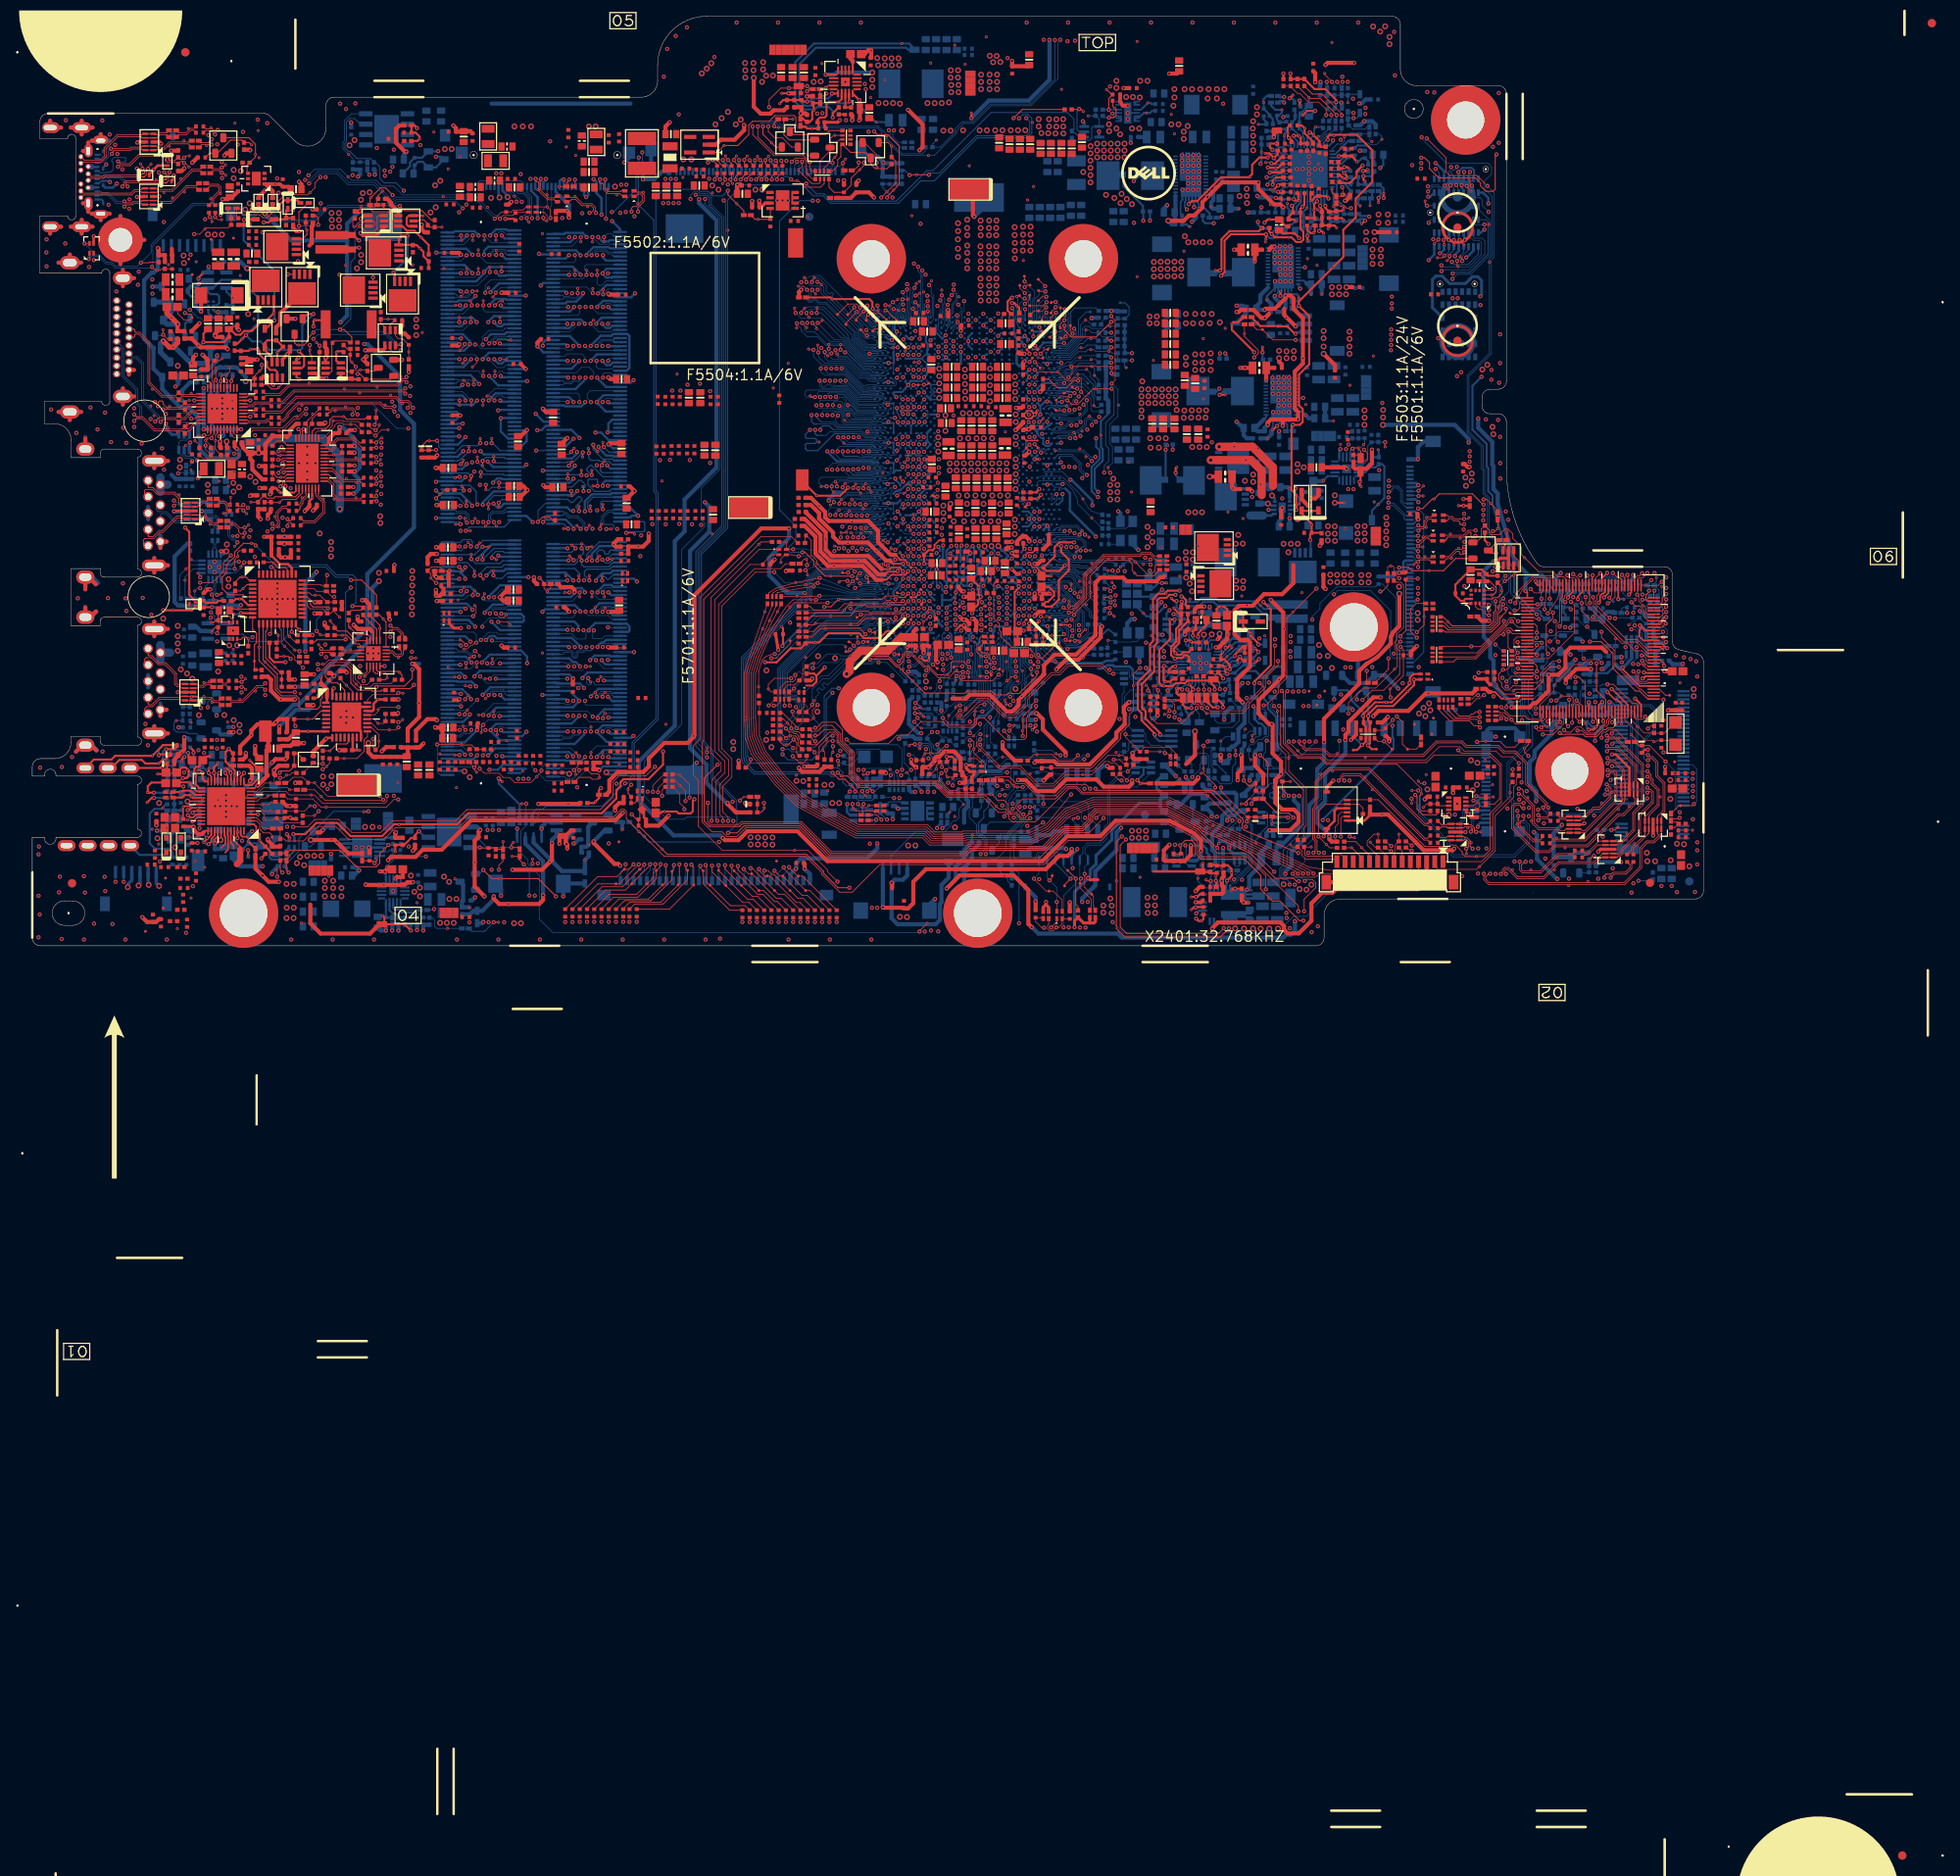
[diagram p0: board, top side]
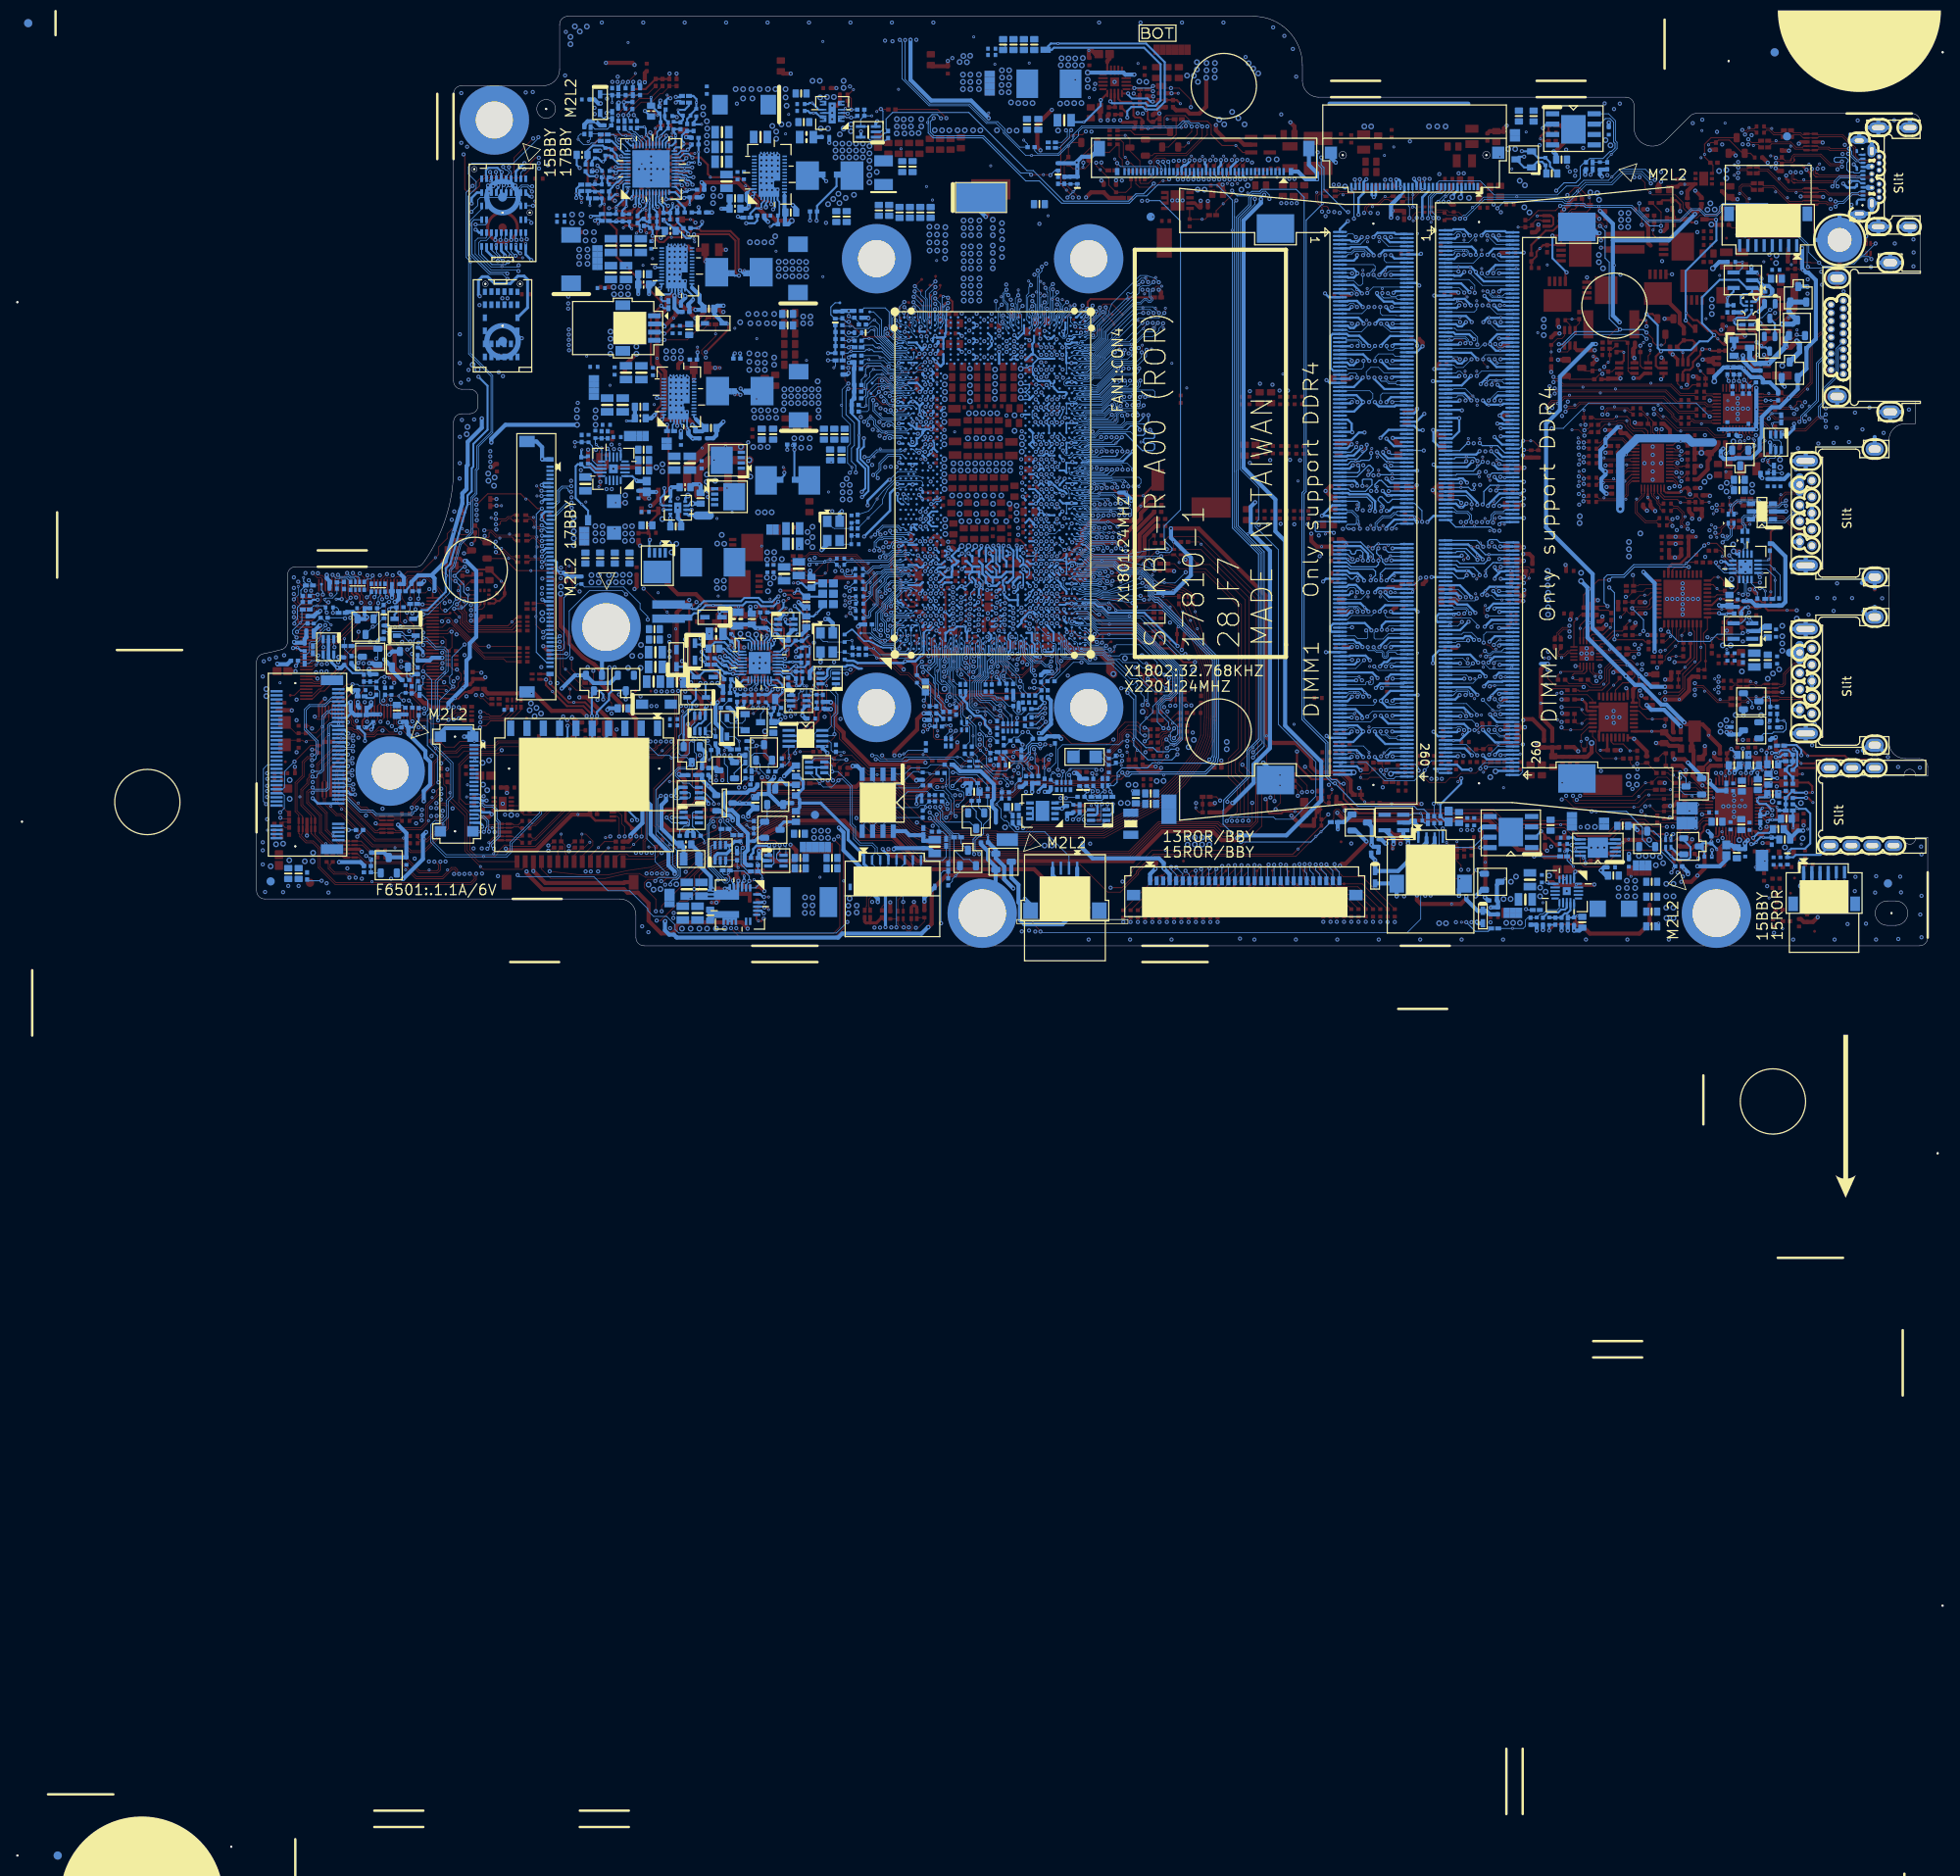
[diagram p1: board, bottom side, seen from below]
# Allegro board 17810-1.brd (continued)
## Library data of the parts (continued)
PR4310 R401 R417 R419 R604 R605 R1702 R1822-R1825 R1909 R2006 R2007 R2019 R2432 R2463 R2464 R3840-R3847 R3852 R3870-R3874 R4005 R6513 = R402H16: tolerance: 63.10234.1DL
PR4311 PR4319 PR4323-PR4325 PR4332 PR4340 PR4342 PR4413 PR4423 PR4424 PR4662 PR5203 R1716 R2441 R2444 R3730 = R402H16: tolerance: 64.10035.6DL
PR4312 = R402H16: tolerance: 64.47035.6DL
PR4313 = R402H16: tolerance: 64.71525.6DL
PR4314 PR4326 PR4463 PR4503 PR4530 PR5106 PR5126 R712 R804 R1718 R1732 R1807 R1808 R1826 R2003 R2004 R2020 R2021 R2023-R2028 R2102 R2418 R2425 R2471 R2476 R2477 R2510 R2601 R2615 R2705 R2710 R2732 R3727-R3729 R3731-R3733 R3736 R3814 R3816 R3849 R3853-R3856 R3859-R3864 R4010 R4012-R4014 R4033 R4462 R5502 R5512 R6005 R6007 R6310 R6505 R6506 R6801-R6810 R7002 R9101-R9103 = R402H16: tolerance: 63.R0034.1DL
PR4315 = R402H16: tolerance: 64.18725.6DL
PR4316 PR4682 R1731 R2056 R2727 = R402H16: tolerance: 63.20334.1DL
PR4317 PR4447 PR4501 PR4502 PR5101 = 0R0603-PAD-U: tolerance: ZZ.R0603.001
PR4320 PR4330 PR4337 = R402H16: tolerance: 64.24035.6DL
PR4322 PR4333 PR4420 PR4421 PR4438 PR4439 PR4450 PR4614 PR5103 PR5104 PR5204 R1306 R2448 R3725 R3726 = R402H16: tolerance: 64.10025.6DL
PR4327 = R402H16: tolerance: 64.12425.6DL
PR4329 PR4436 PR4513 PR4514 PR5127 R1802 R2201 R3706 = R402H16: tolerance: 63.10534.1DL
PR4336 PR4344 = R402H16: tolerance: 63.68434.1DL
PR4338 = R2512H28: tolerance: 63.10135.17L
PR4339 R2442 = R402H16: tolerance: 64.64925.6DL
PR4341 PR4430 PR4444 PR4448 PR4455 PR4458 PR4504 PR4515 PR4516 PR4604 PR4607 PR4616-PR4618 PR4630 PR4645 PR4648 PR4666 PR4670 PR4671 PR4704 PR4714 PR4808 PR5102 PR5105 PR5107 PR5114 PR5118 PR5125 PR5209 PR5210 PR5405 PR5406 PR5408 PR5417 = 0R0402-PAD: tolerance: ZZ.R0402.001
PR4343 PR4638 R2709 = R402H16: tolerance: 64.20035.6DL
PR4401 PR4410 PR4449 PR4506 PR4507 PR4509 PR4511 PR4601 PR4624 PR4626 PR4676 R4303 = R402H16: tolerance: 64.10015.6DL
PR4402 PR4415 = R3720H40: tolerance: 64.R0105.7FL
PR4403 = R805H24: tolerance: 64.10005.16L
PR4407 = R805H24: tolerance: 63.2R231.16L
PR4408 = R402H16: tolerance: 64.30035.6DL
PR4409 = R402H16: tolerance: 64.37425.6DL
PR4411 PR4414 R1206 R1305 R3857 R3858 = R402H16: tolerance: 64.2R005.6DL
PR4412 = R603H22: tolerance: 64.4R705.55L
PR4416 PR4623 PR4650 PR4668 R503 R719-R722 R726 R734 R735 R1501 R1604 R2714 R2716 R9129 = R402H14: tolerance: 64.10005.6DL
PR4422 PR4445 PR4471 = R402H16: tolerance: 64.10035.L1L
PR4437 R2443 = R402H16: tolerance: 64.49925.6DL
PR4442 = R402H15: tolerance: 63.47434.L0L
PR4443 = R402H16: tolerance: 64.30035.L0L
PR4451 = R402H16: tolerance: 64.68035.6DL
PR4508 PR4512 = R402H16: tolerance: 64.20035.L0L
PR4551 = R402H16: tolerance: 64.56035.6DL
PR4602 = R402H16: tolerance: 64.15015.6DL
PR4605 = R402H16: tolerance: 64.82505.6DL
PR4606 PR4633 PR4653 PR4656 = NTC-402H24-U: tolerance: 69.60013.201
PR4608 = R402H16: tolerance: 64.28715.6DL
PR4609 = R402H16: tolerance: 64.14325.6DL
PR4611 = R402H16: tolerance: 64.18225.LDL
PR4612 PR4627 = R603H22: tolerance: 64.80615.55L
PR4613 = R402H16: tolerance: 64.91025.6DL
PR4619 PR4655 = R402H16: tolerance: 64.15415.6DL
PR4621 = R402H16: tolerance: 64.45R35.6DL
PR4622 PR4669 = R402H16: tolerance: 64.75R05.6DL
PR4625 = R402H16: tolerance: 64.37R45.6DL
PR4628 = R402H16: tolerance: 64.10535.60L
PR4629 = R402H16: tolerance: 64.14025.6DL
PR4631 PR4647 = R402H16: tolerance: 64.47515.6DL
PR4632 = R402H16: tolerance: 64.28025.6DL
PR4634 = NTC-402H22-U: tolerance: 69.60011.081
PR4635 = R402H16: tolerance: 64.51125.6DL
PR4636 PR4649 = R402H16: tolerance: 64.24915.6DL
PR4637 PR4679 = R603H22: tolerance: 64.75025.55L
PR4639 = R402H16: tolerance: 64.75025.6DL
PR4640 = R402H16: tolerance: 64.20525.6DL
PR4644 = R402H16: tolerance: 64.82005.6DL
PR4646 PR4667 PR4677 PR4680 PR4681 R2609 R2908 R2910 = R402H14: tolerance: 64.10R05.6DL
PR4651 PR4678 = R402H16: tolerance: 64.48715.6DL
PR4652 = R402H16: tolerance: 64.21525.6DL
PR4657 PR4702 PR4712 PR4803 = R402H16: tolerance: 64.2R205.6DL
PR4658 = R402H16: tolerance: 64.97625.6DL
PR4659 PR4664 = R402H16: tolerance: 64.24025.6DL
PR4660 = R402H16: tolerance: 64.19125.6DL
PR4661 = R402H16: tolerance: 64.19625.6DL
PR4663 = R402H16: tolerance: 64.35725.6DL
PR4665 R412-R415 R601 = R402H16: tolerance: 64.49R95.6DL
PR4701 PR4711 PR4802 = R603H22: tolerance: 63.3R934.15L
PR4703 PR4713 PR4804 PR5014 = R805H24: tolerance: 64.2R205.16L
PR5013 = R603H22: tolerance: 64.2R205.55L
PR5201 = R402H16: tolerance: 64.88725.6DL
PR5202 = R402H16: tolerance: 64.25515.6DL
PR5401 PR5409 = R402H16: tolerance: 63.47334.1DL
PR5403 = R402H16: tolerance: 64.16525.6DL
PR5404 = R402H16: tolerance: 64.13325.6DL
PR5419 = R402H16: tolerance: 64.29425.6DL
PR5420 = R402H16: tolerance: 64.13725.6DL
PT4702 PT4705 = CT7343H83: tolerance: 79.33719.20C
PT4703 PT4704 = CT7343H83: tolerance: 79.33612.20L
PT4801 = CT3528H79: tolerance: 80.3371V.A2L
PU4301-PU4304 PU4403 = PPAK-8P-2H45: tolerance: 84.07121.037
PU4305 PU4306 = PPAK-8P-2H45: tolerance: 84.07625.037
PU4307 = XSON6H24: tolerance: 73.01G04.01V
PU4401 = QFN32J4-G2D7H42: tolerance: 074.88739.0073
PU4404 PU4405 PU5002 PU5003 = PPAK-8P-3232H36: tolerance: 84.07410.A37
PU4501 = QFN20Z3-G1D1H36: tolerance: 074.08286.0043
PU4502 = QFN20Z3-G1D1H36: tolerance: 074.08288.0B43
PU4601 = LFQFN48J6-G4D6H40: tolerance: 074.81218.0073
PU4701 PU4702 PU4801 = QFN36J4060-G2554H48: tolerance: 074.81382.0CE3
PU5001 = LFDFN8G2-G1309H40: tolerance: 074.81253.0AE3
PU5101 = QFN20Z3-G1H36: tolerance: 074.08288.0043
PU5102 = MSOP10-G2D5H44: tolerance: 74.05338.079
PU5201 = QFN22G4-G2PH42: tolerance: 074.02262.0043
PU5401 PU5403 = SOIC8-G3530H63: tolerance: 74.05930.03D
PU5402 = SOT-23-5H52: tolerance: 74.01339.B3F
Q1701 Q2001 = SOT-363H44: tolerance: 075.00138.0A7C
Q1801 Q2601 Q6504 = SOT-363H44: tolerance: 75.27002.F7C; signal model: 6pins2
Q2605 = SOT-363H44: tolerance: 84.2N702.A3F
Q2702 Q6502 = SOT23DGS2D4H48: tolerance: 84.03415.A31
Q6401 Q6402 Q6505 = SOT23CBE2D4H44: tolerance: 084.00144.0B11
Q6501 = SOT23DGS2D4H44: tolerance: 084.03404.0A31
Q9102 = SOT23DGS2D4H48: tolerance: 84.02130.031
Q9104 = SOT723DGS1D2H22: tolerance: 84.03K15.C31
R402 R406-R409 R416 R421-R423 = R402H16: tolerance: 63.51034.1DL
R403 R6401 = R402H16: tolerance: 64.49905.6DL
R410 R504 R602 R709 R732 R1205 R1210 R1212 R1303 R1311 R1704 R1706 R1708 R1713 R1720 R1728 R2101 R2402 R2420 R2422 R2423 R2435 R2445 R2461 R2462 R2470 R2472 R2474 R2475 R2515 R2602 R2611-R2614 R2708 R2713 R2723-R2725 R2905 R2921 R2922 R3401 R3605 R3606 R3609-R3614 R3832-R3839 R4002 R4011 R4017 R4024 R4029 R4030 R4036 R4038 R4042 R4301 R5501 R5503 R5515 R5540 R5722 R5723 R6001 R6002 R6301 R6308 R6403 R6404 R6510 R6512 R7003 R7004 R7007-R7010 R7012 R7013 = 0R0402-PAD: tolerance: ZZ.R0402.ZZZ
R501 = R402H16: tolerance: 64.12105.6DL
R502 = R402H16: tolerance: 64.80R65.6DL
R505 = R402H16: tolerance: 64.47005.6DL
R506 = R402H16: tolerance: 64.22035.6DL
R703 R1102-R1104 R1711 R2106-R2111 R2446 R2703 R2906 R2907 R2909 R2911 R2923 R5701 R5715 R6003 R6006 R6302 R6307 = 0R0603-PAD: tolerance: ZZ.R0603.ZZZ
R705 R2702 R2704 R2706 R2731 R4101 = 0R0805-PAD: tolerance: ZZ.R0805.ZZZ
R706-R708 = R805H20: tolerance: 063.R0007.0161
R723 = R402H16: tolerance: 64.54R95.6DL
R727 = R402H16: tolerance: 63.56034.1DL
R728 = R402H16: tolerance: 63.22134.1DL
R801 R1209 R1309 = R402H16: tolerance: 64.24R95.6DL
R1101 R4045 = 0R1206-PAD: tolerance: ZZ.R1206.ZZZ
R1204 R1208 R1211 R1302 R1310 R3753 = R402H15: tolerance: 64.10025.L0L
R1215 R1312 = R402H16: tolerance: 64.24005.6DL
R1307 R9130 R9133 R9136 R9138 R9142-R9147 R9149 = R402H15: tolerance: 63.R0034.L0L
R1502 R1901 = R402H16: tolerance: 64.20005.6DL
R1603 = R402H16: tolerance: 64.11305.6DL
R1724 R5514 = R1206H26: tolerance: 63.R0037.L0L
R1730 = R402H16: tolerance: 63.33434.1DL
R1803 = R402H16: tolerance: 64.27015.6DL
R1804 R1805 R2202 R2203 = R402H16: tolerance: 63.R0034.1DL; signal model: 2pins
R1806 = R402H16: tolerance: 64.15R05.6DL; signal model: 2pins
R1811 R2503 R2505-R2508 = R402H14: tolerance: 64.10R05.6DL; signal model: 2pins
R1812 R1908 R2447 R2459 R2718-R2720 = 0R0402-PAD: tolerance: ZZ.R0402.ZZZ; signal model: 2pins
R1815 R2504 = R402H16: tolerance: 63.10634.1DL
R1818 = R402H16: tolerance: 64.82015.6DL
R1837 R2055 = R402H16: tolerance: 63.15434.1DL
R2048 R2049 R6507 = R402H16: tolerance: 63.51334.1DL
R2414 R2501 R3724 R3821 R5411-R5420 = R402H16: tolerance: 63.47234.1DL
R2421 R2426 R6402 = R402H16: tolerance: 63.33134.1DL
R2424 R3403 R4006 R6504 = R402H16: tolerance: 64.20025.6DL
R2437 = R402H16: tolerance: 63.43034.1DL
R2456 = R402H16: tolerance: 64.11535.6DL
R2603 R2604 = R402H16: tolerance: 64.75015.6DL
R2608 = R402H16: tolerance: 64.27025.6DL
R2610 = NTC-603H38: tolerance: 69.60035.041
R3404 = R402H16: tolerance: 64.22125.6DL
R3735 = R402H16: tolerance: 63.20534.1DL
R3737 R5507 R5513 R5516 R5520 R5716 R6501 R6502 R6514 = R603H22: tolerance: 63.00000.00L
R3750 R3752 = R402H16: tolerance: 64.30025.6DL
R3751 = R402H16: tolerance: 64.30015.6DL
R3830 R3831 = R402H16: tolerance: 64.20045.6DL
R5702-R5705 = R402H16: tolerance: 63.18134.1DL
R5710 = R402H16: tolerance: 64.43015.6DL
R6503 = R603H22: tolerance: 63.10133.15L
RN801 RN803 RN1811 RN2008 RN2602 RN2604 RN2901 RN3701 RN3702 RN6503 = ARES2H16: tolerance: 66.22236.04L
RN1201 RN1301 RN1802 RN2007 RN2701 = SMD-ARES4H18: tolerance: 66.10236.04L
RN1601 RN1704 RN2403 RN2404 = ARES8-CN24-MUH20: tolerance: 66.10336.08L
RN1602 RN7001 = SMD-ARES4H20: tolerance: 66.R0036.04L
RN1703 RN1810 RN1812 RN1813 RN2009 RN2407 RN6501 = ARES2H18: tolerance: 66.10336.04L
RN1801 = SMD-ARES4H20: tolerance: 66.20336.04L
RN1803 = ARES8-CN24-UH18: tolerance: 66.10036.08A; signal model: 8pins2
RN1806 = ARES8-CN24-MUH20: tolerance: 66.15035.A8L; signal model: 8pins2
RN1807 = ARES8-CN24-UH20: tolerance: 66.22236.A8L
RN1902 = SMD-ARES4H18: tolerance: 66.33036.04L; signal model: 4pins2
RN2402 = SMD-ARES4H18: tolerance: 66.47236.04L
RN2405 RN2409-RN2412 RN5502 = ARES8-CN24H20: tolerance: 66.10436.A8L
RN4302 RN5501 = ARES8-CN24H20: tolerance: 66.10136.A8L
RN5503 RN6502 = SMD-ARES4H18: tolerance: 66.33036.04L
SPI25 = SOIC8-1H86: tolerance: 72.12873.001
SPK1 = A1001WR-S06PN6BT1TS2R-U: tolerance: 20.F1804.006
SPR1-SPR3 = SPR5128H111: tolerance: 34.4YW18.001
SPR4 = SPR6438H83: tolerance: 34.49U26.001
SSD1 = AS0BC2Y-S30BM-7H: tolerance: 062.10003.0481
TCBD1 = FL10F032HA2R3000: tolerance: 20.K0801.032
THM261 = MSOP8-1H44: tolerance: 74.07718.0B9
TP1 = 51574-0084N-W01: tolerance: 020.K0151.0008
TP401-TP409 TP601-TP604 TP607-TP638 TP701 TP707 TP801 TP1602 TP1603 TP1605 TP1606 TP1703-TP1711 TP1802-TP1806 TP1808 TP1902 TP1906 TP2006 TP2007 TP2012-TP2014 TP2016 TP2017 TP2020 TP2027 TP2028 TP2101 TP2102 TP2301-TP2313 TP2402 TP2405-TP2407 TP2702 TP3703 = TPAD14-OP: tolerance: ZZ.PAD14.001
U3401 = QFN16-G1D8-UH32: tolerance: 74.02544.073; signal model: Graser_U3401
U3501 = SOT-23-5H56: tolerance: 074.06288.009B
U3701 = QFN40G6-G4D7H24: tolerance: 071.04125.0003
U3702 = DFN6F2-G1711-UH32: tolerance: 074.70933.0033
U3703 = DFN6G1820-G1511-UH24: tolerance: 074.02151.0073
U3801 = QFN40J4060-G2848H32: tolerance: 071.00546.0003
U3802 = QFN20J3-G1D8H32: tolerance: 071.10224.0003; signal model: Graser_U3802
U4001 = SON14J3020-G2610H34: tolerance: 074.22976.0091
U4002 U4006 = DFN8F3-G2517H32: tolerance: 074.05027.0093
U4003 = SC70-5-1H44: tolerance: 73.01G08.EHG
U4302 = SOT-23-5H52: tolerance: 074.01004.00BF
U5501 = SOT-23-5H51: tolerance: 74.09724.09F
U5701 = QFN40J5-G3D65H32: tolerance: 71.08201.G03; signal model: Graser_U5701
U6001 = DFN10G2510H26: tolerance: 75.01045.073
U6002 = DFN8G2-G1710-U1H32: tolerance: 074.08937.0093
U6301-U6304 = DFN10G2510H22: tolerance: 075.01043.0073
U7001 = LGA12G2H40: tolerance: 074.LNG2D.00BZ
U9104 = QFN32G5-G3D6H32: tolerance: 071.06502.0003
USB1 = SKT-USB34-124103-U: tolerance: 022.10005.M021
USB2 USB3 = SKT-USB13-160162-2: tolerance: 022.10005.01P1
X1801 X2201 = OSC-3225-4P-4H30: tolerance: 82.30004.901
X1802 X2401 = SMD49-3215-0713H36: tolerance: 082.30003.0221

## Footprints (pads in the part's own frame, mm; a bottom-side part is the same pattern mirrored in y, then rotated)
0R0402-PAD
  custom 0.127x0.127 smd: 1(0,0.432) 2(0,-0.432)
0R0603-PAD
  custom 0.254x0.254 smd: 1(0,0.66) 2(0,-0.66)
0R0603-PAD-U
  custom 0.254x0.254 smd: 1(0,0.66) 2(0,-0.66)
0R0805-PAD
  rect 1.549x1.346 smd: 1(0,0.838) 2(0,-0.838)
0R1206-PAD
  rect 1.854x1.829 smd: 1(0,1.347) 2(0,-1.347)
20455-040E-12
  rect 0.305x0.889 smd: 1(-9.75,2.82) 2(-9.25,2.82) 3(-8.75,2.82) 4(-8.25,2.82) 5(-7.75,2.82) 6(-7.25,2.82) 7(-6.75,2.82) 8(-6.25,2.82) 9(-5.75,2.82) 10(-5.25,2.82) 11(-4.75,2.82) 12(-4.25,2.82) 13(-3.75,2.82) 14(-3.25,2.82) 15(-2.75,2.82) 16(-2.25,2.82) 17(-1.75,2.82) 18(-1.25,2.82) 19(-0.75,2.82) 20(-0.25,2.82) 21(0.25,2.82) 22(0.75,2.82) 23(1.25,2.82) 24(1.75,2.82) 25(2.25,2.82) 26(2.75,2.82) 27(3.25,2.82) 28(3.75,2.82) 29(4.25,2.82) 30(4.75,2.82) 31(5.25,2.82) 32(5.75,2.82) 33(6.25,2.82) 34(6.75,2.82) 35(7.25,2.82) 36(7.75,2.82) 37(8.25,2.82) 38(8.75,2.82) 39(9.25,2.82) 40(9.75,2.82)
  rect 0.559x0.889 smd: 41(-10.65,2.82) 42(10.65,2.82)
  rect 1.397x1.905 smd: 43(-12.849,0) 44(12.849,0)
20455-050E-76
  rect 0.305x0.889 smd: 1(-12.25,2.82) 2(-11.75,2.82) 3(-11.25,2.82) 4(-10.75,2.82) 5(-10.25,2.82) 6(-9.75,2.82) 7(-9.25,2.82) 8(-8.75,2.82) 9(-8.25,2.82) 10(-7.75,2.82) 11(-7.25,2.82) 12(-6.75,2.82) 13(-6.25,2.82) 14(-5.75,2.82) 15(-5.25,2.82) 16(-4.75,2.82) 17(-4.25,2.82) 18(-3.75,2.82) 19(-3.25,2.82) 20(-2.75,2.82) 21(-2.25,2.82) 22(-1.75,2.82) 23(-1.25,2.82) 24(-0.75,2.82) 25(-0.25,2.82) 26(0.25,2.82) 27(0.75,2.82) 28(1.25,2.82) 29(1.75,2.82) 30(2.25,2.82) 31(2.75,2.82) 32(3.25,2.82) 33(3.75,2.82) 34(4.25,2.82) 35(4.75,2.82) 36(5.25,2.82) 37(5.75,2.82) 38(6.25,2.82) 39(6.75,2.82) 40(7.25,2.82) 41(7.75,2.82) 42(8.25,2.82) 43(8.75,2.82) 44(9.25,2.82) 45(9.75,2.82) 46(10.25,2.82) 47(10.75,2.82) 48(11.25,2.82) 49(11.75,2.82) 50(12.25,2.82)
  rect 1.397x1.905 smd: 51(-15.35,0) 52(15.35,0)
  rect 0.559x0.889 smd: 53(-13.15,2.82) 54(13.15,2.82)
50224-0040N-001
  rect 0.61x1.549 smd: 1(-1.5,3.875) 2(-0.5,3.875) 3(0.5,3.875) 4(1.5,3.875)
  rect 1.194x1.803 smd: 5(-2.797,0) 6(2.797,0)
50224-0080N-W02-U
  rect 0.406x1.549 smd: 1(-3.5,3.875) 2(-2.5,3.875) 3(-1.5,3.875) 4(-0.5,3.875) 5(0.5,3.875) 6(1.5,3.875) 7(2.5,3.875) 8(3.5,3.875)
  rect 1.194x1.803 smd: 9(-4.797,0) 10(4.797,0)
50299-01001-002-U
  round 0.254 hole 1.803 unplated: (-9.2,0) (9.2,0)
  rect 0.889x1.905 smd: 1(9,4.95) 2(7,4.95) 3(5,4.95) 4(3,4.95) 5(1,4.95) 6(-1,4.95) 7(-3,4.95) 8(-5,4.95) 9(-7,4.95) 10(-9,4.95)
50524-00401-001
  rect 0.305x1.295 smd: 1(-1.5,5.65) 2(-0.5,5.65) 3(0.5,5.65) 4(1.5,5.65)
  rect 1.803x2.21 smd: 5(-4.15,0) 6(4.15,0)
50696-00601-001
  rect 0.305x0.813 smd: 1(1.25,2.5) 2(0.75,2.5) 3(0.25,2.5) 4(-0.25,2.5) 5(-0.75,2.5) 6(-1.25,2.5)
  rect 0.406x0.813 smd: 7(2.25,0) 8(-2.25,0)
50698-00401-W01-U
  rect 0.305x1.6 smd: 1(1.5,5.2) 2(0.5,5.2) 3(-0.5,5.2) 4(-1.5,5.2)
  rect 1.803x2.007 smd: 5(4.21,0) 6(-4.21,0)
51574-0084N-W01
  rect 0.305x1.194 smd: 1(-3.5,3.3) 2(-2.5,3.3) 3(-1.5,3.3) 4(-0.5,3.3) 5(0.5,3.3) 6(1.5,3.3) 7(2.5,3.3) 8(3.5,3.3)
  rect 0.406x0.813 smd: 9(-5.185,0) 10(5.185,0)
87212-1400N
  rect 0.61x1.549 smd: 1(-6.5,-2.525) 2(-5.5,-2.525) 3(-4.5,-2.525) 4(-3.5,-2.525) 5(-2.5,-2.525) 6(-1.5,-2.525) 7(-0.5,-2.525) 8(0.5,-2.525) 9(1.5,-2.525) 10(2.5,-2.525) 11(3.5,-2.525) 12(4.5,-2.525) 13(5.5,-2.525) 14(6.5,-2.525)
  rect 1.194x1.803 smd: 15(-7.797,0) 16(7.797,0)
196528-30041-3
  rect 0.508x1.092 smd: 1(-11.6,1.75) 2(-10.8,1.75) 3(-10,1.75) 4(-9.2,1.75) 5(-8.4,1.75) 6(-7.6,1.75) 7(-6.8,1.75) 8(-6,1.75) 9(-5.2,1.75) 10(-4.4,1.75) 11(-3.6,1.75) 12(-2.8,1.75) 13(-2,1.75) 14(-1.2,1.75) 15(-0.4,1.75) 16(0.4,1.75) 17(1.2,1.75) 18(2,1.75) 19(2.8,1.75) 20(3.6,1.75) 21(4.4,1.75) 22(5.2,1.75) 23(6,1.75) 24(6.8,1.75) 25(7.6,1.75) 26(8.4,1.75) 27(9.2,1.75) 28(10,1.75) 29(10.8,1.75) 30(11.6,1.75)
  rect 1.651x1.295 smd: 31(-13.625,0) 32(13.625,0)
A1001WR-S06PN6BT1TS2R-U
  rect 0.406x1.549 smd: 1(-2.5,3.875) 2(-1.5,3.875) 3(-0.5,3.875) 4(0.5,3.875) 5(1.5,3.875) 6(2.5,3.875)
  rect 1.194x1.803 smd: 7(-3.8,0) 8(3.8,0)
ADDR0205-P012A
  round 0.254 hole 1.118 unplated: (-34.4,0)
  round 0.254 hole 1.6 unplated: (34.4,0)
  custom 0.089x0.089 smd: 1(33.375,4.1) 2(33.125,-4.1) 3(32.875,4.1) 4(32.625,-4.1) 5(32.375,4.1) 6(32.125,-4.1) 7(31.875,4.1) 8(31.625,-4.1) 9(31.375,4.1) 10(31.125,-4.1) 11(30.875,4.1) 12(30.625,-4.1) 13(30.375,4.1) 14(30.125,-4.1) 15(29.875,4.1) 16(29.625,-4.1) 17(29.375,4.1) 18(29.125,-4.1) 19(28.875,4.1) 20(28.625,-4.1) 21(28.375,4.1) 22(28.125,-4.1) 23(27.875,4.1) 24(27.625,-4.1) 25(27.375,4.1) 26(27.125,-4.1) 27(26.875,4.1) 28(26.625,-4.1) 29(26.375,4.1) 30(26.125,-4.1) 31(25.875,4.1) 32(25.625,-4.1) 33(25.375,4.1) 34(25.125,-4.1) 35(24.875,4.1) 36(24.625,-4.1) 37(24.375,4.1) 38(24.125,-4.1) 39(23.875,4.1) 40(23.625,-4.1) 41(23.375,4.1) 42(23.125,-4.1) 43(22.875,4.1) 44(22.625,-4.1) 45(22.375,4.1) 46(22.125,-4.1) 47(21.875,4.1) 48(21.625,-4.1) 49(21.375,4.1) 50(21.125,-4.1) 51(20.875,4.1) 52(20.625,-4.1) 53(20.375,4.1) 54(20.125,-4.1) 55(19.875,4.1) 56(19.625,-4.1) 57(19.375,4.1) 58(19.125,-4.1) 59(18.875,4.1) 60(18.625,-4.1) 61(18.375,4.1) 62(18.125,-4.1) 63(17.875,4.1) 64(17.625,-4.1) 65(17.375,4.1) 66(17.125,-4.1) 67(16.875,4.1) 68(16.625,-4.1) 69(16.375,4.1) 70(16.125,-4.1) 71(15.875,4.1) 72(15.625,-4.1) 73(15.375,4.1) 74(15.125,-4.1) 75(14.875,4.1) 76(14.625,-4.1) 77(14.375,4.1) 78(14.125,-4.1) 79(13.875,4.1) 80(13.625,-4.1) 81(13.375,4.1) 82(13.125,-4.1) 83(12.875,4.1) 84(12.625,-4.1) 85(12.375,4.1) 86(12.125,-4.1) 87(11.875,4.1) 88(11.625,-4.1) 89(11.375,4.1) 90(11.125,-4.1) 91(10.875,4.1) 92(10.625,-4.1) 93(10.375,4.1) 94(10.125,-4.1) 95(9.875,4.1) 96(9.625,-4.1) 97(9.375,4.1) 98(9.125,-4.1) 99(8.875,4.1) 100(8.625,-4.1) 101(8.375,4.1) 102(8.125,-4.1) 103(7.875,4.1) 104(7.625,-4.1) 105(7.375,4.1) 106(7.125,-4.1) 107(6.875,4.1) 108(6.625,-4.1) 109(6.375,4.1) 110(6.125,-4.1) 111(5.875,4.1) 112(5.625,-4.1) 113(5.375,4.1) 114(5.125,-4.1) 115(4.875,4.1) 116(4.625,-4.1) 117(4.375,4.1) 118(4.125,-4.1) 119(3.875,4.1) 120(3.625,-4.1) 121(3.375,4.1) 122(3.125,-4.1) 123(2.875,4.1) 124(2.625,-4.1) 125(2.375,4.1) 126(2.125,-4.1) 127(1.875,4.1) 128(1.625,-4.1) 129(1.375,4.1) 130(1.125,-4.1) 131(0.875,4.1) 132(0.625,-4.1) 133(0.375,4.1) 134(0.125,-4.1) 135(-0.125,4.1) 136(-0.375,-4.1) 137(-0.625,4.1) 138(-0.875,-4.1) 139(-1.125,4.1) 140(-1.375,-4.1) 141(-1.625,4.1) 142(-1.875,-4.1) 143(-2.125,4.1) 144(-2.375,-4.1) 145(-4.625,4.1) 146(-4.875,-4.1) 147(-5.125,4.1) 148(-5.375,-4.1) 149(-5.625,4.1) 150(-5.875,-4.1) 151(-6.125,4.1) 152(-6.375,-4.1) 153(-6.625,4.1) 154(-6.875,-4.1) 155(-7.125,4.1) 156(-7.375,-4.1) 157(-7.625,4.1) 158(-7.875,-4.1) 159(-8.125,4.1) 160(-8.375,-4.1) 161(-8.625,4.1) 162(-8.875,-4.1) 163(-9.125,4.1) 164(-9.375,-4.1) 165(-9.625,4.1) 166(-9.875,-4.1) 167(-10.125,4.1) 168(-10.375,-4.1) 169(-10.625,4.1) 170(-10.875,-4.1) 171(-11.125,4.1) 172(-11.375,-4.1) 173(-11.625,4.1) 174(-11.875,-4.1) 175(-12.125,4.1) 176(-12.375,-4.1) 177(-12.625,4.1) 178(-12.875,-4.1) 179(-13.125,4.1) 180(-13.375,-4.1) 181(-13.625,4.1) 182(-13.875,-4.1) 183(-14.125,4.1) 184(-14.375,-4.1) 185(-14.625,4.1) 186(-14.875,-4.1) 187(-15.125,4.1) 188(-15.375,-4.1) 189(-15.625,4.1) 190(-15.875,-4.1) 191(-16.125,4.1) 192(-16.375,-4.1) 193(-16.625,4.1) 194(-16.875,-4.1) 195(-17.125,4.1) 196(-17.375,-4.1) 197(-17.625,4.1) 198(-17.875,-4.1) 199(-18.125,4.1) 200(-18.375,-4.1) 201(-18.625,4.1) 202(-18.875,-4.1) 203(-19.125,4.1) 204(-19.375,-4.1) 205(-19.625,4.1) 206(-19.875,-4.1) 207(-20.125,4.1) 208(-20.375,-4.1) 209(-20.625,4.1) 210(-20.875,-4.1) 211(-21.125,4.1) 212(-21.375,-4.1) 213(-21.625,4.1) 214(-21.875,-4.1) 215(-22.125,4.1) 216(-22.375,-4.1) 217(-22.625,4.1) 218(-22.875,-4.1) 219(-23.125,4.1) 220(-23.375,-4.1) 221(-23.625,4.1) 222(-23.875,-4.1) 223(-24.125,4.1) 224(-24.375,-4.1) 225(-24.625,4.1) 226(-24.875,-4.1) 227(-25.125,4.1) 228(-25.375,-4.1) 229(-25.625,4.1) 230(-25.875,-4.1) 231(-26.125,4.1) 232(-26.375,-4.1) 233(-26.625,4.1) 234(-26.875,-4.1) 235(-27.125,4.1) 236(-27.375,-4.1) 237(-27.625,4.1) 238(-27.875,-4.1) 239(-28.125,4.1) 240(-28.375,-4.1) 241(-28.625,4.1) 242(-28.875,-4.1) 243(-29.125,4.1) 244(-29.375,-4.1) 245(-29.625,4.1) 246(-29.875,-4.1) 247(-30.125,4.1) 248(-30.375,-4.1) 249(-30.625,4.1) 250(-30.875,-4.1) 251(-31.125,4.1) 252(-31.375,-4.1) 253(-31.625,4.1) 254(-31.875,-4.1) 255(-32.125,4.1) 256(-32.375,-4.1) 257(-32.625,4.1) 258(-32.875,-4.1) 259(-33.125,4.1) 260(-33.375,-4.1)
  rect 3.505x4.597 smd: 261(33.8,-12) 262(-33.8,-12)
ADDR0206-P013A
  round 0.254 hole 1.6 unplated: (-34.4,0)
  round 0.254 hole 1.118 unplated: (34.4,0)
  custom 0.089x0.089 smd: 1(-33.375,-4.1) 2(-33.125,4.1) 3(-32.875,-4.1) 4(-32.625,4.1) 5(-32.375,-4.1) 6(-32.125,4.1) 7(-31.875,-4.1) 8(-31.625,4.1) 9(-31.375,-4.1) 10(-31.125,4.1) 11(-30.875,-4.1) 12(-30.625,4.1) 13(-30.375,-4.1) 14(-30.125,4.1) 15(-29.875,-4.1) 16(-29.625,4.1) 17(-29.375,-4.1) 18(-29.125,4.1) 19(-28.875,-4.1) 20(-28.625,4.1) 21(-28.375,-4.1) 22(-28.125,4.1) 23(-27.875,-4.1) 24(-27.625,4.1) 25(-27.375,-4.1) 26(-27.125,4.1) 27(-26.875,-4.1) 28(-26.625,4.1) 29(-26.375,-4.1) 30(-26.125,4.1) 31(-25.875,-4.1) 32(-25.625,4.1) 33(-25.375,-4.1) 34(-25.125,4.1) 35(-24.875,-4.1) 36(-24.625,4.1) 37(-24.375,-4.1) 38(-24.125,4.1) 39(-23.875,-4.1) 40(-23.625,4.1) 41(-23.375,-4.1) 42(-23.125,4.1) 43(-22.875,-4.1) 44(-22.625,4.1) 45(-22.375,-4.1) 46(-22.125,4.1) 47(-21.875,-4.1) 48(-21.625,4.1) 49(-21.375,-4.1) 50(-21.125,4.1) 51(-20.875,-4.1) 52(-20.625,4.1) 53(-20.375,-4.1) 54(-20.125,4.1) 55(-19.875,-4.1) 56(-19.625,4.1) 57(-19.375,-4.1) 58(-19.125,4.1) 59(-18.875,-4.1) 60(-18.625,4.1) 61(-18.375,-4.1) 62(-18.125,4.1) 63(-17.875,-4.1) 64(-17.625,4.1) 65(-17.375,-4.1) 66(-17.125,4.1) 67(-16.875,-4.1) 68(-16.625,4.1) 69(-16.375,-4.1) 70(-16.125,4.1) 71(-15.875,-4.1) 72(-15.625,4.1) 73(-15.375,-4.1) 74(-15.125,4.1) 75(-14.875,-4.1) 76(-14.625,4.1) 77(-14.375,-4.1) 78(-14.125,4.1) 79(-13.875,-4.1) 80(-13.625,4.1) 81(-13.375,-4.1) 82(-13.125,4.1) 83(-12.875,-4.1) 84(-12.625,4.1) 85(-12.375,-4.1) 86(-12.125,4.1) 87(-11.875,-4.1) 88(-11.625,4.1) 89(-11.375,-4.1) 90(-11.125,4.1) 91(-10.875,-4.1) 92(-10.625,4.1) 93(-10.375,-4.1) 94(-10.125,4.1) 95(-9.875,-4.1) 96(-9.625,4.1) 97(-9.375,-4.1) 98(-9.125,4.1) 99(-8.875,-4.1) 100(-8.625,4.1) 101(-8.375,-4.1) 102(-8.125,4.1) 103(-7.875,-4.1) 104(-7.625,4.1) 105(-7.375,-4.1) 106(-7.125,4.1) 107(-6.875,-4.1) 108(-6.625,4.1) 109(-6.375,-4.1) 110(-6.125,4.1) 111(-5.875,-4.1) 112(-5.625,4.1) 113(-5.375,-4.1) 114(-5.125,4.1) 115(-4.875,-4.1) 116(-4.625,4.1) 117(-4.375,-4.1) 118(-4.125,4.1) 119(-3.875,-4.1) 120(-3.625,4.1) 121(-3.375,-4.1) 122(-3.125,4.1) 123(-2.875,-4.1) 124(-2.625,4.1) 125(-2.375,-4.1) 126(-2.125,4.1) 127(-1.875,-4.1) 128(-1.625,4.1) 129(-1.375,-4.1) 130(-1.125,4.1) 131(-0.875,-4.1) 132(-0.625,4.1) 133(-0.375,-4.1) 134(-0.125,4.1) 135(0.125,-4.1) 136(0.375,4.1) 137(0.625,-4.1) 138(0.875,4.1) 139(1.125,-4.1) 140(1.375,4.1) 141(1.625,-4.1) 142(1.875,4.1) 143(2.125,-4.1) 144(2.375,4.1) 145(4.625,-4.1) 146(4.875,4.1) 147(5.125,-4.1) 148(5.375,4.1) 149(5.625,-4.1) 150(5.875,4.1) 151(6.125,-4.1) 152(6.375,4.1) 153(6.625,-4.1) 154(6.875,4.1) 155(7.125,-4.1) 156(7.375,4.1) 157(7.625,-4.1) 158(7.875,4.1) 159(8.125,-4.1) 160(8.375,4.1) 161(8.625,-4.1) 162(8.875,4.1) 163(9.125,-4.1) 164(9.375,4.1) 165(9.625,-4.1) 166(9.875,4.1) 167(10.125,-4.1) 168(10.375,4.1) 169(10.625,-4.1) 170(10.875,4.1) 171(11.125,-4.1) 172(11.375,4.1) 173(11.625,-4.1) 174(11.875,4.1) 175(12.125,-4.1) 176(12.375,4.1) 177(12.625,-4.1) 178(12.875,4.1) 179(13.125,-4.1) 180(13.375,4.1) 181(13.625,-4.1) 182(13.875,4.1) 183(14.125,-4.1) 184(14.375,4.1) 185(14.625,-4.1) 186(14.875,4.1) 187(15.125,-4.1) 188(15.375,4.1) 189(15.625,-4.1) 190(15.875,4.1) 191(16.125,-4.1) 192(16.375,4.1) 193(16.625,-4.1) 194(16.875,4.1) 195(17.125,-4.1) 196(17.375,4.1) 197(17.625,-4.1) 198(17.875,4.1) 199(18.125,-4.1) 200(18.375,4.1) 201(18.625,-4.1) 202(18.875,4.1) 203(19.125,-4.1) 204(19.375,4.1) 205(19.625,-4.1) 206(19.875,4.1) 207(20.125,-4.1) 208(20.375,4.1) 209(20.625,-4.1) 210(20.875,4.1) 211(21.125,-4.1) 212(21.375,4.1) 213(21.625,-4.1) 214(21.875,4.1) 215(22.125,-4.1) 216(22.375,4.1) 217(22.625,-4.1) 218(22.875,4.1) 219(23.125,-4.1) 220(23.375,4.1) 221(23.625,-4.1) 222(23.875,4.1) 223(24.125,-4.1) 224(24.375,4.1) 225(24.625,-4.1) 226(24.875,4.1) 227(25.125,-4.1) 228(25.375,4.1) 229(25.625,-4.1) 230(25.875,4.1) 231(26.125,-4.1) 232(26.375,4.1) 233(26.625,-4.1) 234(26.875,4.1) 235(27.125,-4.1) 236(27.375,4.1) 237(27.625,-4.1) 238(27.875,4.1) 239(28.125,-4.1) 240(28.375,4.1) 241(28.625,-4.1) 242(28.875,4.1) 243(29.125,-4.1) 244(29.375,4.1) 245(29.625,-4.1) 246(29.875,4.1) 247(30.125,-4.1) 248(30.375,4.1) 249(30.625,-4.1) 250(30.875,4.1) 251(31.125,-4.1) 252(31.375,4.1) 253(31.625,-4.1) 254(31.875,4.1) 255(32.125,-4.1) 256(32.375,4.1) 257(32.625,-4.1) 258(32.875,4.1) 259(33.125,-4.1) 260(33.375,4.1)
  rect 3.505x4.597 smd: 261(-33.8,-12) 262(33.8,-12)
AFTE14P-75
  round 0.356 smd: 1(0,0)
AJ3R2D-Y050-412
  oval 1.346x2.184 hole 0.66x1.473: 1(-4.8,7.8) 2(4.7,2.3) 3(-4.8,2.6) 4(-4.8,0) 5(4.7,7.8) 6(4.7,5.05) MS(-4.8,5.15)
ARES2H16
  rect 0.457x0.635 smd: 1(-0.335,-0.44) 2(0.335,-0.44) 3(0.335,0.44) 4(-0.335,0.44)
ARES2H18
  rect 0.457x0.635 smd: 1(-0.335,-0.44) 2(0.335,-0.44) 3(0.335,0.44) 4(-0.335,0.44)
ARES8-CN24-MUH20
  rect 0.457x0.61 smd: 1(-0.838,-0.445) 4(0.838,-0.445) 5(0.838,0.445) 8(-0.838,0.445)
  rect 0.305x0.61 smd: 2(-0.25,-0.445) 3(0.25,-0.445) 6(0.25,0.445) 7(-0.25,0.445)
ARES8-CN24-UH18
  rect 0.457x0.61 smd: 1(-0.838,-0.445) 4(0.838,-0.445) 5(0.838,0.445) 8(-0.838,0.445)
  rect 0.305x0.61 smd: 2(-0.25,-0.445) 3(0.25,-0.445) 6(0.25,0.445) 7(-0.25,0.445)
ARES8-CN24-UH20
  rect 0.457x0.61 smd: 1(-0.838,-0.445) 4(0.838,-0.445) 5(0.838,0.445) 8(-0.838,0.445)
  rect 0.305x0.61 smd: 2(-0.25,-0.445) 3(0.25,-0.445) 6(0.25,0.445) 7(-0.25,0.445)
ARES8-CN24H20
  rect 0.457x0.559 smd: 1(-0.838,-0.483) 4(0.838,-0.483) 5(0.838,0.483) 8(-0.838,0.483)
  rect 0.305x0.559 smd: 2(-0.25,-0.483) 3(0.25,-0.483) 6(0.25,0.483) 7(-0.25,0.483)
AS0BC2Y-S30BM-7H
  round 0.254 hole 1.168 unplated: (-10,0)
  round 0.254 hole 1.651 unplated: (10,0)
  rect 0.305x1.549 smd: 1(-9.25,5.275) 3(-8.75,5.275) 5(-8.25,5.275) 7(-7.75,5.275) 9(-7.25,5.275) 11(-6.75,5.275) 13(-6.25,5.275) 15(-5.75,5.275) 17(-5.25,5.275) 19(-4.75,5.275) 21(-4.25,5.275) 23(-3.75,5.275) 25(-3.25,5.275) 27(-2.75,5.275) 29(-2.25,5.275) 31(-1.75,5.275) 33(-1.25,5.275) 35(-0.75,5.275) 37(-0.25,5.275) 39(0.25,5.275) 41(0.75,5.275) 43(1.25,5.275) 45(1.75,5.275) 47(2.25,5.275) 49(2.75,5.275) 51(3.25,5.275) 53(3.75,5.275) 55(4.25,5.275) 57(4.75,5.275) 67(7.25,5.275) 69(7.75,5.275) 71(8.25,5.275) 73(8.75,5.275) 75(9.25,5.275)
  rect 0.305x1.499 smd: 2(-9,-2.3) 4(-8.5,-2.3) 6(-8,-2.3) 8(-7.5,-2.3) 10(-7,-2.3) 12(-6.5,-2.3) 14(-6,-2.3) 16(-5.5,-2.3) 18(-5,-2.3) 20(-4.5,-2.3) 22(-4,-2.3) 24(-3.5,-2.3) 26(-3,-2.3) 28(-2.5,-2.3) 30(-2,-2.3) 32(-1.5,-2.3) 34(-1,-2.3) 36(-0.5,-2.3) 38(0,-2.3) 40(0.5,-2.3) 42(1,-2.3) 44(1.5,-2.3) 46(2,-2.3) 48(2.5,-2.3) 50(3,-2.3) 52(3.5,-2.3) 54(4,-2.3) 56(4.5,-2.3) 58(5,-2.3) 68(7.5,-2.3) 70(8,-2.3) 72(8.5,-2.3) 74(9,-2.3)
  rect 1.194x2.743 smd: 76(-10.35,4.5) 77(10.35,4.5)
BGA1356M4224-U2H52
  round 0.356 smd: A3(19.349,-11.314) A70(-19.852,-11.314) B2(19.832,-10.832) B71(-20.314,-10.852) BA1(20.314,10.852) BA71(-20.314,10.852) BB2(19.852,11.314) BB70(-19.852,11.314) C1(20.314,-10.349)
  round 0.33 smd: A4(18.699,-11.314) A69(-19.202,-11.314) AY1(20.314,10.202) AY71(-20.314,10.202) B3(19.197,-10.679) B70(-19.685,-10.685) BA2(19.685,10.685) BA70(-19.685,10.685) BB3(19.202,11.314) BB69(-19.202,11.314) C2(19.679,-10.197) C71(-20.314,-10.202) D1(20.314,-9.699)
  round 0.305 smd: A5(18.048,-11.314) A68(-18.552,-11.314) AA2(19.339,-0.511) AA4(18.363,-0.511) AA63(-15.112,-0.596) AA64(-15.763,-0.596) AA65(-16.413,-0.596) AA66(-17.063,-0.596) AA67(-17.713,-0.596) AA68(-18.364,-0.596) AA69(-19.014,-0.596) AA70(-19.664,-0.596) AA71(-20.314,-0.596) AB4(18.363,0.152) AB6(17.585,-0.133) AB7(16.935,-0.133) AB8(16.285,-0.133) AB9(15.635,-0.133) AB10(14.984,-0.133) AB11(14.334,-0.133) AB12(13.684,-0.133) AB13(13.034,-0.133) AB15(12.188,-0.009) AB16(11.538,-0.009) AB17(10.888,-0.009) AB18(10.237,-0.009) AB19(9.587,-0.009) AB20(8.937,-0.009) AB21(8.287,-0.009) AB62(-14.644,-0.138) AC3(18.689,0.815) AC63(-15.112,0.319) AC64(-15.763,0.319) AC65(-16.413,0.319) AC66(-17.063,0.319) AC67(-17.713,0.319) AC68(-18.364,0.319) AC69(-19.014,0.319) AC70(-19.664,0.319) AC71(-20.314,0.319) AD4(18.363,1.478) AD6(17.585,0.934) AD7(16.935,0.934) AD8(16.285,0.934) AD9(15.635,0.934) AD10(14.984,0.934) AD11(14.334,0.934) AD12(13.684,0.934) AD13(13.034,0.934) AD15(12.188,0.829) AD16(11.538,0.829) AD17(10.888,0.829) AD18(10.237,0.829) AD19(9.587,0.829) AD20(8.937,0.829) AD21(8.287,0.829) AD62(-14.644,0.776) AE62(-14.644,1.69) AE63(-15.112,1.233) AE64(-15.763,1.233) AE65(-16.413,1.233) AE66(-17.063,1.233) AE67(-17.713,1.233) AE68(-18.364,1.233) AE69(-19.014,1.233) AF2(19.339,2.141) AF4(18.363,2.141) AF6(17.585,2.001) AF7(16.935,2.001) AF8(16.285,2.001) AF9(15.635,2.001) AF10(14.984,2.001) AF11(14.334,2.001) AF12(13.684,2.001) AF13(13.034,2.001) AF15(12.188,1.668) AF16(11.538,1.668) AF17(10.888,1.668) AF18(10.237,1.668) AF19(9.587,1.668) AF20(8.937,1.668) AF21(8.287,1.668) AF63(-15.112,2.148) AF64(-15.763,2.148) AF65(-16.413,2.148) AF66(-17.063,2.148) AF67(-17.713,2.148) AF68(-18.364,1.939) AF69(-19.014,1.939) AG4(18.363,2.804) AG15(12.188,2.506) AG16(11.538,2.506) AG17(10.888,2.506) AG18(10.237,2.506) AG19(9.587,2.506) AG20(8.937,2.506) AG21(8.287,2.506) AG62(-14.644,2.605) AG69(-18.689,2.602) AH3(18.689,3.467) AH6(17.585,3.067) AH7(16.935,3.067) AH8(16.285,3.067) AH9(15.635,3.067) AH10(14.984,3.067) AH11(14.334,3.067) AH12(13.684,3.067) AH13(13.034,3.067) AH63(-15.112,3.062) AH64(-15.763,3.062) AH65(-16.413,3.062) AH66(-17.063,3.062) AH67(-17.713,3.062) AJ4(18.363,4.13) AJ15(12.188,3.344) AJ16(11.538,3.344) AJ17(10.888,3.344) AJ18(10.237,3.344) AJ19(9.587,3.344) AJ20(8.937,3.344) AJ21(8.287,3.344) AJ62(-14.644,3.519) AK6(17.585,4.007) AK7(16.935,4.007) AK8(16.285,4.007) AK9(15.635,4.007) AK10(14.984,4.007) AK11(14.334,4.007) AK12(13.684,4.007) AK13(13.034,4.007) AK15(12.188,4.182) AK16(11.538,4.182) AK17(10.888,4.182) AK18(10.237,4.182) AK19(9.587,4.182) AK20(8.937,4.182) AK21(8.287,4.182) AK22(7.596,4.009) AK23(6.681,4.009) AK25(5.767,4.009) AK27(4.852,4.009) AK28(3.938,4.009) AK30(3.024,4.009) AK32(2.109,4.009) AK33(1.195,4.009) AK35(0.28,4.009) AK37(-0.634,4.009) AK38(-1.548,4.009) AK40(-2.463,4.009) AK42(-3.377,4.009) AK43(-4.292,4.009) AK45(-5.206,4.009) AK46(-6.12,4.009) AK48(-7.035,4.009) AK50(-7.949,4.009) AK52(-8.864,4.009) AK53(-9.778,4.009) AK55(-10.692,4.009) AK56(-11.607,4.009) AK58(-12.521,4.009) AK60(-13.436,4.009) AK62(-14.46,4.144) AK63(-15.112,3.976) AK64(-15.763,3.976) AK65(-16.413,3.976) AK66(-17.063,3.976) AK67(-17.713,3.976) AK68(-18.364,3.829) AK69(-19.339,3.829) AL2(19.339,4.793) AL4(18.363,4.793) AL23(7.138,4.474) AL25(6.224,4.474) AL27(5.31,4.474) AL28(4.395,4.474) AL30(3.481,4.474) AL32(2.566,4.474) AL33(1.652,4.474) AL35(0.738,4.474) AL37(-0.177,4.474) AL38(-1.091,4.474) AL40(-2.006,4.474) AL42(-2.92,4.474) AL43(-3.834,4.474) AL45(-4.749,4.474) AL46(-5.663,4.474) AL48(-6.578,4.474) AL50(-7.492,4.474) AL52(-8.406,4.474) AL53(-9.321,4.474) AL55(-10.235,4.474) AL56(-11.15,4.474) AL58(-12.064,4.474) AL60(-12.978,4.474) AL61(-13.893,4.474) AL63(-15.112,4.845) AL64(-15.763,4.845) AL65(-16.413,4.845) AL66(-17.063,4.845) AM4(18.363,5.456) AM5(17.654,4.946) AM7(16.74,4.946) AM8(15.825,4.946) AM10(14.911,4.946) AM11(13.996,4.946) AM13(13.082,4.946) AM15(12.168,4.946) AM16(11.253,4.946) AM18(10.339,4.946) AM20(9.424,4.946) AM21(8.51,4.946) AM22(7.596,4.946) AM23(6.681,4.946) AM25(5.767,4.946) AM27(4.852,4.946) AM28(3.938,4.946) AM30(3.024,4.946) AM32(2.109,4.946) AM33(1.195,4.946) AM35(0.28,4.946) AM37(-0.634,4.946) AM38(-1.548,4.946) AM40(-2.463,4.946) AM42(-3.377,4.946) AM43(-4.292,4.946) AM45(-5.206,4.946) AM46(-6.12,4.946) AM48(-7.035,4.946) AM50(-7.949,4.946) AM52(-8.864,4.946) AM53(-9.778,4.946) AM55(-10.692,4.946) AM56(-11.607,4.946) AM58(-12.521,4.946) AM60(-13.436,4.946) AM61(-14.35,4.946) AM68(-18.039,5.056) AM69(-18.689,5.056) AN3(18.689,6.119) AN5(17.654,5.597) AN7(16.74,5.597) AN8(15.825,5.597) AN10(14.911,5.597) AN11(13.996,5.597) AN13(13.082,5.597) AN15(12.168,5.597) AN16(11.253,5.597) AN18(10.339,5.597) AN20(9.424,5.597) AN21(8.51,5.597) AN22(7.596,5.597) AN23(6.681,5.597) AN25(5.767,5.597) AN27(4.852,5.597) AN28(3.938,5.597) AN30(3.024,5.597) AN32(2.109,5.597) AN33(1.195,5.597) AN35(0.28,5.597) AN37(-0.634,5.597) AN38(-1.548,5.597) AN40(-2.463,5.597) AN42(-3.377,5.597) AN43(-4.292,5.597) AN45(-5.206,5.597) AN46(-6.12,5.597) AN48(-7.035,5.597) AN50(-7.949,5.597) AN52(-8.864,5.597) AN53(-9.778,5.597) AN55(-10.692,5.597) AN56(-11.607,5.597) AN58(-12.521,5.597) AN60(-13.436,5.597) AN61(-14.35,5.597) AN63(-15.264,5.597) AN65(-16.179,5.597) AN66(-17.093,5.597) AN68(-18.364,5.719) AN69(-19.014,5.719) AP4(18.363,6.782) AP5(17.654,6.247) AP7(16.74,6.247) AP8(15.825,6.247) AP10(14.911,6.247) AP11(13.996,6.247) AP13(13.082,6.247) AP15(12.168,6.247) AP16(11.253,6.247) AP18(10.339,6.247) AP20(9.424,6.247) AP21(8.51,6.247) AP22(7.596,6.247) AP23(6.681,6.247) AP25(5.767,6.247) AP27(4.852,6.247) AP28(3.938,6.247) AP30(3.024,6.247) AP32(2.109,6.247) AP33(1.195,6.247) AP35(0.28,6.247) AP37(-0.634,6.247) AP38(-1.548,6.247) AP40(-2.463,6.247) AP42(-3.377,6.247) AP43(-4.292,6.247) AP45(-5.206,6.247) AP46(-6.12,6.247) AP48(-7.035,6.247) AP50(-7.949,6.247) AP52(-8.864,6.247) AP53(-9.778,6.247) AP55(-10.692,6.247) AP56(-11.607,6.247) AP58(-12.521,6.247) AP60(-13.436,6.247) AP61(-14.35,6.247) AP63(-15.264,6.247) AP65(-16.179,6.247) AP66(-17.093,6.247) AP68(-18.039,6.332) AP70(-19.258,6.332) AR5(17.654,6.897) AR7(16.74,6.897) AR8(15.825,6.897) AR10(14.911,6.897) AR11(13.996,6.897) AR13(13.082,6.897) AR15(12.168,6.897) AR16(11.253,6.897) AR18(10.339,6.897) AR20(9.424,6.897) AR21(8.51,6.897) AR22(7.596,6.897) AR23(6.681,6.897) AR25(5.767,6.897) AR27(4.852,6.897) AR28(3.938,6.897) AR30(3.024,6.897) AR32(2.109,6.897) AR33(1.195,6.897) AR35(0.28,6.897) AR37(-0.634,6.897) AR38(-1.548,6.897) AR40(-2.463,6.897) AR42(-3.377,6.897) AR43(-4.292,6.897) AR45(-5.206,6.897) AR46(-6.12,6.897) AR48(-7.035,6.897) AR50(-7.949,6.897) AR52(-8.864,6.897) AR53(-9.778,6.897) AR55(-10.692,6.897) AR56(-11.607,6.897) AR58(-12.521,6.897) AR60(-13.436,6.897) AR61(-14.35,6.897) AR63(-15.264,6.897) AR65(-16.179,6.897) AR66(-17.093,6.897) AR68(-18.364,6.945) AR69(-19.014,6.945) AT2(19.339,7.445) AT4(18.363,7.445) AT5(17.654,7.547) AT7(16.74,7.547) AT8(15.825,7.547) AT10(14.911,7.547) AT11(13.996,7.547) AT13(13.082,7.547) AT15(12.168,7.547) AT16(11.253,7.547) AT18(10.339,7.547) AT20(9.424,7.547) AT21(8.51,7.547) AT22(7.596,7.547) AT23(6.681,7.547) AT25(5.767,7.547) AT27(4.852,7.547) AT28(3.938,7.547) AT30(3.024,7.547) AT32(2.109,7.547) AT33(1.195,7.547) AT35(0.28,7.547) AT37(-0.634,7.547) AT38(-1.548,7.547) AT40(-2.463,7.547) AT42(-3.377,7.547) AT43(-4.292,7.547) AT45(-5.206,7.547) AT46(-6.12,7.547) AT48(-7.035,7.547) AT50(-7.949,7.547) AT52(-8.864,7.547) AT53(-9.778,7.547) AT55(-10.692,7.547) AT56(-11.607,7.547) AT58(-12.521,7.547) AT60(-13.436,7.547) AT61(-14.35,7.547) AT63(-15.264,7.547) AT65(-16.179,7.547) AT66(-17.093,7.547) AT68(-18.039,7.509) AT69(-18.689,7.509) AU4(18.363,8.108) AU5(17.654,8.198) AU7(16.74,8.198) AU8(15.825,8.198) AU10(14.911,8.198) AU11(13.996,8.198) AU13(13.082,8.198) AU15(12.168,8.198) AU16(11.253,8.198) AU18(10.339,8.198) AU20(9.424,8.198) AU21(8.51,8.198) AU22(7.596,8.198) AU23(6.681,8.198) AU25(5.767,8.198) AU27(4.852,8.198) AU28(3.938,8.198) AU30(3.024,8.198) AU32(2.109,8.198) AU33(1.195,8.198) AU35(0.28,8.198) AU37(-0.634,8.198) AU38(-1.548,8.198) AU40(-2.463,8.198) AU42(-3.377,8.198) AU43(-4.292,8.198) AU45(-5.206,8.198) AU46(-6.12,8.198) AU48(-7.035,8.198) AU50(-7.949,8.198) AU52(-8.864,8.198) AU53(-9.778,8.198) AU55(-10.692,8.198) AU56(-11.607,8.198) AU58(-12.521,8.198) AU60(-13.436,8.198) AU61(-14.35,8.198) AU63(-15.264,8.198) AU65(-16.179,8.198) AU66(-17.093,8.198) AV3(18.689,8.799) AV68(-18.029,8.711) AV69(-19.014,8.901) AV70(-19.664,8.901) AW1(20.314,9.551) AW5(17.781,8.911) AW6(17.13,9.038) AW7(16.564,9.363) AW8(15.986,9.038) AW9(15.416,9.363) AW10(14.753,9.038) AW11(14.143,9.363) AW12(13.565,9.038) AW13(12.995,9.363) AW14(12.332,9.038) AW15(11.723,9.363) AW16(11.145,9.038) AW17(10.575,9.363) AW18(9.912,9.038) AW20(9.302,9.363) AW21(8.724,9.038) AW22(8.154,9.363) AW23(7.466,9.038) AW25(6.828,9.363) AW26(6.264,9.038) AW27(5.601,9.363) AW28(4.988,9.038) AW29(4.374,9.363) AW30(3.711,9.038) AW31(3.148,9.363) AW32(2.485,9.038) AW33(1.847,9.363) AW34(1.283,9.038) AW35(0.62,9.363) AW36(0.007,9.038) AW37(-0.607,9.363) AW38(-1.269,9.038) AW39(-1.833,9.363) AW41(-2.471,9.038) AW42(-3.108,9.363) AW43(-3.672,9.038) AW44(-4.335,9.363) AW45(-4.949,9.038) AW46(-5.562,9.363) AW47(-6.163,9.038) AW48(-6.727,9.363) AW49(-7.355,9.038) AW50(-7.984,9.363) AW51(-8.548,9.038) AW52(-9.149,9.363) AW53(-9.762,9.038) AW54(-10.375,9.363) AW55(-11.038,9.038) AW56(-11.602,9.363) AW57(-12.24,9.038) AW59(-12.877,9.363) AW60(-13.441,9.038) AW61(-14.104,9.363) AW62(-14.718,9.038) AW63(-15.331,9.363) AW64(-15.994,9.038) AW65(-16.558,9.363) AW66(-17.093,8.9) AW67(-18.018,9.371) AW68(-18.622,9.622) AW69(-19.267,9.536) AW70(-19.685,10.035) AW71(-20.314,9.551) AY2(19.685,10.034) AY3(19.028,10.028) AY4(18.274,10.043) AY5(17.665,9.689) AY8(15.986,9.689) AY12(13.565,9.689) AY16(11.145,9.689) AY21(8.724,9.689) AY26(6.264,9.689) AY27(5.601,10.014) AY29(4.374,10.014) AY30(3.711,9.689) AY34(1.283,9.689) AY35(0.62,10.014) AY37(-0.607,10.014) AY38(-1.269,9.689) AY43(-3.672,9.689) AY44(-4.335,10.014) AY46(-5.562,10.014) AY47(-6.163,9.689) AY51(-8.548,9.689) AY52(-9.149,10.014) AY54(-10.375,10.014) AY55(-11.038,9.689) AY60(-13.441,9.689) AY61(-14.104,10.014) AY63(-15.331,10.014) AY64(-15.994,9.689) AY66(-17.221,9.689) AY68(-18.535,10.267) B5(18.048,-10.664) B6(17.467,-10.339) B10(14.989,-10.339) B14(12.511,-10.339) B18(10.033,-10.339) B22(7.555,-10.339) B26(5.077,-10.339) B30(2.599,-10.339) B34(0.121,-10.339) B39(-2.357,-10.339) B44(-4.835,-10.339) B48(-7.313,-10.339) B53(-9.791,-10.339) B58(-12.269,-10.339) B62(-14.747,-10.339) B66(-17.226,-10.339) B69(-19.035,-10.685) BA3(19.035,10.685) BA5(17.715,10.626) BA8(15.986,10.339) BA12(13.565,10.339) BA16(11.145,10.339) BA21(8.724,10.339) BA23(7.466,10.258) BA28(4.988,10.258) BA32(2.485,10.258) BA36(0.007,10.258) BA41(-2.471,10.258) BA45(-4.949,10.258) BA49(-7.355,10.339) BA53(-9.762,10.258) BA57(-12.24,10.258) BA62(-14.718,10.258) BA68(-19.035,10.685) BB4(18.551,11.314) BB68(-18.552,11.314) C4(18.615,-10.336) C5(18.048,-10.014) C7(16.791,-10.014) C8(16.228,-10.339) C9(15.664,-10.014) C11(14.313,-10.014) C12(13.75,-10.339) C13(13.186,-10.014) C15(11.835,-10.014) C16(11.272,-10.339) C17(10.708,-10.014) C19(9.357,-10.014) C20(8.794,-10.339) C21(8.23,-10.014) C23(6.879,-10.014) C24(6.316,-10.339) C25(5.752,-10.014) C27(4.401,-10.014) C28(3.838,-10.339) C29(3.274,-10.014) C31(1.923,-10.014) C32(1.36,-10.339) C33(0.796,-10.014) C36(-0.555,-10.014) C37(-1.118,-10.339) C38(-1.682,-10.014) C40(-3.033,-10.014) C41(-3.596,-10.339) C42(-4.16,-10.014) C45(-5.511,-10.014) C46(-6.074,-10.339) C47(-6.638,-10.014) C50(-7.989,-10.014) C51(-8.552,-10.339) C52(-9.116,-10.014) C54(-10.467,-10.014) C55(-11.03,-10.339) C56(-11.594,-10.014) C59(-12.945,-10.014) C60(-13.508,-10.339) C61(-14.072,-10.014) C63(-15.423,-10.014) C64(-15.987,-10.339) C65(-16.55,-10.014) C67(-18.485,-10.299) C68(-18.622,-9.622) C70(-19.685,-10.034) D3(19.339,-9.608) D4(18.691,-9.669) D5(18.09,-9.363) D6(17.441,-9.323) D7(16.791,-9.363) D8(16.228,-9.689) D9(15.664,-9.363) D10(14.989,-9.323) D11(14.313,-9.363) D12(13.75,-9.689) D13(13.186,-9.363) D14(12.511,-9.323) D15(11.835,-9.363) D16(11.272,-9.689) D17(10.708,-9.363) D18(10.033,-9.323) D19(9.357,-9.363) D20(8.794,-9.689) D21(8.23,-9.363) D22(7.555,-9.323) D23(6.879,-9.363) D24(6.316,-9.689) D25(5.752,-9.363) D26(5.077,-9.323) D27(4.401,-9.363) D28(3.838,-9.689) D29(3.274,-9.363) D30(2.599,-9.323) D31(1.923,-9.363) D32(1.36,-9.689) D33(0.796,-9.363) D34(0.121,-9.323) D36(-0.555,-9.363) D37(-1.118,-9.689) D38(-1.682,-9.363) D39(-2.357,-9.323) D40(-3.033,-9.363) D41(-3.596,-9.689) D42(-4.16,-9.363) D44(-4.835,-9.323) D45(-5.511,-9.363) D46(-6.074,-9.689) D47(-6.638,-9.363) D48(-7.313,-9.323) D50(-7.989,-9.363) D51(-8.552,-9.689) D52(-9.116,-9.363) D53(-9.791,-9.323) D54(-10.467,-9.363) D55(-11.03,-9.689) D56(-11.594,-9.363) D58(-12.269,-9.323) D59(-12.945,-9.363) D60(-13.508,-9.689) D61(-14.072,-9.363) D62(-14.747,-9.323) D63(-15.423,-9.363) D64(-15.987,-9.689) D65(-16.55,-9.363) D66(-17.226,-9.323) D67(-17.899,-10.014) D68(-19.267,-9.535) D69(-18.562,-8.971) D71(-20.314,-9.551) E1(20.314,-9.04) E2(19.664,-9.04) E3(19.014,-9.04) E5(17.654,-8.591) E6(16.74,-8.591) E8(15.825,-8.591) E10(14.911,-8.591) E11(13.996,-8.591) E13(13.082,-8.591) E15(12.168,-8.591) E16(11.253,-8.591) E18(10.339,-8.591) E20(9.424,-8.591) E21(8.51,-8.591) E22(7.596,-8.591) E23(6.681,-8.591) E25(5.767,-8.591) E27(4.852,-8.591) E28(3.938,-8.591) E30(3.024,-8.591) E32(2.109,-8.591) E33(1.195,-8.591) E35(0.28,-8.591) E37(-0.634,-8.591) E38(-1.548,-8.591) E40(-2.463,-8.591) E42(-3.377,-8.591) E43(-4.292,-8.591) E45(-5.206,-8.591) E46(-6.12,-8.591) E48(-7.035,-8.591) E50(-7.949,-8.591) E52(-8.864,-8.591) E53(-9.778,-8.591) E55(-10.692,-8.591) E56(-11.607,-8.591) E58(-12.521,-8.591) E60(-13.436,-8.591) E61(-14.35,-8.591) E63(-15.315,-8.655) E65(-16.331,-8.655) E66(-17.347,-8.655) E68(-17.899,-9.363) F2(19.339,-8.466) F4(18.363,-8.466) F5(17.654,-7.941) F6(16.74,-7.941) F8(15.825,-7.941) F10(14.911,-7.941) F11(13.996,-7.941) F13(13.082,-7.941) F15(12.168,-7.941) F16(11.253,-7.941) F18(10.339,-7.941) F20(9.424,-7.941) F21(8.51,-7.941) F22(7.596,-7.941) F23(6.681,-7.941) F25(5.767,-7.941) F27(4.852,-7.941) F28(3.938,-7.941) F30(3.024,-7.941) F32(2.109,-7.941) F33(1.195,-7.941) F35(0.28,-7.941) F37(-0.634,-7.941) F38(-1.548,-7.941) F40(-2.463,-7.941) F42(-3.377,-7.941) F43(-4.292,-7.941) F45(-5.206,-7.941) F46(-6.12,-7.941) F48(-7.035,-7.941) F50(-7.949,-7.941) F52(-8.864,-7.941) F53(-9.778,-7.941) F55(-10.692,-7.941) F56(-11.607,-7.941) F58(-12.521,-7.941) F60(-13.436,-7.941) F61(-14.35,-7.941) F63(-15.315,-8.005) F65(-16.331,-8.005) F66(-17.347,-8.005) F68(-18.562,-8.32) G4(18.363,-7.803) G5(17.654,-7.291) G6(16.74,-7.291) G8(15.825,-7.291) G10(14.911,-7.291) G11(13.996,-7.291) G13(13.082,-7.291) G15(12.168,-7.291) G16(11.253,-7.291) G18(10.339,-7.291) G20(9.424,-7.291) G21(8.51,-7.291) G22(7.596,-7.291) G23(6.681,-7.291) G25(5.767,-7.291) G27(4.852,-7.291) G28(3.938,-7.291) G30(3.024,-7.291) G32(2.109,-7.291) G33(1.195,-7.291) G35(0.28,-7.291) G37(-0.634,-7.291) G38(-1.548,-7.291) G40(-2.463,-7.291) G42(-3.377,-7.291) G43(-4.292,-7.291) G45(-5.206,-7.291) G46(-6.12,-7.291) G48(-7.035,-7.291) G50(-7.949,-7.291) G52(-8.864,-7.291) G53(-9.778,-7.291) G55(-10.692,-7.291) G56(-11.607,-7.291) G58(-12.521,-7.291) G60(-13.436,-7.291) G61(-14.35,-7.291) G63(-15.315,-7.354) G65(-16.331,-7.354) G66(-17.347,-7.354) G68(-18.364,-7.66) G69(-19.014,-7.66) H3(18.689,-7.14) H5(17.654,-6.641) H6(16.74,-6.641) H8(15.825,-6.641) H10(14.911,-6.641) H11(13.996,-6.641) H13(13.082,-6.641) H15(12.168,-6.641) H16(11.253,-6.641) H18(10.339,-6.641) H20(9.424,-6.641) H21(8.51,-6.641) H63(-15.315,-6.704) H65(-16.331,-6.704) H66(-17.347,-6.704) H69(-18.689,-7.096) J4(18.363,-6.477) J5(17.654,-5.99) J6(16.74,-5.99) J8(15.825,-5.99) J10(14.911,-5.99) J11(13.996,-5.99) J13(13.082,-5.99) J22(7.138,-6.827) J23(6.224,-6.827) J25(5.31,-6.827) J27(4.395,-6.827) J28(3.481,-6.827) J30(2.566,-6.827) J32(1.652,-6.827) J33(0.738,-6.827) J35(-0.177,-6.827) J37(-1.091,-6.827) J38(-2.006,-6.827) J40(-2.92,-6.827) J42(-3.834,-6.827) J43(-4.749,-6.827) J45(-5.663,-6.827) J46(-6.578,-6.827) J48(-7.492,-6.827) J50(-8.406,-6.827) J52(-9.321,-6.827) J53(-10.235,-6.827) J55(-11.15,-6.827) J56(-12.064,-6.827) J58(-12.978,-6.827) J60(-13.893,-6.827) J68(-18.362,-6.52) K15(12.188,-5.876) K16(11.538,-5.876) K17(10.888,-5.876) K18(10.237,-5.876) K19(9.587,-5.876) K20(8.937,-5.876) K21(8.287,-5.876) K22(7.596,-6.362) K23(6.681,-6.362) K25(5.767,-6.362) K27(4.852,-6.362) K28(3.938,-6.362) K30(3.024,-6.362) K32(2.109,-6.362) K33(1.195,-6.362) K35(0.28,-6.362) K37(-0.634,-6.362) K38(-1.548,-6.362) K40(-2.463,-6.362) K42(-3.377,-6.362) K43(-4.292,-6.362) K45(-5.206,-6.362) K46(-6.12,-6.362) K48(-7.035,-6.362) K50(-7.949,-6.362) K52(-8.864,-6.362) K53(-9.778,-6.362) K55(-10.692,-6.362) K56(-11.607,-6.362) K58(-12.521,-6.362) K60(-13.436,-6.362) K61(-14.35,-6.362) K63(-15.133,-6.054) K64(-15.783,-6.054) K65(-16.433,-6.054) K66(-17.084,-6.054) K67(-17.734,-6.054) K68(-18.352,-5.846) K70(-19.339,-5.744) L2(19.339,-5.814) L4(18.363,-5.814) L6(17.585,-5.34) L7(16.935,-5.34) L8(16.285,-5.34) L9(15.635,-5.34) L10(14.984,-5.34) L11(14.334,-5.34) L12(13.684,-5.34) L13(13.034,-5.34) L15(12.188,-5.038) L16(11.538,-5.038) L17(10.888,-5.038) L18(10.237,-5.038) L19(9.587,-5.038) L20(8.937,-5.038) L21(8.287,-5.038) L62(-14.644,-5.625) L63(-15.112,-5.168) L64(-15.763,-5.168) L65(-16.413,-5.168) L66(-17.063,-5.168) L67(-17.713,-5.168) L68(-18.364,-5.168) L69(-19.014,-5.168) L70(-19.664,-5.168) L71(-20.314,-5.168) M4(18.363,-5.151) M62(-14.644,-4.71) N3(18.689,-4.488) N6(17.585,-4.4) N7(16.935,-4.4) N8(16.285,-4.4) N9(15.635,-4.4) N10(14.984,-4.4) N11(14.334,-4.4) N12(13.684,-4.4) N13(13.034,-4.4) N15(12.188,-4.2) N16(11.538,-4.2) N17(10.888,-4.2) N18(10.237,-4.2) N19(9.587,-4.2) N20(8.937,-4.2) N21(8.287,-4.2) N63(-15.112,-4.253) N64(-15.763,-4.253) N65(-16.413,-4.253) N66(-17.063,-4.253) N67(-17.713,-4.253) N68(-18.364,-4.253) N69(-19.014,-4.253) N70(-19.664,-4.253) N71(-20.314,-4.253) P4(18.363,-3.825) P15(12.188,-3.362) P16(11.538,-3.362) P17(10.888,-3.362) P18(10.237,-3.362) P19(9.587,-3.362) P20(8.937,-3.362) P21(8.287,-3.362) P62(-14.644,-3.796) R6(17.585,-3.333) R7(16.935,-3.333) R8(16.285,-3.333) R9(15.635,-3.333) R10(14.984,-3.333) R11(14.334,-3.333) R12(13.684,-3.333) R13(13.034,-3.333) R63(-15.112,-3.339) R64(-15.763,-3.339) R65(-16.413,-3.339) R66(-17.063,-3.339) R67(-17.713,-3.339) R68(-18.364,-3.339) R69(-19.014,-3.339) R70(-19.664,-3.339) R71(-20.314,-3.339) T2(19.339,-3.162) T4(18.363,-3.162) T15(12.188,-2.523) T16(11.538,-2.523) T17(10.888,-2.523) T18(10.237,-2.523) T19(9.587,-2.523) T20(8.937,-2.523) T21(8.287,-2.523) T62(-14.644,-2.882) U4(18.363,-2.499) U6(17.585,-2.267) U7(16.935,-2.267) U8(16.285,-2.267) U9(15.635,-2.267) U10(14.984,-2.267) U11(14.334,-2.267) U12(13.684,-2.267) U13(13.034,-2.267) U63(-15.112,-2.424) U64(-15.763,-2.424) U65(-16.413,-2.424) U66(-17.063,-2.424) U67(-17.713,-2.424) U68(-18.364,-2.424) U69(-19.014,-2.424) U70(-19.664,-2.424) U71(-20.314,-2.424) V3(18.689,-1.836) V15(12.188,-1.685) V16(11.538,-1.685) V17(10.888,-1.685) V18(10.237,-1.685) V19(9.587,-1.685) V20(8.937,-1.685) V21(8.287,-1.685) V62(-14.644,-1.967) W4(18.363,-1.173) W6(17.585,-1.2) W7(16.935,-1.2) W8(16.285,-1.2) W9(15.635,-1.2) W10(14.984,-1.2) W11(14.334,-1.2) W12(13.684,-1.2) W13(13.034,-1.2) W63(-15.112,-1.51) W64(-15.763,-1.51) W65(-16.413,-1.51) W66(-17.063,-1.51) W67(-17.713,-1.51) W68(-18.364,-1.51) W69(-19.014,-1.51) W70(-19.664,-1.51) W71(-20.314,-1.51) Y15(12.188,-0.847) Y16(11.538,-0.847) Y17(10.888,-0.847) Y18(10.237,-0.847) Y19(9.587,-0.847) Y20(8.937,-0.847) Y21(8.287,-0.847) Y62(-14.644,-1.053)
  oval 0.254x0.343 smd: A6(17.467,-10.989) A7(16.791,-11.314) A9(15.664,-11.314) A10(14.989,-10.989) A11(14.313,-11.314) A13(13.186,-11.314) A14(12.511,-10.989) A15(11.835,-11.314) A17(10.708,-11.314) A18(10.033,-10.989) A19(9.357,-11.314) A21(8.23,-11.314) A22(7.555,-10.989) A23(6.879,-11.314) A25(5.752,-11.314) A26(5.077,-10.989) A27(4.401,-11.314) A29(3.274,-11.314) A30(2.599,-10.989) A31(1.923,-11.314) A33(0.796,-11.314) A34(0.121,-10.989) A36(-0.555,-11.314) A38(-1.682,-11.314) A39(-2.357,-10.989) A40(-3.033,-11.314) A42(-4.16,-11.314) A44(-4.835,-10.989) A45(-5.511,-11.314) A47(-6.638,-11.314) A48(-7.313,-10.989) A50(-7.989,-11.314) A52(-9.116,-11.314) A53(-9.791,-10.989) A54(-10.467,-11.314) A56(-11.594,-11.314) A58(-12.269,-10.989) A59(-12.945,-11.314) A61(-14.072,-11.314) A62(-14.747,-10.989) A63(-15.423,-11.314) A65(-16.55,-11.314) A66(-17.226,-10.989) A67(-17.901,-11.314) AY7(16.551,10.014) AY9(15.416,10.014) AY11(14.131,10.014) AY13(12.995,10.014) AY15(11.71,10.014) AY17(10.575,10.014) AY20(9.289,10.014) AY22(8.154,10.014) AY25(6.828,10.014) AY31(3.148,10.014) AY33(1.847,10.014) AY39(-1.833,10.014) AY42(-3.108,10.014) AY48(-6.789,10.014) AY50(-7.922,10.014) AY56(-11.602,10.014) AY59(-12.877,10.014) AY65(-16.558,10.014) AY67(-17.901,10.014) B7(16.791,-10.664) B9(15.664,-10.664) B11(14.313,-10.664) B13(13.186,-10.664) B15(11.835,-10.664) B17(10.708,-10.664) B19(9.357,-10.664) B21(8.23,-10.664) B23(6.879,-10.664) B25(5.752,-10.664) B27(4.401,-10.664) B29(3.274,-10.664) B31(1.923,-10.664) B33(0.796,-10.664) B36(-0.555,-10.664) B38(-1.682,-10.664) B40(-3.033,-10.664) B42(-4.16,-10.664) B45(-5.511,-10.664) B47(-6.638,-10.664) B50(-7.989,-10.664) B52(-9.116,-10.664) B54(-10.467,-10.664) B56(-11.594,-10.664) B59(-12.945,-10.664) B61(-14.072,-10.664) B63(-15.423,-10.664) B65(-16.55,-10.664) B67(-17.901,-10.664) BA4(18.366,10.689) BA6(17.173,10.258) BA7(16.61,10.664) BA9(15.416,10.664) BA10(14.753,10.258) BA11(14.189,10.664) BA13(12.995,10.664) BA14(12.332,10.258) BA15(11.768,10.664) BA17(10.575,10.664) BA18(9.912,10.258) BA20(9.348,10.664) BA22(8.154,10.664) BA25(6.828,10.664) BA26(6.165,10.339) BA27(5.502,10.664) BA29(4.473,10.664) BA30(3.811,10.339) BA31(3.148,10.664) BA33(1.847,10.664) BA34(1.184,10.339) BA35(0.521,10.664) BA37(-0.507,10.664) BA38(-1.17,10.339) BA39(-1.833,10.664) BA42(-3.108,10.664) BA43(-3.771,10.339) BA44(-4.434,10.664) BA46(-5.463,10.664) BA47(-6.126,10.339) BA48(-6.789,10.664) BA50(-7.922,10.664) BA51(-8.585,10.339) BA52(-9.248,10.664) BA54(-10.276,10.664) BA55(-10.939,10.339) BA56(-11.602,10.664) BA59(-12.877,10.664) BA60(-13.54,10.339) BA61(-14.203,10.664) BA63(-15.232,10.664) BA64(-15.895,10.339) BA65(-16.558,10.664) BA66(-17.221,10.339) BA67(-17.901,10.664) BB5(17.786,11.314) BB6(17.173,10.989) BB7(16.61,11.314) BB9(15.416,11.314) BB10(14.753,10.989) BB11(14.189,11.314) BB13(12.995,11.314) BB14(12.332,10.989) BB15(11.768,11.314) BB17(10.575,11.314) BB18(9.912,10.989) BB20(9.348,11.314) BB22(8.154,11.314) BB23(7.466,10.908) BB25(6.828,11.314) BB26(6.165,10.989) BB27(5.502,11.314) BB29(4.473,11.314) BB30(3.811,10.989) BB31(3.148,11.314) BB32(2.485,10.908) BB33(1.847,11.314) BB34(1.184,10.989) BB35(0.521,11.314) BB37(-0.507,11.314) BB38(-1.17,10.989) BB39(-1.833,11.314) BB41(-2.471,10.908) BB42(-3.108,11.314) BB43(-3.771,10.989) BB44(-4.434,11.314) BB46(-5.463,11.314) BB47(-6.126,10.989) BB48(-6.789,11.314) BB50(-7.922,11.314) BB51(-8.585,10.989) BB52(-9.248,11.314) BB54(-10.276,11.314) BB55(-10.939,10.989) BB56(-11.602,11.314) BB57(-12.24,10.908) BB59(-12.877,11.314) BB60(-13.54,10.989) BB61(-14.203,11.314) BB63(-15.232,11.314) BB64(-15.895,10.989) BB65(-16.558,11.314) BB66(-17.221,10.989) BB67(-17.901,11.314)
  oval 0.343x0.254 smd: AA1(19.989,-0.511) AB1(20.314,0.152) AB2(19.664,0.152) AB3(19.014,0.152) AC1(19.989,0.815) AC2(19.339,0.815) AD1(20.314,1.478) AD2(19.664,1.478) AD3(19.014,1.478) AF1(19.989,2.141) AF70(-19.664,1.84) AF71(-20.314,1.84) AG1(20.314,2.804) AG2(19.664,2.804) AG3(19.014,2.804) AG70(-19.339,2.503) AG71(-19.989,2.503) AH1(19.989,3.467) AH2(19.339,3.467) AH68(-18.364,3.166) AH69(-19.014,3.166) AH70(-19.664,3.166) AH71(-20.314,3.166) AJ1(20.314,4.13) AJ2(19.664,4.13) AJ3(19.014,4.13) AK70(-19.989,3.829) AL1(19.989,4.793) AL68(-18.364,4.492) AL69(-19.014,4.492) AL70(-19.664,4.492) AL71(-20.314,4.492) AM1(20.314,5.456) AM2(19.664,5.456) AM3(19.014,5.456) AM70(-19.339,5.155) AM71(-19.989,5.155) AN1(19.989,6.119) AN2(19.339,6.119) AN70(-19.664,5.818) AN71(-20.314,5.818) AP1(20.314,6.782) AP2(19.664,6.782) AP3(19.014,6.782) AR70(-19.664,6.846) AR71(-20.314,6.846) AT1(19.989,7.445) AT70(-19.339,7.509) AT71(-19.989,7.509) AU1(20.314,8.108) AU2(19.664,8.108) AU3(19.014,8.108) AU68(-18.364,8.147) AU69(-19.014,8.172) AU70(-19.664,8.172) AU71(-20.314,8.172) AV1(20.314,8.828) AV2(19.364,8.799) AV71(-20.314,8.901) AW2(19.689,9.362) AW3(19.039,9.362) E70(-19.664,-9.009) E71(-20.314,-8.901) F1(19.989,-8.466) F70(-19.212,-8.32) F71(-19.862,-8.384) G1(20.314,-7.803) G2(19.664,-7.803) G3(19.014,-7.803) G70(-19.664,-7.759) G71(-20.314,-7.759) H1(19.989,-7.14) H2(19.339,-7.14) H70(-19.339,-7.096) H71(-19.989,-7.096) J1(20.314,-6.477) J2(19.664,-6.477) J3(19.014,-6.477) J69(-19.014,-6.433) J70(-19.664,-6.433) J71(-20.314,-6.433) K71(-19.989,-5.744) L1(19.989,-5.814) M1(20.314,-5.151) M2(19.664,-5.151) M3(19.014,-5.151) N1(19.989,-4.488) N2(19.339,-4.488) P1(20.314,-3.825) P2(19.664,-3.825) P3(19.014,-3.825) T1(19.989,-3.162) U1(20.314,-2.499) U2(19.664,-2.499) U3(19.014,-2.499) V1(19.989,-1.836) V2(19.339,-1.836) W1(20.314,-1.173) W2(19.664,-1.173) W3(19.014,-1.173)
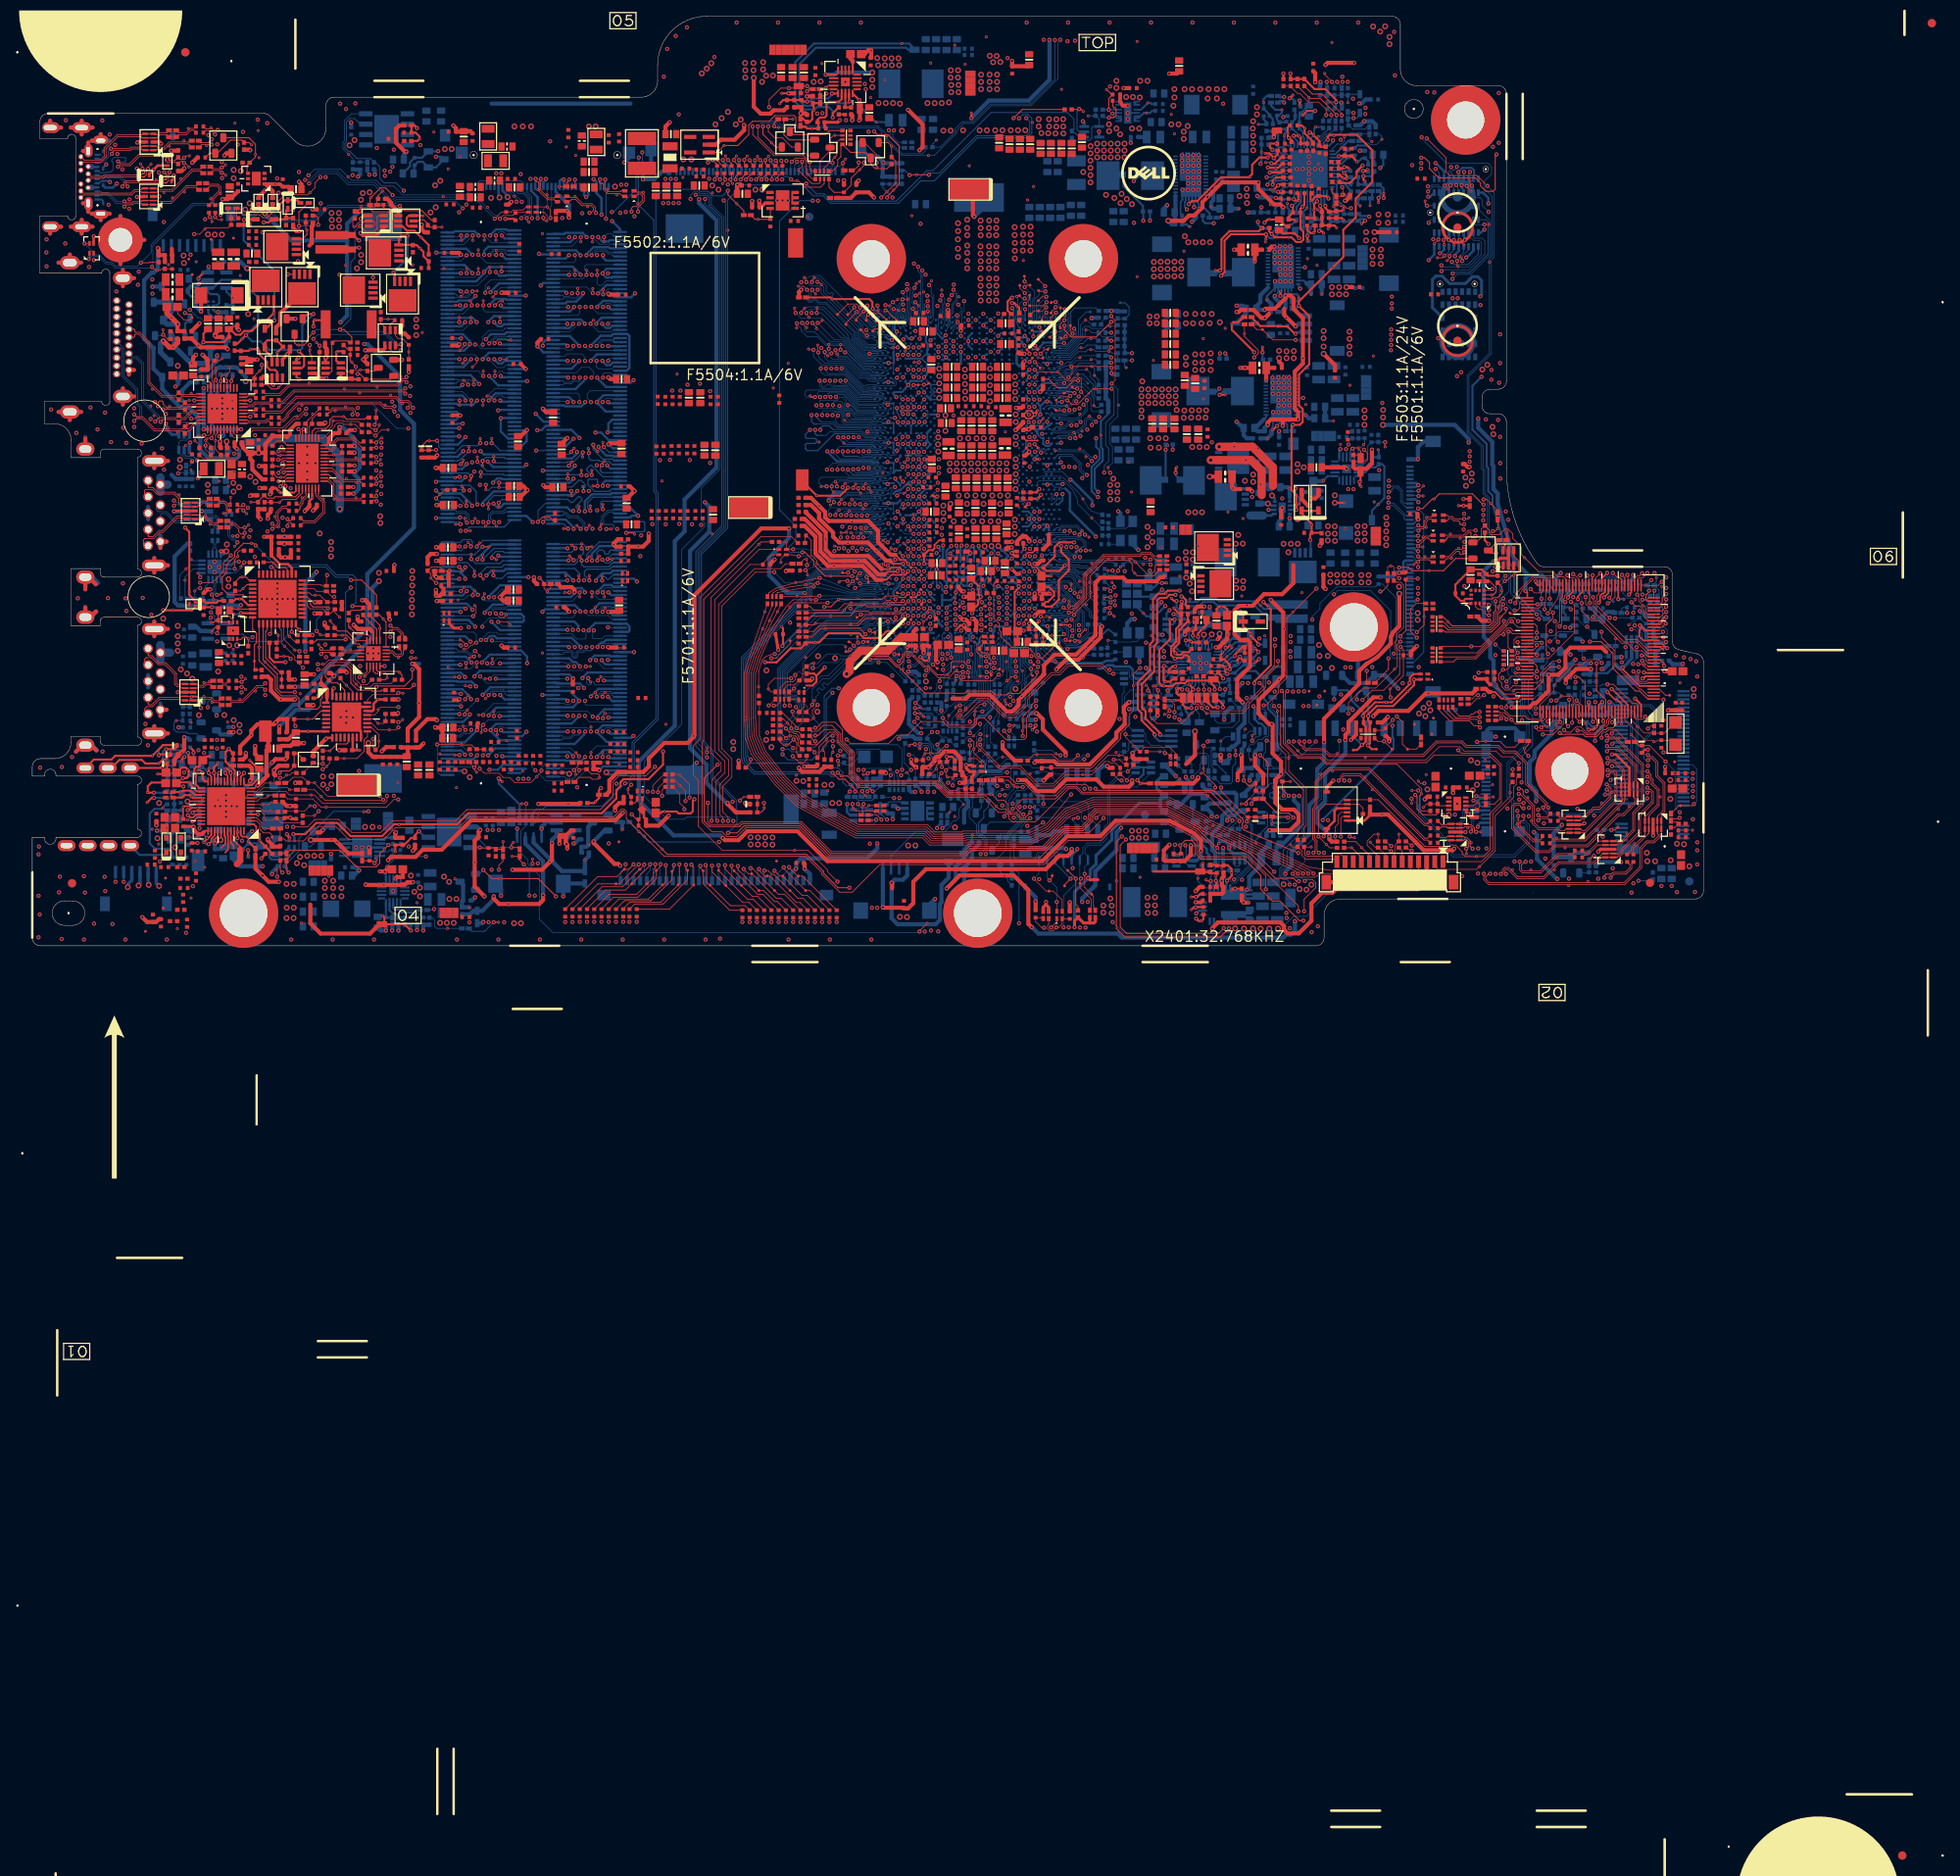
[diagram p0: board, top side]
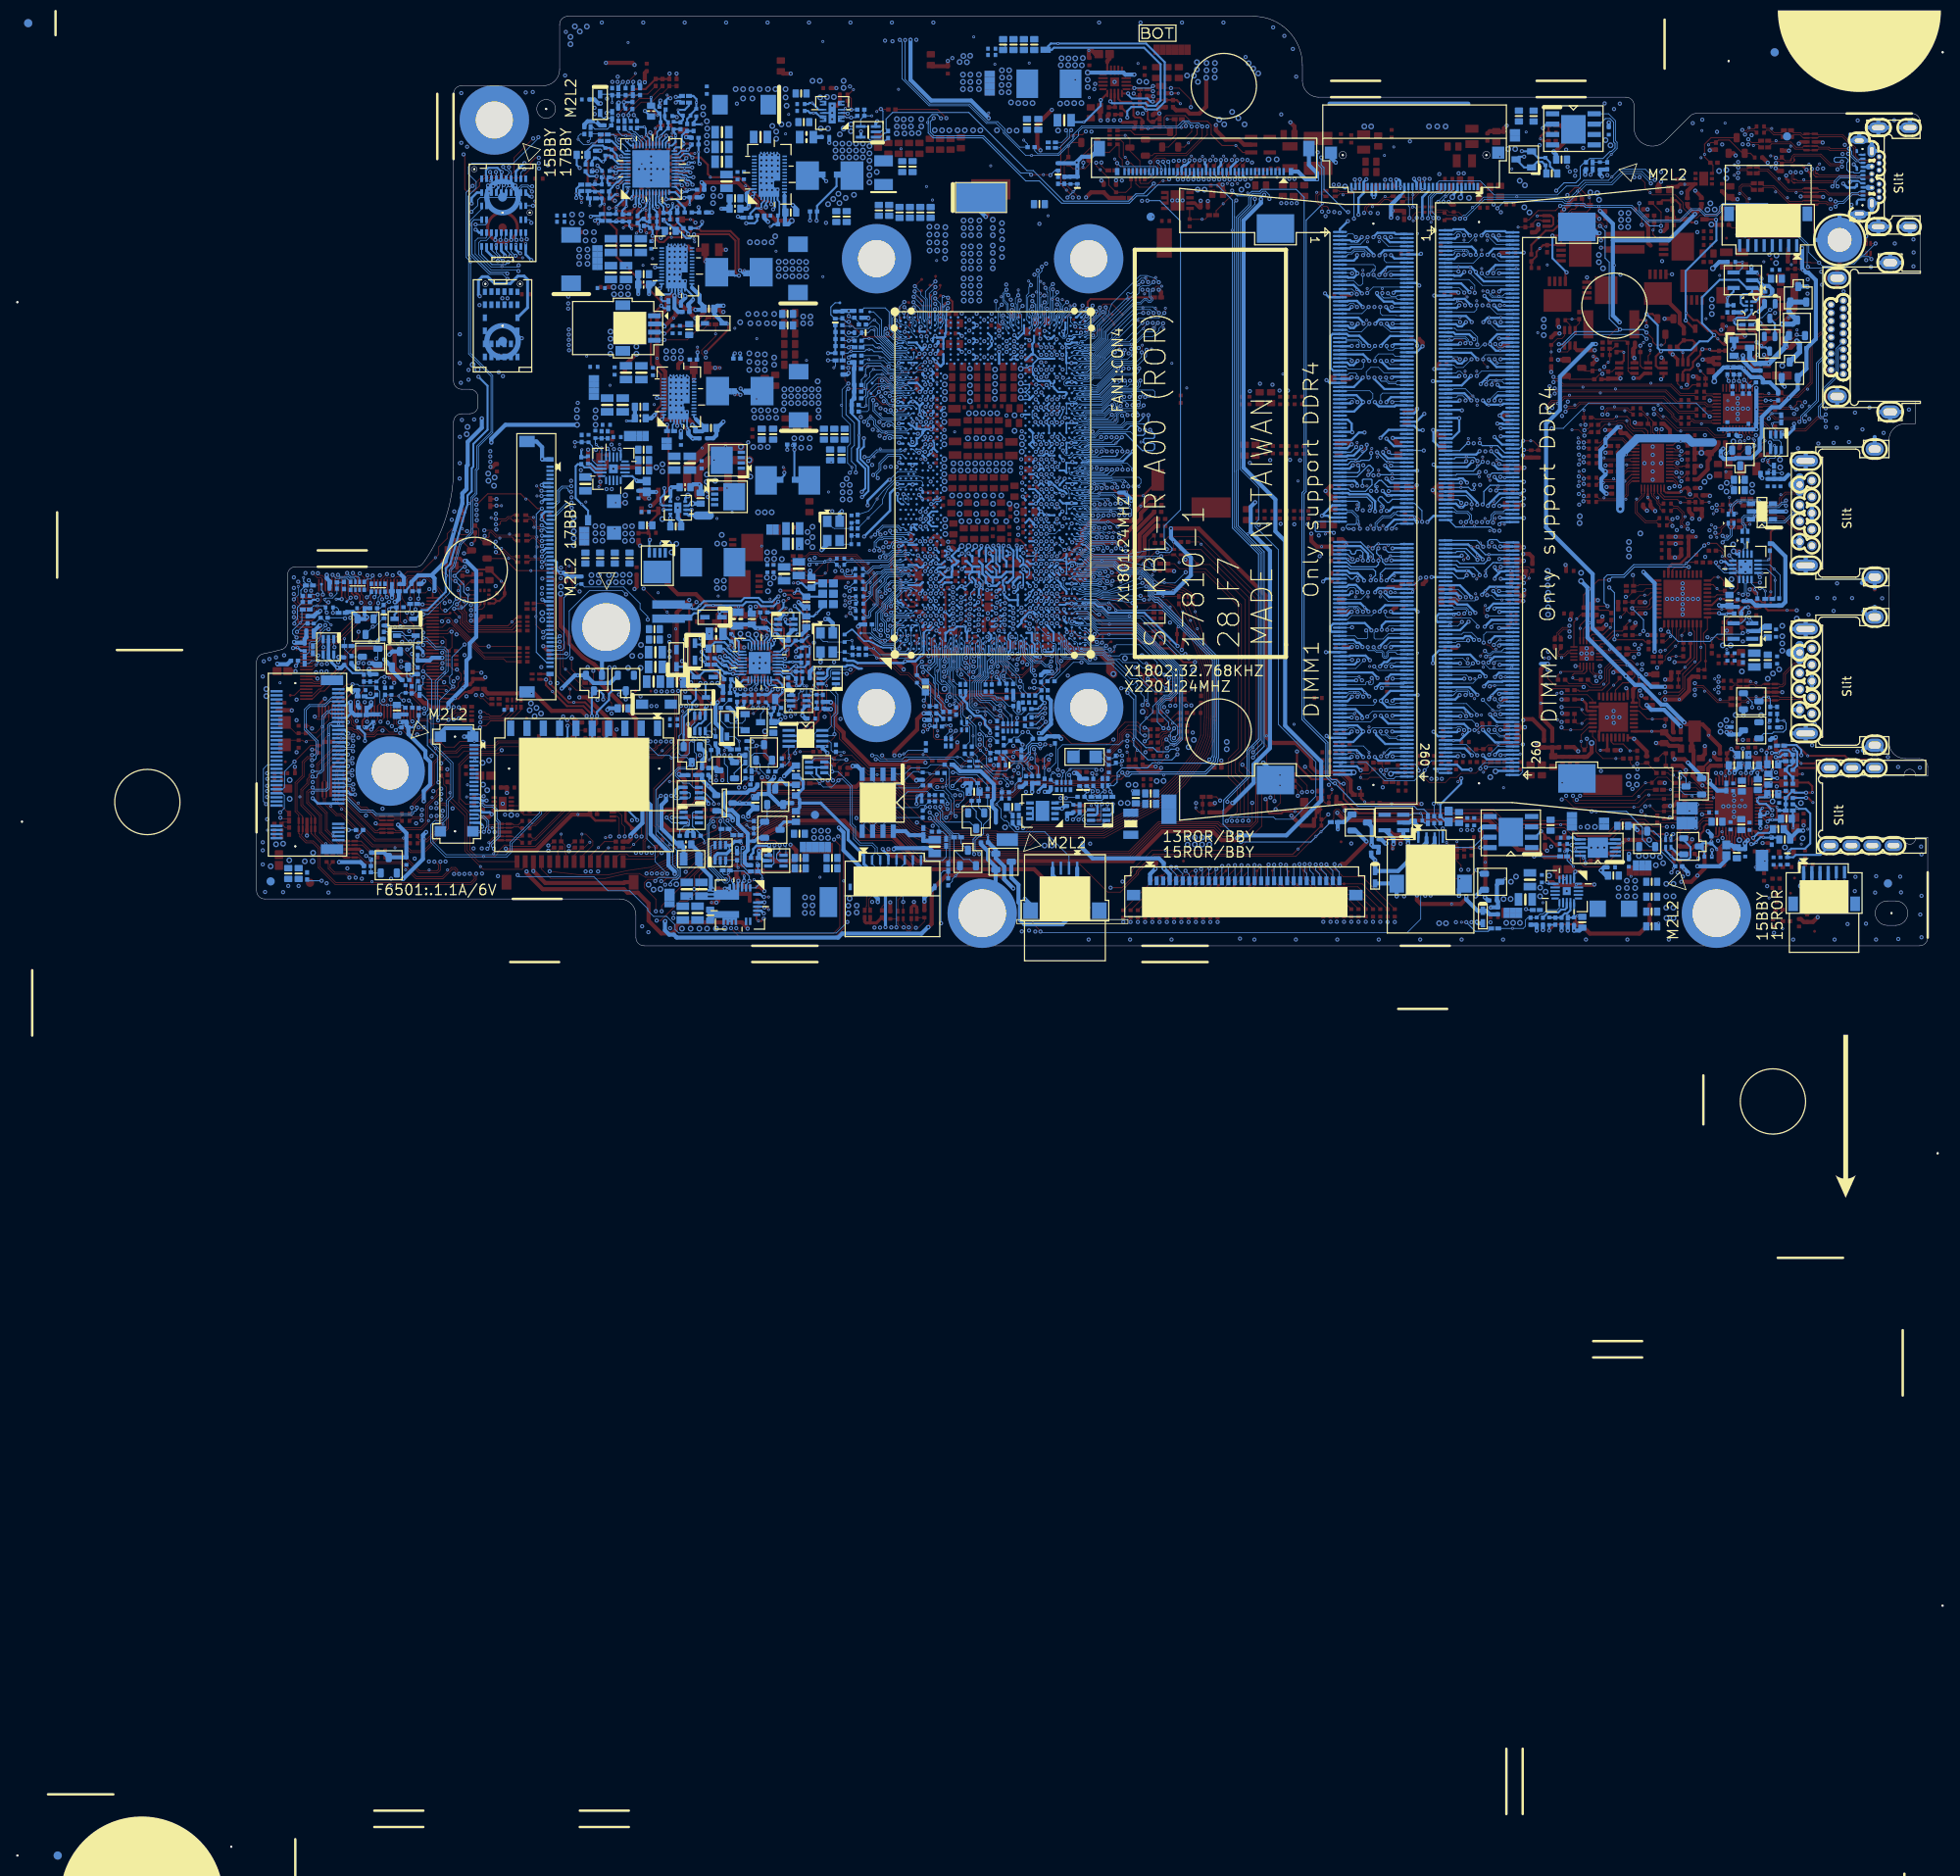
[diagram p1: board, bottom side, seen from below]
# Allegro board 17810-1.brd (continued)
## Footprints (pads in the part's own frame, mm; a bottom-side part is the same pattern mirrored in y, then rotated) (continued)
C402H22
  custom 0.114x0.114 smd: 1(0,0.457) 2(0,-0.457)
C402H24
  custom 0.114x0.114 smd: 1(0,0.457) 2(0,-0.457)
C603H32
  custom 0.197x0.197 smd: 1(0,0.66) 2(0,-0.66)
C603H35
  custom 0.197x0.197 smd: 1(0,0.66) 2(0,-0.66)
C603H36
  custom 0.197x0.197 smd: 1(0,0.66) 2(0,-0.66)
C603H38
  custom 0.197x0.197 smd: 1(0,0.66) 2(0,-0.66)
C603H40
  custom 0.197x0.197 smd: 1(0,0.66) 2(0,-0.66)
C805H54
  rect 1.549x0.94 smd: 1(0,0.838) 2(0,-0.838)
C805H56
  rect 1.549x0.94 smd: 1(0,0.838) 2(0,-0.838)
C805H58
  rect 1.549x0.94 smd: 1(0,0.838) 2(0,-0.838)
CON2O-U
  custom 0.159x0.159 smd: 1(0,0.254) 2(0,-0.254)
CT3528H79
  rect 2.286x1.372 smd: 1(0,1.448) 2(0,-1.448)
CT7343H83
  rect 2.413x1.905 smd: 1(0,2.959) 2(0,-2.959)
D1006-0305AK-UH22
  rect 0.61x0.432 smd: A(0,0.34) K(0,-0.34)
D1608AK-UH28
  rect 0.559x0.711 smd: A(0,0.889) K(0,-0.889)
D4724AKH44
  rect 2.007x1.549 smd: A(0,2.221) K(0,-2.221)
DFN6F2-G1711-UH32
  rect 0.406x0.508 smd: 1(0.65,1.13) 2(0,1.13) 3(-0.65,1.13) 4(-0.65,-1.13) 5(0,-1.13) 6(0.65,-1.13)
  rect 1.702x1.092 smd: 7(0,0)
DFN6G1820-G1511-UH24
  rect 0.305x0.508 smd: 1(0.5,1.07) 2(0,1.07) 3(-0.5,1.07) 4(-0.5,-1.07) 5(0,-1.07) 6(0.5,-1.07)
  rect 1.499x1.092 smd: 7(0,0)
DFN8F3-G2517H32
  rect 0.406x0.94 smd: 1(0.975,1.538) 2(0.325,1.538) 3(-0.325,1.538) 4(-0.975,1.538) 5(-0.975,-1.538)
  rect 0.025x0.025 smd: 6(-0.325,-1.538) 8(0.975,-1.538)
  custom 0.235x0.235 smd: 7(0.325,-1.538)
  rect 2.489x1.676 smd: 9(0,0)
DFN8G2-G1710-U1H32
  rect 0.305x0.686 smd: 1(0.75,1.106) 2(0.25,1.106) 3(-0.25,1.106) 4(-0.75,1.106) 5(-0.75,-1.106) 6(-0.25,-1.106) 7(0.25,-1.106) 8(0.75,-1.106)
  rect 1.702x0.94 smd: 9(0,0)
DFN10G2510H22
  rect 0.305x0.787 smd: 1(1,0.494) 5(-1,0.494) 6(-1,-0.494) 10(1,-0.494)
  rect 0.254x0.787 smd: 2(0.521,0.494) 4(-0.521,0.494) 7(-0.521,-0.494) 9(0.521,-0.494)
  rect 0.025x0.025 smd: 3(0,0.494)
  rect 0.406x1.753 smd: 8(0,-0.494)
DFN10G2510H26
  rect 0.305x0.787 smd: 1(1,0.494) 5(-1,0.494) 6(-1,-0.494) 10(1,-0.494)
  rect 0.254x0.787 smd: 2(0.521,0.494) 4(-0.521,0.494) 7(-0.521,-0.494) 9(0.521,-0.494)
  rect 0.025x0.025 smd: 3(0,0.494)
  rect 0.406x1.753 smd: 8(0,-0.494)
FL10F032HA2R3000
  round 0.254 hole 0.914 unplated: (-8.8,0) (8.8,0)
  rect 0.305x0.889 smd: 1(-7.75,3.85) 2(-7.25,3.85) 3(-6.75,3.85) 4(-6.25,3.85) 5(-5.75,3.85) 6(-5.25,3.85) 7(-4.75,3.85) 8(-4.25,3.85) 9(-3.75,3.85) 10(-3.25,3.85) 11(-2.75,3.85) 12(-2.25,3.85) 13(-1.75,3.85) 14(-1.25,3.85) 15(-0.75,3.85) 16(-0.25,3.85) 17(0.25,3.85) 18(0.75,3.85) 19(1.25,3.85) 20(1.75,3.85) 21(2.25,3.85) 22(2.75,3.85) 23(3.25,3.85) 24(3.75,3.85) 25(4.25,3.85) 26(4.75,3.85) 27(5.25,3.85) 28(5.75,3.85) 29(6.25,3.85) 30(6.75,3.85) 31(7.25,3.85) 32(7.75,3.85)
  rect 1.499x1.499 smd: 33(-10.25,-0.3) 34(10.25,-0.3)
GAP-CLOSE-PWR
  rect 0.66x0.762 smd: 1(-0.305,0) 2(0.305,0)
GAP-CLOSE-PWR-3
  rect 0.66x0.762 smd: 1(-0.305,0) 2(0.305,0)
GS12201-1011-9H
  round 0.254 hole 0.965 unplated: (-5.8,0) (5.8,0)
  rect 0.305x1.143 smd: 1(4.75,-2.325) 2(4.25,-2.325) 3(3.75,-2.325) 4(3.25,-2.325) 5(2.75,-2.325) 6(2.25,-2.325) 7(1.75,-2.325) 8(1.25,-2.325) 9(0.75,-2.325) 10(0.25,-2.325) 11(-0.25,-2.325) 12(-0.75,-2.325) 13(-1.25,-2.325) 14(-1.75,-2.325) 15(-2.25,-2.325) 16(-2.75,-2.325) 17(-3.25,-2.325) 18(-3.75,-2.325) 19(-4.25,-2.325) 20(-4.75,-2.325)
  rect 1.295x1.397 smd: 21(5.8,1.8) 22(5.8,-2.2) 23(-5.8,1.8) 24(-5.8,-2.2)
HOLE335R178
  round 8.509 hole 4.521: 1(0,0)
HOLE335R229
  round 8.509 hole 5.817: 1(0,0)
L402H22
  custom 0.127x0.127 smd: 1(0,0.432) 2(0,-0.432)
L402H24
  custom 0.127x0.127 smd: 1(0,0.432) 2(0,-0.432)
L4947-1015H119
  rect 1.753x1.676 smd: 1(0,1.944) 2(0,-1.944)
L4947-1115H119
  rect 2.007x2.007 smd: 1(0,1.922) 2(0,-1.922)
L7066-1830-UH119
  rect 3.505x2.667 smd: 1(0,2.653) 2(0,-2.653)
L7366-1930H158
  rect 3.505x2.819 smd: 1(0,2.729) 2(0,-2.729)
L125100-4P-4H24
  rect 0.635x0.432 smd: 1(-0.562,0.341) 2(0.562,0.341) 3(0.562,-0.341) 4(-0.562,-0.341)
L686647-127318H119
  rect 3.683x2.159 smd: 1(0,2.859) 2(0,-2.859)
LFDFN8G2-G1309H40
  rect 0.305x0.483 smd: 1(0.75,0.911) 2(0.25,0.911) 3(-0.25,0.911) 4(-0.75,0.911) 5(-0.75,-0.911) 6(-0.25,-0.911) 7(0.25,-0.911) 8(0.75,-0.911)
  rect 1.295x0.889 smd: 9(0,0)
LFQFN48J6-G4D6H40
  rect 0.203x0.686 smd: 1(2.2,2.857) 2(1.8,2.857) 3(1.4,2.857) 4(1,2.857) 5(0.6,2.857) 6(0.2,2.857) 7(-0.2,2.857) 8(-0.6,2.857) 9(-1,2.857) 10(-1.4,2.857) 11(-1.8,2.857) 12(-2.2,2.857) 25(-2.2,-2.857) 26(-1.8,-2.857) 27(-1.4,-2.857) 28(-1,-2.857) 29(-0.6,-2.857) 30(-0.2,-2.857) 31(0.2,-2.857) 32(0.6,-2.857) 33(1,-2.857) 34(1.4,-2.857) 35(1.8,-2.857) 36(2.2,-2.857)
  rect 0.686x0.203 smd: 13(-2.857,2.2) 14(-2.857,1.8) 15(-2.857,1.4) 16(-2.857,1) 17(-2.857,0.6) 18(-2.857,0.2) 19(-2.857,-0.2) 20(-2.857,-0.6) 21(-2.857,-1) 22(-2.857,-1.4) 23(-2.857,-1.8) 24(-2.857,-2.2) 37(2.857,-2.2) 38(2.857,-1.8) 39(2.857,-1.4) 40(2.857,-1) 41(2.857,-0.6) 42(2.857,-0.2) 43(2.857,0.2) 44(2.857,0.6) 45(2.857,1) 46(2.857,1.4) 47(2.857,1.8) 48(2.857,2.2)
  rect 4.597x4.597 smd: 49(0,0)
LGA12G2H40
  rect 0.381x0.381 smd: 1(0.809,0.809) 4(-0.809,0.809) 7(-0.809,-0.809) 10(0.809,-0.809)
  rect 0.305x0.432 smd: 2(0.25,0.784) 3(-0.25,0.784) 8(-0.25,-0.784) 9(0.25,-0.784)
  rect 0.432x0.305 smd: 5(-0.784,0.25) 6(-0.784,-0.25) 11(0.784,-0.25) 12(0.784,0.25)
MSOP8-1H44
  rect 0.356x1.524 smd: 1(-0.975,-2.055) 2(-0.325,-2.055) 3(0.325,-2.055) 4(0.975,-2.055) 5(0.975,2.055) 6(0.325,2.055) 7(-0.325,2.055) 8(-0.975,2.055)
MSOP10-G2D5H44
  rect 0.305x1.372 smd: 1(-1,-2.146) 2(-0.5,-2.146) 3(0,-2.146) 4(0.5,-2.146) 5(1,-2.146) 6(1,2.146) 7(0.5,2.146) 8(0,2.146) 9(-0.5,2.146) 10(-1,2.146)
  rect 2.489x2.489 smd: 11(0,0)
NTC-402H22-U
  custom 0.127x0.127 smd: 1(0,0.432) 2(0,-0.432)
NTC-402H24-U
  custom 0.127x0.127 smd: 1(0,0.432) 2(0,-0.432)
NTC-603H38
  rect 0.914x0.787 smd: 1(0,0.66) 2(0,-0.66)
OPLGA4-0913H22
  rect 0.305x0.61 smd: 1(0.25,0.599) 2(-0.25,0.599) 3(-0.25,-0.599) 4(0.25,-0.599)
OSC-3225-4P-4H30
  rect 1.397x1.067 smd: 1(-1.171,-0.756) 2(1.171,-0.756) 3(1.171,0.756) 4(-1.171,0.756)
POLYSW-2114H30
  rect 1.6x0.965 smd: 1(0,0.94) 2(0,-0.94)
POLYSW-4633-UH43
  rect 3.505x1.626 smd: 1(0,1.834) 2(0,-1.834)
PPAK-8P-2H45
  rect 0.406x1.168 smd: 1(-0.975,-2.351) 2(-0.325,-2.351) 3(0.325,-2.351) 4(0.975,-2.351)
  rect 3.404x2.769 smd: 5(0,0)
  rect 0.025x0.025 smd: 6(1.029,0.902) 7(0.013,0.902) 8(-0.991,0.902)
PPAK-8P-3232H36
  rect 0.406x0.914 smd: 1(-0.975,-2.396) 2(-0.325,-2.396) 3(0.325,-2.396) 4(0.975,-2.396)
  rect 3.353x2.692 smd: 5(0,0)
  rect 0.025x0.025 smd: 6(0.65,0.838) 7(0,0.838) 8(-0.65,0.838)
QFN16-G1D8-UH32
  rect 0.305x0.914 smd: 1(0.75,1.551) 2(0.25,1.551) 3(-0.25,1.551) 4(-0.75,1.551) 9(-0.75,-1.551) 10(-0.25,-1.551) 11(0.25,-1.551) 12(0.75,-1.551)
  rect 0.914x0.305 smd: 5(-1.551,0.75) 6(-1.551,0.25) 7(-1.551,-0.25) 8(-1.551,-0.75) 13(1.551,-0.75) 14(1.551,-0.25) 15(1.551,0.25) 16(1.551,0.75)
  rect 1.778x1.778 smd: 17(0,0)
QFN20J3-G1D8H32
  rect 0.203x0.889 smd: 1(0.8,1.564) 2(0.4,1.564) 3(0,1.564) 4(-0.4,1.564) 5(-0.8,1.564) 11(-0.8,-1.564) 12(-0.4,-1.564) 13(0,-1.564) 14(0.4,-1.564) 15(0.8,-1.564)
  rect 0.889x0.203 smd: 6(-1.564,0.8) 7(-1.564,0.4) 8(-1.564,0) 9(-1.564,-0.4) 10(-1.564,-0.8) 16(1.564,-0.8) 17(1.564,-0.4) 18(1.564,0) 19(1.564,0.4) 20(1.564,0.8)
  rect 1.803x1.803 smd: 21(0,0)
QFN20Z3-G1D1H36
  custom 0.064x0.064 smd: 1(0.9,1.424) 5(-0.9,1.424) 6(-1.424,0.9) 10(-1.424,-0.9) 11(-0.9,-1.424) 15(0.9,-1.424) 16(1.424,-0.9) 20(1.424,0.9)
  rect 0.254x1.168 smd: 2(0.45,1.424) 3(0,1.424) 4(-0.45,1.424) 12(-0.45,-1.424) 13(0,-1.424) 14(0.45,-1.424)
  rect 1.168x0.254 smd: 7(-1.424,0.45) 8(-1.424,0) 9(-1.424,-0.45) 17(1.424,-0.45) 18(1.424,0) 19(1.424,0.45)
  rect 1.092x1.092 smd: 21(0,0)
QFN20Z3-G1H36
  custom 0.064x0.064 smd: 1(0.9,1.424) 5(-0.9,1.424) 6(-1.424,0.9) 10(-1.424,-0.9) 11(-0.9,-1.424) 15(0.9,-1.424) 16(1.424,-0.9) 20(1.424,0.9)
  rect 0.254x1.168 smd: 2(0.45,1.424) 3(0,1.424) 4(-0.45,1.424) 12(-0.45,-1.424) 13(0,-1.424) 14(0.45,-1.424)
  rect 1.168x0.254 smd: 7(-1.424,0.45) 8(-1.424,0) 9(-1.424,-0.45) 17(1.424,-0.45) 18(1.424,0) 19(1.424,0.45)
  rect 0.991x0.991 smd: 21(0,0)
QFN22G4-G2PH42
  rect 0.305x0.914 smd: 1(1.25,2.051) 2(0.75,2.051) 3(0.25,2.051) 4(-0.25,2.051) 5(-0.75,2.051) 6(-1.25,2.051) 16(0.75,-2.051) 17(1.25,-2.051)
  custom 0.326x0.326 smd: 7(-2.051,1.25)
  rect 0.025x0.025 smd: 8(-2.051,0.75) 9(-2.051,0.25) 10(-2.051,-0.75) 13(-0.75,-2.051) 14(-0.25,-2.051) 15(0.25,-2.051)
  custom 0.232x0.232 smd: 11(-2.051,-1.25)
  custom 0.229x0.229 smd: 12(-1.25,-2.051)
  rect 0.914x0.305 smd: 18(2.051,-1.25) 19(2.051,-0.75) 20(2.051,-0.25) 21(2.051,0.25) 22(2.051,1.25)
QFN32G5-G3D6H32
  rect 0.305x0.914 smd: 1(1.75,2.551) 8(-1.75,2.551) 17(-1.75,-2.551) 24(1.75,-2.551)
  rect 0.305x0.991 smd: 2(1.25,2.513) 3(0.75,2.513) 4(0.25,2.513) 5(-0.25,2.513) 6(-0.75,2.513) 7(-1.25,2.513) 18(-1.25,-2.513) 19(-0.75,-2.513) 20(-0.25,-2.513) 21(0.25,-2.513) 22(0.75,-2.513) 23(1.25,-2.513)
  rect 0.914x0.305 smd: 9(-2.551,1.75) 16(-2.551,-1.75) 25(2.551,-1.75) 32(2.551,1.75)
  rect 0.991x0.305 smd: 10(-2.513,1.25) 11(-2.513,0.75) 12(-2.513,0.25) 13(-2.513,-0.25) 14(-2.513,-0.75) 15(-2.513,-1.25) 26(2.513,-1.25) 27(2.513,-0.75) 28(2.513,-0.25) 29(2.513,0.25) 30(2.513,0.75) 31(2.513,1.25)
  rect 3.607x3.607 smd: 33(0,0)
QFN32J4-G2D7H42
  custom 0.051x0.051 smd: 1(1.4,2.076) 8(-1.4,2.076) 9(-2.076,1.4) 16(-2.076,-1.4) 17(-1.4,-2.076) 24(1.4,-2.076) 25(2.076,-1.4) 32(2.076,1.4)
  rect 0.203x0.94 smd: 2(1,2.038) 3(0.6,2.038) 4(0.2,2.038) 5(-0.2,2.038) 6(-0.6,2.038) 7(-1,2.038) 18(-1,-2.038) 19(-0.6,-2.038) 20(-0.2,-2.038) 21(0.2,-2.038) 22(0.6,-2.038) 23(1,-2.038)
  rect 0.94x0.203 smd: 10(-2.038,1) 11(-2.038,0.6) 12(-2.038,0.2) 13(-2.038,-0.2) 14(-2.038,-0.6) 15(-2.038,-1) 26(2.038,-1) 27(2.038,-0.6) 28(2.038,-0.2) 29(2.038,0.2) 30(2.038,0.6) 31(2.038,1)
  rect 2.692x2.692 smd: 33(0,0)
QFN36J4060-G2554H48
  rect 0.203x0.559 smd: 1(1,2.873) 2(0.6,2.873) 3(0.2,2.873) 4(-0.2,2.873) 5(-0.6,2.873) 6(-1,2.873)
  rect 0.61x0.203 smd: 7(-1.848,2.2) 8(-1.848,1.8) 9(-1.848,1.4) 10(-1.848,1) 25(1.848,-2.2) 26(1.848,-1.8) 27(1.848,-1.4) 28(1.848,-1) 29(1.848,-0.6) 30(1.848,-0.2) 31(1.848,0.2) 32(1.848,0.6) 33(1.848,1) 34(1.848,1.4) 35(1.848,1.8) 36(1.848,2.2)
  rect 0.559x0.203 smd: 11(-1.848,0.6) 12(-1.848,0.2) 13(-1.848,-0.2) 14(-1.848,-0.6) 15(-1.848,-1) 16(-1.848,-1.4) 17(-1.848,-1.8) 18(-1.848,-2.2)
  rect 0.025x0.025 smd: 19(-1,-2.848) 20(-0.6,-2.848) 21(-0.2,-2.848) 22(0.2,-2.848) 23(0.6,-2.848) 24(1,-2.848)
  custom 0.665x0.665 smd: 37(0,0)
QFN40G6-G4D7H24
  rect 0.305x0.914 smd: 1(2.25,3.038) 10(-2.25,3.038) 21(-2.25,-3.038) 30(2.25,-3.038)
  rect 0.305x0.94 smd: 2(1.75,3.038) 3(1.25,3.038) 4(0.75,3.038) 5(0.25,3.038) 6(-0.25,3.038) 7(-0.75,3.038) 8(-1.25,3.038) 9(-1.75,3.038) 22(-1.75,-3.038) 23(-1.25,-3.038) 24(-0.75,-3.038) 25(-0.25,-3.038) 26(0.25,-3.038) 27(0.75,-3.038) 28(1.25,-3.038) 29(1.75,-3.038)
  rect 0.914x0.305 smd: 11(-3.038,2.25) 20(-3.038,-2.25) 31(3.038,-2.25) 40(3.038,2.25)
  rect 0.94x0.305 smd: 12(-3.038,1.75) 13(-3.038,1.25) 14(-3.038,0.75) 15(-3.038,0.25) 16(-3.038,-0.25) 17(-3.038,-0.75) 18(-3.038,-1.25) 19(-3.038,-1.75) 32(3.038,-1.75) 33(3.038,-1.25) 34(3.038,-0.75) 35(3.038,-0.25) 36(3.038,0.25) 37(3.038,0.75) 38(3.038,1.25) 39(3.038,1.75)
  rect 4.699x4.699 smd: 41(0,0)
QFN40J5-G3D65H32
  rect 0.203x0.94 smd: 1(1.8,2.538) 10(-1.8,2.538) 21(-1.8,-2.538) 30(1.8,-2.538)
  rect 0.203x0.965 smd: 2(1.4,2.526) 3(1,2.526) 4(0.6,2.526) 5(0.2,2.526) 6(-0.2,2.526) 7(-0.6,2.526) 8(-1,2.526) 9(-1.4,2.526) 22(-1.4,-2.526) 23(-1,-2.526) 24(-0.6,-2.526) 25(-0.2,-2.526) 26(0.2,-2.526) 27(0.6,-2.526) 28(1,-2.526) 29(1.4,-2.526)
  rect 0.94x0.203 smd: 11(-2.538,1.8) 20(-2.538,-1.8) 31(2.538,-1.8) 40(2.538,1.8)
  rect 0.965x0.203 smd: 12(-2.526,1.4) 13(-2.526,1) 14(-2.526,0.6) 15(-2.526,0.2) 16(-2.526,-0.2) 17(-2.526,-0.6) 18(-2.526,-1) 19(-2.526,-1.4) 32(2.526,-1.4) 33(2.526,-1) 34(2.526,-0.6) 35(2.526,-0.2) 36(2.526,0.2) 37(2.526,0.6) 38(2.526,1) 39(2.526,1.4)
  rect 3.658x3.658 smd: 41(0,0)
QFN40J4060-G2848H32
  rect 0.203x0.889 smd: 1(1.4,3.063) 2(1,3.063) 3(0.6,3.063) 4(0.2,3.063) 5(-0.2,3.063) 6(-0.6,3.063) 7(-1,3.063) 8(-1.4,3.063) 21(-1.4,-3.063) 22(-1,-3.063) 23(-0.6,-3.063) 24(-0.2,-3.063) 25(0.2,-3.063) 26(0.6,-3.063) 27(1,-3.063) 28(1.4,-3.063)
  rect 0.889x0.203 smd: 9(-2.063,2.2) 10(-2.063,1.8) 11(-2.063,1.4) 12(-2.063,1) 13(-2.063,0.6) 14(-2.063,0.2) 15(-2.063,-0.2) 16(-2.063,-0.6) 17(-2.063,-1) 18(-2.063,-1.4) 19(-2.063,-1.8) 20(-2.063,-2.2) 29(2.063,-2.2) 30(2.063,-1.8) 31(2.063,-1.4) 32(2.063,-1) 33(2.063,-0.6) 34(2.063,-0.2) 35(2.063,0.2) 36(2.063,0.6) 37(2.063,1) 38(2.063,1.4) 39(2.063,1.8) 40(2.063,2.2)
  rect 2.794x4.801 smd: 41(0,0)
QFN48J6-G465H40
  rect 0.203x0.965 smd: 1(2.2,3.025) 2(1.8,3.025) 3(1.4,3.025) 4(1,3.025) 5(0.6,3.025) 6(0.2,3.025) 7(-0.2,3.025) 8(-0.6,3.025) 9(-1,3.025) 10(-1.4,3.025) 11(-1.8,3.025) 12(-2.2,3.025) 25(-2.2,-3.025) 26(-1.8,-3.025) 27(-1.4,-3.025) 28(-1,-3.025) 29(-0.6,-3.025) 30(-0.2,-3.025) 31(0.2,-3.025) 32(0.6,-3.025) 33(1,-3.025) 34(1.4,-3.025) 35(1.8,-3.025) 36(2.2,-3.025)
  rect 0.965x0.203 smd: 13(-3.025,2.2) 14(-3.025,1.8) 15(-3.025,1.4) 16(-3.025,1) 17(-3.025,0.6) 18(-3.025,0.2) 19(-3.025,-0.2) 20(-3.025,-0.6) 21(-3.025,-1) 22(-3.025,-1.4) 23(-3.025,-1.8) 24(-3.025,-2.2) 37(3.025,-2.2) 38(3.025,-1.8) 39(3.025,-1.4) 40(3.025,-1) 41(3.025,-0.6) 42(3.025,-0.2) 43(3.025,0.2) 44(3.025,0.6) 45(3.025,1) 46(3.025,1.4) 47(3.025,1.8) 48(3.025,2.2)
  rect 4.648x4.648 smd: 49(0,0)
R402H14
  custom 0.127x0.127 smd: 1(0,0.432) 2(0,-0.432)
R402H15
  custom 0.127x0.127 smd: 1(0,0.432) 2(0,-0.432)
R402H16
  custom 0.127x0.127 smd: 1(0,0.432) 2(0,-0.432)
R603H22
  custom 0.197x0.197 smd: 1(0,0.66) 2(0,-0.66)
R805H20
  rect 1.549x0.94 smd: 1(0,0.838) 2(0,-0.838)
R805H24
  rect 1.549x0.94 smd: 1(0,0.838) 2(0,-0.838)
R1206H26
  rect 1.854x1.016 smd: 1(0,1.346) 2(0,-1.346)
R2512H28
  rect 3.454x1.219 smd: 1(0,2.819) 2(0,-2.819)
R3720H40
  rect 4.013x1.041 smd: 1(0,0.867) 2(0,-0.867)
SC70-2D2-312H44
  custom 0.152x0.152 smd: 1(-0.65,-0.902) 2(0.65,-0.902) 3(0,0.902)
SC70-5-1H44
  rect 0.356x1.219 smd: 1(-0.65,-0.922) 2(0,-0.922) 3(0.65,-0.922) 4(0.65,0.921) 5(-0.65,0.921)
SKT-HDMI23-188137-4
  oval 0.813x0.914 hole 0.559: 1(-4.5,5.75) 2(-4,7.25) 3(-3.5,5.75) 4(-3,7.25) 5(-2.5,5.75) 6(-2,7.25) 7(-1.5,5.75) 8(-1,7.25) 9(-0.5,5.75) 10(0,7.25) 11(0.5,5.75) 12(1,7.25) 13(1.5,5.75) 14(2,7.25) 15(2.5,5.75) 16(3,7.25) 17(3.5,5.75) 18(4,7.25) 19(4.5,5.75)
  oval 1.626x2.413 hole 0.914x1.702: 20(-9.15,0) 21(-7.25,6.5) 22(9.15,0) 23(7.25,6.5)
SKT-USB13-160162-2
  round 1.168 hole 0.813: 1(3.5,9.2) 2(1,9.2) 3(-1,9.2) 4(-3.5,9.2) 5(-4,7.7) 6(-2,7.7) 7(0,7.7) 8(2,7.7) 9(4,7.7)
  oval 1.422x2.997 hole 0.711x2.286: 10(6.4,8.45) 11(-6.4,8.45)
  oval 1.626x2.235 hole 0.914x1.524: 12(7.85,0) 13(-7.85,0)
SKT-USB34-124103-U
  round 0.254 hole 0.762 unplated: (-3.45,5.8) (3.45,5.8)
  oval 1.321x2.134 hole 0.61x1.6: 13(-6.075,0) 22(6.075,0)
  oval 1.321x2.311 hole 0.61x1.6: 14(-6.075,3.865) 21(6.075,3.865)
  oval 1.041x1.829 hole 0.508x1.118: 15(-4.475,6.2) 20(4.475,6.2)
  custom 0.076x0.076 smd: 16(-3.2,6.49) 19(3.2,6.49) A1(-2.75,5.74) A12(2.75,5.74)
  rect 0.508x0.305 smd: 17(-1,6.49) 18(1,6.49)
  rect 0.305x0.61 smd: A2(-2.25,5.74) A3(-1.75,5.74) A4(-1.25,5.74) A5(-0.75,5.74) A6(-0.25,5.74) A7(0.25,5.74) A8(0.75,5.74) A9(1.25,5.74) A10(1.75,5.74) A11(2.25,5.74)
  oval 1.626x0.991 hole 1.016x0.508: B1(3.2,4.665) B12(-3.2,4.665)
  round 0.66 hole 0.406: B2(2.5,3.765) B3(1.7,3.765) B4(1.3,4.665) B5(0.85,3.765) B6(0.4,4.665) B7(-0.4,4.665) B8(-0.85,3.765) B9(-1.3,4.665) B10(-1.7,3.765) B11(-2.5,3.765)
SLP2510P8-1H22
  rect 0.305x0.762 smd: 1(-1,-0.5) 5(1,-0.5) 6(1,0.5) 10(-1,0.5)
  rect 0.203x0.762 smd: 2(-0.5,-0.5) 4(0.5,-0.5) 7(0.5,0.5) 9(-0.5,0.5)
  rect 0.406x0.762 smd: 3(0,-0.5) 8(0,0.5)
SMD49-3215-0713H36
  rect 1.549x1.549 smd: 1(0,1.371) 2(0,-1.371)
SMD-ARES4H18
  rect 0.356x0.61 smd: 1(-0.325,-0.457) 2(0.325,-0.457) 3(0.325,0.457) 4(-0.325,0.457)
SMD-ARES4H20
  rect 0.356x0.61 smd: 1(-0.325,-0.457) 2(0.325,-0.457) 3(0.325,0.457) 4(-0.325,0.457)
SOD123AK-2H43
  rect 1.143x1.499 smd: A(0,1.758) K(0,-1.758)
SOD323-2513AKH36
  rect 0.559x1.168 smd: A(0,1.05) K(0,-1.05)
SOD323AKH38
  rect 0.559x1.016 smd: A(0,1.143) K(0,-1.143)
SOD323AKH44
  rect 0.559x1.016 smd: A(0,1.143) K(0,-1.143)
SOD882-10D6-1H20
  custom 0.114x0.114 smd: 1(0,0.445) 2(0,-0.445)
SOD923-10D6AKH18
  rect 0.457x0.762 smd: A(0,0.527) K(0,-0.527)
SOD-523-2H26
  rect 0.559x1.016 smd: 1(0,0.762) 2(0,-0.762)
SOIC8-1H86
  rect 0.635x1.651 smd: 1(-1.905,-3.493) 2(-0.635,-3.493) 3(0.635,-3.493) 4(1.905,-3.493) 5(1.905,3.493) 6(0.635,3.493) 7(-0.635,3.493) 8(-1.905,3.493)
SOIC8-G3530H63
  rect 0.635x1.651 smd: 1(-1.905,-2.555) 2(-0.635,-2.555) 3(0.635,-2.555) 4(1.905,-2.555) 5(1.905,2.555) 6(0.635,2.555) 7(-0.635,2.555) 8(-1.905,2.555)
  rect 3.505x2.997 smd: 9(0,0)
SON14J3020-G2610H34
  rect 0.025x0.025 smd: 1(1.2,1.105) 6(-0.8,1.105) 9(-0.8,-1.105) 14(1.2,-1.105)
  custom 0.151x0.151 smd: 2(0.8,1.105) 7(-1.2,1.105) 8(-1.2,-1.105) 13(0.8,-1.105)
  rect 0.203x0.813 smd: 3(0.4,1.105) 4(0,1.105) 5(-0.4,1.105) 10(-0.4,-1.105) 11(0,-1.105) 12(0.4,-1.105)
  rect 2.591x0.889 smd: 15(0,0)
SOT23-2D4-312H44
  custom 0.191x0.191 smd: 1(-0.984,-0.953) 2(0.984,-0.953) 3(0,0.953)
SOT23-2D4-312H48
  custom 0.191x0.191 smd: 1(-0.984,-0.953) 2(0.984,-0.953) 3(0,0.953)
SOT23-2D4-312H60
  custom 0.191x0.191 smd: 1(-0.984,-0.953) 2(0.984,-0.953) 3(0,0.953)
SOT23CBE2D4H44
  custom 0.191x0.191 smd: B(-0.984,-0.953) C(0,0.953) E(0.984,-0.953)
SOT23DGS2D4H44
  custom 0.191x0.191 smd: D(0,0.953) G(-0.984,-0.953) S(0.984,-0.953)
SOT23DGS2D4H48
  custom 0.191x0.191 smd: D(0,0.953) G(-0.984,-0.953) S(0.984,-0.953)
SOT323CBE2D2H40
  custom 0.152x0.152 smd: B(-0.65,-0.902) C(0,0.902) E(0.65,-0.902)
SOT723DGS1D2H22
  custom 0.146x0.146 smd: D(0,0.61)
  custom 0.121x0.121 smd: G(-0.4,-0.61) S(0.4,-0.61)
SOT883-1D0-321H20
  rect 0.203x0.305 smd: 1(0.203,-0.35) 2(-0.203,-0.35)
  rect 0.559x0.305 smd: 3(0,0.35)
SOT-6H58
  rect 0.584x1.016 smd: 1(-0.953,-1.346) 2(0,-1.346) 3(0.953,-1.346) 4(0.953,1.346) 5(0,1.346) 6(-0.953,1.346)
SOT-23-5H51
  rect 0.508x1.524 smd: 1(-0.95,-1.143) 2(0,-1.143) 3(0.95,-1.143) 4(0.95,1.143) 5(-0.95,1.143)
SOT-23-5H52
  rect 0.508x1.524 smd: 1(-0.95,-1.143) 2(0,-1.143) 3(0.95,-1.143) 4(0.95,1.143) 5(-0.95,1.143)
SOT-23-5H56
  rect 0.508x1.524 smd: 1(-0.95,-1.143) 2(0,-1.143) 3(0.95,-1.143) 4(0.95,1.143) 5(-0.95,1.143)
SOT-23-9H44
  custom 0.178x0.178 smd: 1(-0.95,-0.999) 2(0.95,-0.999) 3(0,0.999)
SOT-23-10H44
  rect 0.762x1.143 smd: 1(-0.984,-0.953) 2(0.984,-0.953) 3(0,0.953)
SOT-363H44
  rect 0.406x1.016 smd: 1(-0.65,-0.94) 2(0,-0.94) 3(0.65,-0.94) 4(0.65,0.94) 5(0,0.94) 6(-0.65,0.94)
SPR5128H111
  rect 4.801x2.489 smd: 1(-1.397,0)
SPR6438H83
  rect 6.096x3.505 smd: 1(-1.6,0)
STF217R115H101
  round 5.512 hole 2.921: 1(0,0)
STFSR158R113H62
  round 0.254 hole 2.87 unplated: (0,0)
  custom 1.003x1.003 smd: 1(0,-1.822)
TPAD14-OP
  round 0.356 smd: 1(0,0)
TQFP128-2H48
  rect 0.203x1.524 smd: 1(6.2,7.747) 2(5.8,7.747) 3(5.4,7.747) 4(5,7.747) 5(4.6,7.747) 6(4.2,7.747) 7(3.8,7.747) 8(3.4,7.747) 9(3,7.747) 10(2.6,7.747) 11(2.2,7.747) 12(1.8,7.747) 13(1.4,7.747) 14(0.999,7.747) 15(0.599,7.747) 16(0.199,7.747) 17(-0.199,7.747) 18(-0.599,7.747) 19(-0.999,7.747) 20(-1.4,7.747) 21(-1.8,7.747) 22(-2.2,7.747) 23(-2.6,7.747) 24(-3,7.747) 25(-3.4,7.747) 26(-3.8,7.747) 27(-4.2,7.747) 28(-4.6,7.747) 29(-5,7.747) 30(-5.4,7.747) 31(-5.8,7.747) 32(-6.2,7.747) 65(-6.2,-7.747) 66(-5.8,-7.747) 67(-5.4,-7.747) 68(-5,-7.747) 69(-4.6,-7.747) 70(-4.2,-7.747) 71(-3.8,-7.747) 72(-3.4,-7.747) 73(-3,-7.747) 74(-2.6,-7.747) 75(-2.2,-7.747) 76(-1.8,-7.747) 77(-1.4,-7.747) 78(-0.999,-7.747) 79(-0.599,-7.747) 80(-0.199,-7.747) 81(0.199,-7.747) 82(0.599,-7.747) 83(0.999,-7.747) 84(1.4,-7.747) 85(1.8,-7.747) 86(2.2,-7.747) 87(2.6,-7.747) 88(3,-7.747) 89(3.4,-7.747) 90(3.8,-7.747) 91(4.2,-7.747) 92(4.6,-7.747) 93(5,-7.747) 94(5.4,-7.747) 95(5.8,-7.747) 96(6.2,-7.747)
  rect 1.524x0.203 smd: 33(-7.747,6.2) 34(-7.747,5.8) 35(-7.747,5.4) 36(-7.747,5) 37(-7.747,4.6) 38(-7.747,4.2) 39(-7.747,3.8) 40(-7.747,3.4) 41(-7.747,3) 42(-7.747,2.6) 43(-7.747,2.2) 44(-7.747,1.8) 45(-7.747,1.4) 46(-7.747,0.999) 47(-7.747,0.599) 48(-7.747,0.199) 49(-7.747,-0.199) 50(-7.747,-0.599) 51(-7.747,-0.999) 52(-7.747,-1.4) 53(-7.747,-1.8) 54(-7.747,-2.2) 55(-7.747,-2.6) 56(-7.747,-3) 57(-7.747,-3.4) 58(-7.747,-3.8) 59(-7.747,-4.2) 60(-7.747,-4.6) 61(-7.747,-5) 62(-7.747,-5.4) 63(-7.747,-5.8) 64(-7.747,-6.2) 97(7.747,-6.2) 98(7.747,-5.8) 99(7.747,-5.4) 100(7.747,-5) 101(7.747,-4.6) 102(7.747,-4.2) 103(7.747,-3.8) 104(7.747,-3.4) 105(7.747,-3) 106(7.747,-2.6) 107(7.747,-2.2) 108(7.747,-1.8) 109(7.747,-1.4) 110(7.747,-0.999) 111(7.747,-0.599) 112(7.747,-0.199) 113(7.747,0.199) 114(7.747,0.599) 115(7.747,0.999) 116(7.747,1.4) 117(7.747,1.8) 118(7.747,2.2) 119(7.747,2.6) 120(7.747,3) 121(7.747,3.4) 122(7.747,3.8) 123(7.747,4.2) 124(7.747,4.6) 125(7.747,5) 126(7.747,5.4) 127(7.747,5.8) 128(7.747,6.2)
unnamed#2
  round 0.254 hole 2.184 unplated: (0,0)
XBGCB5008
  round 0.254 hole 2.718 unplated: (0,0)
  round 0.254 hole 0.711 unplated: (5.143,-2.145) (5.143,2.105)
  rect 0.813x0.508 smd: A1(-3.805,2.165) A2(-3.805,1.365) A3(-3.805,0.565) A4(-3.805,-0.235) A5(-3.805,-1.035) A6(-3.805,-1.835) B1(-2.205,2.165) B2(-2.205,1.365) B3(-2.205,0.565) B4(-2.205,-0.235) B5(-2.205,-1.035) B6(-2.205,-1.835) C1(2.595,2.165) C2(2.595,1.365) C3(2.595,0.565) C4(2.595,-0.235) C5(2.595,-1.035) C6(2.595,-1.835) D2(4.195,1.365) D3(4.195,0.565) D4(4.195,-0.235) D5(4.195,-1.035) P1(-0.605,2.165) P2(0.995,2.165) P3(-0.605,-1.835) P4(0.995,-1.835)
  rect 0.762x0.508 smd: D1(4.169,2.165) D6(4.169,-1.835)
  custom 1.124x1.124 smd: N1(-1.905,0)
XBGCB5009-U2
  round 0.254 hole 0.711 unplated: (-5.325,-3.465) (0,3.34)
  round 0.254 hole 2.718 unplated: (0,0)
  rect 0.813x0.356 smd: A1(-4.15,2.845) A2(-4.15,2.245) A3(-4.15,1.645) A4(-4.15,1.045) A5(-4.15,0.445) A6(-4.15,-0.155) A7(-4.15,-0.755) A8(-4.15,-1.355) A9(-4.15,-1.955) A10(-4.15,-2.555) B1(-2.45,2.845) B2(-2.45,2.245) B3(-2.45,1.645) B4(-2.45,1.045) B5(-2.45,0.445) B6(-2.45,-0.155) B7(-2.45,-0.755) B8(-2.45,-1.355) B9(-2.45,-1.955) B10(-2.45,-2.555) C2(-0.82,2.245) C9(-0.82,-1.955) C10(-0.82,-2.555) D1(0.87,2.845) D2(0.87,2.245) D9(0.87,-1.955) D10(0.87,-2.555) E1(2.45,2.845) E2(2.45,2.245) E3(2.45,1.645) E4(2.45,1.045) E5(2.45,0.445) E6(2.45,-0.155) E7(2.45,-0.755) E8(2.45,-1.355) E9(2.45,-1.955) E10(2.45,-2.555) F1(4.15,2.845) F2(4.15,2.245) F3(4.15,1.645) F4(4.15,1.045) F5(4.15,0.445) F6(4.15,-0.155) F7(4.15,-0.755) F8(4.15,-1.355) F9(4.15,-1.955) F10(4.15,-2.555)
  rect 0.762x0.356 smd: C1(-0.846,2.845)
  custom 1.124x1.124 smd: N1(-1.905,0)
XSON6H24
  rect 0.305x0.381 smd: 1(0.5,0.31) 2(0,0.31) 3(-0.5,0.31) 4(-0.5,-0.31) 5(0,-0.31) 6(0.5,-0.31)

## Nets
1.8V_RUN_FB: PC5405.2 PR5403.2 PR5404.1 PU5401.2
3V5V_CT1: C4001.1 U4001.12
3V5V_CT2: C4002.1 U4001.10
3V5V_S0_ON: R4010.2 R4013.1 R4014.1 U4003.4
3V_5V_EN: C4009.1 D4001.1 PR4515.1 PR4516.1 R4006.1 R4009.1
3V_5V_POK: C1710.1 ED1705.1 PG4529.1 PG4531.1 PR5210.1 PR5406.1 R1718.2 R1728.2 R4033.1
3V_5V_POK#: Q1701.5 Q1701.6 R1726.1
3V_5V_POK_C: Q1701.2 R1727.2 R1728.1
5V_AUX_S5: PG4528.2 PR4510.2
5V_HDD: C6010.1 R6003.1 R6006.2 U6002.7 U6002.8
5V_HDD_SIP: C6002.2 C6004.1 HDD1.8 HDD1.9 HDD1.10 HDD1.11 R6003.2
5V_HDMI_R_S5: F5701.1 R5715.2 R5716.2
5V_HDMI_S5: C5713.1 F5701.2 HDMI1.18
5V_S0: C4005.1 C6009.1 D5701.3 EC8916.1 EC8917.1 F5501.1 F6501.1 GPU2.P4 R2612.1 R2702.1 R2703.2 R2704.1 R5507.1 R5716.1 R6006.1 R6501.1 R6510.2 U4001.13 U4001.14 U6002.1 U6002.2 U6002.4
5V_S0_ON: C4010.1 R4013.2 U4001.3
5V_S5: C3402.1 C3406.1 C3502.1 C3503.1 C3704.1 C3705.1 C3718.1 C3719.1 C4031.1 C4032.1 EC8914.1 EC8915.1 IOBD1.28 IOBD1.29 IOBD1.30 IOBD1.31 IOBD1.32 PC4707.1 PC4721.1 PC4807.1 PC5001.1 PC5202.1 PC5401.1 PC5410.1 PG4507.2 PG4508.2 PG4509.2 PG4510.2 PG4511.2 PG4512.2 PG4513.2 PG4514.2 PR4303.1 PR4657.1 PR4676.1 PR4702.2 PR4712.2 PR4803.2 PR5118.1 PU4701.3 PU4701.7 PU4701.36 PU4702.3 PU4702.7 PU4702.36 PU4801.7 PU4801.36 PU5001.4 PU5201.21 PU5401.6 PU5403.6 Q6401.E Q6402.E Q6505.E R3402.1 R3405.1 R3406.1 R3734.1 R5715.1 U3401.1 U3501.5 U3703.2 U4001.1 U4001.2 U4001.4 U4002.3 U4006.3
5V_STB: HDA27.47 R2725.2
5V_VCONN_EN: R3734.2 U3703.3
5V_VCONN_P1: R3706.1 R3737.1 U3703.5 U3703.6
5V_VCONN_P1_CCG4: R3737.2 U3701.8
+1.8VALW_EC: C2423.1 KBC24.54 R2462.1
+3V_1D8V_AVDD: C2715.1 HDA27.16 R2705.2 R2710.2 R2713.2
+3V_AVDD: C2716.1 C2717.1 C2719.1 HDA27.4 HDA27.12 R2722.1 R2728.2 R2731.2
+3VALW_EC: C2410.1 C2411.1 C2412.1 C2413.1 C2414.1 C2420.1 C2422.1 C2429.1 D4304.2 D4305.2 D4306.2 DB3.1 KBC24.5 KBC24.19 KBC24.22 KBC24.43 KBC24.65 KBC24.82 KBC24.103 KBC24.115 PR4438.1 PR4439.1 PR4445.1 Q2415.G Q2605.2 Q2605.5 R2414.2 R2415.2 R2424.2 R2443.1 R2446.2 R2450.2 R2473.2 R2480.2 R2608.1 R3707.1 R4032.1 RN2402.1(A) RN2402.2(A) RN2403.1(A) RN2403.2(A) RN2403.3(A) RN2403.4(A) RN2404.1(A) RN2404.2(A) RN2404.3(A) RN2404.4(A) RN2409.1(A) RN2409.2(A) RN2409.3(A) RN2409.4(A) RN2410.1(A) RN2410.2(A) RN2410.3(A) RN2410.4(A) RN2411.1(A) RN2411.2(A) RN2411.3(A) RN2411.4(A) RN2412.1(A) RN2412.2(A) RN2412.3(A) RN2412.4(A) RN2604.1(A) RN2604.2(A)
+5V_AVDD: C2710.1 C2711.1 HDA27.40 R2703.1
+5V_KB_BL: AFTP6529.1 C6501.1 F6501.2 KBBL1.1 R6501.2
+5V_PVDD: C2706.1 C2707.1 C2708.1 C2709.1 HDA27.41 HDA27.46 R2702.2 R2704.2
+V1.00A_SIP: C1112.1 C2101.1 C2104.1 C2116.1 C2121.1 CPU1.A10 CPU1.A14 CPU1.AB17 CPU1.AB19 CPU1.AB20 CPU1.AK20 CPU1.K17 CPU1.L1 CPU1.L21 CPU1.P18 CPU1.T1 CPU1.Y18 R1102.2 R1803.2 R2108.1 R2109.1 R2110.1 R2111.1
+V1.00U_CPU: C4012.1 R4036.1 R4038.1 U4006.6 U4006.7 U4006.8
+V1.8A: C2714.1 C2722.1 PG5405.2 PG5406.2 PG5407.2 Q2702.S R1104.1 R1607.1 R1739.1 R1818.2 R1820.1 R1821.1 R1915.2 R1916.2 R1918.2 R1920.2 R2462.2 R2726.1
+V1.8A_SIP: C1122.1 C2108.1 CPU1.AA1 CPU1.AF11 CPU1.AF16 CPU1.AH10 CPU1.AH11 CPU1.AH12 CPU1.AK15 R1104.2
+V3.3A_SIP: C1113.1 C1123.1 C2105.1 C2106.1 C2107.1 C2109.1 C2110.1 C2111.1 CPU1.AD15 CPU1.AG15 CPU1.AJ16 CPU1.AJ21 CPU1.AK17 CPU1.T16 CPU1.V19 CPU1.Y15 CPU1.Y16 R1103.2 R1701.1 R1731.1 R2101.1
+VCCAMPHYPLL_1P0: C2113.1 CPU1.K15 CPU1.L15 R2107.2
+VCCAPLL_1P0: C2114.1 CPU1.V15 R2108.2
+VCCCLK2: C2115.1 CPU1.K19 R2109.2
+VCCCLK4: C2119.1 CPU1.N20 R2110.2
+VCCCLK5: C2122.1 CPU1.L19 R2111.2
+VCCCOREG0: CPU1.K32 TP701.1
+VCCCOREG1: CPU1.AK32 TP707.1
+VCCDSW_1P0: C2103.1 CPU1.AL1
+VCCFUSEPRG: CPU1.G20 R703.1
+VCCGT: C1102.1 C1103.1 C1104.1 C1105.1 C1106.1 C1107.1 CPU1.A58 CPU1.A62 CPU1.A66 CPU1.AA63 CPU1.AA64 CPU1.AA66 CPU1.AA67 CPU1.AA69 CPU1.AA70 CPU1.AA71 CPU1.AC64 CPU1.AC65 CPU1.AC66 CPU1.AC67 CPU1.AC68 CPU1.AC69 CPU1.AC70 CPU1.AC71 CPU1.J53 CPU1.J55 CPU1.J56 CPU1.J58 CPU1.J60 CPU1.K53 CPU1.K55 CPU1.K56 CPU1.K58 CPU1.K60 CPU1.L62 CPU1.L63 CPU1.L64 CPU1.L65 CPU1.L66 CPU1.L67 CPU1.L68 CPU1.L69 CPU1.L70 CPU1.L71 CPU1.M62 CPU1.N63 CPU1.N64 CPU1.N66 CPU1.N67 CPU1.N69 CPU1.N70 CPU1.N71 CPU1.R63 CPU1.R64 CPU1.R65 CPU1.R66 CPU1.R67 CPU1.R68 CPU1.R69 CPU1.R70 CPU1.R71 CPU1.T62 CPU1.U65 CPU1.U68 CPU1.U71 CPU1.W63 CPU1.W64 CPU1.W65 CPU1.W66 CPU1.W67 CPU1.W68 CPU1.W69 CPU1.W70 CPU1.W71 CPU1.Y62 EC1005.1 EC1006.1 PC1001.1 PC1037.1 PC1038.1 PC1039.1 PC1040.1 PC1041.1 PC1042.1 PC1043.1 PC1044.1 PC1045.1 PC1046.1 PC1047.1 PC1048.1 PC1049.1 PC1050.1 PC1051.1 PC1052.1 PC1053.1 PC1054.1 PC1055.1 PC1056.1 PC1057.1 PC1058.1 PC1059.1 PC1060.1 PC1061.1 PC1062.1 PC1063.1 PC1064.1 PC1065.1 PC1066.1 PC1067.1 PC1068.1 PC1069.1 PC1070.1 PC1083.1 PC1085.1 PG4809.2 PL4801.2 PT4801.1 R706.2 R712.2 R721.1
+VCCIO: C1108.1 C1109.1 C1110.1 C1111.1 CPU1.AK28 CPU1.AK30 CPU1.AL30 CPU1.AL42 CPU1.AM28 CPU1.AM30 CPU1.AM42 PC1102.1 PC1103.1 PC1104.1 R801.1 R4045.2
+VCCIO_SIP: C4007.1 R4042.1 R4045.1 U4002.6 U4002.7 U4002.8
+VCCMPHYGTAON_1P0_LS_SIP: C1114.1 C1115.1 C1116.1 C1117.1 C1118.1 C1119.1 C1120.1 C1121.1 C1704.1 CPU1.AF20 CPU1.AF21 CPU1.N15 CPU1.N16 CPU1.N17 CPU1.N18 CPU1.P15 CPU1.P16 CPU1.T19 CPU1.T20 R1724.2 R2107.1
+VCCPAZIO: CPU1.AJ19 R2101.2 R2102.2
+VCCPDSW_3P3: CPU1.AD17 CPU1.AD18 CPU1.AJ17 R1707.1 R1711.2
+VCCPRIM_CORE: C2102.1 C2120.1 CPU1.AF18 CPU1.AF19 CPU1.V20 CPU1.V21 EC2101.1 PC1105.1 PC1106.1 R1101.2
+VCCPRTC_3P3: C2117.1 C2118.1 CPU1.AK19 CPU1.BB14 R2106.2
+VCCSA: CPU1.AK23 CPU1.AK25 CPU1.G23 CPU1.G25 CPU1.G27 CPU1.G28 CPU1.J22 CPU1.J23 CPU1.J27 CPU1.K23 CPU1.K25 CPU1.K27 CPU1.K28 CPU1.K30 EC1001.1 EC1007.1 PC1071.1 PC1072.1 PC1073.1 PC1074.1 PC1075.1 PC1076.1 PC1077.1 PC1078.1 PG5022.2 PL5001.2 R735.1
+VCCSFR: C720.1 C721.1 CPU1.K20 CPU1.K21 R4038.2
+VCCST_CPU: C716.1 CPU1.A18 PC4610.1 PR4621.1 PR4622.1 PR4623.1 PR4624.1 R419.1 R603.2 R723.1 R726.1 R727.1 R4036.2
+VCCSTG: C717.1 C4008.1 CPU1.A22 PR4669.1 R401.1 R408.2 R409.2 R416.2 R417.2 R421.2 R422.2 R423.2 R703.2 R4042.2
+VDDQ_CPU_CLK: C715.1 CPU1.AM40 R705.2
AV1_TP: CPU1.AV1 TP2307.1
AV71_TP: CPU1.AV71 TP2304.1
DVSS: HDA27.7 R2732.1
GND: AFTP225.1 AFTP2604.1 AFTP4306.1 AFTP4307.1 AFTP4308.1 BATT1.8 BATT1.9 BATT1.10 C715.2 C716.2 C717.2 C718.2 C719.2 C720.2 C721.2 C1101.2 C1102.2 C1103.2 C1104.2 C1105.2 C1106.2 C1107.2 C1108.2 C1109.2 C1110.2 C1111.2 C1112.2 C1113.2 C1114.2 C1115.2 C1116.2 C1117.2 C1118.2 C1119.2 C1120.2 C1121.2 C1122.2 C1123.2 C1124.2 C1125.2 C1126.2 C1127.2 C1202.2 C1203.2 C1204.2 C1205.2 C1206.2 C1207.2 C1208.2 C1209.2 C1210.2 C1211.2 C1212.2 C1213.2 C1214.2 C1215.2 C1216.2 C1217.2 C1218.2 C1219.2 C1220.2 C1221.2 C1223.2 C1224.2 C1225.2 C1226.2 C1227.2 C1228.2 C1229.2 C1230.2 C1231.2 C1232.2 C1301.2 C1303.2 C1304.2 C1305.2 C1306.2 C1307.2 C1308.2 C1309.2 C1310.2 C1311.2 C1312.2 C1313.2 C1314.2 C1315.2 C1316.2 C1317.2 C1318.2 C1319.2 C1320.2 C1321.2 C1322.2 C1324.2 C1325.2 C1326.2 C1327.2 C1328.2 C1329.2 C1330.2 C1331.2 C1701.2 C1704.2 C1710.2 C1711.2 C1801.1 C1802.1 C1803.2 C1804.2 C1805.2 C1806.2 C2101.2 C2102.2 C2103.2 C2104.2 C2105.2 C2106.2 C2107.2 C2108.2 C2109.2 C2110.2 C2111.2 C2112.2 C2113.2 C2114.2 C2115.2 C2116.2 C2117.2 C2118.2 C2119.2 C2120.2 C2121.2 C2122.2 C2201.1 C2202.1 C2405.2 C2406.2 C2409.2 C2410.2 C2411.2 C2412.2 C2413.2 C2414.2 C2415.2 C2416.2 C2418.2 C2420.2 C2421.2 C2423.2 C2424.1 C2425.1 C2426.2 C2428.2 C2429.2 C2436.2 C2501.2 C2502.2 C2503.2 C2601.2 C2602.2 C2603.2 C2604.2 C2605.2 C2608.2 C2609.2 C2610.2 C2701.2 C2706.2 C2707.2 C2708.2 C2709.2 C2716.2 C2717.2 C2718.2 C2719.2 C2721.2 C2722.2 C2723.1 C2724.2 C3401.2 C3402.2 C3403.2 C3404.2 C3405.2 C3406.2 C3407.2 C3502.2 C3503.2 C3507.2 C3508.2 C3512.2 C3513.2 C3514.2 C3701.2 C3702.2 C3703.2 C3704.2 C3705.2 C3707.2 C3709.2 C3710.2 C3711.2 C3712.2 C3715.2 C3716.2 C3717.1 C3718.2 C3719.2 C3720.1 C3721.2 C3722.2 C3723.2 C3815.2 C3816.2 C3817.2 C3818.2 C3819.2 C3820.2 C3821.2 C3865.2 C4001.2 C4002.2 C4004.2 C4005.2 C4006.2 C4007.2 C4008.2 C4009.2 C4010.2 C4011.2 C4012.2 C4013.2 C4031.2 C4032.2 C4033.2 C4034.2 C5502.2 C5503.2 C5505.2 C5507.2 C5508.1 C5512.2 C5513.2 C5514.2 C5515.2 C5516.2 C5517.2 C5518.2 C5520.2 C5534.2 C5542.1 C5701.1 C5702.1 C5703.1 C5704.1 C5705.1 C5706.1 C5713.2 C5716.1 C5717.1 C6002.1 C6004.2 C6007.2 C6008.2 C6009.2 C6010.2 C6304.2 C6305.2 C6306.2 C6307.2 C6308.2 C6317.2 C6318.2 C6501.2 C6503.2 C6504.2 C7001.2 C7002.2 C7003.2 C7004.2 C9101.2 C9102.2 C9104.2 C9105.2 C9106.2 C9113.2 C9114.2 CPU1.AA2 CPU1.AA4 CPU1.AA65 CPU1.AA68 CPU1.AB8 CPU1.AB15 CPU1.AB16 CPU1.AB18 CPU1.AB21 CPU1.AD8 CPU1.AD13 CPU1.AD16 CPU1.AD19 CPU1.AD20 CPU1.AD21 CPU1.AD62 CPU1.AE64 CPU1.AE65 CPU1.AE66 CPU1.AE67 CPU1.AE68 CPU1.AE69 CPU1.AF1 CPU1.AF2 CPU1.AF4 CPU1.AF10 CPU1.AF15 CPU1.AF17 CPU1.AF63 CPU1.AG16 CPU1.AG17 CPU1.AG18 CPU1.AG19 CPU1.AG20 CPU1.AG21 CPU1.AG71 CPU1.AH6 CPU1.AH13 CPU1.AH63 CPU1.AH64 CPU1.AH67 CPU1.AJ4 CPU1.AJ15 CPU1.AJ18 CPU1.AJ20 CPU1.AK8 CPU1.AK11 CPU1.AK16 CPU1.AK18 CPU1.AK21 CPU1.AK22 CPU1.AK27 CPU1.AK63 CPU1.AK68 CPU1.AK69 CPU1.AL2 CPU1.AL4 CPU1.AL28 CPU1.AL32 CPU1.AL35 CPU1.AL38 CPU1.AL45 CPU1.AL48 CPU1.AL52 CPU1.AL55 CPU1.AL58 CPU1.AL64 CPU1.AL65 CPU1.AL66 CPU1.AM8 CPU1.AM13 CPU1.AM21 CPU1.AM25 CPU1.AM27 CPU1.AM43 CPU1.AM45 CPU1.AM46 CPU1.AM55 CPU1.AM60 CPU1.AM61 CPU1.AM68 CPU1.AM71 CPU1.AN20 CPU1.AN23 CPU1.AN28 CPU1.AN30 CPU1.AN32 CPU1.AN33 CPU1.AN35 CPU1.AN37 CPU1.AN38 CPU1.AN40 CPU1.AN42 CPU1.AN58 CPU1.AN63 CPU1.AP10 CPU1.AP18 CPU1.AP20 CPU1.AP23 CPU1.AP28 CPU1.AP32 CPU1.AP35 CPU1.AP38 CPU1.AP42 CPU1.AP58 CPU1.AP63 CPU1.AP68 CPU1.AP70 CPU1.AR5 CPU1.AR8 CPU1.AR11 CPU1.AR15 CPU1.AR16 CPU1.AR20 CPU1.AR23 CPU1.AR28 CPU1.AR35 CPU1.AR42 CPU1.AR43 CPU1.AR45 CPU1.AR46 CPU1.AR48 CPU1.AR50 CPU1.AR52 CPU1.AR53 CPU1.AR55 CPU1.AR58 CPU1.AR63 CPU1.AT2 CPU1.AT4 CPU1.AT20 CPU1.AT23 CPU1.AT28 CPU1.AT35 CPU1.AT42 CPU1.AT56 CPU1.AT58 CPU1.AT63 CPU1.AT68 CPU1.AT71 CPU1.AU10 CPU1.AU15 CPU1.AU20 CPU1.AU32 CPU1.AU38 CPU1.AV68 CPU1.AV69 CPU1.AV70 CPU1.AW6 CPU1.AW8 CPU1.AW10 CPU1.AW12 CPU1.AW14 CPU1.AW16 CPU1.AW18 CPU1.AW21 CPU1.AW23 CPU1.AW26 CPU1.AW28 CPU1.AW30 CPU1.AW32 CPU1.AW34 CPU1.AW36 CPU1.AW38 CPU1.AW41 CPU1.AW43 CPU1.AW45 CPU1.AW47 CPU1.AW49 CPU1.AW51 CPU1.AW53 CPU1.AW55 CPU1.AW57 CPU1.AW60 CPU1.AW62 CPU1.AW64 CPU1.AW66 CPU1.AY66 CPU1.B10 CPU1.B14 CPU1.B18 CPU1.B22 CPU1.B30 CPU1.B34 CPU1.B39 CPU1.B44 CPU1.B48 CPU1.B53 CPU1.B58 CPU1.B62 CPU1.B66 CPU1.BA6 CPU1.BA10 CPU1.BA14 CPU1.BA18 CPU1.BA23 CPU1.BA28 CPU1.BA32 CPU1.BA36 CPU1.BA41 CPU1.BA45 CPU1.BA49 CPU1.BA53 CPU1.BA57 CPU1.BA62 CPU1.BA66 CPU1.BB6 CPU1.BB18 CPU1.BB26 CPU1.BB30 CPU1.BB34 CPU1.BB38 CPU1.BB43 CPU1.BB55 CPU1.BB60 CPU1.BB64 CPU1.C5 CPU1.C25 CPU1.D6 CPU1.D10 CPU1.D11 CPU1.D14 CPU1.D18 CPU1.D22 CPU1.D25 CPU1.D26 CPU1.D30 CPU1.D34 CPU1.D39 CPU1.D44 CPU1.D45 CPU1.D47 CPU1.D48 CPU1.D53 CPU1.D58 CPU1.D62 CPU1.D66 CPU1.D69 CPU1.E6 CPU1.E11 CPU1.E15 CPU1.E18 CPU1.E21 CPU1.E46 CPU1.E50 CPU1.E53 CPU1.E56 CPU1.E65 CPU1.F1 CPU1.F2 CPU1.F4 CPU1.F8 CPU1.F13 CPU1.F22 CPU1.F23 CPU1.F27 CPU1.F28 CPU1.F32 CPU1.F33 CPU1.F35 CPU1.F37 CPU1.F38 CPU1.F40 CPU1.F42 CPU1.F68 CPU1.G5 CPU1.G6 CPU1.G10 CPU1.G22 CPU1.G43 CPU1.G45 CPU1.G48 CPU1.G52 CPU1.G55 CPU1.G58 CPU1.G60 CPU1.G63 CPU1.G66 CPU1.H15 CPU1.H18 CPU1.H71 CPU1.J8 CPU1.J11 CPU1.J13 CPU1.J25 CPU1.J28 CPU1.J32 CPU1.J35 CPU1.J38 CPU1.J42 CPU1.K16 CPU1.K18 CPU1.K22 CPU1.K61 CPU1.K63 CPU1.K64 CPU1.K65 CPU1.K66 CPU1.K67 CPU1.K68 CPU1.K70 CPU1.K71 CPU1.L2 CPU1.L4 CPU1.L8 CPU1.L11 CPU1.L16 CPU1.L17 CPU1.L18 CPU1.L20 CPU1.N6 CPU1.N10 CPU1.N13 CPU1.N19 CPU1.N21 CPU1.N65 CPU1.N68 CPU1.P17 CPU1.P19 CPU1.P20 CPU1.P21 CPU1.R6 CPU1.R13 CPU1.T2 CPU1.T4 CPU1.T15 CPU1.T17 CPU1.T18 CPU1.T21 CPU1.U10 CPU1.U63 CPU1.U64 CPU1.U66 CPU1.U67 CPU1.U69 CPU1.U70 CPU1.V16 CPU1.V17 CPU1.V18 CPU1.W6 CPU1.W9 CPU1.W13 CPU1.Y17 CPU1.Y19 CPU1.Y20 CPU1.Y21 D2601.A D4304.1 D4305.1 D4306.1 DB1.3 DB1.15 DB1.16 DB3.4 DB3.7 DB3.8 DCIN1.9 DCIN1.10 DM1.1 DM1.2 DM1.5 DM1.6 DM1.9 DM1.10 DM1.14 DM1.15 DM1.18 DM1.19 DM1.22 DM1.23 DM1.26 DM1.27 DM1.30 DM1.31 DM1.35 DM1.36 DM1.39 DM1.40 DM1.43 DM1.44 DM1.47 DM1.48 DM1.51 DM1.52 DM1.56 DM1.57 DM1.60 DM1.61 DM1.64 DM1.65 DM1.68 DM1.69 DM1.72 DM1.73 DM1.77 DM1.78 DM1.81 DM1.82 DM1.85 DM1.86 DM1.89 DM1.90 DM1.93 DM1.94 DM1.98 DM1.99 DM1.102 DM1.103 DM1.106 DM1.107 DM1.167 DM1.168 DM1.171 DM1.172 DM1.175 DM1.176 DM1.180 DM1.181 DM1.184 DM1.185 DM1.188 DM1.189 DM1.192 DM1.193 DM1.196 DM1.197 DM1.201 DM1.202 DM1.205 DM1.206 DM1.209 DM1.210 DM1.213 DM1.214 DM1.217 DM1.218 DM1.222 DM1.223 DM1.226 DM1.227 DM1.230 DM1.231 DM1.234 DM1.235 DM1.238 DM1.239 DM1.243 DM1.244 DM1.247 DM1.248 DM1.251 DM1.252 DM1.261 DM1.262 DM2.1 DM2.2 DM2.5 DM2.6 DM2.9 DM2.10 DM2.14 DM2.15 DM2.18 DM2.19 DM2.22 DM2.23 DM2.26 DM2.27 DM2.30 DM2.31 DM2.35 DM2.36 DM2.39 DM2.40 DM2.43 DM2.44 DM2.47 DM2.48 DM2.51 DM2.52 DM2.56 DM2.57 DM2.60 DM2.61 DM2.64 DM2.65 DM2.68 DM2.69 DM2.72 DM2.73 DM2.77 DM2.78 DM2.81 DM2.82 DM2.85 DM2.86 DM2.89 DM2.90 DM2.93 DM2.94 DM2.98 DM2.99 DM2.102 DM2.103 DM2.106 DM2.107 DM2.167 DM2.168 DM2.171 DM2.172 DM2.175 DM2.176 DM2.180 DM2.181 DM2.184 DM2.185 DM2.188 DM2.189 DM2.192 DM2.193 DM2.196 DM2.197 DM2.201 DM2.202 DM2.205 DM2.206 DM2.209 DM2.210 DM2.213 DM2.214 DM2.217 DM2.218 DM2.222 DM2.223 DM2.226 DM2.227 DM2.230 DM2.231 DM2.234 DM2.235 DM2.238 DM2.239 DM2.243 DM2.244 DM2.247 DM2.248 DM2.251 DM2.252 DM2.261 DM2.262 EC1001.2 EC1002.2 EC1003.2 EC1004.2 EC1005.2 EC1006.2 EC1007.2 EC1102.2 EC1103.2 EC1202.2 EC1302.2 EC1303.2 EC1706.2 EC1707.2 EC1710.2 EC1712.2 EC1713.2 EC1803.1 EC1804.2 EC1806.2 EC1807.2 EC1901.1 EC1902.2 EC2002.2 EC2101.2 EC2501.2 EC2502.2 EC2503.2 EC2504.2 EC2701.2 EC2703.2 EC2704.2 EC2705.2 EC2706.2 EC2707.2 EC2708.2 EC2709.2 EC2901.2 EC2902.2 EC2903.2 EC2904.2 EC2909.2 EC2910.2 EC2911.2 EC2912.2 EC4306.1 EC4307.2 EC4308.2 EC4309.2 EC4310.2 EC4425.2 EC4534.2 EC4701.2 EC4801.2 EC5001.2 EC5501.2 EC5502.2 EC5503.2 EC5504.2 EC5505.2 EC6401.2 EC6402.2 EC6501.2 EC6502.2 EC6503.2 EC6504.2 EC6505.2 EC6506.2 EC6507.2 EC6508.2 EC6509.2 EC6510.2 EC6511.2 EC6512.2 EC6513.2 EC6514.2 EC6515.2 EC6516.2 EC6517.2 EC6518.2 EC6519.2 EC6520.2 EC6521.2 EC6522.2 EC6523.2 EC6524.2 EC6525.2 EC6526.2 EC6527.2 EC6528.2 EC6529.2 EC6530.2 EC6601.2 EC6602.2 EC6603.2 EC8901.2 EC8902.2 EC8903.2 EC8904.2 EC8905.2 EC8906.2 EC8907.2 EC8908.2 EC8909.2 EC8910.2 EC8911.2 EC8912.2 EC8913.2 EC8914.2 EC8915.2 EC8916.2 EC8917.2 EC8918.2 EC8919.2 EC8920.2 EC8921.2 EC8922.2 EC8923.2 EC8924.2 EC8925.2 EC8926.2 EC8927.2 EC8928.2 EC8929.2 EC8930.2 EC8931.2 EC8932.2 EC8933.2 EC8934.2 EC8935.2 EC8936.2 EC8937.2 EC8938.2 EC8939.2 EC8940.2 EC8941.2 EC8942.2 EC8943.2 EC8944.2 EC8945.2 EC8946.2 EC8947.2 EC8948.2 EC8949.2 EC8950.2 EC8951.2 EC8952.2 EC8953.2 EC8954.2 EC8955.2 ED401.2 ED501.1 ED1217.2 ED1302.2 ED1701.2 ED1702.2 ED1703.2 ED1704.2 ED1705.2 ED1708.2 ED1709.2 ED1711.2 ED2401.2 ED2901.K ED2902.2 ED2903.2 ED2904.2 ED2905.2 ED2906.K ED3601.3 ED3601.8 ED3602.2 ED3603.3 ED3603.8 ED3801.3 ED3802.3 ED3802.8 ED3803.3 ED3804.3 ED3805.3 ED3806.3 ED3806.8 ED6305.2 ED6401.2 ED6402.2 EL4303.2 EL4304.2 FAN1.2 FAN1.5 FAN1.6 G1801.1 GMR1.2 GPU1.A3 GPU1.A6 GPU1.A9 GPU1.B1 GPU1.B4 GPU1.B7 GPU1.B10 GPU1.E1 GPU1.E4 GPU1.E7 GPU1.E10 GPU1.F3 GPU1.F6 GPU1.F9 GPU2.C1 GPU2.C2 GPU2.C3 GPU2.C4 GPU2.C5 GPU2.C6 GPU2.D1 GPU2.D2 GPU2.D3 GPU2.D4 GPU2.D5 GPU2.D6 H2.1 H3.1 H4.1 H5.1 H6.1 H7.1 H8.1 H9.1 H10.1 HDA27.49 HDD1.3 HDD1.4 HDD1.5 HDD1.6 HDD1.14 HDD1.17 HDD1.20 HDD1.21 HDD1.22 HDD1.23 HDD1.24 HDMI1.2 HDMI1.5 HDMI1.8 HDMI1.11 HDMI1.17 HDMI1.20 HDMI1.21 HDMI1.22 HDMI1.23 HS1.1 IOBD1.5 IOBD1.6 IOBD1.9 IOBD1.12 IOBD1.15 IOBD1.18 IOBD1.21 IOBD1.24 IOBD1.50 IOBD1.51 IOBD1.52 IOBD1.53 IOBD1.54 KB1.1 KB1.31 KB1.32 KBBL1.5 KBBL1.6 KBC24.17 KBC24.51 KBC24.64 KBC24.84 KBC24.100 KBC24.124 LCD1.11 LCD1.14 LCD1.17 LCD1.20 LCD1.23 LCD1.26 LCD1.33 LCD1.34 LCD1.35 LCD1.36 LCD1.37 LCD1.38 LCD1.39 LCD1.40 LCD1.41 LCD1.42 LCD1.43 LCD1.44 LED1.1 LED1.4 LED1.5 LED1.6 PC1001.2 PC1002.2 PC1003.2 PC1004.2 PC1005.2 PC1006.2 PC1007.2 PC1008.2 PC1009.2 PC1010.2 PC1011.2 PC1012.2 PC1013.2 PC1014.2 PC1015.2 PC1016.2 PC1017.2 PC1018.2 PC1019.2 PC1020.2 PC1021.2 PC1022.2 PC1023.2 PC1024.2 PC1025.2 PC1026.2 PC1027.2 PC1028.2 PC1029.2 PC1030.2 PC1031.2 PC1032.2 PC1033.2 PC1034.2 PC1035.2 PC1036.2 PC1037.2 PC1038.2 PC1039.2 PC1040.2 PC1041.2 PC1042.2 PC1043.2 PC1044.2 PC1045.2 PC1046.2 PC1047.2 PC1048.2 PC1049.2 PC1050.2 PC1051.2 PC1052.2 PC1053.2 PC1054.2 PC1055.2 PC1056.2 PC1057.2 PC1058.2 PC1059.2 PC1060.2 PC1061.2 PC1062.2 PC1063.2 PC1064.2 PC1065.2 PC1066.2 PC1067.2 PC1068.2 PC1069.2 PC1070.2 PC1071.2 PC1072.2 PC1073.2 PC1074.2 PC1075.2 PC1076.2 PC1077.2 PC1078.2 PC1079.2 PC1080.2 PC1081.2 PC1082.2 PC1083.2 PC1085.2 PC1101.2 PC1102.2 PC1103.2 PC1104.2 PC1105.2 PC1106.2 PC1107.2 PC1108.2 PC1109.2 PC1110.2 PC1111.2 PC1112.2 PC1113.2 PC1114.2 PC1115.2 PC4302.2 PC4303.2 PC4304.2 PC4305.2 PC4306.2 PC4307.2 PC4311.2 PC4313.1 PC4314.2 PC4315.2 PC4403.2 PC4404.2 PC4405.2 PC4406.2 PC4407.2 PC4408.2 PC4409.2 PC4410.2 PC4411.2 PC4412.2 PC4413.2 PC4415.2 PC4416.2 PC4417.2 PC4418.2 PC4419.2 PC4421.2 PC4422.2 PC4423.2 PC4424.2 PC4427.2 PC4428.2 PC4430.2 PC4431.2 PC4432.2 PC4433.2 PC4435.2 PC4501.2 PC4502.2 PC4503.2 PC4504.2 PC4505.2 PC4507.2 PC4508.2 PC4509.2 PC4510.2 PC4511.2 PC4512.2 PC4513.2 PC4514.2 PC4515.2 PC4516.2 PC4517.2 PC4518.2 PC4519.2 PC4520.2 PC4522.2 PC4523.2 PC4524.2 PC4525.2 PC4527.2 PC4528.2 PC4529.2 PC4530.2 PC4531.2 PC4532.2 PC4610.2 PC4702.2 PC4703.2 PC4704.2 PC4705.2 PC4707.2 PC4708.2 PC4709.2 PC4710.2 PC4721.2 PC4723.2 PC4724.2 PC4725.2 PC4726.2 PC4727.2 PC4728.2 PC4729.2 PC4730.2 PC4802.2 PC4803.2 PC4804.2 PC4805.2 PC4806.2 PC4807.2 PC4808.2 PC4810.2 PC4811.2 PC5001.2 PC5002.2 PC5027.2 PC5029.2 PC5031.2 PC5101.2 PC5102.2 PC5103.2 PC5104.2 PC5105.2 PC5106.2 PC5107.2 PC5108.2 PC5110.2 PC5111.2 PC5113.2 PC5114.2 PC5115.2 PC5116.2 PC5118.2 PC5119.2 PC5120.2 PC5138.2 PC5201.2 PC5202.2 PC5203.2 PC5205.2 PC5206.2 PC5208.2 PC5209.2 PC5210.2 PC5211.2 PC5213.2 PC5214.2 PC5215.2 PC5216.2 PC5401.2 PC5402.2 PC5403.2 PC5406.2 PC5407.2 PC5408.2 PC5409.2 PC5410.2 PC5412.2 PC5413.2 PC5414.2 PC5427.2 PD4301.A PD4302.1 PD4303.3 PD4304.A PG4601.2 PQ4302.2 PQ4304.E PQ4306.S PQ4307.1 PQ4307.4 PQ4308.1 PQ4308.4 PQ4309.1 PQ4310.1 PQ4310.4 PQ4311.1 PQ4311.4 PQ4312.S PQ4313.4 PQ4405.1 PQ4405.4 PQ4415.1 PQ4415.4 PR4302.2 PR4308.2 PR4313.2 PR4315.1 PR4316.2 PR4323.2 PR4324.2 PR4325.2 PR4328.1 PR4329.2 PR4332.2 PR4340.2 PR4344.1 PR4401.2 PR4409.2 PR4413.1 PR4423.2 PR4424.2 PR4430.2 PR4433.2 PR4436.2 PR4437.2 PR4442.2 PR4443.1 PR4449.2 PR4451.2 PR4508.2 PR4512.2 PR4513.2 PR4514.2 PR4530.2 PR4551.2 PR4652.2 PR4653.1 PR4656.1 PR4661.2 PR4682.2 PR5104.2 PR5106.1 PR5127.2 PR5203.2 PR5204.2 PR5401.2 PR5404.2 PR5409.2 PR5420.2 PT4702.2 PT4703.2 PT4704.2 PT4705.2 PT4801.2 PU4307.3 PU4401.33 PU4405.1 PU4405.2 PU4405.3 PU4501.7 PU4501.8 PU4501.18 PU4501.21 PU4502.7 PU4502.8 PU4502.18 PU4502.21 PU4701.5 PU4701.19 PU4701.20 PU4701.21 PU4701.22 PU4701.23 PU4701.24 PU4701.31 PU4701.37 PU4702.5 PU4702.19 PU4702.20 PU4702.21 PU4702.22 PU4702.23 PU4702.24 PU4702.31 PU4702.37 PU4801.3 PU4801.5 PU4801.19 PU4801.20 PU4801.21 PU4801.22 PU4801.23 PU4801.24 PU4801.31 PU4801.37 PU5001.6 PU5001.9 PU5003.1 PU5003.2 PU5003.3 PU5101.7 PU5101.8 PU5101.18 PU5101.21 PU5102.4 PU5102.8 PU5102.11 PU5201.4 PU5201.12 PU5201.13 PU5201.14 PU5201.15 PU5201.19 PU5401.1 PU5402.2 PU5403.1 Q1701.1 Q1701.4 Q1702.1 Q1702.4 Q2001.1 Q2001.4 Q2408.S Q2417.S Q2503.1 Q2503.4 Q2701.S Q3701.S Q5704.1 Q5704.4 Q6501.S Q6503.S Q7001.1 Q7001.4 Q9104.S R402.2 R406.2 R407.2 R412.2 R413.2 R414.2 R415.2 R501.2 R502.2 R503.2 R601.2 R602.2 R604.2 R605.2 R720.2 R722.2 R734.2 R803.1 R1205.1 R1209.2 R1210.1 R1212.1 R1216.2 R1303.1 R1307.2 R1309.2 R1311.1 R1501.2 R1502.2 R1603.2 R1714.2 R1715.2 R1717.2 R1719.2 R1823.2 R1825.2 R1901.2 R1912.2 R1914.1 R1917.1 R1919.1 R1921.1 R2008.2 R2009.2 R2019.2 R2030.2 R2031.2 R2032.2 R2033.2 R2034.2 R2035.2 R2036.2 R2056.2 R2417.2 R2431.1 R2436.2 R2445.1 R2448.2 R2449.1 R2454.2 R2456.2 R2504.2 R2509.2 R2517.2 R2611.2 R2706.2 R2717.2 R2732.2 R3403.1 R3404.1 R3501.2 R3726.1 R3735.2 R3751.2 R3753.2 R3802.1 R3830.2 R3831.2 R3841.2 R3843.2 R3844.2 R3846.2 R3857.1 R3858.1 R3870.2 R3872.2 R3873.2 R4006.2 R4301.1 R4303.2 R5412.1 R5414.1 R5416.1 R5418.1 R5501.2 R5710.2 R6304.2 R6508.2 R6509.2 R7007.1 R9131.2 R9148.2 RN1201.2(A) RN1301.2(A) RN1602.3(B) RN1602.4(B) RN1703.1(A) RN1703.2(A) RN2009.1(A) RN2009.2(A) RN5502.1(A) RN5502.2(A) RN5502.3(A) RN5502.4(A) SPI25.4 SPK1.6 SPK1.7 SPK1.8 SPR1.1 SPR2.1 SPR3.1 SPR4.1 SSD1.1 SSD1.3 SSD1.9 SSD1.15 SSD1.21 SSD1.27 SSD1.33 SSD1.39 SSD1.45 SSD1.51 SSD1.57 SSD1.71 SSD1.73 SSD1.75 SSD1.76 SSD1.77 TCBD1.13 TCBD1.16 TCBD1.20 TCBD1.21 TCBD1.29 TCBD1.33 TCBD1.34 THM261.5 TP1.4 TP1.9 TP1.10 U3401.14 U3401.17 U3501.2 U3701.41 U3702.3 U3702.7 U3703.1 U3703.7 U3801.41 U3802.5 U3802.21 U4001.11 U4001.15 U4002.5 U4003.3 U4006.5 U4302.3 U5501.2 U5701.8 U5701.35 U5701.41 U6001.3 U6001.8 U6002.5 U6002.9 U6301.3 U6301.8 U6302.3 U6302.8 U6303.3 U6303.8 U6304.3 U6304.8 U7001.5 U7001.6 U7001.7 U7001.8 U9104.9 U9104.16 U9104.23 U9104.32 U9104.33 USB1.13 USB1.14 USB1.15 USB1.16 USB1.17 USB1.18 USB1.19 USB1.20 USB1.21 USB1.22 USB1.A1 USB1.A12 USB1.B1 USB1.B12 USB2.4 USB2.7 USB2.10 USB2.11 USB2.12 USB2.13 USB3.4 USB3.7 USB3.10 USB3.11 USB3.12 USB3.13 X1801.2 X1801.4 X2201.2 X2201.4
V0.85A_VID0: CPU1.AN11 TP2101.1
V0.85A_VID1: CPU1.AN13 TP2102.1
VBUS_PRODECT#: PQ4311.5 PQ4311.6 PR4337.1
VCC3PD: D3701.K D3702.K PR4337.2 PR4342.1 R3732.1 R3733.1
VCC_CORE: C1101.1 C1124.1 C1125.1 C1126.1 C1127.1 CPU1.A30 CPU1.A34 CPU1.A39 CPU1.A44 CPU1.AK33 CPU1.AK35 CPU1.AK37 CPU1.AK38 CPU1.AK40 CPU1.AL33 CPU1.AL37 CPU1.AL40 CPU1.AM32 CPU1.AM33 CPU1.AM35 CPU1.AM37 CPU1.AM38 CPU1.G30 CPU1.G32 CPU1.G33 CPU1.G35 CPU1.G37 CPU1.G38 CPU1.G40 CPU1.G42 CPU1.J30 CPU1.J33 CPU1.J37 CPU1.J40 CPU1.K33 CPU1.K35 CPU1.K37 CPU1.K38 CPU1.K40 CPU1.K42 CPU1.K43 EC1002.1 EC1003.1 EC1004.1 PC1002.1 PC1003.1 PC1004.1 PC1005.1 PC1006.1 PC1007.1 PC1008.1 PC1009.1 PC1010.1 PC1011.1 PC1012.1 PC1013.1 PC1014.1 PC1015.1 PC1016.1 PC1017.1 PC1018.1 PC1019.1 PC1020.1 PC1021.1 PC1022.1 PC1023.1 PC1024.1 PC1025.1 PC1026.1 PC1027.1 PC1028.1 PC1029.1 PC1030.1 PC1031.1 PC1032.1 PC1033.1 PC1034.1 PC1035.1 PC1036.1 PC1079.1 PC1080.1 PC1081.1 PC1082.1 PG4708.2 PG4711.2 PL4701.2 PL4702.2 PT4702.1 PT4705.1 R707.1 R708.1 R719.1
VCC_SENSE: CPU1.E32 PR4617.1 R719.2
VCCGT_SENSE: CPU1.J70 PR4648.2 R721.2
VCCPD_VBUS: C3707.1 C3821.1 PC4310.2 PR4319.1 PR4336.2 PR4338.1 PR4343.1 PU4303.1 PU4303.2 PU4303.3 PU4305.5 PU4305.6 PU4305.7 PU4305.8 R3730.1 R3739.1 U3702.6 USB1.A4 USB1.A9 USB1.B4 USB1.B9
VCCRTCEXT: C2112.1 CPU1.BB10
VCCSA_SENSE: CPU1.H20 PR4607.1 R735.2
VCCSTG_EN_R: C4033.1 R4017.2 U4002.4
VCCSTU_EN_R: C4034.1 R4024.2 U4006.4
VDD: PC4428.1 PR4412.1 PR4422.1 PR4471.1 PU4401.19
VDDD: C3701.1 C3702.1 C3703.1 R3724.1 R3725.1 R3732.2 R3750.1 R3752.1 RN3701.1(A) RN3701.2(A) RN3702.1(A) RN3702.2(A) U3701.31
VDDIO: C3721.1 C3722.1 C3723.1 R3733.2 U3701.32
VSS_AY71: CPU1.AY71 R602.1
VSS_SENSE: CPU1.E33 PR4618.1 R720.1
VSSGT_SENSE: CPU1.J69 PR4645.2 R722.1
VSSSA_SENSE: CPU1.H21 PR4604.1 R734.1
0D6V_PWR: PC5114.1 PG5120.1 PG5121.1 PU5102.3 PU5102.5
0D6V_S0: C1223.1 C1224.1 C1225.1 C1226.1 C1227.1 C1230.1 C1324.1 C1325.1 C1326.1 C1327.1 DM1.258 DM2.258 PG5120.2 PG5121.2
1D0V_PWR: PC5201.1 PC5203.1 PC5205.1 PC5206.1 PC5208.1 PG5201.1 PG5204.1 PG5206.1 PG5207.1 PG5208.1 PG5209.1 PG5211.1 PG5213.1 PG5215.1 PG5216.1 PG5223.2 PL5201.2
1D0V_S5: C4006.1 C4013.1 EC1710.1 PG5201.2 PG5204.2 PG5206.2 PG5207.2 PG5208.2 PG5209.2 PG5211.2 PG5213.2 PG5215.2 PG5216.2 R1101.1 R1102.1 R1724.1 R2402.1 U4002.1 U4002.2 U4002.9 U4006.1 U4006.2 U4006.9
1D0V_S5_PWRGD: PR5209.1 R4029.1
1D2V_PWR: PC5101.1 PC5102.1 PC5103.1 PC5104.1 PC5105.1 PC5115.1 PC5118.1 PG5102.1 PG5106.1 PG5109.1 PG5111.1 PG5112.1 PG5113.1 PG5114.1 PG5115.1 PL5101.2 PU5102.1 PU5102.2
1D2V_S3: C718.1 C719.1 C1202.1 C1203.1 C1204.1 C1205.1 C1206.1 C1208.1 C1209.1 C1210.1 C1214.1 C1215.1 C1216.1 C1217.1 C1218.1 C1219.1 C1220.1 C1221.1 C1303.1 C1304.1 C1305.1 C1306.1 C1307.1 C1308.1 C1309.1 C1310.1 C1315.1 C1316.1 C1317.1 C1318.1 C1319.1 C1320.1 C1321.1 C1322.1 CPU1.AL23 CPU1.AU23 CPU1.AU28 CPU1.AU35 CPU1.AU42 CPU1.BB23 CPU1.BB32 CPU1.BB41 CPU1.BB47 CPU1.BB51 DM1.12 DM1.33 DM1.54 DM1.75 DM1.96 DM1.111 DM1.112 DM1.117 DM1.118 DM1.123 DM1.124 DM1.129 DM1.130 DM1.135 DM1.136 DM1.141 DM1.142 DM1.147 DM1.148 DM1.153 DM1.154 DM1.159 DM1.160 DM1.163 DM1.178 DM1.199 DM1.220 DM1.241 DM2.12 DM2.33 DM2.54 DM2.75 DM2.96 DM2.111 DM2.112 DM2.117 DM2.118 DM2.123 DM2.124 DM2.129 DM2.130 DM2.135 DM2.136 DM2.141 DM2.142 DM2.147 DM2.148 DM2.153 DM2.154 DM2.159 DM2.160 DM2.163 DM2.178 DM2.199 DM2.220 DM2.241 EC1102.1 EC1103.1 EC1202.1 EC1303.1 EC8918.1 EC8919.1 EC8920.1 EC8921.1 EC8922.1 EC8923.1 EC8924.1 EC8925.1 EC8933.1 EC8934.1 EC8935.1 EC8936.1 EC8937.1 EC8938.1 PC1101.1 PC1107.1 PC1108.1 PC1109.1 PC1110.1 PC1111.1 PC1112.1 PC1113.1 PC1114.1 PC1115.1 PG5102.2 PG5106.2 PG5109.2 PG5111.2 PG5112.2 PG5114.2 PG5115.2 Q501.G R505.1 R705.1 R1215.1 R1312.1 RN1201.1(A) RN1301.1(A)
1D2V_VTT_PWRGD: PR5107.1 R4011.1
1D5V_PWR: PC5409.1 PG5404.1 PU5402.5
1D5V_S0: PG5404.2 R2102.1 R2705.1 R5701.1
1D5V_VDD: C5702.2 C5704.2 C5705.2 C5706.2 C5716.2 R5701.2 U5701.19 U5701.20 U5701.31 U5701.40
1D8V_EN#: Q2701.D R2726.2 R2727.1
1D8V_EN_R#: C2714.2 Q2702.G R2727.2
1D8V_ESPI: DB1.10 R6802.1
1D8V_PWR: PC5402.1 PC5405.1 PG5405.1 PG5406.1 PG5407.1 PR5403.1 PU5401.3 PU5401.4
1D8V_S0: C2721.1 Q2702.D R2713.1 R2724.1 R6120.1
1D8V_S5_PWROK: KBC24.30 PR5408.1 R4030.1
2D5V_S3: C1207.1 C1211.1 C1212.1 C1213.1 C1231.1 C1232.1 C1311.1 C1312.1 C1313.1 C1314.1 C1330.1 C1331.1 DM1.257 DM1.259 DM2.257 DM2.259 PG5408.2 PG5409.2
3D3V_AUX_S5: C2415.1 GPU1.F1 PG4532.2 PR4503.1 PR4505.1 Q2417.D R1726.2 R1727.1 R1737.1 R2463.1 R2510.1
3D3V_CAMERA_S0: C5503.1 EC5502.1 F5502.2 R5513.2 TCBD1.6
3D3V_GSEN2: C7003.1 C7004.1 R7004.2 R7005.1 R7006.2 U7001.9 U7001.10
3D3V_MUX: C3815.1 C3816.1 C3817.1 C3818.1 C3819.1 C3820.1 C3865.1 L3801.2 R3801.1 R3818.1 R3821.1 R3840.1 R3842.1 R3845.1 R3847.1 R3852.1 R3871.1 R3874.1 U3801.1 U3801.6 U3801.20 U3801.28 U3802.13
3D3V_RTC_SYS: D2501.1 R2510.2 R2517.1
3D3V_S0: C1228.1 C1328.1 C1329.1 C2601.1 C2602.1 C4004.1 C5502.1 C5701.2 C5703.2 C5717.2 DM1.255 DM2.255 EC8909.1 EC8910.1 EC8911.1 F5502.1 F5504.1 GPU2.P1 GPU2.P2 GPU2.P3 IOBD1.36 IOBD1.37 IOBD1.38 IOBD1.39 PR4614.1 PR5102.2 Q1801.2 Q1801.5 Q2414.G Q2601.2 Q2601.5 R506.1 R802.2 R1204.2 R1208.2 R1211.2 R1216.1 R1302.2 R1306.2 R1310.2 R1503.1 R1606.1 R1608.1 R1827.1 R1828.1 R2005.1 R2006.1 R2010.1 R2029.1 R2042.1 R2043.1 R2044.1 R2045.1 R2046.1 R2047.1 R2048.1 R2049.1 R2055.1 R2429.2 R2430.2 R2489.2 R2603.1 R2604.1 R2609.1 R2710.1 R2731.1 R4005.1 R5411.1 R5413.1 R5415.1 R5417.1 R5419.1 R5420.1 R5513.1 R5516.1 R6302.1 R6307.1 R6502.1 R6802.2 R7004.1 R7018.1 R9102.1 R9120.2 R9141.2 R9145.1 RN801.1(A) RN801.2(A) RN803.1(A) RN803.2(A) RN1810.1(A) RN1810.2(A) RN1812.1(A) RN1812.2(A) RN1813.1(A) RN1813.2(A) RN2007.3(B) RN2007.4(B) RN2008.3(B) RN2008.4(B) RN2602.1(A) RN2602.2(A) THM261.1 U4001.8 U4001.9 U5501.4 U5501.5 U5701.11
3D3V_S0_ON: C4011.1 R4014.2 U4001.5
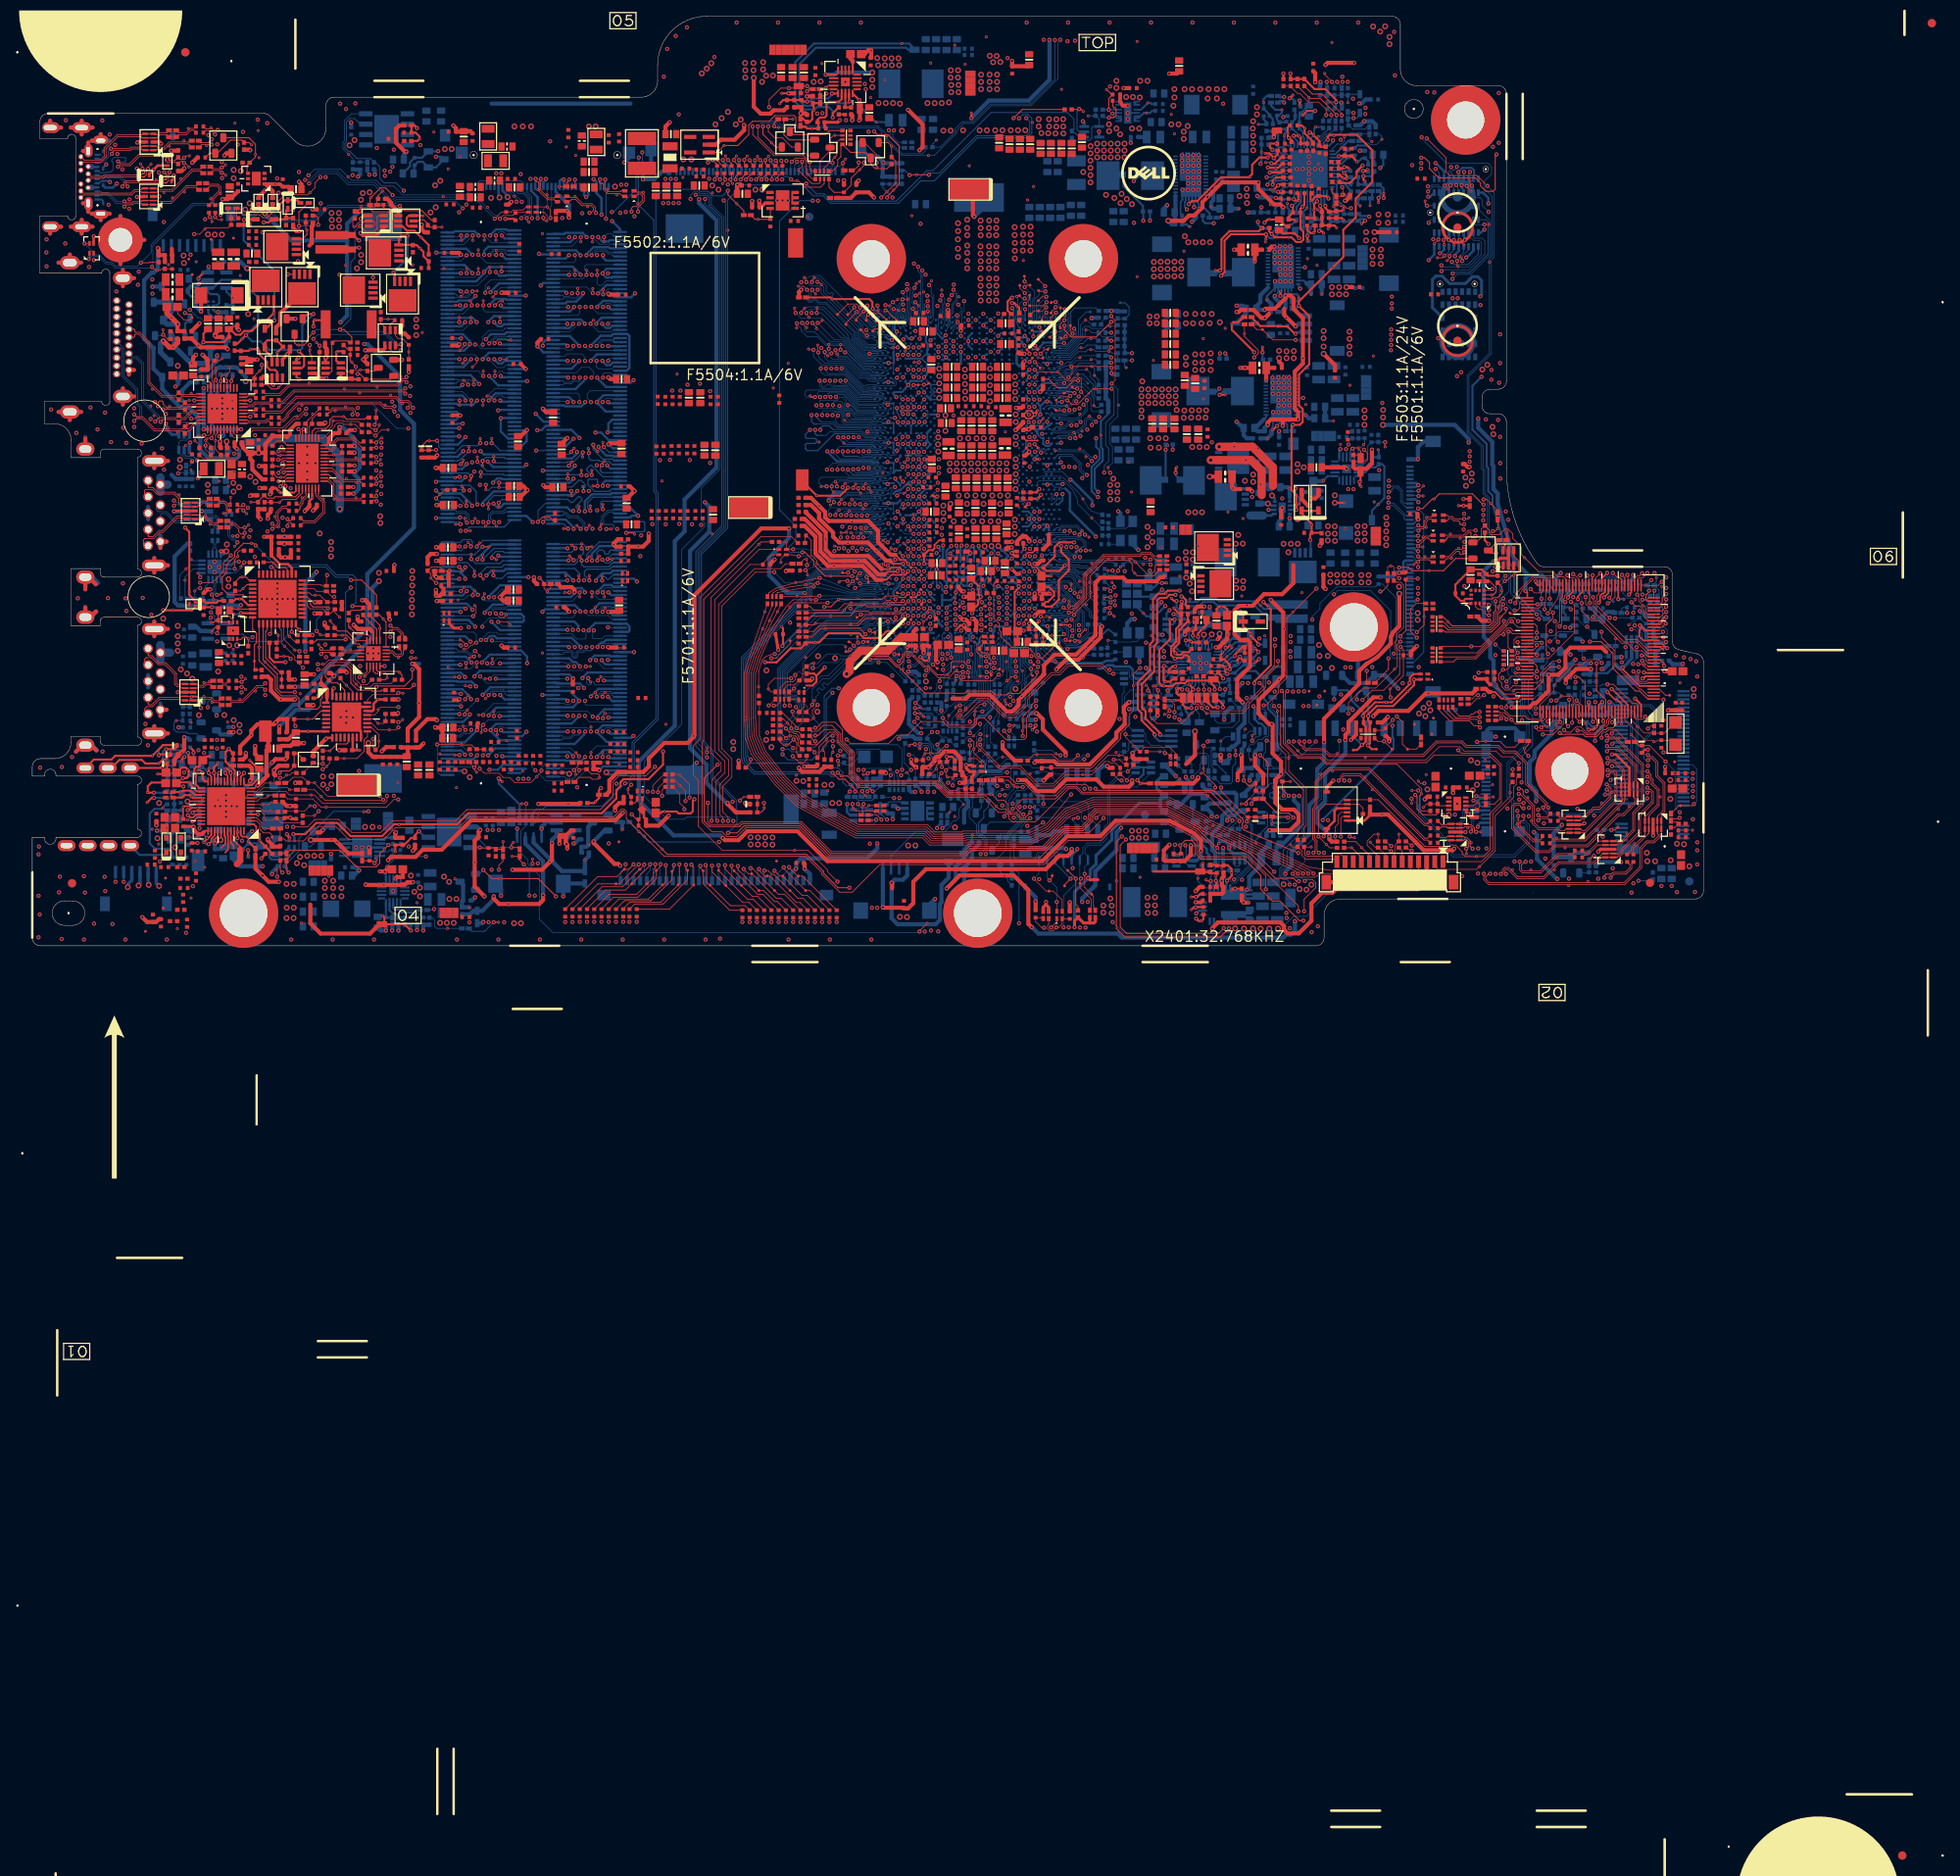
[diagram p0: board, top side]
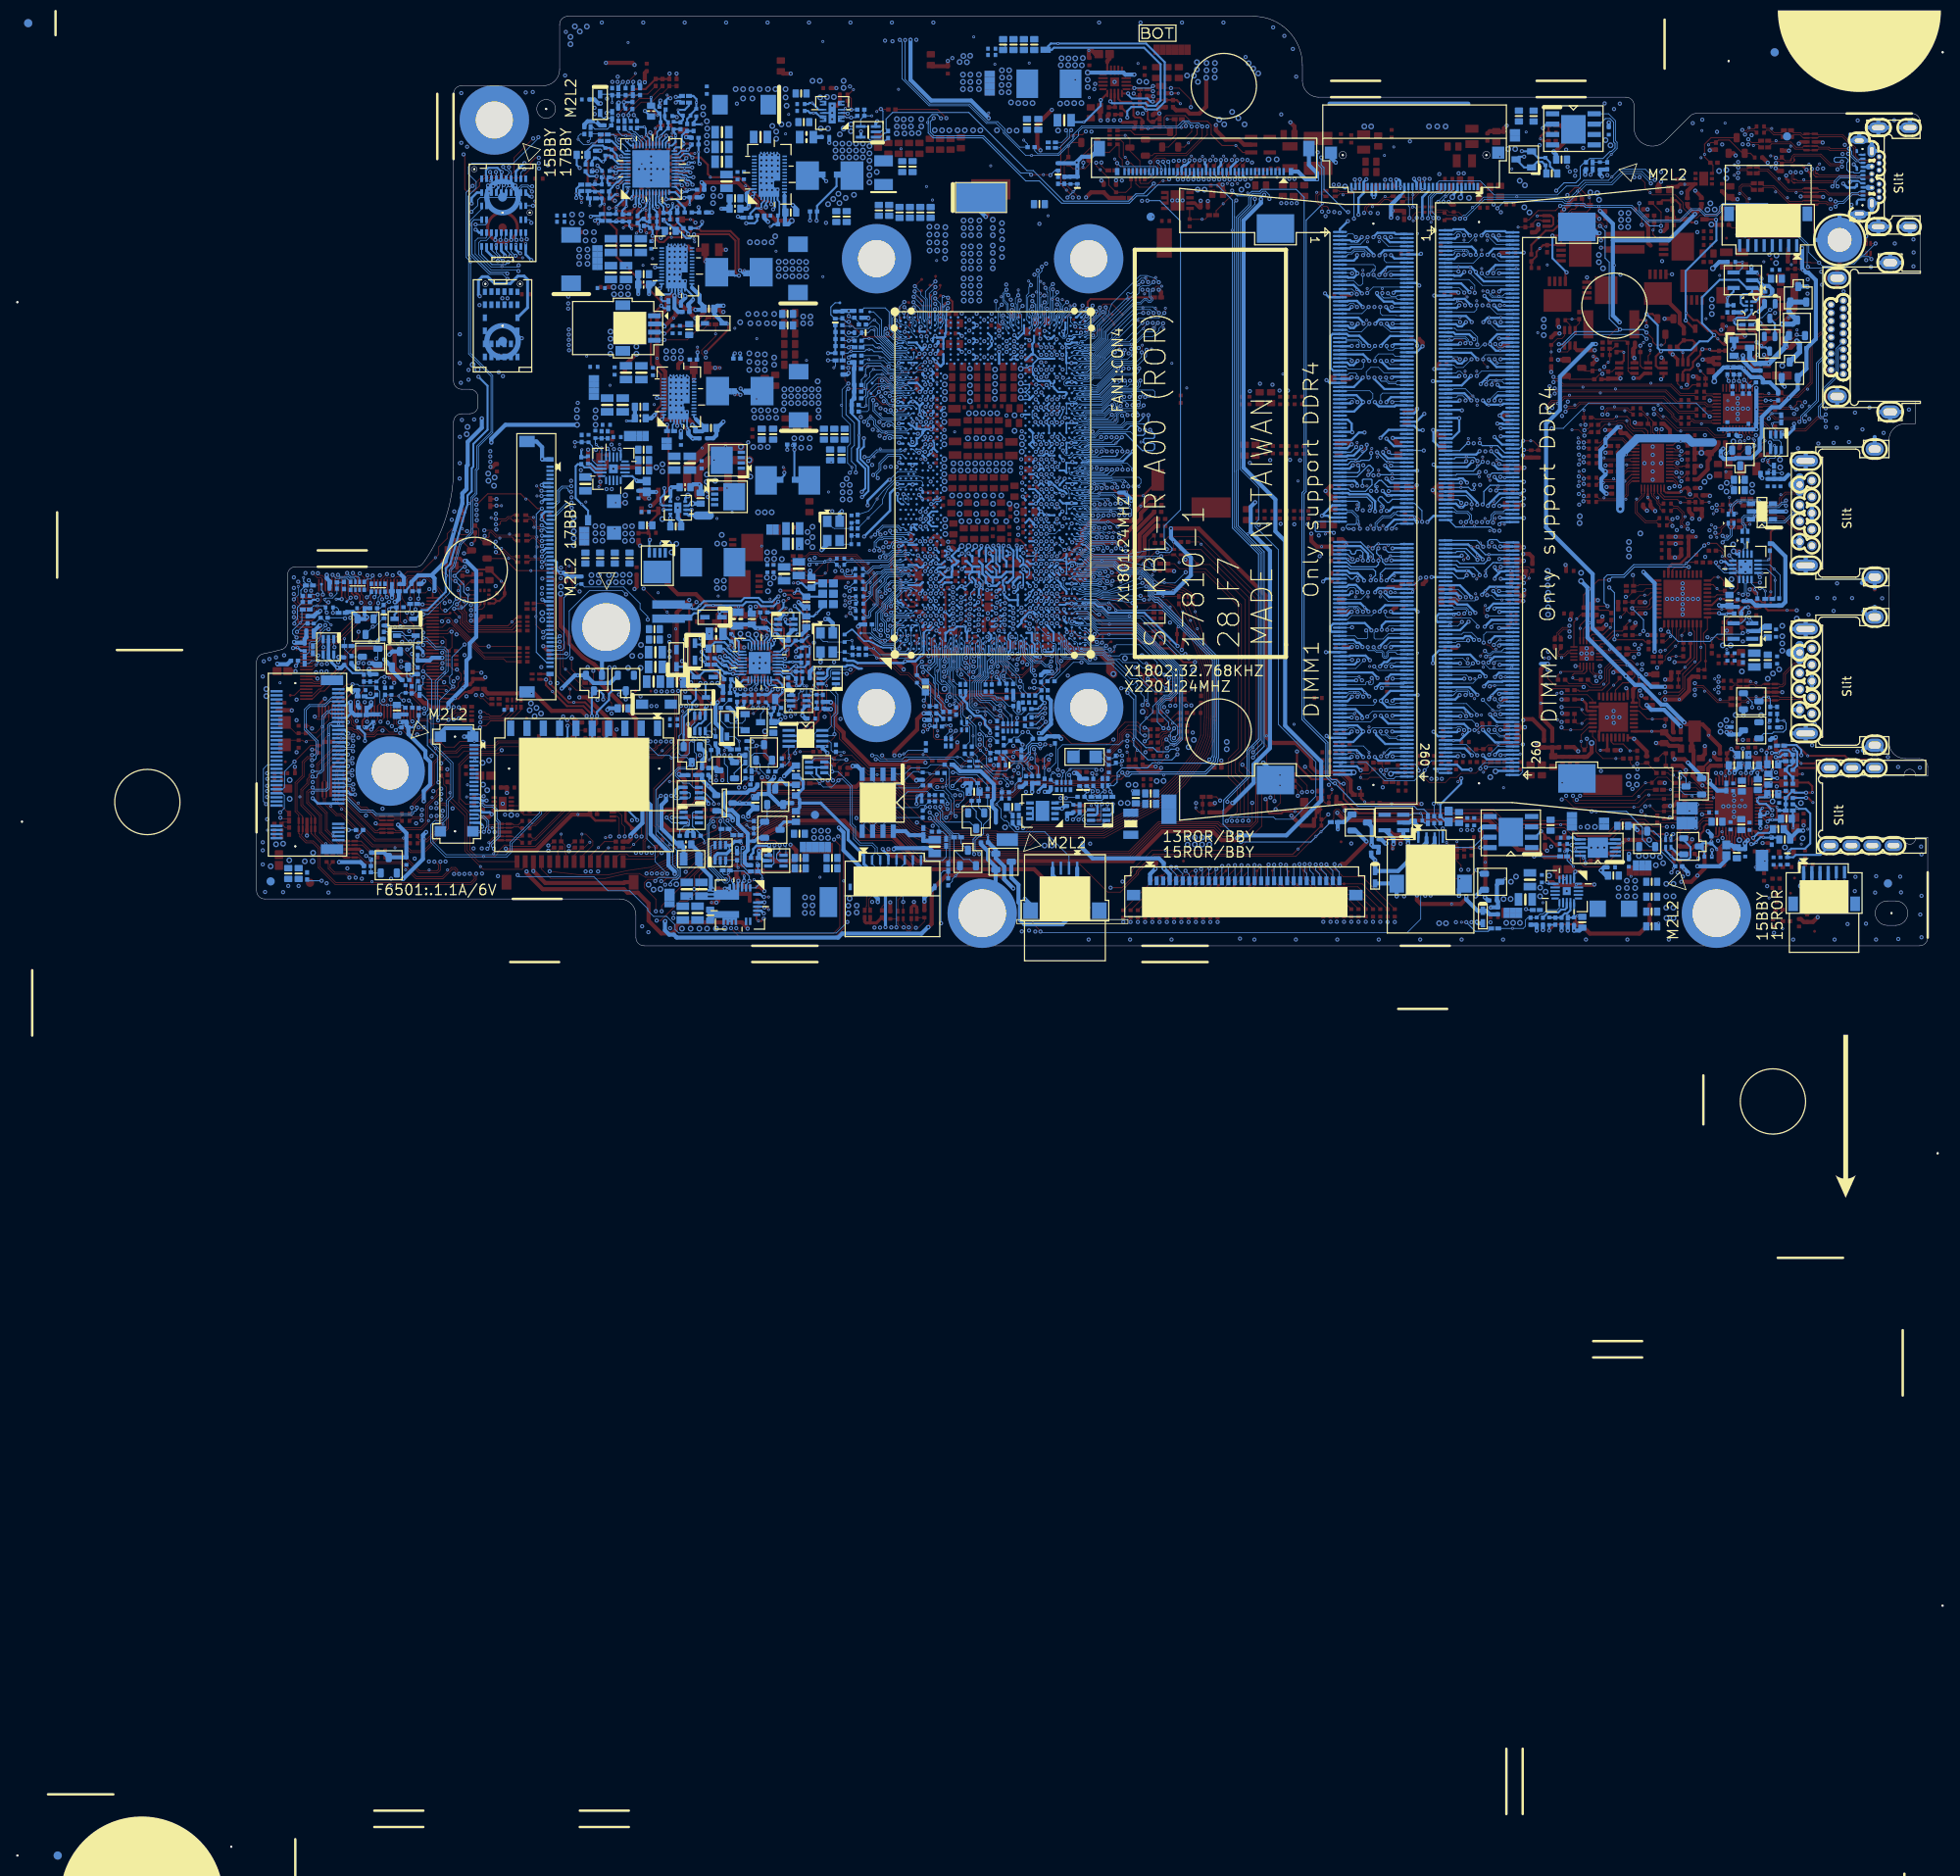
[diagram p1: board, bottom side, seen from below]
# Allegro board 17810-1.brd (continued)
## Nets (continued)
3D3V_S5: C2416.1 C2421.1 C6502.1 C7002.1 D3701.A EC1302.1 EC1713.1 EC8912.1 GMR1.3 L3801.1 PC5403.1 PC5408.1 PC5414.1 PD4302.2 PG4519.2 PG4520.2 PG4521.2 PG4522.2 PG4523.2 PG4524.2 PR4304.1 PR4335.1 PR4450.2 PR5208.1 PR5410.1 PU4307.6 PU5401.5 PU5401.9 PU5402.1 PU5403.5 PU5403.9 Q2416.2 Q2416.5 Q6502.S R1711.1 R1913.1 R2001.1 R2050.2 R2434.1 R2442.1 R2446.1 R2496.2 R2607.1 R3738.1 R4031.1 R4101.1 R7001.2 R7011.2 R9101.1 R9143.1 R9146.1 RN1704.1(A) RN1704.2(A) RN1704.3(A) RN1704.4(A) RN2405.5(B) RN2405.6(B) RN2405.7(B) RN2405.8(B) RN2407.1(A) RN2407.2(A) U4001.6 U4001.7 U4003.5 U4302.2
3D3V_S5_PCH: R404.1 R1103.1 R1822.1 R1824.1 R1836.1 R1837.1 R2007.1 R2040.1 R2041.1 R2501.2 R2515.1 R4101.2 R9103.1 RN1601.1(A) RN1601.2(A) RN1601.3(A) RN1601.4(A) RN1802.1(A) RN1802.2(A) RN1807.1(A) RN1807.2(A) RN1807.3(A) RN1807.4(A) RN1811.1(A) RN1811.2(A)
3D3V_SEN_S0: C5515.1 EC5505.1 F5504.2 R5516.2 TCBD1.5
3D3V_SPIVCC1: C2501.1 C2502.1 R2515.2 SPI25.8
3D3V_SSD: AFTP6304.1 C6304.1 C6305.1 C6306.1 C6307.1 C6308.1 C6317.1 C6318.1 R6302.2 R6303.1 R6306.2 R6307.2 SSD1.2 SSD1.4 SSD1.12 SSD1.14 SSD1.16 SSD1.18 SSD1.70 SSD1.72 SSD1.74
3D3V_TPM: C9101.1 C9102.1 C9104.1 C9105.1 Q9102.S R9101.2 R9102.2 R9103.2 R9119.1 R9138.2 R9140.1 R9147.1 R9149.1
3D3V_TPM_1: C9106.1 C9113.1 R9143.2 R9144.1
3D_CAM_DET#: CPU1.P2 TP2006.1
81208_AGND: PC4604.1 PC4609.2 PC4613.2 PC4615.1 PC4619.2 PC4628.2 PC4629.2 PC4630.2 PC4631.2 PC4632.2 PC4633.2 PC4646.2 PC4647.1 PC4648.2 PG4601.1 PR4602.1 PR4611.2 PR4613.2 PR4628.2 PR4632.1 PR4635.2 PR4636.2 PR4658.2 PR4659.2 PR4660.2 PR4662.2 PR4663.2 PR4664.2 PU4601.49
+DC_IN: EC8913.1 EL4301.2 EL4302.2 PC4301.1 PC4302.1 PD4301.K PQ4305.2 PR4307.1 PR4312.1 PU4301.1 PU4301.2 PU4301.3
+DC_IN_C: AFTP4303.1 AFTP4305.1 DCIN1.6 DCIN1.7 DCIN1.8 EC4301.1 EC4302.1 EL4301.1 EL4302.1
+RTC_VCC: D2501.2 IOBD1.34 Q2503.2 R2504.1
+SDC_IN: PG4402.1 PR4318.1 PR4320.1 PR4402.1 PU4302.1 PU4302.2 PU4302.3 PU4304.1 PU4304.2 PU4304.3
+SDC_IN_SW: PR4318.2 PR4333.2 PU4302.4
+SDC_IN_SW_R1: PQ4310.3 PR4333.1
+UZ12_TPM: C9114.1 R9145.2 R9146.2 U9104.8
+V_VREF_PATH1: C1222.2 R1209.1
+V_VREF_PATH2: C1323.2 R1309.1
A5_TP: CPU1.A5 TP2309.1
A67_TP: CPU1.A67 TP2311.1
A70_TP: CPU1.A70 TP2310.1
AC_DIS: KBC24.69 PD4307.A PR4326.1
AC_DIS_R: PD4307.K PD4308.K PQ4304.B PR4326.2 R4303.1
AC_IN#_G: PR4312.2 PR4313.1 U4302.5
AC_PRESENT: CPU1.AY15 D1701.A EC1707.1 Q1702.3 RN1704.8(B)
ACLIM: PR4421.2 PR4424.1 PU4401.16
ACOK#: PQ4415.2 PQ4415.3 PR4471.2
ACOK_IN_M: D1701.K PD4305.K PD4306.K PQ4415.6
AD+: PC4303.1 PC4304.1 PC4305.1 PC4306.1 PD4402.A PD4406.A PD4411.A PR4311.1 PR4316.1 PR4431.1 PU4301.5 PU4301.6 PU4301.7 PU4301.8 PU4302.5 PU4302.6 PU4302.7 PU4302.8
AD_IA: PC4423.1 PG4401.2 PR2455.1 R2421.1
AD_OFF_L: PQ4304.C PQ4305.1
AD_OFF_R: PC4301.2 PQ4305.3 PR4307.2 PR4308.1 PU4301.4
ALERT#: R2603.2 THM261.6
ALWON: KBC24.121 R4009.2
AMBER_LED_BAT: EC6401.1 Q6402.C R6401.2
AUD_AGND: C2702.1 C2704.1 C2705.1 C2710.2 C2711.2 C2712.1 C2713.2 C2715.2 C2902.2 EC2703.1 EC2704.1 EC2705.1 EC2706.1 EC2707.1 EC2905.2 EC2906.2 EC2907.2 EC2908.2 EC8901.1 EC8902.1 EC8903.1 EC8904.1 HDA27.18 HDA27.37 HPMIC1.MS R2706.1 R2711.1 R2905.2 R2919.2 R2920.2
AUD_HP1_JACK_L: HDA27.26 R2907.1
AUD_HP1_JACK_L1: EC2907.1 R2907.2 R2908.1 R2912.2 R2919.1 R2922.2
AUD_HP1_JACK_R: HDA27.25 R2909.1
AUD_HP1_JACK_R1: EC2908.1 R2909.2 R2910.1 R2913.2 R2920.1 R2921.2
AUD_PC_BEEP: HDA27.32 R2723.2
AUD_PC_BEEP_C: C2720.1 D2701.3 R2717.1
AUD_PC_BEEP_R: C2720.2 R2723.1
AUD_PORTA_L_R_B: ED2902.1 HPMIC1.1 R2908.2
AUD_PORTA_R_R_B: ED2905.1 HPMIC1.2 R2910.2
AUD_SENSE: C2902.1 R2709.2 R2923.2
AUD_SENSE_A: HDA27.1 R2709.1 R2722.2
AUD_SPK_L+: EC2904.1 EL2902.1 HDA27.42
AUD_SPK_L+_C: AFTP2902.1 EC2911.1 EL2902.2 SPK1.1
AUD_SPK_L-: EC2903.1 EL2901.1 HDA27.43
AUD_SPK_L-_C: AFTP2901.1 EC2909.1 EL2901.2 SPK1.2
AUD_SPK_R+: EC2901.1 EL2904.1 HDA27.45
AUD_SPK_R+_C: AFTP2904.1 EC2910.1 EL2904.2 SPK1.4
AUD_SPK_R-: EC2902.1 EL2903.1 HDA27.44
AUD_SPK_R-_C: AFTP2903.1 EC2912.1 EL2903.2 SPK1.3
AUD_VREF: C2705.2 HDA27.38
AUX_EN_WOWL: CPU1.BB17 TP1710.1
B71_TP: CPU1.B71 TP2312.1
BA1_TP: CPU1.BA1 TP2305.1
BA2_TP: CPU1.BA2 TP2306.1
BA71_TP: CPU1.BA71 TP2303.1
BAT1_LED#: KBC24.106 Q2416.4 RN2405.2(A)
BAT2_LED#: KBC24.1 Q2416.1 RN2405.1(A)
BAT_AMBER: ED6401.1 LED1.2 R6401.1
BAT_WHITE: ED6402.1 LED1.3 R6402.1
BATT_WHITE_LED#: Q2416.6 R6404.1
BATT_WHITE_LED_R#: Q6401.B Q6403.D R6404.2
BB67_TP: CPU1.BB67 TP2302.1
BB70_TP: CPU1.BB70 TP2301.1
BEEP: KBC24.45 RN2701.1(A)
BKLT_CTRL: D5502.3 R5502.1 RN5501.5(B) RN5502.8(B)
BKLT_EN_EC: KBC24.67 R2422.2
BLON_OUT: D5503.3 RN5501.7(B) RN5502.6(B)
BLON_OUT_C: LCD1.31 RN5501.2(A)
BLUETOOTH_EN: CPU1.AB2 IOBD1.47 R2042.2
BOARD_ID: C2408.1 KBC24.111 R2443.2 R2444.1
BOARD_ID1: CPU1.AC1 R2009.1 R2010.2
BOARD_ID2: CPU1.AB3 R2005.2 R2008.1
BOOST_MON: PC4424.1 PG4414.2 R2426.1
BOT_MUX_N: ED3805.1 EL3802.2 R3864.2 USB1.B7
BOT_MUX_N_L: EL3802.1 R3864.1 U3802.9
BOT_MUX_P: ED3805.2 EL3802.3 R3863.2 USB1.B6
BOT_MUX_P_L: EL3802.4 R3863.1 U3802.8
BREATH_LED#: KBC24.70 TP2405.1
BT+: AFTP4312.1 AFTP4313.1 AFTP4314.1 BATT1.1 BATT1.2 BATT1.3 EC4307.1 EC4308.1 PC4415.1 PC4416.1 PC4417.1 PC4418.1 PC4419.1 PC4433.1 PC4435.1 PD4304.K PD4401.A PG4413.1 PR4403.2 PR4415.2
C1_TP: CPU1.C1 TP2308.1
CAD_SNK: R3818.2 U3801.29
CAM_EN#: CPU1.A6 TP403.1
CAP_LED: AFTP6538.1 EC6530.1 KB1.4 R6513.2
CAP_LED#: KBC24.93 Q2414.S R2489.1
CAP_LED#_R: Q2414.D R6512.1
CAP_LED_Q: Q6505.C R6513.1
CAP_LED_R#: Q6505.B R6512.2
CBN: C2703.2 HDA27.23
CBP: C2703.1 HDA27.22
CCG4_FLIP#: R3855.1 R3856.1 U3701.5
CCG4_I2C_SCL: Q2605.6 RN3702.3(B) U3701.17
CCG4_I2C_SDA: Q2605.3 RN3702.4(B) U3701.16
CCG4_ID_1: R3750.2 R3751.1 U3701.25
CCG4_ID_2: R3752.2 R3753.1 U3701.27
CCG4_OVP_TRIP_P1: PQ4311.2 PR4341.2 U3701.14
CCG4_OVP_TRIP_P1_G: PC4313.2 PQ4309.2 PR4340.1 PR4341.1
CFG: R5420.2 U5701.23
CFG0: CPU1.E68 TP618.1
CFG1: CPU1.B67 TP619.1
CFG2: CPU1.D65 TP620.1
CFG3: CPU1.D67 R604.1 TP621.1
CFG4: CPU1.E70 R605.1 TP622.1
CFG5: CPU1.C68 TP623.1
CFG6: CPU1.D68 TP624.1
CFG7: CPU1.C67 TP625.1
CFG8: CPU1.F71 TP626.1
CFG9: CPU1.G69 TP627.1
CFG10: CPU1.F70 TP628.1
CFG11: CPU1.G68 TP629.1
CFG12: CPU1.H70 TP630.1
CFG13: CPU1.G71 TP631.1
CFG14: CPU1.H69 TP632.1
CFG15: CPU1.G70 TP633.1
CFG16: CPU1.E63 TP634.1
CFG17: CPU1.F63 TP635.1
CFG18: CPU1.E66 TP636.1
CFG19: CPU1.F66 TP637.1
CFG_RCOMP: CPU1.E60 R601.1
CHARGER_SRC: PC4405.1 PC4406.1 PC4407.1 PC4408.1 PC4409.1 PC4410.1 PC4411.1 PG4404.1 PG4405.1 PG4406.1 PG4407.1 PU4404.5 PU4404.6 PU4404.7 PU4404.8
CHG_AMBER_LED#: Q2416.3 R6403.1
CHG_AMBER_LED_R#: Q6402.B R6403.2
CLK_PCIE_LAN_REQ#: CPU1.AT8 RN1813.3(B)
CLK_PCIE_NVME_REQ#: CPU1.AU8 RN1812.3(B) SSD1.52
CLK_PCIE_PEG_REQ#: CPU1.AR10 GPU1.A2 RN1812.4(B)
CLK_PCIE_SD_REQ#: CPU1.AT10 R1827.2
CLK_PCIE_TBT_REQ#: CPU1.AU7 RN1813.4(B)
CLK_PCIE_VGA: CPU1.C42 GPU1.B8
CLK_PCIE_VGA#: CPU1.D42 GPU1.B9
CLK_PCIE_WLAN_REQ#: CPU1.AT7 IOBD1.44 R1828.2
CLK_TP_SIO: EC6501.1 KBC24.78 RN6501.4(B) RN6502.2(A)
CLKRUN#: CPU1.AW11 R1818.1 R2476.1
CLKRUN#_EC: KBC24.63 R2476.2 R2477.2
CMP_VIN0: KBC24.20 R2470.2
CMP_VIN0_R: C2612.1 C2613.1 R2470.1 R2608.2 R2609.2 R2610.1
CMP_VIN1: C2436.1 KBC24.21 PR2455.2 R2456.1
CMP_VOUT0: KBC24.85 R2602.2 R2607.2 R2615.2
CODEC_BITCLK_R: HDA27.8 R2720.2
CODEC_SDOUT_R: HDA27.11 R2719.2
COMBO-GPI: HDA27.2 TP2702.1
CPU_A16_TP: CPU1.BB9 TP1902.1
CPU_D4_TP: CPU1.V1 TP1804.1
CPU_D5_TP: CPU1.V2 TP1805.1
CPU_DP1_CTRL_CLK: CPU1.L13 RN801.3(B) U5701.38
CPU_DP1_CTRL_DATA: CPU1.L12 RN801.4(B) U5701.39
CPU_DP1_HPD: CPU1.L9 U5701.3
CPU_DP2_CTRL_CLK: CPU1.N7 RN803.3(B)
CPU_DP2_CTRL_DATA: CPU1.N8 RN803.4(B)
CPU_DP2_HPD: CPU1.L7 R803.2 R804.1
CPU_DP_HPD: R3849.2 U3801.23
CPU_DP_HPD_MUX: R3729.1 U3701.18
CPU_DP_HPD_R: Q5704.5 R804.2 R3725.2 R3729.2 R3849.1
CPU_POPIRCOMP: CPU1.AT16 R412.1
CPU_RXN_C_DGPU_TXN0: CPU1.H13 GPU1.E3
CPU_RXN_C_DGPU_TXN1: CPU1.G11 GPU1.E6
CPU_RXN_C_DGPU_TXN2: CPU1.H16 GPU1.F5
CPU_RXN_C_DGPU_TXN3: CPU1.G15 GPU1.F8
CPU_RXP_C_DGPU_TXP0: CPU1.G13 GPU1.E2
CPU_RXP_C_DGPU_TXP1: CPU1.F11 GPU1.E5
CPU_RXP_C_DGPU_TXP2: CPU1.G16 GPU1.F4
CPU_RXP_C_DGPU_TXP3: CPU1.F15 GPU1.F7
CPVDD: C2701.1 C2724.1 HDA27.21 R2724.2
CPVEE: C2704.2 HDA27.24
CSI2_COMP: CPU1.E13 R1501.1
CTL1: R3401.2 U3401.6
CTL2: R3406.2 U3401.7
CTL3: R3402.2 U3401.8
DAT_TP_SIO: EC6502.1 KBC24.79 RN6501.3(B) RN6502.1(A)
DBC_EN_R: LCD1.32 R5503.1
DBC_PANEL_EN: CPU1.AM5 R2043.2 R5503.2
DC_IN_OK: PD4305.A PD4309.A PQ4306.G PQ4310.5 PR4311.2 PR4314.1 PR4315.2 PR4335.2 PU4307.2 R2475.1 U4302.1
DC_IN_OK#: PD4308.A PU4307.4
DC_IN_OK_R: PD4309.K PD4310.K PQ4308.2 PR4314.2 PR4329.1
DCBATOUT: EC4425.1 EC4534.1 EC4801.1 EC8905.1 EC8906.1 EC8907.1 EC8908.1 EC8926.1 EC8927.1 EC8928.1 EC8929.1 EC8930.1 EC8931.1 EC8932.1 EC8939.1 EC8940.1 EC8941.1 EC8942.1 EC8943.1 EC8944.1 EC8945.1 EC8946.1 EC8947.1 EC8948.1 EC8949.1 EC8950.1 EC8951.1 EC8952.1 EC8953.1 EC8954.1 EC8955.1 F5503.1 GPU2.A1 GPU2.A2 GPU2.A3 GPU2.A4 GPU2.A5 GPU2.A6 GPU2.B1 GPU2.B2 GPU2.B3 GPU2.B4 GPU2.B5 GPU2.B6 PC4434.1 PC4802.1 PC4803.1 PC4804.1 PC4805.1 PC4806.1 PC4811.1 PG4403.1 PG4404.2 PG4405.2 PG4406.2 PG4407.2 PG4501.1 PG4502.1 PG4503.1 PG4504.1 PG4505.1 PG4506.1 PG4515.1 PG4516.1 PG4517.1 PG4518.1 PG4701.2 PG4702.2 PG4703.2 PG4704.2 PG4705.2 PG4721.2 PG4722.2 PG4723.2 PG5001.1 PG5002.1 PG5101.1 PG5103.1 PG5104.1 PG5107.1 PG5108.1 PG5110.1 PG5210.1 PG5212.1 PG5214.1 PR4402.2 PR4410.2 PR4458.2 PR4509.1 PR4511.1 PR4601.1 PT4703.1 PT4704.1 PU4403.1 PU4403.2 PU4403.3 PU4801.25 PU4801.26 PU4801.27 PU4801.28 PU4801.29 PU4801.30 R5514.2 R5520.2
DCBATOUT_+VCCSA: EC5001.1 PC5002.1 PC5027.1 PC5029.1 PG5001.2 PG5002.2 PU5002.5 PU5002.6 PU5002.7 PU5002.8
DCBATOUT_CAMERA: C5534.1 C5542.2 R5520.1 TCBD1.1 TCBD1.2
DCBATOUT_LCD: C5512.1 C5513.1 C5514.1 C5518.1 F5503.2 LCD1.1 LCD1.2 LCD1.3 LCD1.4 R5514.1
DCBATOUT_VCORE: EC4701.1 PC4702.1 PC4703.1 PC4704.1 PC4705.1 PC4710.1 PG4701.1 PG4702.1 PG4703.1 PG4704.1 PU4701.25 PU4701.26 PU4701.27 PU4701.28 PU4701.29 PU4701.30
DCBATOUT_VCORE1: PC4723.1 PC4724.1 PC4725.1 PC4726.1 PC4729.1 PC4730.1 PG4705.1 PG4721.1 PG4722.1 PG4723.1 PU4702.25 PU4702.26 PU4702.27 PU4702.28 PU4702.29 PU4702.30
DCIN_EN: R5419.2 U5701.13
DDC_CLK_HDMI: HDMI1.15 R5707.2 U5701.32
DDC_CLK_PH1: D5701.2 R5707.1
DDC_DATA_HDMI: HDMI1.16 R5706.2 U5701.33
DDC_DATA_PH2: D5701.1 R5706.1
DDCBUF: R5417.2 R5418.2 U5701.14
DDR4_DRAMRST#: DM1.108 DM2.108 ED1217.1 ED1302.1 R504.2
DDR_VREF_S3: PC5116.1 PU5102.6
DGPU_HOLD_RST#: CPU1.P3 EC2002.1 GPU1.D10 RN2009.4(B)
DGPU_PWR_EN: CPU1.U1 GPU1.C10 RN2009.3(B)
DGPU_PWROK: CPU1.C8 GPU1.D9 R2471.1 R2477.1
DGPU_RXN_C_CPU_TXN0: C1606.1 GPU1.A5
DGPU_RXN_C_CPU_TXN1: C1608.1 GPU1.A8
DGPU_RXN_C_CPU_TXN2: C1610.1 GPU1.B3
DGPU_RXN_C_CPU_TXN3: C1612.1 GPU1.B6
DGPU_RXP_C_CPU_TXP0: C1605.1 GPU1.A4
DGPU_RXP_C_CPU_TXP1: C1607.1 GPU1.A7
DGPU_RXP_C_CPU_TXP2: C1609.1 GPU1.B2
DGPU_RXP_C_CPU_TXP3: C1611.1 GPU1.B5
DMIC_CLK: C2723.2 EC5504.1 R2716.2 RN5503.4(B)
DMIC_CLK_C: RN5503.1(A) TCBD1.17
DMIC_CLK_R: HDA27.6 R2716.1
DMIC_DATA: EC5503.1 R2714.2 RN5503.3(B)
DMIC_DATA_C: RN5503.2(A) TCBD1.18
DMIC_DATA_R: EC2701.1 HDA27.5 R2714.1
DMIC_PCH_CLK: CPU1.H5 TP1906.1
DOCK_USB_EN_A: R3859.2 U3701.26
DOCK_USB_EN_B: R3860.2 U3701.36
DPB_AUXN: C3802.1 CPU1.E48
DPB_AUXN_C: C3802.2 R3801.2 U3801.25
DPB_AUXP: C3801.1 CPU1.F48
DPB_AUXP_C: C3801.2 R3802.2 U3801.24
DPEQ0_A1: R3871.2 R3872.1 U3801.14
DPEQ1: R3847.2 R3870.1 U3801.2
E71_TP: CPU1.E71 TP2313.1
EAPD#: HDA27.3 R2708.2
EC_AGND: C2407.2 C2408.2 C2422.2 C2435.2 C2441.2 KBC24.112 R2441.2 R2444.2 R2445.2
EC_SLP_S0IX#: KBC24.88 R2423.2
ECVBAT: C2428.1 KBC24.122 R2472.1
EDP_AUX: C5510.1 LCD1.12
EDP_AUX#: C5511.1 LCD1.13
EDP_AUX_DN: C5511.2 CPU1.E45
EDP_AUX_DP: C5510.2 CPU1.F45
EDP_COMP: CPU1.E52 R801.2
EDP_DISP_UTIL: CPU1.B52 TP801.1
EDP_HPD: CPU1.L10 RN5501.6(B) RN5502.7(B)
EDP_HPD_CONN: LCD1.27 RN5501.3(A)
EDP_TX0: C5509.1 LCD1.25
EDP_TX0#: C5506.1 LCD1.24
EDP_TX0_DN: C5506.2 CPU1.C47
EDP_TX0_DP: C5509.2 CPU1.C46
EDP_TX1: C5504.1 LCD1.22
EDP_TX1#: C5501.1 LCD1.21
EDP_TX1_DN: C5501.2 CPU1.D46
EDP_TX1_DP: C5504.2 CPU1.C45
EDP_TX2: C5519.1 LCD1.19
EDP_TX2#: C5533.1 LCD1.18
EDP_TX2_DN: C5533.2 CPU1.A45
EDP_TX2_DP: C5519.2 CPU1.B45
EDP_TX3: C5531.1 LCD1.16
EDP_TX3#: C5532.1 LCD1.15
EDP_TX3_DN: C5532.2 CPU1.A47
EDP_TX3_DP: C5531.2 CPU1.B47
EDP_VDD_EN: CPU1.U13 D5501.1
EDRAM_OPIO_RCOMP: CPU1.H66 R414.1
EMMC_RCOMP: CPU1.AT1 R1502.1
EOPIO_RCOMP: CPU1.H65 R415.1
EQ: R5411.2 R5412.2 U5701.17
EQ0: R3842.2 R3843.1 U3801.38
EQ1: R3840.2 R3841.1 U3801.35
ESPI_ALERT#: CPU1.AY11 KBC24.55 R1821.2 R6801.2
ESPI_ALERT#_ESPI: DB1.1 R6801.1
ESPI_CLK: EC1804.1 KBC24.57 R1806.2 R6807.2
ESPI_CLK_C: DB1.2 R6807.1
ESPI_CS#: CPU1.BA12 DB1.5 KBC24.58
ESPI_IO0: KBC24.59 R6806.2 RN1806.8(B)
ESPI_IO0_C: DB1.9 R6806.1
ESPI_IO1: KBC24.60 R6805.2 RN1806.7(B)
ESPI_IO1_C: DB1.8 R6805.1
ESPI_IO2: KBC24.61 R6804.2 RN1806.6(B)
ESPI_IO2_C: DB1.7 R6804.1
ESPI_IO3: KBC24.62 R6803.2 RN1806.5(B)
ESPI_IO3_C: DB1.6 R6803.1
ESPI_RESET#: CPU1.BA11 DB1.4 KBC24.53
EXT_PWR_GATE#: CPU1.AM10 R1731.2
FALL_INT2: Q7001.2 Q7001.3 R7018.2
FAN1_PWM: KBC24.47 R2614.1
FAN1_TACH: D2403.A KBC24.40 R2430.1
FAN_PWM1_C: AFTP2602.1 FAN1.4 R2614.2
FAN_TACH1: D2403.K R2613.1
FAN_TACH1_C: AFTP2601.1 FAN1.3 R2613.2
FAN_VCC_1: AFTP2603.1 C2603.1 C2604.1 C2605.1 D2601.K FAN1.1 R2612.2
FFS_INT1: CPU1.M3 R7012.1
FFS_INT2: CPU1.AC2 D7001.3 R2044.2 R7008.2
FFS_INT2_Q: Q7001.6 R6001.1
FFS_INT2_Q_R: HDD1.1 R6001.2
GC6_FB_EN: GPU1.C1 R2004.1
GC6_FB_EN_MCP: CPU1.AP7 R2004.2
GC6_THM_DIS#: CPU1.AB13 R2420.2
GC6_THM_DIS#_EC: KBC24.23 R2420.1 R2431.2 R2471.2
GPD2/LAN_WAKE#: CPU1.AM15 R1707.2 R1732.2
GPD11/LANPHYPC: CPU1.AW17 RN1704.5(B)
GPIO052/SPI_IO2: KBC24.42 TP2402.1
GPP_A10/CLKOUT_LPC1: CPU1.AY9 TP1808.1
GPP_E0/SATAXPCIE0/SATAGP0: CPU1.H2 TP1602.1
GPP_E1/SATAXPCIE1/SATAGP1: CPU1.H3 TP1603.1
GPU_EVENT#: GPU1.F10 R2003.1
GPU_EVENT_MCP#: CPU1.AN8 R2003.2
GPU_PWR_LEVEL: KBC24.10 R2474.2
GPU_THM_SMBCLK: KBC24.12 R2459.1
GPU_THM_SMBDAT: KBC24.11 R2447.1
GSEN2_INT1: R7009.2 R7012.2 U7001.12
GSEN2_INT1_C: R2025.2 R7009.1
GSEN2_INT1_ISH: CPU1.BA7 R2025.1 R2035.1
GSEN2_INT2: R7010.2 R7013.2 U7001.11
GSEN2_INT2_C: R2026.2 R7010.1
GSEN2_INT2_ISH: CPU1.AY7 R2026.1 R2033.1
GSEN_INT1: R2023.2 TCBD1.9
GSEN_INT1_ISH: CPU1.BA8 R2023.1 R2031.1
GSEN_INT2: R2024.2 TCBD1.10
GSEN_INT2_ISH: CPU1.BB7 R2024.1 R2032.1
GSENSOR_CS: R7006.1 U7001.2
GSENSOR_SDO: R7005.2 R7007.2 U7001.3
GT_CORE: CPU1.A48 CPU1.A53 CPU1.J43 CPU1.J45 CPU1.J46 CPU1.J48 CPU1.J50 CPU1.J52 CPU1.K48 CPU1.K50 R706.1 R707.2
GTX_CORE: CPU1.AK42 CPU1.AK43 CPU1.AK45 CPU1.AK46 CPU1.AK48 CPU1.AK50 CPU1.AL43 CPU1.AL46 CPU1.AL50 CPU1.AM48 CPU1.AM50 CPU1.AM52 R708.2
GYRO_DRDY: R2028.2 TCBD1.12
GYRO_DRDY_ISH: CPU1.AP13 R2028.1 R2034.1
GYRO_INT: R7002.2 R7003.2 TCBD1.11
GYRO_INT_C: R2027.2 R7003.1
GYRO_INT_ISH: CPU1.AW7 R2027.1 R2036.1
GYRO_INT_P11: D7001.1 R7002.1
H_CATERR#: CPU1.D63 TP401.1
H_CPU_SVIDALRT#: CPU1.B63 R728.2
H_CPU_SVIDCLK: CPU1.A63 R732.1
H_CPU_SVIDDAT: CPU1.D64 R709.1 R726.2
H_CPUPWRGD: CPU1.A68 ED1701.1 R1714.1 TP1705.1
H_PECI: C2405.1 KBC24.94 R2437.1
H_PECI_CPU: CPU1.A54 R2437.2
H_PROCHOT#: ED2401.1 PG4419.2 PR4445.2 PR4455.1 PR4624.2 PR4668.2 PR4669.2 Q2408.D R401.2 R403.1 R2418.2
H_PROCHOT#_R: CPU1.C65 R403.2
H_VCCST_PWRGD: C1711.1 CPU1.B65 ED1708.1 R1716.2 R1719.1
HDA_BITCLK: CPU1.AY22 RN1902.3(B)
HDA_CODEC_BITCLK: EC1901.2 EC2709.1 R2720.1 RN1902.2(A)
HDA_CODEC_SDIN0: HDA27.10 R2718.2
HDA_CODEC_SDOUT: EC2708.1 R2719.1 RN1902.1(A)
HDA_CODEC_SYNC: HDA27.9 R1908.1
HDA_RST#: CPU1.AW22 EC1902.1
HDA_SDIN0: CPU1.BA21 R2718.1
HDA_SDOUT: CPU1.BB22 R1909.2 RN1902.4(B)
HDA_SPKR_R: D2701.1 RN2701.3(B)
HDA_SYNC: CPU1.BA22 R1908.2
HDD_CT: C6007.1 U6002.6
HDD_DET#: CPU1.M1 TP1806.1
HDD_DEVSLP: CPU1.J1 R6002.1
HDD_DEVSLP_R: HDD1.13 R6002.2
HDD_EN: C6008.1 R6005.2 R6007.2 U6002.3
HDD_EN_PCH: CPU1.J4 R6007.1
HDMI_CLK: C5709.1 CPU1.G56
HDMI_CLK#: C5714.1 CPU1.F56
HDMI_CLK#_R: C5714.2 U5701.10
HDMI_CLK#_R_C: HDMI1.12 R5705.1 U5701.21
HDMI_CLK_R: C5709.2 U5701.9
HDMI_CLK_R_C: HDMI1.10 R5705.2 U5701.22
HDMI_DATA0: C5711.1 CPU1.G53
HDMI_DATA0#: C5708.1 CPU1.F53
HDMI_DATA0#_R: C5708.2 U5701.1
HDMI_DATA0#_R_C: HDMI1.9 R5703.2 U5701.30
HDMI_DATA0_R: C5711.2 U5701.2
HDMI_DATA0_R_C: HDMI1.7 R5703.1 U5701.29
HDMI_DATA1: C5712.1 CPU1.F58
HDMI_DATA1#: C5715.1 CPU1.E58
HDMI_DATA1#_R: C5715.2 U5701.4
HDMI_DATA1#_R_C: HDMI1.6 R5704.2 U5701.27
HDMI_DATA1_R: C5712.2 U5701.5
HDMI_DATA1_R_C: HDMI1.4 R5704.1 U5701.26
HDMI_DATA2: C5707.1 CPU1.F55
HDMI_DATA2#: C5710.1 CPU1.E55
HDMI_DATA2#_R: C5710.2 U5701.6
HDMI_DATA2#_R_C: HDMI1.3 R5702.2 U5701.25
HDMI_DATA2_R: C5707.2 U5701.7
HDMI_DATA2_R_C: HDMI1.1 R5702.1 U5701.24
HDMI_EC_DET#: KBC24.126 R5721.2 R5723.1
HDMI_EC_DET#_C: Q5704.3 Q5704.6 R5723.2
HOST_DEBUG_TX: DB3.5 KBC24.81 R2480.1 R6808.2
HOST_DEBUG_TX_CON: DB1.11 R6808.1
HPD_HDMI_CON: HDMI1.19 R5722.2 U5701.28
HPD_HDMI_CON_C: Q5704.2 R5722.1
HPDIN: R3821.2 U3801.32
HW_ACAV_IN: KBC24.128 PG4408.2 PQ4415.5
HW_ACAVIN_NB: KBC24.24 R2475.2
I2C0_SCL_R: AFTP6534.1 Q6504.6 R6505.2 RN6503.4(B) TP1.3
I2C0_SCL_TCH_PAD: CPU1.U6 EC6503.1 Q6504.1 R6505.1
I2C0_SCL_TCH_PNL: CPU1.U9 TP2028.1
I2C0_SDA_R: AFTP6535.1 Q6504.3 R6506.2 RN6503.3(B) TP1.2
I2C0_SDA_TCH_PAD: CPU1.U7 EC6504.1 Q6504.4 R6506.1
I2C0_SDA_TCH_PNL: CPU1.U8 TP2027.1
I2C1_SCL: CPU1.N2 RN2008.1(A)
I2C1_SDA: CPU1.N1 RN2008.2(A)
I2C_CLK_PD: R3814.1 RN3701.3(B) U3701.29
I2C_CLK_PD_MUX: R3814.2 U3801.21
I2C_DATA_PD: R3816.1 RN3701.4(B) U3701.28
I2C_DATA_PD_MUX: R3816.2 U3801.22
I2CEN: R3873.1 R3874.2 U3801.17
I_ADP_R: C2435.1 KBC24.110 R2421.2
I_BATT: C2441.1 KBC24.114 R2426.2
IC_DELAY: PC4307.1 U4302.4
ICSP_CLOCK: DB3.2 KBC24.101
ICSP_CLR: DB3.6 KBC24.87 R2414.1
ICSP_DATA: DB3.3 KBC24.102
IE_DELAY_G: PC4315.1 PQ4313.2 PQ4313.3 PR4343.2
IE_DELAY_S: PC4314.1 PQ4313.1 PR4344.2
ILIM_HI: R3404.2 U3401.16
ILIM_LO: R3403.2 U3401.15
ILIM_SEL: R3405.2 U3401.4
INT2_SELECT: D7001.2 Q7001.5 R7008.1 R7013.1
INT#_TYPEC: KBC24.32 R3731.1
INT#_TYPEC_R: R3707.2 R3731.2 U3701.15
IR_CAM_DET#: CPU1.P4 R2046.2 R5540.2
IR_CAMERA_DET#_R: R5540.1 TCBD1.22
ISET: R5413.2 R5414.2 U5701.34
ISH_I2C0_SCL: CPU1.N3 R2020.1 RN2007.1(A)
ISH_I2C0_SDA: CPU1.M4 R2021.1 RN2007.2(A)
ISH_KB_DISABLE: CPU1.AY8 Q2001.2
ISH_KB_DISABLE_R: Q2001.5 Q2001.6 R2001.2
ITP_PMODE: CPU1.E8 TP638.1
JACK_PLUG: ED2903.1 HPMIC1.5 R2923.1
JACK_PLUG_DET: ED2904.1 HPMIC1.6 R2905.1
JGND: AFTP4301.1 AFTP4302.1 DCIN1.1 DCIN1.2 DCIN1.3 EC4301.2 EC4302.2 EL4303.1 EL4304.1
KB_BL_CTRL#: AFTP6530.1 KBBL1.4 Q6501.D
KB_CLOSE#_2: C7001.1 GMR1.1 Q2415.S R2461.1 R7001.1
KB_DET#: CPU1.AD4 KB1.30 R2045.2
KB_LED_BL_DET: CPU1.W8 R6507.1 R6508.1
KB_LED_DET_C: C6504.1 KBBL1.2 R6507.2
KB_LED_PWM: KBC24.44 Q6501.G R6509.1
KBC_BEEP_R: D2701.2 RN2701.4(B)
KBC_PWRBTN#: EC6601.1 IOBD1.45 R2432.1
KSI0: AFTP6512.1 EC6505.1 KB1.22 KBC24.98 RN2403.8(B)
KSI1: AFTP6501.1 EC6507.1 KB1.24 KBC24.99 RN2403.7(B)
KSI2: AFTP6508.1 EC6509.1 KB1.26 KBC24.6 RN2403.6(B)
KSI3: AFTP6509.1 EC6506.1 KB1.23 KBC24.7 RN2403.5(B)
KSI4: AFTP6505.1 EC6510.1 KB1.27 KBC24.104 RN2404.5(B)
KSI5: AFTP6506.1 EC6508.1 KB1.25 KBC24.105 RN2404.6(B)
KSI6: AFTP6503.1 EC6511.1 KB1.28 KBC24.107 RN2404.7(B)
KSI7: AFTP6502.1 EC6512.1 KB1.29 KBC24.108 RN2404.8(B)
KSO0: AFTP6507.1 EC6524.1 KB1.13 KBC24.2 RN2412.8(B)
KSO1: AFTP6511.1 EC6526.1 KB1.15 KBC24.14 RN2412.7(B)
KSO2: AFTP6513.1 EC6523.1 KB1.14 KBC24.15 RN2412.6(B)
KSO3: AFTP6518.1 EC6522.1 KB1.16 KBC24.16 RN2412.5(B)
KSO4: AFTP6514.1 EC6521.1 KB1.20 KBC24.37 RN2409.8(B)
KSO5: AFTP6510.1 EC6529.1 KB1.21 KBC24.38 RN2409.7(B)
KSO6: AFTP6517.1 EC6527.1 KB1.18 KBC24.39 RN2409.6(B)
KSO7: AFTP6515.1 EC6528.1 KB1.19 KBC24.50 RN2409.5(B)
KSO8: AFTP6516.1 EC6525.1 KB1.17 KBC24.46 RN2410.8(B)
KSO9: AFTP6504.1 EC6518.1 KB1.7 KBC24.68 R2449.2 R2450.1
KSO10: AFTP6523.1 EC6516.1 KB1.5 KBC24.72 RN2410.7(B)
KSO11: AFTP6522.1 EC6515.1 KB1.6 KBC24.74 RN2410.6(B)
KSO12: AFTP6519.1 EC6513.1 KB1.12 KBC24.75 RN2410.5(B)
KSO13: AFTP6520.1 EC6517.1 KB1.9 KBC24.76 RN2411.8(B)
KSO14: AFTP6521.1 EC6514.1 KB1.8 KBC24.77 RN2411.7(B)
KSO15: AFTP6524.1 EC6519.1 KB1.10 KBC24.86 RN2411.6(B)
KSO16: AFTP6539.1 EC6520.1 KB1.11 KBC24.92 RN2411.5(B)
L_BKLT_CTRL: CPU1.R11 D5502.1 R5502.2
L_BKLT_EN: CPU1.R12 R2435.2 R5512.2
L_BKLT_EN_C: D5503.2 R5512.1
L_BKLT_EN_EC: R2422.1 R2435.1 R2436.1
LANWAKE#: KBC24.35 R1732.1
LCD_BRIGHTNESS: EC5501.1 LCD1.30 RN5501.4(A)
LCD_TST: D5502.2 KBC24.26 RN5501.8(B)
LCD_TST_C: LCD1.29 RN5501.1(A)
LCD_VCC_TEST_EN: D5501.2 KBC24.113
LCDVDD: C5505.1 C5507.1 C5508.2 LCD1.6 LCD1.7 LCD1.8 LCD1.9 U5501.3
LDO1_CAP: C2702.2 HDA27.39 R2711.2
LDO2_CAP: C2712.2 HDA27.17
LDO3_CAP: C2718.1 HDA27.13
LID_CL_SIO#: D2402.K GMR1.4 KBC24.66 R7011.1 RN2405.3(A)
LID_CL_SIO_TAB#: KBC24.97 Q2415.D R2461.2 R2496.1
LINE1-L_C: C2907.2 R2922.1
LINE1-L_R: C2908.2 R2921.1
LINE1_L: C2907.1 HDA27.34
LINE1_R: C2908.1 HDA27.33
LINE1_VREFO_L: HDA27.14 R2912.1
LINE1_VREFO_R: HDA27.15 R2913.1
LVDS_VDD_EN_R: D5501.3 RN5502.5(B) U5501.1
M2_SSD_PEDET: CPU1.G4 R6310.1
M_A_A0: CPU1.AY50 DM1.144
M_A_A1: CPU1.BB50 DM1.133
M_A_A2: CPU1.AY51 DM1.132
M_A_A3: CPU1.BA50 DM1.131
M_A_A4: CPU1.BB52 DM1.128
M_A_A5: CPU1.BA51 DM1.126
M_A_A6: CPU1.BA52 DM1.127
M_A_A7: CPU1.AW52 DM1.122
M_A_A8: CPU1.AY52 DM1.125
M_A_A9: CPU1.BB54 DM1.121
M_A_A10: CPU1.AT50 DM1.146
M_A_A11: CPU1.BA54 DM1.120
M_A_A12: CPU1.AW54 DM1.119
M_A_A13: CPU1.AU46 DM1.158
M_A_A14: CPU1.AT46 DM1.151
M_A_A15: CPU1.AU48 DM1.156
M_A_A16: CPU1.AU50 DM1.152
M_A_ACT_N: CPU1.BA55 DM1.114
M_A_ALERT_N: CPU1.AW50 DM1.116
M_A_BA0: CPU1.AU52 DM1.150
M_A_BA1: CPU1.AT48 DM1.145
M_A_BG0: CPU1.AY55 DM1.115
M_A_BG1: CPU1.AY54 DM1.113
M_A_CKE0: CPU1.BA56 DM1.109
M_A_CKE1: CPU1.BB56 DM1.110
M_A_CLK0: CPU1.AT53 DM1.137
M_A_CLK1: CPU1.AT55 DM1.138
M_A_CLK#0: CPU1.AU53 DM1.139
M_A_CLK#1: CPU1.AU55 DM1.140
M_A_CS#0: CPU1.AU45 DM1.149
M_A_CS#1: CPU1.AU43 DM1.157
M_A_DIMA_ODT0: CPU1.AT45 DM1.155
M_A_DIMA_ODT1: CPU1.AT43 DM1.161
M_A_DQ0: CPU1.AL71 DM1.8
M_A_DQ1: CPU1.AL68 DM1.7
M_A_DQ2: CPU1.AN68 DM1.20
M_A_DQ3: CPU1.AN69 DM1.21
M_A_DQ4: CPU1.AL70 DM1.4
M_A_DQ5: CPU1.AL69 DM1.3
M_A_DQ6: CPU1.AN70 DM1.16
M_A_DQ7: CPU1.AN71 DM1.17
M_A_DQ8: CPU1.AR70 DM1.28
M_A_DQ9: CPU1.AR68 DM1.29
M_A_DQ10: CPU1.AU71 DM1.41
M_A_DQ11: CPU1.AU68 DM1.42
M_A_DQ12: CPU1.AR71 DM1.24
M_A_DQ13: CPU1.AR69 DM1.25
M_A_DQ14: CPU1.AU70 DM1.38
M_A_DQ15: CPU1.AU69 DM1.37
M_A_DQ16: CPU1.BB65 DM1.50
M_A_DQ17: CPU1.AW65 DM1.49
M_A_DQ18: CPU1.AW63 DM1.62
M_A_DQ19: CPU1.AY63 DM1.63
M_A_DQ20: CPU1.BA65 DM1.46
M_A_DQ21: CPU1.AY65 DM1.45
M_A_DQ22: CPU1.BA63 DM1.58
M_A_DQ23: CPU1.BB63 DM1.59
M_A_DQ24: CPU1.BA61 DM1.70
M_A_DQ25: CPU1.AW61 DM1.71
M_A_DQ26: CPU1.BB59 DM1.83
M_A_DQ27: CPU1.AW59 DM1.84
M_A_DQ28: CPU1.BB61 DM1.66
M_A_DQ29: CPU1.AY61 DM1.67
M_A_DQ30: CPU1.BA59 DM1.79
M_A_DQ31: CPU1.AY59 DM1.80
M_A_DQ32: CPU1.AY39 DM1.174
M_A_DQ33: CPU1.AW39 DM1.173
M_A_DQ34: CPU1.AY37 DM1.187
M_A_DQ35: CPU1.AW37 DM1.186
M_A_DQ36: CPU1.BB39 DM1.170
M_A_DQ37: CPU1.BA39 DM1.169
M_A_DQ38: CPU1.BA37 DM1.183
M_A_DQ39: CPU1.BB37 DM1.182
M_A_DQ40: CPU1.AY35 DM1.195
M_A_DQ41: CPU1.AW35 DM1.194
M_A_DQ42: CPU1.AY33 DM1.207
M_A_DQ43: CPU1.AW33 DM1.208
M_A_DQ44: CPU1.BB35 DM1.191
M_A_DQ45: CPU1.BA35 DM1.190
M_A_DQ46: CPU1.BA33 DM1.203
M_A_DQ47: CPU1.BB33 DM1.204
M_A_DQ48: CPU1.AY31 DM1.216
M_A_DQ49: CPU1.AW31 DM1.215
M_A_DQ50: CPU1.AY29 DM1.228
M_A_DQ51: CPU1.AW29 DM1.229
M_A_DQ52: CPU1.BB31 DM1.211
M_A_DQ53: CPU1.BA31 DM1.212
M_A_DQ54: CPU1.BA29 DM1.224
M_A_DQ55: CPU1.BB29 DM1.225
M_A_DQ56: CPU1.AY27 DM1.237
M_A_DQ57: CPU1.AW27 DM1.236
M_A_DQ58: CPU1.AY25 DM1.249
M_A_DQ59: CPU1.AW25 DM1.250
M_A_DQ60: CPU1.BB27 DM1.232
M_A_DQ61: CPU1.BA27 DM1.233
M_A_DQ62: CPU1.BA25 DM1.245
M_A_DQ63: CPU1.BB25 DM1.246
M_A_DQS_DN0: CPU1.AM70 DM1.11
M_A_DQS_DN1: CPU1.AT69 DM1.32
M_A_DQS_DN2: CPU1.BA64 DM1.53
M_A_DQS_DN3: CPU1.AY60 DM1.74
M_A_DQS_DN4: CPU1.BA38 DM1.177
M_A_DQS_DN5: CPU1.AY34 DM1.198
M_A_DQS_DN6: CPU1.BA30 DM1.219
M_A_DQS_DN7: CPU1.AY26 DM1.240
M_A_DQS_DP0: CPU1.AM69 DM1.13
M_A_DQS_DP1: CPU1.AT70 DM1.34
M_A_DQS_DP2: CPU1.AY64 DM1.55
M_A_DQS_DP3: CPU1.BA60 DM1.76
M_A_DQS_DP4: CPU1.AY38 DM1.179
M_A_DQS_DP5: CPU1.BA34 DM1.200
M_A_DQS_DP6: CPU1.AY30 DM1.221
M_A_DQS_DP7: CPU1.BA26 DM1.242
M_A_PARITY: CPU1.AT52 DM1.143
M_B_A0: CPU1.BA46 DM2.144
M_B_A1: CPU1.AY46 DM2.133
M_B_A2: CPU1.AY47 DM2.132
M_B_A3: CPU1.BB46 DM2.131
M_B_A4: CPU1.BA47 DM2.128
M_B_A5: CPU1.AY48 DM2.126
M_B_A6: CPU1.BA48 DM2.127
M_B_A7: CPU1.AP48 DM2.122
M_B_A8: CPU1.BB48 DM2.125
M_B_A9: CPU1.AP50 DM2.121
M_B_A10: CPU1.AW46 DM2.146
M_B_A11: CPU1.AN48 DM2.120
M_B_A12: CPU1.AN50 DM2.119
M_B_A13: CPU1.BA43 DM2.158
M_B_A14: CPU1.AY44 DM2.151
M_B_A15: CPU1.AY43 DM2.156
M_B_A16: CPU1.AW44 DM2.152
M_B_ACT_N: CPU1.AN53 DM2.114
M_B_ALERT_N: CPU1.AN43 DM2.116
M_B_BA0: CPU1.BB44 DM2.150
M_B_BA1: CPU1.BA44 DM2.145
M_B_BG0: CPU1.AP52 DM2.115
M_B_BG1: CPU1.AN52 DM2.113
M_B_CKE0: CPU1.AN56 DM2.109
M_B_CKE1: CPU1.AP55 DM2.110
M_B_CLK0: CPU1.AP45 DM2.137
M_B_CLK1: CPU1.AP46 DM2.138
M_B_CLK#0: CPU1.AN45 DM2.139
M_B_CLK#1: CPU1.AN46 DM2.140
M_B_CS#0: CPU1.BB42 DM2.149
M_B_CS#1: CPU1.AY42 DM2.157
M_B_DIMB_ODT0: CPU1.BA42 DM2.155
M_B_DIMB_ODT1: CPU1.AW42 DM2.161
M_B_DQ0: CPU1.AF65 DM2.28
M_B_DQ1: CPU1.AF64 DM2.29
M_B_DQ2: CPU1.AK65 DM2.41
M_B_DQ3: CPU1.AK64 DM2.42
M_B_DQ4: CPU1.AF66 DM2.24
M_B_DQ5: CPU1.AF67 DM2.25
M_B_DQ6: CPU1.AK67 DM2.38
M_B_DQ7: CPU1.AK66 DM2.37
M_B_DQ8: CPU1.AF70 DM2.8
M_B_DQ9: CPU1.AF68 DM2.7
M_B_DQ10: CPU1.AH71 DM2.20
M_B_DQ11: CPU1.AH68 DM2.21
M_B_DQ12: CPU1.AF71 DM2.4
M_B_DQ13: CPU1.AF69 DM2.3
M_B_DQ14: CPU1.AH70 DM2.16
M_B_DQ15: CPU1.AH69 DM2.17
M_B_DQ16: CPU1.AT66 DM2.50
M_B_DQ17: CPU1.AU66 DM2.49
M_B_DQ18: CPU1.AP65 DM2.62
M_B_DQ19: CPU1.AN65 DM2.63
M_B_DQ20: CPU1.AN66 DM2.46
M_B_DQ21: CPU1.AP66 DM2.45
M_B_DQ22: CPU1.AT65 DM2.58
M_B_DQ23: CPU1.AU65 DM2.59
M_B_DQ24: CPU1.AT61 DM2.70
M_B_DQ25: CPU1.AU61 DM2.71
M_B_DQ26: CPU1.AP60 DM2.83
M_B_DQ27: CPU1.AN60 DM2.84
M_B_DQ28: CPU1.AN61 DM2.66
M_B_DQ29: CPU1.AP61 DM2.67
M_B_DQ30: CPU1.AT60 DM2.79
M_B_DQ31: CPU1.AU60 DM2.80
M_B_DQ32: CPU1.AU40 DM2.174
M_B_DQ33: CPU1.AT40 DM2.173
M_B_DQ34: CPU1.AT37 DM2.187
M_B_DQ35: CPU1.AU37 DM2.186
M_B_DQ36: CPU1.AR40 DM2.170
M_B_DQ37: CPU1.AP40 DM2.169
M_B_DQ38: CPU1.AP37 DM2.183
M_B_DQ39: CPU1.AR37 DM2.182
M_B_DQ40: CPU1.AT33 DM2.195
M_B_DQ41: CPU1.AU33 DM2.194
M_B_DQ42: CPU1.AU30 DM2.207
M_B_DQ43: CPU1.AT30 DM2.208
M_B_DQ44: CPU1.AR33 DM2.191
M_B_DQ45: CPU1.AP33 DM2.190
M_B_DQ46: CPU1.AR30 DM2.203
M_B_DQ47: CPU1.AP30 DM2.204
M_B_DQ48: CPU1.AU27 DM2.216
M_B_DQ49: CPU1.AT27 DM2.215
M_B_DQ50: CPU1.AT25 DM2.228
M_B_DQ51: CPU1.AU25 DM2.229
M_B_DQ52: CPU1.AP27 DM2.211
M_B_DQ53: CPU1.AN27 DM2.212
M_B_DQ54: CPU1.AN25 DM2.224
M_B_DQ55: CPU1.AP25 DM2.225
M_B_DQ56: CPU1.AT22 DM2.237
M_B_DQ57: CPU1.AU22 DM2.236
M_B_DQ58: CPU1.AU21 DM2.249
M_B_DQ59: CPU1.AT21 DM2.250
M_B_DQ60: CPU1.AN22 DM2.232
M_B_DQ61: CPU1.AP22 DM2.233
M_B_DQ62: CPU1.AP21 DM2.245
M_B_DQ63: CPU1.AN21 DM2.246
M_B_DQS_DN0: CPU1.AH66 DM2.32
M_B_DQS_DN1: CPU1.AG69 DM2.11
M_B_DQS_DN2: CPU1.AR66 DM2.53
M_B_DQS_DN3: CPU1.AR61 DM2.74
M_B_DQS_DN4: CPU1.AT38 DM2.177
M_B_DQS_DN5: CPU1.AT32 DM2.198
M_B_DQS_DN6: CPU1.AR25 DM2.219
M_B_DQS_DN7: CPU1.AR22 DM2.240
M_B_DQS_DP0: CPU1.AH65 DM2.34
M_B_DQS_DP1: CPU1.AG70 DM2.13
M_B_DQS_DP2: CPU1.AR65 DM2.55
M_B_DQS_DP3: CPU1.AR60 DM2.76
M_B_DQS_DP4: CPU1.AR38 DM2.179
M_B_DQS_DP5: CPU1.AR32 DM2.200
M_B_DQS_DP6: CPU1.AR27 DM2.221
M_B_DQS_DP7: CPU1.AR21 DM2.242
M_B_PARITY: CPU1.AP43 DM2.143
M_VREF_CA_DIMMA: C1229.1 DM1.164 R1206.1 RN1201.3(B) RN1201.4(B)
M_VREF_CA_DIMMB: C1301.1 DM2.164 R1305.1 RN1301.3(B) RN1301.4(B)
MASK_SATA_LED#: KBC24.56 Q6403.G R6120.2
ME_FWP_EC: KBC24.80 R1909.1
ME_SUS_PWR_ACK_R: CPU1.AR13 R1708.1 R1739.2
MEC_XTAL1_R: C2425.2 KBC24.123 X2401.1
MEC_XTAL2: C2424.2 KBC24.125 R2425.2 X2401.2
MEM_CHB_EN: CPU1.AD11 TP2007.1
MEM_CONFIG0: CPU1.AH9 TP2020.1
MEM_SMBCLK: CPU1.R7 Q1801.3 RN1811.4(B)
MEM_SMBDATA: CPU1.R8 Q1801.6 RN1811.3(B)
MIC2_VREFO_L: HDA27.27 RN2901.2(A)
MIC2_VREFO_R: HDA27.28 RN2901.1(A)
MIC_CAP: C2713.1 HDA27.31
MIC_GND: R5501.1 TCBD1.19
MODEL_ID: C2407.1 KBC24.109 R2441.1 R2442.2
MSATA_CLK_CPU: CPU1.A40 SSD1.55
MSATA_CLK_CPU#: CPU1.B40 SSD1.53
MSATA_DEVSLP_R: AFTP6302.1 R6301.2 SSD1.38
MSATA_RST#: ED6305.1 R6308.2 SSD1.50
MSM#: CPU1.AP56 TP617.1
MUX_ENA_L: R3859.1 U3802.16
MUX_ENB_L: R3860.1 U3802.10
MUX_INB_N: R3854.2 U3802.3
MUX_INB_P: R3853.2 U3802.4
MUX_SAI: R3855.2 U3802.14
MUX_SAO: R3857.2 U3802.15
MUX_SBI: R3856.2 U3802.12
MUX_SBO: R3858.2 U3802.11
MUX_TYPEC_RXN1: R3835.1 U3801.31
MUX_TYPEC_RXN2: R3837.1 U3801.39
MUX_TYPEC_RXP1: R3834.1 U3801.30
MUX_TYPEC_RXP2: R3836.1 U3801.40
MUX_TYPEC_TXN1: C3863.1 U3801.34
MUX_TYPEC_TXN1_C: C3863.2 R3833.1
MUX_TYPEC_TXN2: C3862.1 U3801.36
MUX_TYPEC_TXN2_C: C3862.2 R3839.1
MUX_TYPEC_TXP1: C3864.1 U3801.33
MUX_TYPEC_TXP1_C: C3864.2 R3832.1
MUX_TYPEC_TXP2: C3861.1 U3801.37
MUX_TYPEC_TXP2_C: C3861.2 R3838.1
NB_MODE#: KBC24.96 Q2001.3 R2050.1
NB_MUTE#: KBC24.119 R2708.1 R2728.1
NCT7718_DXN: C2606.2 C2607.2 Q2603.2 THM261.3
NCT7718_DXP: C2606.1 C2607.1 Q2603.1 Q2603.3 THM261.2
NRB_BIT: CPU1.AR7 R2007.2 R2019.1
OVER_CURRENT_P8#: GPU1.C2 R2474.1
P_SYS: PC4430.1 PG4415.2 PR4401.1 PR4671.1
PANEL_BKEN_EC: KBC24.117 R5515.2
PANEL_BKEN_EC_C: D5503.1 R5515.1
PBAT_CHG_SMBCLK: D4306.3 EC4309.1 KBC24.9 PG4410.1 PR4439.2 RN2402.3(B) RN4302.3(A)
PBAT_CHG_SMBDAT: D4305.3 EC4310.1 KBC24.8 PG4409.1 PR4438.2 RN2402.4(B) RN4302.2(A)
PBAT_PRES1#: AFTP4309.1 BATT1.6 RN4302.8(B)
PBAT_PRES#: D4304.3 EC4306.2 KBC24.29 PQ4313.5 R2415.1 RN4302.1(A)
PBAT_SMBCLK1: AFTP4311.1 BATT1.4 RN4302.6(B)
PBAT_SMBDAT1: AFTP4310.1 BATT1.5 RN4302.7(B)
PCH_BATLOW#: CPU1.AU13 RN1704.6(B)
PCH_DPC_N0: C3813.1 CPU1.C50
PCH_DPC_N0_C: C3813.2 U3801.10
PCH_DPC_N1: C3807.1 CPU1.C52
PCH_DPC_N1_C: C3807.2 U3801.13
PCH_DPC_N2: C3808.1 CPU1.A50
PCH_DPC_N2_C: C3808.2 U3801.16
PCH_DPC_N3: C3810.1 CPU1.D51
PCH_DPC_N3_C: C3810.2 U3801.19
PCH_DPC_P0: C3812.1 CPU1.D50
PCH_DPC_P0_C: C3812.2 U3801.9
PCH_DPC_P1: C3814.1 CPU1.D52
PCH_DPC_P1_C: C3814.2 U3801.12
PCH_DPC_P2: C3809.1 CPU1.B50
PCH_DPC_P2_C: C3809.2 U3801.15
PCH_DPC_P3: C3811.1 CPU1.C51
PCH_DPC_P3_C: C3811.2 U3801.18
PCH_DPWROK: CPU1.BB20 ED1711.1 R1704.2 R1718.1
PCH_ESPI_CLK: CPU1.AW9 R1806.1
PCH_ESPI_IO0: CPU1.AY13 RN1806.1(A)
PCH_ESPI_IO1: CPU1.BA13 RN1806.2(A)
PCH_ESPI_IO2: CPU1.BB13 RN1806.3(A)
PCH_ESPI_IO3: CPU1.AY12 RN1806.4(A)
PCH_JTAG_TCK: CPU1.B56 R407.1
PCH_JTAG_TDI: CPU1.D59 R408.1
PCH_JTAG_TDO: CPU1.A56 R409.1
PCH_JTAG_TMS: CPU1.C59 R416.1
PCH_PLTRST#: CPU1.AN10 R1713.2
PCH_POPIRCOMP: CPU1.AU16 R413.1
PCH_RSMRST#: EC1712.1 KBC24.27 R1702.2 TP2406.1
PCH_SMBCLK: DM1.253 DM2.253 Q1801.4 RN1810.4(B)
PCH_SMBDATA: DM1.254 DM2.254 Q1801.1 RN1810.3(B)
PCH_SPI_CS2#: CPU1.AU1 R1826.2
PCH_THERMTRIP#: CPU1.C63 ED401.1 R419.2
PCH_WAKE#: CPU1.BB15 RN1704.7(B)
PCIE_CLK_XDP_N: CPU1.F43 TP1802.1
PCIE_CLK_XDP_P: CPU1.E43 TP1803.1
PCIE_RCOMPN: CPU1.F5 R1604.1
PCIE_RCOMPP: CPU1.E5 R1604.2
PCIE_RX_CPU_N6: CPU1.G18 IOBD1.8
PCIE_RX_CPU_N9: CPU1.E22 SSD1.7 U6303.2 U6303.9
PCIE_RX_CPU_N10: CPU1.F25 SSD1.19 U6304.2 U6304.9
PCIE_RX_CPU_N11: CPU1.E28 SSD1.29 U6302.1 U6302.10
PCIE_RX_CPU_P6: CPU1.F18 IOBD1.7
PCIE_RX_CPU_P9: CPU1.E23 SSD1.5 U6303.1 U6303.10
PCIE_RX_CPU_P10: CPU1.E25 SSD1.17 U6304.1 U6304.10
PCIE_RX_CPU_P11: CPU1.E27 SSD1.31 U6302.2 U6302.9
PCIE_TX_CPU_N6: C1601.2 CPU1.D20
PCIE_TX_CPU_N9: C6314.2 CPU1.B23
PCIE_TX_CPU_N9_C: C6314.1 SSD1.11 U6303.4 U6303.7
PCIE_TX_CPU_N10: C6316.2 CPU1.D23
PCIE_TX_CPU_N10_C: C6316.1 SSD1.23 U6304.4 U6304.7
PCIE_TX_CPU_N11: C6312.2 CPU1.D24
PCIE_TX_CPU_N11_C: C6312.1 SSD1.35 U6302.4 U6302.7
PCIE_TX_CPU_P6: C1602.2 CPU1.C20
PCIE_TX_CPU_P9: C6313.2 CPU1.A23
PCIE_TX_CPU_P9_C: C6313.1 SSD1.13 U6303.5 U6303.6
PCIE_TX_CPU_P10: C6315.2 CPU1.C23
PCIE_TX_CPU_P10_C: C6315.1 SSD1.25 U6304.5 U6304.6
PCIE_TX_CPU_P11: C6311.2 CPU1.C24
PCIE_TX_CPU_P11_C: C6311.1 SSD1.37 U6302.5 U6302.6
PCIE_TX_WLAN_N6: C1601.1 IOBD1.10
PCIE_TX_WLAN_P6: C1602.1 IOBD1.11
PCIE_WAKE#: KBC24.4 TP2407.1
PD4403_A: PD4404.A PQ4408.1
PD4403_K: PD4404.K PR4458.1
PD_CC1: R3728.1 U3701.9
PD_CC2: R3727.1 U3701.7
PD_SWD_CLK: R3736.1 U3701.2
PD_SWD_IO: R3736.2 U3701.1
PD_VBUS_C_CTRL1: PQ4312.G PR4325.1 U3701.12
PD_VBUS_C_CTRL1_A: PC4311.1 PQ4306.D PQ4307.5 PQ4307.6 PQ4311.3 PQ4313.6 PR4319.2
PD_VBUS_C_CTRL1_R: PQ4307.2 PQ4312.D PR4323.1 PR4342.2
PD_VBUS_DISCHG: PQ4310.2 PR4332.1 U3701.20
PD_VBUS_P_CTRL1: PD4310.A PR4310.1 U3701.11
PD_VBUS_P_CTRL1_R: PQ4309.5 PR4310.2 PR4324.1
PD_VBUS_R: C3717.2 R3726.2 R3730.2 U3701.13
PD_VCCD: C3715.1 U3701.33
PD_XRES: C3716.1 R3724.2 TP3703.1 U3701.10
PEG_CLK1_CPU: CPU1.A42 IOBD1.14
PEG_CLK1_CPU#: CPU1.B42 IOBD1.13
PEG_TX_CPU_N0: C1606.2 CPU1.B17
PEG_TX_CPU_N1: C1608.2 CPU1.D16
PEG_TX_CPU_N2: C1610.2 CPU1.D17
PEG_TX_CPU_N3: C1612.2 CPU1.B19
PEG_TX_CPU_P0: C1605.2 CPU1.A17
PEG_TX_CPU_P1: C1607.2 CPU1.C16
PEG_TX_CPU_P2: C1609.2 CPU1.C17
PEG_TX_CPU_P3: C1611.2 CPU1.A19
PG_1: PG4402.2 PR4444.1
PG_2: PG4403.2 PR4414.1
PIRQA#: CPU1.BB11 R1607.2
PLT_RST#: C1701.1 EC6602.1 ED1703.1 GPU1.D1 IOBD1.43 R1713.1 R1715.1 R6308.1 R9136.1
PLT_RST#_Q_TPM2: R9136.2 U9104.17
PM_PCH_PWROK: CPU1.BA20 R1706.2 RN1703.3(B)
PM_RSMRST#: CPU1.AY17 Q1701.3 R1702.1 R1704.1 R1720.2 RN1703.4(B)
PM_RSMRST#_M: Q1702.5 Q1702.6 R1737.2
PM_RSMRST#_R: Q1702.2 R1720.1
PME#: CPU1.AU11 TP1707.1
POWER_SW_IN#: C2426.1 KBC24.127 R2432.2 R2451.1
PQ3802_1: PQ4302.1 PR4302.1 PR4309.2
PQ4405_2: PQ4405.2 PR4463.1 R4462.1
PQ4405_3: PQ4405.3 PR4455.2
PQ4405_5: PC4438.1 PQ4405.5 PR4413.2
PQ4405_6: PC4438.2 PQ4405.6 PR4450.1
PQ4408_C: PQ4408.3 PR4451.1 R4462.2
PQ4408_E: PQ4408.2 PR4431.2 PR4436.1
PR_2: PC4432.1 PR4416.2
PRE: R5415.2 R5416.2 U5701.16
PROC_SELECT#: CPU1.C64 R603.1
PROCHOT: KBC24.83 Q2408.G R2417.1 R2418.1
PROJECT_ID0: CPU1.AK6 R1914.2 R1915.1
PROJECT_ID1: CPU1.AK7 R1916.1 R1917.2
PROJECT_ID2: CPU1.AK9 R1918.1 R1919.2
PROJECT_ID3: CPU1.AK10 R1920.1 R1921.2
PS_ID: KBC24.36 PD4302.3 PR4304.2 PR4305.2
PS_ID_R: AFTP4304.1 DCIN1.4 PR4317.1
PS_ID_R1: PQ4301.S PR4305.1 PR4306.2
PS_ID_R2: PD4303.1 PD4303.2 PQ4301.D PR4306.1 PR4309.1 PR4317.2
PSID_DISABLE#_R_C: PQ4301.G PQ4302.3 PR4303.2
PSYS: PR4671.2 PR4682.1 PU4601.46
PTP_DIS#_R: AFTP6537.1 KBC24.90 TP1.6
PURE_HW_SHUTDOWN#: C2610.1 D4001.3 Q2602.D R2615.1
PWR_0D6V_S3EN: PC5120.1 PR5125.2 PR5126.2 PU5102.7
PWR_0D6V_S5EN: PC5119.1 PR5114.2 PU5102.9
PWR_0D6V_VCNTL: PC5111.1 PR5118.2 PU5102.10
PWR_1D0V_BT: PC5204.1 PU5201.20
PWR_1D0V_EN: PC5215.1 PR5210.2 PU5201.2
PWR_1D0V_FB: PC5212.2 PR5202.2 PR5204.1 PU5201.5
PWR_1D0V_FB_A: PC5212.1 PG5223.1 PR5202.1
PWR_1D0V_PFM: PR5203.1 PU5201.3
PWR_1D0V_PG: PR5208.2 PR5209.2 PU5201.1
PWR_1D0V_PH: PC5204.2 PL5201.1 PU5201.10 PU5201.11 PU5201.16 PU5201.17 PU5201.18
PWR_1D0V_SS: PC5213.1 PU5201.22
PWR_1D0V_TON: PR5201.2 PU5201.6
PWR_1D2V_BOOT: PR5101.1 PU5101.1
PWR_1D2V_BOOT_R: PC5117.1 PR5101.2
PWR_1D2V_BYP: PC5110.1 PR5102.1 PU5101.15
PWR_1D2V_EN: PC5138.1 PR5105.2 PR5127.1 PU5101.11
PWR_1D2V_IMAX: PR5106.2 PU5101.13
PWR_1D2V_LDO_P5: PC5113.1 PU5101.16 PU5101.17
PWR_1D2V_PGOOD: PR5107.2 PU5101.9 PU5101.10
PWR_1D2V_PHASE: PC5117.2 PL5101.1 PU5101.6 PU5101.19 PU5101.20
PWR_1D2V_VFB: PC5112.2 PR5103.2 PR5104.1 PU5101.14
PWR_1D2V_VFB_R: PC5112.1 PG5113.2 PR5103.1
PWR_1D5V_EN: PC5407.1 PR5405.2 PU5402.3
PWR_1D8V_EN: PC5406.1 PR5401.1 PR5406.2 PU5401.8
PWR_1D8V_POK: PR5408.2 PU5401.7
PWR_2D5V: PC5411.1 PC5412.1 PC5413.1 PG5408.1 PG5409.1 PR5419.1 PU5403.3 PU5403.4
PWR_2D5V_EN: PC5427.1 PR5409.1 PR5417.2 PU5403.8
PWR_2D5V_FB: PC5411.2 PR5419.2 PR5420.1 PU5403.2
PWR_2D5V_PG: PR5105.1 PR5114.1 PR5410.2 PU5403.7
PWR_3D3V: PC4509.1 PC4510.1 PC4511.1 PC4512.1 PC4513.1 PC4525.1 PG4519.1 PG4520.1 PG4521.1 PG4522.1 PG4523.1 PG4524.1 PG4530.2 PL4501.2
PWR_3D3V_BOOT: PR4501.1 PU4501.1
PWR_3D3V_BOOT_A: PC4506.1 PR4501.2
PWR_3D3V_EN: PC4508.1 PR4508.1 PR4509.2 PU4501.11
PWR_3D3V_EN1: PC4532.1 PR4514.1 PR4516.2 PU4501.12
PWR_3D3V_FB: PC4533.1 PU4501.13
PWR_3D3V_FB2: PC4533.2 PR4506.2
PWR_3D3V_LDO: PC4507.1 PG4532.1 PU4501.16 PU4501.17
PWR_3D3V_PH: PC4506.2 PL4501.1 PU4501.6 PU4501.19 PU4501.20
PWR_3D3V_VOUT: PG4530.1 PR4506.1 PU4501.14
PWR_3V_PG: PG4531.2 PR4505.2 PU4501.9 PU4501.10
PWR_5V: PC4514.1 PC4515.1 PC4516.1 PC4517.1 PC4518.1 PC4527.1 PC4528.1 PC4529.1 PG4507.1 PG4508.1 PG4509.1 PG4510.1 PG4511.1 PG4512.1 PG4513.1 PG4514.1 PG4527.2 PL4502.2
PWR_5V_BOOT: PR4502.1 PU4502.1
PWR_5V_BOOT_A: PC4521.1 PR4502.2
PWR_5V_EN: PC4530.1 PR4511.2 PR4512.1 PU4502.11
PWR_5V_EN1: PC4531.1 PR4504.2 PR4513.1 PU4502.12
PWR_5V_EN1_R: PR4503.2 PR4504.1 PR4515.2 PR4530.1
PWR_5V_FB: PC4526.1 PR4551.1 PU4502.13
PWR_5V_FB_A: PC4526.2 PR4507.1
PWR_5V_LDO: PC4520.1 PG4528.1 PU4502.15
PWR_5V_PG: PG4529.2 PR4510.1 PU4502.9 PU4502.10
PWR_5V_PH: PC4521.2 PL4502.1 PU4502.6 PU4502.19 PU4502.20
PWR_5V_VCC: PC4524.1 PU4502.16 PU4502.17
PWR_5V_VOUT: PG4527.1 PR4507.2 PU4502.14
PWR_ASGATE: PC4436.2 PU4401.30
PWR_CHG_1: PD4401.K PD4402.K PD4405.K PR4407.2
PWR_CHG_ACDET: PC4413.1 PR4408.2 PR4409.1 PU4401.1
PWR_CHG_ACN: PC4402.2 PC4404.1 PR4414.2 PU4401.31
PWR_CHG_ACOK: PG4408.1 PR4422.2 PR4443.2 PR4463.2 PU4401.2
PWR_CHG_ACP: PC4402.1 PC4403.1 PR4444.2 PU4401.32
PWR_CHG_BATDRV: PC4437.2 PU4401.25
PWR_CHG_BATPRES#: PR4449.1 PU4401.13
PWR_CHG_BTST: PR4447.1 PU4401.24
PWR_CHG_BTST1: PC4414.1 PR4447.2
PWR_CHG_COMP: PC4427.1 PR4416.1 PU4401.10
PWR_CHG_FSET: PR4430.1 PU4401.12
PWR_CHG_HIDRV: PU4401.23 PU4404.4
PWR_CHG_IADP: PG4401.1 PU4401.6
PWR_CHG_IDCHG: PG4414.1 PU4401.7
PWR_CHG_ILIM: PR4420.2 PR4423.1 PU4401.11
PWR_CHG_LODRV: PU4401.21 PU4405.4
PWR_CHG_NTC: PR4437.1 PU4401.17
PWR_CHG_PHASE: PC4414.2 PL4401.1 PU4401.22 PU4404.1 PU4404.2 PU4404.3 PU4405.5 PU4405.6 PU4405.7 PU4405.8
PWR_CHG_PHASE_1: PG4412.1 PL4401.2 PR4415.1 PU4403.5 PU4403.6 PU4403.7 PU4403.8
PWR_CHG_PMON: PG4415.1 PU4401.8
PWR_CHG_PROCHOT#: PG4419.1 PU4401.5
PWR_CHG_PROG: PR4433.1 PU4401.9
PWR_CHG_REGN: PC4431.1 PR4412.2 PR4420.1 PR4421.1 PU4401.20
PWR_CHG_SCL: PG4410.2 PU4401.4
PWR_CHG_SDA: PG4409.2 PU4401.3
PWR_CHG_SRN: PC4420.2 PC4422.1 PR4448.2 PU4401.14
PWR_CHG_SRN_1: PG4413.2 PR4448.1
PWR_CHG_SRP: PC4420.1 PC4421.1 PR4411.2 PU4401.15
PWR_CHG_SRP_1: PG4412.2 PR4411.1
PWR_CHG_VCC: PC4412.1 PR4407.1 PU4401.18
PWR_CMSRC: PC4436.1 PR4410.1 PU4401.29
PWR_DCBATOUT_1D0V: PC5209.1 PC5210.1 PC5211.1 PC5214.1 PC5216.1 PG5210.2 PG5212.2 PG5214.2 PR5201.1 PU5201.7 PU5201.8 PU5201.9
PWR_DCBATOUT_1D2V: PC5106.1 PC5107.1 PC5108.1 PG5101.2 PG5103.2 PG5104.2 PG5107.2 PG5108.2 PG5110.2 PU5101.2 PU5101.3 PU5101.4 PU5101.5
PWR_DCBATOUT_3D3V: PC4501.1 PC4502.1 PC4503.1 PC4504.1 PG4515.2 PG4516.2 PG4517.2 PG4518.2 PU4501.2 PU4501.3 PU4501.4 PU4501.5
PWR_DCBATOUT_5V: PC4505.1 PC4519.1 PC4522.1 PC4523.1 PG4501.2 PG4502.2 PG4503.2 PG4504.2 PG4505.2 PG4506.2 PU4502.2 PU4502.3 PU4502.4 PU4502.5
PWR_OPCN: PC4426.2 PU4401.28
PWR_OPCP: PC4426.1 PU4401.27
PWR_VBAT: PC4437.1 PR4403.1 PU4401.26
PWR_VCCGT_BOOTA: PR4802.1 PU4801.35
PWR_VCCGT_BOOTA_RC: PC4809.1 PR4802.2
PWR_VCCGT_COMP: PC4617.2 PC4618.2 PU4601.4
PWR_VCCGT_COMP_R: PC4618.1 PR4631.2
PWR_VCCGT_CSCOMP: PC4620.1 PC4621.1 PR4634.2 PR4639.2 PR4640.1 PU4601.6
PWR_VCCGT_CSN: PG4809.1 PR4633.1 PR4680.2
PWR_VCCGT_CSN_L: PC4616.2 PC4634.2 PC4647.2 PR4680.1 PU4601.28
PWR_VCCGT_CSP: PG4808.1 PR4627.2
PWR_VCCGT_CSP1: PC4623.2 PR4651.2 PU4601.10
PWR_VCCGT_CSP2: PC4641.2 PR4676.2 PR4678.2 PU4601.9
PWR_VCCGT_CSREF: PC4623.1 PC4641.1 PC4646.1 PR4646.1 PR4677.1 PU4601.8
PWR_VCCGT_CSSUM: PC4620.2 PC4621.2 PR4637.2 PR4638.2 PR4679.2 PU4601.7
PWR_VCCGT_DIFFOUT: PR4625.1 PR4626.1 PU4601.2
PWR_VCCGT_DISB#_A: PR4808.2 PU4801.2
PWR_VCCGT_FB: PC4614.2 PC4617.1 PR4626.2 PR4631.1 PU4601.3
PWR_VCCGT_FB_R: PC4614.1 PR4625.2
PWR_VCCGT_GL1: PU4801.8 PU4801.9 PU4801.10 PU4801.11
PWR_VCCGT_ICCMAX: PR4662.1 PU4601.18
PWR_VCCGT_ILIM: PR4640.2 PU4601.5
PWR_VCCGT_ILIM_R: PR4634.1 PR4638.1 PR4639.1
PWR_VCCGT_IOUT: PC4615.2 PR4632.2 PU4601.1
PWR_VCCGT_NTC: PR4655.1 PR4656.2 PR4661.1
PWR_VCCGT_PHASEDA: PC4809.2 PU4801.32 PU4801.34
PWR_VCCGT_PWMA: PU4601.22 PU4801.4
PWR_VCCGT_SNUB_1: PC4810.1 PR4804.2
PWR_VCCGT_SWA: PG4808.2 PL4801.1 PR4804.1 PU4801.12 PU4801.13 PU4801.14 PU4801.15 PU4801.16 PU4801.17 PU4801.18
PWR_VCCGT_TSENSE: PC4630.1 PR4655.2 PU4601.11
PWR_VCCGT_VCCA: PC4808.1 PR4803.1 PU4801.6
PWR_VCCGT_VSN: PC4612.2 PR4619.2 PU4601.48
PWR_VCCGT_VSN_R: PC4611.2 PC4612.1 PR4618.2 PR4619.1
PWR_VCCGT_VSP: PC4611.1 PR4617.2 PU4601.47
PWR_VCCSA_BST: PR5013.1 PU5001.1
PWR_VCCSA_BST_RC: PC5008.1 PR5013.2
PWR_VCCSA_COMP: PC4602.2 PC4604.2 PU4601.43
PWR_VCCSA_COMP_R: PC4602.1 PR4602.2
PWR_VCCSA_CSN: PG5022.1 PR4606.2 PR4681.2
PWR_VCCSA_CSN_L: PC4606.1 PC4607.1 PC4648.1 PR4681.1 PU4601.41
PWR_VCCSA_CSN_NTC: PR4606.1 PR4609.2
PWR_VCCSA_CSP: PG5021.1 PR4612.2
PWR_VCCSA_CSP1B: PC4606.2 PC4607.2 PR4609.1 PR4612.1 PU4601.40
PWR_VCCSA_DRVH: PU5001.8 PU5002.4
PWR_VCCSA_DRVL: PU5001.5 PU5003.4
PWR_VCCSA_ICCMAX: PR4660.1 PU4601.20
PWR_VCCSA_ILIM: PC4632.1 PR4611.1 PU4601.42
PWR_VCCSA_IOUT: PC4609.1 PR4613.1 PU4601.39
PWR_VCCSA_PWM: PU4601.36 PU5001.2
PWR_VCCSA_SNUB: PC5031.1 PR5014.2
PWR_VCCSA_SW: PC5008.2 PG5021.2 PL5001.1 PR5014.1 PU5001.7 PU5002.1 PU5002.2 PU5002.3 PU5003.5 PU5003.6 PU5003.7 PU5003.8
PWR_VCCSA_VSN: PC4603.2 PR4605.2 PU4601.44
PWR_VCCSA_VSN_R: PC4603.1 PC4605.2 PR4604.2 PR4605.1
PWR_VCCSA_VSP: PC4608.2 PR4608.2 PU4601.45
PWR_VCCSA_VSP_R: PC4605.1 PR4607.2 PR4608.1 PR4616.1
PWR_VCCSA_VSP_RC: PC4608.1 PR4616.2
PWR_VCORE_ADDR_BOOT: PR4663.1 PU4601.21
PWR_VCORE_ALERT#: PR4666.2 PU4601.33
PWR_VCORE_BOOT1: PR4701.1 PU4701.35
PWR_VCORE_BOOT2: PR4711.1 PU4702.35
PWR_VCORE_BOOT_RC1: PC4706.1 PR4701.2
PWR_VCORE_BOOT_RC2: PC4722.1 PR4711.2
PWR_VCORE_COMP: PC4601.1 PC4619.1 PU4601.26
PWR_VCORE_COMP_R: PC4601.2 PR4636.1
PWR_VCORE_CSNA: PG4708.1 PR4646.2
PWR_VCORE_CSNB: PG4711.1 PR4677.2
PWR_VCORE_CSNNTC: PR4629.2 PR4633.2
PWR_VCORE_CSP_1A: PC4616.1 PC4634.1 PR4627.1 PR4629.1 PU4601.29
PWR_VCORE_CSPA: PG4707.1 PR4637.1 PR4651.1
PWR_VCORE_CSPB: PG4712.1 PR4678.1 PR4679.1
PWR_VCORE_DISB#1: PR4704.2 PU4701.2
PWR_VCORE_DISB#2: PR4714.2 PU4702.2
PWR_VCORE_DRVON: PR4704.1 PR4714.1 PR4808.1 PU4601.35 PU5001.3
PWR_VCORE_EN: PR4630.1 PU4601.37
PWR_VCORE_GL1: PU4701.8 PU4701.9 PU4701.10 PU4701.11
PWR_VCORE_GL2: PU4702.8 PU4702.9 PU4702.10 PU4702.11
PWR_VCORE_ICCMAX: PR4658.1 PU4601.19
PWR_VCORE_ILIM: PC4633.1 PR4635.1 PU4601.27
PWR_VCORE_IOUT: PC4613.1 PR4628.1 PU4601.30
PWR_VCORE_NTC: PR4650.2 PR4652.1 PR4653.2
PWR_VCORE_PHASED1: PC4706.2 PU4701.32 PU4701.34
PWR_VCORE_PHASED2: PC4722.2 PU4702.32 PU4702.34
PWR_VCORE_PWM1: PU4601.16 PU4701.4
PWR_VCORE_PWM2: PU4601.17 PU4702.4
PWR_VCORE_ROSC_COREGT: PR4664.1 PU4601.14
PWR_VCORE_ROSC_SAUS: PR4659.1 PU4601.15
PWR_VCORE_SCLK: PR4665.2 PU4601.34
PWR_VCORE_SDIO: PR4667.2 PU4601.32
PWR_VCORE_SNUB1: PC4709.1 PR4703.2
PWR_VCORE_SNUB2: PC4727.1 PR4713.2
PWR_VCORE_SW1: PG4707.2 PL4701.1 PR4703.1 PU4701.12 PU4701.13 PU4701.14 PU4701.15 PU4701.16 PU4701.17 PU4701.18
PWR_VCORE_SW2: PG4712.2 PL4702.1 PR4713.1 PU4702.12 PU4702.13 PU4702.14 PU4702.15 PU4702.16 PU4702.17 PU4702.18
PWR_VCORE_TSENSE: PC4628.1 PR4650.1 PU4601.23
PWR_VCORE_VCC1: PC4708.1 PR4702.1 PU4701.6
PWR_VCORE_VCC2: PC4728.1 PR4712.1 PU4702.6
PWR_VCORE_VCC_R: PC4631.1 PR4657.2 PU4601.13
PWR_VCORE_VR_RDY: PR4670.1 PU4601.38
PWR_VCORE_VRHOT#: PR4668.1 PU4601.31
PWR_VCORE_VRMP: PC4629.1 PR4601.2 PU4601.12
PWR_VCORE_VSN: PC4622.1 PR4644.1 PU4601.25
PWR_VCORE_VSN_R: PC4622.2 PC4625.1 PR4644.2 PR4645.1
PWR_VCORE_VSP: PR4647.1 PR4649.1 PU4601.24
PWR_VCORE_VSP_R: PC4625.2 PC4627.2 PR4647.2 PR4648.1
PWR_VCORE_VSP_RC: PC4627.1 PR4649.2
Q6204_G: Q6504.2 Q6504.5 R6510.1
Q6205_Q: Q6503.D R6503.2
Q6502_D: Q6502.D R6514.1
Q9102.G: Q9102.G R9129.1
RESET_OUT#: ED1704.1 KBC24.73 Q2602.G R1706.1
REXT: R5710.1 U5701.18
RING2: EC2905.1 HDA27.29 R2906.1 RN2901.3(B)
RING2_R: ED2901.A HPMIC1.4 R2906.2
RSMRST_PWRGD#: D4002.K R4029.2 R4030.2 R4031.2 R4032.2 R4033.2
RSVD_F65: CPU1.F65 TP612.1
RSVD_G65: CPU1.G65 TP613.1
RSVD_TP_AW70: CPU1.AW70 TP615.1
RSVD_TP_AW71: CPU1.AW71 TP614.1
RSVD_TP_BA68: CPU1.BA68 TP602.1
RSVD_TP_BA70: CPU1.BA70 TP601.1
RSVD_TP_BB68: CPU1.BB68 TP603.1
RSVD_TP_BB69: CPU1.BB69 TP604.1
RTC_AUX_S5: C2503.1 D2501.3 R1730.1 R2106.1 R2451.2 R2464.1 R2472.2 R2725.1 R5721.1 RN1801.1(A) RN1801.2(A)
RTC_DET#: CPU1.P1 Q2503.6 R2040.2
RTC_RST#: C1806.1 CPU1.AM16 EC1807.1 G1801.2 Q2503.3 RN1801.4(B)
RTC_X1: C1804.1 CPU1.AM18 R1815.1 X1802.1
RTC_X2: C1803.1 CPU1.AM20 R1815.2 X1802.2
RTCRST_ON: EC2504.1 KBC24.31 Q2503.5 R2509.1
RUNPWROK: D4002.A ED1709.1 KBC24.48 R1716.1 R4002.1 R4005.2 R4011.2
SA0_CHA_DIM0: DM1.256 R1204.1 R1205.2
SA0_CHB_DIM0: DM2.256 R1302.1 R1303.2
SA1_CHA_DIM0: DM1.260 R1208.1 R1210.2
SA1_CHB_DIM0: DM2.260 R1306.1 R1307.1
SA2_CHA_DIM0: DM1.166 R1211.1 R1212.2
SA2_CHB_DIM0: DM2.166 R1310.1 R1311.2
SATA_LED#: CPU1.H1 Q6403.S R1606.2
SATA_RX_CPU_N0: C6006.1 CPU1.F20
SATA_RX_CPU_N12: CPU1.E30 SSD1.43 U6301.2 U6301.9
SATA_RX_CPU_P0: C6005.1 CPU1.E20
SATA_RX_CPU_P12: CPU1.F30 SSD1.41 U6301.1 U6301.10
SATA_RXN0_R: C6006.2 HDD1.18 U6001.4 U6001.7
SATA_RXP0_R: C6005.2 HDD1.19 U6001.5 U6001.6
SATA_TX_CPU_N0: C6003.1 CPU1.B21
SATA_TX_CPU_N12: C6303.2 CPU1.A25
SATA_TX_CPU_N12_C: C6303.1 SSD1.47 U6301.4 U6301.7
SATA_TX_CPU_P0: C6001.1 CPU1.A21
SATA_TX_CPU_P12: C6302.2 CPU1.B25
SATA_TX_CPU_P12_C: C6302.1 SSD1.49 U6301.5 U6301.6
SATA_TXN0_R: C6003.2 HDD1.16 U6001.2 U6001.9
SATA_TXP0_R: C6001.2 HDD1.15 U6001.1 U6001.10
SD_RCOMP: CPU1.AB7 R1901.1
SD_READ_MODE: CPU1.AN5 R2055.2 R2056.1
SENSOR_I2C_SCL: R2020.2 RN7001.2(A) TCBD1.8
SENSOR_I2C_SCL_2G: RN7001.3(B) U7001.1
SENSOR_I2C_SDA: R2021.2 RN7001.1(A) TCBD1.7
SENSOR_I2C_SDA_2G: RN7001.4(B) U7001.4
SERIRQ_TPM: R9148.1 U9104.27
SIO_EXT_SCI#: CPU1.J2 R1608.2
SIO_EXT_SMI#: CPU1.L6 R802.1
SIO_EXT_WAKE#: CPU1.AD3 KBC24.116 R2041.2
SIO_PWRBTN#: CPU1.BA15 KBC24.52
SIO_RCIN#: CPU1.AW13 R1820.2
SIO_SLP_A#: CPU1.AN16 TP1706.1
SIO_SLP_S0#: CPU1.AT11 R2423.1 R4012.1 R6005.1 R9142.2
SIO_SLP_S3#: CPU1.AP15 PR5126.1 PR5405.1 Q2701.G R4010.1 R4017.1 U4003.1
SIO_SLP_S4#: CPU1.BA16 PR5417.1 R4024.1
SIO_SLP_S5#: CPU1.AY16 TP1703.1
SKTOCC#: CPU1.A65 TP402.1
SLEEVE: EC2906.1 HDA27.30 R2911.1 RN2901.4(B)
SLEEVE_R: ED2906.A HPMIC1.3 R2911.2
SLP_LAN#: CPU1.AW15 TP1704.1
SLP_S0_U: R4012.2 U4003.2
SLP_SUS#: CPU1.AN15 TP1711.1
SM_DRAMRST#: CPU1.AT13 ED501.2 R504.1 R505.2
SM_INTRUDER#: CPU1.AP16 R1730.2
SM_PGCNTL: CPU1.AW67 Q501.S
SM_PGCNTL_R: PR5125.1 Q501.D R506.2
SM_RCOMP_0: CPU1.AR18 R501.1
SM_RCOMP_1: CPU1.AT18 R502.1
SM_RCOMP_2: CPU1.AU18 R503.1
SMB_ALERT#: CPU1.R10 R1836.2
SML0_ALERT#: CPU1.W1 R1822.2 R1823.1
SML0_SMBCLK: CPU1.R9 RN1807.5(B)
SML0_SMBDATA: CPU1.W2 RN1807.6(B)
SML1_SMBCLK: CPU1.W3 GPU1.E8 Q2601.3 R2459.2 RN1807.7(B)
SML1_SMBDATA: CPU1.V3 GPU1.E9 Q2601.6 R2447.2 RN1807.8(B)
SML1ALERT#: CPU1.AM7 R1837.2
SPI_CLK_CPU: CPU1.AV2 RN1803.8(B)
SPI_CLK_ROM: R2505.2 R9132.1 RN1803.1(A)
SPI_CLK_ROM_R: EC2503.1 R2505.1 SPI25.6
SPI_CLK_ROM_TPM2: R9132.2 U9104.19
SPI_CS2#_R: Q9104.G R1826.1 R9129.2 R9130.2 R9133.2
SPI_CS2#_R_TPM2: R9130.1 R9140.2 U9104.20
SPI_CS_CPU_N0: CPU1.AU3 R1812.2
SPI_CS_ROM_N0: R1812.1 R2501.1 SPI25.1
SPI_HOLD_CPU: CPU1.AU4 R1811.2
SPI_HOLD_ROM: R1811.1 R2503.2 RN1802.4(B)
SPI_HOLD_ROM_R: R2503.1 SPI25.7
SPI_IRQ#_TPM2: R1808.2 R9119.2 U9104.18
SPI_SI_CPU: CPU1.AV3 R1824.2 R1825.1 RN1803.6(B)
SPI_SI_ROM: R2506.2 R9139.1 RN1803.3(A)
SPI_SI_ROM_R: EC2501.1 R2506.1 SPI25.5
SPI_SI_ROM_TPM2: R9139.2 U9104.21
SPI_SO_CPU: CPU1.AW3 RN1803.7(B)
SPI_SO_ROM: R2507.1 R9134.1 RN1803.2(A)
SPI_SO_ROM_R: EC2502.1 R2507.2 SPI25.2
SPI_SO_ROM_TPM2: R9134.2 U9104.24
SPI_WP_CPU: CPU1.AW2 RN1803.5(B)
SPI_WP_ROM: R2508.1 RN1802.3(B) RN1803.4(A)
SPI_WP_ROM_R: R2508.2 SPI25.3
SPK_ID: CPU1.AB1 R2047.2 SPK1.5
SPKR: CPU1.AW5 R2006.2 RN2701.2(A)
SRTC_RST#: C1805.1 CPU1.AN18 EC1806.1 RN1801.3(B)
SSD_DEVSLP: CPU1.J3 R6301.1 R6303.2 R6304.1
SSD_PEDET: AFTP6303.1 R6306.1 R6310.2 SSD1.69
SSEQ0_A0: R3845.2 R3846.1 U3801.11
SSEQ1: R3844.1 R3852.2 U3801.3
SUS_CLK: R1807.1 R2425.1
SUSACK#_R: CPU1.AP11 R1708.2
SUSCLK: CPU1.BA17 EC1803.2 R1807.2
SYS_PRES1#: AFTP4315.1 BATT1.7 R4301.2
SYS_PWROK: CPU1.B6 ED1702.1 KBC24.28 R1717.1
SYSPWR_PRES: KBC24.120 Q2417.G R2454.1 R2463.2 R2464.2
T_CRIT#: R2601.1 R2604.2 THM261.4
THERM_SYS_SHDN#: Q2602.S R2601.2 R2602.1
THM_SML1_CLK: C2608.1 Q2601.4 RN2602.4(B) THM261.8
THM_SML1_DATA: C2609.1 Q2601.1 RN2602.3(B) THM261.7
TOP_MUX_N: ED3804.1 EL3801.3 R3861.2 USB1.A7
TOP_MUX_N_L: EL3801.4 R3861.1 U3802.17
TOP_MUX_P: ED3804.2 EL3801.2 R3862.2 USB1.A6
TOP_MUX_P_L: EL3801.1 R3862.1 U3802.18
TOUCH_PAD_INTR#: CPU1.BA5 R404.2 R410.2
TOUCH_PANEL_INTR#: CPU1.A7 TP409.1
TOUCH_PANEL_PD#: CPU1.AY5 TP404.1
TOUCH_REPORT_SW: D2402.A R2429.1 TCBD1.32
TP1_AY4: CPU1.AY4 TP610.1
TP2_BB3: CPU1.BB3 TP611.1
TP4_BB5: CPU1.BB5 TP609.1
TP5_AU5: CPU1.AU5 TP607.1
TP6_AT5: CPU1.AT5 TP608.1
TP_EN#: KBC24.49 R6504.1 RN2405.4(A)
TP_ON#_GATE: C6502.2 Q6502.G Q6503.G R6504.2
TP_VDD: AFTP6531.1 C6503.1 R6502.2 R6503.1 R6511.1 R6514.2 RN6501.1(A) RN6501.2(A) RN6503.1(A) RN6503.2(A) TP1.1
TP_WAKE_KBC#: AFTP6536.1 KBC24.33 R410.1 R6511.2 TP1.5
TPAN_VDD: C5516.1 C5517.1 C5520.1 F5501.2 R5507.2 TCBD1.26 TCBD1.27
TPCLK_C: AFTP6532.1 RN6502.3(B) TP1.8
TPDATA_C: AFTP6533.1 RN6502.4(B) TP1.7
TPM_GPIO0: R9141.1 R9142.1 U9104.29
TPM_GPIO2: Q9102.D Q9104.D R9120.1 R9131.1 R9138.1 U9104.3
TPM_GPIO4: R9133.1 U9104.13
TPM_ID: CPU1.D8 R1912.1 R1913.2
TPM_SPI_IRQ#: CPU1.M2 R1808.1
TPM_VDD14: R9147.2 U9104.14
TPM_VDD22: R9149.2 U9104.22
TPM_VSB: R9144.2 U9104.1
TPS70933_EN: Q3701.D R3739.2 U3702.4
TPS70933_EN_G: C3720.2 Q3701.G R3738.2
TS#_DIMM0_1: DM1.134 R1215.2
TS#_DIMM1_1: DM2.134 R1312.2
TYPEC_5V: PQ4309.3 PR4339.2
TYPEC_5V_L: PQ4309.4 PQ4309.6
TYPEC_5V_SW: PC4312.2 PR4330.2 PU4305.1 PU4305.2 PU4305.3 PU4306.1 PU4306.2 PU4306.3
TYPEC_5V_SW_R: PC4312.1 PR4330.1 PR4339.1 PU4305.4 PU4306.4
TYPEC_CON_RXN1: ED3806.5 ED3806.6 R3835.2 USB1.B10
TYPEC_CON_RXN2: ED3802.1 ED3802.10 R3837.2 USB1.A10
TYPEC_CON_RXP1: ED3806.4 ED3806.7 R3834.2 USB1.B11
TYPEC_CON_RXP2: ED3802.2 ED3802.9 R3836.2 USB1.A11
TYPEC_CON_TXN1: ED3806.2 ED3806.9 R3833.2 USB1.A3
TYPEC_CON_TXN2: ED3802.4 ED3802.7 R3839.2 USB1.B3
TYPEC_CON_TXP1: ED3806.1 ED3806.10 R3832.2 USB1.A2
TYPEC_CON_TXP2: ED3802.5 ED3802.6 R3838.2 USB1.B2
TYPEC_SMBCLK: KBC24.91 Q2605.1 R3854.1 RN2604.4(B)
TYPEC_SMBDA: KBC24.89 Q2605.4 R3853.1 RN2604.3(B)
U22_POWER_K52: CPU1.K52 R712.1
UART0_CTS#: CPU1.U4 TP2014.1
UART0_RTS#: CPU1.U3 TP2013.1
UART1_CTS#: CPU1.AB4 TP2017.1
UART1_RTS#: CPU1.AC3 TP2016.1
UART_2_CRXD_DTXD: CPU1.AD1 R2049.2 R6810.2
UART_2_CRXD_DTXD_CON: DB1.14 R6810.1
UART_2_CTXD_DRXD: CPU1.AD2 R2048.2 R6809.2
UART_2_CTXD_DRXD_CON: DB1.13 R6809.1
USB2_ID: CPU1.AG3 RN1602.1(A)
USB2_VBUSSENSE: CPU1.AG4 RN1602.2(A)
USB20_DN0_C: ED3602.1 EL3605.2 USB2.2
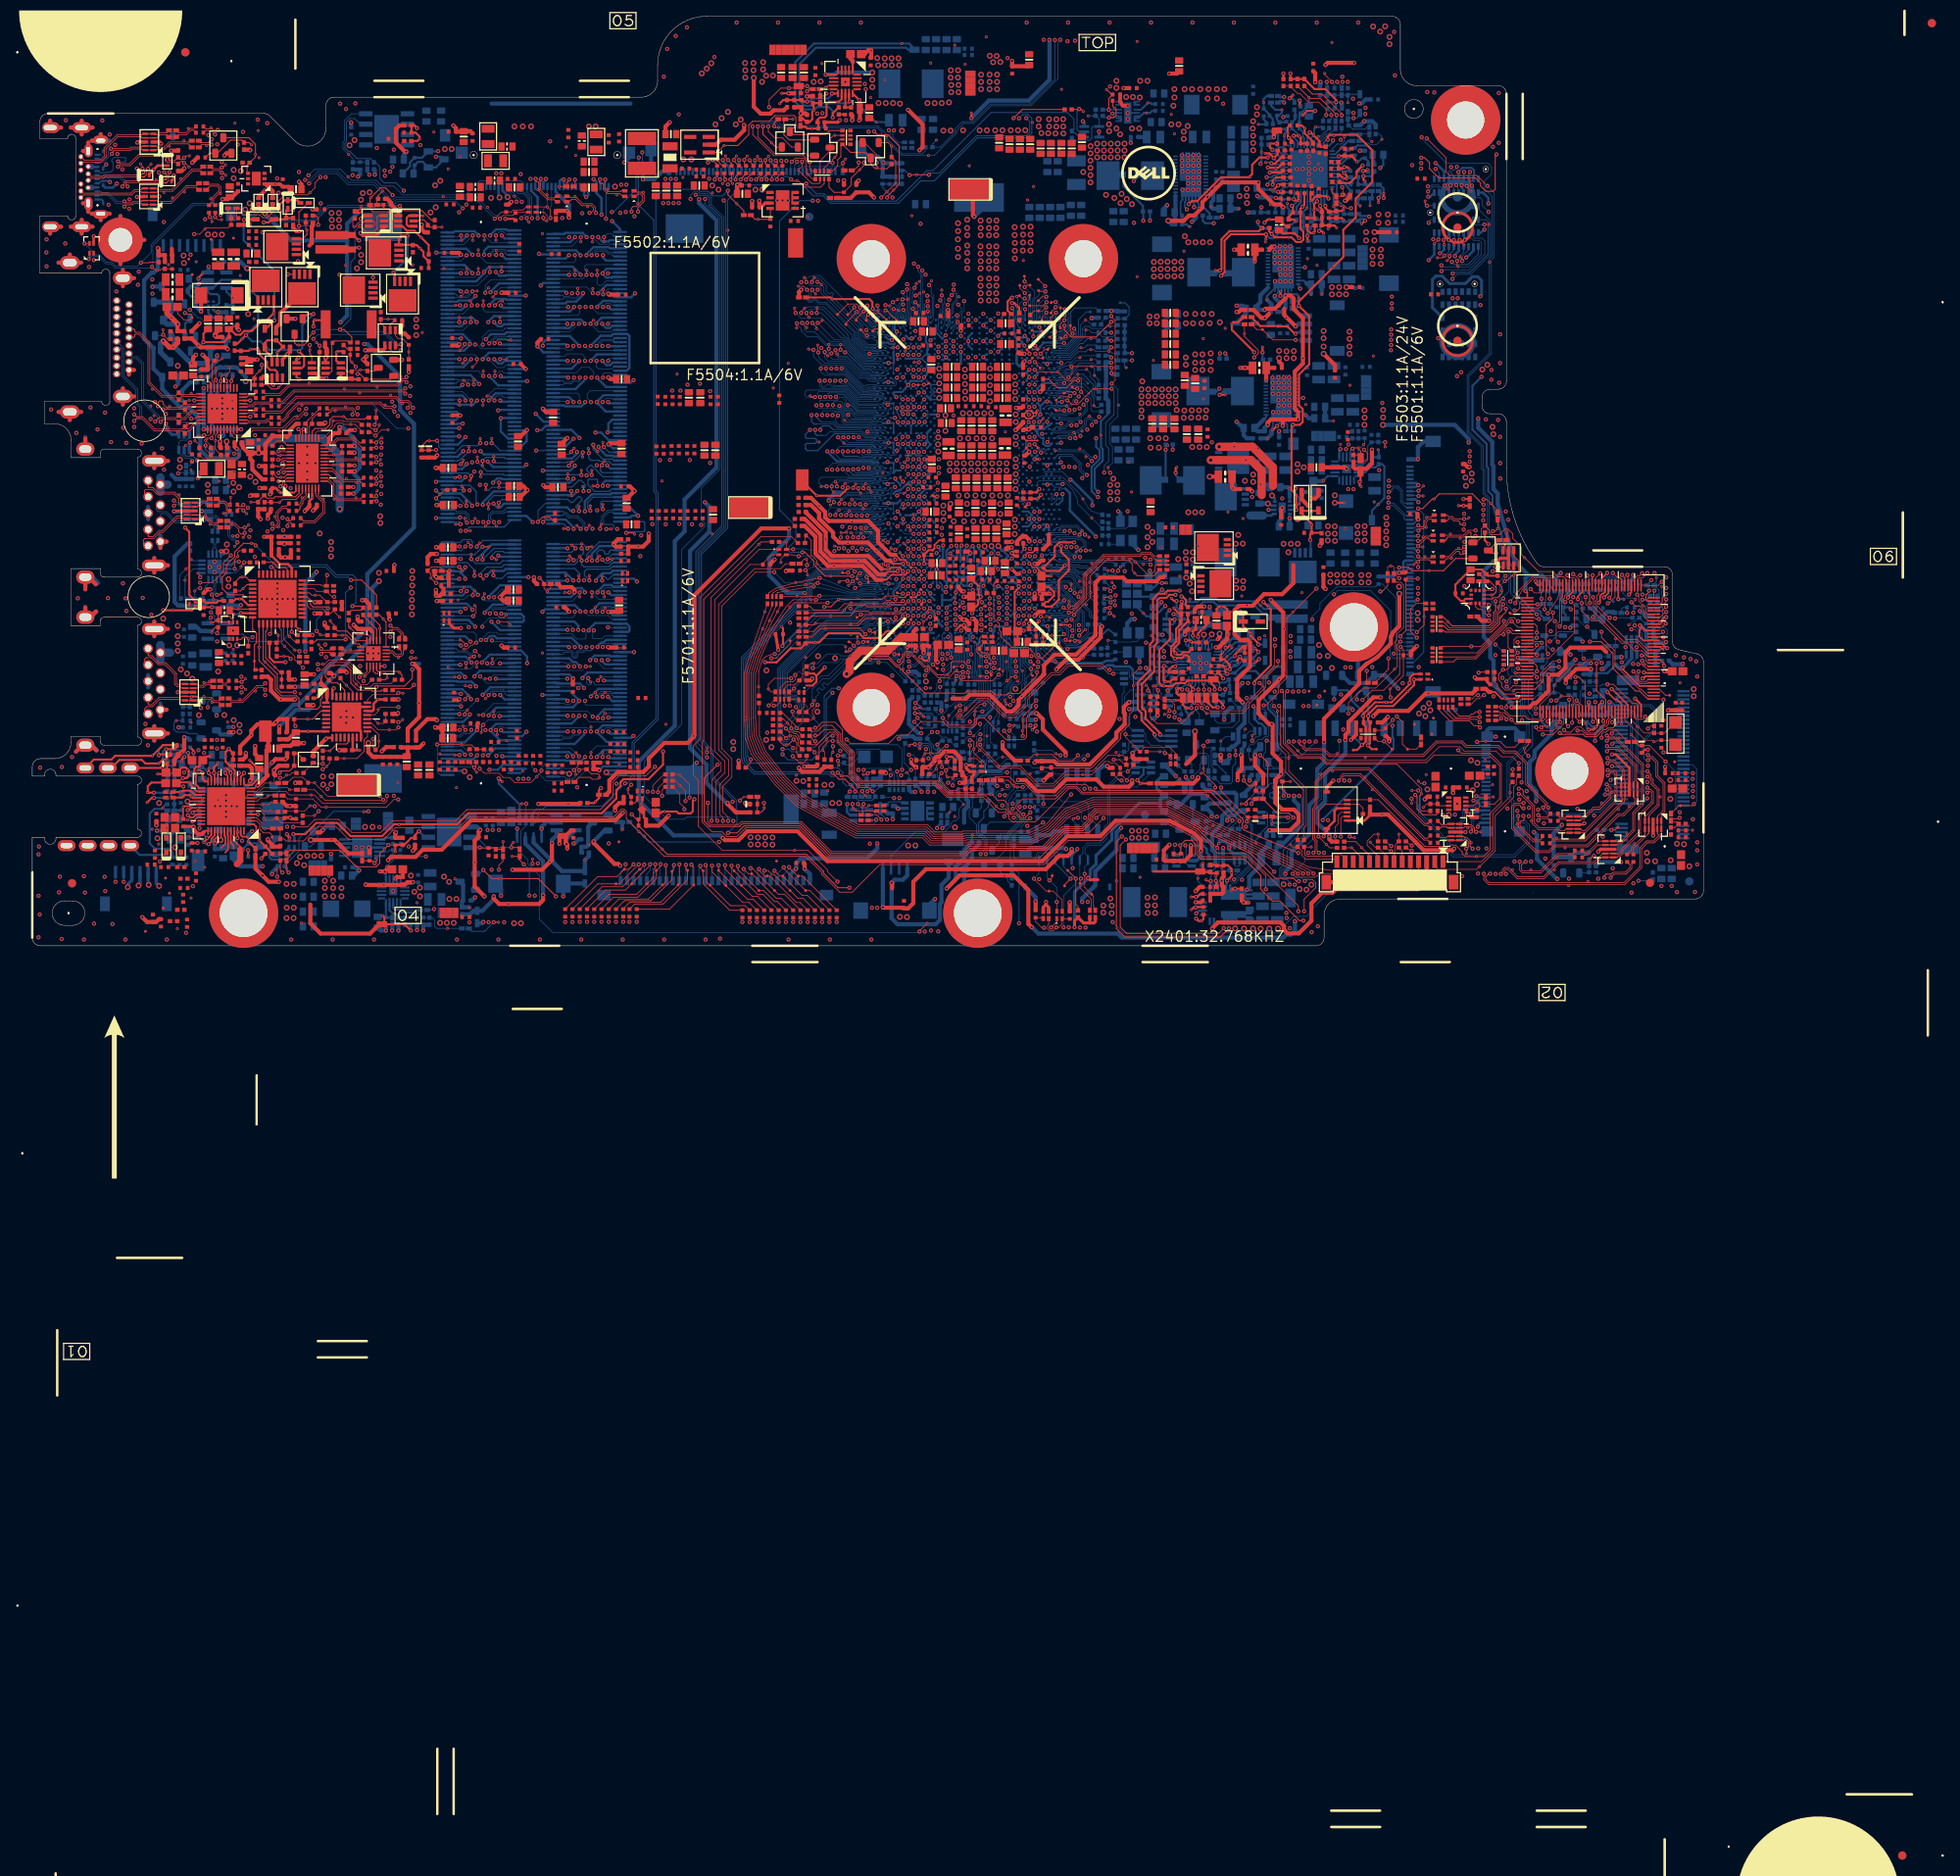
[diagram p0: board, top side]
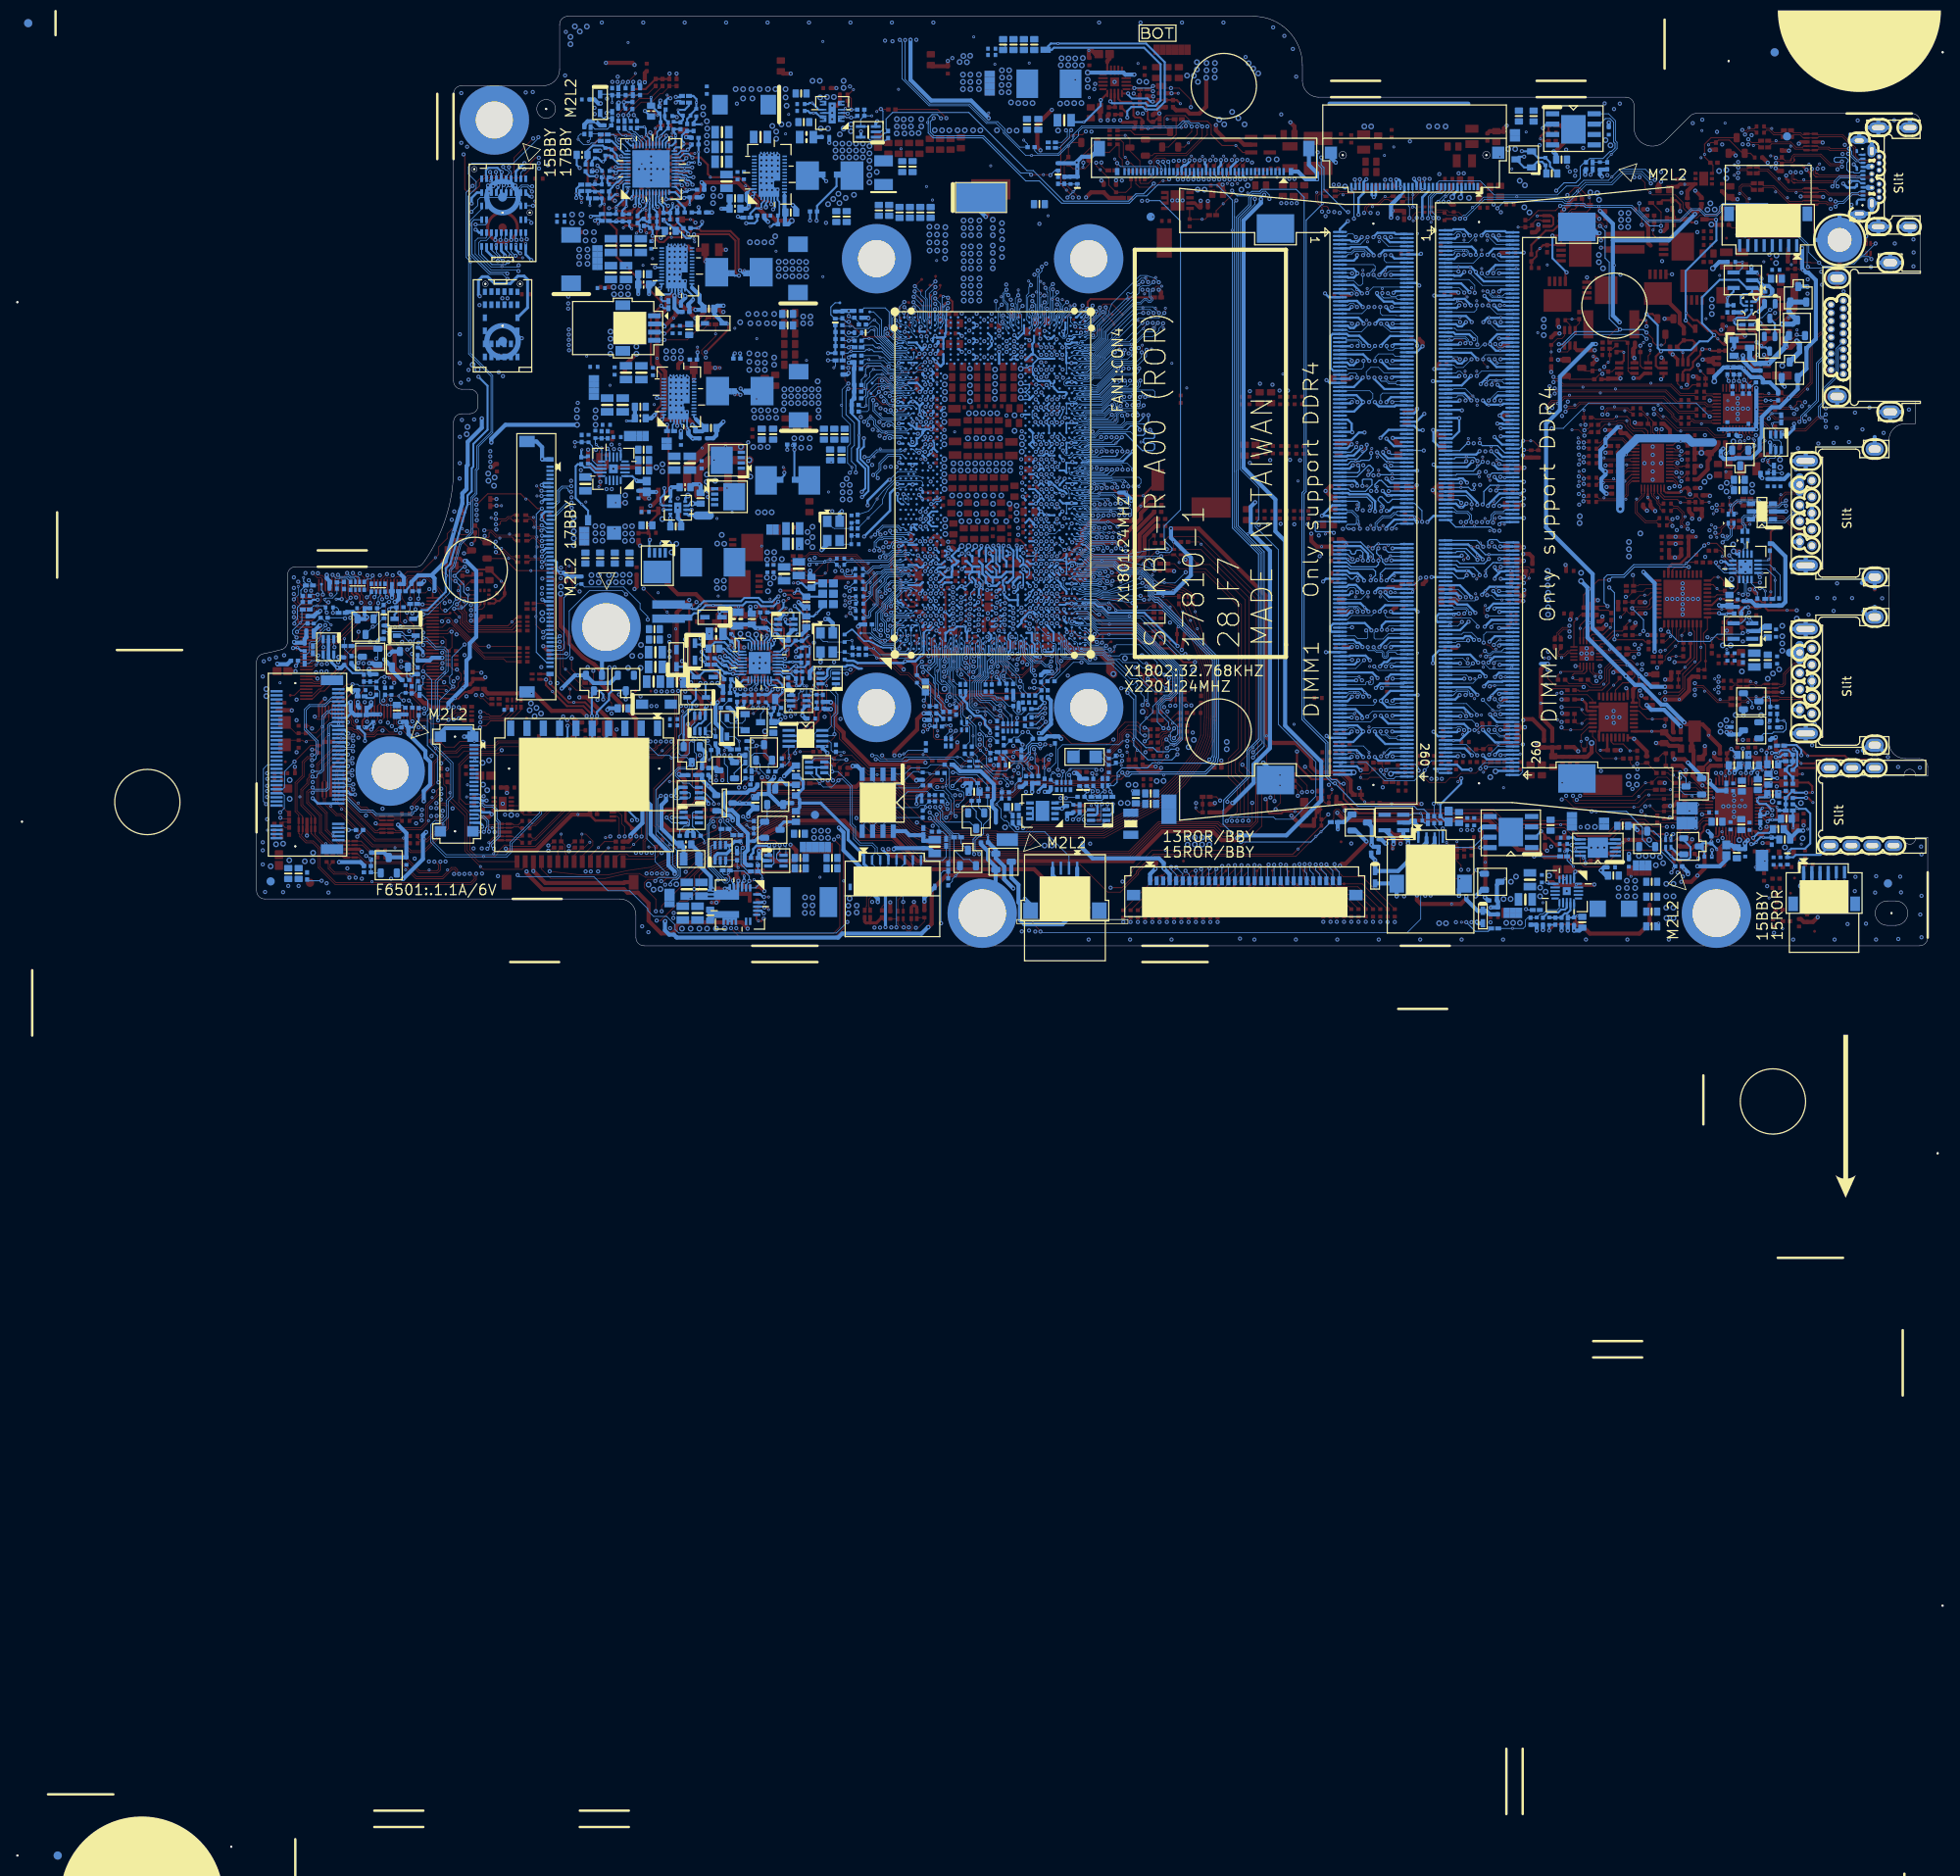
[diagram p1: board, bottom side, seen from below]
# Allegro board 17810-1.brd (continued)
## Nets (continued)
USB20_DN1_C: ED3602.3 EL3606.2 USB3.2
USB20_DP0_C: ED3602.6 EL3605.3 USB2.3
USB20_DP1_C: ED3602.4 EL3606.3 USB3.3
USB30_RX_CPU_N1: CPU1.H8 R3609.1
USB30_RX_CPU_N2: CPU1.J6 R3612.1
USB30_RX_CPU_N4: C3806.1 CPU1.E10
USB30_RX_CPU_N4_C: C3806.2 U3801.4
USB30_RX_CPU_P1: CPU1.G8 R3610.1
USB30_RX_CPU_P2: CPU1.H6 R3613.1
USB30_RX_CPU_P4: C3805.1 CPU1.F10
USB30_RX_CPU_P4_C: C3805.2 U3801.5
USB30_RXDN1_C: ED3601.1 ED3601.10 R3609.2 USB2.5
USB30_RXDN2_C: ED3603.1 ED3603.10 R3612.2 USB3.5
USB30_RXDP1_C: ED3601.2 ED3601.9 R3610.2 USB2.6
USB30_RXDP2_C: ED3603.2 ED3603.9 R3613.2 USB3.6
USB30_TX_CPU_N1: C3601.1 CPU1.C13
USB30_TX_CPU_N2: C3603.1 CPU1.B13
USB30_TX_CPU_N4: C3804.1 CPU1.C15
USB30_TX_CPU_N4_C: C3804.2 U3801.7
USB30_TX_CPU_P1: C3602.1 CPU1.D13
USB30_TX_CPU_P2: C3604.1 CPU1.A13
USB30_TX_CPU_P4: C3803.1 CPU1.D15
USB30_TX_CPU_P4_C: C3803.2 U3801.8
USB30_TXDN1_C: ED3601.4 ED3601.7 R3605.2 USB2.8
USB30_TXDN1_R: C3601.2 R3605.1
USB30_TXDN2_C: ED3603.4 ED3603.7 R3611.2 USB3.8
USB30_TXDN2_R: C3603.2 R3611.1
USB30_TXDP1_C: ED3601.5 ED3601.6 R3606.2 USB2.9
USB30_TXDP1_R: C3602.2 R3606.1
USB30_TXDP2_C: ED3603.5 ED3603.6 R3614.2 USB3.9
USB30_TXDP2_R: C3604.2 R3614.1
USB30_VCCA: C3401.1 C3403.1 C3404.1 C3405.1 C3407.1 ED3602.5 U3401.12 USB2.1
USB30_VCCB: C3507.1 C3508.1 C3512.1 C3513.1 C3514.1 PU4306.5 PU4306.6 PU4306.7 PU4306.8 R3501.1 U3501.1 USB3.1
USB_ADT: PD4405.A PD4407.A PD4409.A PR4327.2 PU4303.5 PU4303.6 PU4303.7 PU4303.8 PU4304.5 PU4304.6 PU4304.7 PU4304.8
USB_ADT_D: PD4406.K PD4407.K PR4408.1
USB_ADT_D1: PC4434.2 PD4409.K PD4411.K PR4442.1 PU4403.4
USB_ADT_R1: PD4306.A PQ4308.5 PQ4308.6 PR4327.1 PR4328.2
USB_ADT_SW: PR4320.2 PR4321.1 PU4304.4
USB_ADT_SW_R: PQ4308.3 PR4321.2
USB_CAMERA_N: EL5501.3 TCBD1.15
USB_CAMERA_P: EL5501.2 TCBD1.14
USB_CPU_PN0: CPU1.AB9 U3401.2
USB_CPU_PN1: CPU1.AD6 EL3606.1
USB_CPU_PN2: CPU1.AH3 EL6601.2
USB_CPU_PN2_C: EL6601.1 IOBD1.19
USB_CPU_PN3: CPU1.AD9 U3802.2
USB_CPU_PN4: CPU1.AJ1 EL5501.4
USB_CPU_PN5: CPU1.AF6 EL6602.2
USB_CPU_PN5_C: EL6602.1 IOBD1.22
USB_CPU_PN6: CPU1.AH1 EL6603.2
USB_CPU_PN6_C: EL6603.1 IOBD1.16
USB_CPU_PN7: CPU1.AF8 EL5502.4
USB_CPU_PP0: CPU1.AB10 U3401.3
USB_CPU_PP1: CPU1.AD7 EL3606.4
USB_CPU_PP2: CPU1.AJ3 EL6601.3
USB_CPU_PP2_C: EL6601.4 IOBD1.20
USB_CPU_PP3: CPU1.AD10 U3802.1
USB_CPU_PP4: CPU1.AJ2 EL5501.1
USB_CPU_PP5: CPU1.AF7 EL6602.3
USB_CPU_PP5_C: EL6602.4 IOBD1.23
USB_CPU_PP6: CPU1.AH2 EL6603.3
USB_CPU_PP6_C: EL6603.4 IOBD1.17
USB_CPU_PP7: CPU1.AF9 EL5502.1
USB_EN#: IOBD1.49 KBC24.13 R2434.2 U3501.4
USB_OC0#: CPU1.A9 RN1601.6(B) U3401.13 U3501.3
USB_OC1#: CPU1.C9 IOBD1.48 RN1601.5(B)
USB_OC2#: CPU1.D9 RN1601.8(B)
USB_OC3#: CPU1.B9 RN1601.7(B)
USB_PN0_R: EL3605.1 U3401.11
USB_PN7_TPNL: EL5502.3 TCBD1.31
USB_POWERSHARE_VBUS_EN: KBC24.71 U3401.5
USB_PP0_R: EL3605.4 U3401.10
USB_PP7_TPNL: EL5502.2 TCBD1.30
USB_PWR_SHR_EN_L#: KBC24.118 R2473.1 R3401.1
USB_TYPEC_DIS: PQ4310.6 PR4338.2
USB_TYPEC_R: PC4310.1 PR4322.1 PR4336.1 PU4303.4
USB_TYPEC_SW: PQ4307.3 PR4322.2
USBC1_CC1_CONN: C3711.1 ED3801.2 R3728.2 USB1.A5
USBC1_CC2_CONN: C3712.1 ED3801.1 R3727.2 USB1.B5
USBC_DPAUX1: ED3803.2 R3830.1 U3801.27 USB1.A8
USBC_DPAUX2: ED3803.1 R3831.1 U3801.26 USB1.B8
USBCOMP: CPU1.AB6 R1603.1
V_SM_VREF_CNTA: C1222.1 CPU1.AY67 R1206.2
V_SM_VREF_CNTB: C1323.1 CPU1.BA67 R1305.2
VCONN_MON_P1: R3706.2 R3735.1 U3701.19
VCREF0: C2409.1 KBC24.25 R2424.1 R2448.1
VD_IN1_C: C2612.2 C2613.2 R2610.2 R2611.1
VOL_DOWN#: IOBD1.42 KBC24.41 RN2407.3(B)
VOL_UP#: IOBD1.41 KBC24.34 RN2407.4(B)
VR_CAP: C2418.1 KBC24.18
VR_EN: PR4630.2 R4002.2
VR_RDY: PR4614.2 PR4670.2
VR_SVID_ALERT#: PR4622.2 PR4666.1 R727.2 R728.1
VR_SVID_CLK: PR4621.2 PR4665.1 R723.2 R732.2
VR_SVID_DATA: PR4623.2 PR4667.1 R709.2
VRALERT#: CPU1.AM11 TP1708.1
VRAM_ID1: CPU1.AP8 R2029.2 R2030.1
VRAM_ID2: CPU1.U2 TP2012.1
VREF_CPU: C2406.1 KBC24.95 R2402.2
VREG3PD: C3709.1 C3710.1 D3702.A U3702.1
WHITE_LED_BAT: EC6402.1 Q6401.C R6402.2
WIFI_RF_EN: CPU1.B7 EC6603.1 IOBD1.46 R1503.2
XCLK_BIASREF: CPU1.E42 R1803.1
XDP_BPM0: CPU1.C55 TP405.1
XDP_BPM1: CPU1.D55 TP406.1
XDP_BPM2: CPU1.B54 TP407.1
XDP_BPM3: CPU1.C56 TP408.1
XDP_DBRESET#: CPU1.B5 EC1706.1 R1701.2 TP1709.1
XDP_PRDY#: CPU1.D56 TP1605.1
XDP_PREQ#: CPU1.D61 TP1606.1
XDP_TCK_JTAGX: CPU1.A59 R417.1
XDP_TCLK: CPU1.B61 R406.1
XDP_TDI: CPU1.D60 R422.1
XDP_TDO_CPU: CPU1.A61 R423.1
XDP_TMS: CPU1.C60 R421.1
XDP_TRST#: CPU1.B59 CPU1.C61 R402.1
XTAL24_IN: CPU1.E37 R1804.2
XTAL24_IN_R: C1801.2 R1802.1 R1804.1 X1801.1
XTAL24_IN_U42: CPU1.E3 R2202.2
XTAL24_IN_U42_R: C2201.2 R2201.1 R2202.1 X2201.1
XTAL24_OUT: CPU1.E35 R1805.2
XTAL24_OUT_R: C1802.2 R1802.2 R1805.1 X1801.3
XTAL24_OUT_U42: CPU1.C7 R2203.2
XTAL24_OUT_U42_R: C2202.2 R2201.2 R2203.1 X2201.3
ZVM#: CPU1.AR56 TP616.1

Pads without a net: CPU1 A3 A4 A11 A15 A26 A27 A29 A31 A33 A36 A38 A52 A69 AB11 AB12 AB62 AC63 AD12 AE62 AE63 AF12 AF13 AG1 AG2 AG62 AH7 AH8 AJ62 AK12 AK13 AK52 AK53 AK55 AK56 AK58 AK60 AK62 AK70 AL25 AL27 AL53 AL56 AL60 AL61 AL63 AM1 AM2 AM3 AM4 AM22 AM23 AM53 AM56 AM58 AN1 AN2 AN3 AN7 AN55 AP1 AP2 AP3 AP4 AP5 AP53 AT15 AU2 AU56 AU58 AU63 AW1 AW20 AW48 AW56 AW68 AW69 AY1 AY2 AY3 AY20 AY21 AY56 AY68 B2 B3 B11 B15 B26 B27 B29 B31 B33 B36 B38 B69 B70 BA3 BA4 BA9 BB2 BB4 BB57 BB66 C2 C4 C11 C12 C19 C21 C27 C28 C29 C31 C32 C33 C36 C37 C38 C40 C41 C54 C70 C71 D1 D3 D4 D5 D7 D12 D19 D21 D27 D28 D29 D31 D32 D33 D36 D37 D38 D40 D41 D54 D71 E1 E2 E16 E38 E40 E61 F6 F16 F21 F46 F50 F52 F60 F61 G1 G2 G3 G21 G46 G50 G61 H10 H11 H63 J5 J10 J68 J71 K45 K46 N9 N11 N12 P62 U11 U12 V62 W4 W7 W10 W11 W12; D4001 2; DB1 12; DCIN1 5; DM1 87 88 91 92 95 97 100 101 104 105 162 165; DM2 87 88 91 92 95 97 100 101 104 105 162 165; GPU1 A1 A10 C9 D2 F2 N1; GPU2 N1; HDA27 19 20 35 36 48; HDD1 2 7 12; HDMI1 13 14; HS2 1; HS3 1; IOBD1 1 2 3 4 25 26 27 33 35 40; KB1 2 3; KBBL1 3; KBC24 3; LCD1 5 10 28; PU4307 1 5; PU4501 15; PU4701 1 33; PU4702 1 33; PU4801 1 33; PU5101 12; PU5402 4; RN4302 4 5; SSD1 6 8 10 20 22 24 26 28 30 32 34 36 40 42 44 46 48 54 56 58 67 68; TCBD1 3 4 23 24 25 28; U3401 9; U3701 3 4 6 21 22 23 24 30 34 35 37 38 39 40; U3702 2 5; U3703 4; U3802 6 7 19 20; U5701 12 15 36 37; U9104 2 4 5 6 7 10 11 12 15 25 26 28 30 31

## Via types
v1: diameter 0.508, hole 0.254, TOP to BOTTOM, 3595 vias
v2: diameter 0.356, hole 0.178, TOP to BOTTOM, 1306 vias
v3: diameter 0.711, hole 0.406, TOP to BOTTOM, 765 vias

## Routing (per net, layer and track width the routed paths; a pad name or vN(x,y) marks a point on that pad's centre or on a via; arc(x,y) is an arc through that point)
1.8V_RUN_FB: length 6
  TOP w0.254: v2(44.5,11.55) PC5405.2 44.52,12.36 PR5403.2 45.59,12.36 46.45,13.22 PR5404.1 46.91,13.55 v1(47.39,14.04)
  BOTTOM w0.254: v1(47.39,14.04) 47.52,13.91 47.52,13.91 48.13,13.3 48.55,13.3
3V5V_CT1: length 2.5
  BOTTOM w0.203: U4001.12 135.84,101.67 136.04,101.87
  BOTTOM w0.254: C4001.1 137.26,102.33 137.01,102.07 v2(136.57,102.07) 136.24,102.07 136.04,101.87
3V5V_CT2: length 2.7
  BOTTOM w0.203: 136.13,102.7 135.91,102.47 U4001.10
  BOTTOM w0.254: 136.13,102.7 v2(136.74,103.31) 137.07,103.31 137.21,103.17 C4002.1
3V5V_S0_ON: length 8.1
  BOTTOM w0.127: 130.35,101.72 130.79,101.28 U4003.4 130.04,100.41 129.87,100.25 129.87,98.98 129.61,98.72 127.71,98.72 R4010.2 ; 130.35,101.72 130.35,102.48 ; 130.35,101.72 v2(129.44,101.72)
3V_5V_EN: length 115.6
  TOP w0.127: v1(97.33,104.46) 97.03,104.16 PR4515.1 96.54,104.19 PR4516.1 ; v1(104.79,91.71) 104.79,91.83 v2(105.57,92.62) 106.27,93.31 106.27,98.06 104.91,99.41 103.6,99.41 v1(103.2,99.81)
  L3 w0.127: v1(104.79,91.71) 113.02,83.48 113.02,82.22 113.82,81.42 113.82,79.46 112.95,78.59 112.95,77.46 111.53,76.04 111.53,74.49 110.51,73.47 110.51,52.61 111.5,51.63 111.99,51.63 112.98,50.64 118.07,50.64 119.34,49.37 119.34,47.83 117.98,46.47 117.98,43.83 119,42.82 119,39.27 119.3,38.96 119.3,32.17 118.31,31.18 118.31,28.86 118.75,28.41 118.75,27.29 118.41,26.95 118.41,26.34 119.43,25.33 119.43,24.68 118.75,24 118.75,20.9 119.48,20.17 119.48,19.64 v1(119.54,19.57)
  L4 w0.127: v1(97.33,104.46) 98.83,102.96 100.76,102.96 103.2,100.52 v1(103.2,99.81)
  BOTTOM w0.127: D4001.1 116.33,16.96 R4009.1 116.23,17.87 C4009.1 116.46,19.12 R4006.1 117.13,20.6 118.51,20.6 v1(119.54,19.57)
3V_5V_POK: length 362.8
  TOP w0.102: v1(148.87,15.23) 149.02,15.38 C1710.1 ; PG4529.1 93.39,105.12 v1(92.76,105.12) 91.74,105.12 90.32,103.7 v1(90.32,102.79) ; C1710.1 149.03,15.78 ED1705.1 149.97,15.84 R1728.2 ; C1710.1 148.89,15.76 145.72,18.94 v1(145.72,19.4) ; v2(158.42,106.93) 158.42,106.77 v1(159.31,105.88) ; v1(163.24,60.8) 163.65,60.39 163.65,59.68 163.42,59.45 PG4531.1 ; v1(57.2,9.31) 57.2,9.87 57.71,10.38 PR5406.1
  L3 w0.102: v1(105.64,18.1) 104.06,16.53 103.01,16.53 102.65,16.17 102.59,16.11 98.26,16.11 97.45,15.29 v1(85.93,15.29) 85.93,15.11 84.78,13.96 82.56,11.74 82.23,11.74 72.57,11.74 71.03,10.2 62.66,10.2 62.34,10.52 58.41,10.52 v1(57.2,9.31) ; v1(159.31,105.88) 156.88,108.31 130.53,108.31 129.63,107.41 123.56,107.41 117.03,100.88 103.02,100.88 101.98,101.92 99.47,101.92 98.63,102.76 94.74,102.76 94.17,103.33 94.17,104.47 93.52,105.12 93.01,105.12 v1(92.76,105.12) ; v1(82.47,91.53) 82.47,92.25 82.14,92.58 82.14,97.31 84.43,99.6 85.86,99.6 86.42,100.15 87.69,100.15 87.83,100.3 87.83,100.75 89.86,102.78 90.32,102.78 v1(90.32,102.79)
  L4 w0.102: v1(145.72,19.4) 145.29,19.83 143.87,19.83 143.61,19.57 132.91,19.57 131.09,17.75 129.07,17.75 128.75,17.43 127.52,17.43 126.98,16.89 123.46,16.89 122.5,17.85 119.13,17.85 118.91,17.63 107.58,17.63 107.37,17.85 106.65,17.85 106.48,17.67 106.12,17.67 105.94,17.85 105.89,17.85 v1(105.64,18.1)
  L6 w0.102: v1(163.24,60.8) 163.73,61.28 165.99,61.28 166.25,61.55 166.25,70.11 164.59,71.77 164.59,75.96 166.04,77.41 166.93,77.41 169.01,79.49 169.01,93.22 167.45,94.78 167.45,96.54 164.72,99.27 164.72,101.78 164.34,102.16 164.34,103.23 162.5,105.07 160.12,105.07 v1(159.31,105.88)
  BOTTOM w0.102: v1(148.87,15.23) 149.37,14.73 149.37,9.81 147.8,8.25 147.8,7.99 147.5,7.69 147.14,7.69 146.89,7.94 146.89,8.47 147.14,8.73 147.55,8.73 147.7,8.88 PR5210.1 ; v1(159.31,105.88) 159.61,105.58 R4033.1 ; v1(82.47,91.53) 82.47,90.9 84.3,89.08 84.3,58.43 82.02,56.15 82.02,52.21 82.43,51.8 82.43,51.39 79.6,48.56 79.6,27.14 75,22.55 75,18.33 77.82,15.51 79.93,15.51 80.19,15.76 85.46,15.76 v1(85.93,15.29) ; v1(105.64,18.1) 105.56,18.18 104.31,18.18 R1718.2
3V_5V_POK#: length 5.9
  BOTTOM w0.127: 151.41,15.82 151.41,14.65 150.42,13.66 R1726.1 150.42,13.4 149.96,12.95 v2(149.96,12.62) ; 151.41,15.82 151.41,16.27 151.32,16.36 Q1701.6 ; 151.41,15.82 151.31,15.71 Q1701.5
3V_5V_POK_C: length 7.8
  TOP w0.127: v2(151.99,14.95) R1728.1 153.8,15.84 v1(153.92,15.71)
  BOTTOM w0.127: v1(153.92,15.71) Q1701.2 152.14,15.71 151.8,15.37 151.8,14.78 151.91,14.67 152.43,14.67 152.96,14.14 R1727.2
5V_AUX_S5: length 12.9
  TOP w0.254: v1(92.69,104.49) v2(91.87,104.49)
  TOP w0.508: PG4528.2 101.45,101.25 v1(101.37,101.17) ; v1(92.69,104.49) 92.89,104.49 92.89,104.49 PR4510.2
  L4 w0.508: v1(101.37,101.17) 101.37,101.46 100.51,102.33 98.6,102.33 98.09,102.84 94.69,102.84 93.04,104.49 v1(92.69,104.49)
5V_HDD:
  vias: v2(170.86,20.97)
5V_HDD_SIP:
  vias: v2(178.99,19.73) v3(176.58,19.07) v3(177.09,19.75)
5V_HDMI_R_S5:
  vias: v2(22.91,56.94)
5V_HDMI_S5: length 2.2
  L4 w0.762: 12.27,79.44 11.85,79.03 HDMI1.18 12.98,78.58
  vias: v2(19.45,58.31) v3(18.11,59.58) v3(18.08,58.64)
5V_S0: length 122.9
  TOP w0.508: R2612.1 148.13,77.94 147.88,77.69 v1(147.62,77.69) ; v1(142.9,20.64) 142.9,20.48 142.32,19.9 R6510.2
  L6 w0.508: v1(147.62,77.69) 149.15,77.69 150.19,78.73 153.97,78.73 154.56,79.32 154.56,80.59 154.96,80.99 154.96,85.89 154.38,86.48 148.87,86.48 147.14,88.21 147.14,99.79 144.96,101.97 137.49,101.97 v3(135.69,100.17) ; v1(154.66,18.38) 154.66,19.04 ; 154.66,19.04 153.59,19.04 151.71,20.92 143.18,20.92 v1(142.9,20.64) ; 154.66,19.04 154.66,19.04 166.52,19.04 168.32,17.24 171.68,17.24 v1(172.9,16.02) 173.62,16.02 v3(173.63,16.03) ; v1(28.24,9.74) 29.36,9.74 30.22,10.61 30.22,13.91 30.91,14.6 v1(31.24,14.6)
  BOTTOM w0.356: v1(177.49,79.62) 177.65,79.77 177.65,81.55 177.19,82.01 176.53,82.01 176.34,81.82 176.27,81.77 176.15,81.66 176.11,81.59 175.69,81.17 173.73,81.17 172.82,82.08 172.06,82.08 171.63,81.65 171.63,78.21 GPU2.P4
  BOTTOM w0.508: F6501.1 152.5,12.16 152.75,12.41 R6501.1 152.93,12.46 153.29,12.46 155.22,14.39 155.22,17.24 154.66,17.8 v1(154.66,18.38) ; R2703.2 24.69,10.54 25.48,9.74 v1(28.24,9.74)
  vias: v2(24.74,58.11) v3(24.69,27.65) v3(25.4,27.07) v3(25.4,26.23) v3(26.72,57.5) v3(27.35,56.86) v3(42.64,52.65) v3(42.67,51.81) v3(49.38,93.21) v3(50.01,93.77) v3(68.22,100.42) v3(69.06,100.42) v3(134.8,100.17) v3(135.81,106.01) v3(136.7,106.01) v3(166.37,111.4) v3(166.37,110.51) v3(171.02,19.17)
5V_S0_ON: length 5
  TOP w0.127: v1(131.96,101.52) 132.53,101.52 132.84,101.83 132.84,102.49 v2(132.7,102.63) 132.43,102.9 C4010.1
  BOTTOM w0.127: U4001.3 132.74,101.67 132.59,101.52 v1(131.96,101.52) 131.42,101.52 R4013.2
5V_S5: length 336.1
  TOP w0.406: U4002.3 89.84,91.03 89.33,90.52 C4032.1
  TOP w0.457: PC5202.1 143.25,5.33 v1(142.59,5.33)
  TOP w0.508: PR5118.1 38.73,11.32 37.89,12.16 v2(37.38,12.67) 37.08,12.97 EC8914.1 v3(34.14,12.97) ; v1(72.06,9.82) 71.85,10.03 71.38,10.03 68.81,12.6 v1(68.81,12.79) ; 153.28,64.51 v1(155.17,64.51) 155.17,65.42 154.76,65.83 154.76,70.37 155.75,71.37 v2(155.75,72) 155.75,76.93 154.61,78.07 154.61,79.34 154.25,79.7 v1(153.62,79.7) 153.62,79.38 152.31,78.07 151.18,78.07 v1(151.05,77.94) ; 153.28,64.51 v1(153.28,63.74) ; 153.28,64.51 151.84,64.51 151.43,64.1 v1(151.43,63.85) ; v1(158.34,24.96) 158.34,27.82 162.63,32.11 162.63,33.66 163.48,34.5 164.87,35.37 166.53,37.04 166.53,37.9 166.64,38.01 166.74,38.35 167.56,39.17 v3(167.56,43.15) ; v1(89.12,91.31) 89.12,90.55 C4032.1 ; v1(153.34,90.52) 152.98,90.87 152.2,90.87 150.29,92.78 v1(150.29,93.56) 145.85,93.56 v1(144.07,91.79) 143.43,91.15 143.43,90.52 142.42,89.5 141.78,89.5 141.15,88.87 v3(139.24,88.87) ; v1(54.91,14.19) 54.71,13.99 PC5401.1 54.66,13.3 54.23,12.87 v2(54.23,10.23) 54.23,7.25 v1(55.42,6.06)
  L3 w0.508: v1(68.81,12.79) 67.92,13.68 63.55,13.68 63.53,13.7 58.83,13.7 57.71,14.82 55.54,14.82 55.17,14.45 55.17,14.44 v1(54.91,14.19) ; v1(142.59,5.33) 146.89,5.33 148.26,6.7 148.26,7.14 148.76,7.64 152.42,7.64 v1(153.59,8.81) ; v1(106.12,16.81) 105.21,16.81 104.5,16.09 103.19,16.09 102.77,15.68 98.95,15.68 94.48,11.21 73.03,11.21 72.06,10.24 v1(72.06,9.82)
  L4 w0.508: v1(151.43,63.85) 151.43,62.96 154.12,60.27 v1(154.12,52.4) ; v1(153.62,79.7) 154.57,79.7 v1(155.42,80.55) 155.12,80.86 155.12,85.82 153.72,87.21 153.72,90.14 v1(153.34,90.52) ; v3(116.3,104.99) 116.3,103.78 114.6,102.07 110.92,102.07 106.22,97.37 106.22,96.65 102.25,92.68 91.62,92.68 90.25,91.31 v1(89.12,91.31)
  L6 w0.508: v3(34.14,12.97) 34.15,12.98 44.31,12.98 50.72,6.57 54.91,6.57 v1(55.42,6.06) ; v3(133.35,99.46) 134.29,99.46 134.52,99.23 139.5,99.23 140.64,98.09 143.05,98.09 144.07,97.07 v1(144.07,91.79) ; v1(146.75,23.35) 146.75,23.6 147.59,24.44 150.98,24.44 151.02,24.4 157.78,24.4 v1(158.34,24.96)
  BOTTOM w0.203: PU4702.36 155.19,80.79 v1(155.42,80.55) ; PU4701.36 154.93,64.74 v1(155.17,64.51) ; PU4701.3 153.28,63.74 v1(153.28,63.74) ; v1(132.38,102) 132.46,102.07 U4001.4 ; 140.14,91.91 PU4801.7 ; v1(153.62,79.7) 153.54,79.78 PU4702.3 ; PU4801.36 143.83,92.02 v1(144.07,91.79) ; 150.99,64.55 151.24,64.79 PU4701.7 ; 151.49,80.68 PU4702.7
  BOTTOM w0.305: v1(142.59,5.33) 142.89,5.33 142.92,5.3 PU5201.21 ; v1(154.12,52.4) PU5001.4
  BOTTOM w0.406: U4006.3 106.16,16.85 v1(106.12,16.81)
  BOTTOM w0.508: v1(106.12,16.81) 105.79,17.14 C4031.1 ; 150.99,64.55 149.91,63.47 PC4707.1 150.21,63.06 PR4702.2 151.04,63.07 151.04,63.45 v1(151.43,63.85) ; v1(153.34,90.52) 153.27,90.45 153.27,89.84 PR4676.1 ; PR4657.1 149.97,92.68 149.97,93.24 v1(150.29,93.56) ; v1(151.05,77.94) 150.19,77.94 PC4721.1 150.06,78.4 150.54,78.88 150.54,79.73 151.49,80.68 ; Q6505.E 146.75,22.97 v1(146.75,23.35) ; v1(54.91,14.19) 54.53,14.57 PU5401.6 ; Q6401.E 54.63,6.86 v1(55.42,6.06) ; R3402.1 19.02,49.29 17.45,47.72 17.45,42.13 17.88,41.7 R3406.1 R3405.1 21.08,41.7 21.64,42.26 22.63,42.26 ; v3(139.24,88.87) 139.67,88.43 PR4803.2 140.08,89.83 PC4807.1 140.13,89.98 140.13,91.91 140.14,91.91 ; v1(154.12,52.4) 154.13,52.4 PC5001.1 ; v1(153.62,79.7) 153.62,78.16 153.15,77.69 PR4712.2 ; v1(22.66,72.35) 22.63,72.33 22.63,71.7 21.44,70.5 PR4303.1 ; Q6402.E 70.13,14.12 v1(68.81,12.79) ; v1(158.34,24.96) 158.34,22.5 157.52,21.67 157.52,18.2 156.54,17.23 156.54,13.69 154.35,11.5 154.35,9.85 153.59,9.08 v1(153.59,8.81)
  vias: v2(24.05,56.33) v2(24.64,36.34) v2(126.16,104.97) v3(24.05,44.92) v3(24.05,44.03) v3(24.15,36.82) v3(24.64,56.73) v3(25.12,36.82) v3(25.35,56.2) v3(26.11,90.24) v3(26.64,91) v3(27,90.21) v3(38.89,98.11) v3(39.5,98.75) v3(82.07,106.93) v3(82.68,107.51) v3(83.23,108.17) v3(116.3,106.77) v3(116.3,105.88) v3(117.35,106.77) v3(117.35,105.88) v3(117.35,104.99) v3(118.26,106.77) v3(118.26,105.88) v3(118.26,104.99) v3(131.98,100.68) v3(132,99.84) v3(132.89,100.17) v3(164.36,112.67) v3(165.23,112.06) v3(165.83,112.69) v3(167.54,44.01)
5V_STB: length 3.2
  TOP w0.203: HDA27.47 25.55,13.58 25.75,13.37 26.26,13.37 26.52,13.12 v2(26.52,12.84)
  TOP w0.254: R2725.2 26.52,12.74 v2(26.52,12.84)
5V_VCONN_EN: length 2.4
  TOP w0.127: U3703.3 25.58,37.55 25.83,37.81 26.29,37.81 v2(26.47,37.63) R3734.2
5V_VCONN_P1: length 6.1
  TOP w0.127: R3706.1 22.53,39.89 22.3,39.67 v2(21.89,39.67) ; R3706.1 23.24,40.35 24.18,40.35 24.61,39.92 U3703.5 ; R3706.1 22.78,41.01 R3737.1 ; R3706.1 22.98,39.69 U3703.6
5V_VCONN_P1_CCG4: length 2.9
  TOP w0.127: R3737.2 24.31,41.26 v2(25.25,41.26) U3701.8
+1.8VALW_EC: length 3.4
  TOP w0.203: KBC24.54 188.81,43.4 188.81,43.34 188.24,42.77 v1(188.24,42.68)
  BOTTOM w0.457: R2462.1 C2423.1
  BOTTOM w0.508: R2462.1 188.24,43.43 v1(188.24,42.68)
+3V_1D8V_AVDD: length 7.5
  TOP w0.203: HDA27.16 24.75,20.93 24.81,21 24.81,21.17
  TOP w0.254: R2705.2 R2710.2 v1(24.08,24.12) 23.7,23.74 v2(23.7,23.21) 23.7,22.57 24.2,22.06 R2713.2 24.61,21.68 24.81,21.48 24.81,21.17
  BOTTOM w0.254: C2715.1 24.05,24.12 v1(24.08,24.12)
+3V_AVDD: length 14.3
  TOP w0.203: v1(27.61,19.65) 27.57,19.65 27.23,19.31 HDA27.12 ; HDA27.4 v1(27.66,16.11)
  TOP w0.508: v1(28.88,13.05) 28.88,12.92 29.44,12.36 R2722.1 30.33,12.16 R2728.2 ; v1(27.61,19.65) 27.64,19.65 28.42,20.43 C2719.1 28.7,21.05 28.7,23.94 C2716.1 28.93,25.11 R2731.2
  L6 w0.508: v1(28.88,13.05) 28.88,14.99 27.76,16.11 v1(27.66,16.11)
  vias: v2(26.29,18.15)
+3VALW_EC: length 452.2
  TOP w0.203: v1(192.66,42.69) 193.21,43.24 KBC24.43 ; v1(184.45,35.63) 184.24,35.84 KBC24.82 ; KBC24.103 187.21,27.49 v1(187.3,27.4) ; v1(192.43,29.86) 192.38,29.86 192.01,29.49 KBC24.115 ; KBC24.65 183.26,43.27 v1(183.06,43.48) ; KBC24.5 197,31.84 194.99,33.85 194.99,34.06 v1(194.95,34.1) ; KBC24.22 197.72,38.64 197.1,39.26 v1(197.05,39.26) 197.08,39.24 197.08,38.73 196.99,38.64 196.99,37.91 197.46,37.44 KBC24.19
  TOP w0.254: v1(31.04,34.76) 29.64,34.76 29.08,35.32 R3707.1
  TOP w0.305: DB3.1 163.31,15.35 163.98,16.02 R2480.2
  TOP w0.508: v1(123.06,28.49) 123.15,28.49 123.87,27.76 123.87,26.51 126.67,23.71 v1(126.67,23.33) ; v1(174.29,11.9) 174.1,11.71 170.55,11.71 169.62,12.64 169.62,12.65 166.17,16.09 v2(165.45,16.09) 165.43,16.07 164.06,16.07 R2480.2 R2414.2 ; v1(200.07,33.65) R2446.2
  L3 w0.254: v1(31.04,34.76) 31.04,29.93 31.97,29 32.42,29 34.02,27.4 34.68,27.4 36.88,25.2 36.88,23.65 37.31,23.22 37.31,12.67 39.02,10.95 42.18,10.95 42.57,11.35 44.17,11.35 45.64,9.87 45.64,6.67 47.14,5.17 49.45,5.17 50.52,4.11 60.98,4.11 61.26,3.83 103.22,3.83 103.55,4.16 v1(103.55,4.66)
  L3 w0.508: v1(184.35,17.72) 184.38,17.75 185.98,17.75 186.46,17.26 186.46,15.27 185.12,13.94 v1(184.07,13.94) 181.66,11.52 179.75,11.52 179.49,11.26 174.94,11.26 v1(174.29,11.9)
  L6 w0.508: 127.56,13.68 127.56,17.03 127.96,17.44 127.96,22.04 v1(126.67,23.33) ; 127.56,13.68 130.86,13.68 133.63,10.91 141.23,10.91 142.73,9.41 148.26,9.41 150.11,7.56 150.11,6.8 151.06,5.85 156.56,5.85 158.32,7.61 186.36,7.61 v1(186.94,8.2) ; 127.56,13.68 127.33,13.68 124.42,10.77 120.2,10.77 117.86,8.44 105.04,8.44 103.55,6.95 v1(103.55,4.66) ; v1(146.23,31.44) 146.25,31.44 147.85,33.04 150.44,33.04 ; v1(179.12,30.57) 178.33,31.36 172.25,31.36 172.1,31.51 167.46,31.51 v1(167.44,31.54) 166.9,32.07 152.88,32.07 151.92,33.04 150.44,33.04 ; 150.44,33.04 v1(150.44,32.2) ; v1(177.24,64.63) 175.99,65.88 172.4,65.88 165.66,72.62 165.66,75.52 166.48,76.34 166.49,76.34 167.37,76.34 170.13,79.1 170.13,81.41 171.8,83.09 171.8,83.78 171.8,83.78 171.8,84.3 170.08,86.03 170.08,94.2 170.89,95.01 170.89,96.87 170.51,97.25 167.84,97.25 165.4,99.68 165.4,102.06 165.02,102.44 165.02,103.63 161.83,106.82 161.45,106.82 161.12,107.15 159.7,107.15 159.12,106.57 158.32,106.57 157.91,106.16 v1(157.91,105.88) ; v1(179.35,35.63) 180.8,35.63 181.74,36.57 182.35,36.57 182.73,36.2 182.73,36.19 183.28,35.63 v1(184.45,35.63)
  BOTTOM w0.254: R2443.1 191.87,33.42 193.09,33.42 C2413.1 ; R2415.2 184.99,27.48 185.7,26.76 186.23,26.76 ; D4304.2 152.49,25.86 152.47,25.88 152.47,28.05 151.46,29.07 151.46,29.76 151,30.22 151,31.64 v1(150.44,32.2) ; R2450.2 C2411.1 ; PR4445.1 PR4439.1 PR4438.1 146.23,31.03 v1(146.23,31.44)
  BOTTOM w0.356: 184.45,36.11 184.91,36.57 C2414.1
  BOTTOM w0.381: v1(184.45,35.63) 184.45,36.11 ; 196.04,35.19 195.64,34.8 195.64,34.73 195.01,34.1 v1(194.95,34.1)
  BOTTOM w0.406: 196.04,35.19 Q2605.5 Q2605.2
  BOTTOM w0.508: 183.4,45.41 181.69,47.12 179.9,53.3 179.63,54.19 179.63,54.92 179.63,55.45 179.3,55.78 179.11,55.97 179.11,58.79 178.97,58.93 178.97,61.76 177.24,63.49 v1(177.24,64.63) ; 183.4,45.41 183.03,45.04 183.03,43.5 v1(183.06,43.48) ; 183.4,45.41 185.04,45.41 185.88,44.57 C2411.1 ; v1(194.95,34.1) 194.9,34.05 194.49,34.05 C2413.1 ; v1(184.07,13.94) 184.45,13.55 184.45,10.62 186.88,8.2 v1(186.94,8.2) ; Q2415.G 190.42,34.44 190.62,34.64 v1(191.06,34.64) ; R4032.1 157.83,105.5 157.91,105.58 v1(157.91,105.88) ; D4306.2 161.52,32.2 163.53,32.2 D4305.2 165.82,33.15 v1(167.44,31.54) ; v1(192.43,29.86) 192.43,29.33 C2422.1 ; v1(197.05,39.26) 197.08,39.24 197.14,39.24 197.76,38.62 C2429.1 C2410.1 ; v1(184.35,17.72) 184.35,18.97 183.56,19.76 183.56,22.52 184.15,23.11 184.15,23.87 186.23,25.95 186.23,26.76 186.43,26.97 186.43,27.37 C2420.1 186.94,27.45 186.99,27.4 v1(187.3,27.4) ; R2608.1 v1(123.06,28.49)
  vias: v1(189.74,45.41)
+5V_AVDD: length 5.5
  TOP w0.203: v1(22.4,12.54) 22.4,13.1 22.75,13.44 HDA27.40
  BOTTOM w0.508: R2703.1 24.08,12.36 23.87,12.16 23.49,12.16 C2711.1 23.19,11.85 C2710.1 22.38,12.51 v1(22.4,12.54) 22.4,12.59 v2(22.03,12.96)
+5V_KB_BL: length 64
  TOP w0.508: v1(104.26,4.72) 104.32,4.66 AFTP6529.1 106.78,4.66 C6501.1 107.36,4.59 108,5.22 108,7.84 109.55,9.39 124.23,9.39 125.86,11.01 126.92,11.01 127.4,11.5 v1(127.4,11.85)
  L6 w0.508: v1(148.89,6.87) 148.36,6.34 144.7,6.34 140.9,10.14 133.26,10.14 130.9,12.49 127.83,12.49 127.4,12.07 v1(127.4,11.85)
  BOTTOM w0.508: v1(148.89,6.87) 149.16,7.14 149.16,8.46 150.62,9.92 F6501.2 150.62,11.47 R6501.2 ; KBBL1.1 v1(104.26,4.72)
+5V_PVDD: length 2
  TOP w0.203: v1(25.14,13.2) 25.15,13.2 HDA27.46 ; HDA27.41 23.15,13.02 v3(23.09,12.96)
  vias: v1(25.7,12.87) v2(25.22,13.96)
+V1.00A_SIP: length 28.1
  TOP w0.406: v1(120.06,46.17) 120.66,45.57 120.91,45.57 C2101.1
  TOP w0.508: v1(120.04,48.81) 119.56,48.81 R1803.2 ; v1(114.16,42.78) 115.03,42.78 R2108.1 ; C2121.1 114.8,48.3 v1(115,48.1)
  L4 w0.508: v1(126.69,43.98) 126.44,43.73 126.44,42.41 v1(126.49,42.36) 126.7,42.36 126.75,42.41 127.52,42.41 127.73,42.19 129.68,42.19 131.72,40.15 133.93,40.15 134.49,40.71 v1(134.77,40.71)
  L6 w0.127: 116.57,41.71 115.89,41.71
  BOTTOM w0.127: v1(120.52,34.87) 120.52,35.24 120.53,35.25 120.53,35.41 120.52,35.42 120.52,36.61 CPU1.L1 ; CPU1.A14 125.6,44.19 126.49,44.19 v1(126.69,43.98) ; v1(117.87,35.3) 117.87,35.41 117.78,35.49 117.78,36.6 CPU1.T1
  BOTTOM w0.152: CPU1.AK20 109.59,47.77 109.33,48.04 v1(109.33,48.66)
  BOTTOM w0.254: CPU1.P18 118.08,46.47 v1(118.39,46.17) ; CPU1.AB17 114.8,45.82 CPU1.Y18 114.8,47.12 CPU1.AB19 ; CPU1.K17 120.41,45.82 v1(120.06,46.17) ; v1(126.49,42.36) 126.41,42.36 126.1,42.05 125.84,42.05 125.59,41.8 CPU1.A10
  BOTTOM w0.305: CPU1.L21 119.65,48.42 v1(120.04,48.81) ; CPU1.AB19 CPU1.AB20 114.7,47.77 115,48.08 115,48.1 v1(115,48.1)
  vias: v2(119.4,34.84)
+V1.00U_CPU:
  vias: v2(113.08,15.84)
+V1.8A: length 234.9
  TOP w0.508: v1(72.37,16.29) 71.46,15.38 53.8,15.38 50.19,11.78 47.86,11.78 46.97,10.89 43.99,10.89 v1(43.61,10.51) ; v1(93.97,21.81) 93.97,21.74 94.38,21.33 96.52,21.33 97.1,21.91 R1821.1 97.13,21.94 R1820.1 ; v1(113.66,19.98) 114.25,19.98 R1915.2 114.37,20.57 R1916.2 114.02,21.25 113.79,21.48 113.79,23.01 112.99,23.82 111.83,23.82 111.19,23.18 110.84,23.18 110.59,22.93 110.59,22.62 109.85,21.89 v1(109.85,21.84) 109.8,21.84 109.75,21.89 R1920.2 109.09,21.81 R1918.2 ; R1104.1 110.79,36.68 110.79,34.93 v1(110.97,34.75) ; v1(144.65,2.1) 144.65,2.17 145.34,2.86 152.98,2.86 153.44,2.4 153.44,1.97 153.89,1.52 155.24,1.52 156.79,3.06 156.79,5.2 158.1,6.51 159.38,6.51 159.81,6.94 169.78,6.94 171.75,8.91 v1(171.75,9.11) ; R1607.1 v1(86.59,22.7)
  L3 w0.508: v1(171.75,9.11) 172.31,9.67 185.76,9.67 189.95,13.86 191.23,13.86 194.94,17.57 194.94,32.5 193.65,33.8 193.65,35.46 191.23,37.88 191.23,39.37 189.99,40.61 188.33,40.61 187.96,40.98 187.96,42.05 187.91,42.1 v1(187.91,42.13) ; v1(113.66,19.98) 113.66,16.44 124.1,6 128.96,6 129.39,5.58 v1(129.39,5.38) ; v1(106.22,25.37) 106.54,25.37 109.85,22.06 v1(109.85,21.84)
  L4 w0.508: v1(43.61,10.51) 42.54,11.57 v1(42.54,14.55)
  L6 w0.508: v1(144.65,2.1) 132.23,2.1 129.74,4.59 129.74,5.02 v1(129.39,5.38) ; 79.96,21.23 80.29,21.56 85.44,21.56 v1(86.59,22.7) 87.48,21.81 v1(93.97,21.81) 93.97,22.2 94.38,22.6 96.95,22.6 97.51,22.04 99.02,22.04 99.95,22.97 99.95,24.05 100.63,24.73 104.57,24.73 105.21,25.37 v1(106.22,25.37) 106.22,26.46 107.21,27.45 107.21,29.63 108.01,30.42 109.65,30.42 110.54,31.31 110.54,33.27 110.99,33.72 110.99,34.72 110.97,34.75 v1(110.97,34.75)
  BOTTOM w0.508: R2462.2 187.4,42.51 187.78,42.13 v1(187.91,42.13) ; v1(106.22,25.37) 106.53,25.67 R1818.2 107.95,25.67 108.25,25.37 R1739.1
  vias: v2(23.95,27.42) v3(20.42,28.26) v3(23.54,28.29)
+V1.8A_SIP: length 8.1
  L3 w0.127: 113.46,38.9 113.46,38.09
  BOTTOM w0.178: CPU1.AA1 115.11,36.72 115.11,35.73 v1(115.09,35.7)
  BOTTOM w0.254: CPU1.AH12 CPU1.AH11 ; CPU1.AH11 CPU1.AH10 ; CPU1.AH11 CPU1.AF11 113.21,42.98 v1(113.21,43.32) 113.21,44.06 113.36,44.21 113.36,44.75 CPU1.AF16
  BOTTOM w0.279: v1(110.06,44.07) 110.06,44.17 CPU1.AK15
  vias: v1(115.29,37.86) v2(115.49,37.23)
+V3.3A_SIP: length 68.5
  TOP w0.508: 81.05,25.72 81.05,25.56 80.34,24.86 77.46,24.86 75.59,22.99 75.59,21.99 74.88,21.28 72.11,21.28 71.75,21.28 70.74,20.26 70.74,18.91 R2101.1 ; 81.05,25.72 81.05,25.72 81.15,25.82 81.15,42.94 89.36,51.15 v1(92.76,51.15) ; 81.05,25.72 v2(81.06,25.72)
  BOTTOM w0.254: v1(110.84,46.14) 110.52,45.82 CPU1.AK17 ; v1(116.58,44.11) 116.7,44.23 116.7,44.75 116.75,44.79 CPU1.T16
  BOTTOM w0.305: v1(112.01,43.98) 112.09,44.07 CPU1.AG15 111.44,45.17 CPU1.AJ16 ; CPU1.V19 115.87,46.7 115.87,45.59 CPU1.Y16 CPU1.Y15 115.37,44.52 v1(115.03,44.19) 114.98,44.13 114.16,44.13 CPU1.AD15 ; v1(111.05,48.89) 111.05,48.84 111.26,48.63 CPU1.AJ21
  BOTTOM w0.508: v1(92.76,51.15) 92.76,50 90.73,47.97 90.72,47.97 90.32,47.57 90.32,45.41 92.48,43.25 v1(94.69,43.25)
+VCCAMPHYPLL_1P0: length 8.7
  TOP w0.254: C2113.1 120.78,37.33 R2107.2 120.78,38.61 120.42,38.97 120.42,40.22 120.41,40.23 120.41,40.62 120.42,40.63 v2(120.42,40.99) 120.42,43.35 120.93,43.86 v1(120.93,44.06)
  BOTTOM w0.254: v1(120.93,44.06) 120.9,44.09 120.9,44.1 120.48,44.52 CPU1.K15 CPU1.L15
+VCCAPLL_1P0: length 6.7
  TOP w0.254: C2114.1 116,44.09 v2(116,43.91) 116,43.04 116.27,42.77 v1(116.27,42.77) 116.27,42.65 115.93,42.31 115.93,41.83 115.63,41.53 R2108.2
  BOTTOM w0.254: v1(116.27,42.77) 116.3,42.81 116.3,43.7 116.11,43.9 116.11,44.35 CPU1.V15
+VCCCLK2: length 30.1
  L4 w0.254: v1(121.56,46.88) 121.16,47.28 121.16,49.19 122.02,50.04 123.86,50.04 129.36,44.54 135.26,44.54 138.2,41.61 138.62,41.61 138.66,41.64 v1(138.88,41.64)
  BOTTOM w0.203: CPU1.K19 120.53,47.12 120.89,46.76 121.44,46.76 v1(121.56,46.88)
  BOTTOM w0.254: R2109.2 135.46,41.49 v2(136.2,40.75) 136.57,40.38 C2115.1 137.62,40.38 v1(138.88,41.64)
+VCCCLK4: length 38.9
  TOP w0.254: v1(138.48,44.47) v2(139.04,44.47)
  L4 w0.254: v1(138.48,44.47) 137.78,44.47 135.5,46.75 132.87,46.75 131.49,48.12 131.49,55.52 130.87,56.14 128.04,56.14 125.58,53.69 122.35,53.69 122.34,53.68 121.01,53.68 119.43,52.09 119.43,49.13 v1(118.38,48.08)
  BOTTOM w0.254: R2110.2 136.29,44.42 C2119.1 137.44,43.88 138.02,44.47 v1(138.48,44.47) ; CPU1.N20 118.69,47.77 v1(118.38,48.08)
+VCCCLK5: length 27.8
  L4 w0.254: v1(120.06,47.46) 120.07,47.46 120.57,47.97 120.57,49.08 121.88,50.39 124.04,50.39 125.92,48.5 125.93,48.5 129.26,45.18 135.69,45.18 137.21,43.65 v1(138.48,43.65)
  BOTTOM w0.254: v1(120.06,47.46) 119.98,47.46 CPU1.L19 ; v2(138.96,43.2) 138.5,43.65 v1(138.48,43.65) 137.62,42.79 C2122.1 135.81,42.79 R2111.2
+VCCCOREG0: length 2
  TOP w0.254: v1(122.15,54.15) 122.05,54.15 TP701.1
  BOTTOM w0.127: CPU1.K32 121.11,54.45 121.56,54.45 121.82,54.19 122.1,54.19 v1(122.15,54.15)
+VCCCOREG1: length 1.2
  TOP w0.254: v1(110.92,55.06) 110.51,55.06 TP707.1
  BOTTOM w0.254: v1(110.92,55.06) 110.92,55.01 110.59,54.68 CPU1.AK32
+VCCDSW_1P0: length 4.1
  TOP w0.254: v1(108.86,35.38) 108.88,35.38 109.29,34.97 v2(109.88,34.97) 109.93,35.02 C2103.1
  BOTTOM w0.254: v1(108.86,35.38) 109.28,35.38 109.3,35.41 109.45,35.41 109.73,35.68 109.73,35.83 109.82,35.92 109.82,36.71 CPU1.AL1
+VCCFUSEPRG: length 4.2
  TOP w0.152: 123.35,46.09 123.07,46.37 122.68,46.37 v1(122.22,46.83)
  TOP w0.254: v2(124.89,45.3) R703.1 123.7,45.75 123.35,46.09
  BOTTOM w0.254: CPU1.G20 121.92,47.29 122.22,46.98 v1(122.22,46.83)
+VCCGT: length 2.4
  BOTTOM w0.127: CPU1.A58 126.49,68.98 v1(126.49,68.98)
  BOTTOM w0.178: CPU1.A66 125.67,73.85 126.44,73.85 v1(126.46,73.88)
  BOTTOM w0.254: v1(126.13,71.44) 126.12,71.46 CPU1.A62
  vias: v1(114.75,77.47) v1(114.74,76.7) v1(114.73,72.13) v1(115.64,72.15) v1(115.65,76.7) v1(115.65,74.09) v1(116.58,77.47) v1(117.48,76.7) v1(117.48,75.4) v1(117.48,74.09) v1(117.48,72.79) v1(118.41,77.49) v2(114.86,95.6) v2(121.99,91.41) v2(122.73,93.06) v3(113.48,88.56) v3(113.49,87.6) v3(113.46,86.58) v3(113.47,85.44) v3(113.47,84.42) v3(114.32,70.63) v3(114.32,69.74) v3(114.32,68.85) v3(114.35,67.94) v3(114.35,67.05) v3(114.6,88.99) v3(114.6,87.98) v3(114.6,87.09) v3(114.6,85.82) v3(114.6,84.93) v3(114.6,83.91) v3(114.6,83.02) v3(116.24,88.89) v3(116.23,85.72) v3(116.24,84.83) v3(116.23,81.78) v3(116.24,80.89) v3(116.25,87.98) v3(116.25,87.09) v3(116.25,83.91) v3(116.25,83.02) v3(116.25,79.98) v3(116.25,79.09) v3(117.3,88.89) v3(117.27,87.98) v3(117.27,87.09) v3(117.28,85.72) v3(117.3,84.83) v3(117.27,83.91) v3(117.27,83.02) v3(117.28,81.78) v3(117.3,80.89) v3(117.27,79.98) v3(117.27,79.09) v3(118.19,88.89) v3(118.16,87.98) v3(118.16,87.09) v3(118.17,85.72) v3(118.19,84.83) v3(118.16,83.91) v3(118.16,83.02) v3(118.17,81.78) v3(118.19,80.89) v3(118.16,79.98) v3(118.16,79.09) v3(120.45,69.74) v3(120.5,68.8) v3(120.47,67.89) v3(120.5,67) v3(128.83,94.83) v3(129.72,98.01) v3(129.72,97.12) v3(129.72,96.23) v3(129.72,95.34) v3(129.72,94.45) v3(129.72,93.56) v3(130.53,98.31) v3(130.53,97.48) v3(130.53,96.64) v3(131.37,98.31) v3(131.37,97.48) v3(131.37,96.64) v3(131.62,92.04) v3(132.21,98.31) v3(132.21,97.48) v3(132.21,96.64) v3(132.64,91.66) v3(133.04,98.31) v3(133.04,97.48) v3(133.04,96.64) v3(133.4,91.02) v3(133.53,92.17) v3(133.88,98.31) v3(133.88,97.48) v3(133.88,96.64) v3(134.16,91.53) v3(134.8,90.9)
+VCCIO: length 12.3
  TOP w0.127: 106.48,65.57 106.5,65.6 107.59,65.6 107.62,65.57 ; 107.16,60.09 107.57,60.09
  TOP w0.508: R801.1 121.26,63.92 121.26,63.91 120.56,63.21 v1(120.53,63.21)
  L3 w0.508: v3(111.94,65.02) 113.74,63.21 v1(120.53,63.21)
  vias: v1(111.12,59.63) v2(92.66,71.39) v3(111.68,53.94) v3(111.68,53.05) v3(111.68,52.16) v3(111.94,63.11)
+VCCIO_SIP:
  vias: v2(94.99,89.35)
+VCCMPHYGTAON_1P0_LS_SIP: length 2.3
  BOTTOM w0.254: CPU1.AF21 112.93,48.42 112.87,48.42 v1(112.52,48.07)
  BOTTOM w0.305: v1(117.57,48.1) 117.23,47.77 CPU1.T20 CPU1.T19 ; v1(112.52,48.07) 112.82,47.77 CPU1.AF20
  vias: v1(119.47,43.98) v2(94.79,35.35) v3(89.99,33.75) v3(89.97,25.24) v3(90.6,24.35) v3(96.32,35.5) v3(98.07,17.49) v3(98.91,17.49)
+VCCPAZIO: length 57.8
  TOP w0.254: v1(69.7,19.32) 69.47,19.09 R2101.2 69.47,18.1 v2(69.01,17.64) 68.86,17.49 R2102.2
  L6 w0.254: v1(111.66,49.06) 111.3,49.42 110.74,49.42 110.29,48.96 110.29,44.82 110.06,44.59 ; 106.2,43.58 105.87,43.58 102.21,39.92 100.81,39.92 97,36.11 94.56,36.11 90.73,32.27 86.61,32.27 77.21,22.88 75.44,22.88 73.82,21.25 71.63,21.25 v1(69.7,19.32)
  BOTTOM w0.254: v1(111.66,49.06) 111.66,48.53 111.63,48.51 111.63,47.57 111.26,47.19 CPU1.AJ19
+VCCPDSW_3P3: length 83.6
  TOP w0.254: v2(57.58,20.11) v1(57.17,20.51)
  L6 w0.127: 108.51,42.69 108.99,42.69
  L6 w0.254: 110.34,42.75 110.37,42.75 110.56,42.94 110.56,43.32 111.05,43.81 v1(111.05,44) 111.05,45.51 111.33,45.79 111.33,48 112.14,48.81 112.14,49.32 112.45,49.62 114.19,49.62 114.55,49.27 v1(114.55,49.04) ; 106.27,41.93 105.61,41.93 105.1,41.42 104.24,41.42 102.39,39.56 101.24,39.56 96.21,34.54 94.03,34.54 91.39,31.89 86.77,31.89 77.37,22.5 75.6,22.5 73.98,20.87 71.83,20.87 70.97,20.01 70.97,19.65 70.03,18.72 66.18,18.72 65.4,19.5 58.19,19.5 v1(57.17,20.51)
  BOTTOM w0.203: CPU1.AJ17 111.18,45.82 110.86,45.5 110.86,44.19 v1(111.05,44)
  BOTTOM w0.229: v1(114.55,49.04) 114.55,48.89 114.2,48.53 114.2,46.9 CPU1.AD18
  BOTTOM w0.254: R1711.2 59.03,15.18 R1707.1 59.74,17.33 57.17,19.89 v1(57.17,20.51) ; CPU1.AD18 CPU1.AD17
+VCCPRIM_CORE: length 5.3
  L6 w0.127: 111.58,41.04 111.58,40.71 111.17,40.3 110.87,40.3
  BOTTOM w0.254: v1(113.28,49.04) 113.36,48.96 113.36,47.55 CPU1.AF19
  BOTTOM w0.305: v1(116,49.01) 116,48.71 CPU1.V21 CPU1.V20 ; CPU1.AF18 CPU1.AF19
  vias: v2(93.65,20.92) v3(93.67,20.21) v3(94.51,20.18) v3(96.24,28.69) v3(98.4,35.25)
+VCCPRTC_3P3: length 73.7
  TOP w0.203: C2118.1 111.17,49.7 110.59,49.11 110.59,48.71
  TOP w0.254: 110.59,48.71 110.36,48.48 109.85,48.48 C2117.1 109.29,46.86 v1(109.33,46.83) ; v1(81.17,17.97) 80.97,17.77 80.97,16.5 80.69,16.22 79.22,16.22 78.99,16.45 v2(77.57,16.45) 77.19,16.45 77.01,16.27 R2106.2
  L3 w0.229: v1(109.33,46.83) 109.33,47.79 108.91,48.2 106.88,48.2 106.86,48.23
  L3 w0.254: 106.86,48.23 106.53,48.23 106.2,47.9 105,47.9 104.08,46.97 104.08,46.09 102.44,44.44 101.5,44.44 v1(101.47,44.42) 103.17,42.71 103.17,36.31 104.42,35.07 104.42,34.45 103.74,33.77 101.88,33.77 100.28,32.17 98.11,32.17 97.43,31.49 97.43,29.89 99.01,28.31 99.01,24.59 98.19,23.77 98.19,22.32 95.3,19.42 82.62,19.42 v1(81.17,17.97)
  BOTTOM w0.127: v1(101.47,44.42) 101.52,44.37 103.6,44.37 CPU1.BB14
  BOTTOM w0.254: v1(109.33,46.83) 109.35,46.8 110.03,46.8 110.35,47.12 CPU1.AK19
+VCCSA: length 2.1
  TOP w0.508: 124.61,50.44 124.61,49.29 R735.1
  vias: v1(111.5,51.2) v1(111.48,50.36) v2(121.36,52.29) v2(134.75,55.62) v3(112.95,52.04) v3(114.22,52.04) v3(115.37,52.04) v3(116.43,52.04) v3(117.47,52.04) v3(118.44,52.04) v3(120.45,52.24) v3(120.45,51.38) v3(120.42,50.46) v3(132.13,56.48) v3(132.13,55.59) v3(132.13,54.7) v3(132.51,57.24) v3(133.02,56.48) v3(133.02,55.59) v3(133.02,54.7)
+VCCSFR: length 53.9
  TOP w0.254: C721.1 120.42,47.77 120.26,47.93 120.25,47.93 v1(120.06,48.12) 120.27,48.33 C720.1 ; v1(122.98,26.99) 122.98,26.86 v2(122.58,26.46)
  L4 w0.127: 122.68,42.71 123.11,42.28 123.09,42.28 122.65,41.85 121.28,41.85 120.78,42.36 121.13,42.71 122.68,42.71
  L4 w0.254: v1(120.06,48.12) 120.06,48.12 119.59,47.66 119.59,45.39 120.45,44.54 120.45,42.69 120.78,42.36 ; v1(122.98,26.99) 123.01,27.01 123.02,27.01 123.57,27.57 123.57,31.35 121.54,33.39 121.54,35.71 124.27,38.45 124.38,38.45 124.91,38.97 124.91,40.49 123.11,42.28
  L6 w0.254: v1(111.56,14.41) 112.1,13.86 113.46,13.86 113.82,14.22 113.82,14.45 117.6,18.23 117.6,20.62 122.4,25.42 122.4,26.24 122.86,26.69 122.86,26.86 v1(122.98,26.99)
  BOTTOM w0.254: v1(111.56,14.41) 111.64,14.41 112.16,14.93 R4038.2 ; CPU1.K21 120.36,48.42 v1(120.06,48.12) 120.25,47.93 120.26,47.93 120.42,47.77 CPU1.K20
+VCCST_CPU: length 193.9
  TOP w0.254: v1(159.82,103.39) 159.82,103.67 158.49,104.99 157.17,104.99 PR4621.1 PR4622.1 PR4624.1 154.23,106.26 v1(154.23,106.9) ; v1(127.71,49.45) 125.9,49.45 125.32,48.87 v2(125.32,48.1) 125.32,47.72 C716.1 123.94,46.32 124.32,45.94 125.91,45.94 v1(126.58,46.61)
  L4 w0.254: v1(123.14,26.25) 123.95,27.07 123.95,31.51 121.88,33.58 121.88,35.57 124.42,38.1 124.52,38.1 125.33,38.92 125.33,45.36 v1(126.58,46.61) ; v1(127.71,49.45) 126.65,49.45 125.82,50.27 125.82,51.54 129.4,55.13 130.5,55.13 v1(130.63,55) ; v1(166.57,75.54) 166.48,75.54 162.86,71.92 157.22,71.92 156.72,71.42 152.5,71.42 152.07,71.85 152.07,72.86 151.29,73.64 150.51,73.64 150.5,73.65 138.24,73.65 135.69,71.09 134.16,71.09 133.85,71.39 133.85,72.43 134.03,72.61 134.77,72.61 v1(134.8,72.64)
  L6 w0.254: v1(166.57,75.54) 168.88,75.54 174.31,80.97 174.75,80.97 176.93,83.15 176.93,92.92 177.01,93 177.01,93.46 176.65,93.82 172.49,93.82 171.4,94.91 171.4,97.08 170.72,97.76 168.05,97.76 165.91,99.89 165.91,102.27 165.53,102.65 165.53,103.84 162.04,107.33 161.66,107.33 161.33,107.66 159.49,107.66 158.91,107.08 154.4,107.08 v1(154.23,106.9) ; v1(130.4,62.2) 130.5,62.3 130.5,62.4 134.03,65.93 134.03,71.97 134.69,72.64 v1(134.8,72.64) ; v1(123.14,26.25) 122.91,26.03 122.91,25.72 122.78,25.59 122.78,25.26 118.78,21.26 118.78,19.36 118.48,19.07 118.21,19.07 117.98,18.84 117.98,18.08 114.2,14.29 114.2,14.06 113.62,13.48 111.76,13.48 110.89,14.35 v1(110.89,14.42)
  BOTTOM w0.152: v1(126.58,46.61) 126.51,46.68 CPU1.A18
  BOTTOM w0.254: v1(110.89,14.42) 110.89,14.57 R4036.2 ; R603.2 133.91,75.25 R419.1 R727.1 R723.1 133.91,73.47 R726.1 v1(134.8,72.64) ; v1(130.4,62.2) 130.4,61.17 130.83,60.73 130.83,59.66 129.84,58.67 129.84,55.73 130.57,55 v1(130.63,55) ; PC4610.1 159.82,102.81 v1(159.82,103.39) 158.8,103.39 PR4623.1
+VCCSTG: length 196.4
  TOP w0.254: PR4669.1 v1(153.36,106.9) ; C717.1 124,41.77 ; 124,41.77 124.2,41.57 124.97,41.57 125.83,42.43 125.83,44.8 127.05,46.02 127.05,47.33 126.12,48.27 v1(126.12,48.97) ; 124,41.77 124,41.9 124.26,42.16 124.51,42.16 125.24,42.89 125.24,43.36 124.61,43.98 R703.2
  TOP w0.508: R4042.2 100.33,91.66 C4008.1 102.55,92.35 v1(103.17,91.72)
  L4 w0.254: v1(166.57,74.9) 166.38,74.9 163.02,71.54 157.38,71.54 156.87,71.04 152.34,71.04 151.69,71.69 151.69,72.71 151.13,73.26 150.35,73.26 150.35,73.26 138.57,73.26 136.02,70.7 134,70.7 133.24,71.47 v1(132.26,71.47) ; v1(126.12,48.97) 126.12,49.49 125.47,50.13 125.47,51.74 129.24,55.51 130.53,55.51 v1(130.66,55.63)
  L4 w0.508: v1(103.17,91.72) 103.8,92.35 115.78,92.35 119.3,88.82 119.3,78.12 120.74,76.67 123.45,76.67 124.38,75.74 124.38,74.51 125.61,73.28 127.47,73.28 128.7,74.51 128.7,75.78 v1(129.84,76.93) 130.86,75.91 130.86,72.6 131.99,71.47 v1(132.26,71.47)
  L6 w0.254: v1(153.36,106.9) 153.92,107.46 158.75,107.46 159.33,108.04 161.48,108.04 161.81,107.71 162.2,107.71 165.91,104 165.91,102.81 166.29,102.43 166.29,100.05 168.2,98.14 170.88,98.14 172.57,96.45 172.57,94.94 173.28,94.23 176.78,94.23 177.39,93.62 177.39,92.57 177.34,92.52 177.34,83.02 174.86,80.53 174.42,80.53 168.79,74.9 v1(166.57,74.9)
  BOTTOM w0.254: v1(130.66,55.63) 130.23,56.07 130.23,58.47 131.21,59.46 131.21,60.89 131.01,61.1 131.01,62.55 v2(130.99,62.58) 130.99,64.3 131.9,65.21 R422.2 ; CPU1.A22 125.77,48.97 v1(126.12,48.97)
  BOTTOM w0.508: v1(132.26,71.47) 131.99,71.47 131.94,71.52 R423.2 131.57,70.76 131.62,70.7 131.62,68.77 R416.2 131.57,67.94 R417.2 R408.2 131.9,66.79 R409.2 R422.2 ; v1(129.84,76.93) 129.89,76.98 R401.1
+VDDQ_CPU_CLK: length 17.5
  TOP w0.254: v1(109.36,59.63) 110.21,59.63 C715.1 ; v1(99.97,56.15) 99.97,56.1 99.03,55.16 v2(96.16,55.16) 95.07,56.25 R705.2
  L4 w0.152: 108.96,60.04 108.94,60.06 107.29,60.06
  L4 w0.254: 106.53,59.2 106.42,59.2 104.39,57.17 100.98,57.17 100.14,56.32 100.14,56.32 v1(99.97,56.15)
  BOTTOM w0.254: v1(109.36,59.63) 109.65,59.34 CPU1.AM40
AV1_TP: length 1.3
  TOP w0.102: v1(105.66,35.73) 105.69,35.7 TP2307.1
  BOTTOM w0.102: v1(105.66,35.73) 105.77,35.84 CPU1.AV1
AV71_TP: length 3.3
  TOP w0.102: v1(104.6,77.87) 104.7,77.87 104.81,77.77 104.82,77.77 TP2304.1
  BOTTOM w0.102: CPU1.AV71 105.7,77.07 104.97,77.79 104.79,77.79 104.7,77.87 v1(104.6,77.87)
DVSS: length 3.2
  TOP w0.102: R2732.1 29.34,17.64 29,17.31 v2(28.17,17.31) HDA27.7
GND: length 1933.8
  TOP w0.127: 84.3,0.99 v1(84.3,0.88)
  TOP w0.203: KBC24.51 190.01,43.37 189.46,42.82 v1(189.46,42.47) ; v1(22.93,62.45) 23.09,62.61 U5701.35 ; v1(193.6,31.46) 193.64,31.46 195.61,29.5 KBC24.124 ; KBC24.84 182.35,35.04 v1(182.09,35.3) ; KBC24.17 199.57,36.64 199.95,36.26 ; v1(184.3,44.7) 184.3,44.42 184.53,44.19 KBC24.64 ; v1(43.18,34.28) 43.16,34.27 U3802.5 ; KBC24.100 186.01,27.88 186.01,27.76 v1(185.75,27.5) ; U5701.8 v1(26.72,66.84)
  TOP w0.254: v1(190.24,15) 190.09,14.85 U6301.3 U6301.8 ; C9113.2 34.77,30.34 v1(35.1,30.67) ; R1919.1 112.11,23.16 v1(112.09,23.18) 112.72,23.18 113.08,22.83 R1917.1 ; v2(20.88,82.39) 20.37,81.88 v1(20.37,81.75) ; v1(198.04,24.05) 197.67,24.05 ED6305.2 ; EC5504.2 59.05,89.09 v1(57.99,89.09)
  TOP w0.305: ED3803.3 15.37,95.63 v1(14.86,95.11) 14.34,94.6 ED3805.3 ; ED3603.3 ED3603.8 v1(17.83,31.08) ; v1(17.37,53.26) 17.42,53.31 ED3601.8 ED3601.3 ; U6002.5 175.78,16.36 v1(176.02,16.12) ; R3872.2 38.86,58.87 v1(39.5,58.87) ; PR4323.2 39.24,69.43 PR4325.2 ; v1(35.99,25.37) 36.11,25.48 U9104.9 ; U6302.8 U6302.3 195.77,21.8 194.13,23.44 v1(193.65,23.44) ; v1(36.96,31.56) 36.78,31.39 U9104.32 ; U6001.3 v1(175.68,13.94) ; G1801.1 74.98,15.74 EC1807.2 ; ED3806.3 v1(15.57,91.84) ; v1(17.35,94.4) 17.35,94 ED3804.3 ; DB3.4 159.94,16.85 159.62,16.54 159.62,15.3 DB3.7 158.67,14.01 158.34,13.68 158.34,13.45 v1(158.29,13.4) ; U9104.23 39.78,29.28 v1(38.53,28.03) 40.28,26.28 U9104.16
  TOP w0.356: v1(52.54,38.93) 51.66,38.93 51.1,39.49 RN1301.2 ; PQ4308.4 30.67,71.89 ; PQ4308.1 29.37,68.92 v1(29.54,68.75) ; v1(32.64,72.1) 32.38,71.85 PQ4310.4 ; R1914.1 115.16,20.72 115.42,20.97 RN1602.4 114.88,21.36 114.48,21.76 v1(114.48,22.14) 115.14,22.14 115.27,22.01 RN1602.3
  TOP w0.381: PC4531.2 97.13,100.32 PR4513.2 98.73,100.93 v1(98.98,101.18) ; C2405.2 178.33,32.4 C2406.2 ; C6305.2 v1(200.15,21.94) ; EC2701.2 30.96,15.71 v1(31.62,15.71) 31.77,15.56 C2723.1 ; R3846.2 v1(39.37,56.23) ; C2112.2 v1(91.44,36.26)
  TOP w0.406: PQ4310.1 34.76,70.16 35.34,69.57 v1(36.07,69.57) ; v1(44.58,90.26) 44.85,89.98 PQ4309.1 ; U6303.8 v1(198.68,13.5) ; ED3806.8 v1(12.83,91.79) ; v1(35.96,72.04) 35.94,72.02 PQ4307.4 ; v1(37.67,69.54) 37.82,69.69 PQ4307.1 ; DB3.8 158.67,19.44 v1(159.48,20.25) ; v1(15.8,98.31) 15.59,98.52 ED3802.3 ; v1(191.95,11.52) 192.25,11.83 U6304.8 ; v1(12.88,98.44) 12.95,98.52 ED3802.8 ; PQ4311.1 43.1,87.98 42.17,87.05 40.52,87.05 v1(40.23,87.34) ; v1(40.26,89.09) 40.65,89.49 PQ4311.4 ; PQ4313.4 43.21,73.23 42.98,72.99 ; 30.67,71.89 v1(31.27,72.48) ; v1(107.72,22.83) 107.72,22.4 108.24,21.89 R1921.1
  TOP w0.457: C4011.2 C4010.2 133.65,102.96 v1(134.29,102.96) ; v1(43.84,39.97) 43.74,40.07 43.74,40.66 EC8910.2 ; EC4309.2 162.28,25.87 v1(161.64,25.24) ; v1(60.48,70.69) 59.89,71.29 C1320.2 ; EC8911.2 44.32,46.6 v1(44.4,46.68) ; v1(52.46,64.99) 52.44,65.02 C1315.2 ; C1316.2 52.26,30.12 v1(52.36,30.22) ; PC5202.2 PC5213.2 ; v1(176.02,16.12) 176.38,15.76 C6007.2 ; C3817.2 38.86,63.21 v1(39.55,63.21) ; v1(54.52,26.46) 54.56,26.5 54.56,27.19 C1317.2 ; v1(176.81,32.91) 177.01,32.71 C2405.2 ; EC6602.2 168.25,45.71 v1(167.56,45.71) ; C2608.2 C2609.2
  TOP w0.508: v1(114.17,43.44) 113.98,43.44 113.55,43.87 C2107.2 ; C1301.2 v1(49.58,42.26) ; C1303.2 59.89,62.48 v1(60.63,63.21) ; R3831.2 18.31,94.96 v1(18.64,95.29) ; v1(35.99,25.37) 34.44,23.82 Q9104.S ; C1310.2 49.48,58.56 v1(49.45,58.59) ; C5717.1 26.13,71.29 C5701.1 ; C3818.2 34.89,53.8 v1(34.42,53.33) ; C3722.2 30.78,49.37 v1(30.91,49.24) 31.01,49.34 C3701.2 ; v1(94.26,80.41) 93.98,80.13 R602.2 ; EC6601.2 168.98,36 v1(169.71,36.72) ; PR4442.2 158.04,49.32 157.83,49.11 v1(157.83,49.04) ; EC2708.2 32.26,19.98 v1(32.23,19.96) ; PR4340.2 43.48,91.56 43.95,91.09 43.95,90.81 PC4313.1 44.04,90.8 v1(44.58,90.26) ; v1(142.01,12.31) 142.01,11.14 141.25,10.38 EC2504.2 140.77,10.41 R2509.2 138.86,10.41 PC5208.2 138.71,11.7 v1(139.39,12.39) ; 17.12,85.41 C7002.2 17.14,84.65 C7001.2 ; 6.06,99.45 USB1.21 ; USB1.21 4.72,100.28 ; USB1.21 7.39,100.28 ; USB1.21 6.06,101.12 ; v1(166.17,28.03) 165.5,27.37 EC4310.2 ; AFTP2604.1 153.47,77.31 v1(154.86,75.91) ; 3.22,65.43 HDMI1.20 ; HDMI1.20 4.6,64.44 ; HDMI1.20 5.98,65.43 ; 7.3,98.68 USB1.20 8.39,99.47 ; v1(13.49,3.5) 14.07,2.91 EC2912.2 15.19,2.91 15.54,3.27 EC2910.2 ; R1309.2 50.11,45.1 49.6,45.1 v1(49.5,45.2) 49.33,45.38 R1311.1 ; ED2903.2 17.41,22.83 17.82,23.23 ED2904.2 17.98,23.44 18.63,24.08 ED2905.2 v1(18.63,25.56) ; v1(120.11,108.45) EC8915.2 120.11,107.8 122.06,107.8 EC8927.2 ; DB1.16 159.72,7.79 159.81,7.7 169.46,7.7 v1(170.92,9.16) DB1.3 ; C1218.2 66.27,32.71 v1(66.3,32.74) ; EC8944.2 169.8,52.37 v1(169.9,52.26) ; PR4308.2 22.55,74.62 v1(22.4,74.77) 22.4,75 22.83,75.43 PC4302.2 ; v1(37.67,69.54) 37.69,69.51 PR4323.2 ; C1204.2 62.89,56.2 v1(62.63,56.46) ; v1(137.95,28.24) 137.92,28.26 PR4451.2 ; EC8906.2 175.58,59.05 175.93,58.69 v1(176.17,58.69) ; EC1005.2 v1(112.27,77.93) ; C1220.2 70.64,36.57 v1(70.58,36.62) ; v1(90.98,47.34) 90.47,46.83 EC1901.1 ; v3(152.83,72.03) 152.83,71.59 153.16,71.26 PC4709.2 ; EC6502.2 v1(122.99,5.43) ; USB3.10 14.95,39.72 ; USB3.10 14.95,37.94 ; USB3.10 16.63,38.83 ; C5705.1 C5706.1 21.49,71.7 R5710.2 21.46,71.85 v1(20.88,72.44) ; v1(57.52,80.05) 57.54,80.03 C1321.2 ; v1(158.52,43.73) 158.27,43.98 EC4425.2 ; 2.19,101.12 USB1.22 3.52,100.28 ; 6.22,97.41 USB1.B1 6.85,98.45 ; R3751.2 v1(34.59,40.73) ; R3726.1 31.44,32.66 C3717.1 v1(32.18,32.63) ; v3(112.55,54.17) 112.44,54.07 C1109.2 ; v1(38.53,33.49) 38.35,33.67 R9148.2 ; C716.2 123.7,47.24 123.29,46.83 v1(122.87,46.83) ; 7.8,44.29 6.91,45.18 USB2.13 6.5,43.68 ; v1(70.61,79.93) 70.74,79.8 C1214.2 ; PC5215.2 143.1,7.2 v1(142.59,6.7) ; v1(27.58,71.85) 26.69,71.85 C5701.1 ; PC4311.2 35.89,73.37 36.09,73.17 PR4332.2 36.09,72.17 v1(35.96,72.04) ; EC8941.2 153.08,53.56 v1(153.21,53.69) ; v1(51.61,100.52) 51.94,100.19 EC8947.2 52.83,99.79 C5515.2 53.69,99.84 EC5505.2 ; R3873.2 v1(39.5,60.44) ; 14.95,25.14 USB3.11 ; USB3.11 16.63,26.03 ; USB3.11 14.95,26.92 ; EC1806.2 C1805.2 71.94,17.49 71.44,16.99 v1(71.44,16.58) ; v1(33.3,24.86) 33.27,24.83 C9114.2 32,24.83 31.67,24.5 30.58,24.5 C2716.2 ; C1318.2 57.78,36.54 v1(57.52,36.8) ; PD4301.A v1(20.69,77.74) ; PG4601.2 152.2,99.84 v1(152.2,99.1) ; v1(45.18,75.84) 45.34,75.99 PC4315.2 ; 42.98,72.99 v1(40.82,72.99) ; v1(121.61,71.62) 121.46,71.47 R601.2 ; 8.39,88.95 USB1.15 ; USB1.15 9.48,89.73 ; USB1.15 7.3,89.73 ; v1(113.82,75.4) 113.82,75.97 EC1006.2 ; v1(70.61,61.46) 70.74,61.59 C1206.2 ; v1(58.72,91.18) 58.39,90.85 EC5503.2 ; v1(45.13,75.05) 45.67,75.05 PC4314.2 ; 12.49,70.58 HDMI1.2 11.85,70 ; v1(170.69,17.95) 171.02,18.28 C6008.2 ; USB1.14 7.39,88.13 ; USB1.14 4.72,88.13 ; USB1.14 6.06,87.3 ; USB1.14 6.06,88.97 ; v1(134.87,23.63) 134.87,23.08 EC6503.2 135.08,22.88 C2609.2 ; HDMI1.23 11.1,82.82 ; HDMI1.23 12.48,81.83 ; HDMI1.23 11.1,80.84 ; 6.85,89.97 USB1.B12 6.22,91.01 ; C3865.2 40.07,39.74 39.88,39.93 v1(39.88,40.35) ; v1(122.2,60.55) 121.74,60.09 C1127.2 ; v1(49.63,60.11) 49.36,59.85 ED1217.2 ED1302.2 ; v1(65.59,62.23) 64.9,61.54 C1203.2 ; USB2.11 14.95,47.52 ; USB2.11 14.95,45.74 ; USB2.11 16.63,46.63 ; EC1710.2 86.87,93.29 v1(86.43,93.29) 86.38,93.23 C4006.2 ; v1(87.25,100.59) 87.26,100.58 87.26,99.97 86.08,98.8 84.4,98.8 83.79,98.19 U5501.2 ; EC8930.2 v1(34.34,90.26) ; PC4428.2 141.3,38.45 v1(141.3,38.15) ; v1(149.88,23.36) 149.88,22.06 150.87,21.07 EC1712.2 ; USB2.10 14.95,60.32 ; USB2.10 16.63,59.43 ; USB2.10 14.95,58.54 ; v1(100.51,101.18) 100.51,101.77 PR4551.2 ; C717.2 123.88,40.94 123.87,40.95 123.37,40.95 123.02,40.6 123.02,40.59 v1(122.86,40.43) ; HS1.1 13.73,86.51 ; HS1.1 10.8,83.58 ; HS1.1 10.8,89.44 ; C6010.2 C6009.2 174.15,19.4 174.15,18.75 v1(174.17,18.74) ; v1(32.74,87.6) 32.38,87.6 31.98,88 PR4315.1 ; v1(78,15.94) 76.78,14.72 C1806.2 EC1807.2 ; C1215.2 61.92,73.93 v1(61.92,73.47) ; v1(31.27,72.48) 31.6,72.81 PR4328.1 ; PR4344.1 v1(46.15,70.32) ; v1(34.52,33.27) C9106.2 ; EC5501.2 v1(99.49,93.82) ; C1210.2 70.84,69.46 70.64,69.66 v1(70.61,69.66) ; v1(32.69,93.64) 32.99,93.34 C3710.2 ; v1(127.18,5.33) EC6501.2 ; v1(49.5,47.18) C1308.2 ; v1(143.66,41.57) 142.85,41.57 142.49,41.22 PC4431.2 ; C1329.2 50.29,25.47 R1216.2 49.43,26.74 v1(49.38,26.79) ; C2416.2 C2421.2 200.56,28.87 v1(200.53,28.85) ; PC4727.2 151.66,85.44 151.92,85.69 v1(152.25,85.69) ; v1(115.21,40.08) 115.41,40.08 115.71,39.78 R1901.2 115.71,38.76 R1603.2 ; v1(123.97,20.26) 124.71,21 R1912.2 ; R2034.2 104.52,21.3 v1(104.65,21.18) ; C1217.2 65.28,41.49 v1(65.81,40.96) ; EC8955.2 157.26,106.97 v1(157.26,105.84) ; v1(149.53,55.69) 149.25,55.97 PC5031.2 ; v3(161.09,80.73) 161.1,80.74 EC8946.2 ; ED501.1 87.5,17.36 v1(87.37,17.49) ; v1(28.87,52.35) 28.87,52.85 29.21,53.18 29.21,53.46 R3844.2 ; 11.1,66.34 HDMI1.21 ; HDMI1.21 12.48,67.33 ; HDMI1.21 11.1,68.32 ; R1212.1 64.79,43.96 66.1,43.96 66.47,43.59 v1(66.47,43.32) ; HDMI1.22 5.98,83.73 ; HDMI1.22 4.6,84.72 ; HDMI1.22 3.22,83.73 ; v1(34.64,42.1) 35.28,42.1 R3753.2 ; EC8943.2 159.69,71.16 v3(158.29,72.56) ; v1(122.87,43.17) 122.87,42.53 R1501.2 ; PR4324.2 48.08,87.44 47.72,87.8 v1(47.72,88.38) ; EC8928.2 140.31,106.9 v1(139.37,106.9) ; v1(94.66,9.44) 94.66,10.05 EC6530.2 ; EC6504.2 132,21.81 v1(131.78,22.03) ; R2732.2 31.19,17.14 v1(31.57,17.14) 32.28,17.14 EC2709.2 ; v1(62.59,65.83) 62.99,65.42 C1202.2 ; C3815.2 v1(27.86,56.1) ; 5.33,23.79 6.12,24.58 USB3.13 7.21,24.58 7.85,23.94 ; EC8929.2 160.93,58.64 v1(161.11,58.46) ; C5701.1 26.29,72.05 PR4329.2 ; v1(20.06,72.44) 19.71,72.08 C5702.1 ; EC4306.1 165.94,25.72 166.34,25.32 v1(166.34,25.06) ; 16.46,28.93 USB3.4 15.7,28.17 ; C1309.2 v1(49.55,54.02) ; PQ4306.S v1(32.26,76.85) ; v1(95.6,32.73) 95.4,32.53 R1825.2 ; EC1004.2 122.43,63.57 v1(122.15,63.29) 121.56,63.29 C1126.2 ; C1305.2 58.24,43.65 v1(57.3,42.71) 57.71,42.31 C1304.2 ; 3.52,88.13 USB1.13 2.19,87.3 ; PR4512.2 93.42,102.77 94.29,102.77 PC4530.2 94.29,102.14 94.18,102.03 v1(94.18,102.02) 94.79,102.02 PR4530.2 ; v1(23.32,91.51) 23.95,91.51 C3707.2 24.51,91.76 C3821.2 ; C3712.2 21.18,43.4 21.46,43.68 v1(21.8,43.68) ; 16.46,49.53 USB2.4 15.7,48.77 ; v1(101.29,93.79) 101.01,93.51 C4008.2 ; v1(115.47,89.35) 115.3,89.51 SPR1.1 ; v1(20.5,76.29) 19.53,75.33 PR4302.2 ; PR5204.2 146.02,8.46 145.82,8.26 145.82,7.99 v1(145.79,7.97) 145.82,7.94 145.82,7.38 PR5203.2 146,6.57 145.79,6.37 PC5213.2 ; R5414.1 23.01,61.13 v1(23.01,61.81) ; C3720.1 20.24,96.61 v1(19.61,95.98) ; C4032.2 v1(88.24,91.28) ; EC8916.2 v1(133.78,105.12) ; v1(27.32,24.48) 27.32,23.5 C2718.2 ; v1(109.26,35.88) 109.26,36.29 109.13,36.42 R1502.2 109.8,36.8 C2103.2 ; Q3701.S 23.81,97.13 v1(23.54,96.87) ; C5502.2 77.62,100.42 v1(78.13,100.93) ; v1(52.36,73.72) 52.22,73.58 C1319.2 ; v1(123.54,67.88) 123.9,68.24 R407.2 ; USB2.12 6.5,62.17 ; v3(26.52,88.41) 26.47,88.36 R4303.2 ; v1(35.91,64.13) 35.76,63.97 R3802.1 ; v1(46.66,11.65) 46.91,11.91 PR5404.2 ; 6.5,41.47 USB3.12 7.09,40.28 7.8,40.99 ; v1(52.54,84.69) 52.31,84.93 C1322.2 ; PQ4312.S v1(45.31,71.82) ; C1205.2 72.97,54.9 v1(73.81,55.74) 73.24,56.31 C1219.2 ; EC8914.2 35.3,13.89 v1(35.61,14.19) ; v1(25.32,75.48) 25.14,75.66 EC8913.2 ; v1(27.79,58.79) R3841.2 R3843.2 ; R3735.2 v1(34.34,38.09) ; v1(40.44,42.36) 40.82,42.36 41.3,41.88 R3858.1 ; v1(17.02,97.45) 17.83,97.45 R3830.2 ; v1(70.61,40.94) 71.8,40.94 C1209.2 ; PC1115.2 v1(49.5,48.84) ; R3857.1 35.84,39.31 v1(35.84,39.59) ; v1(26.69,55.13) 26.77,55.21 R3870.2 ; EC8942.2 v3(164.51,87.47) ; C2719.2 29.64,21.02 v1(29.64,21.53) 30.17,22.06 R9131.2 ; C1307.2 60.17,56.35 v1(60.68,55.85) 59.84,55.01 C1306.2 ; C3721.2 C3723.2 30.48,47.59 v1(30.99,47.59) 31.6,47.59 C3703.2 C3702.2 ; v1(160.92,91.32) 161.01,91.32 161.52,91.83 PR4682.2 ; v1(92.38,45.91) 92.45,45.99 EC1902.2 ; v1(122.22,49.57) 122.22,49.73 121.77,50.18 R734.2 121.33,50.18 120.7,49.55 C720.2 ; v1(45.85,97.35) 45.66,97.35 44.58,98.44 EC8945.2 44.58,100.12 45.01,100.55 PR5420.2 ; PC5111.2 41.32,11.95 v1(41.25,12.03)
  L3 w0.508: HDMI1.22 5.98,83.73 ; HDMI1.22 4.6,84.72 ; HDMI1.22 3.22,83.73 ; 15.7,28.17 USB3.4 ; USB3.4 15.7,29.69 ; USB3.4 16.46,28.93 ; 4.6,64.44 HDMI1.20 ; HDMI1.20 5.98,65.43 ; HDMI1.20 3.22,65.43 ; 8.39,99.47 USB1.20 7.3,98.68 ; USB3.11 14.95,26.92 ; USB3.11 16.63,26.03 ; USB3.11 14.95,25.14 ; 14.95,47.52 USB2.11 14.95,45.74 ; 14.95,58.54 USB2.10 14.95,60.32 ; USB3.10 16.63,38.83 ; USB3.10 14.95,37.94 ; USB3.10 14.95,39.72 ; 15.7,50.29 USB2.4 15.7,48.77 ; 4.72,88.13 USB1.14 ; USB1.14 6.06,88.97 ; USB1.14 6.06,87.3 ; USB1.14 7.39,88.13 ; 11.21,70.58 HDMI1.2 ; HDMI1.2 12.49,70.58 ; HDMI1.2 11.85,70 ; 11.21,73.58 HDMI1.8 12.49,73.58 ; USB3.7 14.2,33.19 ; USB3.7 14.2,31.67 ; USB3.7 14.96,32.43 ; 6.5,41.62 USB3.12 7.06,40.28 7.85,41.06 ; 8.39,88.95 USB1.15 ; USB1.15 9.48,89.73 ; USB1.15 7.3,89.73 ; 6.06,99.45 USB1.21 ; USB1.21 4.72,100.28 ; USB1.21 7.39,100.28 ; USB1.21 6.06,101.12 ; 6.22,97.41 USB1.B1 6.85,98.45 ; 3.52,88.13 USB1.13 2.19,87.3 ; HDMI1.5 10.99,72.08 ; 2.19,101.12 USB1.22 3.52,100.28 ; HDMI1.23 12.48,81.83 ; HDMI1.23 11.1,82.82 ; HDMI1.23 11.1,80.84 ; 6.5,62.07 USB2.12 6.91,60.88 7.69,61.66 ; 5.33,23.74 6.17,24.58 USB3.13 7.21,24.58 7.82,23.97 ; 6.22,91.01 USB1.B12 6.85,89.97 ; HS1.1 12.64,86.51 ; HS1.1 8.96,86.51 ; HS1.1 10.8,88.35 ; HS1.1 10.8,84.67 ; USB2.7 14.2,53.79 ; USB2.7 14.96,53.03 ; USB2.7 14.2,52.27 ; 6.5,43.83 USB2.13 6.96,45.18 7.72,44.42 ; HDMI1.21 12.48,67.33 ; HDMI1.21 11.1,66.34 ; HDMI1.21 11.1,68.32 ; HDMI1.11 10.96,75.08
  L4 w0.127: v1(109.26,40.42) 108.79,40.89 108.48,40.89 108.03,41.34 v1(108.01,41.34)
  L4 w0.508: USB3.7 14.96,32.43 ; USB3.7 14.2,31.67 ; USB3.7 14.2,33.19 ; 15.7,28.17 USB3.4 ; USB3.4 15.7,29.69 ; USB3.4 16.46,28.93 ; USB2.11 14.95,47.52 ; USB2.11 14.95,45.74 ; USB2.11 16.63,46.63 ; 8.39,88.95 USB1.15 7.3,89.73 ; 6.5,62.32 USB2.12 7.04,60.88 7.77,61.61 ; v1(108.03,42.26) 108.03,42.25 108.03,41.35 v1(108.01,41.34) ; 2.19,87.3 USB1.13 3.52,88.13 ; 14.95,60.32 USB2.10 14.95,58.54 ; USB2.4 15.7,50.29 ; USB2.4 16.46,49.53 ; USB2.4 15.7,48.77 ; 5.31,23.77 6.12,24.58 USB3.13 7.19,24.58 7.85,23.92 ; HDMI1.21 12.48,67.33 ; HDMI1.21 11.1,66.34 ; HDMI1.21 11.1,68.32 ; 11.21,73.58 HDMI1.8 12.49,73.58 ; USB1.14 6.06,88.97 ; USB1.14 4.72,88.13 ; USB1.14 7.39,88.13 ; USB1.14 6.06,87.3 ; USB3.10 14.95,39.72 ; USB3.10 14.95,37.94 ; USB3.10 16.63,38.83 ; 4.6,64.44 HDMI1.20 ; HDMI1.20 3.22,65.43 ; HDMI1.20 5.98,65.43 ; USB1.21 7.39,100.28 ; USB1.21 6.06,101.12 ; USB1.21 4.72,100.28 ; USB1.21 6.06,99.45 ; 11.85,70 HDMI1.2 ; HDMI1.2 11.21,70.58 ; HDMI1.2 12.49,70.58 ; USB2.7 14.2,53.79 ; USB2.7 14.2,52.27 ; USB2.7 14.96,53.03 ; 6.5,41.6 USB3.12 6.89,40.28 7.64,41.04 ; 6.85,89.97 USB1.B12 6.22,91.01 ; 11.1,80.84 HDMI1.23 ; HDMI1.23 11.1,82.82 ; HDMI1.23 12.48,81.83 ; 7.3,98.68 USB1.20 8.39,99.47 ; HDMI1.22 5.98,83.73 ; HDMI1.22 3.22,83.73 ; HDMI1.22 4.6,84.72 ; 6.22,97.41 USB1.B1 6.85,98.45 ; 2.19,101.12 USB1.22 3.52,100.28 ; 14.95,25.14 USB3.11 ; USB3.11 16.63,26.03 ; USB3.11 14.95,26.92 ; HDMI1.5 11.02,72.08 ; 7.69,44.39 6.91,45.18 USB2.13 6.5,43.93
  L6 w0.127: v1(108.01,41.34) 108.03,41.34 108.51,40.86 108.81,40.86 v1(109.26,40.42)
  L6 w0.508: USB1.14 7.39,88.13 ; USB1.14 4.72,88.13 ; USB1.14 6.06,88.97 ; USB1.14 6.06,87.3 ; 14.2,52.27 USB2.7 ; USB2.7 14.96,53.03 ; USB2.7 14.2,53.79 ; 14.2,33.19 USB3.7 14.2,31.67 ; 14.95,37.94 USB3.10 14.95,39.72 ; USB3.4 16.46,28.93 ; USB3.4 15.7,28.17 ; USB3.4 15.7,29.69 ; 3.52,88.13 USB1.13 2.19,87.3 ; 11.1,66.34 HDMI1.21 ; HDMI1.21 11.1,68.32 ; HDMI1.21 12.48,67.33 ; HDMI1.20 5.98,65.43 ; HDMI1.20 4.6,64.44 ; HDMI1.20 3.22,65.43 ; 3.52,100.28 USB1.22 2.19,101.12 ; 6.5,43.86 USB2.13 7.13,45.18 7.9,44.42 ; HDMI1.23 12.48,81.83 ; HDMI1.23 11.1,82.82 ; HDMI1.23 11.1,80.84 ; 14.95,25.14 USB3.11 ; USB3.11 14.95,26.92 ; USB3.11 16.63,26.03 ; 14.95,58.54 USB2.10 ; USB2.10 16.63,59.43 ; USB2.10 14.95,60.32 ; 6.85,98.45 USB1.B1 6.22,97.41 ; 6.85,89.97 USB1.B12 6.22,91.01 ; 14.95,45.74 USB2.11 14.95,47.52 ; HDMI1.22 5.98,83.73 ; HDMI1.22 3.22,83.73 ; HDMI1.22 4.6,84.72 ; USB1.21 7.39,100.28 ; USB1.21 6.06,101.12 ; USB1.21 6.06,99.45 ; USB1.21 4.72,100.28 ; 8.39,88.95 USB1.15 ; USB1.15 7.3,89.73 ; USB1.15 9.48,89.73 ; 5.31,23.74 6.15,24.58 USB3.13 7.29,24.58 7.97,23.89 ; HS1.1 10.8,88.35 ; HS1.1 8.96,86.51 ; HS1.1 12.64,86.51 ; HS1.1 10.8,84.67 ; 15.7,48.77 USB2.4 15.7,50.29 ; 7.3,98.68 USB1.20 8.39,99.47 ; USB2.12 6.5,62.17 ; 6.5,41.65 USB3.12 7.19,40.28 7.9,40.99
  BOTTOM w0.089: GPU1.E1 171.85,86.71 171.74,86.59 v1(171.73,86.59) ; 99.13,55.54 101.65,55.54 101.78,55.41 102.76,55.41 102.87,55.53 CPU1.BB34
  BOTTOM w0.102: v1(125.55,55.34) 125.6,55.29 125.6,54.63 125.09,54.11 CPU1.B30 ; v1(126.9,36.36) 126.39,35.86 125.04,35.86 124.61,36.28 124.61,36.77 124.49,36.89 124.49,37.16 124.61,37.28 CPU1.C5 ; 126.62,56.05 126.21,56.05 126.06,56.2 125.33,56.2 CPU1.B34 ; 123.98,58 124.1,58.13 124.41,58.13 124.44,58.1 124.76,58.1 124.78,58.12 126.25,58.12 v1(127.25,57.12) ; CPU1.P20 CPU1.P21
  BOTTOM w0.114: 124.94,54.5 124.94,54.93 125.35,55.34 v1(125.55,55.34)
  BOTTOM w0.127: CPU1.BB38 102.99,57.88 102.86,57.75 100.58,57.75 v1(99.97,58.36) ; 184,6.49 184.01,6.51 ; CPU1.BA28 104.1,51.72 103.95,51.57 103.18,51.57 102.98,51.36 102.35,51.36 v1(102.2,51.21) ; v1(102.64,72.57) 102.67,72.6 CPU1.BB64 ; v1(106.79,77.93) 106.85,77.87 106.85,77.74 107.09,77.5 CPU1.AT71 ; v1(112.27,77.93) 112.21,77.88 112.21,77.67 112.1,77.46 CPU1.AG71 ; CPU1.AM71 109.45,77.49 109.38,77.55 109.38,77.58 109.35,77.62 109.35,78.59 109.77,79.02 v1(109.77,79.02) ; v1(102.53,60.61) 102.56,60.61 102.68,60.48 CPU1.BB43 ; v1(99.64,72.74) 99.82,72.74 101.9,70.65 102.72,70.65 103.07,70.3 103.56,70.3 CPU1.BB60 ; CPU1.W13 115.8,44.69 CPU1.V16 ; CPU1.BB26 102.93,50.54 102.45,50.06 v1(101.87,50.06) ; CPU1.BB55 103.59,67.63 102.74,67.63 102.67,67.56 101.56,67.56 99.85,69.27 v1(99.7,69.27) ; CPU1.AW30 CPU1.AW32 ; v1(107.95,78.08) 108.08,77.96 108.08,76.16 CPU1.AP70 ; CPU1.BB30 102.56,52.9 102.41,52.75 v1(102.33,52.75) ; CPU1.AW53 CPU1.AW51 ; CPU1.AW60 CPU1.AW62
  BOTTOM w0.152: 110.59,67.86 110.13,68.32 CPU1.AL58 111.02,68.77 v3(111.17,68.93) ; 110.59,67.86 111,67.86 v3(111.17,68.04) ; 110.59,67.86 110.13,67.4 CPU1.AL55 110.97,66.95 v3(111.17,67.15) ; CPU1.AW18 CPU1.AW16 ; CPU1.AN42 108.85,60.09 108.85,60.08 108.5,60.08 108.49,60.09 CPU1.AP42 ; CPU1.AM60 109.65,70.34 109.75,70.43 109.75,70.78 109.65,70.87 CPU1.AM61 ; CPU1.AK16 110.1,45.49 110.1,46.16 CPU1.AK18 ; CPU1.AT42 107.21,60.09 107.22,60.08 107.57,60.08 107.58,60.09 CPU1.AR42 ; CPU1.AR20 CPU1.AT20 ; 109.8,71.06 110.12,71.06 110.32,70.85 111.05,70.85 v3(111.17,70.73)
  BOTTOM w0.178: CPU1.T15 117.39,44.52 117.85,44.06 118.39,44.06 ; v1(121.69,78.02) 121.7,78.01 CPU1.H71 ; 105.65,73.75 105.62,73.72 105.62,72.76 CPU1.AW64 ; CPU1.AM61 109.8,71.06 ; CPU1.AP20 CPU1.AN20
  BOTTOM w0.203: v1(193.65,23.44) SSD1.33 ; CPU1.J8 120.4,40.88 CPU1.L8 ; C2201.1 131.93,38.75 131.8,38.75 130.39,37.34 129.79,37.34 129.27,37.13 128.76,36.83 128.27,36.62 128.07,36.54 127.07,36.54 v1(126.9,36.36) ; CPU1.AF4 112.71,38.09 112.71,37.62 CPU1.AF2 ; PU4701.5 152.48,66.04 ; v1(155.78,67.15) 155.7,67.08 PU4701.31 ; CPU1.AH13 111.53,43.68 111.53,44.25 CPU1.AJ15 ; CPU1.AN63 CPU1.AP63 ; CPU1.AN63 109.5,72.47 CPU1.AL64 ; CPU1.AN63 109.65,71.32 CPU1.AM61 ; v1(156.01,83.15) 155.97,83.12 PU4702.31 ; CPU1.G5 122.26,38.69 122.72,38.69 CPU1.F4 ; v1(104.84,59.3) 104.97,59.18 CPU1.AW41 105.58,59.16 105.58,58 ; U4001.11 v1(134.29,102.07) ; IOBD1.15 169.3,51.71 169.85,52.26 v1(169.9,52.26) ; CPU1.AR50 108.07,64.3 v1(108.07,64.19) 108.07,64.11 CPU1.AR48 CPU1.AR46 ; CPU1.AW18 105.34,46.8 105.13,47.01 105.08,47.01 105.04,47.04 104.58,47.04 104.34,46.8 CPU1.BA18 CPU1.BB18 ; PU4801.5 141.38,91.26 141.27,91.15 141.27,90.51 v1(141.52,90.26) ; CPU1.G45 121.89,61.76 121.78,61.65 121.78,61.11 CPU1.G43 ; 153.28,65.29 v1(153.39,65.4) ; CPU1.AR52 108.08,65.95 v1(108.08,66.02) ; CPU1.AT20 CPU1.AU20 ; CPU1.AR43 107.44,61.26 107.44,61.43 v1(107.36,61.51) 107.7,61.85 CPU1.AR45 ; CPU1.AW62 v1(104.96,71.43) ; CPU1.K70 CPU1.K71 120.29,76.75 120.29,77.97 v1(120.11,78.15) ; CPU1.AR11 107.7,42.58 v1(108.03,42.26) 108.35,41.93 CPU1.AP10 ; CPU1.AW47 105.58,62.89 105.58,64.05 CPU1.AW49 105.09,64.07 v1(104.94,64.22) ; 142.42,90.64 142.42,91 142.18,91.23 PU4801.3 ; SSD1.39 193.72,21.94 v1(193.65,22.01) ; CPU1.D45 123.68,62.22 123.29,62.61 123.29,62.73 CPU1.E46 ; CPU1.AM46 109.72,62.76 109.72,61.98 CPU1.AM45 ; PU4702.5 152.74,80.08 v1(152.3,79.65) ; CPU1.T17 117.52,45.43 117.52,45.01 117.12,44.62 CPU1.T15 ; CPU1.AW36 104.98,56.7 v1(104.86,56.58) ; CPU1.AW43 105.55,60.4 105.55,60.86 105.58,60.89 105.58,61.21 105.56,61.23 CPU1.AW45 104.97,61.66 v1(104.96,61.66) ; USB1.A12 8.4,96.96 ; CPU1.AW53 105.03,66.47 v1(104.87,66.31)
  BOTTOM w0.229: CPU1.AL2 109.81,37.29 109.47,36.95 109.47,36.09 v1(109.26,35.88) ; CPU1.AJ20 110.84,47.36 110.84,46.88 111.05,46.68 ; CPU1.AB18 114.17,46.03 114.17,45.17 ; 8.69,91.28 8.5,91.46 USB1.A1
  BOTTOM w0.254: CPU1.AL35 109.46,55.97 CPU1.AN33 108.74,55.25 v1(108.74,55.06) ; CPU1.F4 CPU1.F2 CPU1.F1 123.07,35.89 v1(123.32,35.64) ; 108.68,56.75 CPU1.AP35 ; 108.68,56.75 v1(108.68,56.89) ; 108.68,56.75 CPU1.AN35 ; CPU1.AG17 CPU1.AF17 ; CPU1.AG17 CPU1.AG18 CPU1.AG19 CPU1.AG20 112.05,47.82 112.05,48.38 CPU1.AG21 112.09,48.44 v1(112.65,48.99) ; CPU1.AG17 CPU1.AG16 ; v1(108.68,53.23) 108.35,52.9 CPU1.AP28 108.29,52.83 107.76,52.83 CPU1.AR28 CPU1.AT28 ; v1(108.68,53.23) 109,53.55 CPU1.AN30 ; v1(108.68,53.23) 109,52.9 CPU1.AN28 ; CPU1.J25 122.08,51.4 CPU1.F27 122.16,52.24 v1(122.16,52.32) 122.16,52.39 CPU1.F28 122.08,53.23 CPU1.J28 ; CPU1.U66 116.7,74.1 v1(116.57,74.1) 116.89,74.42 CPU1.U67 ; v1(105.79,47.31) 105.56,47.08 CPU1.AW18 ; v1(105.79,47.31) 105.82,47.29 CPU1.AU20 ; v1(105.79,47.31) 105.66,47.44 105.66,47.59 105.56,47.69 CPU1.AW21 ; v1(132.26,72.1) 132.03,72.33 R406.2 ; v1(118.41,44.06) 118.03,43.68 CPU1.R13 ; v1(118.41,44.06) 118.62,44.06 CPU1.N13 ; v1(118.41,44.06) 118.39,44.06 ; v1(105.87,41.24) 105.87,41.03 CPU1.AW8 ; CPU1.K65 CPU1.K66 CPU1.K67 120.45,74.65 CPU1.K68 120.34,75.16 CPU1.K70 ; CPU1.AR15 107.38,44.87 v1(107.38,45) ; CPU1.AF63 112.31,71.82 v1(112,72.13) ; CPU1.AR35 107.7,56.56 108.02,56.88 ; CPU1.AW32 106.03,54.23 CPU1.AU32 ; CPU1.AP38 108.35,58.39 v1(108.68,58.72) ; CPU1.BA57 104.47,69.08 104.89,69.08 v1(104.92,69.1) 105.41,69.1 CPU1.AW57 ; v1(107.39,68.72) 107.52,68.85 107.52,69.04 CPU1.AR58 CPU1.AP58 108.37,69.22 108.99,69.22 CPU1.AN58 109.33,69.56 v1(109.33,69.69) 109.65,70.01 CPU1.AM60 ; v1(107.39,68.72) 107.05,69.06 CPU1.AT58 ; v1(107.39,68.72) 107.05,68.39 CPU1.AT56 106.6,67.86 105.68,67.86 CPU1.AW55 105.56,67.6 v1(105.91,67.25) ; CPU1.G58 121.89,69.36 v1(122.22,69.69) 122.22,69.82 CPU1.G60 ; v1(118.4,74.75) 118.72,75.07 CPU1.N68 ; CPU1.BA53 104.71,66.47 v1(104.87,66.31) ; CPU1.AP63 108.34,71.96 107.72,71.96 CPU1.AR63 107.69,71.96 107.07,71.96 CPU1.AT63 ; CPU1.T4 117.93,38.52 CPU1.R6 CPU1.N6 119.41,38.71 119.9,38.71 120.27,38.35 CPU1.L4 CPU1.L2 ; CPU1.T4 117.76,38.44 v1(117.45,38.75) ; CPU1.T4 CPU1.T2 ; v1(123.95,17.39) 123.95,18.1 123.59,18.46 EC2501.2 ; CPU1.BA41 104.72,59.18 v1(104.84,59.3) ; CPU1.AP32 108.35,54.68 v1(108.74,55.06) ; CPU1.AK11 110.08,42.89 v1(110.08,43.2) 110.08,43.2 CPU1.AM13 ; R2009.2 113.79,32.58 v1(114.15,32.94) ; CPU1.B14 CPU1.D14 ; CPU1.G10 121.58,41.49 121.58,41.34 v1(121.58,41.34) ; CPU1.D45 123.92,62.18 CPU1.D44 124.21,61.26 124.65,61.26 124.94,61.55 CPU1.B44 ; LCD1.11 83.95,94.41 83.74,94.2 83.74,94 v1(83.67,93.92) ; v1(104.87,39.73) 104.54,39.73 CPU1.BA6 104.24,39.54 104.23,39.55 103.72,39.55 103.7,39.54 CPU1.BB6 ; v1(119.46,40.74) 119.56,40.74 119.88,40.43 CPU1.L8 ; v1(108.74,55.06) 108.74,54.87 CPU1.AN32 109,54.52 v1(109.33,54.19) 109.38,54.14 CPU1.AL32 ; 108.02,56.88 107.5,56.88 CPU1.AT35 107,56.43 106.46,55.88 106.25,55.88 106.12,55.76 105.89,55.76 CPU1.AW34 ; 108.02,56.88 v1(108.03,56.89) ; CPU1.AM43 109.67,61 CPU1.AL45 110.11,61.46 CPU1.AM45 ; CPU1.BA66 CPU1.AY66 105.09,73.75 105.65,73.75 CPU1.AW66 ; v1(122.15,63.29) 122.18,63.31 123.46,63.31 123.5,63.35 CPU1.D47 ; CPU1.AR5 107.7,38.96 107.16,38.42 CPU1.AT4 CPU1.AT2 ; v1(112,72.13) 111.83,72.31 111.7,72.31 CPU1.AH64 ; v1(112,72.13) 111.69,71.82 CPU1.AH63 ; v1(104.86,56.58) 104.72,56.58 104.6,56.7 CPU1.BA36 ; v1(118.49,41.39) 118.67,41.39 CPU1.N10 ; CPU1.BA49 104.78,64.07 v1(104.94,64.22) ; v1(108.03,60.52) 108.03,60.45 ; 108.03,60.45 108.35,60.13 CPU1.AP42 ; 108.03,60.45 107.7,60.12 CPU1.AR42 ; CPU1.U63 116.89,71.82 v1(116.57,72.15) 116.89,72.47 CPU1.U64 ; GPU1.E7 175.45,86.97 175.59,86.83 v1(175.59,86.5) ; v1(122.2,60.55) 122.2,60.7 CPU1.G43 121.88,61 CPU1.J42 ; v1(112.09,41.42) 112.4,41.73 CPU1.AF10 ; CPU1.AV70 CPU1.AV69 105.7,75.55 v1(105.97,75.28) 105.89,75.2 CPU1.AV68 ; CPU1.AP68 107.96,74.44 v1(107.8,74.44) ; v1(111.02,64.99) 110.9,65.12 CPU1.AL52 ; CPU1.BA45 104.96,61.66 v1(104.96,61.66) ; CPU1.H15 121.11,44.54 CPU1.K16 120.48,45.26 121.06,45.84 121.46,45.84 121.49,45.86 v1(121.56,45.86) 121.56,46.05 CPU1.H18 ; CPU1.T17 CPU1.T18 ; v1(174.8,94.83) 174.8,94.84 175.3,95.34 176.43,95.34 176.73,95.05 176.73,94.43 176.65,94.35 GPU1.A9 ; CPU1.N65 118.72,73.12 v1(118.4,72.8) ; CPU1.AK27 110.13,52.31 CPU1.AL28 109.67,51.86 CPU1.AM27 ; v1(107.98,66.94) 107.98,67.13 CPU1.AR55 ; CPU1.U10 116.79,41.73 v1(116.4,42.12) ; CPU1.AL4 CPU1.AJ4 ; CPU1.Y21 115.45,48.32 115.47,48.3 115.47,47.91 115.45,47.88 CPU1.Y20 CPU1.Y19 ; v1(110.95,24.65) 111.43,25.14 R1823.2 ; CPU1.AL38 v1(109.33,57.8) 109.33,57.67 CPU1.AN37 ; v1(9.07,95.77) 8.68,95.39 USB1.18 ; CPU1.B53 124.72,66.72 v1(124.4,66.72) 124.14,66.72 CPU1.D53 123.56,66.14 v1(123.56,65.12) 123.56,65.04 123.19,64.67 CPU1.E50 ; CPU1.D47 124.06,63.35 124.46,63.74 124.61,63.74 124.9,64.02 CPU1.B48 ; CPU1.D47 123.92,63.39 CPU1.D48 ; CPU1.AK18 110.62,46.68 111.05,46.68 CPU1.AJ18 ; CPU1.AB21 114.65,48.42 115.21,48.99 v1(115.26,48.99) ; GPU1.B4 173.66,92.31 173.66,92.65 v1(173.12,93.18) ; CPU1.B66 CPU1.D66 123.92,73.83 123.54,73.45 123.54,73.33 CPU1.E65 ; v1(111.95,74.82) 111.55,74.42 CPU1.AH67 110.89,75.07 CPU1.AK68 CPU1.AK69 ; CPU1.BA14 v1(104.93,44.38) CPU1.AW14 ; CPU1.AU38 105.84,58.26 CPU1.AW38 ; CPU1.AR53 108.08,66.12 v1(108.08,66.02) ; v1(123.54,67.88) 123.19,68.24 CPU1.E56 123.85,68.98 CPU1.D58 ; v1(124.44,39.17) 124.34,39.27 CPU1.D6 ; CPU1.E18 123.62,46.37 CPU1.D18 CPU1.B18 ; v1(113.14,40.64) 113.35,40.43 CPU1.AD8 ; R2008.2 109.08,29.02 108.35,29.76 v1(108.24,29.76) 108.63,30.15 R2030.2 ; CPU1.BA62 v1(104.96,71.43) ; CPU1.L20 118.99,48.42 CPU1.N21 ; CPU1.AW62 105.6,71.47 105.6,72.27 105.56,72.31 CPU1.AW64 ; v1(112.62,35.32) 112.68,35.37 112.68,36 112.46,36.21 CPU1.AF1 CPU1.AF2 ; CPU1.AL64 109.74,72.49 109.74,72.49 109.68,72.55 109.68,72.94 109.74,73 109.74,73.11 CPU1.AL65 CPU1.AL66 109.54,73.98 CPU1.AM68 ; v1(197.36,42.41) 197.94,42.41 198.22,42.13 R2431.1 ; Q2001.1 151.14,26.73 150.62,27.25 150.36,27.25 149.86,27.75 149.86,28.17 Q2001.4 ; CPU1.AA68 114.74,74.62 v1(114.74,74.1) 114.74,73.57 CPU1.AA65 ; CPU1.BA10 v1(104.93,41.96) CPU1.AW10 105.72,41.8 CPU1.AU10 ; CPU1.U70 116.89,76.37 v1(116.57,76.05) 116.89,75.72 CPU1.U69 ; CPU1.B62 124.58,71.46 v1(124.41,71.29) 124.24,71.46 CPU1.D62 ; CPU1.B34 124.5,56.59 v1(124.43,56.52) 124.36,56.59 CPU1.D34 ; CPU1.AK8 110.59,40.46 110.17,40.88 CPU1.AM8 ; C2601.2 141.76,27.68 PC4430.2 141.43,28.69 PR4401.2 ; v1(106.73,45) 106.72,45 106.72,44.86 CPU1.AU15 106.25,44.39 106.25,44.09 105.56,43.4 CPU1.AW12 ; v1(123.44,75.84) 123.57,75.71 CPU1.D69 CPU1.F68 ; ED401.2 v1(132.26,75.15) ; GPU1.B7 175.45,92.66 175.21,92.9 v1(175.21,93.21)
  BOTTOM w0.279: v1(65.78,84.65) 65.37,84.23 DM1.14 ; v1(56,69.83) 56.17,69.66 56.17,69.63 57.12,68.69 59.1,68.69 DM2.77 ; DM1.39 70.92,77.98 v1(70.61,78.3) ; v1(65.61,73.52) 65.4,73.73 DM1.56 ; DM2.69 60.48,70.69 v1(60.48,70.69) ; DM2.65 57.9,71.69 57.58,71.37 57.13,71.37 56.81,71.69 56.81,71.71 v1(56.63,71.89) ; v1(57.42,69.83) 57.57,69.69 59.1,69.69 DM2.73 ; v1(56.81,82.59) 57.27,82.13 58.02,82.13 58.08,82.19 DM2.23 ; DM2.213 56.86,32.69 v1(56.81,32.74) ; DM1.235 71.06,26.98 71.04,27.01 69.92,27.01 69.37,26.46 69.37,26.44 v1(69.19,26.26) 69.37,26.08 69.37,26.03 70.42,24.98 DM1.243 ; DM1.227 70.14,28.98 69.31,28.16 v1(69.31,27.91) ; DM2.10 50.9,85.44 53.22,85.44 v1(53.96,84.69) ; v1(57.61,23.23) 57.65,23.19 DM2.251 ; DM2.172 50.9,42.93 52.73,42.93 53.25,43.45 v1(53.25,43.48) ; v1(65.81,40.96) 65.76,40.96 65.53,40.73 DM1.180 ; DM2.205 59.05,34.64 57.38,34.64 57.35,34.61 v1(57.33,34.61) ; v1(69.29,43.32) 69.37,43.4 69.37,43.5 70.09,44.23 70.98,44.23 71.22,43.98 DM1.167 ; DM2.234 52.82,27.44 53.64,28.26 v1(53.64,28.36) ; DM2.197 57.63,36.69 v1(57.52,36.8) ; DM1.248 65.8,23.73 66.3,23.24 v1(66.3,23.22) ; v1(65.71,34.24) 65.71,34.23 DM1.206 ; v1(53.1,66.84) 53.1,67.06 52.72,67.44 DM2.82 ; DM1.69 72.86,70.48 73.19,70.82 73.19,74.74 72.95,74.98 DM1.51 71.21,74.98 70.99,74.76 69.68,74.76 68.48,73.57 68.48,73.55 v1(68.46,73.52) ; DM2.72 50.9,69.94 53.73,69.94 54.79,68.88 v1(54.79,68.85) ; v1(70.61,26.25) 70.62,26.25 70.89,25.98 DM1.239 ; DM1.231 v1(70.61,27.98) ; v1(67.51,80) 67.51,79.79 66.68,78.96 65.59,78.96 65.37,78.73 DM1.36 ; v1(53.72,37.28) 53.06,37.94 50.9,37.94 DM2.192 ; v1(57.45,26.43) 57.7,26.19 DM2.239 ; v1(69.34,79.95) 70.37,80.98 DM1.27 ; DM1.192 66.13,37.73 67.04,36.83 67.04,36.78 v1(67.21,36.6) ; v1(69.19,23.14) 69.37,23.31 69.37,23.34 70.02,23.98 DM1.247 ; v1(52.36,28.39) 52.32,28.44 DM2.230 ; DM1.77 70.34,68.48 69.42,69.41 69.42,69.46 v1(69.24,69.63) ; DM2.102 v1(52.34,62.44) ; DM1.57 70.63,73.48 v1(70.59,73.52) ; v1(70.56,30.53) 71.11,29.98 DM1.223 ; DM1.78 66.59,68.23 67.82,69.46 v1(67.82,69.63) ; DM2.44 50.92,76.96 53.98,76.96 54.29,76.64 54.29,76.62 v1(54.47,76.44) ; DM1.23 71.12,81.98 71.03,81.89 70.34,81.89 69.9,82.34 v1(69.9,82.41) 69.9,82.49 70.39,82.98 DM1.19 ; v1(61.71,65.2) 62.67,64.23 DM1.94 ; DM1.6 65.93,86.23 66.53,86.83 v1(66.53,86.86) ; v1(54.33,79.65) 53.77,79.09 52.27,79.09 52.12,78.94 50.9,78.94 DM2.36 ; DM1.9 70.82,85.48 70.68,85.62 68.79,85.62 67.92,84.75 v1(67.92,84.62) ; v1(55.95,42.71) 56.03,42.79 56.03,42.87 57.35,44.19 59.1,44.19 DM2.167 ; v1(52.36,30.22) 52.15,30.44 DM2.222 ; v1(57.52,80.05) 57.54,80.05 57.68,80.19 DM2.31 ; DM1.22 65.79,82.23 v1(65.79,82.23) ; v1(54.52,23.34) 54.05,22.86 50.97,22.86 50.9,22.94 DM2.252 ; v1(53.28,87.06) 53.28,87.03 52.68,86.44 50.9,86.44 DM2.6 ; v1(65.61,28.19) 65.57,28.23 DM1.230 ; v1(54.52,66.84) 54.34,66.66 54.34,66.63 54.03,66.32 52.15,66.32 52.03,66.44 DM2.86 ; DM2.196 50.9,36.94 52.4,36.94 v1(52.54,36.8) ; DM2.26 50.9,81.44 54.41,81.44 55.39,82.41 v1(55.39,82.59) 55.39,82.61 55.96,83.19 DM2.19 ; DM1.2 65.22,87.23 65.36,87.38 67.43,87.38 67.47,87.36 67.95,86.88 v1(67.95,86.86) ; DM1.40 65.89,77.73 66.22,78.07 66.22,78.12 v1(66.4,78.3) ; v1(61.92,73.47) 62.61,72.79 62.61,72.73 DM1.60 ; v1(55.12,34.71) 56.09,35.69 DM2.201 ; v1(56.28,39.72) 57.32,38.69 DM2.189 ; DM1.218 65.87,31.23 66.86,30.25 66.86,30.2 v1(67.04,30.02) 66.86,29.84 66.86,29.82 66.28,29.23 DM1.226 ; v1(69.8,35) 69.8,34.94 70.25,34.48 DM1.205 ; v1(65.61,71.69) 65.57,71.73 DM1.64 ; DM1.175 69.53,41.98 68.55,41.01 v1(68.55,40.96) ; v1(62.33,80.92) 62.64,81.23 DM1.26 ; v1(66.47,43.32) 66.47,43.2 66.01,42.73 DM1.172 ; v1(54.63,43.02) 54.63,43.07 53.7,44 50.97,44 50.9,43.93 DM2.168 ; v1(67.74,43.32) 67.74,43.43 67.32,43.84 65.49,43.84 65.38,43.73 DM1.168 ; DM1.15 70.34,83.98 69.95,84.38 v1(69.95,84.65) ; DM2.48 50.9,75.94 50.92,75.92 52.55,75.92 52.88,76.25 52.88,76.27 v1(53.05,76.44) ; DM1.103 70.64,61.98 69.72,62.91 v1(69.04,62.91) ; DM2.22 50.9,82.44 52.54,82.44 v1(52.54,82.43) ; v1(65.61,30.02) 65.4,30.23 DM1.222 ; DM2.35 58.1,79.19 58,79.29 56.76,79.29 56.17,78.7 56.17,78.67 v1(56,78.5) ; v1(55.62,37.48) 56.09,37.95 56.67,37.95 56.94,37.68 DM2.193 ; v1(67.04,71.69) 66.86,71.51 66.86,71.49 66.1,70.73 DM1.68 ; DM1.89 70.3,65.48 69.37,66.42 69.37,66.46 v1(69.19,66.64) 69.37,66.81 69.37,66.84 70.02,67.48 DM1.81 ; v1(69.85,76.24) 70.03,76.06 70.03,76.03 70.35,75.72 70.8,75.72 71.07,75.98 DM1.47 ; v1(54.52,26.46) 54.37,26.31 54.37,26.28 53.02,24.94 50.9,24.94 DM2.244 ; v1(52.54,80.2) 52.3,80.44 50.9,80.44 DM2.30 ; DM1.93 71.09,64.48 70.61,64.01 70.61,63.01 v1(70.53,62.93) 70.61,62.93 70.66,62.98 71.98,62.98 DM1.99 ; DM2.89 59.1,65.69 57.16,65.69 v1(57.1,65.62) ; DM2.206 50.9,34.44 v1(52.46,34.44) ; DM2.243 57.33,25.19 56.18,26.33 v1(56.18,26.43) 56.18,26.53 56.83,27.19 DM2.235 ; DM2.43 56.59,77.19 55.89,76.49 v1(55.89,76.44) ; v1(66.93,38.73) 66.93,39.25 66.44,39.73 DM1.184 ; CPU1.AA4 115.09,38.35 114.81,38.06 114.81,37.66 115.09,37.38 115.1,37.38 CPU1.AA2 ; DM1.193 70.35,37.48 70,37.14 69.71,37.14 69.29,36.72 v1(69.29,36.62) ; DM2.210 50.92,33.46 52.55,33.46 53.05,32.96 v1(53.05,32.94) ; DM2.227 56.88,29.19 v1(55.93,28.24) ; v1(53.05,23.42) 53.05,23.44 52.55,23.94 50.9,23.94 DM2.248 ; DM2.238 52.36,26.44 v1(52.39,26.46) ; v1(67.64,31.6) 67.47,31.77 67.47,31.8 67.12,32.15 64.24,32.15 64.15,32.23 DM1.214 ; v1(55.6,74.34) 56.21,74.95 57.89,74.95 58.13,75.19 DM2.51 ; DM1.43 69.79,76.98 69.14,76.34 v1(69.14,76.24) ; DM1.98 66.09,63.23 v1(67.08,62.25) ; v1(67.04,28.19) 66.86,28.01 66.86,27.97 66.12,27.23 DM1.234 ; v1(55.94,66.84) 56.12,67.02 56.12,67.04 56.8,67.71 59.07,67.71 DM2.81 ; v1(52.54,84.69) 52.28,84.44 50.9,84.44 DM2.14 ; v1(52.36,73.72) 52.15,73.94 50.9,73.94 DM2.56 ; DM2.107 59.91,61.19 60.59,61.87 60.59,63.18 59.11,63.18 DM2.99 ; v1(70.61,43.32) 70.95,42.98 DM1.171 ; v1(57.37,66.84) 57.52,66.69 59.1,66.69 DM2.85 ; v1(57.3,73.83) 57.38,73.83 57.52,73.69 DM2.57 ; DM2.2 50.9,87.44 51.65,87.44 51.79,87.58 54.2,87.58 54.52,87.26 54.52,87.23 v1(54.7,87.06) ; DM2.90 52.02,65.44 v1(52.46,64.99) 51.91,64.43 50.9,64.43 DM2.94 ; v1(57.37,30.73) 57.91,30.19 DM2.223 ; DM1.35 71.12,78.98 71.06,79.04 69.97,79.04 69.42,78.5 69.42,78.47 v1(69.24,78.3) ; v1(65.79,36.6) 65.65,36.73 DM1.196 ; DM2.247 56.73,24.19 v1(55.88,23.33) ; v1(56.6,76.44) 56.78,76.26 56.78,76.24 57.1,75.92 57.55,75.92 57.82,76.19 DM2.47 ; DM1.85 70.77,66.48 70.61,66.64 v1(70.58,66.64) ; DM1.107 71.14,60.98 70.67,61.46 v1(70.61,61.46) ; v1(57.54,87.06) 57.92,86.69 DM2.5 ; v1(56.16,80.1) 56.26,80.2 56.26,80.25 57.19,81.19 DM2.27 ; v1(55.21,71.89) 55.39,72.07 55.39,72.1 55.98,72.69 DM2.61 ; DM2.175 59.1,42.19 58.03,42.19 57.67,41.83 56.45,41.83 55.47,40.85 55.47,40.83 v1(55.45,40.81) ; v1(68.2,38.65) 68.2,38.75 69,39.55 71.07,39.55 71.13,39.48 DM1.185 72.05,39.49 72.86,39.49 73.19,39.15 73.19,38.6 73.07,38.48 DM1.189 ; DM1.210 64.15,33.23 64.17,33.26 65.8,33.26 66.3,32.76 v1(66.3,32.74) ; DM2.176 50.9,41.93 53.24,41.93 53.79,41.39 53.79,41.37 v1(53.96,41.19) ; DM1.102 v1(65.59,62.23) ; DM2.18 50.9,83.44 52.99,83.44 53.79,82.64 53.79,82.61 v1(53.96,82.43) ; v1(68.46,71.69) 68.64,71.87 68.64,71.92 69.2,72.48 DM1.61 ; v1(57.42,78.5) 57.73,78.19 DM2.39 ; DM1.202 65.8,35.23 66.26,34.77 66.63,34.77 66.96,34.44 66.96,34.41 v1(67.14,34.24) ; v1(70.61,69.66) 70.64,69.66 70.82,69.48 DM1.73 ; v1(67.21,84.62) 67.21,84.67 66.65,85.23 DM1.10 ; DM2.218 52.72,31.44 53.61,30.54 53.61,30.4 v1(53.79,30.22) ; DM1.86 65.21,66.23 65.33,66.12 67.28,66.12 67.77,66.61 v1(67.77,66.64) ; v1(71.07,88.82) 72.05,87.84 DM1.1 ; DM2.40 50.9,77.94 52.61,77.94 52.97,78.29 52.97,78.32 v1(53.15,78.5) ; v1(54.19,33.01) 54.19,33.04 54.84,33.69 DM2.209 ; v1(52.73,68.75) 52.41,68.44 DM2.78 ; v1(66.35,62.15) 65.43,61.23 DM1.106 ; DM2.180 50.9,40.93 52.48,40.93 v1(52.5,40.92) ; v1(57.52,84.69) 58.03,84.18 DM2.15 ; v1(53.1,62.35) 52.18,61.43 DM2.106 ; v1(68.46,30.56) 68.47,30.56 69.4,31.48 DM1.217 ; DM2.1 58.25,87.69 58.13,87.81 56.85,87.81 56.3,87.26 56.3,87.23 v1(56.12,87.06) ; DM2.202 53.13,35.44 53.85,34.72 v1(53.85,34.71) ; DM1.52 65.87,74.73 66.86,73.75 66.86,73.7 v1(67.04,73.52) ; v1(67.18,40.96) 67.18,41.08 66.52,41.73 DM1.176 ; v1(57.43,64.66) 57.43,63.05 58.29,62.19 DM2.103 ; DM1.244 66.49,24.73 67.62,25.87 67.62,26.11 v1(67.77,26.26) ; DM1.30 65.22,80.23 65.43,80.03 v1(65.48,80.03) ; DM2.185 60.09,39.69 60.24,39.84 60.24,40.35 59.91,40.68 59.1,40.68 DM2.181 58.18,40.69 58.16,40.71 v1(57.48,40.71) ; DM1.72 65.59,69.73 v1(65.69,69.63) ; DM1.5 70.79,86.48 70.64,86.33 69.87,86.33 69.37,86.83 v1(69.37,86.86) ; DM2.64 50.9,71.94 52.32,71.94 v1(52.36,71.89) ; v1(70.58,36.62) 70.76,36.62 70.9,36.48 DM1.197 ; DM1.201 70.87,35.48 70.79,35.56 68.91,35.56 68.56,35.21 68.56,35.18 v1(68.38,35) ; v1(67.44,32.81) 67.44,32.86 68.07,33.48 DM1.209 ; DM1.65 71.15,71.48 70.83,71.17 70.38,71.17 70.06,71.49 70.06,71.51 v1(69.88,71.69) ; DM1.82 65.79,67.23 66.17,66.86 66.17,66.81 v1(66.35,66.64) ; v1(52.56,29.34) 52.47,29.44 DM2.226 ; v1(67.21,82.23) 67.04,82.41 67.04,82.44 66.24,83.23 DM1.18 ; v1(67.72,76.24) 67.54,76.42 67.54,76.44 67.23,76.76 65.35,76.76 65.32,76.73 DM1.44 ; v1(53.79,71.89) 53.61,71.71 53.61,71.69 52.85,70.94 50.9,70.94 DM2.68 ; DM2.188 50.9,38.93 52.54,38.93 v1(52.54,38.93) ; DM2.214 52.08,32.44 52.14,32.37 53.85,32.37 54.22,32 54.22,31.97 v1(54.39,31.8) ; DM1.251 70.78,22.98 v1(70.61,23.16) ; DM2.52 50.92,74.96 52.77,74.96 53.64,74.08 v1(53.64,73.75) 53.64,73.65 52.93,72.94 50.9,72.94 DM2.60 ; DM1.252 65.25,22.73 65.3,22.69 67.33,22.69 v1(67.77,23.14) ; DM2.9 55.9,85.69 55.39,85.17 v1(55.39,84.69) ; DM1.213 70.11,32.48 v1(70.06,32.53) ; v1(65.64,26.26) 65.61,26.23 DM1.238 ; DM2.217 56.15,31.69 55.22,30.76 v1(55.21,30.76) ; v1(57.29,28.14) 59.05,28.14 DM2.231 ; DM2.98 v1(52.34,63.44)
  BOTTOM w0.305: CPU1.AK63 110.54,71.82 109.89,72.47 CPU1.AL64 ; CPU1.AR8 107.7,40.97 108.01,41.28 v1(108.01,41.34) ; LCD1.20 88.45,95.66 88.59,95.8 v1(88.59,96.28) ; GPU1.E4 173.71,87.36 173.71,86.58 v1(173.63,86.5) ; v1(111.99,43.35) 111.86,43.35 CPU1.AH13 ; v1(54.3,39.11) 53.48,39.93 50.9,39.93 DM2.184 ; v1(68.81,93.95) 69.15,93.6 TCBD1.29 69.15,92.26 69.77,91.64 v1(69.77,89.6) ; v1(122.15,63.29) 121.89,63.55 CPU1.G48 ; PU5102.4 39.93,12.53 v1(40.44,12.03) ; v1(122.87,46.83) 123.19,46.51 CPU1.E18 ; v1(178.48,90.97) 178.48,91.66 177.83,92.31 GPU1.B10 ; CPU1.AW6 105.84,39.86 v1(105.84,40.22) ; SSD1.9 193.97,29.44 193.55,29.86 v1(193.32,29.86) ; PU5201.4 145.84,7.78 145.79,7.83 v1(145.79,7.97) ; v1(172.01,95.93) 172.05,95.93 173.06,94.92 173.06,94.02 GPU1.A3 ; v1(10.36,93.41) 9.88,92.93 8.94,92.93 8.68,93.19 USB1.17 ; v1(193.67,24.74) 193.87,24.94 SSD1.27 ; CPU1.D22 CPU1.B22 ; CPU1.V16 CPU1.V17 CPU1.T17 CPU1.P17 ; CPU1.AB16 114.8,45.17 CPU1.Y17 ; CPU1.AB16 CPU1.AB15 ; CPU1.AB16 CPU1.AD16 113.58,45.17 CPU1.AF17 ; CPU1.N21 118.8,48.6 v3(118.41,48.99) ; v1(22.76,77.69) 22.47,77.69 PU4307.3 ; GPU1.F6 174.85,85.16 174.39,84.7 v1(174.39,84.52) ; v1(169.87,50.26) 169.83,50.21 IOBD1.18 ; CPU1.AM46 110.11,63.29 CPU1.AL48 ; CPU1.G63 121.61,71.68 v1(121.61,71.62) 121.05,71.06 CPU1.K61 120.65,71.37 CPU1.K63 CPU1.K64 ; CPU1.D25 123.96,51 v1(124.43,51.47) ; CPU1.E15 123.53,44.2 CPU1.D14 ; v1(127.25,57.12) 127.38,57.12 129.94,54.55 v1(129.94,53.99) ; GPU1.F3 173.05,85.32 172.62,84.88 v1(172.54,84.88) ; LCD1.23 89.95,93.99 v1(90.02,93.92) ; v1(124.43,51.47) 124.61,51.29 CPU1.C25 ; v1(124.43,51.47) 124.27,51.63 CPU1.D26 ; v1(128.09,11.85) 128.09,11.75 127.4,11.06 TP1.4 ; CPU1.T21 116.74,48.81 v3(116.74,48.96) ; v1(57.3,42.71) 57.77,43.19 59.1,43.19 DM2.171 ; v1(178,87.77) 177.94,87.77 177.57,87.4 177.26,87.4 GPU1.E10 ; CPU1.AR16 107.7,45.37 107.53,45.2 107.53,45.15 v1(107.38,45) ; CPU1.V18 CPU1.T18 117.77,47.12 CPU1.P19 ; v1(61.95,89.17) 61.95,91.74 61.15,92.53 TCBD1.13 ; CPU1.D39 124.24,59.07 v1(124.43,58.87) 124.63,59.07 CPU1.B39 ; v1(113.92,49.06) 113.77,48.92 CPU1.AD21 CPU1.AD20 CPU1.AD19 ; PU5001.6 v1(151.54,53.44) ; v1(192.78,18.53) 193.32,18.53 193.72,18.94 SSD1.51 ; IOBD1.6 168.9,56.23 169.59,56.23 169.82,56.46 v1(169.9,56.46) 169.64,56.71 IOBD1.5 ; CPU1.L20 118.99,47.12 CPU1.N19 119.24,46.69 119.42,46.69 CPU1.L18 119.57,46.4 119.57,45.89 CPU1.L17 CPU1.L16 CPU1.K16 ; v3(117.57,48.99) 117.57,48.81 CPU1.P21 ; CPU1.AK8 111.09,39.93 111.09,39.59 111.53,39.15 CPU1.AH6 ; v1(175.77,84.37) 175.84,84.37 176.66,85.19 176.66,85.7 GPU1.F9 ; 60.59,63.18 v1(60.63,63.21) ; CPU1.C5 124.61,38.99 v1(124.44,39.17) ; v1(122.16,65.1) 121.89,65.37 CPU1.G52 ; TCBD1.20 64.65,93.73 64.84,93.92 v1(65.15,93.92) TCBD1.21 ; IOBD1.9 169.57,54.71 169.9,54.38 v1(169.9,54.37) ; v1(176.66,17.8) 177.24,17.8 177.52,18.08 HDD1.14 ; LED1.1 62.44,14.32 v1(62.43,14.33) ; CPU1.AL2 CPU1.AL4 ; v1(169.87,48.35) 169.77,48.45 169.65,48.45 169.4,48.71 IOBD1.21 ; SSD1.21 194,26.44 193.62,26.06 193.62,26.03 v1(193.61,26.01) ; CPU1.G60 121.89,70.28 v1(122.22,70.6) ; CPU1.F42 122.2,60.43 v1(122.2,60.55) ; CPU1.K67 120.75,74.54 121.45,74.54 v1(121.66,74.75) 121.95,74.45 CPU1.G66 ; v1(114.17,43.44) 114.1,43.44 113.86,43.68 CPU1.AD13 ; CPU1.H18 120.58,46.37 CPU1.K18 ; v1(84.66,96.31) 84.66,96.18 85.45,95.39 LCD1.14 ; SSD1.15 193.82,27.94 193.22,28.54 193.09,28.54 ; v1(109.37,61.46) 109.65,61.74 CPU1.AM45 ; PC4423.2 PC4424.2 142.15,30.78 141.58,31.35 v1(141.58,31.41) ; v1(90.5,96.28) 90.5,96.11 90.94,95.67 91.18,95.67 91.45,95.41 LCD1.26 ; SSD1.45 193.6,20.44 v1(193.47,20.31) ; v1(122.13,66.94) 121.89,67.18 CPU1.G55 ; EC2503.2 EC2501.2 ; C2202.1 132.69,35.14 132.48,34.93 131.67,34.93 131.16,34.66 125.55,34.66 v1(125.35,34.87) 124.09,34.87 v1(123.32,35.64) ; CPU1.B58 CPU1.D58 ; HDD1.20 177.49,15.08 177.19,14.77 v1(177.19,14.58) ; GPU1.B1 171.36,91.81 v1(171.12,91.81) ; v1(169.9,52.26) 169.9,52.81 169.49,53.21 IOBD1.12 ; IOBD1.24 168.27,47.21 168.07,47.01 168.07,46.13 167.71,45.76 167.61,45.76 v1(167.56,45.71) ; CPU1.AF15 112.74,44.52 CPU1.AG16 ; CPU1.AD62 v1(113.82,72.8) ; DM2.93 59.1,64.69 57.45,64.69 v1(57.43,64.66) ; HDD1.17 177.42,16.58 177.19,16.35 176.25,16.35 v1(176.02,16.12) ; v1(86.64,96.31) 86.64,95.7 86.95,95.39 LCD1.17 ; v1(107.8,74.44) 107.4,74.44 CPU1.AT68 ; CPU1.AL55 110.11,66.95 CPU1.AM55 ; R2504.2 144.24,11.12 143.97,11.4 143.97,11.85 143.56,12.26 142.06,12.26 v1(142.01,12.31) ; v1(197.97,18.08) 197.33,17.44 SSD1.57 ; v1(108.04,39.53) 108.02,39.51 108.02,39.38 CPU1.AR5 ; v1(62.96,94) 62.96,93.87 62.65,93.56 TCBD1.16 ; v1(62.59,65.83) 62.59,65.62 62.97,65.23 DM1.90 ; U3401.14 24.43,46.7 24.81,47.08 v1(25.32,47.08) ; v1(59.44,14.37) LED1.4 ; PU5102.8 v1(41.25,12.03) ; v1(70.61,79.93) 70.81,79.93 70.87,79.98 DM1.31 ; 126.62,56.05 127.2,55.46 127.2,53.33 v1(130.38,50.16) ; DM1.48 65.33,75.73 65.36,75.7 65.81,75.7 66.12,76.02 66.12,76.06 v1(66.3,76.24) ; v1(70.61,40.94) 70.76,40.94 71.21,40.48 DM1.181 ; CPU1.AN38 108.68,58.58 v1(108.68,58.72) 108.68,58.85 CPU1.AN40 ; CPU1.E53 123.22,66.49 123.56,66.14 ; CPU1.Y21 115.45,48.8 v1(115.26,48.99) ; v1(142.67,3.97) 143,4.3 PU5201.19 ; v1(174.8,94.83) 174.85,94.78 GPU1.A6 ; v1(65.61,38.73) 65.6,38.73 DM1.188 ; v1(109.33,50.49) 109.33,50.34
  BOTTOM w0.356: v1(201.47,35.6) 201.45,35.63 ; CPU1.AM27 109.65,51.72 v1(109.33,51.4) ; v1(146.71,12.01) 147.04,12.34 Q7001.4 ; v1(149.68,29.35) 149.84,29.19 Q2001.4 ; v1(16.38,63.97) 16.38,63.39 17.12,62.65 Q5704.1 ; v1(137.95,28.24) 137.95,28.88 PQ4405.4 ; v1(104.93,54.26) 104.9,54.23 CPU1.BA32 ; v1(128.78,101.06) 128.95,100.89 U4003.3 ; THM261.5 135.51,24.12 135.36,24.12 v1(134.87,23.63) ; CPU1.E46 123.19,62.98 122.86,63.31 ; Q1702.1 150.02,18.11 149.45,17.54 v1(149.45,17.4)
  BOTTOM w0.381: R2436.2 C2414.2 ; v1(104.93,54.26) 104.97,54.23 CPU1.AW32
  BOTTOM w0.406: PQ4405.1 139.32,30.87 139.19,31 139.19,31.28 ; v1(142.01,12.31) 142.01,11.21 Q2503.1 ; v1(109.26,40.42) 109.26,40.49 CPU1.AM8 ; EC8912.2 146.23,12.79 146.71,12.31 v1(146.71,12.01) 146.71,11.8 147.22,11.29 148.34,11.29 148.65,10.98 Q7001.1 ; v1(138.73,35.39) 138.24,35.39 PR4449.2 ; v1(122.93,73.58) 122.93,73.45 123.22,73.16 123.25,73.16 CPU1.E65 ; v1(153.38,18.38) 153.38,19.1 153.07,19.41 Q1702.4 ; v1(139.9,40.65) 140.2,40.65 140.81,40.04 PQ4415.1 ; Q5704.4 19.27,61.6 v1(19.35,61.69)
  BOTTOM w0.457: C2610.2 144.13,25.09 v1(144.07,25.03) ; ED1701.2 133.06,77.75 R1714.2 ; C2721.2 v1(24.66,26.81) ; PC4810.2 v1(134.64,98.42) ; v1(191.31,40.28) 191.62,40.58 C2412.2 R2417.2
  BOTTOM w0.508: C2426.2 187.48,28.36 C2420.2 ; R2056.2 108.29,33.59 107.96,33.59 107.95,33.59 v1(107.36,33.59) ; TP1.10 122.99,5.94 v1(122.99,5.43) ; PC4728.2 152.83,78.9 152.3,79.43 v1(152.3,79.65) ; v1(184.3,44.7) 184.66,44.34 R2449.1 ; C2503.2 143.32,18.6 142.04,18.6 ; TCBD1.34 73.15,96.59 v1(72.57,96) ; USB2.4 16.46,49.53 ; USB2.4 15.7,48.77 ; USB2.4 15.7,50.29 ; v3(26.34,83.02) 25.55,83.81 PC4307.2 ; 3.52,100.28 USB1.22 2.19,101.12 ; PR4661.2 v1(149.02,89.88) ; PC5114.2 36.12,14.7 v1(35.61,14.19) ; C2501.2 122.35,11.95 C2502.2 126.59,11.95 126.69,11.85 v1(126.74,11.85) ; v1(135.71,34.76) 135.71,35.99 X2201.2 ; 99.13,55.54 98.45,55.54 97.64,54.73 v1(97.64,54.55) ; C2122.2 137.49,41.44 137.74,41.44 v1(138.41,42.11) ; SPI25.4 130.61,21.43 131.2,22.03 v1(131.78,22.03) ; R2456.2 198.58,40.4 C2436.2 197.66,40.58 197.66,40.58 197.41,40.83 197.25,40.83 v1(197.05,41.04) ; v1(105.48,15.51) C4031.2 104.87,16.22 C4034.2 ; ED6401.2 65.12,7.64 LED1.5 v1(65.09,6.06) ; 142.04,18.6 142.04,19.94 141.4,20.57 v1(141.4,20.69) ; 142.04,18.6 140.74,17.3 Q6503.S 140.1,17.49 C6503.2 ; C2722.2 v1(17.93,26.76) ; LCD1.41 77.19,94.89 76.25,93.95 v1(74.85,93.95) 74.85,94.71 75.85,95.71 LCD1.43 ; v1(26.95,14.04) 26.52,13.61 R2717.2 ; v1(179.4,25.63) HDD1.22 178.32,26.37 178.62,26.67 181.7,26.67 182.32,26.05 HDD1.21 ; v1(25.58,41.75) 25.5,41.67 C3406.2 24.18,41.55 C3402.2 ; C2429.2 C2410.2 198.75,37.8 198.96,37.59 C2418.2 199.05,37.15 200.18,37.15 v1(200.25,37.23) ; v1(104.32,96) 104.4,95.91 ED1709.2 ; v1(104.32,96) 104.24,95.93 ED1708.2 104.25,94.28 C1711.2 105.1,94.25 R1719.2 ; v1(104.32,96) 104.32,96.07 103.67,96.71 102.54,96.71 LCD1.44 ; v1(147.62,64.23) 148.39,63.47 PC4707.2 148.49,62.58 148.87,62.2 PC4708.2 ; PR4653.1 142.62,89.2 v1(142.16,88.74) ; R803.1 122.93,27.68 122.99,27.73 v1(123.01,27.73) ; 4.6,64.44 HDMI1.20 ; HDMI1.20 5.98,65.43 ; HDMI1.20 3.22,65.43 ; v1(22.93,62.45) 23.32,62.45 C5703.1 ; v1(115.47,89.35) 116.25,90.13 SPR4.1 ; H5.1 114.29,5.6 Q6501.S 114.23,9.63 115.19,10.58 115.19,11.59 116.05,12.45 R6509.2 ; v1(194.8,35.38) 194.79,35.37 194.51,35.37 C2413.2 ; v1(134.44,29.01) 135.24,29.01 PR4413.1 ; v1(152.2,99.1) 151.61,99.1 PR4652.2 ; PC5110.2 v1(43.36,1.87) 42.7,1.87 PC5113.2 ; ED3602.2 17.4,53.23 v1(17.37,53.26) ; ED1704.2 ED1711.2 103.96,20.79 104.34,21.18 v1(104.65,21.18) ; R2436.2 183.64,34.97 183.31,35.3 v1(182.09,35.3) ; USB1.14 6.06,88.97 ; USB1.14 7.39,88.13 ; USB1.14 4.72,88.13 ; USB1.14 6.06,87.3 ; 5.43,23.82 6.2,24.58 USB3.13 7.31,24.58 7.95,23.94 ; v1(20.69,77.74) 20,78.43 PQ4304.E ; 6.5,41.55 USB3.12 7.19,40.28 7.87,40.96 ; 3.52,88.13 USB1.13 2.19,87.3 ; 14.2,52.27 USB2.7 14.2,53.79 ; IOBD1.53 169.8,59.61 v1(169.85,59.66) 169.85,61.12 170.54,61.81 IOBD1.51 ; 6.5,43.88 USB2.13 7.36,45.18 8.08,44.47 ; R2019.2 111,19.47 R6508.2 ; R402.2 132.46,70.02 v1(132.28,70.2) ; 14.95,58.54 USB2.10 ; USB2.10 16.63,59.43 ; USB2.10 14.95,60.32 ; USB1.20 9.48,98.68 ; USB1.20 7.3,98.68 ; USB1.20 8.39,99.47 ; PC5414.2 45.54,96.94 45.85,97.25 v1(45.85,97.35) ; 14.95,25.14 USB3.11 ; USB3.11 14.95,26.92 ; USB3.11 16.63,26.03 ; v1(21.61,83.25) 21.61,82.63 U4302.3 ; D2601.A 148.74,77.44 PC4721.2 148.36,78.45 v1(147.62,78.45) ; 14.2,31.67 USB3.7 14.2,33.19 ; C2423.2 C2411.2 186.79,45.13 v1(187.35,45.69) ; HDMI1.22 5.98,83.73 ; HDMI1.22 4.6,84.72 ; HDMI1.22 3.22,83.73 ; C3513.2 20.09,39.11 20.62,38.57 U3501.2 ; v1(167.56,45.71) 167.21,45.71 166.75,45.25 EC6603.2 ; 10.8,89.44 HS1.1 13.73,86.51 ; v1(17.55,68.54) 17.9,68.9 PD4302.1 ; EC8902.2 19.1,25.44 18.74,25.44 v1(18.63,25.56) ; USB3.10 16.63,38.83 ; USB3.10 14.95,39.72 ; USB3.10 14.95,37.94 ; v1(118.27,19.57) 117.92,19.93 R4006.2 117.32,19.27 117.55,19.04 C4009.2 ; PR5104.2 v1(44.88,1.87) ; v1(141.3,38.15) 141.05,38.15 140.31,37.41 PR4424.2 139.65,38.13 PQ4415.4 ; KBBL1.6 109.97,5.04 v1(110.67,5.73) ; v1(55.28,2.91) 55.27,2.91 55.12,2.76 ED6402.2 ; X1801.4 133.38,52.98 v1(133.11,53.26) ; v1(136.5,34.05) 136.57,34.05 PC4432.2 PC4427.2 ; R604.2 v1(132.26,77.82) 132.99,77.82 R1714.2 ; PC5115.2 39.42,8.6 v1(40.05,9.24) 39.67,9.62 PC5118.2 ; v1(193.32,29.86) 193.32,28.77 192.84,28.29 R2445.1 ; USB1.21 6.06,101.12 ; USB1.21 6.06,99.45 ; USB1.21 4.72,100.28 ; USB1.21 7.39,100.28 ; v1(144.32,41.55) 144.32,40.89 PC4412.2 ; EC6401.2 66.99,13.05 66.48,12.54 v1(66.34,12.54) ; 6.22,97.41 USB1.B1 6.85,98.45 ; USB3.4 16.46,28.93 ; USB3.4 15.7,29.69 ; USB3.4 15.7,28.17 ; v1(140.61,27.74) 140.93,27.42 C2601.2 ; C2115.2 137.46,38.7 138.05,38.12 v1(138.55,38.12) ; C2602.2 137.59,27.86 137.59,27.88 v1(137.95,28.24) ; EC2502.2 123.9,20.34 v1(123.97,20.26) ; v1(47.93,1.87) PC5138.2 47.95,2.58 PR5127.2 ; D4305.1 162.51,38.55 H3.1 ; PC5102.2 v1(36.63,11.27) ; v1(39.93,94.28) 40.18,94.53 PC5427.2 39.32,95.14 PR5409.2 ; FAN1.2 155.16,76.21 v1(154.86,75.91) ; PR4436.2 146.86,29.18 146.1,28.41 v1(146.1,27.7) ; 14.95,45.74 USB2.11 ; USB2.11 16.63,46.63 ; USB2.11 14.95,47.52 ; PR4409.2 147.62,31 147.65,31.03 PC4413.2 147.95,31.82 v1(148.33,32.2) ; PC5410.2 v1(39.09,100.91) ; v1(14.73,80.76) 14.77,80.8 PD4303.3 ; EC5001.2 v1(152.83,63.08) ; C3403.2 C3401.2 C3407.2 17.58,57.22 17.07,57.73 ; USB1.15 9.48,89.73 ; USB1.15 8.39,88.95 ; USB1.15 7.3,89.73 ; PC5001.2 152.8,52.01 153.21,52.42 v1(153.21,53.69) ; ED2401.2 188.78,39.25 v1(188.52,38.98) ; PU5402.2 63.52,15.1 63.3,15.33 PC5407.2 62.86,15.03 62.43,14.6 v1(62.43,14.33) ; DM2.261 41.27,88.11 40.5,87.34 v1(40.23,87.34) ; 73.33,103.22 56.31,103.22 ; v1(108.23,18.86) 107.72,18.86 107.49,19.09 EC1707.2 ; KB1.1 95.32,8.78 v1(94.66,9.44) ; 6.85,89.97 USB1.B12 6.22,91.01 ; PC4610.2 160.53,103.27 v1(160.45,103.34) ; USB2.12 6.5,62.35 ; v1(22.76,77.69) 22.81,77.64 PR4313.2 ; v1(196.24,45.46) 196.24,45.03 195.86,44.64 R2448.2 195.91,44.49 C2409.2 ; v1(81.46,22.44) 79.95,20.94 DM1.262 ; EC4308.2 160.58,29.11 161.66,29.11 v1(161.85,28.92) ; v1(136.99,45.98) 136.99,45.37 C2119.2 ; 142.42,90.64 v1(142.42,90.52) ; D4304.1 149.88,23.75 v1(149.88,23.36) 149.88,23.08 150.24,22.73 R2517.2 ; EC8952.2 163.43,103.72 162.94,103.24 v1(162.66,103.24) ; X2201.4 134.22,39.54 134.73,40.05 v1(135.13,40.05) ; 11.1,66.34 HDMI1.21 11.1,68.32 ; v1(139.11,90.77) 138.71,90.36 PC4807.2 ; v1(139.18,31.28) 139.19,31.28 139.19,31.31 139.67,31.79 PR4433.2 ; v1(57.45,6.12) 57.45,6.95 LED1.6 ; v1(191.31,40.28) 191.31,40.25 191.5,40.06 Q2408.S 192.47,40.37 193.02,40.91 193.83,40.91 R2611.2 ; v1(54.28,5.93) 53.9,5.55 EC6402.2 ; X1801.2 134.89,49.2 v1(135.58,48.51) ; PR5106.1 v1(47.17,1.92) ; Q2701.S v1(22.59,28.21)
  vias: v1(0.81,12.16) v1(0.76,11.2) v1(0.76,6.12) v1(0.76,1.04) v1(0.91,3.83) v1(0.96,21.84) v1(1.73,84.98) v1(1.75,86.58) v1(1.75,83.28) v1(2.3,65.72) v1(3.27,6.54) v1(3.38,8.47) v1(3.63,21.91) v1(3.61,0.83) v1(4.04,86.07) v1(4.11,101.18) v1(4.88,23.13) v1(5.41,62.86) v1(5.59,42.59) v1(6.32,8.53) v1(6.33,0.76) v1(6.45,6.52) v1(6.96,83.2) v1(7.13,65.97) v1(7.54,84.04) v1(7.57,2.71) v1(8,63.29) v1(8.58,101.16) v1(8.61,23.82) v1(8.91,65.35) v1(8.86,8.45) v1(8.94,6.7) v1(9.35,90.82) v1(9.27,42.61) v1(9.65,61.74) v1(9.83,2.66) v1(10.16,98.16) v1(10.21,7.84) v1(10.31,80.2) v1(10.44,97.04) v1(11.05,95.16) v1(11.15,63.49) v1(11.11,44.42) v1(11.43,42.59) v1(11.41,0.76) v1(11.54,61.64) v1(11.54,41.04) v1(11.91,91.48) v1(11.89,90.34) v1(12.5,65.88) v1(12.5,63.59) v1(12.83,95.27) v1(12.95,81.02) v1(13.05,82.62) v1(13.41,61.56) v1(13.54,42.64) v1(13.87,27.19) v1(14.17,24.58) v1(14.51,64.56) v1(14.6,40.58) v1(14.7,81.68) v1(14.73,79.93) v1(15.04,66.64) v1(15.52,94.78) v1(15.64,10.33) v1(15.9,60.98) v1(16.13,88.71) v1(16.15,58.36) v1(16.38,65.19) v1(16.49,0.76) v1(18.85,1.59) v1(19.68,7.31) v1(21.18,89.04) v1(21.59,99.36) v1(21.77,46.42) v1(22.02,65.84) v1(22.35,47.08) v1(22.35,45.81) v1(22.4,17.11) v1(22.68,98.24) v1(22.65,65.84) v1(22.66,37.3) v1(22.66,25.24) v1(22.88,46.42) v1(23.04,17.11) v1(23.09,89.58) v1(23.24,96.05) v1(23.26,94.1) v1(23.29,67.11) v1(23.29,66.47) v1(23.29,65.84) v1(23.29,65.2) v1(23.29,64.57) v1(23.75,18.46) v1(23.75,17.8) v1(23.75,17.11) v1(23.75,16.45) v1(23.75,15.79) v1(23.92,65.84) v1(24.43,17.11) v1(24.56,65.84) v1(24.61,38.62) v1(25.07,17.09) v1(25.2,98.21) v1(25.63,32.99) v1(25.65,31.06) v1(25.83,99.76) v1(26.42,53.69) v1(26.59,50.13) v1(26.74,50.92) v1(27,37.81) v1(27.3,62.58) v1(27.28,47.67) v1(27.63,101.25) v1(28.14,42.51) v1(28.55,30.73) v1(28.8,100.83) v1(28.83,50.79) v1(28.78,42.51) v1(29.41,42.51) v1(30.02,94.05) v1(30.05,44.42) v1(30.05,43.78) v1(30.05,43.15) v1(30.05,42.51) v1(30.05,41.88) v1(30.05,41.24) v1(30.05,40.61) v1(30.2,56.94) v1(30.68,52.47) v1(30.68,42.51) v1(30.76,50.94) v1(31.32,42.51) v1(31.67,56.1) v1(31.73,0.76) v1(31.95,42.51) v1(32.71,65.73) v1(32.69,59.15) v1(33.7,61.18) v1(33.7,60.16) v1(33.7,59.15) v1(33.7,58.13) v1(33.7,57.12) v1(34.72,59.15) v1(35.91,36.92) v1(36.02,35.37) v1(36.19,19.22) v1(36.81,0.76) v1(37.74,103.22) v1(37.79,28.01) v1(38.5,28.77) v1(38.48,27.32) v1(39.32,27.98) v1(39.6,103.25) v1(39.65,12.03) v1(39.9,65.93) v1(40.05,21.43) v1(40.18,34.28) v1(40.61,32.45) v1(41.15,35.83) v1(41.81,36.47) v1(41.81,35.83) v1(41.81,35.2) v1(41.89,0.76) v1(42.16,58.26) v1(42.44,35.83) v1(42.75,60.19) v1(42.75,59) v1(42.72,54.07) v1(42.8,61.69) v1(42.8,61.05) v1(42.77,57.52) v1(42.8,56.35) v1(42.76,55.37) v1(43.18,95.01) v1(43.89,37.86) v1(44.12,66.69) v1(44.25,6.7) v1(44.32,18.38) v1(44.83,64.94) v1(46.15,12.16) v1(46.3,67.4) v1(46.35,68.57) v1(46.35,65.32) v1(52.05,0.76) v1(52.32,89.91) v1(53.21,90.85) v1(53.59,2.88) v1(54.57,78.5) v1(55.8,14.19) v1(56.31,9.31) v1(56.44,14.19) v1(57.13,0.76) v1(57.2,14.19) v1(59.87,94.58) v1(61.06,94) v1(62.21,0.76) v1(63.47,98.59) v1(64.97,89.2) v1(65.33,2.91) v1(66.22,2.91) v1(66.8,19.42) v1(67.11,2.94) v1(67.29,0.76) v1(67.41,89.78) v1(67.82,78.3) v1(67.99,2.94) v1(68.88,2.94) v1(69.77,2.94) v1(70.66,12.54) v1(70.66,2.94) v1(71.55,2.94) v1(72.44,2.94) v1(72.37,0.76) v1(72.74,89.93) v1(73.2,2.94) v1(73.81,89.42) v1(74.09,2.94) v1(74.53,47.75) v1(74.63,50.29) v1(76.01,51.66) v1(76.94,59.51) v1(77.34,91.02) v1(77.41,106.52) v1(77.45,0.76) v1(77.65,51.66) v1(77.82,109.92) v1(77.98,91.02) v1(78.17,59.56) v1(78.43,68.05) v1(78.61,91.02) v1(78.87,111.52) v1(79.25,91.02) v1(79.31,51.71) v1(79.45,68.05) v1(80.24,112.56) v1(80.32,68.77) v1(80.6,59.53) v1(80.87,51.66) v1(81.85,68.9) v1(82,51.58) v1(82.53,0.76) v1(82.83,96) v1(83.09,67.97) v1(83.09,59.19) v1(85.27,93.31) v1(86.33,113.16) v1(87.04,2.91) v1(87.93,2.91) v1(88.11,93.92) v1(88.82,2.91) v1(89.71,2.91) v1(90.09,26.13) v1(90.6,2.91) v1(91.41,113.16) v1(91.49,2.91) v1(91.92,93.92) v1(92.43,96.21) v1(92.38,2.91) v1(92.69,0.76) v1(93.27,2.91) v1(94.16,2.91) v1(94.99,76.34) v1(95.05,2.91) v1(95.53,77.56) v1(95.93,2.91) v1(96.26,80.41) v1(96.49,113.16) v1(96.72,73.27) v1(96.82,2.91) v1(97.71,2.91) v1(97.79,69.26) v1(97.77,0.76) v1(97.94,70.76) v1(97.96,72.61) v1(98.04,58.36) v1(98.32,48.38) v1(98.6,2.91) v1(98.78,93.79) v1(99.03,23.89) v1(99.57,54.19) v1(99.67,105.88) v1(99.92,50.05) v1(100.05,48.38) v1(100.4,52.75) v1(100.91,51.2) v1(101.27,21.56) v1(101.57,113.16) v1(101.87,58.57) v1(102.06,105.63) v1(102.16,104.99) v1(102.51,99.79) v1(102.92,4.66) v1(102.85,0.76) v1(108.03,46.83) v1(108.08,83.61) v1(108.89,88.48) v1(109.4,1.74) v1(109.5,82.26) v1(110.54,18.86) v1(110.84,48.12) v1(111.66,34.47) v1(112.39,79.19) v1(112.93,64.99) v1(112.95,81.04) v1(113.82,74.75) v1(113.82,73.45) v1(115.21,40.76) v1(120.92,43.17) v1(121.89,113.16) v1(122.22,56.89) v1(122.21,40.43) v1(122.27,58.72) v1(122.3,48.66) v1(122.27,47.74) v1(126.97,113.16) v1(127.76,50.57) v1(128.01,48.86) v1(128.24,42.79) v1(128.29,39.31) v1(128.37,65.88) v1(128.5,64.2) v1(128.47,62.5) v1(129.31,63.26) v1(129.39,58.94) v1(130.78,64.81) v1(132.05,113.16) v1(132.72,41.74) v1(132.79,42.94) v1(133.91,45.91) v1(134.06,34.76) v1(134.29,101.31) v1(134.28,53.26) v1(136.42,47.56) v1(136.52,37.15) v1(137.13,113.16) v1(140.92,96.89) v1(140.94,96.26) v1(140.94,95.6) v1(140.97,94.91) v1(140.99,92.65) v1(141.65,96.92) v1(141.68,96.28) v1(141.68,95.62) v1(141.65,94.89) v1(141.65,94.15) v1(141.68,93.46) v1(141.65,92.63) v1(142.21,113.16) v1(142.31,96.92) v1(142.34,96.28) v1(142.34,95.62) v1(142.34,94.89) v1(142.31,94.15) v1(142.34,93.46) v1(142.29,92.65) v1(142.44,34.66) v1(142.95,96.92) v1(142.92,92.65) v1(142.97,96.28) v1(142.97,95.62) v1(143.03,94.91) v1(143,94.17) v1(143.03,93.49) v1(143.15,35.35) v1(143.18,34.66) v1(143.2,34) v1(143.91,34.64) v1(144.59,61.71) v1(147.29,113.16) v1(149.53,55.01) v1(151.59,32.27) v1(152.02,69.64) v1(152.04,69) v1(152.04,68.34) v1(152.07,67.66) v1(152.09,65.4) v1(152.27,85.06) v1(152.27,84.4) v1(152.3,83.71) v1(152.32,81.45) v1(152.3,31.16) v1(152.37,113.16) v1(152.75,69.66) v1(152.78,69.03) v1(152.78,68.37) v1(152.75,67.63) v1(152.75,66.89) v1(152.78,66.21) v1(152.75,65.37) v1(152.91,85.72) v1(152.93,85.08) v1(152.93,84.42) v1(152.93,83.68) v1(152.93,82.95) v1(152.98,82.26) v1(152.98,81.42) v1(153.21,54.83) v1(153.41,69.66) v1(153.44,69.03) v1(153.44,68.37) v1(153.44,67.63) v1(153.41,66.89) v1(153.44,66.21) v1(153.57,85.72) v1(153.59,85.08) v1(153.59,84.42) v1(153.59,83.68) v1(153.59,82.95) v1(153.62,82.26) v1(153.62,81.45) v1(154.05,69.66) v1(154.02,65.4) v1(154.07,69.03) v1(154.07,68.37) v1(154.13,67.66) v1(154.1,66.92) v1(154.13,66.23) v1(154.2,85.72) v1(154.23,85.08) v1(154.23,84.42) v1(154.23,83.68) v1(154.23,82.97) v1(154.25,82.26) v1(154.25,81.45) v1(154.63,25.04) v1(156.41,11.4) v1(156.56,25.04) v1(156.82,1.67) v1(157.45,113.16) v1(157.59,2.38) v1(158.34,11.4) v1(160.39,98.8) v1(161.03,60.88) v1(161.34,61.43) v1(161.31,55.97) v1(161.47,20.25) v1(161.95,55.97) v1(162.53,113.16) v1(165.1,58.3) v1(166.24,54.96) v1(166.29,56.99) v1(166.94,112.01) v1(167.03,106.67) v1(167.98,32.19) v1(169.87,46.42) v1(170.99,104.64) v1(171.85,104.59) v1(174.09,79.37) v1(174.72,79.37) v1(174.67,17.42) v1(175.26,8.53) v1(175.51,52.95) v1(175.46,51.02) v1(175.54,49.52) v1(175.54,44.09) v1(176.2,60.62) v1(177.24,11.93) v1(177.21,8.86) v1(178.18,64.51) v1(178.26,11.93) v1(179.04,97.93) v1(179.37,8.81) v1(179.68,64.45) v1(179.75,104.51) v1(179.75,98.42) v1(179.8,69) v1(179.93,74.95) v1(179.93,71.42) v1(179.93,62.37) v1(179.94,59.15) v1(179.96,57.27) v1(180.62,53.23) v1(180.92,52.21) v1(181.68,10.33) v1(182.03,16.54) v1(182.27,17.92) v1(183.18,18.95) v1(183.44,15.89) v1(183.46,16.91) v1(183.72,10.33) v1(184.58,16.68) v1(185.29,15) v1(185.47,10.68) v1(188.36,8.22) v1(190.88,30.9) v1(191.95,8.22) v1(193.72,9.49) v1(196.04,6.52) v1(198.04,22.06) v1(197.97,20.06) v1(198.85,45.69) v1(199.69,7.33) v1(199.95,27.65) v1(199.95,23.71) v1(200.28,45.15) v1(200.28,43.86) v1(200.96,7.33) v1(201.6,6.57) v1(202.46,35.35) v1(203.27,35.14) v1(203.53,20.46) v1(203.55,21.15) v1(203.55,15.51) v1(203.81,6.6) v1(203.96,34.87) v1(204.09,33) v1(204.09,12.68) v1(204.09,11.7) v1(204.09,9.97) v2(18.79,61.31) v2(19.45,27.35) v2(21.72,32.4) v2(22.78,17.87) v2(24.51,66.79) v2(24.84,100.83) v2(27.68,99.91) v2(32.99,2.79) v2(44.8,19.98) v2(49.96,23.51) v2(58.14,25.14) v2(62.53,87.29) v2(65.45,97.91) v2(77.67,27.14) v2(79.04,70.07) v2(83.34,50.49) v2(85.27,87.7) v2(90.83,68.37) v2(97.51,18.99) v2(107.82,89.48) v2(116.94,111.4) v2(118.11,39.21) v2(121.49,83.99) v2(122.6,100.91) v2(125.86,97.68) v2(138.35,48.81) v2(139.19,61.33) v2(139.62,101.9) v2(140.66,45.3) v2(141.17,85.13) v2(143.53,74.41) v2(144.19,36.29) v2(146.23,75.68) v2(178.08,22.78) v2(178.61,83.79) v2(203.5,14.16) v3(16.05,40.1) v3(17.83,39.21) v3(18.21,33.87) v3(18.97,33.37) v3(19.61,32.73) v3(22.78,33.62) v3(24.66,55.67) v3(31.16,7.59) v3(31.16,6.06) v3(31.19,4.66) v3(31.16,3.39) v3(32.03,3.39) v3(32.05,7.59) v3(32.05,6.06) v3(32.05,4.66) v3(46.84,6.62) v3(47.51,7.13) v3(47.52,6.06) v3(89.46,105.88) v3(89.58,108.3) v3(89.58,107.41) v3(89.95,106.64) v3(90.79,106.66) v3(95.78,105.88) v3(96.64,105.94) v3(97.11,19.72) v3(97.97,19.74) v3(106.6,99.91) v3(111.17,69.82) v3(111.68,99.91) v3(112.57,99.91) v3(113.56,55.19) v3(113.71,62.2) v3(114.1,99.95) v3(114.58,55.19) v3(114.58,54.17) v3(114.73,62.2) v3(115.62,55.19) v3(115.75,62.2) v3(116.13,99.95) v3(116.64,62.2) v3(116.61,55.19) v3(116.61,54.17) v3(117.02,99.95) v3(117.37,109.08) v3(117.4,70.73) v3(117.4,69.71) v3(117.4,68.7) v3(117.37,67.78) v3(117.4,66.74) v3(117.65,62.2) v3(117.68,55.19) v3(117.78,108.3) v3(118.03,99.95) v3(118.21,109.06) v3(118.64,55.19) v3(118.64,54.17) v3(118.67,108.32) v3(118.92,99.95) v3(119.58,55.19) v3(119.94,99.95) v3(120.42,88.08) v3(120.42,87.12) v3(120.45,86.15) v3(120.44,85.19) v3(120.45,84.25) v3(120.83,99.95) v3(121.44,88.13) v3(121.44,87.17) v3(121.44,86.2) v3(121.42,85.21) v3(121.72,99.97) v3(122.35,85.21) v3(122.37,88.13) v3(122.37,87.17) v3(122.37,86.2) v3(123.37,101.31) v3(123.37,100.42) v3(123.7,99.61) v3(124.53,99.58) v3(124.64,101.31) v3(124.64,100.42) v3(125.42,99.56) v3(125.53,101.29) v3(125.53,100.4) v3(126.36,101.31) v3(126.36,100.42) v3(126.39,99.56) v3(131.29,4.92) v3(131.29,4.08) v3(132.15,5.79) v3(132.31,4.92) v3(132.31,3.98) v3(136.7,51.35) v3(136.7,50.08) v3(136.7,48.86) v3(137.03,62.2) v3(137.08,61.05) v3(137.31,50.72) v3(137.31,49.5) v3(138.05,62.2) v3(138.1,61.05) v3(138.94,62.2) v3(139.62,100.68) v3(139.88,102.96) v3(140,104.99) v3(140,103.98) v3(140.51,100.68) v3(141.15,99.79) v3(141.15,98.9) v3(141.27,86.96) v3(141.4,77.44) v3(141.4,76.29) v3(141.4,72.1) v3(141.4,71.21) v3(141.44,45.13) v3(141.63,100.47) v3(141.7,86.22) v3(141.88,44.39) v3(142.19,61.13) v3(142.29,76.29) v3(142.29,45.13) v3(142.54,77.44) v3(142.54,72.48) v3(142.54,71.47) v3(142.54,70.58) v3(142.59,86.22) v3(143.08,61.13) v3(143.31,76.29) v3(143.43,72.48) v3(143.43,71.47) v3(143.43,70.58) v3(143.48,86.22) v3(143.56,77.44) v3(143.97,61.13) v3(144.32,76.29) v3(144.37,86.22) v3(144.45,72.61) v3(144.45,71.59) v3(144.45,70.58) v3(144.58,77.44) v3(145.57,76.42) v3(147.45,2.12) v3(147.98,91.89) v3(148.54,2.1) v3(148.64,56.99) v3(148.87,92.78) v3(148.87,91.89) v3(148.89,91.02) v3(149.6,100.17) v3(149.63,2.1) v3(149.66,101.06) v3(149.66,99.28) v3(149.66,98.39) v3(149.66,97.5) v3(149.66,57.75) v3(149.66,56.86) v3(150.11,102.79) v3(150.11,101.9) v3(150.57,2.1) v3(151.64,2.1) v3(152.7,2.1) v3(152.83,72.91) v3(153.39,7.54) v3(153.74,72.86) v3(153.74,72.03) v3(154.63,72.89) v3(154.63,72.03) v3(155.12,52.29) v3(157.73,36.87) v3(157.78,35.53) v3(157.78,34.05) v3(158.29,75.35) v3(158.29,74.46) v3(158.29,73.45) v3(158.8,35.53) v3(159.1,45.48) v3(159.1,44.59) v3(159.31,80.73) v3(159.31,79.85) v3(159.31,34.05) v3(159.94,45.46) v3(159.97,44.57) v3(160.2,80.73) v3(160.2,79.85) v3(160.81,45.46) v3(160.81,44.57) v3(161.03,79.85) v3(161.47,75.28) v3(161.47,74.39) v3(161.47,73.45) v3(161.47,72.56) v3(161.64,45.43) v3(161.67,44.54) v3(163.29,65.63) v3(163.32,64.74) v3(163.29,63.85) v3(163.5,87.47) v3(163.5,86.45) v3(164.51,86.45) v3(165.02,89.63) v3(165.02,88.61) v3(166.17,89.63) v3(166.17,88.61) v3(169.98,28.46) v3(170.53,29.15) v3(170.76,28.13) v3(171.22,29.71) v3(171.37,28.87) v3(176.35,22.72) v3(177.14,22.42) v3(197.92,11.4) v3(197.97,10.36)
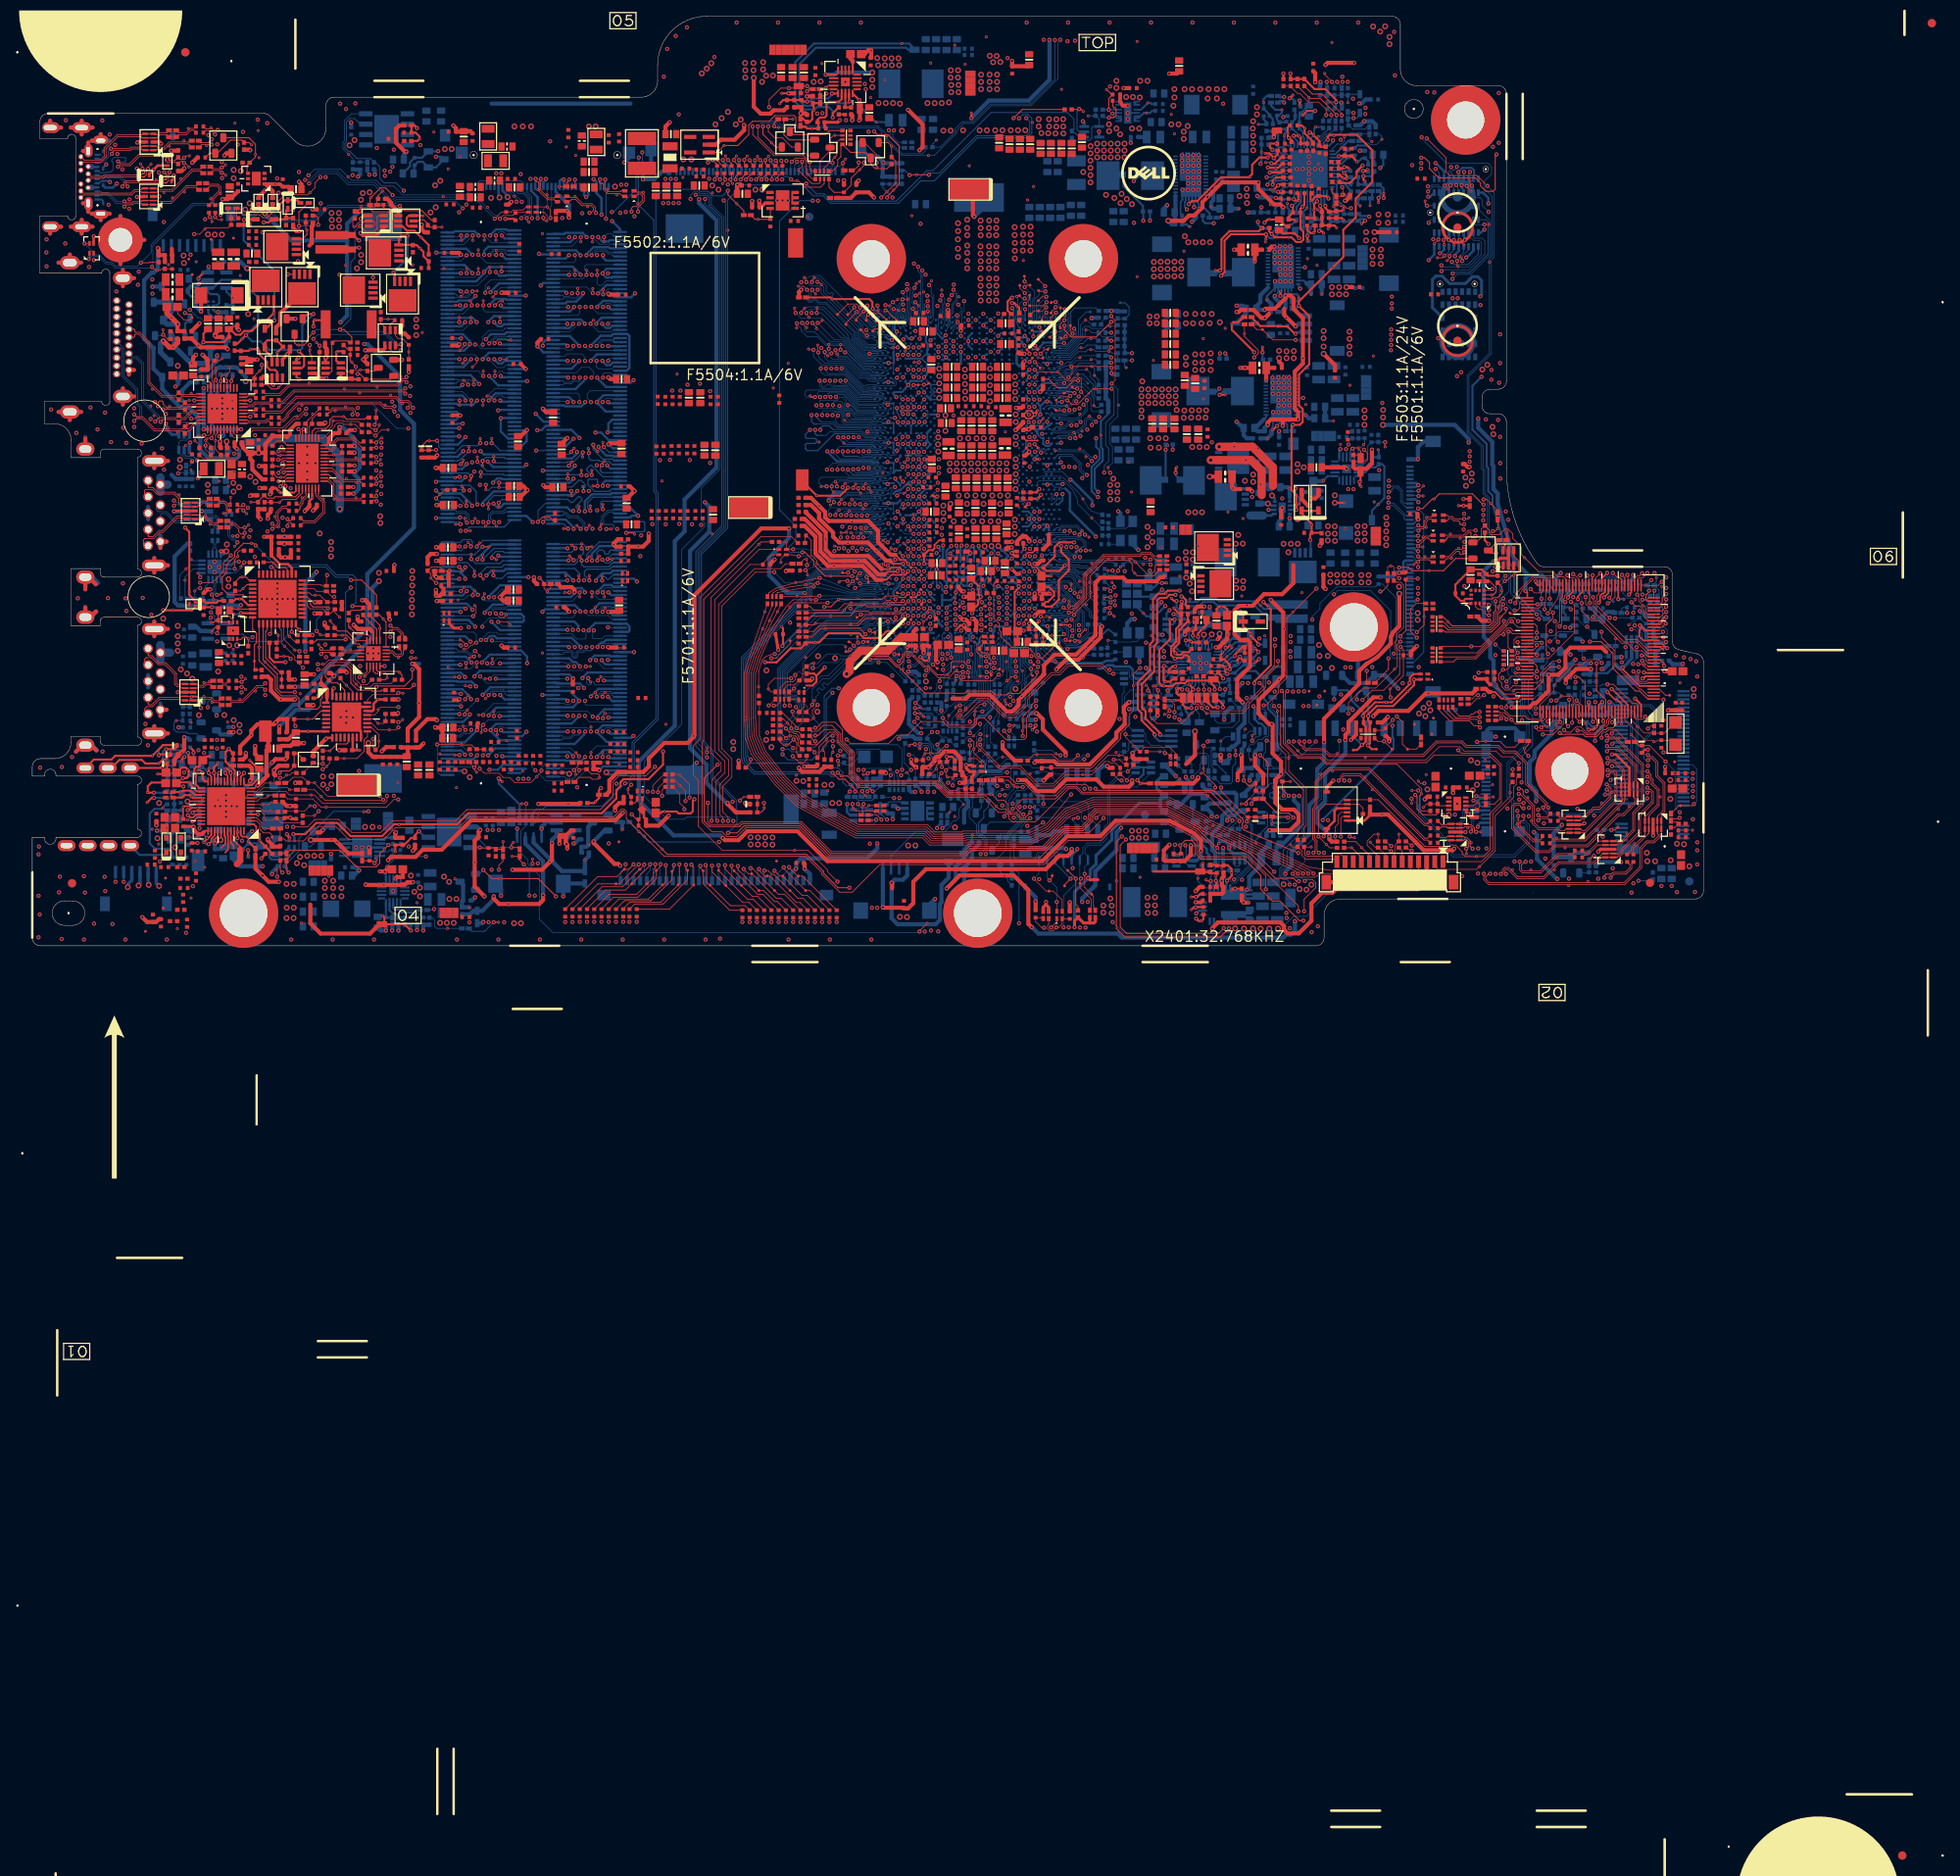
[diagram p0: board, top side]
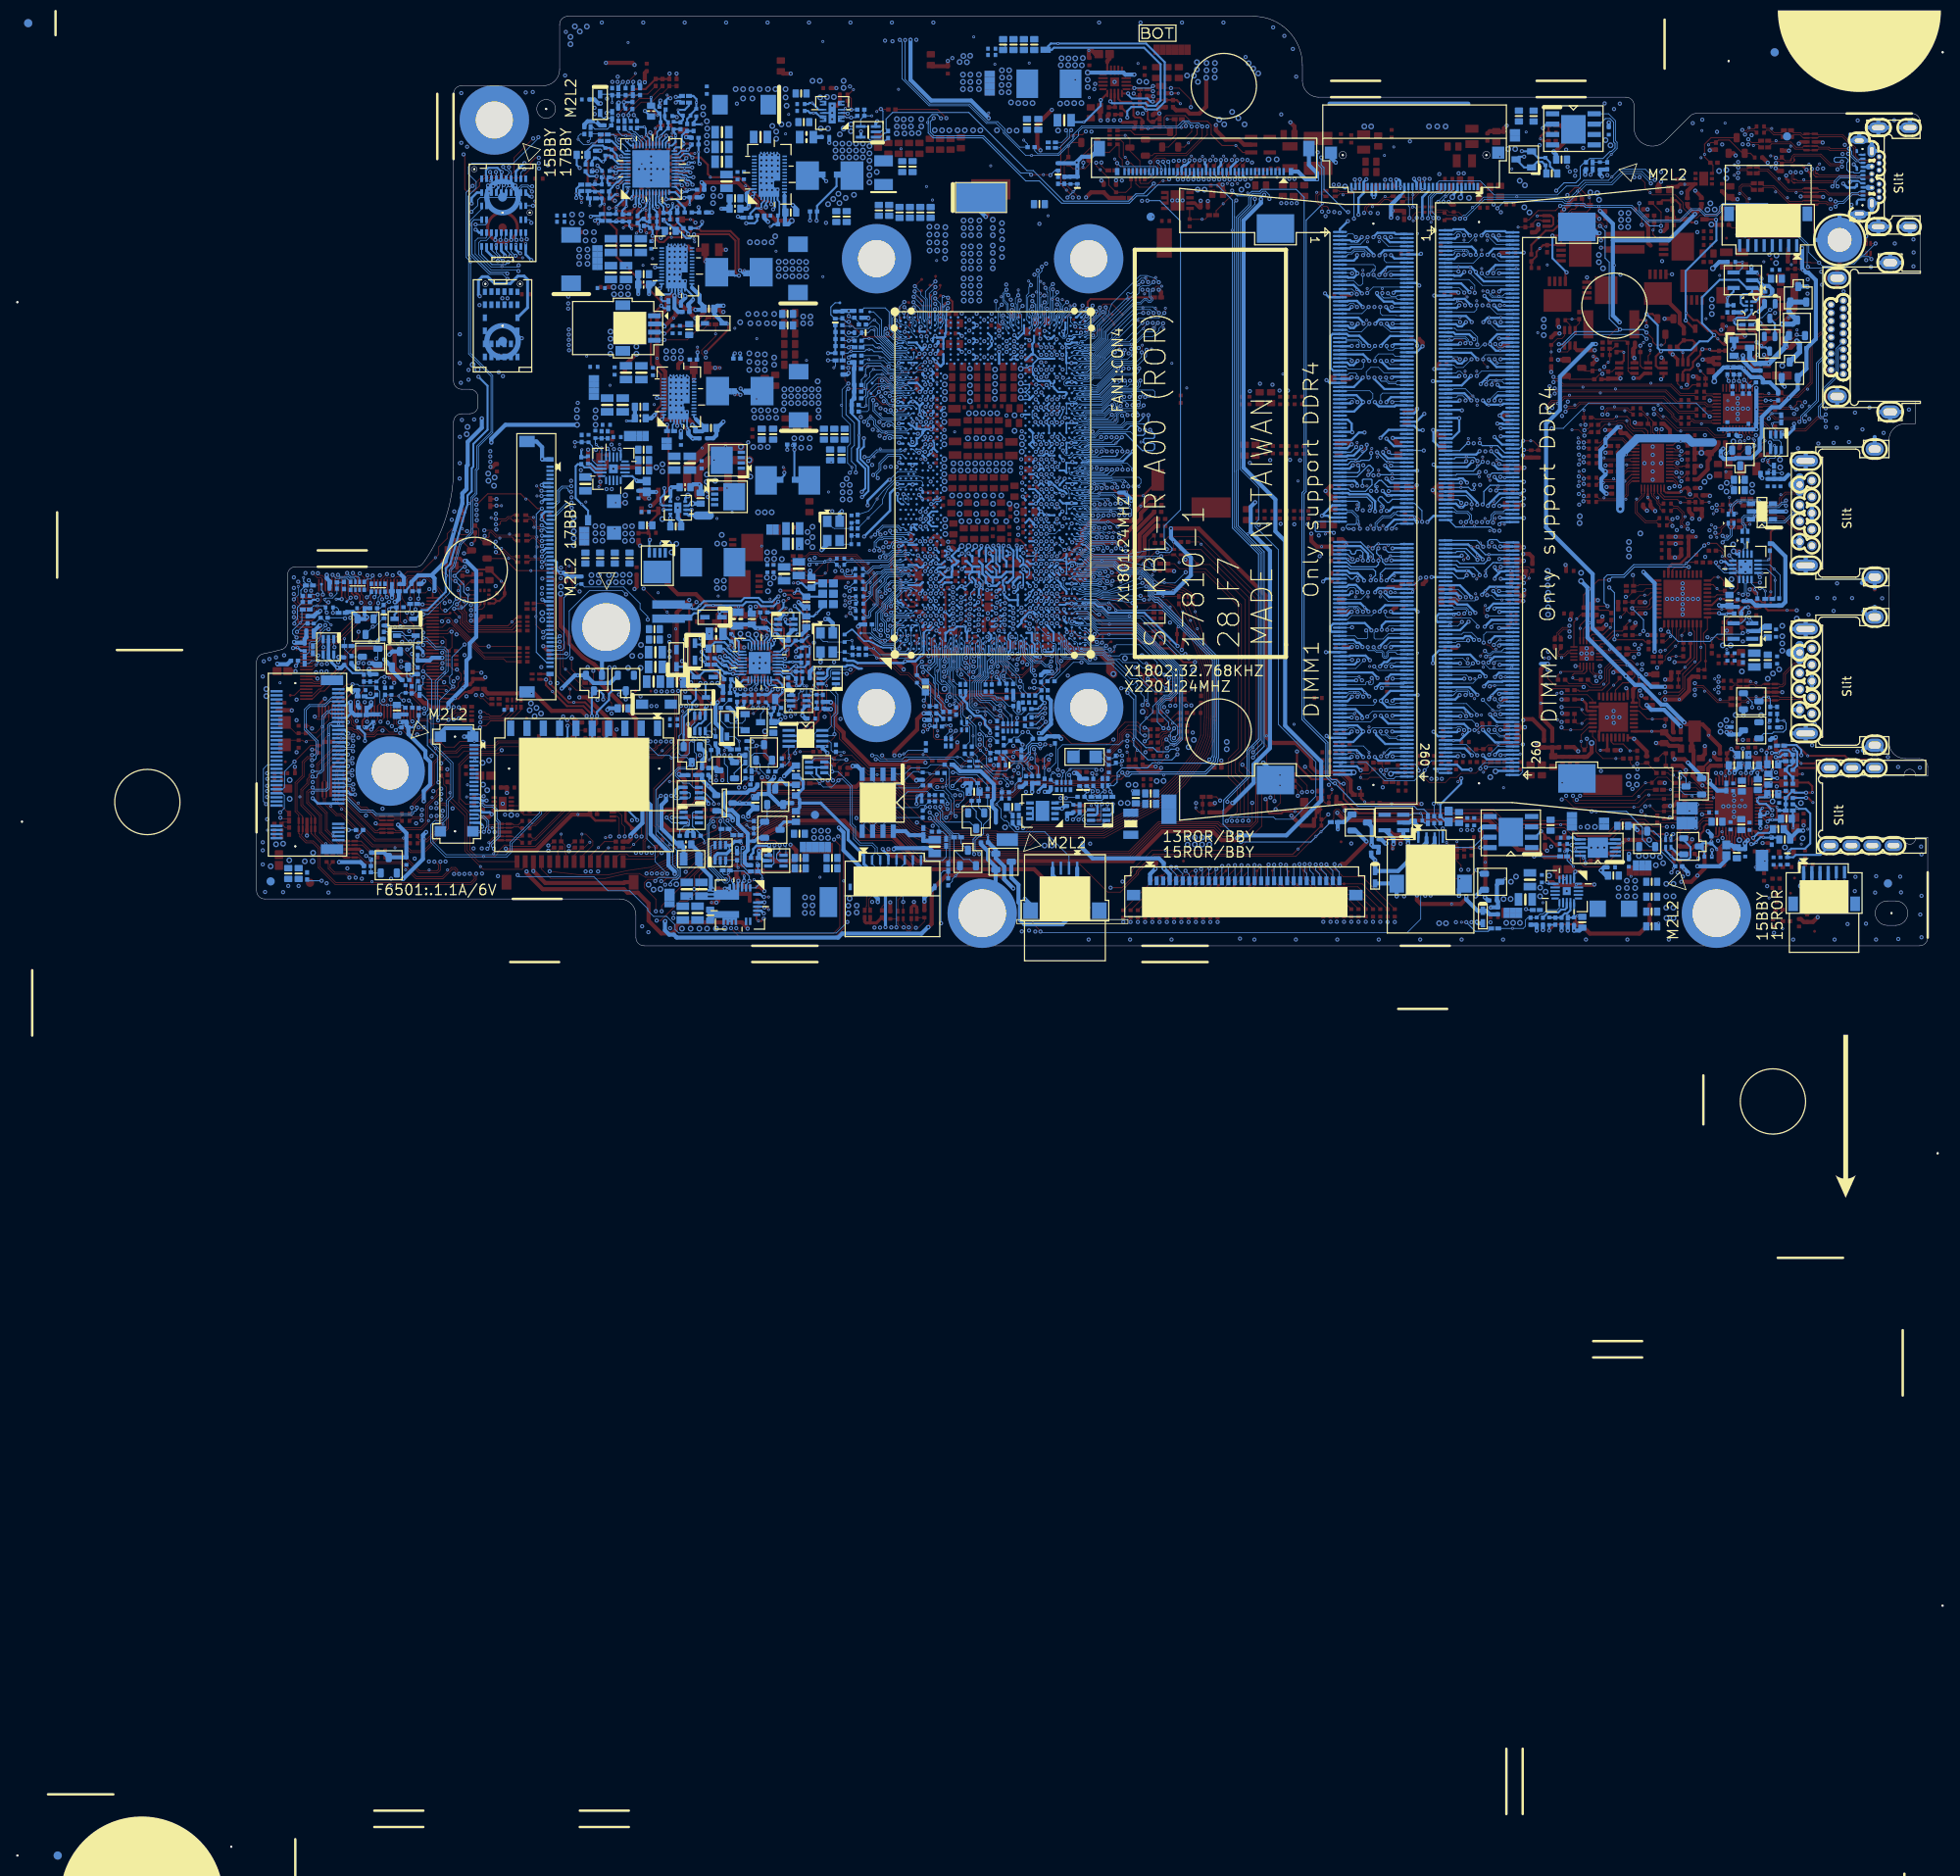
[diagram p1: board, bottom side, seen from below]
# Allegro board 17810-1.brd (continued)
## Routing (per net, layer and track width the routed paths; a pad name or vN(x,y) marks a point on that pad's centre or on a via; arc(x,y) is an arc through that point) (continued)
V0.85A_VID0: length 1.2
  TOP w0.254: TP2101.1 108.98,41.91 v1(109.33,42.26)
  BOTTOM w0.254: v1(109.33,42.26) 109.33,42.35 109,42.68 CPU1.AN11
V0.85A_VID1: length 1.8
  TOP w0.203: v1(108.68,43.15) 108.25,42.71 TP2102.1
  BOTTOM w0.254: v1(108.68,43.15) 108.68,43.43 108.89,43.63 CPU1.AN13
VBUS_PRODECT#: length 5.3
  TOP w0.102: PR4337.1 39.29,88.92 39.29,88.28 v2(39.44,88.13) 39.67,88.13 39.75,88.21 39.75,88.41 40,88.66 40.56,88.66 40.74,88.84 PQ4311.5 41.76,88.84 41.96,88.64 41.96,88.36 41.79,88.19 PQ4311.6
VCC3PD: length 95.8
  TOP w0.254: v1(40.16,90.06) 40.31,90.21 v2(40.31,90.64)
  TOP w0.432: D3702.K 29.46,90.62 v1(28.52,89.68)
  TOP w0.508: v1(40.16,90.06) 40.1,90.01 39.52,90.01 ; R3732.1 v1(30.91,50.13) R3733.1 ; PR4342.1 v1(40.56,71.85) 40.94,72.23 v2(40.99,72.23) ; v1(28.52,89.68) 27.74,90.47 D3701.K
  L3 w0.508: v1(37.77,76.42) 39.55,74.64 39.55,72.86 v1(40.56,71.85)
  L4 w0.508: v1(30.91,50.13) 28.59,50.13 28.09,50.63 28.09,51.1 26.64,52.54 25.73,52.54 23.16,55.11 23.16,58.26 20.37,61.05 20.37,64.48 20.5,64.61 20.5,67.98 20.24,68.23 20.24,69.82 18.72,71.34 18.72,76.55 18.08,77.18 18.08,80.62 20.8,83.34 20.8,87.49 21.23,87.93 22.41,87.93 26.26,91.78 26.97,91.78 28.65,90.11 28.65,89.81 v1(28.52,89.68)
  BOTTOM w0.508: v1(37.77,76.42) 38.59,77.25 38.59,86.45 ; v1(28.52,89.68) 31.75,86.45 38.59,86.45 ; 38.59,86.45 38.59,88.5 v1(40.16,90.06)
VCC_CORE: length 8.2
  TOP w0.152: 123.26,61.94 123.24,61.92 121.81,61.92 C1126.1
  L6 w0.508: v1(111.12,58.61) 111.04,58.7 v1(109.39,58.7)
  BOTTOM w0.152: CPU1.G32 121.75,54.74 121.27,54.74 121.05,54.96
  BOTTOM w0.203: v1(126.29,56.59) CPU1.A34 ; v1(126.29,55.37) 126.29,54.58 125.82,54.11 CPU1.A30
  BOTTOM w0.254: v1(126.11,61.66) 125.99,61.55 CPU1.A44 ; v1(126.08,59.25) 125.9,59.07 CPU1.A39
  vias: v1(109.36,56.87) v1(109.37,55.06) v1(111,56.76) v1(110.97,55.87) v1(111.12,57.93) v2(125.4,60.67) v2(133.15,66.26) v2(134.42,59.27) v2(135.43,82.01) v2(137.44,71.75) v2(143.56,67.02) v3(112.47,59.12) v3(112.47,58.26) v3(113.31,59.12) v3(113.31,58.26) v3(114.07,65.27) v3(114.2,59.12) v3(114.2,58.26) v3(114.6,52.92) v3(114.91,65.27) v3(115.09,59.12) v3(115.09,58.26) v3(115.8,65.27) v3(115.92,59.12) v3(115.92,58.26) v3(116.64,52.92) v3(116.69,65.27) v3(116.76,59.12) v3(116.76,58.26) v3(117.52,65.27) v3(117.65,59.12) v3(117.65,58.26) v3(118.54,59.12) v3(118.54,58.26) v3(118.67,52.92) v3(119.43,59.12) v3(119.43,58.26) v3(120.55,59.63) v3(120.55,58.72) v3(120.55,57.8) v3(120.52,56.91) v3(120.52,55.97) v3(135.96,68.19) v3(135.96,67.35) v3(135.96,66.51) v3(135.96,65.62) v3(135.96,64.79) v3(136.07,69.18) v3(136.8,68.19) v3(136.8,67.35) v3(136.8,66.51) v3(136.96,77.13) v3(136.96,76.29) v3(137.49,83.81) v3(137.49,82.92) v3(137.49,82.03) v3(137.64,68.19) v3(137.64,67.35) v3(137.64,66.51) v3(137.84,77.13) v3(137.84,76.29) v3(138.33,83.84) v3(138.33,82.95) v3(138.33,82.06) v3(138.48,68.19) v3(138.48,67.35) v3(138.48,66.51) v3(139.16,83.84) v3(139.16,82.95) v3(139.16,82.06) v3(139.32,68.19) v3(139.32,67.35) v3(139.32,66.51) v3(140,83.84) v3(140,82.95) v3(140,82.06) v3(140.16,68.19) v3(140.16,67.35) v3(140.16,66.51) v3(140.28,65.68) v3(140.84,83.84) v3(140.84,82.97) v3(140.84,82.08) v3(141.15,64.71) v3(141.22,65.6) v3(142.14,65.62) v3(142.06,64.74) v3(142.95,64.74) v3(143.03,65.62) v3(143.81,64.74) v3(143.89,65.62)
VCC_SENSE: length 86.9
  TOP w0.254: R719.2 v2(123.26,54.8) 123.64,55.18 v1(123.64,55.27)
  L6 w0.254: v1(123.64,55.27) 124.3,55.27 125.11,54.45 128.19,54.45 130.2,56.46 130.2,57.96 131.06,58.82 132.39,58.82 141.33,49.88 144.21,49.88 146.6,52.26 150.41,52.26 151.53,51.15 156.04,51.15 158.16,53.27 158.16,61 161.62,64.46 161.62,69.97 162.99,71.34 162.99,76.22 164.07,77.3 164.07,81.91 162.89,83.1 162.89,87.72 163.4,88.23 163.45,88.23 163.88,88.66 v1(163.88,89.37)
  BOTTOM w0.254: PR4617.1 162.55,89.68 162.78,89.45 163.8,89.45 v1(163.88,89.37) ; CPU1.E32 123.19,54.82 v1(123.64,55.27)
VCCGT_SENSE: length 58.6
  TOP w0.254: R721.2 119.56,77.87 119.56,78.96 119.94,79.34 120,79.34 v1(120.09,79.43)
  L4 w0.254: v1(120.09,79.43) 120.23,79.29 120.49,79.29 120.75,79.55 120.75,81.91 123.49,84.66 123.49,86.76 126.62,89.88 140.54,89.88 140.8,89.63 143.53,89.63 145.34,91.44 145.34,93.34 148.26,96.26 148.26,102.3 148.26,102.61 149.52,103.88 153.29,103.88 v1(153.45,104.04)
  BOTTOM w0.089: CPU1.J70 120.82,76.58 120.82,76.79 120.76,76.92 120.76,77.11 120.76,77.11 120.81,77.24 120.82,77.29 120.82,79.44 v2(120.67,79.59) 120.25,79.59 v1(120.09,79.43)
  BOTTOM w0.254: v1(153.45,104.04) 153.41,104 152.86,104 PR4648.2
VCCPD_VBUS: length 57.2
  TOP w0.508: v1(32.21,31.74) R3730.1
  L4 w0.508: USB1.B4 7.6,95.51
  L4 w0.635: 7.89,92.91 USB1.B9 6.85,92.3
  BOTTOM w0.305: USB1.A9 7.29,95.46 ; USB1.A4 7.32,92.96
  BOTTOM w0.508: v1(32.21,31.74) 33.89,31.74 41.07,38.92 41.07,45.56 46.78,51.27 46.78,63.98 45.08,65.68 45.08,69.77 41.1,73.75 v1(40.69,73.75)
  BOTTOM w0.635: USB1.B9 7.27,92.91 7.32,92.96 ; 7.29,95.46 7.24,95.51 USB1.B4
  vias: v2(27.79,96.59) v3(24.69,95.09) v3(24.69,94.07) v3(25.58,94.96) v3(39.8,83.02) v3(40.28,91.43) v3(40.31,84.67) v3(40.31,83.79) v3(40.51,92.24) v3(41.35,92.35)
VCCRTCEXT: length 16.3
  TOP w0.254: v2(91.87,39.08) 92.02,38.93 C2112.1 92.02,36.82 v1(91.95,36.75)
  BOTTOM w0.254: CPU1.BB10 103.57,42 102.13,42 101.67,41.55 101.19,41.55 100.46,40.81 96.01,40.81 v1(91.95,36.75)
VCCSA_SENSE: length 86.4
  TOP w0.152: v1(121.64,47.74) 122.1,48.2 122.65,48.2 R735.2
  TOP w0.254: v1(165.02,91.66) v2(165.02,91.1)
  L6 w0.254: v1(121.64,47.74) 121.64,47.74 121.02,48.36 121.02,54.92 124.1,58 128.12,58 128.5,58.39 128.5,59.87 129.69,61.05 131.37,61.05 133.65,63.34 140.29,63.34 140.44,63.19 150.82,63.19 151.94,62.07 155.85,62.07 159.46,65.68 159.46,76.18 161.92,78.63 161.92,81.02 160.73,82.21 160.73,88.77 163.49,91.53 164.9,91.53 v1(165.02,91.66)
  BOTTOM w0.254: v1(165.02,91.66) 165.02,91.74 165.28,92 165.28,92.28 PR4607.1 ; v1(121.64,47.74) 121.24,47.35 CPU1.H20
VCCSTG_EN_R: length 3.9
  TOP w0.127: R4017.2 88.59,89.04 v2(88.95,89.04) 90.45,89.04 C4033.1 90.47,90.34 U4002.4
VCCSTU_EN_R: length 3.2
  BOTTOM w0.127: R4024.2 104.67,17.24 C4034.1 105.07,17.63 106.84,17.63 U4006.4
VDD: length 20.1
  TOP w0.254: v1(145.98,32.78) PR4422.1 ; PR4412.1 142.62,38.85 PC4428.1 142.59,38.83 142.28,38.52 v1(142.28,38.02) ; v1(140.26,42.26) 139.95,42.26 v2(139.62,42.59)
  L3 w0.254: v1(145.98,32.78) 145.87,32.88 145.87,34.08 142.29,37.66 142.29,38.01 v1(142.28,38.02)
  L4 w0.254: v1(140.26,42.26) 140.26,41.49 142.28,39.47 v1(142.28,38.02)
  BOTTOM w0.203: PU4401.19 142.58,37.41 142.28,37.7 v1(142.28,38.02)
  BOTTOM w0.254: v1(140.26,42.26) 140.26,41.49 140.89,40.86 PR4471.1
VDDD: length 24.1
  TOP w0.508: R3750.1 R3752.1 ; v1(32.18,30.19) v2(30.45,30.19) 30.33,30.19 29.26,31.26 29.26,32.6 28.88,32.99 28.17,32.99 R3724.1
  L6 w0.508: v1(32.18,30.19) 32.43,30.19 33.81,31.56 33.81,35.04 33.48,35.37 v1(33.48,36.06)
  BOTTOM w0.508: v1(34.85,45.81) 33.48,44.44 v1(33.48,36.06)
VDDIO: length 7.1
  TOP w0.305: U3701.32 31.8,46.32 31.34,46.78 30.36,46.78 29.31,47.83 C3723.1
  TOP w0.457: R3733.2 29.31,50.11 C3722.1 C3721.1 C3723.1
  TOP w0.508: R3733.2 v2(28.4,50.13)
VSS_AY71: length 11
  TOP w0.254: v1(103.03,78.08) 102.97,78.14 102.97,78.91 102.61,79.27 v2(98.04,79.27) 98.01,79.27 97.81,79.47 R602.1
  BOTTOM w0.254: v1(103.03,78.08) 103.03,78.06 103.25,77.83 103.5,77.83 104.31,77.02 CPU1.AY71
VSS_SENSE: length 85.6
  TOP w0.254: v2(162.96,88.48) 163.35,88.87 v1(163.37,88.87) ; v1(123.44,55.97) 123.04,55.57 R720.1
  L6 w0.254: v1(123.44,55.97) 124.13,55.97 125.27,54.83 128.03,54.83 129.82,56.61 129.82,58.12 130.9,59.2 132.55,59.2 141.49,50.26 144.05,50.26 146.44,52.65 146.76,52.65 150.57,52.65 151.69,51.53 155.88,51.53 157.78,53.43 157.78,61.16 161.24,64.61 161.24,70.13 162.61,71.5 162.61,76.37 163.69,77.46 163.69,81.76 162.51,82.94 162.51,87.88 163.37,88.74 v1(163.37,88.87)
  BOTTOM w0.254: CPU1.E33 123.19,55.75 123.42,55.97 v1(123.44,55.97) ; v1(163.37,88.87) 163.17,89.07 162.75,89.07 162.53,88.85 PR4618.1
VSSGT_SENSE: length 57.5
  TOP w0.254: R722.1 120.98,78.19 v2(120.71,78.45) 120.37,78.79 v1(120.09,78.79)
  L4 w0.254: v1(153.45,103.36) 153.38,103.36 153.24,103.5 149.68,103.5 148.64,102.45 148.64,96.1 145.72,93.18 145.72,91.28 143.69,89.25 140.64,89.25 140.38,89.5 126.78,89.5 123.87,86.6 123.87,84.5 121.13,81.75 121.13,79.39 120.65,78.91 120.21,78.91 v1(120.09,78.79)
  BOTTOM w0.089: CPU1.J69 120.81,75.95 120.81,76.14 120.63,76.32 120.63,76.78 120.57,76.9 120.57,77.15 120.63,77.28 120.63,78.25 v1(120.09,78.79)
  BOTTOM w0.254: PR4645.2 152.9,103.55 153.26,103.55 v1(153.45,103.36)
VSSSA_SENSE: length 85.3
  TOP w0.254: v1(165.66,91.66) v2(165.66,92.22) ; v1(121.63,48.65) 121.49,48.8 R734.1
  L6 w0.254: v1(165.66,91.66) 165.66,91.53 165.28,91.15 163.65,91.15 161.11,88.61 161.11,82.36 162.3,81.18 162.3,78.48 159.84,76.02 159.84,65.52 156.01,61.69 151.78,61.69 150.67,62.81 140.28,62.81 140.13,62.96 133.81,62.96 131.53,60.67 129.84,60.67 128.88,59.71 128.88,58.23 128.27,57.62 124.26,57.62 121.4,54.77 121.4,48.89 v1(121.63,48.65)
  BOTTOM w0.254: v1(165.66,91.66) 165.66,92.78 165.15,93.29 PR4604.1 ; CPU1.H21 121.24,48.26 v1(121.63,48.65)
0D6V_PWR:
  vias: v2(36.66,13.06)
0D6V_S0: length 4.1
  BOTTOM w0.279: v3(65.81,21.07) 65.65,21.23 64.15,21.23 DM1.258 ; DM2.258 52.8,21.44 52.86,21.38 v3(52.98,21.38)
  vias: v2(51.99,19.37) v3(40.79,14.57) v3(41.71,14.57) v3(53.62,20.67)
1D0V_PWR: length 5.4
  TOP w0.305: PG5223.2 137.46,9.11
  vias: v2(135.79,8.4) v3(136.7,5.91) v3(136.7,4.94) v3(136.73,4.03) v3(137.62,5.93) v3(137.62,4.94) v3(137.64,4.03)
1D0V_S5: length 69
  TOP w0.508: v1(164.39,28.16) 165.02,28.79 168.67,28.79 170.81,30.93 v2(171.14,30.93) 176.52,30.93 176.99,31.4 R2402.1
  L4 w0.508: v3(120.52,31.49) 121.18,30.83 121.18,26.86 122.32,25.72 122.66,25.39 124.15,25.39 124.99,26.23 124.99,30.29 127.39,32.69 130.61,32.69 132.4,30.9 135.21,30.9 136.2,29.91 137.39,29.91 139.17,28.13 v1(139.34,28.13)
  L6 w0.508: v1(164.39,28.16) 164.39,27.9 164.02,27.52 161.73,27.52 161.45,27.8 151.68,27.8 150.93,27.06 141.18,27.06
  vias: v1(91.34,91.36) v1(91.97,91.36) v1(92.61,91.36) v3(85.93,24.98) v3(85.93,24.1) v3(88.06,13.3) v3(88.06,12.41) v3(88.64,92.68) v3(88.95,13.28) v3(88.95,12.41) v3(89.48,92.68) v3(89.84,13.28) v3(89.84,12.41) v3(90.73,13.28) v3(90.73,12.39) v3(109.55,32.4) v3(134.8,14.09) v3(134.8,13.22) v3(135.65,14.09) v3(135.63,13.22) v3(136.51,14.09) v3(136.51,13.22)
1D0V_S5_PWRGD: length 241.5
  TOP w0.127: v2(145.44,12.56) 145.26,12.39 v1(145.26,12.01) 145.18,12.01 143.41,13.78 142.91,14.28 142.85,14.31 142.77,14.35 142.42,14.53 140.5,15.52 140.24,15.66 138.95,16.32 130.45,16.32 129.98,15.85 129.98,15.3 128.77,14.1 126.47,14.1 126.03,13.66 125.35,12.98 124.28,11.91 124.18,11.81 124.13,11.76 124.06,11.69 115.07,11.69 114.44,11.05 97.74,11.05 94.08,14.71 87.26,14.71 86.38,13.83 v1(85.29,13.83)
  L3 w0.127: v1(158.67,105.88) 156.49,108.07 130.63,108.07 129.73,107.17 123.67,107.17 121.21,104.7 121.21,101.67 v1(120.95,101.41)
  BOTTOM w0.127: v1(85.29,13.83) 86.37,14.91 86.37,16.62 86.29,16.69 86.29,17.84 83.43,20.71 83.43,23.94 82.03,25.34 82.03,48.01 85.23,51.21 85.23,91.38 87.09,93.25 94.4,93.25 95.74,91.91 96.95,91.91 97.85,91.01 106.16,91.01 108.89,93.74 110.56,93.74 115.84,99.03 121.91,99.03 122.52,99.63 122.52,101.39 122.03,101.88 121.42,101.88 v1(120.95,101.41) ; v1(158.67,105.88) 158.72,105.83 R4029.1 ; v1(145.26,12.01) 145.46,11.8 145.46,9.97 144.47,8.98 PR5209.1
1D2V_PWR: length 11.7
  TOP w0.508: PG5113.1 41.4,1.49 35.36,1.49 34.09,2.76 34.09,5.05
  vias: v2(36.37,8.5) v3(35.86,7.97) v3(35.86,7.08) v3(35.86,6.06) v3(36.88,7.97) v3(36.88,7.08) v3(36.88,6.06) v3(37.9,7.08) v3(37.9,6.06)
1D2V_S3: length 213.7
  TOP w0.508: R505.1 86.24,16.35 85.23,17.36 v1(85.23,17.51)
  BOTTOM w0.089: v1(102.16,54.09) 102.63,54.19 CPU1.BB32
  BOTTOM w0.127: CPU1.BB47 103.59,62.85 102.59,62.85 102.44,63.01 v1(102.37,63.01) ; CPU1.BB51 103.44,65.47 101.16,65.47 100.37,66.26 v1(99.97,66.26)
  BOTTOM w0.152: v1(69.87,47.31) 70.25,46.93 70.76,46.93 71.32,47.48 DM1.153
  BOTTOM w0.203: CPU1.BB23 103.59,49.14 103.3,49.14 102.72,48.56 102.34,48.56 v1(102.3,48.52)
  BOTTOM w0.254: CPU1.AU23 106.4,49.95 106.08,49.62 v1(106.08,49.57) ; v1(105.79,57.26) 105.79,57.14 106.4,56.53 CPU1.AU35 ; v1(105.97,59.5) 106.4,59.94 CPU1.AU42 ; CPU1.AU28 106.4,52.9 v1(106.07,53.24) ; v1(109.33,49.57) CPU1.AL23 ; v1(97.45,60.6) 97.48,60.57 97.48,60.53 98.62,59.39 102.86,59.39 102.98,59.27 103.6,59.27 CPU1.BB41
  BOTTOM w0.279: DM1.154 65.73,47.23 v1(65.73,47.24) ; v1(66.31,53.31) 65.99,53.31 65.56,53.73 DM1.136 ; DM1.163 73.78,44.98 v1(74.12,44.64) ; 52.54,45.69 52.34,45.89 51.79,45.89 51.74,45.94 DM2.160 ; 52.54,45.69 53.07,46.22 v1(53.07,46.4) ; 52.54,45.69 53.07,45.16 v1(53.07,44.98) ; v1(62.61,51.93) 62.91,52.23 DM1.142 65.38,52.23 66.37,51.25 v1(66.37,51.1) ; v1(61.9,63.19) 62.41,63.19 62.95,63.73 DM1.96 ; v1(62.58,73.55) 62.58,73.88 62.94,74.23 DM1.54 ; DM1.199 v1(73.77,35.98) ; DM2.241 60.03,25.68 v1(60.58,26.23) ; DM1.141 73.27,52.48 73.49,52.71 v1(74.26,52.71) 72.99,53.98 DM1.135 ; v1(56.48,56.76) 57,57.28 57.45,57.28 57.55,57.19 DM2.123 ; v1(73.88,79.96) 73.4,79.48 DM1.33 ; v1(73.68,25.72) 73.63,25.72 73.4,25.48 DM1.241 ; DM2.220 52.48,30.93 v1(52.54,30.88) ; DM2.96 52.08,63.93 52.14,64 v1(52.75,64) ; v1(61.34,51.93) 60.59,52.68 DM2.141 ; v1(49.49,55.8) 49.86,55.44 DM2.130 52.5,55.44 53.91,54.03 v1(53.91,53.92) ; v1(55.22,54.04) 55.22,54.32 56.58,55.69 59.1,55.69 DM2.129 ; v1(52.55,74.44) 52.55,74.44 DM2.54 ; v1(69.92,56.38) 69.92,56.63 70.28,56.98 DM1.123 ; v1(52.83,60.62) 52.14,59.94 DM2.112 ; v1(70.46,58.89) 70.87,58.48 DM1.117 ; DM1.159 71.17,45.98 70.85,45.67 69.88,45.67 69.09,44.88 v1(69.09,44.76) ; DM2.135 57.82,54.19 57.41,53.78 56.96,53.78 v1(56.54,54.19) ; DM1.111 71.2,59.98 71.09,60.09 70.36,60.09 69.42,61.03 v1(69.42,61.15) ; v1(66.77,60.51) 66.77,60.33 66.17,59.73 DM1.112 ; v1(60.48,79.69) 60.48,79.69 DM2.33 ; DM1.178 62.83,41.23 v1(62.53,40.94) ; DM2.159 59.1,46.19 58.03,46.19 57.78,45.94 56.23,45.94 v1(55.68,45.38) ; v1(62.53,30.73) DM1.220 ; DM2.118 52.66,58.43 53.07,58.85 53.07,58.87 v1(53.25,59.05) ; v1(60.82,45.19) 59.1,45.19 DM2.163 ; DM2.148 50.9,48.93 52.38,48.93 v1(52.39,48.94) ; DM1.124 65.84,56.73 66.17,57.07 66.17,57.07 v1(66.35,57.25) ; v1(60.65,34.64) 60.65,35.44 59.91,36.19 59.1,36.19 DM2.199 ; v1(49.53,84.95) 49.55,84.94 50.9,84.94 DM2.12 ; v1(60.65,69.21) 60.63,69.19 DM2.75 ; DM1.75 73.3,68.98 73.64,69.32 v1(73.7,69.32) ; v1(53.1,57.45) 53.1,57.44 52.59,56.94 DM2.124 49.56,56.94 v1(49.49,56.87) ; DM2.154 52.48,47.44 v1(52.5,47.41) ; v1(66.5,58.85) 66.32,58.67 66.32,58.63 65.93,58.23 DM1.118 v1(62.58,58.23) ; DM2.136 52.47,53.94 v1(52.49,53.92) ; v1(68.6,47.21) 68.6,48.07 69.52,48.98 DM1.147 ; v1(67.74,53.24) 67.74,54.47 68.61,55.34 70.89,55.34 71.04,55.48 DM1.129 ; v1(53.11,41.33) 53,41.44 52.26,41.44 52.25,41.44 DM2.178 ; v1(52.44,52.5) 52.37,52.44 DM2.142 49.51,52.44 v1(49.49,52.42) ; v1(54.56,47.36) 54.56,47.41 56.33,49.19 59.1,49.19 DM2.147 ; v1(60.57,58.98) 60.27,58.68 DM2.117 56.48,58.68 v1(55.82,59.35) ; v1(54.94,60.62) 55.34,60.21 59.07,60.21 DM2.111 ; DM1.130 65.68,55.23 65.71,55.21 66.29,55.21 66.81,55.73 v1(66.81,55.74) ; DM2.153 59.1,47.69 57.26,47.69 v1(57.12,47.83) ; DM1.160 65.37,45.73 v1(66.32,44.78) ; v1(65.61,48.71) 65.58,48.73 DM1.148 ; v1(62.11,84.82) 62.2,84.82 62.29,84.73 DM1.12
  BOTTOM w0.508: v1(85.23,17.51) 85.08,17.51 82.63,19.96 82.63,22.22 80.63,24.22 80.63,48.39 82.99,50.75 82.99,53.81 v1(82.45,54.35)
  vias: v1(52.5,50.87) v1(53.61,55.82) v1(53.92,59.25) v1(54.23,60.6) v1(54.18,58.11) v1(54.63,51.93) v1(54.88,56.48) v1(55.29,51.93) v1(55.65,61.59) v1(57.22,51.93) v1(67.64,44.8) v1(67.94,57.65) v1(68.22,55.74) v1(68.67,51.11) v1(69.19,58.89) v1(69.25,53.37) v1(71.69,51.09) v1(97.2,67.28) v1(97.48,66.26) v1(97.46,65.04) v1(100.04,62.33) v1(99.99,60.6) v2(50.44,83.02) v2(50.98,34.13) v2(62.53,35.88) v2(77.19,56.96) v2(96.44,61.74) v2(104.27,57.95) v3(32.43,10.13) v3(32.82,10.89) v3(33.32,9.87) v3(33.7,11.01) v3(34.57,11.01) v3(35.41,11.01) v3(35.63,20.74) v3(35.66,19.75) v3(36.68,20.77) v3(36.65,19.8) v3(46.53,43.27) v3(46.53,42.38) v3(46.53,41.49) v3(46.53,40.61) v3(46.58,45.94) v3(46.58,45.05) v3(46.58,44.16)
1D2V_VTT_PWRGD: length 221.1
  TOP w0.127: v2(47,35.27) 46.99,35.27 46.98,35.26 v1(46.44,35.26)
  L3 w0.127: v1(119.56,108.8) 119.68,108.93 122.22,108.93 122.36,108.79 129.06,108.79 129.96,109.69 158.42,109.69 162.34,105.77 162.34,103.64 161.95,103.24 v1(161.95,102.07) ; v1(72.08,89.83) 71.74,89.49 70.75,89.49 69.96,90.28 67.28,90.28 66.7,89.7 66.7,89.17 65.77,88.24 57.12,88.24 56.42,87.54 52.07,87.54 50.6,86.07 49.85,86.07 49.58,86.07 48.74,85.23 48.74,37.56 v1(46.44,35.26)
  L4 w0.127: v1(72.08,89.83) 72.3,90.05 72.3,90.12 74.67,92.49 81.52,92.49 81.96,92.04 82.6,92.04 84,90.64 86.16,90.64 87.43,91.91 90.23,91.91 91.43,93.12 93.58,93.12 94.54,94.07 97.2,94.07 98.09,93.18 102.13,93.18 105.78,96.84 105.78,97.56 110.74,102.52 114.42,102.52 115.49,103.59 115.49,107.03 116,107.53 118.92,107.53 119.56,108.17 v1(119.56,108.8) ; v1(49.25,4.49) 49.25,10.76 49.71,11.22 49.71,17.87 46.14,21.44 46.14,34.96 v1(46.44,35.26)
  BOTTOM w0.127: v1(49.25,4.49) 49.15,4.39 PR5107.1 ; R4011.1 161.82,102.2 v1(161.95,102.07)
1D5V_PWR: length 5.1
  TOP w0.508: v2(65.58,11.9) 65.58,12.36 v1(65.48,12.46) 65.38,12.56 PG5404.1 66.06,14.14 PC5409.1
  BOTTOM w0.508: PU5402.5 66.51,14.15 65.48,13.12 v1(65.48,12.46)
1D5V_S0: length 126.8
  TOP w0.508: v1(62.05,17.39) v2(65.71,17.39) 67.08,17.39 R2102.1 ; R2705.1 25.83,22.83 26.17,23.17 v1(26.17,23.61) ; PG5404.2 64.62,13.3 v1(64.62,12.51)
  L3 w0.508: v1(57.83,2.89) 56.95,2 49.45,2 48.82,2.63 46.28,2.63 43.23,5.68 43.23,7.71 42.47,8.47 39.44,8.47 38.83,9.08 32.43,9.08 31.67,9.85 31.67,11.87 29.28,14.26 29.28,20 26.17,23.11 v1(26.17,23.61) 26.17,27.56 21.28,32.45 21.28,34.34 20.55,35.07 20.55,38.88 18.34,41.09 18.34,44.78 19.38,45.83 19.38,49.33 21.41,51.37 21.41,54.45 20.6,55.26 20.6,56.66 21.21,57.27 21.21,59.73 20.17,60.76 20.17,63 18.57,64.61 18.57,70.35 v3(17.83,71.09)
  L4 w0.508: v1(62.05,17.39) 64.62,14.82 v1(64.62,12.51) 64.62,11.47 57.83,4.69 v1(57.83,2.89)
1D5V_VDD: length 11.7
  TOP w0.203: 21.59,69.23 21.89,68.93 U5701.19 ; U5701.40 v1(25.6,63.3) ; U5701.31 v1(21,63.3)
  BOTTOM w0.508: v1(25.6,63.3) 24.6,63.3 C5704.2 24.52,63.3 v1(21,63.3) 21.05,63.35 C5716.2 21,64.02 v2(21,65.75) v1(21,68.37)
1D8V_EN#: length 3.5
  BOTTOM w0.127: Q2701.D 20.18,30.47 v2(19.51,30.47) 19.3,30.27 R2726.2 R2727.1
1D8V_EN_R#: length 6.6
  BOTTOM w0.127: Q2702.G 20.1,26.01 19.07,26.01 18.89,26.19 17.69,26.19 17.36,26.53 17.36,27.31 v2(17.65,27.6) C2714.2 18.46,27.63 R2727.2
1D8V_ESPI: length 4.6
  TOP w0.102: R6802.1 162.21,12.77 v2(162.94,12.03) 163.92,11.06 DB1.10
1D8V_PWR: length 1.6
  TOP w0.508: v1(44.58,13.91) 44.5,13.83 PC5405.1 44.52,13.22 PR5403.1
  vias: v2(44.98,14.82)
1D8V_S0: length 216.2
  TOP w0.254: v1(178.48,49.24) 178.05,49.67 R6120.1
  TOP w0.508: v1(24.66,26.18) v2(24.1,26.18) ; v1(26.69,20.21) 26.74,20.26 26.74,20.27 26.92,20.45 26.92,21.73 26.59,22.06 R2713.1
  L3 w0.254: v1(111.05,1.76) 110.52,1.24 104.95,1.24 104.8,1.39 84.09,1.39 84.06,1.36 31.29,1.36 29.79,2.86 29.79,4.92 28.88,5.83 28.88,12.16 28.29,12.74 28.29,17.97 26.69,19.58 v1(26.69,20.21)
  L4 w0.254: v1(111.05,1.76) 112.01,2.72 112.01,5.19 114.41,7.58 118.19,7.58 119.72,6.06 130.31,6.06 132.68,8.42 143.13,8.42 144.56,9.85 149.86,9.85 151.48,11.47 152.4,11.47 154.62,13.69 156.16,13.69 157.88,15.41 v1(158.19,15.41) ; v1(178.48,49.24) 178,48.76 178,45.39 177.11,44.5 177.11,43.81 176.07,42.77 176.07,40.05 173.42,37.4 173.42,34.93 167.84,29.34 167.84,27.97 166.84,26.97 v1(166.72,26.97)
  L6 w0.508: v1(26.69,20.21) 26.69,20.26 26.97,20.54 26.97,21.73 25.53,23.18 25.53,24.13 24.66,24.99 v1(24.66,26.18)
  BOTTOM w0.254: v1(166.72,26.97) 166.72,25.54 166.85,25.42 166.85,24.13 158.19,15.47 v1(158.19,15.41)
  BOTTOM w0.508: v1(24.66,26.18) 24.38,25.9 C2721.1 23.1,25.9 Q2702.D ; v1(26.69,20.21) 26.69,19.93 25.78,19.02 R2724.1
1D8V_S5_PWROK: length 311.1
  TOP w0.127: KBC24.30 199.51,41.84 199.79,42.13 199.79,42.64 v1(200.28,43.12) ; v1(179.47,96.99) 179.32,96.84 179.32,92.73 179.07,92.47 178.18,92.47 177.52,93.13 177.52,93.49 176.9,94.11 172.41,94.11 171.27,95.26 171.27,95.99 170.67,96.59 v1(170.25,96.59) ; v2(58.82,10.96) PR5408.1 59.74,10.51 v1(60.25,10)
  L3 w0.127: v1(159.94,105.88) 157.28,108.55 130.43,108.55 129.53,107.65 123.46,107.65 118.26,102.45 114.02,102.45 112.69,101.12 103.12,101.12 102.08,102.16 99.57,102.16 98.7,103.03 94.81,103.03 94.41,103.43 94.41,104.87 93.3,105.97 92.11,105.97 90.98,104.84 85.12,104.84 79.14,98.86 78.77,98.86 78.77,98.86 77.68,98.86 76.06,97.25 v1(74.77,97.25) ; v1(179.47,96.99) 179.87,96.6 179.87,78.92 179.47,78.53 179.47,73.5 177.14,71.16 177.14,69.08 176.3,68.24 176.3,63.96 178.99,61.27 178.99,57.21 179.03,57.11 179.06,56.99 179.36,56.05 179.42,55.86 179.67,55.07 179.67,51.83 180.2,51.3 180.2,50.69 180.81,50.07 181,49.58 181,49.47 181.03,49.41 181.16,49.27 181.16,47.89 183.45,45.6 184.32,45.6 184.37,45.55 184.44,45.52 184.68,45.4 184.84,45.32 184.88,45.28 186.41,45.28 187.24,44.45 196.98,44.45 197.76,45.24 198.63,45.24 198.89,44.98 198.89,44.81 199.83,43.87 199.83,43.57 v1(200.28,43.12)
  L4 w0.127: v1(60.93,6.16) 60.93,6.5 68.56,14.13 68.56,16.16 71.6,19.2 v1(71.6,19.85)
  L6 w0.127: v1(170.25,96.59) 170.04,96.8 167.65,96.8 164.96,99.5 164.96,101.88 164.58,102.26 164.58,103.33 162.6,105.31 160.51,105.31 v1(159.94,105.88)
  BOTTOM w0.127: v1(159.94,105.88) 160.5,105.33 R4030.1 ; v1(60.25,10) 60.93,9.31 v1(60.93,6.16) ; v1(74.77,97.25) 74.79,97.23 74.79,95.8 74.28,95.29 74.28,90.83 76.19,88.93 76.19,55.67 76.45,55.41 76.45,27.85 73.53,24.93 73.53,20.84 73.04,20.35 72.48,20.35 71.99,19.85 v1(71.6,19.85)
2D5V_S3: length 5
  BOTTOM w0.279: DM2.257 60.52,21.69 ; DM1.259 70.62,20.98 v3(70.36,21.25) 70.59,21.48 DM1.257
  vias: v1(59.56,20.46) v1(60.2,20.46) v1(60.83,20.46) v2(60.12,21.4) v2(71.96,22.24) v3(50.57,97.65) v3(51.41,97.65)
3D3V_AUX_S5: length 260.4
  TOP w0.508: v1(162.02,108.22) 158.77,108.22 v1(158.52,107.97) ; v1(151.81,42.38) 153.34,40.86 153.34,33.11 v2(152.84,32.61) 150.32,30.09 150.32,28.46 151.61,27.17 v1(151.94,27.17) 152.04,27.07 152.04,23.58 153.07,22.55 v1(153.07,21.03) 152.38,20.34 152.37,20.34 R1737.1 152.37,17.54 153.22,16.69 154.65,16.69 155.22,16.12 155.22,15.18 154.2,14.16 v1(151.66,14.16) ; PR4505.1 161.95,58.67 162.15,58.46 PG4532.2 163.55,58.46 164.21,59.12 v1(164.21,60.8) ; PR4503.1 95.64,104.11 v1(94.94,104.11)
  L3 w0.508: v1(162.02,108.22) 163.16,108.22 164.23,107.14 164.23,104.36 165.28,103.32 165.28,101.06 168.76,97.58 168.76,96.07 v1(169.15,95.67) ; v1(158.52,107.97) 157.49,108.99 130.24,108.99 129.35,108.09 123.27,108.09 119.03,103.85 114.79,103.85 112.5,101.57 103.31,101.57 102.27,102.61 99.75,102.61 98.53,103.83 96.16,103.83 95.88,104.11 v1(94.94,104.11)
  L4 w0.508: v1(164.21,60.8) 162.94,62.07 159.46,62.07 158.27,60.88 158.27,52.39 157.3,51.43 157.3,49.48 157.2,49.38 157.2,47.77 v1(151.81,42.38)
  L6 w0.508: v1(187.5,14.82) 188.34,14.82 190.04,16.53 190.04,17.06 189.1,18 187.76,18 182.42,23.33 179.95,23.33 177.54,25.75 162.61,25.75 161.99,26.37 161.19,27.17 v1(151.94,27.17) ; v1(169.15,95.67) 169.44,95.38 169.44,85.77 v1(171.17,84.04) 171.17,83.35 169.49,81.68 169.49,79.36 167.11,76.98 166.75,76.98 166.75,76.98 166.22,76.98 165.02,75.79 165.02,71.97 167.1,69.89 167.1,61.79 166.12,60.8 v1(164.21,60.8)
  BOTTOM w0.305: GPU1.F1 171.85,84.73 v1(171.17,84.04)
  BOTTOM w0.508: R1726.2 151.28,13.83 151.61,14.16 v1(151.66,14.16) 151.79,14.16 152.09,13.86 R1727.1 ; v1(187.5,14.82) 186.49,13.81 C2415.1 188.63,10.84 Q2417.D 189.24,11.42 R2463.1 ; v1(153.07,21.03) 152.95,20.91 R2510.1
3D3V_CAMERA_S0: length 1.6
  BOTTOM w0.305: TCBD1.6 57.65,92.56 58.11,92.09 58.11,91.91 v3(58.27,91.76)
  vias: v2(59.08,91.86)
3D3V_GSEN2: length 11
  TOP w0.254: 175.41,42.26 175.72,41.96 U7001.10 ; 175.41,42.26 175.67,42.52 U7001.9 ; 175.41,42.26 175.11,42.26 174.45,42.92 C7003.1 174.45,44.26 v2(174.86,44.68) C7004.1 177.67,46.12 R7005.1 178.43,45.36 R7006.2
3D3V_MUX: length 83.9
  TOP w0.203: 31.86,55.54 32.1,55.54 32.3,55.74 U3801.1 ; U3801.6 34.3,55.34 ; 36.37,61.62 36.09,61.35 U3801.20 ; 41.62,38.56 41.81,38.37 U3802.13
  TOP w0.305: 34.3,55.34 v2(34.3,54.96) 34.3,54.85 33.97,54.51 C3818.1 ; C3815.1 29.84,56.1 v2(30.25,55.69) 30.4,55.54 31.86,55.54
  TOP w0.406: v1(39.37,55.42) 39.36,55.41 R3845.1
  TOP w0.457: 31.24,62.35 31.6,62.7 31.6,63.23 32.33,63.97 32.33,63.97 R3801.1
  TOP w0.508: v3(27.74,60.41) 27.74,60.42 C3820.1 ; v3(27.74,60.41) 27.72,60.39 C3819.1 ; v3(27.74,60.41) 27.93,60.41 27.94,60.42 R3821.1 ; v1(29.13,55.34) 29.26,55.46 29.26,55.9 C3815.1 ; 31.24,62.35 31.14,62.45 29.59,62.45 C3816.1 29.46,62.4 28.57,61.51 R3818.1 R3821.1 ; R3821.1 R3840.1 ; R3842.1 28.19,57.17 26.97,58.39 26.97,59.4 26.72,59.66 C3819.1 ; C3819.1 26.49,60.39 25.83,61.05 25.83,61.24 25.68,61.39 L3801.2 ; v1(33.4,53.28) 33.97,53.85 C3818.1 ; v1(39.5,58.16) 39.47,58.13 R3871.1 ; R3874.1 v1(39.5,61.26) ; 41.62,38.56 41.35,38.83 C3865.1 39.9,38.83 v1(39.39,39.34) ; v1(37.67,63.57) 37.67,62.93 C3817.1 37.01,62.83 36.37,62.2 36.37,61.62 ; v1(27.99,52.29) 27.68,52.59 R3847.1 R3852.1
  L3 w0.508: v1(39.37,55.42) 38.68,54.74 38.68,53.26 37.72,52.29 36.98,52.29 v3(35.23,50.54) 35.23,46.57 35.51,46.3 35.51,43.27 36.18,42.6 36.18,42.55 v1(39.39,39.34)
  L4 w0.508: v3(27.74,60.41) 28.2,60.41 28.88,59.73 28.88,55.59 v1(29.13,55.34) ; v1(29.13,55.34) 30.02,54.45 32.23,54.45 v1(33.4,53.28) 33.4,51.83 34.69,50.54 v3(35.23,50.54) ; v1(29.13,55.34) 27.99,54.19 v1(27.99,52.29)
  BOTTOM w0.508: 39.5,58.14 39.5,57.75 40,57.24 40,55.96 39.46,55.42 v1(39.37,55.42) ; 39.5,58.14 39.67,58.14 40.13,58.61 40.13,60.71 39.58,61.26 v1(39.5,61.26) 39.5,62.09 38.02,63.57 v1(37.67,63.57) ; 39.5,58.14 v1(39.5,58.16)
3D3V_RTC_SYS: length 4
  BOTTOM w0.508: R2510.2 151.05,20.92 R2517.1 150.26,20.39 v2(149.45,19.57) 148.5,18.62 D2501.1
3D3V_S0: length 401.2
  TOP w0.406: R5413.1 23.82,61.1 v3(23.82,61.81)
  TOP w0.508: v1(131.11,39.13) 130.96,38.98 130.96,37.8 128.24,35.08 126.73,35.08 v1(125.53,33.87) ; R2045.1 120.42,22.7 118.95,24.17 v1(118.95,24.93) ; R2710.1 25.47,24.43 v2(26.85,25.8) 26.85,26.38 27.61,27.14 R2731.1 29.61,27.14 v1(29.84,27.37) 30.25,27.78 R9120.2 31.24,26.25 R9145.1 ; C1228.1 R1204.2 R1208.2 69.37,21.63 v1(69.49,21.51) ; R9141.2 36.62,33.42 36.98,33.05 v1(37.01,33.05) ; 141.43,22.27 142.52,23.36 v3(142.52,26.28) ; R9102.1 47.04,26.38 48.44,27.78 49.45,27.78 v1(49.58,27.65) ; v1(61.49,45.15) 61.49,44.72 R1211.2 ; v1(107.36,102.45) 109.14,100.68 109.14,97.88 v1(108.76,97.5) ; v1(178.56,39.84) 177.65,39.84 R7004.1 ; R6802.2 159.28,12.77 159,13.05 v1(159,13.4) ; v1(49.58,48.02) 48.84,48.02 48.46,47.64 R1310.2 ; v1(160.96,25.21) 160.96,25.86 161.34,26.25 161.34,27.41 164.37,30.45 v1(165.28,30.45)
  L3 w0.508: v1(29.39,8.77) 29.39,6.04 30.3,5.13 30.3,3.07 31.5,1.87 42.21,1.87 42.85,2.51 43.74,2.51 44.12,2.12 v1(44.12,1.87) ; v1(159,13.4) 159,13.61 158.33,14.29 152.9,14.29 152.39,14.8 151.18,14.8 150.32,13.94 147.74,13.94 145.97,12.17 v1(145.97,12.01) ; v1(61.49,45.15) 61.49,45.41 58.44,48.46 55.88,48.46 55.52,48.1 49.66,48.1 v1(49.58,48.02)
  L3 w1.016: 24.56,62.96 24.56,64.48 25.7,65.62 25.7,68.72 v3(26.16,69.18)
  L4 w0.508: v1(163.27,101.06) 162.99,101.06 162.61,101.44 162.61,102.38 161.8,103.19 161.52,103.19 160.45,104.26 155.27,104.26 154.63,104.89 149.07,104.89 146.4,102.23 138.3,102.23 136.55,103.98 v3(135.76,103.98) ; v1(135.22,28.06) 133.53,28.06 v1(133.27,27.8) ; v1(29.39,8.77) 30.15,9.53 30.15,19.28 27.86,21.57 27.86,23.21 29.56,24.91 29.56,27.09 v1(29.84,27.37) ; v3(169.82,39.95) 170.43,39.34 170.43,35.6 v1(165.28,30.45) ; v1(189.17,35.08) 189.23,35.14 189.23,35.58 190.04,36.39 v1(190.04,37.29) 189.96,37.37 189.96,38.44 188.63,39.77 v1(186.64,39.77) ; v1(92.89,39.62) 77.75,24.48 76.93,24.48 74.78,22.32 69.06,22.32
  L6 w0.508: v1(49.58,48.02) 44.8,48.02 v3(42.49,45.71) ; v1(111.43,28.79) 110.51,27.88 110.51,27.6 v1(108.96,26.05) ; v1(160.96,25.21) 160.96,25.29 159.83,26.42 142.66,26.42 v3(142.52,26.28) ; v1(203.55,19.6) 203.49,19.6 202.87,20.23 202.87,21.43 203.76,22.32 203.76,29.05 202.61,30.19 202.61,33.23 198.61,37.23 193.41,37.23 192.37,36.19 190.25,36.19 189.53,35.47 189.53,35.45 v1(189.17,35.08) ; v1(203.55,18.23) 202.92,17.59 202.92,14.98 203.2,14.7 203.2,9.82 v3(203.12,9.74)
  BOTTOM w0.254: 120.74,27.84 121.38,28.49 R2609.1
  BOTTOM w0.279: DM1.255 69.97,21.98 v1(69.49,21.51) ; DM2.255 57.68,22.19 57.08,21.58 v1(56.03,21.58)
  BOTTOM w0.305: v1(172.34,74.46) 172.46,74.46 172.87,74.86 GPU2.P3 ; 118.18,30.37 118.18,30.13 117.73,29.68 117.73,29.11 116.81,28.18 116.11,28.18 115.54,27.62 115.54,27.09 114.93,26.48 v1(114.93,26.08) ; 118.18,30.37 117.93,30.63 RN2008.4 ; 118.18,30.37 118.34,30.37 118.6,30.63 RN2008.3 ; Q1801.5 101.98,16.02 101.78,16.22 101.78,17.24 v1(101.9,17.36) ; v1(99.9,17.36) 99.87,17.34 99.87,16.38 100.23,16.02 Q1801.2 ; 130.66,33.98 131.07,33.98 131.81,34.38 132.47,34.38 132.63,34.22 134.51,34.22 134.89,33.84 134.89,33.1 135.23,32.76 Q2601.5
  BOTTOM w0.356: v1(109.02,18.86) 109.02,18.99 108.41,19.6 R2043.1
  BOTTOM w0.508: R2044.1 112.09,31.21 R2005.1 ; R4005.1 162.76,100.55 v1(163.27,101.06) 164.27,101.06 164.67,100.66 PR4614.1 ; v1(140.18,20.79) 138.89,22.09 R6502.1 ; v1(37.01,33.05) 36.98,33.05 ; 36.98,33.05 41.71,37.78 41.71,43.91 v3(42.49,44.7) ; 36.98,33.05 35.9,31.97 35.07,31.97 32.65,29.56 32.03,29.56 v1(29.84,27.37) ; v1(108.96,26.05) 108.6,26.05 107.47,27.19 107.47,27.71 107.49,27.73 107.49,30.06 R2055.1 ; v1(131.11,39.13) 130.86,39.39 R1503.1 ; v1(190.04,37.29) 189.72,37.61 R2429.2 ; R2489.2 187.11,32.58 188.22,33.68 188.22,34.13 Q2414.G 189.17,35.08 v1(189.17,35.08) ; R5420.1 18.34,68.04 19.35,69.05 R5411.1 20.19,69.38 20.5,69.69 21.64,69.69 22.83,70.88 R5415.1 R5417.1 R5419.1 25.02,70.88 26.16,69.74 v3(26.16,69.18) ; 111.43,29.81 v1(111.43,28.79) ; PR5102.2 v1(44.12,1.87) ; v1(29.39,8.77) 29.39,8.98 30.1,9.69 R506.1 ; R7018.1 v1(145.97,12.01) ; v1(160.96,25.21) 160.96,23.56 158.47,21.07 158.47,17.7 157.55,16.79 157.55,15.04 159,13.59 v1(159,13.4)
  BOTTOM w1.016: 26.34,61.69 28.88,61.69 29.39,62.2 35.61,62.2 37.69,60.11 v3(37.69,53.53)
  vias: v1(56.87,94.68) v1(57.5,94.68) v1(96.21,102) v1(96.85,102.05) v1(174.65,69.82) v1(175.16,70.3) v1(177.52,78.53) v1(203.55,18.97) v3(79.81,96.38) v3(80.8,96.38) v3(84.5,101.44) v3(85.27,102.2) v3(134.08,104.03) v3(134.92,104.03) v3(169.82,40.78) v3(177.75,70.63) v3(178.36,71.21)
3D3V_S0_ON: length 5
  TOP w0.127: v1(131.95,102.47) 131.95,103.85 C4011.1 132.3,104.33 v2(131.69,104.94)
  BOTTOM w0.127: U4001.5 v1(131.95,102.47) 131.22,102.47 R4014.2
3D3V_S5: length 348.2
  TOP w0.305: v1(7.54,86.96) 7.51,86.93 GMR1.3
  TOP w0.406: Q2416.5 180.95,47.49 ; 180.95,47.49 179.93,47.49 179.6,47.16 v1(179.32,47.16) ; 180.95,47.49 Q2416.2
  TOP w0.457: D3701.A 27.74,91.79 v1(28.5,92.55)
  TOP w0.508: v1(58.85,9.31) 62.48,9.31 v2(63.42,10.25) 63.7,10.53 v1(63.7,12.56) ; v1(15.39,85.51) 15.49,85.41 R7011.2 16.18,84.65 C7002.1 16.25,84.62 R7001.2 ; v1(46.58,34.56) 46.77,34.56 47.42,33.91 v2(47.42,29.73) 47.42,28.03 46.02,26.64 R9101.1 ; v1(25.07,60.93) 24.81,61.18 L3801.1 ; R3738.1 26.64,97.58 v1(26.72,97.5) ; v1(34.45,29.49) 34.44,29.51 R9143.1 ; v1(30.28,26.89) R9146.1 ; 192.93,36.01 192.4,36.54 188.53,36.54 187.93,35.95 187.93,34.09 187.05,33.21 v1(185.88,33.21) 185.88,31.27 184.34,29.73 184.03,29.73 183.52,29.23 v1(181.33,29.23) ; v1(134.44,29.82) 134.36,29.82 133.81,29.27 133.81,28.6 133.91,28.5 133.91,27.15 132.89,26.13 132.89,25.49 129.62,22.22 125.65,22.22 125.25,22.62 R1913.1 123.04,22.62 v1(122.86,22.44) ; v1(147.75,20.29) 147.75,21.12 148.26,21.63 148.26,23.26 v1(148.16,23.36)
  L3 w0.508: v1(130.76,99.81) 130.76,103.37 132.11,104.73 v1(132.11,105.33) ; v1(20.42,81.12) 19.78,81.12 v1(15.39,85.51) ; v3(108.25,12.28) 113.16,12.28 113.97,13.1 113.97,15.03 111.73,17.26 106.98,17.26 106.3,17.95 v1(106.3,18.1)
  L4 w0.508: v1(174.39,16.07) 175.11,16.78 176.54,16.78 180.84,21.08 180.84,21.89 181.95,23.01 182.24,23.01 183.13,23.9 184.06,23.9 186.38,26.22 186.38,27.88 185.32,28.95 185.32,32.66 v1(185.88,33.21) ; v1(28.5,92.55) 27.86,93.18 25.6,93.18 24.59,92.17 22.27,92.17 15.62,85.51 v1(15.39,85.51) 15.39,85.35 15.05,85.01 13.03,85.01 12.18,84.16 9.84,84.16 8.3,85.69 8.3,86.2 v1(7.54,86.96) ; v1(176.07,61.69) 177.09,61.69 178.87,59.91 178.87,51.89 179.68,51.08 179.68,49.32 178.79,48.43 178.79,47.69 v1(179.32,47.16)
  L6 w0.508: v1(147.75,20.29) 147.75,20.12 148.29,19.59 150.89,19.59 152.73,17.75 166.88,17.75 168.02,16.6 171.41,16.6 172.72,15.29 173.94,15.29 174.39,15.75 v1(174.39,16.07) ; v1(34.45,29.49) 35.14,29.49 36.32,30.67 36.32,33.3 40.12,37.1 43.31,37.1 45.85,34.56 v1(46.58,34.56) ; 41.22,95.7 39.61,95.7 37.1,93.18 36.12,93.18 29.44,86.5 28.12,86.5 27.43,87.19 27.43,89.6 27.74,89.91 27.74,89.91 28.5,90.67 v1(28.5,92.55) 27.48,93.56 27.48,96.74 v1(26.72,97.5)
  BOTTOM w0.305: v1(20.42,81.12) 20.5,81.12 20.95,81.58 U4302.2 ; PU4307.6 21.11,78.95 20.5,79.57 19.48,79.57 19.07,79.98 PR4335.1
  BOTTOM w0.356: U4003.5 130.76,99.14 v1(130.76,99.81)
  BOTTOM w0.381: Q6502.S 143.38,13.23 143.8,12.82 C6502.1 144.6,12.82 EC8912.1 ; R2050.2 148.59,24.46 148.26,24.13 R2001.1
  BOTTOM w0.508: R2434.1 201.06,34.51 202.26,34.51 v1(202.31,34.56) ; v1(134.44,29.82) 134.5,29.89 PR4450.2 ; PR5208.1 144.7,9.87 145.02,10.19 145.02,11.35 144.63,11.74 EC8912.1 144.63,13.73 145.85,14.95 145.85,15.88 146.59,16.63 147.12,16.63 147.6,17.11 147.6,18.53 147.37,18.76 144.74,18.76 144.4,19.1 143.9,19.1 143.46,19.54 R2607.1 ; PR4335.1 19.07,80.46 19.48,80.86 20.17,80.86 v1(20.42,81.12) ; v1(41.98,94.5) 41.98,95.06 PR5410.1 ; v1(25.07,60.93) 25.37,60.63 25.37,60.05 24.99,59.68 23.65,59.68 23.54,59.78 21.58,59.78 20.6,60.77 20.6,62.14 20.34,62.39 20.34,64.79 19.13,66.01 18.13,66.01 17.02,67.12 v2(17.02,67.15) 15.93,68.23 PD4302.2 14.86,70.72 PR4304.1 13.71,74.36 13.71,81.59 14.64,82.52 14.89,82.52 15.39,83.01 v1(15.39,85.51) ; v1(185.88,33.21) 185.72,33.21 185.65,33.29 R2442.1 ; v1(30.28,26.89) 32.31,28.92 33.88,28.92 v1(34.45,29.49) ; PU5402.1 64.29,13.55 63.7,12.97 v1(63.7,12.56) ; v1(192.38,33.93) 192.63,33.93 193.22,34.51 R2496.2 ; v3(165.56,63.85) 174.35,63.85 176.07,62.13 v1(176.07,61.69) ; v1(148.16,23.36) 148.26,23.46 R2001.1 ; v1(179.32,47.16) 179.14,47.16 177.93,45.95 177.93,37.86 178.71,37.07 178.71,35.37 179.12,34.96 179.12,31.97 181.33,29.76 v1(181.33,29.23) ; 47.42,34.56 v1(46.58,34.56)
  vias: v1(43.23,94.38) v1(43.86,94.89) v1(44.14,95.47) v1(72.19,93.29) v1(72.82,93.29) v1(160.58,106.52) v1(160.6,105.88) v1(161.24,105.88) v2(50.37,91.81) v2(164.49,54.4) v2(201.98,32.22) v3(48.82,89.88) v3(49.45,90.52) v3(59.05,2.76) v3(59.89,2.76) v3(71.42,93.06) v3(83.74,100.68) v3(106.35,3.55) v3(107.21,3.52) v3(107.36,12.28) v3(132.89,106.01) v3(132.89,105.15) v3(165.58,65.68) v3(165.58,64.76) v3(165.96,52.49) v3(166.01,51.65) v3(165.96,50.79) v3(165.96,49.93) v3(165.96,49.09)
3D3V_S5_PCH: length 152.8
  TOP w0.254: 96.11,33.09 v1(97.13,34.1) ; 96.11,33.09 95.83,33.37 R1824.1 ; 96.11,33.09 96.11,32.35 95.65,31.89 94.87,31.89
  TOP w0.508: 138.8,45.34 138.63,45.18 138.29,45.18 137.78,44.67 134.16,44.67 133.7,45.13 130.94,45.13 130.33,44.52 130.33,38.07 127.94,35.68 125.32,35.68 124.03,34.39 124.03,33.27 120.9,30.14 120.9,29.48 120.15,28.73 119.43,28.73 117.68,30.47 117.67,30.47 117.37,30.77 114.91,30.77 114.43,30.29 112.77,30.29 ; R1103.1 108.02,38.52 R1837.1 ; R9103.1 43.36,24.35 v1(42.85,23.84)
  TOP w1.016: v3(99.82,33.32) 100.2,33.7 100.2,34.84 101.52,36.16 104.87,36.16 106.53,37.81 R1103.1
  L3 w0.508: 100.51,13.4 95.26,8.15 86.01,8.15 85.81,8.36 55.28,8.36 47.46,16.18 43.84,16.18 41.98,18.04 41.98,22.98 v1(42.85,23.84)
  L6 w0.508: v1(109.78,18.86) 109.78,19.24 111.05,20.51 111.91,20.51 112.7,21.3 112.7,22.63 114.22,24.15 114.22,26.76 v1(114.93,27.47)
  BOTTOM w0.508: v1(109.78,18.86) R2007.1 R2041.1 ; R2501.2 119.4,22.19 118.61,21.4 116.1,21.4 114.48,19.78 114.48,17.97 114.7,17.75 114.7,17.08 114.22,16.6 114.22,15.08
  vias: v1(121.97,14.7) v2(111.96,30.04) v2(112.44,16.35) v3(113.1,14.52)
3D3V_SEN_S0: length 1.4
  BOTTOM w0.305: TCBD1.5 57.15,91.84 v3(57.28,91.71)
  vias: v2(52.45,96.71)
3D3V_SPIVCC1: length 6
  BOTTOM w0.508: SPI25.8 125.31,14.05 124.81,13.55 123.11,13.55 C2502.1 121.84,12.87 C2501.1
3D3V_SSD:
  vias: v3(198.93,10.35) v3(200.79,20.31) v3(200.79,18) v3(200.84,10.48) v3(201.6,12.51) v3(202.46,12.44) v3(203.66,31.46) v3(203.66,30.6)
3D3V_TPM: length 37.2
  TOP w0.508: v2(47.95,24.81) 47.45,24.3 R9102.2 R9101.2 ; v1(44.83,28.52) 44.73,28.41 R9140.1 ; R9101.2 46.02,23.36 C9105.1 45.82,23.16 C9102.1 C9104.1 C9101.1 R9119.1 41.76,23.16 41.2,23.71 v3(41.2,24.86) ; R9101.2 45.24,24.3 R9103.2 ; R9147.1 v1(37.64,23.97) ; v1(29.39,22.44) 29.82,22.88 v1(31.04,22.88) 31.24,23.08 R9138.2 ; R9149.1 v1(44.88,30.19)
  L4 w0.508: v1(44.83,28.52) 44.27,28.52 43.99,28.79 43.99,29.05 ; v1(31.04,22.88) 33.63,22.88 34.72,23.97 v1(37.64,23.97) 40.31,23.97 v3(41.2,24.86) 41.15,24.91 41.15,26.46 43.74,29.05 43.99,29.05 ; 43.99,29.05 43.99,29.94 44.25,30.19 v1(44.88,30.19)
  BOTTOM w0.508: Q9102.S 27.72,20.78 v1(29.39,22.44)
3D3V_TPM_1:
  vias: v2(32.84,30.9)
3D_CAM_DET#: length 4.4
  TOP w0.102: v1(117.82,34.05) 117.97,33.9 TP2006.1
  BOTTOM w0.089: CPU1.P2 118.2,36.82 118.2,36.59 118.16,36.5 118.16,35.91 118.44,35.64 118.44,34.43 118.39,34.38
  BOTTOM w0.102: v1(117.82,34.05) 117.86,34.05 117.88,34.02 118.03,34.02 118.39,34.38
81208_AGND: length 1.2
  BOTTOM w0.254: v1(153.34,101.57) 153.41,101.64 153.52,101.64 153.57,101.69 PC4647.1
  BOTTOM w0.508: PC4648.2 v1(162.74,97.45)
  vias: v1(155.01,95.19) v1(155.73,95.22) v1(156.49,96.74) v1(156.49,95.98) v1(156.49,95.22) v1(156.49,94.58) v1(156.49,93.82) v1(157.22,95.22) v1(157.96,95.19) v2(157.63,95.83)
+DC_IN:
  vias: v2(24.69,75.94) v2(25.5,82.16) v2(27.18,76.85) v3(26.47,79.21) v3(26.47,78.32) v3(26.47,77.44)
+DC_IN_C:
  vias: v2(20.09,83.84) v3(21.54,87.19) v3(22.38,87.16) v3(23.24,87.16)
+RTC_VCC: length 343.6
  TOP w0.254: v1(115.11,101.44) v2(115.11,102.07)
  TOP w0.508: v1(84.64,13.21) 84.91,12.95 86.56,12.95 87.65,14.03 93.8,14.03 97.46,10.38 123.82,10.38 126.87,13.43 130.91,13.43 132.81,15.33 139.41,15.33 139.9,15.07 139.93,15.06 140.81,14.6 141.97,14 142.03,13.97 142.43,13.77 143.25,12.94 v1(143.25,11.62)
  L3 w0.508: v1(146.48,15.36) 143.25,12.13 v1(143.25,11.62)
  L4 w0.508: v1(115.11,101.44) 111.18,101.44 106.86,97.11 106.86,96.39 102.51,92.04 95.17,92.04 93.14,90.01 82.73,90.01 81.74,91 v1(81.74,91.51) ; v1(124.69,111.04) 124.69,111.25 125.19,111.75 162.77,111.75 166.01,108.51 166.01,106.21 166.95,105.27 166.95,102.54 168.93,100.56 171.32,100.56 174.59,97.3 174.7,97.3 178.05,93.95 178.45,93.95 179.14,93.25 179.14,89.22 178.92,89 178.92,82.76 178.99,82.7 178.99,76.72 178.41,76.14 178.41,74.57 172.38,68.53 172.38,60.26 171.93,59.81 171.93,44.4 171.25,43.71 171.25,43.28 170.41,42.45 169.84,42.45 v1(169.82,42.43)
  BOTTOM w0.305: v1(169.82,42.43) 169.72,42.43 169.5,42.21 IOBD1.34
  BOTTOM w0.406: Q2503.2 142.72,10.43 143.05,10.76 R2504.1
  BOTTOM w0.508: v1(115.11,101.44) 117.27,103.6 122.15,103.6 124.69,106.13 v1(124.69,111.04) ; D2501.2 147.97,16.54 147.42,15.99 146.85,15.99 146.48,15.62 v1(146.48,15.36) ; v1(143.25,11.62) 143.25,10.89 R2504.1 ; v1(81.74,91.51) 81.74,91.03 83.87,88.9 83.87,58.61 79.96,54.7 79.96,50.79 78.76,49.6 78.76,26.97 74.34,22.55 74.34,17.8 78.61,13.53 84.33,13.53 v1(84.64,13.21)
+SDC_IN: length 19.5
  TOP w0.508: PR4320.1 28.34,69.77 v1(28.75,69.77) ; 33.96,85.82 34.26,86.12 34.26,88.15 34.39,88.28 PR4318.1
  L3 w0.508: v1(32.56,83.91) 32.56,82.19 29.03,78.66 29.03,70.04 v1(28.75,69.77)
  vias: v2(38.4,83.4)
+SDC_IN_SW: length 3.9
  TOP w0.127: PU4302.4 33.16,86.67 33.67,87.18 v2(33.67,87.72) 33.53,87.86 PR4318.2 PR4333.2
+SDC_IN_SW_R1: length 19.2
  TOP w0.127: v1(35.05,88.36) 35.05,89.2 34.75,89.5 PR4333.1 ; PQ4310.3 34.26,72.31 34.02,72.55 v2(34.02,72.99) v1(34.02,73.63)
  L3 w0.127: v1(35.05,88.36) 35.25,88.15 35.25,79.72 34.02,78.49 v1(34.02,73.63)
+UZ12_TPM: length 6.1
  TOP w0.305: U9104.8 v2(33.83,26.28) 32.44,26.28 C9114.1
  TOP w0.508: R9146.2 R9145.2 31.41,25.32 32.25,26.15 C9114.1
+V_VREF_PATH1: length 2.2
  TOP w0.508: C1222.2 71.53,48.92 v2(71.27,49.18) 71.27,49.31 71.78,49.81 R1209.1
+V_VREF_PATH2: length 1.9
  TOP w0.457: C1323.2 51.05,45.03 R1309.1
  TOP w0.508: R1309.1 51.03,45.84 v2(51.15,45.97)
A5_TP: length 7
  BOTTOM w0.102: CPU1.A5 125.61,38.36 125.61,37.88 125.79,37.71 126.02,37.71 126.23,37.49 126.23,37.39 126.62,37 127.94,37 128.34,37.3 128.98,37.66 129.63,38.32 TP2309.1
A67_TP: length 4.8
  TOP w0.102: v1(126.59,77.99) 126.41,78.17 TP2311.1
  BOTTOM w0.102: v1(126.59,77.99) 127.09,77.5 127.09,75.7 126,74.61 CPU1.A67
A70_TP: length 3.2
  TOP w0.102: TP2310.1 124.97,78.91 v1(125.45,78.91)
  BOTTOM w0.102: v1(125.45,78.91) 126.03,78.32 126.03,76.68 CPU1.A70
AC_DIS: length 239
  TOP w0.102: v1(178.36,93.13) 177.09,94.4 173.76,94.4 173.28,94.89 173.28,96.61 v1(170.94,98.95) ; v1(35.33,94.2) 34.64,93.51 34.64,92.92 v2(34.02,92.29) 33.77,92.04 30.94,92.04 30,91.1 30,90.44 28.78,89.22 28.27,89.22 27.91,89.58 25.85,89.58 25.58,89.85 25.58,90.24 25.42,90.39 PD4307.A 25.04,89.38 PR4326.1 ; v1(184.42,40.63) 184,41.04 KBC24.69
  L3 w0.102: v1(170.94,98.95) 170.94,99.08 170.48,99.53 170.25,99.53 167.66,102.12 167.66,104.71 165.99,106.39 165.99,108.18 161.92,112.24 86.97,112.24 84.3,109.58 84.3,108.02 79.01,102.73 78.62,102.73 75.73,99.84 67.09,99.84 66.21,100.73 62.33,100.73 61.47,99.86 58.62,99.86 57.75,100.73 52.48,100.73 51.84,100.09 49.66,100.09 49.1,100.65 42.95,100.65 37.06,94.76 35.89,94.76 v1(35.33,94.2)
  BOTTOM w0.102: v1(184.42,40.63) 183.8,40.63 181.23,43.2 181.23,46.07 180.74,46.56 180.71,46.69 180.64,46.92 179.97,49.22 179.95,49.3 178.56,50.69 178.56,54.96 178.04,55.48 178.04,58.35 177.85,58.54 177.85,61.25 176.1,63 176.1,69.79 178.85,72.55 178.85,84.08 179.16,84.38 179.16,92.34 v1(178.36,93.13)
AC_DIS_R: length 21.2
  TOP w0.102: v1(19.83,87.22) 20.52,87.22 v2(21.16,87.85) 21.28,87.98 24,87.98 R4303.1 PR4326.2 24.38,89.55 23.98,89.95 PD4307.K
  L6 w0.102: v1(19.83,87.22) 19.94,87.11 19.94,78.15 19.73,77.94 v1(19.33,77.94)
  BOTTOM w0.102: PD4308.K 21.44,76.12 20.57,76.98 20.29,76.98 v1(19.33,77.94) 19.12,77.94 18.7,78.37 PQ4304.B
AC_IN#_G: length 3.2
  BOTTOM w0.254: PR4313.1 PR4312.2 v2(24.56,79.42) 23.8,80.18 U4302.5
AC_PRESENT: length 112.3
  L4 w0.102: v1(100.86,43.86) 100.86,43.81 100.73,43.68 100.73,42.92 99.01,41.19 99.01,39.29 94.77,35.05 94.77,23.93 96.99,21.71 98.94,21.71 100.44,20.21 105.48,20.21 106.17,20.9 v1(106.5,20.9) 106.81,20.59 111.69,20.59 111.94,20.84 112.76,20.84 113.19,20.41 119.89,20.41 120.42,19.88 121.79,19.88 122.22,19.45 127.07,19.45 127.27,19.65 128.2,19.65 128.5,19.96 130.86,19.96 133.27,22.37 143.91,22.37 145.69,24.14 147.29,24.14 148.72,25.57 150.89,25.57 v1(151.31,25.15)
  BOTTOM w0.089: 103.4,44.16 103.52,44.12 103.69,44.12 103.79,44.14 103.96,44.32 103.96,44.41 104.55,45 CPU1.AY15
  BOTTOM w0.102: RN1704.8 107.17,20.02 EC1707.1 107.49,20.94 v2(107.21,21.21) 107,21.21 106.68,20.9 v1(106.5,20.9) ; 103.4,44.16 101.77,44.16 101.62,44.01 101.01,44.01 v1(100.86,43.86) ; Q1702.3 151.3,19.41 151.8,19.92 152.57,19.92 153.5,20.86 153.5,21.21 153.06,21.66 151.2,21.66 150.95,21.91 150.95,23.53 151.18,23.75 151.18,25.02 v1(151.31,25.15) 151.52,25.15 151.81,24.86 151.81,23.59 152.07,23.33 152.83,23.33 153.08,23.58 153.08,25.71 152.78,26 152.78,28.18 151.76,29.19 151.76,29.56 152.04,29.84 D1701.A
ACLIM: length 4.8
  BOTTOM w0.203: 140.41,36.31 140.66,36.06 PU4401.16
  BOTTOM w0.254: v2(137.18,38.02) 137.82,37.38 PR4421.2 138.76,37.38 PR4424.1 138.78,37.37 139.38,36.77 139.96,36.77 140.41,36.32 140.41,36.31
ACOK#: length 4.4
  BOTTOM w0.127: 141.7,39.29 141.6,39.39 PQ4415.2 ; 141.7,39.29 141.7,39.15 141.29,38.74 PQ4415.3 ; 141.7,39.29 142.38,39.96 v2(142.42,39.96) 142.91,39.96 143.1,40.15 PR4471.2
ACOK_IN_M: length 290.6
  TOP w0.254: v1(25.96,88.99) 26.01,89.04 PD4305.K ; v1(150.93,42.13) v2(151.56,41.49) 151.81,41.24 151.81,34.38 149.81,32.38 v1(149.81,32.17) ; v1(29.67,76.65) 28.65,75.63 PD4306.K
  L3 w0.254: v1(170.25,95.93) 170.2,95.93 169.54,96.58 169.54,98.46 166.67,101.33 166.67,104.26 164.97,105.96 164.97,107.79 161.51,111.25 129.31,111.25 128.41,110.35 123.01,110.35 122.13,111.23 87.03,111.23 85.06,109.26 85.06,106.99 78.49,100.42 77.03,100.42 75.94,99.33 66.88,99.33 65.99,100.22 62.54,100.22 61.68,99.36 58.41,99.36 57.54,100.22 52.69,100.22 52.01,99.55 47.56,99.55 47.34,99.33 45.32,99.33 43.13,97.15 41.59,97.15 39.27,94.82 v1(39.27,94.45)
  L4 w0.254: v1(139.4,41.12) 139.4,44.58 140.77,45.94 142.8,45.94 143.31,45.43 143.31,44.06 145.24,42.13 v1(150.93,42.13) 151.67,41.39 155.77,41.39 157.91,43.53 157.91,45.2 159.51,46.8 163.17,46.8 164.44,48.07 164.44,59.22 166.93,61.71 166.93,70.45 169.26,72.79 169.26,95.02 170.17,95.93 v1(170.25,95.93)
  L6 w0.254: v1(39.27,94.45) 39.04,94.23 39.04,87.07 29.73,77.76 29.73,76.65 v1(29.67,76.65)
  BOTTOM w0.254: v1(29.67,76.65) 29.67,82.69 25.91,86.45 25.91,88.94 v1(25.96,88.99) ; v1(149.81,32.17) 149.81,30.5 D1701.K ; PQ4415.6 139.04,40.76 v1(139.4,41.12)
AD+: length 239.6
  TOP w0.508: PD4411.A 155.6,55.62 155.62,55.6 155.62,54.7 156.39,53.94 v1(156.59,53.94)
  L3 w0.508: v1(150.42,37.67) 153.34,40.59 153.34,44.16 155.94,46.76 155.94,52.02 156.59,52.67 v1(156.59,53.94)
  L4 w0.508: v1(156.59,53.94) 157,53.94 157.5,54.45 157.5,61.19 165.02,68.71 165.02,69.47 168.36,72.81 168.36,78.36 167.12,79.59 166.67,79.59 v1(166.65,79.57) ; v1(38.45,102.56) 76,102.56 78.03,104.59 78.03,106.21 78.05,106.23 78.05,106.8 78.03,106.82 78.03,108.42 82.09,112.49 120.45,112.49 124.06,108.87 132.32,108.87 132.81,109.36 161.78,109.36 163.24,107.9 163.24,105.07 163.71,104.6 164.18,104.13 164.18,102.39 163.74,101.95 v1(163.4,101.95)
  L6 w0.508: v1(28.24,87.47) 29.28,88.51 29.28,94.21 31.69,96.61 35.26,96.61 37.26,98.61 37.26,101.36 v1(38.45,102.56) ; v1(163.4,101.95) 163.9,101.44 163.9,98.94 166.63,96.21 166.63,95.57 166.63,94.44 168.2,92.88 168.2,81.12 v1(166.65,79.57)
  vias: v1(149.02,32.2) v2(151.08,37.99)
AD_IA: length 69.1
  TOP w0.102: PG4401.2 141.96,30.04 142.42,29.58 142.91,29.58 143.34,29.15 v1(143.37,29.15) 143.37,29.05 v2(143.94,28.48) 148.35,28.48 149.15,29.28 149.15,29.66 151.15,31.67 151.15,32.84 152.7,34.39 v1(152.7,34.89)
  L4 w0.102: v1(194,40.12) 192.8,38.92 192.17,38.92 191.92,38.66 191.92,37.66 189.66,35.4 189.66,32.79 v1(189.18,32.31)
  L6 w0.102: v1(152.7,34.89) 154.33,33.27 164.29,33.27 164.75,33.73 170.33,33.73 170.86,34.26 178.23,34.26 179.37,33.11 179.37,32.48 180.59,31.26 182.8,31.26 183.41,31.87 184.87,31.87 185.65,32.66 188.83,32.66 189.18,32.31 v1(189.18,32.31)
  BOTTOM w0.102: v1(194,40.12) 194.08,40.2 PR2455.1 ; v1(143.37,29.15) 143.31,29.21 PC4423.1 ; v1(189.18,32.31) 189.1,32.23 R2421.1
AD_OFF_L: length 2.5
  BOTTOM w0.254: PQ4305.1 18.73,76.27 PQ4304.C
AD_OFF_R: length 16.8
  TOP w0.254: PC4301.2 20.98,75.02 v1(20.98,73.98) 23.49,73.98 PR4308.1 24.1,74.64 PR4307.2 24.26,75.58 24.94,74.9 25.52,74.9 25.98,75.35 26.92,75.35 28.24,76.67 28.73,76.67 29.6,77.54 v2(29.6,77.56) PU4301.4
  BOTTOM w0.254: v1(20.98,73.98) 20.34,73.35 19.85,73.35 PQ4305.3
ALERT#: length 3.8
  BOTTOM w0.102: v2(132.84,23.69) 132.92,23.77 R2603.2 134.21,23.77 134.42,23.97 134.42,24.86 134.65,25.09 THM261.6
ALWON: length 95.8
  TOP w0.127: v1(161.49,13.4) 161.64,13.25 v2(162.08,13.25) ; v1(187.25,26.08) 187.4,25.92 190.09,25.92 190.4,25.62 191.71,25.62 192.57,26.48 192.87,26.48 193.07,26.69 193.74,26.69 194.41,27.36 194.41,27.7 KBC24.121
  L3 w0.127: v1(148.77,14.6) 150.35,14.6 150.99,15.24 152.58,15.24 153.09,14.73 160.22,14.73 161.49,13.47 v1(161.49,13.4)
  L4 w0.127: v1(161.49,13.4) 162.29,14.2 164.21,14.2 164.97,14.96 176.13,14.96 v1(187.25,26.08) ; v1(116.89,11.24) 117.14,11.5 124.8,11.5 125.71,12.41 136.47,12.41 138.47,14.41 148.58,14.41 v1(148.77,14.6)
  BOTTOM w0.127: v1(116.89,11.24) 117.02,11.37 117.02,13.05 116.44,13.62 116.18,13.62 116,13.79 116,15.08 116.64,15.71 116.64,16.48 117.19,17.03 R4009.2
AMBER_LED_BAT: length 4.7
  BOTTOM w0.508: R6401.2 67.31,11.47 EC6401.1 67.94,12.13 v2(68.2,12.39) 68.15,12.44 68.15,14.58 Q6402.C
AUD_AGND: length 11
  TOP w0.203: v1(23.67,21.17) 23.67,21.1 23.95,20.82 HDA27.18 ; 21.02,13.92 21.18,14.09 HDA27.37
  TOP w0.305: v1(20.24,12.59) EC2704.1
  TOP w0.381: EC2906.2 19.71,14.62 v1(19.76,14.57)
  TOP w0.508: EC2905.2 v1(15.21,14.75) ; 21.02,13.92 20.78,13.68 20.31,13.68 19.76,14.23 v1(19.76,14.57)
  BOTTOM w0.508: v1(15.26,14.11) 15.9,14.11 16.86,13.15 ; 16.86,13.15 16.86,13.5 C2705.1 ; 16.86,13.15 C2702.1 ; C2712.1 23.06,21.99 23.67,21.38 v1(23.67,21.17)
  vias: v1(18.51,19.52) v1(18.62,21.25) v1(20.37,23.97) v1(21.05,23.64) v1(22.66,24.17) v2(14.7,14.29)
AUD_HP1_JACK_L: length 3.6
  TOP w0.203: HDA27.26 20.19,18.91 20.01,19.09
  TOP w0.254: 20.01,19.09 19.4,19.7 19.4,19.85 v2(19.23,20.03) 17.78,20.03 R2907.1
AUD_HP1_JACK_L1: length 9.3
  TOP w0.254: v2(14.14,18.8) 14.16,18.8 ; 14.16,18.8 14.24,18.8 14.27,18.76 v1(14.91,18.76) ; 14.16,18.8 14.16,19.56 14.6,20.01 16.28,20.01 R2907.2
  BOTTOM w0.254: EC2907.1 18.18,16.58 R2922.2 R2908.1 R2912.2 17.4,18.13 R2919.1 16.31,18.76 v1(14.91,18.76)
AUD_HP1_JACK_R: length 5.8
  TOP w0.203: HDA27.25 20.51,19.31 20.34,19.47
  TOP w0.254: 20.34,19.47 20.04,19.78 20.04,20.9 19.86,21.07 19.86,21.68 20.11,21.94 20.41,21.94 20.53,22.06 20.53,22.38 R2909.1 21.36,23.21 21.74,23.21 v2(21.92,23.38)
AUD_HP1_JACK_R1: length 8.5
  TOP w0.254: v1(19.1,23.64) 19.15,23.59 19.15,23.18 R2909.2
  BOTTOM w0.254: v1(19.1,23.64) v2(18.31,23.64) 17.98,23.97 17.07,23.97 R2913.2 R2921.2 16.53,22.32 16.76,22.09 17.02,22.09 17.4,21.71 R2910.1 17.4,21.48 EC2908.1 R2920.1
AUD_PC_BEEP: length 3.2
  TOP w0.203: HDA27.32 19.84,16.51 v1(19.64,16.31)
  BOTTOM w0.254: v1(19.64,16.31) 19.99,15.97 R2723.2 20.52,16.63 v2(20.27,16.88)
AUD_PC_BEEP_C: length 4.2
  BOTTOM w0.254: v2(25.86,11.78) 25.86,11.9 R2717.1 27.62,12.56 D2701.3 27.38,11.56 C2720.1
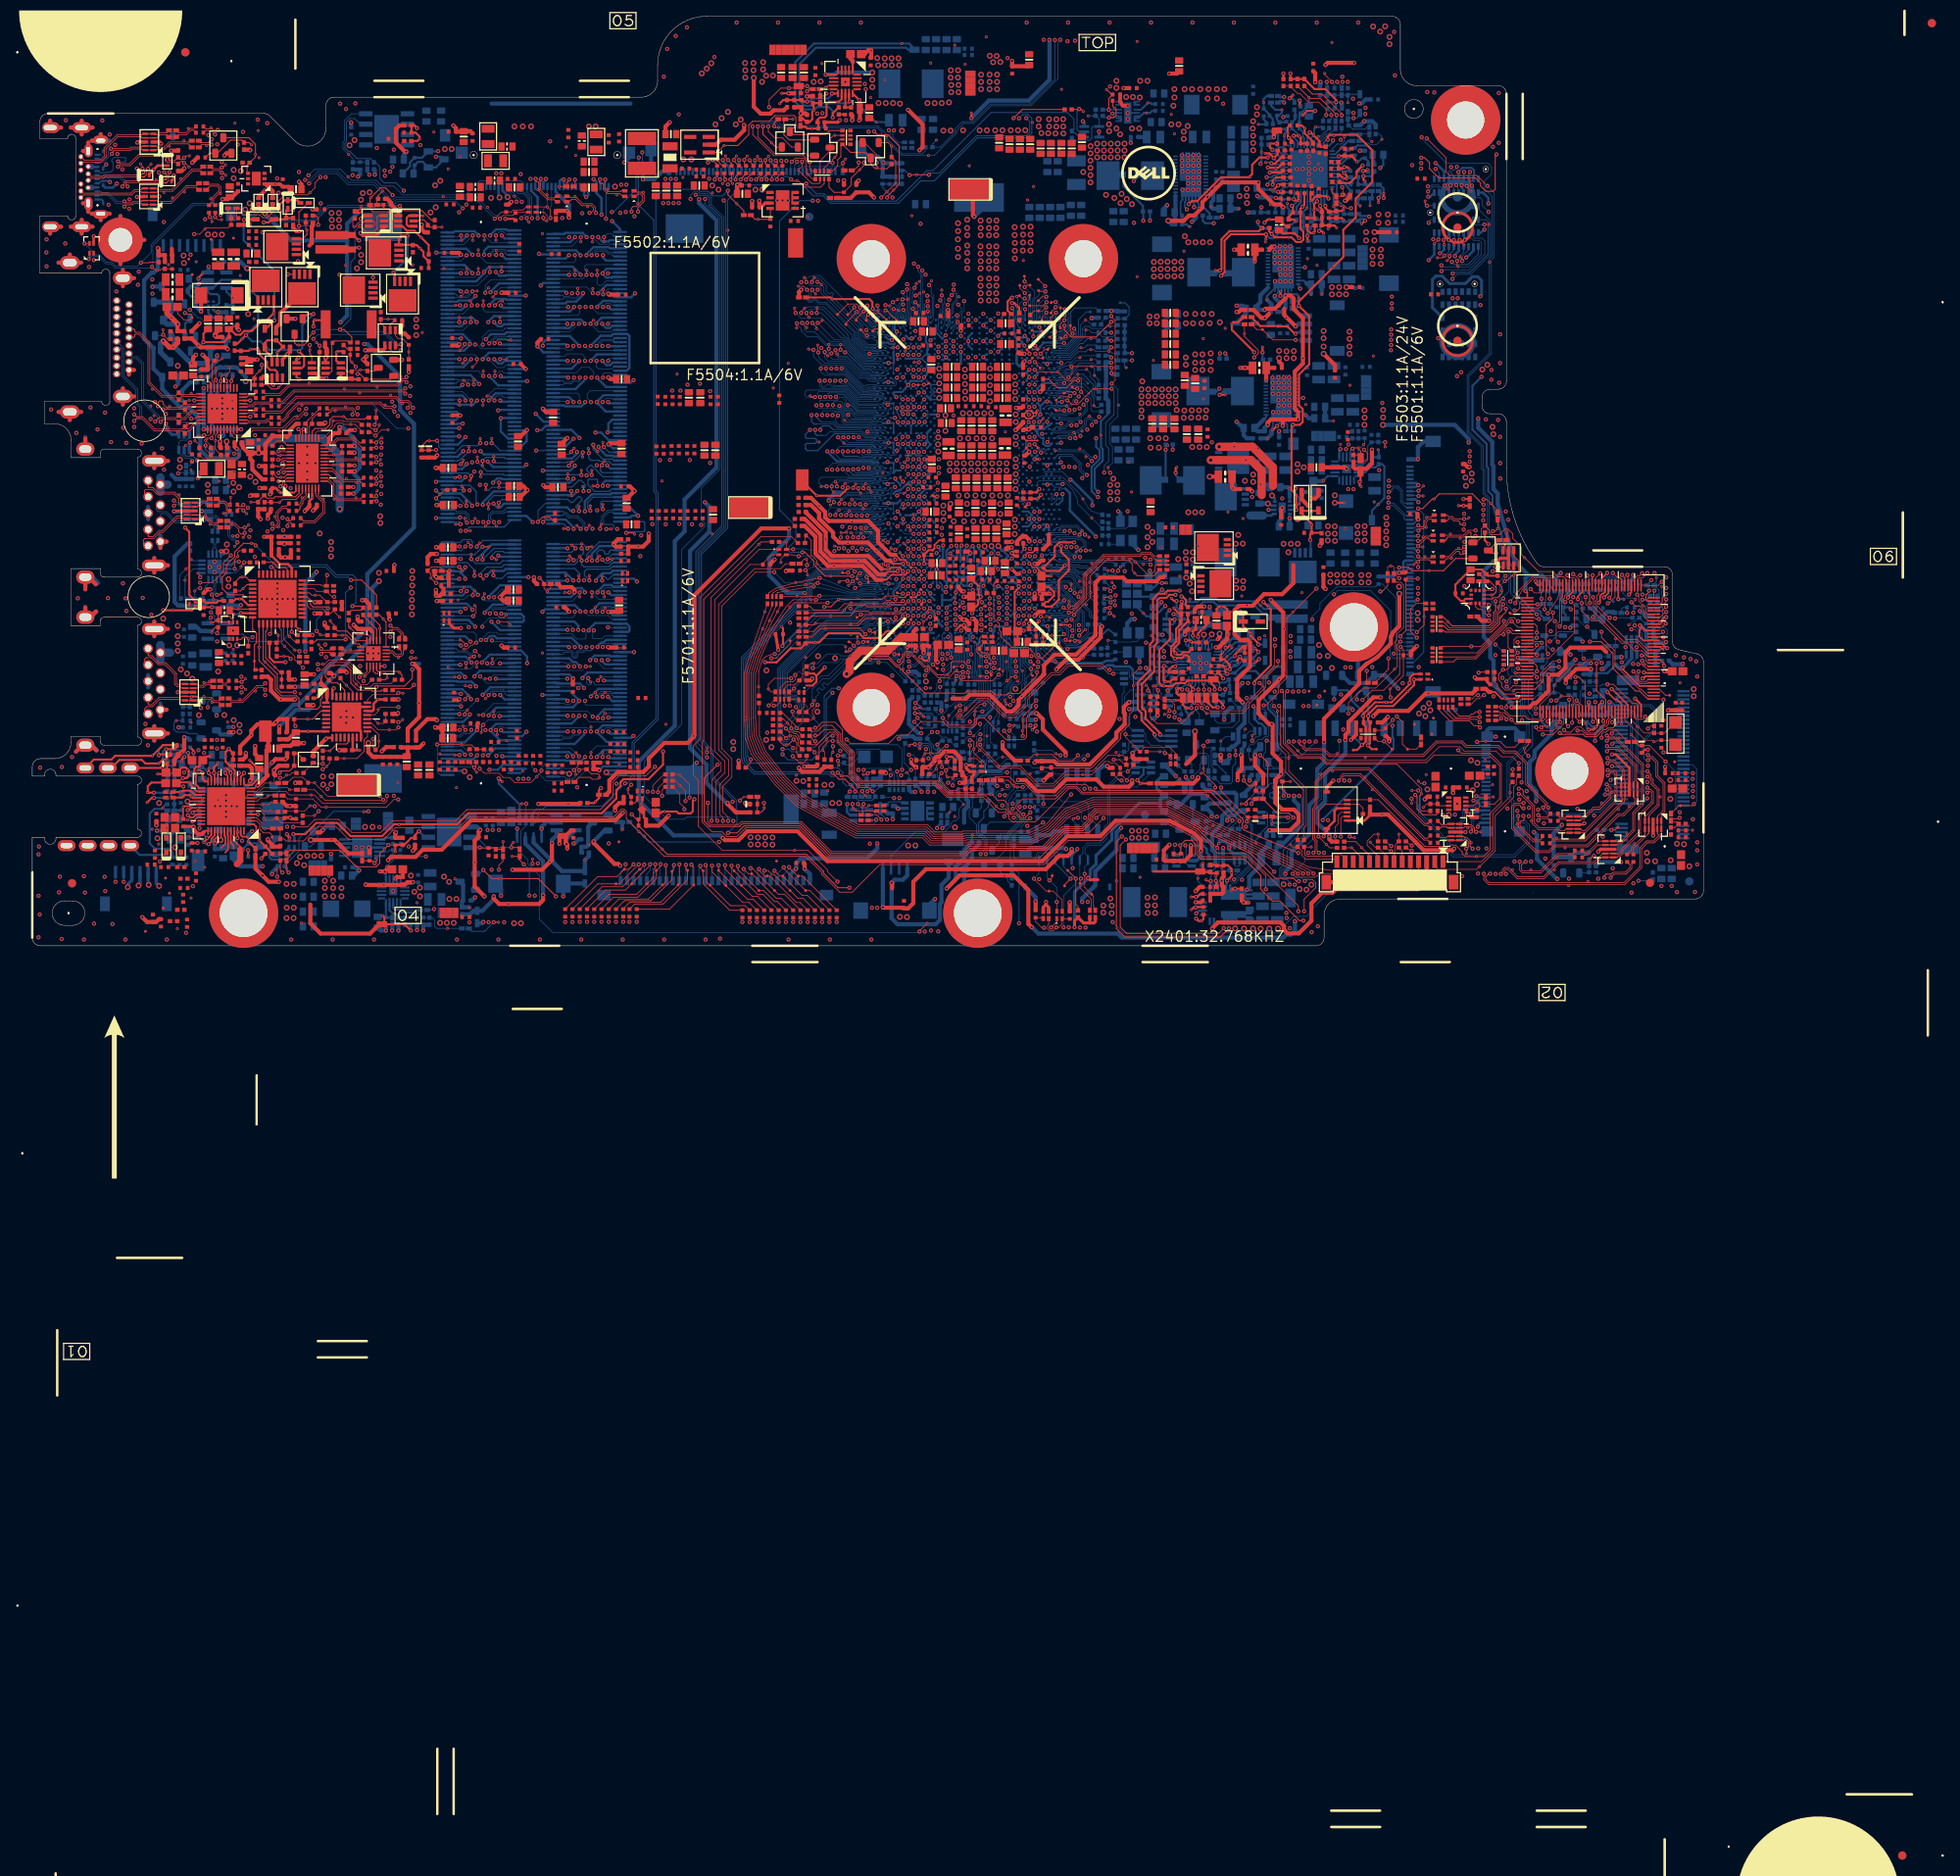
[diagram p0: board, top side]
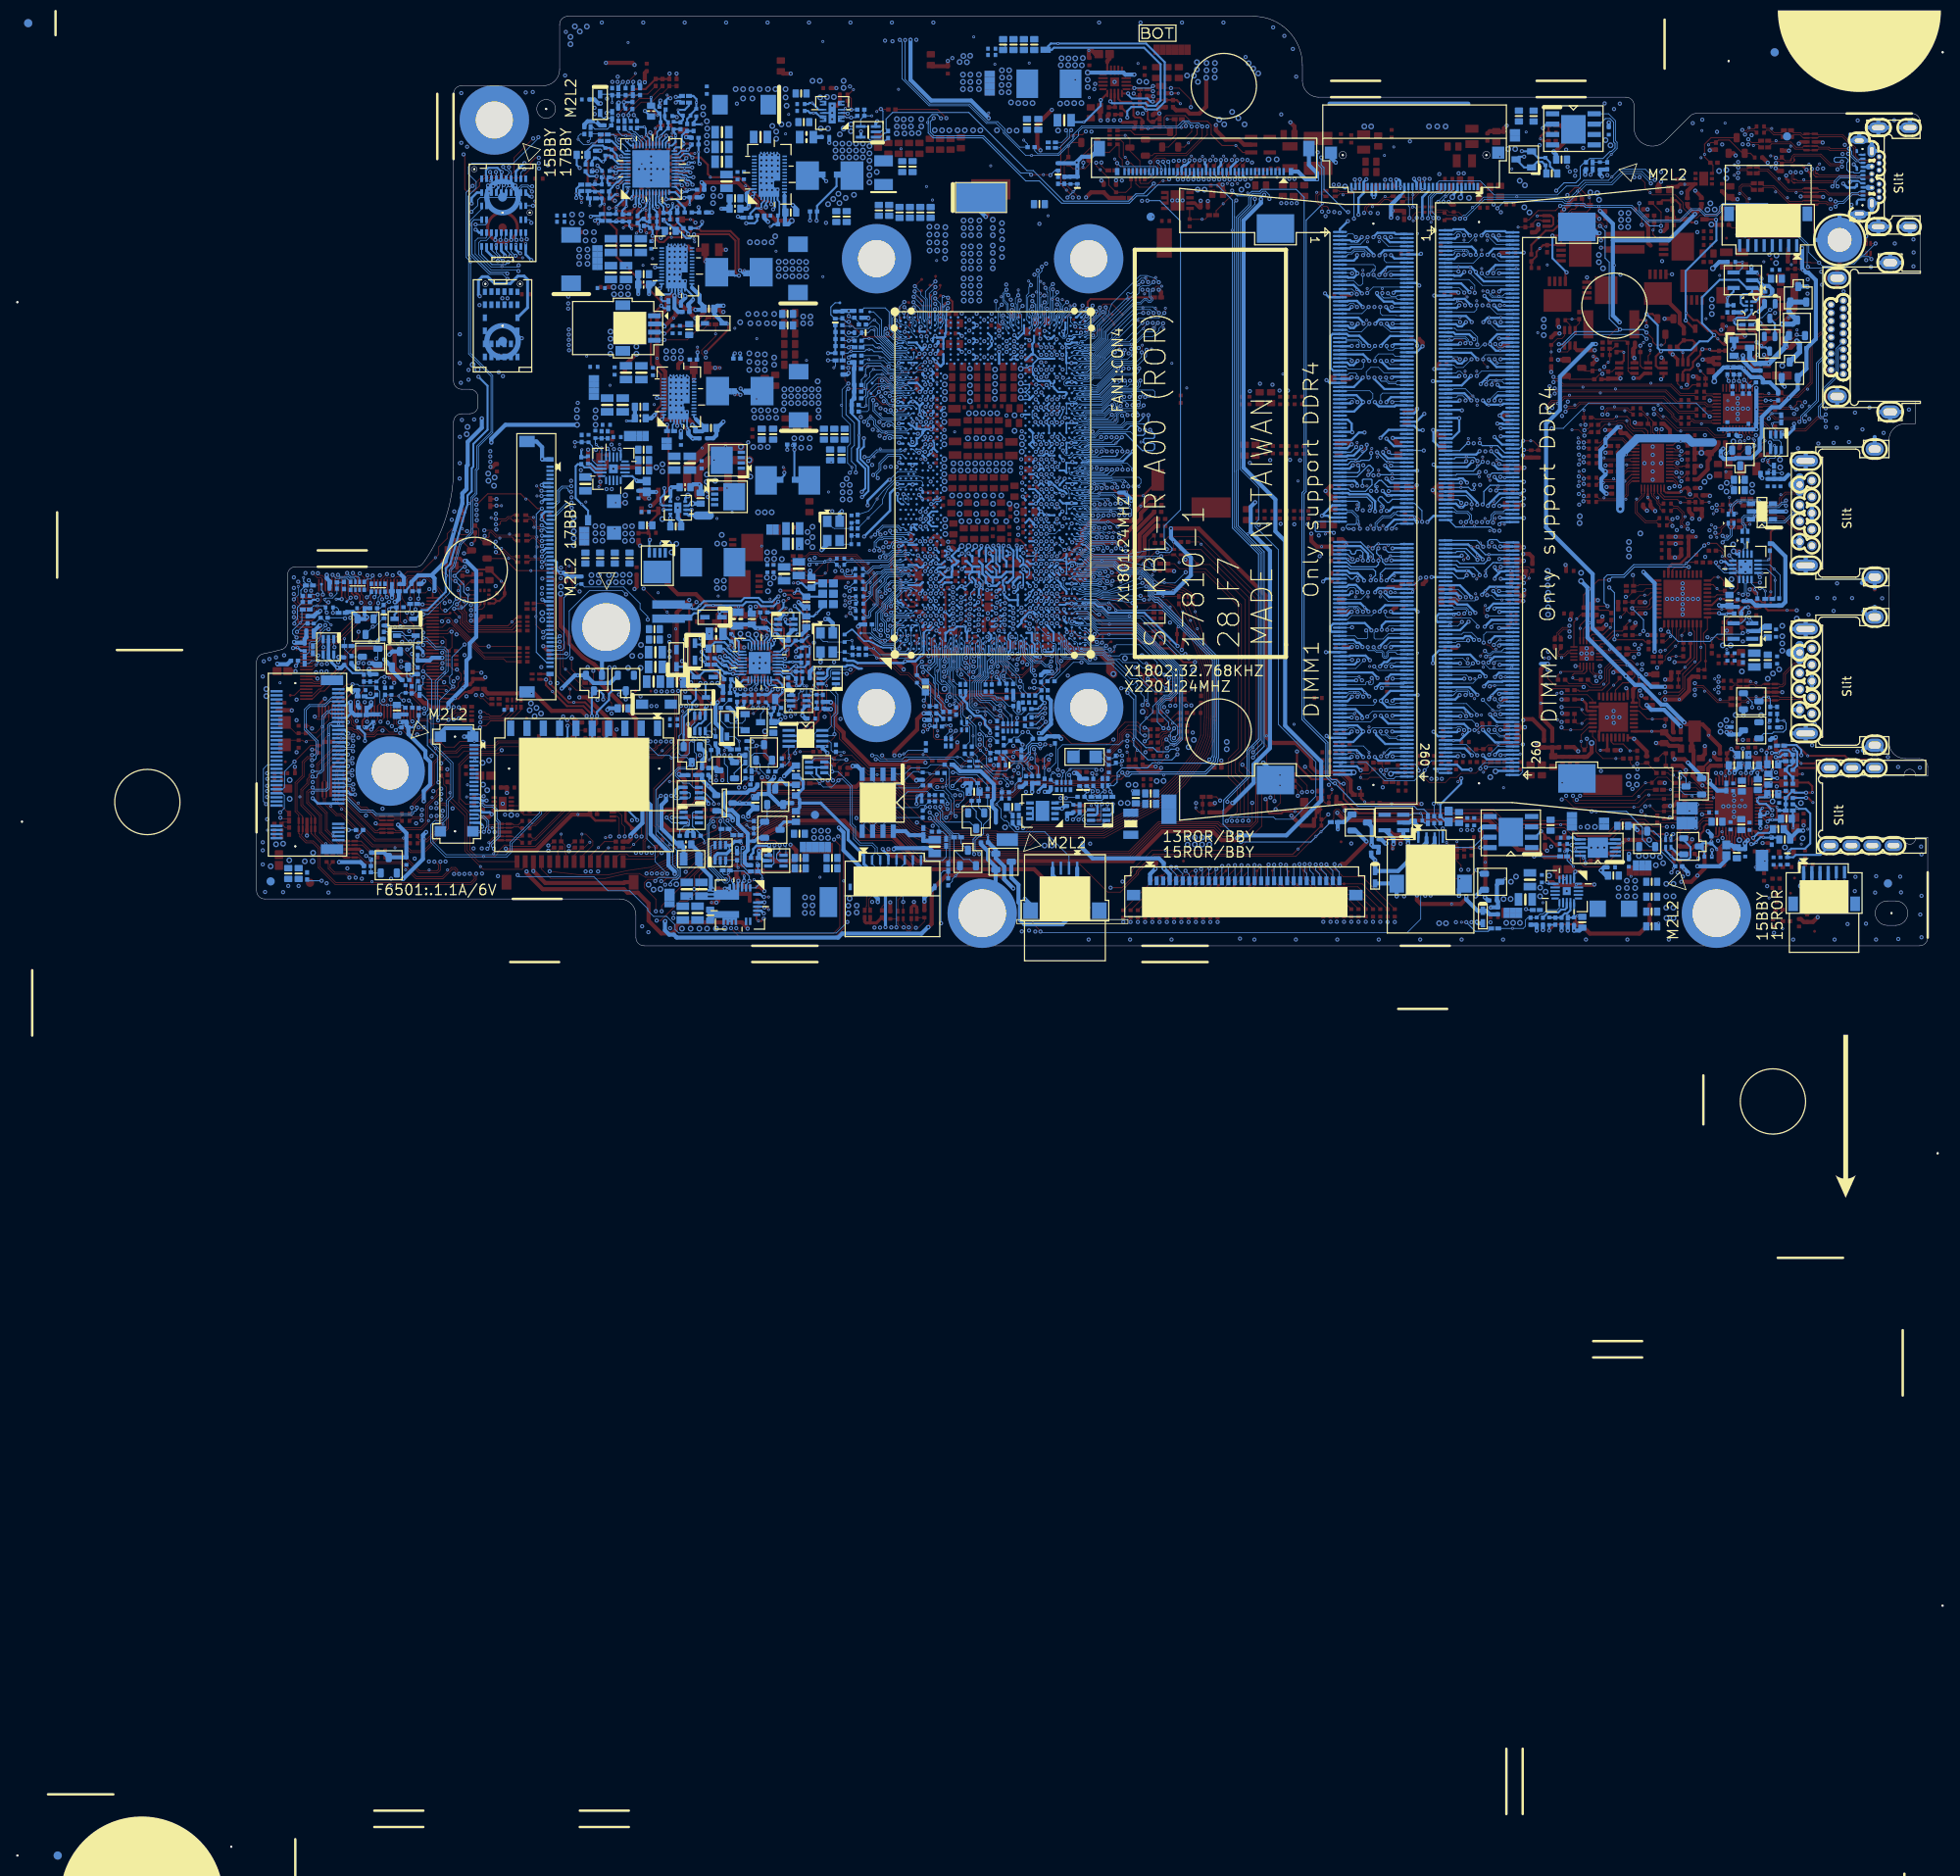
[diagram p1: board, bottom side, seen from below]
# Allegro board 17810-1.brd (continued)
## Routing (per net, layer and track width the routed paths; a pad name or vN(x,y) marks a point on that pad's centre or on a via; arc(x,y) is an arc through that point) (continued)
AUD_PC_BEEP_R: length 10.7
  TOP w0.254: v2(26.47,11.01) 26.47,11.71 v1(26.45,11.73)
  L6 w0.254: v1(20.5,14.39) 20.75,14.14 20.75,12.61 21.63,11.73 23.18,11.73 23.82,12.36 25.48,12.36 26.12,11.73 v1(26.45,11.73)
  BOTTOM w0.254: R2723.1 20.52,14.42 v1(20.5,14.39) ; v1(26.45,11.73) 26.45,10.93 C2720.2
AUD_PORTA_L_R_B: length 15.9
  BOTTOM w0.254: HPMIC1.1 13.15,11.14 16.18,11.14 16.47,10.85 ED2902.1 17.19,11.44 v2(16.96,11.68) 16.73,11.9 15.04,11.9 14.4,12.54 14.4,16.22 14.96,16.78 15.82,16.78 16.38,17.34 R2908.2
AUD_PORTA_R_R_B: length 17
  TOP w0.254: v1(16.41,24.07) 16.43,24.1 17.45,24.1 17.74,24.39 ED2905.1 17.69,24.6 16.03,24.6 v2(14.7,23.28) 10.16,23.28 9.7,22.83 7.54,22.83 6.51,21.79 HPMIC1.2
  BOTTOM w0.254: v1(16.41,24.07) 16.31,24.07 16,23.77 16,22.09 R2910.2
AUD_SENSE: length 28.6
  TOP w0.254: v1(28.09,10.71) 28.09,10.74 28.57,11.22 R2709.2 ; v1(18.46,20.54) 18.85,20.54 19.17,20.87 19.17,21.48 v2(19.07,21.58) 18.82,21.84 18.31,21.84 R2923.2
  L6 w0.254: v1(18.46,20.54) 15.97,20.54 14.4,18.97 14.4,17.54 20.72,11.22 23.39,11.22 24.03,11.85 25.27,11.85 26.05,11.07 27.73,11.07 v1(28.09,10.71)
  BOTTOM w0.254: v1(18.46,20.54) 19,20.54 C2902.1
AUD_SENSE_A: length 5
  TOP w0.203: HDA27.1 27.14,14.91 27.46,14.6 27.46,14.09
  TOP w0.254: 27.46,14.09 27.86,13.68 v2(27.86,12.9) 27.86,12.87 R2722.2 29.44,11.29 R2709.1
AUD_SPK_L+: length 2.4
  TOP w0.203: 23.14,11.98 23.67,12.51 23.67,13.33 23.55,13.45 HDA27.42
  vias: v2(19.96,10.38)
AUD_SPK_L+_C: length 1.8
  BOTTOM w0.406: v3(15.54,7.33) 15.2,7.67 SPK1.1
AUD_SPK_L-: length 2.8
  TOP w0.203: HDA27.43 23.95,13.53 24,13.48 24,11.78 23.65,11.42
  vias: v2(21.13,9.62)
AUD_SPK_L-_C: length 1.6
  BOTTOM w0.406: SPK1.2 14.2,7.53 v3(14.27,7.46)
AUD_SPK_R+: length 4.6
  TOP w0.203: 25.5,11.8 25.5,12.13 24.66,12.97 24.66,13.49 24.75,13.58 HDA27.45
  TOP w0.762: 25.5,11.8 25.5,10.43 25.07,10
  vias: v2(17.78,2.1)
AUD_SPK_R+_C: length 2
  BOTTOM w0.406: v3(11.71,7.18) 11.71,7.54 12.2,8.03 SPK1.4
AUD_SPK_R-: length 2.3
  TOP w0.203: 24.66,11.9 24.66,12.31 24.33,12.64 24.33,14.07 HDA27.44
  vias: v2(19.45,5.86)
AUD_SPK_R-_C: length 1.7
  BOTTOM w0.406: SPK1.3 13.2,7.55 v3(13.03,7.38)
AUD_VREF: length 4.8
  TOP w0.203: v1(21.4,13.23) 21.43,13.26 21.63,13.26 21.95,13.58 HDA27.38
  TOP w0.254: v1(21.4,13.23) 21.4,13.06 v2(21,12.67)
  BOTTOM w0.254: C2705.2 19.43,13.83 20.79,13.83 v1(21.4,13.23)
AUX_EN_WOWL: length 4.3
  TOP w0.102: v1(100,45.74) 99.97,45.71 TP1710.1
  BOTTOM w0.102: v1(100,45.74) 100,45.81 100.46,46.27 102.64,46.27 102.77,46.14 CPU1.BB17
B71_TP: length 2.5
  TOP w0.102: TP2312.1 124.81,76.93 v1(125.5,77.61)
  BOTTOM w0.102: v1(125.5,77.61) 125.5,77.56 125.45,77.51 CPU1.B71
BA1_TP: length 4.1
  TOP w0.102: v1(100.25,36.31) 100,36.06 TP2305.1
  BOTTOM w0.102: CPU1.BA1 103.33,36.4 103.33,36.39 100.89,36.39 100.86,36.36 100.3,36.36 v1(100.25,36.31)
BA2_TP: length 4.4
  TOP w0.102: v1(100.71,36.77) 100.23,37.25 TP2306.1
  BOTTOM w0.102: v1(100.71,36.77) 100.86,36.62 102.54,36.62 103.1,37.18 103.58,37.18 103.73,37.03 CPU1.BA2
BA71_TP: length 5.6
  TOP w0.102: TP2303.1 103.96,77.49 103.32,77.49 103.22,77.59 102.79,77.59 102.37,78.01 v1(102.37,78.46)
  BOTTOM w0.102: v1(102.37,78.46) 102.37,78.44 102.57,78.24 102.57,77.81 102.83,77.55 103.26,77.55 103.49,77.32 103.49,77.28 CPU1.BA71
BAT1_LED#: length 38
  TOP w0.127: v1(180.3,41.85) 180.3,41.85 180.11,41.66 180.11,41.15 179.63,40.67 179.63,39.6 178.74,38.71 173.52,38.71 173.02,39.21 RN2405.2 ; v1(188.39,30.17) 188.41,30.15 188.41,29.44 KBC24.106 ; Q2416.4 181.6,47.75 182.22,47.13 182.22,46.04 v2(181.56,45.38) 181.38,45.38 180.82,44.82 180.6,44.82 v1(180.49,44.7)
  L4 w0.127: v1(188.39,30.17) 188.39,30.6 186.93,32.06 186.93,33.05 187.59,33.71 187.59,37.31 186.79,38.11 185.95,38.11 185.57,38.49 185.31,38.74 185.31,40.36 184.13,41.55 181.05,41.55 180.74,41.85 v1(180.3,41.85)
  BOTTOM w0.127: v1(180.3,41.85) 179.86,42.29 179.86,44.08 v1(180.49,44.7)
BAT2_LED#: length 46.3
  TOP w0.127: KBC24.1 198.02,30.24 197.04,31.22 196.54,31.22 193.76,34 193.76,35.81 192.29,37.28 190.93,37.28 v1(190.93,37.28) ; v1(179.32,46.45) 180.15,46.45 Q2416.1 ; v1(180.63,41.31) 180.63,40.93 v2(180,40.29) 179.88,40.17 179.88,39.49 178.84,38.45 173.2,38.45 173.02,38.62 RN2405.1
  L3 w0.127: v1(180.59,45.33) 180.93,44.99 180.93,44.65 182.78,42.8 183.96,42.8 184.62,43.46 186.52,43.46 187.39,42.6 187.39,40.92 188.15,40.16 188.65,40.16 189.79,39.02 189.79,38.42 v1(190.93,37.28)
  BOTTOM w0.127: v1(180.63,41.31) 179.66,41.31 178.93,42.05 178.93,42.86 179.45,43.38 179.45,44.3 180.48,45.33 v1(180.59,45.33) 179.47,46.45 v1(179.32,46.45)
BAT_AMBER: length 10.8
  BOTTOM w0.508: LED1.2 61.44,12.64 64.92,9.16 ED6401.1 v2(67.74,10.51) 68.22,10.99 R6401.1
BAT_WHITE: length 20.4
  TOP w0.508: v1(56.56,6.06) 56.56,5.78 57.22,5.12 v2(58.37,5.12) 62.13,5.12 62.61,5.6 v1(62.61,6.19)
  BOTTOM w0.508: v1(56.56,6.06) 56.56,5.68 55.17,4.28 ED6402.1 54.11,4.28 53.68,3.85 R6402.1 ; v1(62.61,6.19) 62.61,10.35 60.44,12.52 LED1.3
BATT_WHITE_LED#: length 2.4
  TOP w0.127: v2(180.77,50.71) 180.77,49.81 R6404.1 180.69,49.27 180.3,48.87 Q2416.6
BATT_WHITE_LED_R#: length 157.9
  TOP w0.127: v1(64.18,6.06) 62.03,8.22 v2(57.38,8.22) 56.35,8.22 v1(55.29,9.29) ; v1(179.42,48.1) 178.85,48.1 Q6403.D 179.77,49.72 R6404.2
  L4 w0.127: v1(179.42,48.1) 179.77,47.76 179.77,46.03 178.75,45.01 178.43,45.01 177.68,44.26 177.68,43.58 176.64,42.53 176.64,39.59 174.1,37.04 174.1,34.79 168.41,29.11 168.41,27.67 166.71,25.96 165.36,25.96 164.78,25.38 164.78,24.63 164.01,23.86 160.11,23.86 158.49,25.48 153.81,25.48 153.41,25.08 153.41,24.34 149.91,20.83 147.67,20.83 146.42,19.58 146.42,19.11 146.01,18.7 133.27,18.7 131.45,16.87 129.43,16.87 129.11,16.55 127.88,16.55 127.34,16.01 124.18,16.01 122.39,14.22 121.43,14.22 121.28,14.37 117.87,14.37 117.71,14.53 114.55,14.53 113.68,13.67 110.89,13.67 108.65,11.43 100.34,11.43 99.03,12.74 92.53,12.74 91.2,14.07 86.95,14.07 85.15,12.27 80.99,12.27 80.94,12.22 74.6,12.22 74.49,12.11 71.76,12.11 66.57,6.93 65.05,6.93 v1(64.18,6.06)
  BOTTOM w0.127: Q6401.B 54.82,8.82 v1(55.29,9.29)
BB67_TP: length 2.1
  TOP w0.102: v1(102.31,74.79) 102.26,74.79 TP2302.1
  BOTTOM w0.102: v1(102.31,74.79) 102.33,74.79 102.36,74.82 103.03,74.82 103.24,74.61 CPU1.BB67
BB70_TP: length 2
  TOP w0.102: v1(102.46,77.36) 102.23,77.13 TP2301.1
  BOTTOM w0.102: CPU1.BB70 103.13,76.56 102.51,77.18 102.51,77.31 v1(102.46,77.36)
BEEP: length 338.8
  TOP w0.203: v1(193.04,45.69) 192.41,45.05 KBC24.45
  TOP w0.254: v2(31.57,13.2) 31.21,13.55 v1(31.21,13.68)
  L3 w0.254: v1(31.21,13.68) 29.92,14.98 29.92,20.26 26.81,23.37 26.81,27.83 21.92,32.72 21.92,34.6 21.18,35.34 21.18,39.14 19.23,41.1 19.23,44.78 20.01,45.56 20.01,48.71 22.54,51.24 22.54,57.46 24.63,59.55 25,59.55 29.03,63.59 29.03,69.08 29.67,69.71 29.67,75.05 30.38,75.76 30.38,79.09 33.2,81.91 33.2,84.33 30.94,86.59 30.94,93.15 32.62,94.83 v1(32.69,94.83)
  L4 w0.254: v1(126.9,110.86) 127.52,110.24 128.1,110.24 128.22,110.35 162.19,110.35 164.62,107.93 164.62,105.64 165.56,104.7 165.56,101.96 169.1,98.42 171.3,98.42 172.52,97.2 172.52,89.4 174.65,87.27 175.54,87.27 177.21,85.6 177.21,82.29 177.59,81.91 177.59,80.46 176.68,79.54 176.68,74.82 170.94,69.08 170.94,60.8 170.51,60.37 170.51,44.95 169.85,44.29 v1(169.85,43.86)
  L6 w0.254: v1(32.69,94.83) 32.92,95.06 36.85,95.06 39.13,97.35 40.07,97.35 43.35,100.63 45.62,100.63 47.18,102.19 76.28,102.19 79.04,104.95 79.04,106.7 79.17,106.83 79.17,106.83 83.93,111.6 115.81,111.6 115.82,111.59 126.17,111.59 126.21,111.55 126.24,111.55 126.52,111.27 126.52,111.24 v1(126.9,110.86) ; v1(169.85,43.86) 171.47,43.86 172.82,45.2 179.27,45.2 180.39,44.09 181.59,44.09 182.76,42.92 183.6,42.92 184.92,44.24 191.59,44.24 v1(193.04,45.69)
  BOTTOM w0.254: v1(31.21,13.68) 31.22,13.68 31.47,13.43 RN2701.1
BKLT_CTRL: length 12.2
  TOP w0.114: R5502.1 104.77,95.24 v2(104.27,95.24) 103.33,95.24 102.77,95.8 D5502.3 102.07,97.25 100.3,97.25 RN5502.8 99.11,98.04 99.11,96.71 98.73,96.33 98.73,95.6 98.07,94.94 RN5501.5
BKLT_EN_EC: length 1.9
  TOP w0.114: v1(184.5,41.84) KBC24.67
  BOTTOM w0.114: v1(184.5,41.84) 184.56,41.9 R2422.2
BLON_OUT: length 6.2
  TOP w0.102: RN5501.7 96.57,96.21 97.8,97.44 D5503.3 97.8,98.91 98.22,99.33 v2(98.37,99.33) RN5502.6
BLON_OUT_C: length 6.4
  TOP w0.102: v1(94.37,96.1) 94.37,95.53 v2(93.9,95.06) 95.52,93.44 96.47,93.44 96.57,93.55 RN5501.2
  BOTTOM w0.102: v1(94.37,96.1) 94.36,96.1 94.36,95.95 93.95,95.54 LCD1.31
BLUETOOTH_EN: length 77.8
  TOP w0.102: v1(126.03,23.33) v2(125.49,23.54)
  L4 w0.102: v1(166.89,35.82) 166.89,35.2 162.92,31.23 160.25,31.23 159.79,30.78 158.95,30.78 158.01,29.84 151.99,29.84 151.22,30.6 149.71,30.6 149.05,29.94 148.51,29.4 147.57,29.4 146.32,28.16 145.95,28.16 142.9,28.16 141.16,26.41 139.43,26.41 139.08,26.76 131.56,26.76 128.87,24.07 126.77,24.07 v1(126.03,23.33) 125.51,23.33 125.36,23.48 124.77,24.07 122.11,24.07 121.78,24.4 116.69,24.4 116.51,24.22 116.02,24.22 115.59,24.65 115.59,27.42 114.88,28.14 114.88,33.11 115.25,33.48 115.25,34.34 v1(114.74,34.84)
  BOTTOM w0.089: 114.6,35.2 114.52,35.28 114.52,36.03 114.67,36.18 114.71,36.31 114.71,36.48 114.66,36.67 114.66,36.83 CPU1.AB2
  BOTTOM w0.102: IOBD1.47 167.04,35.71 166.93,35.82 v1(166.89,35.82) ; v1(114.74,34.84) 114.74,35.05 114.6,35.2 ; R2042.2 124.99,23.94 125.53,23.41 125.96,23.41 v1(126.03,23.33)
BOARD_ID: length 8.4
  TOP w0.102: KBC24.111 190.41,29.31 190.37,29.34 190.37,32.15 189.57,32.94 v1(189.17,32.94)
  BOTTOM w0.102: v2(188.57,32.81) 188.7,32.94 v1(189.17,32.94) 189.57,32.94 C2408.1 R2444.1 R2443.2
BOARD_ID1: length 6.1
  BOTTOM w0.102: CPU1.AC1 113.76,36.7 113.76,34.74 113.31,34.28 v2(113.31,33.75) 113.31,33.67 113.71,33.27 113.71,32.9 112.94,32.12 R2009.1 112.9,32.1 R2010.2
BOARD_ID2: length 14.7
  BOTTOM w0.089: 114.74,35.41 114.7,35.46 114.7,35.92 114.89,36.11 114.89,36.5 114.84,36.69 114.84,37.13 114.45,37.52 CPU1.AB3
  BOTTOM w0.102: 114.74,35.41 115.29,34.87 115.29,33.51 115.31,33.48 115.31,32.96 116.05,32.23 116.05,30.88 115.81,30.65 114.32,30.65 v2(114.04,30.37) 113.63,30.37 112.64,29.38 R2005.2 112.09,28.84 111.61,28.36 111.1,28.36 110.74,28.72 R2008.1
BOOST_MON: length 60.7
  TOP w0.254: v1(142.09,29.15) 142.06,29.13 141.45,29.13 141.04,29.53 PG4414.2 v2(140,30.09)
  L6 w0.254: v1(142.09,29.15) 142.09,29.22 143.27,30.41 146.85,30.41 147.93,29.33 148.67,29.33 149.42,30.07 151.8,30.07 151.83,30.04 156.61,30.04 156.82,29.84 158.51,29.84 159.38,30.7 159.8,30.7 160.2,30.29 161.74,30.29 162.14,30.7 163.2,30.7 165.66,28.24 165.66,27.31 166.72,26.26 178.03,26.26 179.93,24.35 181.47,24.35 181.83,24.71 185.82,24.71 186.23,25.11 v1(191.57,25.11)
  BOTTOM w0.254: PC4424.1 142.09,29.53 v1(142.09,29.15) ; R2426.1 191.57,25.98 v1(191.57,25.11)
BOT_MUX_N: length 96.6
  TOP w0.102: v2(14.55,95.8) 14.2,95.44 v1(14.2,95.22) 13.97,94.99 13.97,94.48 13.74,94.25 ED3805.1 8.88,94.25 8.7,94.07 7.12,94.07 USB1.B7 ; v1(43.91,38.52) 44.17,38.78 44.67,38.78 45.21,38.24 45.21,38.09 45,37.88 EL3802.2
  L6 w0.127: v1(43.91,38.52) 43.64,38.24 43.46,38.24 43.28,38.42 43.28,38.83 43.14,38.97 42.79,38.97 39.63,42.12 39.63,44.88 38.94,45.58 38.94,49.6 34.72,53.81 30.48,53.81 29.72,54.58 27.99,54.58 25.61,56.95 25.61,61.09 26.45,61.93 26.45,63.74 25.91,64.28 25.91,67.18 26.8,68.07 26.8,69.92 25.17,71.54 19,71.54 18.33,72.22 16.68,72.22 15.24,73.66 15.24,83.76 14.39,84.61 14.39,89.94 17.84,93.4 17.84,95.18 17.17,95.85 14.27,95.85 14.04,95.62 14.04,95.37 v1(14.2,95.22)
BOT_MUX_N_L: length 3
  TOP w0.102: EL3802.1 45,36.37 45.26,36.11 45.26,35.82 45.14,35.7 44.6,35.7 44.15,36.15 43.84,36.15 43.75,36.23 U3802.9
BOT_MUX_P: length 96.3
  TOP w0.102: v1(43.92,39.23) 44.14,39.01 44.77,39.01 45.44,38.33 45.44,38.09 45.68,37.85 EL3802.3 ; v2(13.26,95.83) 13.51,95.57 v1(13.51,95.24) 13.75,95 13.75,94.76 ED3805.2 13.51,94.66 13.33,94.48 8.79,94.48 8.61,94.3 7.17,94.3 USB1.B6
  L6 w0.127: v1(13.51,95.24) 13.78,95.5 13.78,95.73 14.16,96.12 17.28,96.12 18.11,95.29 18.11,93.29 14.65,89.83 14.65,84.72 15.5,83.87 15.5,73.77 16.79,72.48 18.44,72.48 19.11,71.81 25.28,71.81 27.06,70.03 27.06,67.96 26.17,67.07 26.17,64.39 26.72,63.85 26.72,61.82 25.88,60.98 25.88,57.07 28.1,54.84 29.83,54.84 30.59,54.08 34.83,54.08 39.2,49.71 39.2,45.69 39.9,44.99 39.9,42.23 42.9,39.23 43.27,39.23 v1(43.92,39.23)
BOT_MUX_P_L: length 3.5
  TOP w0.102: U3802.8 43.78,35.83 43.86,35.92 44.06,35.92 44.5,35.47 44.88,35.47 ; 44.88,35.47 45.24,35.47 45.49,35.72 45.49,36.19 45.68,36.37 EL3802.4 ; 44.88,35.47 v2(44.88,35.32)
BREATH_LED#: length 2.2
  TOP w0.127: TP2405.1 181.27,40.64 KBC24.70
BT+:
  vias: v1(154.2,36.11) v1(154.23,35.4) v1(154.25,37.96) v1(154.25,37.23) v1(154.53,31.16) v1(155.22,31.18) v1(155.82,29.38) v1(155.9,31.18) v1(156.45,29.38) v1(157.78,30.57) v2(153.47,38.83)
C1_TP: length 5.5
  BOTTOM w0.102: CPU1.C1 125.3,36.05 126.22,36.05 126.45,36.28 126.45,36.48 126.78,36.81 128,36.81 128.4,37.1 129.1,37.5 129.34,37.74 TP2308.1
CAD_SNK: length 2.6
  TOP w0.127: R3818.2 29.97,61.84 v2(30.3,61.84) 30.73,61.84 31.22,61.35 U3801.29
CAM_EN#: length 3.3
  TOP w0.102: v1(126.66,37.51) 126.82,37.35 TP403.1
  BOTTOM w0.102: v1(126.66,37.51) 126.86,37.71 126.86,38.63 126.25,39.24 CPU1.A6
CAP_LED: length 68.3
  TOP w0.508: v1(120.85,20.31) 121.78,20.31 123.13,18.97 125.3,18.97 126.72,20.39 130.44,20.39 131.33,19.5 134.42,19.5 134.82,19.91 v1(134.82,20.26)
  L3 w0.508: v1(134.82,20.26) 134.82,19.87 135.45,19.24 143.68,19.24 145.36,20.92 148.75,20.92 149.22,20.45 v1(149.22,20.26)
  L6 w0.508: v1(103.58,12.54) 104.44,13.4 110.03,13.4 110.46,12.97 113.83,12.97 114.7,13.85 114.7,14.08 118.45,17.82 119.49,17.82 120.34,18.68 120.34,19.8 v1(120.85,20.31)
  BOTTOM w0.508: KB1.4 92.92,8.76 v1(93.6,9.44) 93.65,9.49 93.65,10.13 94.23,10.71 102.36,10.71 103.58,11.93 v1(103.58,12.54) ; R6513.2 149.22,20.67 v1(149.22,20.26)
CAP_LED#: length 9.8
  TOP w0.127: v2(181.61,31.28) 181.76,31.44 KBC24.93 184.21,31.44 185.18,32.42 185.18,33.3 186.06,34.18 v1(187.12,34.18)
  BOTTOM w0.127: v1(187.12,34.18) 186.76,34.18 186.75,34.17 Q2414.S 186.29,33.82 186.43,33.67 186.43,32.88 R2489.1
CAP_LED#_R: length 73.4
  TOP w0.508: v2(145.67,22.7) 145.67,23.38 v1(145.69,23.38)
  L3 w0.508: v1(188.57,35.69) 188.53,35.65 188.53,34.57 189.97,33.13 189.97,29.26 190.55,28.68 190.55,27.4 190.12,26.97 190.12,24.65 191.49,23.28 191.49,18.94 189.86,17.31 189.86,17.24 v1(189.41,16.79)
  L6 w0.508: v1(189.41,16.79) 188.83,17.36 187.49,17.36 185.21,19.65 184.46,19.65 183.15,20.95 180.89,20.95 177.81,24.03 176.43,24.03 175.86,24.6 174.17,24.6 173.49,23.92 160.49,23.92 158.63,25.79 147.88,25.79 145.69,23.6 v1(145.69,23.38)
  BOTTOM w0.508: Q2414.D 188.18,36.07 v1(188.57,35.69) ; R6512.1 145.64,23.33 v1(145.69,23.38)
CAP_LED_Q: length 1.4
  BOTTOM w0.508: R6513.1 148.47,21.78 Q6505.C
CAP_LED_R#: length 2.5
  BOTTOM w0.127: R6512.2 146.31,21.16 Q6505.B
CBN: length 3.1
  TOP w0.203: HDA27.23 21.95,20.74 21.64,21.05 v1(21.64,21.17)
  TOP w0.254: v2(21.64,21.73) v1(21.64,21.17)
  BOTTOM w0.254: C2703.2 21.63,21.17 v1(21.64,21.17)
CBP: length 3.5
  TOP w0.203: HDA27.22 22.35,21.1 v1(22.27,21.17)
  TOP w0.254: v1(22.27,21.17) 22.27,21.86 22.68,22.27 v2(22.68,22.42)
  BOTTOM w0.254: C2703.1 22.27,21.86 v1(22.27,21.17)
CCG4_FLIP#: length 33.4
  TOP w0.127: R3855.1 39.11,41.11 40.26,41.11 R3856.1 40.36,41.62 v1(39.24,41.62) ; U3701.5 26.09,42.76 25.83,43.02 24.05,43.02 23.29,43.78 23.29,45.18 23.8,45.69 23.8,46.68 24.81,47.69 24.81,48.26 25.87,49.32 v2(26.87,49.32) 27.13,49.32 v1(27.38,49.06)
  BOTTOM w0.127: v1(39.24,41.62) 39.67,42.05 39.67,45.05 39.26,45.46 37.29,45.46 36.04,46.7 29.74,46.7 v1(27.38,49.06)
CCG4_I2C_SCL: length 227.7
  TOP w0.089: U3701.17 30.8,37.62 v2(32.18,36.24) 32.63,36.24 v1(32.76,36.11) RN3702.3
  L3 w0.127: v1(32.76,36.11) 32.73,36.08 32.73,33.43 33.31,32.85 33.31,29.42 34.34,28.39 35,28.39 38.44,24.94 38.44,14.53 40.14,12.83 44.05,12.83 50.2,6.68 51.81,6.68 53.46,5.03 67.91,5.03 68.6,5.73 99.95,5.73 103.19,8.97 117.64,8.97 120.58,6.03 120.81,5.8 120.81,5 122.7,3.1 129.79,3.1 131.63,1.26 142.63,1.26 144.4,3.03 153.39,3.03 v1(153.76,3.4)
  L4 w0.127: v1(153.76,3.4) 154.16,3.8 154.16,3.83 155.03,4.7 156.63,4.7 158.8,6.87 192.62,6.87 195.93,10.18 195.93,12.64 197.15,13.86 197.15,28.41 197.67,28.93 197.67,31.23 195.5,33.4 195.5,34.18 194.94,34.74 v1(194.84,34.74)
  BOTTOM w0.089: Q2605.6 195.39,35.16 194.99,34.76 194.87,34.76 v1(194.84,34.74)
CCG4_I2C_SDA: length 227.8
  TOP w0.089: U3701.16 30.3,38.93 30.53,38.7 30.53,37.1 v2(30.91,36.72) 32.18,35.45 32.18,35.06 32.48,34.76 RN3702.4 32.76,34.49 v1(33.17,34.08)
  L3 w0.127: v1(33.17,34.08) 33.69,33.56 33.69,29.58 34.5,28.77 35.16,28.77 38.82,25.1 38.82,14.69 40.3,13.21 44.21,13.21 50.35,7.07 51.97,7.07 53.62,5.41 67.75,5.41 68.45,6.11 99.79,6.11 103.03,9.35 117.8,9.35 120.96,6.19 121.19,5.96 121.19,5.16 122.86,3.48 129.95,3.48 131.79,1.64 142.47,1.64 144.24,3.41 153.1,3.41 v1(153.72,4.03)
  L4 w0.127: v1(153.72,4.03) 154.77,5.08 156.48,5.08 158.64,7.25 189.99,7.25 196.77,14.03 196.77,28.57 197.29,29.09 197.29,31.07 194.36,34 194.36,35.57 194.92,36.14 196.19,36.14 v1(196.65,36.59)
  BOTTOM w0.089: v1(196.65,36.59) 196.69,36.63 Q2605.3
CCG4_ID_1: length 6.3
  TOP w0.102: v2(37.67,40.28) 37.08,40.86 R3750.2 36.57,40.73 R3751.1 35.61,41.29 34.07,41.29 33.73,41.63 33.73,42.1 33.57,42.26 U3701.25
CCG4_ID_2: length 4.5
  TOP w0.102: U3701.27 33.97,43.26 34.26,42.97 v2(34.69,42.97) 35.26,42.97 36.09,42.13 R3753.1 R3752.2
CCG4_OVP_TRIP_P1: length 76.8
  TOP w0.127: U3701.14 29.3,38.38 v1(29.13,38.22) ; v1(44.17,92.02) 43.29,92.89 42.68,92.89 v2(41.48,91.69) 41.4,91.61 PR4341.2 41.4,90.31 41.76,89.96 43.62,89.96 43.8,89.77 43.8,89.08 43.56,88.84 PQ4311.2
  L4 w0.127: v1(44.17,92.02) 44.17,90.69 43.83,90.35 43.83,79.43 42.75,78.35 42.75,70.65 41.51,69.42 41.51,53.17 41.98,52.7 41.98,50.05 43.04,49 43.04,44.1 41.83,42.89 37.51,42.89 37.01,43.4 34.31,43.4 v1(29.13,38.22)
CCG4_OVP_TRIP_P1_G: length 6
  TOP w0.127: v2(42.95,92.5) 42.39,91.94 PR4340.1 42.26,91.43 PR4341.1 PC4313.2 43.06,90.8 43.06,90.48 43.25,90.29 43.64,90.29 44.14,89.79 44.14,89.09 44.4,88.84 PQ4309.2
CFG: length 2.4
  TOP w0.102: U5701.23 v1(19.86,66.84)
  BOTTOM w0.102: R5420.2 18.34,66.84 v2(19.23,66.84) v1(19.86,66.84)
CFG0: length 4.7
  TOP w0.089: TP618.1 126.03,76.19 v1(126.52,76.67)
  BOTTOM w0.089: CPU1.E68 123.97,74.61 124.56,75.19 124.56,75.42 125.2,76.06 125.63,76.06 125.78,76.22 126.01,76.22 126.31,76.52 126.36,76.52 v1(126.52,76.67)
CFG1: length 4.5
  TOP w0.089: TP619.1 126.31,77.31 v1(126.54,77.31)
  BOTTOM w0.089: v1(126.54,77.31) 126.54,77.28 126.9,76.92 126.9,75.85 125.95,74.9 125.7,74.9 125.42,74.61 CPU1.B67
CFG2: length 5.5
  TOP w0.089: v1(127.53,75.02) 127.25,75.3 TP620.1
  BOTTOM w0.089: CPU1.D65 124.28,73.58 124.98,73.58 125.25,73.84 125.25,74 125.42,74.18 125.46,74.2 125.72,74.2 125.78,74.17 126.16,74.17 126.27,74.28 126.8,74.28 127.15,74.63 127.15,74.64 v1(127.53,75.02)
CFG3: length 10
  TOP w0.114: v1(126.67,74.69) 126.44,74.46 TP621.1
  BOTTOM w0.089: v1(126.67,74.69) 126.57,74.6 126.31,74.6 126.07,74.35 125.81,74.35 125.72,74.39 125.45,74.39 125.36,74.35 125.16,74.35 125.03,74.4 124.82,74.4 CPU1.D67
  BOTTOM w0.114: R604.1 130.38,78.17 127.79,78.17 127.3,77.69 127.3,75.61 126.67,74.97 v1(126.67,74.69)
CFG4: length 4.5
  TOP w0.089: v1(124.28,78.25) 123.85,77.82 TP622.1 122.81,77.82 R605.1
  BOTTOM w0.089: v1(124.28,78.25) 123.77,77.74 123.77,76.85 123.61,76.69 CPU1.E70
CFG5: length 4.9
  TOP w0.089: v1(125.45,78.27) 125.42,78.25 125.42,78.15 125.02,77.74 125.02,77.72 TP623.1
  BOTTOM w0.089: v1(125.45,78.27) 125.42,78.27 125.02,77.87 125.02,77.26 125.12,77.16 125.12,76.9 124.94,76.72 124.53,76.72 124.33,76.52 124.33,76.27 124.5,76.1 124.5,75.75 124.22,75.47 CPU1.C68
CFG6: length 3.2
  TOP w0.089: v1(124.31,77.61) 124.31,77.56 123.77,77.03 TP624.1
  BOTTOM w0.089: v1(124.31,77.61) 124.46,77.46 124.46,76.9 124.28,76.72 124.2,76.72 123.98,76.5 123.98,76.14 CPU1.D68
CFG7: length 1.5
  TOP w0.089: v1(125.41,75.25) 124.76,74.61 TP625.1
  BOTTOM w0.089: CPU1.C67 124.96,75.25 v1(125.41,75.25)
CFG8: length 5
  TOP w0.089: TP626.1 123.44,80.2 v1(124.18,80.2)
  BOTTOM w0.089: v1(124.18,80.2) 124.18,80 123.06,78.88 123.06,76.73 122.98,76.65 CPU1.F71
CFG9: length 5.7
  TOP w0.089: TP627.1 121.05,80.61 v1(121.66,80)
  BOTTOM w0.089: v1(121.66,80) 121.66,79.98 122.1,79.54 122.1,76.04 122.26,75.88 CPU1.G69
CFG10: length 5.4
  TOP w0.089: v1(124.31,79.54) 123.8,79.54 TP628.1
  BOTTOM w0.089: CPU1.F70 122.92,76 123.29,76.37 123.29,76.8 123.24,76.85 123.24,78.48 v1(124.31,79.54)
CFG11: length 7.7
  TOP w0.089: v1(124.15,80.84) TP629.1
  BOTTOM w0.089: v1(124.15,80.84) 123.42,80.1 123.42,79.77 122.81,79.16 122.81,76.81 122.65,76.66 122.65,75.51 122.26,75.11 CPU1.G68
CFG12: length 4.3
  TOP w0.089: TP630.1 122.25,79.26 v1(121.66,78.68)
  BOTTOM w0.089: CPU1.H70 121.49,76.25 121.49,76.43 121.44,76.61 121.44,76.79 121.47,76.9 121.47,77.17 121.44,77.24 121.44,77.31 121.26,77.49 121.26,78.25 121.66,78.66 v1(121.66,78.68)
CFG13: length 4.8
  TOP w0.089: v1(121.64,80.74) 121.87,80.97 TP631.1
  BOTTOM w0.089: v1(121.64,80.74) 121.64,80.69 122.39,79.94 122.39,79.51 122.36,79.48 CPU1.G71
CFG14: length 5.3
  TOP w0.089: v1(121.66,79.34) 121.36,79.34 TP632.1
  BOTTOM w0.089: CPU1.H69 121.31,75.78 121.31,76.4 121.26,76.59 121.26,76.82 121.29,76.93 121.29,77.13 121.26,77.2 121.26,77.24 121.03,77.46 121.03,78.71 v1(121.66,79.34)
CFG15: length 6.4
  TOP w0.089: TP633.1 121.64,82.03 v1(121.64,81.42)
  BOTTOM w0.089: CPU1.G70 122.36,76.61 122.63,76.88 122.63,79.26 122.86,79.49 122.86,80.2 v1(121.64,81.42)
CFG16: length 1.8
  TOP w0.089: v1(122.95,72.56) 123.49,72.03 TP634.1
  BOTTOM w0.089: v1(122.95,72.56) 122.95,72.29 123.21,72.03 CPU1.E63
CFG17: length 1.3
  TOP w0.089: v1(122.25,71.54) 122.25,71.7 TP635.1
  BOTTOM w0.089: CPU1.F63 122.6,71.9 v1(122.25,71.54)
CFG18: length 1.5
  TOP w0.089: TP636.1 123.37,74.92 v1(123.37,74.69)
  BOTTOM w0.089: CPU1.E66 123.25,74.58 v1(123.37,74.69)
CFG19: length 1.5
  TOP w0.089: TP637.1 122.71,75.28 v1(122.71,74.69)
  BOTTOM w0.089: CPU1.F66 122.6,74.59 v1(122.71,74.69)
CFG_RCOMP: length 0.6
  BOTTOM w0.356: CPU1.E60 123.19,70.01 v1(122.87,69.69)
  vias: v2(121.46,69.05)
CHARGER_SRC:
  vias: v2(142.92,48.99) v3(140.46,47.39) v3(141.4,48.25) v3(141.4,47.41) v3(142.26,48.23) v3(142.26,47.34)
CHG_AMBER_LED#: length 132.9
  TOP w0.127: Q2416.3 181.61,46.59 181.61,46.22 181.27,45.88 179.09,45.88 179.07,45.9 v1(179.01,45.9)
  L4 w0.127: v1(84.18,12.72) 84.17,12.73 84.17,13.55 84.94,14.33 91.41,14.33 92.74,13 99.13,13 100.44,11.69 108.55,11.69 110.78,13.92 113.58,13.92 114.44,14.79 117.81,14.79 117.98,14.62 120.43,14.62 120.99,15.18 122.99,15.18 124.07,16.27 127.24,16.27 127.78,16.81 129.01,16.81 129.33,17.13 131.34,17.13 133.17,18.95 145.9,18.95 146.16,19.21 146.16,19.69 147.56,21.09 149.06,21.09 153.71,25.73 158.6,25.73 160.22,24.11 163.9,24.11 164.53,24.74 164.53,25.49 165.27,26.23 166.62,26.23 168.16,27.77 168.16,29.21 173.83,34.88 173.83,37.16 176.39,39.72 176.39,42.64 177.43,43.68 177.43,44.37 178.96,45.9 v1(179.01,45.9)
  BOTTOM w0.127: v1(84.18,12.72) 75.61,12.72 v2(74.37,13.96) R6403.1
CHG_AMBER_LED_R#: length 3
  BOTTOM w0.508: v2(72.31,14.27) R6403.2 71.51,15.16 Q6402.B
CLK_PCIE_LAN_REQ#: length 15.5
  TOP w0.102: RN1813.3 95.57,37.86 96.61,38.89 v2(97.25,38.89) 101.43,38.89 v1(102.13,38.19)
  L6 w0.102: v1(102.13,38.19) 102.13,38.75 104.22,40.84 106.88,40.84 v1(107.38,41.34)
  BOTTOM w0.102: v1(107.38,41.34) 107.05,41.02 CPU1.AT8
CLK_PCIE_NVME_REQ#: length 163.2
  TOP w0.102: v1(106.73,41.34) 106.57,41.34 106.08,40.85 102.6,40.85 102.45,41 100.82,41 100.23,40.4 v2(97.86,40.4) 95.43,40.4 95.17,40.14 RN1812.3
  L3 w0.102: v1(106.73,41.34) 107.13,40.94 110.01,40.94 110.51,40.44 110.51,35.64 109.06,34.19 109.06,33.48 109.03,33.45 109.03,31.16 109.95,30.23 109.95,28.95 112.93,25.98 112.93,21.43 114.1,20.26 114.1,16.82 119.24,11.68 119.94,11.68 123.42,8.2 v1(123.42,8.17)
  L6 w0.102: v1(123.42,8.17) 123.54,8.17 128.32,3.39 128.62,3.39 131.16,0.85 155.32,0.85 157.3,2.84 157.3,4.38 159.23,6.32 195.12,6.32 195.96,7.15 197,7.15 197.46,7.61 197.46,8.32 196.77,9.01 196.77,15.61 198.65,17.49 198.65,20.77 199.21,21.33 201.67,21.33 201.98,21.02 201.98,16.37 v1(201.95,16.35)
  BOTTOM w0.102: SSD1.52 201.7,18.69 201.45,18.43 201.45,16.86 v1(201.95,16.35) ; CPU1.AU8 106.4,41.01 v1(106.73,41.34)
CLK_PCIE_PEG_REQ#: length 176.5
  TOP w0.102: RN1812.4 99.22,40.81 v2(99.53,41.13) 100.14,41.74 102.14,41.74 102.32,41.56 105.12,41.56 105.33,41.77 106.89,41.77 107.35,42.23 v1(107.39,42.23)
  L4 w0.102: v1(172.01,95.22) 172.07,95.15 172.07,89.57 171.55,89.04 170.99,89.04 170.74,88.79 170.74,86.68 171.65,85.77 175.34,85.77 176.45,84.65 176.45,82.48 175.67,81.7 175.67,79.7 174.85,78.88 174.78,78.88 172.71,76.81 172.71,75.13 173.02,74.81 173.02,72.1 170.1,69.18 170.1,61 169.21,60.11 169.21,47.01 169.23,46.99 169.23,35.69 162.89,29.35 161.07,29.35 159.66,27.94 153.35,27.94 152.14,26.74 148.31,26.74 146.83,25.26 145.22,25.26 143.85,23.89 143.3,23.89 143.13,24.06 132.67,24.06 130.29,21.69 129.68,21.07 128.04,21.07 127.73,20.77 124.77,20.77 124.46,21.07 122.16,21.07 121.5,21.73 121.14,21.73 121.02,21.85 120.81,22.06 117.65,22.06 117.44,21.85 117.3,21.71 114.17,21.71 112.27,23.61 111.91,23.61 111.4,23.11 110.93,23.11 110.09,22.27 109.67,22.27 109.39,21.99 107.37,21.99 106.46,22.9 106.46,24.49 105.79,25.16 105.79,26.85 106.22,27.28 106.22,34.16 105.83,34.56 105.83,35.29 106.06,35.52 106.06,38.74 105.71,39.08 105.71,39.79 105.45,40.06 105.45,40.39 105.69,40.63 105.81,40.63 106.26,41.08 106.26,41.43 106.58,41.75 106.91,41.75 v1(107.39,42.23)
  BOTTOM w0.102: v1(107.39,42.23) 107.7,41.92 CPU1.AR10 ; GPU1.A2 172.45,94.77 v1(172.01,95.22)
CLK_PCIE_SD_REQ#: length 13.4
  TOP w0.102: v1(106.73,42.26) 106.56,42.09 105.37,42.09 105.11,42.35 104.74,42.35 104.32,41.93 v2(103.17,41.93) 99.54,41.93 98.74,41.13 95.79,41.13 95.3,41.62 R1827.2
  BOTTOM w0.102: CPU1.AT10 107.05,41.93 v1(106.73,42.26)
CLK_PCIE_TBT_REQ#: length 13.4
  TOP w0.102: RN1813.4 95.76,38.53 96.48,39.25 101.23,39.25 102.11,40.12 v2(103.07,40.12) 105.21,40.12 105.5,39.83 106.12,39.83 v1(106.7,40.41)
  BOTTOM w0.102: v1(106.7,40.41) 106.7,40.37 106.4,40.07 CPU1.AU7
CLK_PCIE_VGA: length 141.7
  TOP w0.102: v2(176.35,92.47) 175.84,92.98 v1(175.84,93.11)
  L3 w0.14: v1(175.84,93.11) 175.84,93.44 175.57,93.72 174.88,93.72 174.1,94.5 169.71,94.5 168.58,93.36 168.58,88.87 167.73,88.02 167.73,47.2 166.95,46.42 166.95,37.48 163.86,34.4 163.28,34.4 161.83,32.95 154.11,32.95 153.28,32.12 152.6,32.12 151.85,31.37 148.42,31.37 146.72,29.67 139.63,29.67 138.47,30.84 138.47,32.39 139.18,33.1 139.18,36.38 139,36.57 139,38.38 138.23,39.16 138.23,40.17 137.54,40.86 136.29,42.1 136.29,43.96 135.2,45.05 135.2,46.39 134.31,47.29 131.87,47.29 130.91,48.25 130.91,53.51 130.49,53.93 130.49,54.11 129.73,54.87 129.73,58 129.5,58.22 129.09,58.22 128.67,58.64 128.67,58.95 128.28,59.34 127.21,59.34 126.57,59.99 124.23,59.99 124.1,59.86 124.1,59.45 123.98,59.33 123.7,59.33 123.57,59.45 123.57,60.37 v1(123.65,60.44)
  BOTTOM w0.102: v1(123.65,60.44) 123.95,60.44 124.38,60.87 CPU1.C42 ; GPU1.B8 176.05,92.9 v1(175.84,93.11)
CLK_PCIE_VGA#: length 141.6
  TOP w0.102: v1(176.48,93.18) 176.22,93.44 v2(176.22,93.74)
  L3 w0.14: v1(176.48,93.18) 175.68,93.98 174.99,93.98 174.21,94.77 169.6,94.77 168.31,93.47 168.31,88.98 167.46,88.13 167.46,47.31 166.69,46.53 166.69,37.6 163.75,34.66 163.17,34.66 161.72,33.22 154,33.22 153.17,32.39 152.49,32.39 151.74,31.64 148.31,31.64 146.61,29.94 139.75,29.94 138.73,30.95 138.73,32.27 139.45,32.99 139.45,36.49 139.27,36.68 139.27,38.49 138.49,39.27 138.49,40.28 137.88,40.89 137.88,40.89 136.56,42.21 136.56,44.07 135.47,45.17 135.47,46.5 134.42,47.55 131.98,47.55 131.18,48.36 131.18,53.62 130.76,54.04 130.76,54.22 130,54.98 130,58.11 129.61,58.49 129.2,58.49 128.94,58.75 128.94,59.06 128.4,59.61 127.32,59.61 126.68,60.25 124.53,60.25 124.49,60.3 123.91,60.88 123.24,60.88 v1(122.91,60.54)
  BOTTOM w0.102: CPU1.D42 123.51,60.87 123.19,60.54 v1(122.91,60.54) ; GPU1.B9 176.65,93.01 v1(176.48,93.18)
CLK_PCIE_WLAN_REQ#: length 107
  TOP w0.102: R1828.2 95.81,39.34 v2(95.98,39.51) 101.14,39.51 102.25,40.62 106.22,40.62 106.41,40.8 106.99,40.8 v1(107.34,40.46) ; v1(167.68,37.28) 167.28,36.87 167.28,36.46 167.61,36.13 167.61,33.28 165.65,31.32 164.24,31.32 v1(163.05,30.13)
  L4 w0.102: v1(107.34,40.46) 106.99,40.8 106.54,40.8 106.28,40.55 106.28,39.94 106.15,39.81 106.15,38.92 106.67,38.4 106.67,22.98 107.46,22.19 109.31,22.19 109.59,22.47 110.01,22.47 110.84,23.31 111.27,23.31 111.77,23.82 112.39,23.82 113.64,22.57 114.66,22.57 114.76,22.47 114.76,22.47 115.14,22.09 117.39,22.09 117.57,22.27 120.89,22.27 121.22,21.94 121.59,21.94 122.25,21.28 124.55,21.28 124.85,20.97 127.65,20.97 127.95,21.28 129.59,21.28 132.58,24.27 143.21,24.27 143.39,24.09 143.76,24.09 145.14,25.46 146.75,25.46 148.76,27.47 149.31,27.47 149.44,27.6 152.72,27.6 153.27,28.15 159.58,28.15 160.99,29.56 162.48,29.56 v1(163.05,30.13)
  BOTTOM w0.102: IOBD1.44 167.75,37.21 v1(167.68,37.28) ; CPU1.AT7 107.05,40.11 107.34,40.39 v1(107.34,40.46)
CLK_TP_SIO: length 111.7
  TOP w0.089: v1(184.41,37.75) 184.31,37.75 184,37.44 KBC24.78 ; v2(169.11,19.03) v1(169.88,19.03) ; RN6501.4 124.59,2.64 124.46,2.51 124.46,2.08 124.71,1.83 125.1,1.83 v1(125.53,2.25) 125.81,2.25 126.23,2.67 RN6502.2 126.26,3.29 EC6501.1
  L4 w0.127: v1(169.88,19.03) 169.44,19.03 167.68,17.28 164.01,17.28 163.25,16.51 160.85,16.51 159.1,14.76 157.86,14.76 156.35,13.25 154.8,13.25 152.58,11.03 151.67,11.03 150.04,9.4 144.74,9.4 143.58,8.25 143.58,3.62 142.44,2.47 131.08,2.47 130.37,3.18 126.17,3.18 125.53,2.53 v1(125.53,2.25)
  BOTTOM w0.089: v1(184.41,37.75) 183.96,37.75 182.83,36.62 181.8,36.62 181.37,36.19 181.37,33.65 182.68,32.35 182.68,28.43 183.19,27.91 183.19,24.84 180.78,22.43 180.78,18.25 181.34,17.69 181.34,15.74 182,15.08 182.89,15.08 183.23,14.74 183.23,12.78 181.6,11.15 174.28,11.15 173.79,11.65 173.79,12.67 170.17,16.28 170.17,18.74 v1(169.88,19.03)
CLKRUN#: length 108.3
  TOP w0.089: R2476.1 167.1,44.57 167.72,44.57 168.09,44.2 168.09,39.02 167.26,38.2 167.26,37.46 167.01,37.2 167.01,36.35 167.31,36.05 167.31,34.23 v2(166.98,33.89) 164.68,31.59 163.15,31.59 161.33,29.77 v1(161.33,28.47)
  L4 w0.127: v1(105.81,42.49) 105.81,41.93 105.24,41.36 105.24,39.93 105.28,39.9 105.28,39.18 104.54,38.45 104.54,35.5 105.85,34.19 105.85,27.44 105.42,27 105.42,25.01 106.09,24.34 106.09,22.74 107.28,21.56 107.72,21.56 v1(107.72,21.55) 107.75,21.55 107.91,21.39 110.04,21.39 110.33,21.69 110.33,21.99 111.08,22.74 111.93,22.74 113.33,21.34 117.45,21.34 117.81,21.7 120.65,21.7 120.99,21.37 121.35,21.37 122.01,20.71 124.31,20.71 124.61,20.4 127.88,20.4 128.19,20.7 129.83,20.7 130.45,21.32 130.52,21.39 132.8,23.68 134.1,23.68 134.66,23.12 143.6,23.12 145.38,24.89 146.41,24.89 146.41,24.89 146.98,24.89 148.46,26.37 152.3,26.37 153.5,27.58 160.44,27.58 v1(161.33,28.47)
  BOTTOM w0.089: R1818.1 106.88,24.71 106.88,22.42 107.72,21.58 v1(107.72,21.55) ; v1(105.81,42.49) 105.73,42.57 CPU1.AW11
CLKRUN#_EC: length 25.3
  TOP w0.089: R2477.2 166.14,46.4 166.29,46.55 v2(166.52,46.55) 166.75,46.55 166.9,46.4 R2476.2 167.49,45.05 v1(167.56,45.05) ; v1(183.67,43.72) 184.13,43.25 184.98,43.25 185.21,43.48 KBC24.63
  L6 w0.102: v1(167.56,45.05) 167.74,45.05 168.22,44.57 170.23,44.57 173.25,47.59 180.24,47.59 183.67,44.16 v1(183.67,43.72)
CMP_VIN0: length 5.4
  TOP w0.114: KBC24.20 199.9,37.84 v1(199.95,37.79)
  BOTTOM w0.114: R2470.2 199.29,41.11 199.29,39.79 v2(199.52,39.56) 200.42,38.66 200.42,38.26 v1(199.95,37.79)
CMP_VIN0_R: length 135
  L3 w0.102: v1(123.29,34.83) 122.82,34.36 122.82,33.76 121.23,32.17 121.23,30.28 121.41,30.1 121.41,26.46 122.15,25.72 122.15,24.67 126.72,20.1 128.1,20.1 128.95,19.25 v1(128.98,19.25) ; v1(154.76,7.48) 154.79,7.46 154.79,6.76 155.2,6.34 156.4,6.34 158.19,8.13 169.28,8.13 171.76,10.61 179.76,10.61 180.02,10.88 182.98,10.88 187.11,15 187.11,17.91 185.22,19.81 185.22,23.14 186.22,24.15 186.49,24.41 186.49,26.62 186.69,26.83 186.69,27.97 185.61,29.05 185.61,30.38 186.74,32.89 187.88,34.03 187.88,35.92 187.92,35.95 187.92,39.02 v1(187.89,39.06)
  L6 w0.102: v1(154.76,7.48) 154.28,7 152.59,7 151.7,7.89 151.26,7.89 148.84,10.32 143.32,10.32 143.06,10.58 141.76,11.88 139.29,11.88 138.96,12.21 138.96,13.06 136.52,15.5 132.73,15.5 v1(128.98,19.25) ; v1(196.24,40.83) 195.1,39.69 188.52,39.69 v1(187.89,39.06)
  BOTTOM w0.114: v1(196.24,40.83) 196.39,40.99 C2613.1 196.59,41.67 v2(197.44,41.67) 197.86,41.67 R2470.1 ; R2609.2 R2608.2 122.22,29.48 122.22,30.58 122.22,30.59 122.22,31.84 122.76,32.38 R2610.1 123.11,32.38 C2612.1 123.9,34.22 v1(123.29,34.83)
CMP_VIN1: length 6.5
  TOP w0.102: KBC24.21 199.64,38.24 199.87,38.47 v1(199.9,38.47)
  BOTTOM w0.102: v2(195.71,39.31) 196.14,39.74 196.44,39.74 196.9,40.2 PR2455.2 197.71,39.49 C2436.1 198.58,39.49 R2456.1 198.85,39.51 v1(199.9,38.47)
CMP_VOUT0: length 61.9
  TOP w0.114: v1(147.5,23.38) v2(147.5,23.97) ; KBC24.85 184.09,34.64 184.44,34.3 184.44,33.65 v1(184.43,33.65)
  L6 w0.102: v1(182.55,20.03) 180.9,20.03 177.54,23.38 176,23.38 175.89,23.28 159.1,23.28 158.62,23.75 150.75,23.75 150.71,23.79 147.89,23.79 147.5,23.4 v1(147.5,23.38)
  BOTTOM w0.114: R2607.2 144.17,19.9 R2602.2 R2615.2 145.62,19.85 146.87,19.85 147.12,20.1 147.12,21.94 147.5,22.32 v1(147.5,23.38) ; v1(182.55,20.03) 182.55,20.04 182.68,20.16 182.68,23.32 183.9,24.55 183.9,28.21 183.39,28.72 183.39,32.6 v1(184.43,33.65)
CODEC_BITCLK_R: length 3.3
  TOP w0.089: R2720.2 28.93,18.41 v2(28.88,18.36) 28.62,18.1 27.94,18.1 27.55,17.71 HDA27.8
CODEC_SDOUT_R: length 3.8
  TOP w0.089: HDA27.11 27.5,18.91 28.55,19.96 v2(29.21,19.96) R2719.2
COMBO-GPI: length 4
  TOP w0.102: TP2702.1 29.39,13.55 29.11,13.83 28.34,13.83 27.89,14.29 27.89,14.93 27.5,15.31 HDA27.2
CPU_A16_TP: length 2.7
  TOP w0.102: TP1902.1 101.22,40.25 v1(101.57,40.61)
  BOTTOM w0.102: CPU1.BB9 103.13,41.29 103.13,41.29 102.61,41.29 101.93,40.61 v1(101.57,40.61)
CPU_D4_TP: length 5.2
  TOP w0.102: TP1804.1 116.89,33.04 v1(117.02,32.91)
  BOTTOM w0.102: CPU1.V1 116.41,36.69 116.41,35.91 116.28,35.78 116.28,35.77 116.28,35.77 116.28,35.28 116.28,35.28 116.28,33.36 116.73,32.91 v1(117.02,32.91)
CPU_D5_TP: length 5
  TOP w0.102: TP1805.1 117.19,33.54 v1(116.99,33.54)
  BOTTOM w0.102: v1(116.99,33.54) 116.47,34.06 116.47,35.69 116.7,35.92 116.7,37.06 116.44,37.32 CPU1.V2
CPU_DP1_CTRL_CLK: length 206.9
  TOP w0.089: v1(33.55,65.17) 33.29,65.17 32.64,64.51 32.12,64.51 30.69,63.08 v2(30.28,63.08) 30.17,63.19 27.05,63.19 26.17,62.31 24.7,62.31 24.29,62.72 U5701.38
  L3 w0.127: v1(119.48,43.34) 119.48,43.38 119.07,43.79 119.07,46.02 119.83,46.78 120.26,46.78 121.03,47.55 121.03,49.23 122.26,50.46 124,50.46 124.84,51.3 124.84,55.87 126.63,57.66 126.63,58.25 v1(127.1,58.72)
  L6 w0.102: v1(127.1,58.72) 127.1,58.82 127.46,59.17 127.46,60.32 130.63,63.49 130.68,63.49 131.11,63.92 131.11,63.97 133.32,66.18 133.32,72.13 133.93,72.74 133.93,72.92 136,74.99 136,86.82 131.52,91.3 130.89,91.3 122.83,99.36 122.83,100.03 122.06,100.8 105.83,100.8 v1(104.99,99.97) 104.8,99.97 104.04,100.73 91.77,100.73 88.9,103.6 79.37,103.6 77.04,101.26 48.82,101.26 47.29,99.74 47.03,99.74 46.05,98.76 46.05,98.69 43.1,95.75 42.87,95.75 42.42,95.29 42.42,94.33 41.5,93.41 40.49,93.41 39.42,92.34 39.42,86.91 36.12,83.61 36.12,73.78 33.15,70.81 33.15,65.57 v1(33.55,65.17)
  BOTTOM w0.089: CPU1.L13 119.81,43.68 v1(119.48,43.34) ; v1(104.99,99.97) 105.21,99.75 105.21,99.03 106.43,97.8 RN801.3
CPU_DP1_CTRL_DATA: length 206.2
  TOP w0.089: U5701.39 24.69,62.83 24.94,62.58 26.06,62.58 26.94,63.45 30.68,63.45 32.09,64.86 v2(32.43,64.86) 32.61,64.86 v1(33.58,65.83)
  L3 w0.127: v1(119.47,42.69) 119.47,42.77 119.07,43.17 119.07,43.38 118.85,43.6 118.85,46.11 119.75,47.01 120.18,47.01 120.8,47.63 120.8,49.31 122.17,50.68 123.34,50.68 124,51.34 124,53.67 124.59,54.26 124.59,56.07 126.41,57.9 v1(126.41,58.69)
  L6 w0.102: v1(33.58,65.83) 33.45,65.96 33.45,70.68 36.42,73.65 36.42,80.52 36.52,80.63 36.87,80.63 36.98,80.73 36.98,81.13 36.87,81.24 36.52,81.24 36.42,81.34 36.42,81.74 36.52,81.84 36.87,81.84 36.98,81.95 36.98,82.35 36.87,82.45 36.52,82.45 36.42,82.56 36.42,83.48 39.72,86.78 39.72,92.21 40.62,93.11 41.63,93.11 42.72,94.2 42.72,95.17 43,95.44 43.23,95.44 46.35,98.57 46.35,98.63 47.16,99.43 47.47,99.43 48.99,100.96 77.21,100.96 79.55,103.29 88.77,103.29 91.64,100.42 103.91,100.42 104.8,99.53 105.22,99.53 v1(105.62,99.94) 106.18,100.5 121.94,100.5 122.53,99.91 122.53,99.24 130.88,90.89 131.5,90.89 135.7,86.69 135.7,75.14 133.6,73.04 133.6,72.84 133.02,72.25 133.02,66.31 130.81,64.1 130.81,64.05 130.56,63.8 130.5,63.8 127.13,60.42 127.13,59.63 126.41,58.92 v1(126.41,58.69)
  BOTTOM w0.089: RN801.4 106.14,98.47 105.47,99.14 105.47,99.79 v1(105.62,99.94) ; v1(119.47,42.69) 119.8,43.03 CPU1.L12
CPU_DP1_HPD: length 175.2
  TOP w0.102: v1(123.04,29.38) 123.04,29.08 v2(122.12,28.17) 121.89,27.93 121.89,25.59 121.59,25.29 119.32,25.29 116.68,27.93 116,27.93 115.75,27.68 115.75,27.18 115.35,26.78 112.31,26.78 111.6,27.49 108.95,27.49 107.26,25.8 105.99,25.8 104.97,24.78 100.32,24.78 v1(99.82,25.28) ; U5701.3 26.69,64.84 v1(26.72,64.86)
  L3 w0.102: v1(99.82,25.28) 99.64,25.11 99.64,21.53 98.88,20.77 97.08,20.77 95.43,19.12 83.01,19.12 80.19,16.3 79,16.3 78.39,16.91 74.04,16.91 73.77,17.17 65.94,17.17 65.04,18.08 57.63,18.08 56.41,16.86 53.11,16.86 44.03,25.93 44.03,28.12 42.95,29.2 42.95,33.24 42.75,33.44 42.75,35.07 43.41,35.73 43.41,42.23 45.9,44.72 45.9,61.74 46.1,61.94 v1(46.1,63.42)
  L4 w0.102: v1(123.04,29.38) 122.55,29.86 122.55,31.21 121.27,32.49 121.27,37.05 123.26,39.04 123.26,39.68 122.91,40.02 120.72,40.02 119.91,40.83 119.91,40.94 v1(119.47,41.38)
  BOTTOM w0.102: v1(26.72,64.86) 28.37,66.51 41.58,66.51 44.68,63.42 v1(46.1,63.42) ; CPU1.L9 119.63,41.38 v1(119.47,41.38)
CPU_DP2_CTRL_CLK: length 17.1
  TOP w0.089: v2(119.73,25.68) 119.2,26.21 119.2,26.28 v1(119.13,26.35)
  L4 w0.127: v1(118.51,40.07) 118.6,39.98 118.6,38.69 118.87,38.42 118.87,33.07 118.44,32.64 118.44,30.25 118.74,29.94 118.74,26.81 119.13,26.43 v1(119.13,26.35)
  BOTTOM w0.089: v1(119.13,26.35) 119.7,25.78 RN803.3 ; v1(118.51,40.07) 118.81,39.77 CPU1.N7
CPU_DP2_CTRL_DATA: length 17.9
  TOP w0.089: v2(120.34,27.02) 120.34,26.95 v1(119.76,26.37)
  L4 w0.127: v1(118.47,40.73) 118.92,40.28 118.92,38.93 119.09,38.76 119.09,32.62 118.82,32.35 118.82,30.41 119.12,30.1 119.12,27 v1(119.76,26.37)
  BOTTOM w0.089: RN803.4 120.37,25.75 v1(119.76,26.37) ; v1(118.47,40.73) 118.78,40.43 CPU1.N8
CPU_DP2_HPD: length 18.6
  L4 w0.127: v1(119.46,40.1) 120.53,39.03 121.69,39.03 121.93,38.79 121.93,38 121.07,37.14 121.07,32.35 122.26,31.16 122.26,27.11 v1(122.35,27.02)
  BOTTOM w0.127: CPU1.L7 119.78,39.77 v1(119.46,40.1) ; v2(122.6,26.46) 122.35,26.71 v1(122.35,27.02) 122.2,26.86 R804.1 121.49,27.07 R803.2
CPU_DP_HPD: length 9.1
  TOP w0.127: R3849.2 40.94,64.74 40.75,64.55 38.53,64.55 38.21,64.86 v2(38.15,64.86) 36.87,64.86 36.49,64.48 36.49,63.89 36,63.4 34.66,63.4 34.3,63.05 U3801.23
CPU_DP_HPD_MUX: length 2.9
  TOP w0.102: U3701.18 31.3,38.14 v2(31.55,37.89) 32.13,37.3 R3729.1
CPU_DP_HPD_R: length 187.9
  TOP w0.127: v1(38.4,37.56) 38.35,37.51 34.87,37.51 34.59,37.23 R3725.2 33.45,37.23 R3729.2 ; v1(41.96,63.85) 42.14,64.02 R3849.1 v2(42.14,65.65)
  L3 w0.127: v1(41.96,63.85) 42.75,63.85 44.25,62.35 44.25,50.26 40.18,46.19 40.18,45.05 v1(39.04,43.91) ; v1(102.67,12.51) 102.37,12.81 101.05,12.81 95.5,7.26 69.66,7.26 69.38,7.54 55.14,7.54 47.22,15.46 43.25,15.46 41.01,17.71 41.01,23.99 40.56,24.43 40.56,28.96 38.03,31.48 38.03,37.19 v1(38.4,37.56)
  L4 w0.127: v1(20.22,59.5) 21.29,59.5 22.72,58.07 22.72,54.92 25.55,52.09 26.47,52.09 27.65,50.91 27.65,50.45 28.41,49.69 31.52,49.69 31.8,49.97 35.44,49.97 35.86,50.38 36.75,50.38 37.45,49.69 37.45,45.5 v1(39.04,43.91)
  L6 w0.127: v1(102.67,12.51) 104.38,14.23 109.31,14.23 110.15,15.07 113.98,15.07 117.28,18.36 117.28,18.79 117.28,20.79 120.21,23.72 120.21,26.57 v1(119.77,27)
  BOTTOM w0.127: Q5704.5 18.62,60.27 18.87,60.01 19.71,60.01 v1(20.22,59.5) ; R804.2 120.62,27.07 119.84,27.07 v1(119.77,27) ; v1(39.04,43.91) 38.4,43.27 v1(38.4,37.56)
CPU_POPIRCOMP: length 18
  TOP w0.203: 104.21,44.85 104.7,44.85 105.31,45.46 106.92,45.46 v1(107.38,45.92)
  TOP w0.508: 104.21,44.85 103.48,44.85 101.78,46.55 v2(98.3,46.55) 97.53,46.55 96.01,48.07 96.01,50.13 94.69,51.45 R412.1
  BOTTOM w0.305: v1(107.38,45.92) 107.38,45.78 CPU1.AT16
CPU_RXN_C_DGPU_TXN0: length 143.4
  TOP w0.102: v2(173.07,85.94) 173.07,86.43 v1(173,86.5)
  L3 w0.14: v1(173,86.5) 173,85.86 173.57,85.29 176.01,85.29 176.97,84.33 176.97,82.96 175.7,81.7 175.7,78.23 176.79,77.14 176.79,74.65 172.88,70.74 172.88,63.14 173.49,62.53 173.49,35.32 172.66,34.49 172.17,34 172.17,32.2 169.43,29.45 169.43,24.83 162.26,17.66 151.95,17.66 150.64,18.97 148.02,18.97 147.33,18.28 134.39,18.28 130.86,21.81 130.86,24.18 129.55,25.48 127.25,25.48 125.21,27.52 125.21,31.24 126.4,32.42 126.4,34.63 125.36,35.67 125.36,36.58 124.89,37.05 124.89,40.83 123.4,42.32 122.74,42.32 122.32,42.74 122,42.74 v1(121.57,43.17)
  BOTTOM w0.102: v1(121.57,43.17) 121.24,43.5 CPU1.H13 ; v1(173,86.5) 173.11,86.61 173.11,87.36 GPU1.E3
CPU_RXN_C_DGPU_TXN1: length 142.9
  TOP w0.102: v1(174.95,86.5) 174.95,86.43 v2(175.51,85.87)
  L3 w0.14: v1(121.57,42.26) 122,41.83 123.01,41.83 124.15,40.69 124.15,40.09 123.48,39.43 123.48,37.19 124.5,36.17 124.5,27.19 127.27,24.43 129.24,24.43 129.97,23.69 129.97,21.68 134.08,17.57 147.72,17.57 148.41,18.26 150.08,18.26 151.39,16.95 162.57,16.95 172.19,26.57 172.19,31.21 172.88,31.9 172.88,33.71 174.2,35.03 174.2,62.83 173.61,63.42 173.61,70.46 177.51,74.36 177.51,77.43 176.66,78.29 176.66,79.44 177.84,80.62 177.84,84.84 176.66,86.02 175.43,86.02 175.14,86.32 175.14,86.32 v1(174.95,86.5)
  BOTTOM w0.102: v1(174.95,86.5) 174.86,86.6 174.86,87.4 GPU1.E6 ; v1(121.57,42.26) 121.89,42.57 CPU1.G11
CPU_RXN_C_DGPU_TXN2: length 134.3
  TOP w0.102: v1(173.73,84.55) 173.73,84.29 v2(173.43,83.99)
  L3 w0.14: v1(121.59,44.97) 122.07,44.49 125.21,44.49 125.58,44.85 127.07,44.85 128.82,43.1 128.82,37.27 128.32,36.77 128.32,33.93 131.72,30.53 131.72,25.76 136.16,21.31 143.82,21.31 144.97,22.47 152.3,22.47 154.73,20.04 157.92,20.04 158.52,19.44 162.02,19.44 167.98,25.39 167.98,30.21 170.72,32.95 170.72,33.17 170.72,34.57 172.07,35.91 172.07,61.94 171.41,62.6 171.41,78.41 173.56,80.57 173.56,84.38 v1(173.73,84.55)
  BOTTOM w0.102: v1(173.73,84.55) 173.73,84.76 174.25,85.28 GPU1.F5 ; CPU1.H16 121.24,45.32 v1(121.59,44.97)
CPU_RXN_C_DGPU_TXN3: length 137.4
  TOP w0.102: v2(175.03,84.45) 175.28,84.19 v1(175.28,83.94)
  L3 w0.14: v1(121.56,44.03) 122.01,43.59 124.15,43.59 125.64,42.09 125.64,37.44 126.29,36.8 127.05,36.8 127.31,36.54 127.31,32.33 125.92,30.94 125.92,27.82 127.55,26.19 130.28,26.19 136.59,19.87 143.42,19.87 145.23,21.68 151.14,21.68 153.49,19.33 157.63,19.33 158.23,18.72 162.32,18.72 168.72,25.12 168.72,29.75 171.46,32.49 171.46,34.3 172.36,35.2 172.78,35.62 172.78,62.24 172.15,62.87 172.15,72.75 173.1,73.71 173.1,74.74 172.6,75.24 172.6,78.53 174.87,80.8 174.87,81.89 175.28,82.3 v1(175.28,83.94)
  BOTTOM w0.102: v1(121.56,44.03) 121.89,44.36 CPU1.G15 ; GPU1.F8 176.05,85.3 175.29,84.54 175.29,83.95 v1(175.28,83.94)
CPU_RXP_C_DGPU_TXP0: length 143.6
  TOP w0.102: v2(171.85,86.05) v1(172.36,86.55)
  L3 w0.14: v1(122.22,43.17) 122.27,43.17 122.85,42.59 123.51,42.59 125.16,40.95 125.16,37.16 125.63,36.69 125.63,35.78 126.67,34.74 126.67,32.31 125.48,31.13 125.48,27.63 127.36,25.75 129.67,25.75 131.13,24.29 131.13,21.92 134.5,18.55 147.22,18.55 147.91,19.24 150.75,19.24 152.06,17.93 162.15,17.93 169.16,24.94 169.16,29.56 171.91,32.31 171.91,34.11 172.55,34.76 173.22,35.43 173.22,62.42 172.62,63.03 172.62,70.85 176.53,74.77 176.53,77.03 175.44,78.12 175.44,81.81 176.71,83.07 176.71,84.22 175.9,85.02 173.46,85.02 172.91,85.57 172.03,85.57 171.91,85.7 171.91,86 172.03,86.13 172.29,86.13 172.46,86.31 172.46,86.45 v1(172.36,86.55)
  BOTTOM w0.102: GPU1.E2 172.45,86.65 v1(172.36,86.55) ; CPU1.G13 121.89,43.5 v1(122.22,43.17)
CPU_RXP_C_DGPU_TXP1: length 142.6
  TOP w0.102: v2(174.29,85.89) 174.27,85.92 v1(174.27,86.5)
  L3 w0.14: v1(174.27,86.5) 174.01,86.25 174.01,85.94 174.2,85.75 176.54,85.75 177.57,84.73 177.57,80.73 176.39,79.55 176.39,78.18 177.24,77.32 177.24,74.47 173.34,70.57 173.34,63.31 173.94,62.72 173.94,35.14 172.62,33.82 172.62,32.01 171.92,31.32 171.92,26.68 162.46,17.22 151.5,17.22 150.19,18.53 148.3,18.53 147.61,17.83 134.2,17.83 130.24,21.79 130.24,23.8 129.35,24.69 127.38,24.69 124.77,27.3 124.77,36.28 123.75,37.3 123.75,39.31 124.41,39.98 124.41,40.8 123.12,42.09 122.39,42.09 v1(122.22,42.26)
  BOTTOM w0.102: GPU1.E5 174.34,87.32 174.34,86.58 v1(174.27,86.5) ; v1(122.22,42.26) 122.22,42.51 122.43,42.71 CPU1.F11
CPU_RXP_C_DGPU_TXP2: length 134.7
  TOP w0.102: v2(172.24,84.32) 172.85,84.32 v1(173.1,84.57)
  L3 w0.14: v1(173.1,84.57) 172.95,84.42 172.54,84.42 172.41,84.29 172.41,84.07 172.52,83.97 173.12,83.97 173.3,83.79 173.3,80.68 171.14,78.52 171.14,62.49 171.8,61.83 171.8,36.02 170.46,34.68 170.46,33.06 167.71,30.32 167.71,25.5 161.91,19.7 158.63,19.7 158.03,20.31 154.84,20.31 152.41,22.74 144.86,22.74 143.71,21.58 136.27,21.58 131.98,25.87 131.98,30.64 128.59,34.04 128.59,36.66 129.09,37.16 129.09,43.21 127.18,45.12 125.47,45.12 125.1,44.76 122.41,44.76 v1(122.22,44.95)
  BOTTOM w0.102: GPU1.F4 173.65,85.08 173.15,84.57 v1(173.1,84.57) ; v1(122.22,44.95) 122.22,45.2 121.97,45.46 CPU1.G16
CPU_RXP_C_DGPU_TXP3: length 137.5
  TOP w0.102: v1(174.65,83.94) 174.65,83.38 v2(174.78,83.25)
  L3 w0.14: v1(122.2,44.03) 122.38,43.85 124.26,43.85 125.91,42.2 125.91,37.55 126.4,37.06 127.16,37.06 127.58,36.65 127.58,32.22 126.19,30.83 126.19,27.93 127.66,26.46 130.39,26.46 136.71,20.14 143.31,20.14 145.12,21.95 151.25,21.95 153.6,19.59 157.74,19.59 157.89,19.44 158.34,18.99 162.21,18.99 168.45,25.23 168.45,29.86 171.19,32.6 171.19,34.41 172.25,35.47 172.51,35.73 172.51,62.13 171.88,62.76 171.88,62.98 171.88,62.98 171.88,72.86 172.83,73.82 172.83,74.63 172.34,75.13 172.34,78.64 174.61,80.91 174.61,82 175.02,82.41 175.02,82.72 174.89,82.85 174.37,82.85 174.24,82.97 174.24,83.23 174.37,83.36 174.67,83.36 174.8,83.49 174.8,83.79 v1(174.65,83.94)
  BOTTOM w0.102: CPU1.F15 122.54,44.38 v1(122.2,44.03) ; GPU1.F7 175.45,85.02 175.06,84.63 175.06,84.33 174.85,84.12 174.85,84.07 174.72,83.94 v1(174.65,83.94)
CPVDD: length 1.1
  TOP w0.203: HDA27.21 22.75,21.01 v1(22.91,21.17)
  vias: v2(24.79,20.79)
CPVEE: length 3.1
  TOP w0.203: v1(20.88,21.2) 20.57,21.51 v2(20.29,21.51) ; 21.2,20.14 HDA27.24
  TOP w0.305: v1(20.88,21.2) 20.88,20.46 21.2,20.14
  BOTTOM w0.305: v1(20.88,21.2) 20.83,21.15 C2704.2
CSI2_COMP: length 2.5
  TOP w0.508: R1501.1 123.75,42.94 v1(123.52,43.16) v2(124.72,43.16)
  BOTTOM w0.254: CPU1.E13 123.19,43.52 123.52,43.19 v1(123.52,43.16)
CTL1: length 5.3
  BOTTOM w0.102: U3401.6 19.74,46.2 18.72,45.18 v2(18.72,44.8) 18.72,42.84 R3401.2
CTL2: length 6.2
  BOTTOM w0.102: U3401.7 19.35,46.7 v2(18.85,46.19) 18.08,45.43 18.08,42.69 R3406.2
CTL3: length 2.5
  BOTTOM w0.102: U3401.8 19.62,47.2 v2(19.48,47.34) 19.35,47.46 R3402.2
DAT_TP_SIO: length 112.1
  TOP w0.089: RN6502.1 125.58,2.94 v1(124.89,2.25) ; v1(124.03,2.2) 123.75,2.2 122.99,2.96 EC6502.1 123.57,3.45 123.62,3.39 123.86,3.39 RN6501.3 ; KBC24.79 183.98,37.04 184.24,37.3 184.85,37.3 185.01,37.14 v1(185.02,37.14) ; v1(169.06,18.03) 169.06,17.49 v2(169.09,17.47)
  L4 w0.127: v1(169.06,18.03) 168.97,18.03 167.84,16.9 164.17,16.9 163.41,16.13 161.01,16.13 159.26,14.38 158.02,14.38 156.51,12.87 154.96,12.87 152.74,10.65 151.83,10.65 150.2,9.02 144.9,9.02 143.97,8.09 143.97,3.46 142.59,2.09 130.92,2.09 130.29,2.72 126.26,2.72 125.97,2.44 125.97,2.07 125.71,1.81 125.34,1.81 124.9,2.25 v1(124.89,2.25) 124.84,2.2 v1(124.03,2.2)
  BOTTOM w0.089: v1(185.02,37.14) 185.01,37.14 184.85,37.3 183.88,37.3 182.94,36.36 181.91,36.36 181.64,36.08 181.64,33.76 182.94,32.46 182.94,28.54 183.46,28.02 183.46,24.73 181.05,22.32 181.05,18.36 181.6,17.8 181.6,15.85 182.11,15.35 183,15.35 183.49,14.85 183.49,12.67 181.71,10.89 174.17,10.89 173.52,11.54 173.52,12.56 169.9,16.17 169.9,17.18 v1(169.06,18.03)
DBC_EN_R: length 7.2
  TOP w0.102: R5503.1 99.36,95.24 v1(99.36,95.93) 99.36,96.13 v2(99.67,96.44)
  BOTTOM w0.102: v1(99.36,95.93) 98.95,95.51 94.63,95.51 94.45,95.33 LCD1.32
DBC_PANEL_EN: length 153.8
  TOP w0.102: v1(101.29,96) 101.29,95.62 100.71,95.04 R5503.2
  L3 w0.102: v1(85.85,17.65) 86.63,18.43 96.03,18.43 96.5,18.9 98.24,18.9 100.33,20.99 100.33,24.4 102.12,26.19 104.22,26.19 105.69,27.65 105.69,32.17 104.98,32.88 104.98,33.54 105.31,33.87 105.31,34.56 106.24,35.49 v1(107.36,35.49)
  L4 w0.102: v1(84.76,91.36) 85.52,92.12 86.49,92.12 87.86,93.49 93.57,93.49 94.51,94.42 99.71,94.42 v1(101.29,96) ; v1(107.36,35.49) 107.37,35.49 107.89,34.98 107.89,33.18 107.24,32.53 107.24,23.63 v1(107.46,23.41)
  BOTTOM w0.102: v1(84.76,91.36) 84.97,91.14 84.97,89.37 84.99,89.36 84.99,58.15 84.97,58.13 84.97,51.3 81.79,48.11 81.79,25.24 83.19,23.84 83.19,20.61 85.85,17.95 v1(85.85,17.65) ; CPU1.AM5 109.44,38.84 109.44,37.57 109.25,37.38 109.06,37.38 108.75,37.07 108.75,36.57 108.67,36.49 108.67,36.02 108.14,35.49 v1(107.36,35.49) ; v1(107.46,23.41) 107.93,23.41 108.28,23.05 v2(108.28,21.81) 108.25,21.78 R2043.2
DC_IN_OK: length 282.3
  TOP w0.254: v1(32.69,72.86) 33.32,72.23 33.32,71.09 33.04,70.81 PQ4310.5 ; PR4314.1 25.14,73.8 v2(25.73,74.39) v1(26.19,74.85) ; PR4311.2 31.11,90.12 PD4309.A ; PR4311.2 30.96,89.04 PD4305.A 29.36,89.04 28.98,88.66 v1(28.37,88.66) ; PR4311.2 PR4315.2 ; PQ4306.G 33.72,77.44 v1(34.47,77.44) ; v1(175.44,54.75) R2475.1
  L3 w0.254: v1(35.96,94.2) 35.96,94.1 34.85,92.98 34.85,89.37 35.76,88.46 35.76,78.73 v1(34.47,77.44)
  L4 w0.254: v1(26.19,74.85) 28.98,77.64 28.98,88.05 v1(28.37,88.66) ; v1(123.98,111.04) 123.98,111.26 124.98,112.26 162.98,112.26 166.52,108.72 166.52,106.42 167.94,105 167.94,104.7 168.39,104.26 169.91,104.26 171.07,103.1 171.07,101.54 174.8,97.81 174.91,97.81 176.43,96.28 178.18,96.28 179.17,95.29 179.17,94.23 179.65,93.75 179.65,89.01 179.43,88.79 179.43,82.97 179.5,82.91 179.5,76.51 179.37,76.39 179.37,70.37 178.97,69.97 178.61,69.97 177.8,69.16 177.44,69.16 176.35,68.06 176.35,63.21 175.56,62.42 175.56,61.48 175.86,61.18 176.36,61.18 177.06,60.48 177.06,56.37 v1(175.44,54.75)
  L6 w0.254: v1(123.98,111.04) 115.65,111.04 115.6,111.09 84.14,111.09 79.58,106.52 79.58,104.76 76.5,101.68 47.43,101.68 45.87,100.12 43.56,100.12 40.28,96.84 39.34,96.84 37.01,94.5 36.27,94.5 v1(35.96,94.2)
  BOTTOM w0.254: PU4307.2 22.58,78.45 22.91,78.78 22.91,79.59 22.63,79.87 21.82,79.87 21.51,80.18 U4302.1 ; U4302.1 22.18,80.63 23.18,81.63 25.5,81.63 27.67,79.46 27.67,76.33 v1(26.19,74.85) 26.95,74.08 27.96,74.08 29.03,73.02 32.54,73.02 v1(32.69,72.86) 33.09,73.27 33.09,76.06 v1(34.47,77.44) ; U4302.1 20.89,80.63 20.45,80.18 PR4335.2
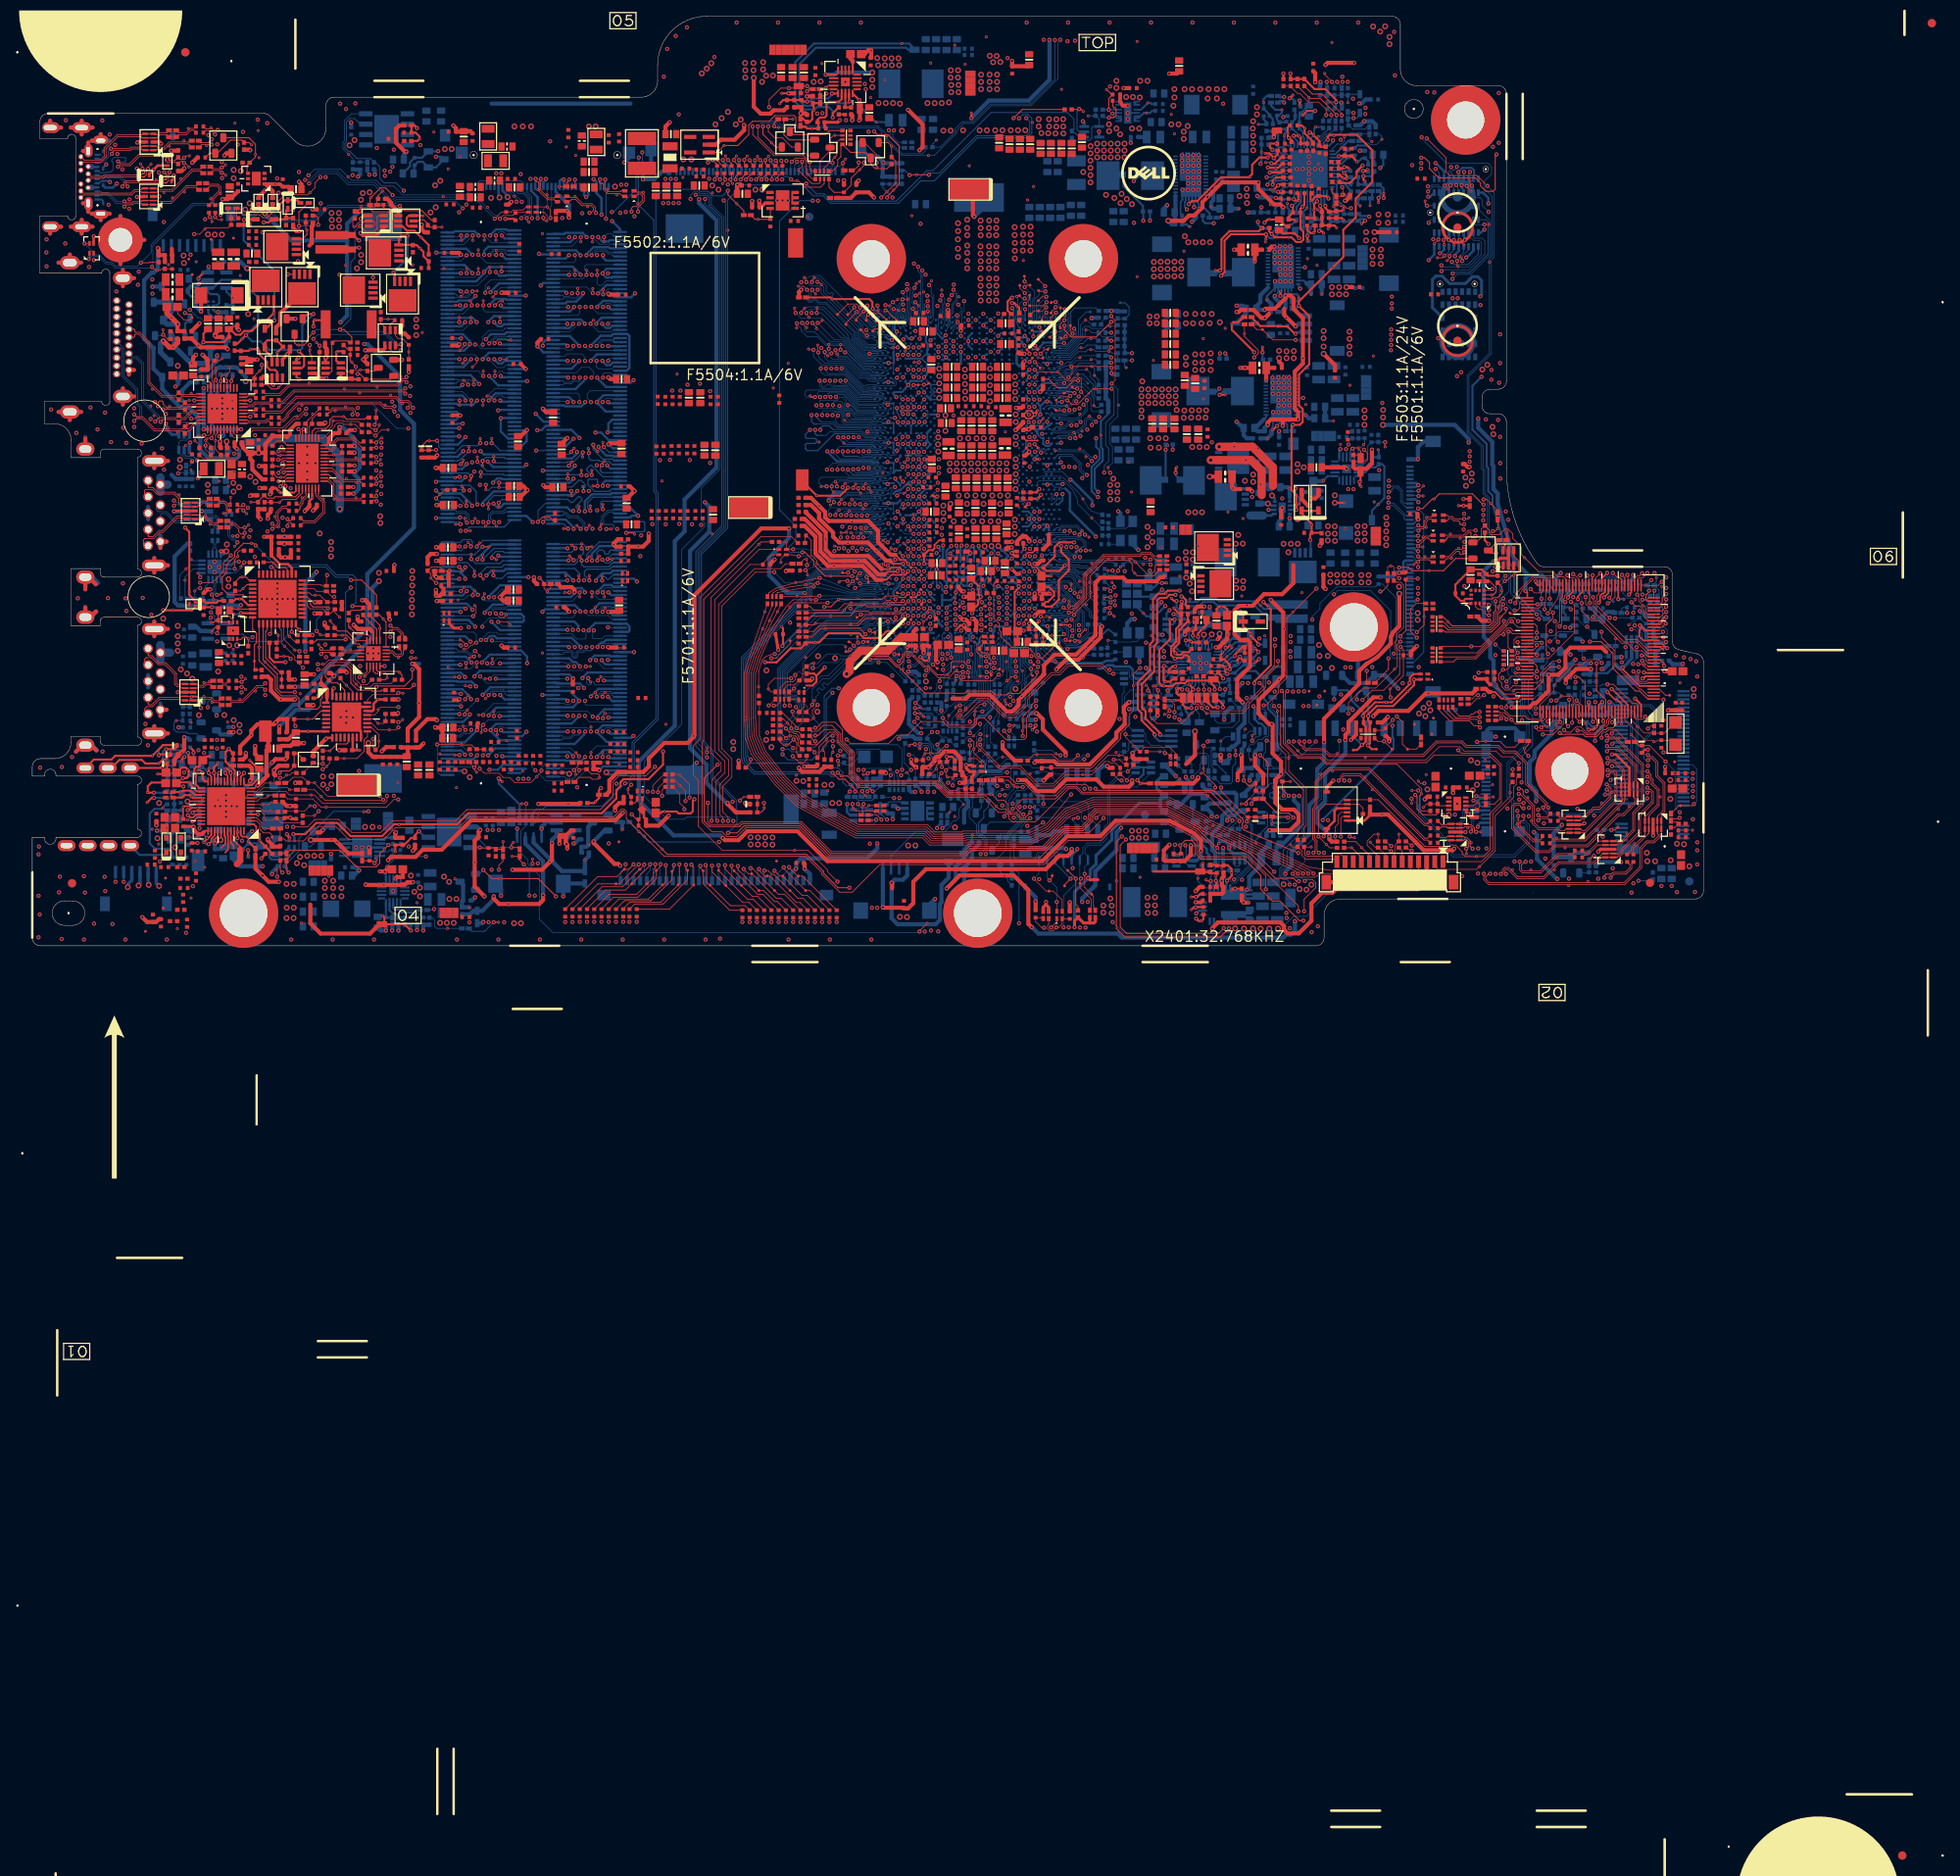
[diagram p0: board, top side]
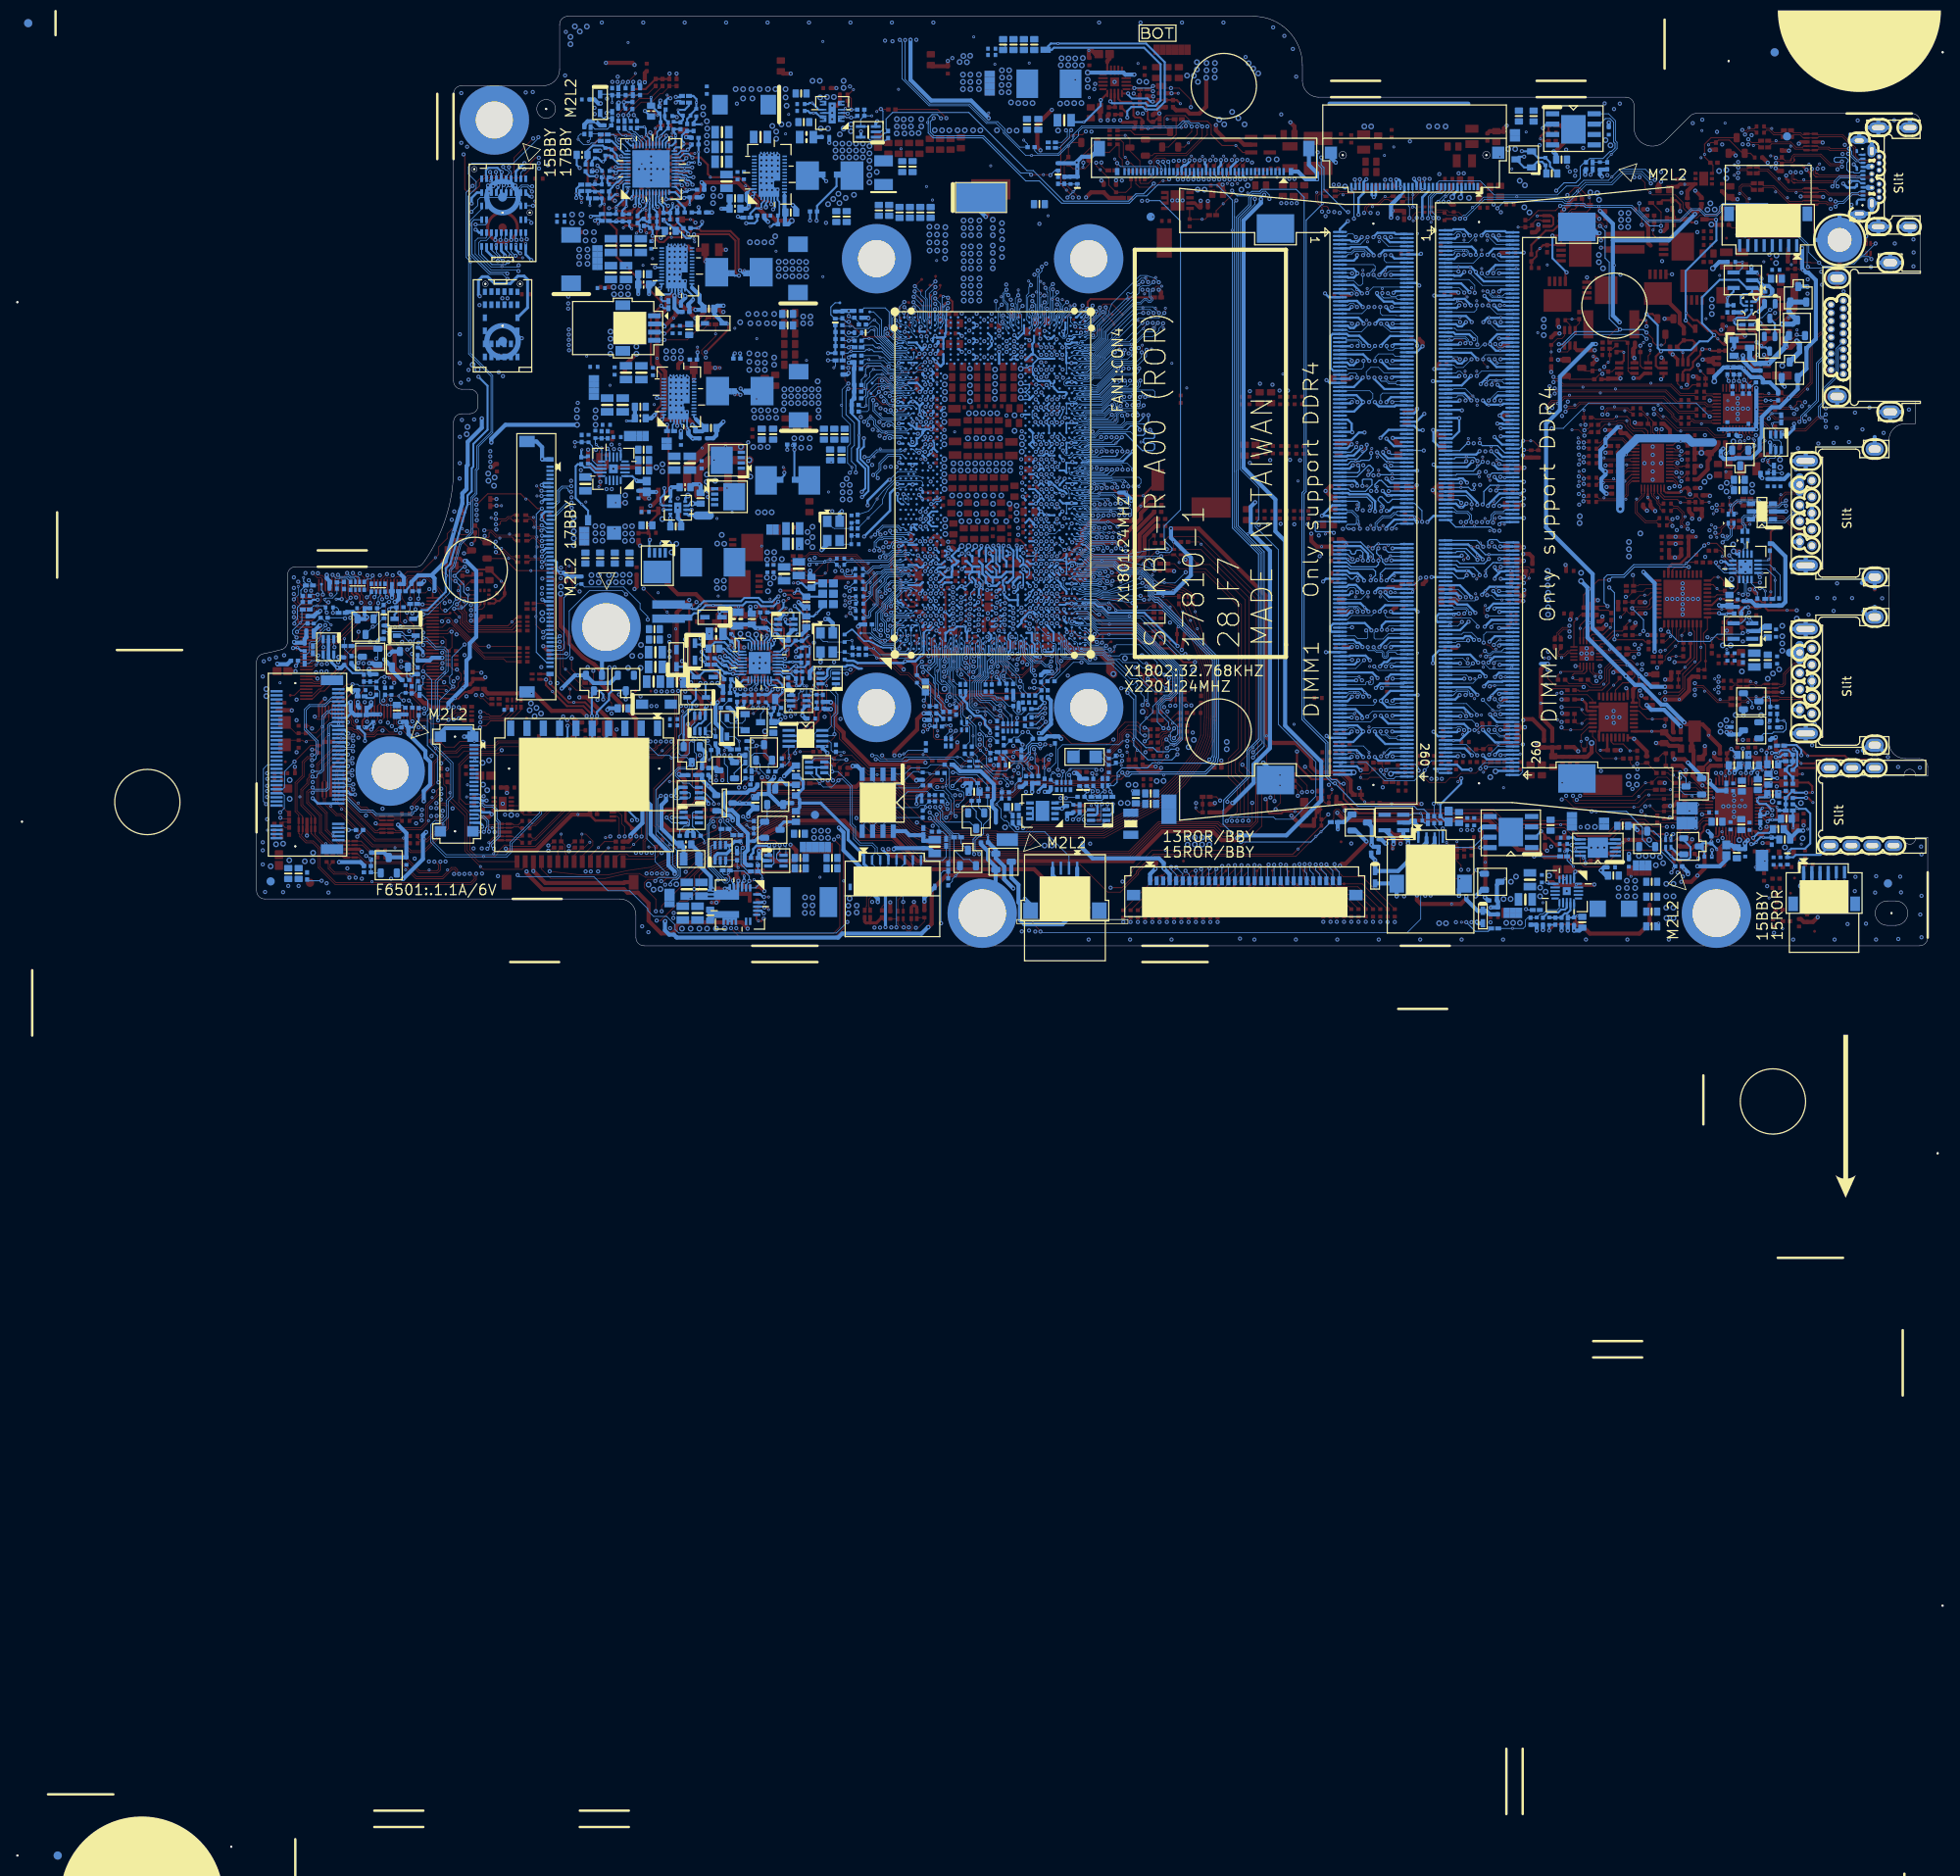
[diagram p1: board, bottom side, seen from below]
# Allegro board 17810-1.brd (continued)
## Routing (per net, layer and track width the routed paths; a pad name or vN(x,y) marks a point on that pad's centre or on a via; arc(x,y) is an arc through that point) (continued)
DC_IN_OK#: length 4.3
  BOTTOM w0.254: PD4308.A 23.49,76.12 23.71,76.33 v2(23.71,76.66) 23.39,76.98 22.17,76.98 21.58,77.57 PU4307.4
DC_IN_OK_R: length 29.4
  TOP w0.254: PQ4308.2 30.02,70.32 29.77,70.58 29.16,70.58 28.78,70.96 28.78,71.54 27.86,72.46 27.86,72.86 v1(27.61,73.12) v2(26.72,73.12) 26.52,72.91 PR4329.1 24.84,72.91 PR4314.2 ; v1(30.35,90.03) 30.35,90.85 30.88,91.37 PD4309.K 32.52,91.37 PD4310.K
  L4 w0.254: v1(27.61,73.12) 27.61,75.33 30.35,78.07 v1(30.35,90.03)
DCBATOUT: length 53.3
  TOP w0.508: 154.58,46.69 154.58,44.47 153.21,43.1 150.99,43.1 149.56,41.67 147.91,41.67 147.37,41.12 147.37,38.19 148.08,37.48 PR4410.2 148.97,37.48 149.27,37.18 149.27,34.23 147.7,32.66 147.7,30.47 v1(148.33,29.84) ; v3(88.44,106.39) 88.44,102.84 89.28,102 90.47,102 90.87,102.4 92.13,102.4 PR4511.1
  L6 w0.508: v1(150.16,91.91) 150.16,92.73 148.44,94.45 148.44,100.75 v1(145.97,103.22)
  BOTTOM w0.508: v1(148.33,29.84) 148.59,29.58 148.59,27.3 147.85,26.56 147.85,24.98 147.3,24.42 147.06,24.42 PR4458.2 ; PR4601.1 150.34,91.73 v1(150.16,91.91)
  vias: v2(50.98,95.22) v2(113.08,110.38) v2(135.43,110.84) v2(146.56,53.15) v2(159.31,110.71) v2(164.39,72.28) v3(36.68,89.81) v3(36.7,88.97) v3(36.73,88.1) v3(37.59,89.81) v3(37.59,88.97) v3(37.62,88.1) v3(49.99,2.81) v3(50.82,2.81) v3(51.66,2.81) v3(59.1,100.42) v3(60.12,100.42) v3(61.14,100.42) v3(87.37,108.2) v3(87.4,107.31) v3(87.4,106.42) v3(88.4,108.2) v3(88.4,107.31) v3(141.25,104.99) v3(141.7,53.13) v3(142.16,104.99) v3(142.54,53.13) v3(143.18,104.99) v3(143.38,53.13) v3(144.07,103.85) v3(144.19,104.99) v3(145.21,104.99) v3(145.21,103.85) v3(146.12,104.99) v3(153.39,49.27) v3(153.97,48.23) v3(154.28,49.27) v3(155.09,59.02) v3(155.09,58.13) v3(155.12,49.27) v3(155.34,6.95) v3(155.85,58.64) v3(156.18,6.87) v3(156.79,7.48) v3(162.91,45.43) v3(162.91,44.54) v3(163.8,45.43) v3(163.8,44.54) v3(164.29,85.34) v3(164.29,84.47) v3(164.29,83.58) v3(165.3,85.34) v3(165.3,84.47) v3(165.3,83.58) v3(175.66,57.4) v3(175.74,56.38) v3(176.43,56.99) v3(176.45,57.88) v3(178.99,63.59) v3(179.09,62.7)
DCBATOUT_+VCCSA:
  vias: v2(150.24,61)
DCBATOUT_CAMERA:
  vias: v2(55.8,90.52) v3(56.23,91.66)
DCBATOUT_LCD:
  vias: v1(77.62,94) v1(78.26,94) v1(78.89,94) v2(79.75,94.17)
DCBATOUT_VCORE:
  vias: v2(161.52,68.7)
DCBATOUT_VCORE1:
  vias: v2(156.31,84.22)
DCIN_EN: length 2.4
  TOP w0.102: U5701.13 24.29,69.12 v1(24.4,69.23) 24.4,69.58 v2(24.59,69.76)
  BOTTOM w0.102: v1(24.4,69.23) 24.56,69.39 R5419.2
DDC_CLK_HDMI: length 30
  TOP w0.089: R5707.2 20.47,61.43 20.26,61.64 20.18,61.64 v2(19.94,61.89) 19.94,62.24 20.27,62.58 v1(21.06,62.58) 21.69,62.58 21.89,62.78 U5701.32
  L6 w0.102: v1(21.06,62.58) 20.68,62.96 18.59,62.96 17.4,64.15 17.4,67.35 13.59,71.16 13.59,78.2 12.27,79.52 11.43,79.52 11.02,79.11 11.02,77.23 10.87,77.08 HDMI1.15
DDC_CLK_PH1: length 7
  TOP w0.089: R5707.1 20.94,59.7 24.11,59.7 24.12,59.7 25.14,59.7 25.35,59.91 v2(25.35,60.19) 25.22,60.32 v1(24.73,60.32)
  BOTTOM w0.089: v1(24.73,60.32) 24.31,60.74 D5701.2
DDC_DATA_HDMI: length 24.7
  TOP w0.089: U5701.33 22.29,62.73 21.97,62.41 v1(21.97,62.22) 21.51,62.22 v2(21.23,61.95) 21.89,61.29 R5706.2
  L6 w0.102: HDMI1.16 13.28,76.15 13.28,71.01 17.09,67.2 17.09,63.95 18.39,62.65 20.29,62.65 20.8,62.15 21.89,62.15 v1(21.97,62.22)
DDC_DATA_PH2: length 3.3
  TOP w0.089: v1(21.23,61.31) 21.23,60.82 R5706.1
  BOTTOM w0.089: D5701.1 21.8,60.74 v1(21.23,61.31) 21.23,61.97 v2(21.39,62.12)
DDCBUF: length 4.3
  TOP w0.102: U5701.14 23.89,69.06 23.77,69.18 v1(23.77,69.23) 23.77,69.91 24.19,70.34 v2(24.19,70.92)
  BOTTOM w0.102: R5417.2 23.77,69.99 v1(23.77,69.23) 23.93,69.07 R5418.2
DDR4_DRAMRST#: length 112
  TOP w0.127: v1(49.5,60.77) 49.35,60.77 49.31,60.74 ED1217.1 ED1302.1 47.72,61.26 48.36,61.89 v2(48.66,61.89) v1(49.6,61.89) ; v1(46.58,33.85) 46.58,32.78 45.64,31.84 42.3,31.84 v1(42.17,31.72) ; R504.2 87.2,18.25 v1(86.74,17.8)
  L3 w0.127: v1(42.17,31.72) 42.17,29.32 43.56,27.93 43.56,25.78 52.95,16.39 63.65,16.39 64.79,15.24 81.13,15.24 82.72,16.83 86.13,16.83 86.74,17.44 v1(86.74,17.8) ; v1(49.5,60.77) 48.99,60.27 48.99,36.26 v1(46.58,33.85) ; v1(61.77,60.7) 61.4,61.07 51.45,61.07 50.62,61.89 v1(49.6,61.89)
  BOTTOM w0.127: v1(49.6,61.89) 49.81,61.69 49.81,61.18 50.05,60.94 DM2.108 ; DM1.108 62.74,60.73 62.71,60.7 v1(61.77,60.7)
DDR_VREF_S3: length 1.6
  BOTTOM w0.305: PU5102.6 43.14,13.03 43.36,13.25 PC5116.1
DGPU_HOLD_RST#: length 133.2
  TOP w0.127: RN2009.4 116.1,36.57 EC2002.1 116.1,36.24 116.44,35.89 117.06,35.89 117.27,35.69 117.27,35.26 117.84,34.69 117.94,34.69 v1(117.96,34.67)
  L4 w0.127: v1(174.12,82.39) 173.45,81.73 173.45,80.86 171.33,78.74 171.33,71.86 168.65,69.18 168.65,61.01 167.92,60.27 167.92,46.92 168.25,46.59 168.25,42.1 167.01,40.87 167.01,37.01 165.54,35.55 165.54,34.48 162.74,31.68 160.06,31.68 159.6,31.22 157.17,31.22 156.23,30.28 152.17,30.28 151.41,31.04 148.4,31.04 145.96,28.6 142.72,28.6 140.98,26.86 139.61,26.86 139.27,27.21 131.37,27.21 128.68,24.52 122.29,24.52 121.96,24.85 121.05,24.85 120.26,25.64 118.89,25.64 118.13,26.39 118.13,29.69 117.83,30 117.83,33.47 118.23,33.87 118.23,34.4 v1(117.96,34.67)
  BOTTOM w0.089: v1(117.96,34.67) 117.96,34.67 118.26,34.97 118.26,35.56 117.99,35.84 117.99,36.53 118.02,36.62 118.02,37.22 118.43,37.62 CPU1.P3
  BOTTOM w0.127: v1(174.12,82.39) 174.27,82.54 176.22,82.54 178.46,84.78 178.46,88.71 178.18,88.99 GPU1.D10 ; v2(117.55,33.54) 117.4,33.7 117.4,34.28 117.78,34.67 v1(117.96,34.67)
DGPU_PWR_EN: length 131.8
  TOP w0.102: RN2009.3 116.34,37.89 116.13,37.68 116.13,37.18 115.8,36.85 115.8,36 116.3,35.5 v2(116.3,35.5) 116.32,35.49 v1(116.86,35.49)
  L4 w0.102: v1(174.09,81.73) 174.09,81.14 171.6,78.66 171.6,71.77 169.11,69.28 169.11,61.13 168.16,60.17 168.16,47.02 168.49,46.69 168.49,42 167.25,40.77 167.25,36.91 165.78,35.45 165.78,34.38 162.84,31.44 160.16,31.44 159.7,30.98 158.87,30.98 157.93,30.04 152.07,30.04 151.31,30.8 148.68,30.8 146.23,28.36 142.82,28.36 141.08,26.62 139.51,26.62 139.17,26.97 131.47,26.97 128.78,24.27 122.19,24.27 121.86,24.6 120.95,24.6 120.16,25.39 118.79,25.39 117.89,26.29 117.89,29.59 117.41,30.07 117.41,34.94 v1(116.86,35.49)
  BOTTOM w0.102: v1(174.09,81.73) 174.66,82.3 176.32,82.3 178.71,84.7 178.71,88.84 177.25,90.3 GPU1.C10 ; v1(116.86,35.49) 116.86,35.73 117.09,35.96 117.09,36.39 CPU1.U1
DGPU_PWROK: length 139.7
  TOP w0.102: v1(165.25,43.43) 165.45,43.43 166.14,44.11 R2477.1 ; v1(178,88.41) v2(178.56,88.41)
  L3 w0.102: v1(197.36,43.05) 196.68,43.73 186.94,43.73 186.67,44 184.03,44 180.44,47.59 180.44,48.28 179.73,50.13 179.47,50.39 179.47,51 178.94,51.53 178.94,52.37 v1(177.87,53.43) 177.47,53.43 176.58,54.32 176.58,55.5 177.67,56.59 177.67,61.06 175.37,63.36 175.37,68.62 176.21,69.46 176.21,71.57 178.52,73.88 178.52,78.96 178.74,79.19 178.74,87.67 v1(178,88.41)
  L4 w0.102: v1(165.25,43.43) 160.82,43.43 159.82,42.43 158.75,42.43 156.21,39.89 153.15,39.89 151.61,38.35 151.61,35.48 150.65,34.51 146.12,34.51 144.77,33.16 134.17,33.16 128.85,38.48 128.85,39.41 128.34,39.93 127.45,39.93 v1(127.4,39.97)
  L6 w0.102: v1(165.25,43.43) 165.28,43.45 165.28,44.29 166.98,45.99 166.98,46.55 167.41,46.98 168.47,46.98 169.39,47.9 169.39,52.37 170.41,53.38 177.82,53.38 v1(177.87,53.43)
  BOTTOM w0.102: v1(197.36,43.05) 198.17,43.05 R2471.1 ; v1(178,88.41) 177.98,88.38 176.79,88.38 176.65,88.52 GPU1.D9 ; v1(127.4,39.97) 127.14,40.24 126.78,40.24 126.62,40.4 125.02,40.4 CPU1.C8
DGPU_RXN_C_CPU_TXN0: length 132.9
  TOP w0.102: v1(132.18,42.08) 132.41,42.31 v2(132.71,42.31)
  L3 w0.14: v1(174.62,95.47) 174.62,95.73 174.88,95.98 176.53,95.98 177.15,95.36 177.15,94.72 177.65,94.23 177.65,92.61 176.59,91.56 176.59,88.8 175.14,87.35 171.41,87.35 170.43,86.37 170.43,62.2 171.09,61.54 171.09,36.32 165.78,31.01 165.78,28.71 164.33,27.26 152.74,27.26 152.2,26.71 148.88,26.71 147.94,25.77 143.8,25.77 142.59,24.56 137.2,24.56 136.32,25.44 136.32,26.71 136,27.03 136,28.48 135.2,29.28 135.2,30.14 134.61,30.73 134.61,32.3 131.83,35.07 131.83,39.73 131.45,40.11 131.45,41.86 131.82,42.23 132.03,42.23 v1(132.18,42.08)
  BOTTOM w0.102: GPU1.A5 174.25,94.32 173.89,94.69 173.89,94.81 174.17,95.09 174.32,95.09 174.62,95.39 v1(174.62,95.47) ; C1606.1 131.27,41.93 131.14,42.06 131.14,42.21 131.29,42.36 131.92,42.36 132.18,42.1 v1(132.18,42.08)
DGPU_RXN_C_CPU_TXN1: length 122.4
  TOP w0.102: v1(132.08,41.42) 131.57,41.42 v2(131.52,41.37)
  L3 w0.14: v1(132.08,41.42) 132.4,41.42 132.6,41.22 132.6,35.53 135.58,32.56 135.58,30.77 135.91,30.43 135.91,29.57 136.71,28.78 136.71,27.33 137.03,27 137.03,25.77 137.53,25.27 142.3,25.27 143.51,26.48 147.6,26.48 148.54,27.42 151.18,27.42 151.78,28.02 161.79,28.02 170.38,36.61 170.38,61.13 169.7,61.81 169.7,86.64 171.22,88.16 171.97,88.16 172.18,88.38 172.18,90.32 174.3,92.43 174.3,92.43 174.45,92.59 176.62,92.59 176.93,92.9 176.93,93.46 176.41,93.99 176.41,94.7 176.27,94.83 v1(176.22,94.83)
  BOTTOM w0.102: C1608.1 131.32,41.12 131.32,41.39 131.42,41.49 132,41.49 v1(132.08,41.42) ; GPU1.A8 176.05,94.67 v1(176.22,94.83)
DGPU_RXN_C_CPU_TXN2: length 118.6
  TOP w0.102: v2(132.35,44.53) 132.35,44.5 132.61,44.24 v1(132.61,43.95)
  L3 w0.14: v1(171.07,93.08) 170.37,93.08 169.96,92.67 169.96,88.21 168.96,87.21 168.96,36.2 164.48,31.72 162.56,31.72 159.58,28.73 151.08,28.73 150.48,28.13 148.23,28.13 147.29,27.19 141.96,27.19 141.34,26.57 138.63,26.57 137.49,27.71 137.49,29.1 136.62,29.97 136.62,30.73 136.29,31.06 136.29,32.65 137.24,33.61 137.24,38.29 136.92,38.62 136.92,39.74 135.06,41.59 135.06,42.83 133.94,43.95 132.62,43.95 v1(132.61,43.95)
  BOTTOM w0.102: v1(132.61,43.95) 132.61,43.95 132.57,43.98 132.13,43.98 131.49,44.62 C1610.1 ; GPU1.B3 173.05,92.57 172.39,93.23 171.56,93.23 171.4,93.08 v1(171.07,93.08)
DGPU_RXN_C_CPU_TXN3: length 121.5
  TOP w0.102: v2(133.4,46.45) 133.09,46.14 v1(133.09,45.97)
  L3 w0.14: v1(174.55,93.23) 174.55,93.31 173.88,93.98 169.99,93.98 169.2,93.19 169.2,88.6 168.25,87.64 168.25,36.49 164.19,32.43 158.32,32.43 156.2,30.31 149.49,30.31 148.11,28.92 147.64,28.92 147.26,28.54 142.26,28.54 141.01,27.28 139.03,27.28 138.68,27.64 138.68,29.1 137.54,30.24 137.54,32.61 138.03,33.1 138.03,38.62 137.7,38.94 137.7,39.95 135.77,41.89 135.77,43.29 v1(133.09,45.97)
  BOTTOM w0.102: v1(133.09,45.97) 132.84,45.72 132.84,45.47 132.6,45.23 131.65,45.23 C1612.1 ; GPU1.B6 174.85,92.57 174.72,92.7 174.72,93.06 v1(174.55,93.23)
DGPU_RXP_C_CPU_TXP0: length 134.3
  TOP w0.102: v2(131.37,42.59) 131.49,42.71 v1(132.18,42.71)
  L3 w0.14: v1(132.18,42.71) 131.93,42.71 131.18,41.97 131.18,40 131.56,39.62 131.56,34.96 134.34,32.19 134.34,30.62 134.94,30.03 134.94,29.17 135.73,28.37 135.73,26.92 136.05,26.6 136.05,25.33 137.09,24.29 142.7,24.29 143.91,25.51 148.05,25.51 148.99,26.45 152.31,26.45 152.85,26.99 164.44,26.99 166.05,28.6 166.05,30.9 171.36,36.21 171.36,61.65 170.7,62.31 170.7,86.26 171.52,87.09 175.25,87.09 176.86,88.69 176.86,91.45 177.91,92.5 177.91,94.34 177.42,94.83 177.42,95.47 176.64,96.25 174.77,96.25 173.96,95.44 v1(173.91,95.44)
  BOTTOM w0.102: v1(173.91,95.44) 173.91,95.16 173.66,94.9 173.66,94.02 GPU1.A4 ; v1(132.18,42.71) 132.08,42.82 C1605.1
DGPU_RXP_C_CPU_TXP1: length 123.7
  TOP w0.102: v1(132.08,40.78) 132.21,40.78 v2(132.61,40.38)
  L3 w0.14: v1(132.08,40.78) 132.34,40.53 132.34,35.42 135.31,32.45 135.31,30.66 135.65,30.32 135.65,29.46 136.44,28.67 136.44,27.22 136.76,26.89 136.76,25.66 137.42,25 142.41,25 143.62,26.22 147.71,26.22 148.65,27.16 151.29,27.16 151.89,27.75 161.9,27.75 170.65,36.5 170.65,61.24 169.96,61.93 169.96,86.53 171.33,87.9 172.08,87.9 172.45,88.27 172.45,90.21 174.57,92.32 176.51,92.32 176.73,92.32 177.2,92.79 177.2,93.57 176.67,94.1 176.67,95.02 176.41,95.29 175.96,95.29 v1(175.51,94.83)
  BOTTOM w0.102: C1607.1 131.45,40.15 v1(132.08,40.78) ; GPU1.A7 175.45,94.75 175.46,94.76 175.46,94.78 v1(175.51,94.83)
DGPU_RXP_C_CPU_TXP2: length 118.9
  TOP w0.102: v1(132.15,43.48) 132.15,43.6 131.95,43.81 v2(131.37,43.81)
  L3 w0.14: v1(171.09,92.45) 170.95,92.59 170.92,92.59 170.7,92.82 170.48,92.82 170.23,92.56 170.23,88.1 169.23,87.1 169.23,36.09 164.59,31.45 162.67,31.45 159.69,28.46 151.19,28.46 150.59,27.87 148.34,27.87 147.4,26.93 142.07,26.93 141.45,26.31 138.52,26.31 137.23,27.6 137.23,28.99 136.36,29.86 136.36,30.62 136.02,30.95 136.02,32.76 136.97,33.72 136.97,38.18 136.65,38.51 136.65,39.63 134.8,41.48 134.8,42.72 133.83,43.68 132.98,43.68 132.8,43.5 132.18,43.5 v1(132.15,43.48)
  BOTTOM w0.102: v1(132.15,43.48) 132.15,43.64 131.91,43.88 131.59,43.88 C1609.1 ; GPU1.B2 172.45,92.85 172.3,93.01 171.65,93.01 v1(171.09,92.45)
DGPU_RXP_C_CPU_TXP3: length 122.6
  TOP w0.102: v2(173.53,92.73) 173.84,93.03 v1(173.84,93.21) ; v2(131.86,45.99) v1(132.42,45.99)
  L3 w0.14: v1(132.42,45.99) 132.42,45.72 132.64,45.51 133.17,45.51 135.51,43.18 135.51,41.77 137.44,39.84 137.44,38.83 137.76,38.51 137.76,33.21 137.27,32.72 137.27,30.13 138.41,28.99 138.41,27.53 138.92,27.02 141.12,27.02 142.37,28.27 147.37,28.27 147.75,28.66 148.22,28.66 149.6,30.04 156.31,30.04 158.43,32.16 164.3,32.16 168.51,36.38 168.51,87.53 169.47,88.48 169.47,93.08 170.1,93.71 173.77,93.71 173.93,93.55 173.93,93.3 v1(173.84,93.21)
  BOTTOM w0.102: v1(173.84,93.21) 173.91,93.21 174.25,92.87 GPU1.B5 ; v1(132.42,45.99) 132.62,45.8 132.62,45.56 132.51,45.46 131.95,45.46 131.82,45.58 131.82,45.89 131.52,46.19 C1611.1
DMIC_CLK: length 117.6
  TOP w0.089: R2716.2 31.04,16.48 C2723.2 33.35,16.48 v2(34.03,17.16) 34.54,17.16 v1(34.62,17.09) ; RN5503.4 59.31,89.91 EC5504.1 58.92,89.52 57.73,89.52 v1(57.33,89.12)
  L3 w0.127: v1(33.45,93.87) 33.45,93.49 32.75,92.8 32.75,89.64 33.2,89.2 33.2,85.85 34.25,84.79 34.25,80.73 32.84,79.32 32.84,76.4 31.72,75.28 31.72,70.37 30.85,69.5 30.85,61.62 31.42,61.05 31.42,56.99 31.64,56.76 32.12,56.28 32.12,44 32.4,43.72 32.4,41.08 29.86,38.54 29.86,29.62 31.54,27.94 31.87,27.94 34.3,25.51 34.3,17.81 34.62,17.49 v1(34.62,17.09)
  BOTTOM w0.089: v1(57.33,89.12) 56.9,89.55 56.64,89.55 54.43,91.76 44.54,91.76 44.31,91.52 44,91.52 41.98,93.55 38.8,93.55 37.46,94.89 35.01,94.89 33.99,93.87 v1(33.45,93.87)
DMIC_CLK_C: length 7
  TOP w0.089: RN5503.1 62.71,89.91 63.09,89.53 63.09,88.89 v2(63.07,88.87) 62.74,88.87 62.63,88.97 v1(62.63,89.22)
  BOTTOM w0.089: v1(62.63,89.22) 62.63,90.29 63.15,90.8 TCBD1.17
DMIC_CLK_R: length 3.6
  TOP w0.089: R2716.1 29.31,16.43 v2(29.21,16.53) 28.29,16.53 27.91,16.91 HDA27.6
DMIC_DATA: length 115.9
  TOP w0.089: R2714.2 34.57,15.94 v2(34.59,15.97) 35.1,16.48 v1(35.1,16.5) ; RN5503.3 60.53,90.56 60.14,90.18 58.93,90.18 58.68,89.93 EC5503.1 57.5,89.93 v1(56.69,89.12)
  L3 w0.127: v1(33.93,93.44) 33.13,92.64 33.13,89.8 33.58,89.35 33.58,86.01 34.63,84.95 34.63,80.57 33.22,79.16 33.22,76.24 32.1,75.12 32.1,70.22 31.23,69.34 31.23,61.88 31.8,61.31 31.8,57.15 32.01,56.93 32.5,56.44 32.5,44.16 32.78,43.88 32.78,40.9 30.24,38.36 30.24,29.78 31.69,28.33 32.03,28.33 34.68,25.67 34.68,18.1 35.1,17.68 v1(35.1,16.5)
  BOTTOM w0.089: v1(33.93,93.44) 35.12,94.63 37.35,94.63 38.69,93.28 41.86,93.28 43.89,91.26 44.42,91.26 44.65,91.49 54.32,91.49 v1(56.69,89.12)
DMIC_DATA_C: length 6.8
  TOP w0.089: RN5503.2 63.12,90.56 v2(63.14,90.54) 63.52,90.16 v1(63.52,89.2)
  BOTTOM w0.089: v1(63.52,89.2) 63.52,90.54 63.65,90.67 TCBD1.18
DMIC_DATA_R: length 7.5
  TOP w0.089: R2714.1 33.14,15.07 30.54,15.07 EC2701.1 29.67,15.64 29.41,15.39 28.62,15.39 v2(28.42,15.59) 28.42,16.09 27.97,16.54 27.16,16.54 27.14,16.51 HDA27.5
DMIC_PCH_CLK: length 1.2
  TOP w0.102: TP1906.1 121.56,39.72 v1(121.56,39.46)
  BOTTOM w0.102: CPU1.H5 121.56,39.38 v1(121.56,39.46)
DOCK_USB_EN_A: length 9
  TOP w0.127: v1(34.84,38.58) 34.85,38.58 v2(35.27,38.15) 35.36,38.07 R3859.2 ; v1(36.24,41.37) 36.08,41.53 34.41,41.53 34.09,41.85 34.09,42.38 33.71,42.76 U3701.26
  BOTTOM w0.127: v1(34.84,38.58) 34.84,39.97 v1(36.24,41.37)
DOCK_USB_EN_B: length 17
  TOP w0.127: R3860.2 42.19,42.99 v2(41.45,43.73) 40.36,44.82 v1(39.06,44.82) ; U3701.36 29.8,46.01 29.39,46.42 v1(29.28,46.42)
  BOTTOM w0.127: v1(29.28,46.42) 35.96,46.42 37.21,45.18 38.71,45.18 v1(39.06,44.82)
DPB_AUXN: length 172.3
  TOP w0.102: 38.4,65.93 39.29,65.93 39.6,65.62 39.6,65.4 v1(39.88,65.12) ; 38.4,65.93 v2(38.4,66.06) ; 38.4,65.93 36.78,65.93 36.5,65.65 36.35,65.65 C3802.1
  L6 w0.127: v1(122.78,64.2) 122.57,63.99 122.57,63.86 122.83,63.59 125.14,63.59 125.61,63.12 128,63.12 131.56,66.68 131.56,69.6 131.15,70.01 131.15,72.21 131.76,72.83 132.37,72.83 132.78,73.23 132.78,74.96 134.94,77.11 134.94,86.37 131.19,90.12 130.36,90.12 122.05,98.44 112.22,98.44 111.89,98.77 101.9,98.77 101.1,99.57 77.23,99.57 76.68,100.12 70.39,100.12 69.61,99.33 67.26,99.33 67.1,99.49 67.1,99.49 66.72,99.86 62.58,99.86 61.86,99.14 57.14,99.14 56.17,100.11 52.59,100.11 52.24,99.76 48.89,99.76 47.72,98.59 47.39,98.59 47.12,98.31 47.12,97.61 46.38,96.87 46.38,96.39 42.2,92.21 42.2,91.91 41.39,91.09 41.39,83.43 37.27,79.31 37.27,71.12 38.28,70.11 38.53,69.86 38.53,66.21 39.17,65.56 39.43,65.56 v1(39.88,65.12)
  BOTTOM w0.102: v1(122.78,64.2) 122.78,63.92 122.95,63.74 CPU1.E48
DPB_AUXN_C: length 4.7
  TOP w0.102: U3801.25 33.5,62.72 33.68,62.9 33.68,63.77 R3801.2 33.48,64.08 34.47,65.07 ; 34.47,65.07 v2(34.36,65.17) ; 34.47,65.07 35.2,65.8 C3802.2
DPB_AUXP: length 173.2
  TOP w0.102: C3801.1 36.42,65.42 36.6,65.42 36.88,65.7 37.13,65.7 ; 37.13,65.7 v2(37.13,65.57) ; 37.13,65.7 39.2,65.7 39.37,65.53 39.37,65.24 v1(39.24,65.12)
  L6 w0.127: v1(39.24,65.12) 38.26,66.1 38.26,69.75 38.01,70 38.01,70 37.01,71.01 37.01,79.42 41.12,83.54 41.12,91.2 41.93,92.02 41.93,92.32 46.11,96.5 46.11,96.98 46.85,97.72 46.85,98.43 47.28,98.86 47.61,98.86 48.78,100.03 52.13,100.03 52.47,100.37 56.28,100.37 57.25,99.41 61.75,99.41 62.47,100.13 66.83,100.13 67.37,99.6 69.49,99.6 70.28,100.38 76.8,100.38 77.34,99.84 101.21,99.84 102.01,99.04 112,99.04 112.33,98.71 122.16,98.71 130.47,90.39 131.3,90.39 135.2,86.49 135.2,77 133.04,74.85 133.04,73.12 132.48,72.56 131.88,72.56 131.42,72.1 131.42,70.12 131.82,69.71 131.82,66.57 128.11,62.86 125.5,62.86 125.03,63.33 122.72,63.33 122.3,63.75 122.3,64.02 v1(122.13,64.2)
  BOTTOM w0.102: CPU1.F48 122.54,63.78 v1(122.13,64.2)
DPB_AUXP_C: length 3.7
  TOP w0.102: U3801.24 33.91,62.21 33.91,63.59 R3802.2 34.29,64.57 34.84,65.12 C3801.2
DPEQ0_A1: length 3
  TOP w0.127: U3801.14 v2(36.9,58.95) 37.94,58.95 R3872.1 R3871.2
DPEQ1: length 7.3
  TOP w0.127: v2(26.8,54.37) R3847.2 27.68,54.47 R3870.1 28.78,54.86 29.59,54.86 29.77,55.03 32.26,55.03 32.7,55.48 U3801.2
E71_TP: length 4.5
  TOP w0.102: v1(124.33,78.88) 123.9,78.45 TP2313.1
  BOTTOM w0.102: v1(124.33,78.88) 123.5,78.05 CPU1.E71
EAPD#: length 3.6
  TOP w0.102: 29.51,14.37 v2(28.5,14.37) 28.32,14.37 28.12,14.57 28.12,15.08 27.48,15.71 HDA27.3
EC_AGND: length 10.4
  TOP w0.203: KBC24.112 v1(190.81,29.84)
  TOP w0.508: v1(191.05,33.92) 189.25,33.92 187.98,32.66 v1(187.98,32.22)
  BOTTOM w0.508: 191.36,28.31 R2445.2 ; 191.36,28.31 191.31,28.36 C2441.2 v2(189.66,28.36) ; 191.36,28.31 C2422.2 191.11,29.18 190.81,29.48 v1(190.81,29.84) ; v1(191.05,33.92) 191.05,33.36 R2444.2 190.88,33.29 C2408.2
EC_SLP_S0IX#: length 4.4
  TOP w0.127: v2(181.79,33.44) KBC24.88 183.99,33.44 184.43,33 v1(184.43,32.91)
  BOTTOM w0.127: R2423.2 184.43,32.06 v1(184.43,32.91)
ECVBAT: length 6.3
  TOP w0.203: v2(194.81,27.19) KBC24.122 194.81,29.64 194.26,30.19 193.98,30.19 v1(193.09,31.08)
  BOTTOM w0.508: R2472.1 192.45,31.28 C2428.1 192.84,31.33 v1(193.09,31.08)
EDP_AUX: length 1.9
  TOP w0.102: C5510.1 83.95,94.28 v1(84.3,93.92)
  BOTTOM w0.102: LCD1.12 84.45,94.07 v1(84.3,93.92)
EDP_AUX#: length 2.6
  TOP w0.102: v2(84.61,93.41) 84.94,93.74 v1(84.94,93.92) 84.83,94.02 C5511.1
  BOTTOM w0.102: v1(84.94,93.92) 84.91,93.92 84.73,94.1 84.73,94.32 84.95,94.54 LCD1.13
EDP_AUX_DN: length 96.5
  TOP w0.102: v1(84.02,96.36) 84.02,96.18 84.6,95.6 C5511.2
  L3 w0.14: v1(84.02,96.36) 84.02,96.87 83.95,96.94 83.72,96.94 83.59,97.07 83.59,97.32 83.9,97.62 85.34,97.62 86.84,99.13 96.98,99.13 98.81,97.29 107.83,97.29 108.39,96.73 120.71,96.73 129.39,88.05 131.07,88.05 132.81,86.31 132.81,70.28 133.61,69.47 133.61,62.59 131.88,60.85 129.84,60.85 129.25,60.25 127.54,60.25 126.63,61.17 124.37,61.17 123.95,61.58 123.37,62.17 123.37,62.86 123.24,62.98 122.91,62.98 122.78,62.86 122.78,62.46 v1(122.86,62.38)
  BOTTOM w0.102: CPU1.E45 122.99,61.92 122.86,62.04 v1(122.86,62.38)
EDP_AUX_DP: length 96.5
  TOP w0.102: C5510.2 83.95,95.75 v1(83.39,96.31)
  L3 w0.14: v1(122.23,62.34) 122.62,61.94 123.22,61.94 123.84,61.32 124.26,60.9 126.52,60.9 127.43,59.99 129.36,59.99 129.95,60.58 131.99,60.58 133.88,62.48 133.88,69.58 133.08,70.39 133.08,86.42 131.18,88.32 129.5,88.32 120.82,97 108.5,97 107.94,97.56 98.92,97.56 97.09,99.39 86.73,99.39 85.23,97.89 83.79,97.89 83.32,97.43 83.32,96.92 83.39,96.85 v1(83.39,96.31)
  BOTTOM w0.102: v1(122.23,62.34) 122.54,62.03 CPU1.F45
EDP_COMP: length 4.9
  TOP w0.178: 122.43,64.63 121.87,64.63 R801.2 121.99,65.57 122.41,65.57
  TOP w0.254: v2(123.19,65.6) 123.09,65.51 123.09,65.3 v1(122.89,65.1) ; 122.43,64.63 v1(122.89,65.1) ; v1(122.89,65.1) 122.41,65.57
  BOTTOM w0.305: v1(122.89,65.1) 122.89,65.27 CPU1.E52
EDP_DISP_UTIL: length 2.5
  TOP w0.102: TP801.1 125.53,65.6 v1(126.49,65.6)
  BOTTOM w0.102: v1(126.49,65.6) 126.36,65.47 125.58,65.47 125.26,65.78 CPU1.B52
EDP_HPD: length 109.4
  TOP w0.102: RN5502.7 98.99,98.83 98.6,98.44 98.6,96.87 v2(98.37,96.64) 98.09,96.36 v1(98.09,95.95) 97.69,95.95 97.07,95.34 RN5501.6
  L3 w0.102: v1(135.05,88.61) 133.73,89.92 132.27,89.92 132,90.19 130.43,90.19 129.41,91.21 129.41,92 129.41,92.46 122.51,99.36 101.57,99.36 v1(99.74,101.18) ; v1(127.79,58.67) 127.68,58.56 127.68,56.99 126.54,55.85 125.5,55.85 125.04,55.39 125.04,51.22 124.08,50.26 122.34,50.26 121.23,49.15 121.23,47.46 120.34,46.57 119.91,46.57 119.33,45.99 119.33,44.77 119.87,44.23 119.87,42.45 v1(119.47,42.05)
  L4 w0.102: v1(98.09,95.95) 98.09,99.53 v1(99.74,101.18)
  L6 w0.102: v1(135.05,88.61) 135.05,88.2 136.31,86.94 136.31,74.86 134.24,72.79 134.24,72.61 133.63,72 133.63,66.01 130.81,63.19 130.78,63.19 127.79,60.19 v1(127.79,58.67)
  BOTTOM w0.102: CPU1.L10 119.62,42.05 v1(119.47,42.05)
EDP_HPD_CONN: length 6.9
  TOP w0.102: RN5501.3 97.07,93.43 96.62,92.98 94.69,92.98 93.9,93.77 v2(93.72,93.77) 93.17,93.77 v1(92.99,93.95)
  BOTTOM w0.102: LCD1.27 91.95,94.53 92.23,94.25 92.69,94.25 v1(92.99,93.95)
EDP_TX0: length 2.2
  TOP w0.102: C5509.1 91.79,94.68 91.29,94.17 v1(91.29,93.92)
  BOTTOM w0.102: LCD1.25 90.95,94.26 v1(91.29,93.92)
EDP_TX0#: length 2
  TOP w0.102: C5506.1 90.65,94.28 v1(90.65,93.92)
  BOTTOM w0.102: LCD1.24 90.45,94.53 90.65,94.33 v1(90.65,93.92)
EDP_TX0_DN: length 74.4
  TOP w0.102: C5506.2 91.36,95.9 91.36,96 v1(91.13,96.23)
  L3 w0.14: v1(91.13,96.23) 91.34,96.44 91.34,96.77 91.59,97.02 95.52,97.02 96.04,96.51 96.04,94.89 96.38,94.54 106.39,94.54 107.02,93.91 120.45,93.91 125.13,89.23 125.13,82.22 129.35,78 129.35,76.52 129.73,76.14 129.73,69.4 130.85,68.28 130.85,65.97 130.33,65.46 130.33,64.27 v1(130.38,64.23)
  BOTTOM w0.102: v2(129.59,64.91) 129.59,64.76 ; 129.59,64.76 129.31,64.76 128.98,64.43 128.98,63.92 128.13,63.07 125.1,63.07 124.82,63.35 CPU1.C47 ; 129.59,64.76 129.84,64.76 v1(130.38,64.23)
EDP_TX0_DP: length 74.2
  TOP w0.102: C5509.2 91.95,95.72 91.92,95.72 91.92,96.1 v1(91.79,96.23)
  L3 w0.14: v1(91.79,96.23) 91.6,96.42 91.6,96.65 91.7,96.75 95.41,96.75 95.77,96.4 95.77,94.78 96.27,94.28 106.28,94.28 106.91,93.64 120.34,93.64 124.86,89.12 124.86,82.11 129.08,77.89 129.08,76.41 129.46,76.03 129.46,69.29 130.58,68.17 130.58,66.08 130.07,65.57 130.07,64.75 129.84,64.52 129.6,64.52 129.34,64.26 129.34,63.92 129.44,63.82 v1(129.87,63.82)
  BOTTOM w0.102: v1(129.87,63.82) 129.94,63.9 129.94,64.34 129.75,64.53 129.4,64.53 129.21,64.34 129.21,63.83 128.57,63.19 ; v2(128.67,63.08) 128.57,63.19 ; 128.57,63.19 128.22,62.84 125,62.84 CPU1.C46
EDP_TX1: length 2.1
  TOP w0.102: v1(89.38,93.92) 90.14,94.68 C5504.1
  BOTTOM w0.102: v1(89.38,93.92) 89.38,94.31 89.45,94.38 LCD1.22
EDP_TX1#: length 2.1
  TOP w0.102: C5501.1 89.28,94.43 88.95,94.1 88.95,94.1 88.77,93.92 v1(88.75,93.92)
  BOTTOM w0.102: LCD1.21 88.95,94.12 v1(88.75,93.92)
EDP_TX1_DN: length 74.9
  TOP w0.102: C5501.2 89.5,95.81 89.5,96.02 v1(89.23,96.28) 88.9,96.61 v2(88.9,96.77)
  L3 w0.14: v1(123.78,62.75) 124.1,62.43 124.3,62.43 124.71,62.84 125.69,62.84 126.64,63.79 126.64,64.45 127.21,65.02 128.37,65.02 129.72,66.36 129.72,67.76 128.62,68.85 128.62,75.75 128.29,76.08 128.29,77.51 124.05,81.75 124.05,88.79 120,92.84 100.24,92.84 100.1,92.7 100.1,92.21 99.81,91.91 99.34,91.91 99.05,92.21 99.05,92.7 98.91,92.84 96.4,92.84 94.79,94.45 89.84,94.45 89.42,94.88 89.42,96.09 v1(89.23,96.28)
  BOTTOM w0.102: CPU1.D46 123.82,62.78 v1(123.78,62.75)
EDP_TX1_DP: length 75
  TOP w0.102: C5504.2 89.86,95.9 v1(89.86,96.28) 89.86,96.39 v2(90.26,96.79)
  L3 w0.14: v1(124.45,61.73) 124.45,62.2 124.82,62.58 125.8,62.58 126.91,63.68 126.91,64.34 127.32,64.75 128.48,64.75 129.98,66.25 129.98,67.87 128.89,68.97 128.89,75.86 128.56,76.19 128.56,77.62 124.32,81.86 124.32,88.9 120.11,93.11 100.13,93.11 99.83,92.81 99.83,92.32 99.7,92.18 99.45,92.18 99.31,92.32 99.31,92.81 99.02,93.11 96.51,93.11 94.9,94.72 89.95,94.72 89.69,94.99 89.69,96.1 v1(89.86,96.28)
  BOTTOM w0.102: CPU1.C45 124.61,61.9 v1(124.45,61.73)
EDP_TX2: length 2.4
  TOP w0.102: v1(87.48,93.92) 88.24,94.68 C5519.1
  BOTTOM w0.102: v1(87.48,93.92) 87.95,94.39 LCD1.19
EDP_TX2#: length 2.3
  TOP w0.102: v1(86.84,93.92) 86.84,94.02 C5533.1
  BOTTOM w0.102: LCD1.18 87.45,94.53 v1(86.84,93.92)
EDP_TX2_DN: length 79.8
  TOP w0.102: C5533.2 87.27,95.83 v1(87.27,96.31) 87.27,96.44 v2(87.63,96.79)
  L3 w0.14: v1(127.23,62.22) 127.89,61.56 128.65,61.56 130.11,63.02 130.49,63.02 131.63,64.17 131.63,68.81 130.76,69.69 130.76,77.74 125.92,82.58 125.92,89.59 120.16,95.34 97.59,95.34 97.12,95.81 97.12,96.54 95.84,97.82 88.02,97.82 87.48,97.27 87.48,96.51 v1(87.27,96.31)
  BOTTOM w0.102: CPU1.A45 v1(127.23,62.22)
EDP_TX2_DP: length 79.8
  TOP w0.102: v1(87.93,96.28) 87.93,96.16 88.39,95.7 C5519.2 ; v2(127.68,62.88) 127.86,62.7 v1(127.86,62.22)
  L3 w0.14: v1(87.93,96.28) 87.74,96.47 87.74,97.16 88.13,97.55 95.73,97.55 96.85,96.43 96.85,95.7 97.47,95.08 120.05,95.08 125.65,89.48 125.65,82.46 130.49,77.63 130.49,69.58 131.37,68.7 131.37,64.28 130.38,63.29 130,63.29 128.53,61.83 128,61.83 127.86,61.96 v1(127.86,62.22)
  BOTTOM w0.102: v1(127.86,62.22) 127.43,62.65 127.02,62.65 126.86,62.49 125.76,62.49 125.49,62.22 CPU1.B45
EDP_TX3: length 2
  TOP w0.102: C5531.1 86.21,94.28 v1(86.21,93.92)
  BOTTOM w0.102: LCD1.16 86.45,94.24 86.33,94.12 86.33,94.05 v1(86.21,93.92)
EDP_TX3#: length 2.6
  TOP w0.102: v2(85.86,93.43) 85.57,93.71 v1(85.57,93.92) 85.72,94.07 C5532.1
  BOTTOM w0.102: LCD1.15 85.95,94.3 v1(85.57,93.92)
EDP_TX3_DN: length 91.3
  TOP w0.102: v2(84.96,96.82) 84.96,96.64 v1(85.29,96.31) 85.72,95.88 C5532.2
  L3 w0.14: v1(127.37,63.8) 127.54,63.62 127.54,63.31 127.33,63.1 127.01,63.1 126.46,62.55 126.46,61.92 127.61,60.77 128.98,60.77 129.65,61.45 131.43,61.45 133.07,63.08 133.07,69.25 132.58,69.74 132.05,69.74 131.62,70.17 131.62,80.69 132.22,81.28 132.22,86.03 130.72,87.53 129.17,87.53 120.49,96.21 108.17,96.21 107.62,96.77 98.59,96.77 96.76,98.61 87.13,98.61 85.55,97.02 85.55,96.56 v1(85.29,96.31)
  BOTTOM w0.102: v1(127.37,63.8) 126.94,63.8 126.49,63.35 CPU1.A47
EDP_TX3_DP: length 91.2
  TOP w0.102: C5531.2 86,96.21 v1(86,96.31) 86,96.49 v2(86.31,96.79)
  L3 w0.14: v1(86,96.31) 85.81,96.5 85.81,96.91 87.24,98.34 96.65,98.34 98.48,96.51 107.5,96.51 108.06,95.95 120.38,95.95 129.06,87.27 130.61,87.27 131.95,85.92 131.95,81.39 131.35,80.8 131.35,70.06 131.94,69.47 132.47,69.47 132.8,69.14 132.8,63.2 131.32,61.71 129.54,61.71 128.87,61.04 127.72,61.04 126.73,62.03 126.73,62.44 127.12,62.83 127.44,62.83 127.81,63.2 127.81,63.6 128.01,63.79 v1(128.01,63.8)
  BOTTOM w0.102: v1(128.01,63.8) 128.01,63.86 127.62,64.24 127.06,64.24 126.41,63.59 126.1,63.59 126.07,63.62 125.53,63.62 CPU1.B47
EDP_VDD_EN: length 101.8
  TOP w0.127: v1(89.57,100.42) 89.56,100.41 89.56,99.47 v2(90.62,98.41) 91.13,97.9 D5501.1
  L3 w0.127: v1(89.57,100.42) 89.05,99.91 86.52,99.91 85.96,99.36 84.53,99.36 82.38,97.21 82.38,92.76 83.09,92.05 96.3,92.05 97.56,90.79 104.5,90.79 111.92,83.38 111.92,79.16 111.38,78.61 111.38,76.95 109.7,75.28 109.7,70.83 109.96,70.57 109.96,51.3 111.31,49.95 118.17,49.95 118.92,49.2 118.92,48.04 117.52,46.65 117.52,43.92 117.35,43.75 v1(117.35,42.58)
  BOTTOM w0.127: v1(117.35,42.58) 117.32,42.62 117.32,43.23 CPU1.U13
EDRAM_OPIO_RCOMP: length 0.6
  BOTTOM w0.381: v1(121.62,73.56) 121.3,73.88 CPU1.H66
  vias: v2(122.12,74.29)
EMMC_RCOMP: length 3.6
  TOP w0.508: v1(108.28,36.19) 108.27,36.19 R1502.1 107.49,36.8 v2(107.24,36.54)
  BOTTOM w0.254: CPU1.AT1 107.16,36.19 107.34,36.01 108.1,36.01 v1(108.28,36.19)
EOPIO_RCOMP: length 1.4
  TOP w0.508: v1(121.61,72.56) 121.05,72.56 R415.1
  BOTTOM w0.254: CPU1.H65 121.3,72.87 v1(121.61,72.56)
EQ: length 4.7
  TOP w0.102: v2(22.5,70.83) 22.5,70.2 22.5,70.19 v1(22.5,69.36) 22.5,69.23 22.69,69.04 U5701.17
  BOTTOM w0.102: v1(22.5,69.36) 21.89,68.75 R5412.2 21.56,68.55 R5411.2
EQ0: length 3.4
  TOP w0.127: R3842.2 R3843.1 30,57.42 v2(30.49,57.42) 30.88,57.42 31.21,57.75 U3801.38
EQ1: length 3.1
  TOP w0.127: U3801.35 31.08,58.95 30.87,58.73 30.11,58.73 30.05,58.79 R3841.1 R3840.2
ESPI_ALERT#: length 153.7
  TOP w0.089: v1(181.47,21.63) 181.46,21.62 R6801.2 ; KBC24.55 188.41,43.48 187.81,42.89 187.81,42.64 187.48,42.31 187.48,39.39 v1(187.22,39.13) ; v1(98.12,25.11) 97.66,25.11 96.9,24.35 v2(96.9,23.97) 97.1,23.77 R1821.2
  L3 w0.127: v1(100.3,41.34) 100.3,39.35 102.26,37.4 102.26,36.8 104.14,34.92 104.14,34.57 103.76,34.19 101.67,34.19 100.11,32.63 97.94,32.63 96.99,31.68 96.99,29.52 98.56,27.94 98.56,25.4 98.27,25.11 v1(98.12,25.11) ; v1(187.22,39.13) 187.43,38.93 187.43,38.87 187.46,38.83 187.46,36.27 187.23,35.91 187.22,35.9 186.68,35.05 186.68,35.05 186.68,33.47 186.36,33.16 185.15,30.48 185.15,28.86 186.23,27.78 186.23,27.02 186.03,26.81 186.03,24.6 183.05,21.63 v1(181.47,21.63)
  L4 w0.127: v1(106.62,21.57) 107.18,21.01 110.2,21.01 110.71,21.53 110.71,21.83 111.24,22.36 111.77,22.36 113.35,20.78 121.39,20.78 121.85,20.32 123.05,20.32 123.56,19.82 126.91,19.82 127.12,20.02 127.42,20.02 128.04,20.02 128.35,20.32 130.71,20.32 133.12,22.74 143.76,22.74 145.53,24.51 146.57,24.51 146.57,24.51 147.14,24.51 148.62,25.99 152.45,25.99 153.19,26.72 160.49,26.72 v1(160.7,26.51)
  L6 w0.102: v1(181.47,21.63) 180.64,22.46 180.11,22.46 178.02,24.54 176.64,24.54 176.07,25.11 173.96,25.11 173.47,24.63 164.26,24.63 163.65,25.24 162.36,25.24 161.08,26.51 v1(160.7,26.51)
  BOTTOM w0.089: v1(100.3,41.34) 100.35,41.39 100.35,41.44 100.73,41.83 101.57,41.83 102.01,42.26 104.27,42.26 CPU1.AY11 ; v1(106.62,21.57) 106.6,21.59 106.6,24.1 106.06,24.64 100.66,24.64 100.65,24.65 99.17,24.65 98.7,25.11 v1(98.12,25.11)
ESPI_ALERT#_ESPI: length 16.1
  TOP w0.089: R6801.1 181.15,19.78 v2(181.15,18.76) 181.15,18.3 179.06,16.2 179.06,11.73 177.64,10.31 DB1.1
ESPI_CLK: length 135.4
  TOP w0.089: v1(123.9,15.1) 122.02,14.05 114.09,14.05 113.98,13.94 110.66,13.94 109.78,14.82 101.34,14.82 98.41,16.4 94.62,18.44 92.25,20.81 90.89,22.55 89.88,23.85 89.13,25.78 EC1804.1 89.13,29.71 R1806.2 ; v1(187.02,37.25) 186.8,37.47 186.8,39.32 187.21,39.73 187.21,42.41 187.6,42.8 187.6,42.98 187.61,42.99 KBC24.57 ; R6807.2 182.22,22.37 v1(182.21,22.37) 181.42,23.16 180.12,23.16 179.42,23.86 175.51,23.86 174.98,24.39 172.46,24.39 170.79,22.73 158.79,22.73 158.07,23.44 155.59,23.44 v2(155.12,23.92) v1(154,25.04)
  L3 w0.127: v1(182.21,22.37) 183.26,22.37 185.65,24.76 185.65,26.73 184.77,27.61 184.77,30.56 185.42,32 185.42,33.78 186.36,35.26 187.02,36.29 v1(187.02,37.25)
  L4 w0.127: v1(154,25.04) 154,24.38 149.12,19.51 147.36,19.51 146.17,18.32 133.43,18.32 131.61,16.49 129.59,16.49 129.27,16.17 128.04,16.17 127.5,15.63 124.43,15.63 v1(123.9,15.1)
ESPI_CLK_C: length 19.5
  TOP w0.089: DB1.2 171.92,9.74 172.3,9.37 177.07,9.37 v2(177.41,9.71) 179.32,11.62 179.32,15.93 181.58,18.2 181.58,19.45 181.91,19.78 181.91,20.54 R6807.1
ESPI_CS#: length 162.4
  TOP w0.089: KBC24.58 187.21,43.46 187.21,43.4 186.94,42.52 v1(185.76,40.73) ; DB1.5 v1(168.92,9.12) 165.07,8.68 161.76,8.68 159.41,9.21 156.48,9.64 148.55,13.47 144.45,15.36 144.41,15.37 143.95,15.84 140.28,17.72 139.53,18.11 139.43,18.16 129.99,18.16 128.79,17.68 127.62,17.2 127.53,17.16 126.54,16.76 126.08,16.3 125.69,15.92 124.27,14.5 122.14,13.52 114.31,13.52 114.2,13.41 110.44,13.41 109.56,14.29 101.21,14.29 94.3,18 91.84,20.46 90.16,22.62 89.37,23.64 88.51,25.73 88.44,27.04 88.39,27.97 88.38,27.98 88.38,33.41 88.95,35.18 90.36,38.44 90.7,38.94 92.39,41.54 93.26,42.41 v2(95.45,42.41) v1(96.06,42.41)
  L3 w0.127: v1(185.76,40.73) 185.76,40.33 186.57,38.93 186.57,37.23 185.32,35.98 185.32,34.33 185.04,33.89 185.04,32.08 183.89,29.55 183.84,29.35 183.84,27.12 182.33,23.12 180.96,21.75 180.8,21.59 180.6,21.1 180.43,20.67 179.79,19.09 179.15,17.5 176.83,15.19 176.7,15.06 176.64,15 175.69,14.58 174.45,13.34 171.42,11.63 v1(168.92,9.12)
  BOTTOM w0.089: CPU1.BA12 103.27,43.02 101.9,43.02 101.17,42.72 101.14,42.71 v1(96.06,42.41)
ESPI_IO0: length 152.3
  TOP w0.089: RN1806.8 91.61,41.46 v2(91.34,40.94) 90.12,38.6 88.71,35.32 88.71,35.32 88.13,33.48 88.12,33.44 88.12,27.87 88.12,27.87 88.23,25.68 89,23.68 90.02,22.37 91.64,20.28 94.14,17.78 101.14,14.02 109.45,14.02 110.33,13.14 114.31,13.14 114.42,13.25 122.22,13.25 124.43,14.28 125.63,15.48 126.69,16.54 130.04,17.89 139.37,17.89 139.44,17.85 140.16,17.49 143.39,15.82 143.79,15.62 144.27,15.14 148.44,13.23 156.54,9.31 v1(157.05,8.86) ; v1(181.18,42.21) 182.43,43.76 183.49,44.82 183.99,45.29 184.05,45.34 186.36,45.34 186.58,45.12 186.81,44.89 KBC24.59 ; R6806.2 v1(166.57,12.23)
  L3 w0.127: v1(181.18,42.21) 181.07,41.24 180.91,40.49 180.91,39.53 181.42,38.76 181.42,31.7 181.77,30.47 181.77,26.2 180.91,23.85 179.51,22.45 177.85,18.36 176.63,17.15 175.67,16.94 175.08,16.35 174.89,15.93 173.66,14.71 170.96,13.87 169.26,13.35 v1(166.57,12.23)
  L4 w0.127: v1(157.05,8.86) 157.81,9.23 158.38,9.33 158.89,9.5 v1(166.57,12.23)
ESPI_IO0_C: length 5.6
  TOP w0.089: DB1.9 164.92,11.02 163.63,12.31 163.63,12.83 164.49,13.68 v2(164.97,13.68) R6806.1
ESPI_IO1: length 152.2
  TOP w0.089: RN1806.7 91.1,41.47 v2(90.37,39.87) 88.46,35.41 87.87,33.55 87.83,33.4 87.83,28.12 87.85,27.77 87.86,27.76 87.96,25.63 88.71,23.62 89.25,22.93 89.73,22.31 89.81,22.21 91.44,20.11 93.98,17.57 93.98,17.57 99.6,14.55 101.07,13.76 109.34,13.76 110.22,12.88 114.42,12.88 114.53,12.99 122.28,12.99 124.58,14.06 126.84,16.31 130.09,17.63 139.3,17.63 139.41,17.57 140.03,17.25 143.17,15.64 143.63,15.4 144.12,14.91 148.32,12.99 151.63,11.35 155.98,9.29 v1(156.41,8.86) ; v1(181.79,42) 181.89,42.29 182.69,43.69 182.72,43.74 183.65,44.67 184.12,45.12 186.18,45.12 186.41,44.89 KBC24.60 ; R6805.2 v1(166.57,11.6)
  L3 w0.127: v1(166.57,11.6) 169.52,13.03 173.86,14.37 175.31,15.82 175.46,16.19 175.86,16.59 176.79,16.77 178.17,18.15 178.22,18.25 179.83,22.23 179.94,22.35 181.24,23.64 182.15,26.14 182.15,27.74 182.56,31.57 182.56,40 182.12,41.25 v1(181.79,42)
  L4 w0.127: v1(166.57,11.6) 158.47,8.95 157.93,8.87 157.24,8.41 156.86,8.41 v1(156.41,8.86)
ESPI_IO1_C: length 3.4
  TOP w0.089: v2(164,12.69) 164.66,12.03 R6805.1 165.92,11.08 DB1.8
ESPI_IO2: length 148.9
  TOP w0.089: KBC24.61 186,44.13 v1(186,42.54) ; R6804.2 v1(169.09,12.28) ; RN1806.6 90.6,41.47 v2(89.53,38.85) 89.49,38.81 88.69,36.64 88.29,35.69 88.21,35.5 87.61,33.62 87.57,33.43 87.57,28.09 87.57,28.01 87.58,27.73 87.58,27.68 87.58,27.66 87.59,27.66 87.69,25.55 88.42,23.56 89.53,22.13 91.24,19.93 93.82,17.35 101.01,13.49 109.22,13.49 110.11,12.61 114.53,12.61 114.64,12.72 122.3,12.72 122.35,12.73 124.71,13.81 126.99,16.08 130.14,17.36 139.24,17.36 139.28,17.34 139.91,17.01 140.9,16.5 140.92,16.5 142.54,15.66 143.01,15.42 143.19,15.33 143.33,15.26 143.47,15.19 143.97,14.68 143.97,14.68 148.21,12.74 155.48,9.15 v1(155.78,8.86)
  L3 w0.127: v1(169.09,12.28) 174.07,14.04 175.37,15.34 176.24,15.67 178.5,17.93 180.15,22.02 180.21,22.08 181.57,23.43 183.04,27.18 183.04,29.68 183.95,40.79 183.95,40.79 184.37,41.21 184.41,41.24 184.77,41.43 v1(186,42.54)
  L4 w0.127: v1(155.78,8.86) 156.17,9.24 156.44,9.34 157.74,9.61 158.32,9.71 158.75,9.86 166.23,12.68 167.05,12.68 v1(169.09,12.28)
ESPI_IO2_C: length 3.6
  TOP w0.089: v2(167.51,13.68) R6804.1 167.05,12.34 167.05,11.4 166.92,11.27 DB1.7
ESPI_IO3: length 149.3
  TOP w0.089: KBC24.62 185.49,42.39 v1(185.37,41.24) ; v1(155.14,8.83) 154.75,9.18 147.35,12.84 143.82,14.46 143.37,14.9 142.94,15.12 142.82,15.19 140.76,16.25 140.75,16.26 140.08,16.6 139.23,17.04 139.23,17.04 139.14,17.09 130.19,17.09 127.14,15.86 127.06,15.78 124.87,13.59 122.43,12.45 114.76,12.45 114.64,12.34 110,12.34 109.11,13.22 100.94,13.22 98.61,14.48 93.65,17.14 93.65,17.14 91.04,19.75 89.9,21.21 89.32,21.96 89.25,22.06 88.6,22.89 88.13,23.49 87.41,25.43 87.32,27.56 87.32,27.56 87.32,27.67 87.3,28.07 87.3,28.09 87.3,33.46 87.35,33.69 87.96,35.6 89.57,40.31 v2(89.79,40.95) RN1806.5 ; R6803.2 v1(169.09,11.65)
  L3 w0.127: v1(169.09,11.65) 174.27,13.7 175.53,14.96 176.42,15.32 178.82,17.72 179.44,19.24 180.25,21.24 180.48,21.8 180.66,21.98 181.83,23.16 182,23.33 183.41,27.08 183.42,27.14 183.42,29.4 183.9,33.65 183.97,33.8 184.94,35.33 184.94,36.08 185.47,36.95 185.47,37.32 185.4,38.72 185.32,40.35 185.32,40.78 v1(185.37,41.24)
  L4 w0.127: v1(155.14,8.83) 155.56,8.41 156.13,8.41 156.7,8.03 157.39,8.03 158.08,8.5 158.56,8.58 v1(169.09,11.65)
ESPI_IO3_C: length 1.9
  TOP w0.089: R6803.1 167.92,11.62 DB1.6
ESPI_RESET#: length 199.4
  TOP w0.089: v1(127.33,18.55) 124.67,15.27 124.15,14.75 122.08,13.79 114.2,13.79 114.09,13.68 110.55,13.68 109.67,14.56 101.28,14.56 98.46,16.07 94.55,18.17 94.55,18.17 94.46,18.22 92.04,20.64 89.71,23.63 89.65,23.72 88.77,25.83 88.65,28.09 88.65,33.37 88.84,33.96 89.03,34.55 89.16,34.97 89.2,35.08 90.59,38.31 92.02,40.38 v2(92.86,41.52) 93.39,42.05 94.35,42.05 94.36,42.05 95.88,42.05 95.9,42.02 97.48,42.02 v1(97.48,42.03) ; KBC24.53 189.21,44.89 188.97,45.13 188.44,45.13 v1(188.16,45.41) ; v1(154.51,8.83) 154.93,8.41 157.17,8.41 157.95,8.86 159.43,8.86 162.13,8.25 168.79,8.25 169.92,9.38 DB1.4
  L4 w0.127: v1(127.33,18.55) 127.59,18.81 130.52,18.81 133.51,21.8 147.05,21.8 147.2,21.95 147.88,21.95 149.01,23.08 149.01,23.61 149.56,24.17 151.18,24.17 153.35,26.34 159.01,26.34 v1(160.23,25.12) 160.98,25.87 162.73,25.87 165.69,28.83 166.2,28.83 172.47,35.11 172.47,38.1 175.4,41.03 175.4,43.05 176.44,44.09 176.44,44.78 176.96,45.3 176.96,49.25 177.4,49.7 177.4,52.35 177.66,52.61 177.68,52.61 v1(177.87,52.8)
  L6 w0.102: v1(177.87,52.8) 178.53,52.14 178.53,50.71 183.61,45.64 186.49,45.64 186.87,45.25 188.01,45.25 v1(188.16,45.41)
  BOTTOM w0.089: v1(154.51,8.83) 155.98,10.3 155.98,12.08 157.02,13.12 157.02,17.03 157.99,18.01 157.99,21.47 160.23,23.71 v1(160.23,25.12) ; v1(97.48,42.03) 101.17,42.54 101.25,42.56 102.05,42.84 103.35,42.84 CPU1.BA11
EXT_PWR_GATE#: length 2.8
  TOP w0.127: v2(109.75,40.83) 109.75,41.08 v1(110.05,41.37) 110.65,40.77 110.65,40.2 R1731.2
  BOTTOM w0.127: CPU1.AM10 109.65,41.77 v1(110.05,41.37)
FALL_INT2: length 4.3
  BOTTOM w0.102: v2(145.82,9.57) 145.95,9.69 R7018.2 Q7001.3 147.35,9.89 147.5,9.74 147.88,9.74 148,9.87 Q7001.2
FAN1_PWM: length 79.7
  TOP w0.102: v1(149.78,72.1) 150.29,72.61 150.29,72.99 148.58,74.71 v2(148.58,75) 148.59,75.01 R2614.1 ; KBC24.47 191.61,45.04 v1(192.2,45.64)
  L3 w0.102: v1(192.2,45.64) 192.2,45.15 191.74,44.7 187.34,44.7 186.51,45.52 184.98,45.52 184.78,45.62 184.54,45.73 184.51,45.75 184.42,45.84 183.55,45.84 181.41,47.99 181.41,49.37 181.35,49.42 181.27,49.51 181.27,49.56 181.2,49.74 181.04,50.16 181.02,50.21 180.44,50.79 180.44,51.4 179.91,51.93 179.91,55.11 179.65,55.93 179.59,56.13 179.23,57.25 179.23,61.37 176.54,64.06 176.54,67.97 178.87,70.3 v1(178.87,70.58)
  L4 w0.102: v1(166.55,72.99) 163.65,70.1 151.95,70.1 149.95,72.1 v1(149.78,72.1)
  L6 w0.102: v1(178.87,70.58) 178.87,70.32 175.89,67.35 172.18,67.35 v1(166.55,72.99)
FAN1_TACH: length 11.3
  TOP w0.203: v1(194.41,42.49) 194.41,42.49 194.41,43.29 KBC24.40
  L6 w0.254: v1(188.59,41.24) 188.72,41.11 190.6,41.11 190.85,41.37 193.25,41.37 194.37,42.49 v1(194.41,42.49)
  BOTTOM w0.254: v2(195.1,42.49) v1(194.41,42.49) ; D2403.A 187.93,40.61 187.7,40.83 R2430.1 188.34,41.49 v1(188.59,41.24)
FAN_PWM1_C: length 7.4
  TOP w0.102: v1(154.86,74.26) 152.07,74.26 AFTP2602.1 150.1,75.53 149.46,76.17 R2614.2
  BOTTOM w0.102: FAN1.4 154.91,74.21 v1(154.86,74.26)
FAN_TACH1: length 73.7
  TOP w0.254: v1(149.78,72.76) 147.04,75.5 v2(147.04,76.24) 147.22,76.42 147.8,76.42 148.44,77.05 R2613.1
  L4 w0.254: v1(149.78,72.76) 149.9,72.76 152.13,70.53 163.36,70.53 166.47,73.63 v1(166.57,73.63)
  L6 w0.254: v1(177.65,69.74) 175.69,67.78 172.47,67.78 166.62,73.63 v1(166.57,73.63)
  BOTTOM w0.254: v1(177.65,69.74) 176.53,68.63 176.53,63.25 178.28,61.5 178.28,58.72 178.47,58.53 178.47,55.71 178.99,55.19 178.99,54.1 179.29,53.12 179.3,53.11 180.04,50.54 181.05,47.05 181.13,46.78 181.66,46.25 181.66,43.38 183.9,41.13 184.63,41.13 184.93,40.84 184.93,40.52 185.37,40.07 D2403.K
FAN_TACH1_C: length 7.6
  TOP w0.254: R2613.2 149.45,77.03 150.52,75.96 152.65,75.96 AFTP2601.1 153.85,75.91 154.74,75.02 v1(154.86,75.02)
  BOTTOM w0.254: FAN1.3 155.05,75.21 v1(154.86,75.02)
FAN_VCC_1: length 2.8
  TOP w0.508: AFTP2603.1 151.56,77.41 v1(151.08,76.93) 151.08,76.95 150.67,76.95 149.68,77.94 R2612.2
  vias: v2(153.72,76.93)
FFS_INT1: length 24.1
  TOP w0.102: R7012.1 119.62,20.29 120.46,19.45 v2(120.75,19.45) v1(121.41,19.45)
  L3 w0.102: v1(120.6,34.23) 121.08,33.75 121.08,32.77 120.77,32.45 120.27,32.45 119.18,31.36 119.18,29.21 120.42,27.97 120.42,20.13 120.67,19.88 120.72,19.88 121.16,19.45 v1(121.41,19.45)
  BOTTOM w0.089: 120.32,35.33 120.32,36.37 120.19,36.5 120.15,36.63 120.15,36.8 120.13,37.01 119.9,37.42 119.9,37.55 CPU1.M3
  BOTTOM w0.102: 120.32,35.33 120.13,35.13 120.13,34.7 v1(120.6,34.23)
FFS_INT2: length 37.5
  TOP w0.102: v1(113.32,33.06) 113.18,32.92 v2(113.18,32.5)
  L3 w0.102: v1(121.66,17.01) 121.64,17.03 121.64,17.31 120.95,18 120.06,18 119.68,17.62 119.68,17.21 119.23,16.76 118.59,16.76 117.16,18.18 117.16,25.35 116.76,25.75 116.76,27.22 116.22,27.76 116.22,28.19 115.83,28.58 115.83,30.55 v1(113.32,33.06)
  BOTTOM w0.089: 113.56,35.83 113.56,36.53 113.51,36.67 113.51,37.1 CPU1.AC2
  BOTTOM w0.102: v1(121.66,17.01) 121.66,16.97 121.05,16.36 121.05,15.37 119.41,13.73 118.82,13.73 118.72,13.63 118.72,13.53 R7008.2 118.49,12.55 D7001.3 ; R2044.2 112.11,32.44 112.44,32.77 113.03,32.77 v1(113.32,33.06) 112.95,33.43 112.95,34.23 113.56,34.84 113.56,35.83 113.56,35.83
FFS_INT2_Q: length 50.8
  TOP w0.102: R6001.1 183.36,24.63 v2(182.9,24.17) 182.9,23.75 v1(183.39,23.26)
  L4 w0.102: v1(147.32,8.12) 147.88,7.56 149.26,7.56 151.98,10.28 152.89,10.28 155.11,12.5 157,12.5 160.57,12.95 160.83,13.21 160.83,13.64 161.84,14.65 164.03,14.65 164.79,15.41 175.92,15.41 182.67,22.16 182.67,22.54 v1(183.39,23.26)
  BOTTOM w0.102: v1(147.32,8.12) 147.37,8.12 149.16,9.91 149.16,12.17 148.99,12.34 Q7001.6
FFS_INT2_Q_R: length 7.3
  TOP w0.102: v1(177.09,25) 177.14,25.05 v2(178.15,25.05) 179.92,25.05 180.61,24.35 181.74,24.35 R6001.2
  BOTTOM w0.102: HDD1.1 177.5,24.58 v1(177.09,25)
GC6_FB_EN: length 139.8
  TOP w0.127: v1(170.97,90.7) 170.74,90.93 v2(170.74,91.28)
  L4 w0.127: v1(108.51,27.93) 107.96,27.93 107.48,27.45 107.48,24.4 108.47,23.41 110.6,23.41 110.74,23.55 111.17,23.55 111.67,24.06 112.49,24.06 113.74,22.81 114.76,22.81 114.79,22.78 114.8,22.78 115.24,22.33 117.29,22.33 117.47,22.51 120.99,22.51 121.32,22.18 121.69,22.18 122.35,21.52 124.65,21.52 124.95,21.21 127.55,21.21 127.85,21.52 129.49,21.52 132.52,24.54 142.9,24.54 144.06,25.71 146.65,25.71 148.66,27.72 149.21,27.72 149.34,27.84 152.62,27.84 153.17,28.39 159.48,28.39 161.75,30.66 163.05,30.66 168.64,36.25 168.64,41.46 168.98,41.8 168.98,46.89 168.65,47.22 168.65,59.97 169.82,61.14 169.82,69.26 172.78,72.22 172.78,74.71 172.46,75.03 172.46,78.78 174.83,81.14 174.83,81.2 176.21,82.58 176.21,84.55 175.25,85.51 171.56,85.51 170.5,86.58 170.5,90.24 v1(170.97,90.7)
  BOTTOM w0.127: v1(170.97,90.7) 171.85,90.7 GPU1.C1 ; v1(108.51,27.93) 109.3,27.14 R2004.1
GC6_FB_EN_MCP: length 15.6
  TOP w0.127: v1(108.2,28.49) 108.89,28.49 v2(109.29,28.08)
  L4 w0.127: v1(108.68,39.51) 107.87,38.71 107.87,35.57 108.09,35.35 108.09,33.04 107.54,32.5 107.54,29.15 108.2,28.49 v1(108.2,28.49)
  BOTTOM w0.127: R2004.2 109.07,28.03 108.61,28.49 v1(108.2,28.49) ; CPU1.AP7 108.35,39.92 108.68,39.6 v1(108.68,39.51)
GC6_THM_DIS#: length 162
  TOP w0.127: v1(133.55,13.4) 132.89,12.74 v2(132.89,7.94) 132.89,2.1 133.16,1.83 133.94,1.05 145.61,1.05 146.68,2.13 v1(146.68,2.15)
  L3 w0.127: v1(115.29,43.6) 115.52,43.6 115.52,43.59 116.02,43.59 116.8,42.81 116.8,36.99 116.08,36.26 116.08,29.35 116.27,29.16 116.64,29.16 116.95,28.85 116.95,27.66 117.21,27.41 117.21,25.93 117.61,25.53 117.61,18.69 118.41,17.89 119.32,17.89 119.88,18.44 122.06,18.44 127.13,13.38 133.53,13.38 v1(133.55,13.4)
  L4 w0.127: v1(146.68,2.15) 148.08,3.55 150.11,3.55 152.28,5.72 156.21,5.72 158.38,7.89 185.9,7.89 187.12,9.11 190.95,9.11 196.02,14.18 196.02,31.44 193.72,33.74 193.72,36 195.2,37.48 196.26,37.48 197.8,39.02 197.8,43.26 197.72,43.34 197.72,44.07 v1(198.45,44.8)
  BOTTOM w0.127: CPU1.AB13 114.81,43.6 v1(115.29,43.6) ; R2420.2 197.94,44.29 v1(198.45,44.8)
GC6_THM_DIS#_EC: length 8.2
  TOP w0.127: v1(200.23,39.49) 199.78,39.04 KBC24.23
  BOTTOM w0.127: v1(200.23,39.49) 200.23,39.69 199.83,40.09 199.83,41.48 R2431.2 R2471.2 199.41,43.12 199.41,43.58 199.02,43.97 198.99,43.97 R2420.1 198.8,44.39 199.08,44.67 v2(199.08,45.13)
GPD2/LAN_WAKE#: length 82.4
  TOP w0.102: v2(59.99,17.42) v1(60.55,17.42)
  L3 w0.102: v1(60.55,17.42) 61.11,16.86 63.81,16.86 64.85,15.82 72.51,15.82 73.4,16.7 78.31,16.7 79.04,15.97 80.14,15.97 83.09,18.91 95.51,18.91 97.17,20.57 98.97,20.57 99.85,21.44 99.85,24.65 100.25,25.06 100.25,25.88 99.54,26.59 99.54,30.34 102.41,33.21 103.97,33.21 104.9,34.15 104.9,35.27 104.07,36.1 104.07,44.47 105.91,46.31 109.49,46.31 109.72,46.08 109.72,44.74 109.33,44.35 v1(109.33,44.08)
  BOTTOM w0.102: v1(60.55,17.42) 60.5,17.36 R1732.2 60.5,15.79 R1707.2 ; v1(109.33,44.08) 109.33,44.22 CPU1.AM15
GPD11/LANPHYPC: length 40
  TOP w0.102: v2(104.32,46.75) 104.47,46.6 v1(104.87,46.6)
  L4 w0.102: v1(104.87,46.6) 104.87,46.32 103.6,45.05 103.6,43.76 102.72,42.87 102.72,40.37 95.9,33.54 95.81,33.54 95.17,32.91 95.17,28.62 96.51,27.28 96.51,23.52 97.91,22.11 99.11,22.11 100.61,20.62 104.93,20.62 v1(105.23,20.92)
  BOTTOM w0.102: v1(104.87,46.6) 105.24,46.24 CPU1.AW17 ; v1(105.23,20.92) 105.08,20.77 RN1704.5
GPIO052/SPI_IO2: length 2.3
  TOP w0.102: v1(193.32,42.66) 193.61,42.95 KBC24.42
  BOTTOM w0.102: TP2402.1 v1(193.32,42.66)
GPP_A10/CLKOUT_LPC1: length 20.2
  TOP w0.089: v1(90.57,35.25) 91.14,35.25 92.9,37.01 TP1808.1
  BOTTOM w0.089: v1(90.57,35.25) 91.6,35.25 96.53,40.17 100.51,40.17 101.37,41.04 101.93,41.04 102.39,41.5 103.05,41.5 103.1,41.52 103.1,41.52 103.18,41.55 103.38,41.55 103.47,41.52 103.75,41.52 103.84,41.56 104.06,41.56 104.06,41.55 104.08,41.55 104.12,41.52 104.12,41.52 104.35,41.29 CPU1.AY9
GPP_E0/SATAXPCIE0/SATAGP0: length 4.9
  TOP w0.102: v1(122.43,33.95) 122.43,33.29 TP1602.1
  BOTTOM w0.089: 121.54,35.55 121.54,36.46 121.48,36.63 121.48,36.86 121.48,36.87 121.49,37 CPU1.H2
  BOTTOM w0.102: v1(122.43,33.95) 122.2,33.95 121.56,34.59 121.56,35.53 121.54,35.55
GPP_E1/SATAXPCIE1/SATAGP1: length 4.1
  TOP w0.102: TP1603.1 122.76,34.43 v1(122.35,34.84)
  BOTTOM w0.102: v1(122.35,34.84) 122.02,35.17 122.02,35.55 122.08,35.61 122.08,37.68 CPU1.H3
GPU_EVENT#: length 130.9
  L4 w0.127: v1(108.1,27.45) 107.73,27.08 107.73,24.51 108.58,23.66 110.5,23.66 110.64,23.8 111.05,23.8 111.64,24.4 111.64,24.69 111.9,24.95 112.4,24.95 114.28,23.07 114.86,23.07 115.35,22.58 117.19,22.58 117.37,22.76 121.1,22.76 121.43,22.43 121.79,22.43 122.45,21.77 124.75,21.77 125.06,21.47 127.44,21.47 127.75,21.77 129.39,21.77 132.41,24.79 142.79,24.79 143.96,25.96 146.54,25.96 148.55,27.97 149.11,27.97 149.41,28.27 152.69,28.27 153.06,28.64 159.37,28.64 161.7,30.97 163,30.97 168.39,36.36 168.39,41.56 168.73,41.9 168.73,46.79 168.4,47.12 168.4,60.07 169.37,61.04 169.37,69.18 171.85,71.67 171.85,78.55 174.56,81.26 174.56,83.27 v1(174.01,83.81)
  BOTTOM w0.127: v1(108.1,27.45) 108.88,26.67 v2(108.99,26.67) 110.37,26.67 R2003.1 ; v1(174.01,83.81) 174.33,83.49 175.98,83.49 177.26,84.77 177.26,85.7 GPU1.F10
GPU_EVENT_MCP#: length 16.6
  TOP w0.127: v1(108.19,29.13) 108.76,29.13 v2(108.86,29.23)
  L4 w0.127: v1(108.19,29.13) 107.8,29.52 107.8,32.45 108.38,33.03 108.38,35.65 109.08,36.36 109.08,39.77 108.62,40.23 v1(108.62,40.44)
  BOTTOM w0.127: v1(108.62,40.44) 108.62,40.5 CPU1.AN8 ; R2003.2 110.67,27.99 110.3,28.36 110.18,28.48 109,28.48 108.35,29.13 v1(108.19,29.13)
GPU_PWR_LEVEL: length 32.2
  TOP w0.102: R2474.2 v2(179.63,51.12) 179.63,51.1 179.35,50.82 v1(179.04,50.82) ; v1(196.85,34.51) 197.37,34.51 198.04,33.84 KBC24.10
  L3 w0.102: v1(179.04,50.82) 179.04,50.53 179.55,50.02 180.24,48.24 180.24,46.3 181.17,45.36 181.17,44.75 182.88,43.04 183.86,43.04 184.52,43.7 186.68,43.7 186.85,43.53 189.01,43.53 189.91,42.62 189.91,42.62 190.16,42.37 190.2,42.34 190.37,42.18 190.37,41.8 190.59,41.58 190.92,41.58 196.85,35.65 v1(196.85,34.51)
GPU_THM_SMBCLK: length 2.9
  TOP w0.089: KBC24.12 198.04,34.64 197.79,34.89 197.79,35.27 197.48,35.58 v1(197.28,35.58)
  BOTTOM w0.089: v1(197.28,35.58) 197.69,35.58 R2459.1
GPU_THM_SMBDAT: length 4.1
  TOP w0.089: v1(197.33,34.94) 197.35,34.94 198.05,34.24 KBC24.11
  BOTTOM w0.089: v2(197.53,34.41) 197.33,34.61 v1(197.33,34.94) 198.09,34.94 198.45,34.59 R2447.1
GSEN2_INT1: length 96
  TOP w0.102: U7001.12 177.41,41.73 177.6,41.55 178.15,41.55 v1(178.56,41.14) ; R7009.2 R7012.2 117.85,20.51 118.06,20.72 119.76,20.72 120.6,19.88 121.64,19.88 123.14,18.38 v2(123.87,18.38) 125.4,18.38 126.8,19.78 129.14,19.78 v1(129.67,19.25)
  L3 w0.102: v1(178.56,41.14) 179.2,40.5 179.2,39.58 178.74,39.13 178.74,32.31 178.59,32.15 178.59,29.93 178.15,29.5 178.15,22.39 177.13,21.37 176.7,21.37 174.67,19.33 174.14,19.33 170.31,15.51 167.66,15.51 165.33,13.18 165.33,11.9 162.99,9.56 v1(162.99,9.11)
  L6 w0.102: v1(162.99,9.11) 158.04,9.11 157.3,8.37 151.41,8.37 149.02,10.76 143.51,10.76 142.82,11.45 142.82,12.11 142.06,12.87 139.78,12.87 136.7,15.94 132.97,15.94 v1(129.67,19.25)
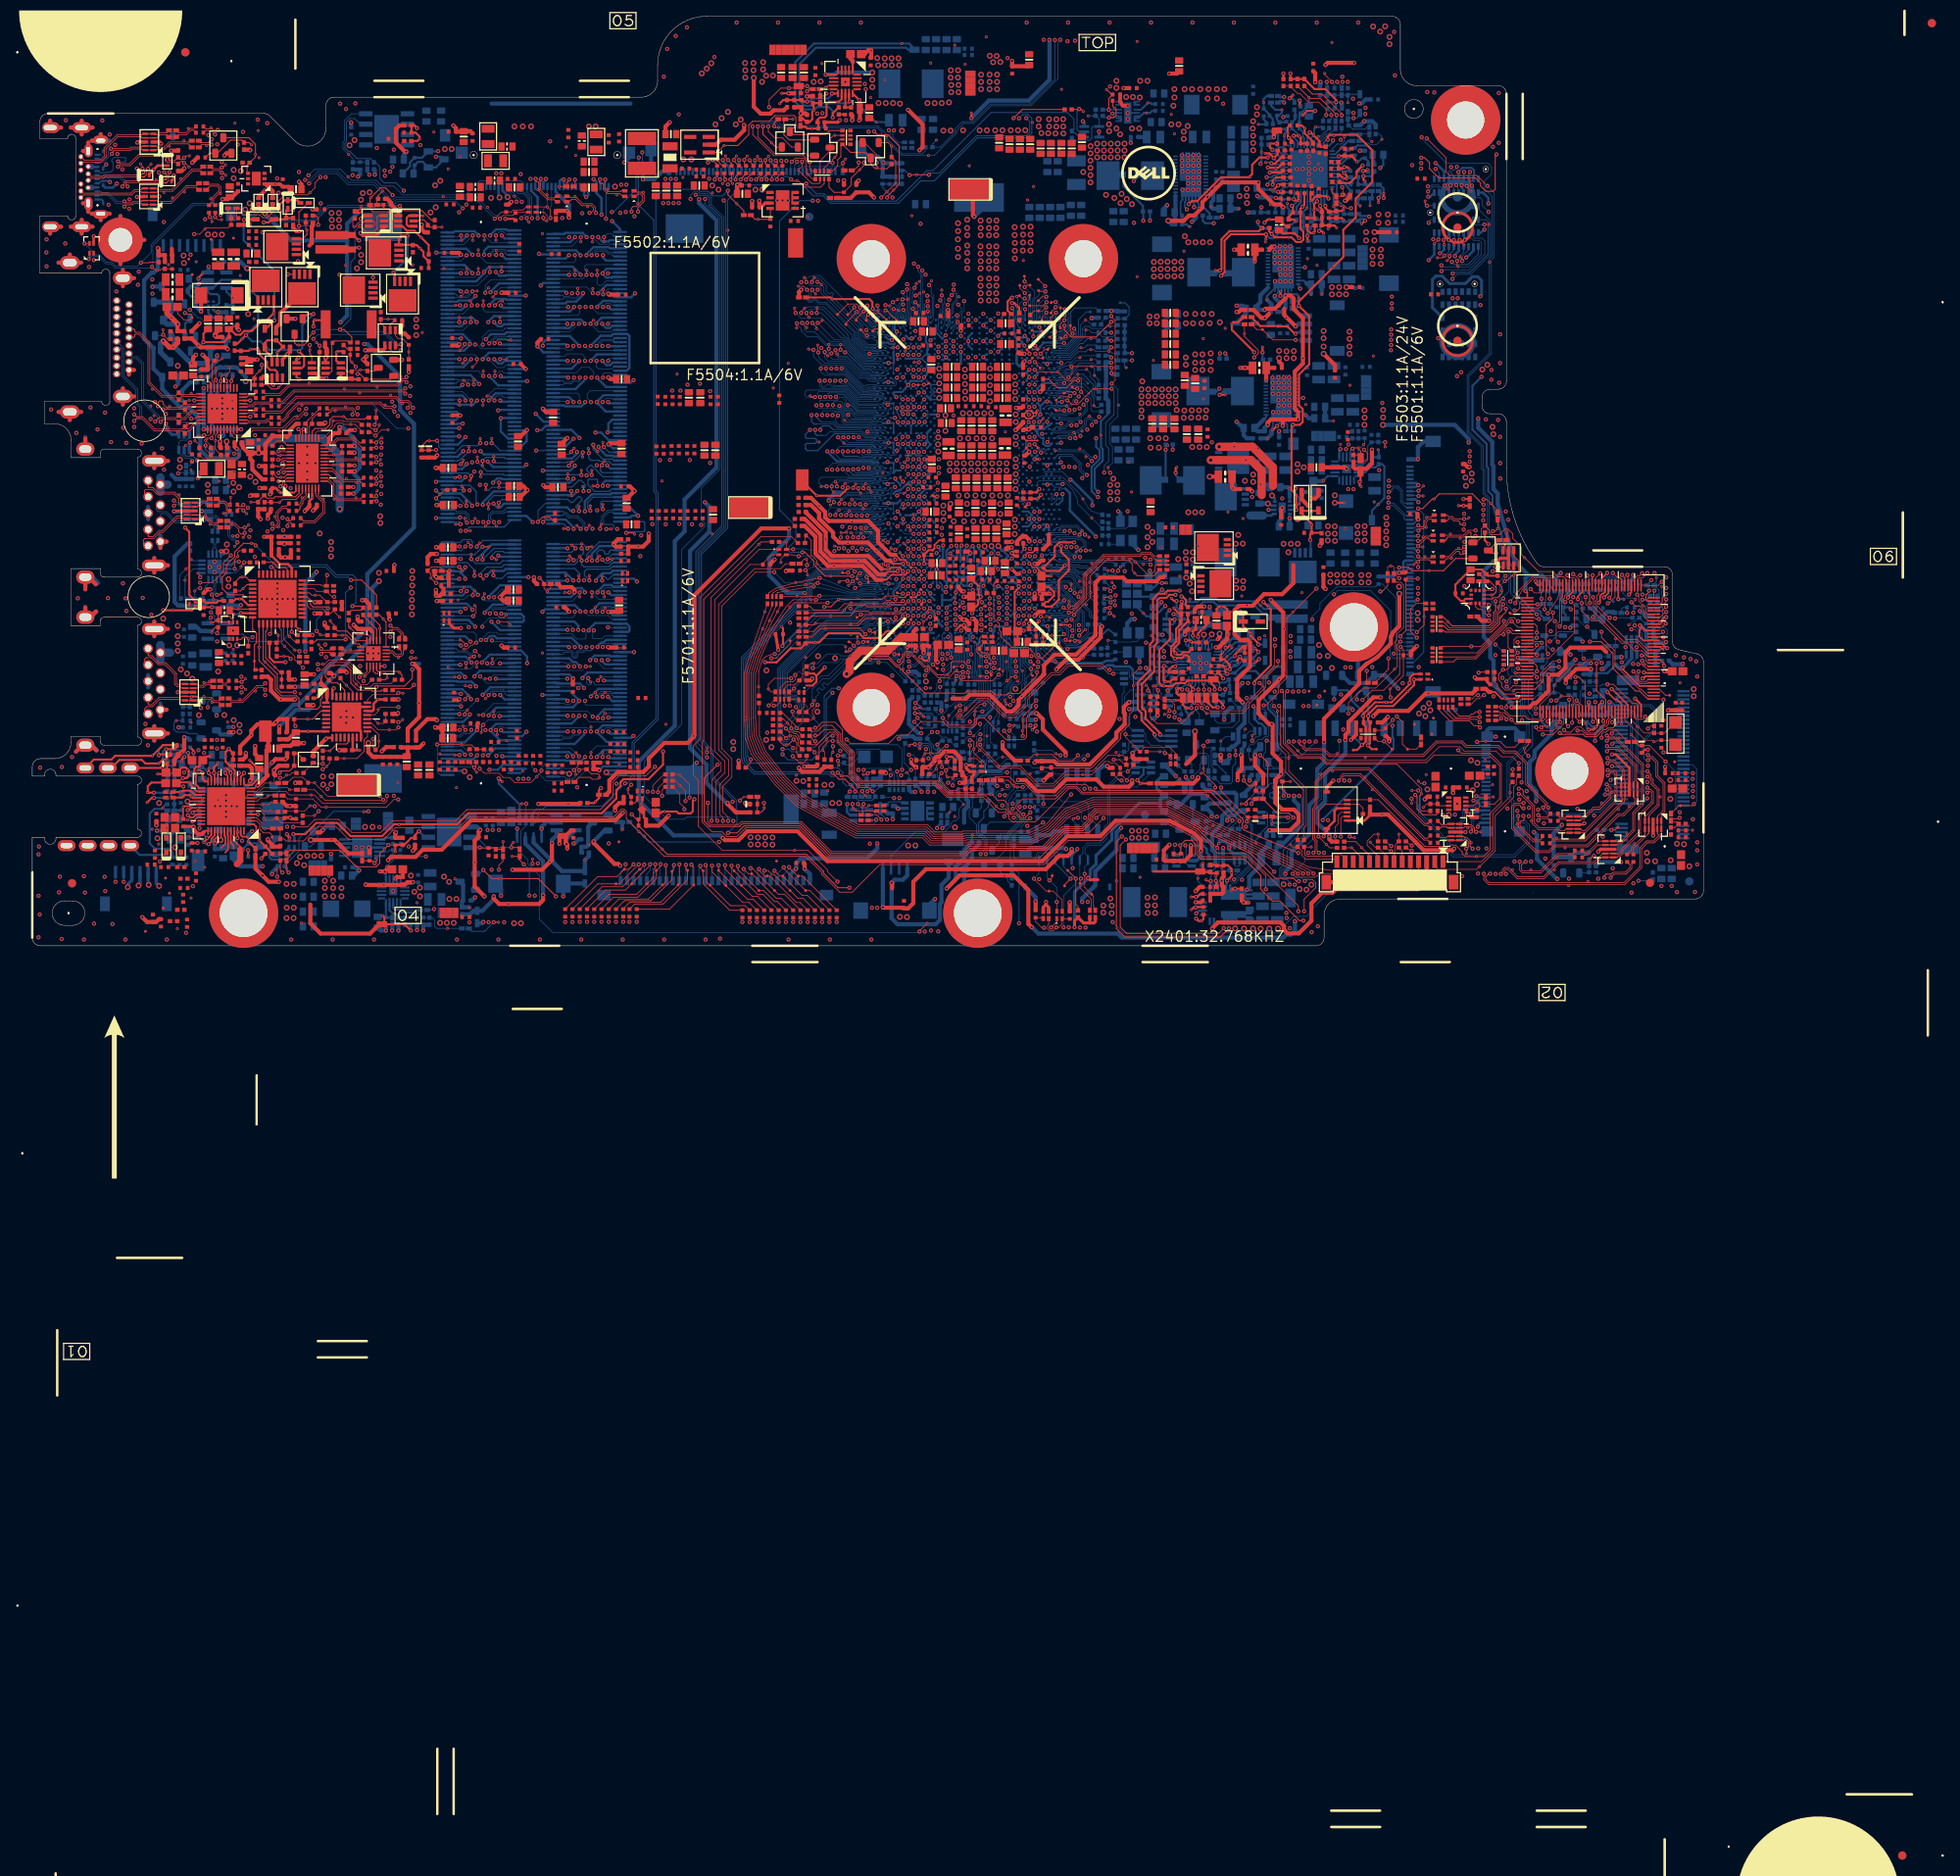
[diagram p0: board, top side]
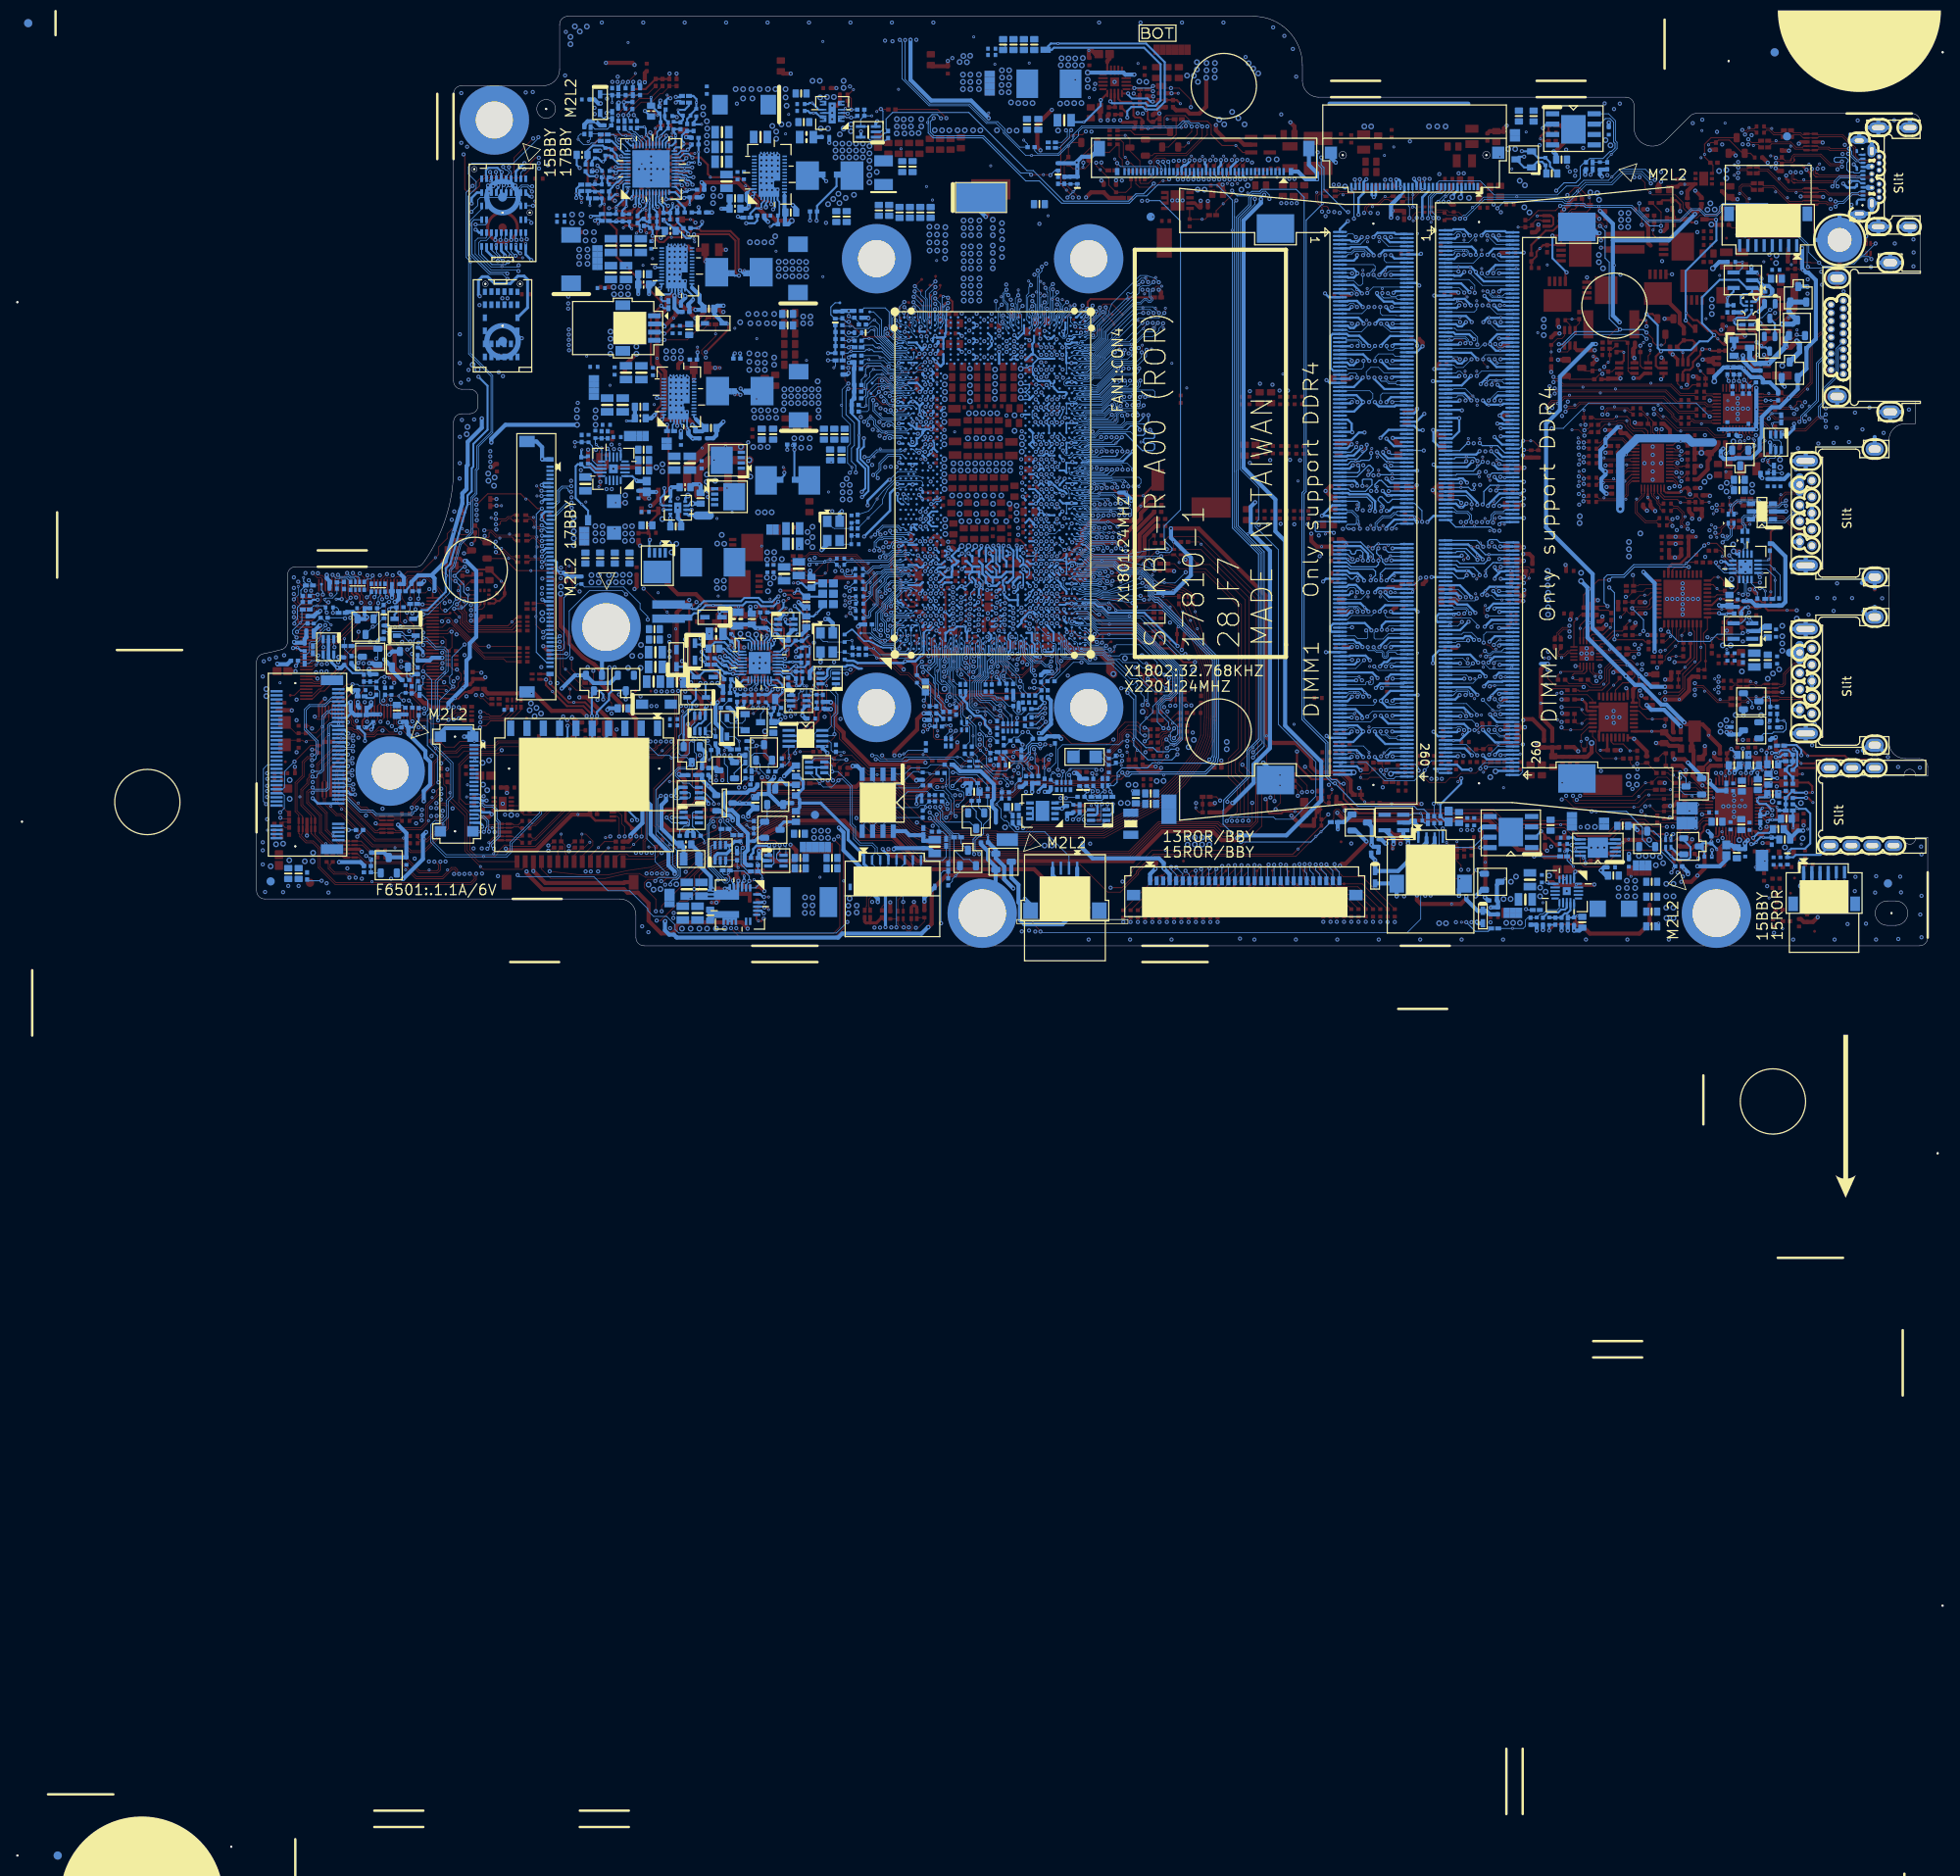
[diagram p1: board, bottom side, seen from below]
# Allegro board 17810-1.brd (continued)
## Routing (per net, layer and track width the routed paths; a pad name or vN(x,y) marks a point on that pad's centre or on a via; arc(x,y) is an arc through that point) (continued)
GSEN2_INT1_C: length 30.9
  TOP w0.102: R7009.1 v2(116.15,19.24) 116.15,19.04 115.9,18.79 112.39,18.79 110.92,20.26 101.71,20.26 100.71,21.26 100.71,23.72 99.29,25.14 99.29,26.51 98.4,27.4 96.82,27.4 96.14,26.71 v1(95.98,26.71) ; R2025.2 95.93,25.06 v1(95.98,25.06)
  BOTTOM w0.102: v1(95.98,25.06) 95.86,25.06 95.5,25.42 95.5,26.48 95.73,26.71 v1(95.98,26.71)
GSEN2_INT1_ISH: length 26.8
  TOP w0.102: R2035.1 92.07,27.78 v2(92.58,27.27) 93.04,26.81 v1(93.04,26.64) 93.44,26.23 93.9,26.23 R2025.1
  BOTTOM w0.102: v1(93.04,26.64) 93.04,27.37 94.23,28.57 94.23,29.52 93.43,30.32 92.87,30.32 92.15,31.04 92.15,33.61 97.19,38.65 101.75,38.65 102.56,39.46 103.07,39.46 103.71,40.1 CPU1.BA7
GSEN2_INT2: length 69.8
  TOP w0.102: v1(178.56,40.5) 178.36,40.5 v2(178,40.86) 177.6,41.27 177.21,41.27 176.91,41.57 U7001.11
  L3 w0.102: v1(148.28,8.09) 148.77,8.58 152.37,8.58 153.17,9.38 162.52,9.38 165.13,11.98 165.13,13.27 167.58,15.71 170.23,15.71 174.05,19.54 174.58,19.54 176.62,21.57 177.04,21.57 177.95,22.48 177.95,29.58 178.38,30.02 178.38,32.24 178.54,32.39 178.54,39.21 178.99,39.66 178.99,40.07 v1(178.56,40.5)
  BOTTOM w0.102: R7010.2 146.99,14.14 R7013.2 146.99,14.55 147.55,15.11 147.55,15.46 147.8,15.71 149,15.71 149.27,15.44 149.27,15.39 149.3,15.36 149.3,15.09 149.57,14.82 149.57,9.68 148.28,8.4 v1(148.28,8.09)
GSEN2_INT2_C: length 65.1
  TOP w0.102: v1(147.12,15.36) v2(144.1,18.38) 143.86,18.61 128.65,18.61 127.95,19.31 127.08,19.31 122.97,15.2 120.12,15.2 119.73,15.59 119.73,15.92 119.3,16.35 118.41,16.35 116.58,18.18 112.14,18.18 110.67,19.65 101.45,19.65 100.1,21.01 100.1,23.46 98.65,24.91 98.65,25.8 98.27,26.18 97.71,26.18 96.16,24.63 95.5,24.63 R2026.2
  BOTTOM w0.102: R7010.1 145.54,13.65 147.12,15.23 v1(147.12,15.36)
GSEN2_INT2_ISH: length 30.7
  TOP w0.102: R2033.1 92,27.02 v1(92.38,26.64) 92.43,26.64 92.86,26.2 93.18,26.2 93.36,26.03 93.62,26.03 93.95,25.7 93.95,25.39 94.36,24.99 R2026.1
  BOTTOM w0.102: CPU1.AY7 104.3,40.16 104.09,40.37 102.91,40.37 101.95,39.41 v2(100.3,39.41) 97.37,39.41 91.74,33.78 91.74,25.49 92.22,25.01 92.58,25.01 92.84,25.26 92.84,26.08 92.38,26.53 v1(92.38,26.64)
GSEN_INT1: length 136.6
  TOP w0.102: v1(93.22,23.23) 94.05,22.39 v2(94.26,22.39) 94.51,22.39 94.92,22.8 R2023.2
  L3 w0.102: v1(93.22,23.23) 90.45,20.46 82.24,20.46 81.89,20.12 74.7,20.12 73.67,19.09 71.35,19.09 70.68,19.75 69.44,19.75 68.48,18.8 66.59,18.8 65.71,19.68 56.37,19.68 55.49,18.79 53.44,18.79 45.91,26.32 45.91,31.58 45.14,32.34 45.14,37.52 47.6,39.97 47.6,85.08 49.29,86.77 50.14,86.77 53.69,90.32 55.16,90.32 55.3,90.3 55.33,90.29 55.33,90.29 55.46,90.26 55.46,90.26 55.8,90.2 56.24,89.75 58.52,89.75 59.1,89.17 v1(59.94,89.17)
  BOTTOM w0.102: v1(59.94,89.17) 60.32,89.55 60.35,89.55 60.79,90 60.79,91.61 60.21,92.19 59.56,92.19 59.15,92.6 TCBD1.9
GSEN_INT1_ISH: length 31.1
  TOP w0.102: R2023.1 94.04,23.28 93.7,23.63 93.7,24.91 v1(93.32,25.29) 92.61,24.58 v2(92.4,24.58) 92.07,24.58 91.67,24.98 R2031.1
  BOTTOM w0.102: CPU1.BA8 102.99,40.72 102.03,39.77 97.44,39.77 91.54,33.87 91.54,25.41 92.14,24.81 92.84,24.81 v1(93.32,25.29)
GSEN_INT2: length 137.7
  TOP w0.102: R2024.2 95.52,24.1 v1(95.89,23.72) ; v1(60.6,89.2) 60.6,88.97 v2(60.88,88.69)
  L3 w0.102: v1(60.6,89.2) 60.15,88.74 59.23,88.74 58.42,89.55 56.15,89.55 55.7,90.01 55.35,90.08 55.23,90.1 55.23,90.1 55.14,90.12 53.78,90.12 50.23,86.57 49.37,86.57 47.8,84.99 47.8,39.82 45.35,37.36 45.35,32.43 47.12,30.66 47.12,25.4 53.52,19 55.4,19 56.28,19.88 66.83,19.88 67.37,20.42 67.52,20.52 67.62,20.56 67.68,20.62 68.63,20.62 69.2,20.06 70.79,20.06 71.55,19.3 73.58,19.3 74.61,20.32 81.81,20.32 82.15,20.67 90.04,20.67 93.1,23.72 v1(95.89,23.72)
  BOTTOM w0.102: v1(60.6,89.2) 61,89.59 61,91.7 60.3,92.4 59.94,92.4 59.65,92.69 TCBD1.10
GSEN_INT2_ISH: length 28.8
  TOP w0.102: R2032.1 91.67,26.18 v1(92.4,25.44) 92.68,25.72 v2(92.94,25.72) 93.52,25.72 93.75,25.49 93.75,25.31 93.9,25.16 93.9,24.58 94.36,24.12 R2024.1
  BOTTOM w0.102: v1(92.4,25.44) 91.95,25.9 91.95,26.86 94.03,28.95 94.03,29.43 93.34,30.12 92.79,30.12 91.95,30.96 91.95,33.7 97.23,38.98 101.8,38.98 102.92,40.1 CPU1.BB7
GSENSOR_CS: length 4
  TOP w0.127: R7006.1 180.14,43.98 v2(180.14,43.53) 180.14,43.2 179.61,42.68 179.16,42.68 179,42.52 U7001.2
GSENSOR_SDO: length 5
  TOP w0.127: R7005.2 177.81,45.11 177.9,45.11 178.23,44.79 R7007.2 178.66,44.67 179.41,43.91 179.41,43.34 179.08,43.01 v2(178.88,43.01) 178.87,43.01 U7001.3
GT_CORE: length 1.8
  L3 w0.508: v1(126.12,64.01) 125.53,64.01
  BOTTOM w0.254: CPU1.A48 125.98,64.02 126,64.01 v1(126.12,64.01) ; v1(126.21,66.67) 125.75,66.67 CPU1.A53
  vias: v2(119.28,62.98) v3(120.55,65.12) v3(120.55,64.2) v3(120.55,62.37) v3(120.55,61.46)
GTX_CORE: length 1
  BOTTOM w0.127: CPU1.AM52 109.78,65.44 109.78,64.79 CPU1.AM50
  vias: v1(111.05,63.06) v3(111.05,62.32) v3(111.02,61.46) v3(111.05,60.57)
GYRO_DRDY: length 152.3
  TOP w0.102: v1(101.73,18.94) 101.73,18.81 v2(102.13,18.41)
  L3 w0.102: v1(101.73,18.94) 101.33,19.33 99.36,19.33 98.42,18.39 96.68,18.39 96.23,17.95 94.54,17.95 93.18,16.59 82.82,16.59 81.23,15 64.1,15 62.95,16.15 52.85,16.15 43.3,25.69 43.3,27.83 41.74,29.39 41.74,33.84 40.71,34.87 40.71,36.01 42.84,38.13 42.84,42.37 45.46,45 45.46,63.82 47.09,65.45 47.09,70.73 46.33,71.49 46.33,84.88 48.26,86.81 48.38,86.81 49.3,87.73 49.3,87.85 52.73,91.28 54.63,91.28 55.43,90.48 55.48,90.47 55.9,90.38 56.32,89.96 60.48,89.96 v1(61.26,89.17)
  BOTTOM w0.102: v1(101.73,18.94) 102.28,19.5 R2028.2 ; v1(61.26,89.17) 61.2,89.23 61.2,91.84 60.65,92.39 TCBD1.12
GYRO_DRDY_ISH: length 36.1
  TOP w0.102: v2(101.87,20.99) 102.28,20.99 v1(102.41,21.12) 102.59,21.3 R2034.1
  L3 w0.102: v1(108.03,44.08) 107.63,44.48 106.56,44.48 104.48,42.39 104.48,38.02 106.31,36.19 107.22,36.19 107.89,35.52 107.89,34.01 107.8,33.92 107.8,33.44 106.6,32.24 106.6,27.88 104.42,25.7 102.32,25.7 100.81,24.2 100.81,21.4 101.09,21.12 v1(102.41,21.12)
  BOTTOM w0.102: R2028.1 102.28,21 v1(102.41,21.12) ; v1(108.03,44.08) 108.35,43.76 CPU1.AP13
GYRO_INT: length 221.1
  L3 w0.102: v1(120.95,2.76) 119.96,3.74 119.96,5.45 119.73,5.67 117.52,7.89 109.24,7.89 104.8,3.45 61.21,3.45 60.86,3.8 48.08,3.8 45.34,6.54 45.34,9.75 44.04,11.04 42.7,11.04 42.23,10.57 38.97,10.57 37.01,12.54 37.01,16.3 35.05,18.25 35.05,25.82 32.18,28.69 31.85,28.69 30.61,29.93 30.61,38.21 33.15,40.75 33.15,44.03 32.87,44.31 32.87,56.6 32.65,56.81 32.28,57.18 32.17,57.3 32.17,61.46 31.6,62.03 31.6,69.1 33.59,71.1 33.59,79 35,80.41 35,85.11 33.95,86.16 33.95,89.51 33.5,89.95 33.5,92.19 34.36,93.06 34.36,93.92 v1(33.86,94.43)
  BOTTOM w0.102: R7002.2 R7003.2 120.62,9.19 120.95,8.86 v1(120.95,2.76) ; TCBD1.11 60.15,93.48 59.89,93.74 54.84,93.74 53.12,92.03 45.38,92.03 44.29,93.12 42.86,93.12 42.16,93.82 39.14,93.82 v2(38.71,94.25) 37.79,95.17 34.59,95.17 v1(33.86,94.43)
GYRO_INT_C: length 42.2
  TOP w0.102: v1(122.34,16.35) 122.34,16.33 121.67,15.66 121.29,15.66 120.61,16.35 119.99,16.35 119.56,16.78 119.56,17.39 119.1,17.85 118.32,17.85 117.59,18.58 v2(117.52,18.58) 112.31,18.58 111.01,19.88 110.83,20.06 101.62,20.06 100.51,21.18 100.51,23.63 99.08,25.05 99.08,25.94 98.01,27.02 96.95,27.02 96.21,26.28 95.53,26.28 R2027.2
  BOTTOM w0.102: v1(122.34,16.35) 122.34,16.33 121.8,15.8 121.8,15.54 119.89,13.63 119.89,10.56 120.06,10.38 R7003.1
GYRO_INT_ISH: length 28.1
  TOP w0.102: R2027.1 93.8,26.53 v1(93.67,26.66) 93.67,26.86 92,28.54 R2036.1
  BOTTOM w0.089: CPU1.AW7 105.24,39.94 105.26,39.92 105.26,39.57 105.02,39.34 104.57,39.34 104.44,39.21 104.29,39.21
  BOTTOM w0.102: v1(93.67,26.66) 94.44,27.42 94.44,29.6 93.51,30.52 92.97,30.52 92.37,31.12 92.37,33.46 97.07,38.17 v2(100.35,38.17) 101.55,38.17 102.64,39.26 103.81,39.26 103.83,39.29 104.11,39.29 104.19,39.21 104.29,39.21
GYRO_INT_P11: length 3
  BOTTOM w0.102: R7002.1 119.56,7.92 119.56,8.17 v2(119.18,8.55) 118.64,9.09 D7001.1
H_CATERR#: length 1.7
  TOP w0.102: TP401.1 124.12,73.09 v1(123.59,72.56)
  BOTTOM w0.102: v1(123.59,72.56) 123.96,72.19 CPU1.D63
H_CPU_SVIDALRT#: length 6.5
  BOTTOM w0.114: R728.2 130.42,74.42 v2(129.77,74.42) 129.39,74.42 128.78,73.82 128.45,73.82 127.04,72.41 125.73,72.41 125.45,72.13 CPU1.B63
H_CPU_SVIDCLK: length 5.5
  BOTTOM w0.114: R732.1 130.4,73.63 129.31,73.63 128.98,73.3 v2(128.57,73.3) 128.56,73.3 128.29,73.3 127.13,72.13 CPU1.A63
H_CPU_SVIDDAT: length 11.1
  BOTTOM w0.114: CPU1.D64 124.29,72.04 124.49,71.83 125.94,71.83 125.96,71.85 127.2,71.85 128.17,72.81 129.16,72.81 129.41,73.07 v2(129.77,73.07) 130.1,73.07 130.31,72.86 132.14,72.86 132.36,72.64 R726.2 133.04,71.77 R709.1
H_CPUPWRGD: length 13.3
  TOP w0.127: v1(126.52,76.01) 126.52,75.46 127.36,74.62 130.4,74.62 v1(132.26,76.47)
  BOTTOM w0.127: CPU1.A68 126.02,75.26 126.52,75.76 v1(126.52,76.01) ; v1(132.26,76.47) 132.56,76.47 132.99,76.9 R1714.1 133.08,76.86 ED1701.1 133.97,76.86 134.45,77.35 134.45,78.29 133.93,78.81 TP1705.1
H_PECI: length 6.1
  TOP w0.114: KBC24.94 181.97,31.04 181.78,30.85 180.36,30.85 180.36,30.85 v2(179.59,31.61) 179.59,32.05 179.25,32.4 C2405.1 179.25,33.52 R2437.1
H_PECI_CPU: length 86.2
  TOP w0.114: v1(132.31,68.27) v2(130.38,68.27) 130.04,68.27 128.82,67.05 128.82,67.03 128.13,66.34 127.42,66.34 126.92,66.84 v1(126.87,66.84) ; v1(177.29,33.47) 177.37,33.54 R2437.2
  L6 w0.102: v1(131.39,58) 131.11,57.73 131.11,54.28 131.71,53.69 135.69,53.69 137.84,51.53 137.84,45.23 137.56,44.95 137.56,43.27 138.29,42.55 138.61,42.55 140.87,40.29 140.87,37.36 142.39,35.83 143.64,35.83 145.04,34.43 152.48,34.43 154.13,32.78 164.49,32.78 164.95,33.24 170.61,33.24 171.14,33.77 176.99,33.77 v1(177.29,33.47)
  BOTTOM w0.114: CPU1.A54 125.97,67.12 126.34,67.12 126.62,66.84 v1(126.87,66.84) ; v1(131.39,58) 131.39,58.84 131.93,59.37 131.93,60.98 131.57,61.33 131.57,64.08 132.59,65.1 132.59,67.98 v1(132.31,68.27)
H_PROCHOT#: length 202.6
  TOP w0.089: v1(132.31,68.9) 132.74,69.33 132.74,76.62 132.26,77.11 v1(132.26,77.18) ; v1(140.01,28.64) 140.01,29.57 139.39,30.19 PR4455.1 ; v1(158.61,101.82) 158.61,102.49 157.7,103.4 156.42,103.4 155.36,104.46 155.09,104.46 154.25,105.3 PR4624.2 PR4669.2 ; v1(152.32,36.8) 152.28,36.75 152.28,34.35 150.88,32.96 150.88,31.78 148.87,29.77 148.87,29.39 148.27,28.79 144.37,28.79 v1(144.02,29.14) 143.58,29.58 143.3,29.58 142.87,30.01 PG4419.2
  L4 w0.127: v1(132.26,77.18) 133.69,75.75 151.57,75.75 152.81,76.99 153.68,77.86 154.1,77.86 161.31,77.86 166.89,83.44 166.89,92.12 166.32,92.69 166.32,95.87 163.54,98.65 161.65,98.65 161.06,99.23 161.06,99.24 158.61,101.69 v1(158.61,101.82)
  L6 w0.102: v1(144.02,29.14) 144.02,28.94 143.71,28.64 v1(140.01,28.64) ; v1(190.6,39.11) 190.46,38.97 189.2,38.97 188.78,38.55 187.2,38.55 186.45,39.29 180.12,39.29 179.71,38.88 168.59,38.88 163.97,43.5 159.03,43.5 v1(152.32,36.8) 151.31,36.8 150.98,36.47 149.99,36.47 148.5,34.98 145.17,34.98 143.84,36.31 143.38,36.31 141.83,37.86 141.83,40.01 138.81,43.03 138.49,43.03 138.05,43.47 138.05,44.75 138.33,45.03 138.33,51.73 135.89,54.17 131.91,54.17 131.6,54.48 131.6,57.45 v1(132.13,57.98)
  BOTTOM w0.089: PR4668.2 158.21,101.43 v1(158.61,101.82) ; R2418.2 189.23,40.86 ED2401.1 189.32,40.14 190.35,39.11 v1(190.6,39.11) 191.49,38.21 Q2408.D ; PR4445.2 144.07,29.76 144.07,29.23 144.02,29.18 v1(144.02,29.14) ; R403.1 131.01,76.41 131.57,76.97 R401.2 132.05,76.98 v1(132.26,77.18) ; v1(132.31,68.9) 132.35,68.9 133.08,68.18 133.08,64.9 132.06,63.88 132.06,61.53 132.41,61.18 132.41,59.17 v2(131.88,58.64) 131.88,58.23 v1(132.13,57.98)
H_PROCHOT#_R: length 8.2
  BOTTOM w0.089: CPU1.C65 124.85,73.26 125.12,72.98 126.69,72.98 128.5,74.79 128.5,76.09 v2(129.1,76.7) 129.26,76.7 129.82,76.14 R403.2
H_VCCST_PWRGD: length 45
  L3 w0.127: v1(105.45,91.71) 119.56,91.71 122.92,88.36 122.92,77.17 125.24,74.85 126.16,74.85 126.46,75.15 127.05,75.15 127.53,75.63 v1(127.71,75.63)
  BOTTOM w0.127: R1716.2 R1719.1 105.81,93.36 C1711.1 104.25,93.36 ED1708.1 104.24,92.92 v2(104.76,92.4) v1(105.45,91.71) ; v1(127.71,75.63) 127.94,75.4 127.94,74.79 127.36,74.21 127.36,74.2 126.63,73.47 126.16,73.47 126.09,73.54 125.74,73.54 125.46,73.26 CPU1.B65
HDA_BITCLK: length 14
  TOP w0.089: v1(93.95,47.74) 93.06,47.93 RN1902.3 92.28,47.93 91.77,47.41 v2(91.77,46.98)
  BOTTOM w0.089: v1(93.95,47.74) 93.98,47.77 102.28,47.77 102.91,48.16 103.46,48.32 103.61,48.47 103.61,48.65 103.79,48.82 103.96,48.83 104.25,48.77 CPU1.AY22
HDA_CODEC_BITCLK: length 96.9
  TOP w0.089: R2720.1 30.89,18.41 31.3,18 EC2709.1 34.39,18 35.4,16.99 v2(36.02,16.99) 43.39,16.99 44.33,17.93 v1(44.86,17.93) ; v1(83.97,15.33) 83.97,15.34 83.78,15.54 83.78,20.1 84.9,21.21 84.9,22.59 83.65,23.83 83.65,42.4 87.98,46.73 EC1901.2 89.56,46.88 90.61,47.93 RN1902.2
  L3 w0.127: v1(44.86,17.93) 48.42,17.93 53.86,12.49 62.29,12.49 63.27,11.51 68.95,11.51 70.49,13.05 81.77,13.05 83.97,15.25 v1(83.97,15.33)
HDA_CODEC_SDIN0: length 6.1
  TOP w0.089: R2718.2 31.56,19.12 v2(31.55,19.13) 31.3,19.37 28.34,19.37 27.48,18.51 HDA27.10
HDA_CODEC_SDOUT: length 98.4
  TOP w0.089: R2719.1 31.27,19.96 31.97,20.66 33.13,20.66 EC2708.1 v2(34.59,19.98) 34.59,19.94 36.24,18.29 42.53,18.29 v1(42.62,18.38) ; v1(83.26,15.33) 83.31,15.38 83.31,20.34 84.43,21.45 84.43,22.39 83.18,23.64 83.18,42.67 89.09,48.58 RN1902.1
  L3 w0.127: v1(83.26,15.33) 83.26,15.26 81.56,13.56 70.28,13.56 68.74,12.02 63.49,12.02 62.5,13 54.07,13 48.19,18.88 46.98,18.88 46.85,18.76 46.85,18.56 46.72,18.44 46.47,18.44 46.34,18.56 46.34,18.76 46.22,18.88 45.96,18.88 45.83,18.76 45.83,18.56 45.71,18.44 45.45,18.44 45.33,18.56 45.33,18.76 45.2,18.88 43.12,18.88 v1(42.62,18.38)
HDA_CODEC_SYNC: length 103.3
  TOP w0.089: HDA27.9 27.47,18.11 27.47,18.12 28.25,18.9 31.11,18.9 31.53,18.48 v2(34.19,18.48) 34.2,18.47 34.58,18.47 35.6,17.46 43.19,17.46 43.48,17.75 v1(43.48,18.38) ; v1(84.66,15.31) 84.66,15.71 84.25,16.12 84.25,19.75 85.37,20.87 85.37,22.78 84.12,24.03 84.12,41.8 88.54,46.22 91.74,46.22 92.35,46.83 R1908.1
  L3 w0.127: v1(84.66,15.31) 84.66,15.14 82.05,12.54 72.23,12.54 70.7,11 63.06,11 62.51,11.56 54.07,11.56 48.27,17.36 44.66,17.36 43.65,18.38 v1(43.48,18.38)
HDA_RST#: length 12.5
  TOP w0.089: EC1902.1 94.74,45.99 v1(94.79,46.04) 95.02,45.81 v2(95.02,45.45)
  BOTTOM w0.089: CPU1.AW22 104.74,48.3 104.57,48.3 104.11,48.28 103.86,48.17 103.49,47.8 103.06,47.8 102.64,47.38 99.52,47.38 96.44,46.7 v1(94.79,46.04)
HDA_SDIN0: length 108.8
  TOP w0.089: v1(90.96,45.79) 88.64,45.79 84.49,41.63 84.49,24.18 85.75,22.92 85.75,20.67 84.62,19.54 84.62,16.44 85.29,15.76 v1(85.29,15.31) ; 33.32,19.12 34.6,19.12 v2(35.42,18.29) 35.9,17.82 42.96,17.82 v1(43.03,17.89)
  L3 w0.127: v1(85.29,15.31) 85.29,15.03 84.62,14.36 82.4,12.13 72.4,12.13 70.87,10.6 62.9,10.6 62.34,11.15 53.9,11.15 48.1,16.96 44.49,16.96 43.56,17.89 v1(43.03,17.89)
  BOTTOM w0.089: CPU1.BA21 103.93,47.99 103.57,47.62 103.13,47.62 102.69,47.18 99.58,47.18 98.7,46.3 96.24,46.3 94.41,44.47 92.28,44.47 v1(90.96,45.79)
HDA_SDOUT: length 12.9
  TOP w0.089: R1909.2 v2(92.45,49.5) 92.45,48.6 RN1902.4 93.24,48.58 v1(93.27,48.61)
  BOTTOM w0.089: v1(93.27,48.61) 93.32,48.66 94.51,48.66 98.02,47.99 102.18,47.99 102.77,48.28 102.83,48.31 CPU1.BB22
HDA_SPKR_R: length 6.7
  BOTTOM w0.254: RN2701.3 32.12,11.66 31.47,11.01 v2(31.47,10.99) 31.04,10.56 29.35,10.56 29.08,10.83 29.08,12.11 29.91,12.93 D2701.1
HDA_SYNC: length 11.6
  TOP w0.089: v1(94.97,46.65) 94.97,47.31 v2(94.89,47.39) 94.61,47.39 R1908.2
  BOTTOM w0.089: CPU1.BA22 103.94,48.49 103.42,47.98 102.99,47.98 102.57,47.57 95.93,47.57 95.02,46.65 v1(94.97,46.65)
HDD_CT: length 2.7
  TOP w0.102: U6002.6 176.66,17.17 177.06,17.57 v2(177.21,17.57) 177.42,17.36 177.42,17.01 C6007.1
HDD_DET#: length 5
  TOP w0.102: TP1806.1 120.01,32.96 v1(120.55,32.96)
  BOTTOM w0.102: v1(120.55,32.96) 120.2,33.3 120.2,33.72 119.75,34.18 119.75,36.01 119.75,36.02 CPU1.M1
HDD_DEVSLP: length 93.1
  TOP w0.102: v1(153.85,31.21) 153.57,30.93 153.57,24.86 155.25,23.17 157.96,23.17 158.67,22.46 170.9,22.46 171.83,23.38 178.56,23.38 179.86,22.08 179.86,18.01 179.22,17.36 178.18,17.36
  L4 w0.102: v1(120.25,30.02) 120.45,29.82 120.45,26.08 121.23,25.29 122.15,25.29 122.48,24.96 128.5,24.96 134,30.46 134.7,30.46 137.49,27.68 139.43,27.68 139.8,27.3 140.79,27.3 141.15,27.66 141.15,29.11 142.18,30.14 146.64,30.14 148.03,31.54 151.79,31.54 151.89,31.64 152.47,31.64 152.73,31.38 152.73,31.05 152.98,30.8 153.44,30.8 v1(153.85,31.21)
  BOTTOM w0.102: CPU1.J1 121.08,35.21 121.18,35.11 121.18,33.87 v2(121.36,33.7) 121.36,32.48 120.91,32.03 120.36,32.03 119.99,31.66 119.99,31.01 120.3,30.7 120.3,30.06 v1(120.25,30.02)
HDD_DEVSLP_R: length 3.4
  TOP w0.102: v1(177.01,18.33) 177.11,18.23 R6002.2 178.19,18.24 v2(179.09,18.24)
  BOTTOM w0.102: v1(177.01,18.33) 177.29,18.33 177.54,18.58 HDD1.13
HDD_EN: length 4.2
  TOP w0.102: U6002.3 172.49,17.17 R6005.2 ; R6005.2 172.24,17.42 C6008.1 ; R6005.2 R6007.2 170.94,17.39 v2(170.51,16.96)
HDD_EN_PCH: length 82.6
  TOP w0.102: R6007.1 170.29,16.53 170.03,16.79 170.03,18.38 v2(170.28,18.63) 170.32,18.67 170.32,19.21 167.27,22.25 158.59,22.25 157.88,22.97 155.17,22.97 153.36,24.77 153.36,31.03 v1(153.16,31.23)
  L4 w0.102: v1(121.52,38.62) 120.13,37.23 120.13,32.8 121.44,31.49 121.44,31.18 121.61,31.01 121.61,27.04 122.5,26.15 122.83,25.82 123.97,25.82 124.56,26.41 124.56,30.47 127.21,33.12 130.79,33.12 132.58,31.33 135.39,31.33 136.38,30.34 146.55,30.34 147.95,31.74 151.7,31.74 151.81,31.84 152.55,31.84 v1(153.16,31.23)
  BOTTOM w0.102: CPU1.J4 121.23,38.35 121.51,38.62 v1(121.52,38.62)
HDMI_CLK: length 145
  TOP w0.102: 42.26,68.6 44.75,68.6 45.41,69.26 45.69,69.26 v1(45.87,69.08) ; 42.26,68.6 31.52,68.6 30.38,67.45 28.62,67.45 C5709.1 ; 42.26,68.6 v2(42.26,68.47)
  L6 w0.127: v1(45.87,69.08) 46.06,69.27 47.13,69.27 49.08,71.23 49.08,82.48 48.21,83.35 48.21,85.42 49.31,86.52 49.31,88.12 51.08,89.89 51.08,90.55 52.88,92.35 54.96,92.35 55.71,93.1 59.83,93.1 60.57,92.36 64.62,92.36 65.45,93.18 68.94,93.18 70.12,92 74.39,92 76.32,90.07 97.19,90.07 99.28,92.17 105.76,92.17 106.68,91.25 119.56,91.25 122.79,89.79 123.96,88.62 123.96,82.48 123.38,81.89 123.38,77.55 124.64,76.29 124.64,74.74 124.83,74.55 124.83,71.01 124.23,70.41 124.23,69.56 123.04,68.37 122.72,68.37 v1(122.21,67.85)
  BOTTOM w0.102: CPU1.G56 121.89,68.17 v1(122.21,67.85)
HDMI_CLK#: length 145.1
  TOP w0.102: 33.93,68.83 31.42,68.83 30.28,67.68 28.55,67.68 C5714.1 ; 33.93,68.83 44.65,68.83 45.31,69.49 45.64,69.49 v1(45.87,69.71) ; 33.93,68.83 v2(33.93,68.95)
  L6 w0.127: v1(45.87,69.71) 46.05,69.54 47.02,69.54 48.82,71.34 48.82,82.37 47.94,83.24 47.94,85.53 49.05,86.63 49.05,88.23 50.81,90 50.81,90.66 52.77,92.61 54.85,92.61 55.6,93.36 59.94,93.36 60.68,92.63 64.51,92.63 65.34,93.45 69.05,93.45 70.23,92.27 74.5,92.27 76.43,90.34 97.08,90.34 99.17,92.43 105.87,92.43 106.79,91.52 119.56,91.52 119.67,91.5 122.9,90.04 122.95,90.02 123.2,89.77 123.33,89.64 124.23,88.74 124.23,82.37 123.65,81.78 123.65,77.66 124.9,76.4 124.9,74.85 125.09,74.66 125.09,70.9 124.5,70.3 124.5,69.45 122.9,67.85 v1(122.86,67.85)
  BOTTOM w0.102: v1(122.86,67.85) 122.54,68.17 CPU1.F56
HDMI_CLK#_R: length 1.7
  TOP w0.102: U5701.10 27.13,67.64 C5714.2
HDMI_CLK#_R_C: length 15.7
  TOP w0.102: HDMI1.12 12.47,75.58 12.57,75.48 12.57,75.3 12.67,75.19 13.15,75.19 14.4,73.95 14.4,69.05 15.98,67.48 17.64,67.48 R5705.1 18.2,67.55 19.48,67.55 ; 19.48,67.55 v2(19.48,67.71) ; 19.48,67.55 20.05,67.55 20.14,67.64 U5701.21
HDMI_CLK_R: length 1.8
  TOP w0.102: U5701.9 26.27,67.24 26.44,67.41 27.15,67.41 C5709.2
HDMI_CLK_R_C: length 15.7
  TOP w0.102: U5701.22 20.18,67.24 20.09,67.32 18.35,67.32 R5705.2 17.64,67.25 15.88,67.25 14.82,68.31 ; 14.82,68.31 14.17,68.96 14.17,73.85 13.06,74.97 12.67,74.97 12.57,74.86 12.57,74.68 12.47,74.58 HDMI1.10 ; 14.82,68.31 v2(14.73,68.22)
HDMI_DATA0: length 151.1
  TOP w0.102: v1(44.4,66.11) 43.22,66.11 43.15,66.18 ; C5711.1 30.48,64.48 30.71,64.48 31.14,64.91 31.14,65.18 32.6,66.64 42.69,66.64 43.15,66.18 ; v2(43.25,66.29) 43.15,66.18
  L6 w0.127: v1(44.4,66.11) 44.64,66.35 44.64,66.88 44.14,67.38 44.14,76.06 46.05,79.57 46.05,85.21 47.04,88.69 47.67,89.87 47.7,89.91 51.97,94.19 54.19,94.19 55.44,95.43 70.85,95.43 71.51,94.77 100.11,94.77 113.64,93.18 120.11,93.18 120.22,93.16 123.41,91.79 123.45,91.77 125.82,89.41 125.82,83.24 125.86,83.14 125.94,82.96 128.43,77.41 128.43,74.79 127.47,73.82 126.93,71.77 126.93,70.97 125.93,69.21 125.93,68.6 125.13,67.38 125.13,66.49 124.3,65.66 122.57,65.66 v1(122.2,66.03)
  BOTTOM w0.102: v1(122.2,66.03) 121.89,66.34 CPU1.G53
HDMI_DATA0#: length 150.1
  TOP w0.102: 33.04,66.41 42.59,66.41 43.13,65.88 43.99,65.88 v1(44.4,65.47) ; 33.04,66.41 v2(33.04,66.26) ; 33.04,66.41 32.7,66.41 31.37,65.08 31.37,64.82 30.81,64.25 30.5,64.25 C5708.1
  L6 w0.127: v1(44.4,65.47) 44.7,65.47 44.91,65.68 44.91,66.99 44.41,67.49 44.41,75.99 46.28,79.44 46.32,79.5 46.32,85.18 47.29,88.59 47.91,89.74 47.91,89.75 52.08,93.92 54.3,93.92 55.55,95.17 70.74,95.17 71.4,94.5 100.1,94.5 113.62,92.92 120.11,92.92 123.3,91.55 125.55,89.3 125.55,83.19 125.67,82.93 125.67,82.93 127.15,79.61 128.17,77.35 128.17,74.9 127.23,73.96 127.17,73.73 126.67,71.81 126.67,71.04 125.66,69.28 125.66,68.68 124.86,67.46 124.86,66.6 124.19,65.93 122.98,65.93 v1(122.84,66.07)
  BOTTOM w0.102: CPU1.F53 122.54,66.37 v1(122.84,66.07)
HDMI_DATA0#_R: length 3.9
  TOP w0.102: 27.74,64.12 26.47,64.12 26.38,64.04 U5701.1 ; 27.74,64.12 28.67,64.12 28.85,64.3 28.98,64.3 C5708.2 ; 27.74,64.12 v2(27.74,63.97)
HDMI_DATA0#_R_C: length 21.4
  TOP w0.102: 17.8,63.1 18.4,63.1 R5703.2 19.05,63.11 19.27,63.11 20.2,64.04 U5701.30 ; 17.8,63.1 14.95,63.1 13.44,64.61 12.78,64.61 v1(12.5,64.33) ; 17.8,63.1 v2(17.8,62.96)
  BOTTOM w0.102: v1(12.5,64.33) 12.8,64.63 13.15,64.63 13.38,64.86 13.38,66.09 12.93,66.54 12.93,68.2 11.21,69.91 11.21,73.21 HDMI1.9
HDMI_DATA0_R: length 3.7
  TOP w0.102: C5711.2 29.11,64.53 28.76,64.53 28.58,64.35 26.47,64.35 26.38,64.44 U5701.2
HDMI_DATA0_R_C: length 20.5
  TOP w0.102: U5701.29 20.27,64.44 19.18,63.34 19.02,63.34 R5703.1 18.4,63.33 16.64,63.33 ; 16.64,63.33 15.05,63.33 13.54,64.84 12.78,64.84 v1(12.5,65.12) ; 16.64,63.33 v2(16.64,63.47)
  BOTTOM w0.102: HDMI1.7 10.55,73.28 10.83,73.28 10.99,73.12 10.99,69.81 12.7,68.1 12.7,66.45 13.16,65.99 13.16,64.96 13.06,64.86 12.75,64.86 v1(12.5,65.12)
HDMI_DATA1: length 145.3
  TOP w0.102: C5712.1 28.55,65.52 30.48,65.52 32.31,67.35 43.91,67.35 ; v1(46.66,65.93) 46.45,66.13 46.45,66.49 46.12,66.82 45.13,66.82 44.59,67.35 43.91,67.35 ; 43.91,67.35 v2(43.91,67.48)
  L6 w0.127: v1(122.22,68.77) 122.68,69.24 122.99,69.24 123.49,69.74 123.49,71.85 124.03,72.38 124.03,74.72 123.65,75.1 123.09,75.1 122.32,75.86 122.32,83.46 123.19,84.32 123.19,88.28 122.45,89.02 119.25,90.48 98.69,90.48 97.51,89.3 75.97,89.3 74.04,91.23 69.8,91.23 68.62,92.41 65.77,92.41 64.93,91.57 60.24,91.57 59.49,92.32 56.06,92.32 55.29,91.56 53.21,91.56 51.88,90.23 51.88,89.57 50.09,87.78 50.09,86.17 49.02,85.11 49.02,83.99 50.07,82.94 50.07,69.98 46.47,66.38 46.47,66.12 v1(46.66,65.93)
  BOTTOM w0.102: v1(122.22,68.77) 122.54,69.1 CPU1.F58
HDMI_DATA1#: length 145.6
  TOP w0.102: v1(46.02,65.93) 46.23,66.13 46.23,66.39 46.03,66.59 45.39,66.59 ; C5715.1 28.62,65.29 30.57,65.29 32.4,67.12 44.5,67.12 45.03,66.59 45.39,66.59 ; 45.39,66.59 v2(45.39,66.46)
  L6 w0.127: v1(46.02,65.93) 46.2,66.11 46.2,66.49 49.81,70.1 49.81,82.82 48.75,83.88 48.75,85.22 49.82,86.28 49.82,87.89 51.61,89.68 51.61,90.34 53.1,91.83 55.18,91.83 55.95,92.59 59.6,92.59 60.35,91.84 64.82,91.84 65.66,92.68 68.73,92.68 69.91,91.49 74.15,91.49 76.08,89.56 97.4,89.56 98.58,90.75 119.25,90.75 119.36,90.72 122.61,89.24 123.45,88.39 123.45,84.21 122.59,83.35 122.59,75.97 123.2,75.37 123.76,75.37 124.29,74.83 124.29,72.27 123.76,71.74 123.76,69.63 122.91,68.77 v1(122.87,68.77)
  BOTTOM w0.102: CPU1.E58 122.96,69.23 122.87,69.14 v1(122.87,68.77)
HDMI_DATA1#_R: length 1.8
  TOP w0.102: C5715.2 27.07,65.32 26.47,65.32 26.38,65.24 U5701.4
HDMI_DATA1#_R_C: length 16.3
  TOP w0.102: v1(15.72,64.21) 16.01,64.51 17.63,64.51 R5704.2 18.29,64.51 18.74,64.51 19.58,65.35 20.17,65.35 20.27,65.24 U5701.27
  BOTTOM w0.102: HDMI1.6 12.24,72.19 12.87,72.19 13.64,71.42 13.64,66.84 14.42,66.05 ; v2(14.53,66.16) 14.42,66.05 ; 14.42,66.05 15.55,64.93 15.55,64.39 v1(15.72,64.21)
HDMI_DATA1_R: length 1.7
  TOP w0.102: C5712.2 27.2,65.55 26.44,65.55 26.35,65.64 U5701.5
HDMI_DATA1_R_C: length 16.6
  TOP w0.102: U5701.26 20.23,65.64 20.17,65.57 19.49,65.57 18.65,64.74 18.26,64.74 R5704.1 17.65,64.74 15.54,64.74 v1(15.06,64.25)
  BOTTOM w0.102: 15.05,65.1 15.32,64.83 15.32,64.51 v1(15.06,64.25) ; 15.05,65.1 13.41,66.74 13.41,71.33 12.77,71.97 12.24,71.97 HDMI1.4 ; 15.05,65.1 v2(14.93,64.99)
HDMI_DATA2: length 145.7
  TOP w0.102: 38.28,68.11 32.06,68.11 30.64,66.69 30.43,66.69 C5707.1 ; 38.28,68.11 v2(38.28,68.24) ; 38.28,68.11 45.52,68.11 v1(45.72,68.32)
  L6 w0.127: v1(122.81,66.95) 123.21,67.35 123.59,67.35 123.95,67.71 123.95,68.22 124.86,69.13 124.86,70.07 125.44,70.64 125.44,74.01 125.82,74.39 125.82,75.62 125.4,76.04 125.4,76.69 124.76,77.33 124.76,88.97 123.1,90.63 120.37,91.85 119.76,92.13 119.71,92.14 106.88,92.14 106.08,92.94 98.96,92.94 97.83,91.81 82.98,91.81 81.65,93.15 74.01,93.15 73.42,93.73 71.08,93.73 70.42,94.39 64.98,94.39 63.85,93.26 60.78,93.26 60.17,93.87 55.37,93.87 54.63,93.13 52.55,93.13 50.3,90.89 50.3,90.21 48.54,88.44 48.54,86.84 47.42,85.72 47.42,82.88 48.04,82.25 48.04,72.93 45.27,70.16 45.27,68.5 45.46,68.32 v1(45.72,68.32)
  BOTTOM w0.102: v1(122.81,66.95) 122.54,67.22 CPU1.F55
HDMI_DATA2#: length 146.9
  TOP w0.102: 40.13,67.89 45.52,67.89 v1(45.72,67.68) ; 40.13,67.89 v2(40.13,67.76) ; 40.13,67.89 32.16,67.89 30.74,66.46 30.55,66.46 C5710.1
  L6 w0.127: v1(45.72,67.68) 45.01,68.39 45.01,70.27 47.78,73.04 47.78,82.14 47.15,82.76 47.15,85.83 48.27,86.95 48.27,88.55 50.04,90.32 50.04,91 52.44,93.4 54.52,93.4 55.26,94.14 60.28,94.14 60.89,93.53 63.74,93.53 64.87,94.66 70.53,94.66 71.19,94 73.53,94 74.12,93.41 81.76,93.41 83.09,92.08 97.72,92.08 98.85,93.21 106.2,93.21 107,92.41 119.73,92.41 119.84,92.39 123.25,90.85 125.03,89.08 125.03,77.44 125.66,76.8 125.66,76.15 126.08,75.73 126.08,74.28 125.7,73.9 125.7,70.53 125.13,69.96 125.13,69.02 124.22,68.11 124.22,67.6 123.56,66.94 v1(123.47,66.94)
  BOTTOM w0.102: CPU1.E55 123.19,67.22 v1(123.47,66.94)
HDMI_DATA2#_R: length 3.8
  TOP w0.102: U5701.6 26.38,66.04 26.42,66.07 27.03,66.07 27.37,66.41 29.03,66.41 C5710.2
HDMI_DATA2#_R_C: length 14.2
  TOP w0.102: v1(16.05,65.75) 18.67,65.75 R5702.2 19.12,66.11 20.17,66.11 20.24,66.04 U5701.25
  L6 w0.127: HDMI1.3 11.04,70.39 11.04,70.38 13.63,67.8 15.28,67.8 16.05,67.02 v1(16.05,65.75)
  BOTTOM w0.102: v1(16.05,65.75) 16.56,65.75 v2(16.66,65.85)
HDMI_DATA2_R: length 3.8
  TOP w0.102: C5707.2 29.06,66.64 27.28,66.64 26.94,66.3 26.42,66.3 26.28,66.44 U5701.7
HDMI_DATA2_R_C: length 14.9
  TOP w0.102: 16.84,65.98 16.44,65.98 16.05,66.37 16.05,66.64 15.93,66.76 15.59,66.76 15.47,66.64 15.47,66.18 v1(15.42,66.13) ; 16.84,65.98 v2(16.84,66.11) ; 16.84,65.98 18.13,65.98 R5702.1 18.95,66.34 20.12,66.34 20.22,66.44 U5701.24
  L6 w0.127: v1(15.42,66.13) 15.44,66.11 15.69,66.11 15.78,66.2 15.78,66.91 15.17,67.53 13.51,67.53 10.77,70.27 10.54,70.27 HDMI1.1
HDMI_EC_DET#: length 260.5
  TOP w0.102: KBC24.126 196.41,27.98 196.63,27.75 197.38,27.75 v1(197.71,28.08) ; v2(29.89,9.36) 30.02,9.24 v1(30.02,8.47)
  L3 w0.102: v1(30.02,8.47) 30.02,12.52 28.6,13.95 28.6,19.71 25.45,22.86 25.45,24.01 21.91,27.55 20.27,27.55 19.81,28.01 19.81,31.36 20.14,31.69 20.14,33.97 19.48,34.63 19.48,38.44 17.27,40.65 17.27,45.23 18.31,46.27 18.31,56.76 17.88,57.19 v1(17.88,57.9) ; v1(172.85,8.67) 173.41,8.1 175.85,8.1 176.12,8.37 185.79,8.37 190.34,12.92 192.9,12.92 196.9,16.92 196.9,27.27 v1(197.71,28.08)
  L4 w0.102: v1(30.02,8.47) 29.77,8.22 29.77,2.89 31.46,1.19 83.99,1.19 84.1,1.31 111.63,1.31 112.32,2 112.32,5.06 114.54,7.28 118.06,7.28 121.03,4.31 129.76,4.31 130.06,4 131.16,2.91 v1(132.43,2.91)
  BOTTOM w0.102: v1(172.85,8.67) 172.65,8.47 163.5,8.47 161.77,6.75 159.11,6.75 156.89,4.54 156.89,4.31 156.18,3.6 154.58,3.6 153.55,2.57 153.55,2.01 153.11,1.57 133.78,1.57 v1(132.43,2.91) ; R5721.2 19.61,57.98 R5723.1 17.96,57.98 v1(17.88,57.9)
HDMI_EC_DET#_C: length 6.4
  BOTTOM w0.102: Q5704.3 19.27,62.34 18.89,61.97 18.24,61.97 17.97,61.7 Q5704.6 17.97,60.43 18.31,60.09 18.45,60.09 18.77,59.77 19.34,59.77 v2(19.61,59.5) 19.61,59.15 19.3,58.84 R5723.2
HOST_DEBUG_TX: length 56.3
  TOP w0.102: v1(184.43,36.87) 184.43,36.67 184,36.24 KBC24.81 ; R2480.1 163.12,16.86 162.62,17.35 DB3.5 161.16,17.36 158.55,17.36 157.66,16.48 v1(157.66,13.39) v2(158.63,12.42) 159.04,12.01 R6808.2
  L4 w0.102: v1(157.66,13.39) 158.28,14.01 159.41,14.01 161.16,15.76 163.56,15.76 164.32,16.53 170.23,16.53 173.32,19.61 175.11,19.61 176.58,21.07 177.54,21.07 184.88,28.42 184.88,36.41 v1(184.43,36.87)
HOST_DEBUG_TX_CON: length 3.1
  TOP w0.102: DB1.11 162.92,10.83 161.75,12.01 v2(161.72,12.01) R6808.1
HPD_HDMI_CON: length 24.6
  TOP w0.102: U5701.28 20.19,64.84 19.96,64.61 v1(19.48,64.61)
  L6 w0.102: HDMI1.19 11.12,79.85 12.37,79.85 13.89,78.32 13.89,71.29 17.7,67.48 17.7,65.22 18.31,64.61 v1(19.48,64.61)
  BOTTOM w0.102: R5722.2 18.18,65.24 v2(19.1,65.24) 19.48,64.86 v1(19.48,64.61)
HPD_HDMI_CON_C: length 2.7
  BOTTOM w0.102: Q5704.2 18.62,63.16 19.05,63.59 v2(19.05,63.97) 18.87,64.15 R5722.1
HPDIN: length 2.4
  TOP w0.127: R3821.2 29.77,60.42 30.09,60.09 v2(30.4,60.09) 30.45,60.15 U3801.32
HW_ACAV_IN: length 74.5
  TOP w0.203: 196.95,29.81 197.21,29.55 KBC24.128
  TOP w0.254: v1(144.93,31.41) 144.93,31.75 144.5,32.18 PG4408.2 144.34,32.5 141.63,32.5 141.32,32.2 140.17,32.2 139.82,31.84 138.53,31.84 138.15,32.22 138.15,36.26 139.44,37.56 139.44,39.92 v2(139.47,39.95) 139.52,40 v1(140.03,40) ; 196.95,29.81 v1(196.47,30.29)
  L6 w0.254: v1(196.47,30.29) 196.29,30.47 192.53,30.47 191.59,31.41 190.37,31.41 189.76,30.8 189,30.8 187.27,30.8 187.04,30.57 183.95,30.57 183.6,30.23 183.6,30.23 183.34,29.96 178.99,29.96 178.74,30.22 172.68,30.22 171.89,31 167.08,31 166.55,31.54 157.81,31.54 156.92,30.65 152.09,30.65 151.81,30.93 145.38,30.93 144.93,31.38 v1(144.93,31.41)
  BOTTOM w0.254: v1(140.03,40) 140,40 140,39.84 140.05,39.79 140.03,39.77 140.03,39.62 139.8,39.39 PQ4415.5
HW_ACAVIN_NB: length 60.5
  TOP w0.203: v1(200.28,40.28) 200.05,40.28 199.74,39.97 199.74,39.64 199.54,39.44 KBC24.24
  TOP w0.254: v2(174.83,53.94) v1(175.44,53.94) 176.15,53.94 R2475.2
  L4 w0.254: v1(175.44,53.94) 176.33,53.06 176.33,45.61 174.95,44.24 174.95,41.24 171.65,37.94 171.65,35.86 v1(169.95,34.16)
  L6 w0.254: v1(200.28,40.28) 197.99,37.99 193.45,37.99 192.16,36.69 188.69,36.69 187.42,35.42 186.71,35.42 186.24,34.95 185.7,34.95 185.02,34.27 184.13,34.27 182.68,32.82 181.6,32.82 181.36,33.06 181.3,33.11 181.23,33.18 181.17,33.24 181.07,33.34 179.72,33.34 178.5,34.56 170.35,34.56 v1(169.95,34.16)
I2C0_SCL_R: length 24.5
  TOP w0.089: RN6503.4 129.63,4.62 129.81,4.8 129.81,5.71 128.42,7.1 AFTP6534.1 128.42,8.09 v1(128.55,8.22) ; v1(134.29,21.35) 134.97,22.04 R6505.2
  BOTTOM w0.089: v1(128.55,8.22) 128.4,8.37 TP1.3 128.4,10.92 128.76,11.28 128.76,12.02 129.34,12.59 130.81,12.59 131.42,13.21 131.42,14.57 131.82,14.97 131.82,19.6 133.58,21.35 v1(134.29,21.35) 134.29,22.06 134.74,22.51 Q6504.6
I2C0_SCL_TCH_PAD: length 45.7
  TOP w0.089: v1(132.56,22.8) 133.3,22.8 133.91,22.19 R6505.1 134.11,22.93 EC6503.1 133.7,23.33 v2(133.22,23.33) 131.88,23.33 129.94,21.4 126.69,21.4 125.12,19.84 123.31,19.84 121.12,22.03 118.61,22.03 116.2,24.43 v1(116.2,24.66)
  L4 w0.127: v1(116.2,24.66) 116.2,24.66 117.05,25.51 117.05,27.49 115.83,28.71 115.83,32.06 116.1,32.33 116.1,37.66 116.72,38.28 116.72,38.98 v1(116.34,39.35)
  BOTTOM w0.089: v1(116.34,39.35) 116.57,39.12 CPU1.U6 ; Q6504.1 136.89,22.51 136.45,22.95 134.29,22.95 134.14,22.8 v1(132.56,22.8)
I2C0_SCL_TCH_PNL: length 1.4
  TOP w0.102: TP2028.1 116.61,41.6 v1(116.28,41.26)
  BOTTOM w0.102: v1(116.28,41.26) 116.68,41.26 CPU1.U9
I2C0_SDA_R: length 26.1
  TOP w0.089: v1(133.53,20.26) 133.25,20.26 R6506.2 ; v1(129,8.81) 129,8.49 129,8.48 129,7.16 AFTP6535.1 130.08,6.08 130.08,4.85 130.12,4.81 130.12,4.53 RN6503.3
  BOTTOM w0.089: Q6504.3 135.38,19.45 134.33,19.45 v1(133.53,20.26) 133.34,20.45 133.05,20.45 132.09,19.49 132.09,14.86 131.69,14.46 131.69,13.1 130.92,12.33 129.45,12.33 129.03,11.9 129.03,11.35 129.4,10.98 TP1.2 129.4,10.06 129,9.67 v1(129,8.81)
I2C0_SDA_TCH_PAD: length 42.1
  TOP w0.089: v1(116.2,25.29) 115.78,24.87 115.78,24.48 118.5,21.76 121.01,21.76 123.2,19.57 125.23,19.57 126.63,20.97 v2(128.78,20.97) 129.89,20.97 131.5,22.58 132.01,22.58 132.23,22.36 132.8,22.36 EC6504.1 133.35,21.45 133.32,21.43 R6506.1 133.4,21.05 v1(134.19,20.26)
  L4 w0.127: v1(116.2,25.29) 116.39,25.48 116.41,25.48 116.67,25.74 116.67,27.33 115.45,28.55 115.45,32.48 115.89,32.91 115.89,39.48 116.33,39.92 v1(116.33,39.99)
  BOTTOM w0.089: v1(134.19,20.26) 134.19,20.44 134.96,21.21 Q6504.4 ; CPU1.U7 116.54,39.77 v1(116.33,39.99)
I2C0_SDA_TCH_PNL: length 1.3
  TOP w0.102: v1(117.45,40.66) 117.14,40.35 TP2027.1
  BOTTOM w0.102: v1(117.45,40.66) 117.1,40.66 CPU1.U8
I2C1_SCL: length 6.1
  BOTTOM w0.089: CPU1.N2 118.86,36.91 118.83,36.82 118.83,36.63 118.86,36.5 118.91,36.12 118.91,36.06 118.98,35.98 118.98,33.71 v2(118.96,33.68) 118.96,33.19 118.48,32.71 118.18,32.71 117.93,32.45 RN2008.1
I2C1_SDA: length 5.4
  BOTTOM w0.089: CPU1.N1 119.09,36.13 119.16,36.06 119.16,34 119.45,33.71 v2(119.45,32.48) 119,32.03 RN2008.2
I2C_CLK_PD: length 29.7
  TOP w0.089: U3701.29 35.36,44.26 35.5,44.12 RN3701.3 36.06,45.35 v1(36.14,45.43) ; v2(43.61,63.24) 42.8,63.24 v1(42.09,62.53) 41.96,62.53 41.53,62.96 R3814.1
  L3 w0.127: v1(36.14,45.43) 38.28,45.43 43.48,50.64 43.48,61.94 42.9,62.53 v1(42.09,62.53)
I2C_CLK_PD_MUX: length 6.7
  TOP w0.089: U3801.21 35.64,62.21 37.04,63.61 37.04,63.75 37.39,64.1 37.96,64.1 38.15,63.91 v2(39.04,63.91) 39.56,63.91 40.38,63.08 R3814.2
I2C_DATA_PD: length 30.8
  TOP w0.089: v2(42.54,63.85) 42.54,63.64 v1(42.09,63.19) 41.91,63.36 41.63,63.36 41.25,63.75 R3816.1 ; U3701.28 34.53,43.76 34.85,43.45 RN3701.4 36.74,42.76 v1(37.01,42.76)
  L3 w0.127: v1(42.09,63.19) 42.87,63.19 43.86,62.2 43.86,50.42 37.01,43.56 v1(37.01,42.76)
I2C_DATA_PD_MUX: length 7.5
  TOP w0.089: R3816.2 39.97,64.26 38.18,64.26 38.07,64.37 36.89,64.37 v2(36.88,64.35) 36.77,64.25 36.77,63.72 36.14,63.08 34.97,63.08 34.7,62.81 U3801.22
I2CEN: length 3.1
  TOP w0.127: R3874.2 R3873.1 37.72,60.19 v2(36.96,60.19) 36.91,60.15 U3801.17
I_ADP_R: length 4.9
  TOP w0.102: v2(190.4,27.22) 190.4,27.34 190.01,27.72 KBC24.110 190.01,29.41 189.78,29.63 189.73,29.63 v1(189.3,30.06)
  BOTTOM w0.102: v1(189.3,30.06) 189.3,30.56 R2421.2 C2435.1
I_BATT: length 5.4
  TOP w0.203: KBC24.114 191.61,27.86 191.84,27.63
  TOP w0.254: v1(190.79,26.5) 191.37,26.5 v2(191.68,26.81) 191.87,27 191.87,27.49 191.84,27.52 191.84,27.63
  BOTTOM w0.254: v1(190.79,26.5) 190.55,26.74 C2441.1 190.6,27.45 191.28,26.76 R2426.2
IC_DELAY: length 2.9
  BOTTOM w0.127: PC4307.1 v2(22.71,83.81) 22.71,83.1 23.28,82.53 U4302.4
ICSP_CLOCK: length 36.3
  TOP w0.089: KBC24.101 186.41,27.88 186.41,27.54 185.81,26.94 v2(185.55,26.94) 185.16,26.94 v1(184.99,26.76) ; DB3.2 160.63,15.85 160.4,15.62 v1(160.4,13.39)
  L4 w0.127: v1(184.99,26.76) 181.8,23.58 181.71,23.58 178.46,20.32 176.89,20.32 174.51,17.95 172.75,17.95 170.58,15.78 164.63,15.78 163.87,15.02 161.69,15.02 160.4,13.73 v1(160.4,13.39)
ICSP_CLR: length 54.5
  TOP w0.102: v1(174.8,23.97) 175.18,23.59 178.71,23.59 180.06,22.24 180.06,17.6 178.71,16.25 178.71,11.78 177.88,10.94 v2(177.04,10.94) 175.64,10.94 175.28,11.3 175.28,11.53 174.47,12.34 173.81,12.34 173.67,12.19 170.69,12.19 164.98,17.9 R2414.1 161.73,17.9 DB3.6 ; KBC24.87 182.25,33.84 v1(182.09,34)
  L4 w0.102: v1(182.09,34) 182.29,33.8 182.29,31.84 181.96,31.51 181.96,27.73 181.25,27.02 178.93,27.02 177.71,25.8 176.63,25.8 v1(174.8,23.97)
ICSP_DATA: length 39.1
  TOP w0.089: v1(184.35,26.79) 184.35,26.61 184.62,26.34 186.41,26.34 186.81,26.74 v2(186.81,27.12) KBC24.102 ; v1(159.71,13.4) 159.71,14.57 160.07,14.93 160.07,15.98 160.45,16.35 DB3.3
  L4 w0.127: v1(184.35,26.79) 178.27,20.71 176.73,20.71 175.27,19.24 173.47,19.24 170.38,16.16 164.48,16.16 163.71,15.4 161.53,15.4 159.71,13.58 v1(159.71,13.4)
IE_DELAY_G: length 4.8
  TOP w0.102: PQ4313.2 43.86,76.12 PC4315.1 44.3,76.8 v2(43.61,76.8) PR4343.2 42.72,76.29 43.21,75.8 PQ4313.3
IE_DELAY_S: length 4.6
  TOP w0.102: PQ4313.1 44.51,74.75 44.84,74.43 45.38,74.43 PC4314.1 v2(46.15,72.79) PR4344.2
ILIM_HI: length 4.2
  TOP w0.102: v2(25.58,46.45) 25.58,46.6 v1(25.96,46.98) R3404.2
  BOTTOM w0.102: v1(25.96,46.98) 25.96,46.71 24.95,45.7 U3401.16
ILIM_LO: length 4
  TOP w0.102: v1(24.81,46.19) 24.81,47.34 v2(25.2,47.72) 25.2,48.23 25.4,48.43 R3403.2
  BOTTOM w0.102: U3401.15 24.81,46.2 v1(24.81,46.19)
ILIM_SEL: length 2.6
  BOTTOM w0.102: U3401.4 21.6,44.4 21.21,44.01 v2(21.21,43.63) 20.88,43.3 R3405.2
INT2_SELECT: length 43.4
  TOP w0.102: v1(121.49,16.09) 121.36,16.09 120.6,16.85 120.6,17.21 121.39,18 125.4,18 126.91,19.51 128.03,19.51 128.73,18.81 144.45,18.81 v2(145.62,17.64) v1(147.98,15.28)
  BOTTOM w0.102: D7001.2 117.44,10.58 118.18,10.58 119.35,11.75 R7008.1 119.35,13.39 121.49,15.52 v1(121.49,16.09) ; v1(147.98,15.28) 147.98,14.44 R7013.1 148,14.16 Q7001.5
INT#_TYPEC: length 237.2
  TOP w0.127: v1(198.83,43.53) 198.75,43.45 KBC24.32 ; v1(31.67,35.17) 31.36,35.48 v2(30.86,35.48) R3731.1
  L3 w0.127: v1(127.05,2.25) 126.55,1.76 122.39,1.76 121.79,2.36 121.79,2.99 120.2,4.58 120.2,5.55 119.97,5.77 117.59,8.16 103.24,8.16 99.32,4.25 61.29,4.25 61.11,4.42 50.84,4.42 48.94,6.32 48.94,7.07 44.36,11.66 42.44,11.66 42.05,11.27 39.46,11.27 37.63,13.1 37.63,23.35 37.2,23.78 37.2,25.33 34.74,27.78 34.09,27.78 32.55,29.32 32.1,29.32 31.51,29.91 31.51,34.61 31.67,34.77 v1(31.67,35.17)
  L4 w0.127: v1(198.83,43.53) 198.83,42.95 198.8,42.91 198.8,39.66 196.18,37.04 195.11,37.04 193.98,35.9 193.98,33.85 196.91,30.91 196.91,29.25 196.39,28.73 196.39,14.19 189.83,7.63 158.49,7.63 156.32,5.47 154.53,5.47 153.27,4.21 153.27,1.9 152.65,1.27 128.03,1.27 v1(127.05,2.25)
INT#_TYPEC_R: length 3.4
  TOP w0.102: U3701.15 29.8,38.54 30.15,38.19 v2(30.15,38.04) 30.15,37.35 R3707.2 29.94,36.36 R3731.2
IR_CAM_DET#: length 144.1
  TOP w0.102: R5540.2 66.52,93.23 v1(66.52,93.9) ; v2(82.7,24.27) v1(82.7,23.71) ; v1(102.06,35.25) 102.3,35.49 104.94,35.49 106,34.42 106.36,34.42 106.81,34.87 106.81,35.5 107.2,35.89 107.53,35.89 109.27,34.14 109.76,34.14 111.05,32.86 112.34,32.86 113.06,33.58 v1(114.07,33.58) 114.07,33.42 113.71,33.06 113.71,32.76 113.97,32.5 117.73,32.5 v1(118.46,33.24)
  L3 w0.102: v1(82.7,23.71) 82.95,23.46 86.41,23.46 90.26,27.31 92.08,27.31 93.06,28.29 93.37,28.29 94.03,28.95 94.03,30.21 98.16,34.34 98.89,34.34 99.47,34.92 99.47,34.92 99.79,35.25 v1(102.06,35.25) ; v1(66.52,93.9) 68.45,91.96 79.75,91.96 80.19,91.53 v1(80.69,91.53)
  BOTTOM w0.089: v1(118.46,33.24) 118.46,33.68 118.81,34.02 118.81,35.86 118.73,35.94 118.68,36.48 118.67,36.53 118.65,36.61 118.65,36.86 118.69,36.95 118.69,37.95 118.43,38.21 CPU1.P4
  BOTTOM w0.102: v1(114.07,33.58) 114.09,33.58 114.73,32.94 R2046.2 ; v1(80.69,91.53) 80.69,92.02 81.15,92.47 81.53,92.47 81.79,92.22 82.76,92.22 83.23,91.74 83.23,90.83 84.78,89.28 84.78,58.23 84.77,58.22 84.77,51.38 81.58,48.19 81.58,24.83 v1(82.7,23.71)
IR_CAMERA_DET#_R: length 2.8
  TOP w0.102: v2(64.57,93.06) R5540.1 65.48,93.55 v1(65.84,93.91)
  BOTTOM w0.102: v1(65.84,93.91) 65.84,93.9 65.65,93.71 TCBD1.22
ISET: length 4.3
  TOP w0.102: U5701.34 22.69,62.82 22.45,62.58 v2(22.45,61.92) 22.45,60.82 R5414.2 R5413.2
ISH_I2C0_SCL: length 15.3
  BOTTOM w0.089: R2020.1 117.02,24.55 v2(117.02,25.72) 117.02,26.89 117.5,27.37 RN2007.1 117.92,27.51 117.92,27.94 118.25,28.28 118.25,29.67 119.18,30.6 119.18,31.71 119.84,32.37 119.84,33.58 119.38,34.03 119.38,34.17 119.38,36.09 119.31,36.16 119.31,36.31 119.31,36.53 119.35,36.62 119.35,36.82 119.31,36.9 119.31,37.19 119.35,37.27 119.35,37.47 119.3,37.57 119.3,37.74 119.13,37.97 CPU1.N3
ISH_I2C0_SDA: length 16
  BOTTOM w0.089: R2021.1 117.43,25 117.43,26.71 117.43,26.71 117.43,26.83 117.53,26.93 118.19,26.93 118.43,27.18 RN2007.2 118.43,27.97 118.52,28.06 118.52,29.41 v2(119.23,30.12) 119.44,30.33 119.44,31.6 119.44,31.61 119.44,31.73 120.01,32.3 120.01,32.45 120.01,33.65 119.56,34.1 119.56,36.16 119.49,36.24 119.49,36.49 119.53,36.58 119.53,36.86 119.49,36.95 119.49,37.15 119.53,37.23 119.53,37.51 119.49,37.6 119.49,38.09 CPU1.M4
ISH_KB_DISABLE: length 92.8
  TOP w0.102: v1(149.53,25.14) v2(149.53,25.77)
  L4 w0.102: v1(93.27,24.22) 94,24.22 97.46,20.77 99.59,20.77 100.35,20.01 105.57,20.01 105.95,20.38 111.77,20.38 112.03,20.64 112.68,20.64 113.23,20.09 113.23,19.8 113.48,19.55 117.08,19.55 117.74,20.21 119.81,20.21 121,19.02 126.92,19.02 127.35,19.45 128.28,19.45 128.58,19.75 130.94,19.75 133.36,22.17 144,22.17 144.73,22.9 148.31,22.9 148.64,23.23 148.64,23.97 149.53,24.86 v1(149.53,25.14)
  BOTTOM w0.102: v1(93.27,24.22) 92.89,24.6 92.06,24.6 91.34,25.32 91.34,33.95 97.36,39.97 101.95,39.97 103,41.02 104.45,41.02 104.75,40.72 CPU1.AY8 ; v1(149.53,25.14) 149.99,25.59 150.32,25.59 150.49,25.77 Q2001.2
ISH_KB_DISABLE_R: length 9.4
  BOTTOM w0.102: Q2001.5 150.49,28.85 150.65,29 150.98,29 151.14,28.83 Q2001.6 151.14,27.34 151.58,26.91 151.58,25.77 151.42,25.62 151.08,25.62 150.72,25.26 150.27,25.26 149.71,24.7 149.37,24.7 149.12,24.45 R2001.2 149.12,23.05 v2(149.38,22.8)
ITP_PMODE: length 1.8
  TOP w0.102: v1(123.62,40.35) 123.72,40.25 TP638.1
  BOTTOM w0.102: v1(123.62,40.35) 123.62,40.46 CPU1.E8
JACK_PLUG: length 7
  TOP w0.254: HPMIC1.5 15.7,21.79 16.18,22.27 16.5,22.27 ED2903.1 16.52,21.37 R2923.1 16.2,21.05 v2(15.35,21.05)
JACK_PLUG_DET: length 13.3
  TOP w0.254: HPMIC1.6 9.68,21.79 10.67,22.78 13.43,22.78 13.87,22.34 v2(15.52,22.34) 16.03,22.85 16.34,22.85 ED2904.1 16.89,23.47 15.61,23.47 v1(15.49,23.35)
  BOTTOM w0.254: v1(15.49,23.35) 15.49,23.44 15.49,24 16.09,24.6 17.52,24.6 R2905.1
JGND:
  vias: v2(16.71,83.48) v3(18.54,84.6) v3(18.59,83.68)
KB_BL_CTRL#: length 22.3
  TOP w0.508: AFTP6530.1 105.41,7.64 v1(105.33,7.71)
  BOTTOM w0.508: Q6501.D 112.33,8.35 111.45,7.47 111.45,5.33 111.26,5.14 111.26,3.16 110.74,2.63 106.06,2.63 105.33,3.36 v1(105.33,7.71) 105.71,8.09 106.73,8.09 107.26,8.63 KBBL1.4
KB_CLOSE#_2: length 319.3
  TOP w0.102: v1(152.25,9.06) 150.9,10.4 150.15,11.15 149.28,11.58 147.23,12.6 146.97,12.72 144.68,13.77 143.66,14.23 143.21,14.68 143.02,14.78 143,14.79 142.72,14.93 140.53,16.06 140.53,16.06 139.17,16.77 139.07,16.82 130.25,16.82 129.48,16.05 129.48,15.51 128.57,14.6 126.27,14.6 124.85,13.18 123.93,12.26 123.85,12.18 114.87,12.18 114.23,11.55 97.94,11.55 94.29,15.2 86.91,15.2 86.57,14.86 83.12,14.86 82.8,15.18 v1(82.8,17.52) ; C7001.1 17.12,82.97 R7001.1 15.85,82.97 15.67,82.8 v2(15.34,82.8) 15.09,82.8 v1(14.68,83.2) ; GMR1.1 7.01,84.27 v1(6.91,84.17)
  L3 w0.102: v1(82.8,17.52) 82.56,17.52 80.53,15.49 64.89,15.49 63.75,16.63 53.05,16.63 43.81,25.86 43.81,28.03 42.75,29.1 42.75,33.14 42.54,33.34 42.54,35.17 43.04,35.67 43.04,42.19 45.67,44.82 45.67,63.67 47.29,65.29 47.29,71.16 46.53,71.92 46.53,84.8 48.34,86.61 48.46,86.61 49.5,87.65 49.5,87.77 52.13,90.39 v1(52.75,90.39)
  L4 w0.102: v1(152.25,9.06) 152.65,9.47 153.23,9.47 154.39,10.63 158.09,10.63 158.45,10.73 161.73,12.03 162.97,13.28 164.59,13.28 165.29,13.97 173.73,13.97 174.72,12.99 184.26,12.99 191.57,20.29 191.57,23.21 190.61,24.17 190.61,25.58 192.14,27.12 192.14,27.73 194.04,29.62 194.04,31.77 192.82,32.99 190.55,32.99 190.17,33.37 v1(190.17,35.2)
  BOTTOM w0.102: R2461.1 190.31,36.75 Q2415.S 189.98,35.39 v1(190.17,35.2) ; v1(52.75,90.39) 51.93,91.22 44.77,91.22 44.53,90.98 42.09,90.98 41.86,90.75 36.25,90.75 34.27,88.76 30.3,88.76 28.93,90.14 28,90.14 27.34,89.48 25.83,89.48 25.27,90.03 25.27,90.54 25.02,90.79 19.77,90.79 14.78,85.8 14.78,83.3 v1(14.68,83.2) 14.55,83.07 10.12,83.07 9.62,83.58 9.02,83.58 8.13,84.47 7.21,84.47 v1(6.91,84.17)
KB_DET#: length 108.8
  TOP w0.102: v1(128.17,23.33) 127.49,22.66 125.83,22.66 125.05,23.44 v2(123.14,23.44) 122.76,23.44 R2045.2
  L4 w0.102: v1(129.05,15.69) 128.62,15.26 125.05,15.26 123.77,13.98 121.33,13.98 121.18,14.13 117.77,14.13 117.61,14.29 114.65,14.29 113.78,13.43 110.99,13.43 108.75,11.19 100.24,11.19 98.93,12.5 92.43,12.5 91.1,13.83 87.12,13.83 85.32,12.03 81.09,12.03 81.04,11.98 74.7,11.98 v1(72.72,10) ; v1(128.17,23.33) 127.28,23.33 126.85,22.9 125.65,22.9 125.16,23.4 124.69,23.87 122.02,23.87 121.69,24.2 116.77,24.2 116.59,24.02 115.94,24.02 115.39,24.57 115.39,26.23 114.5,27.12 114.5,27.74 114.55,27.79 114.55,30.4 112.75,32.21 112.75,34 113.31,34.56 113.31,38.07 v1(113.87,38.62)
  L6 w0.102: v1(129.05,15.69) 129.05,17.96 128.52,18.49 128.52,22.32 128.17,22.67 v1(128.17,23.33)
  BOTTOM w0.102: v1(72.72,10) 72.72,9.64 72.12,9.04 KB1.30 ; CPU1.AD4 113.59,38.35 v1(113.87,38.62)
KB_LED_BL_DET: length 30.2
  L4 w0.102: v1(117.4,28.01) 117.22,28.19 117.22,29.73 116.47,30.48 116.47,35.65 117.02,36.2 117.02,39.92 v1(116.31,40.62)
  BOTTOM w0.102: v1(117.4,28.01) 117.4,27.66 116.66,26.92 116.66,24.5 v2(116.12,23.96) 115.37,23.21 115.37,22.17 114.65,21.45 112.93,21.45 112.04,22.34 111.22,22.34 110.97,22.09 110.97,20.67 R6508.1 111.86,19.78 111.86,19.12 112.16,18.81 R6507.1 ; CPU1.W8 116.11,40.43 v1(116.31,40.62)
KB_LED_DET_C: length 15.5
  BOTTOM w0.102: KBBL1.2 105.26,10.99 108.23,13.96 111.83,13.96 112.6,14.73 112.6,15 112.93,15.33 113.21,15.33 113.59,15.71 113.59,16.76 v2(114.15,17.31) 114.15,17.42 C6504.1 113.51,18.79 R6507.2
KB_LED_PWM: length 140.6
  TOP w0.203: v1(192.02,42.05) 192.17,42.21 192.17,42.89 192.46,43.17 192.61,43.17 192.81,43.37 KBC24.44
  TOP w0.508: v1(112.09,7.03) 113.69,8.63 120.29,8.63 122.1,6.82 122.1,2.68 v1(122.5,2.28)
  L3 w0.508: v1(154.76,3.01) 154.56,3.22 154.56,4.5 155.06,5 156.9,5 158.79,6.89 188.83,6.89 198.69,16.74 198.69,28.53 198.3,28.92 198.3,36.29 196.77,37.81 196.1,37.81 194.84,39.07 194.84,40.18 193.68,41.34 192.73,41.34 v1(192.02,42.05)
  BOTTOM w0.254: R6509.1 115.19,13.5 v2(115.24,13.55)
  BOTTOM w0.508: v1(112.09,7.03) 113.21,8.14 113.21,9.71 114.23,10.74 Q6501.G 114.23,11.76 115.14,12.67 R6509.1 ; v1(154.76,3.01) 154.76,2.99 154.79,2.96 154.79,1.89 154.26,1.36 153.69,1.36 153.39,1.06 153.34,1.01 133.55,1.01 133.07,1.49 123.33,1.49 122.54,2.28 v1(122.5,2.28)
KBC_BEEP_R: length 1.9
  BOTTOM w0.254: D2701.2 30.59,11.2 RN2701.4
KBC_PWRBTN#: length 30.2
  TOP w0.102: v1(167.71,36.64) 168.07,36.29 EC6601.1 168.07,33.11 v2(166.42,31.46) 166.42,30.53 v1(166.5,30.45)
  L6 w0.102: v1(166.5,30.45) 171.73,30.45 172.46,29.71 178.53,29.71 179.44,28.79 181.85,28.79 182.63,29.58 183.88,29.58 184.36,30.06 v1(186.18,30.06)
  BOTTOM w0.102: R2432.1 185.77,29.66 v1(186.18,30.06) ; IOBD1.45 167.78,36.71 v1(167.71,36.64)
KSI0: length 135
  TOP w0.102: RN2403.8 179.98,29.3 v1(180.06,29.23) 180.11,29.23 180.51,28.82 180.53,28.82 181.19,28.16 183.01,28.16 183.41,27.75 184.99,27.75 185.21,27.97 KBC24.98 ; EC6505.1 72.59,5.53 75.84,5.53 78.41,8.1 AFTP6512.1 78.66,9.36 v1(78.66,9.9)
  L4 w0.102: v1(78.66,9.9) 78.66,9.33 79.12,8.88 79.18,8.88 81.84,6.21 97.59,6.21 97.76,6.39 109.52,6.39 112.44,9.31 124.41,9.31 125.94,7.78 129.56,7.78 131.93,10.15 142.39,10.15 143.81,11.57 149.14,11.57 150.77,13.2 151.67,13.2 152.93,14.46 152.93,15.33 153.74,16.15 156.1,16.15 157.24,17.29 158.8,17.29 160.02,18.51 162.42,18.51 163.19,19.27 166.85,19.27 171.19,23.6 171.8,23.6 175.74,27.54 175.74,28.47 176.99,29.71 179.58,29.71 v1(180.06,29.23)
  BOTTOM w0.102: v1(78.66,9.9) 78.52,9.76 KB1.22
KSI1: length 138.9
  TOP w0.102: KBC24.99 185.61,27.98 185.18,27.55 183.79,27.55 183.43,27.19 181.84,27.19 v1(181.33,27.7) 181.33,27.73 180.49,28.57 179.93,28.57 179.78,28.71 RN2403.7 ; EC6507.1 71.22,5.93 74.21,5.93 76.5,8.23 AFTP6501.1 77.01,9.74 v1(77.01,10)
  L4 w0.102: v1(77.01,10) 77.01,9.9 81.3,5.6 97.84,5.6 98.02,5.78 109.81,5.78 112.73,8.7 118.7,8.7 120.23,7.17 129.84,7.17 132.21,9.54 142.67,9.54 144.09,10.96 149.39,10.96 151.02,12.59 151.93,12.59 154.16,14.81 155.63,14.81 157.49,16.68 159.06,16.68 160.28,17.9 162.68,17.9 163.44,18.66 167.11,18.66 171.44,22.99 172.05,22.99 176.38,27.31 176.38,28.24 177.24,29.1 178.23,29.1 180.01,27.32 180.87,27.32 181.25,27.7 v1(181.33,27.7)
  BOTTOM w0.102: v1(77.01,10) 76.92,9.91 KB1.24
KSI2: length 170.8
  TOP w0.102: v1(180.69,27.75) 180.69,27.86 180.24,28.31 179.88,28.31 179.78,28.21 RN2403.6 ; v1(75.74,10) 75.74,9.87 AFTP6508.1 72.69,6.82 70.28,6.82 67.99,4.54 EC6509.1 ; v1(196.26,33.62) 196.65,33.24 196.65,32.6 197.12,32.12 197.85,32.12 197.97,32.24 KBC24.6
  L4 w0.102: v1(180.69,27.75) 180.69,27.86 179.04,29.51 177.07,29.51 175.94,28.38 175.94,27.46 171.89,23.4 171.27,23.4 166.94,19.07 163.27,19.07 162.51,18.3 160.11,18.3 158.89,17.09 157.33,17.09 155.46,15.22 153.99,15.22 151.76,13 150.85,13 149.22,11.37 143.92,11.37 142.5,9.95 132.01,9.95 129.64,7.58 121.17,7.58 119.65,9.11 112.56,9.11 109.64,6.19 97.85,6.19 97.67,6.01 81.7,6.01 78.1,9.6 78.1,10.03 77.7,10.43 76.17,10.43 v1(75.74,10)
  L6 w0.102: v1(196.26,33.62) 196.72,34.08 197.22,34.08 198.08,34.94 200.29,34.94 201.24,33.99 201.24,30.43 197.32,26.51 192.43,26.51 191.73,27.21 191.73,27.64 190.78,28.59 185.79,28.59 185.03,27.83 183.99,27.83 183.76,28.06 182.42,28.06 181.64,27.27 181.08,27.27 180.69,27.65 v1(180.69,27.75)
  BOTTOM w0.102: KB1.26 75.32,8.82 75.74,9.24 v1(75.74,10)
KSI3: length 165.1
  TOP w0.102: v1(180.06,27.88) 179.8,27.63 RN2403.5 ; EC6506.1 71.91,5.73 75.54,5.73 AFTP6509.1 77.65,7.84 v1(77.65,9.87) ; KBC24.7 198.04,32.64 197.72,32.33 197.2,32.33 196.9,32.63 v1(196.9,33.62)
  L4 w0.102: v1(180.06,27.88) 180.03,27.88 178.61,29.3 177.15,29.3 176.15,28.3 176.15,27.37 171.97,23.2 171.36,23.2 167.02,18.86 163.35,18.86 162.59,18.1 160.19,18.1 158.97,16.88 157.41,16.88 155.54,15.02 154.07,15.02 151.85,12.79 150.93,12.79 149.31,11.17 144.01,11.17 142.59,9.74 132.09,9.74 129.73,7.38 120.32,7.38 118.79,8.9 112.64,8.9 109.72,5.99 97.93,5.99 97.75,5.81 81.61,5.81 77.65,9.77 v1(77.65,9.87)
  L6 w0.102: v1(196.9,33.62) 197.05,33.62 198.17,34.74 200.2,34.74 201.04,33.9 201.04,30.51 197.24,26.71 192.52,26.71 191.94,27.29 191.94,27.72 190.87,28.79 185.71,28.79 184.94,28.03 184.08,28.03 183.85,28.26 182.17,28.26 182.09,28.17 181.5,28.17 181.49,28.19 180.36,28.19 v1(180.06,27.88)
  BOTTOM w0.102: KB1.23 77.72,9.8 v1(77.65,9.87)
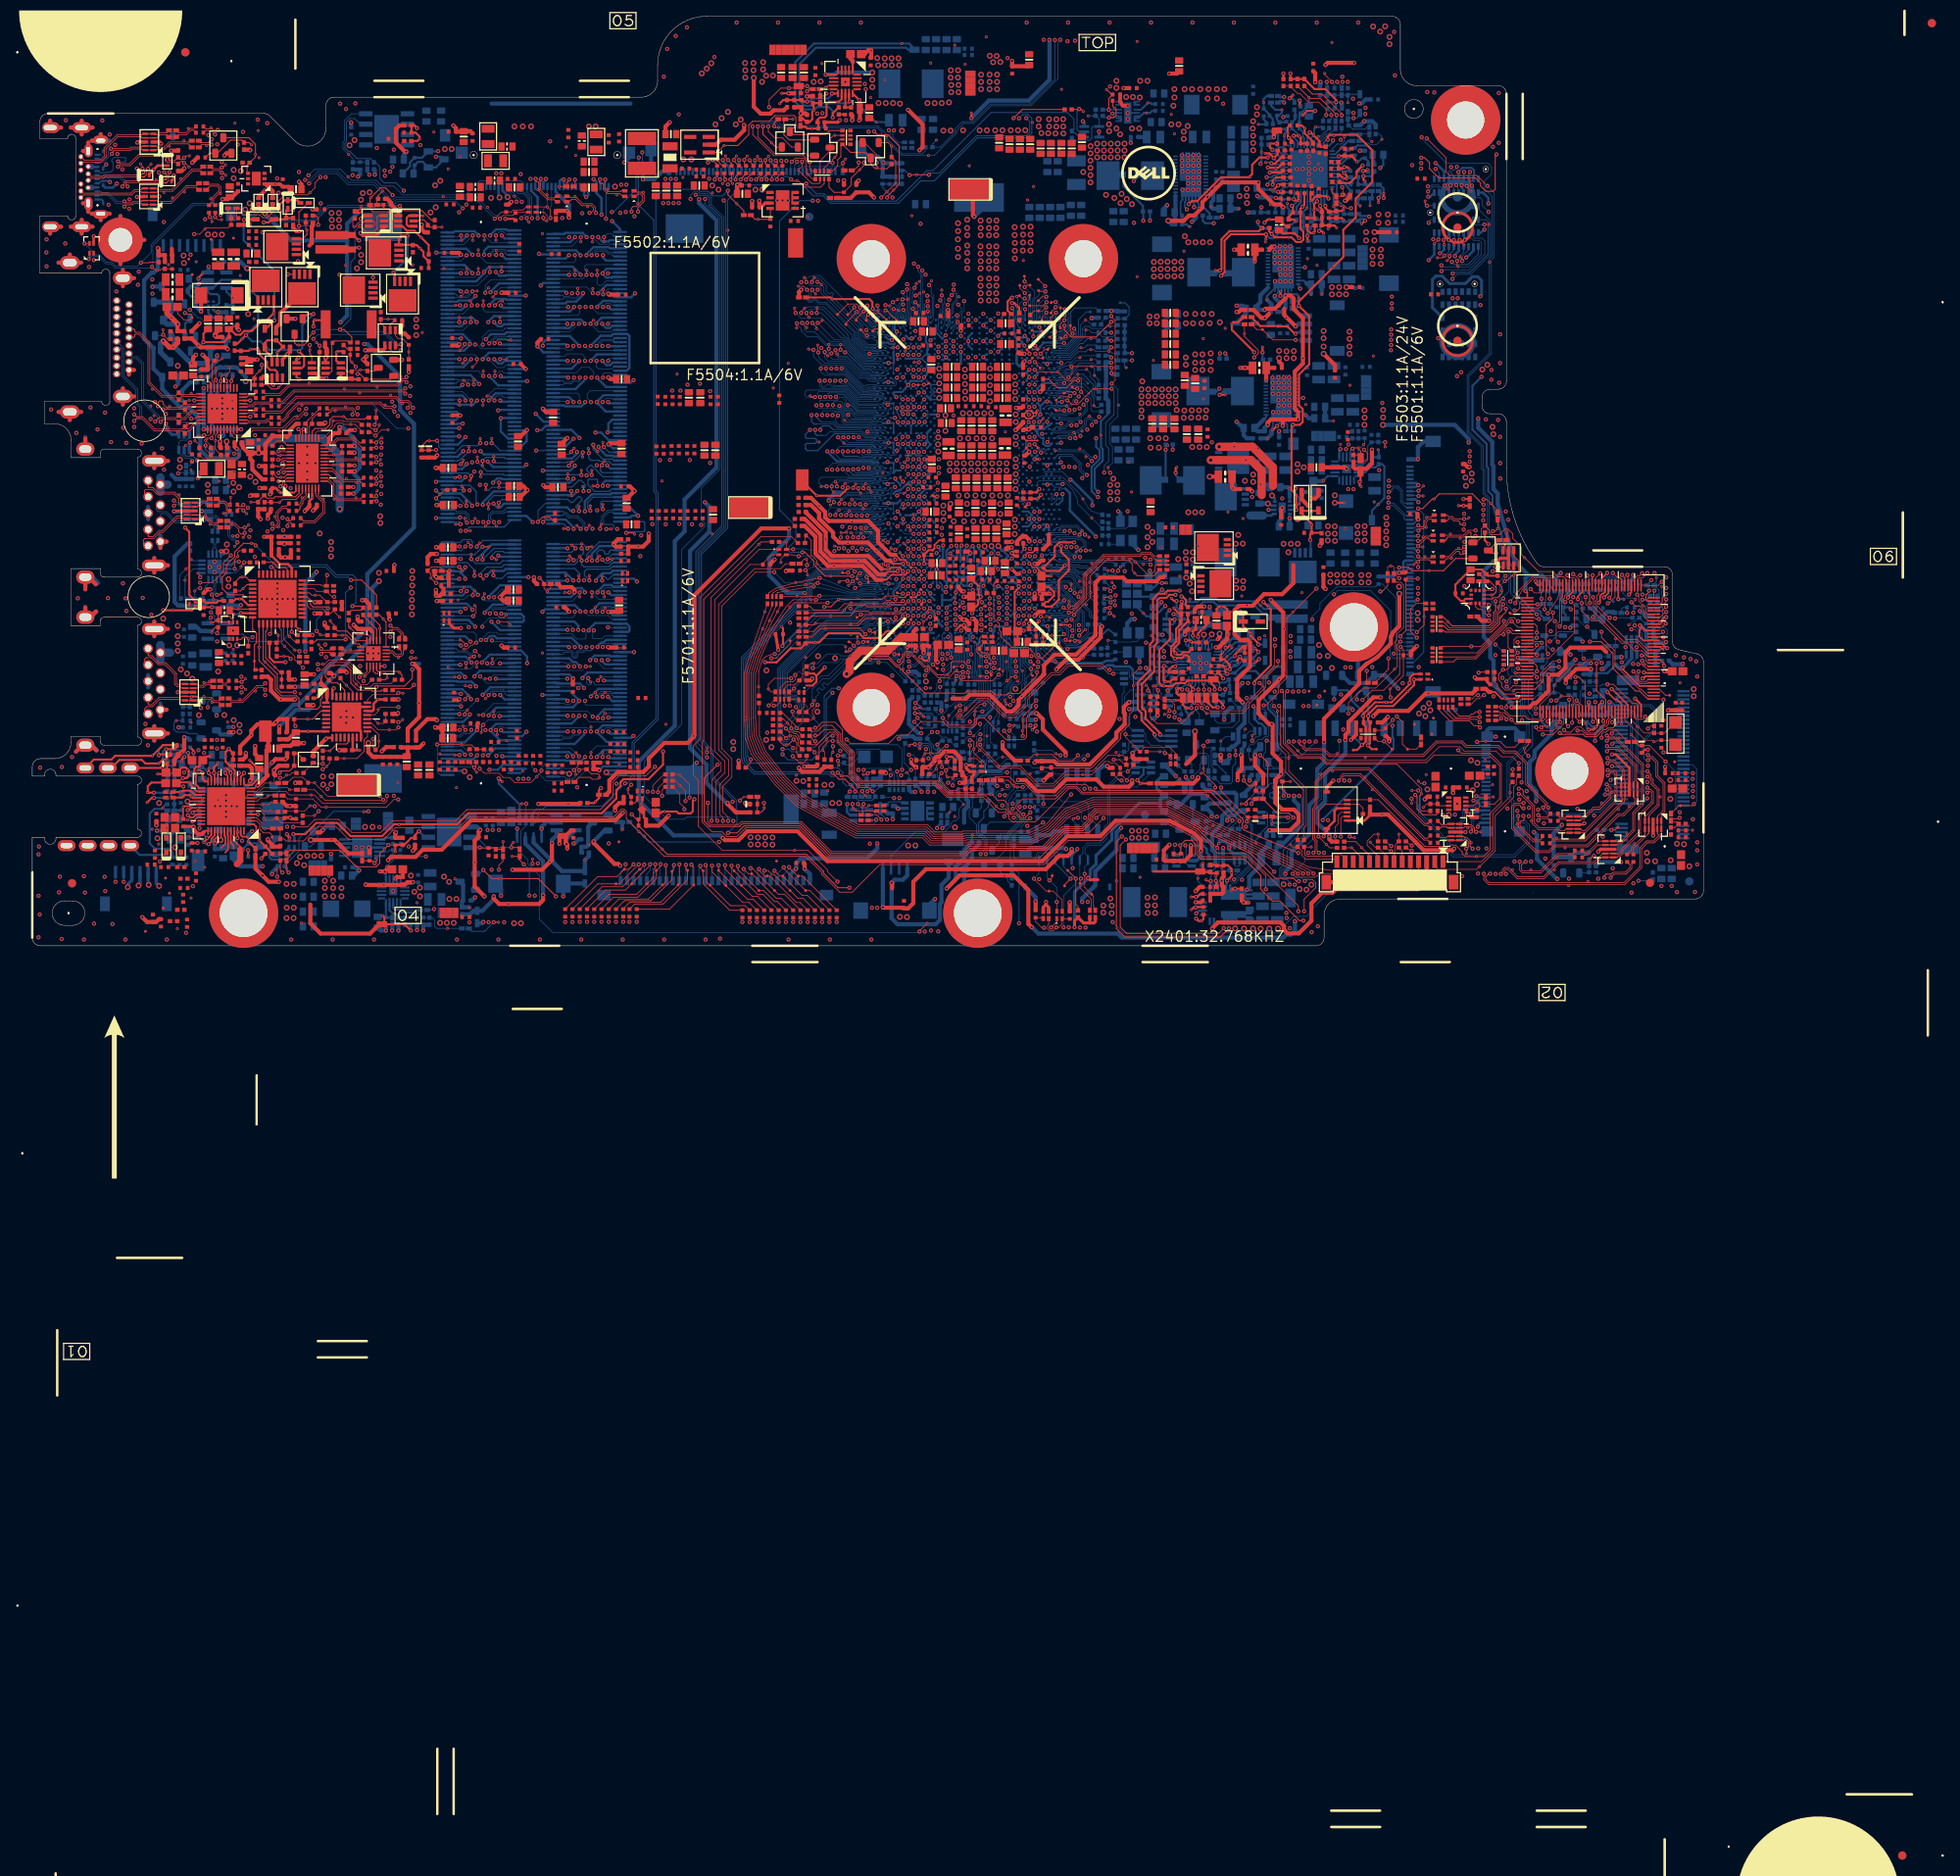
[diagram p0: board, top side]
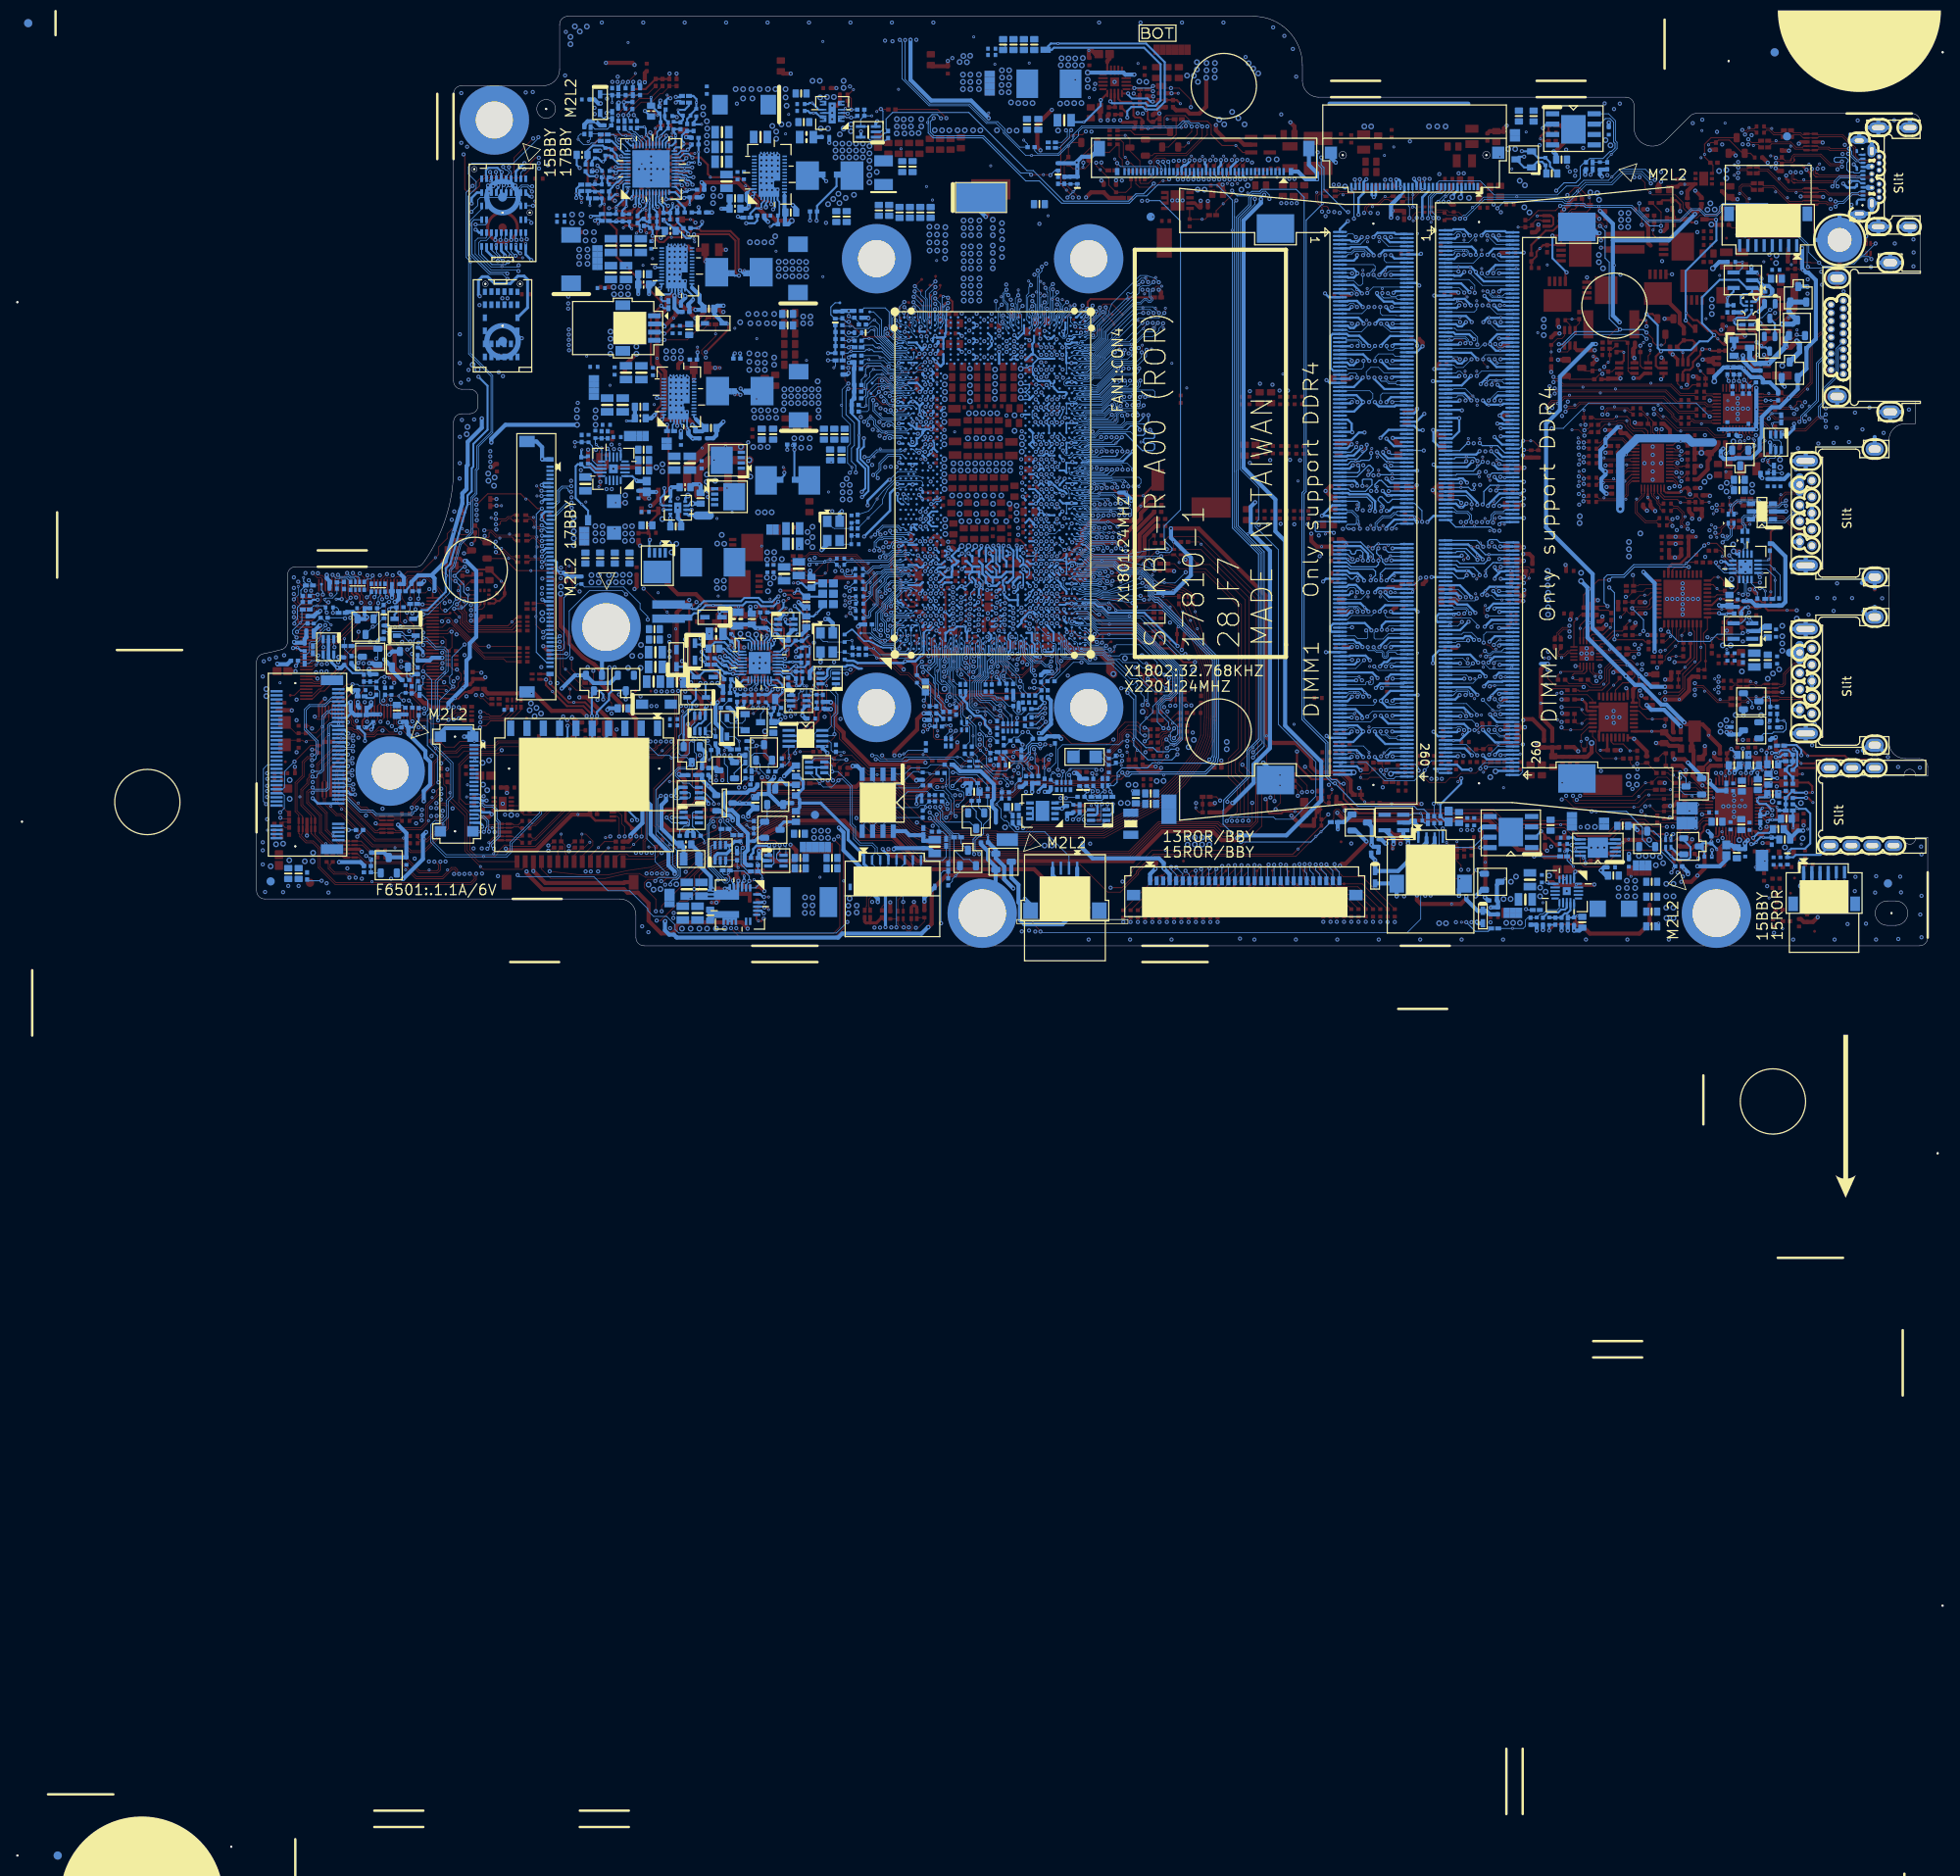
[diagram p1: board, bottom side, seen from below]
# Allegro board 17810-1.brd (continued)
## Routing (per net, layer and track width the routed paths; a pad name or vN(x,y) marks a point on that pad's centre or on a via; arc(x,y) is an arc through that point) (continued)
KSI4: length 150
  TOP w0.102: v1(75.02,9.96) 75.02,9.91 AFTP6505.1 72.34,7.23 69.85,7.23 EC6510.1 ; v1(177.46,26.76) 177.26,26.97 176.73,26.97 176.48,27.22 176.48,27.24 176.16,27.55 173.76,27.55 172.44,28.87 RN2404.5 ; KBC24.104 187.61,27.98 187.73,27.86 187.73,27.22 186.41,25.9 v1(185.16,25.9)
  L4 w0.102: v1(177.46,26.76) 176.4,26.76 172.22,22.59 171.61,22.59 167.28,18.25 163.61,18.25 162.85,17.49 160.44,17.49 159.23,16.27 157.66,16.27 155.8,14.41 154.32,14.41 152.1,12.18 151.19,12.18 149.56,10.56 144.26,10.56 142.84,9.14 132.38,9.14 130.01,6.77 120.04,6.77 118.52,8.3 114.1,8.3 110.93,5.12 104.76,5.12 104.52,5.36 104,5.36 103.94,5.3 98.14,5.3 98.04,5.2 79.78,5.2 v1(75.02,9.96)
  L6 w0.102: v1(177.46,26.76) 177.44,26.76 176.99,27.22 176.99,28.85 177.24,29.1 177.92,29.1 179.94,27.08 180.98,27.08 180.99,27.07 182.86,27.07 183.6,26.33 184.73,26.33 v1(185.16,25.9)
  BOTTOM w0.102: KB1.27 74.52,8.78 75.02,9.28 v1(75.02,9.96)
KSI5: length 145.9
  TOP w0.102: v1(188.26,26.92) 188.01,27.17 KBC24.105 ; RN2404.6 173.03,28.89 174.16,27.76 177.06,27.76 v1(177.42,27.4) ; v1(76.38,10) 76.38,9.61 76.15,9.38 76.15,8.37 AFTP6506.1 74.09,6.32 70.71,6.32 EC6508.1
  L4 w0.102: v1(177.42,27.4) 176.75,27.4 172.14,22.79 171.52,22.79 167.19,18.46 163.52,18.46 162.76,17.7 160.36,17.7 159.14,16.48 157.58,16.48 155.71,14.61 154.24,14.61 152.02,12.39 151.1,12.39 149.48,10.76 144.18,10.76 142.75,9.34 132.3,9.34 129.93,6.97 120.15,6.97 118.62,8.5 112.81,8.5 109.89,5.58 98.14,5.58 97.96,5.4 80.97,5.4 v1(76.38,10)
  L6 w0.102: v1(188.26,26.92) 188.21,26.86 187.6,26.86 187.3,26.56 187.01,26.56 185.51,25.06 184,25.06 182.61,26.46 180.75,26.46 180.74,26.47 178.86,26.47 177.93,27.4 v1(177.42,27.4)
  BOTTOM w0.102: KB1.25 76.12,8.85 76.38,9.11 v1(76.38,10)
KSI6: length 150.9
  TOP w0.102: EC6511.1 69.31,7.59 AFTP6503.1 71.93,7.59 74.32,9.97 v1(74.34,9.97) ; v1(177.42,28.03) 176.33,28.03 176.26,27.96 174.46,27.96 173.53,28.89 RN2404.7 ; KBC24.107 188.81,27.41 v1(188.75,27.35)
  L4 w0.102: v1(177.42,28.03) 177.89,27.56 177.89,26.59 177.51,26.2 176.13,26.2 172.31,22.38 171.69,22.38 167.36,18.05 163.69,18.05 162.93,17.29 160.53,17.29 159.31,16.07 157.75,16.07 155.88,14.2 154.41,14.2 152.19,11.98 151.27,11.98 149.65,10.35 144.35,10.35 142.92,8.93 132.47,8.93 130.1,6.56 119.94,6.56 118.41,8.09 114.19,8.09 111.01,4.92 104.67,4.92 104.44,5.15 104.08,5.15 104.02,5.1 102.74,5.1 102.69,5.05 98.18,5.05 98.13,5 79.32,5 v1(74.34,9.97)
  L6 w0.102: v1(177.42,28.03) 178.41,28.03 179.77,26.67 180.82,26.67 180.83,26.66 182.69,26.66 184.09,25.26 185.43,25.26 186.78,26.62 186.78,27.79 186.98,27.98 188.11,27.98 v1(188.75,27.35)
  BOTTOM w0.102: v1(74.34,9.97) 74.34,9.36 73.72,8.74 KB1.28
KSI7: length 154
  TOP w0.102: v1(73.71,9.97) 73.1,9.36 AFTP6502.1 71.68,8.47 69.31,8.47 EC6512.1 ; v1(189.66,27.46) 189.66,27.47 189.21,27.93 KBC24.108 ; v1(177.42,28.67) 176.91,28.67 176.66,28.41 176.42,28.41 176.17,28.16 174.93,28.16 174.12,28.98 RN2404.8
  L4 w0.102: v1(177.42,28.67) 178.09,27.99 178.09,26.5 177.59,26 176.21,26 170.87,20.66 170.25,20.66 167.44,17.85 163.78,17.85 163.01,17.09 160.61,17.09 159.39,15.87 157.83,15.87 155.96,14 154.49,14 152.27,11.78 151.36,11.78 149.73,10.15 144.43,10.15 143.01,8.73 132.55,8.73 130.18,6.36 119.84,6.36 118.31,7.89 114.27,7.89 110.54,4.16 79.53,4.16 v1(73.71,9.97)
  L6 w0.102: v1(177.42,28.67) 178.06,28.67 179.85,26.87 180.9,26.87 180.91,26.86 182.78,26.86 184.17,25.47 185.34,25.47 186.43,26.56 186.43,27.73 186.89,28.19 188.94,28.19 v1(189.66,27.46)
  BOTTOM w0.102: v1(73.71,9.97) 72.92,9.18 KB1.29
KSO0: length 152
  TOP w0.102: KBC24.2 198.03,30.64 197.2,31.46 196.98,31.46 194,34.44 194,36.14 192.35,37.79 v1(192.35,38.49) ; EC6524.1 89.53,6.32 88.9,6.32 AFTP6507.1 85.72,9.49 v1(85.72,9.81)
  L3 w0.102: v1(188.88,42.73) 189.03,42.58 189.03,42.34 189.04,42.33 189.04,41.86 189.66,41.24 190.96,41.24 192.35,39.85 v1(192.35,38.49)
  L4 w0.102: v1(85.72,9.81) 86.11,10.2 96.87,10.2 97.71,9.36 109.51,9.36 111.74,11.6 114.74,11.6 115.6,12.46 116.85,12.46 117.01,12.3 120.42,12.3 120.57,12.15 124.54,12.15 125.56,13.17 131.48,13.17 134.63,16.32 147.68,16.32 147.71,16.35 149.76,16.35 153.12,19.7 155.7,19.7 156.08,20.08 156.63,20.08 158.54,21.99 165.69,21.99 170.26,26.56 171.09,26.56 172.74,28.21 172.74,30.79 177.85,35.9 177.85,37.26 178.99,38.4 178.99,42 178.94,42.05 178.94,42.41 179.19,42.66 179.51,42.66 180.04,43.2 181.61,43.2 182.75,42.05 183.78,42.05 184.84,43.11 188.49,43.11 v1(188.88,42.73)
  BOTTOM w0.102: v1(188.88,42.73) 189.05,42.9 RN2412.8 ; KB1.13 v1(85.72,9.81)
KSO1: length 152.8
  TOP w0.102: v1(84.12,9.87) 84.12,9.24 AFTP6511.1 87.68,5.68 88.39,5.68 EC6526.1 ; KBC24.14 198.04,35.44 197.32,36.16 196.44,36.16 195.58,37.02 194.9,37.02 192.08,39.84 191.13,39.84 190.88,40.1 189.93,41.04 v1(189.93,42)
  L4 w0.102: v1(84.12,9.87) 84.31,9.87 85.05,10.61 97.53,10.61 98.37,9.77 109.34,9.77 111.58,12.01 114.57,12.01 115.43,12.87 117.02,12.87 117.18,12.7 120.59,12.7 120.74,12.56 124.37,12.56 125.39,13.58 131.31,13.58 134.46,16.73 147.51,16.73 148.62,17.83 150.67,17.83 152.95,20.11 155.53,20.11 155.91,20.49 156.46,20.49 158.37,22.39 165.52,22.39 170.09,26.97 170.92,26.97 172.34,28.38 172.34,30.96 177.44,36.07 177.44,37.43 177.9,37.89 177.9,42.01 178.96,43.07 179.2,43.07 179.74,43.6 181.78,43.6 182.92,42.46 183.62,42.46 184.67,43.52 190.24,43.52 190.84,42.92 190.84,42.56 190.28,42 v1(189.93,42)
  BOTTOM w0.102: v1(189.93,42) 189.93,42.69 189.69,42.93 RN2412.7 ; KB1.15 v1(84.12,9.87)
KSO2: length 148.8
  TOP w0.102: v1(190.41,42.74) 190.41,41.93 195.11,37.23 196.65,37.23 198.04,35.84 KBC24.15 ; EC6523.1 88.9,6.06 88.26,6.06 AFTP6513.1 84.92,9.41 v1(84.92,9.87)
  L4 w0.102: v1(190.41,42.74) 190.36,42.74 189.79,43.31 184.76,43.31 183.7,42.26 182.84,42.26 181.69,43.4 179.96,43.4 179.43,42.87 179.04,42.87 178.1,41.93 178.1,37.8 177.65,37.34 177.65,35.98 172.54,30.88 172.54,28.3 171.01,26.76 170.18,26.76 165.61,22.19 158.45,22.19 156.55,20.29 156,20.29 155.62,19.9 153.03,19.9 149.68,16.55 147.62,16.55 147.6,16.53 134.54,16.53 131.39,13.38 125.47,13.38 124.45,12.36 120.65,12.36 120.51,12.5 117.1,12.5 116.93,12.66 115.51,12.66 114.65,11.8 111.66,11.8 109.43,9.57 97.81,9.57 96.98,10.41 85.63,10.41 85.09,9.87 v1(84.92,9.87)
  BOTTOM w0.102: v1(190.41,42.74) 190.19,42.95 RN2412.6 ; KB1.14 v1(84.92,9.87)
KSO3: length 151.4
  TOP w0.102: KBC24.16 198.04,36.24 196.75,37.53 195.42,37.53 191.36,41.59 191.36,42.68 v1(191.32,42.71) ; v1(83.32,9.81) 83.32,9.07 AFTP6518.1 87.09,5.3 87.88,5.3 EC6522.1
  L4 w0.102: v1(191.32,42.71) 191.32,42.72 190.32,43.72 184.52,43.72 183.84,43.04 182.62,43.04 181.86,43.81 179.65,43.81 179.12,43.27 178.87,43.27 177.7,42.1 177.7,37.97 177.24,37.51 177.24,36.15 172.13,31.05 172.13,28.46 170.84,27.17 170.01,27.17 165.44,22.6 156.55,22.6 156.19,22.97 154.98,22.97 154.18,22.16 154.18,21.24 153.25,20.31 152.86,20.31 150.63,18.08 148.57,18.08 147.43,16.93 134.37,16.93 131.48,14.04 125.56,14.04 124.28,12.76 120.82,12.76 120.68,12.91 117.27,12.91 117.1,13.07 115.35,13.07 114.48,12.21 111.49,12.21 109.26,9.97 98.46,9.97 97.62,10.81 84.32,10.81 v1(83.32,9.81)
  BOTTOM w0.102: RN2412.5 190.78,43.19 191.25,42.71 v1(191.32,42.71) ; KB1.16 v1(83.32,9.81)
KSO4: length 152.6
  TOP w0.102: v1(80.12,9.92) 80.12,9.43 AFTP6514.1 80.31,8.1 77.34,5.12 73.84,5.12 EC6521.1 ; v1(195.53,45.46) 195.61,45.38 KBC24.37
  L4 w0.102: v1(195.53,45.46) 194.33,44.26 184.12,44.26 184.03,44.35 181.26,44.35 181.18,44.27 179.32,44.27 179.23,44.37 178.7,44.37 178.33,43.99 178.33,43.31 177.29,42.27 177.29,38.85 175.14,36.7 175.14,34.91 169.06,28.84 169.06,27.17 165.11,23.21 156.8,23.21 156.44,23.58 154.72,23.58 149.88,18.74 147.73,18.74 146.54,17.54 134.12,17.54 131.23,14.65 125.3,14.65 124.02,13.37 121.08,13.37 120.93,13.52 117.52,13.52 117.36,13.68 114.9,13.68 114.04,12.82 111.24,12.82 109,10.58 99.98,10.58 99.15,11.42 82.88,11.42 80.97,9.52 80.52,9.52 v1(80.12,9.92)
  BOTTOM w0.102: KB1.20 v1(80.12,9.92) ; RN2409.8 193.77,45.05 194.66,45.05 194.69,45.03 195.1,45.03 v1(195.53,45.46)
KSO5: length 154.5
  TOP w0.102: v1(194.87,45.46) 195.22,45.1 195.21,45.09 KBC24.38 ; v1(79.32,9.97) 79.32,7.61 AFTP6510.1 77.04,5.33 73.23,5.33 72.44,4.54 EC6529.1
  L4 w0.102: v1(194.87,45.46) 194.61,45.2 192.02,45.2 191.69,45.53 191.69,45.59 191.44,45.84 190.47,45.84 190.17,45.53 190.17,45.18 189.96,44.97 185.04,44.97 184.48,45.53 182.1,45.53 181.67,45.97 180.31,45.97 179.12,44.77 178.53,44.77 177.93,44.16 177.93,43.48 176.88,42.43 176.88,39.31 174.48,36.91 174.48,34.83 168.65,29.01 168.65,27.57 166.81,25.72 165.46,25.72 165.02,25.28 165.02,24.53 164.11,23.62 157.13,23.62 156.77,23.98 154.31,23.98 149.47,19.14 147.57,19.14 146.37,17.95 133.58,17.95 131.76,16.13 130.1,16.13 129.03,15.06 125.13,15.06 123.85,13.78 121.24,13.78 121.1,13.92 117.69,13.92 117.52,14.09 114.73,14.09 113.87,13.22 111.07,13.22 108.83,10.99 100.15,10.99 99.31,11.83 81.18,11.83 v1(79.32,9.97)
  BOTTOM w0.102: RN2409.7 192.73,44.92 192.86,45.05 193.4,45.05 193.61,45.25 194.66,45.25 v1(194.87,45.46) ; KB1.21 v1(79.32,9.97)
KSO6: length 153.6
  TOP w0.102: v1(193.75,45.69) 194.31,45.13 194.58,45.13 194.81,44.9 KBC24.39 ; v1(81.89,9.8) 81.89,9.52 AFTP6517.1 82.22,7.61 85.47,4.36 EC6527.1
  L4 w0.102: v1(81.89,9.8) 82.09,10 82.09,10.07 83.24,11.22 99.06,11.22 99.9,10.38 109.09,10.38 111.32,12.62 114.12,12.62 114.98,13.48 117.27,13.48 117.43,13.31 120.85,13.31 120.99,13.17 124.1,13.17 125.38,14.45 131.31,14.45 134.2,17.34 146.62,17.34 147.82,18.53 149.96,18.53 154.8,23.37 156.35,23.37 156.72,23.01 165.19,23.01 169.26,27.08 169.26,28.75 175.97,35.46 175.97,37.15 177.49,38.68 177.49,42.18 178.53,43.22 178.53,43.91 178.79,44.16 179.15,44.16 179.24,44.07 181.26,44.07 181.34,44.15 183.84,44.15 183.93,44.06 195.45,44.06 196.67,45.28 196.67,45.64 196.42,45.89 193.95,45.89 v1(193.75,45.69)
  BOTTOM w0.102: v1(193.75,45.69) 193.32,45.25 192.4,45.25 192.23,45.08 RN2409.6 ; v1(81.89,9.8) 81.72,9.63 KB1.18
KSO7: length 147.1
  TOP w0.102: v1(190.63,45.38) 190.41,45.16 KBC24.50 ; v1(80.8,9.95) 81.08,9.67 AFTP6515.1 78.1,4.49 EC6528.1
  L4 w0.102: v1(80.8,9.95) 82.47,11.62 99.23,11.62 100.07,10.79 108.92,10.79 111.15,13.02 113.95,13.02 114.81,13.88 117.44,13.88 117.6,13.72 121.01,13.72 121.16,13.57 123.94,13.57 125.22,14.86 131.14,14.86 134.04,17.75 146.46,17.75 147.65,18.94 149.79,18.94 154.63,23.78 156.52,23.78 156.89,23.42 164.19,23.42 165.23,24.45 165.23,25.2 165.55,25.52 166.89,25.52 168.86,27.48 168.86,28.92 174.83,34.89 174.83,36.8 177.09,39.06 177.09,42.35 178.13,43.39 178.13,44.08 178.62,44.57 179.2,44.57 180.4,45.76 181.58,45.76 182.01,45.33 184.38,45.33 184.94,44.77 190.32,44.77 190.63,45.08 v1(190.63,45.38)
  BOTTOM w0.102: KB1.19 80.92,9.82 v1(80.8,9.95) ; RN2409.5 191.29,44.95 190.88,44.95 190.63,45.2 v1(190.63,45.38)
KSO8: length 148
  TOP w0.102: KBC24.46 192.01,43.12 191.79,42.9 191.79,42.44 191.59,42.23 191.59,41.87 193.27,40.2 v1(193.37,40.2) ; RN2410.8 172.82,36.69 v1(176.4,36.69) 177.6,36.69 180.39,39.49 v1(180.39,39.8) ; EC6525.1 87.37,4.92 85.57,4.92 AFTP6516.1 82.68,7.81 82.68,9.73 v1(82.52,9.89)
  L4 w0.102: v1(82.52,9.89) 83.65,11.01 98.14,11.01 98.98,10.18 109.17,10.18 111.41,12.41 114.4,12.41 115.26,13.27 117.19,13.27 117.35,13.11 120.76,13.11 120.91,12.97 124.2,12.97 125.47,14.24 131.39,14.24 134.29,17.14 147.34,17.14 148.54,18.33 150.59,18.33 152.78,20.51 153.16,20.51 153.83,21.18 153.83,22.11 154.89,23.17 156.27,23.17 156.63,22.81 165.36,22.81 170.15,27.6 170.98,27.6 171.93,28.55 171.93,31.13 176.4,35.6 v1(176.4,36.69)
  L6 w0.102: v1(180.39,39.8) 180.79,40.2 183.67,40.2 184.25,39.62 185.11,39.62 185.7,40.2 187.61,40.2 187.94,40.53 190.83,40.53 191.01,40.71 192.76,40.71 193.27,40.2 v1(193.37,40.2)
  BOTTOM w0.102: KB1.17 v1(82.52,9.89)
KSO9: length 132.3
  TOP w0.102: v1(185.01,42.54) 185.01,41.74 184.68,41.41 184.03,41.41 184,41.44 KBC24.68 ; v1(90.98,9.2) 91.62,8.55 AFTP6504.1 94.36,6.19 94.99,6.19 EC6518.1
  L4 w0.102: v1(185.01,42.54) 184.56,42.54 183.88,41.85 182.67,41.85 181.52,42.99 180.13,42.99 179.87,42.73 179.87,41.47 180.88,40.45 182.04,40.45 182.55,39.95 182.55,38.52 181.05,37.02 181.05,36.11 174.43,29.5 174.43,28.07 171.26,24.9 170.65,24.9 166.32,20.57 162.39,20.57 161.63,19.8 158.47,19.8 157.25,18.58 156.7,18.58 155.56,17.44 153.17,17.44 149.29,13.55 138.87,13.55 137.04,11.73 130.94,11.73 130.23,11.01 125.4,11.01 124.79,10.4 111.99,10.4 109.93,8.35 99.92,8.35 99.01,7.43 92.74,7.43 v1(90.98,9.2)
  BOTTOM w0.102: v1(90.98,9.2) 90.52,8.73 KB1.7 ; R2450.1 185.7,43.48 R2449.2 184.94,42.61 v1(185.01,42.54)
KSO10: length 129
  TOP w0.102: v1(92.75,9.64) 92.75,9.6 93.8,8.55 AFTP6523.1 94.41,8.55 EC6516.1 ; KBC24.72 182.29,39.84 182.22,39.77 v1(182.11,39.77) 181.68,40.2 181.18,40.2 180.82,39.85 180.82,39.62 180.57,39.37 180.56,39.37 177.09,35.9 RN2410.7
  L4 w0.102: v1(92.75,9.64) 92.78,9.64 93.42,9.01 96.33,9.01 96.48,9.16 109.59,9.16 111.83,11.4 114.82,11.4 115.68,12.26 116.77,12.26 116.93,12.09 120.34,12.09 120.49,11.95 124.62,11.95 125.64,12.97 131.56,12.97 132.62,14.03 133.7,14.03 134.57,14.9 147.27,14.9 147.55,15.18 147.55,15.46 147.95,15.87 149.96,15.87 153.32,19.22 155.9,19.22 156.28,19.6 156.83,19.6 158.74,21.51 165.89,21.51 170.42,26.03 171.25,26.03 173.23,28.01 173.23,30.59 178.42,35.79 178.42,37.15 179.61,38.34 179.61,39.64 180.21,40.23 181.65,40.23 v1(182.11,39.77)
  BOTTOM w0.102: v1(92.75,9.64) 92.75,9.35 92.12,8.72 KB1.5
KSO11: length 127.7
  TOP w0.102: v1(92.12,9.62) 92.12,9.45 AFTP6522.1 95.3,6.77 EC6515.1 ; KBC24.74 182.08,39.04 v1(181.35,39.77) 181.25,39.77 180.65,39.17 180.64,39.17 176.88,35.4 RN2410.6
  L4 w0.102: v1(92.12,9.62) 92.93,8.81 96.42,8.81 96.57,8.96 109.68,8.96 111.91,11.19 114.91,11.19 115.77,12.05 116.68,12.05 116.84,11.89 120.26,11.89 120.4,11.75 124.7,11.75 125.73,12.77 131.64,12.77 132.71,13.83 133.78,13.83 134.65,14.7 148.01,14.7 148.44,15.13 148.44,15.41 148.69,15.66 150.05,15.66 153.4,19.02 155.99,19.02 156.37,19.4 156.92,19.4 158.82,21.3 165.97,21.3 170.45,25.77 171.28,25.77 173.43,27.93 173.43,30.51 178.63,35.71 178.63,37.07 180.9,39.34 180.92,39.34 v1(181.35,39.77)
  BOTTOM w0.102: KB1.6 91.32,8.82 v1(92.12,9.62)
KSO12: length 132.4
  TOP w0.102: RN2410.5 174.22,34.81 174.57,35.17 176.93,35.17 179.93,38.17 v1(180.34,38.17) 180.34,38.5 180.77,38.93 181.2,38.93 181.49,38.64 KBC24.75 ; EC6513.1 91.31,5.43 90.98,5.43 89.63,6.77 AFTP6519.1 86.49,9.36 v1(86.49,9.77)
  L4 w0.102: v1(180.34,38.17) 180.01,37.84 180.01,35.67 178.48,34.15 177.36,34.15 174.03,30.82 174.03,28.24 171.1,25.31 170.48,25.31 166.15,20.97 159.07,20.97 157.08,18.99 156.54,18.99 155.39,17.85 153.01,17.85 149.12,13.96 138.68,13.96 136.85,12.13 130.77,12.13 130.06,11.42 125.11,11.42 124.5,10.81 111.82,10.81 109.76,8.75 97.31,8.75 97.15,8.6 92.47,8.6 91.13,9.95 86.66,9.95 v1(86.49,9.77)
  BOTTOM w0.102: v1(86.49,9.77) 86.52,9.74 KB1.12
KSO13: length 121.7
  TOP w0.102: RN2411.8 180.9,36.58 180.9,38.45 v1(180.95,38.5) 181.18,38.5 181.43,38.24 KBC24.76 ; v1(89.08,9.4) 89.08,9.26 89.79,8.55 AFTP6520.1 90.4,8.55 93.65,5.3 94.11,5.3 EC6517.1
  L4 w0.102: v1(89.08,9.4) 89.32,9.64 91.14,9.64 92.39,8.4 97.33,8.4 97.48,8.55 109.85,8.55 111.9,10.61 124.59,10.61 125.2,11.22 130.15,11.22 130.86,11.93 136.96,11.93 138.78,13.76 149.2,13.76 153.09,17.64 155.48,17.64 156.62,18.79 157.17,18.79 159.15,20.77 166.23,20.77 170.56,25.1 171.18,25.1 174.23,28.15 174.23,29.58 180.8,36.15 180.8,38.35 v1(180.95,38.5)
  BOTTOM w0.102: KB1.9 88.92,9.25 v1(89.08,9.4)
KSO14: length 120.3
  TOP w0.102: RN2411.7 181.72,35.55 181.72,35.56 v1(182.09,35.93) 181.8,36.22 181.8,36.44 181.63,36.6 181.63,37.51 181.97,37.84 KBC24.77 ; EC6514.1 94.49,5.81 93.85,5.81 AFTP6521.1 90.93,8.73 90.68,8.73 90.19,9.21 v1(89.74,9.21)
  L4 w0.102: v1(89.74,9.21) 91.72,7.23 99.09,7.23 99.82,7.95 100.54,7.95 101.22,7.28 109.15,7.28 112.07,10.2 124.87,10.2 125.48,10.81 130.32,10.81 131.03,11.52 137.12,11.52 138.95,13.35 149.37,13.35 153.26,17.24 155.65,17.24 156.79,18.38 157.34,18.38 158.56,19.6 161.97,19.6 162.73,20.36 166.4,20.36 170.73,24.69 171.35,24.69 174.64,27.98 174.64,29.33 180.14,34.84 181,34.84 v1(182.09,35.93)
  BOTTOM w0.102: v1(89.74,9.21) 89.72,9.2 KB1.8
KSO15: length 120
  TOP w0.102: v1(88.03,9.51) 88.24,9.51 AFTP6524.1 91.44,6.32 92.2,6.32 EC6519.1 ; RN2411.6 181.72,35.05 182.07,34.7 v1(182.07,34.64) 182.14,34.64 182.54,34.24 KBC24.86
  L4 w0.102: v1(182.07,34.64) 180.23,34.64 174.84,29.25 174.84,27.9 171.43,24.49 170.82,24.49 166.49,20.16 162.82,20.16 162.06,19.4 159.65,19.4 158.44,18.18 156.87,18.18 155.73,17.03 153.34,17.03 149.46,13.15 139.04,13.15 137.21,11.32 131.11,11.32 130.4,10.61 125.6,10.61 124.99,10 112.16,10 109.24,7.08 101.13,7.08 100.46,7.75 99.9,7.75 99.18,7.03 90.52,7.03 v1(88.03,9.51)
  BOTTOM w0.102: v1(88.03,9.51) 88.12,9.42 KB1.10
KSO16: length 123.7
  TOP w0.102: KBC24.92 181.83,31.84 181.81,31.87 181.51,31.87 180.97,31.33 180.57,31.33 180.14,31.77 180.14,32.2 179.78,32.55 179.78,33.34 v1(180.29,33.85) 180.73,33.85 RN2411.5 ; EC6520.1 91.82,5.81 91.21,5.81 AFTP6539.1 87.78,8.83 v1(87.2,9.41)
  L4 w0.102: v1(87.2,9.41) 89.79,6.82 99.26,6.82 99.98,7.55 100.37,7.55 101.05,6.87 109.32,6.87 112.24,9.79 125.12,9.79 125.73,10.41 130.48,10.41 131.2,11.12 137.29,11.12 139.12,12.95 149.54,12.95 153.43,16.83 155.81,16.83 156.96,17.97 158.52,17.97 159.74,19.19 162.14,19.19 162.9,19.96 166.57,19.96 170.9,24.29 171.52,24.29 175.04,27.81 175.04,29.16 179.73,33.85 v1(180.29,33.85)
  BOTTOM w0.102: v1(87.2,9.41) 87.32,9.29 KB1.11
L_BKLT_CTRL: length 72.8
  TOP w0.114: v1(104.06,91.71) 105.84,93.49 105.84,96.16 R5502.2 v2(105.33,98.01) 105.33,98.02 104.89,98.45 D5502.1
  L3 w0.114: v1(118.51,42.07) 117.77,42.81 117.77,46.59 119.13,47.95 119.13,49.29 118.01,50.41 112.67,50.41 112.29,50.79 111.34,50.79 110.23,51.91 110.23,73.49 111.3,74.57 111.3,76.39 112.7,77.79 112.7,78.83 113.39,79.53 113.39,81.25 112.59,82.04 112.59,83.3 104.62,91.27 104.5,91.27 v1(104.06,91.71)
  BOTTOM w0.114: v1(118.51,42.07) 118.21,42.38 CPU1.R11
L_BKLT_EN: length 221.8
  TOP w0.102: v1(163.57,33.7) 163.57,32.35 R2435.2
  L4 w0.102: v1(125.35,111.01) 126.55,109.81 128.41,109.81 128.52,109.92 162.01,109.92 164.18,107.75 164.18,105.46 164.45,105.19 165.12,104.52 165.12,101.78 168.92,97.98 169.47,97.98 170.69,96.77 170.69,93.82 170.25,93.39 170.25,86.48 173.56,83.18 173.56,82.36 173.06,81.86 172.28,81.86 171.09,80.67 171.09,71.97 168.37,69.26 168.37,61.07 167.68,60.37 167.68,46.82 168.01,46.49 168.01,44.88 167.72,44.59 167.13,44.59 166.74,44.2 166.74,37.08 165.28,35.62 165.28,34.56 164.41,33.7 v1(163.57,33.7) 163.53,33.7 161.75,31.92 157.52,31.92 156.2,30.6 152.2,30.6 151.51,31.28 148.07,31.28 146.72,29.94 142.26,29.94 141.35,29.02 141.35,27.57 140.88,27.1 139.71,27.1 139.34,27.47 137.4,27.47 134.62,30.26 134.08,30.26 128.58,24.76 122.39,24.76 122.06,25.09 121.15,25.09 120.31,25.92 118.95,25.92 118.37,26.49 118.37,29.79 118.07,30.1 118.07,33.42 118.43,33.78 118.43,36.35 118.08,36.7 118.08,42.32 v1(118.48,42.72)
  BOTTOM w0.102: v1(125.35,111.01) 125.35,106.18 122.33,103.17 117.45,103.17 115.29,101.01 114,101.01 113.1,100.11 113.1,99.69 111.29,97.88 R5512.2 110.34,98.26 v2(110.82,98.75) ; CPU1.R12 118.24,42.72 v1(118.48,42.72)
L_BKLT_EN_C: length 32.6
  TOP w0.102: D5503.2 95.06,96.85 94.79,97.12 90.93,97.12 88.93,99.12 v1(88.93,100.42)
  BOTTOM w0.102: v1(88.93,100.42) 89.36,100.85 89.38,100.85 89.39,100.85 89.58,100.85 90.35,100.85 90.6,101.11 91.31,101.11 91.97,100.45 103.71,100.45 104.75,99.41 v2(104.75,99.23) 104.75,98.93 106.61,97.07 109.09,97.07 109.47,97.45 R5512.1
L_BKLT_EN_EC: length 33.9
  TOP w0.114: v1(166.24,35.22) 166.24,33.9 v2(165.48,33.14) R2435.1 ; v1(186.41,40.83) 186.41,40.16 185.58,39.33 185.58,36.08 185.8,35.86 v1(185.8,35.78)
  L6 w0.114: v1(185.8,35.78) 185.48,35.78 184.71,35.01 183.72,35.01 182.27,33.56 181.91,33.56 181.62,33.86 181.6,33.86 181.56,33.9 180.45,35.01 179.1,35.01 178.81,35.3 169.02,35.3 168.59,34.87 166.57,34.87 166.27,35.17 166.27,35.2 v1(166.24,35.22)
  BOTTOM w0.114: v1(186.41,40.83) 186.03,41.22 R2422.1 ; v1(185.8,35.78) 185.7,35.68 185.7,34.71 185.1,34.1 R2436.1
LANWAKE#: length 200.8
  TOP w0.102: v1(108.76,1.74) 108.76,1.82 v2(109.7,2.76) ; v1(197.33,45.66) 197.05,45.38 196.8,45.38 196.41,44.99 KBC24.35
  L3 w0.102: v1(108.76,1.74) 108.76,1.74 114.3,7.28 117.26,7.28 119.35,5.19 119.35,2.41 121.14,0.63 152.63,0.63 152.86,0.85 153.41,0.85 154.15,1.59 154.15,2.15 v1(154.15,2.15)
  L4 w0.102: v1(197.33,45.66) 197.34,45.66 197.75,45.25 198.6,45.25 199.27,44.59 199.27,42.71 199.04,42.48 199.04,38.19 198.75,37.9 198.75,14.94 196.3,12.48 196.3,10.03 192.77,6.5 158.95,6.5 156.08,3.62 154.76,3.62 154.19,3.05 154.19,2.19 v1(154.15,2.15)
  BOTTOM w0.102: R1732.1 60.5,14.7 59.9,14.09 59.9,11.36 60.76,10.51 60.76,10 62.15,8.6 62.15,3.27 63.8,1.62 108.63,1.62 v1(108.76,1.74)
LCD_BRIGHTNESS: length 18.4
  TOP w0.114: RN5501.4 97.66,92.98 98.3,92.35 EC5501.1 100.38,93.23 100.38,94.07 v2(101.42,95.12) 101.93,95.62 v1(101.93,95.98)
  L4 w0.114: v1(101.93,95.98) 101.93,95.99 101.48,96.44 101.1,96.44 99.74,95.08 94.75,95.08 v1(93.73,96.11)
  BOTTOM w0.114: v1(93.73,96.11) 93.73,96.1 93.73,95.91 93.45,95.63 LCD1.30
LCD_TST: length 219
  TOP w0.102: D5502.2 101.99,98.45 103.5,96.94 v1(103.5,95.98) ; KBC24.26 199.51,40.24 200.18,40.91 v1(200.28,40.91) ; v1(88.3,100.42) 88.31,100.41 88.31,99.41 90.88,96.84 94.53,96.84 95.3,96.07 v1(95.3,96.05) 95.3,95.22 95.58,94.94 RN5501.8
  L3 w0.102: v1(200.28,40.91) 199.59,41.6 199.59,43.74 199.12,44.21 187.14,44.21 186.31,45.04 184.78,45.04 184.7,45.12 184.62,45.16 184.34,45.3 184.23,45.35 184.22,45.36 183.35,45.36 180.92,47.79 180.92,49.14 180.61,49.46 180.61,49.94 180.39,50.15 179.96,50.59 179.96,51.2 179.42,51.73 179.42,55.03 179.13,55.98 178.83,56.92 178.8,57.03 178.75,57.18 178.75,61.17 176.06,63.86 176.06,68.34 176.9,69.18 176.9,71.28 179.22,73.6 179.22,78.63 179.61,79.02 179.61,95.79 177.98,97.41 174.11,97.41 171.17,100.35 171.17,103.25 170.01,104.41 168.65,104.41 166.47,106.59 166.47,108.38 162.12,112.73 86.77,112.73 83.62,109.58 v1(83.62,108.93)
  L4 w0.102: v1(88.3,100.42) 88.3,104.25 v1(83.62,108.93) ; v1(95.3,96.05) 95.35,96.05 95.91,95.5 99.57,95.5 100.93,96.85 102.6,96.85 103.47,95.98 v1(103.5,95.98)
  BOTTOM w0.102: v2(103.55,95.42) 103.5,95.47 v1(103.5,95.98)
LCD_TST_C: length 6.3
  TOP w0.102: RN5501.1 95.65,93.97 v2(95.1,94.53) 94.87,94.76 94.87,96.21 94.54,96.54 93.53,96.54 v1(93.1,96.1)
  BOTTOM w0.102: v1(93.1,96.1) 92.95,95.95 LCD1.29
LCD_VCC_TEST_EN: length 197.7
  TOP w0.102: D5501.2 93.08,97.9 91.95,99.03 90.98,99.03 90.22,99.79 v1(90.22,100.42) ; KBC24.113 191.21,27.56 v1(191.3,27.46)
  L3 w0.102: v1(191.3,27.46) 191.3,28.5 190.38,29.43 190.38,34.2 189.71,34.87 189.71,36.49 189.29,36.91 189.29,38.82 188.44,39.67 187.94,39.67 186.89,40.72 186.89,42.39 186.32,42.97 184.83,42.97 184.17,42.31 182.47,42.31 181.2,43.58 180.64,43.58 179.75,44.47 179.75,47.36 179.45,47.67 179.24,47.67 178.99,47.92 178.99,49.87 176.1,52.77 176.1,55.7 177.01,56.61 177.01,60.62 176.38,61.26 175.89,61.26 175.64,61.51 175.64,62.41 174.89,63.16 174.89,68.82 175.72,69.65 175.72,71.77 178.03,74.09 178.03,79.16 178.26,79.39 178.26,86.41 177.32,87.36 177.32,91.2 178.88,92.76 178.88,95.48 177.68,96.68 171.76,96.68 166.98,101.46 166.98,104.43 165.3,106.1 165.3,107.89 161.63,111.56 126.53,111.56 v1(126.01,111.04)
  BOTTOM w0.102: v1(126.01,111.04) 125.73,110.76 125.73,106.28 122.42,102.96 117.53,102.96 115.37,100.8 114.19,100.8 113.31,99.92 113.31,99.61 110.56,96.87 v2(109.85,96.87) 106.53,96.87 104.09,99.31 104.09,99.78 103.62,100.25 91.79,100.25 91.13,100.91 90.7,100.91 v1(90.22,100.42)
LCDVDD:
  vias: v1(82.95,94.02) v2(83.36,92.27) v3(83.36,93.18) v3(84.12,92.68) v3(86.23,100.68) v3(86.84,101.26)
LDO1_CAP: length 5.8
  TOP w0.203: v1(21.62,12.46) 22.02,12.87 22.02,13.18 22.35,13.51 HDA27.39
  BOTTOM w0.254: C2702.2 18.41,13.25 R2711.2 20.11,13.25 v2(20.16,13.3) 20.5,13.3 21.33,12.46 v1(21.62,12.46)
LDO2_CAP: length 2.9
  TOP w0.203: v1(24.31,21.17) 24.35,21.13 HDA27.17
  TOP w0.254: v1(24.31,21.17) 24.31,21.3 23.87,21.73 v2(23.7,21.73)
  BOTTOM w0.254: v1(24.31,21.17) 24.38,21.25 C2712.2
LDO3_CAP: length 5.2
  TOP w0.203: 26.48,19.7 26.13,19.7 25.95,19.89 HDA27.13
  TOP w0.254: 26.48,19.7 26.9,19.7 27.77,20.57 27.77,21.64 C2718.1 27.7,21.68 v2(26.65,22.73)
LID_CL_SIO#: length 285.4
  TOP w0.102: v1(180.31,42.56) 179.87,42.12 179.87,41.69 v2(179.74,41.56) 179.74,41.12 179.37,40.75 179.37,39.69 178.64,38.95 173.73,38.95 172.98,39.71 RN2405.3 ; KBC24.66 182.54,42.24 182.32,42.01 182.32,41.37 182.04,41.09 v1(181.71,41.09) ; v1(13.31,83.71) 14.3,83.71 14.37,83.79 R7011.1 ; GMR1.4 6.41,86.08 v1(6.4,86.07)
  L3 w0.102: v1(35.36,91) 35.36,92.77 42.22,99.64 47.22,99.64 47.43,99.85 51.89,99.85 52.56,100.52 57.67,100.52 58.53,99.66 61.55,99.66 62.41,100.52 66.12,100.52 67.01,99.64 75.81,99.64 78.71,102.53 79.1,102.53 84.5,107.94 84.5,109.49 87.05,112.04 161.83,112.04 165.78,108.09 165.78,106.3 167.46,104.63 167.46,101.95 v1(170.31,99.1)
  L4 w0.102: v1(186.02,37.3) 184.86,38.46 184.86,38.91 182.68,41.09 v1(181.71,41.09)
  BOTTOM w0.102: v1(181.71,41.09) 181.48,41.09 180.73,41.84 180.73,42.09 180.31,42.52 v1(180.31,42.56) 180.31,42.76 181.02,43.48 181.02,45.99 180.56,46.45 180.51,46.63 180.44,46.87 179.77,49.19 178.36,50.6 178.36,54.87 177.84,55.39 177.84,58.27 177.65,58.46 177.65,61.17 175.9,62.92 175.9,69.89 178.61,72.61 178.61,84.25 178.94,84.58 178.94,91.86 177.93,92.87 177.93,93.65 178.88,94.59 178.88,95.48 178.45,95.9 173.38,95.9 170.31,98.97 v1(170.31,99.1) ; v1(35.36,91) 35.36,90.14 34.19,88.97 30.38,88.97 29.01,90.34 27.91,90.34 27.25,89.68 25.91,89.68 25.5,90.09 25.5,90.59 25.1,90.99 19.65,90.99 14.58,85.93 14.58,84.98 v1(13.31,83.71) 12.88,83.28 10.21,83.28 9.7,83.79 9.1,83.79 8.21,84.67 7.8,84.67 v1(6.4,86.07) ; v1(186.02,37.3) 186.21,37.3 186.92,38.02 D2402.K
LID_CL_SIO_TAB#: length 16.1
  TOP w0.089: KBC24.97 184.81,29.53 186.49,31.21 186.49,31.94 189.02,34.48 190.04,34.48 190.63,35.06 191.98,35.06 v1(192.38,34.66)
  BOTTOM w0.089: v2(194.08,37.63) R2461.2 194.08,36.36 R2496.1 193.14,35.42 Q2415.D 191.88,35.16 v1(192.38,34.66)
LINE1-L_C: length 2.3
  BOTTOM w0.254: R2922.1 16.53,15.69 C2907.2 16.48,15.38 v2(16.48,14.42)
LINE1-L_R: length 1.1
  BOTTOM w0.254: R2921.1 17.95,22.62 C2908.2
LINE1_L: length 3.1
  TOP w0.203: HDA27.34 20.19,15.71 19.72,15.24 v1(19.63,15.24)
  BOTTOM w0.254: v1(19.63,15.24) 19.44,15.43 v2(19.05,15.43) 18.11,15.43 C2907.1
LINE1_R: length 12.9
  TOP w0.203: HDA27.33 20.12,16.11 19.75,15.74 19.33,15.74 v1(19.07,15.99)
  TOP w0.254: v1(19.76,23.66) 19.76,23.92 v2(19.43,24.25)
  L3 w0.254: v1(19.07,15.99) 18.69,15.99 18.29,16.4 18.29,18.46 19.76,19.93 v1(19.76,23.66)
  BOTTOM w0.254: v1(19.76,23.66) 19.76,22.35 C2908.1
LINE1_VREFO_L: length 16.3
  TOP w0.203: HDA27.14 25.55,20.72 25.96,21.13 v1(25.96,21.17)
  TOP w0.254: v1(14.91,18.13) 14.64,18.13 v2(14.07,17.56)
  L6 w0.254: v1(25.96,21.17) 25.96,21.07 25.47,20.59 21.94,20.59 20.37,19.02 19.35,19.02 18.46,18.13 v1(14.91,18.13)
  BOTTOM w0.254: v1(14.91,18.13) 16.51,18.13 R2912.1
LINE1_VREFO_R: length 10.7
  TOP w0.203: HDA27.15 25.15,21 v1(25.32,21.17)
  TOP w0.254: v1(18.64,23.13) 18.34,22.83 v2(18.34,22.57)
  L6 w0.254: v1(25.32,21.17) 24.05,22.44 19.33,22.44 v1(18.64,23.13)
  BOTTOM w0.254: v1(18.64,23.13) 18.08,23.13 17.78,23.44 R2913.1
LVDS_VDD_EN_R: length 22.1
  TOP w0.127: U5501.1 83.96,97.24 v2(84.81,98.09) 86.49,98.09 87.83,99.43 87.83,100.59 88.3,101.06 90.34,101.06 91.03,101.76 93.36,101.76 93.6,101.52 93.6,100.54 D5501.3 93.24,99.42 97.22,99.42 97.71,99.91 RN5502.5
M2_SSD_PEDET: length 109
  TOP w0.127: v2(127.63,15.56) 127.77,15.69 v1(128.19,15.69)
  L3 w0.127: v1(122.48,35.5) 122.44,35.5 121.56,34.63 121.56,32.96 120.79,32.19 120.35,32.19 119.42,31.26 119.42,29.31 120.72,28.01 120.72,21.6 126.63,15.69 v1(128.19,15.69)
  L6 w0.127: v1(192.51,13.38) 194.23,11.65 194.23,7.97 193.68,7.42 191.86,7.42 190.55,8.73 186.41,8.73 185.76,8.09 158.17,8.09 156.41,6.33 152.61,6.33 151.51,7.43 151.07,7.43 148.65,9.86 142.92,9.86 141.42,11.36 139.16,11.36 138.35,12.17 138.35,13.02 136.42,14.95 128.93,14.95 v1(128.19,15.69)
  BOTTOM w0.102: v1(122.48,35.5) 122.45,35.53 122.45,36.01 122.67,36.23 122.67,38.08 CPU1.G4
  BOTTOM w0.127: v1(192.51,13.38) 191.79,14.09 R6310.1
M_A_A0: length 50.6
  TOP w0.152: v2(65.12,51.12) v1(65.68,51.12)
  L3 w0.089: 93.31,66.03 95.91,66.03 v1(96.11,66.23)
  L3 w0.203: v1(65.68,51.12) 65.68,53.36 67.08,54.75 68.65,54.75 68.73,54.83 72.16,54.83 73.64,56.31 74.53,56.31 75.12,56.9 76.2,56.9 78.65,59.36 78.65,59.7 79.98,61.03 80.66,61.03 82.35,62.72 83.13,62.72 86.47,66.06 93.28,66.06 93.31,66.03
  BOTTOM w0.089: CPU1.AY50 104.46,64.5 104.25,64.5 103.94,64.19 103.04,64.19 102.82,64.41 100.11,64.41 99.59,64.93 99.59,65.26 99.1,65.75 98.78,65.75 98.68,65.85 96.42,65.85 96.11,66.16 v1(96.11,66.23)
  BOTTOM w0.152: DM1.144 64.34,51.73 64.34,51.73 65.07,51.73 v1(65.68,51.12)
M_A_A1: length 49.1
  TOP w0.152: v2(69.94,54.07) v1(69.94,53.51)
  L3 w0.089: 93.01,65.05 94.17,65.05 94.75,65.62 99.36,65.62 99.59,65.85 99.59,66.6 99.69,66.71 100.32,66.71 100.42,66.81 100.42,67.55 100.32,67.65 99.6,67.65 98.93,66.98 v1(98.93,66.16)
  L3 w0.203: v1(69.94,53.51) 70,53.51 70.31,53.81 72.58,53.81 73.31,54.54 74.19,54.54 75.54,55.89 76.76,55.89 80.12,59.25 80.12,59.73 80.4,60.01 80.8,60.01 80.89,59.92 81.31,59.92 82.36,60.96 82.81,60.96 86.89,65.05 93.01,65.05
  BOTTOM w0.089: v1(98.93,66.16) 99.16,65.93 99.19,65.93 99.62,65.5 100.16,65.5 100.89,64.77 103.15,64.77 103.28,64.63 CPU1.BB50
  BOTTOM w0.152: v1(69.94,53.51) 69.68,53.77 69.68,54.3 69.86,54.48 DM1.133
M_A_A2: length 52.2
  TOP w0.152: v2(67.01,53.86) v1(67.01,53.28)
  L3 w0.089: v1(98.14,66.26) 98.14,65.97 97.97,65.8 94.53,65.8 94.16,65.44 93.39,65.44 93.28,65.56 93,65.56
  L3 w0.203: 93,65.56 86.68,65.56 82.79,61.67 82.2,61.67 81.05,60.52 80.19,60.52 79.16,59.49 79.16,59.15 76.41,56.4 75.33,56.4 73.98,55.05 73.09,55.05 72.37,54.32 68.96,54.32 68.88,54.25 67.29,54.25 67.01,53.97 v1(67.01,53.28)
  BOTTOM w0.089: CPU1.AY51 104.69,65.03 104.54,64.91 103.91,64.91 103.71,64.85 103.51,64.85 103.36,64.9 103.27,64.9 103.08,65.08 101.87,65.08 101.85,65.07 100.89,65.07 100.28,65.68 99.7,65.68 99.34,66.03 99.34,66.5 99.14,66.69 98.34,66.69 98.14,66.5 v1(98.14,66.26)
  BOTTOM w0.152: DM1.132 64.15,54.73 64.15,54.73 65.62,54.73 66.02,54.34 66.23,54.34 66.93,55.03 67.14,55.03 67.36,54.82 67.36,54.6 66.66,53.9 66.66,53.69 67.01,53.34 v1(67.01,53.28)
M_A_A3: length 50.7
  TOP w0.152: v2(68.4,53.92) v1(68.4,53.34)
  L3 w0.089: v1(100,65.09) 101.13,66.22 101.13,66.36 100.95,66.54 100.8,66.54 99.98,65.72 99.79,65.72 99.5,65.43 94.88,65.43 93.99,64.54 92.75,64.54
  L3 w0.203: 92.75,64.54 87.11,64.54 83.02,60.46 82.57,60.46 80.65,58.54 80.12,58.54 76.97,55.38 75.75,55.38 74.4,54.03 73.52,54.03 72.79,53.31 70.53,53.31 70.12,52.89 68.85,52.89 v1(68.4,53.34)
  BOTTOM w0.089: CPU1.BA50 103.68,64.37 103.11,64.37 102.89,64.59 100.5,64.59 v1(100,65.09)
  BOTTOM w0.152: v1(68.4,53.34) 68.09,53.65 68.09,54.34 68.74,54.98 DM1.131
M_A_A4: length 51.4
  TOP w0.152: v2(66.07,55.17) v1(66.07,55.73)
  L3 w0.102: v1(97.84,67.28) 97.84,67.06 97.59,66.81 95.21,66.81
  L3 w0.203: 95.21,66.81 94.94,67.08 86.05,67.08 82.74,63.77 81.91,63.77 81.2,63.07 79.92,63.07 79.52,62.67 79.52,62.09 77.98,60.55 77.66,60.55 77.53,60.42 77.51,60.42 77.09,59.99 76.74,59.99 76.46,59.71 76.46,59.01 75.39,57.94 74.71,57.94 74.1,57.33 73.22,57.33 71.74,55.85 69.09,55.85 68.29,56.64 64.87,56.64 64.67,56.44 64.67,55.88 64.87,55.68 66.02,55.68 v1(66.07,55.73)
  BOTTOM w0.089: CPU1.BB52 101.2,65.96 99.4,67.76 97.66,67.76 97.53,67.63 97.53,67.5 97.76,67.28 v1(97.84,67.28)
  BOTTOM w0.152: v1(66.07,55.73) 66.01,55.73 66.01,55.73 64.31,55.73 64.31,55.73 DM1.128
M_A_A5: length 51.4
  TOP w0.152: v2(67.49,56.28) 67.57,56.2 v1(67.57,55.72)
  L3 w0.089: v1(96.75,66.26) 96.75,66.45 96.58,66.62 95.94,66.62 95.84,66.52 94.5,66.52
  L3 w0.203: v1(67.57,55.72) 67.57,55.45 67.76,55.26 68.43,55.26 68.5,55.34 71.95,55.34 73.43,56.82 74.32,56.82 74.91,57.41 75.99,57.41 76.36,57.78 76.36,58.07 76.94,58.65 77.22,58.65 77.69,59.11 77.69,59.76 77.97,60.04 78.19,60.04 80.03,61.88 80.03,62.28 80.31,62.56 81.47,62.56 82.14,63.23 82.92,63.23 86.26,66.57 94.45,66.57 94.5,66.52
  BOTTOM w0.089: v1(96.75,66.26) 96.54,66.46 96.54,66.77 96.64,66.86 96.73,66.86 96.74,66.87 98.63,66.87 98.64,66.89 98.66,66.89 98.97,67.2 99.37,67.2 99.73,66.84 99.73,66.61 99.52,66.4 99.52,66.4 99.52,66.11 99.77,65.85 100.35,65.85 100.95,65.26 103.21,65.26 103.39,65.08 103.54,65.03 103.68,65.03 103.88,65.09 103.97,65.09 CPU1.BA51
  BOTTOM w0.152: v1(67.57,55.72) 67.57,56.05 67.76,56.25 67.76,56.54 67.26,57.04 66.97,57.04 66.17,56.23 DM1.126
M_A_A6: length 50.1
  TOP w0.152: v2(68.73,56.35) v1(69.29,56.35)
  L3 w0.203: v1(69.29,56.35) 69.31,56.38 69.31,56.45 69.72,56.86 71.26,56.86 75.92,61.52 76.87,61.52 79.46,64.11 80.77,64.11 82.12,65.46 82.12,66.23 83.99,68.1 96.34,68.1 96.57,67.87 v1(96.57,67.25)
  BOTTOM w0.089: CPU1.BA52 103.66,66.23 101.23,66.23 99.53,67.94 96.44,67.94 96.24,67.73 96.24,67.5 96.48,67.25 v1(96.57,67.25)
  BOTTOM w0.152: DM1.127 71.03,55.98 70.74,55.7 68.92,55.7 68.12,56.49 68.12,57.08 68.22,57.18 69.19,57.18 69.29,57.08 v1(69.29,56.35)
M_A_A7: length 53
  TOP w0.152: v2(65.64,57.83) v1(65.64,57.27)
  L3 w0.203: v1(98.5,67.28) 97.95,67.82 97.09,67.82 96.45,68.46 95.3,68.46 95.22,68.53 95.15,68.6 83.04,68.6 82.61,68.17 82.61,67.43 81.62,66.44 81.62,65.67 80.56,64.62 79.19,64.62 77.2,62.63 76.31,62.63 71.05,57.37 69.51,57.37 69.29,57.15 67.11,57.15 66.83,57.43 66.83,57.45 66.55,57.73 66.53,57.73 65.93,58.33 64.63,58.33 64.43,58.14 64.43,57.46 64.64,57.26 65.63,57.26 v1(65.64,57.27)
  BOTTOM w0.089: v1(98.5,67.28) 98.5,67.3 98.78,67.58 99.33,67.58 99.71,67.2 101.24,65.68 104.16,65.68 104.48,65.57 104.95,65.57 CPU1.AW52
  BOTTOM w0.152: v1(65.64,57.27) 65.6,57.23 DM1.122
M_A_A8: length 50.9
  TOP w0.152: v1(95.93,67.25) 95.5,67.25 v2(95.35,67.4)
  L3 w0.203: v1(95.93,67.25) 95.93,67.43 95.78,67.59 85.84,67.59 85.48,67.23 85.19,67.23 84.83,67.59 84.55,67.59 84.26,67.3 84.26,67.01 84.62,66.65 84.62,66.37 84.33,66.08 84.05,66.08 83.51,66.61 83.22,66.61 82.94,66.32 82.94,66.04 83.09,65.89 83.09,65.88 83.47,65.5 83.47,65.22 83.13,64.87 82.25,64.87 80.98,63.6 79.67,63.6 77.78,61.71 77.78,61.39 77.32,60.93 76.1,60.93 75.51,60.34 75.51,60.05 75.95,59.61 75.95,59.3 75.68,59.02 75.39,59.02 74.94,59.48 74.65,59.48 74.26,59.08 74.26,58.8 74.41,58.64 74.41,58.36 74.12,58.06 73.84,58.06 73.68,58.22 73.4,58.22 71.53,56.35 70.58,56.35 v1(70.56,56.38)
  BOTTOM w0.089: v1(95.93,67.25) 94.93,67.25 94.72,67.45 94.72,67.91 94.93,68.11 99.6,68.11 101.3,66.41 104,66.41 104.22,66.19 104.23,66.19 104.55,65.86 CPU1.AY52
  BOTTOM w0.152: v1(70.56,56.38) 70.66,56.48 DM1.125
M_A_A9: length 49.9
  TOP w0.152: v2(68.58,58.26) v1(68.58,57.7)
  L3 w0.203: v1(97.15,69.27) 96.7,68.83 95.34,68.83 95.06,69.11 82.8,69.11 82.1,68.41 82.1,67.64 81.74,67.28 81.45,67.28 81.35,67.39 81.06,67.39 80.77,67.1 80.77,66.81 80.88,66.71 80.88,65.65 80.35,65.12 78.98,65.12 76.99,63.14 76.1,63.14 70.87,57.9 68.86,57.9 68.65,57.7 v1(68.58,57.7)
  BOTTOM w0.089: v1(97.15,69.27) 97.06,69.27 96.78,69 96.78,68.62 96.91,68.5 97.15,68.5 97.46,68.81 97.78,68.81 98.09,68.5 99.73,68.5 101.24,66.99 CPU1.BB54
  BOTTOM w0.152: DM1.121 69.95,57.48 68.55,58.88 68.38,58.88 67.96,58.46 67.96,58.28 68.4,57.84 68.4,57.83 68.53,57.7 v1(68.58,57.7)
M_A_A10: length 51
  TOP w0.152: v2(68.58,48.91) 68.25,48.91 v1(68.04,48.71)
  L3 w0.089: 95.5,61.43 95.64,61.57 102.82,61.57 104.69,63.44 106.03,63.44 v1(106.74,64.15)
  L3 w0.203: v1(68.04,48.71) 68.05,48.7 68.08,48.74 75.99,48.74 77.35,50.1 78.38,50.1 79.88,51.6 79.88,52.07 80.74,52.93 81.22,52.93 82.16,53.87 82.65,53.87 88.97,60.18 94.25,60.18 95.5,61.43
  BOTTOM w0.152: DM1.146 64.15,49.23 64.18,49.21 67.55,49.21 v1(68.04,48.71) ; CPU1.AT50 107.05,64.46 v1(106.74,64.15)
M_A_A11: length 51.2
  TOP w0.152: v2(67.31,58.28) v1(67.31,57.7)
  L3 w0.203: v1(67.31,57.7) 67.01,58 67.01,59.47 67.22,59.68 67.81,59.68 67.94,59.55 67.94,58.54 68.07,58.41 70.66,58.41 75.89,63.65 76.6,63.65 79.13,66.18 79.14,66.18 79.15,66.17 79.74,66.17 80.26,66.7 80.26,67.31 80.3,67.35 81.31,68.36 81.31,69.04 81.89,69.62 95.06,69.62 95.4,69.27 v1(96.51,69.27)
  BOTTOM w0.089: CPU1.BA54 103.68,66.73 101.25,66.73 99.66,68.32 96.8,68.32 96.51,68.61 v1(96.51,69.27)
  BOTTOM w0.152: DM1.120 64.15,57.73 67.22,57.73 67.26,57.7 v1(67.31,57.7)
M_A_A12: length 51
  TOP w0.152: v1(69.82,58.89) 69.82,59.07 v2(70.13,59.38)
  L3 w0.089: v1(98.43,69.26) 98.43,69.5 98.24,69.69 95.59,69.69
  L3 w0.203: 95.59,69.69 95.44,69.69 95,70.13 81.57,70.13 80.8,69.36 80.8,68.57 79.76,67.52 79.76,67.02 79.47,66.73 78.97,66.73 78.45,66.22 77.32,66.22 76.91,65.8 76.91,64.68 76.39,64.16 75.68,64.16 71.67,60.14 68.72,60.14 68.51,59.94 68.51,59.58 68.72,59.38 69.62,59.38 69.82,59.17 v1(69.82,58.89)
  BOTTOM w0.089: CPU1.AW54 105.24,66.87 105.1,66.73 104.49,66.73 104.27,66.95 104.27,67.12 104.19,67.2 104.02,67.25 103.84,67.25 103.72,67.21 103.47,67.21 103.39,67.25 102.98,67.25 102.91,67.17 101.32,67.17 99.82,68.67 98.29,68.67 98.19,68.77 98.19,69.16 98.29,69.26 v1(98.43,69.26)
  BOTTOM w0.152: v1(69.82,58.89) 69.65,58.72 69.65,58.21 69.87,57.98 DM1.119
M_A_A13: length 53.4
  TOP w0.152: v2(66.98,45.36) v1(66.98,44.77)
  L3 w0.089: v1(105.87,62.09) 105.87,62.01 103.84,59.99 96.32,59.99 95.92,59.59
  L3 w0.203: 95.92,59.59 93.78,57.45 90.03,57.45 82.55,49.97 82.55,48.83 79.05,45.32 75.27,45.32 74.85,45.74 73.73,45.74 73.71,45.76 67.41,45.76 66.98,45.33 v1(66.98,44.77)
  BOTTOM w0.152: CPU1.AU46 105.87,62.29 v1(105.87,62.09) ; v1(66.98,44.77) 66.98,44.82 67.11,44.95 67.11,45.63 66.5,46.23 DM1.158
M_A_A14: length 51.3
  TOP w0.152: v1(70.51,47.39) v2(71.07,47.39)
  L3 w0.089: 96.62,60.95 96.85,60.95 97.11,61.21 103.11,61.21 104.92,63.03 106.55,63.03 106.7,63.18 107.41,63.18 107.6,62.98 107.6,62.64 v1(107.34,62.37)
  L3 w0.203: 96.62,60.95 96,60.95 94.18,59.12 89.35,59.12 83.07,52.85 82.58,52.85 81.43,51.7 81.43,51.54 80.47,50.58 80.47,50.29 80.96,49.81 80.96,49.52 80.67,49.23 80.38,49.23 79.9,49.72 79.61,49.72 79.32,49.43 79.32,49.14 79.84,48.63 79.84,48.37 79.52,48.05 79.27,48.05 78.75,48.57 77.33,48.57 76.49,47.72 75.99,47.72 75.41,47.72 74.96,47.27 74.37,47.27 74.35,47.29 72.93,47.29 72.49,47.72 70.85,47.72 v1(70.51,47.39)
  BOTTOM w0.152: v1(70.51,47.39) 71.11,47.98 DM1.151 ; v1(107.34,62.37) 107.05,62.66 CPU1.AT46
M_A_A15: length 52.1
  TOP w0.152: v2(67.33,49.27) v1(67.33,48.71)
  L3 w0.089: v1(106.09,64.18) 105.97,64.3 105.65,64.3 105.12,63.76 104.71,63.76 102.7,61.76 96.78,61.76 96.7,61.84
  L3 w0.203: v1(67.33,48.71) 67.91,49.29 75.82,49.29 77.16,50.62 78.01,50.62 78.83,51.44 78.83,52.03 80.24,53.44 80.99,53.44 81.97,54.42 81.97,54.58 82.22,54.83 82.9,54.83 88.79,60.72 94.24,60.72 95.35,61.84 96.7,61.84
  BOTTOM w0.152: v1(106.09,64.18) 106.09,64.02 106.37,63.74 CPU1.AU48 ; v1(67.33,48.71) 67.55,48.49 67.55,48.11 66.83,47.38 66.83,47.07 66.49,46.73 64.15,46.73 64.15,46.73 DM1.156
M_A_A16: length 52.8
  TOP w0.152: v2(65.86,47.79) 65.86,47.77 v1(66.37,47.26)
  L3 w0.089: 97.74,62.98 99.68,62.98 101.9,63.27 102.29,63.39 102.5,63.39 102.89,63.56 104.75,65.09 105.37,65.53 105.45,65.62 105.53,65.66 105.58,65.68 v1(105.99,65.9)
  L3 w0.203: 97.74,62.98 97.51,62.76 94.63,62.76 94.43,62.56 93.72,62.31 88.03,62.31 82.1,56.38 81.02,56.38 77.29,52.65 77.06,52.65 75.45,52.03 74.84,51.41 73.95,51.41 73.68,51.15 72.59,51.15 72.28,50.83 71.92,50.65 71.41,50.51 67.68,50.51 66.11,48.94 66.11,48.45 v1(66.37,47.26)
  BOTTOM w0.152: v1(105.99,65.9) 105.99,65.45 106.15,65.12 CPU1.AU50 ; DM1.152 64.15,47.73 64.15,47.73 65.89,47.73 v1(66.37,47.26)
M_A_ACT_N: length 49.9
  TOP w0.152: v1(67.49,60.47) 67.46,60.44 v2(67.46,59.91)
  L3 w0.203: v1(96.66,70.77) 96.4,70.77 95.01,72.16 80.29,72.16 72.08,63.95 68.66,63.95 67.56,62.85 67.56,60.54 v1(67.49,60.47)
  BOTTOM w0.089: CPU1.BA55 103.98,67.86 103.88,67.86 103.69,67.91 103.52,67.91 103.39,67.87 102.65,67.87 102.54,67.76 101.76,67.76 99.59,69.92 97.12,69.92 96.66,70.38 v1(96.66,70.77)
  BOTTOM w0.152: v1(67.49,60.47) 66.32,59.31 65.6,59.31 65.53,59.23 DM1.114
M_A_ALERT_N: length 66.5
  TOP w0.152: v1(65.79,58.85) 65.79,58.95 v2(66.14,59.3)
  L3 w0.089: v1(105.74,64.71) 105.79,64.76 106.54,64.76 106.59,64.7 109.54,64.7 109.76,64.93 109.76,67.09 109.5,67.35 108.02,67.35 107.41,67.96
  L3 w0.203: v1(65.79,58.85) 64.55,60.09 64.55,63.79 65.73,64.96 71.64,64.96 79.85,73.18 94.94,73.18 95.98,72.13 102.62,72.13 106.78,67.96 107.41,67.96
  BOTTOM w0.152: v1(105.74,64.71) 105.73,64.69 CPU1.AW50 ; DM1.116 64.26,58.73 65.68,58.73 v1(65.79,58.85)
M_A_BA0: length 51.7
  TOP w0.152: v2(66.11,49.09) 66.22,49.09 v1(66.6,48.71)
  L3 w0.089: v1(106.71,65.17) 106.69,65.15 105.57,65.15 105.05,64.63 104.8,64.63 104.44,64.27 104.44,64.02 102.36,61.94 97.44,61.94 97.21,62.16
  L3 w0.203: 97.21,62.16 95.21,62.16 94.32,61.26 88.42,61.26 82.5,55.35 81.43,55.35 78.32,52.24 78.32,51.65 77.8,51.13 76.94,51.13 76.42,50.6 76.42,50.6 75.61,49.8 67.69,49.8 v1(66.6,48.71)
  BOTTOM w0.152: v1(106.71,65.17) 106.4,65.48 CPU1.AU52 ; v1(66.6,48.71) 66.12,48.23 DM1.150
M_A_BA1: length 53.3
  TOP w0.152: v2(68.3,47.69) 67.97,47.36 v1(67.97,47.21)
  L3 w0.089: v1(107.38,64.14) 106.47,63.23 104.88,63.23 103.04,61.39 96.83,61.39 96.7,61.26
  L3 w0.203: 96.7,61.26 95.81,61.26 94.21,59.66 89.17,59.66 82.86,53.36 82.37,53.36 81.43,52.42 80.95,52.42 80.39,51.86 80.39,51.39 78.59,49.59 77.56,49.59 76.2,48.23 68.94,48.23 67.97,47.26 v1(67.97,47.21)
  BOTTOM w0.152: CPU1.AT48 107.05,63.81 v1(107.38,64.14) ; DM1.145 69.5,49.48 67.97,47.95 v1(67.97,47.21)
M_A_BG0: length 50.6
  TOP w0.152: v1(68.22,60.39) 68.22,60.88 v2(68.15,60.95)
  L3 w0.203: v1(97.3,70.77) 97.3,70.58 97.04,70.33 96.36,70.33 95.04,71.65 80.5,71.65 72.29,63.44 68.87,63.44 68.22,62.79 v1(68.22,60.39)
  BOTTOM w0.089: CPU1.AY55 104.62,68.04 103.91,68.04 103.71,68.09 103.5,68.09 103.37,68.05 102.55,68.05 102.44,67.94 101.83,67.94 99.64,70.13 97.54,70.13 97.3,70.36 v1(97.3,70.77)
  BOTTOM w0.152: v1(68.22,60.39) 68.22,59.76 68.48,59.5 69.44,59.5 69.57,59.38 70.69,59.38 71.08,58.98 DM1.115
M_A_BG1: length 52.2
  TOP w0.152: v2(69.31,60.6) 68.76,61.15 v1(68.76,61.41)
  L3 w0.089: v1(99.06,69.26) 99.47,68.86 100.16,68.86 100.37,69.07 100.37,69.73 100.23,69.87 95.78,69.87 95.53,70.12
  L3 w0.203: 95.53,70.12 95.01,70.64 81.36,70.64 78.97,68.25 78.97,67.46 78.28,66.76 77.12,66.76 76.4,66.05 76.4,64.89 76.18,64.66 75.43,64.66 71.41,60.65 69.04,60.65 68.76,60.93 v1(68.76,61.41)
  BOTTOM w0.089: v1(99.06,69.26) 99.06,69.03 99.25,68.85 99.97,68.85 101.47,67.35 102.76,67.35 102.83,67.42 103.43,67.42 103.51,67.39 103.69,67.39 103.82,67.42 104.04,67.42 104.18,67.39 104.29,67.39 104.59,67.09 CPU1.AY54
  BOTTOM w0.152: v1(68.76,61.41) 68.76,60.84 69.94,59.66 71.09,59.66 71.26,59.48 DM1.113
M_A_CKE0: length 50.5
  TOP w0.152: v1(70.05,61.13) 69.95,61.23 v2(69.95,61.68)
  L3 w0.089: v1(99.21,70.77) 99.23,70.75 100.86,70.75 101.04,70.57 101.04,70.35 100.78,70.09 96.06,70.09 95.85,70.3
  L3 w0.203: 95.85,70.3 95.01,71.14 80.78,71.14 80.23,70.6 80.23,70.23 78.75,68.75 78.38,68.75 77.94,68.31 77.94,67.83 77.39,67.28 76.91,67.28 75.22,65.58 75.22,65.17 72.98,62.93 72.16,62.93 71.93,62.7 71.93,61.88 71.73,61.68 71.48,61.68 70.74,62.42 69.37,62.42 69.12,62.17 69.12,61.89 69.34,61.66 69.65,61.66 70.05,61.26 v1(70.05,61.13)
  BOTTOM w0.089: CPU1.BA56 103.41,68.57 103.13,68.57 103.12,68.56 103.09,68.56 103.02,68.48 102.72,68.47 102.46,68.47 102.36,68.37 101.9,68.37 101.7,68.58 99.5,70.77 v1(99.21,70.77)
  BOTTOM w0.152: v1(70.05,61.13) 70.7,60.48 DM1.109
M_A_CKE1: length 50.7
  TOP w0.152: v1(66.06,60.51) 66.06,60.61 v2(66.42,60.98)
  L3 w0.203: v1(66.06,60.51) 65.06,61.51 65.06,63.58 65.94,64.45 71.86,64.45 80.08,72.67 94.92,72.67 96.07,71.52 98.35,71.52 98.58,71.29 v1(98.58,70.77)
  BOTTOM w0.089: CPU1.BB56 103.21,68.24 102.49,68.24 102.36,68.11 101.91,68.11 99.64,70.38 98.95,70.38 98.58,70.76 v1(98.58,70.77)
  BOTTOM w0.152: v1(66.06,60.51) 65.78,60.23 DM1.110
M_A_CLK0: length 52.2
  TOP w0.102: v2(69.77,51.65) 69.6,51.48 v1(69.6,51.12)
  L3 w0.089: 103.13,65.96 103.17,65.92 105.07,65.92 105.64,66.49 106.32,66.49 106.4,66.41 106.93,66.41 v1(107.34,66.01)
  L3 w0.14: v1(69.6,51.12) 70.21,51.51 70.34,51.53 70.66,51.53 71.1,51.97 73.35,51.97 73.61,52.23 74.5,52.23 75.74,53.47 76.95,53.47 80.68,57.2 81.76,57.2 87.71,63.14 94.22,63.14 95.13,64.06 97.91,64.06 98.36,63.61 100.19,63.61 101.2,64.62 101.62,64.62 102.25,64 102.48,64 102.64,64.16 102.64,64.39 102.02,65.02 102.02,65.43 102.54,65.96 103.13,65.96
  BOTTOM w0.102: v1(69.6,51.12) 69.71,51.22 69.71,52.06 69.8,52.15 69.8,52.64 70.51,53.35 71.19,53.35 71.33,53.48 DM1.137 ; CPU1.AT53 v1(107.34,66.01)
M_A_CLK1: length 52.6
  TOP w0.102: v1(67.92,51.1) 68.27,51.45 v2(68.27,51.53)
  L3 w0.089: v1(107.34,66.95) 106.89,66.62 106.86,66.6 106.54,66.6 106.47,66.67 105.37,66.67 105.33,66.72 104.26,66.72 104.11,66.56 103.72,66.56 103.68,66.51
  L3 w0.14: 103.68,66.51 102.46,66.51 100.23,64.28 94.67,64.28 94.06,63.67 87.4,63.67 83.36,59.64 82.91,59.64 80.99,57.72 80.46,57.72 77.31,54.56 76.09,54.56 74.74,53.21 73.86,53.21 73.13,52.49 70.88,52.49 70.46,52.06 68.55,52.06 67.92,51.43 v1(67.92,51.1)
  BOTTOM w0.102: v1(67.92,51.1) 67.74,51.27 67.74,51.81 66.85,52.7 65.86,52.7 65.46,53.1 65.16,53.1 65.02,53.23 DM1.138 ; CPU1.AT55 v1(107.34,66.95)
M_A_CLK#0: length 52.2
  TOP w0.102: v2(70.94,51.09) 70.93,51.08 v1(70.37,51.08)
  L3 w0.089: 103.13,65.69 103.17,65.73 105.15,65.73 105.72,66.3 106.23,66.3 106.35,66.18 106.5,66.18 v1(106.68,66.01)
  L3 w0.14: v1(70.37,51.08) 70.59,51.08 71.21,51.7 73.46,51.7 73.72,51.97 74.61,51.97 75.85,53.2 77.06,53.2 80.79,56.93 81.87,56.93 87.82,62.88 94.33,62.88 95.24,63.79 97.8,63.79 98.25,63.34 100.3,63.34 101.31,64.35 101.51,64.35 102.13,63.73 102.59,63.73 102.91,64.05 102.91,64.5 102.28,65.13 102.28,65.32 102.65,65.69 103.13,65.69
  BOTTOM w0.102: CPU1.AU53 106.4,66.1 106.5,66.01 v1(106.68,66.01) ; DM1.139 71.33,52.98 71.19,53.12 70.6,53.12 70.03,52.54 70.03,51.77 70.15,51.64 71.12,51.64 71.27,51.49 71.27,51.23 71.12,51.08 v1(70.37,51.08)
M_A_CLK#1: length 52.6
  TOP w0.102: v1(67.21,51.1) 66.8,51.5 v2(66.77,51.5)
  L3 w0.089: 103.68,66.78 103.71,66.75 104.03,66.75 104.18,66.91 105.41,66.91 105.45,66.86 106.58,66.86 v1(106.7,66.99)
  L3 w0.14: 103.68,66.78 102.35,66.78 100.12,64.55 94.56,64.55 93.95,63.94 87.29,63.94 83.25,59.9 82.8,59.9 80.88,57.98 80.35,57.98 77.2,54.83 75.98,54.83 74.63,53.48 73.74,53.48 73.02,52.75 70.77,52.75 70.34,52.33 68.44,52.33 67.91,51.79 67.4,51.79 67.23,51.63 67.23,51.12 v1(67.21,51.1)
  BOTTOM w0.102: v1(67.21,51.1) 67.51,51.4 67.51,51.71 66.76,52.47 65.77,52.47 65.36,52.87 65.11,52.87 64.97,52.73 DM1.140 ; CPU1.AU55 106.4,67.12 106.53,66.99 v1(106.7,66.99)
M_A_CS#0: length 55.6
  TOP w0.152: v1(69.24,47.24) 69.24,47.46 v2(69.52,47.74)
  L3 w0.089: 96.9,60.65 97.28,61.02 102.9,61.02 103,60.92 103,60.54 103.1,60.43 103.39,60.43 103.5,60.54 103.5,60.76 103.6,60.86 104.09,60.86 104.19,60.96 104.19,61.19 104.09,61.29 103.92,61.29 103.82,61.39 103.82,61.67 104.83,62.68 106.37,62.68 v1(106.68,62.37)
  L3 w0.203: v1(69.24,47.24) 69.24,46.98 69.44,46.78 70.72,46.78 71.16,47.22 72.25,47.22 72.69,46.78 74.14,46.78 74.15,46.76 75.96,46.76 76.29,46.43 76.99,46.43 77.19,46.63 77.19,47.24 77.39,47.45 77.8,47.45 78,47.24 78,46.63 78.21,46.43 78.71,46.43 81.53,49.25 81.53,49.82 81.53,50.92 81.71,51.1 82.2,51.1 82.48,51.38 82.48,52.03 82.79,52.34 83.29,52.34 89.5,58.56 94.04,58.56 96.02,60.54 96.13,60.54 96.24,60.65 96.9,60.65
  BOTTOM w0.152: DM1.149 70.88,48.48 70.73,48.33 70.73,48.16 70.57,48.01 70.27,48.01 70.12,48.16 70.12,48.33 69.97,48.48 69.51,48.48 69.24,48.22 v1(69.24,47.24) ; CPU1.AU45 106.65,62.17 106.65,62.35 v1(106.68,62.37)
M_A_CS#1: length 56.9
  TOP w0.152: v2(68.28,45.36) v1(68.28,44.78)
  L3 w0.089: 96.24,59.48 96.52,59.76 104.04,59.76 104.24,59.96 106.45,59.96 106.78,60.29 106.78,60.8 v1(106.09,61.48)
  L3 w0.203: v1(68.28,44.78) 68.28,45.05 68.48,45.25 72.84,45.25 73.63,44.46 73.63,44.44 73.92,44.16 73.98,44.16 73.99,44.15 75.24,44.15 75.44,44.36 75.44,44.61 75.65,44.82 76.05,44.82 76.25,44.61 76.25,44.36 76.46,44.15 76.86,44.15 77.07,44.36 77.07,44.61 77.27,44.82 77.68,44.82 77.88,44.61 77.88,44.36 78.08,44.15 78.59,44.15 83.06,48.62 83.06,49.61 90.38,56.94 93.7,56.94 96.24,59.48
  BOTTOM w0.152: v1(68.28,44.78) 68.1,44.97 68.1,44.99 67.69,45.39 67.69,45.89 67.97,46.17 70.79,46.17 71.11,46.48 DM1.157 ; CPU1.AU43 106.4,61.09 106.09,61.4 v1(106.09,61.48)
M_A_DIMA_ODT0: length 55.7
  TOP w0.152: v2(67.08,47.72) 67.33,47.46 v1(67.33,47.21)
  L3 w0.089: 96.92,60.24 96.95,60.21 103.81,60.21 104.58,60.98 104.58,61.82 104.6,61.84 104.6,61.87 105.21,62.48 106.03,62.48 106.28,62.23 106.28,62.21 106.73,61.76 v1(106.73,61.51)
  L3 w0.203: 96.92,60.24 96.14,60.24 93.85,57.95 89.82,57.95 82.04,50.18 82.04,49.04 78.85,45.85 75.73,45.85 75.33,46.25 73.94,46.25 73.93,46.27 67.56,46.27 67.33,46.49 v1(67.33,47.21)
  BOTTOM w0.102: v1(106.73,61.51) 106.73,61.59 107.05,61.91 CPU1.AT45
  BOTTOM w0.152: DM1.155 71.21,46.98 70.68,46.45 67.61,46.45 67.33,46.73 v1(67.33,47.21)
M_A_DIMA_ODT1: length 56.3
  TOP w0.152: v2(69.85,45.33) v1(69.85,44.77)
  L3 w0.089: v1(107.39,60.49) 106.83,59.93 106.83,59.48 105.56,58.21 104.32,58.21 102.95,59.58 96.84,59.58 96.59,59.33
  L3 w0.203: 96.59,59.33 93.7,56.43 90.59,56.43 83.57,49.4 83.57,48.41 78.76,43.6 78.08,43.6 77.88,43.39 77.88,42.92 77.69,42.74 77.25,42.74 77.07,42.92 77.07,43.46 76.88,43.64 76.44,43.64 76.25,43.46 76.25,42.97 76.05,42.76 75.64,42.76 75.44,42.97 75.44,43.47 75.26,43.64 74.8,43.64 74.63,43.47 74.63,42.96 74.42,42.75 73.19,42.75 72.83,43.11 72.83,43.4 73.2,43.77 73.2,44.05 72.91,44.34 72.63,44.34 72.26,43.98 71.97,43.98 71.24,44.71 69.91,44.71 v1(69.85,44.77)
  BOTTOM w0.152: DM1.161 71.22,45.48 70.69,44.95 70.45,44.95 70.15,45.25 69.95,45.25 69.85,45.15 v1(69.85,44.77) ; CPU1.AT43 107.05,60.71 107.27,60.49 v1(107.39,60.49)
M_A_DQ0: length 58.9
  TOP w0.089: v2(67.24,86.29) v1(67.24,86.86)
  L3 w0.127: v1(67.24,86.86) 67.24,86.7 67.53,86.41 72.53,86.41 74.95,88.84 82.7,88.84 83.42,89.56 104.23,89.56 110.37,83.41 110.37,80.34 v1(109.7,79.67)
  BOTTOM w0.089: CPU1.AL71 110.32,77.23 110.32,79.48 110.13,79.67 v1(109.7,79.67) ; v1(67.24,86.86) 66.12,85.73 DM1.8
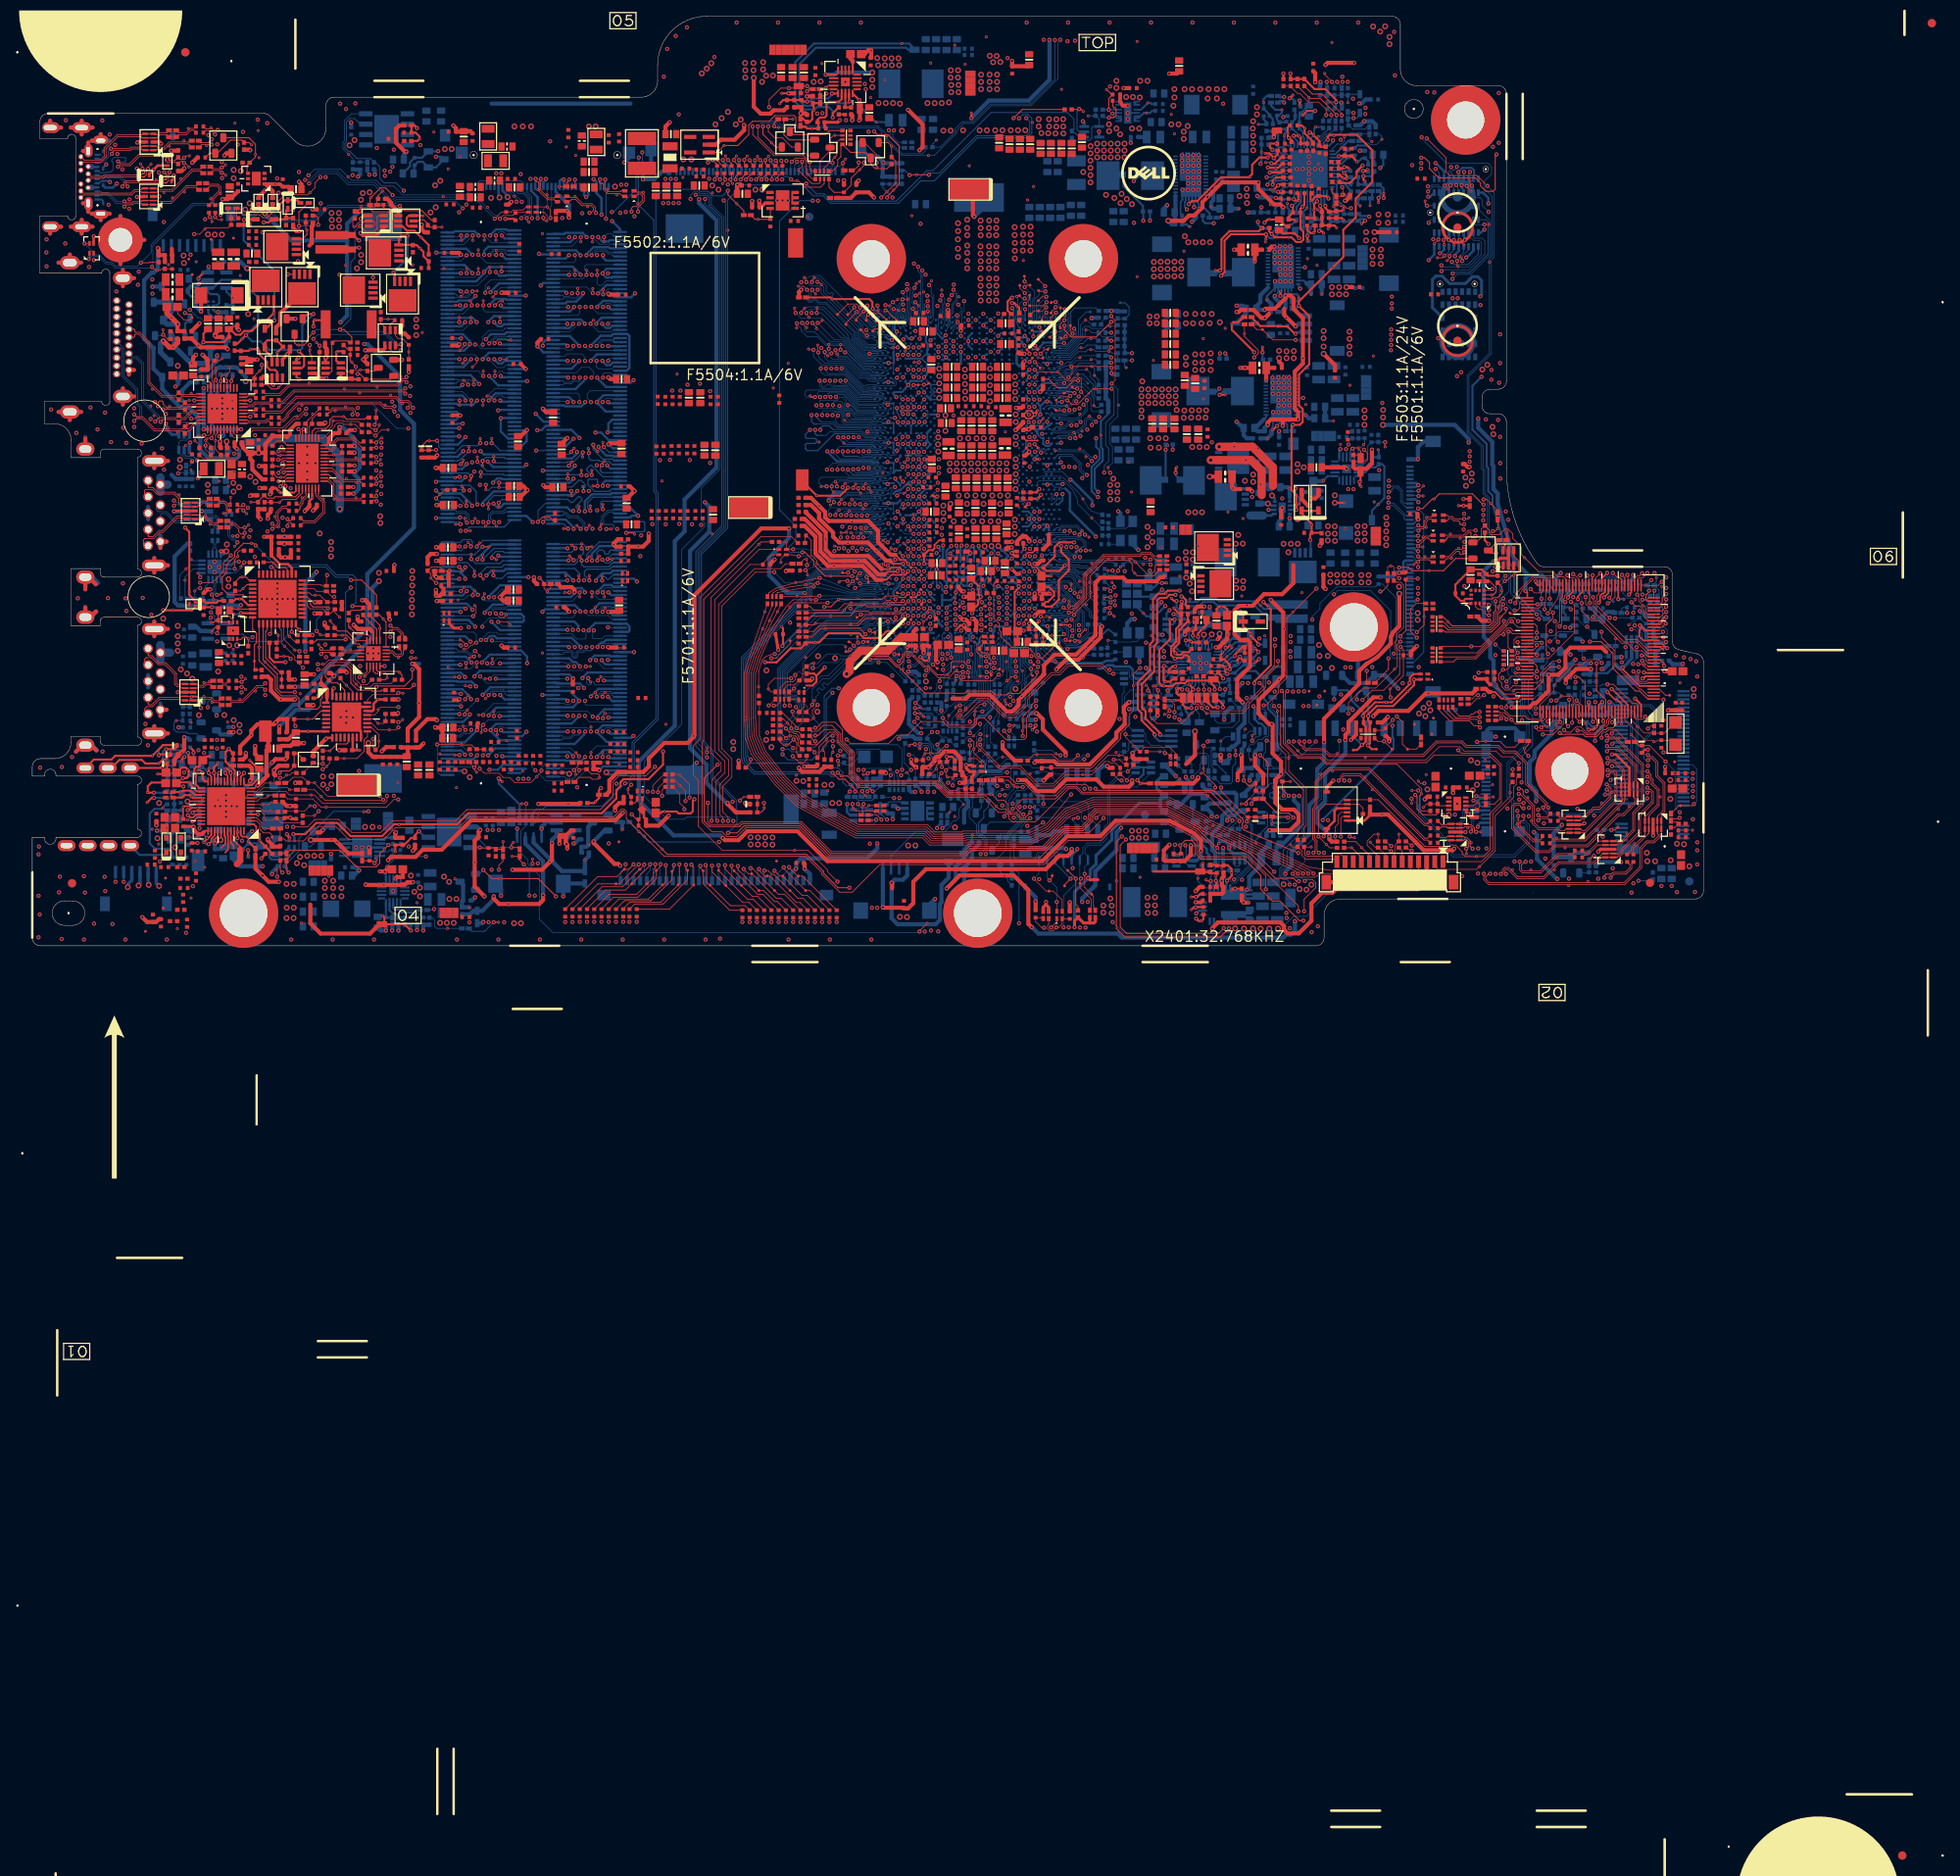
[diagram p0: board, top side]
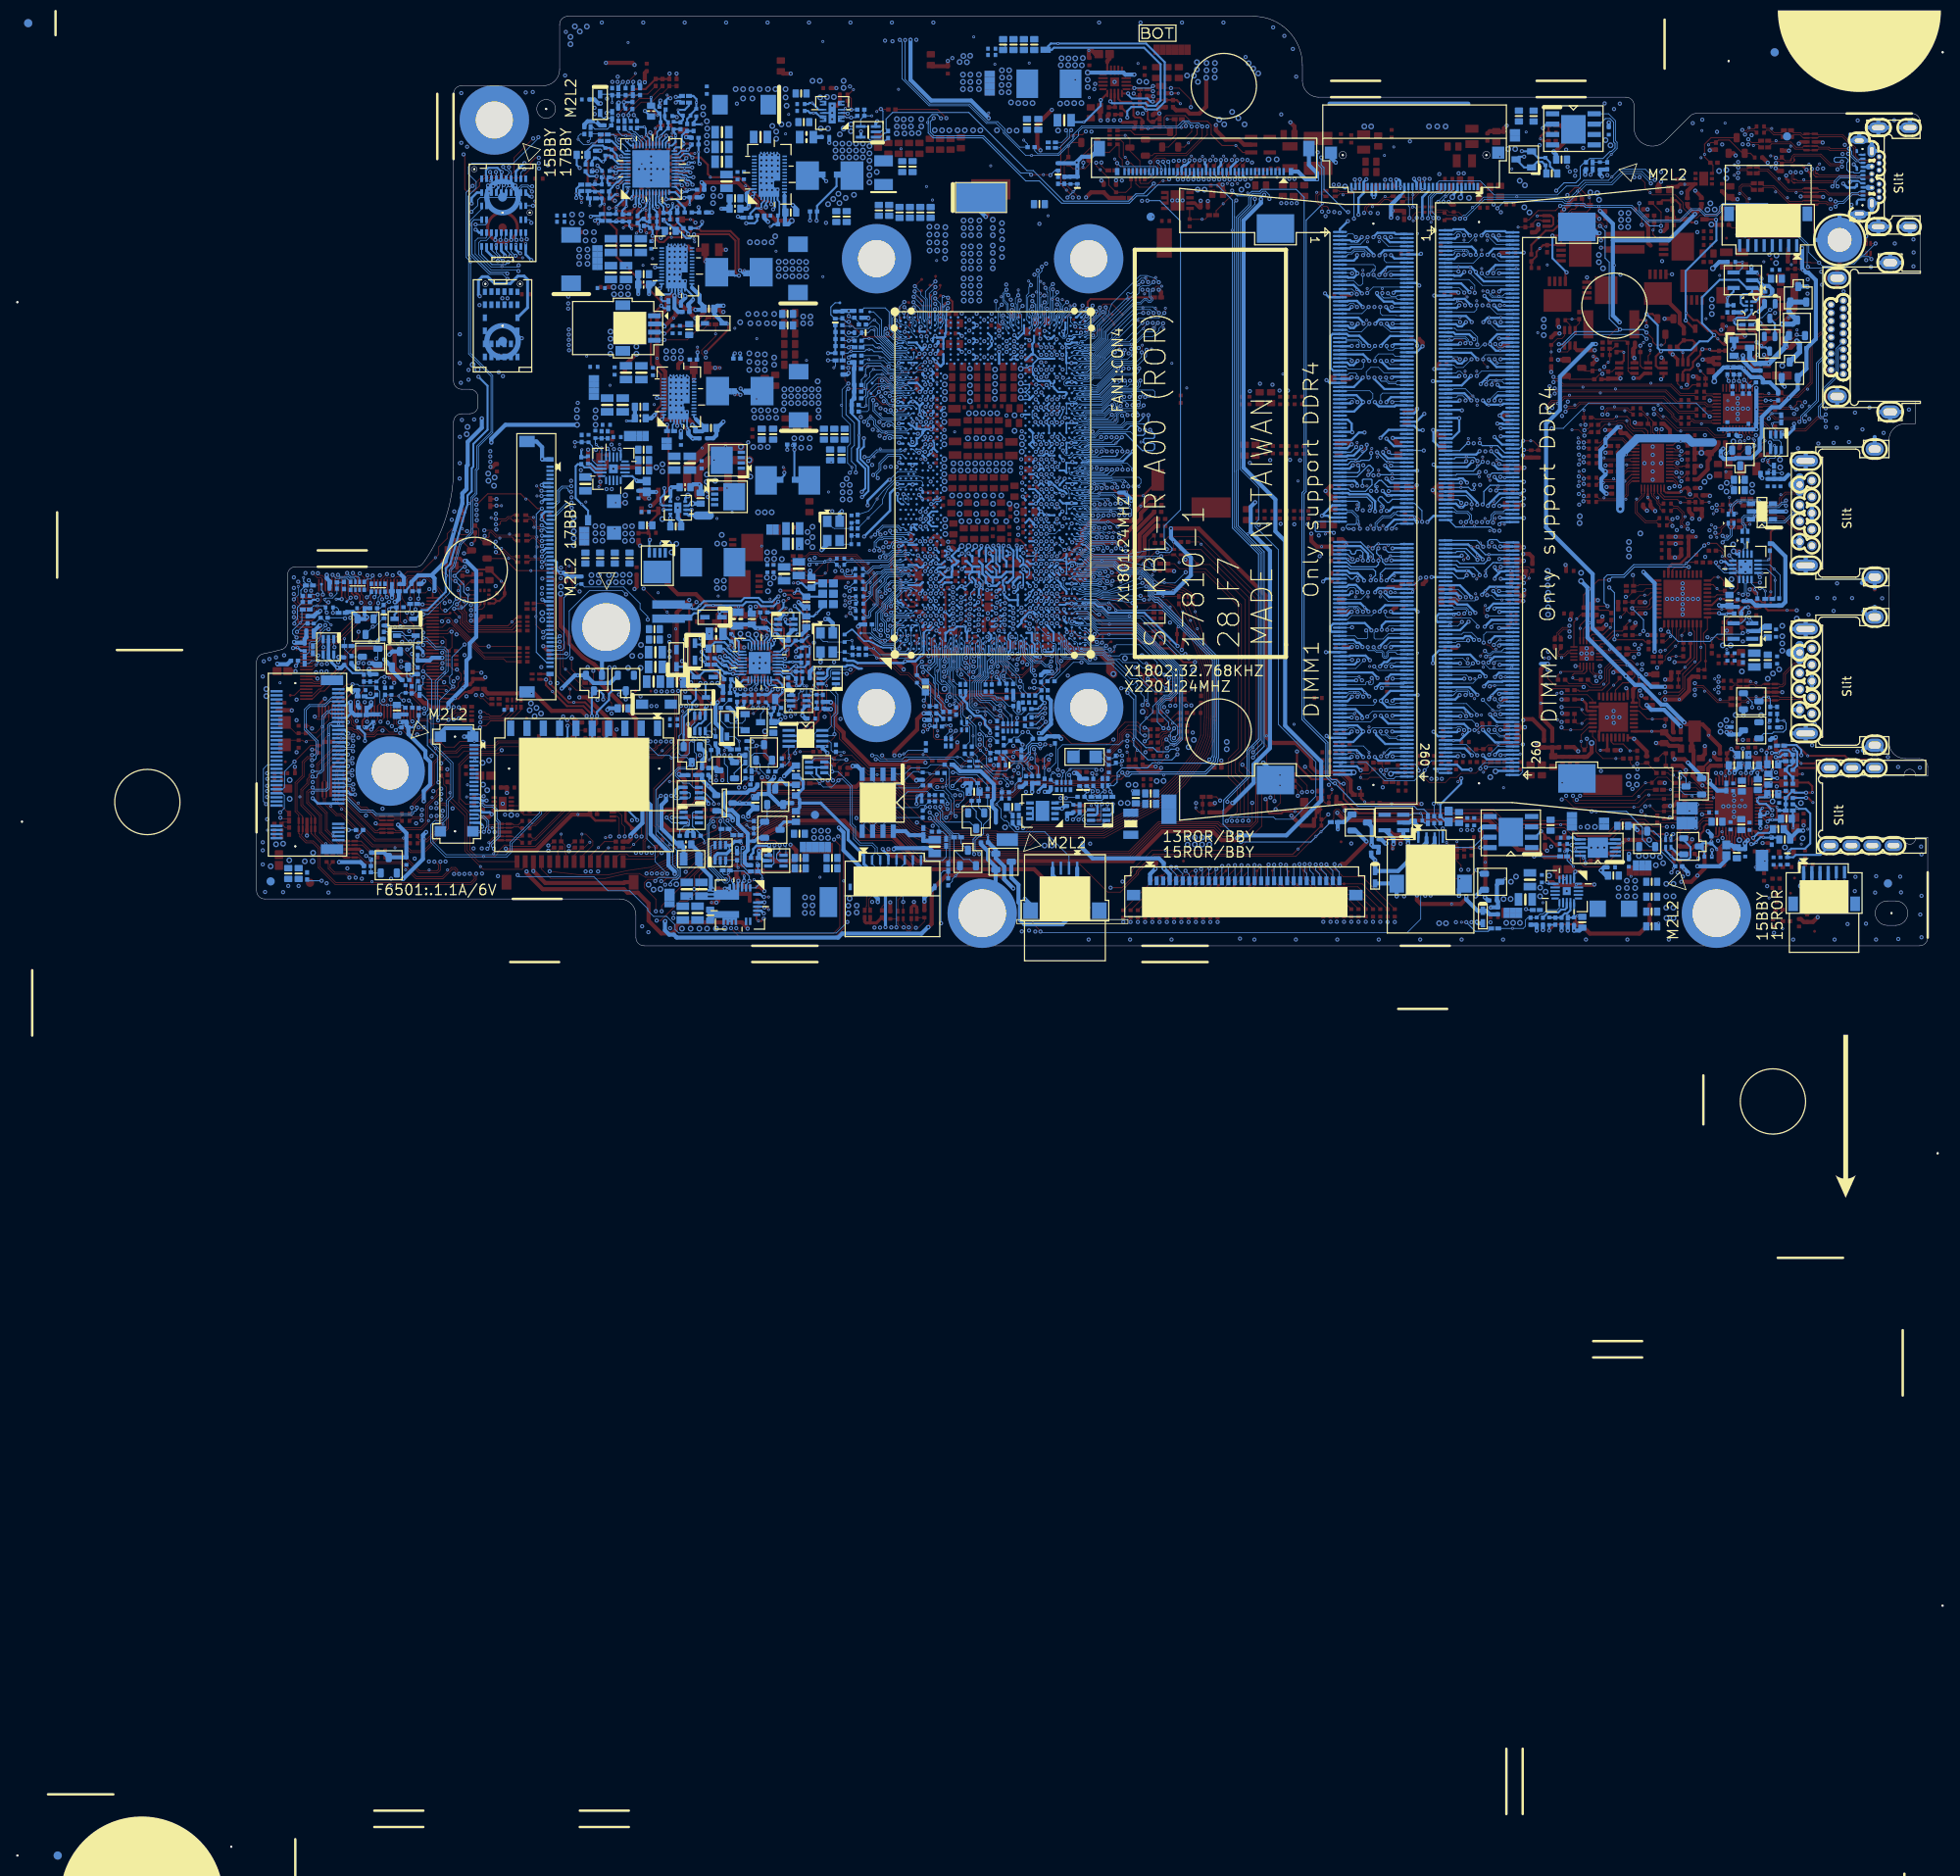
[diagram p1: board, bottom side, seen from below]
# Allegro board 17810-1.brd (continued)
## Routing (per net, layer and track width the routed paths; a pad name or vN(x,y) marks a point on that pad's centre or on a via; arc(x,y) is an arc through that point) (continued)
M_A_DQ1: length 59.7
  TOP w0.089: v2(68.66,86.28) v1(68.66,86.86)
  L3 w0.127: v1(68.66,86.86) 69.05,87.32 73.7,88.67 74.62,89.6 77.85,90.44 104.36,90.44 111.09,83.71 111.09,80.04 110.46,78.46 v1(109.75,77.75)
  BOTTOM w0.089: DM1.7 69.53,85.98 v1(68.66,86.86) ; CPU1.AL68 110.11,75.22 109.73,75.73 109.73,76.07 109.67,76.26 109.67,76.49 109.71,76.6 109.71,76.81 109.67,76.88 109.67,77.25 109.75,77.33 v1(109.75,77.75)
M_A_DQ2: length 60
  TOP w0.089: v2(66.5,82.8) v1(66.5,82.23)
  L3 w0.127: v1(66.5,82.23) 66.5,82.7 67.08,83.28 71.18,83.28 72.39,84.49 73.15,84.49 75.75,87.09 96.66,87.09 96.95,87.37 103.95,87.37 106.15,85.17 107.06,83.43 108.95,81.54 108.95,80.28 108.66,79.48 108.46,79.28 108.01,79.28 107.77,78.92 107.53,78.14 107.53,77.91 107.91,77.35 108.79,76.47 108.79,74.41 v1(108.78,74.41)
  BOTTOM w0.089: v1(108.78,74.41) 108.88,74.51 CPU1.AN68 ; DM1.20 64.23,82.73 65.9,82.73 v1(66.5,82.23)
M_A_DQ3: length 60.1
  TOP w0.089: v2(108.35,81.17) v1(108.15,80.64)
  L3 w0.127: v1(70.56,82.41) 70.58,82.39 71.38,82.39 72.44,83.44 73.25,83.44 76.13,86.32 97.08,86.32 97.47,85.92 97.65,85.92 98.39,86.66 98.61,86.66 98.75,86.52 98.75,86.31 98.01,85.56 98.01,85.38 98.19,85.21 98.37,85.21 99.26,86.09 99.47,86.09 99.62,85.94 99.62,85.73 98.73,84.85 98.73,84.67 98.91,84.49 99.09,84.49 99.85,85.25 100.06,85.25 100.21,85.1 100.21,84.89 99.45,84.13 99.45,83.95 100.43,82.97 100.43,82.06 101.27,81.22 103.96,81.22 104.8,82.07 105.28,82.07 105.41,82.2 105.41,83.02 105.54,83.15 105.79,83.15 105.92,83.02 105.92,82.2 106.05,82.07 107.39,82.07 108.13,81.34 108.13,80.66 v1(108.15,80.64)
  BOTTOM w0.089: CPU1.AN69 108.6,76.12 108.38,76.42 108.31,76.49 108.31,77.29 108.35,77.33 108.35,78.24 107.87,78.72 107.87,79.58 107.88,79.59 107.88,80.04 107.99,80.15 107.99,80.47 v1(108.15,80.64) ; DM1.21 70.63,82.48 v1(70.56,82.41)
M_A_DQ4: length 60.4
  L3 w0.127: v1(65.82,86.86) 66.62,86.06 72.76,86.06 75.17,88.47 84.34,88.47 84.47,88.6 84.47,88.99 84.6,89.12 84.85,89.12 84.98,88.99 84.98,88.6 85.11,88.47 85.46,88.47 85.59,88.6 85.59,89.08 85.72,89.21 85.97,89.21 86.1,89.08 86.1,88.6 86.22,88.47 86.58,88.47 87.31,89.21 104.08,89.21 109.97,83.32 109.97,81 v1(109.93,80.97)
  BOTTOM w0.089: v2(110.21,81.47) 109.93,81.2 v1(109.93,80.97) 110.18,80.71 110.18,80 110.5,79.69 110.5,76.76 CPU1.AL70 ; v1(65.82,86.86) 65.7,86.73 DM1.4
M_A_DQ5: length 60.2
  TOP w0.089: v2(70.08,86.29) v1(70.08,86.86)
  L3 w0.127: v1(109.77,78.39) 110.23,78.85 110.23,79.7 110.73,80.19 110.73,83.56 104.28,90.01 82.7,90.01 81.87,89.19 81.49,89.19 81.37,89.32 81.37,89.63 81.22,89.78 81.01,89.78 80.86,89.63 80.86,89.32 80.73,89.19 80.48,89.19 80.35,89.32 80.35,89.73 80.2,89.88 79.99,89.88 79.84,89.73 79.84,89.32 79.72,89.19 79.46,89.19 79.33,89.32 79.33,89.77 79.21,89.89 78.95,89.89 78.83,89.77 78.83,89.32 78.7,89.19 78.45,89.19 78.32,89.32 78.32,89.75 78.17,89.9 77.96,89.9 77.81,89.75 77.81,89.32 77.68,89.19 74.8,89.19 72.47,86.86 v1(70.08,86.86)
  BOTTOM w0.089: v1(70.08,86.86) 70.52,87.29 71.01,87.29 71.32,86.98 DM1.3 ; CPU1.AL69 109.9,75.93 109.9,76.1 109.85,76.29 109.85,76.47 109.88,76.57 109.88,76.85 109.85,76.92 109.85,77.18 110.14,77.47 110.14,78.01 109.77,78.38 v1(109.77,78.39)
M_A_DQ6: length 58.5
  TOP w0.089: v2(108.63,78.45) 108.25,78.83 v1(108.25,78.88)
  L3 w0.127: v1(108.25,78.88) 108.53,78.88 108.98,79.33 109.31,80.22 109.31,81.75 107.41,83.64 107.41,84.41 104.07,87.75 96.61,87.75 96.3,87.44 75.6,87.44 73,84.85 72.24,84.85 71.03,83.63 66.98,83.63 66.5,84.12 v1(66.5,84.65)
  BOTTOM w0.089: DM1.16 66.35,83.73 66.63,84.02 66.63,84.51 v1(66.5,84.65) ; v1(108.25,78.88) 108.25,78.84 108.54,78.55 108.54,77.26 108.48,77.21 108.48,76.67 CPU1.AN70
M_A_DQ7: length 58
  TOP w0.089: v2(108.79,79.98) v1(108.28,79.7)
  L3 w0.127: v1(108.28,79.7) 108.28,80.13 108.6,80.45 108.6,81.37 105.77,84.19 105.77,85.05 103.8,87.02 100.76,87.02 100.63,86.89 100.63,86.2 100.51,86.07 100.25,86.07 100.13,86.2 100.13,86.89 100,87.02 97.09,87.02 96.81,86.73 75.9,86.73 73.3,84.13 72.56,84.13 71.33,82.9 68.78,82.9 68.58,82.7 v1(68.58,82.24)
  BOTTOM w0.089: v1(108.28,79.7) 108.48,79.7 108.74,79.44 108.74,77.23 108.78,77.19 CPU1.AN71 ; DM1.17 67.93,83.48 67.73,83.28 67.73,82.86 67.93,82.66 68.16,82.66 v1(68.58,82.24)
M_A_DQ8: length 55.8
  TOP w0.089: v1(68.71,80) v2(68.71,80.56)
  L3 w0.127: v1(68.71,80) 69.47,80.76 71.36,80.76 72.9,82.3 73.8,82.3 75.94,84.44 79.35,84.44 79.47,84.57 79.47,85.02 79.6,85.14 79.85,85.14 79.98,85.02 79.98,84.57 80.11,84.44 80.36,84.44 80.49,84.57 80.49,85.02 80.62,85.14 80.87,85.14 81,85.02 81,84.57 81.12,84.44 81.48,84.44 82.14,85.11 96.77,85.11 99.36,82.52 99.36,81.47 100.78,80.06 104.73,80.06 105.22,80.55 107.05,80.55 107.14,80.46 v1(107.24,80.46)
  BOTTOM w0.089: CPU1.AR70 107.55,76.58 107.55,76.75 107.49,76.94 107.49,77.12 107.53,77.22 107.53,77.5 107.47,77.62 107.46,77.64 107.38,77.78 107.38,79.45 107.24,79.59 v1(107.24,80.46) ; DM1.28 67.97,80.73 v1(68.71,80)
M_A_DQ9: length 56.3
  TOP w0.089: v1(69.98,79.85) v2(69.98,80.41)
  L3 w0.127: v1(69.98,79.85) 69.98,79.93 70.43,80.38 71.5,80.38 73.07,81.95 73.95,81.95 76.09,84.09 81.63,84.09 82.25,84.71 96.66,84.71 99.01,82.36 99.01,80.83 100.14,79.7 104.87,79.7 104.97,79.79 106.39,79.79 106.52,79.66 106.85,79.66 107.21,79.3 107.21,77.41 105.26,75.46 105.26,75 105.59,74.67 106.54,74.67 107.12,75.25 107.12,76.08 107.24,76.21 108.13,76.21 108.25,76.08 v1(108.25,75.35)
  BOTTOM w0.089: v1(69.98,79.85) 69.98,79.9 70.56,80.48 DM1.29 ; CPU1.AR68 107.93,75.35 v1(108.25,75.35)
M_A_DQ10: length 53.6
  TOP w0.089: v2(106.09,79.2) v1(105.48,78.88)
  L3 w0.127: v1(105.48,78.88) 105.18,78.58 105.18,77.44 105.43,77.2 105.43,76.83 104.89,76.29 104.33,76.29 104.13,76.09 100.14,76.09 97.15,79.08 97.15,81.59 95.8,82.95 86.61,82.95 85.91,82.25 76.83,82.25 72.06,77.49 68.72,77.49 68.53,77.67 v1(68.53,78.3)
  BOTTOM w0.089: CPU1.AU71 106.43,77.21 106.04,77.6 106.04,78.38 105.61,78.81 105.56,78.81 v1(105.48,78.88) ; v1(68.53,78.3) 69.34,77.48 DM1.41
M_A_DQ11: length 55.8
  TOP w0.089: v2(103.68,77.84) v1(103.6,78.46)
  L3 w0.127: v1(103.6,78.46) 103.9,78.16 103.9,77.26 103.37,76.74 101.46,76.74 98.87,79.32 98.34,79.32 97.92,79.75 97.92,81.91 96.14,83.68 82.68,83.68 81.95,82.96 76.53,82.96 74.49,80.92 73.5,80.92 71.33,78.75 67.57,78.75 v1(67.11,78.3)
  BOTTOM w0.089: v1(103.6,78.46) 103.62,78.44 103.62,78.29 104.56,77.36 105.12,77.36 105.41,77.07 105.41,75.05 105.59,74.87 105.59,74.64 105.77,74.45 106.01,74.45 106.45,74.9 106.45,75.07 CPU1.AU68 ; v1(67.11,78.3) 67.11,77.52 66.84,77.25 65.16,77.25 65.14,77.23 DM1.42
M_A_DQ12: length 54.5
  TOP w0.089: v2(67.92,82.8) v1(67.92,82.23)
  L3 w0.127: v1(67.92,82.23) 67.92,81.68 68.16,81.45 71.49,81.45 72.72,82.69 73.68,82.69 75.8,84.8 77.25,84.8 77.38,84.93 77.38,85.15 77.51,85.28 77.76,85.28 77.89,85.15 77.89,84.93 78.02,84.8 78.38,84.8 79.11,85.52 96.86,85.52 99.72,82.67 99.72,81.63 100.84,80.51 104.67,80.51 105.26,81.09 v1(107.24,81.09)
  BOTTOM w0.089: v1(67.92,82.23) 67.43,81.73 DM1.24 ; CPU1.AR71 107.75,77.73 107.56,77.92 107.56,80.17 107.66,80.27 107.66,80.67 v1(107.24,81.09)
M_A_DQ13: length 55.3
  TOP w0.089: v2(69.24,82.8) v1(69.24,82.24)
  L3 w0.127: v1(69.24,82.24) 69.24,82.03 69.47,81.8 71.34,81.8 72.58,83.04 73.5,83.04 76.37,85.91 96.99,85.91 100.07,82.82 100.07,81.78 100.99,80.86 104.52,80.86 105.37,81.71 107.25,81.71 107.68,81.28 107.68,80.27 107.42,80.01 106.79,80.01 v1(106.7,80.1)
  BOTTOM w0.089: v1(69.24,82.24) 69.24,82.23 69.24,81.17 69.47,80.94 69.8,80.94 70.34,81.48 DM1.25 ; CPU1.AR69 107.59,76.09 107.37,76.38 107.37,76.72 107.32,76.91 107.32,77.15 107.35,77.25 107.35,77.46 107.32,77.53 107.19,77.72 107.19,79.39 106.75,79.82 106.75,80.05 v1(106.7,80.1)
M_A_DQ14: length 54
  TOP w0.089: v2(106.21,77.88) v1(105.59,78.05)
  L3 w0.127: v1(65.69,78.3) 66.85,77.13 72.21,77.13 76.9,81.82 85.99,81.82 86.76,82.59 95.65,82.59 96.77,81.47 96.77,78.96 99.87,75.86 102.39,75.86 102.39,75.86 102.4,75.86 102.71,75.55 103.95,75.55 104.02,75.48 104.78,75.48 106.02,76.72 106.02,77.61 v1(105.59,78.05)
  BOTTOM w0.089: CPU1.AU70 106.23,76.68 106.21,76.76 106.14,76.83 106.14,77.24 105.86,77.53 105.86,77.55 105.84,77.57 105.84,77.79 v1(105.59,78.05) ; DM1.38 65.63,78.23 v1(65.69,78.3)
M_A_DQ15: length 54.4
  TOP w0.089: v2(105.13,78.44) v1(104.57,78.52)
  L3 w0.127: v1(69.96,78.3) 70.4,77.85 71.93,77.85 73.4,79.33 73.4,80.23 73.64,80.47 74.54,80.47 76.68,82.6 76.97,82.6 76.97,82.6 82.61,82.6 82.74,82.73 82.74,83.01 82.87,83.14 83.12,83.14 83.25,83.01 83.25,82.73 83.37,82.6 83.63,82.6 83.76,82.73 83.76,83.01 83.88,83.14 84.14,83.14 84.26,83.01 84.26,82.73 84.39,82.6 84.64,82.6 84.77,82.73 84.77,83.01 84.9,83.14 85.15,83.14 85.28,83.01 85.28,82.73 85.41,82.6 85.76,82.6 86.46,83.3 95.94,83.3 97.53,81.71 97.53,79.35 98.13,78.75 98.31,78.75 98.51,78.95 98.69,78.95 98.87,78.77 98.87,78.59 98.67,78.39 98.67,78.21 98.85,78.03 99.03,78.03 99.23,78.23 99.41,78.23 99.59,78.05 99.59,77.87 99.39,77.67 99.39,77.49 99.57,77.31 99.75,77.31 99.95,77.52 100.13,77.52 100.31,77.34 100.31,77.16 100.11,76.95 100.11,76.77 100.36,76.52 103.46,76.52 104.16,77.22 104.16,78.1 v1(104.57,78.52)
  BOTTOM w0.089: v1(104.57,78.52) 104.73,78.52 105.2,78.06 105.2,77.89 105.44,77.64 105.5,77.64 105.97,77.17 105.97,76.7 105.99,76.67 106.01,76.61 106.07,76.55 106.07,76.47 106.07,76.47 106.07,76.45 106.09,76.42 106.09,76.26 106.12,76.15 106.15,76.08 CPU1.AU69 ; v1(69.96,78.3) 70.39,78.73 70.83,78.73 71.08,78.48 DM1.37
M_A_DQ16: length 47.6
  TOP w0.089: v1(94.89,81.35) 94.89,81.65 v2(94.64,81.91)
  L3 w0.127: v1(67.01,76.24) 67.98,75.43 72.54,75.43 77.46,80.34 91.51,80.34 92.13,80.97 93.98,80.97 94.07,80.88 94.44,80.88 94.7,81.14 94.7,81.15 v1(94.89,81.35)
  BOTTOM w0.089: v1(67.01,76.24) 65.81,75.23 DM1.50 ; CPU1.BB65 103.05,73.27 102.97,73.35 102.25,73.35 101.14,74.45 101.14,75.55 96.69,80 96.69,80.58 96.47,80.8 96.17,80.92 95.45,80.92 95.29,81.01 95.15,81.14 v1(94.89,81.35)
M_A_DQ17: length 49.2
  TOP w0.089: v1(68.43,76.24) 68.43,76.33 v2(68.78,76.68)
  L3 w0.127: v1(68.43,76.24) 68.89,75.78 72.39,75.78 77.31,80.7 91.36,80.7 91.98,81.32 v1(94.26,81.32)
  BOTTOM w0.089: v1(68.43,76.24) 69.43,75.24 70.96,75.24 71.2,75.48 DM1.49 ; v1(94.26,81.32) 94.66,81.79 95.72,82.15 96.55,82.15 100.02,78.68 100.1,78.45 100.35,77.81 100.35,77.49 101.83,76.01 101.83,74.73 102.15,74.41 102.48,74.41 102.56,74.48 102.98,74.48 103.27,74.19 103.69,74.19 103.85,74.15 103.94,73.98 103.94,73.91 103.97,73.81 104.08,73.7 104.2,73.66 104.34,73.62 104.51,73.62 CPU1.AW65
M_A_DQ18: length 50
  TOP w0.089: v2(94.66,78.16) 94.23,77.72 v1(94.23,77.56)
  L3 w0.127: v1(94.23,77.56) 94.23,78.05 93.76,78.52 78.26,78.52 72.62,72.87 72.02,72.87 71.46,72.32 68,72.32 67.75,72.06 v1(67.75,71.69)
  BOTTOM w0.089: CPU1.AW63 104.98,72.23 104.72,72.38 104.45,72.38 104.41,72.34 103.53,72.34 103.39,72.38 103.05,72.38 102.85,72.19 102.48,72.19 102.25,72.41 102.25,72.57 100.48,74.34 100.48,74.85 97.02,78.31 94.98,78.31 v1(94.23,77.56) ; v1(67.75,71.69) 67.75,72.12 67.33,72.54 65.56,72.54 65.25,72.23 DM1.62
M_A_DQ19: length 49.1
  TOP w0.089: v2(93.44,78.15) 93.44,77.69 v1(93.57,77.56)
  L3 w0.127: v1(70.59,71.69) 71.85,71.69 72.61,72.44 73.26,72.44 74.24,73.43 74.24,73.61 74.14,73.71 74.14,73.89 74.32,74.07 74.5,74.07 74.6,73.97 74.78,73.97 74.96,74.15 74.96,74.33 74.86,74.43 74.86,74.61 75.04,74.79 75.22,74.79 75.32,74.69 75.5,74.69 75.68,74.87 75.68,75.05 75.58,75.15 75.58,75.33 75.76,75.51 75.94,75.51 76.04,75.41 76.22,75.41 76.4,75.59 76.4,75.77 76.3,75.87 76.3,76.05 76.48,76.23 76.66,76.23 76.76,76.12 76.94,76.12 78.98,78.16 79.5,78.16 79.62,78.04 79.62,77.5 79.75,77.37 80,77.37 80.13,77.5 80.13,78.04 80.26,78.16 80.51,78.16 80.64,78.04 80.64,77.5 80.77,77.37 81.02,77.37 81.15,77.5 81.15,78.04 81.27,78.16 81.53,78.16 81.65,78.04 81.65,77.5 81.78,77.37 82.04,77.37 82.16,77.5 82.16,78.04 82.29,78.16 82.54,78.16 82.67,78.04 82.67,77.5 82.8,77.37 83.05,77.37 83.18,77.5 83.18,78.04 83.31,78.16 93.02,78.16 93.57,77.61 v1(93.57,77.56)
  BOTTOM w0.089: DM1.63 70.69,71.98 70.59,71.88 v1(70.59,71.69) ; v1(93.57,77.56) 94.23,76.9 96.77,76.9 99.11,74.56 99.42,74.56 101.65,72.33 101.65,72.26 102.27,71.64 104.04,71.64 CPU1.AY63
M_A_DQ20: length 47.9
  TOP w0.089: v2(96.72,81.02) 96.37,81.37 v1(96.24,81.37)
  L3 w0.127: v1(96.24,81.37) 95.46,82.15 87.03,82.15 86.34,81.46 77.05,81.46 72.31,76.72 66.07,76.72 v1(65.59,76.24)
  BOTTOM w0.089: v1(65.59,76.24) 65.58,76.23 DM1.46 ; v1(96.24,81.37) 96.39,81.37 97.01,80.76 97.01,80.13 101.32,75.82 101.32,74.53 102.32,73.52 103.16,73.52 103.17,73.53 103.37,73.53 103.63,73.46 CPU1.BA65
M_A_DQ21: length 48.6
  TOP w0.089: v1(95.55,81.35) 95.55,81.6 v2(95.86,81.91)
  L3 w0.127: v1(70.57,76.24) 70.57,76.24 72.34,76.24 76.7,80.6 76.7,80.6 77.16,81.06 86.88,81.06 87.01,81.18 87.01,81.62 87.13,81.75 87.39,81.75 87.51,81.62 87.51,81.18 87.64,81.06 87.89,81.06 88.02,81.18 88.02,81.62 88.15,81.75 88.4,81.75 88.53,81.62 88.53,81.18 88.66,81.06 88.91,81.06 89.04,81.18 89.04,81.62 89.16,81.75 89.42,81.75 89.55,81.62 89.55,81.18 89.67,81.06 89.93,81.06 90.05,81.18 90.05,81.62 90.18,81.75 90.43,81.75 90.56,81.62 90.56,81.18 90.69,81.06 91.21,81.06 91.83,81.68 93.98,81.68 94.1,81.79 95.08,81.79 95.52,81.35 v1(95.55,81.35)
  BOTTOM w0.089: DM1.45 70.81,76.48 v1(70.57,76.24) ; CPU1.AY65 104.44,73.27 104.2,73.48 103.82,73.58 103.7,73.63 103.39,73.71 103,73.71 103,73.7 102.44,73.7 101.6,74.54 101.6,75.99 99.88,77.7 98.04,79.55 98.04,79.67 98.19,79.83 98.19,79.95 98.07,80.08 97.94,80.08 97.79,79.92 97.66,79.92 97.32,80.26 97.32,80.92 96.42,81.83 96.04,81.83 v1(95.55,81.35)
M_A_DQ22: length 48.5
  TOP w0.089: v1(94.89,77.56) 94.89,77.36 v2(95.22,77.03)
  L3 w0.127: v1(94.89,77.56) 94.89,78.51 94.5,78.9 78.13,78.9 72.48,73.25 71.81,73.25 71.28,72.72 66.82,72.72 66.32,73.21 v1(66.32,73.52)
  BOTTOM w0.089: v1(94.89,77.56) 95.32,77.99 96.89,77.99 99.97,74.9 99.97,74.57 102.04,72.51 102.04,72.38 102.4,72.01 102.92,72.01 103.12,72.2 103.37,72.2 103.63,72.14 CPU1.BA63 ; v1(66.32,73.52) 66.32,73.24 66.09,73.01 65.53,73.01 65.3,73.23 DM1.58
M_A_DQ23: length 47
  TOP w0.089: v2(96.21,78.2) 96.16,78.15 v1(96.16,77.56)
  L3 w0.127: v1(96.16,77.56) 96.16,77.98 94.82,79.32 77.88,79.32 72.45,73.88 71.75,73.88 70.94,73.08 68.19,73.08 v1(67.75,73.52)
  BOTTOM w0.089: v1(67.75,73.52) 68.28,72.98 DM1.59 ; v1(96.16,77.56) 96.72,77.56 100.07,74.22 100.07,74.16 101.86,72.37 101.86,72.3 102.34,71.82 103.16,71.82 CPU1.BB63
M_A_DQ24: length 48.3
  TOP w0.089: v1(95.63,76.34) 96.14,75.84 v2(96.14,75.63)
  L3 w0.127: v1(95.63,76.34) 95.63,76.05 95.43,75.85 93.14,75.85 93.14,75.85 78.76,75.85 73.93,71.02 73.2,71.02 71.36,69.19 68.98,69.19 v1(68.53,69.63)
  BOTTOM w0.089: v1(68.53,69.63) 68.82,69.92 68.82,70.35 68.27,70.9 67.32,70.9 66.66,70.23 DM1.70 ; CPU1.BA61 103.59,71.26 102.15,71.26 101.29,72.12 101.29,72.19 99.46,74.02 97.85,74.02 95.68,76.19 95.68,76.27 95.63,76.32 v1(95.63,76.34)
M_A_DQ25: length 50
  TOP w0.089: v1(93.72,76.29) 93.7,76.27 v2(93.7,75.73)
  L3 w0.127: v1(93.72,76.29) 92.4,76.29 92.28,76.42 92.28,76.89 92.13,77.04 91.92,77.04 91.77,76.89 91.77,76.42 91.64,76.29 91.39,76.29 91.26,76.42 91.26,76.87 91.13,77 90.88,77 90.75,76.87 90.75,76.42 90.63,76.29 90.37,76.29 90.25,76.42 90.25,76.87 90.12,77 89.86,77 89.74,76.87 89.74,76.42 89.61,76.29 89.36,76.29 89.23,76.42 89.23,76.87 89.1,77 88.85,77 88.72,76.87 88.72,76.42 88.59,76.29 78.68,76.29 73.76,71.38 73.05,71.38 72.21,70.54 71.69,70.54 71.56,70.41 71.56,70.15 71.44,70.02 71.18,70.02 71.06,70.15 71.06,70.41 70.93,70.54 70.05,70.54 69.72,70.2 69.72,69.84 69.92,69.63 v1(69.96,69.63)
  BOTTOM w0.089: CPU1.AW61 104.78,70.49 104.74,70.48 104.49,70.48 104.28,70.56 104.22,70.62 103.13,70.62 102.88,70.87 101.97,70.87 101.54,71.3 101.54,71.33 100.86,72 100.86,72.05 100.83,72.08 100.83,72.14 99.41,73.57 97.29,73.57 96.19,74.67 94.99,74.67 94.23,75.43 94.23,75.66 93.72,76.17 v1(93.72,76.29) ; DM1.71 71.1,69.98 70.87,70.22 70.15,70.22 69.96,70.03 v1(69.96,69.63)
M_A_DQ26: length 47.8
  TOP w0.089: v1(97.64,73.17) v2(97.64,73.73)
  L3 w0.127: v1(69.91,66.64) 69.22,67.32 68.04,67.32 67.93,67.42 67.93,68.04 68.04,68.14 70.48,68.14 70.61,68.01 70.61,67.78 70.74,67.66 70.99,67.66 71.12,67.78 71.12,68.01 71.24,68.14 71.89,68.14 73.61,69.87 74.23,69.87 79.19,74.82 92.71,74.82 92.72,74.82 96.76,74.82 97.64,73.94 v1(97.64,73.17)
  BOTTOM w0.089: CPU1.BB59 103.1,69.59 103.02,69.66 102.74,69.66 102.39,70.02 101.54,70.02 99.69,71.87 98.11,71.87 97.56,72.42 97.56,73.09 v1(97.64,73.17) ; v1(69.91,66.64) 70.34,67.08 71.04,67.08 71.13,66.98 DM1.83
M_A_DQ27: length 50.5
  TOP w0.089: v2(95.15,73.14) 95.25,73.04 v1(95.76,73.04)
  L3 w0.127: v1(95.76,73.04) 95.15,73.65 79.66,73.65 71.44,65.43 66.84,65.43 v1(65.64,66.64)
  BOTTOM w0.089: v1(95.76,73.04) 95.76,72.22 96.79,71.18 99.32,71.18 99.34,71.16 99.39,71.16 99.62,70.93 99.62,70.91 101.88,68.65 102.21,68.65 102.3,68.74 102.55,68.74 103.41,68.76 103.66,68.67 103.94,68.67 104.06,68.61 105.06,68.61 105.1,68.65 105.38,68.65 105.41,68.61 105.7,68.61 105.9,68.81 105.9,69.09 105.47,69.52 105.31,69.52 CPU1.AW59 ; v1(65.64,66.64) 65.54,66.73 DM1.84
M_A_DQ28: length 47.9
  TOP w0.089: v2(94.92,75.76) 94.92,75.79 v1(94.36,76.34)
  L3 w0.127: v1(94.36,76.34) 93.95,76.75 93.25,76.75 92.59,77.41 88.57,77.41 88.37,77.2 88.37,76.85 88.16,76.65 87.62,76.65 87.49,76.78 87.49,77.07 87.37,77.2 87.11,77.2 86.99,77.07 86.99,76.78 86.86,76.65 78.53,76.65 73.62,71.73 72.9,71.73 72.06,70.89 66.52,70.89 66.32,71.09 v1(66.32,71.69)
  BOTTOM w0.089: v1(94.36,76.34) 94.38,76.32 94.41,76.32 94.66,76.06 94.66,75.53 94.94,75.25 95.88,75.25 97.38,73.75 99.47,73.75 101.06,72.17 101.06,72.06 102.06,71.06 103.14,71.06 CPU1.BB61 ; DM1.66 65.87,71.23 v1(66.32,71.69)
M_A_DQ29: length 48.9
  TOP w0.089: v1(96.26,76.34) 96.52,76.34 v2(96.82,76.65)
  L3 w0.127: v1(96.26,76.34) 96.26,76.84 96,77.11 93.39,77.11 92.71,77.79 86.44,77.79 86.32,77.66 86.32,77.13 86.19,77 85.93,77 85.81,77.13 85.81,77.66 85.68,77.79 85.43,77.79 85.3,77.66 85.3,77.13 85.17,77 84.82,77 84.69,77.13 84.69,77.68 84.56,77.81 84.31,77.81 84.18,77.68 84.18,77.13 84.05,77 78.38,77 73.47,72.09 72.75,72.09 71.91,71.25 69.61,71.25 v1(69.17,71.69)
  BOTTOM w0.089: DM1.67 71.33,70.98 71.02,70.68 69.42,70.68 69.17,70.93 v1(69.17,71.69) ; v1(96.26,76.34) 98.35,74.26 99.47,74.26 101.47,72.26 101.47,72.19 102.22,71.44 103.79,71.44 103.92,71.3 CPU1.AY61
M_A_DQ30: length 49.1
  TOP w0.089: v1(97.13,72.76) 97.13,72.66 v2(97.48,72.31)
  L3 w0.127: v1(68.48,66.64) 68.48,66.38 68.67,66.19 71.2,66.19 72.21,67.21 72.21,67.39 72.07,67.54 72.07,67.72 72.24,67.89 72.42,67.89 72.57,67.75 72.75,67.75 79.47,74.47 92.57,74.47 92.57,74.46 95.78,74.46 95.78,74.47 96.44,74.47 97.13,73.78 v1(97.13,72.76)
  BOTTOM w0.089: DM1.79 71.44,67.98 71.41,68.02 68.38,68.02 68.02,67.66 68.02,67.1 v1(68.48,66.64) ; v1(97.13,72.76) 97.13,72.08 97.56,71.64 99.59,71.64 101.44,69.79 102.28,69.79 102.6,69.47 102.93,69.47 103.07,69.33 103.38,69.33 103.51,69.38 103.61,69.48 103.83,69.48 CPU1.BA59
M_A_DQ31: length 49.6
  TOP w0.089: v2(96.27,73.61) 96.27,72.81 v1(96.34,72.74)
  L3 w0.127: v1(96.34,72.74) 96.32,72.76 96.32,73.5 95.71,74.11 92.42,74.11 92.42,74.11 79.62,74.11 71.34,65.84 67.32,65.84 67.06,66.09 v1(67.06,66.64)
  BOTTOM w0.089: v1(67.06,66.64) 67.06,67.49 66.82,67.73 64.24,67.73 64.24,67.73 64.15,67.73 DM1.80 ; CPU1.AY59 104.18,69.28 104.09,69.24 103.69,69.24 103.41,69.15 102.92,69.15 102.51,69.3 102.25,69.56 101.35,69.56 99.5,71.41 97.13,71.41 96.37,72.18 96.37,72.71 v1(96.34,72.74)
M_A_DQ32: length 53
  TOP w0.089: v1(67.11,43.32) v2(67.11,42.76)
  L3 w0.127: v1(97.41,58.36) 97,58.36 93.45,54.81 91.15,54.81 85.1,48.77 85.1,47.23 81.61,43.74 81.11,43.74 78.22,40.85 72.54,40.85 71.05,42.34 69.1,42.34 68.97,42.21 68.97,41.8 68.84,41.67 68.59,41.67 68.46,41.8 68.46,42.21 68.34,42.34 67.4,42.34 67.11,42.63 v1(67.11,43.32)
  BOTTOM w0.089: DM1.174 66.17,42.23 67.11,43.17 v1(67.11,43.32) ; CPU1.AY39 104.36,58.54 104.05,58.86 103.69,58.86 103.38,59.01 102.88,59.01 102.76,59.13 98.12,59.13 97.43,58.44 97.43,58.39 v1(97.41,58.36)
M_A_DQ33: length 51
  TOP w0.089: v1(68.6,43.32) v2(68.6,42.76)
  L3 w0.127: v1(68.6,43.32) 69.04,43.78 70.99,43.78 72.85,41.91 78.24,41.91 84.39,48.07 84.39,49.06 90.91,55.57 93.53,55.57 97.06,59.11 98.39,59.11 v1(99.34,58.41)
  BOTTOM w0.089: CPU1.AW39 105.24,58.06 105.18,57.84 105.05,57.72 104.67,57.62 104.18,57.62 104.04,57.66 103.79,57.66 103.71,57.62 103.51,57.62 103.43,57.66 103.04,57.66 102.93,57.55 100.17,57.55 100.02,57.7 v1(99.34,58.41) ; v1(68.6,43.32) 69.44,42.48 DM1.173
M_A_DQ34: length 52.7
  TOP w0.089: v1(97.36,56.3) 97.33,56.28 v2(96.7,56.28)
  L3 w0.127: v1(97.36,56.3) 96.88,56.3 93.77,53.19 92.11,53.19 86.84,47.92 86.84,45.51 84.04,42.71 83.18,42.71 82.92,42.46 82.92,42.28 83.18,42.02 83.18,41.84 83,41.67 82.82,41.67 82.57,41.92 82.39,41.92 82.21,41.74 82.21,41.56 82.46,41.31 82.46,41.13 82.28,40.95 82.1,40.95 81.85,41.2 81.67,41.2 81.49,41.02 81.49,40.84 81.74,40.59 81.74,40.41 81.56,40.23 81.38,40.23 81.13,40.48 80.95,40.48 80.77,40.3 80.77,40.12 81.02,39.87 81.02,39.69 80.84,39.51 80.66,39.51 80.41,39.76 80.23,39.76 79.04,38.57 78.51,38.57 78.39,38.7 78.39,38.9 78.26,39.03 78,39.03 77.88,38.9 77.88,38.7 77.75,38.57 77.36,38.57 77.23,38.7 77.23,38.9 77.11,39.03 76.85,39.03 76.72,38.9 76.72,38.7 76.6,38.57 75.46,38.57 75,39.03 v1(70.56,39.03)
  BOTTOM w0.089: v1(97.36,56.3) 97.23,56.43 96.72,56.43 96.44,56.71 96.44,57.17 96.7,57.42 99.99,57.42 100.04,57.37 103,57.37 103.11,57.48 103.39,57.48 103.47,57.44 103.75,57.44 103.84,57.48 104.01,57.48 104.11,57.45 104.12,57.45 104.26,57.38 CPU1.AY37 ; v1(70.56,39.03) 70.79,39.03 70.83,38.98 DM1.187
M_A_DQ35: length 53.4
  TOP w0.089: v1(99.34,56.18) 99.34,56.33 v2(99.67,56.66)
  L3 w0.127: v1(66.27,38.73) 66.11,38.88 66.11,39.3 66.27,39.45 69.2,39.45 70.17,38.49 74.99,38.49 75.39,38.09 79.17,38.09 80.2,39.12 80.96,39.12 87.2,45.36 87.2,47.77 92.32,52.89 93.84,52.89 96.82,55.87 99.03,55.87 v1(99.34,56.18)
  BOTTOM w0.089: DM1.186 66,39.23 66.27,38.97 v1(66.27,38.73) ; CPU1.AW37 105.12,57.32 104.81,57 104.14,57 104.09,56.96 103.95,56.96 103.77,56.78 103.75,56.78 103.75,56.78 103.01,56.78 103,56.78 102.99,56.78 102.94,56.84 100.13,56.84 100.04,56.74 99.52,56.74 99.39,56.61 99.39,56.23 v1(99.34,56.18)
M_A_DQ36: length 50.2
  TOP w0.089: v2(65.28,43.3) 65.81,43.3 v1(65.84,43.32)
  L3 w0.127: v1(102.51,58.57) 102.51,59.1 102.26,59.35 101.06,59.35 100.93,59.22 100.93,58.94 100.8,58.82 100.55,58.82 100.42,58.94 100.42,59.22 100.29,59.35 96.98,59.35 93.57,55.95 90.78,55.95 84.04,49.21 84.04,48.21 78.09,42.27 73,42.27 71.13,44.14 66.65,44.14 v1(65.84,43.32)
  BOTTOM w0.089: v1(65.84,43.32) 65.81,43.32 65.72,43.23 DM1.170 ; CPU1.BB39 102.53,58.54 v1(102.51,58.57)
M_A_DQ37: length 51.2
  TOP w0.089: v2(70.13,42.76) 70.13,43.12 v1(69.92,43.32)
  L3 w0.127: v1(98.7,58.36) 98.3,58.77 97.05,58.77 93.48,55.19 91.03,55.19 84.75,48.91 84.75,47.92 84.46,47.63 84.46,47.45 84.55,47.36 84.55,47.18 84.37,47 84.19,47 84.1,47.09 83.92,47.09 83.74,46.91 83.74,46.73 83.83,46.64 83.83,46.46 83.65,46.28 83.47,46.28 83.38,46.37 83.2,46.37 83.02,46.19 83.02,46.01 83.11,45.92 83.11,45.74 82.93,45.56 82.75,45.56 82.66,45.65 82.48,45.65 82.3,45.47 82.3,45.3 82.4,45.2 82.4,45.02 82.22,44.84 82.04,44.84 81.94,44.94 81.76,44.94 81.58,44.76 81.58,44.58 81.68,44.48 81.68,44.3 81.5,44.13 81.32,44.13 81.23,44.22 81.05,44.22 78.39,41.56 78.03,41.56 77.9,41.43 77.9,41.33 77.78,41.2 77.52,41.2 77.39,41.33 77.39,41.43 77.27,41.56 77.01,41.56 76.89,41.43 76.89,41.33 76.76,41.2 76.51,41.2 76.38,41.33 76.38,41.43 76.25,41.56 76,41.56 75.87,41.43 75.87,41.33 75.74,41.2 75.49,41.2 75.36,41.33 75.36,41.43 75.24,41.56 74.98,41.56 74.85,41.43 74.85,41.33 74.73,41.2 74.47,41.2 74.35,41.33 74.35,41.43 74.22,41.56 73.97,41.56 73.84,41.43 73.84,41.33 73.71,41.2 73.46,41.2 73.33,41.33 73.33,41.43 73.2,41.56 72.71,41.56 71.57,42.7 70.15,42.7 69.87,42.97 69.87,43.27 v1(69.92,43.32)
  BOTTOM w0.089: v1(69.92,43.32) 70.13,43.53 70.13,43.73 70.31,43.91 70.82,43.91 71.25,43.48 DM1.169 ; CPU1.BA39 103.83,58.65 103.72,58.65 103.55,58.73 103.32,58.84 102.8,58.84 102.68,58.96 98.86,58.96 98.7,58.8 v1(98.7,58.36)
M_A_DQ38: length 52
  TOP w0.089: v2(98.45,56.86) 98.63,56.68 v1(98.63,56.3)
  L3 w0.127: v1(98.63,56.3) 98.63,56.67 98.37,56.93 96.69,56.93 93.51,53.75 91.54,53.75 90.12,52.32 90.12,52.26 86.13,48.28 86.13,45.81 83.79,43.47 82.9,43.47 79.18,39.74 71.83,39.74 71.41,40.16 68.02,40.16 67.82,40.36 v1(67.82,40.96)
  BOTTOM w0.089: v1(67.82,40.96) 67.87,40.91 67.87,40.78 68.17,40.48 70.61,40.48 71.1,39.98 DM1.183 ; v1(98.63,56.3) 98.65,56.33 98.65,56.68 98.91,56.94 99.95,56.94 100.03,57.01 103.02,57.01 103.08,56.95 103.67,56.95 CPU1.BA37
M_A_DQ39: length 51.6
  TOP w0.089: v1(97.99,56.3) 97.99,55.85 v2(98.22,55.62)
  L3 w0.127: v1(66.5,40.96) 66.23,40.7 66.23,40.13 66.56,39.81 70.64,39.81 71.06,39.39 79.35,39.39 83.03,43.06 83.89,43.06 86.49,45.66 86.49,48.07 91.81,53.39 92,53.39 92.01,53.41 93.56,53.41 96.86,56.71 97.59,56.71 v1(97.99,56.3)
  BOTTOM w0.089: CPU1.BB37 103.26,57.19 99.95,57.19 99.91,57.15 98.51,57.15 97.99,56.63 v1(97.99,56.3) ; DM1.182 66.26,40.23 66.5,40.47 v1(66.5,40.96)
M_A_DQ40: length 56.7
  TOP w0.089: v1(102.51,56.07) 102.51,55.95 v2(102.84,55.62)
  L3 w0.127: v1(69.92,36.62) 70.37,37.06 71.39,37.06 72.39,36.07 73.06,36.07 73.58,35.54 73.95,35.54 74.48,36.07 79.91,36.07 88.76,44.91 88.76,47.2 92.26,50.7 92.97,50.7 97.22,54.96 103.46,54.96 104.26,55.76 104.26,57.92 104.13,58.05 102.19,58.05 101.86,57.71 101.86,57.17 102.51,56.51 v1(102.51,56.07)
  BOTTOM w0.089: DM1.195 71.07,36.98 70.98,37.08 70.38,37.08 v1(69.92,36.62) ; CPU1.AY35 104.47,55.97 104.14,55.97 104.04,55.93 103.84,55.93 103.74,55.96 103.47,55.96 103.35,55.91 102.67,55.91 v1(102.51,56.07)
M_A_DQ41: length 57.8
  TOP w0.089: v2(102.16,56.63) 101.88,56.35 v1(101.88,56.07)
  L3 w0.127: v1(66.5,36.6) 65.95,37.15 64.71,37.15 64.51,37.35 64.51,37.81 64.71,38.01 67.71,38.01 68.3,37.42 71.55,37.42 72.5,36.47 72.5,36.47 72.55,36.42 73.57,36.42 73.58,36.43 73.95,36.43 73.96,36.42 79.77,36.42 88.4,45.06 88.4,47.47 93.15,52.22 94.13,52.22 97.1,55.19 100.99,55.19 v1(101.88,56.07)
  BOTTOM w0.089: v1(66.5,36.6) 65.87,37.23 DM1.194 ; CPU1.AW35 104.94,55.79 104.17,55.79 104.07,55.75 103.8,55.75 103.71,55.79 103.51,55.79 103.42,55.75 103.42,55.75 103.38,55.73 102.81,55.73 102.81,55.72 102.68,55.59 102.29,55.59 101.88,56 v1(101.88,56.07)
M_A_DQ42: length 56.7
  TOP w0.089: v1(101.47,54.12) 101.85,53.74 v2(101.85,53.56)
  L3 w0.089: 97.35,53.29 97.5,53.43 101.1,53.43 101.47,53.8 v1(101.47,54.12)
  L3 w0.127: 97.35,53.29 92.84,48.78 92.84,47.36 91.43,45.94 91.43,45.01 90.54,44.12 90.54,43.42 87.43,40.31 87.26,40.31 87.03,40.54 86.85,40.54 86.67,40.36 86.67,40.18 86.9,39.95 86.9,39.77 86.72,39.59 86.54,39.59 86.31,39.82 86.13,39.82 85.95,39.64 85.95,39.46 86.18,39.23 86.18,39.05 86,38.87 85.82,38.87 85.59,39.1 85.41,39.1 85.23,38.92 85.23,38.74 85.46,38.52 85.46,38.34 85.28,38.16 85.1,38.16 84.87,38.38 84.69,38.38 84.51,38.2 84.51,38.02 84.74,37.8 84.74,37.62 84.49,37.36 84.31,37.36 84.08,37.59 83.9,37.59 83.72,37.41 83.72,37.23 83.95,37.01 83.95,36.83 83.77,36.65 83.59,36.65 83.36,36.87 83.18,36.87 83,36.69 83,36.51 83.23,36.29 83.23,36.11 82.43,35.31 81.65,34.53 81.47,34.53 81.26,34.74 81.08,34.74 79.54,33.21 71.52,33.21 70.68,34.05 70.05,34.05 v1(69.09,35)
  BOTTOM w0.089: v1(69.09,35) 70.11,33.98 DM1.207 ; v1(101.47,54.12) 101.47,54.24 101.73,54.5 102.51,54.5 102.59,54.42 103.39,54.42 103.51,54.45 103.57,54.49 103.92,54.57 104.16,54.57 104.36,54.71 CPU1.AY33
M_A_DQ43: length 55.5
  TOP w0.089: v1(67.85,34.24) v2(68.41,34.24)
  L3 w0.127: v1(67.85,34.24) 69.8,33.69 70.54,33.69 71.37,32.86 79.79,32.86 81.66,34.04 90.9,43.28 91.37,44.19 92.81,45.62 93.11,46.84 93.11,47.83 93.8,48.52 94.44,50 97.67,53.23 101.33,53.23 102.56,53.64 v1(105.75,56.23)
  BOTTOM w0.089: v1(105.75,56.23) 105.75,56.19 105.37,55.82 105.24,55.44 CPU1.AW33 ; DM1.208 65.14,33.73 65.16,33.75 67.37,33.75 v1(67.85,34.24)
M_A_DQ44: length 55.3
  TOP w0.089: v2(101.55,55.49) 101.24,55.8 v1(101.24,56.07)
  L3 w0.127: v1(101.24,56.07) 101.24,55.76 100.9,55.41 97.03,55.41 94.04,52.43 92.87,52.43 87.91,47.48 87.91,45.07 80.87,38.03 80.69,38.03 80.5,38.23 80.32,38.23 80.14,38.05 80.14,37.87 80.33,37.67 80.33,37.49 79.67,36.83 79.31,36.83 79.19,36.96 79.19,37.25 79.06,37.38 78.81,37.38 78.68,37.25 78.68,36.96 78.55,36.83 78.3,36.83 78.17,36.96 78.17,37.25 78.04,37.38 77.79,37.38 77.66,37.25 77.66,36.96 77.54,36.83 77.28,36.83 77.16,36.96 77.16,37.25 77.03,37.38 76.77,37.38 76.65,37.25 76.65,36.96 76.52,36.83 76.27,36.83 76.14,36.96 76.14,37.23 75.99,37.38 75.78,37.38 75.63,37.23 75.63,36.96 75.5,36.83 72.64,36.83 71.7,37.77 68.51,37.77 68.38,37.9 68.38,38.21 68.83,38.65 v1(68.83,38.65)
  BOTTOM w0.089: CPU1.BB35 103.24,56.19 102.75,56.38 102.67,56.46 101.63,56.46 v1(101.24,56.07) ; DM1.191 70.2,37.98 69.86,37.64 68.77,37.64 68.64,37.77 68.64,38.52 68.77,38.65 v1(68.83,38.65)
M_A_DQ45: length 56.5
  TOP w0.089: v2(100.94,56.58) 100.61,56.25 v1(100.61,56.13)
  L3 w0.127: v1(100.61,56.13) 100.61,55.89 100.36,55.64 96.92,55.64 93.93,52.65 92.58,52.65 87.55,47.62 87.55,45.22 81.1,38.77 80.35,38.77 79.32,37.73 75.24,37.73 74.85,38.13 74.37,38.13 74.24,38 74.24,37.31 74.11,37.19 73.86,37.19 73.73,37.31 73.73,38 73.61,38.13 73.35,38.13 73.22,38 73.22,37.34 73.08,37.2 72.86,37.2 72.72,37.34 72.72,38 72.59,38.13 69.43,38.13 69.29,38.27 69.29,38.85 69.05,39.09 67.69,39.09 67.56,38.97 v1(67.56,38.68)
  BOTTOM w0.089: v1(67.56,38.68) 67.57,38.68 67.86,38.38 67.86,37.73 67.74,37.6 66.75,37.6 66.11,38.23 DM1.190 ; v1(100.61,56.13) 101.13,56.65 102.88,56.65 102.95,56.58 103.74,56.58 103.94,56.38 CPU1.BA35
M_A_DQ46: length 55.7
  TOP w0.089: v1(100.84,54.12) 100.84,54.32 v2(100.43,54.73)
  L3 w0.089: 97.18,53.45 97.35,53.61 100.69,53.61 100.84,53.76 v1(100.84,54.12)
  L3 w0.127: 97.18,53.45 93.01,49.28 92.84,49.28 91.95,48.39 91.95,48.21 92.46,47.7 92.46,47.52 92.28,47.34 92.1,47.34 91.8,47.64 91.54,47.64 91.43,47.53 91.43,47.01 91.3,46.89 90.4,46.89 90.14,46.62 90.14,45.51 90.27,45.39 90.74,45.39 90.87,45.26 90.87,45 90.74,44.88 90.27,44.88 90.14,44.75 90.14,44.34 89.74,43.94 89.74,43.76 89.97,43.53 89.97,43.35 89.79,43.17 89.61,43.17 89.38,43.4 89.2,43.4 89.02,43.22 89.02,43.04 89.25,42.81 89.25,42.63 89.07,42.45 88.89,42.45 88.66,42.68 88.48,42.68 88.3,42.5 88.3,42.32 88.53,42.09 88.53,41.91 88.35,41.73 88.17,41.73 87.95,41.96 87.77,41.96 87.59,41.78 87.59,41.6 87.81,41.37 87.81,41.19 87.63,41.01 87.45,41.01 87.23,41.24 87.05,41.24 79.4,33.6 76.07,33.6 75.94,33.72 75.94,33.98 75.79,34.13 75.58,34.13 75.43,33.98 75.43,33.72 75.31,33.6 75.05,33.6 74.93,33.72 74.93,34.01 74.78,34.16 74.57,34.16 74.42,34.01 74.42,33.72 74.29,33.6 72.01,33.6 71.75,33.85 71.75,34.03 71.95,34.23 71.95,34.41 71.77,34.58 71.59,34.58 71.39,34.39 70.81,34.39 70.56,34.64 v1(70.56,35.04)
  BOTTOM w0.089: DM1.203 70.62,34.98 v1(70.56,35.04) ; v1(100.84,54.12) 100.84,54.47 101.05,54.68 102.59,54.68 102.66,54.6 103.36,54.6 103.43,54.62 103.82,54.86 CPU1.BA33
M_A_DQ47: length 54.9
  L3 w0.089: 96.78,53.41 97.15,53.79 99.87,53.79 v1(100.2,54.12)
  L3 w0.127: v1(66.43,34.24) 65.67,35 65.38,35 65.25,35.12 65.25,35.84 65.38,35.96 67.91,35.96 68.38,35.49 71.37,35.49 72.87,33.99 73.86,33.99 74.81,34.95 75.51,34.95 76.47,33.99 79.29,33.99 89.79,44.49 89.79,46.77 92.65,49.64 93,49.64 96.78,53.41
  BOTTOM w0.089: v1(66.43,34.24) 66.32,34.24 65.89,34.66 65.3,34.66 65.23,34.73 DM1.204 ; CPU1.BB33 103.25,54.83 102.72,54.83 102.69,54.86 100.71,54.86 v2(100.52,54.66) 100.23,54.37 100.23,54.14 v1(100.2,54.12)
M_A_DQ48: length 55.9
  TOP w0.089: v2(100.15,53.28) 99.76,52.89 v1(99.76,52.78)
  L3 w0.127: v1(66.93,31.6) 66.7,31.36 66.7,30.8 66.93,30.57 67.49,30.57 68.06,31.15 68.45,31.15 68.58,31.27 68.58,31.54 68.71,31.67 68.96,31.67 69.09,31.54 69.09,31.27 69.22,31.15 70.69,31.15 71.41,30.43 74.21,30.43 74.93,31.15 81.16,31.15 92.79,42.78 92.79,43.6 94.24,45.05 94.24,46.51 95.44,47.7 95.44,49.41 97.92,51.89 98.51,51.89 98.98,52.37 99.35,52.37 v1(99.76,52.78)
  BOTTOM w0.089: v1(99.76,52.78) 100.14,53.15 103.38,53.15 103.43,53.2 104.23,53.2 CPU1.AY31 ; DM1.216 66.79,31.73 v1(66.93,31.6)
M_A_DQ49: length 56.8
  TOP w0.089: v2(68.43,32.33) 68.15,32.6 v1(68.15,32.81)
  L3 w0.127: v1(68.15,32.81) 68.07,32.81 67.63,33.25 67.63,33.57 67.76,33.7 68.44,33.7 69.32,33.33 70.39,33.33 71.22,32.5 80.66,32.5 91.73,43.57 91.73,44.04 93.42,45.74 93.42,47.82 94.7,49.1 94.7,49.88 97.62,52.8 v1(97.81,52.8)
  BOTTOM w0.089: v1(68.15,32.81) 67.97,32.63 67.97,32.17 68.16,31.98 68.43,31.98 68.52,32.07 68.52,32.26 68.61,32.35 68.78,32.35 68.87,32.26 68.87,32.07 68.96,31.98 DM1.215 ; v1(97.81,52.8) 97.61,53 97.61,53.48 97.81,53.69 102.72,53.69 103.05,54.02 103.42,54.02 103.57,53.95 103.64,53.88 104.74,53.88 105.05,53.56 CPU1.AW31
M_A_DQ50: length 55.8
  TOP w0.089: v2(102.81,50.64) 102.72,50.74 102.06,50.74 101.57,51.23 v1(101.57,51.23)
  L3 w0.127: v1(101.57,51.23) 101.03,50.69 98.5,50.69 96.63,48.82 96.63,45.83 94.03,43.24 94.03,41.55 81.16,28.69 79.97,28.69 79.76,28.48 79.46,28.48 79.25,28.69 78.95,28.69 78.74,28.48 78.45,28.48 78.24,28.69 77.94,28.69 77.73,28.48 77.43,28.48 77.22,28.69 69.21,28.69 68.71,28.19 v1(68.71,28.09)
  BOTTOM w0.089: v1(68.71,28.09) 68.06,28.73 DM1.228 ; v1(101.57,51.23) 101.58,51.23 101.95,51.6 102.94,51.6 103.1,51.76 103.72,51.76 103.84,51.89 104.03,51.94 104.19,52.06 CPU1.AY29
M_A_DQ51: length 55.4
  TOP w0.089: v2(70.2,28.52) 69.95,28.26 v1(69.95,27.88)
  L3 w0.127: v1(69.95,27.88) 70.33,27.5 70.73,27.5 70.74,27.49 71.6,27.49 72.23,28.12 72.63,28.12 72.76,27.99 72.76,27.62 72.89,27.49 73.14,27.49 73.27,27.62 73.27,27.99 73.39,28.12 73.65,28.12 73.78,27.99 73.78,27.62 73.9,27.49 74.16,27.49 74.28,27.62 74.28,27.99 74.41,28.12 81.21,28.12 92.26,39.17 93.07,39.17 93.43,39.53 93.43,40.45 94.28,41.3 94.28,41.78 96.92,44.43 96.92,48.81 98.59,50.47 102.83,50.47 104.77,52.42 v1(105.81,52.42)
  BOTTOM w0.089: v1(69.95,27.88) 69.95,27.93 70.51,28.48 DM1.229 ; CPU1.AW29 105.73,52.34 v1(105.81,52.42)
M_A_DQ52: length 53.6
  TOP w0.089: v1(69.35,32.53) 69.69,32.87 v2(69.69,32.98)
  L3 w0.127: v1(69.35,32.53) 69.35,32.04 69.62,31.77 71.46,31.77 71.59,31.64 71.59,31 71.71,30.88 71.97,30.88 72.1,31 72.1,31.64 72.22,31.77 72.48,31.77 72.6,31.64 72.6,31 72.75,30.85 72.96,30.85 73.11,31 73.11,31.64 73.24,31.77 73.49,31.77 73.62,31.64 73.62,31 73.75,30.88 74,30.88 74.13,31 74.13,31.64 74.25,31.77 80.99,31.77 92.44,43.21 92.44,43.75 93.89,45.2 93.89,46.71 95.21,48.03 95.21,49.49 97.83,52.11 98.4,52.11 99.07,52.79 v1(99.13,52.79)
  BOTTOM w0.089: CPU1.BB31 103.05,53.33 100.05,53.33 99.97,53.26 99.6,53.26 v1(99.13,52.79) ; DM1.211 69.82,32.98 69.81,33 v1(69.35,32.53)
M_A_DQ53: length 54.5
  TOP w0.089: v2(98.91,53.38) 98.45,52.92 v1(98.45,52.8)
  L3 w0.127: v1(98.45,52.8) 98.02,52.37 97.61,52.37 94.96,49.71 94.96,48.17 93.66,46.86 93.66,45.47 92.08,43.89 92.08,43.41 80.8,32.13 71.09,32.13 70.24,32.98 69.16,32.98 68.48,32.29 66.95,32.29 66.27,31.61 65.63,31.61 65.33,31.92 65.33,32.48 v1(65.59,32.74)
  BOTTOM w0.089: CPU1.BA31 103.7,53.56 103.52,53.75 103.47,53.79 103.38,53.82 103.35,53.84 103.12,53.84 102.79,53.51 98.68,53.51 98.45,53.28 v1(98.45,52.8) ; v1(65.59,32.74) 65.58,32.73 DM1.212
M_A_DQ54: length 54.6
  TOP w0.089: v1(100.23,51.27) 99.59,50.64 v2(99.13,50.64)
  L3 w0.127: v1(66.32,30.02) 66.32,29.47 66.76,29.04 81.02,29.04 93.71,41.73 93.71,43.22 96.4,45.91 96.4,48.9 98.42,50.92 99.44,50.92 99.79,51.27 v1(100.23,51.27)
  BOTTOM w0.089: CPU1.BA29 103.66,52.06 103.54,51.94 103.03,51.94 102.87,51.78 100.86,51.78 100.35,51.27 v1(100.23,51.27) ; DM1.224 65.21,29.73 65.37,29.58 65.89,29.58 v1(66.32,30.02)
M_A_DQ55: length 53.2
  L3 w0.127: v1(99.29,51.38) 99.06,51.15 98.34,51.15 96.14,48.95 96.14,45.96 93.49,43.31 93.49,42.02 80.87,29.4 69.16,29.4 69.03,29.53 69.03,29.71 68.91,29.84 68.65,29.84 68.53,29.71 68.53,29.53 68.4,29.4 68.03,29.4 67.75,29.68 v1(67.75,30.02)
  BOTTOM w0.089: v1(67.75,30.02) 67.75,29.68 67.94,29.48 DM1.225 ; CPU1.BB29 103.07,52.24 102.78,51.96 v2(100.48,51.96) 100.26,51.96 99.88,51.73 v1(99.29,51.38)
M_A_DQ56: length 59.1
  TOP w0.089: v1(101.24,50.04) 101.24,50.2 v2(101.6,50.56)
  L3 w0.127: v1(69.91,26.26) 70.37,25.8 70.87,25.8 71.25,26.17 79.17,26.17 80.04,27.04 82.09,27.04 86.39,31.34 86.57,31.34 87.08,30.83 87.26,30.83 87.44,31.01 87.44,31.19 86.93,31.7 86.93,31.88 87.11,32.06 87.29,32.06 87.8,31.55 87.98,31.55 88.16,31.73 88.16,31.91 87.65,32.42 87.65,32.6 87.83,32.78 88.01,32.78 88.52,32.27 88.7,32.27 88.88,32.45 88.88,32.63 88.37,33.14 88.37,33.32 88.55,33.5 88.73,33.5 89.24,32.99 89.42,32.99 89.6,33.17 89.6,33.35 89.09,33.86 89.09,34.04 89.34,34.29 90.41,34.29 95.78,39.65 95.78,40.97 97.69,42.88 97.69,48.63 98.45,49.39 100.27,49.39 100.29,49.41 100.61,49.41 v1(101.24,50.04)
  BOTTOM w0.089: DM1.237 71.1,26.48 70.89,26.7 70.34,26.7 v1(69.91,26.26) ; v1(101.24,50.04) 101.65,50.46 102.57,50.46 102.86,50.75 103.33,50.75 103.37,50.77 103.45,50.78 103.7,50.85 103.74,50.86 104.07,50.86 104.23,50.93 104.3,50.99 CPU1.AY27
M_A_DQ57: length 59.6
  TOP w0.089: v1(68.48,26.26) v2(68.48,26.82)
  L3 w0.127: v1(104.93,51.76) 104.61,51.76 102.05,49.2 100.38,49.2 100.35,49.17 98.53,49.17 97.91,48.55 97.91,41.28 91.01,34.39 91.01,33.89 87.38,30.26 85.81,30.26 85.48,29.93 85.48,29.75 85.77,29.46 85.77,29.28 85.59,29.1 85.41,29.1 85.12,29.39 84.94,29.39 82.24,26.69 80.21,26.69 79.34,25.82 74.72,25.82 74.17,25.27 69.47,25.27 v1(68.48,26.26)
  BOTTOM w0.089: v1(68.48,26.26) 68.01,26.73 DM1.236 ; CPU1.AW27 105.24,51.4 104.93,51.71 v1(104.93,51.76)
M_A_DQ58: length 58.4
  TOP w0.089: v1(69.91,23.14) v2(69.91,23.7)
  L3 w0.127: v1(69.91,23.14) 70.35,22.69 73.09,22.69 73.21,22.82 73.21,23 73.34,23.13 73.59,23.13 73.72,23 73.72,22.82 73.85,22.69 74.1,22.69 74.23,22.82 74.23,23 74.36,23.13 74.61,23.13 74.74,23 74.74,22.82 74.86,22.69 75.28,22.69 75.44,22.85 77.76,22.85 77.89,22.98 77.89,23.79 78.01,23.92 78.27,23.92 78.4,23.79 78.4,22.98 78.52,22.85 79.01,22.85 79.25,23.09 79.25,23.93 79.38,24.06 79.63,24.06 79.76,23.93 79.76,23.11 79.89,22.98 80.14,22.98 80.27,23.11 80.27,23.93 81.2,24.86 84.07,24.86 87.65,28.44 88.03,28.44 93.17,33.57 93.17,34.03 99.27,40.13 99.27,46.33 100.94,48 101.24,48 101.67,48.43 v1(101.67,48.68)
  BOTTOM w0.089: v1(101.67,48.68) 101.78,48.68 102,48.91 102.73,48.91 103.2,49.38 103.81,49.57 104.15,49.57 104.15,49.57 104.23,49.61 CPU1.AY25 ; DM1.249 71.13,23.48 71.03,23.59 70.36,23.59 v1(69.91,23.14)
M_A_DQ59: length 59.2
  TOP w0.089: v2(104.29,49.7) 104.54,49.45 v1(104.87,49.45)
  L3 w0.127: v1(104.87,49.45) 102.2,46.78 101.24,46.78 100.87,46.41 99.93,46.41 99.52,45.99 99.52,39.87 93.99,34.35 93.99,32.99 93.15,32.15 92.26,32.15 88.19,28.08 87.81,28.08 84.22,24.5 82.4,24.5 80.23,22.34 78.64,22.34 78.48,22.5 75.69,22.5 75.53,22.34 68.2,22.34 68.07,22.21 68.07,21.94 67.94,21.81 67.69,21.81 67.56,21.94 67.56,22.21 67.43,22.34 66.46,22.34 v1(65.59,23.21)
  BOTTOM w0.089: CPU1.AW25 105.24,49.82 v1(104.87,49.45) ; v1(65.59,23.21) 65.56,23.23 64.15,23.23 DM1.250
M_A_DQ60: length 57.3
  L3 w0.127: v1(66.32,28.19) 66.77,28.64 67.92,28.64 68.26,28.29 68.26,27.84 68.97,27.14 74.33,27.14 74.95,27.76 75.31,27.76 75.44,27.64 75.44,27.01 75.56,26.88 75.82,26.88 75.94,27.01 75.94,27.64 76.07,27.76 76.33,27.76 76.45,27.64 76.45,27.01 76.58,26.88 76.83,26.88 76.96,27.01 76.96,27.64 77.09,27.76 81.35,27.76 91.15,37.56 92.09,37.56 94.76,40.24 94.76,41.95 97.15,44.34 97.15,48.74 98.47,50.05 v1(99.11,50.05)
  BOTTOM w0.089: v1(99.11,50.05) 99.11,50.28 99.49,50.66 v2(99.79,50.66) 100.94,50.66 101.09,50.82 102.41,50.82 102.72,51.12 102.72,51.12 102.73,51.13 103.2,51.13 CPU1.BB27 ; DM1.232 65.87,27.73 v1(66.32,28.19)
M_A_DQ61: length 58.2
  TOP w0.089: v2(100.35,50.61) 100.6,50.37 v1(100.6,50.07)
  L3 w0.127: v1(67.74,28.19) 67.51,27.96 67.51,27.29 68.07,26.73 75.16,26.73 75.36,26.53 77.4,26.53 77.52,26.65 77.52,27.17 77.65,27.3 77.9,27.3 78.03,27.17 78.03,26.65 78.16,26.53 78.82,26.53 79.71,27.41 81.5,27.41 81.55,27.41 91.34,37.21 92.23,37.21 95.36,40.34 95.36,40.86 97.47,42.96 97.47,48.75 98.35,49.62 100.16,49.62 v1(100.6,50.07)
  BOTTOM w0.089: DM1.233 71.03,27.48 71,27.46 68.29,27.46 67.74,28.01 v1(67.74,28.19) ; CPU1.BA27 103.63,51.01 103.31,50.93 102.78,50.93 102.49,50.64 101.17,50.64 v1(100.6,50.07)
M_A_DQ62: length 57.8
  TOP w0.089: v1(68.48,23.14) v2(68.48,23.7)
  L3 w0.127: v1(101.06,48.4) 101.04,48.4 99.05,46.42 99.05,40.42 92.8,34.17 92.8,33.73 87.88,28.8 87.49,28.8 83.9,25.21 80.84,25.21 80.03,24.41 76.54,24.41 76.41,24.28 76.41,23.79 76.29,23.66 76.03,23.66 75.91,23.79 75.91,24.28 75.78,24.41 75.42,24.41 75.3,24.29 75.3,23.63 75.09,23.42 74.86,23.42 74.7,23.58 73.11,23.58 72.71,23.18 71.46,23.18 71,23.64 68.76,23.64 68.48,23.37 v1(68.48,23.14)
  BOTTOM w0.089: CPU1.BA25 103.58,49.69 103.13,49.55 103.11,49.54 102.66,49.09 101.27,49.09 101.06,48.88 101.06,48.41 v1(101.06,48.4) ; v1(68.48,23.14) 68.48,23.8 69.17,24.48 DM1.245
M_A_DQ63: length 57.2
  TOP w0.089: v1(67.01,23.22) 66.66,23.56 v2(66.66,23.65)
  L3 w0.127: v1(67.01,23.22) 67.8,24.01 74.52,24.01 75.28,24.77 79.87,24.77 80.67,25.57 83.76,25.57 83.82,25.64 83.82,25.82 83.51,26.13 83.51,26.31 83.69,26.49 83.87,26.49 84.11,26.25 84.29,26.25 84.47,26.43 84.47,26.61 84.3,26.78 84.3,26.96 84.48,27.13 84.66,27.13 84.9,26.9 85.08,26.9 87.42,29.23 87.81,29.23 92.32,33.75 92.32,34.2 98.8,40.68 98.8,46.55 100.55,48.29 v1(100.55,48.79)
  BOTTOM w0.089: v1(67.01,23.22) 65.99,24.23 DM1.246 ; CPU1.BB25 103.15,49.88 102.54,49.27 101.03,49.27 v1(100.55,48.79)
M_A_DQS_DN0: length 59.9
  L3 w0.14: v1(68.55,84.65) 68.55,84.88 69.16,85.49 72.74,85.49 75.34,88.08 87.03,88.08 87.72,88.77 88.32,88.77 88.61,88.49 88.61,88.22 88.75,88.08 89.03,88.08 89.17,88.22 89.17,88.49 89.46,88.77 91.25,88.77 91.54,88.49 91.54,88.22 91.68,88.08 91.96,88.08 92.1,88.22 92.1,88.49 92.39,88.77 92.88,88.77 93.17,88.49 93.17,88.22 93.31,88.08 93.59,88.08 93.73,88.22 93.73,88.49 94.02,88.77 94.51,88.77 94.79,88.49 94.79,88.22 94.93,88.08 95.21,88.08 95.35,88.22 95.35,88.49 95.64,88.77 103.96,88.77 109.09,83.64 v1(109.09,82.77)
  BOTTOM w0.089: v1(68.55,84.65) 68.55,84.82 69.04,85.31 70.34,85.31 70.46,85.2 70.46,85.2 70.67,84.98 DM1.11 ; 109.11,80.13 109.11,78.21 109.15,77.86 109.15,77.54 109.18,77.5 109.18,77.24 109.22,77.17 109.22,76.9 109.18,76.79 109.18,76.61 109.24,76.43 109.24,76.25 CPU1.AM70 ; 109.11,80.13 109.11,82 109.07,82.04 109.07,82.75 v1(109.09,82.77) ; 109.11,80.13 v2(109.27,80.13)
M_A_DQS_DN1: length 55
  TOP w0.089: v2(107.31,79.25) v1(106.68,79.24)
  L3 w0.14: v1(106.68,79.24) 106.39,79.24 106.31,79.32 106.08,79.55 105.21,79.55 105.02,79.37 99.92,79.37 98.58,80.72 98.58,82.19 96.44,84.33 82.41,84.33 82.04,83.95 81.79,83.7 76.25,83.7 74.11,81.56 73.23,81.56 71.06,79.39 68.65,79.39 68.22,79.82 68.22,80.46 67.59,81.1 66.78,81.1 66.17,80.48 v1(66.17,79.98)
  BOTTOM w0.089: DM1.32 65,79.73 65.14,79.59 65.78,79.59 v1(66.17,79.98) ; CPU1.AT69 106.7,76.04 106.7,76.42 106.65,76.6 106.65,76.79 106.69,76.96 106.69,77.2 106.21,77.68 106.21,78.63 v1(106.68,79.24)
M_A_DQS_DN2: length 49
  TOP w0.089: v2(93.9,80.84) 94.54,80.84 v1(94.97,80.41)
  L3 w0.14: v1(94.97,80.41) 95.12,80.26 95.12,80.1 94.98,79.96 93.62,79.96 93.48,80.1 93.48,80.27 93.19,80.56 92.7,80.56 92.41,80.27 92.41,80.1 92.27,79.96 77.62,79.96 72.35,74.69 69.77,74.69 69.44,74.37 69.44,73.79 v1(69.17,73.52)
  BOTTOM w0.089: v1(69.17,73.52) 69.43,73.78 69.43,73.99 69.77,74.32 71.28,74.32 71.45,74.48 DM1.53 ; v1(94.97,80.41) 95.25,80.13 95.25,79.62 95.01,79.38 95.01,79.1 95.25,78.86 95.53,78.86 95.82,79.16 95.95,79.16 96.44,78.67 97.24,78.67 100.71,75.2 100.71,74.36 102.1,72.97 102.83,72.97 102.97,72.82 103.39,72.82 103.54,72.87 103.68,72.87 103.88,72.81 104.06,72.81 CPU1.BA64
M_A_DQS_DN3: length 48.9
  TOP w0.089: v2(98.73,72.48) 98.45,72.76 v1(98.45,73.01)
  L3 w0.14: v1(98.45,73.01) 98.63,73.19 98.63,73.75 97.17,75.21 92.88,75.21 92.88,75.21 79.03,75.21 74.07,70.25 73.45,70.25 71.75,68.55 67.16,68.55 66.6,69.11 66.6,69.43 v1(66.4,69.63)
  BOTTOM w0.089: DM1.74 65.04,69.23 65.2,69.07 66,69.07 66.4,69.48 v1(66.4,69.63) ; v1(98.45,73.01) 98.45,72.41 98.76,72.09 99.78,72.09 101.66,70.21 102.46,70.21 102.81,69.85 103.36,69.85 103.51,69.81 103.71,69.81 103.91,69.87 104.54,69.87 CPU1.AY60
M_A_DQS_DN4: length 51.9
  TOP w0.089: v2(69.01,41.47) 69.01,41.14 v1(69.21,40.94)
  L3 w0.14: v1(69.21,40.94) 69.21,41.29 69.87,41.95 70.79,41.95 72.28,40.46 78.58,40.46 81.22,43.1 81.62,43.1 82.98,44.46 83.39,44.46 83.54,44.32 83.73,44.32 83.93,44.51 83.93,44.71 83.74,44.9 83.74,45.29 84.11,45.66 84.5,45.66 84.69,45.47 84.88,45.47 85.08,45.66 85.08,45.86 84.94,46.01 84.94,46.42 85.49,46.97 85.49,48.6 89.48,52.59 91.27,54.39 91.59,54.39 91.59,54.39 93.44,54.39 96.6,57.55 98.79,57.55 99.45,56.88 100.45,56.88 100.63,57.07 100.63,58.39 v1(100.61,58.41)
  BOTTOM w0.089: DM1.177 71.12,41.48 70.97,41.63 69.89,41.63 69.21,40.96 v1(69.21,40.94) ; CPU1.BA38 103.98,58.09 103.88,58.09 103.69,58.14 103.52,58.14 103.39,58.11 102.91,58.11 102.72,57.98 102.69,57.95 101.01,57.95 100.61,58.35 v1(100.61,58.41)
M_A_DQS_DN5: length 57.1
  TOP w0.089: v2(99.19,54.7) 98.91,54.42 v1(98.91,54.19)
  L3 w0.089: 96.81,53.77 97,53.97 98.52,53.97 98.75,54.19 v1(98.91,54.19)
  L3 w0.14: 96.81,53.77 93.06,50.02 92.49,50.02 89.4,46.93 89.4,44.65 80.18,35.42 79.17,35.42 79.03,35.28 79.03,34.7 78.74,34.41 78.25,34.41 77.96,34.7 77.96,35.28 77.82,35.42 77.54,35.42 77.4,35.28 77.4,34.7 77.12,34.41 76.62,34.41 76.34,34.7 76.34,35.28 76.2,35.42 74.74,35.42 74.22,34.9 74.21,34.9 73.69,34.38 73.03,34.38 71.5,35.91 68.62,35.91 v1(67.92,36.6)
  BOTTOM w0.089: CPU1.AY34 104.29,55.14 103.91,55.14 103.71,55.08 103.51,55.08 103.36,55.13 103.3,55.13 103.3,55.12 103.13,55.12 103.11,55.1 103,55.1 102.93,55.03 101.62,55.03 101.49,55.16 99.87,55.16 v1(98.91,54.19) ; DM1.198 65.03,36.23 65.09,36.17 66.11,36.17 66.32,35.97 66.32,35.53 66.42,35.43 66.57,35.43 66.67,35.53 66.67,35.97 66.87,36.17 67.51,36.17 67.92,36.58 v1(67.92,36.6)
M_A_DQS_DN6: length 54.8
  TOP w0.089: v2(69,31.05) 69.19,30.86 v1(69.19,30.53)
  L3 w0.14: v1(69.19,30.53) 69.19,30.35 69.76,29.79 75.16,29.79 75.45,30.07 75.45,30.33 75.59,30.47 75.87,30.47 76.01,30.33 76.01,30.07 76.3,29.79 77.02,29.79 77.31,30.07 77.31,30.37 77.45,30.51 77.73,30.51 77.87,30.37 77.87,30.07 78.16,29.79 78.65,29.79 78.94,30.07 78.94,30.37 79.08,30.51 79.36,30.51 79.5,30.37 79.5,30.07 79.79,29.79 80.71,29.79 93.27,42.34 93.27,43.4 95.91,46.05 95.91,49.22 98.11,51.41 98.7,51.41 99.15,51.86 101.03,51.86 101.38,52.21 101.38,52.45 v1(101.67,52.75)
  BOTTOM w0.089: v1(69.19,30.53) 69.48,30.81 69.48,30.91 69.71,31.15 70.94,31.15 71.1,30.98 DM1.219 ; CPU1.BA30 104.06,52.7 103.88,52.7 103.68,52.63 103.54,52.63 103.39,52.68 102.99,52.68 102.77,52.46 102.64,52.34 101.84,52.34 101.67,52.5 v1(101.67,52.75)
M_A_DQS_DN7: length 58.5
  L3 w0.14: v1(66.35,26.26) 66.5,26.12 66.5,25.14 67.23,24.4 74.36,24.4 75.14,25.18 79.72,25.18 80.52,25.98 82.43,25.98 84.23,27.77 85.37,27.77 87.22,29.62 87.65,29.62 91.93,33.91 91.93,34.36 98.5,40.93 98.5,47.04 99.51,48.05 v1(99.51,48.71)
  BOTTOM w0.089: v1(99.51,48.71) 99.44,48.78 99.44,49.26 99.63,49.46 99.97,49.46 ; v1(66.35,26.26) 66.35,26 65.93,25.58 65.11,25.58 64.96,25.73 DM1.240 ; CPU1.AY26 104.63,50.16 103.91,50.16 103.71,50.1 103.51,50.1 103.36,50.15 103.12,50.15 102.43,49.46 99.97,49.46 ; 99.97,49.46 v2(99.97,49.29)
M_A_DQS_DP0: length 60
  L3 w0.14: v1(108.58,83.23) 108.68,83.23 108.84,83.38 108.84,83.54 103.86,88.52 95.75,88.52 95.61,88.38 95.61,88.12 95.32,87.83 94.83,87.83 94.54,88.12 94.54,88.38 94.4,88.52 94.12,88.52 93.98,88.38 93.98,88.12 93.69,87.83 93.2,87.83 92.91,88.12 92.91,88.38 92.77,88.52 92.49,88.52 92.36,88.38 92.36,88.12 92.07,87.83 91.58,87.83 91.29,88.12 91.29,88.38 91.15,88.52 89.56,88.52 89.42,88.38 89.42,88.12 89.13,87.83 88.64,87.83 88.36,88.12 88.36,88.38 88.22,88.52 87.82,88.52 87.13,87.83 75.44,87.83 72.84,85.23 69.27,85.23 69.06,85.02 69.06,84.8 v1(69.21,84.65)
  BOTTOM w0.089: CPU1.AM69 109.45,75.55 109.06,76.05 109.06,76.4 109.01,76.59 109.01,76.82 109.04,76.93 109.04,77.13 109.01,77.2 109.01,77.41 108.96,77.46 108.96,77.84 108.94,78.02 108.92,78.2 108.92,81.42 ; DM1.13 71.31,84.48 71,84.79 70.59,84.79 70.38,85.01 70.38,85.01 70.26,85.12 69.12,85.12 68.97,84.97 68.97,84.78 69.1,84.65 v1(69.21,84.65) ; v1(108.58,83.23) 108.59,83.22 108.59,82.67 108.88,82.38 108.88,81.96 108.92,81.92 108.92,81.42 ; 108.92,81.42 v2(108.74,81.42)
M_A_DQS_DP1: length 54.9
  TOP w0.089: v1(66.86,80) v2(66.86,80.56)
  L3 w0.14: v1(66.86,80) 66.78,80 66.6,80.18 66.6,80.56 66.88,80.84 67.48,80.84 67.97,80.35 67.97,79.72 68.55,79.14 71.17,79.14 73.34,81.31 74.22,81.31 76.36,83.45 81.89,83.45 82.29,83.84 82.29,83.85 82.52,84.07 96.33,84.07 98.32,82.08 98.32,80.61 99.82,79.11 105.13,79.11 105.31,79.3 105.97,79.3 106.13,79.14 106.13,78.72 106.24,78.6 v1(106.73,78.6)
  BOTTOM w0.089: v1(106.73,78.6) 106.6,78.6 106.4,78.41 106.4,77.76 106.88,77.28 106.88,76.96 106.87,76.92 106.86,76.91 106.83,76.77 106.83,76.63 106.88,76.44 106.88,76.26 CPU1.AT70 ; v1(66.86,80) 66.93,79.93 66.93,79.65 66.69,79.4 65.16,79.4 64.99,79.23 DM1.34
M_A_DQS_DP2: length 48.3
  TOP w0.089: v2(96.01,79.9) 95.6,80.31 v1(95.6,80.41)
  L3 w0.14: v1(69.88,73.52) 69.7,73.7 69.7,74.26 69.87,74.44 72.46,74.44 77.72,79.7 92.38,79.7 92.66,79.99 92.66,80.17 92.8,80.31 93.08,80.31 93.22,80.17 93.22,79.99 93.51,79.7 95.09,79.7 95.38,79.99 95.38,80.18 v1(95.6,80.41)
  BOTTOM w0.089: CPU1.AY64 104.54,72.99 103.91,72.99 103.71,73.05 103.51,73.05 103.36,73 103.06,73 102.9,73.16 102.18,73.16 100.9,74.44 100.9,75.28 97.32,78.86 96.52,78.86 96.03,79.35 95.75,79.35 95.45,79.05 95.32,79.05 95.2,79.18 95.2,79.3 95.44,79.54 95.44,80.2 95.49,80.25 95.49,80.3 v1(95.6,80.41) ; DM1.55 71.47,73.98 71.33,74.13 69.84,74.13 69.7,73.98 69.7,73.7 v1(69.88,73.52)
M_A_DQS_DP3: length 48.9
  TOP w0.089: v1(99.08,73.05) v2(99.08,73.7)
  L3 w0.14: v1(99.08,73.05) 98.88,73.25 98.88,73.86 97.28,75.46 92.98,75.46 92.98,75.46 78.92,75.46 73.97,70.51 73.35,70.51 71.64,68.8 67.27,68.8 66.99,69.08 66.99,69.51 v1(67.11,69.63)
  BOTTOM w0.089: DM1.76 65.04,68.73 65.19,68.88 66.08,68.88 66.38,69.19 66.98,69.19 67.11,69.32 v1(67.11,69.63) ; CPU1.BA60 104.06,70.05 103.88,70.05 103.68,69.98 103.54,69.98 103.39,70.03 102.91,70.03 102.54,70.4 101.74,70.4 99.86,72.28 98.84,72.28 98.66,72.46 98.66,72.63 v1(99.08,73.05)
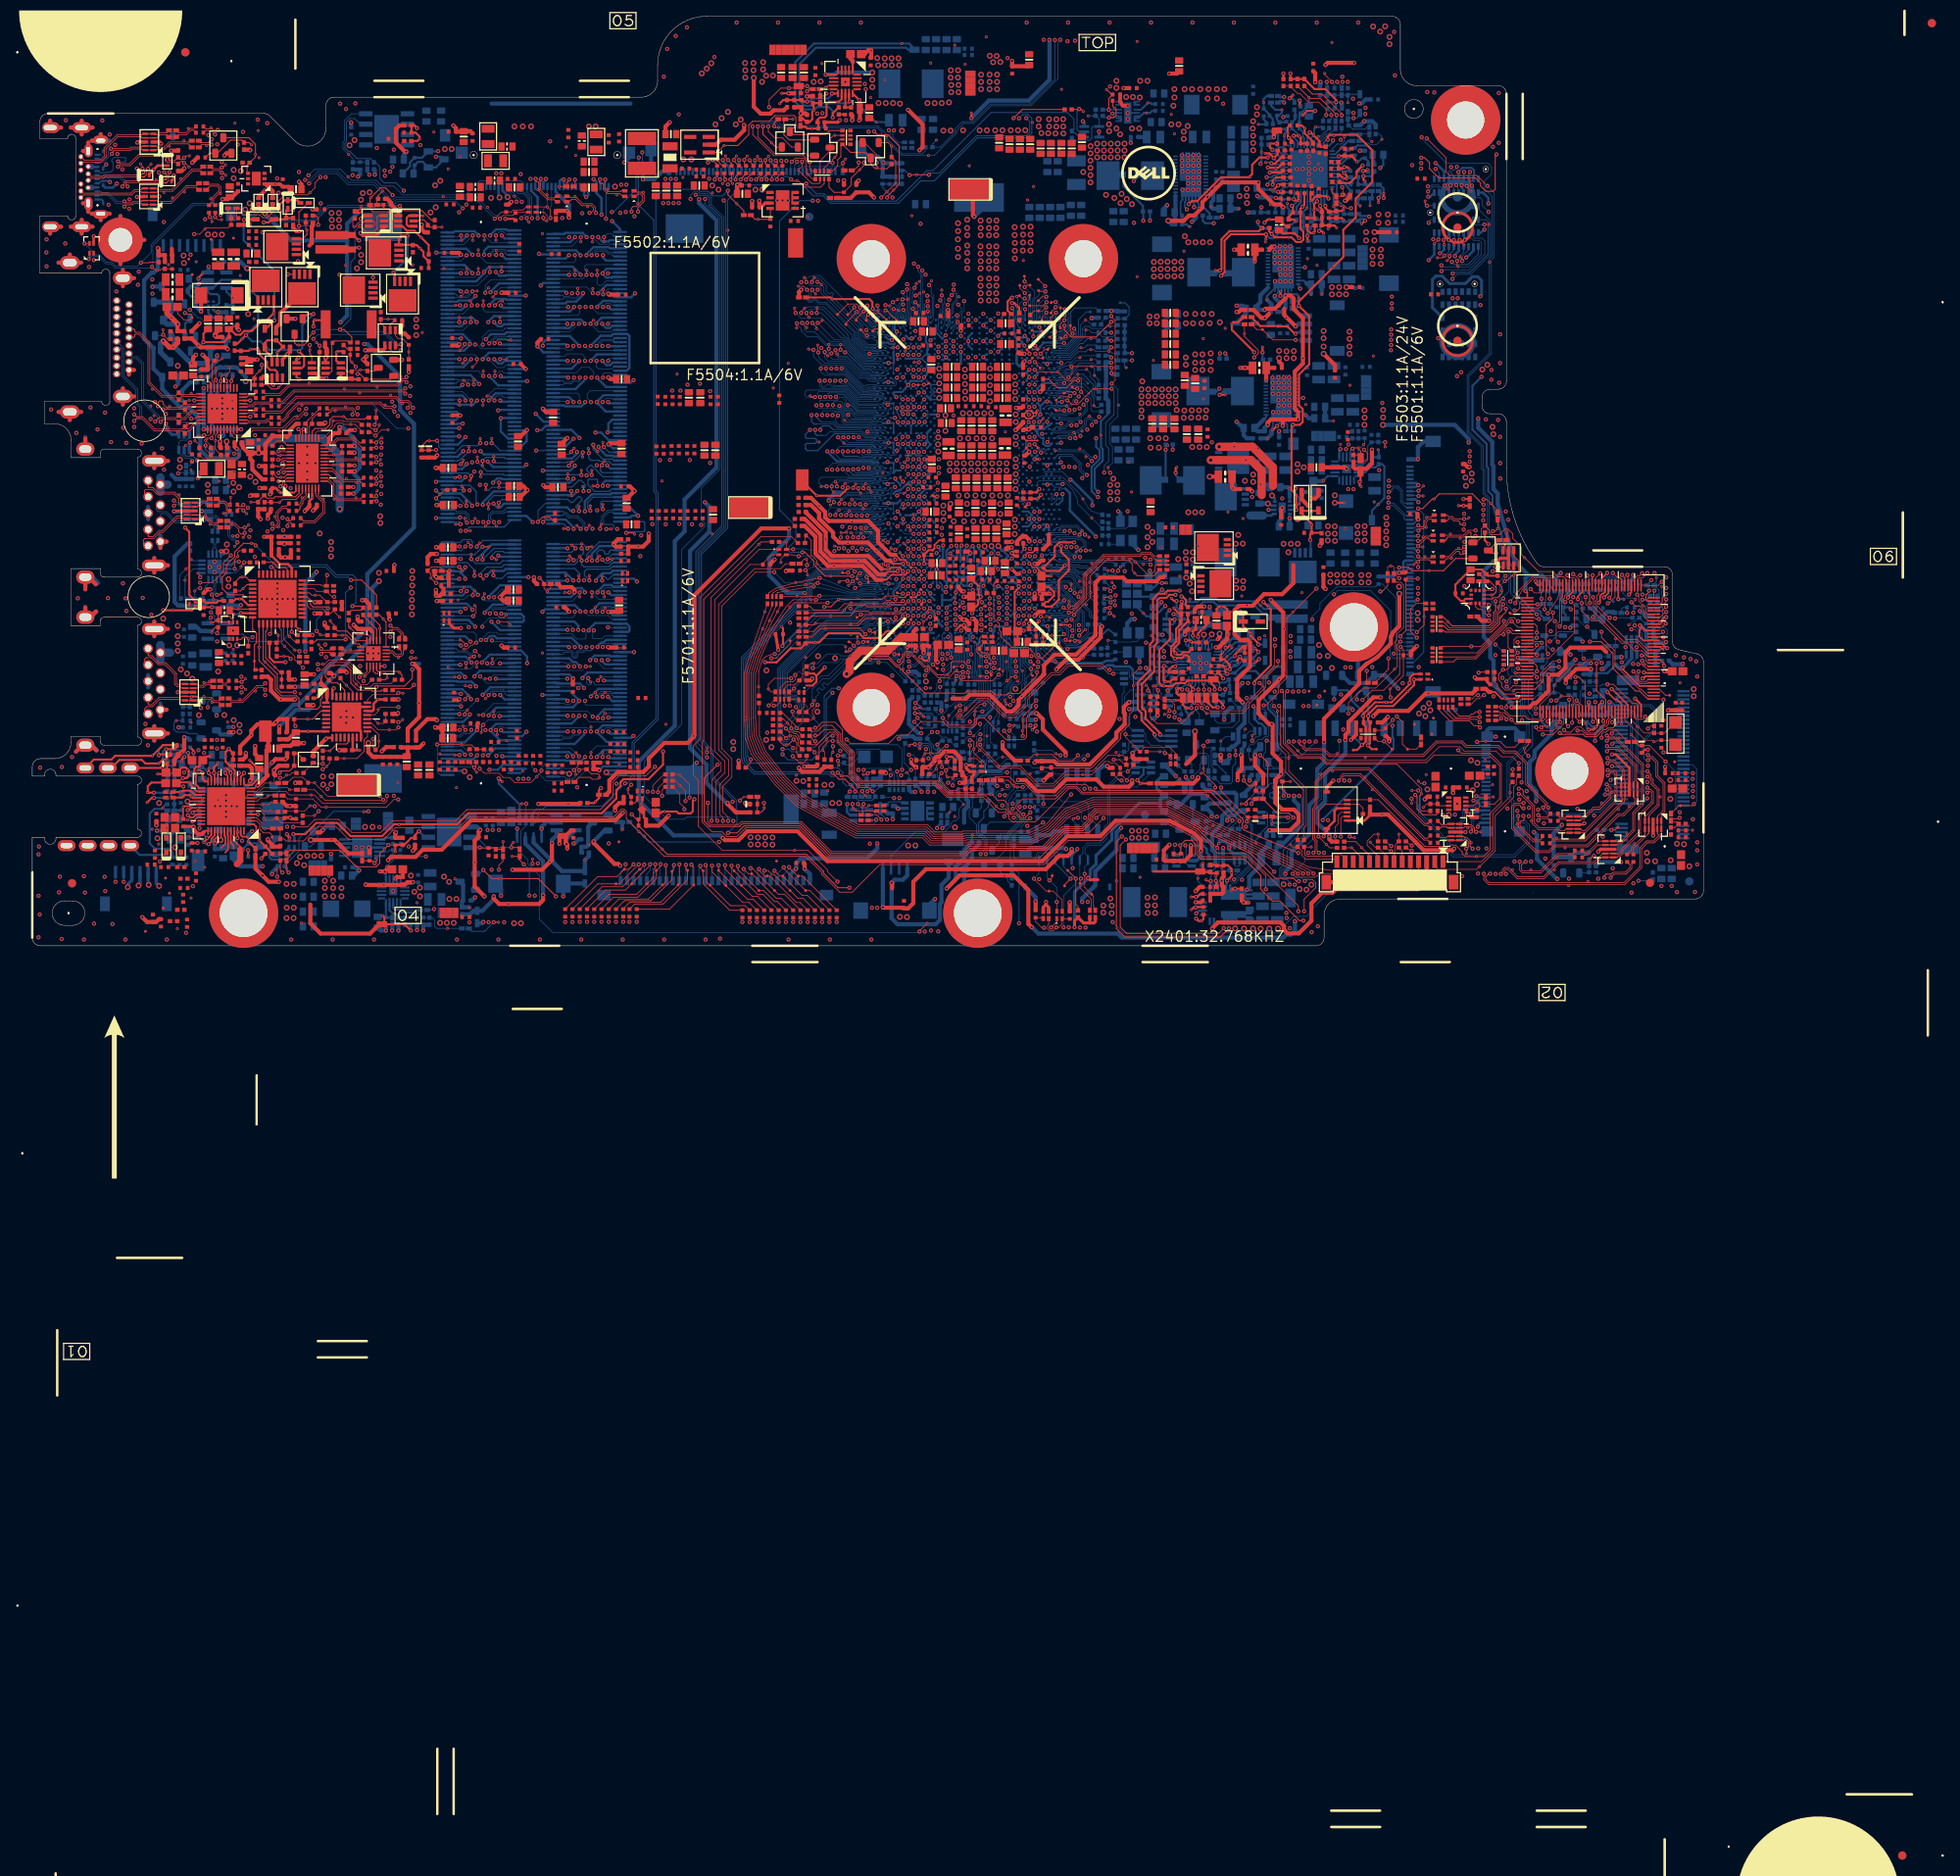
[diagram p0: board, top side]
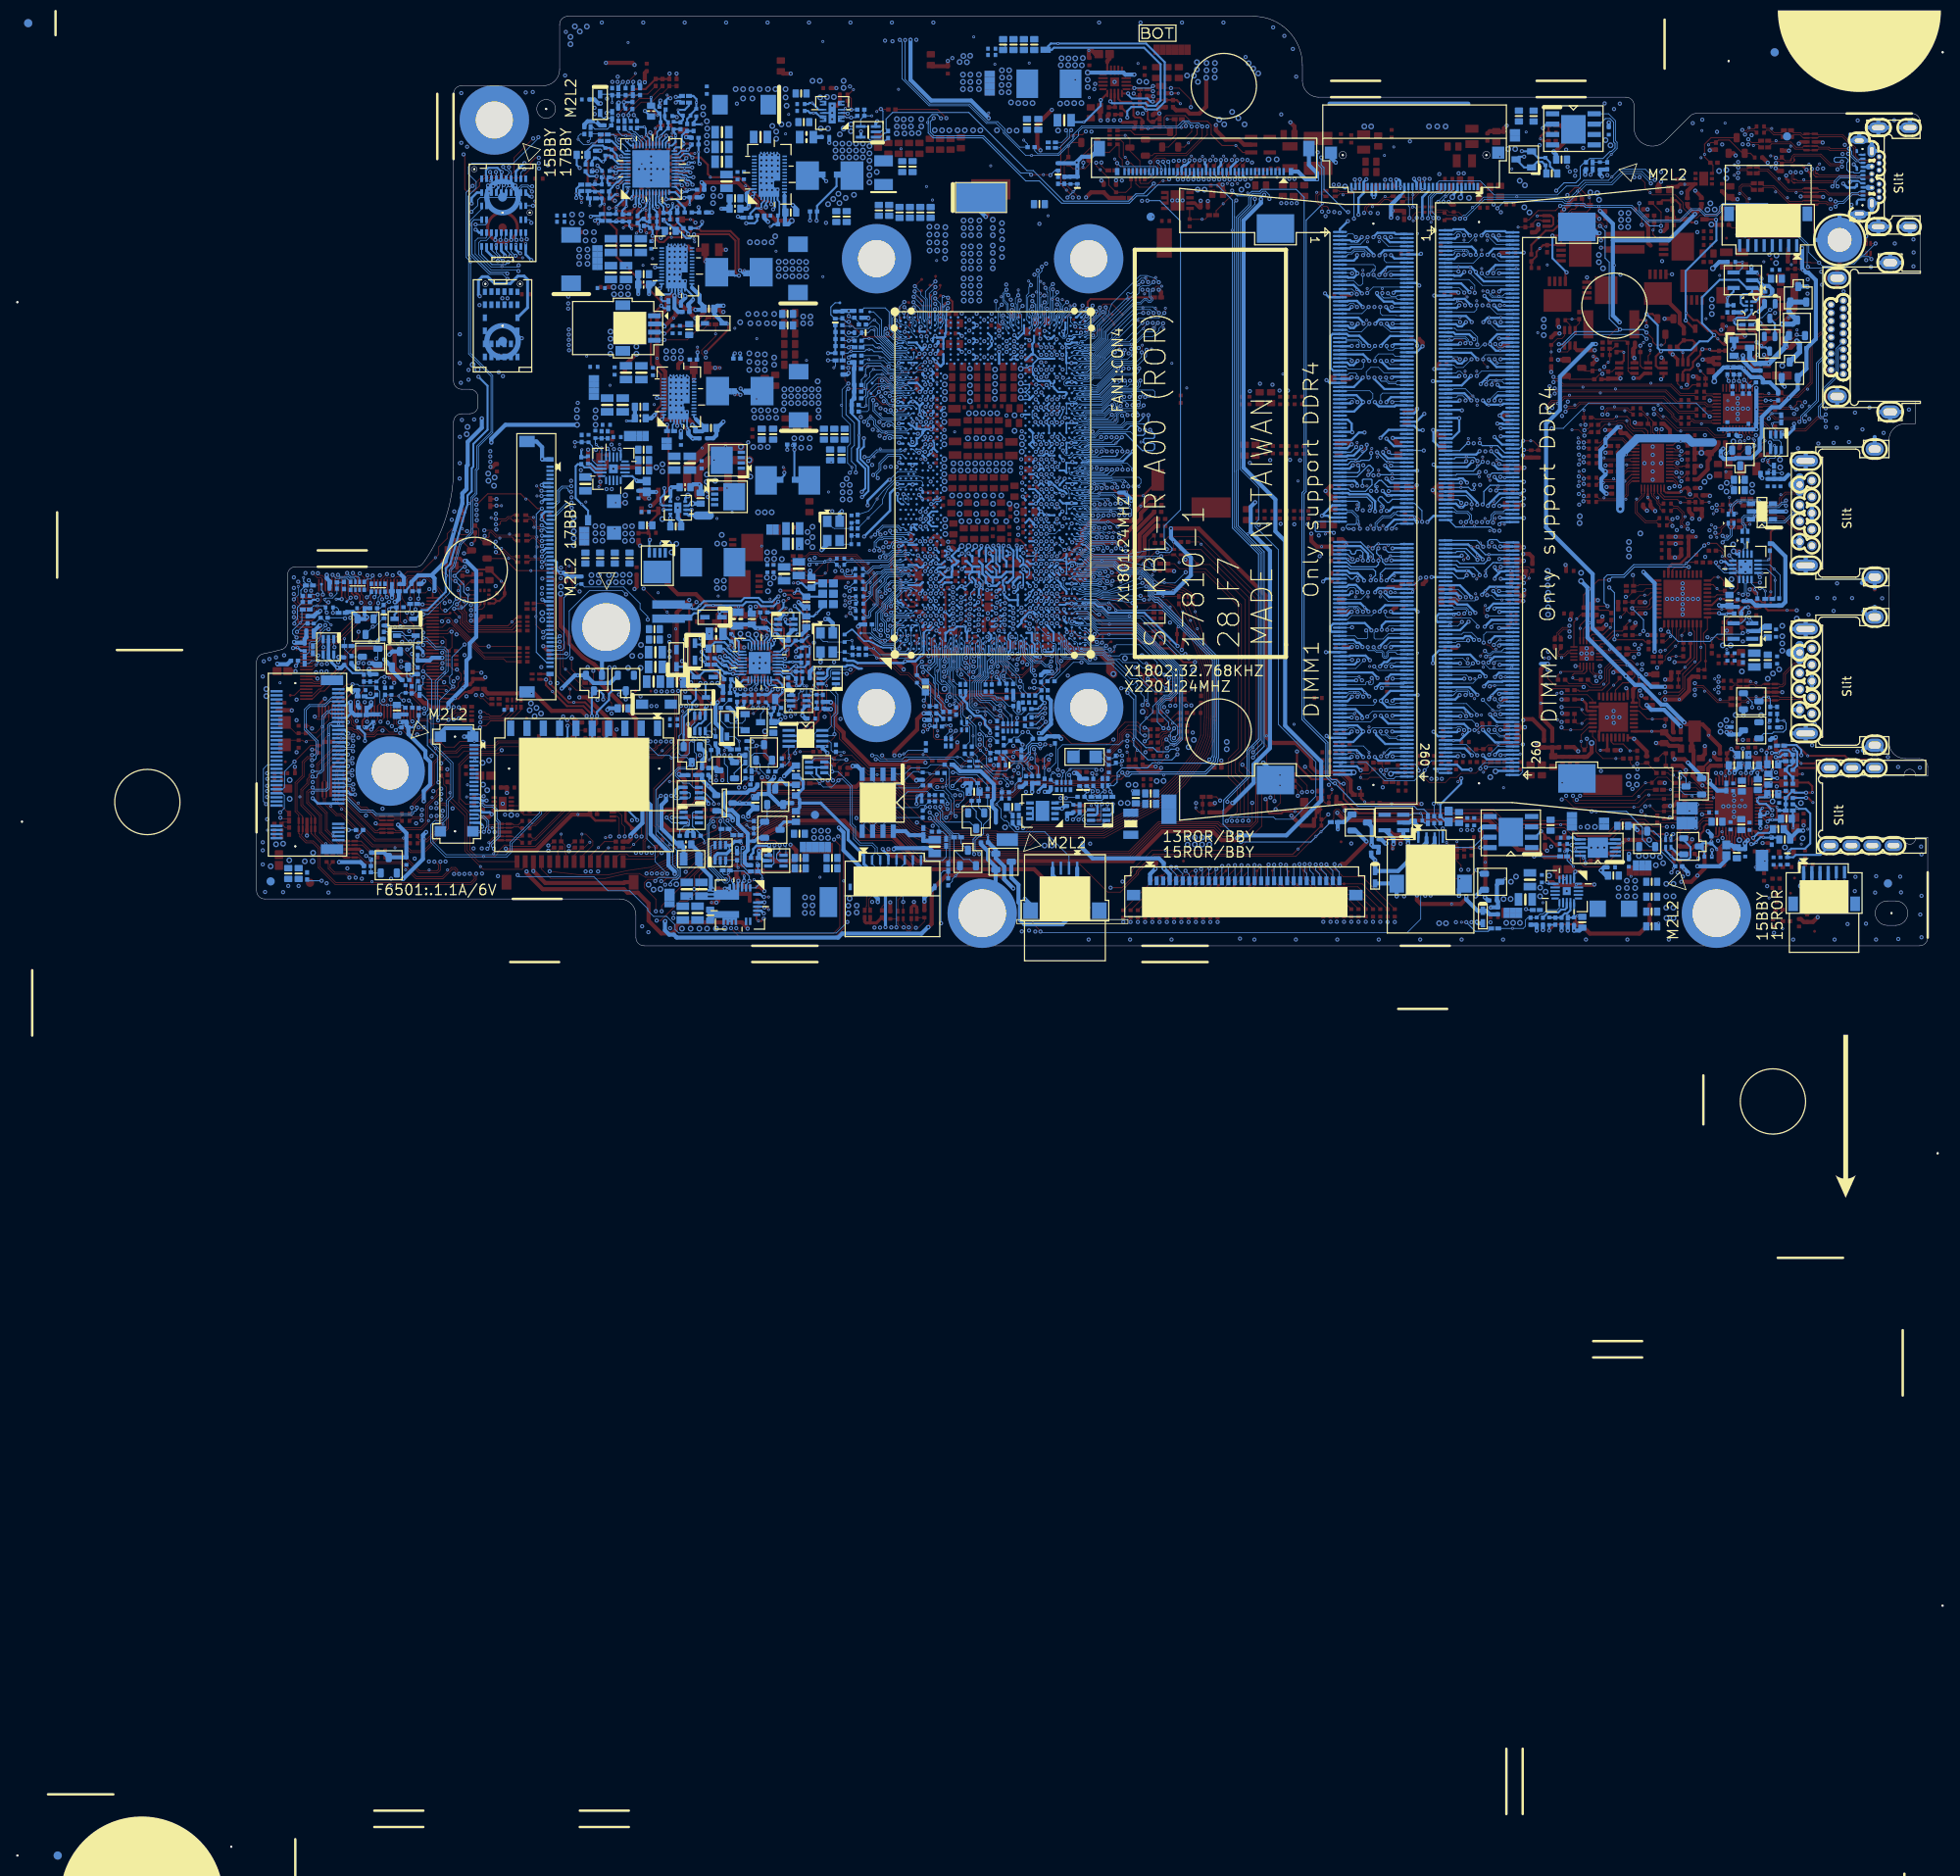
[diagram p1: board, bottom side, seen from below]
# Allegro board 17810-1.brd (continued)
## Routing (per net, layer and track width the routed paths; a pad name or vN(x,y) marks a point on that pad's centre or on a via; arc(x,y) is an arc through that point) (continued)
M_A_DQS_DP4: length 51.8
  TOP w0.089: v2(70.23,41.39) 70.23,41.27 v1(69.9,40.94)
  L3 w0.14: v1(101.24,58.44) 100.89,58.08 100.89,56.96 100.55,56.63 99.35,56.63 98.68,57.29 96.71,57.29 93.54,54.13 91.48,54.13 91.48,54.13 91.38,54.13 89.73,52.48 85.74,48.5 85.74,46.86 85.19,46.31 85.19,46.11 85.34,45.97 85.34,45.56 84.99,45.21 84.58,45.21 84.39,45.4 84.21,45.4 84,45.19 84,45.01 84.19,44.82 84.19,44.41 83.84,44.06 83.43,44.06 83.29,44.21 83.09,44.21 81.73,42.85 81.32,42.85 78.68,40.21 72.18,40.21 70.69,41.7 69.98,41.7 69.67,41.38 69.67,41.04 69.77,40.94 v1(69.9,40.94)
  BOTTOM w0.089: DM1.179 71.35,40.98 70.89,41.44 69.97,41.44 69.8,41.28 69.8,41.03 v1(69.9,40.94) ; v1(101.24,58.44) 101.24,58.33 101.43,58.14 102.61,58.14 102.64,58.17 102.81,58.28 103.37,58.28 103.5,58.32 103.71,58.32 103.91,58.27 104.31,58.27 CPU1.AY38
M_A_DQS_DP5: length 57.3
  TOP w0.089: v2(97.84,54.02) 97.92,54.02 v1(98.27,54.37)
  L3 w0.089: v1(98.27,54.37) 98.27,54.24 98.19,54.16 96.92,54.16 96.8,54.03 96.71,54.03 96.63,53.95
  L3 w0.14: 96.63,53.95 92.95,50.28 92.38,50.28 89.15,47.04 89.15,44.75 80.07,35.68 79.06,35.68 78.78,35.39 78.78,34.81 78.64,34.67 78.36,34.67 78.22,34.81 78.22,35.39 77.93,35.68 77.44,35.68 77.15,35.39 77.15,34.81 77.01,34.67 76.73,34.67 76.59,34.81 76.59,35.39 76.3,35.68 74.63,35.68 74.11,35.15 74.11,35.15 73.59,34.63 73.13,34.63 71.6,36.16 68.76,36.16 68.64,36.29 v1(68.64,36.6)
  BOTTOM w0.089: v1(98.27,54.37) 98.26,54.37 98.13,54.5 98.13,54.68 98.26,54.8 99.25,54.8 99.79,55.35 101.57,55.35 101.69,55.22 102.85,55.22 102.92,55.29 103,55.29 103.02,55.31 103.39,55.31 103.54,55.26 103.68,55.26 103.88,55.32 104.06,55.32 CPU1.BA34 ; DM1.200 65.02,35.73 65.27,35.98 66.04,35.98 66.12,35.89 66.12,35.45 66.34,35.24 66.65,35.24 66.86,35.45 66.86,35.89 66.95,35.98 67.59,35.98 67.79,36.17 68.54,36.17 68.67,36.3 68.67,36.57 v1(68.64,36.6)
M_A_DQS_DP6: length 54.9
  TOP w0.089: v1(69.91,30.53) 69.91,30.74 v2(70.22,31.06)
  L3 w0.14: v1(101.04,52.75) 101.13,52.66 101.13,52.32 100.92,52.11 99.04,52.11 98.6,51.67 98.59,51.67 98.59,51.67 98.01,51.67 95.66,49.32 95.66,46.15 93.01,43.51 93.01,42.45 80.6,30.04 79.89,30.04 79.75,30.18 79.75,30.47 79.46,30.76 78.97,30.76 78.68,30.47 78.68,30.18 78.54,30.04 78.27,30.04 78.13,30.18 78.13,30.47 77.84,30.76 77.35,30.76 77.06,30.47 77.06,30.18 76.92,30.04 76.4,30.04 76.26,30.18 76.26,30.44 75.97,30.73 75.48,30.73 75.2,30.44 75.2,30.18 75.06,30.04 70,30.04 69.83,30.21 69.83,30.46 v1(69.91,30.53)
  BOTTOM w0.089: v1(69.91,30.53) 69.79,30.53 69.67,30.66 69.67,30.83 69.79,30.96 70.86,30.96 71.33,30.48 DM1.221 ; v1(101.04,52.75) 101.04,52.72 101.07,52.69 101.07,52.69 101.61,52.15 102.72,52.15 102.9,52.33 103.08,52.5 103.36,52.5 103.51,52.46 103.71,52.46 103.91,52.52 104.29,52.52 104.45,52.67 CPU1.AY30
M_A_DQS_DP7: length 59
  TOP w0.089: v2(98.35,48.99) 98.57,48.99 v1(98.87,48.69)
  L3 w0.14: v1(98.87,48.69) 99.25,48.31 99.25,48.15 98.25,47.14 98.25,41.03 91.68,34.47 91.68,34.01 87.54,29.87 87.11,29.87 85.27,28.03 84.13,28.03 82.33,26.23 80.41,26.23 79.61,25.43 75.03,25.43 74.25,24.65 67.34,24.65 66.75,25.24 66.75,25.95 v1(67.06,26.26)
  BOTTOM w0.089: v1(67.06,26.26) 67.06,25.95 66.94,25.83 66.45,25.83 66.01,25.39 65.12,25.39 64.96,25.23 DM1.242 ; v1(98.87,48.69) 99.25,49.06 99.25,49.34 99.55,49.65 102.35,49.65 103.03,50.33 103.39,50.33 103.54,50.28 103.68,50.28 103.88,50.34 104.06,50.34 CPU1.BA26
M_A_PARITY: length 49.9
  TOP w0.152: v2(73.83,50.46) 73.69,50.61 v1(72.8,50.61)
  L3 w0.089: v1(107.36,65.17) 107.36,65.32 107.12,65.57 106.2,65.57 106.15,65.52 105.65,65.52 105.64,65.5 105.62,65.5 104.97,64.86 104.78,64.86 104.26,64.34 104.26,64.34 103.29,63.37 102.95,63.37 102.77,63.2 102.77,62.66 102.39,62.27 101.95,62.27 101.42,62.81 98.02,62.81 97.76,62.55
  L3 w0.203: 97.76,62.55 97.67,62.45 94.85,62.45 94.16,61.77 88.21,61.77 82.29,55.86 81.22,55.86 77.5,52.14 77.44,52.14 77.44,52.14 77.23,52.14 76.21,51.11 75.26,51.11 75.05,50.91 74.16,50.91 73.9,50.64 72.84,50.64 v1(72.8,50.61)
  BOTTOM w0.152: DM1.143 72.54,51.98 74.95,51.98 75.07,51.86 75.07,50.86 74.96,50.75 72.93,50.75 72.8,50.62 v1(72.8,50.61) ; CPU1.AT52 107.16,65.57 107.36,65.37 v1(107.36,65.17)
M_B_A0: length 67.1
  TOP w0.152: v2(51.9,51.66) v1(52.49,51.66)
  L6 w0.165: v1(95.96,63.24) 95.93,63.24 95.24,62.55 92.78,62.55 92.67,62.44 84.19,62.44 80.81,59.06 80.11,59.06 77.28,56.23 75.16,56.23 74.12,55.19 73.07,55.19 71.88,53.99 69.18,53.99 69.01,53.82 66.12,53.82 65.54,53.24 53.55,53.24 53.29,52.98 50.52,52.98 50.32,52.77 50.32,50.85 50.52,50.65 51.03,50.65 51.23,50.84 51.23,51.99 51.43,52.19 51.96,52.19 v1(52.49,51.66)
  BOTTOM w0.089: 96.85,62.56 97.29,62.56 97.74,63.02 101.56,63.02 102.15,62.43 103.37,62.43 103.7,62.35 103.7,62.35 CPU1.BA46
  BOTTOM w0.152: v1(52.49,51.66) 52.49,51.76 52.32,51.94 DM2.144 ; v1(95.96,63.24) 95.96,62.76 96.16,62.56 96.85,62.56
M_B_A1: length 68.2
  TOP w0.152: v2(57.17,53.74) v1(57.17,54.3)
  L6 w0.165: v1(96.59,63.24) 95.83,64 95.07,64 94.45,63.38 94.22,63.38 94.06,63.55 94.06,63.94 93.89,64.1 93.56,64.1 93.39,63.94 93.39,63.55 93.23,63.38 92.9,63.38 92.73,63.55 92.73,63.94 92.57,64.1 92.24,64.1 92.07,63.94 92.07,63.55 91.91,63.38 91.58,63.38 91.41,63.55 91.41,63.94 91.25,64.1 90.92,64.1 90.75,63.94 90.75,63.55 90.59,63.38 90.26,63.38 90.09,63.55 90.09,63.94 89.93,64.1 89.6,64.1 89.43,63.94 89.43,63.55 89.27,63.38 88.94,63.38 88.77,63.55 88.77,63.94 88.61,64.1 88.28,64.1 88.11,63.94 88.11,63.55 87.95,63.38 87.62,63.38 87.45,63.55 87.45,63.94 87.29,64.1 86.96,64.1 86.79,63.94 86.79,63.55 86.63,63.38 83.58,63.38 83.27,63.69 82.92,63.69 82.61,63.38 82.22,63.38 81.02,62.19 81.02,61.93 80.7,61.61 80.4,61.61 80.2,61.41 80.2,61.11 78.89,59.8 78.89,59.18 78.29,58.58 77.28,58.58 77.12,58.41 77.12,58.07 76.93,57.88 76.65,57.88 76.46,58.07 76.46,58.41 76.29,58.58 76.03,58.58 75.69,58.24 75.69,58.01 76.01,57.69 76.01,57.46 75.77,57.23 75.54,57.23 75.22,57.54 74.99,57.54 74.79,57.35 73.9,57.35 71.51,54.95 68.81,54.95 68.62,54.76 65.74,54.76 65.74,54.76 65.14,54.76 64.9,55 64.71,55 64.54,54.84 64.54,54.39 64.38,54.22 64.05,54.22 63.88,54.39 63.88,54.84 63.72,55 63.39,55 63.22,54.84 63.22,54.39 63.06,54.22 62.73,54.22 62.56,54.39 62.56,54.84 62.4,55 60.86,55 60.25,55.62 59.96,55.62 59.46,55.12 59.46,54.37 59.26,54.18 57.29,54.18 v1(57.17,54.3)
  BOTTOM w0.089: 98.17,63.26 101.57,63.26 102.22,62.61 103.39,62.61 103.58,62.56 103.99,62.56 CPU1.AY46
  BOTTOM w0.152: 98.17,63.26 97.71,63.72 96.9,63.72 96.59,63.42 v1(96.59,63.24) ; DM2.133 59.1,54.69 57.56,54.69 v1(57.17,54.3)
M_B_A2: length 67.8
  TOP w0.152: v2(53.2,54.5) v1(53.2,53.92)
  L6 w0.165: v1(53.2,53.92) 52.74,53.46 51.64,53.46 51.51,53.59 51.51,54.25 51.9,54.64 53.92,54.64 54.64,55.35 58.36,55.35 59.79,56.78 61.08,56.78 61.92,55.94 64.02,55.94 64.28,56.2 65.01,56.2 65.01,56.21 68.6,56.21 68.91,55.89 71.12,55.89 73.51,58.29 74.4,58.29 76.77,60.65 77.01,60.65 77.35,60.31 77.59,60.31 77.82,60.54 77.82,60.78 77.47,61.12 77.47,61.36 77.7,61.58 78.99,61.58 79.26,61.86 79.26,62.5 80.07,63.31 80.82,63.31 82.26,64.76 82.99,64.76 83.28,65.05 94.51,65.05 94.94,64.62 95.74,64.62 v1(96.16,65.04)
  BOTTOM w0.089: 96.61,64.29 96.72,64.18 98.22,64.18 98.77,63.63 102.55,63.63 102.94,63.24 103.37,63.24 103.5,63.27 103.71,63.27 104.03,63.2 104.46,63.2 CPU1.AY47
  BOTTOM w0.152: 96.61,64.29 96.16,64.74 v1(96.16,65.04) ; DM2.132 52.2,54.94 52.2,54.92 v1(53.2,53.92)
M_B_A3: length 67.6
  TOP w0.152: v2(55.9,53.56) v1(55.9,54.12)
  L6 w0.165: v1(55.9,54.12) 56.32,53.71 59.81,53.71 59.98,53.87 59.98,54.56 60.17,54.75 60.44,54.75 60.64,54.56 60.64,53.87 60.8,53.71 61.13,53.71 61.3,53.87 61.3,54.36 61.46,54.53 61.79,54.53 61.96,54.36 61.96,53.87 62.12,53.71 65.34,53.71 65.93,54.29 68.82,54.29 69,54.47 71.69,54.47 73.93,56.7 77.08,56.7 79.54,59.16 79.54,59.78 80.76,61.01 81,61.01 81.26,60.75 81.53,60.75 81.73,60.94 81.73,61.21 81.47,61.47 81.47,61.71 81.7,61.94 82.09,61.94 82.27,61.76 82.83,61.76 83.08,62.02 83.08,62.7 83.29,62.91 92.14,62.91 92.26,62.8 94.23,62.8 94.66,63.24 v1(95.32,63.24)
  BOTTOM w0.089: CPU1.BB46 103.2,62.26 102.07,62.26 101.55,62.78 101.08,62.78
  BOTTOM w0.152: DM2.131 56.56,55.19 55.9,54.53 v1(55.9,54.12) ; 101.08,62.78 98.35,62.78 96.26,60.7 94.99,60.7 94.77,60.93 94.77,61.42 94.92,61.57 95.98,61.57 96.14,61.72 96.14,62.03 95.98,62.18 94.92,62.18 94.77,62.33 94.77,62.68 v1(95.32,63.24)
M_B_A4: length 67.4
  TOP w0.152: v2(52.65,56.3) 52.9,56.06 v1(52.9,55.79)
  L6 w0.165: v1(52.9,55.79) 52.53,55.79 52.18,56.15 51.46,56.15 51.26,55.95 51.26,55.31 51.46,55.11 53.73,55.11 54.44,55.82 58.17,55.82 59.92,57.57 60.95,57.57 61.83,56.7 62.12,56.7 62.55,57.13 62.93,57.13 63.39,56.67 64.81,56.67 64.82,56.68 68.95,56.68 69.14,56.86 71.43,56.86 73.32,58.76 74.21,58.76 77.55,62.09 78.19,62.09 79.88,63.78 80.54,63.78 81.98,65.23 82.8,65.23 83.39,65.82 83.81,65.82 84.1,65.52 84.47,65.52 84.76,65.82 85.13,65.82 85.42,65.52 85.79,65.52 86.08,65.82 86.45,65.82 86.74,65.52 87.11,65.52 87.4,65.82 87.77,65.82 88.06,65.52 88.43,65.52 88.72,65.82 89.09,65.82 89.38,65.52 89.75,65.52 90.04,65.82 90.41,65.82 90.7,65.52 91.07,65.52 91.36,65.82 91.73,65.82 92.02,65.52 92.39,65.52 92.68,65.82 93.05,65.82 93.34,65.52 93.71,65.52 94,65.82 94.75,65.82 v1(95.53,65.04)
  BOTTOM w0.089: CPU1.BA47 103.99,63.02 103.69,63.1 103.53,63.1 103.4,63.06 102.87,63.06 102.47,63.45 98.66,63.45 98.17,63.95 96.19,63.95
  BOTTOM w0.152: v1(52.9,55.79) 52.76,55.94 DM2.128 ; 96.19,63.95 95.83,63.95 95.53,64.25 v1(95.53,65.04)
M_B_A5: length 68.2
  L6 w0.165: v1(54.56,54.09) 54.56,54.6 54.79,54.83 58.5,54.83 59.99,56.31 60.88,56.31 61.16,56.04 61.16,55.75 61.43,55.47 65.09,55.47 65.33,55.23 65.94,55.23 65.94,55.23 68.43,55.23 68.62,55.42 71.31,55.42 73.71,57.82 74.6,57.82 75.83,59.05 77.47,59.05 77.7,59.28 77.7,59.75 77.98,60.02 78.44,60.02 78.64,60.21 78.64,60.82 78.9,61.09 79.51,61.09 79.73,61.31 79.73,62.27 80.3,62.84 81.01,62.84 82.46,64.29 83.19,64.29 83.48,64.58 83.83,64.58 83.99,64.41 83.99,64.04 84.16,63.87 84.49,63.87 84.65,64.04 84.65,64.41 84.82,64.58 85.15,64.58 85.31,64.41 85.31,64.04 85.48,63.87 85.81,63.87 85.97,64.04 85.97,64.41 86.14,64.58 94.31,64.58 94.53,64.36 96.11,64.36 96.59,63.87 97.18,63.87 97.38,64.08 97.38,64.48 v1(96.82,65.04)
  BOTTOM w0.089: v1(96.82,65.04) 96.82,65.4 97,65.57 99.03,65.57 99.41,65.19 99.41,64.58 v2(99.59,64.41) 99.77,64.23 102.74,64.23 103.02,63.95 103.46,63.95 104.31,63.74 CPU1.AY48
  BOTTOM w0.152: DM2.126 52.64,56.44 52.65,56.44 53.64,56.44 54.41,55.67 54.41,54.24 v1(54.56,54.09)
M_B_A6: length 66.4
  TOP w0.152: v2(55.59,55.92) v1(55.59,56.48)
  L6 w0.165: v1(55.59,56.48) 55.78,56.29 57.97,56.29 59.72,58.04 61.15,58.04 61.59,57.6 63.13,57.6 63.59,57.14 64.62,57.14 65.25,57.77 66.5,57.77 67.09,57.19 68.8,57.19 69.53,57.92 69.79,57.92 69.96,57.75 69.96,57.51 70.13,57.34 70.39,57.34 70.62,57.57 70.85,57.57 71.03,57.39 71.27,57.39 71.5,57.63 71.5,57.86 71.32,58.04 71.32,58.27 71.55,58.51 71.78,58.51 71.97,58.33 72.2,58.33 72.43,58.56 72.43,58.79 72.25,58.98 72.25,59.21 72.62,59.58 73.31,59.58 73.71,59.98 73.95,59.98 74.23,59.7 74.46,59.7 74.7,59.93 74.7,60.17 74.41,60.45 74.41,60.68 74.65,60.92 74.88,60.92 75.16,60.63 75.4,60.63 75.63,60.87 75.63,61.1 75.35,61.38 75.35,61.62 76.57,62.84 77.15,62.84 77.39,62.6 77.96,62.6 79.61,64.25 80.16,64.25 82.19,66.29 82.59,66.29 82.85,66.54 83.25,66.54 83.51,66.29 92.28,66.29 92.44,66.45 92.44,66.86 92.61,67.02 92.94,67.02 93.1,66.86 93.1,66.45 93.27,66.29 94.92,66.29 95.68,65.52 97.61,65.52 v1(98.09,65.04)
  BOTTOM w0.089: v1(98.09,65.04) 98.12,65.07 98.12,65.17 98.35,65.4 98.96,65.4 99.24,65.12 99.24,64.25 99.47,64.02 102.7,64.02 102.94,63.77 103.39,63.77 103.58,63.73 CPU1.BA48
  BOTTOM w0.152: v1(55.59,56.48) 55.59,55.96 55.72,55.83 55.94,55.83 56.3,56.19 DM2.127
M_B_A7: length 69.1
  TOP w0.152: v2(51.84,57.34) 51.96,57.47 v1(52.39,57.47)
  L6 w0.102: v1(108.73,64.19) 108.22,63.68 104.81,63.68 104.6,63.9
  L6 w0.165: 104.6,63.9 103.6,64.89 102,64.89 100.13,66.77 95.65,66.77 95.16,67.26 94.59,67.26 94.59,67.26 94.47,67.26 93.76,67.97 83.74,67.97 83.26,67.49 81.7,67.49 81.34,67.13 81.34,67 81.34,66.76 81.05,66.48 80.68,66.48 80.4,66.2 80.4,66.06 80.4,65.83 79.77,65.19 79.22,65.19 77.81,63.78 76.19,63.78 73.79,61.39 73.55,61.39 73.15,61.79 72.92,61.79 72.69,61.55 72.69,61.32 73.09,60.92 73.09,60.68 72.92,60.52 71.85,60.52 70.74,59.41 65.55,59.41 65.41,59.26 65.4,59.26 65.36,59.22 60.98,59.22 60.43,59.77 59.99,59.77 57.49,57.27 56.28,57.27 56,56.99 54.53,56.99 54.3,56.76 53.22,56.76 52.84,56.38 52.61,56.38 52.39,56.61 v1(52.39,57.47)
  BOTTOM w0.152: CPU1.AP48 108.73,64.12 v1(108.73,64.19) ; v1(52.39,57.47) 52.35,57.44 DM2.122
M_B_A8: length 64.3
  TOP w0.152: v2(57.21,56.18) v1(57.21,56.76)
  L6 w0.165: v1(57.21,56.76) 57.66,56.76 59.41,58.51 60.78,58.51 61.02,58.75 63.62,58.75 63.79,58.59 63.79,57.97 63.95,57.8 64.28,57.8 64.45,57.97 64.45,58.59 64.61,58.75 65.21,58.75 65.73,58.24 67.54,58.24 67.71,58.41 67.71,58.77 67.87,58.94 68.2,58.94 68.37,58.77 68.37,58.41 68.54,58.24 69.19,58.24 69.33,58.39 70.61,58.39 72.27,60.05 73.12,60.05 76.38,63.31 78.01,63.31 79.42,64.72 79.96,64.72 82.26,67.02 83.46,67.02 83.93,67.5 84.42,67.5 84.59,67.33 84.59,66.98 84.75,66.82 85.08,66.82 85.25,66.98 85.25,67.33 85.41,67.5 85.74,67.5 85.91,67.33 85.91,66.98 86.07,66.82 86.4,66.82 86.57,66.98 86.57,67.33 86.73,67.5 87.06,67.5 87.23,67.33 87.23,66.98 87.39,66.82 87.72,66.82 87.89,66.98 87.89,67.33 88.06,67.5 88.39,67.5 88.55,67.33 88.55,66.98 88.72,66.82 89.05,66.82 89.21,66.98 89.21,67.33 89.38,67.5 89.71,67.5 89.87,67.33 89.87,66.98 90.04,66.82 90.37,66.82 90.53,66.98 90.53,67.33 90.7,67.5 91.03,67.5 91.19,67.33 91.19,66.98 91.36,66.82 91.69,66.82 91.85,66.98 91.85,67.33 92.02,67.5 93.57,67.5 94.27,66.79 94.39,66.79 94.39,66.79 94.86,66.79 95.87,65.78 97.97,65.78 v1(98.75,64.99)
  BOTTOM w0.089: v1(98.75,64.99) 98.47,64.71 98.47,64.25 98.92,63.81 102.62,63.81 102.93,63.5 CPU1.BB48
  BOTTOM w0.152: DM2.125 59.1,56.69 57.29,56.69 v1(57.21,56.76)
M_B_A9: length 65.4
  TOP w0.152: v2(54.96,57.5) v1(54.96,58.06)
  L6 w0.102: 101.8,66.06 101.84,66.06 102.59,65.31 105.98,65.31 106.51,64.77 107.68,64.77 v1(108.02,65.12)
  L6 w0.165: v1(54.96,58.06) 55.14,58.24 57.13,58.24 59.67,60.77 60.76,60.77 61.29,60.24 62.07,60.24 62.61,60.77 63.81,60.77 64.25,61.22 66.74,61.22 67.66,61.22 68.38,61.94 71.22,61.94 72.02,62.73 73.79,62.73 75.78,64.72 77.42,64.72 78.24,65.54 78.24,65.67 79.27,66.7 79.58,66.7 81.3,68.43 82.04,68.43 82.52,68.91 94.15,68.91 94.86,68.2 99.65,68.2 99.74,68.11 101.8,66.06
  BOTTOM w0.152: DM2.121 59.1,57.69 57.84,57.69 57.75,57.78 55.24,57.78 v1(54.96,58.06) ; CPU1.AP50 108.35,64.79 v1(108.02,65.12)
M_B_A10: length 67.3
  TOP w0.152: v2(53.41,49.42) 53.77,49.06 v1(53.77,48.94)
  L6 w0.102: 94.62,59.53 95.48,59.53 96.32,60.37 96.65,60.37 97.28,61 100.99,61 101.31,61.33 v1(101.31,62.35)
  L6 w0.165: 94.62,59.53 93.52,58.44 87.45,58.44 82.09,53.08 80.94,53.08 79.77,51.91 79.77,50.76 79.51,50.5 79.28,50.5 78.92,50.86 78.68,50.86 78.45,50.63 78.45,50.4 78.81,50.03 78.81,49.8 78.58,49.57 78.35,49.57 77.98,49.93 77.75,49.93 77.52,49.7 77.52,49.46 77.88,49.1 77.88,48.87 77.28,48.26 71.83,48.26 71.62,48.48 68.47,48.48 68.14,48.14 66.95,48.14 66.58,47.78 66.21,47.78 65.74,48.25 65.41,48.25 65.08,48.58 64.51,48.58 64.34,48.76 55.79,48.76 55.47,48.44 54.01,48.44 53.77,48.68 v1(53.77,48.94)
  BOTTOM w0.089: v1(101.31,62.35) 101.59,62.07 102.96,62.07 102.98,62.06 103.13,61.91 104.09,61.91 104.18,61.96 104.6,61.96 104.94,62.07 CPU1.AW46
  BOTTOM w0.152: v1(53.77,48.94) 53.92,49.09 53.92,49.55 53.69,49.78 52.8,49.78 52.46,49.44 DM2.146
M_B_A11: length 69.6
  TOP w0.152: v2(53.64,57.04) 53.8,57.19 v1(53.8,57.58)
  L6 w0.102: v1(109.39,64.2) 109,64.59 107.9,64.59 107.9,64.58 106.43,64.58 105.9,65.12 102.51,65.12 102.16,65.47 101.93,65.47
  L6 w0.165: 101.93,65.47 99.54,67.86 95.27,67.86 95.14,67.73 94.66,67.73 93.96,68.44 82.71,68.44 82.24,67.96 81.5,67.96 79.77,66.23 79.47,66.23 78.71,65.48 78.71,65.35 77.62,64.25 75.97,64.25 73.98,62.26 72.68,62.26 72.36,61.94 71.95,61.94 71.69,61.68 71.69,61.27 70.3,59.88 70.02,59.88 69.85,60.04 69.85,60.46 69.69,60.62 69.36,60.62 69.19,60.46 69.19,60.04 69.03,59.88 65.34,59.88 65.17,60.04 65.17,60.56 65.01,60.72 64.68,60.72 64.51,60.56 64.51,60.04 64.35,59.88 64,59.88 63.69,60.19 63.34,60.19 62.92,59.77 61.1,59.77 60.62,60.24 59.8,60.24 57.33,57.77 56.12,57.77 55.93,57.58 v1(53.8,57.58)
  BOTTOM w0.152: v1(53.8,57.58) 53.76,57.58 53.4,57.94 52.19,57.94 52.19,57.94 DM2.120 ; v1(109.39,64.2) 109.39,64.13 CPU1.AN48
M_B_A12: length 70.2
  TOP w0.152: v2(54.56,59.91) v1(54.56,59.33)
  L6 w0.102: v1(109.38,65.09) 109.74,65.45 109.74,66.3 109.47,66.56 109.18,66.56 108.19,67.56 106.98,67.56 106.7,67.83 105.64,67.83 104.98,67.17 104.93,67.17
  L6 w0.165: v1(54.56,59.33) 54.56,59.95 54.76,60.16 55.21,60.16 55.68,60.62 56.86,60.62 58.89,62.65 62.16,62.65 64.21,64.71 73.11,64.71 79.18,70.79 94.68,70.79 95.42,70.05 100.06,70.05 102.94,67.17 104.93,67.17
  BOTTOM w0.152: v1(109.38,65.09) 109.38,65.03 CPU1.AN50 ; DM2.119 55.7,58.19 v1(54.56,59.33)
M_B_A13: length 64.6
  TOP w0.152: v2(52.65,45.97) 52.65,46.11 v1(52.34,46.43)
  L6 w0.102: v1(100.63,60.6) 100.61,60.6 100.07,60.06 99.11,60.06 98.6,59.55 96.75,59.55 93.74,56.54
  L6 w0.165: v1(52.34,46.43) 52.34,45.85 52.55,45.64 53.57,45.64 54.28,46.35 57.1,46.35 57.73,45.71 62.58,45.71 62.74,45.55 62.74,44.91 62.91,44.75 63.24,44.75 63.4,44.91 63.4,45.55 63.57,45.71 63.9,45.71 64.06,45.55 64.06,44.91 64.23,44.75 64.56,44.75 64.72,44.91 64.72,45.18 64.91,45.36 73.51,45.36 73.84,45.69 77.44,45.69 88.29,56.54 93.74,56.54
  BOTTOM w0.089: CPU1.BA43 103.99,60.67 103.69,60.74 103.53,60.74 103.4,60.71 103.01,60.71 102.88,60.78 102.83,60.85 102.69,60.99 102.67,60.99 102.65,61.02 101.05,61.02 v1(100.63,60.6)
  BOTTOM w0.152: v1(52.34,46.43) 52.33,46.44 DM2.158
M_B_A14: length 68.2
  TOP w0.152: v1(56.34,47.54) 56.67,47.54 v2(56.89,47.31)
  L6 w0.102: v1(98.72,60.6) 98.08,59.96 96.55,59.96 95.16,58.57 94.97,58.57
  L6 w0.165: 94.97,58.57 93.89,57.48 87.9,57.48 82.46,52.05 81.81,52.05 81.53,51.78 81.53,51.12 77.05,46.63 74.33,46.63 73.63,47.32 71.1,47.32 70.55,46.77 68.82,46.77 68.35,46.3 65.35,46.3 64.8,46.85 64.8,47.33 64.58,47.55 64.1,47.55 63.83,47.82 63.1,47.82 62.94,47.65 62.94,46.89 62.77,46.73 62.44,46.73 62.28,46.89 62.28,47.65 62.11,47.82 61.78,47.82 61.61,47.65 61.61,46.89 61.45,46.73 61.12,46.73 60.95,46.89 60.95,47.65 60.79,47.82 60.46,47.82 60.29,47.65 60.29,46.89 60.13,46.73 59.8,46.73 59.63,46.89 59.63,47.65 59.47,47.82 59.14,47.82 58.97,47.65 58.97,46.89 58.81,46.73 58.48,46.73 58.31,46.89 58.31,47.65 58.15,47.82 57.81,47.82 57.28,47.29 56.59,47.29 v1(56.34,47.54)
  BOTTOM w0.089: CPU1.AY44 104.18,60.84 104.03,60.84 103.71,60.92 103.5,60.92 103.37,60.88 103.08,60.88 102.81,61.13 102.74,61.2 98.95,61.2 98.72,60.97 v1(98.72,60.6)
  BOTTOM w0.152: v1(56.34,47.54) 56.34,47.84 56.82,48.33 57.73,48.33 57.87,48.19 59.1,48.19 DM2.151
M_B_A15: length 68
  TOP w0.152: v2(54.2,45.91) v1(54.2,45.36)
  L6 w0.102: 95.78,57.47 97.25,58.94 98.83,58.94 99.34,59.45 102.11,59.45 103.35,60.7 v1(105.99,60.7)
  L6 w0.165: 95.78,57.47 93.41,55.1 88.84,55.1 76.6,42.86 59.39,42.86 58.11,44.14 53.97,44.14 53.72,44.39 53.72,44.87 v1(54.2,45.36)
  BOTTOM w0.089: CPU1.AY43 105.19,60.1 105.36,60.1 105.37,60.09 105.69,60.09 105.99,60.39 v1(105.99,60.7)
  BOTTOM w0.152: v1(54.2,45.36) 54.13,45.43 54.13,46.12 53.29,46.96 52.86,46.96 52.83,46.94 DM2.156
M_B_A16: length 67
  TOP w0.152: v2(55.98,48.91) v1(55.19,48.91)
  L6 w0.102: 94.57,60.02 95.7,60.02 96.24,60.56 96.57,60.56 97.2,61.19 100.26,61.19 100.68,61.6 v1(100.68,62.33)
  L6 w0.165: 94.57,60.02 93.46,58.91 87.26,58.91 83.42,55.07 82.01,55.07 81.74,54.8 81.74,53.72 81.57,53.55 80.75,53.55 79.54,52.35 78.52,52.35 78.12,51.95 78.12,51.01 77.77,50.66 77.54,50.66 77.33,50.86 77.06,50.86 76.86,50.67 76.86,50.4 77.07,50.19 77.07,49.96 76.84,49.72 76.61,49.72 76.19,50.14 75.95,50.14 75.72,49.91 75.72,49.67 76.22,49.17 76.22,48.91 76.05,48.73 75.18,48.73 75.01,48.9 75.01,49.18 74.85,49.34 74.51,49.34 74.35,49.18 74.35,48.9 74.18,48.73 72.03,48.73 71.59,49.17 66.2,49.17 66.19,49.18 66.18,49.18 64.57,49.18 64.51,49.23 55.51,49.23 v1(55.19,48.91)
  BOTTOM w0.089: v1(100.68,62.33) 101.12,61.88 102.91,61.88 103.06,61.73 103.78,61.73 104.17,61.34 104.72,61.34 105.01,61.05 CPU1.AW44
  BOTTOM w0.152: v1(55.19,48.91) 54.22,47.94 DM2.152 ; DM2.152 50.9,47.93 DM2.152
M_B_ACT_N: length 68.7
  TOP w0.152: v2(53.52,61.18) v1(53.52,60.62)
  L6 w0.102: 104.09,68.29 105.26,68.29 105.43,68.47 106.96,68.47 107.14,68.29 108.2,68.29 108.32,68.41 109.05,68.41 109.12,68.34 109.4,68.34 109.74,68 109.74,67.37 v1(109.33,66.97)
  L6 w0.165: v1(53.52,60.62) 53.52,61 54.74,62.22 55.83,62.22 58.34,64.73 62.2,64.73 63.63,66.16 72.56,66.16 78.6,72.2 94.8,72.2 95.23,71.77 99.6,71.77 101.5,69.86 102.52,69.86 104.09,68.29
  BOTTOM w0.152: v1(109.33,66.97) 109,66.64 CPU1.AN53 ; DM2.114 50.91,59.43 52.14,59.43 52.25,59.53 52.42,59.53 v1(53.52,60.62)
M_B_ALERT_N: length 71.7
  TOP w0.152: v2(52.83,59.53) 52.83,59.34 v1(52.54,59.05)
  L6 w0.089: v1(109.33,60.54) 109.33,60.6 109.88,61.15 109.88,64.26 109.55,64.59 109.27,64.59 108.99,64.86 108.99,65.3 108.72,65.56 106.55,65.56 106.49,65.5 103.05,65.5 102.89,65.65
  L6 w0.165: 102.89,65.65 100.05,68.5 95.23,68.5 94.35,69.38 81.58,69.38 79.38,67.17 79.08,67.17 78.15,66.24 77.64,66.24 77.32,65.93 77.32,65.62 76.89,65.19 75.58,65.19 73.59,63.2 71.82,63.2 71.04,62.42 68.2,62.42 67.46,61.69 66.54,61.69 66.16,61.69 66.16,61.69 64.06,61.69 63.61,61.24 59.47,61.24 56.94,58.71 54.12,58.71 53.85,58.44 52.88,58.44 52.54,58.78 v1(52.54,59.05)
  BOTTOM w0.152: v1(52.54,59.05) 52.43,58.94 DM2.116 ; v1(109.33,60.54) 109,60.87 CPU1.AN43
M_B_BA0: length 66.1
  L6 w0.102: 95.38,60.85 95.78,60.85 95.91,60.98 96.45,60.98 97.05,61.57 98.02,61.57 v1(98.77,62.33)
  L6 w0.165: v1(53.1,48.94) 52.64,48.48 50.52,48.48 50.32,48.68 50.32,49.97 50.52,50.18 64.9,50.18 64.95,50.12 71.97,50.12 72.42,49.67 73.19,49.67 74.94,51.42 74.94,52.02 75.89,52.96 77.64,52.96 80.85,56.18 83.2,56.18 86.87,59.85 93.03,59.85 94.03,60.85 95.38,60.85
  BOTTOM w0.152: CPU1.BB44 103.15,61.28 102.95,61.28 102.8,61.43 102.72,61.44 99.66,61.44 v2(99.48,61.62) v1(98.77,62.33) ; DM2.150 52.58,48.44 53.09,48.94 v1(53.1,48.94)
M_B_BA1: length 67.3
  TOP w0.152: v2(54.84,49.37) 54.48,49.01 v1(54.48,48.91)
  L6 w0.102: v1(99.41,62.33) 99.69,62.04 99.69,61.51 99.57,61.38 97.12,61.38 96.52,60.78 96.12,60.78 95.87,60.53 94.75,60.53
  L6 w0.165: 94.75,60.53 94.52,60.53 93.37,59.38 87.06,59.38 83.23,55.54 81.05,55.54 80.27,54.76 80.27,54.53 80.52,54.28 80.52,54.05 80.29,53.82 80.06,53.82 79.81,54.06 79.57,54.06 79.34,53.83 79.34,53.6 79.59,53.35 79.59,53.11 79.35,52.88 79.12,52.88 78.87,53.13 78.64,53.13 78,52.49 77.33,52.49 77.17,52.33 77.17,51.54 77,51.38 76.67,51.38 76.51,51.54 76.51,52.33 76.34,52.49 76.08,52.49 75.41,51.82 75.41,51.23 75.1,50.91 75.1,50.1 74.82,49.83 74.01,49.83 73.39,49.2 72.22,49.2 71.78,49.65 64.76,49.65 64.71,49.7 54.68,49.7 54.48,49.5 v1(54.48,48.91)
  BOTTOM w0.089: v1(99.41,62.33) 100.07,61.66 102.83,61.66 102.88,61.65 103.04,61.49 103.41,61.49 103.68,61.4 CPU1.BA44
  BOTTOM w0.152: DM2.145 59.1,49.69 55.25,49.69 v1(54.48,48.91)
M_B_BG0: length 69.4
  TOP w0.152: v2(56.56,59.96) v1(56.56,59.4)
  L6 w0.102: v1(108.71,66.03) 108.32,66.42 105.62,66.42 105.07,65.87 104.52,65.87
  L6 w0.165: v1(56.56,59.4) 56.84,59.67 57.23,59.67 59.28,61.71 63.4,61.71 65.36,63.67 65.73,63.67 65.9,63.51 65.9,62.79 66.06,62.63 66.39,62.63 66.56,62.79 66.56,63.51 66.72,63.67 67.44,63.67 67.61,63.51 67.61,63.12 67.77,62.96 68.1,62.96 68.27,63.12 68.27,63.51 68.43,63.67 73.4,63.67 76.06,66.34 76.3,66.34 76.42,66.21 76.66,66.21 76.89,66.45 76.89,66.68 76.76,66.81 76.76,67.04 77.05,67.32 77.28,67.32 77.79,66.82 78.02,66.82 78.26,67.05 78.26,67.28 77.75,67.79 77.75,68.02 78.56,68.84 78.79,68.84 79.1,68.53 79.33,68.53 79.56,68.76 79.56,69 79.26,69.3 79.26,69.54 79.57,69.85 80.05,69.85 80.22,69.68 80.22,69.4 80.38,69.23 80.71,69.23 80.88,69.4 80.88,69.68 81.04,69.85 94.54,69.85 95.25,69.14 95.85,69.14 96.19,68.8 100.35,68.8 102.89,66.26 104.13,66.26 104.52,65.87
  BOTTOM w0.152: CPU1.AP52 108.69,65.91 108.69,66.01 v1(108.71,66.03) ; DM2.115 56.78,59.19 v1(56.56,59.4)
M_B_BG1: length 68.1
  TOP w0.152: v2(55.19,58.84) v1(55.19,59.43)
  L6 w0.102: v1(109.34,65.99) 109.34,66.13 108.13,67.35 106.9,67.35 106.87,67.38 106.54,67.38 106.3,67.14 106.3,66.9 106.09,66.69 105.08,66.69 104.93,66.84
  L6 w0.165: v1(55.19,59.43) 55.9,60.14 57.04,60.14 59.08,62.18 62.37,62.18 62.64,62.46 62.87,62.46 63.05,62.28 63.28,62.28 63.51,62.52 63.51,62.75 63.34,62.92 63.34,63.16 63.57,63.39 63.81,63.39 63.98,63.22 64.22,63.22 64.45,63.45 64.45,63.68 64.28,63.86 64.28,64.09 64.43,64.24 73.3,64.24 79.38,70.32 94.59,70.32 95.21,69.7 100.06,69.7 102.91,66.84 104.93,66.84
  BOTTOM w0.152: v1(55.19,59.43) 55.62,59.85 57.86,59.85 58.03,59.69 59.1,59.69 DM2.113 ; v1(109.34,65.99) 109.34,65.91 CPU1.AN52
M_B_CKE0: length 63.6
  TOP w0.152: v2(56.31,62.17) v1(56.31,61.61)
  L6 w0.102: v1(109.33,67.83) 109.32,67.83 108.94,68.22 108.41,68.22 108.23,68.04 107.08,68.04 106.86,68.27 105.51,68.27 105.16,67.92 105.08,67.92
  L6 w0.165: 105.08,67.92 104.01,67.92 102.38,69.54 101.46,69.54 99.79,71.21 95.3,71.21 94.79,71.73 78.79,71.73 72.75,65.69 63.82,65.69 62.4,64.26 58.96,64.26 v1(56.31,61.61)
  BOTTOM w0.127: v1(109.33,67.83) 109.33,67.99 CPU1.AN56
  BOTTOM w0.152: v1(56.31,61.61) 56.43,61.61 57.36,60.69 59.1,60.69 DM2.109
M_B_CKE1: length 65.6
  TOP w0.152: v2(54.91,62.17) v1(54.91,61.61)
  L6 w0.102: v1(108.65,67.81) 107.03,67.81 106.82,68.03 105.55,68.03 105.02,67.5 104.77,67.5
  L6 w0.165: v1(54.91,61.61) 55.4,61.12 56.69,61.12 59.36,63.79 62.63,63.79 64.03,65.19 72.92,65.19 78.99,71.26 94.67,71.26 95.62,70.31 100.17,70.31 102.98,67.5 104.77,67.5
  BOTTOM w0.152: v1(54.91,61.61) 54.61,61.31 52.73,61.31 51.86,60.43 DM2.110 ; CPU1.AP55 v1(108.65,67.81)
M_B_CLK0: length 68.1
  TOP w0.102: v1(55.93,51.93) 55.93,51.81 v2(55.55,51.43)
  L6 w0.089: 105.31,62.7 105.31,62.71 105.36,62.77 107.51,62.77 108,62.28 108,61.54 v1(108.02,61.51)
  L6 w0.127: 105.31,62.7 104.89,62.28 103.88,62.28 102.64,63.52 98.68,63.52 97.22,62.06 96.45,62.06 95.94,61.55 93.66,61.55 92.99,60.88 86.46,60.88 85.1,59.52 84.7,59.52 84.29,59.93 84.11,59.93 83.93,59.75 83.93,59.57 84.34,59.16 84.34,58.76 82.85,57.26 80.52,57.26 77.91,54.65 76.09,54.65 75.05,53.62 73.84,53.62 73.17,52.95 73.17,52.77 73.65,52.28 73.65,51.88 73.32,51.54 72.92,51.54 72.43,52.03 72.25,52.03 71.83,51.6 65.18,51.6 64.75,51.17 56.5,51.17 56.14,51.53 56.14,51.71 55.93,51.92 v1(55.93,51.93)
  BOTTOM w0.102: v1(108.02,61.51) 108.35,61.84 CPU1.AP45 ; DM2.137 59.1,53.69 58.16,53.69 57.71,53.23 56.36,53.23 55.93,52.8 v1(55.93,51.93)
M_B_CLK1: length 67.2
  TOP w0.102: v1(53.95,51.91) 54.28,52.24 v2(54.28,52.37)
  L6 w0.127: v1(108.63,62.36) 108.88,62.6 108.88,62.97 108.66,63.19 104.28,63.19 103.21,64.25 98.58,64.25 96.89,62.56 96.2,62.56 95.68,62.04 92.98,62.04 92.59,61.65 84.52,61.65 80.94,58.07 80.24,58.07 77.61,55.44 75.78,55.44 74.73,54.39 73.47,54.39 71.52,52.44 53.92,52.44 53.72,52.24 53.72,52.12 53.93,51.91 v1(53.95,51.91)
  BOTTOM w0.102: v1(53.95,51.91) 53.87,51.91 53.52,52.26 53.52,52.82 53.13,53.2 52.02,53.2 51.79,53.43 DM2.138 ; CPU1.AP46 108.61,62.83 108.71,62.73 108.71,62.44 v1(108.63,62.36)
M_B_CLK#0: length 68.1
  TOP w0.102: v1(56.59,51.93) 56.59,51.73 v2(56.89,51.43)
  L6 w0.089: v1(108.7,61.45) 108.19,61.96 108.19,62.36 107.59,62.96 105.18,62.96 105.12,62.89
  L6 w0.127: v1(56.59,51.93) 56.41,51.76 56.41,51.64 56.61,51.44 64.64,51.44 65.07,51.87 71.72,51.87 72.14,52.3 72.54,52.3 73.03,51.81 73.21,51.81 73.39,51.99 73.39,52.17 72.9,52.66 72.9,53.06 73.73,53.89 74.94,53.89 75.98,54.92 77.8,54.92 80.41,57.53 82.74,57.53 84.07,58.87 84.07,59.05 83.67,59.46 83.67,59.86 84,60.19 84.4,60.19 84.81,59.78 84.99,59.78 86.35,61.14 92.88,61.14 93.55,61.81 95.83,61.81 96.34,62.32 97.11,62.32 98.57,63.78 102.75,63.78 103.99,62.55 104.78,62.55 105.12,62.89
  BOTTOM w0.102: DM2.139 57.99,53.19 57.8,53 56.46,53 56.16,52.7 56.16,52.37 v1(56.59,51.93) ; v1(108.7,61.45) 108.65,61.5 108.65,61.81 108.75,61.92 CPU1.AN45
M_B_CLK#1: length 67.3
  TOP w0.102: v2(53.01,52.39) 53.01,52.14 v1(53.29,51.86)
  L6 w0.127: v1(53.29,51.86) 53.45,52.02 53.45,52.35 53.81,52.71 71.41,52.71 73.36,54.66 74.62,54.66 75.67,55.71 77.5,55.71 80.12,58.34 80.83,58.34 84.41,61.92 92.48,61.92 92.87,62.31 95.57,62.31 96.09,62.83 96.78,62.83 98.47,64.52 103.33,64.52 104.39,63.45 108.77,63.45 109.14,63.08 109.14,62.49 v1(109.28,62.35)
  BOTTOM w0.102: DM2.140 50.94,52.98 53.03,52.98 53.29,52.72 v1(53.29,51.86) ; CPU1.AN46 109,62.63 v1(109.28,62.35)
M_B_CS#0: length 64.8
  TOP w0.152: v2(55.19,47.87) v1(55.19,47.31)
  L6 w0.102: v1(99.36,60.6) 98.52,59.76 96.63,59.76 93.89,57.01
  L6 w0.165: v1(55.19,47.31) 55.19,46.98 55.36,46.82 57.47,46.82 58.04,46.24 63.36,46.24 63.52,46.41 63.52,46.89 63.72,47.08 63.99,47.08 64.18,46.89 64.18,46.41 64.35,46.24 64.74,46.24 65.15,45.83 68.58,45.83 68.91,46.16 69.44,46.16 69.76,45.84 70.1,45.84 70.43,46.16 71.33,46.16 71.49,46.33 71.49,46.69 71.66,46.85 71.99,46.85 72.15,46.69 72.15,45.97 72.28,45.84 72.69,45.84 72.82,45.97 72.82,46.69 72.98,46.85 73.31,46.85 73.48,46.69 73.48,46.33 73.64,46.16 77.24,46.16 88.1,57.01 93.89,57.01
  BOTTOM w0.089: CPU1.BB42 103.13,59.82 103.09,59.86 101.75,59.86 101.73,59.88 101.34,59.88 101.23,59.99
  BOTTOM w0.152: DM2.149 59.1,48.69 56.57,48.69 v1(55.19,47.31) ; 101.23,59.99 99.54,59.99 99.36,60.17 v1(99.36,60.6)
M_B_CS#1: length 66
  TOP w0.152: v1(54.91,45.43) 54.91,45.33 v2(55.29,44.95)
  L6 w0.102: 93.6,56.07 96.87,59.35 98.68,59.35 99.19,59.86 100.53,59.86 v1(101.26,60.6)
  L6 w0.165: 93.6,56.07 93.57,56.04 88.45,56.04 77.63,45.22 75.56,45.22 75.39,45.06 75.39,44.53 75.23,44.37 74.9,44.37 74.73,44.53 74.73,45.06 74.57,45.22 74.04,45.22 73.09,44.28 72.67,44.28 72.51,44.44 72.51,44.71 72.34,44.87 72.01,44.87 71.85,44.71 71.85,44.44 71.68,44.28 71.35,44.28 71.19,44.44 71.19,44.71 71.02,44.87 70.69,44.87 70.53,44.71 70.53,44.44 70.36,44.28 61.05,44.28 60.08,45.24 57.4,45.24 56.77,45.88 55.36,45.88 v1(54.91,45.43)
  BOTTOM w0.089: v1(101.26,60.6) 101.82,60.04 102.92,60.04 102.96,60.08 103.39,60.08 103.47,60.04 103.72,60.04 103.84,60.08 104.02,60.08 104.19,60.03 CPU1.AY42
  BOTTOM w0.152: DM2.157 59.1,46.69 57.82,46.69 57.53,46.4 55.68,46.4 54.91,45.64 v1(54.91,45.43)
M_B_DIMB_ODT0: length 65.7
  TOP w0.152: v2(53.8,47.97) v1(53.8,47.41)
  L6 w0.102: 94.81,59.04 95.32,59.04 96.44,60.16 97.65,60.16 v1(98.09,60.6)
  L6 w0.165: 94.81,59.04 93.73,57.95 87.71,57.95 82.27,52.52 81.04,52.52 80.24,51.72 80.24,50.49 77.04,47.29 74.34,47.29 73.83,47.79 71.64,47.79 71.42,48.01 68.67,48.01 68.33,47.67 67.14,47.67 66.87,47.4 66.87,47.11 66.54,46.77 65.54,46.77 65.27,47.04 65.27,47.72 64.9,48.1 64.29,48.1 64.1,48.29 55.99,48.29 55.67,47.97 54,47.97 53.8,47.77 v1(53.8,47.41)
  BOTTOM w0.102: v1(98.09,60.6) 99.02,59.66 102.98,59.66 103.08,59.56 103.12,59.56 103.13,59.55 103.67,59.55 CPU1.BA42
  BOTTOM w0.152: DM2.155 59.1,47.19 57.72,47.19 57.69,47.16 57.63,47.16 57.33,46.85 54.35,46.85 v1(53.8,47.41)
M_B_DIMB_ODT1: length 66.5
  TOP w0.152: v2(56.51,45.97) v1(56.51,45.41)
  L6 w0.102: 93.07,55.59 93.44,55.59 97,59.15 98.75,59.15 99.26,59.66 101.62,59.66 101.9,59.93 v1(101.9,60.63)
  L6 w0.165: 93.07,55.59 93.05,55.57 88.65,55.57 77.07,44 76.77,44 76.53,44.24 76.53,44.56 76.36,44.72 76.03,44.72 75.86,44.56 75.86,43.97 75.7,43.81 75.31,43.81 75.15,43.64 75.15,43.51 74.98,43.35 74.65,43.35 74.49,43.51 74.49,43.64 74.32,43.81 73.99,43.81 73.83,43.64 73.83,43.51 73.66,43.35 73.33,43.35 73.16,43.51 73.16,43.64 73,43.81 72.67,43.81 72.5,43.64 72.5,43.51 72.34,43.35 72.01,43.35 71.84,43.51 71.84,43.64 71.68,43.81 65.19,43.81 65.03,43.64 65.03,43.5 64.86,43.33 64.53,43.33 64.37,43.5 64.37,43.64 64.2,43.81 63.87,43.81 63.7,43.64 63.7,43.5 63.54,43.33 63.21,43.33 63.04,43.5 63.04,43.64 62.88,43.81 62.55,43.81 62.38,43.64 62.38,43.5 62.22,43.33 61.89,43.33 61.72,43.5 61.72,43.64 61.56,43.81 61.23,43.81 61.06,43.64 61.06,43.5 60.9,43.33 60.57,43.33 60.4,43.5 60.4,43.64 59.42,44.62 56.44,44.62 56.26,44.8 56.26,45.15 v1(56.51,45.41)
  BOTTOM w0.089: v1(101.9,60.63) 101.9,60.42 102.1,60.21 102.77,60.21 102.81,60.26 103.43,60.26 103.51,60.22 103.69,60.22 103.82,60.26 104.04,60.26 104.18,60.22 104.65,60.22 104.75,60.12 104.8,60.07 105.05,59.82 CPU1.AW42
  BOTTOM w0.152: v1(56.51,45.41) 56.89,45.03 57.57,45.03 58.23,45.69 59.1,45.69 DM2.161
M_B_DQ0: length 75.6
  TOP w0.089: v2(56.1,83.18) v1(56.1,82.59)
  L6 w0.102: v1(56.1,82.59) 56.1,81.93 56.33,81.7 63.02,81.7 63.03,81.68 63.05,81.68 63.62,81.12 72.13,81.12 73.25,82.24 80.21,82.24 81.16,83.19 88.42,83.19 90.26,85.03 98.02,85.03 102,81.04 104.54,81.04 105.71,82.21 107.83,82.21 110.11,79.93 110.11,79.26 110.18,79.19 110.18,77.99 110.55,77.63 110.55,77.63 110.78,77.4 113.31,74.87 113.31,74.62 113.51,74.41 113.51,73.75 113.31,73.55 113.31,73.2 v1(112.91,72.8)
  BOTTOM w0.089: CPU1.AF65 112.58,73.12 v1(112.91,72.8) ; DM2.28 50.9,80.94 54.59,80.94 56.1,82.44 v1(56.1,82.59)
M_B_DQ1: length 73.7
  TOP w0.089: v2(56.46,79.52) 56.81,79.86 v1(56.81,80.05)
  L6 w0.102: v1(56.81,80.05) 56.81,80.51 57,80.69 58.54,80.69 58.64,80.59 58.64,79.72 58.74,79.62 58.95,79.62 59.05,79.72 59.05,80.59 59.15,80.69 59.35,80.69 59.45,80.59 59.45,79.72 59.56,79.62 59.76,79.62 59.86,79.72 59.86,80.59 59.96,80.69 60.14,80.69 61.21,79.63 62.43,79.63 62.53,79.73 62.53,79.95 62.63,80.05 62.84,80.05 62.94,79.95 62.94,79.73 63.04,79.63 63.24,79.63 63.35,79.73 63.35,79.95 63.45,80.05 63.65,80.05 63.75,79.95 63.75,79.73 63.85,79.63 65.22,79.63 65.49,79.35 71.77,79.35 73.66,81.25 80.62,81.25 81.57,82.2 88.83,82.2 90.57,83.94 97.66,83.94 101.57,80.03 105.81,80.03 106.17,79.67 106.9,79.67 108.1,78.48 108.11,78.48 108.65,77.94 108.65,77.72 110.92,75.46 111.89,75.46 112.51,74.84 112.51,73.32 v1(112,72.8)
  BOTTOM w0.089: CPU1.AF64 112.32,72.47 v1(112,72.8) ; v1(56.81,80.05) 57.45,80.69 DM2.29
M_B_DQ2: length 74.4
  TOP w0.089: v2(55.28,79.06) v1(55.28,78.5)
  L6 w0.102: v1(55.28,78.5) 55.36,78.42 55.36,77.72 55.47,77.62 60.73,77.62 61.35,77 73.03,77 75.65,79.62 87.74,79.62 87.84,79.72 87.84,80.44 87.96,80.56 88.13,80.56 88.25,80.44 88.25,79.72 88.35,79.62 88.57,79.62 91.11,82.16 91.32,82.16 91.42,82.06 91.42,81.64 91.54,81.53 91.71,81.53 91.83,81.64 91.83,82.06 91.93,82.16 92.14,82.16 92.24,82.06 92.24,81.62 92.36,81.5 92.52,81.5 92.64,81.62 92.64,82.06 92.75,82.16 92.95,82.16 93.05,82.06 93.05,81.68 93.15,81.58 93.35,81.58 93.46,81.68 93.46,82.06 93.56,82.16 97.08,82.16 100.38,78.86 103.76,78.86 103.99,78.63 103.99,77.65 104.46,77.18 105.54,77.18 106.12,76.6 108.28,76.6 110.59,74.28 110.59,73.05 110.84,72.8 v1(111.08,72.8)
  BOTTOM w0.089: v1(55.28,78.5) 55.28,77.98 55.58,77.69 DM2.41 ; CPU1.AK65 110.95,72.8 v1(111.08,72.8)
M_B_DQ3: length 75.5
  TOP w0.089: v2(53.64,79.04) 53.86,78.82 v1(53.86,78.5)
  L6 w0.102: v1(111.08,72.15) 111.47,72.54 111.47,73.63 111.07,74.03 111.07,74.34 108.41,77 106.27,77 105.64,77.64 105.44,77.64 105.19,77.88 105.19,78.62 105.09,78.72 105.09,78.75 104.57,79.26 101.04,79.26 100.73,79.57 100.63,79.57 97.33,82.87 90.89,82.87 89.24,81.22 87.79,81.22 87.29,81.22 87.19,81.12 87.19,80.89 87.06,80.76 86.9,80.76 86.78,80.88 86.78,81.12 86.68,81.22 85.9,81.22 84.96,80.28 75.37,80.28 74.17,79.08 74.03,79.08 73.54,79.56 73.4,79.56 73.26,79.42 73.26,79.28 73.74,78.79 73.74,78.65 73.6,78.5 73.45,78.5 72.97,78.99 72.83,78.99 72.68,78.85 72.68,78.7 73.17,78.22 73.17,78.07 72.96,77.86 71.86,77.86 71.76,77.97 71.76,78.1 71.65,78.2 71.45,78.2 71.35,78.1 71.35,77.97 71.12,77.74 65.28,77.74 64.41,78.6 57.94,78.6 57.61,78.93 54.05,78.93 53.86,78.75 v1(53.86,78.5)
  BOTTOM w0.089: v1(111.08,72.15) 110.95,72.15 CPU1.AK64 ; v1(53.86,78.5) 52.82,77.45 51.91,77.45 51.89,77.44 50.9,77.44 DM2.42
M_B_DQ4: length 75.3
  TOP w0.089: v2(54.67,83) v1(54.67,82.43)
  L6 w0.102: v1(112.91,73.45) 112.91,73.53 113.3,73.93 113.3,74.34 113.1,74.54 113.1,74.79 111.81,76.09 110.86,76.09 110.63,76.32 110.63,76.46 110.88,76.72 110.88,76.86 110.74,77.01 110.6,77.01 110.34,76.75 110.2,76.75 109.14,77.81 109.14,80.43 107.69,81.88 105.87,81.88 104.7,80.71 101.85,80.71 97.86,84.7 90.4,84.7 88.55,82.86 81.3,82.86 80.34,81.91 73.38,81.91 72.27,80.79 63.48,80.79 62.91,81.35 55.08,81.35 54.67,81.76 v1(54.67,82.43)
  BOTTOM w0.089: v1(54.67,82.43) 54.18,81.94 50.9,81.94 DM2.24 ; CPU1.AF66 112.58,73.77 v1(112.91,73.45)
M_B_DQ5: length 74.8
  TOP w0.089: v2(55.93,80.64) 55.52,80.23 v1(55.52,80.03)
  L6 w0.102: v1(112.91,74.1) 112.91,74.71 111.76,75.87 110.81,75.87 108.91,77.77 108.91,79.48 108.81,79.59 108.81,79.98 108.58,80.2 107.97,80.2 107.67,80.51 107.67,81.3 107.41,81.55 106.4,81.55 105.21,80.36 101.73,80.36 97.72,84.36 90.52,84.36 88.69,82.53 81.43,82.53 80.48,81.58 73.52,81.58 72.4,80.46 64.78,80.46 64.68,80.36 64.68,80.06 64.57,79.96 64.37,79.96 64.27,80.06 64.27,80.36 64.17,80.46 62.18,80.46 61.61,81.02 61.2,81.02 61.1,80.92 61.1,80.76 61,80.66 60.79,80.66 60.69,80.76 60.69,80.92 60.59,81.02 55.78,81.02 55.52,80.76 v1(55.52,80.03)
  BOTTOM w0.089: DM2.25 58.1,81.69 58.06,81.65 56.23,81.65 55.52,80.94 v1(55.52,80.03) ; CPU1.AF67 112.58,74.42 v1(112.91,74.1)
M_B_DQ6: length 72.4
  TOP w0.089: v2(51.88,78.5) v1(52.44,78.5)
  L6 w0.102: v1(110.11,74.21) 110.11,74.32 108.04,76.39 106.04,76.39 105.48,76.95 104.09,76.95 103.45,77.59 102.79,77.59 102.63,77.75 102.5,77.75 101.6,78.66 100.1,78.66 96.92,81.83 94.08,81.83 93.42,81.17 90.59,81.17 88.71,79.29 75.79,79.29 73.17,76.67 72.57,76.67 72.47,76.57 72.47,76.29 72.35,76.17 72.18,76.17 72.07,76.29 72.07,76.57 71.96,76.67 71.76,76.67 71.66,76.57 71.66,76.23 71.56,76.14 71.35,76.14 71.25,76.23 71.25,76.57 71.15,76.67 61.21,76.67 60.6,77.29 55.13,77.29 55.03,77.39 55.03,77.92 54.93,78.02 54.73,78.02 54.62,77.92 54.62,77.39 54.52,77.29 54.32,77.29 54.22,77.39 54.22,77.92 54.12,78.02 53.91,78.02 53.81,77.92 53.81,77.39 53.71,77.29 53.51,77.29 53.41,77.39 53.41,77.92 53.3,78.02 53.1,78.02 53,77.92 53,77.39 52.9,77.29 52.65,77.29 52.44,77.5 v1(52.44,78.5)
  BOTTOM w0.089: v1(52.44,78.5) 52.38,78.44 50.9,78.44 DM2.38 ; v1(110.11,74.21) 110.32,74.42 CPU1.AK67
M_B_DQ7: length 73.8
  TOP w0.089: v1(56.71,78.5) 57.25,79.04 v2(57.63,79.04)
  L6 w0.102: v1(56.71,78.5) 56.71,78.23 56.99,77.95 58.67,77.95 58.77,78.05 58.77,78.17 58.87,78.27 59.08,78.27 59.18,78.17 59.18,78.05 59.28,77.95 59.48,77.95 59.59,78.05 59.59,78.17 59.69,78.27 59.89,78.27 59.99,78.17 59.99,78.05 60.09,77.95 61.24,77.95 61.36,77.82 61.36,77.46 61.49,77.33 61.77,77.33 61.87,77.44 61.87,78.17 61.97,78.27 62.17,78.27 62.27,78.17 62.27,77.44 62.38,77.33 62.58,77.33 62.68,77.44 62.68,78.17 62.78,78.27 62.99,78.27 63.09,78.17 63.09,77.44 63.19,77.33 63.39,77.33 63.49,77.44 63.49,78.17 63.6,78.27 63.8,78.27 63.9,78.17 63.9,77.44 64,77.33 72.9,77.33 75.51,79.95 85.9,79.95 86,80.05 86,80.75 86.12,80.86 86.29,80.86 86.41,80.75 86.41,80.05 86.51,79.95 86.71,79.95 87.65,80.89 89.38,80.89 90.98,82.49 97.23,82.49 100.38,79.34 100.68,79.34 100.96,79.06 103.89,79.06 104.18,78.77 104.18,77.73 104.53,77.39 105.61,77.39 106.2,76.8 108.34,76.8 110.82,74.32 110.82,73.71 v1(111.08,73.45)
  BOTTOM w0.089: v1(111.08,73.45) 110.95,73.45 CPU1.AK66 ; v1(56.71,78.5) 57.19,78.98 57.62,78.98 57.91,78.69 DM2.37
M_B_DQ8: length 75.5
  TOP w0.089: v2(53.99,86.46) v1(53.99,87.06)
  L6 w0.102: v1(53.99,87.06) 54.43,86.61 63.68,86.61 64.55,85.74 72.36,85.74 72.47,85.86 73.57,85.86 73.67,85.96 73.67,86.12 73.77,86.22 73.97,86.22 74.08,86.12 74.08,85.96 74.18,85.86 79.02,85.86 79.7,86.54 87.96,86.54 89.2,87.79 98.85,87.79 100.35,89.29 105.79,89.29 113.71,81.36 113.71,79.65 113.51,79.44 v1(113.51,78.58)
  BOTTOM w0.089: v1(53.99,87.06) 52.87,85.94 50.9,85.94 DM2.8 ; CPU1.AF70 113.26,76.88 113.5,76.88 113.74,77.12 113.74,77.66 113.9,77.82 113.9,78.14 113.51,78.53 v1(113.51,78.58)
M_B_DQ9: length 78
  TOP w0.089: v2(55.41,86.48) v1(55.41,87.06)
  L6 w0.102: v1(55.41,87.06) 55.41,87.48 55.74,87.82 63.41,87.82 63.71,87.52 63.85,87.52 64.08,87.74 64.22,87.74 64.36,87.6 64.36,87.45 64.14,87.23 64.14,87.09 64.83,86.4 72.08,86.4 72.89,87.2 87.68,87.2 88.93,88.45 98.58,88.45 100.08,89.95 106.06,89.95 114.37,81.63 114.37,79.16 v1(114.22,79.01)
  BOTTOM w0.089: v1(114.22,79.01) 114.22,77.84 113.94,77.56 113.94,76.34 113.68,76.08 113.22,76.08 113,75.85 113,75.58 113,75.58 112.96,75.55 112.96,75.53 CPU1.AF68 ; DM2.7 56.28,86.18 v1(55.41,87.06)
M_B_DQ10: length 74.6
  TOP w0.089: v2(53.25,83) v1(53.25,82.43)
  L6 w0.102: v1(53.25,82.43) 53.25,82.73 53.6,83.08 58.22,83.08 58.32,82.98 58.32,82.49 58.43,82.39 58.63,82.39 58.73,82.49 58.73,82.98 58.83,83.08 59.3,83.08 59.4,82.98 59.4,82.52 59.5,82.41 59.7,82.41 59.81,82.52 59.81,82.98 59.91,83.08 60.11,83.08 60.21,82.98 60.21,82.52 60.31,82.41 60.52,82.41 60.62,82.52 60.62,82.98 60.72,83.08 62.81,83.08 64.11,81.78 71.72,81.78 73.79,83.85 88.14,83.85 89.99,85.69 99.66,85.69 101.28,87.32 104.36,87.32 107.34,84.33 107.34,83.73 109.27,81.8 110.17,81.8 110.77,81.21 110.77,79.65 v1(111.3,79.11)
  BOTTOM w0.089: v1(53.25,82.43) 52.75,82.93 DM2.20 ; CPU1.AH71 111.43,77.48 111.47,77.51 111.47,77.53 111.51,77.57 111.51,78.9 v1(111.3,79.11)
M_B_DQ11: length 77.4
  TOP w0.089: v2(57.52,83.23) v1(57.52,82.65)
  L6 w0.102: v1(57.52,82.65) 58.11,82.06 61.75,82.06 61.85,82.16 61.85,82.41 61.96,82.52 62.16,82.52 62.26,82.41 62.26,82.16 62.36,82.06 63.32,82.06 63.93,81.45 71.99,81.45 73.11,82.57 74.76,82.57 74.86,82.67 74.86,83.3 74.97,83.4 75.17,83.4 75.27,83.3 75.27,82.67 75.37,82.57 75.83,82.57 75.93,82.67 75.93,83.38 76.03,83.48 76.23,83.48 76.33,83.38 76.33,82.67 76.43,82.57 76.64,82.57 76.74,82.67 76.74,83.38 76.84,83.48 77.04,83.48 77.15,83.38 77.15,82.67 77.25,82.57 77.45,82.57 77.55,82.67 77.55,83.38 77.65,83.48 77.86,83.48 77.96,83.38 77.96,82.67 78.06,82.57 78.26,82.57 78.37,82.67 78.37,83.38 78.47,83.48 78.67,83.48 78.77,83.38 78.77,82.67 78.87,82.57 79.08,82.57 79.18,82.67 79.18,83.38 79.28,83.48 79.48,83.48 79.58,83.38 79.58,82.67 79.69,82.57 80.07,82.57 81.02,83.52 88.28,83.52 90.12,85.36 99.79,85.36 101.42,86.99 104.22,86.99 107.01,84.2 107.01,83.6 109.16,81.45 110.06,81.45 110.44,81.07 110.44,79.39 110.95,78.87 v1(110.95,78.42)
  BOTTOM w0.089: CPU1.AH68 111.03,75.48 111.03,75.91 111.06,75.93 111.06,76.88 111.08,76.9 111.08,77.37 111.29,77.59 111.29,77.6 111.33,77.64 111.33,78.04 110.95,78.42 v1(110.95,78.42) ; DM2.21 57.56,82.69 v1(57.52,82.65)
M_B_DQ12: length 74.3
  TOP w0.089: v2(52.57,86.49) v1(52.57,87.06)
  L6 w0.102: v1(113.35,77.28) 112.96,77.66 112.96,78.5 113.38,80.38 113.38,81.22 105.65,88.95 100.49,88.95 98.99,87.46 89.34,87.46 88.09,86.21 79.91,86.21 79.22,85.53 72.61,85.53 71.24,84.15 65.67,84.15 65.61,84.22 65.35,84.47 65.35,84.47 63.59,86.23 53.39,86.23 v1(52.57,87.06)
  BOTTOM w0.089: DM2.4 50.9,86.94 52.45,86.94 v1(52.57,87.06) ; CPU1.AF71 v1(113.35,77.28)
M_B_DQ13: length 76.6
  TOP w0.089: v2(56.83,86.48) v1(56.83,87.06)
  L6 w0.102: v1(113.43,76.46) 113.43,76.47 113.76,76.8 113.76,78.12 113.9,78.26 113.9,78.77 113.83,78.85 113.83,79.43 114.04,79.65 114.04,81.5 105.92,89.62 100.21,89.62 98.71,88.12 89.06,88.12 87.82,86.87 78.77,86.87 78.67,86.77 78.67,86.4 78.57,86.3 78.37,86.3 78.27,86.4 78.27,86.77 78.16,86.87 77.96,86.87 77.86,86.77 77.86,86.4 77.76,86.3 77.56,86.3 77.45,86.4 77.45,86.77 77.35,86.87 77.15,86.87 77.05,86.77 77.05,86.4 76.95,86.3 76.74,86.3 76.64,86.4 76.64,86.77 76.54,86.87 73.02,86.87 72.22,86.07 64.69,86.07 63.27,87.49 59.68,87.49 59.58,87.39 59.58,87.11 59.47,87.01 59.27,87.01 59.17,87.11 59.17,87.39 59.07,87.49 58.86,87.49 58.76,87.39 58.76,87.11 58.66,87.01 58.46,87.01 58.36,87.11 58.36,87.39 58.25,87.49 57.27,87.49 v1(56.83,87.06)
  BOTTOM w0.089: DM2.3 58.07,87.18 57.76,87.49 57.27,87.49 v1(56.83,87.06) ; CPU1.AF69 112.82,75.88 112.82,75.93 113.15,76.25 113.22,76.25 v1(113.43,76.46)
M_B_DQ14: length 76
  L6 w0.102: v1(111.48,79.72) 111.1,80.1 111.1,81.37 104.83,87.65 101.12,87.65 99.49,86.02 89.85,86.02 88.01,84.18 87.62,84.18 87.51,84.28 87.51,84.8 87.41,84.9 87.21,84.9 87.11,84.8 87.11,84.28 87.01,84.18 86.8,84.18 86.7,84.28 86.7,84.8 86.6,84.9 86.4,84.9 86.3,84.8 86.3,84.28 86.19,84.18 85.86,84.18 85.76,84.28 85.76,84.8 85.66,84.9 85.46,84.9 85.36,84.8 85.36,84.28 85.25,84.18 73.65,84.18 72.33,82.86 71.82,82.86 63.54,82.86 62.91,83.48 53.56,83.48 53.24,83.81 v1(53.24,84.62)
  BOTTOM w0.089: DM2.16 50.9,83.94 52.55,83.94 53.24,84.62 v1(53.24,84.62) ; v2(111.48,80.38) v1(111.48,79.72) 111.83,79.37 111.83,78.73 111.7,78.6 111.7,77.69 111.72,77.67 111.72,77.05 111.69,77.03 111.69,76.94 111.67,76.85 111.43,76.61 CPU1.AH70
M_B_DQ15: length 76.9
  TOP w0.089: v2(54.67,85.28) v1(54.67,84.69)
  L6 w0.102: v1(54.67,84.69) 55.53,83.84 58.07,83.84 58.17,83.94 58.17,84.24 58.27,84.34 58.47,84.34 58.57,84.24 58.57,83.94 58.68,83.84 58.88,83.84 58.98,83.94 58.98,84.24 59.08,84.34 59.29,84.34 59.39,84.24 59.39,83.94 59.49,83.84 63.3,83.84 63.94,83.19 71.96,83.19 73.29,84.52 83.93,84.52 84.03,84.62 84.03,85.13 84.13,85.23 84.34,85.23 84.44,85.13 84.44,84.62 84.54,84.52 84.74,84.52 84.84,84.62 84.84,85.13 84.95,85.23 88.59,85.23 89.71,86.35 99.35,86.35 100.98,87.98 104.96,87.98 111.83,81.1 111.83,80.59 111.91,80.51 111.91,78.86 v1(112.21,78.56)
  BOTTOM w0.089: v1(54.67,84.69) 55.68,83.69 DM2.17 ; v1(112.21,78.56) 111.88,78.23 111.88,77.77 111.9,77.75 111.9,77.02 111.83,76.76 111.83,76.12 CPU1.AH69
M_B_DQ16: length 62.9
  TOP w0.089: v2(53.76,77.02) v1(53.76,76.44)
  L6 w0.102: v1(106.78,74.34) 106.78,75.02 106.13,75.67 105.81,75.67 105.45,76.04 104.9,76.04 104.62,76.32 101.37,76.32 99.69,77.99 99.24,77.99 97.6,79.63 90.45,79.63 89.12,78.3 76.2,78.3 73.04,75.15 60.71,75.15 60.25,75.61 53.9,75.61 53.76,75.74 v1(53.76,76.44)
  BOTTOM w0.089: CPU1.AT66 107.05,73.89 106.81,74.13 106.81,74.29 106.78,74.31 v1(106.78,74.34) ; v1(53.76,76.44) 53.76,76.38 52.81,75.44 DM2.50
M_B_DQ17: length 62.2
  TOP w0.089: v2(105.51,73.35) v1(106.07,73.35)
  L6 w0.102: v1(106.07,73.35) 105.87,73.55 105.03,73.55 104.04,74.54 102.61,74.54 102.46,74.39 102.16,74.39 101.9,74.64 101.9,74.69 99.59,77 98.83,77 97.18,78.66 90.89,78.66 89.56,77.33 76.6,77.33 73.32,74.06 64.91,74.06 64.73,73.88 64.48,73.88 64.3,74.06 61.82,74.06 61.11,73.35 55.55,73.35 v1(55.22,73.68)
  BOTTOM w0.089: DM2.49 57.97,75.69 57.95,75.66 57.94,75.66 57.71,75.43 56,75.43 55.17,74.6 55.17,73.72 v1(55.22,73.68) ; v1(106.07,73.35) 106.07,73.6 106.27,73.8 CPU1.AU66
M_B_DQ18: length 65.6
  TOP w0.089: v1(54.5,71.89) 54.5,71.48 v2(53.95,70.93)
  L6 w0.102: v1(54.5,71.89) 54.5,72.17 54.68,72.36 71.04,72.36 71.75,73.07 73.73,73.07 77.01,76.34 90.62,76.34 90.72,76.45 90.72,77.09 90.84,77.21 91.01,77.21 91.13,77.09 91.13,76.45 91.23,76.34 91.59,76.34 91.67,76.42 91.67,76.9 91.9,77.13 97.23,77.13 98.35,76.01 99.64,76.01 102.41,73.24 103.76,73.24 104.32,72.69 105.17,72.69 105.82,72.04 107.63,72.04 v1(108.03,72.43)
  BOTTOM w0.089: v1(108.03,72.43) 108.35,72.76 CPU1.AP65 ; DM2.62 50.9,72.43 54.23,72.43 54.5,72.16 v1(54.5,71.89)
M_B_DQ19: length 66.4
  TOP w0.089: v2(58.14,71.89) v1(57.34,71.89)
  L6 w0.102: v1(108.68,72.43) 108.08,71.83 105.75,71.83 105.13,72.46 104.24,72.46 103.66,73.04 102.33,73.04 99.69,75.68 98.04,75.68 96.92,76.8 93.6,76.8 92.81,76.01 92.51,76.01 92.4,76.12 92.4,76.43 92.28,76.55 92.12,76.55 92,76.43 92,76.12 91.9,76.01 77.14,76.01 73.87,72.74 72.42,72.74 72.19,72.51 72.04,72.51 71.93,72.62 71.79,72.62 71.64,72.48 71.64,72.33 71.76,72.22 71.76,72.08 71.61,71.93 71.47,71.93 71.36,72.04 71.21,72.04 71.07,71.9 71.07,71.76 71.18,71.64 71.18,71.5 70.94,71.26 65.18,71.26 65.08,71.36 65.08,71.92 64.98,72.03 64.77,72.03 64.67,71.92 64.67,71.36 64.57,71.26 64.37,71.26 64.27,71.36 64.27,71.92 64.16,72.03 63.96,72.03 63.86,71.92 63.86,71.36 63.76,71.26 63.55,71.26 63.45,71.36 63.45,71.92 63.35,72.03 63.15,72.03 63.05,71.92 63.05,71.36 62.94,71.26 62.74,71.26 62.64,71.36 62.64,71.92 62.54,72.03 62.34,72.03 62.23,71.92 62.23,71.36 62.13,71.26 61.87,71.26 61.24,71.89 v1(57.34,71.89)
  BOTTOM w0.089: v1(108.68,72.43) 109,72.76 CPU1.AN65 ; v1(57.34,71.89) 57.34,71.89 57.64,72.19 DM2.63
M_B_DQ20: length 65.2
  TOP w0.089: v2(52.34,77.02) v1(52.34,76.44)
  L6 w0.102: v1(108.68,73.35) 108.3,73.72 108.3,74.49 106.63,76.17 105.87,76.17 105.28,76.75 101.47,76.75 97.38,80.84 90.73,80.84 88.85,78.96 75.92,78.96 72.77,75.81 61.47,75.81 60.41,76.87 52.77,76.87 v1(52.34,76.44)
  BOTTOM w0.089: v1(52.34,76.44) 52.32,76.42 50.92,76.42 DM2.46 ; v1(108.68,73.35) 109,73.67 CPU1.AN66
M_B_DQ21: length 64.6
  TOP w0.089: v2(57.32,77.03) v1(57.32,76.44)
  L6 w0.102: v1(57.32,76.44) 57.8,76.44 57.9,76.34 57.9,76.09 58,75.99 58.2,75.99 58.3,76.09 58.3,76.34 58.41,76.44 58.61,76.44 58.71,76.34 58.71,76.09 58.81,75.99 59.02,75.99 59.12,76.09 59.12,76.34 59.22,76.44 59.42,76.44 59.52,76.34 59.52,76.09 59.62,75.99 59.83,75.99 59.93,76.09 59.93,76.34 60.03,76.44 60.33,76.44 61.29,75.48 72.91,75.48 76.06,78.63 88.98,78.63 90.32,79.96 90.73,79.96 90.83,80.06 90.83,80.41 90.93,80.51 91.13,80.51 91.24,80.41 91.24,80.06 91.34,79.96 91.54,79.96 91.64,80.06 91.64,80.41 91.74,80.51 91.95,80.51 92.05,80.41 92.05,80.06 92.15,79.96 92.35,79.96 92.46,80.06 92.46,80.41 92.56,80.51 92.76,80.51 92.86,80.41 92.86,80.06 92.96,79.96 93.17,79.96 93.27,80.06 93.27,80.41 93.37,80.51 93.57,80.51 93.67,80.41 93.67,80.06 93.78,79.96 97.73,79.96 97.93,79.77 97.94,79.77 99.39,78.32 99.63,78.32 101.39,76.56 105.19,76.56 105.79,75.96 106.2,75.96 107.29,74.87 107.29,74.09 v1(108.03,73.35)
  BOTTOM w0.089: DM2.45 57.56,76.69 v1(57.32,76.44) ; CPU1.AP66 108.35,73.67 v1(108.03,73.35)
M_B_DQ22: length 64.4
  TOP w0.089: v2(52.4,72.94) 53.01,73.55 v1(53.01,73.75)
  L6 w0.102: v1(106.73,72.43) 106.32,72.84 105.58,72.84 105.33,73.09 105.05,73.09 104.49,73.65 102.56,73.65 99.54,76.67 98.68,76.67 97.03,78.32 91.02,78.32 89.7,77 76.73,77 73.46,73.73 71.47,73.73 70.76,73.02 64.02,73.02 63.92,73.12 63.92,73.45 63.82,73.55 63.61,73.55 63.51,73.45 63.51,73.12 63.41,73.02 55.27,73.02 54.79,73.5 54.79,74.16 54.58,74.36 53.62,74.36 v1(53.01,73.75)
  BOTTOM w0.089: CPU1.AT65 107.05,72.76 v1(106.73,72.43) ; DM2.58 51.93,73.44 52.07,73.3 52.55,73.3 v1(53.01,73.75)
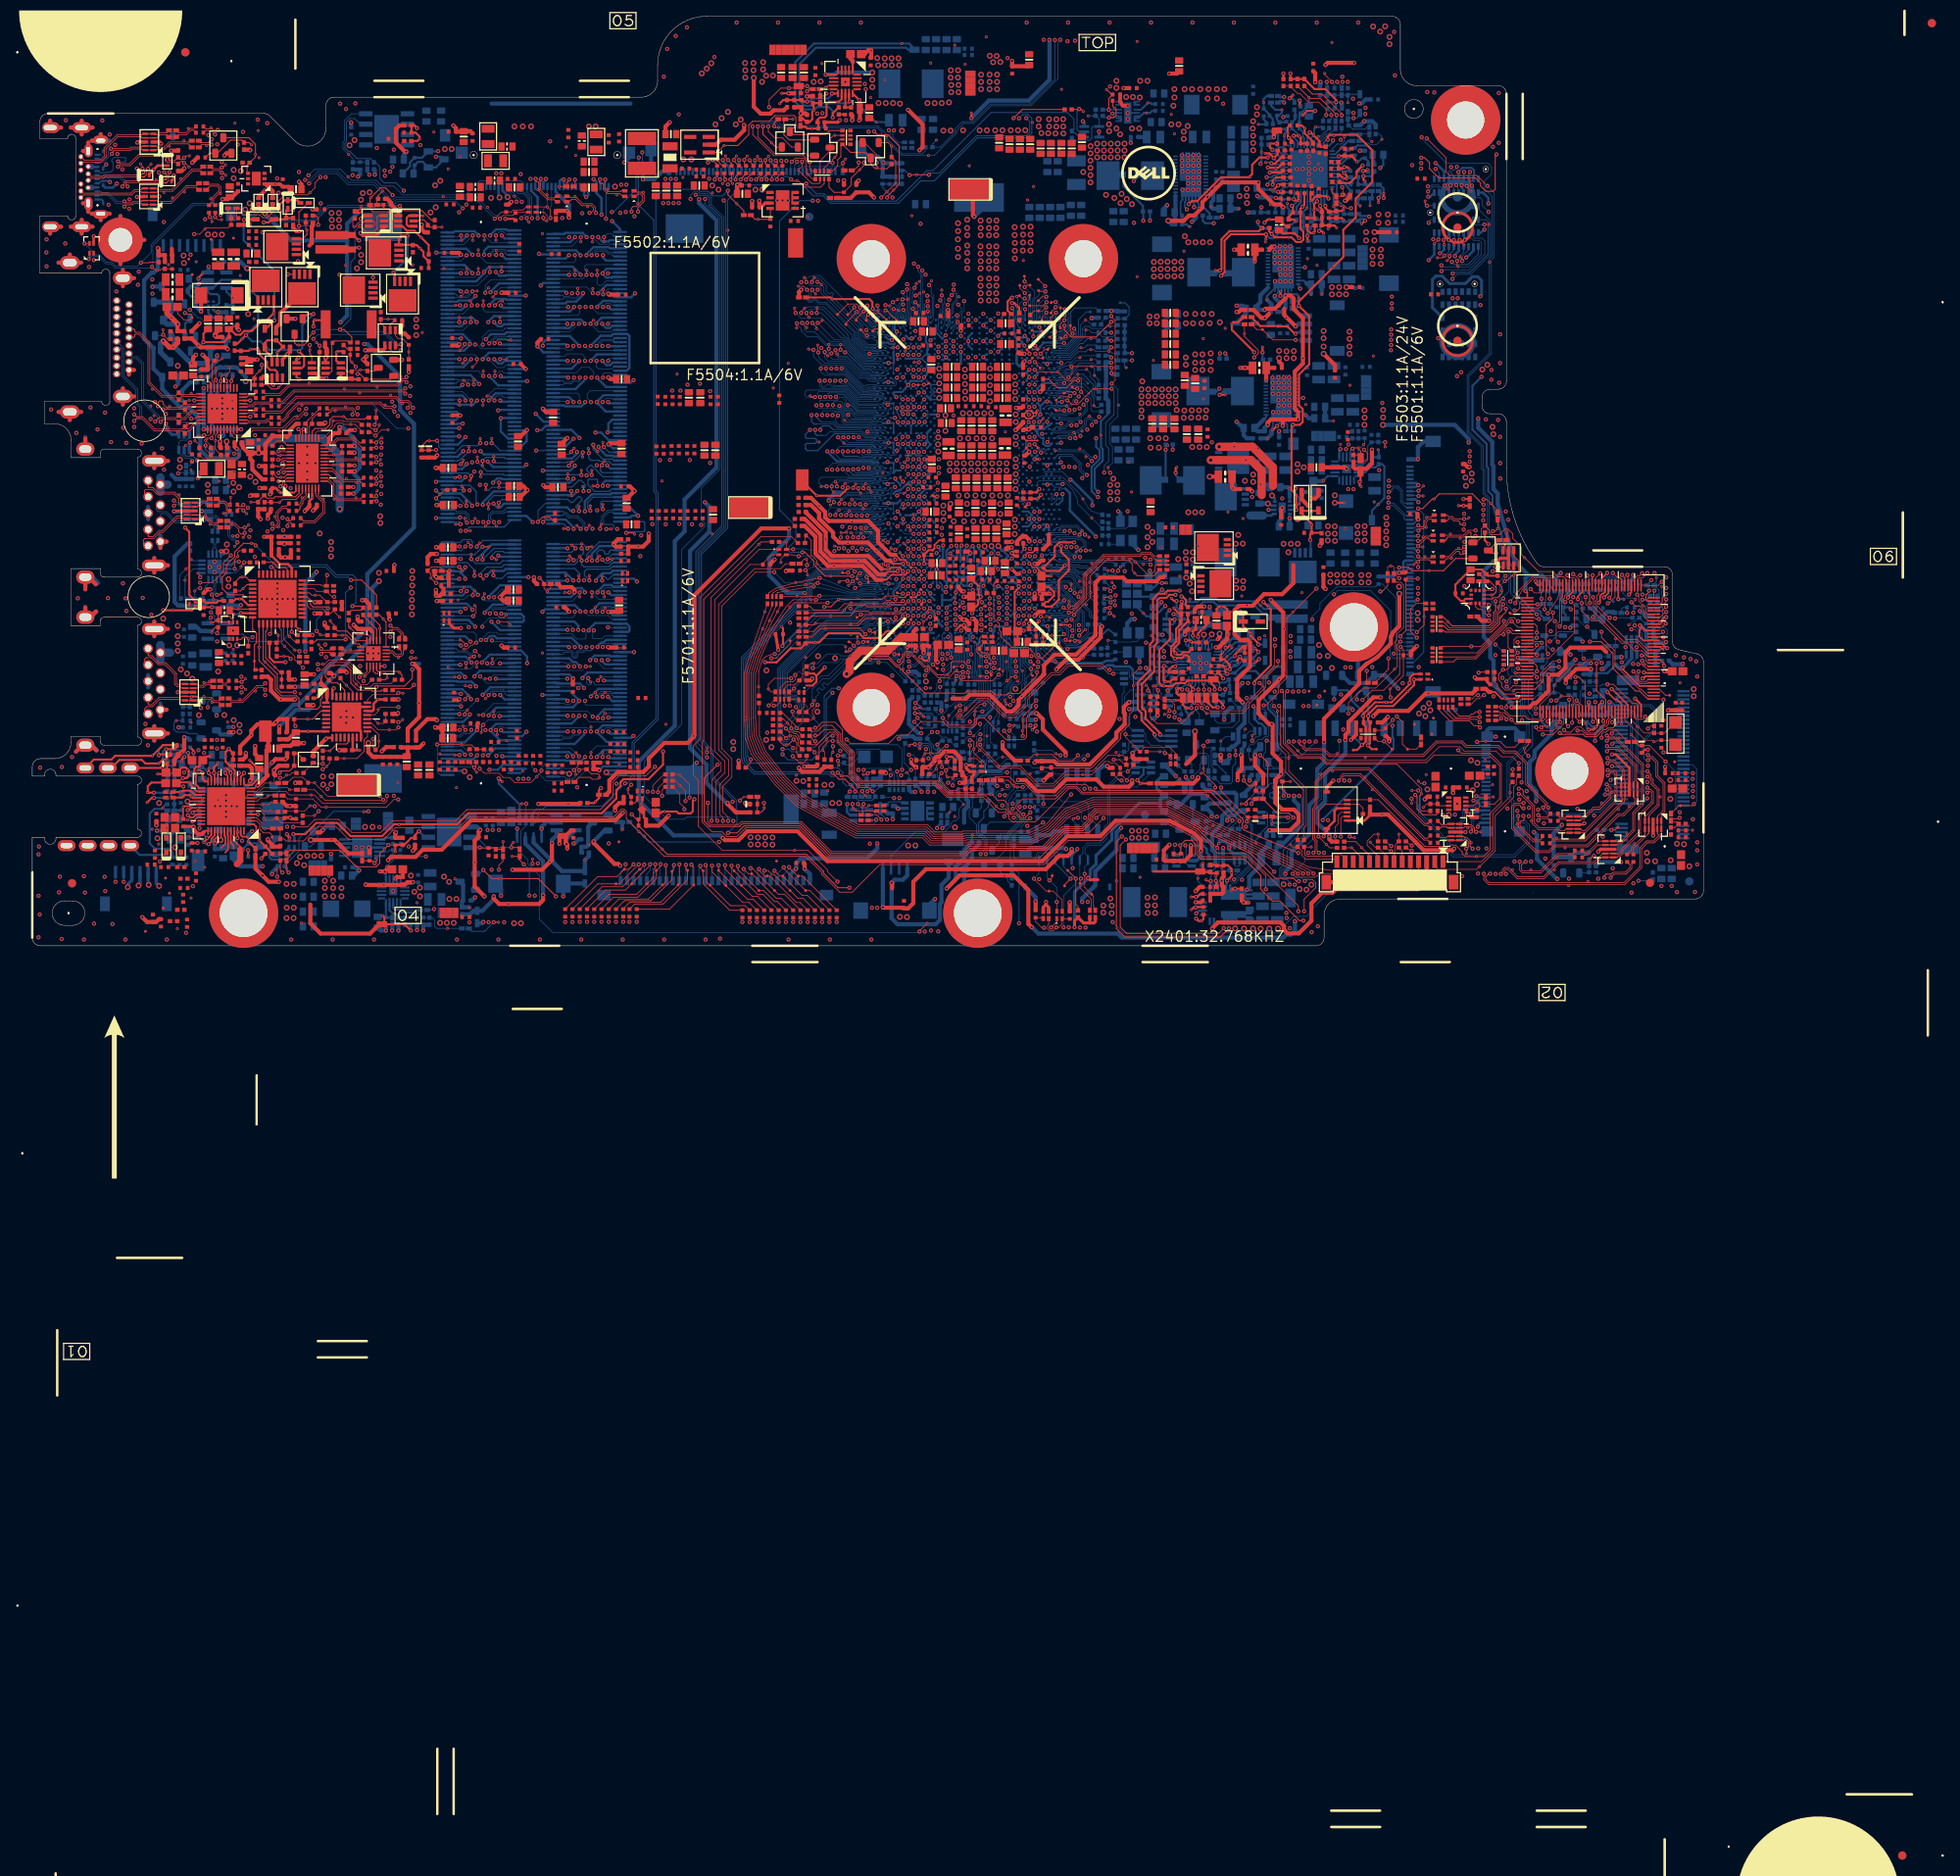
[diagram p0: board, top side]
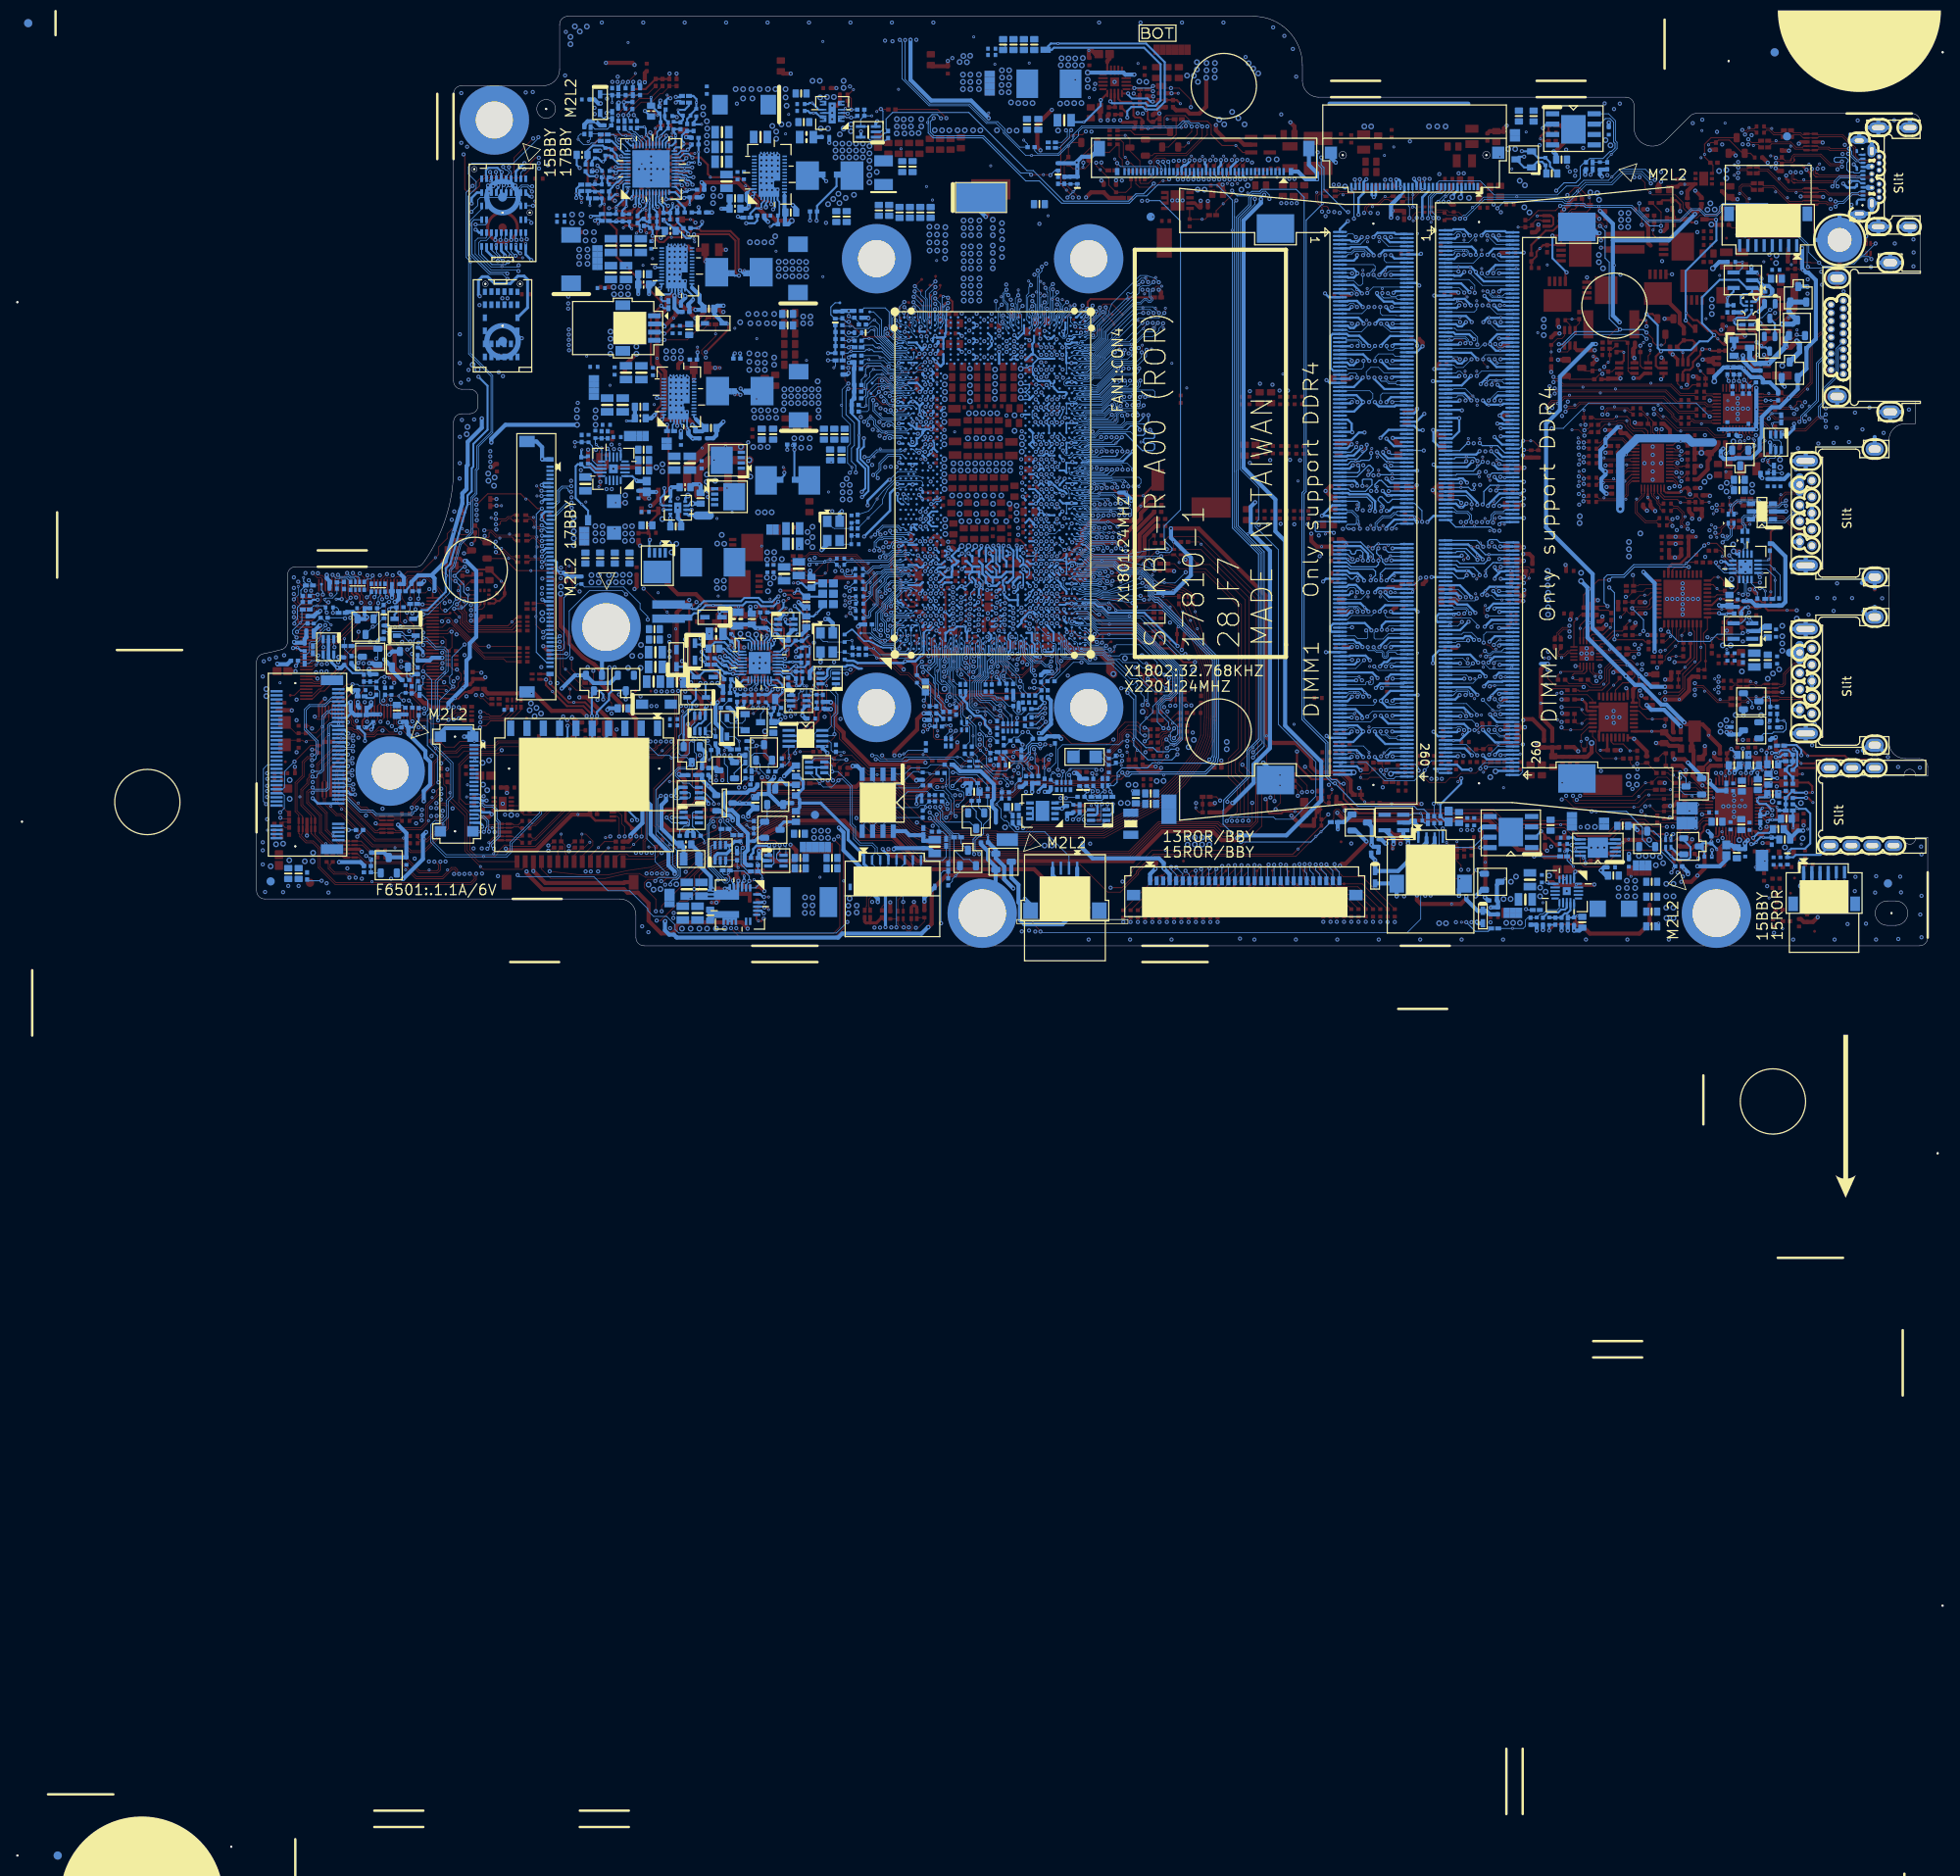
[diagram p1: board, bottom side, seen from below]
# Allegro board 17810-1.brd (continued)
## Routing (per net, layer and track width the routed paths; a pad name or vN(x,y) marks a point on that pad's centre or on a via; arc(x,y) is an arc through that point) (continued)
M_B_DQ23: length 63.5
  TOP w0.089: v2(106.07,71.87) 106.07,72.43 v1(106.07,72.44)
  L6 w0.102: v1(106.07,72.44) 105.71,72.44 105.26,72.89 104.47,72.89 103.91,73.45 102.49,73.45 99.59,76.34 98.49,76.34 96.83,77.99 92.05,77.99 91.95,77.89 91.95,77.73 91.83,77.61 91.66,77.61 91.54,77.73 91.54,77.89 91.44,77.99 91.16,77.99 89.84,76.67 76.87,76.67 73.59,73.4 71.61,73.4 70.9,72.69 55.13,72.69 54.28,73.54 v1(54.28,73.7)
  BOTTOM w0.089: DM2.59 55.03,73.19 54.52,73.7 v1(54.28,73.7) ; v1(106.07,72.44) 106.4,72.77 CPU1.AU65
M_B_DQ24: length 63.6
  TOP w0.089: v2(55.28,70.43) v1(55.28,69.83)
  L6 w0.102: v1(107.38,70.6) 106.79,71.19 105.74,71.19 105.4,70.84 104.97,70.84 104.56,71.26 104.56,71.28 104.09,71.75 102.33,71.75 101.83,72.25 101.83,72.69 99.79,74.72 97.58,74.72 97.28,75.01 77.56,75.01 74.15,71.6 72.86,71.6 71.36,70.1 58.5,70.1 58.34,69.94 58.34,69.71 58.22,69.59 58.05,69.59 57.93,69.71 57.93,70.28 57.83,70.38 55.83,70.38 v1(55.28,69.83)
  BOTTOM w0.089: DM2.70 50.91,70.43 54.69,70.43 v1(55.28,69.83) ; v1(107.38,70.6) 107.05,70.93 CPU1.AT61
M_B_DQ25: length 62.8
  TOP w0.089: v2(56.71,70.43) v1(56.71,69.83)
  L6 w0.102: v1(106.04,70.63) 106.01,70.65 104.72,70.65 103.83,71.54 102.26,71.54 101.62,72.18 101.62,72.61 99.72,74.51 97.31,74.51 97.15,74.68 77.69,74.68 74.29,71.27 73,71.27 70.82,69.09 64.79,69.09 64.69,69.19 64.69,69.64 64.58,69.74 64.38,69.74 64.28,69.64 64.28,69.19 64.18,69.09 63.97,69.09 63.87,69.19 63.87,69.64 63.77,69.74 63.57,69.74 63.47,69.64 63.47,69.19 63.36,69.09 63.16,69.09 63.06,69.19 63.06,69.64 62.96,69.74 62.76,69.74 62.65,69.64 62.65,69.19 62.55,69.09 62.35,69.09 62.25,69.19 62.25,69.64 62.15,69.74 61.94,69.74 61.84,69.64 61.84,69.19 61.74,69.09 61.46,69.09 60.84,69.71 60.23,69.71 59.62,69.1 56.92,69.1 56.71,69.32 v1(56.71,69.83)
  BOTTOM w0.089: v1(106.04,70.63) 106.04,70.69 CPU1.AU61 ; v1(56.71,69.83) 56.71,69.83 57.29,70.42 57.59,70.42 57.82,70.19 59,70.19 DM2.71
M_B_DQ26: length 66.3
  TOP w0.089: v2(55.75,67.38) 56.12,67.38 v1(56.66,66.84)
  L6 w0.102: v1(56.66,66.84) 56.66,66.65 56.9,66.41 58.16,66.41 58.26,66.51 58.26,66.84 58.36,66.94 58.57,66.94 58.67,66.84 58.67,66.51 58.77,66.41 59.43,66.41 59.53,66.51 59.53,66.82 59.63,66.92 59.84,66.92 59.94,66.82 59.94,66.51 60.04,66.41 61.77,66.41 62.31,66.95 64.83,66.95 65.34,67.45 72.77,67.45 72.9,67.59 72.9,67.73 72.46,68.17 72.46,68.32 72.61,68.46 72.75,68.46 73.19,68.02 73.33,68.02 73.48,68.16 73.48,68.31 73.04,68.75 73.04,68.92 73.16,69.04 73.32,69.04 73.77,68.59 73.91,68.59 78.28,72.96 95.08,72.96 95.86,72.18 99.79,72.18 101.65,70.32 103.05,70.32 104.66,68.71 105.11,68.71 105.36,68.95 106.63,68.95 107.01,69.33 108.32,69.33 v1(108.68,69.69)
  BOTTOM w0.089: v1(108.68,69.69) 108.35,70.01 CPU1.AP60 ; v1(56.66,66.84) 56.66,67.09 56.97,67.4 57.58,67.4 57.8,67.19 DM2.83
M_B_DQ27: length 66.4
  TOP w0.089: v2(52.39,66.26) v1(52.39,66.84)
  L6 w0.102: v1(52.39,66.84) 53.15,66.08 61.91,66.08 62.45,66.62 64.97,66.62 65.48,67.12 72.47,67.12 72.9,67.12 78.42,72.63 95.04,72.63 95.69,71.99 99.71,71.99 101.57,70.12 102.92,70.12 104.52,68.52 105.2,68.52 105.36,68.67 106.62,68.67 107.06,69.12 108.65,69.12 108.76,69.23 109.43,69.23 109.72,69.53 109.72,70.21 v1(109.33,70.6)
  BOTTOM w0.089: v1(52.39,66.84) 52.29,66.94 50.9,66.94 DM2.84 ; v1(109.33,70.6) 109,70.28 CPU1.AN60
M_B_DQ28: length 65.7
  TOP w0.089: v2(52.78,71.39) 53.07,71.69 v1(53.07,71.89)
  L6 w0.102: v1(53.07,71.89) 53.07,70.94 53.31,70.71 54.57,70.71 54.67,70.81 54.67,71.11 54.77,71.21 54.97,71.21 55.08,71.11 55.08,70.81 55.18,70.71 59.88,70.71 60.3,71.13 60.92,71.13 61.61,70.43 71.13,70.43 72.64,71.95 74.01,71.95 77.42,75.35 97.41,75.35 97.74,75.02 99.79,75.02 102.03,72.79 102.03,72.33 102.41,71.95 105.05,71.95 105.61,71.39 107.89,71.39 v1(108.68,70.6)
  BOTTOM w0.089: v1(108.68,70.6) 109,70.93 CPU1.AN61 ; v1(53.07,71.89) 53.07,71.89 52.62,71.44 DM2.66
M_B_DQ29: length 65.1
  TOP w0.089: v2(108.1,71.52) v1(108.68,71.52)
  L6 w0.102: v1(55.92,71.89) 55.92,71.22 56.1,71.04 56.48,71.04 56.58,71.14 56.58,71.34 56.68,71.44 56.88,71.44 56.98,71.34 56.98,71.14 57.09,71.04 57.29,71.04 57.39,71.14 57.39,71.34 57.49,71.44 57.69,71.44 57.8,71.34 57.8,71.14 57.9,71.04 58.1,71.04 58.2,71.14 58.2,71.34 58.3,71.44 58.51,71.44 58.61,71.34 58.61,71.14 58.71,71.04 58.91,71.04 59.02,71.14 59.02,71.3 59.13,71.42 59.3,71.42 59.42,71.3 59.42,71.14 59.52,71.04 59.75,71.04 60.16,71.46 61.12,71.46 61.82,70.76 70.99,70.76 72.51,72.28 73.88,72.28 77.28,75.68 97.54,75.68 97.87,75.35 99.74,75.35 102.23,72.86 102.23,72.41 102.49,72.15 105.13,72.15 105.69,71.59 108.6,71.59 v1(108.68,71.52)
  BOTTOM w0.089: CPU1.AP61 108.35,71.19 v1(108.68,71.52) ; v1(55.92,71.89) 56.93,70.88 57.77,70.88 58.08,71.19 DM2.67
M_B_DQ30: length 65.5
  TOP w0.089: v2(55.23,66.26) v1(55.23,66.84)
  L6 w0.102: v1(55.23,66.84) 55.66,67.27 60.21,67.27 60.31,67.17 60.31,66.84 60.41,66.74 60.61,66.74 60.71,66.84 60.71,67.17 60.82,67.27 61.02,67.27 61.12,67.17 61.12,66.84 61.22,66.74 61.43,66.74 61.53,66.84 61.53,67.17 61.63,67.27 61.9,67.27 62.42,67.78 62.57,67.78 62.67,67.68 62.67,67.38 62.77,67.28 62.97,67.28 63.07,67.38 63.07,67.68 63.17,67.78 63.38,67.78 63.48,67.68 63.48,67.38 63.58,67.28 63.78,67.28 63.89,67.38 63.89,67.68 63.99,67.78 71.31,67.78 71.32,67.8 71.36,67.8 73.53,69.98 74.82,69.98 78.14,73.3 95.12,73.3 95.51,73.68 99.26,73.68 100.51,72.43 100.51,71.98 101.96,70.53 103.48,70.53 104.39,69.61 105.03,69.61 105.42,69.22 106.26,69.22 v1(106.73,69.69)
  BOTTOM w0.089: v1(106.73,69.69) 107.05,70.01 CPU1.AT60 ; DM2.79 58.95,68.19 58.93,68.16 58.21,68.16 58.11,68.27 56.66,68.27 v1(55.23,66.84)
M_B_DQ31: length 64.7
  TOP w0.089: v2(53.81,66.26) v1(53.81,66.84)
  L6 w0.102: v1(105.99,69.61) 105.61,69.61 105.36,69.87 104.43,69.87 103.41,70.88 101.92,70.88 100.99,71.81 100.99,72.21 99.32,73.88 95.35,73.88 95.1,73.63 78,73.63 74.69,70.31 73.4,70.31 71.22,68.13 71.18,68.13 71.17,68.11 62.28,68.11 61.8,67.63 61.63,67.63 61.53,67.73 61.53,68.01 61.43,68.11 61.23,68.11 61.12,68.01 61.12,67.73 61.02,67.63 60.82,67.63 60.72,67.73 60.72,68.01 60.62,68.11 60.41,68.11 60.31,68.01 60.31,67.73 60.21,67.63 60.01,67.63 59.9,67.73 59.9,68.01 59.8,68.11 59.6,68.11 59.5,68.01 59.5,67.73 59.4,67.63 59.19,67.63 59.09,67.73 59.09,67.87 58.97,67.99 58.8,67.99 58.69,67.87 58.69,67.73 58.58,67.63 53.97,67.63 53.81,67.47 v1(53.81,66.84)
  BOTTOM w0.089: CPU1.AU60 106,69.74 106,69.67 105.99,69.66 v1(105.99,69.61) ; v1(53.81,66.84) 52.71,67.94 50.9,67.94 DM2.80
M_B_DQ32: length 65.4
  TOP w0.089: v1(54,42.97) 54,43.27 v2(54.23,43.5)
  L6 w0.102: v1(54,42.97) 55.01,41.95 58.14,41.95 58.14,41.95 58.18,41.95 58.7,41.43 71.23,41.43 71.65,41.01 76.77,41.01 89.35,53.59 93.37,53.59 96.92,57.14 102.92,57.14 104.44,58.67 106.66,58.67 v1(106.68,58.69)
  BOTTOM w0.089: DM2.174 50.9,42.43 52.92,42.43 53.45,42.97 v1(54,42.97) ; v1(106.68,58.69) 106.4,58.96 CPU1.AU40
M_B_DQ33: length 65.9
  TOP w0.089: v2(55.42,43.15) 55.29,43.02 v1(55.29,42.59)
  L6 w0.102: v1(55.29,42.59) 55.29,42.82 55.62,43.15 57.92,43.15 58.98,42.09 76.92,42.09 89.16,54.34 93.46,54.34 96.67,57.55 102.53,57.55 104.68,59.7 105.04,59.7 105.62,59.11 106.13,59.11 106.65,59.63 v1(107.33,59.63)
  BOTTOM w0.089: v1(107.33,59.63) 107.05,59.36 CPU1.AT40 ; v1(55.29,42.59) 55.29,42.51 55.52,42.28 57.48,42.28 57.86,42.66 59.08,42.66 DM2.173
M_B_DQ34: length 67.2
  TOP w0.089: v1(57.1,39.69) 58.22,39.69 v2(58.55,39.36)
  L6 w0.102: v1(107.38,57.8) 107.33,57.85 106.35,57.85 106.16,58.04 104.91,58.04 103.53,56.66 103.53,56.52 102.66,55.64 98.8,55.64 98.65,55.8 96.59,55.8 93.43,52.63 92.25,52.63 92.1,52.48 89.65,52.48 89.38,52.2 89.38,52.06 89.73,51.71 89.73,51.57 89.58,51.42 89.44,51.42 89.09,51.77 88.95,51.77 88.8,51.63 88.8,51.49 89.15,51.14 89.15,50.99 89.01,50.85 88.86,50.85 88.52,51.2 88.37,51.2 88.23,51.05 88.23,50.91 88.58,50.56 88.58,50.42 88.43,50.27 88.29,50.27 87.94,50.62 87.8,50.62 87.33,50.15 87.33,50.01 87.66,49.67 87.66,49.53 87.52,49.39 87.37,49.39 87.04,49.72 86.9,49.72 77.02,39.84 65.16,39.84 64.91,39.59 57.2,39.59 v1(57.1,39.69)
  BOTTOM w0.089: CPU1.AT37 107.38,57.67 v1(107.38,57.8) ; v1(57.1,39.69) 57.6,39.19 59.1,39.19 DM2.187
M_B_DQ35: length 66.8
  TOP w0.089: v2(106.42,57.42) 106.42,57.21 v1(106.74,56.89)
  L6 w0.102: v1(53.49,39.06) 53.49,39.31 53.72,39.54 55.36,39.54 55.97,38.93 65.2,38.93 65.43,39.16 68.96,39.16 69.7,38.42 70.94,38.42 71.68,39.16 77.27,39.16 86.69,48.58 87.69,48.58 90.93,51.82 91.95,51.82 92.22,51.82 92.65,52.25 94.01,52.25 97.13,55.36 98.52,55.36 98.63,55.26 102.81,55.26 104.24,56.69 104.24,56.81 105.1,57.66 105.97,57.66 v1(106.74,56.89)
  BOTTOM w0.089: CPU1.AU37 106.4,57.23 v1(106.74,56.89) ; DM2.186 52.75,39.44 53.24,39.44 53.49,39.18 v1(53.49,39.06)
M_B_DQ36: length 66.6
  TOP w0.089: v2(52.91,43.93) 52.91,43.84 v1(52.54,43.48)
  L6 w0.102: v1(52.54,43.48) 52.97,43.91 53.56,43.91 54,43.48 58.06,43.48 59.11,42.42 76.78,42.42 89.03,54.67 93.48,54.67 96.57,57.75 102.47,57.75 104.74,60.03 107.61,60.03 v1(108.01,59.63)
  BOTTOM w0.089: v1(52.54,43.48) 52.49,43.43 50.91,43.43 DM2.170 ; v1(108.01,59.63) 107.7,59.32 CPU1.AR40
M_B_DQ37: length 67.6
  TOP w0.089: v2(109.04,59.17) 109.04,59.26 v1(108.67,59.63)
  L6 w0.102: v1(108.67,59.63) 108.23,59.19 106.61,59.19 106.3,58.87 104.37,58.87 102.84,57.34 96.82,57.34 93.39,53.92 89.21,53.92 77.06,41.76 76.47,41.76 76.37,41.66 76.37,41.44 76.27,41.34 76.06,41.34 75.96,41.44 75.96,41.66 75.86,41.76 75.66,41.76 75.56,41.66 75.56,41.44 75.45,41.34 75.25,41.34 75.15,41.44 75.15,41.66 75.05,41.76 74.84,41.76 74.74,41.66 74.74,41.44 74.64,41.34 74.44,41.34 74.34,41.44 74.34,41.66 74.23,41.76 74.03,41.76 73.93,41.66 73.93,41.44 73.83,41.34 73.62,41.34 73.52,41.44 73.52,41.66 73.42,41.76 73.22,41.76 73.12,41.66 73.12,41.44 73.02,41.34 72.81,41.34 72.71,41.44 72.71,41.66 72.61,41.76 72.41,41.76 72.3,41.66 72.3,41.44 72.2,41.34 72,41.34 71.9,41.44 71.9,41.66 71.8,41.76 58.84,41.76 58.32,42.28 58.28,42.28 57.05,42.28 v1(56.61,42.71)
  BOTTOM w0.089: v1(108.67,59.63) 108.35,59.31 CPU1.AP40 ; DM2.169 57.56,43.69 56.69,42.82 56.69,42.79 v1(56.61,42.71)
M_B_DQ38: length 68.5
  TOP w0.089: v1(108.68,57.8) 108.35,57.48 v2(108.35,57.34)
  L6 w0.102: v1(108.68,57.8) 108.17,57.29 107.75,57.29 107.64,57.18 106.94,56.48 106.55,56.48 106.18,56.85 105.62,56.85 105.48,56.99 104.69,56.99 104.44,56.74 104.44,56.62 102.89,55.07 98.54,55.07 98.47,55.13 97.39,55.13 93.67,51.41 93.15,51.41 92.95,51.61 92.47,51.61 92.36,51.49 91.81,51.49 91.06,51.49 87.83,48.25 86.83,48.25 77.4,38.83 71.81,38.83 71.08,38.09 65.3,38.09 64.79,38.6 55.68,38.6 v1(55.17,39.11)
  BOTTOM w0.089: DM2.183 59.1,40.19 56.02,40.19 55.17,39.34 v1(55.17,39.11) ; v1(108.68,57.8) 108.35,57.48 v2(108.35,57.34)
M_B_DQ39: length 69
  TOP w0.089: v1(54.03,40.4) 54.41,40.77 54.41,41.52 v2(54.23,41.7)
  L6 w0.102: v1(108.03,57.8) 107.95,57.8 107.56,57.41 107.21,57.41 106.96,57.66 106.27,57.66 106.08,57.85 104.99,57.85 103.73,56.6 103.73,56.45 102.73,55.45 98.72,55.45 98.56,55.6 96.78,55.6 93.62,52.44 92.37,52.44 92.08,52.15 90.79,52.15 87.55,48.91 86.55,48.91 77.15,39.51 65.3,39.51 65.05,39.26 56.11,39.26 55.4,39.97 55.4,40.28 55.29,40.38 55.09,40.38 54.99,40.28 54.99,39.97 54.89,39.87 54.25,39.87 54.03,40.09 v1(54.03,40.4)
  BOTTOM w0.089: DM2.182 54,40.44 v1(54.03,40.4) ; v1(108.03,57.8) 108.03,57.67 CPU1.AR37
M_B_DQ40: length 68.8
  TOP w0.089: v1(107.38,55.97) 106.84,55.44 v2(106.81,55.44)
  L6 w0.102: v1(107.38,55.97) 107.28,56.07 106.15,56.07 105.91,55.83 105.58,55.83 105.45,55.96 104.66,55.96 102.36,53.66 97.03,53.66 93.68,50.32 90.83,50.32 88.1,47.59 87.1,47.59 77.68,38.17 72.86,38.17 72.75,38.07 72.75,37.18 72.65,37.08 72.45,37.08 72.35,37.18 72.35,38.07 72.25,38.17 72.09,38.17 71.31,37.38 63.37,37.38 62.86,37.89 62.64,37.89 62.54,37.79 62.54,37.46 62.44,37.35 62.24,37.35 62.14,37.46 62.14,37.79 62.03,37.89 61.83,37.89 61.73,37.79 61.73,37.46 61.63,37.35 61.42,37.35 61.32,37.46 61.32,37.79 61.22,37.89 61.02,37.89 60.92,37.79 60.92,37.46 60.81,37.35 60.61,37.35 60.51,37.46 60.51,37.79 60.41,37.89 60.2,37.89 60.1,37.79 60.1,37.46 60,37.35 59.8,37.35 59.7,37.46 59.7,37.79 59.6,37.89 56.79,37.89 v1(56.34,37.43)
  BOTTOM w0.089: DM2.195 59.1,37.19 57.82,37.19 57.7,37.3 56.46,37.3 v1(56.34,37.43) ; v1(107.38,55.97) 107.05,55.65 CPU1.AT33
M_B_DQ41: length 68.6
  TOP w0.089: v1(53.19,36.87) 52.58,37.48 v2(52.42,37.48)
  L6 w0.102: v1(53.19,36.87) 53.2,36.87 53.45,36.62 54.43,36.62 54.68,36.37 62.76,36.37 63.07,36.37 63.07,36.37 63.63,36.37 63.9,36.1 64.71,36.1 64.81,36 64.81,35.72 64.93,35.6 65.1,35.6 65.22,35.72 65.22,36 65.32,36.1 65.53,36.1 65.63,36 65.63,35.4 65.73,35.3 65.93,35.3 66.03,35.4 66.03,36 66.13,36.1 66.34,36.1 66.44,36 66.44,35.4 66.54,35.3 66.74,35.3 66.85,35.4 66.85,36 66.95,36.1 70.89,36.1 71.21,36.41 72.96,36.41 74.05,37.51 77.95,37.51 87.37,46.93 88.37,46.93 91.1,49.66 94.12,49.66 97.65,53.19 97.67,53.19 97.69,53.2 102.51,53.2 104.49,55.18 v1(106.01,55.18)
  BOTTOM w0.089: CPU1.AU33 106.38,55.52 106.04,55.18 v1(106.01,55.18) ; v1(53.19,36.87) 52.62,37.44 DM2.194
M_B_DQ42: length 67.1
  TOP w0.089: v1(106.73,54.14) 106.78,54.09 v2(106.78,53.59)
  L6 w0.102: v1(106.73,54.14) 105.69,54.14 105.13,53.59 104.84,53.59 102.94,51.68 100.08,51.68 99.74,51.35 99.74,51.28 99.4,50.93 97.73,50.93 94.06,47.26 93.27,47.26 93.17,47.36 93.17,47.77 93.07,47.87 92.86,47.87 92.76,47.77 92.76,47.36 92.66,47.26 92.46,47.26 92.36,47.36 92.36,47.77 92.25,47.87 92.05,47.87 91.95,47.77 91.95,47.36 91.85,47.26 91.59,47.26 91.21,46.88 90.16,46.88 88.91,45.64 87.91,45.64 78.49,36.21 76.04,36.21 73.99,34.16 68.95,34.16 68.26,33.47 63.77,33.47 62.18,35.07 56.21,35.07 55.8,34.66 55.8,34.66 v1(55.75,34.61)
  BOTTOM w0.089: CPU1.AU30 106.4,53.82 v1(106.73,54.14) ; v1(55.75,34.61) 56.21,34.15 59.07,34.15 59.1,34.19 DM2.207
M_B_DQ43: length 68.1
  TOP w0.089: v2(54.48,34.15) v1(54.48,34.71)
  L6 w0.102: v1(107.38,54.14) 107.31,54.14 106.92,54.54 106.51,54.54 106.32,54.34 105.61,54.34 105.05,53.79 104.63,53.79 102.71,51.87 98.13,51.87 95.1,48.84 94.36,48.84 93.74,48.21 91.02,48.21 88.77,45.97 87.77,45.97 78.35,36.54 75.9,36.54 73.85,34.49 68.82,34.49 68.13,33.8 64.83,33.8 64.73,33.91 64.73,34.03 64.63,34.13 64.43,34.13 64.32,34.03 64.32,33.91 64.22,33.8 63.95,33.8 62.36,35.4 55.19,35.4 54.51,34.71 v1(54.48,34.71)
  BOTTOM w0.089: v1(54.48,34.71) 53.69,33.93 50.91,33.93 DM2.208 ; v1(107.38,54.14) 107.38,54.13 107.05,53.81 CPU1.AT30
M_B_DQ44: length 69.6
  TOP w0.089: v2(107.34,56.56) 107.43,56.56 v1(108.02,55.97)
  L6 w0.102: v1(108.02,55.97) 107.61,56.38 107.19,56.38 107.1,56.29 106.38,56.29 106.04,56.63 105.51,56.63 105.03,56.15 104.52,56.15 103.14,54.77 97.97,54.77 97.8,54.94 97.47,54.94 97.24,54.71 97.24,54.49 93.4,50.65 91.88,50.65 91.78,50.75 91.78,51.05 91.68,51.15 91.47,51.15 91.37,51.05 91.37,50.75 91.27,50.65 90.69,50.65 87.96,47.92 86.96,47.92 77.54,38.5 71.96,38.5 71.22,37.76 65.16,37.76 64.71,38.22 64.47,38.22 64.37,38.12 64.37,37.81 64.27,37.71 64.06,37.71 63.96,37.81 63.96,38.12 63.86,38.22 55.73,38.22 v1(54.99,37.48)
  BOTTOM w0.089: CPU1.AR33 107.7,55.65 v1(108.02,55.97) ; v1(54.99,37.48) 54.99,37.48 55.92,38.42 56.89,38.42 57.12,38.19 59.1,38.19 DM2.191
M_B_DQ45: length 71.6
  TOP w0.089: v2(52.93,36.36) 53.29,36.36 53.77,36.85 53.97,36.85 54.28,37.15 v1(54.43,37.15)
  L6 w0.102: v1(54.43,37.15) 54.86,36.72 56.67,36.72 57.2,37.25 58.85,37.25 59.08,37.02 59.41,37.02 59.51,36.92 59.51,36.8 59.61,36.7 59.82,36.7 59.92,36.8 59.92,36.92 60.02,37.02 60.22,37.02 60.32,36.92 60.32,36.8 60.42,36.7 60.63,36.7 60.73,36.8 60.73,36.92 60.83,37.02 61.52,37.02 61.62,36.92 61.62,36.82 61.72,36.72 61.92,36.72 62.03,36.82 62.03,36.92 62.13,37.02 62.33,37.02 62.43,36.92 62.43,36.82 62.53,36.72 62.74,36.72 62.84,36.82 62.84,36.92 62.94,37.02 65.61,37.02 65.63,37.05 71.09,37.05 71.39,36.75 72.82,36.75 73.91,37.84 77.81,37.84 87.24,47.26 88.24,47.26 90.96,49.99 93.94,49.99 97.36,53.41 102.41,53.41 104.38,55.37 105.65,55.37 105.91,55.64 105.99,55.64 106.12,55.64 106.36,55.88 106.91,55.88 107.21,55.58 107.23,55.58 107.25,55.56 108.29,55.56 v1(108.65,55.93)
  BOTTOM w0.089: CPU1.AP33 108.35,55.63 v1(108.65,55.93) ; v1(54.43,37.15) 54.43,38.1 54.1,38.44 51.1,38.44 51.1,38.44 DM2.190
M_B_DQ46: length 68.4
  TOP w0.089: v2(56.39,35.2) v1(56.39,34.64)
  L6 w0.102: v1(56.39,34.64) 56.84,34.18 62.53,34.18 64.41,32.31 66.55,32.31 66.6,32.36 68.38,32.36 69.06,33.04 69.43,33.04 69.53,33.14 69.53,33.47 69.64,33.57 69.84,33.57 69.94,33.47 69.94,33.14 70.04,33.04 70.25,33.04 70.35,33.14 70.35,33.47 70.45,33.57 70.65,33.57 70.75,33.47 70.75,33.14 70.86,33.04 71.06,33.04 71.16,33.14 71.16,33.47 71.26,33.57 71.46,33.57 71.57,33.47 71.57,33.14 71.67,33.04 73.33,33.04 76.17,35.88 78.62,35.88 88.05,45.3 89.05,45.3 90.29,46.55 91.38,46.55 91.76,46.93 94,46.93 97.81,50.74 102.3,50.74 104.94,53.38 105.21,53.38 105.66,53.84 106.33,53.84 106.41,53.75 107.63,53.75 v1(108.03,54.14)
  BOTTOM w0.089: CPU1.AR30 108.03,54.01 v1(108.03,54.14) ; v1(56.39,34.64) 57,35.25 57.95,35.25 58.02,35.19 59.1,35.19 DM2.203
M_B_DQ47: length 69.4
  TOP w0.089: v2(53.18,34.08) v1(53.18,34.65)
  L6 w0.102: v1(108.68,54.14) 108.09,53.56 106.32,53.56 106.25,53.63 105.81,53.63 105.31,53.13 105,53.13 102.38,50.51 97.85,50.51 93.89,46.55 91.84,46.55 91.51,46.22 90.43,46.22 89.18,44.97 88.18,44.97 78.76,35.55 76.33,35.55 72.8,32.03 66.75,32.03 66.7,31.98 64.18,31.98 62.3,33.85 53.98,33.85 v1(53.18,34.65)
  BOTTOM w0.089: CPU1.AP30 108.35,53.82 v1(108.68,54.14) ; DM2.204 50.9,34.94 52.89,34.94 v1(53.18,34.65)
M_B_DQ48: length 70.5
  TOP w0.089: v1(53.68,31.8) 53.16,31.8 v2(53.08,31.87)
  L6 w0.102: v1(106.04,51.4) 105.56,51.4 105.31,51.15 104.41,51.15 104.36,51.1 104.34,51.1 103.12,49.88 103.12,48.78 102.31,47.97 97.94,47.97 94.43,44.47 91.65,44.47 90.83,43.65 88.73,43.65 79.31,34.23 76.87,34.23 72.97,30.33 71.66,30.33 70.92,29.59 64.58,29.59 62.46,31.72 61.37,31.72 61.27,31.61 61.27,30.93 61.17,30.83 60.97,30.83 60.86,30.93 60.86,31.61 60.76,31.72 60.56,31.72 60.46,31.61 60.46,30.93 60.36,30.83 60.15,30.83 60.05,30.93 60.05,31.61 59.95,31.72 55.73,31.72 55.15,32.3 54.19,32.3 v1(53.68,31.8)
  BOTTOM w0.089: CPU1.AU27 106.4,51.76 v1(106.04,51.4) ; DM2.216 50.9,31.94 53.54,31.94 v1(53.68,31.8)
M_B_DQ49: length 71
  TOP w0.089: v2(106.73,51.73) v1(106.73,52.31)
  L6 w0.102: v1(106.73,52.31) 106.22,51.81 105.64,51.81 105.18,51.35 104.29,51.35 102.14,49.2 98.13,49.2 95.76,46.83 95.76,46.12 94.43,44.8 91.51,44.8 90.7,43.98 88.59,43.98 79.17,34.56 76.74,34.56 72.84,30.66 71.44,30.66 70.87,30.1 68.28,30.1 67.93,30.45 64.19,30.45 62.59,32.05 60.85,32.05 60.75,32.15 60.75,32.73 60.65,32.83 60.44,32.83 60.34,32.73 60.34,32.15 60.24,32.05 60.04,32.05 59.94,32.15 59.94,32.73 59.83,32.83 59.63,32.83 59.53,32.73 59.53,32.15 59.43,32.05 55.87,32.05 v1(54.9,33.01)
  BOTTOM w0.089: v1(106.73,52.31) 107.05,51.99 CPU1.AT27 ; v1(54.9,33.01) 55.73,32.19 59.1,32.19 DM2.215
M_B_DQ50: length 69.8
  TOP w0.089: v2(107.62,50.87) 107.62,51.16 v1(107.38,51.4)
  L6 w0.102: v1(54.53,30.14) 54.53,29.61 54.76,29.38 63.02,29.38 63.78,28.62 64.6,28.62 64.7,28.52 64.7,28.31 64.8,28.21 65,28.21 65.11,28.31 65.11,28.52 65.21,28.62 71.33,28.62 72.05,29.34 73.4,29.34 77.32,33.27 79.71,33.27 89.13,42.69 91.23,42.69 91.92,43.37 94.26,43.37 96.44,45.56 97.64,45.56 99.05,46.97 102.21,46.97 103.81,48.57 103.81,49.5 104.87,50.57 106.35,50.57 107.18,51.4 v1(107.38,51.4)
  BOTTOM w0.089: v1(107.38,51.4) 107.05,51.07 CPU1.AT25 ; v1(54.53,30.14) 53.21,28.82 52.48,28.82 52.37,28.93 DM2.228
M_B_DQ51: length 68.9
  TOP w0.089: v2(56.58,28.72) v1(56.58,28.14)
  L6 w0.102: v1(108.03,50.49) 107.71,50.49 107.17,50.47 106.88,50.19 105.03,50.19 104.27,49.42 104.27,48.49 102.18,46.4 99.7,46.4 96.59,43.3 96.06,43.3 95.02,42.26 91.74,42.26 91.51,42.03 89.41,42.03 79.98,32.6 77.6,32.6 72.11,27.12 64.3,27.12 62.75,28.67 59.68,28.67 59.58,28.57 59.58,28.34 59.47,28.24 59.27,28.24 59.17,28.34 59.17,28.57 59.07,28.67 58.87,28.67 58.76,28.57 58.76,28.34 58.66,28.24 58.46,28.24 58.36,28.34 58.36,28.57 58.26,28.67 57.11,28.67 v1(56.58,28.14)
  BOTTOM w0.089: CPU1.AU25 106.5,50.94 106.96,50.49 v1(108.03,50.49) ; DM2.229 57.13,28.68 v1(56.58,28.14)
M_B_DQ52: length 71.4
  TOP w0.089: v2(55.52,32.74) v1(56.1,32.74)
  L6 w0.102: v1(108.68,52.31) 108.29,52.71 106.57,52.71 106.3,52.44 106.3,52.34 105.98,52.02 105.6,52.02 105.47,52.15 104.77,52.15 102.52,49.9 102.52,49.88 102.06,49.42 97.74,49.42 95.38,47.06 95.38,46.01 94.49,45.13 91.37,45.13 90.56,44.31 88.46,44.31 79.03,34.89 76.6,34.89 72.7,30.99 72.11,30.99 72.01,31.09 72.01,31.26 71.9,31.36 71.7,31.36 71.6,31.26 71.6,31.09 71.5,30.99 71.29,30.99 71.19,31.09 71.19,31.26 71.09,31.36 70.89,31.36 70.79,31.26 70.79,31.09 70.68,30.99 70.48,30.99 70.38,31.09 70.38,31.26 70.28,31.36 70.07,31.36 69.97,31.26 69.97,31.09 69.87,30.99 68.28,30.99 68.12,30.83 64.36,30.83 62.02,33.17 58.96,33.17 58.86,33.07 58.86,32.71 58.76,32.6 58.56,32.6 58.45,32.71 58.45,33.07 58.35,33.17 58.15,33.17 58.05,33.07 58.05,32.71 57.95,32.6 57.74,32.6 57.64,32.71 57.64,33.07 57.54,33.17 56.53,33.17 v1(56.1,32.74)
  BOTTOM w0.089: v1(56.1,32.74) 56.56,33.2 56.57,33.19 59.1,33.19 DM2.211 ; v1(108.68,52.31) 108.35,51.99 CPU1.AP27
M_B_DQ53: length 71.9
  TOP w0.089: v2(51.76,32.94) v1(52.34,32.94)
  L6 w0.102: v1(52.34,32.94) 52.9,33.5 62.18,33.5 64.51,31.16 64.99,31.16 65.09,31.26 65.09,31.54 65.19,31.64 65.39,31.64 65.49,31.54 65.49,31.26 65.6,31.16 65.8,31.16 65.9,31.26 65.9,31.54 66,31.64 66.21,31.64 66.31,31.54 66.31,31.26 66.41,31.16 67.99,31.16 68.52,31.7 68.81,31.7 68.91,31.6 68.91,31.45 69.03,31.33 69.2,31.33 69.32,31.45 69.32,31.6 69.42,31.7 72.94,31.7 76.46,35.22 78.9,35.22 88.32,44.64 90.42,44.64 91.24,45.46 93.06,45.46 97.24,49.63 102,49.63 102.3,49.93 102.3,49.96 105.18,52.83 106.28,52.83 106.35,52.9 108.43,52.9 108.51,52.82 108.82,52.82 v1(109.33,52.31)
  BOTTOM w0.089: v1(109.33,52.31) 109,51.99 CPU1.AN27 ; DM2.212 50.9,32.94 52.33,32.94 v1(52.34,32.94)
M_B_DQ54: length 71.7
  TOP w0.089: v1(53.07,30.22) 53.07,30.31 v2(53.44,30.67)
  L6 w0.102: v1(108.68,50.49) 108.28,50.09 107.83,50.09 107.77,50.16 107.12,50.16 106.96,50 105.95,50 105.43,49.48 105.43,49.38 103.16,47.11 103.16,45.54 100.99,43.37 97.59,43.37 96.14,41.93 91.87,41.93 91.64,41.7 89.54,41.7 80.12,32.27 77.73,32.27 72.25,26.79 64.16,26.79 63.3,27.65 55.29,27.65 53.07,29.87 v1(53.07,30.22)
  BOTTOM w0.089: v1(53.07,30.22) 52.64,29.78 52.12,29.78 51.96,29.94 50.9,29.94 DM2.224 ; v1(108.68,50.49) 109,50.81 CPU1.AN25
M_B_DQ55: length 71
  TOP w0.089: v2(54.71,28.29) v1(55.27,28.29)
  L6 w0.102: v1(108.68,51.4) 108.25,50.97 107.11,50.97 106.52,50.38 104.95,50.38 104.06,49.49 104.06,48.56 102.21,46.71 99.39,46.71 96.19,43.5 95.88,43.5 94.97,42.59 91.6,42.59 91.37,42.36 89.27,42.36 79.85,32.94 77.46,32.94 71.97,27.45 64.44,27.45 64.16,27.72 64.16,27.87 64.27,27.98 64.27,28.12 64.13,28.27 63.99,28.27 63.88,28.16 63.73,28.16 62.84,29.05 56.03,29.05 v1(55.27,28.29)
  BOTTOM w0.089: DM2.225 56.88,29.69 56.54,29.69 55.27,28.41 v1(55.27,28.29) ; v1(108.68,51.4) 108.35,51.08 CPU1.AP25
M_B_DQ56: length 73.8
  TOP w0.089: v1(56.82,26.43) 57,26.25 v2(57,25.9)
  L6 w0.102: v1(107.38,49.57) 107.35,49.55 106.92,49.55 106.31,48.94 105.52,48.94 103.62,47.04 103.62,45.45 101.06,42.89 97.76,42.89 95.6,40.73 89.51,40.73 80.39,31.61 78.01,31.61 71.86,25.47 64.5,25.47 64.17,25.8 63.44,25.8 63.34,25.9 63.34,26.61 63.24,26.71 63.03,26.71 62.93,26.61 62.93,25.9 62.83,25.8 62.59,25.8 62.49,25.9 62.49,26.89 62.38,26.99 62.18,26.99 62.08,26.89 62.08,25.9 61.98,25.8 61.77,25.8 61.67,25.9 61.67,26.89 61.57,26.99 61.37,26.99 61.27,26.89 61.27,25.9 61.16,25.8 60.05,25.8 59.95,25.9 59.95,26.86 59.85,26.97 59.64,26.97 59.54,26.86 59.54,25.9 59.44,25.8 57.07,25.8 56.82,26.05 v1(56.82,26.43)
  BOTTOM w0.089: v1(56.82,26.43) 57.24,26.86 57.63,26.86 57.8,26.68 DM2.237 ; CPU1.AT22 107.05,49.25 v1(107.38,49.57)
M_B_DQ57: length 73.2
  TOP w0.089: v1(105.8,48.53) 105.51,48.53 v2(105.26,48.78)
  L6 w0.102: v1(105.8,48.53) 105.39,48.53 103.84,46.98 103.84,45.39 101.14,42.69 98.83,42.69 96.47,40.33 94.06,40.33 93.96,40.22 93.96,39.62 93.86,39.51 93.65,39.51 93.55,39.62 93.55,40.22 93.45,40.33 92.3,40.33 92.2,40.22 92.2,39.64 92.09,39.54 91.89,39.54 91.79,39.64 91.79,40.22 91.69,40.33 91.48,40.33 91.38,40.22 91.38,39.64 91.28,39.54 91.08,39.54 90.98,39.64 90.98,40.22 90.88,40.33 90.67,40.33 90.57,40.22 90.57,39.64 90.47,39.54 90.27,39.54 90.16,39.64 90.16,40.22 90.06,40.33 89.57,40.33 80.53,31.28 78.14,31.28 71.91,25.05 60.28,25.05 59.87,25.47 56.51,25.47 v1(55.55,26.43)
  BOTTOM w0.089: CPU1.AU22 106.4,49.11 105.81,48.53 v1(105.8,48.53) ; DM2.236 50.9,26.94 54.76,26.94 55.26,26.43 v1(55.55,26.43)
M_B_DQ58: length 72.2
  TOP w0.089: v2(106.35,48.18) 106.35,48.13 v1(106.73,47.74)
  L6 w0.102: v1(56.89,23.28) 57.45,23.84 58.96,23.84 59.16,23.65 73.34,23.65 76.67,26.97 76.81,26.97 77.32,26.46 77.47,26.46 77.61,26.6 77.61,26.75 77.1,27.26 77.1,27.4 77.24,27.55 77.39,27.55 77.9,27.03 78.04,27.03 78.19,27.18 78.19,27.32 77.67,27.83 77.67,27.98 77.82,28.12 77.96,28.12 78.47,27.61 78.62,27.61 78.76,27.75 78.76,27.9 78.25,28.41 78.25,28.55 78.39,28.7 78.54,28.7 79.05,28.18 79.19,28.18 79.34,28.33 79.34,28.47 78.82,28.98 78.82,29.13 78.97,29.27 79.11,29.27 79.62,28.76 79.77,28.76 79.91,28.9 79.91,29.05 79.4,29.56 79.4,29.7 79.68,29.99 81.07,29.99 89.27,38.19 96.26,38.19 99.81,41.74 101.43,41.74 104.87,45.18 104.87,45.84 106.73,47.69 v1(106.73,47.74)
  BOTTOM w0.089: v1(106.73,47.74) 106.73,47.74 106.4,48.07 CPU1.AU21 ; DM2.249 58.98,23.69 58.98,23.68 57.3,23.68 v1(56.89,23.28)
M_B_DQ59: length 73.2
  TOP w0.089: v2(51.79,23.38) v1(52.37,23.38)
  L6 w0.102: v1(52.37,23.38) 52.85,23.87 56.03,23.87 56.41,23.48 56.41,23.15 56.89,22.67 60.89,22.67 60.99,22.78 60.99,23.21 61.08,23.31 61.3,23.31 61.4,23.21 61.4,22.78 61.5,22.67 62.48,22.67 62.58,22.78 62.58,23.16 62.68,23.26 62.88,23.26 62.99,23.16 62.99,22.78 63.09,22.67 63.29,22.67 63.39,22.78 63.39,23.16 63.49,23.26 63.7,23.26 63.8,23.16 63.8,22.78 63.9,22.67 64.1,22.67 64.2,22.78 64.2,23.16 64.31,23.26 64.51,23.26 64.61,23.16 64.61,22.78 64.71,22.67 70.79,22.67 71.43,23.32 73.48,23.32 76.29,26.13 77.67,26.13 89.41,37.86 96.4,37.86 99.42,40.89 100.73,40.89 101.27,41.42 101.4,41.42 105.08,45.1 105.08,45.76 105.94,46.63 105.96,46.63 106.57,47.24 106.87,47.24 v1(107.38,47.74)
  BOTTOM w0.089: v1(52.37,23.38) 52.31,23.44 DM2.250 ; CPU1.AT21 107.05,48.07 v1(107.38,47.74)
M_B_DQ60: length 75.5
  TOP w0.089: v2(53.34,28.9) 53.01,28.57 v1(53.01,28.36)
  L6 w0.102: v1(108.68,49.57) 108.17,49.06 106.88,49.06 105.95,48.12 105.25,48.12 104.04,46.91 104.04,45.28 101.25,42.5 99.02,42.5 95.71,39.18 94.96,39.18 94.85,39.29 94.85,39.87 94.75,39.97 94.55,39.97 94.45,39.87 94.45,39.29 94.35,39.18 88.9,39.18 80.67,30.95 78.28,30.95 72.86,25.53 72.86,25.39 73.17,25.07 73.17,24.93 73.03,24.78 72.88,24.78 72.57,25.1 72.43,25.1 71.98,24.65 60.15,24.65 59.66,25.14 55.52,25.14 55.12,25.54 55.12,26.48 54.35,27.25 53.34,27.25 53.01,27.58 v1(53.01,28.36)
  BOTTOM w0.089: v1(53.01,28.36) 53.01,28.33 52.62,27.94 50.9,27.94 DM2.232 ; CPU1.AN22 109,49.25 v1(108.68,49.57)
M_B_DQ61: length 75.4
  TOP w0.089: v1(55.27,27.07) 55.09,26.89 55.09,26.2 v2(55.04,26.15)
  L6 w0.102: v1(55.27,27.07) 55.52,27.32 56.07,27.32 56.17,27.22 56.17,27.07 56.27,26.97 56.47,26.97 56.58,27.07 56.58,27.22 56.68,27.32 56.88,27.32 56.98,27.22 56.98,27.07 57.08,26.97 57.29,26.97 57.39,27.07 57.39,27.22 57.49,27.32 57.87,27.32 57.98,27.22 57.98,26.25 58.08,26.15 58.28,26.15 58.38,26.25 58.38,27.22 58.48,27.32 58.69,27.32 58.79,27.22 58.79,26.25 58.89,26.15 59.09,26.15 59.2,26.25 59.2,27.22 59.3,27.32 63.12,27.32 64.62,25.82 71.75,25.82 77.87,31.94 80.26,31.94 89.4,41.09 95.65,41.09 97.75,43.18 101.09,43.18 103.35,45.45 103.35,47.03 105.48,49.17 106.25,49.17 106.89,49.81 107.04,49.81 107.2,49.97 107.56,49.97 107.95,49.57 v1(108.03,49.57)
  BOTTOM w0.089: CPU1.AP22 108.35,49.25 v1(108.03,49.57) ; v1(55.27,27.07) 55.89,27.68 DM2.233
M_B_DQ62: length 73.9
  TOP w0.089: v2(107.7,48.2) 108.03,47.87 v1(108.03,47.74)
  L6 w0.102: v1(108.03,47.74) 108.54,47.24 109.48,47.24 109.72,46.99 109.72,46.66 109.48,46.42 106.02,46.42 105.29,45.68 105.29,44.72 105.36,44.64 105.36,44.24 102.32,41.2 101.34,41.2 100.67,40.53 99.54,40.53 96.54,37.53 89.56,37.53 77.82,25.8 76.45,25.8 73.64,22.99 71.59,22.99 70.94,22.34 56.23,22.34 v1(55.23,23.34)
  BOTTOM w0.089: DM2.245 58.98,24.69 58.98,24.68 56.58,24.68 v1(55.23,23.34) ; CPU1.AP21 108.35,48.07 v1(108.03,47.74)
M_B_DQ63: length 75.2
  TOP w0.089: v1(108.68,48.66) 108.68,48.79 v2(109,49.11)
  L6 w0.102: v1(108.68,48.66) 109.13,48.2 109.43,48.2 109.91,47.72 109.91,45.94 109.38,45.41 105.79,45.41 105.51,45.13 105.51,44.77 105.56,44.72 105.56,44.06 102.51,41.01 101.42,41.01 100.54,40.14 99.66,40.14 96.72,37.2 89.7,37.2 77.96,25.47 76.59,25.47 73.77,22.65 71.73,22.65 71.09,22.01 55.16,22.01 v1(53.76,23.42)
  BOTTOM w0.089: v1(53.76,23.42) 52.74,24.44 51,24.44 DM2.246 ; CPU1.AN21 109,48.33 v1(108.68,48.66)
M_B_DQS_DN0: length 74.6
  TOP w0.089: v1(53.25,80.2) 53.15,80.2 v2(52.55,79.59)
  L6 w0.127: v1(53.25,80.2) 53.49,80.44 53.49,80.79 53.87,81.17 54.55,81.17 55.01,80.71 55.01,79.87 55.31,79.57 58.18,79.57 58.51,79.24 64.63,79.24 64.89,78.99 71.94,78.99 73.83,80.88 81.56,80.88 81.69,81 81.69,81.42 81.97,81.7 82.37,81.7 82.65,81.42 82.65,81 82.78,80.88 83.04,80.88 83.16,81 83.16,81.42 83.45,81.7 83.84,81.7 84.13,81.42 84.13,81 84.25,80.88 84.68,80.88 85.63,81.83 88.98,81.83 90.63,83.48 97.59,83.48 101.34,79.72 105.61,79.72 106.25,79.09 106.25,77.84 106.65,77.44 108.63,77.44 111.5,74.56 111.5,74.28 111.69,74.1 v1(112,74.1)
  BOTTOM w0.089: CPU1.AH66 111.67,73.77 v1(112,74.1) ; DM2.32 50.9,79.94 51.83,79.94 52.14,79.63 53.3,79.63 53.51,79.83 53.51,79.94 v1(53.25,80.2)
M_B_DQS_DN1: length 75.8
  L6 w0.127: v1(112.93,80.41) 112.47,80.86 112.47,81.55 105.43,88.59 100.64,88.59 99.14,87.09 89.49,87.09 88.24,85.84 83.08,85.84 82.82,85.58 82.82,85.28 82.69,85.16 82.44,85.16 82.31,85.28 82.31,85.58 82.05,85.84 81.61,85.84 81.34,85.58 81.34,85.28 81.22,85.16 72.76,85.16 71.39,83.79 65.14,83.79 63.1,85.82 61.39,85.82 61.13,85.56 61.13,85.26 61,85.13 60.75,85.13 60.62,85.26 60.62,85.56 60.36,85.82 56.57,85.82 56.16,85.4 56.16,84.81 v1(56.02,84.67)
  BOTTOM w0.089: v1(112.93,80.41) 113.38,79.95 113.38,79.54 ; v1(56.02,84.67) 56.26,84.91 56.26,85.12 56.47,85.34 57.94,85.34 58.09,85.18 DM2.11 ; 113.38,79.54 113.38,79.05 112.91,78.57 112.91,77.64 112.49,77.23 112.49,76.95 112.54,76.8 112.54,76.61 112.48,76.4 112.48,76.08 CPU1.AG69 ; 113.38,79.54 v2(113.56,79.54)
M_B_DQS_DN2: length 64.1
  TOP w0.089: v2(107.01,72.91) 107.01,72.98 v1(107.38,73.35)
  L6 w0.089: v1(107.38,73.35) 106.97,73.35 106.11,74.21 106.11,74.37 105.54,74.93 104.83,74.93 103.71,76.05 102.97,76.05 102.94,76.09 102.87,76.09
  L6 w0.127: 102.87,76.09 101.22,76.09 99.69,77.61 99.08,77.61 97.43,79.26 90.61,79.26 89.27,77.93 76.35,77.93 73.11,74.69 60.46,74.69 60.2,74.43 60.2,74.08 60.08,73.96 59.82,73.96 59.69,74.08 59.69,74.91 59.43,75.18 58.99,75.18 58.73,74.91 58.73,74.08 58.6,73.96 58.35,73.96 58.22,74.08 58.22,74.43 57.96,74.69 56.57,74.69 56.21,74.33 56.21,74.03 v1(56.01,73.83)
  BOTTOM w0.089: v1(107.38,73.35) 107.7,73.67 CPU1.AR66 ; v1(56.01,73.83) 56.26,74.08 56.26,74.25 56.62,74.62 58.17,74.62 58.24,74.69 DM2.53
M_B_DQS_DN3: length 64.8
  TOP w0.089: v2(54.13,69.36) v1(54.13,68.8)
  L6 w0.089: 105.43,70.32 105.44,70.32 105.46,70.3 105.52,70.3 105.53,70.3 105.66,70.3 105.74,70.22 106.32,70.22 106.68,70.27 107.06,70.27 107.14,70.2 107.64,70.2 v1(108.02,70.58)
  L6 w0.127: v1(54.13,68.8) 54.13,68.41 54.31,68.23 55.32,68.23 55.45,68.36 55.45,68.69 55.71,68.95 56.15,68.95 56.41,68.69 56.41,68.36 56.54,68.23 58.13,68.23 58.63,68.72 70.97,68.72 73.15,70.9 74.44,70.9 77.85,74.31 99.61,74.31 101.42,72.5 101.42,71.99 102.07,71.34 103.7,71.34 104.72,70.32 105.43,70.32
  BOTTOM w0.089: DM2.74 52.04,69.44 52.1,69.37 53.71,69.37 54.13,68.95 v1(54.13,68.8) ; CPU1.AR61 107.7,70.9 v1(108.02,70.58)
M_B_DQS_DN4: length 66.9
  TOP w0.089: v2(106.88,59.27) 107.32,58.84 v1(107.32,58.74)
  L6 w0.102: 102.77,56.94 103.1,56.94 104.6,58.44 106.32,58.44 106.5,58.26 106.91,58.26 107.32,58.67 v1(107.32,58.74)
  L6 w0.127: v1(56.1,40.74) 56.36,41 56.36,41.22 56.72,41.58 57.84,41.58 58.39,41.03 58.81,40.61 59.24,40.19 59.51,40.19 59.63,40.31 59.63,40.62 59.9,40.89 60.34,40.89 60.6,40.62 60.6,40.31 60.73,40.19 60.98,40.19 61.11,40.31 61.11,40.62 61.37,40.89 61.81,40.89 62.07,40.62 62.07,40.31 62.2,40.19 64.66,40.19 64.93,40.45 76.78,40.45 89.41,53.08 93.15,53.08 97.01,56.94 102.77,56.94
  BOTTOM w0.089: CPU1.AT38 107.05,58.47 v1(107.32,58.74) ; v1(56.1,40.74) 56.34,40.98 56.34,41.23 56.55,41.44 58.02,41.44 58.26,41.69 DM2.177
M_B_DQS_DN5: length 68.7
  TOP w0.089: v2(54.81,35.53) 54.81,35.6 v1(54.28,36.14)
  L6 w0.089: v1(107.35,55.1) 107.17,54.91 106.33,54.91 106.2,54.78 105.84,54.78 105.73,54.89 105.57,54.89 104.72,54.89 104.72,54.89 104.54,54.89 104.54,54.89 104.51,54.89
  L6 w0.127: 104.51,54.89 103.78,54.15 103.78,53.56 103.51,53.3 103.32,53.11 103.32,53.1 102.53,52.31 97.63,52.31 94.61,49.29 91.25,49.29 88.53,46.56 87.53,46.56 78.1,37.14 75.65,37.14 73.61,35.09 71.57,35.09 70.93,35.73 68.05,35.73 67.24,34.92 64,34.92 62.92,36 54.94,36 54.65,35.71 54.52,35.71 54.28,35.95 v1(54.28,36.14)
  BOTTOM w0.089: v1(54.28,36.14) 54.24,36.14 53.9,35.81 53.63,35.81 53.32,36.12 52.24,36.12 51.92,36.44 DM2.198 ; CPU1.AT32 107.35,54.6 107.42,54.67 107.42,55.03 v1(107.35,55.1)
M_B_DQS_DN6: length 70.3
  TOP w0.089: v1(55.94,30.73) 55.94,30.69 v2(55.55,30.29)
  L6 w0.089: v1(108.03,51.4) 107.74,51.69 107.66,51.69 107.54,51.8 107.23,51.8 106.88,51.45 106.88,51.36 106.27,50.75 104.63,50.75 104.6,50.72
  L6 w0.127: v1(55.94,30.73) 56.07,30.6 56.07,30 56.29,29.79 58.3,29.79 58.56,30.05 58.56,30.93 58.69,31.06 58.94,31.06 59.07,30.93 59.07,30.05 59.33,29.79 63.32,29.79 64.11,28.99 71.18,28.99 71.9,29.71 73.24,29.71 77.17,33.63 79.56,33.63 88.98,43.06 91.08,43.06 91.88,43.86 94.44,43.86 96.51,45.93 97.31,45.93 98.8,47.41 102.36,47.41 103.55,48.6 103.55,49.68 104.07,50.2 104.59,50.72 104.6,50.72
  BOTTOM w0.089: DM2.219 57.94,31.19 57.78,31.35 57.75,31.35 56.35,31.35 56.18,31.18 56.18,30.96 v1(55.94,30.73) ; CPU1.AR25 107.7,51.08 v1(108.03,51.4)
M_B_DQS_DN7: length 73.5
  TOP w0.089: v1(53.1,26.46) 52.8,26.76 v2(52.8,26.94)
  L6 w0.089: v1(108.03,48.66) 107.52,48.15 106.55,48.15 106.13,47.73 105.38,47.73 104.49,46.83 104.49,46.1 104.49,46.09
  L6 w0.127: v1(53.1,26.46) 53.24,26.32 53.24,25.06 53.77,24.52 58.8,24.52 59.31,24.02 73.19,24.02 75.09,25.92 75.09,26.29 74.89,26.5 74.89,26.68 75.07,26.86 75.25,26.86 75.45,26.65 75.82,26.65 76.14,26.96 76.14,27.33 75.93,27.54 75.93,27.72 76.11,27.9 76.29,27.9 76.5,27.69 76.87,27.69 79.53,30.36 80.91,30.36 89.13,38.57 96.08,38.57 99.53,42.03 101.42,42.03 104.49,45.1 104.49,46.09
  BOTTOM w0.089: v1(108.03,48.66) 107.7,48.98 CPU1.AR22 ; v1(53.1,26.46) 52.42,25.78 51.83,25.78 51.68,25.93 DM2.240
M_B_DQS_DP0: length 74.2
  TOP w0.089: v2(54.53,80.26) 54.02,80.26 v1(53.96,80.2)
  L6 w0.127: v1(53.96,80.2) 53.72,80.44 53.72,80.7 53.96,80.94 54.46,80.94 54.79,80.61 54.79,79.77 55.22,79.34 58.09,79.34 58.42,79.01 64.54,79.01 64.66,78.89 64.79,78.76 72.03,78.76 73.92,80.65 81.66,80.65 81.92,80.91 81.92,81.33 82.07,81.47 82.28,81.47 82.43,81.33 82.43,80.91 82.69,80.65 83.13,80.65 83.39,80.91 83.39,81.33 83.54,81.47 83.75,81.47 83.9,81.33 83.9,80.91 84.16,80.65 84.77,80.65 85.72,81.6 89.08,81.6 90.73,83.25 97.49,83.25 101.25,79.49 105.52,79.49 106.02,78.99 106.02,77.75 106.56,77.21 108.53,77.21 111.28,74.46 111.28,74.18 112,73.47 v1(112,73.45)
  BOTTOM w0.089: CPU1.AH65 111.67,73.12 v1(112,73.45) ; DM2.34 50.9,79.44 53.38,79.44 53.7,79.75 53.7,79.93 v1(53.96,80.2)
M_B_DQS_DP1: length 76.1
  TOP w0.089: v2(56.87,85.23) v1(56.87,84.67)
  L6 w0.127: v1(56.87,84.67) 56.64,84.67 56.39,84.93 56.39,85.31 56.67,85.59 60.27,85.59 60.39,85.47 60.39,85.16 60.65,84.9 61.1,84.9 61.36,85.16 61.36,85.47 61.49,85.59 63.01,85.59 65.05,83.56 71.49,83.56 72.86,84.93 81.31,84.93 81.57,85.19 81.57,85.49 81.7,85.61 81.95,85.61 82.08,85.49 82.08,85.19 82.34,84.93 82.79,84.93 83.05,85.19 83.05,85.49 83.17,85.61 88.34,85.61 89.58,86.86 99.24,86.86 100.73,88.36 105.34,88.36 112.24,81.46 112.24,80.77 112.42,80.59 112.42,80.38 112.29,80.26 112.29,80.08 112.62,79.75 v1(112.7,79.75)
  BOTTOM w0.089: v1(112.7,79.75) 112.7,79.88 112.8,79.98 113.08,79.98 113.19,79.87 113.19,79.13 112.72,78.65 112.72,77.74 112.32,77.34 112.32,76.92 112.36,76.77 112.36,76.63 112.3,76.43 112.3,76.15 112.2,76.05 CPU1.AG70 ; v1(56.87,84.67) 56.82,84.62 56.54,84.62 56.45,84.72 56.45,85.04 56.55,85.14 57.86,85.14 58.01,84.99 58.01,84.83 58.01,84.83 58.15,84.69 DM2.13
M_B_DQS_DP2: length 65.5
  TOP w0.089: v1(56.67,73.85) 57.07,74.26 v2(58.65,74.26)
  L6 w0.089: 102.87,75.86 103.63,75.86 104.75,74.74 105.46,74.74 105.92,74.29 105.92,74.13 106.84,73.21 106.98,73.07 106.98,72.77 107.31,72.43 v1(107.38,72.43)
  L6 w0.127: v1(56.67,73.85) 56.44,74.08 56.44,74.24 56.67,74.46 57.87,74.46 57.99,74.34 57.99,73.99 58.25,73.73 58.7,73.73 58.96,73.99 58.96,74.82 59.09,74.95 59.34,74.95 59.47,74.82 59.47,73.99 59.73,73.73 60.17,73.73 60.43,73.99 60.43,74.34 60.56,74.46 73.2,74.46 76.44,77.7 89.37,77.7 90.7,79.04 97.34,79.04 98.99,77.39 99.6,77.39 101.12,75.86 102.87,75.86
  BOTTOM w0.089: v1(107.38,72.43) 107.38,72.7 107.57,72.89 CPU1.AR65 ; DM2.55 58.25,74.19 58.01,74.43 56.7,74.43 56.45,74.17 56.45,74.07 v1(56.67,73.85)
M_B_DQS_DP3: length 64.9
  TOP w0.089: v2(52.88,69.31) 53.41,68.77 v1(53.44,68.77)
  L6 w0.089: v1(108.02,69.74) 107.76,70.01 107.06,70.01 106.98,70.08 106.69,70.08 106.34,70.03 105.66,70.03 105.63,70.06 105.61,70.06 105.59,70.08 105.57,70.08 105.56,70.1 105.43,70.1
  L6 w0.127: v1(53.44,68.77) 53.9,68.32 54.21,68 55.41,68 55.68,68.26 55.68,68.6 55.8,68.72 56.06,68.72 56.18,68.6 56.18,68.26 56.44,68 58.23,68 58.72,68.49 71.07,68.49 73.24,70.67 74.53,70.67 77.94,74.08 99.52,74.08 101.19,72.41 101.19,71.9 101.98,71.11 103.6,71.11 104.62,70.1 105.43,70.1
  BOTTOM w0.089: CPU1.AR60 107.7,70.06 v1(108.02,69.74) ; v1(53.44,68.77) 53.44,69.1 53.36,69.18 52.18,69.18 51.94,68.94 50.9,68.94 DM2.76
M_B_DQS_DP4: length 67.7
  TOP w0.089: v1(56.81,40.74) 57.29,40.25 57.81,40.25 v2(58.09,40.53)
  L6 w0.102: v1(107.97,58.72) 107.56,58.31 107.25,58.31 106.99,58.06 106.42,58.06 106.24,58.23 104.68,58.23 103.17,56.72 102.87,56.72 102.86,56.71 102.77,56.71
  L6 w0.127: v1(56.81,40.74) 56.59,40.95 56.59,41.13 56.82,41.35 57.75,41.35 59.14,39.96 59.6,39.96 59.86,40.22 59.86,40.53 59.99,40.66 60.24,40.66 60.37,40.53 60.37,40.22 60.63,39.96 61.08,39.96 61.34,40.22 61.34,40.53 61.46,40.66 61.72,40.66 61.84,40.53 61.84,40.22 62.11,39.96 64.76,39.96 65.02,40.22 76.88,40.22 89.5,52.85 93.24,52.85 97.1,56.71 102.77,56.71
  BOTTOM w0.089: v1(107.97,58.72) 107.7,58.46 CPU1.AR38 ; v1(56.81,40.74) 56.53,41.02 56.53,41.15 56.63,41.25 58.09,41.25 58.16,41.19 59.1,41.19 DM2.179
M_B_DQS_DP5: length 68.5
  TOP w0.089: v2(53.62,35.27) 53.8,35.45 v1(54.15,35.45)
  L6 w0.089: 104.63,54.68 104.65,54.7 105.65,54.7 105.76,54.59 106.27,54.59 106.41,54.72 107.17,54.72 107.19,54.71 107.61,54.71 v1(107.99,55.08)
  L6 w0.127: 104.63,54.68 104.61,54.66 104.01,54.06 104.01,53.47 103.61,53.07 103.61,53.07 103.55,53.01 103.55,53.01 102.62,52.08 97.73,52.08 94.7,49.06 91.35,49.06 88.62,46.33 87.62,46.33 78.2,36.91 75.75,36.91 73.7,34.87 71.47,34.87 70.84,35.5 68.15,35.5 67.33,34.69 63.9,34.69 62.82,35.77 55.03,35.77 54.74,35.48 54.19,35.48 v1(54.15,35.45)
  BOTTOM w0.089: DM2.200 51.89,35.93 51.89,35.93 53.24,35.93 53.55,35.61 53.99,35.61 v1(54.15,35.45) ; v1(107.99,55.08) 107.7,54.8 CPU1.AR32
M_B_DQS_DP6: length 70.3
  TOP w0.089: v1(108.03,52.31) 108.03,52.87 v2(108.02,52.87)
  L6 w0.089: 104.49,50.94 106.2,50.94 106.69,51.44 106.69,51.53 107.15,51.99 107.62,51.99 107.74,51.88 107.95,51.88 108.03,51.95 v1(108.03,52.31)
  L6 w0.127: 104.49,50.94 103.33,49.78 103.33,48.7 102.27,47.64 98.7,47.64 97.22,46.16 96.41,46.16 94.34,44.09 91.79,44.09 90.99,43.29 88.88,43.29 79.46,33.86 77.07,33.86 73.15,29.94 71.8,29.94 71.09,29.22 64.21,29.22 63.41,30.02 59.42,30.02 59.3,30.14 59.3,31.02 59.04,31.28 58.59,31.28 58.33,31.02 58.33,30.14 58.2,30.02 56.38,30.02 56.3,30.1 56.3,30.38 v1(56.66,30.73)
  BOTTOM w0.089: v1(56.66,30.73) 56.48,30.73 56.37,30.84 56.37,31.1 56.43,31.16 57.19,31.16 57.19,31.16 57.7,31.16 58.17,30.69 DM2.221 ; CPU1.AR27 107.92,51.86 108.03,51.96 v1(108.03,52.31)
M_B_DQS_DP7: length 73.8
  TOP w0.089: v2(106.81,49.34) 107.38,48.77 v1(107.38,48.66)
  L6 w0.089: v1(107.38,48.66) 107.38,48.46 107.26,48.34 106.47,48.34 106.05,47.92 105.31,47.92 104.3,46.91 104.3,46.22 104.27,46.19 104.27,46.09
  L6 w0.127: v1(53.81,26.46) 53.47,26.12 53.47,25.15 53.86,24.75 58.9,24.75 59.4,24.25 73.1,24.25 74.87,26.01 74.87,26.19 74.66,26.4 74.66,26.77 74.97,27.09 75.34,27.09 75.55,26.88 75.73,26.88 75.91,27.06 75.91,27.24 75.7,27.45 75.7,27.81 76.01,28.13 76.38,28.13 76.59,27.92 76.77,27.92 79.44,30.59 80.82,30.59 89.04,38.8 95.98,38.8 99.44,42.26 101.33,42.26 104.27,45.2 104.27,46.09
  BOTTOM w0.089: DM2.242 51.66,25.44 51.82,25.59 52.5,25.59 52.93,26.03 53.62,26.03 53.81,26.22 v1(53.81,26.46) ; v1(107.38,48.66) 107.7,48.33 CPU1.AR21
M_B_PARITY: length 71.4
  TOP w0.152: v2(53.69,50.87) v1(53.14,50.87)
  L6 w0.089: v1(108.67,60.5) 108.6,60.5 108.19,60.91 106.33,60.91 106.15,61.08 105.33,61.08
  L6 w0.165: 105.33,61.08 103.52,61.08 101.47,63.14 98.96,63.14 97.64,61.82 96.8,61.82 96.24,61.25 94.08,61.25 93.14,60.32 86.67,60.32 83.09,56.73 80.74,56.73 77.44,53.43 75.69,53.43 74.47,52.21 74.47,51.62 73,50.14 72.61,50.14 72.17,50.59 65.15,50.59 65.09,50.65 54.72,50.65 54.56,50.81 54.56,51.19 54.39,51.35 54.06,51.35 53.9,51.19 53.9,50.81 53.73,50.65 53.36,50.65 v1(53.14,50.87)
  BOTTOM w0.152: CPU1.AP43 108.35,60.82 v1(108.67,60.5) ; v1(53.14,50.87) 53.59,51.32 57.86,51.32 58.72,52.19 DM2.143
M_VREF_CA_DIMMA: length 1.8
  BOTTOM w0.279: DM1.164 64.15,44.73 64.15,44.73 65.54,44.73 v1(65.59,44.78)
  vias: v2(65.38,45.36)
M_VREF_CA_DIMMB: length 1.5
  BOTTOM w0.279: DM2.164 51.1,44.94 51.1,44.93 52.29,44.93 v1(52.34,44.98)
  vias: v2(52.2,42.38)
MASK_SATA_LED#: length 17.9
  TOP w0.102: KBC24.56 188.01,44.9 187.68,45.23 186.99,45.23 186.36,45.86 184.63,45.86 v2(182.93,47.57) 182.52,47.97 182.52,48.89 181.48,49.93 181.48,50.51 180.92,51.07 180.51,51.07 179.83,50.38 178.86,50.38 178.61,50.64 178.61,50.94 R6120.2 177.62,51.07 177.62,50.05 177,49.44 Q6403.G
ME_FWP_EC: length 162.7
  TOP w0.102: KBC24.80 182.4,36.64 182.14,36.9 182.14,37.15 v1(182.07,37.23) ; R1909.1 89.34,49.5 v2(89.06,49.22) 82.31,42.46 82.31,25.12 82.12,24.93 82.12,15.18 83.34,13.96 84.55,13.96 85.14,13.38 86.36,13.38 87.45,14.46 93.98,14.46 97.64,10.81 123.52,10.81 124.27,11.56 124.45,11.74 125.98,13.27 126.57,13.86 129.53,13.86 v1(131.32,15.65)
  L3 w0.102: v1(158.82,15.38) 158.41,14.97 153.19,14.97 152.68,15.49 149.4,15.49 149.1,15.79 146.66,15.79 146.66,15.79 146.3,15.79 145.36,14.85 144.32,14.85 143.52,15.65 v1(131.32,15.65)
  L4 w0.102: v1(158.82,15.38) 159.2,15.38 160.7,16.88 163.1,16.88 163.86,17.64 167.53,17.64 170.34,20.45 174.42,20.45 175.51,21.54 175.51,24.03 177.07,25.59 177.8,25.59 178.97,26.76 181.29,26.76 182.17,27.64 182.17,27.8 182.52,28.16 182.52,36.11 182.07,36.57 v1(182.07,37.23)
ME_SUS_PWR_ACK_R: length 28
  L3 w0.127: v1(110.29,26.2) 110.26,26.2 109.55,26.92 108.01,26.92 107.66,27.26 107.66,33.01 108.04,33.39 108.04,33.83 108.09,33.88 108.09,35.63 105.97,37.76 105.97,38.62 105.33,39.26 105.33,39.84 105.24,39.93 105.24,41.62 105.41,41.78 105.41,42.65 106.33,43.58 107.62,43.58 v1(108.03,43.17)
  BOTTOM w0.127: v1(110.29,26.2) 110.23,26.2 109.7,25.67 R1739.2 109.7,25.3 110.5,24.5 110.5,24.21 110.74,23.97 R1708.1 111.78,23.97 v2(112.01,23.74) ; CPU1.AR13 107.7,43.5 v1(108.03,43.17)
MEC_XTAL1_R: length 8.6
  TOP w0.089: X2401.1 200.86,25.19 C2425.2 199.2,25.19 199.02,25.01 v2(198.76,25.01) 198.58,25.19 197.71,25.19 195.21,27.69 KBC24.123
MEC_XTAL2: length 7.7
  TOP w0.089: KBC24.125 196.01,27.66 v2(196.8,26.87) 197.58,26.08 R2425.2 198.83,26.05 C2424.2 200.04,26.05 201.36,27.37 X2401.2
MEM_CHB_EN: length 1.2
  TOP w0.102: TP2007.1 v1(114.08,42.08)
  BOTTOM w0.102: CPU1.AD11 113.78,42.38 v1(114.08,42.08)
MEM_CONFIG0: length 8.9
  TOP w0.102: TP2020.1 110.9,34 v1(110.4,34.48)
  L4 w0.102: v1(111.09,41.45) 111.47,41.07 111.47,37.09 110.92,36.54 110.92,35.49 110.4,34.97 v1(110.4,34.48)
  BOTTOM w0.102: v1(111.09,41.45) 111.1,41.45 111.47,41.08 CPU1.AH9
MEM_SMBCLK: length 46.8
  TOP w0.089: v1(100.54,17.36) 100.54,16.95 v2(100.68,16.81) 100.97,16.52 RN1811.4
  L3 w0.127: v1(118.59,18.46) 118.72,18.59 118.72,19.85 117.99,20.58 117.99,25.69 117.65,26.03 117.65,27.27 117.99,27.61 117.99,28.1 117.54,28.54 117.54,31.61 118.87,32.94 118.87,37.96 v1(117.45,39.39)
  L4 w0.127: v1(118.59,18.46) 118.51,18.38 107.89,18.38 107.35,18.93 104.91,18.93 103.85,17.87 101.04,17.87 v1(100.54,17.36)
  BOTTOM w0.089: v1(117.45,39.39) 117.84,39.77 CPU1.R7 ; Q1801.3 100.54,16.82 v1(100.54,17.36)
MEM_SMBDATA: length 49.2
  TOP w0.089: v1(101.22,17.36) 101.64,16.94 102.29,16.94 v2(102.54,17.19) RN1811.3
  L3 w0.127: v1(117.45,40.02) 119.09,38.38 119.09,32.61 117.93,31.45 117.93,28.7 118.37,28.26 118.37,27.45 118.03,27.11 118.03,26.18 118.37,25.85 118.37,20.74 119.1,20.01 119.1,18.58 v1(119.22,18.46)
  L4 w0.127: v1(119.22,18.46) 119.22,18.46 118.76,18 107.73,18 107.19,18.55 105.06,18.55 103.44,16.92 101.66,16.92 v1(101.22,17.36)
  BOTTOM w0.089: CPU1.R8 117.85,40.43 v1(117.45,40.02) ; v1(101.22,17.36) 101.37,17.21 101.37,15.49 101.49,15.37 Q1801.6
MIC2_VREFO_L: length 3.8
  TOP w0.203: HDA27.27 20.11,18.51
  TOP w0.254: RN2901.2 v2(18.26,18.83) 18.44,19.02 19.4,19.02 19.91,18.51 20.11,18.51
MIC2_VREFO_R: length 3.8
  TOP w0.203: v2(19.48,18.28) 19.65,18.11 HDA27.28
  TOP w0.254: RN2901.1 18.35,18.16 18.64,18.46 19.3,18.46 v2(19.48,18.28)
MIC_CAP: length 5.9
  TOP w0.203: v1(19.05,16.63) 19.27,16.63 19.56,16.91 HDA27.31
  BOTTOM w0.254: v1(19.05,16.63) 19.81,17.39 20.62,17.39 20.88,17.64 v2(20.88,18) 20.67,18.2 20.04,18.2 C2713.1
MIC_GND: length 6.8
  TOP w0.508: v1(65.78,89.25) 65.78,89.83 v2(65.53,90.09) 64.34,90.09 R5501.1
  BOTTOM w0.305: 64.7,91.88 64.15,92.43 TCBD1.19
  BOTTOM w0.508: 64.7,91.88 65.78,90.8 v1(65.78,89.25)
MODEL_ID: length 9.3
  TOP w0.102: v1(186.82,30.06) 187.35,30.6 188.64,30.6 188.86,30.38 188.86,29.89 189.12,29.63 189.41,29.63 189.61,29.43 KBC24.109
  BOTTOM w0.102: v1(186.82,30.06) 187.02,30.06 187.42,30.47 v2(187.42,30.62) 187.42,30.7 187.12,31 C2407.1 185.9,31 R2441.1 185.57,30.93 185.29,31.21 185.29,32.2 R2442.2
MSATA_CLK_CPU: length 116
  TOP w0.102: 163.4,23.21 158.98,23.21 158.27,23.92 156.04,23.92 155.7,24.26 155.7,24.48 155.57,24.6 155.42,24.6 155.29,24.73 v1(155.29,25.04) ; 163.4,23.21 v2(163.4,23.08) ; 163.4,23.21 170.54,23.21 172.2,24.87 175.17,24.87 175.71,24.34 179.62,24.34 180.32,23.64 181.74,23.64 183.06,22.32 183.06,19.8 185.49,17.36 185.49,17.24 v1(185.19,16.93)
  L3 w0.14: v1(128.7,57.32) 128.7,56.89 125.86,54.05 125.86,50.56 126.53,49.89 127.9,49.89 128.44,49.36 129.35,49.36 130.12,48.59 130.12,47.92 130.4,47.65 130.4,34.16 133.51,31.04 133.51,28.91 134.22,28.2 134.22,27.28 135.05,26.46 135.05,25.21 136.22,24.05 136.22,23.88 137.21,22.89 143.17,22.89 144.98,24.71 148.36,24.71 149.31,25.66 152.92,25.66 153.35,26.09 155.49,26.09 155.66,25.92 155.66,25.58 155.53,25.45 155.42,25.45 155.29,25.32 v1(155.29,25.04)
  BOTTOM w0.102: CPU1.A40 125.91,59.92 126.01,60.01 127.38,60.01 128.32,59.07 128.32,58.32 128.83,57.81 128.83,57.45 v1(128.7,57.32) ; SSD1.55 193.73,17.94 192.19,16.4 190.68,16.4 190.38,16.1 190.24,15.97 185.86,15.97 185.6,16.23 185.6,16.4 185.47,16.53 185.32,16.53 185.19,16.65 v1(185.19,16.93)
MSATA_CLK_CPU#: length 116
  TOP w0.102: v2(159.97,23.56) 159.97,23.44 ; 159.97,23.44 159.08,23.44 158.37,24.15 156.13,24.15 155.93,24.35 v1(155.93,25.04) ; 159.97,23.44 170.44,23.44 172.11,25.1 175.27,25.1 175.8,24.57 179.72,24.57 180.41,23.87 181.83,23.87 183.28,22.41 183.28,19.9 185.72,17.46 185.72,17.03 v1(185.82,16.93)
  L3 w0.14: v1(155.93,25.04) 155.93,25.04 155.93,26.03 155.6,26.36 153.24,26.36 152.8,25.92 149.2,25.92 148.25,24.97 144.87,24.97 143.05,23.16 137.32,23.16 136.49,23.99 136.49,24.16 135.32,25.32 135.32,26.57 134.49,27.39 134.49,28.31 133.78,29.02 133.78,31.15 130.66,34.27 130.66,47.76 130.39,48.03 130.39,48.7 129.46,49.62 128.55,49.62 128.01,50.16 126.64,50.16 126.13,50.67 126.13,53.94 129.16,56.97 129.16,57.6 v1(129.26,57.7)
  BOTTOM w0.102: v1(129.26,57.7) 128.55,58.41 128.55,59.17 127.47,60.24 125.76,60.24 CPU1.B40 ; v1(185.82,16.93) 185.82,16.32 185.95,16.2 190.15,16.2 190.58,16.63 192.09,16.63 193.9,18.44 SSD1.53
MSATA_DEVSLP_R: length 9.6
  TOP w0.102: v1(203.68,17.36) 203.48,17.16 AFTP6302.1 201.83,17.16 R6301.2
  BOTTOM w0.102: SSD1.38 203.5,22.19 204.01,21.68 204.01,17.7 v1(203.68,17.36)
MSATA_RST#: length 10.6
  TOP w0.102: v1(200.2,22.57) 198.23,24.54 ED6305.1 196.89,24.54 R6308.2 196.44,25.44 v2(196.01,25.87)
  BOTTOM w0.102: SSD1.50 201.65,19.19 201.39,19.45 201.39,21.38 v1(200.2,22.57)
MSM#: length 1.8
  TOP w0.102: TP617.1 109.7,68.77 v1(109.29,68.77)
  BOTTOM w0.102: v1(109.29,68.77) 108.81,68.77 CPU1.AP56
MUX_ENA_L: length 3.9
  TOP w0.127: U3802.16 40.24,36.78 40.03,37 39.6,37 38.53,38.07 v2(38.02,38.07) R3859.1
MUX_ENB_L: length 4.6
  TOP w0.127: R3860.1 42.52,40.58 v2(43.03,40.07) 43.03,40.01 43.37,39.67 U3802.10
MUX_INB_N: length 4
  TOP w0.127: R3854.2 43.28,32.6 v2(43.51,32.83) 43.51,33.2 43.34,33.37 42.09,33.37 41.81,33.65 U3802.3
MUX_INB_P: length 4.4
  TOP w0.127: R3853.2 45.31,33.19 v2(45.01,33.49) 44.88,33.62 42.37,33.62 42.21,33.78 U3802.4
MUX_SAI: length 4.4
  TOP w0.127: U3802.14 41.41,37.88 41.12,38.17 39.75,38.17 v2(38.91,39.01) 38.78,39.13 R3855.2
MUX_SAO: length 5.7
  TOP w0.127: v2(36.52,39.84) 36.52,39.77 37.06,39.23 R3857.2 37.44,38.57 38.56,38.57 39.73,37.39 U3802.15
MUX_SBI: length 3.8
  TOP w0.127: R3856.2 40.56,40.45 41.35,39.67 v2(41.43,39.59) 42.21,38.81 U3802.12
MUX_SBO: length 3.7
  TOP w0.127: U3802.11 v2(42.61,38.9) 42.61,39.27 R3858.2
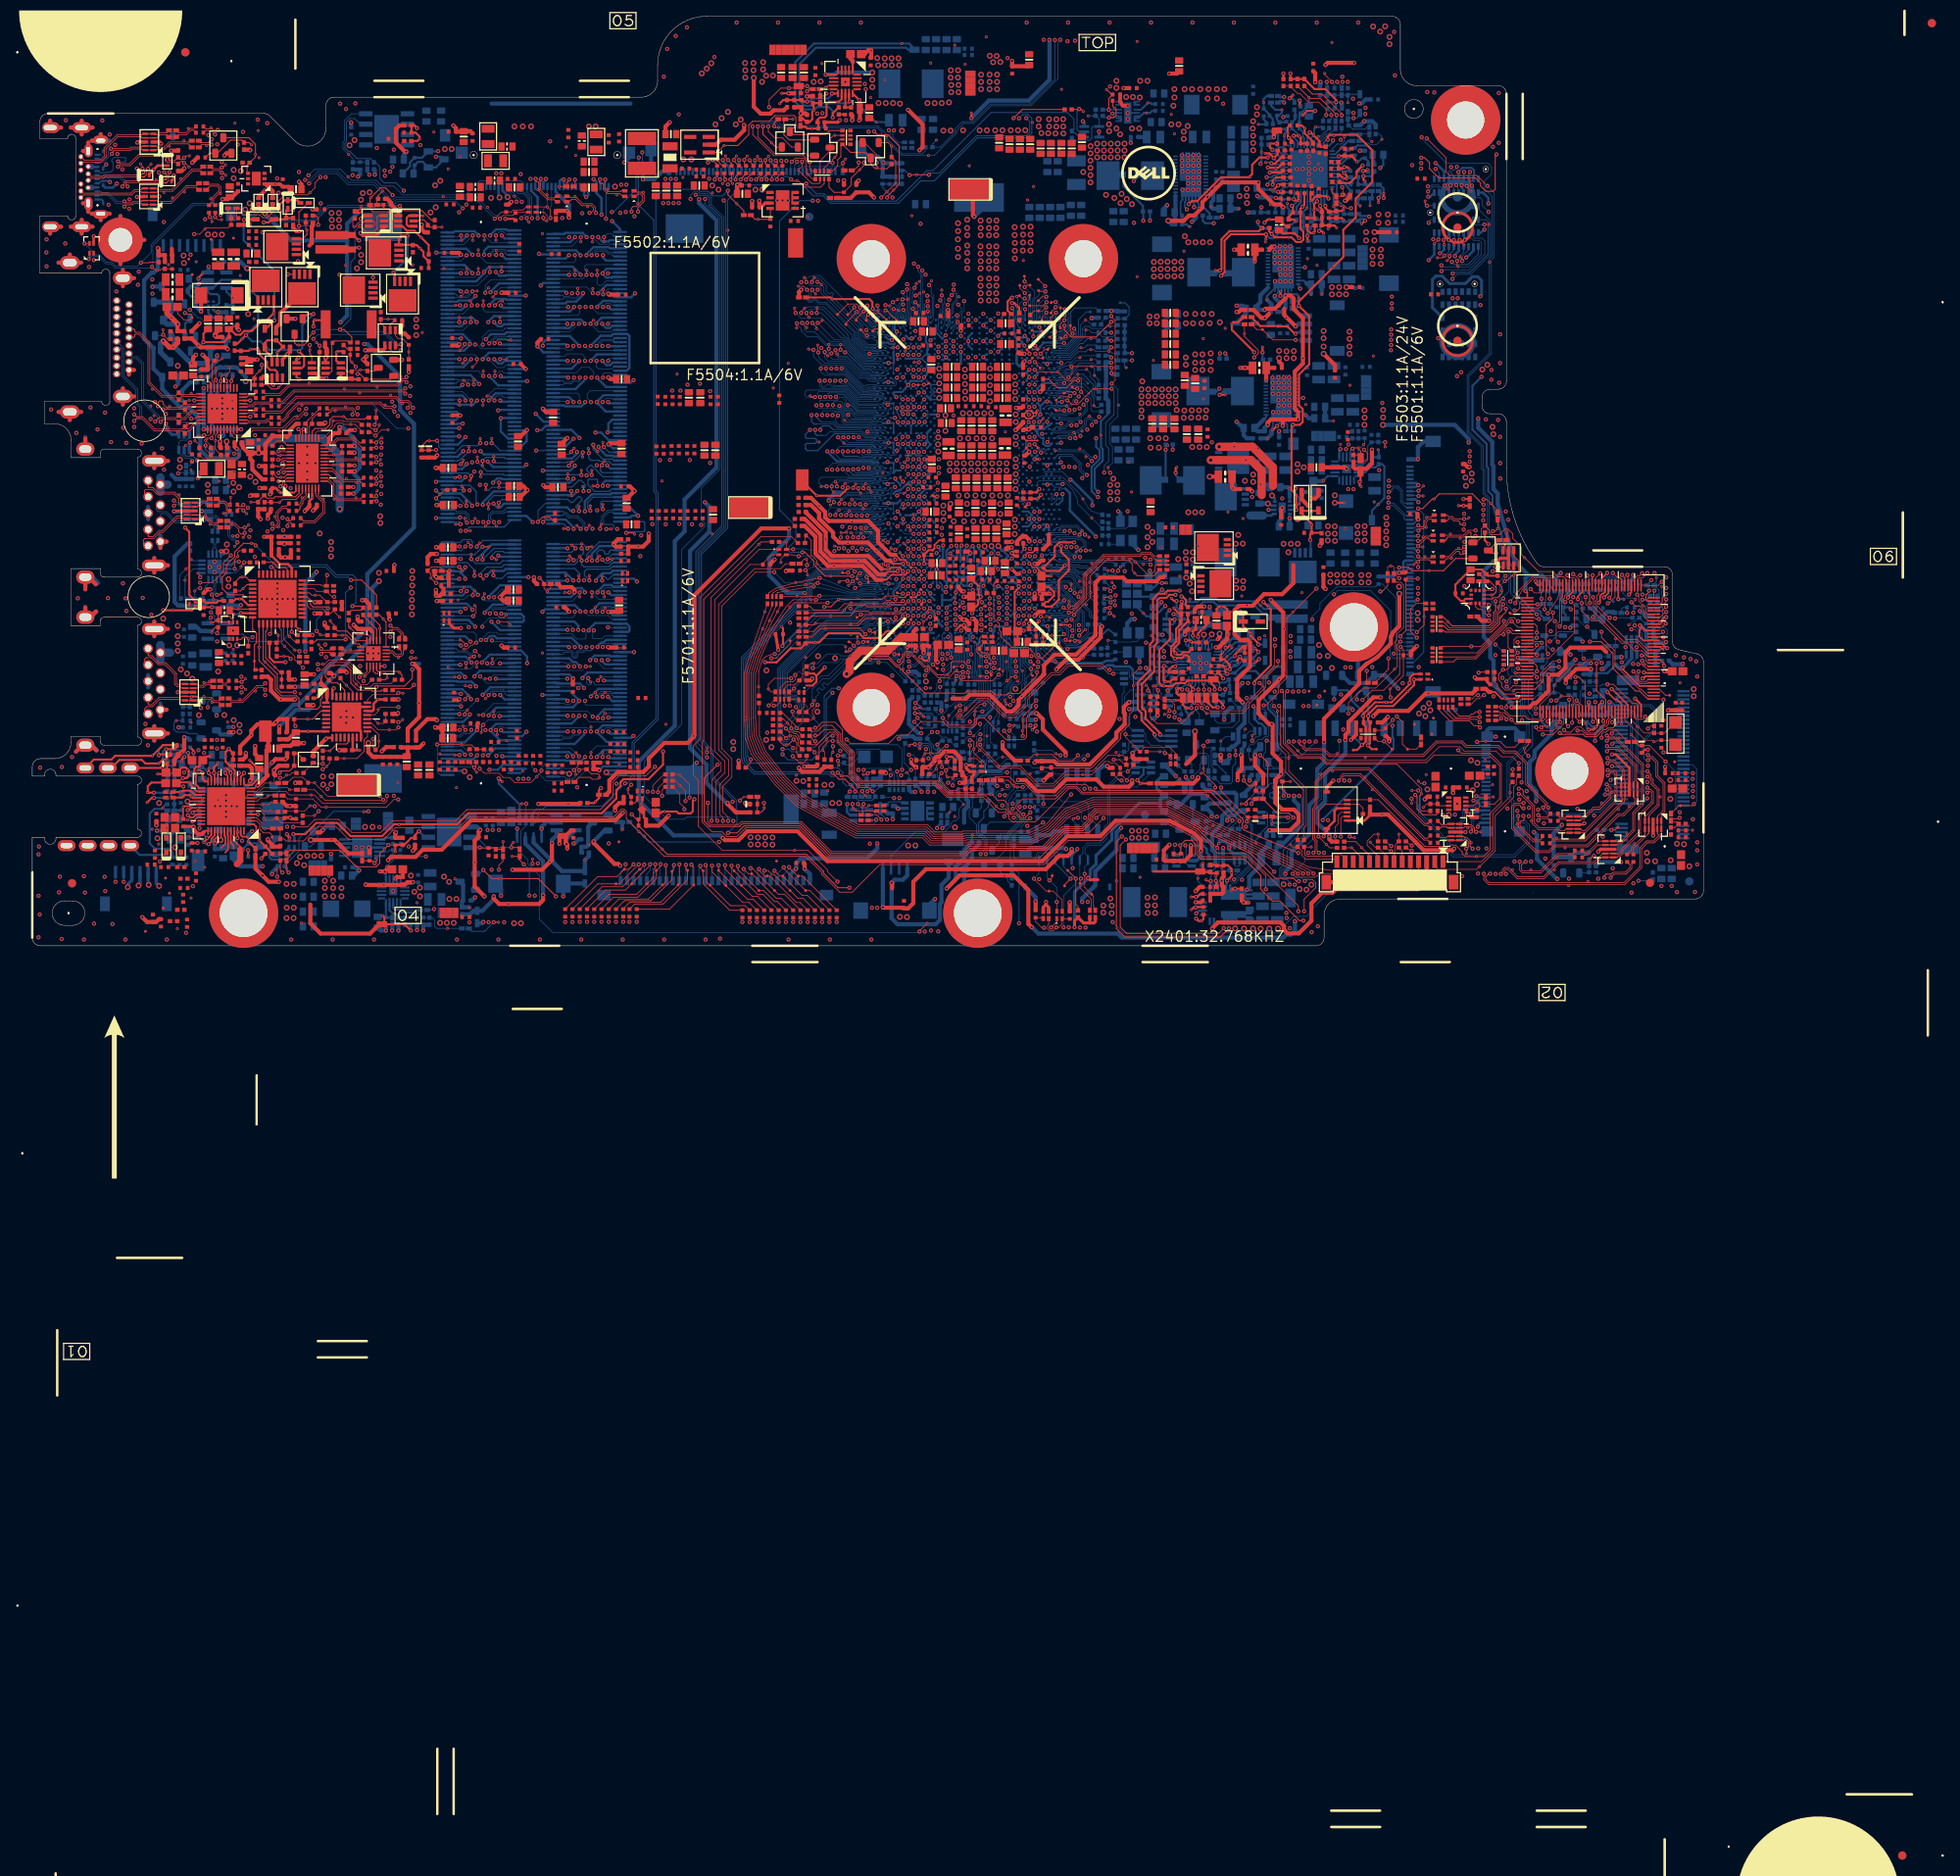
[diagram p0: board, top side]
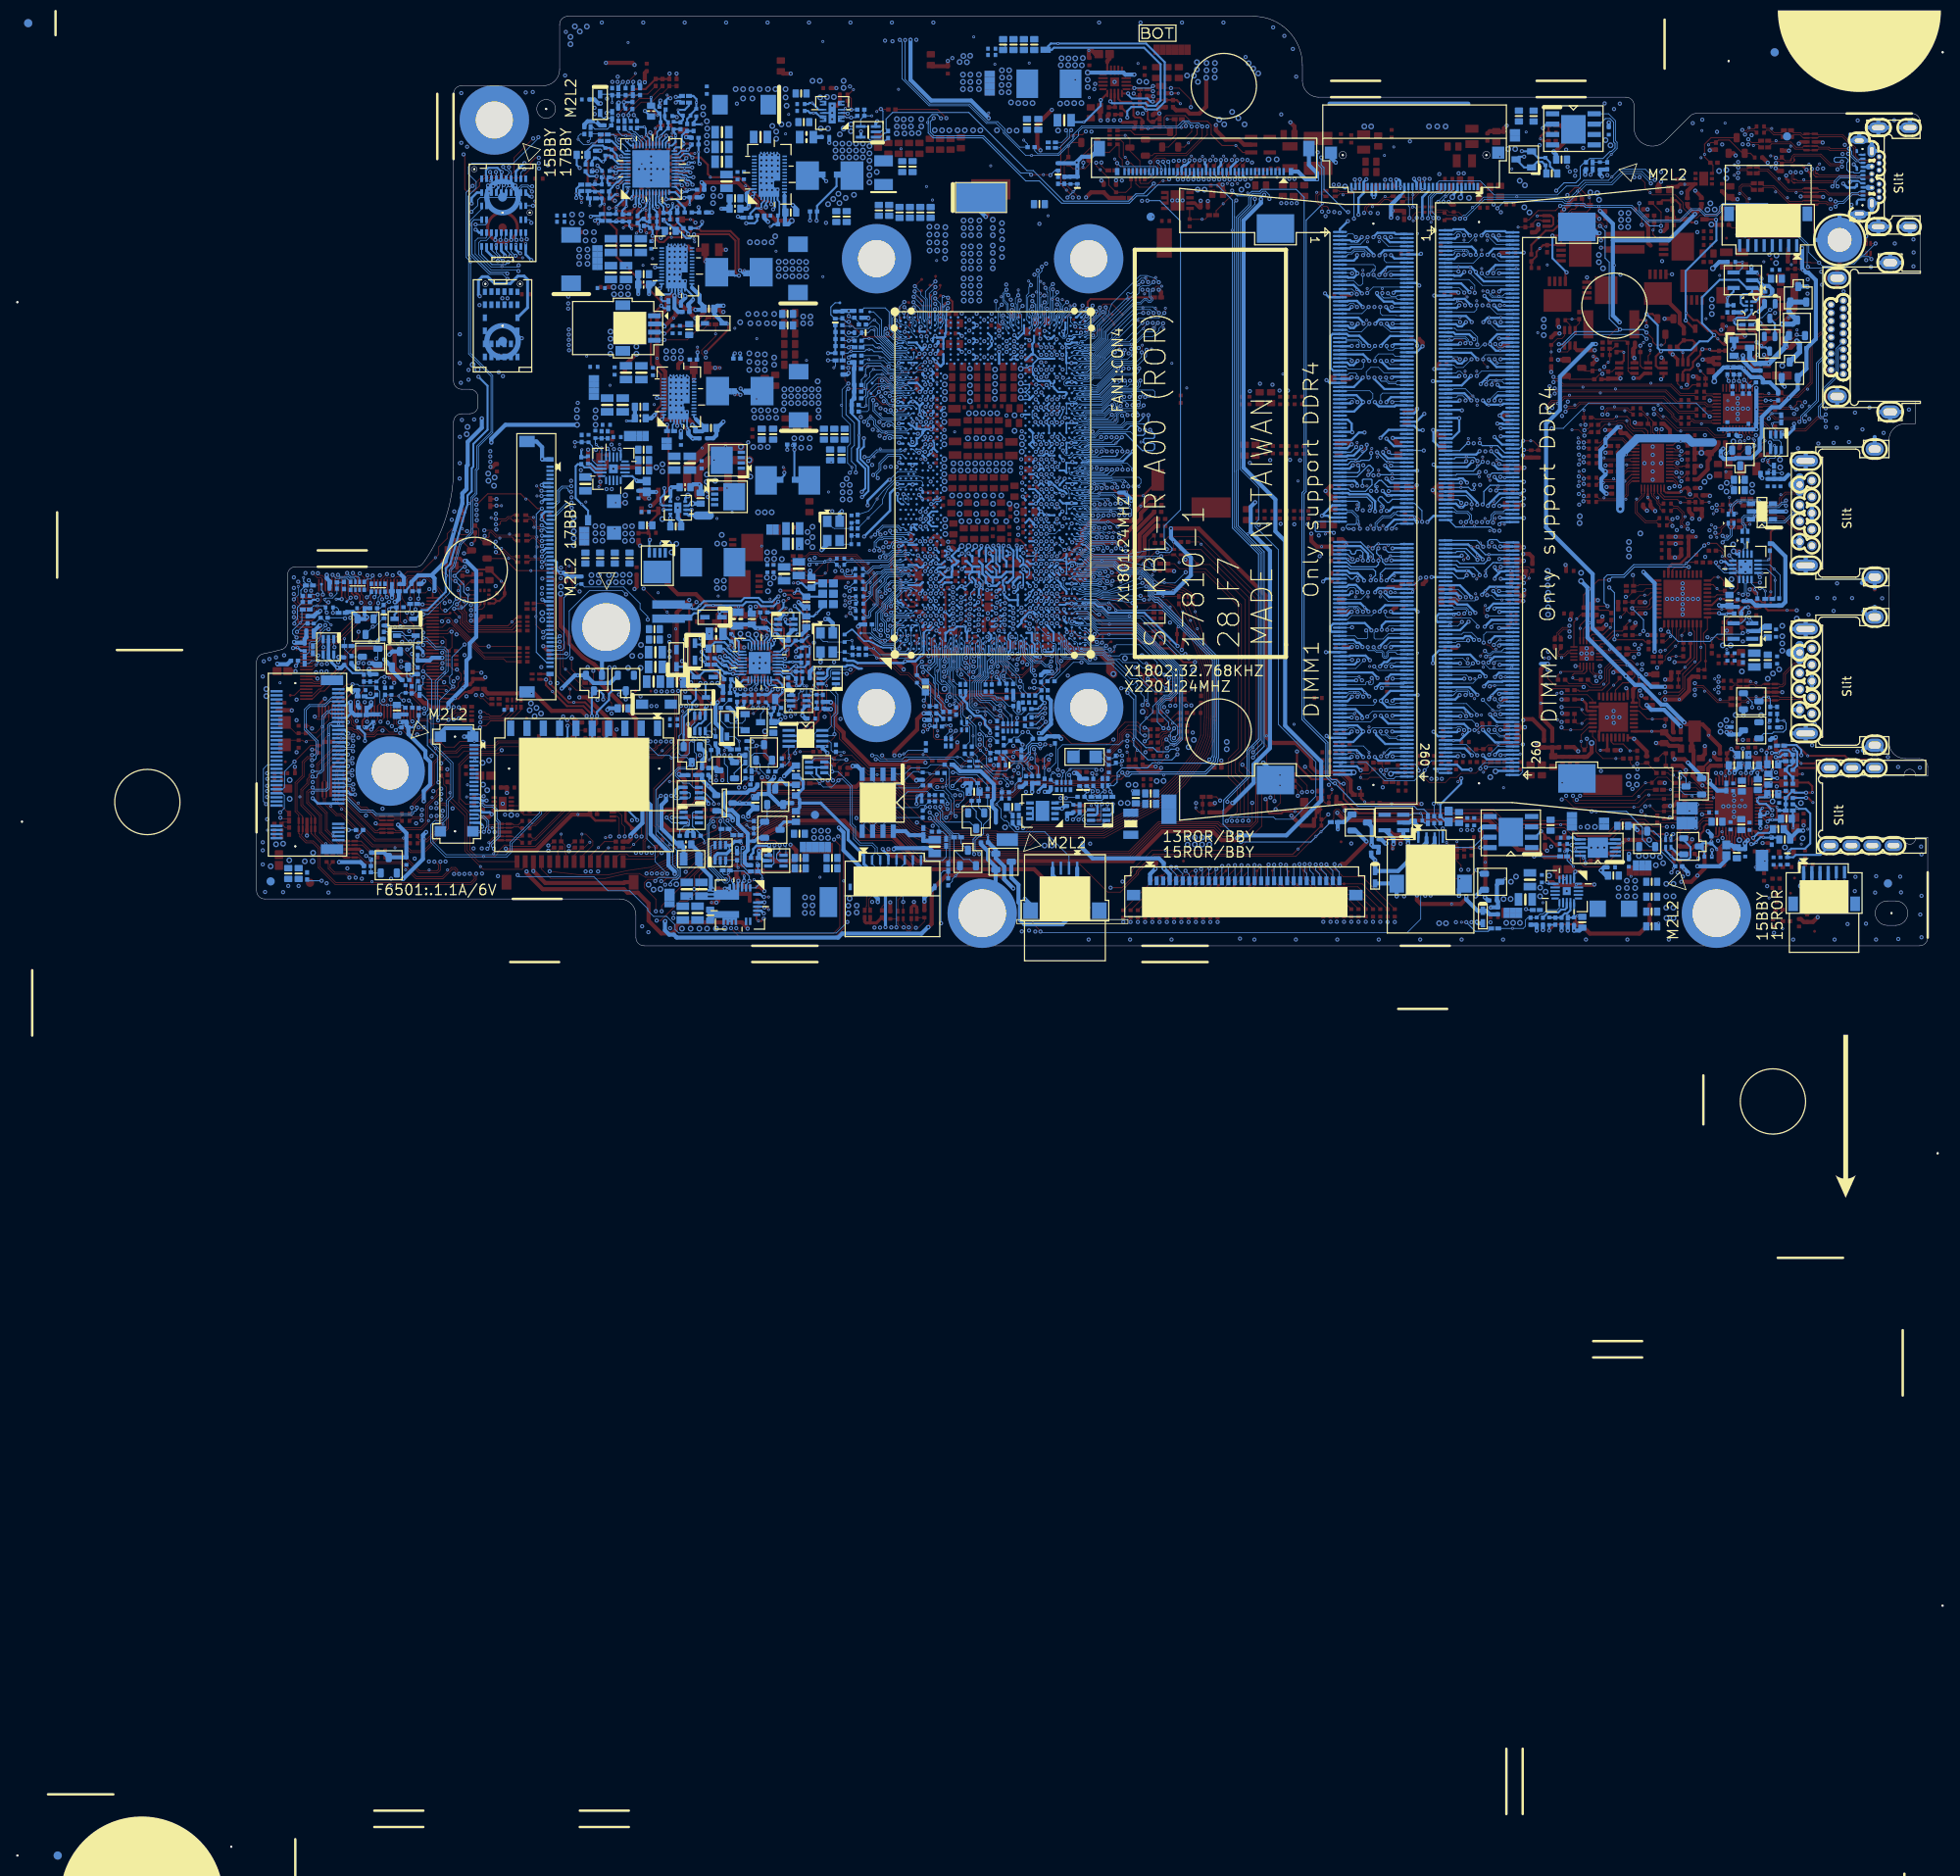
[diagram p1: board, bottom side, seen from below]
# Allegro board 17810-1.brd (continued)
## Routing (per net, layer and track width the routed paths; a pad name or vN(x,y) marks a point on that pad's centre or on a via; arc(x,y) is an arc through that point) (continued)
MUX_TYPEC_RXN1: length 59
  TOP w0.102: U3801.31 30.28,60.55 30.21,60.62 v1(30.2,60.62) ; R3835.1 22.06,95.25 23.1,95.25 v1(23.23,95.38) 23.35,95.38 23.68,95.71 v2(23.68,95.71)
  L6 w0.127: v1(30.2,60.62) 30.2,60.88 29.35,61.73 29.35,67.19 30.26,68.1 30.26,71.15 27.35,74.07 25.21,74.07 23.78,75.51 19.53,75.51 17.62,77.42 17.62,80.09 17.91,80.37 18.59,80.37 18.72,80.5 18.72,80.75 18.59,80.88 17.91,80.88 17.62,81.16 17.62,81.64 17.91,81.92 18.59,81.92 18.72,82.05 18.72,82.3 18.59,82.43 17.91,82.43 17.62,82.71 17.62,86.75 17.91,87.03 18.9,87.03 19.02,87.16 19.02,87.41 18.9,87.54 17.91,87.54 17.62,87.82 17.62,88.3 17.91,88.58 18.95,88.58 19.07,88.71 19.07,88.96 18.95,89.09 17.91,89.09 17.62,89.37 17.62,89.8 21.75,93.93 21.75,94.67 22.47,95.38 v1(23.23,95.38)
MUX_TYPEC_RXN2: length 62.3
  TOP w0.102: v1(30.4,56.3) 30.61,56.51 30.61,56.51 30.73,56.63 30.73,56.86 31.22,57.35 U3801.39 ; R3837.1 20.78,98.21 21.36,98.21 ; v2(21.36,98.09) 21.36,98.21 ; 21.36,98.21 v1(21.99,98.21)
  L6 w0.127: v1(30.4,56.3) 30.67,56.04 30.67,55.83 30.45,55.62 29.96,55.62 27.15,58.42 27.15,60.6 28.05,61.5 28.05,70.13 25.6,72.58 23.7,72.58 23.09,73.19 18.84,73.19 16.33,75.7 16.33,86.1 15.67,86.76 15.67,89.68 20.37,94.38 20.37,98.14 20.81,98.58 21.19,98.58 21.33,98.44 21.33,98.06 21.55,97.84 21.75,97.84 21.99,98.09 v1(21.99,98.21)
MUX_TYPEC_RXP1: length 59.1
  TOP w0.102: U3801.30 31.09,60.95 30.92,60.78 30.65,60.78 30.56,60.88 30.56,61.13 v1(30.56,61.14) ; v2(23.71,94.44) 23.7,94.44 23.4,94.75 v1(23.23,94.75) 22.95,95.02 22.16,95.02 R3834.1
  L6 w0.127: v1(30.56,61.14) 30.76,61.33 30.76,61.58 30.65,61.69 30.35,61.69 30.22,61.56 29.89,61.56 29.61,61.84 29.61,67.08 30.53,67.99 30.53,71.26 27.46,74.34 25.32,74.34 23.89,75.77 19.65,75.77 17.89,77.53 17.89,79.98 18.02,80.11 18.7,80.11 18.98,80.39 18.98,80.87 18.7,81.15 18.02,81.15 17.89,81.28 17.89,81.53 18.02,81.66 18.7,81.66 18.98,81.94 18.98,82.41 18.7,82.7 18.02,82.7 17.89,82.82 17.89,86.64 18.02,86.77 19.01,86.77 19.29,87.05 19.29,87.52 19.01,87.81 18.02,87.81 17.89,87.93 17.89,88.19 18.02,88.32 19.06,88.32 19.34,88.6 19.34,89.07 19.06,89.36 18.02,89.36 17.89,89.48 17.89,89.69 22.02,93.82 22.02,94.56 22.58,95.11 22.85,95.11 23.22,94.75 v1(23.23,94.75)
MUX_TYPEC_RXP2: length 62.3
  TOP w0.102: U3801.40 31.14,56.95 30.96,56.77 30.96,56.4 v1(31.04,56.33) ; v1(21.99,98.85) 21.59,98.44 20.65,98.44 R3836.1
  L6 w0.127: v1(31.04,56.33) 30.94,56.23 30.94,55.72 30.56,55.35 29.85,55.35 26.88,58.31 26.88,60.71 27.79,61.61 27.79,70.02 25.49,72.32 23.59,72.32 22.98,72.93 18.73,72.93 16.06,75.59 16.06,85.99 15.4,86.65 15.4,89.79 20.1,94.49 20.1,98.25 20.7,98.85 v1(21.99,98.85)
MUX_TYPEC_TXN1: length 57
  TOP w0.102: U3801.34 31.22,59.35 31.05,59.52 30.8,59.52 30.68,59.41 v1(30.68,59.17) ; v2(23.21,88.99) 22.73,88.99 v1(22.4,89.32) 22.43,89.35 C3863.1
  L6 w0.127: v1(30.68,59.17) 30.61,59.25 30.61,59.86 31.67,60.93 31.67,62.01 30.39,63.3 30.39,66.76 31.3,67.67 31.3,71.63 29.48,73.46 29.48,73.64 29.96,74.12 29.96,74.52 29.62,74.85 29.22,74.85 28.74,74.37 28.56,74.37 28.38,74.55 28.38,74.73 28.86,75.21 28.86,75.61 28.53,75.95 28.13,75.95 27.65,75.47 27.47,75.47 27.29,75.65 27.29,75.83 27.77,76.31 27.77,76.71 27.43,77.05 27.03,77.05 26.55,76.57 26.37,76.57 25.87,77.07 24.39,77.07 23.04,78.42 23.04,79.09 23.16,79.21 25.62,79.21 25.91,79.5 25.91,79.97 25.62,80.26 23.16,80.26 22.4,81.02 22.4,82.08 22.53,82.21 25.29,82.21 25.58,82.49 25.58,82.97 25.29,83.25 22.53,83.25 22.4,83.38 22.4,85.23 20.75,86.88 20.75,88.03 21.04,88.32 21.88,88.32 22.25,88.69 22.25,89.17 v1(22.4,89.32)
MUX_TYPEC_TXN1_C: length 4.8
  TOP w0.102: 22.97,92.29 22.22,91.54 22.22,90.97 C3863.2 ; 22.97,92.29 v2(23.06,92.19) ; 22.97,92.29 23.1,92.42 23.1,93.02 22.78,93.34 21.44,93.34 R3833.1
MUX_TYPEC_TXN2: length 58.5
  TOP w0.102: U3801.36 31.21,58.55 31.15,58.49 30.63,58.49 30.17,58.03 v1(30.17,57.95) ; v1(22.4,99.43) 21.93,99.9 21.22,99.9 C3862.1
  L6 w0.127: v1(30.17,57.95) 30.17,58.03 29.8,58.4 28.57,59.63 28.57,68.87 29.3,69.6 29.3,71.02 28.03,72.29 27.32,72.29 26.32,73.3 24.89,73.3 24.19,73.99 21.81,73.99 21.11,74.69 18.09,74.69 16.85,75.93 16.85,90.14 20.97,94.26 20.97,95.79 23.28,98.1 23.28,98.56 v1(22.4,99.43)
MUX_TYPEC_TXN2_C: length 2.9
  TOP w0.102: R3839.1 17.91,99.41 18.9,99.41 19.44,99.95 19.77,99.95 C3862.2
MUX_TYPEC_TXP1: length 56.6
  TOP w0.102: v1(30.15,59.59) 30.54,59.59 30.7,59.75 U3801.33 ; v2(22.02,88.76) 22.02,89.07 v1(21.77,89.32) 21.66,89.42 C3864.1
  L6 w0.127: v1(30.15,59.59) 30.34,59.78 30.34,59.97 31.41,61.04 31.41,61.9 30.12,63.19 30.12,66.87 31.04,67.78 31.04,71.52 29.21,73.35 29.21,73.75 29.69,74.23 29.69,74.41 29.51,74.59 29.33,74.59 28.85,74.11 28.45,74.11 28.12,74.44 28.12,74.84 28.6,75.32 28.6,75.5 28.42,75.68 28.24,75.68 27.76,75.2 27.36,75.2 27.02,75.54 27.02,75.94 27.5,76.42 27.5,76.6 27.32,76.78 27.14,76.78 26.66,76.3 26.26,76.3 25.76,76.8 24.28,76.8 22.77,78.31 22.77,79.2 23.05,79.48 25.51,79.48 25.64,79.61 25.64,79.86 25.51,79.99 23.05,79.99 22.13,80.91 22.13,82.19 22.42,82.48 25.18,82.48 25.31,82.6 25.31,82.86 25.18,82.98 22.42,82.98 22.13,83.27 22.13,85.12 20.48,86.77 20.48,88.14 20.93,88.59 21.77,88.59 21.98,88.8 21.98,89.11 v1(21.77,89.32)
MUX_TYPEC_TXP1_C: length 4.6
  TOP w0.102: R3832.1 21.77,93.11 22.69,93.11 22.87,92.92 22.87,92.51 21.99,91.63 21.99,91.56 ; 21.99,91.56 21.99,91.1 C3864.2 ; 21.99,91.56 v2(21.87,91.56)
MUX_TYPEC_TXP2: length 59.2
  TOP w0.102: U3801.37 30.93,58.15 v1(30.81,58.03) ; v1(22.73,99.99) 22.6,99.86 22.29,99.86 22.03,100.13 21.89,100.13 ; C3861.1 21.27,100.13 21.89,100.13 ; 21.89,100.13 v2(21.89,100.27)
  L6 w0.127: v1(22.73,99.99) 22.73,99.73 22.85,99.62 22.85,99.37 23.54,98.67 23.54,97.99 21.23,95.68 21.23,94.15 17.12,90.03 17.12,76.04 18.2,74.96 21.22,74.96 21.92,74.26 24.3,74.26 25,73.56 26.43,73.56 27.43,72.56 28.14,72.56 29.56,71.13 29.56,69.49 28.84,68.76 28.84,59.74 29.99,58.59 29.99,58.59 30.11,58.47 30.29,58.47 30.4,58.59 30.61,58.59 30.81,58.39 v1(30.81,58.03)
MUX_TYPEC_TXP2_C: length 3
  TOP w0.102: 19.23,100.06 19.35,100.18 19.82,100.18 C3861.2 ; 19.23,100.06 18.8,99.64 17.93,99.64 R3838.1 ; 19.23,100.06 v2(19.12,100.17)
NB_MODE#: length 43.4
  TOP w0.102: KBC24.96 182.58,30.24 182.26,29.91 181.07,29.91 180.69,29.53 v1(180.69,29.25)
  L6 w0.102: v1(180.69,29.25) 180.69,29.38 180.41,29.66 178.87,29.66 178.61,29.91 172.55,29.91 171.76,30.7 166.95,30.7 166.42,31.23 159.26,31.23 158.16,30.14 156.94,30.14 156.74,30.34 151.96,30.34 151.93,30.38 148.87,30.38 v1(148.87,30.37)
  BOTTOM w0.102: v2(148.69,26.56) 148.59,26.46 R2050.1 149.25,26.31 Q2001.3 149.84,26.7 149.15,27.4 149.15,29.81 148.87,30.09 v1(148.87,30.37)
NB_MUTE#: length 195.4
  TOP w0.102: v1(151.2,6.93) 151.2,8.59 148.88,10.91 143.35,10.91 142.82,11.45 142.82,12.77 142.17,13.41 141.83,13.59 141.78,13.62 141.56,13.73 140.77,14.14 140.45,14.3 139.58,14.75 139.31,14.9 132.99,14.9 131.01,12.92 126.97,12.92 124,9.95 103.88,9.95 100.51,6.57 98.97,6.57 96.75,8.79 96.75,9.01 94.79,10.96 77.45,10.96 v2(74.99,13.42) 72.81,15.61 72.81,16.47 72.55,16.73 72.2,16.73 71.29,15.82 53.62,15.82 52.27,14.47 44.52,14.47 43.08,13.02 38.81,13.02 37.21,14.62 35.02,14.62 33.25,12.84 31.11,12.84 30.86,13.1 R2728.1 30.38,13.12 R2708.1 ; KBC24.119 193.61,27.98 193.61,27.95 193.24,27.58 193.24,27.19 192.96,26.92 192.66,26.92 191.61,25.86 190.5,25.86 189.98,26.38 v1(189.41,26.38)
  L4 w0.102: v1(189.41,26.38) 189.11,26.38 183.89,21.17 183.89,15.74 181.35,13.19 175.13,13.19 174.14,14.18 165.21,14.18 164.51,13.48 162.89,13.48 161.61,12.2 158.39,10.92 158.06,10.83 154.31,10.83 153.14,9.67 152.24,9.67 151.33,8.76 151.33,7.05 v1(151.2,6.93)
NCT7718_DXN: length 174.2
  TOP w0.254: v1(140.64,43.53) 139.18,43.53 138.8,43.15 138.01,43.15 137.38,42.52 v2(137.38,41.22) 137.38,37.34 137.01,36.96 137.01,33.8 135.52,32.31 135.52,28.96 135.96,28.52 135.96,27.63 137.49,26.1 137.49,26 137.59,25.9 v1(137.59,25.87)
  L3 w0.254: v1(49.76,97.4) 50.11,97.04 52.07,97.04 53.49,98.47 56.82,98.47 57.71,97.58 69.7,97.58 71.8,95.47 73.2,95.47 73.71,95.98 75.96,95.98 78.02,98.03 79.48,98.03 85.46,104.02 90.59,104.02 93.65,100.96 98.02,100.96 100.18,98.8 122.28,98.8 128.85,92.23 128.85,90.97 130.2,89.63 131.72,89.63 134.29,87.06 134.29,71.34 135.18,70.45 135.18,55.44 139.57,51.05 139.57,47.04 140.38,46.23 140.38,43.78 v1(140.64,43.53)
  BOTTOM w0.254: THM261.3 138.12,25.09 137.59,25.62 v1(137.59,25.87) ; C2606.2 46.3,95.55 46.3,96.03 C2607.2 47.77,96.59 Q2603.2 49.73,97.37 v1(49.76,97.4)
NCT7718_DXP: length 172.6
  TOP w0.254: v1(140.13,43.02) 139.39,43.02 139.01,42.64 138.22,42.64 137.89,42.31 137.89,37.13 137.51,36.75 137.51,33.59 136.03,32.1 136.03,29.17 136.47,28.73 136.47,27.84 v2(137.41,26.9) 138.25,26.06 v1(138.25,25.87)
  L3 w0.254: v1(49.48,96.71) 49.66,96.54 52.28,96.54 53.7,97.96 56.61,97.96 57.5,97.07 69.49,97.07 71.59,94.96 73.41,94.96 73.92,95.47 76.17,95.47 78.23,97.53 79.69,97.53 85.67,103.51 90.38,103.51 93.44,100.45 97.8,100.45 99.97,98.29 122.07,98.29 128.34,92.02 128.34,90.76 129.99,89.12 131.51,89.12 133.78,86.85 133.78,71.13 134.67,70.24 134.67,55.23 139.06,50.83 139.06,46.83 139.88,46.02 139.88,43.27 v1(140.13,43.02)
  BOTTOM w0.254: C2606.1 46.81,94.73 46.81,95.62 C2607.1 47.27,96.08 47.87,96.08 Q2603.1 49.47,95.4 Q2603.3 50.13,96.71 v1(49.48,96.71) ; THM261.2 138.41,25.74 138.28,25.87 v1(138.25,25.87)
NRB_BIT: length 26.3
  L4 w0.102: v1(109.86,22.97) 109.8,22.97 109.23,22.39 107.54,22.39 106.87,23.07 106.87,38.8 106.34,39.33 106.34,39.68 106.63,39.97 107.49,39.97 v1(107.98,40.46)
  BOTTOM w0.102: v1(109.86,22.97) 110.37,22.45 110.37,22.36 v2(110.41,22.32) 110.29,22.19 110.29,21.66 109.78,21.15 R2007.2 R2019.1 ; CPU1.AR7 107.7,40.11 107.98,40.38 v1(107.98,40.46)
OVER_CURRENT_P8#: length 48.4
  TOP w0.102: R2474.1 179.63,53.37 v2(178.79,54.21) 178.29,54.7 v1(177.9,54.7)
  L3 w0.102: v1(177.9,54.7) 178.15,54.96 178.15,61.29 175.86,63.59 175.86,68.42 176.69,69.26 176.69,71.37 179.02,73.69 179.02,78.73 179.23,78.94 179.23,89.24 v1(178.51,89.96)
  BOTTOM w0.102: GPU1.C2 172.45,91.17 173,91.71 177.44,91.71 177.75,91.41 177.75,90.72 v1(178.51,89.96)
P_SYS: length 88.6
  TOP w0.102: PR4671.1 159.97,91 160.32,90.64 160.88,90.64 161.12,90.4 v1(161.64,90.4) ; v1(150.95,29.46) 151.21,29.46 152.73,30.98 152.73,31.81 153.77,32.85 153.77,40.15 v2(154.52,40.9) v1(157.4,43.78)
  L3 w0.102: v1(165.48,66.54) 162.94,69.08 162.94,80.5 162.77,80.67 161.39,82.05 161.39,90.15 v1(161.64,90.4)
  L4 w0.102: v1(157.4,43.78) 157.61,43.98 157.61,45.33 159.38,47.11 160.88,47.11 160.93,47.16 163.09,47.16 164.13,48.2 164.13,59.35 164.97,60.19 164.97,66.03 v1(165.48,66.54)
  L6 w0.102: v1(150.95,29.46) 150.79,29.46 150.26,28.92 147.91,28.92 146.72,30.11 145.58,30.11 144.45,28.97 144.45,28.95 143.83,28.33 140.36,28.33 v1(140.03,28)
  BOTTOM w0.102: PG4415.2 140.56,29.23 PR4401.1 140.84,28.9 PC4430.1 140.39,28.36 v1(140.03,28)
PANEL_BKEN_EC: length 210.6
  TOP w0.127: KBC24.117 192.81,29.49 192.87,29.56 192.87,30.15 191.74,31.28 v1(191.74,34.63) ; R5515.2 90.93,100.8 v1(90.93,100.47) 91.11,100.3 v2(91.49,100.3)
  L3 w0.127: v1(191.74,34.63) 191.74,34.79 189.53,37.01 189.53,38.92 188.54,39.91 188.04,39.91 187.13,40.82 187.13,42.49 186.42,43.21 184.73,43.21 184.07,42.55 182.57,42.55 181.3,43.82 180.74,43.82 180,44.57 180,48.2 179.35,49.88 179.1,50.13 179.1,50.14 176.34,52.89 176.34,55.6 177.25,56.51 177.25,61.14 175.13,63.26 175.13,68.72 175.97,69.56 175.97,71.67 178.27,73.98 178.27,79.06 178.5,79.29 178.5,86.51 177.56,87.46 177.56,91.09 179.12,92.65 179.12,95.58 177.78,96.92 171.86,96.92 167.22,101.56 167.22,104.53 165.54,106.2 165.54,107.99 161.73,111.8 87.15,111.8 84.75,109.39 84.75,107.4 v1(79.25,101.9)
  L6 w0.127: v1(90.93,100.47) 88.43,102.98 80.33,102.98 v1(79.25,101.9)
PANEL_BKEN_EC_C: length 6.9
  TOP w0.127: v2(93.22,101.31) R5515.1 92.12,101.13 92.12,99.43 92.79,98.77 95.85,98.77 D5503.1
PBAT_CHG_SMBCLK: length 69.9
  TOP w0.203: v1(197.56,33.52) 197.64,33.44 KBC24.9
  TOP w0.254: v1(145.31,29.22) 144.69,29.22 143.89,30 PG4410.1 ; RN4302.3 163.45,26.86 163.19,27.12 EC4309.1 163.19,28.08 v1(163.12,28.16) 163.12,28.36 164.59,29.84 v2(165.96,29.84) 166.61,29.84 168.83,32.06 v1(168.83,32.22) 168.86,32.25 168.86,32.84 169.33,33.31 RN2402.3
  L6 w0.254: v1(197.56,33.52) 197.89,33.19 197.89,32.55 197.59,32.25 193.6,32.25 193.3,32.55 190.87,32.55 189.57,31.26 189.19,31.26 187.08,31.26 186.85,31.03 183.76,31.03 183.15,30.42 180.23,30.42 178.71,31.94 172.49,31.94 172.34,32.1 168.96,32.1 v1(168.83,32.22) ; v1(145.31,29.22) 145.31,29.3 145.74,29.73 146.57,29.73 147.75,28.54 150.94,28.54 151.25,28.85 158.38,28.85 159.59,30.05 v1(159.59,30.19)
  BOTTOM w0.254: v1(145.31,29.22) 145.31,29.24 145.08,29.47 PR4439.2 ; v1(163.12,28.16) 163.12,28.67 161.64,30.14 161.64,30.88 161.21,31.31 159.65,31.31 D4306.3 v1(159.59,30.19)
PBAT_CHG_SMBDAT: length 67
  TOP w0.203: KBC24.8 197.77,33.04
  TOP w0.254: v1(197.38,32.76) 197.48,32.76 197.77,33.04 ; RN2402.4 170.12,32.63 v1(169.37,32.63) 169.37,31.94 v2(168.59,31.16) 166.8,29.38 164.78,29.38 163.75,28.35 v1(163.75,28.16) 163.75,27.63 EC4310.1 163.95,27.32 RN4302.2 ; PG4409.1 145.44,30.09 145.95,29.58 v1(145.95,29.22)
  L6 w0.254: v1(145.95,29.22) 146.43,29.22 147.56,28.08 151.13,28.08 151.44,28.39 158.57,28.39 159.82,29.63 161.8,29.63 v1(162.36,30.19) ; v1(197.38,32.76) 193.74,32.76 193.49,33.01 190.68,33.01 189.38,31.72 186.89,31.72 186.66,31.49 183.57,31.49 182.96,30.88 180.42,30.88 179.16,32.13 178.9,32.4 172.68,32.4 172.53,32.55 169.44,32.55 v1(169.37,32.63)
  BOTTOM w0.254: v1(145.95,29.22) 145.95,29.89 PR4438.2 ; v1(163.75,28.16) 163.75,30.99 D4305.3 162.8,31.25 162.36,30.8 v1(162.36,30.19)
PBAT_PRES1#: length 4.3
  TOP w0.102: AFTP4309.1 166.67,24.1 v1(165.7,25.06) 164.92,25.06 RN4302.8
  BOTTOM w0.102: v1(165.7,25.06) BATT1.6
PBAT_PRES#: length 311.5
  TOP w0.102: RN4302.1 165.63,26.41 EC4306.2 165.99,26.77 165.99,26.89 v1(166.78,27.67) ; v1(200.28,42.46) 200.28,42.18 199.54,41.44 KBC24.29 ; v1(155.9,4.23) 155.9,5.71 157.33,7.13 157.33,7.71 156.9,8.13 156.17,8.13 v1(155.98,7.94) ; v1(45.18,72.97) 45.01,72.79 44.17,72.79 43.86,73.09 PQ4313.5
  L3 w0.102: v1(166.78,27.67) 164.83,25.72 158.01,25.72 v1(157.33,25.04) ; v1(155.9,4.23) 155.22,3.55 155.22,2.86 154.94,2.58 154.33,2.58 154.26,2.66 144.55,2.66 142.78,0.89 131.48,0.89 129.64,2.73 122.55,2.73 120.44,4.85 120.44,5.65 120.21,5.88 117.49,8.6 103.34,8.6 99.22,4.49 61.39,4.49 61.21,4.66 50.94,4.66 49.19,6.42 49.19,7.17 44.46,11.9 42.34,11.9 41.96,11.52 39.54,11.52 38.07,12.99 38.07,24.79 34.84,28.02 34.19,28.02 32.65,29.56 32.2,29.56 31.75,30.01 31.75,33.7 32.1,34.05 32.1,35.36 31.67,35.79 31.67,37.76 32.23,38.32 32.23,39.51 33.35,40.63 33.35,44.11 33.08,44.38 33.08,51.31 35.15,53.38 35.15,62.78 34.97,62.96 34.97,72.99 34.47,73.5 v1(34.47,74.39)
  L4 w0.102: v1(200.28,42.46) 199.74,41.93 199.74,39.57 199.45,39.27 199.45,38.02 199.16,37.73 199.16,30.95 v1(199.95,30.17)
  L6 w0.102: v1(166.78,27.67) 166.85,27.6 171.6,27.6 173.3,29.3 178.36,29.3 179.27,28.39 182.01,28.39 182.73,29.1 v1(184.29,29.1) 190.85,29.1 192.14,27.81 192.14,27.37 192.6,26.92 197.15,26.92 199.95,29.71 v1(199.95,30.17)
  BOTTOM w0.089: v2(199.74,44.03) 199.74,42.99 v1(200.28,42.46)
  BOTTOM w0.102: v1(184.29,29.1) 184.32,29.13 R2415.1 ; v1(155.98,7.94) 155.55,8.37 153.41,8.37 153.16,8.63 153.16,9.26 153.82,9.92 153.82,11.57 155.9,13.66 155.9,19.1 153.14,21.86 152.09,21.86 151.51,22.44 D4304.3 152.11,23.08 153.97,23.08 154.23,23.33 155.62,23.33 v1(157.33,25.04) ; v1(34.47,74.39) 35,74.92 43.23,74.92 v1(45.18,72.97)
PBAT_SMBCLK1: length 5
  TOP w0.254: RN4302.6 163.45,25.01 163.05,24.6 v1(162.99,24.6) 162.38,23.99 AFTP4311.1
  BOTTOM w0.254: v1(162.99,24.6) 161.7,25.89 BATT1.4
PBAT_SMBDAT1: length 4.3
  TOP w0.254: AFTP4310.1 164.18,24.1 v1(163.72,24.56) 163.95,24.79 RN4302.7
  BOTTOM w0.254: v1(163.72,24.56) 163.7,24.58 BATT1.5
PCH_BATLOW#: length 34.4
  L4 w0.102: v1(101.9,21.56) 101.4,21.05 100.58,21.05 99.52,22.11 99.52,24.65 98.96,25.21 98.96,30.14 101.62,32.81 101.62,35.37 104.04,37.79 104.04,38.96 104.25,39.17 104.25,39.5 104.24,39.51 104.24,41.82 106.51,44.09 v1(106.73,44.09)
  BOTTOM w0.102: v1(101.9,21.56) 102.08,21.74 105,21.74 v2(105.13,21.6) 105.16,21.6 105.67,21.1 RN1704.6 ; CPU1.AU13 106.4,43.76 v1(106.73,44.09)
PCH_DPC_N0: length 164
  TOP w0.102: C3813.1 41.76,54.96 42,54.96 v1(42.16,55.12) 42.16,55.64 v2(42.29,55.77)
  L6 w0.127: v1(124.4,64.21) 124.4,64.45 125.78,65.83 125.78,66.85 127.7,68.77 127.7,70.16 128.23,70.7 128.23,73.54 129.06,74.37 129.06,78.78 131.99,81.72 131.99,85.29 130,87.28 128.05,87.28 126.6,88.72 126.6,89.74 120.85,95.5 101.06,95.5 99.89,96.66 96.9,96.66 95.78,95.55 77.95,95.55 77.5,95.99 74.18,95.99 73.75,95.56 71.84,95.56 71.19,96.21 55.09,96.21 53.89,95 49.41,95 47.12,92.7 47.12,90.47 44.49,87.84 44.49,82.96 44.71,82.73 44.71,79.3 43.37,77.96 43.37,65.34 44.79,63.92 44.79,62.12 45.07,61.83 46.25,61.83 46.38,61.71 46.38,61.45 46.25,61.33 45.07,61.33 44.79,61.04 44.79,55.73 43.99,54.93 42.36,54.93 v1(42.16,55.12)
  BOTTOM w0.102: v1(124.4,64.21) 124.4,64.49 CPU1.C50
PCH_DPC_N0_C: length 7
  TOP w0.102: 39.67,54.78 40.26,54.78 C3813.2 ; 39.67,54.78 37.5,54.78 36.98,55.3 36.98,56.55 36.18,57.35 U3801.10 ; 39.67,54.78 v2(39.67,54.91)
PCH_DPC_N1: length 166.1
  TOP w0.102: v2(42.75,58.13) 42.16,57.55 v1(42.16,57.24) 42.04,57.37 C3807.1
  L6 w0.127: v1(42.16,57.24) 42.33,57.08 43.68,57.08 44.02,57.42 44.02,63.54 42.59,64.96 42.59,76.69 42.47,76.82 40.74,76.82 40.46,77.1 40.46,77.58 40.74,77.86 42.47,77.86 42.59,77.99 42.59,78.6 43.51,79.52 43.51,87.96 46.26,90.72 46.26,93.04 49.01,95.79 51.22,95.79 53.48,98.05 55.15,98.05 56.08,97.12 56.1,97.12 56.14,97.08 70.27,97.08 71.25,98.06 75.83,98.06 76.4,97.49 100.21,97.49 100.98,96.72 104.79,96.72 105.24,96.27 121.17,96.27 127.85,89.59 127.85,89.19 127.67,89 127.67,88.83 127.85,88.65 128.03,88.65 128.21,88.83 128.61,88.83 129.37,88.07 130.33,88.07 132.78,85.62 132.78,81.39 130.85,79.46 130.85,76.84 129.84,75.84 129.84,74.03 128.95,73.14 128.95,69.2 129.45,68.71 129.45,67.82 128.4,66.77 128.4,66.74 v1(127.96,66.74)
  BOTTOM w0.089: CPU1.C52 124.82,66.03 125.03,66.03 125.16,66.09 125.36,66.09 125.45,66.05 125.72,66.05 125.81,66.09 126.71,66.09 126.79,66.16 127.29,66.16 127.88,66.74 v1(127.96,66.74)
PCH_DPC_N1_C: length 5.7
  TOP w0.102: U3801.13 36.75,58.55 38.18,57.12 38.5,57.12 ; 38.5,57.12 v2(38.5,57.24) ; 38.5,57.12 40.36,57.12 C3807.2
PCH_DPC_N2: length 166.6
  TOP w0.102: v1(42.16,59.91) 42.04,60.04 C3808.1
  L6 w0.127: v1(128.85,66.34) 129.36,66.34 129.72,66.69 129.72,66.95 130.24,67.47 130.24,69.04 129.75,69.52 129.75,72.83 130.64,73.72 130.64,75.52 131.63,76.51 131.63,79.13 131.92,79.41 132.09,79.41 132.78,78.72 133.18,78.72 133.52,79.06 133.52,79.46 132.83,80.15 132.83,80.33 133.55,81.05 133.55,85.94 130.66,88.84 129.74,88.84 121.53,97.04 105.56,97.04 105.12,97.49 101.31,97.49 100.84,97.96 100.53,98.26 76.72,98.26 76.15,98.84 70.93,98.84 69.95,97.86 56.46,97.86 55.5,98.82 53.12,98.82 52.77,98.48 49.8,98.48 47.76,96.44 47.76,95.94 44.63,92.8 44.63,91.66 42.72,89.75 42.72,82 41.14,80.43 41.14,80.03 41.54,79.63 41.54,79.45 41.36,79.27 41.18,79.27 40.78,79.67 40.38,79.67 39.69,78.97 39.69,71.64 41.82,69.51 41.82,64.62 43.24,63.2 43.24,60.02 42.96,59.74 42.33,59.74 v1(42.16,59.91)
  BOTTOM w0.102: 128.49,65.08 129.06,65.64 129.06,66.13 v1(128.85,66.34) ; 128.49,65.08 v2(128.4,65.17) ; 128.49,65.08 128.07,64.66 125.95,64.66 CPU1.A50
PCH_DPC_N2_C: length 5.1
  TOP w0.102: U3801.16 36.37,59.75 36.44,59.68 39.67,59.68 ; C3808.2 40.26,59.68 39.67,59.68 ; 39.67,59.68 v2(39.67,59.81)
PCH_DPC_N3: length 167
  TOP w0.102: C3810.1 41.65,61.69 v1(42.16,61.69) 42.72,62.24 v2(42.85,62.24)
  L6 w0.127: v1(42.16,61.69) 42.16,61.87 42.04,61.99 41.71,61.99 41.58,61.87 41.58,61.45 41.45,61.32 41.22,61.32 41.06,61.48 41.06,66.37 39.43,68 39.43,70.05 38.67,70.82 38.67,79.61 42.2,83.14 42.2,90.79 43.04,91.63 43.04,91.93 47.15,96.05 47.15,96.55 49.59,98.99 52.56,98.99 52.91,99.33 55.71,99.33 56.67,98.37 62.2,98.37 62.91,99.08 66.16,99.08 66.69,98.54 69.91,98.54 70.71,99.34 76.36,99.34 76.94,98.77 100.74,98.77 101.52,98 111.57,98 111.94,97.63 121.69,97.63 128.7,90.62 129.97,89.35 130.87,89.35 134.08,86.13 134.08,77.59 132.37,75.87 131.97,75.87 131.28,75.19 131.28,73.59 130.33,72.64 130.33,69.69 130.76,69.26 130.76,67 129.78,66.02 129.78,66.02 129.08,65.32 127.89,65.32 127.76,65.45 v1(127.76,65.7)
  BOTTOM w0.102: CPU1.D51 124.52,65.26 124.81,64.97 126.74,64.97 127.03,65.26 127.49,65.26 127.76,65.52 v1(127.76,65.7)
PCH_DPC_N3_C: length 6.3
  TOP w0.102: 39.39,62.22 39.56,62.22 40.15,61.64 40.44,61.64 C3810.2 ; 39.39,62.22 37.34,62.22 36.88,61.76 36.88,61.05 36.68,60.85 36.4,60.85 36.3,60.95 U3801.19 ; 39.39,62.22 v2(39.39,62.37)
PCH_DPC_P0: length 164.2
  TOP w0.102: v1(123.42,64.2) 123.52,64.2 v2(123.87,64.56) ; v1(42.2,54.49) 42.07,54.63 41.78,54.63 C3812.1
  L6 w0.127: v1(42.2,54.49) 42.38,54.66 44.1,54.66 45.06,55.62 45.06,60.93 45.18,61.06 46.36,61.06 46.65,61.34 46.65,61.82 46.36,62.1 45.18,62.1 45.06,62.23 45.06,64.03 43.64,65.45 43.64,77.85 44.98,79.19 44.98,82.84 44.75,83.07 44.75,87.73 47.38,90.36 47.38,92.59 49.52,94.73 54,94.73 55.21,95.94 71.08,95.94 71.73,95.29 73.86,95.29 74.29,95.72 77.39,95.72 77.84,95.28 95.89,95.28 97.01,96.4 99.78,96.4 100.79,95.38 100.95,95.23 120.74,95.23 126.34,89.63 126.34,88.61 127.94,87.01 129.89,87.01 131.72,85.18 131.72,81.83 128.79,78.89 128.79,74.48 127.96,73.65 127.96,70.81 127.43,70.27 127.43,68.88 125.51,66.96 125.51,65.94 123.77,64.2 v1(123.42,64.2)
  BOTTOM w0.102: v1(123.42,64.2) 123.47,64.2 CPU1.D50
PCH_DPC_P0_C: length 6.8
  TOP w0.102: 37.12,54.84 36.75,55.2 36.75,56.46 36.26,56.95 U3801.9 ; 37.12,54.84 v2(37.01,54.73) ; 37.12,54.84 37.4,54.55 40.49,54.55 C3812.2
PCH_DPC_P1: length 165.6
  TOP w0.102: v2(42.75,56.91) 42.47,56.91 v1(42.16,56.61) 42.04,56.48 C3814.1
  L6 w0.127: v1(128.27,67.33) 128.58,67.33 129.18,67.93 129.18,68.6 128.69,69.09 128.69,73.25 129.58,74.14 129.58,75.95 130.58,76.95 130.58,79.57 132.51,81.5 132.51,85.51 130.22,87.8 129.26,87.8 128.5,88.56 128.32,88.56 128.14,88.38 127.74,88.38 127.4,88.71 127.4,89.12 127.59,89.3 127.59,89.48 121.06,96 105.13,96 104.68,96.45 100.87,96.45 100.1,97.22 76.29,97.22 75.72,97.79 71.36,97.79 70.38,96.82 56.01,96.82 55.04,97.78 53.59,97.78 51.33,95.52 49.12,95.52 46.53,92.93 46.53,90.61 43.78,87.85 43.78,79.41 42.86,78.49 42.86,77.88 42.58,77.59 40.85,77.59 40.73,77.47 40.73,77.21 40.85,77.08 42.58,77.08 42.86,76.8 42.86,65.08 44.28,63.65 44.28,57.31 43.79,56.81 42.37,56.81 v1(42.16,56.61)
  BOTTOM w0.089: CPU1.D52 124.35,66.21 124.99,66.21 125.13,66.26 125.4,66.26 125.49,66.23 125.69,66.23 125.78,66.26 126.62,66.26 126.71,66.35 127.21,66.35 127.58,66.71 127.58,66.9 128,67.33
  BOTTOM w0.102: 128,67.33 v1(128.27,67.33)
PCH_DPC_P1_C: length 5.7
  TOP w0.102: v2(39.75,56.76) 39.75,56.89 ; 39.75,56.89 38.09,56.89 36.83,58.15 U3801.12 ; 39.75,56.89 40.22,56.89 40.61,56.49 C3814.2
PCH_DPC_P2: length 167.1
  TOP w0.102: C3809.1 42.04,59.15 v1(42.16,59.27) 42.37,59.27 v2(42.67,59.58)
  L6 w0.127: v1(42.16,59.27) 42.37,59.48 43.07,59.48 43.51,59.91 43.51,63.31 42.09,64.73 42.09,69.62 39.95,71.75 39.95,78.86 40.49,79.4 40.67,79.4 41.07,79 41.47,79 41.81,79.34 41.81,79.74 41.41,80.14 41.41,80.32 42.99,81.89 42.99,89.64 44.89,91.55 44.89,92.69 48.03,95.83 48.03,96.33 49.91,98.21 52.88,98.21 53.23,98.56 55.39,98.56 56.35,97.59 70.06,97.59 71.04,98.57 76.04,98.57 76.61,98 100.42,98 100.57,97.85 100.57,97.84 101.19,97.22 105,97.22 105.45,96.78 121.42,96.78 129.63,88.57 130.54,88.57 133.28,85.83 133.28,81.16 132.56,80.44 132.56,80.04 133.25,79.35 133.25,79.17 133.07,78.99 132.89,78.99 132.21,79.68 131.81,79.68 131.37,79.24 131.37,76.62 130.38,75.63 130.38,73.83 129.49,72.94 129.49,69.41 129.97,68.93 129.97,67.58 v1(129.26,66.87)
  BOTTOM w0.102: v1(129.26,66.87) 129.28,66.84 129.28,65.55 128.17,64.43 125.53,64.43 CPU1.B50
PCH_DPC_P2_C: length 5
  TOP w0.102: U3801.15 36.37,59.35 36.48,59.45 40.31,59.45 C3809.2
PCH_DPC_P3: length 166.7
  TOP w0.102: C3811.1 41.65,61.05 v1(42.16,61.05) ; v2(126.77,66.16) 127.13,65.8 v1(127.13,65.65)
  L6 w0.127: v1(42.16,61.05) 41.11,61.05 40.79,61.37 40.79,66.26 39.17,67.89 39.17,69.94 38.4,70.71 38.4,79.72 41.93,83.25 41.93,90.9 42.77,91.74 42.77,92.04 46.89,96.16 46.89,96.66 49.48,99.25 52.45,99.25 52.8,99.6 55.82,99.6 56.78,98.63 62.09,98.63 62.8,99.34 66.27,99.34 66.8,98.81 69.8,98.81 70.6,99.61 76.47,99.61 77.05,99.04 100.85,99.04 101.63,98.26 111.68,98.26 112.05,97.9 121.8,97.9 128.89,90.81 130.08,89.62 130.98,89.62 134.35,86.24 134.35,77.48 132.48,75.61 132.08,75.61 131.55,75.08 131.55,73.48 130.59,72.52 130.59,69.8 131.02,69.37 131.02,66.89 130.05,65.91 130.05,65.91 129.2,65.05 127.72,65.05 v1(127.13,65.65)
  BOTTOM w0.102: CPU1.C51 125,65.2 126.65,65.2 127.1,65.65 v1(127.13,65.65)
PCH_DPC_P3_C: length 6.3
  TOP w0.102: C3811.2 40.54,60.93 39.47,61.99 37.44,61.99 37.11,61.66 37.11,60.95 36.78,60.62 36.37,60.62 36.29,60.55 U3801.18
PCH_DPWROK: length 58.2
  TOP w0.127: v1(103.01,18.94) 103,18.94 102.53,19.41 101.35,19.41 99.96,20.81 v2(99.15,20.81) v1(98.73,21.23)
  BOTTOM w0.127: ED1711.1 103.31,18.94 v1(103.01,18.94) 103.01,18.85 103.35,18.51 R1718.1 102.91,17.81 101.26,17.81 R1704.2 ; CPU1.BB20 103.27,47.36 102.88,46.97 99.65,46.97 98.73,46.04 96.3,46.04 94.94,44.69 94.94,43.63 95.1,43.48 95.1,43.08 94.71,42.69 94.29,42.69 86.93,35.33 86.93,22.98 87.03,22.88 87.03,22.5 88.48,21.05 97.62,21.05 97.91,20.76 98.28,20.76 98.73,21.21 v1(98.73,21.23)
PCH_ESPI_CLK: length 23.1
  TOP w0.089: R1806.1 89.03,30.67 v2(89.03,31.75) 89.03,33.62 89.45,34.99 89.91,35.45 90.46,35.66 v1(91.01,35.75)
  BOTTOM w0.089: v1(91.01,35.75) 91.56,35.75 96.23,40.43 100.46,40.43 101.24,41.22 101.85,41.22 102.32,41.68 102.44,41.73 103.41,41.73 103.52,41.7 103.71,41.7 103.8,41.73 104.15,41.73 104.19,41.7 104.6,41.7 105,41.29 CPU1.AW9
PCH_ESPI_IO0: length 13
  TOP w0.089: v1(96.49,42.89) 96.45,42.85 v2(93.73,42.85) RN1806.1
  BOTTOM w0.089: CPU1.AY13 104.08,43.47 103.22,43.2 101.83,43.2 101.12,42.89 v1(96.49,42.89)
PCH_ESPI_IO1: length 13.4
  TOP w0.089: RN1806.2 91.31,43.24 91.32,43.26 91.34,43.28 91.35,43.28 v2(92.51,43.53) 94.57,43.88 v1(95.78,44.03)
  BOTTOM w0.089: v1(95.78,44.03) 100.3,43.11 101.18,43.11 101.68,43.37 102.77,43.37 103.44,43.46 CPU1.BA13
PCH_ESPI_IO2: length 13.4
  TOP w0.089: v1(96.26,44.47) 95.73,44.42 94.77,44.27 v2(94.76,44.26) 94.76,44.26 92.71,43.95 91.23,43.55 90.84,43.27 90.82,43.26 RN1806.3
  BOTTOM w0.089: CPU1.BB13 101.67,43.55 101.64,43.55 101.13,43.29 100.38,43.29 v1(96.26,44.47)
PCH_ESPI_IO3: length 16.6
  TOP w0.089: RN1806.4 90.31,43.26 90.32,43.27 91.1,43.78 91.26,43.85 v2(93.57,44.52) v1(96.52,45.08)
  BOTTOM w0.089: v1(96.52,45.08) 97.73,44.63 100.51,43.47 101.09,43.47 101.6,43.73 103.17,43.98 103.39,43.98 103.48,43.94 103.72,43.94 103.86,43.98 104.74,43.98 104.91,43.8 CPU1.AY12
PCH_JTAG_TCK: length 8.5
  TOP w0.114: v1(128.19,69.27) 128.13,69.27 128.09,69.31 127.68,69.31 126.77,68.39 125.65,68.39 v2(125.29,68.76) 124.59,69.46 R407.1
  BOTTOM w0.089: v1(128.19,69.27) 127.9,69.27 127.51,68.88 127.19,68.88 126.72,68.41 126.22,68.41 126.07,68.56 125.81,68.56 125.72,68.53 125.65,68.53 CPU1.B56
PCH_JTAG_TDI: length 9.3
  BOTTOM w0.089: v2(128.17,70.03) 128,70.03 127.25,69.28 126.8,69.28 126.71,69.37 126.32,69.37 126.23,69.27 126.13,69.24 126.09,69.22 125.74,69.22 125.68,69.24 125.44,69.24 125.32,69.36 124.26,69.36 CPU1.D59
  BOTTOM w0.114: R408.1 130.55,67.1 130.15,67.5 130.15,68.13 130.03,68.25 130.03,68.82 128.82,70.03 v2(128.17,70.03)
PCH_JTAG_TDO: length 7.6
  BOTTOM w0.089: CPU1.A56 126.05,68.3 126.12,68.23 126.8,68.23 127.26,68.7 127.68,68.7 127.84,68.86 128.92,68.86 129.79,67.99
  BOTTOM w0.114: R409.1 131.02,66.29 130.74,66.01 130.33,66.01 v2(130.12,66.21) 130.12,67.16 129.9,67.38 129.9,67.88 129.79,67.99
PCH_JTAG_TMS: length 8.5
  BOTTOM w0.089: 127.43,70.25 126.8,70.25 126.46,69.92 125.09,69.92 124.83,69.66 CPU1.C59
  BOTTOM w0.114: 127.43,70.25 127.48,70.25 128.31,71.07 129.83,71.07 130.2,70.7 v2(130.2,69.89) 130.71,69.38 R416.1
PCH_PLTRST#: length 27.2
  TOP w0.127: v1(108.18,24.69) 107.65,24.69 v2(107.5,24.54)
  L4 w0.127: v1(108.18,24.69) 108.04,24.83 108.04,26.76 109.14,27.86 109.14,30.47 110.06,31.39 110.06,33.93 109.77,34.22 109.77,35.27 110.03,35.53 110.03,38.04 110.52,38.53 110.52,40.44 110.2,40.76 109.91,40.76 v1(109.33,41.34)
  BOTTOM w0.127: R1713.2 113.13,23.44 112.29,22.6 110.69,22.6 110.3,22.99 110.3,23.15 109.99,23.46 109.99,24.29 109.73,24.55 109.26,24.55 108.99,24.29 108.58,24.29 v1(108.18,24.69) ; v1(109.33,41.34) 109,41.67 CPU1.AN10
PCH_POPIRCOMP: length 17
  TOP w0.203: v1(106.73,45.92) 106.28,46.36 105.27,46.36 105.07,46.16 104.11,46.16
  TOP w0.508: 104.11,46.16 102.5,47.77 98.04,47.77 97.25,48.56 v2(97.25,49.83) 97.25,50.69 94.83,53.12 94.83,53.18 R413.1
  BOTTOM w0.305: CPU1.AU16 106.73,45.78 v1(106.73,45.92)
PCH_RSMRST#: length 105.7
  TOP w0.089: v1(196.72,43.04) 196.92,42.84 196.92,42.24 197.82,41.34 197.82,40.87 198.05,40.64 KBC24.27
  TOP w0.127: v2(148.51,20.84) v1(148.51,20.26) 148.51,20.21 149.07,19.65 149.71,19.65 EC1712.1 149.96,19.04 R1702.2
  L3 w0.127: v1(148.51,20.26) 148.96,19.82 150.99,19.82 151.92,18.89 154.79,18.89 v1(155.29,18.38)
  L4 w0.127: v1(154.13,7.51) 154.15,7.48 154.15,7.37 155.19,6.33 156.41,6.33 158.22,8.14 168.73,8.14 170.44,9.86 190.91,9.86 194.95,13.9 194.95,32.15 193.47,33.64 193.47,36.11 195.09,37.74 196.16,37.74 197.5,39.08 197.5,41.64 196.91,42.23 196.91,42.85 v1(196.72,43.04)
  BOTTOM w0.127: v1(155.29,18.38) 155.66,18.01 155.66,14.02 153.35,11.71 153.35,9.87 152.92,9.44 152.92,8.53 153.31,8.13 153.78,8.13 154.13,7.79 v1(154.13,7.51) ; TP2406.1 196.9,43.6 196.72,43.43 v1(196.72,43.04)
PCH_SMBCLK: length 78.8
  TOP w0.089: RN1810.4 103.47,16.05 103.52,16.03 v1(104.09,15.46) ; v1(61.31,10.05) v2(61.31,10.61)
  L3 w0.127: v1(61.31,10.05) 62.41,8.96 86.05,8.96 86.26,8.75 94.81,8.75 95.3,9.24 95.3,10.61 99.36,14.67 103.3,14.67 v1(104.09,15.46)
  L4 w0.127: v1(61.31,10.05) 61.31,10.17 60.55,10.94 60.55,16.06 60.79,16.3 61.06,16.57 61.06,19.29 61.8,20.02 61.8,21.38 v1(61.67,21.51)
  BOTTOM w0.089: v1(104.09,15.46) 102.88,16.67 Q1801.4 ; DM2.253 60.82,22.68 61.24,22.27 61.24,21.94 v1(61.67,21.51) 62.93,20.24 66.58,20.24 68.82,22.48 DM1.253
PCH_SMBDATA: length 76.6
  TOP w0.089: v1(54.84,21.71) 55.4,21.15 57.21,21.15 57.74,20.62 58.51,20.62 59.13,20.01 61.11,20.01 v2(61.84,20.74) 62.41,21.3 v1(62.41,21.48) ; v1(103.45,15.46) 103.37,15.38 RN1810.3
  L3 w0.127: v1(103.45,15.46) 103.07,15.08 99.19,15.08 94.72,10.61 73.72,10.61 73.26,10.16 73.26,9.76 72.87,9.36 62.7,9.36 v1(61.97,10.09)
  L4 w0.127: v1(61.97,10.09) 60.96,11.1 60.96,15.89 61.47,16.4 61.47,19.12 62.2,19.85 62.2,21.28 v1(62.41,21.48)
  BOTTOM w0.089: v1(62.41,21.48) 62.41,21.84 62.81,22.23 DM1.254 ; v1(103.45,15.46) 103.45,15.26 103.07,14.88 101.25,14.88 Q1801.1 ; v1(54.84,21.71) 54.84,21.96 54.36,22.44 DM2.254
PCH_SPI_CS2#: length 5
  BOTTOM w0.089: CPU1.AU1 106.63,36.26 106.63,34.77 106.35,34.5 106.35,33.63 107.12,32.86 107.47,32.86 R1826.2
PCH_THERMTRIP#: length 10.8
  BOTTOM w0.089: CPU1.C63 124.85,72.13 125.32,72.61 126.9,72.61 128.06,73.77
  BOTTOM w0.102: R419.2 133.01,75.23 132.4,74.62 131.2,74.62 ED401.1 129.87,75.15 129.54,75.48 v2(129.16,75.48) 129.06,75.38 129.06,74.76 128.06,73.77
PCH_WAKE#: length 43.1
  TOP w0.102: v2(100.05,44.18) 100.54,44.67 v1(100.58,44.67)
  L4 w0.102: v1(100.58,44.67) 100.72,44.81 101.63,44.81 101.86,44.58 101.86,44.25 100.94,43.32 100.94,42.76 99.24,41.06 99.24,39.23 94.97,34.97 94.97,24.02 97.08,21.91 99.02,21.91 100.52,20.41 105.36,20.41 106.01,21.06 v1(106.01,21.37)
  BOTTOM w0.102: CPU1.BB15 103.15,44.81 101.98,44.81 101.79,45 100.91,45 v1(100.58,44.67) ; v1(106.01,21.37) 106.01,20.78 106.17,20.62 RN1704.7
PCIE_CLK_XDP_N: length 1.1
  TOP w0.102: TP1802.1 121.84,61.04 v1(122.23,61.43)
  BOTTOM w0.102: v1(122.23,61.43) 122.54,61.11 CPU1.F43
PCIE_CLK_XDP_P: length 1.2
  TOP w0.102: TP1803.1 123.29,61.04 v1(122.86,61.47)
  BOTTOM w0.102: CPU1.E43 123.19,61.14 v1(122.86,61.47)
PCIE_RCOMPN: length 1.3
  TOP w0.305: R1604.1 122.17,39.47 v1(122.22,39.51)
  BOTTOM w0.305: v1(122.22,39.51) 122.22,39.38 CPU1.F5
PCIE_RCOMPP: length 2.1
  TOP w0.305: R1604.2 123.04,39.34 v1(122.87,39.51) 123.16,39.51 v2(123.44,39.79)
  BOTTOM w0.305: v1(122.87,39.51) 123.19,39.19 CPU1.E5
PCIE_RX_CPU_N6: length 129.5
  TOP w0.102: v2(170.48,55.13) v1(169.92,55.13)
  L3 w0.089: 121.2,46.2 121.24,46.25 122.12,46.25 122.25,46.12 122.25,45.89 v1(122.22,45.86)
  L3 w0.14: 121.2,46.2 120.46,45.47 120.46,39.1 121.91,37.66 122.26,37.66 123.99,35.92 123.99,35.36 123.98,35.34 123.98,26.86 124.79,26.04 124.79,23.77 127.15,21.42 129.5,21.42 134.02,16.9 149.77,16.9 150.23,16.43 162.79,16.43 172.72,26.36 172.72,31 173.4,31.69 173.4,33.49 174.72,34.81 174.72,59.07 175.25,59.59 175.8,59.59 v1(176.2,59.99)
  L6 w0.127: v1(176.2,59.99) 175.92,59.71 174.55,59.71 172.13,57.29 169.62,57.29 169.09,56.76 169.09,55.72 169.46,55.35 169.71,55.35 v1(169.92,55.13)
  BOTTOM w0.102: v1(122.22,45.86) 122.22,46.17 122.02,46.37 CPU1.G18 ; v1(169.92,55.13) 169.85,55.21 IOBD1.8
PCIE_RX_CPU_N9: length 135.4
  TOP w0.102: 190.7,7.74 178.6,7.74 178.15,8.19 178.15,8.45 178.54,8.83 v1(178.71,8.83) ; 190.7,7.74 v2(190.7,7.87) ; 190.7,7.74 195.12,7.74 197.05,9.67 197.05,12 197.9,12.84 198.21,12.84 198.71,12.84 199.32,13.46 199.32,13.66 199.2,13.79 U6303.9 U6303.2 199.2,15.85 199.9,16.55 199.9,19.89 199.03,20.75 199.03,22.45 198.52,22.95 198.25,22.95 v1(198.05,22.75)
  L6 w0.127: v1(178.71,8.83) 178.71,9.16 178.51,9.36 177.77,9.36 177.25,9.88 173.23,9.88 172.85,10.27 164.88,10.27 162.97,12.17 150.65,12.17 149.48,13.34 148.16,13.34 147.38,14.11 144.14,14.11 143.24,15.02 140.67,15.02 139.89,15.8 137.59,18.09 134.98,18.09 131.14,21.93 131.14,26.81 132.04,27.72 132.04,30.56 129.89,32.7 129.89,43.22 127.63,45.48 125.98,45.48 125.22,46.24 125.22,48.45 124.29,49.38 123.7,49.38 v1(123.52,49.57)
  BOTTOM w0.102: SSD1.7 195.83,29.94 196.44,29.33 198.3,29.33 198.75,28.88 198.75,26.56 197.33,25.14 197.33,23.47 197.56,23.24 197.56,22.95 197.76,22.75 v1(198.05,22.75) ; v1(123.52,49.57) 123.42,49.57 123.19,49.34 CPU1.E22
PCIE_RX_CPU_N10: length 126.3
  TOP w0.102: v1(197.97,18.76) 198.15,18.94 198.3,18.94 198.47,18.77 198.47,17.6 196.9,16.03 196.9,13.93 194.74,11.77 194.74,11.4 194.51,11.17 194.37,11.17 194.23,11.31 U6304.2 U6304.9 192.49,11.31 191.49,10.3 187.08,10.3 185.22,8.45 182.11,8.45 181.35,9.21 ; 181.35,9.21 180.97,9.59 180.48,9.59 180.22,9.33 180.22,9.01 v1(180.01,8.81) ; 181.35,9.21 v2(181.44,9.3)
  L6 w0.127: v1(180.01,8.81) 180.2,8.99 180.2,9.7 179.5,10.39 173.44,10.39 173.06,10.77 165.09,10.77 163.18,12.68 150.86,12.68 149.69,13.85 148.37,13.85 147.6,14.62 144.35,14.62 143.45,15.52 140.88,15.52 140.66,15.74 140.01,16.4 138.85,17.55 137.58,18.82 137.57,18.83 132.38,24.02 132.38,27.32 132.55,27.49 132.55,30.77 130.4,32.91 130.4,43.43 127.97,45.86 126.38,45.86 125.44,46.8 125.44,49.97 124.81,50.59 123.44,50.59 123.09,50.94 123.01,51.02 123.01,51.18 v1(122.82,51.38)
  BOTTOM w0.102: v1(122.82,51.38) 122.54,51.1 CPU1.F25 ; SSD1.19 195.54,26.94 195.68,27.08 195.79,27.08 195.91,26.96 195.91,19.3 196.25,18.97 197.74,18.97 197.94,18.76 v1(197.97,18.76)
PCIE_RX_CPU_N11: length 124.5
  TOP w0.102: v1(193.03,24.48) 193.21,24.3 194.44,24.3 196.65,22.09 196.65,20.21 196.77,20.09 U6302.1 U6302.10 196.77,18.17 196.65,18.05 196.65,17.5 195.1,15.96 194.47,15.96 190.65,12.13 187.88,12.13 ; 187.88,12.13 186.69,12.13 185.98,11.42 184.28,11.42 181.33,14.37 181.33,17.08 181.74,17.49 v1(182.81,17.49) ; 187.88,12.13 v2(187.88,12.01)
  L6 w0.127: v1(123.45,52.3) 123.62,52.12 123.94,52.12 124.3,52.48 129.57,52.48 131.51,50.55 131.51,48.18 132.15,47.54 134.59,47.54 135.76,46.37 135.76,45.36 136.12,45 136.12,42.62 138.8,39.94 138.8,39.5 139.55,38.75 139.55,32.76 138.71,31.92 138.71,30.6 137.49,29.38 137.49,27.64 143,22.13 153.21,22.13 154.93,20.41 156.67,20.41 157.92,21.67 171.03,21.67 173.07,19.64 174.92,19.64 175.95,20.67 177.46,20.67 180.52,17.61 181.57,17.61 181.81,17.36 182.68,17.36 v1(182.81,17.49)
  BOTTOM w0.102: v1(193.03,24.48) 193.2,24.3 194,24.3 194.14,24.44 SSD1.29 ; v1(123.45,52.3) 123.19,52.55 CPU1.E28
PCIE_RX_CPU_P6: length 129.9
  TOP w0.102: v2(170.51,56.35) v1(169.92,55.77)
  L3 w0.089: 121.01,46.39 121.06,46.44 122.19,46.44 122.72,45.91 v1(122.88,45.91)
  L3 w0.14: 121.01,46.39 120.2,45.58 120.2,38.99 121.8,37.39 122.15,37.39 123.73,35.81 123.73,35.47 123.71,35.45 123.71,26.75 124.53,25.93 124.53,23.66 127.04,21.15 129.39,21.15 133.91,16.63 149.66,16.63 150.12,16.16 162.9,16.16 172.98,26.25 172.98,30.89 173.67,31.57 173.67,33.38 174.99,34.7 174.99,58.96 175.36,59.33 v1(176.2,59.33)
  L6 w0.127: v1(176.2,59.33) 176.08,59.44 174.66,59.44 172.24,57.03 169.73,57.03 169.35,56.65 169.35,55.83 169.57,55.61 169.77,55.61 v1(169.92,55.77)
  BOTTOM w0.102: CPU1.F18 122.54,46.26 v1(122.88,45.91) ; v1(169.92,55.77) 169.86,55.71 IOBD1.7
PCIE_RX_CPU_P9: length 135.5
  TOP w0.102: 188.34,7.51 195.22,7.51 197.28,9.57 197.28,11.9 197.99,12.62 198.8,12.62 199.55,13.37 199.55,13.66 199.68,13.79 U6303.10 U6303.1 199.68,16 200.12,16.45 200.12,19.98 199.26,20.84 199.26,22.54 198.62,23.18 198.25,23.18 v1(198.05,23.38) ; 188.34,7.51 178.51,7.51 177.93,8.09 v1(177.93,8.83) ; 188.34,7.51 v2(188.34,7.38)
  L6 w0.127: v1(122.87,49.57) 123.32,49.12 124.18,49.12 124.95,48.34 124.95,46.13 125.87,45.22 127.52,45.22 129.63,43.11 129.63,32.59 131.77,30.45 131.77,27.83 130.87,26.92 130.87,21.82 134.87,17.82 137.48,17.82 139.7,15.61 140.56,14.75 143.13,14.75 144.03,13.85 147.27,13.85 148.05,13.07 149.37,13.07 150.54,11.9 162.86,11.9 164.77,10 172.74,10 173.12,9.62 177.14,9.62 v1(177.93,8.83)
  BOTTOM w0.102: v1(122.87,49.57) 123.19,49.9 CPU1.E23 ; v1(198.05,23.38) 197.73,23.38 197.56,23.56 197.56,25.04 198.98,26.47 198.98,28.97 198.4,29.56 196.54,29.56 195.65,30.44 SSD1.5
PCIE_RX_CPU_P10: length 126.5
  TOP w0.102: v1(180.65,8.81) 180.44,9.01 180.44,9.24 180.57,9.36 180.87,9.36 181.19,9.05 182.01,8.22 185.32,8.22 186.49,9.39 ; 186.49,9.39 v2(186.57,9.3) ; 186.49,9.39 187.17,10.08 191.58,10.08 192.34,10.83 U6304.10 193.33,10.83 193.33,10.83 U6304.1 194.23,10.83 194.34,10.94 194.61,10.94 194.97,11.3 194.97,11.68 197.13,13.83 197.13,15.93 198.7,17.51 198.7,18.86 198.4,19.17 198.2,19.17 v1(197.97,19.4)
  L6 w0.127: v1(180.65,8.81) 180.46,8.99 180.46,9.81 179.61,10.66 173.55,10.66 173.17,11.04 165.2,11.04 163.29,12.95 150.97,12.95 149.8,14.11 148.48,14.11 147.71,14.89 144.46,14.89 143.56,15.79 140.99,15.79 140.85,15.93 140.12,16.66 140.12,16.66 139.04,17.74 137.69,19.08 137.69,19.08 132.65,24.13 132.65,27.21 132.81,27.38 132.81,30.88 130.67,33.02 130.67,43.54 128.08,46.13 126.49,46.13 125.7,46.91 125.7,50.08 124.92,50.85 123.55,50.85 123.47,50.94 v1(123.47,51.38)
  BOTTOM w0.102: v1(197.97,19.4) 197.77,19.19 196.34,19.19 196.14,19.4 196.14,27.05 195.88,27.3 195.7,27.3 195.56,27.44 SSD1.17 ; v1(123.47,51.38) 123.47,51.22 CPU1.E25
PCIE_RX_CPU_P11: length 124.4
  TOP w0.102: 195.83,17.01 v2(195.73,17.11) ; 195.83,17.01 196.42,17.59 196.42,18.08 196.29,18.2 U6302.9 U6302.2 196.29,20.08 196.42,20.21 196.42,21.99 194.34,24.07 193.25,24.07 v1(193.03,23.85) ; 195.83,17.01 195.01,16.18 194.38,16.18 190.56,12.36 186.59,12.36 185.88,11.65 184.38,11.65 181.56,14.47 181.56,16.98 181.84,17.26 182.32,17.26 182.47,17.11 182.47,16.96 182.57,16.86 v1(182.81,16.86)
  L6 w0.127: v1(182.81,16.86) 182.57,17.1 181.7,17.1 181.46,17.34 180.41,17.34 177.35,20.4 176.06,20.4 175.03,19.37 172.95,19.37 170.92,21.4 158.03,21.4 156.78,20.15 154.82,20.15 153.1,21.86 142.89,21.86 137.22,27.53 137.22,29.49 138.44,30.71 138.44,32.03 139.28,32.87 139.28,38.64 138.53,39.39 138.53,39.83 135.85,42.51 135.85,44.89 135.49,45.25 135.49,46.26 134.48,47.27 132.04,47.27 131.24,48.07 131.24,50.44 129.46,52.21 124.41,52.21 124.05,51.86 123.01,51.86 122.81,52.06 v1(122.81,52.32)
  BOTTOM w0.102: v1(122.81,52.32) 122.81,52.06 123.01,51.86 CPU1.E27 ; SSD1.31 194.16,23.94 194.02,24.08 193.25,24.08 v1(193.03,23.85)
PCIE_TX_CPU_N6: length 9.3
  BOTTOM w0.102: CPU1.D20 124.53,47.92 124.82,48.21 125.14,48.21 125.39,47.95 126.79,47.95 127.5,47.24 131.9,47.24 ; C1601.2 132.59,47.24 131.9,47.24 ; v2(131.9,47.39) 131.9,47.24
PCIE_TX_CPU_N9: length 104.3
  TOP w0.102: C6314.2 196.06,10.08 196.06,9.47 195.37,8.78 193.9,8.78 v1(193.47,8.35) ; v1(129.14,48.45) v2(129.72,48.45)
  L6 w0.127: v1(193.47,8.35) 193.23,8.59 193.23,9.47 192.69,10.01 185.33,10.01 183.04,12.3 179.23,12.3 178.84,12.69 174.71,12.69 174.35,13.05 171.79,13.05 170.48,14.36 167.09,14.36 166.54,14.9 156.11,14.9 155.7,14.49 152.5,14.49 150.06,16.93 148.49,16.93 148.08,17.34 147.16,17.34 146.43,18.06 140.91,18.06 140.21,18.76 139.36,19.61 137.57,21.4 136.26,22.71 136.26,23.29 134.77,24.78 134.77,28.26 135.15,28.64 135.15,31.79 132.64,34.3 132.64,39.92 133.5,40.79 133.5,44.19 133.01,44.68 131.72,44.68 129.13,47.27 129.13,48.45 v1(129.14,48.45)
  BOTTOM w0.102: CPU1.B23 125.55,50.12 128.08,50.12 128.21,49.99 128.63,49.99 129.14,49.48 v1(129.14,48.45)
PCIE_TX_CPU_N9_C: length 22.3
  TOP w0.102: 199.41,18.25 199.41,17.19 198.16,15.94 U6303.4 U6303.7 198.16,13.79 196.26,11.89 C6314.1 ; 199.41,18.25 v2(199.54,18.25) ; 199.41,18.25 199.41,19.16 198.68,19.9 198.68,20.38 198.42,20.63 198.42,20.95 v1(197.99,21.38)
  BOTTOM w0.102: v1(197.99,21.38) 197.07,21.38 197.04,21.41 196.85,21.6 196.85,28.13 196.17,28.8 195.88,28.8 195.75,28.94 SSD1.11
PCIE_TX_CPU_N10: length 96.7
  TOP w0.102: v1(182.32,10.3) 182.32,9.27 182.66,8.93 184.93,8.93 186.86,10.87 ; 186.86,10.87 187.06,11.07 188.85,11.07 C6316.2 ; 186.86,10.87 v2(186.95,10.78)
  L6 w0.127: v1(182.32,10.3) 182.32,10.41 181.56,11.17 173.76,11.17 172.93,12 171.36,12 170.05,13.31 166.66,13.31 166.11,13.86 156.54,13.86 156.13,13.45 151.18,13.45 150.53,14.1 150.53,14.92 149.56,15.89 148.05,15.89 147.65,16.3 146.73,16.3 146,17.02 140.48,17.02 140.33,17.17 139.4,18.1 138.05,19.44 134.86,22.64 133.16,24.34 133.16,27 133.72,27.56 133.72,30.71 131.19,33.24 131.19,37.99 131.6,38.4 131.6,39.44 131.18,39.86 131.18,43.75 128.32,46.61 127.64,46.61 126.74,47.51 v1(126.74,48.86)
  BOTTOM w0.089: 126.41,49.45 126.31,49.45 126.26,49.39 125.78,49.39 125.69,49.43 125.49,49.43 125.4,49.39 125.13,49.39 124.99,49.44 124.35,49.44 CPU1.D23
  BOTTOM w0.102: 126.41,49.45 126.6,49.45 126.74,49.3 v1(126.74,48.86)
PCIE_TX_CPU_N10_C: length 24.5
  TOP w0.102: v1(193.01,25.77) 193.21,25.57 194.17,25.57 194.38,25.36 ; v2(194.49,25.47) 194.38,25.36 ; 194.38,25.36 197.48,22.26 197.48,17.3 196.42,16.23 196.42,14.13 194.78,12.49 194.31,12.49 194.17,12.35 U6304.4 U6304.7 191.88,12.35 190.64,11.12 190.27,11.12 C6316.1
  BOTTOM w0.102: v1(193.01,25.77) 193.2,25.58 193.79,25.58 194.15,25.94 SSD1.23
PCIE_TX_CPU_N11: length 94
  TOP w0.102: C6312.2 184.94,12.74 183.97,12.74 182.14,14.57 182.14,14.9 ; 182.14,14.9 v2(181.99,14.9) ; 182.14,14.9 v1(182.14,15.92)
  L6 w0.127: v1(126.54,50.84) 127.01,51.31 127.01,51.31 127.32,51.62 128.88,51.62 129.8,50.7 129.8,50.07 130.69,49.18 130.69,47.9 131.89,46.7 134.21,46.7 134.8,46.12 134.8,45.22 135.14,44.88 135.14,42.5 138.02,39.62 138.02,32.33 137.55,31.85 137.55,30.88 136.7,30.04 136.7,26.01 137.87,24.85 138.77,24.85 140.89,22.72 140.89,20.41 141.36,19.94 143.32,19.94 143.6,20.22 146.47,20.22 147.8,18.89 150.37,18.89 152.21,17.05 166.59,17.05 167.73,15.9 171.12,15.9 172.43,14.6 174.23,14.6 175.04,15.41 180.9,15.41 181.21,15.72 181.95,15.72 v1(182.14,15.92)
  BOTTOM w0.102: v1(126.54,50.84) 126.32,50.62 125.12,50.62 125.06,50.69 124.82,50.69 124.81,50.67 124.61,50.56 124.32,50.39 CPU1.D24
PCIE_TX_CPU_N11_C: length 19.9
  TOP w0.102: C6312.1 186.31,12.84 190.36,12.84 194.34,16.83 ; 194.34,16.83 195.15,17.63 195.15,18.08 195.25,18.18 U6302.7 U6302.4 195.25,20.21 195.12,20.34 195.12,21.57 193.92,22.78 193.33,22.78 v1(193.1,23.01) ; 194.34,16.83 v2(194.43,16.74)
  BOTTOM w0.102: SSD1.35 194.14,22.94 194.01,22.8 193.3,22.8 v1(193.1,23.01)
PCIE_TX_CPU_P6: length 8.5
  BOTTOM w0.102: 129.87,47.01 132.5,47.01 C1602.2 ; 129.87,47.01 127.41,47.01 126.7,47.72 125.3,47.72 125.1,47.92 CPU1.C20 ; 129.87,47.01 v2(129.87,46.88)
PCIE_TX_CPU_P9: length 104.4
  TOP w0.102: v1(192.71,8.35) 192.71,8.58 192.91,8.78 193.58,8.78 193.81,9.01 195.27,9.01 195.83,9.57 195.83,9.95 C6313.2 ; v2(127.96,48.28) 128.14,48.45 v1(128.5,48.45)
  L6 w0.127: v1(128.5,48.45) 128.87,48.09 128.87,47.16 131.61,44.42 132.9,44.42 133.23,44.08 133.23,40.9 132.37,40.03 132.37,34.19 134.88,31.68 134.88,28.75 134.5,28.37 134.5,24.67 135.99,23.18 135.99,22.6 137.38,21.21 139.17,19.42 140.03,18.57 140.8,17.8 146.32,17.8 147.05,17.07 147.97,17.07 148.38,16.67 149.95,16.67 152.39,14.23 155.81,14.23 156.22,14.63 166.43,14.63 166.98,14.09 170.37,14.09 171.68,12.78 174.24,12.78 174.6,12.42 178.73,12.42 179.12,12.03 182.93,12.03 185.22,9.74 192.58,9.74 192.96,9.36 192.96,8.6 v1(192.71,8.35)
  BOTTOM w0.102: v1(128.5,48.45) 128.45,48.51 128.45,48.73 128.57,48.86 128.83,48.86 128.91,48.94 128.91,49.39 128.53,49.76 128.11,49.76 127.98,49.89 125.97,49.89 CPU1.A23
PCIE_TX_CPU_P9_C: length 22.3
  TOP w0.102: C6313.1 196.04,11.73 196.04,11.99 196.46,12.42 ; v2(196.37,12.51) 196.46,12.42 ; 196.46,12.42 197.68,13.63 U6303.6 U6303.5 197.68,15.78 199.19,17.29 199.19,19.07 198.45,19.8 198.45,20.29 v1(197.99,20.74)
  BOTTOM w0.102: v1(197.99,20.74) 197.82,20.57 197.56,20.57 197.43,20.69 197.43,20.95 197.23,21.15 196.98,21.15 196.62,21.51 196.62,28.03 196.08,28.58 195.88,28.58 195.75,28.44 SSD1.13
PCIE_TX_CPU_P10: length 97.4
  TOP w0.102: 183.69,9.16 182.75,9.16 182.55,9.36 182.55,9.92 182.93,10.3 v1(183.06,10.3) ; 183.69,9.16 184.83,9.16 186.97,11.29 188.88,11.29 189.08,11.5 C6315.2 ; 183.69,9.16 v2(183.69,9.29)
  L6 w0.127: v1(183.06,10.3) 183.11,10.35 183.11,10.68 182.89,10.9 182.2,10.9 181.67,11.43 173.87,11.43 173.04,12.27 171.47,12.27 170.16,13.58 166.77,13.58 166.22,14.13 156.43,14.13 156.02,13.72 151.29,13.72 150.8,14.21 150.8,15.03 149.67,16.16 148.17,16.16 147.76,16.56 146.84,16.56 146.11,17.29 140.59,17.29 140.44,17.44 139.59,18.29 138.24,19.63 135.05,22.83 133.42,24.45 133.42,26.89 133.98,27.45 133.98,30.82 131.46,33.35 131.46,37.88 131.86,38.29 131.86,39.55 131.44,39.97 131.44,43.86 128.43,46.88 127.75,46.88 127.01,47.62 127.01,48.49 v1(127.38,48.86)
  BOTTOM w0.089: CPU1.C23 124.97,49.62 125.03,49.62 125.16,49.57 125.36,49.57 125.45,49.61 125.72,49.61 125.81,49.57 126.18,49.57 126.29,49.67
  BOTTOM w0.102: 126.29,49.67 126.69,49.67 127.05,49.32 127.05,49.17 127.35,48.86 v1(127.38,48.86)
PCIE_TX_CPU_P10_C: length 23.7
  TOP w0.102: 195.57,13.61 194.68,12.72 194.31,12.72 194.2,12.83 U6304.5 U6304.6 192.03,12.83 190.55,11.35 190.32,11.35 C6315.1 ; 195.57,13.61 196.19,14.22 196.19,16.32 197.25,17.39 197.25,22.17 194.24,25.18 194.22,25.2 194.08,25.34 193.21,25.34 v1(193.01,25.14) ; 195.57,13.61 v2(195.48,13.71)
  BOTTOM w0.102: v1(193.01,25.14) 193.23,25.35 193.88,25.35 193.97,25.44 SSD1.25
PCIE_TX_CPU_P11: length 94.6
  TOP w0.102: 184.28,12.97 184.06,12.97 182.37,14.66 182.37,15.16 182.52,15.31 182.7,15.31 182.85,15.46 182.85,15.84 v1(182.78,15.92) ; 184.28,12.97 184.86,12.97 185.11,13.22 C6311.2 ; 184.28,12.97 v2(184.28,13.1)
  L6 w0.127: v1(182.78,15.92) 182.78,15.71 182.52,15.45 181.32,15.45 181.01,15.14 175.15,15.14 174.34,14.33 172.32,14.33 171.01,15.64 167.62,15.64 166.48,16.78 152.1,16.78 152.02,16.86 152.02,16.86 150.26,18.62 147.69,18.62 146.36,19.96 143.71,19.96 143.43,19.68 141.25,19.68 140.63,20.3 140.63,22.61 138.66,24.58 137.76,24.58 136.43,25.9 136.43,30.15 137.28,30.99 137.28,31.96 137.76,32.44 137.76,39.5 134.87,42.39 134.87,44.77 134.53,45.11 134.53,46.01 134.1,46.44 131.78,46.44 130.43,47.79 130.43,49.07 129.53,49.96 129.53,50.59 128.77,51.35 127.43,51.35 127.19,51.11 v1(127.19,50.86)
  BOTTOM w0.102: CPU1.C24 126.98,50.39 127.19,50.6 v1(127.19,50.86)
PCIE_TX_CPU_P11_C: length 19.1
  TOP w0.102: 186.84,13.07 186.41,13.07 C6311.1 ; 186.84,13.07 v2(186.84,13.2) ; 186.84,13.07 190.26,13.07 194.92,17.73 194.92,18.08 194.77,18.23 U6302.6 U6302.5 194.77,20.21 194.89,20.34 194.89,21.48 193.83,22.55 193.27,22.55 v1(193.1,22.37)
  BOTTOM w0.102: SSD1.37 194.14,22.44 194,22.58 193.3,22.58 v1(193.1,22.37)
PCIE_TX_WLAN_N6: length 67.8
  L3 w0.14: v1(137.06,47.34) 138.12,47.34 138.49,46.97 138.49,46.59 139.25,45.82 139.25,42.62 140.84,41.03 140.84,37.33 141.98,36.19 141.98,32.8 142.59,32.2 146.04,32.2 146.82,32.98 146.82,33.02 147.78,33.98 152.53,33.98 153.35,34.79 154.34,34.79 157.53,37.98 157.53,40.35 160.7,43.53 164.26,43.53 165.11,44.37 165.11,55.8 165.52,56.21 166.15,56.21 v1(166.27,56.33)
  BOTTOM w0.102: v1(166.27,56.33) 167.43,56.33 167.95,55.81 167.95,54.51 168.25,54.21 IOBD1.10 ; v2(134.54,47.39) 134.54,47.24 ; 134.54,47.24 135.22,47.24 135.33,47.13 136.85,47.13 v1(137.06,47.34) ; 134.54,47.24 133.96,47.24 C1601.1
PCIE_TX_WLAN_P6: length 68.4
  L3 w0.14: v1(166.29,55.64) 165.99,55.95 165.63,55.95 165.38,55.69 165.38,44.26 164.37,43.26 160.81,43.26 157.8,40.24 157.8,37.87 154.45,34.53 153.46,34.53 152.64,33.71 147.89,33.71 147.09,32.91 147.09,32.87 146.15,31.93 142.48,31.93 141.72,32.69 141.72,36.08 140.57,37.22 140.57,40.92 138.99,42.51 138.99,45.71 138.22,46.48 138.22,46.86 138.01,47.07 137.45,47.07 v1(137.08,46.7)
  BOTTOM w0.102: C1602.1 134.03,47.01 135.13,47.01 135.23,46.9 136.19,46.9 ; v2(136.19,46.75) 136.19,46.9 ; 136.19,46.9 136.89,46.9 v1(137.08,46.7) ; IOBD1.11 168.43,53.71 167.72,54.42 167.72,55.71 167.33,56.1 166.8,56.1 166.63,55.93 166.63,55.76 166.52,55.64 v1(166.29,55.64)
PCIE_WAKE#: length 2.3
  TOP w0.102: TP2407.1 200.21,30.7 199.47,31.44 KBC24.4
PD4403_A: length 3.5
  BOTTOM w0.102: PQ4408.1 144.97,27.64 145.34,27.27 146.73,27.27 147.19,27.73 PD4404.A
PD4403_K: length 2.8
  BOTTOM w0.102: PR4458.1 145.69,24.22 v2(145.69,25.09) 146.23,25.62 PD4404.K
PD_CC1: length 3.4
  TOP w0.254: U3701.9 v1(25.58,40.76)
  BOTTOM w0.254: v1(25.58,40.76) 25.46,40.64 v2(24.69,40.64) 24.6,40.73 R3728.1
PD_CC2: length 3.1
  TOP w0.254: U3701.7 26.45,41.76 25.7,42.51 v2(25.42,42.51) 24.94,42.51 24.69,42.26 R3727.1
PD_SWD_CLK: length 2.5
  TOP w0.127: U3701.2 26.31,44.26 v2(25.83,43.78) 25.54,43.49 R3736.1
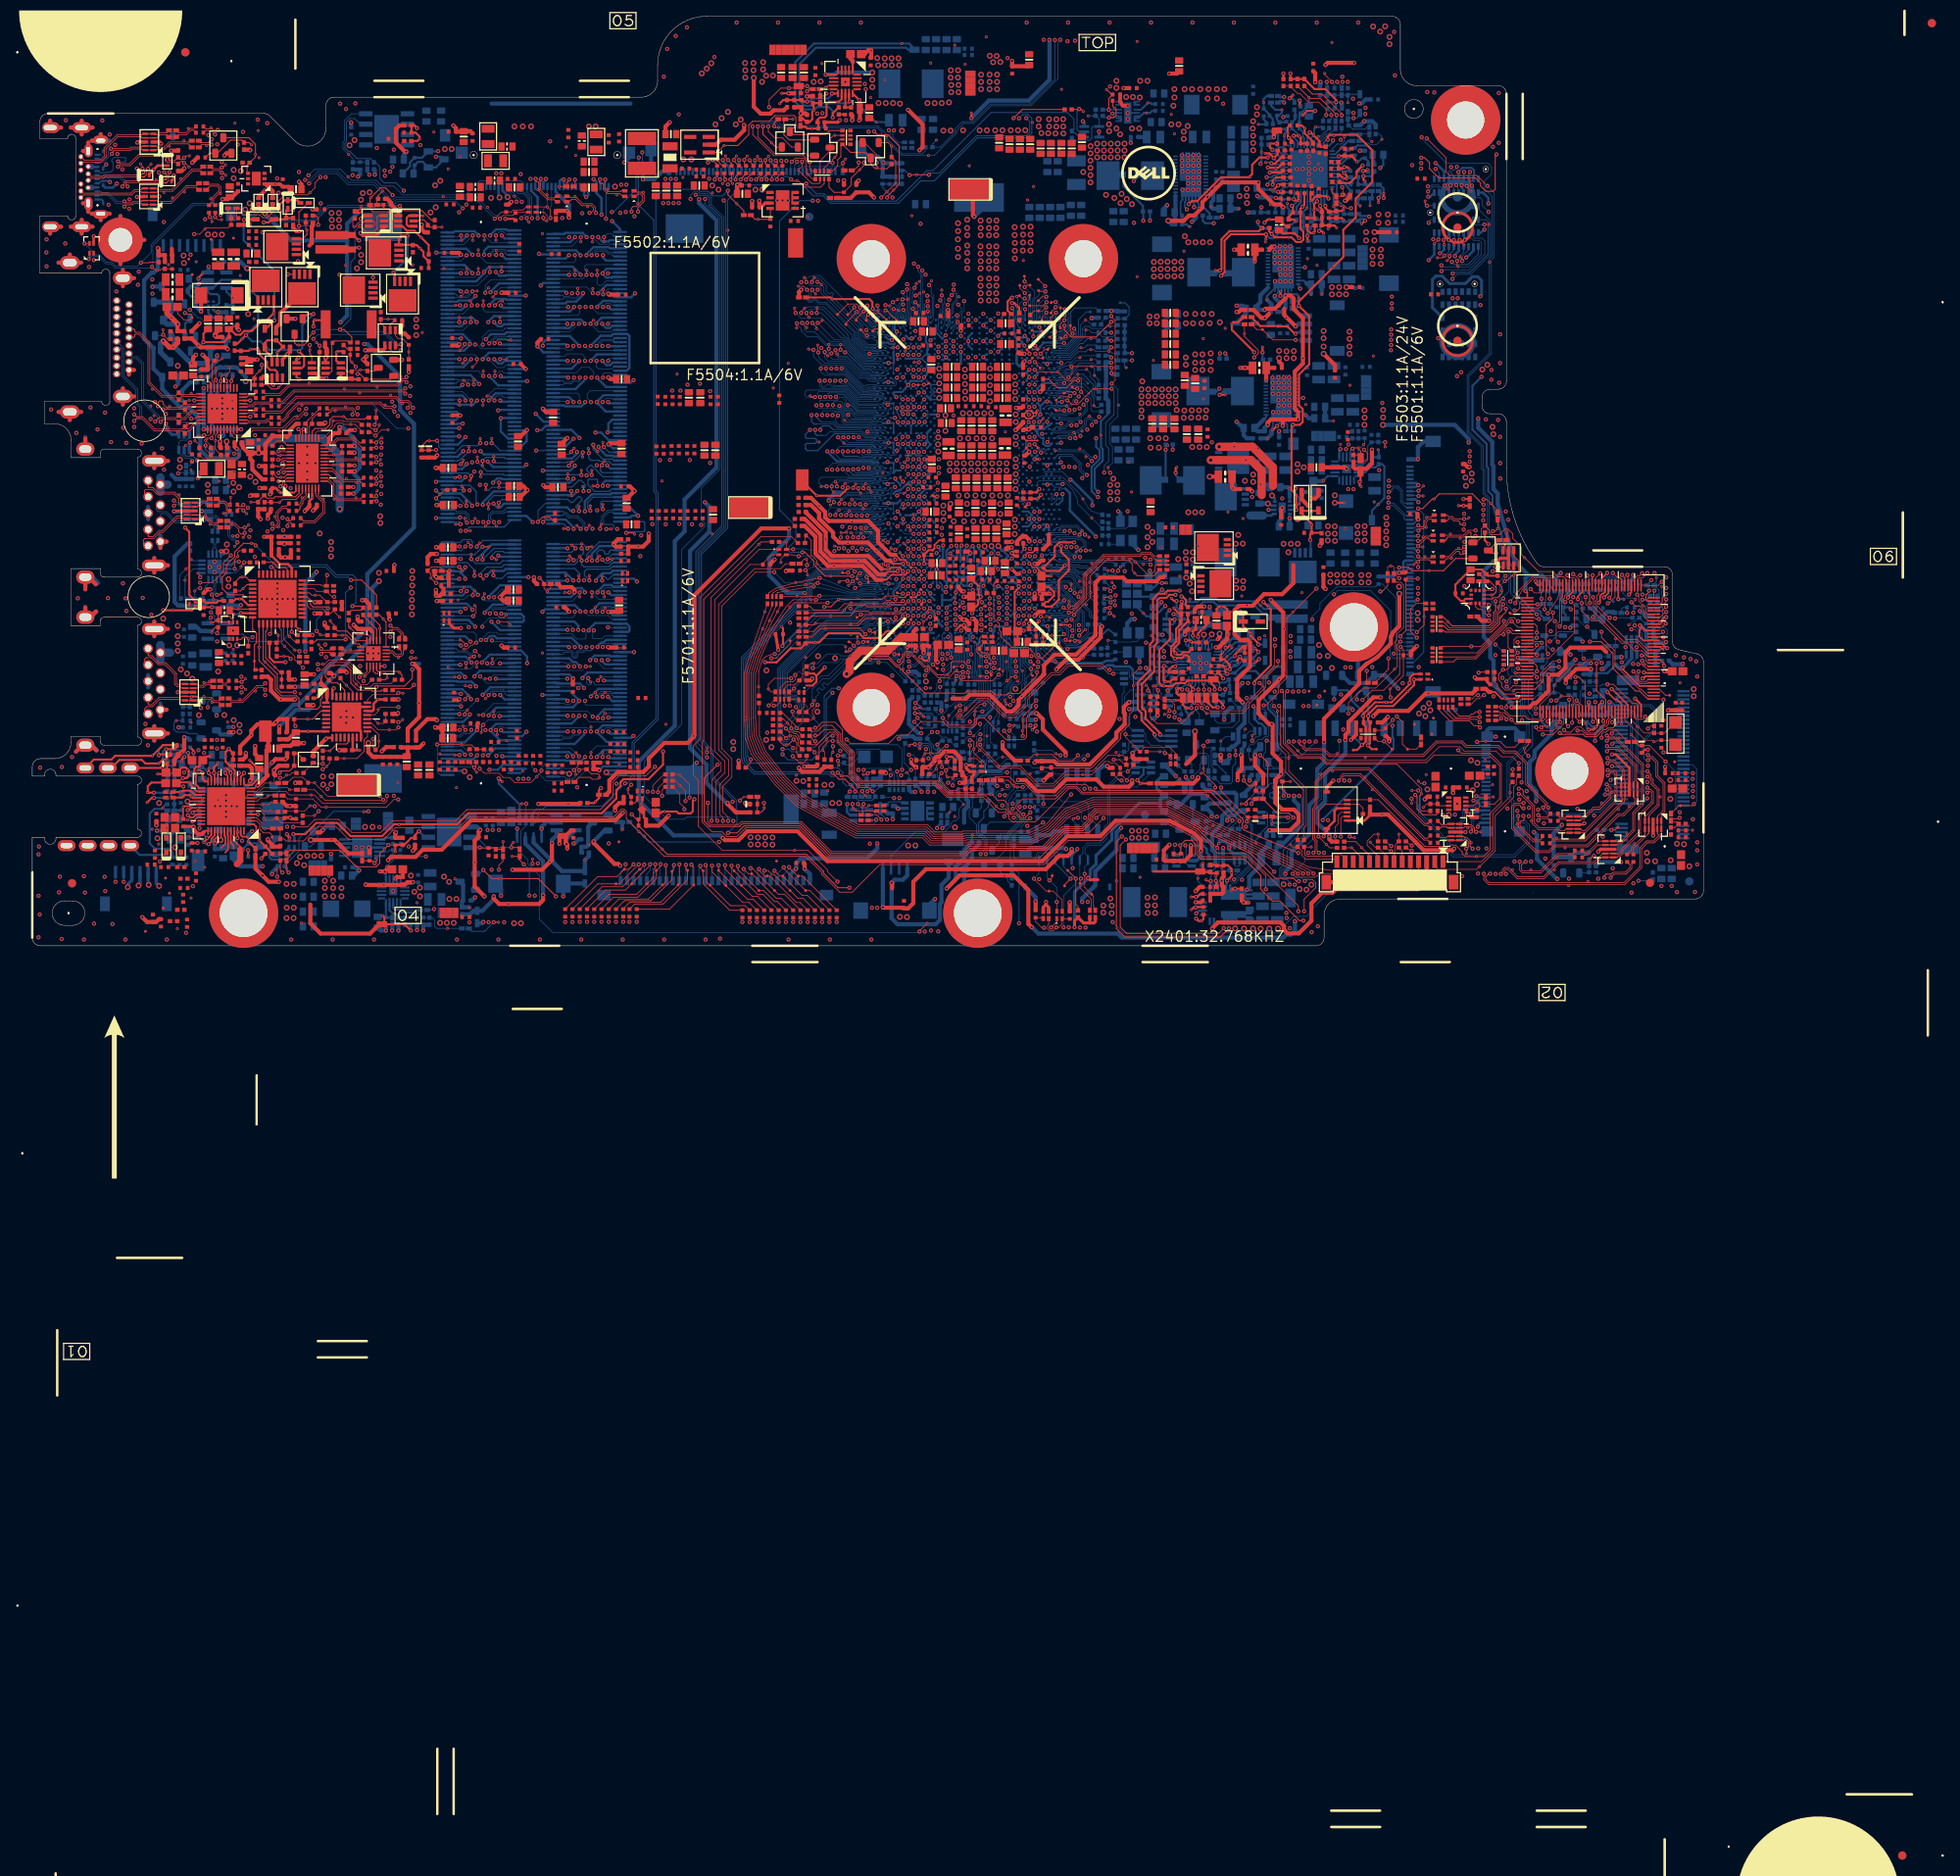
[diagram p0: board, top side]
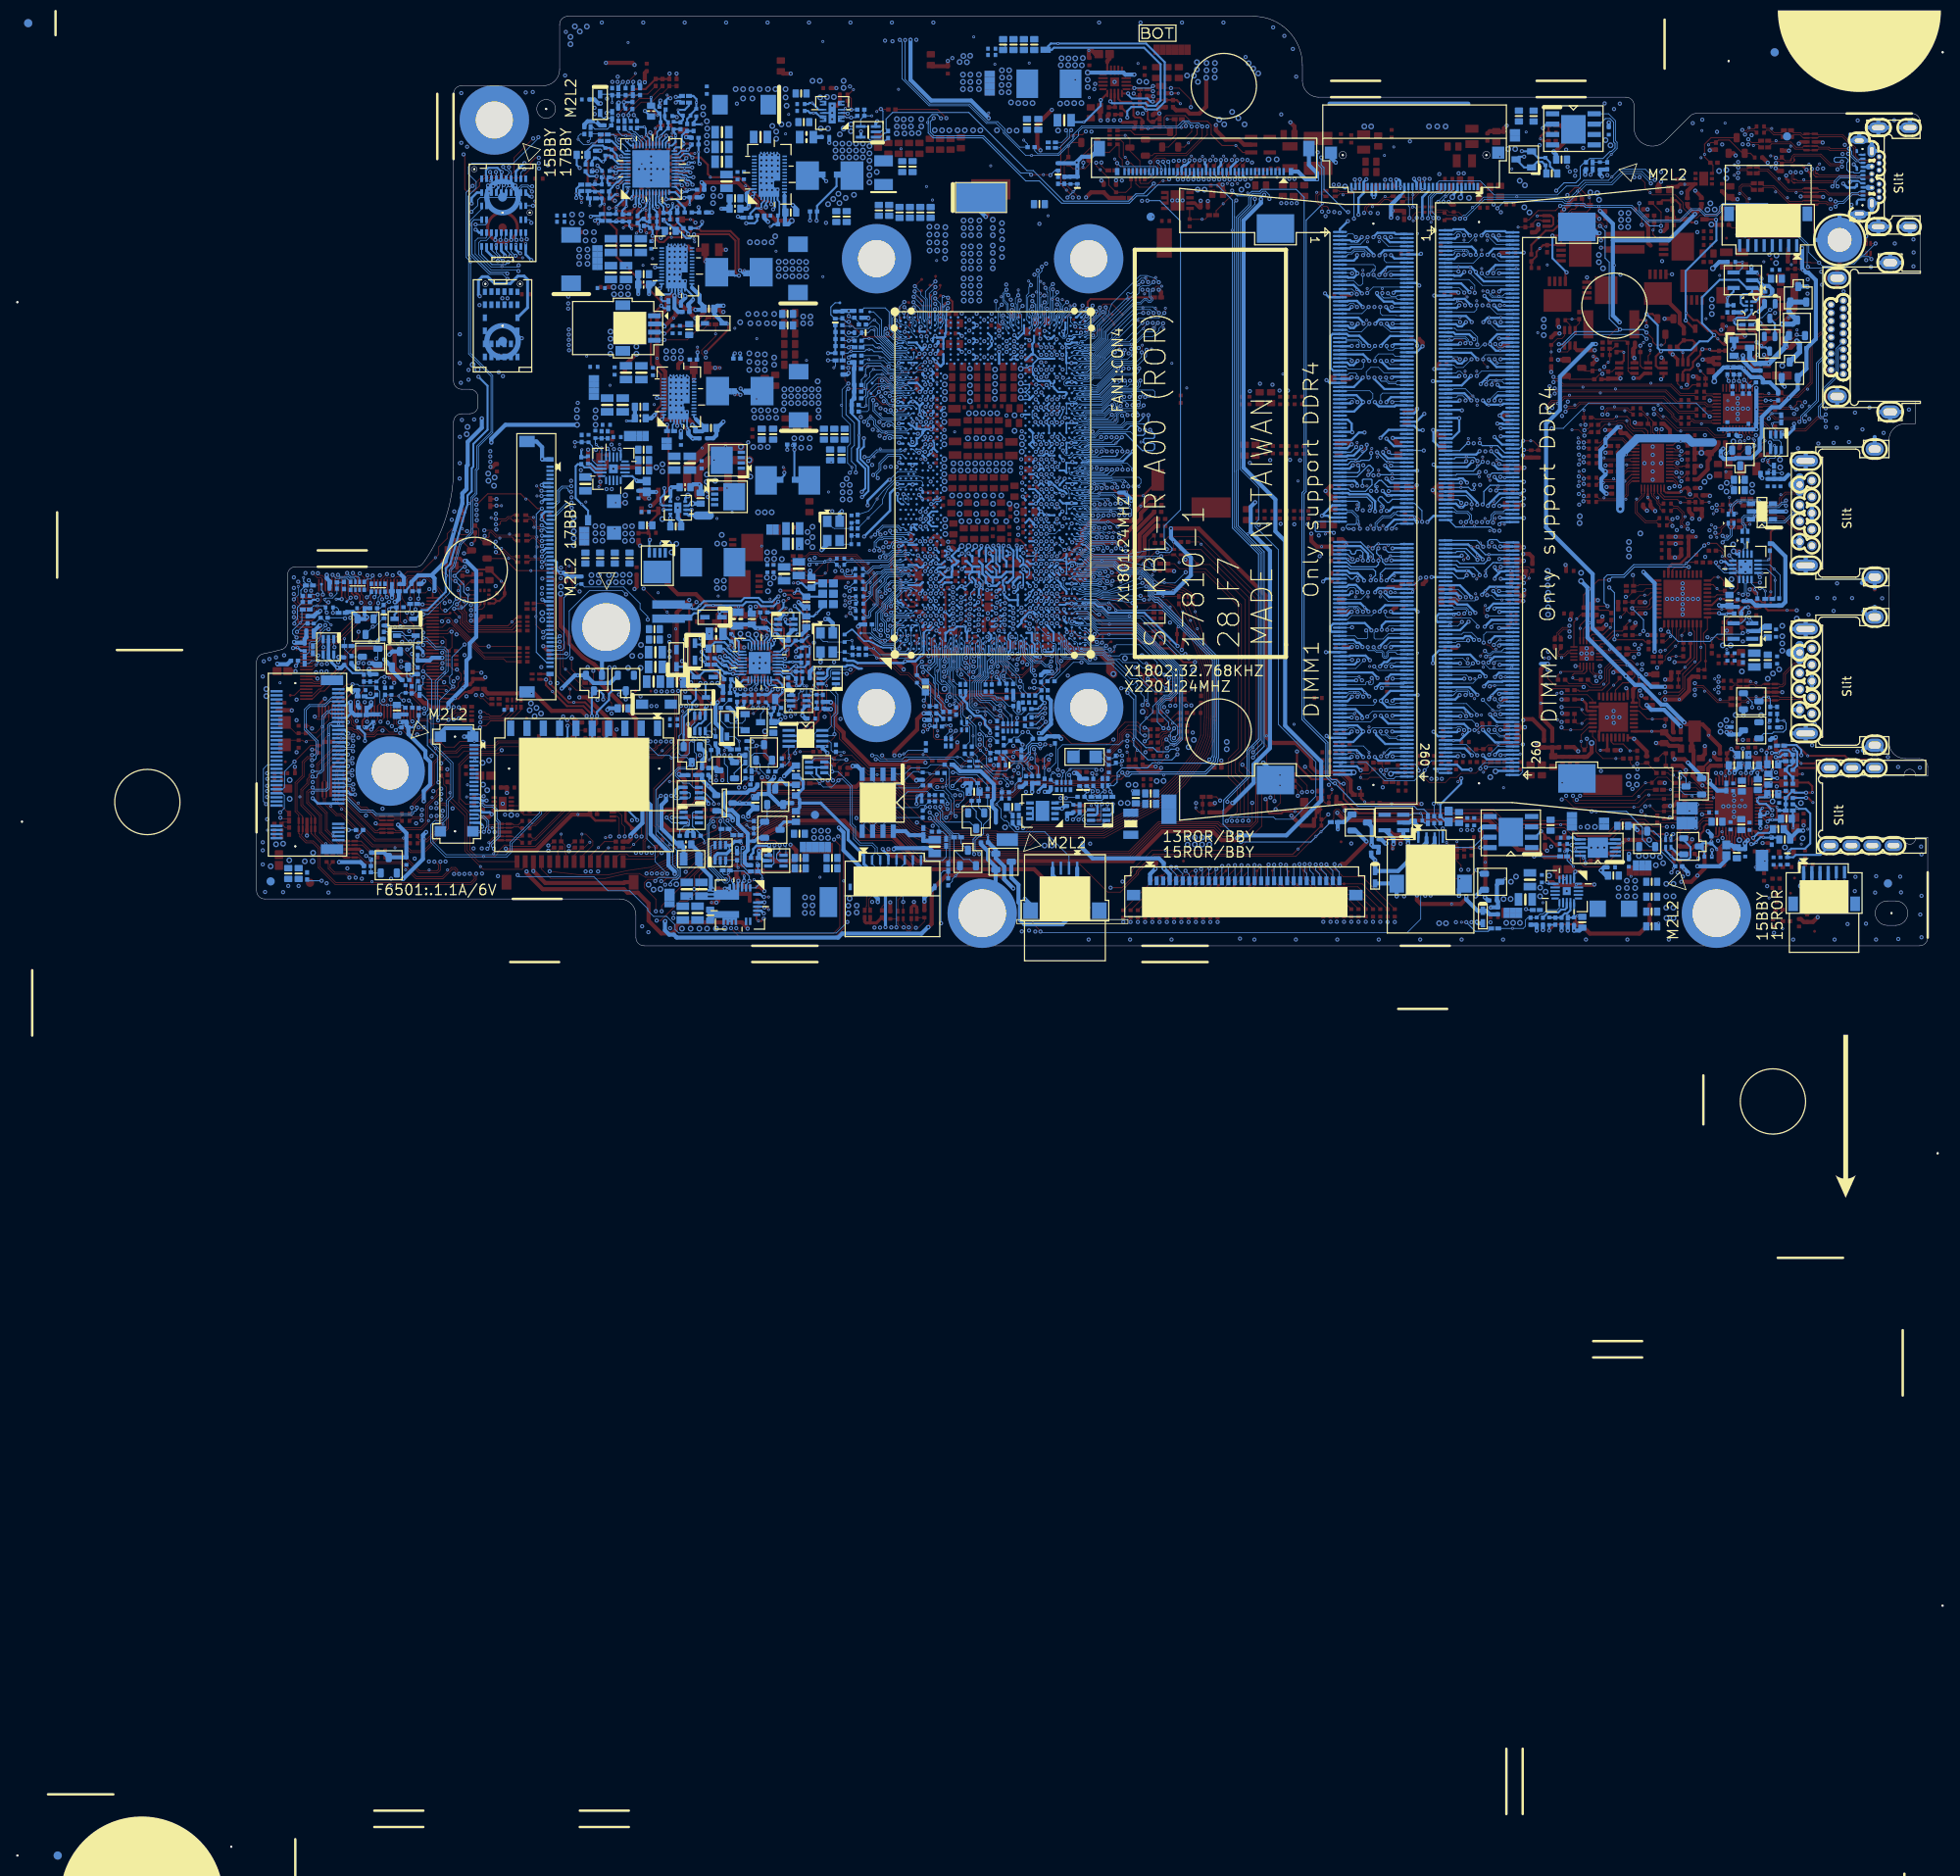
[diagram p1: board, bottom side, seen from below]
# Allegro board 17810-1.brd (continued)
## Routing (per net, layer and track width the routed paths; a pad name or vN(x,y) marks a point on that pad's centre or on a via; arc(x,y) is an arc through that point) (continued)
PD_SWD_IO: length 2.8
  TOP w0.127: U3701.1 26.63,44.76 26.21,45.18 v2(25.7,45.18) 25.45,45.18 24.86,44.59 R3736.2
PD_VBUS_C_CTRL1: length 59.1
  TOP w0.127: v1(32.18,31.08) 30.47,31.08 30.03,31.51 30.03,33.3 v2(28.53,34.8) 28.3,35.04 U3701.12 ; v1(39.88,70.1) 40.16,70.1 40.82,69.43 PR4325.1 43.9,69.43 PQ4312.G
  L3 w0.127: v1(39.88,70.1) 35.47,65.69 35.47,63.22 35.65,63.05 35.65,53.18 33.58,51.11 33.58,44.59 33.84,44.32 33.84,38.84 31.91,36.91 31.91,35.92 32.34,35.49 32.34,33.26 32.65,32.95 32.65,31.56 32.18,31.09 v1(32.18,31.08)
PD_VBUS_C_CTRL1_A: length 45.4
  TOP w0.127: v1(34.47,75.16) 33.69,74.38 33.69,74.02 33.3,73.63 v2(32.66,73.63) 32.43,73.63 32.15,73.91 PQ4306.D ; v1(45.21,73.73) 45.06,73.58 PQ4313.6 ; 36.73,70.81 36.73,73.83 PC4311.1 37.03,74.13 38.66,74.13 38.86,73.93 PR4319.2 39.17,74.11 39.17,74.59 38.23,75.53 v1(37.72,75.53) ; 36.73,70.81 36.73,70.45 36.43,70.16 PQ4307.6 ; 36.73,70.81 PQ4307.5 ; PQ4311.3 42.43,89.49 42.26,89.32 42.26,87.88 41.96,87.57 40.84,87.57 v1(40.18,88.23)
  BOTTOM w0.127: v1(37.72,75.53) 37.97,75.28 43.23,75.28 44.78,73.73 v1(45.21,73.73) ; v1(37.72,75.53) 39.04,76.85 39.04,83.79 39.55,84.29 39.55,87.61 40.17,88.23 v1(40.18,88.23) ; v1(37.72,75.53) 34.84,75.53 v1(34.47,75.16)
PD_VBUS_C_CTRL1_R: length 5.1
  TOP w0.102: PQ4307.2 38.25,70.81 38.68,70.37 PR4323.1 39.32,70.53 40.16,70.53 v2(40.21,70.58) 40.97,70.58 PR4342.2 42.02,70.45 PQ4312.D
PD_VBUS_DISCHG: length 41.3
  TOP w0.127: v2(34.83,73.94) v1(35.23,73.55) PR4332.1 35.23,71.09 34.95,70.81 PQ4310.2 ; v1(32.71,38.73) 32.3,39.14 U3701.20
  L3 w0.127: v1(35.23,73.55) 35.22,73.54 35.22,63.1 35.39,62.92 35.39,53.28 33.32,51.21 33.32,44.48 33.59,44.21 33.59,39.61 v1(32.71,38.73)
PD_VBUS_P_CTRL1: length 105.7
  TOP w0.127: v1(35.28,31.28) 35.54,31.02 35.54,30.38 35.33,30.17 35.33,29.41 34.92,29 32.99,29 32.69,29.3 32.69,30.31 32.36,30.64 30.55,30.64 29.78,31.41 29.78,32.97 27.8,34.96 v2(27.8,36.59) U3701.11 ; PD4310.A 33.81,91.05 32.69,89.93 v1(32.69,88.23) ; PR4310.1 48.92,88.94 47.75,90.11 45.62,90.11 v1(45.05,90.68)
  L3 w0.127: v1(45.05,90.68) 45.05,89.65 44.12,88.72 44.12,83.53 41.96,81.37 41.96,71.21 36.5,65.75 36.5,53.64 33.83,50.98 33.83,44.69 34.15,44.37 34.15,39.91 36.46,37.6 36.46,32.47 v1(35.28,31.28)
  BOTTOM w0.127: v1(45.05,90.68) 44.99,90.74 42.19,90.74 41.96,90.5 36.35,90.5 34.08,88.23 v1(32.69,88.23)
PD_VBUS_P_CTRL1_R: length 4
  TOP w0.127: v2(50.21,88.08) PR4310.2 48.72,88.08 PR4324.1 48.49,88.48 48,88.97 47.45,88.97 47.32,88.84 PQ4309.5
PD_VBUS_R: length 8.8
  TOP w0.127: R3730.2 30.58,32.6 C3717.2 30.58,32.66 R3726.2 30.38,33.52 v2(29.77,34.13) 28.6,35.3 28.6,38.52 28.8,38.72 U3701.13
PD_VCCD: length 3.8
  TOP w0.127: C3715.1 29.48,47.01 v2(29.59,46.9) 30.14,46.35 31.03,46.35 31.3,46.08 U3701.33
PD_XRES: length 7.6
  TOP w0.127: R3724.2 28.09,33.82 C3716.1 27.23,33.95 TP3703.1 27.23,36.87 27.48,37.13 27.48,38.29 27.01,38.77 U3701.10
PEG_CLK1_CPU: length 90
  L3 w0.14: v1(166.22,53.69) 166.41,53.88 166.59,53.88 166.67,53.79 166.67,47.63 165.9,46.86 165.9,37.92 163.43,35.45 162.84,35.45 162.3,34.9 157.14,34.9 156.24,34.01 153.68,34.01 152.85,33.18 148.25,33.18 146.99,31.92 146.99,31.46 146.48,30.95 140.64,30.95 140.26,31.33 140.26,32.6 141.2,33.54 141.2,35.86 140.05,37 140.05,38.9 139.98,38.98 139.63,39.32 139.29,39.67 139.29,40.6 138.67,41.22 137.35,42.54 137.35,44.43 136.38,45.39 136.38,46.79 134.83,48.34 132.37,48.34 131.96,48.74 131.96,54.08 131.54,54.5 131.54,56.07 130.78,56.83 130.78,59.05 131.11,59.38 131.11,59.76 130.83,60.04 130.45,60.04 v1(130.33,59.91)
  BOTTOM w0.102: 128.4,60.77 126.01,60.77 126.01,60.77 CPU1.A42 ; 128.4,60.77 128.85,60.77 129.46,60.16 129.71,59.91 v1(130.33,59.91) ; 128.4,60.77 v2(128.4,60.9) ; v1(166.22,53.69) 166.52,53.99 166.81,53.99 168.17,52.63 168.17,52.34 168.3,52.21 IOBD1.14
PEG_CLK1_CPU#: length 90.1
  L3 w0.14: v1(129.87,59.42) 130.52,58.78 130.52,56.72 131.28,55.96 131.28,54.39 131.7,53.97 131.7,48.63 132.26,48.07 134.72,48.07 136.12,46.68 136.12,45.28 137.08,44.32 137.08,42.43 138.4,41.11 138.4,41.11 139.03,40.48 139.03,39.56 139.79,38.79 139.79,36.89 140.93,35.75 140.93,33.65 139.99,32.71 139.99,31.22 140.53,30.69 146.59,30.69 147.25,31.35 147.25,31.81 148.36,32.91 152.96,32.91 153.79,33.74 156.35,33.74 157.25,34.64 162.41,34.64 162.95,35.18 163.54,35.18 166.17,37.81 166.17,46.75 166.94,47.52 166.94,53.9 166.7,54.14 166.42,54.14 v1(166.24,54.32)
  BOTTOM w0.102: v2(129.16,59.94) 129.26,60.04 ; 129.26,60.04 129.42,59.87 v1(129.87,59.42) ; 129.26,60.04 128.75,60.54 125.91,60.54 CPU1.B42 ; IOBD1.13 168.41,52.71 166.9,54.22 166.34,54.22 v1(166.24,54.32)
PEG_TX_CPU_N0: length 7.6
  BOTTOM w0.089: 127.66,45.59 127.6,45.65 125.85,45.65 125.5,46 CPU1.B17
  BOTTOM w0.102: 128.46,44.79 129.37,43.88 129.37,43.01 130.45,41.93 C1606.2 ; 128.46,44.79 v2(128.34,44.67) ; 128.46,44.79 128.09,45.16 128.02,45.23 127.66,45.59
PEG_TX_CPU_N1: length 10.6
  BOTTOM w0.089: CPU1.D16 124.53,45.44 124.82,45.73 125.52,45.73 125.82,45.43 127.43,45.43 127.65,45.22
  BOTTOM w0.102: 129.08,41.69 128.89,41.88 128.89,43.62 127.91,44.6 127.91,44.95 127.65,45.22 ; 129.08,41.69 129.78,40.99 129.78,40.51 129.86,40.43 130.12,40.43 130.48,40.78 C1608.2 ; 129.08,41.69 v2(129.18,41.8)
PEG_TX_CPU_N2: length 7.8
  BOTTOM w0.089: 128.83,45.81 128.31,45.81 128.24,45.88 128.16,45.96 127.91,46.21 126.39,46.21 126.16,46.44 125.78,46.44 125.69,46.4 125.49,46.4 125.4,46.44 125.13,46.44 124.99,46.39 124.35,46.39 CPU1.D17
  BOTTOM w0.102: 129.06,45.58 128.83,45.81 ; 129.06,45.58 v2(129.16,45.69) ; 129.06,45.58 130.18,44.46 130.38,44.46 130.53,44.61 C1610.2
PEG_TX_CPU_N3: length 6
  BOTTOM w0.102: C1612.2 130.33,45.64 129.87,45.64 129.21,46.3 128.37,46.3 128.22,46.45 127.3,46.45 126.75,47 125.96,47 CPU1.B19
PEG_TX_CPU_P0: length 6.5
  BOTTOM w0.089: CPU1.A17 126.07,45.84 127.73,45.84 127.8,45.77
  BOTTOM w0.102: v2(129.74,43.3) 129.6,43.3 ; 129.6,43.3 129.6,43.97 128.34,45.23 127.8,45.77 ; 129.6,43.3 129.6,43.1 129.88,42.82 C1605.2
PEG_TX_CPU_P1: length 9.5
  BOTTOM w0.089: 127.49,45.05 127.39,45.15 127.3,45.24 125.74,45.24 125.49,45.5 125.44,45.54 125.04,45.54 CPU1.C16
  BOTTOM w0.102: C1607.2 130.43,40.2 129.77,40.2 129.55,40.41 129.55,40.9 128.66,41.79 128.66,43.37 ; v2(128.5,43.37) 128.66,43.37 ; 128.66,43.37 128.66,43.53 127.68,44.5 127.68,44.86 127.49,45.05
PEG_TX_CPU_P2: length 7.8
  BOTTOM w0.089: CPU1.C17 124.82,46.21 125.03,46.21 125.16,46.26 125.36,46.26 125.45,46.23 125.72,46.23 125.81,46.26 126.07,46.26 126.31,46.02 127.83,46.02 128.23,45.62 128.69,45.62
  BOTTOM w0.102: C1609.2 130.53,43.72 130.29,43.48 130.16,43.48 130.09,43.56 130.09,44.22 129.71,44.61 ; 129.71,44.61 128.69,45.62 ; 129.71,44.61 v2(129.61,44.52)
PEG_TX_CPU_P3: length 5.4
  BOTTOM w0.102: C1611.2 130.2,45.86 129.96,45.86 129.3,46.52 128.47,46.52 128.32,46.68 127.4,46.68 126.84,47.23 126.04,47.23 CPU1.A19
PG_1: length 235.1
  TOP w0.254: PG4402.2 39.57,85.56 v1(40.05,85.56) ; v1(150.37,35.14) 149.99,34.76 v2(149.86,34.76)
  L3 w0.254: v1(150.37,35.14) 150.62,35.4 152.49,35.4 153.59,36.49 153.59,38.23 155.29,39.94 155.29,43.3 159.48,47.49 163.17,47.49 164.41,48.73 164.41,56.07 166.72,58.38 166.72,67 163.75,69.97 163.75,80.84 162.36,82.24 162.36,89.77 166.37,93.79 166.37,97.35 165.02,98.7 165.02,100.41 164.64,100.79 164.64,103.05 163.6,104.09 163.6,106.88 162.89,107.59 161.76,107.59 161.39,107.96 161.39,108.56 159.44,110.52 129.61,110.52 128.71,109.62 122.7,109.62 121.83,110.49 87.34,110.49 85.8,108.96 85.8,106.69 78.8,99.69 77.34,99.69 76.24,98.59 66.58,98.59 65.69,99.48 62.85,99.48 61.96,98.59 58.13,98.59 57.24,99.48 52.99,99.48 52.32,98.81 48.96,98.81 47.78,97.63 47.17,97.63 46.53,98.26 45.39,98.26 44.88,97.76 44.88,97.42 44.1,96.64 41.8,96.64 40.44,95.27 40.44,94.03 39.27,92.86 39.27,86.35 v1(40.05,85.56)
  BOTTOM w0.254: v1(150.37,35.14) 149.66,34.43 PR4444.1
PG_2: length 232.3
  TOP w0.254: v1(40.05,86.45) 40,86.45 PG4403.2 ; v2(149.88,36.44) v1(150.29,36.03)
  L3 w0.254: v1(150.29,36.03) 150.54,35.78 152.33,35.78 153.2,36.65 153.2,38.39 154.91,40.1 154.91,43.46 159.33,47.87 163.02,47.87 164.03,48.89 164.03,56.23 166.34,58.54 166.34,66.84 163.37,69.82 163.37,80.68 161.97,82.08 161.97,89.93 165.99,93.95 165.99,97.19 164.64,98.54 164.64,100.26 164.26,100.64 164.26,102.89 163.22,103.94 163.22,106.72 162.74,107.2 161.6,107.2 161.01,107.8 161.01,108.4 159.28,110.14 129.77,110.14 128.87,109.24 122.55,109.24 121.67,110.11 87.49,110.11 86.18,108.8 86.18,106.53 78.96,99.31 77.49,99.31 76.4,98.21 66.42,98.21 65.53,99.1 63,99.1 62.12,98.21 57.97,98.21 57.08,99.1 53.15,99.1 52.48,98.43 49.12,98.43 47.94,97.25 47.01,97.25 46.37,97.88 45.55,97.88 45.26,97.6 45.26,97.26 44.26,96.26 41.96,96.26 40.82,95.11 40.82,93.87 39.65,92.7 39.65,86.86 v1(40.05,86.45)
  BOTTOM w0.254: v1(150.29,36.03) 150.29,35.91 149.63,35.25 PR4414.1
PIRQA#: length 32.3
  TOP w0.102: R1607.2 88.06,22.44 v1(88.06,22.83)
  BOTTOM w0.102: CPU1.BB11 103.22,42.46 101.93,42.46 101.5,42.03 v2(100.38,42.03) 100.28,42.03 99.36,41.11 93.77,41.11 87.68,35.02 87.68,23.3 87.78,23.19 87.78,23.11 v1(88.06,22.83)
PLT_RST#: length 307
  TOP w0.102: R9136.1 36.45,22.37 v2(36.07,21.99) 35.71,21.63 v1(35.58,21.63) ; R6308.1 194.12,26.45 193.17,26.45 192.93,26.2 192.63,26.2 192.37,25.94 v1(192.37,25.51) ; v1(167.69,37.94) 168.37,38.62 168.37,44.87 EC6602.1 168.45,45 v1(169.82,45)
  L3 w0.102: v1(127.53,9.52) 125.53,11.52 125.53,12.41 122.74,15.2 122.15,15.2 122.14,15.21 121.72,15.21 120.57,16.35 118.71,16.35 116.96,18.1 116.96,25.19 v1(116.23,25.92)
  L4 w0.102: v1(35.58,21.63) 37.54,21.63 37.97,21.2 37.97,12.46 39.67,10.76 42.47,10.76 43.36,9.87 46.66,9.87 48.26,8.27 48.26,4.33 49.07,3.52 55.55,3.52 55.93,3.14 v1(55.93,2.89) ; v1(180.74,31.77) 179.98,31 178.92,31 178.2,30.29 176.89,30.29 175.25,28.65 175.25,27.73 171.6,24.09 170.99,24.09 166.65,19.75 162.99,19.75 162.22,18.99 159.82,18.99 158.6,17.77 157.04,17.77 155.9,16.63 153.51,16.63 149.6,12.72 143.38,12.72 141.29,10.63 131.4,10.63 130.67,9.91 127.93,9.91 v1(127.53,9.52) ; v1(171.17,88.61) 170.94,88.38 170.94,86.76 171.73,85.97 175.42,85.97 176.66,84.74 176.66,82.4 175.94,81.68 175.94,79.68 174.84,78.58 174.77,78.58 172.91,76.72 172.91,75.21 173.23,74.9 173.23,72 170.31,69.08 170.31,60.92 169.42,60.03 169.42,47.09 169.43,47.08 169.43,45.39 v1(169.82,45)
  L6 w0.102: v1(167.69,37.94) 168.35,37.28 178.99,37.28 v1(179.35,36.92) ; v1(55.93,2.89) 55.93,1.74 56.39,1.29 84.1,1.29 84.12,1.31 84.48,1.31 84.51,1.29 107,1.29 113.72,8.01 118.04,8.01 119.43,9.39 127.41,9.39 v1(127.53,9.52) ; v1(192.37,25.51) 191.22,26.65 191.22,26.68 189.51,28.39 185.88,28.39 185.11,27.62 v1(182.6,27.62)
  BOTTOM w0.102: v1(182.6,27.62) 182.6,28.12 182.4,28.32 182.4,30.11 v1(180.74,31.77) 181.18,32.2 181.18,32.99 180.9,33.27 180.9,35.37 v1(179.35,36.92) ; v1(167.69,37.94) 167.92,37.71 IOBD1.43 ; ED1703.1 113.04,22.66 C1701.1 113.99,23.61 R1713.1 114.78,23.74 R1715.1 114.91,23.63 115.77,24.49 115.77,25.67 116.03,25.92 v1(116.23,25.92) ; GPU1.D1 171.39,88.99 171.17,88.76 v1(171.17,88.61)
PLT_RST#_Q_TPM2: length 6.3
  TOP w0.102: U9104.17 41.08,25.64 40.66,25.22 40.66,23.82 39.8,22.95 v2(38.23,22.95) R9136.2
PM_PCH_PWROK: length 52.8
  TOP w0.127: v1(100.86,18.9) 100.86,19.17 v2(100.25,19.78) 99.62,20.41 98.88,20.41 v1(98.09,21.2)
  BOTTOM w0.127: R1706.2 101.65,18.38 101.13,18.9 v1(100.86,18.9) 100.86,18.99 101.17,19.3 RN1703.3 ; CPU1.BA20 103.73,47.36 103.1,46.73 99.74,46.73 98.8,45.79 96.35,45.79 95.16,44.6 95.16,43.74 95.31,43.59 95.31,42.99 94.73,42.41 94.37,42.41 87.18,35.22 87.18,23.09 87.29,22.99 87.29,22.61 88.6,21.3 97.99,21.3 v1(98.09,21.2)
PM_RSMRST#: length 119.7
  TOP w0.127: v1(150.52,23.36) 150.53,23.36 151.45,22.44 v2(151.45,22.24) 151.45,19.54 150.93,19.02 R1702.1 R1720.2 152.6,16.25 154.05,16.25 v1(154.58,15.71)
  L4 w0.127: v1(150.52,23.36) 148.5,21.34 147.46,21.34 147.1,20.98 144.22,20.98 143.05,19.82 132.81,19.82 130.99,17.99 128.97,17.99 128.65,17.67 127.42,17.67 127.01,17.26 124.84,17.26 123.98,18.13 120.97,18.13 120.2,18.9 117.5,18.9 117.37,18.77 111.54,18.77 111.01,19.31 104.75,19.31 103.71,18.27 100.84,18.27 v1(100.2,18.9)
  BOTTOM w0.127: Q1701.3 153.93,15.06 v1(154.58,15.71) ; CPU1.AY17 104.55,46.14 104.21,46.47 99.82,46.47 98.88,45.53 96.4,45.53 95.38,44.51 95.38,43.86 95.53,43.7 95.53,42.9 94.73,42.1 94.42,42.1 87.44,35.12 87.44,23.2 87.54,23.09 87.54,22.72 87.88,22.38 93.92,22.38 93.95,22.41 95.05,22.41 95.65,21.81 98.77,21.81 99.36,21.22 99.36,20.03 99.78,19.62 RN1703.4 100.5,19.47 100.2,19.17 v1(100.2,18.9) 99.95,18.65 R1704.1
PM_RSMRST#_M: length 7
  TOP w0.127: v1(154.02,18.38) 153.24,19.17 R1737.2 v2(154.23,20.13)
  BOTTOM w0.127: v1(154.02,18.38) 153.58,17.94 153.02,17.94 152.85,18.11 Q1702.6 151.83,18.11 151.69,18.25 151.69,18.63 151.81,18.76 Q1702.5
PM_RSMRST#_R: length 4.8
  TOP w0.127: R1720.1 149.13,18 148.79,17.66 v1(148.79,17.39) v2(148.18,17.39)
  BOTTOM w0.127: v1(148.79,17.39) 148.79,17.66 149.9,18.76 Q1702.2
PME#: length 1.3
  TOP w0.102: v1(106.73,43.17) 106.12,43.17 TP1707.1
  BOTTOM w0.102: v1(106.73,43.17) 106.4,42.85 CPU1.AU11
POWER_SW_IN#: length 14.1
  TOP w0.102: KBC24.127 196.81,29.52 196.59,29.73 196.11,29.73 193.8,32.05 v1(193.09,32.05)
  BOTTOM w0.102: R2432.2 186.94,29.51 C2426.1 188.79,29.51 v2(188.8,29.52) 189.44,29.52 189.73,29.8 189.73,31.17 R2451.1 190.4,31.84 192.25,31.84 192.45,32.05 v1(193.09,32.05)
PQ3802_1: length 7.1
  TOP w0.508: v1(23.94,73.13) 23.72,73.35 20.61,73.35 v2(20.38,73.57) 19.53,74.43 PR4302.1 PR4309.2
  BOTTOM w0.508: v1(23.94,73.13) 23.73,73.33 PQ4302.1
PQ4405_2: length 4.6
  TOP w0.102: R4462.1 137.89,30.5 PR4463.1 137.99,30.59 v1(137.99,31.31) 137.99,31.31 137.99,31.32 137.74,31.57 v2(137.74,31.87)
  BOTTOM w0.102: v1(137.99,31.31) 138.4,30.9 138.4,30.25 138.61,30.04 PQ4405.2
PQ4405_3: length 2.3
  TOP w0.089: v2(138.78,28.36) 138.96,28.36 v1(139.4,28.81) 139.4,28.97 139.04,29.33 PR4455.2
  BOTTOM w0.089: v1(139.4,28.81) 139.4,29.31 PQ4405.3
PQ4405_5: length 2.7
  BOTTOM w0.102: PQ4405.5 137.06,30.04 136.7,29.68 136.7,29.25 136.52,29.07 PR4413.2 136.17,29.84 PC4438.1
PQ4405_6: length 3.2
  BOTTOM w0.102: v2(137.41,31.84) 137.44,31.82 PQ4405.6 136.84,30.69 136.75,30.78 PC4438.2 135.46,30.78 PR4450.1
PQ4408_C: length 10.4
  TOP w0.102: v1(142.73,29.15) 142.72,29.14 142.72,29.1 v2(142.16,28.54) 140.87,27.25 137.85,27.25 137.06,28.04 PR4451.1 137.03,28.9 R4462.2
  BOTTOM w0.102: v1(142.73,29.15) 142.73,29.14 142.72,29.13 142.72,28.74 143.06,28.4 PQ4408.3
PQ4408_E: length 6.6
  BOTTOM w0.102: PR4431.2 146.89,30.14 147.85,29.18 PR4436.1 147.93,27.55 147.14,26.76 145.32,26.76 PQ4408.2
PR_2: length 0.8
  BOTTOM w0.254: PC4432.1 138.71,33.6 PR4416.2
PRE: length 3.4
  TOP w0.102: v2(23.38,69.98) 23.13,69.73 v1(23.13,69.23) 23.09,69.19 U5701.16
  BOTTOM w0.102: R5415.2 23.13,69.92 v1(23.13,69.23) 22.66,68.75 R5416.2
PROC_SELECT#: length 10.2
  BOTTOM w0.089: CPU1.C64 125.03,72.79 126.75,72.79 128.7,74.74
  BOTTOM w0.102: R603.1 133.03,76.06 132.9,75.93 v2(132.1,75.93) 131.79,75.93 131.52,75.66 129.82,75.66 129.56,75.91 129.03,75.91 128.75,75.63 128.75,74.79 128.7,74.74
PROCHOT: length 14.4
  TOP w0.089: v1(188.61,42.15) 189.02,41.74 189.02,38.35 185.87,35.2 184.2,35.2 183.97,35.44 KBC24.83
  BOTTOM w0.089: v1(188.61,42.15) 188.9,42.15 R2418.1 189.69,41.37 R2417.1 190.07,40.5 Q2408.G
PROJECT_ID0: length 27.1
  TOP w0.102: v1(111.45,21.15) 111.17,20.87 111.17,20.29 112.45,19.02 113.26,19.02 v2(113.49,19.24) R1915.1 R1914.2
  L3 w0.102: v1(111.45,21.15) 111.53,21.07 112.25,21.07 112.72,21.55 112.72,25.89 109.75,28.87 109.75,30.15 108.82,31.07 108.82,33.07 108.83,33.08 108.83,33.53 108.87,33.56 108.87,34.27 110.11,35.51 v1(110.11,38.83)
  BOTTOM w0.102: v1(110.11,38.83) 110.14,38.83 110.44,39.12 CPU1.AK6
PROJECT_ID1: length 24.3
  TOP w0.102: R1917.2 112.25,21.76 v1(111.99,21.51) 111.99,20.86 v2(112.19,20.67) 112.9,20.67 R1916.1
  L3 w0.102: v1(111.99,21.51) 111.99,21.51 112.52,22.03 112.52,25.81 109.54,28.78 109.54,30.06 108.62,30.99 108.62,33.14 108.64,33.16 108.64,33.61 108.67,33.64 108.67,34.34 109.84,35.51 109.84,38.13 109.72,38.25 109.72,39.11 v1(110.07,39.46)
  BOTTOM w0.102: v1(110.07,39.46) 110.38,39.77 CPU1.AK7
PROJECT_ID2: length 33.4
  TOP w0.102: v1(111.5,21.91) 111.5,22.29 R1919.2 110.79,22.09 v2(110.79,21.68) 110.16,21.05 R1918.1
  L3 w0.102: v1(111.07,40.81) 110.49,41.39 110.49,42.29 110.1,42.68 106.59,42.68 105.45,41.53 105.45,40.03 105.54,39.95 105.54,39.82 108.67,36.68 108.67,36.02 108.29,35.64 108.29,33.8 108.26,33.77 108.26,33.32 108.21,33.28 108.21,30.82 109.14,29.9 109.14,28.62 111.5,26.25 v1(111.5,21.91)
  BOTTOM w0.102: v1(111.07,40.81) 110.81,41.08 CPU1.AK9
PROJECT_ID3: length 30
  TOP w0.102: R1921.2 R1920.1 109.17,23.25 109.53,23.61 v2(110.11,23.61) 111.01,23.61 111.87,24.48 112.06,24.48 v1(112.09,24.5)
  L3 w0.102: v1(109.96,42.26) 109.47,41.77 106.6,41.77 106.31,41.48 106.31,39.38 106.58,39.11 106.59,39.11 109.65,36.04 109.65,35.59 108.48,34.42 108.48,33.72 108.45,33.69 108.45,33.24 108.42,33.21 108.42,30.9 109.34,29.98 109.34,28.7 111.78,26.26 111.78,24.86 112.09,24.55 v1(112.09,24.5)
  BOTTOM w0.102: CPU1.AK10 110.5,41.73 v1(109.96,42.26)
PS_ID: length 288
  TOP w0.203: KBC24.36 196.01,43.32 v1(195.73,43.04)
  TOP w0.635: PR4305.2 17.82,74.35 17.82,73.92 v2(17.27,73.37) 16.8,73.37 16.22,73.95 16.22,73.97 v1(16.05,74.13)
  L4 w0.635: v1(169.87,43.15) 170.12,43.15 170.55,43.57 170.55,44 171.23,44.69 171.23,60.1 171.68,60.55 171.68,68.83 177.57,74.72 177.57,76.29 178.29,77.01 178.29,82.25 178.17,82.38 178.17,86.57 177.21,87.52 177.21,93.44 176.63,94.02 174.35,94.02 173.21,95.16 173.21,97.66 171.01,99.86 168.64,99.86 166.25,102.25 166.25,104.98 165.31,105.92 165.31,108.22 162.48,111.05 127.93,111.05 v1(127.81,110.94) ; v1(16.05,74.13) 16.28,74.13 17.16,75.01 17.16,80.68 20.1,83.63 20.1,84.99 19.13,85.96 19.13,88.04 21.78,90.68 24.09,90.68 25.89,92.48 27.47,92.48 28.11,91.85 28.21,91.85 29.75,91.85 v1(30.2,92.29)
  L6 w0.508: v1(195.73,43.04) 195.73,43.1 195.16,43.68 192.11,43.68 192.04,43.6 185.18,43.6 183.86,42.28 182.42,42.28 181.25,43.45 179.59,43.45 179.23,43.1 169.92,43.1 v1(169.87,43.15)
  L6 w0.635: v1(30.2,92.29) 31.88,93.97 31.88,95.01 32.65,95.79 35.6,95.79 38.09,98.27 38.09,98.63 41.27,101.82 45.72,101.82 46.79,102.89 75.99,102.89 78.33,105.23 78.33,106.98 78.47,107.12 78.47,107.12 83.64,112.3 116.1,112.3 116.11,112.29 125.86,112.29 125.88,112.31 126.46,112.31 126.49,112.28 126.49,112.26 126.52,112.26 127.23,111.55 127.23,111.52 v1(127.81,110.94)
  BOTTOM w0.635: PD4302.3 15.7,72.78 PR4304.2 15.72,73.8 v1(16.05,74.13)
PS_ID_R: length 13
  TOP w0.102: v1(18.72,77.56) 18.85,77.44 19.38,77.44 19.58,77.23 AFTP4304.1 19.33,76.72 18.59,76.72 17.82,77.5 PR4317.1
  L6 w0.102: v1(19.4,84.7) 19.48,84.62 19.48,79.98 18.72,79.21 v1(18.72,77.56)
  BOTTOM w0.102: v1(19.4,84.7) 19.4,84.85 19.05,85.21 DCIN1.4
PS_ID_R1: length 3.7
  TOP w0.102: v2(16.03,75.48) 16.03,74.92 v1(16.05,74.9) 16.58,74.36 PR4305.1 PR4306.2
  BOTTOM w0.102: PQ4301.S 15.94,74.78 v1(16.05,74.9)
PS_ID_R2: length 11.1
  TOP w0.508: PR4309.1 18.62,75.33 PR4306.1 17.8,76.14 v1(17.85,76.19)
  TOP w0.635: PR4317.2 16.5,77.55 v2(17.07,76.98) v1(17.85,76.19)
  BOTTOM w0.635: PD4303.2 PD4303.1 17.01,78.74 17.01,77.67 PQ4301.D 16.52,76.19 v1(17.85,76.19)
PSID_DISABLE#_R_C: length 8.3
  BOTTOM w0.635: PQ4301.G 17.42,74.37 17.42,73.43 19.47,71.39 v2(19.53,71.39) 20.47,71.39 PR4303.2 21.16,71.37 21.83,72.04 PQ4302.3
PSYS: length 4.6
  TOP w0.102: v1(160.58,92.98) 160.65,92.9 PR4682.1 160.48,91.86 PR4671.2 159.74,91.86 159.31,92.29 v2(159.31,92.71)
  BOTTOM w0.102: v1(160.58,92.98) 160.58,93.06 159.82,93.82 PU4601.46
PTP_DIS#_R: length 71.4
  TOP w0.127: AFTP6537.1 126.54,7.48 v1(127.28,8.22) ; v1(181.86,32.3) 182.2,32.64 KBC24.90
  L4 w0.127: v1(181.86,32.3) 181.86,32.26 179.66,30.05 176.99,30.05 175.49,28.55 175.49,27.63 171.7,23.84 171.09,23.84 166.75,19.51 163.09,19.51 162.32,18.75 159.92,18.75 158.7,17.53 157.14,17.53 156,16.39 153.64,16.39 152.69,15.43 152.69,14.56 151.57,13.44 150.67,13.44 149.7,12.48 143.48,12.48 141.39,10.39 131.5,10.39 130.77,9.67 128.73,9.67 v1(127.28,8.22)
  BOTTOM w0.127: TP1.6 125.4,10.1 v1(127.28,8.22)
PURE_HW_SHUTDOWN#: length 43
  TOP w0.102: v1(145,19.4) 145,19.71 143.57,21.14 v2(143.57,21.73) v1(143.57,24.52)
  L4 w0.102: v1(121.03,17.03) 121.44,17.44 122.48,17.44 123.34,16.58 127.1,16.58 127.65,17.12 128.88,17.12 129.2,17.45 131.21,17.45 132.22,18.46 133.04,19.27 144.87,19.27 v1(145,19.4)
  BOTTOM w0.102: D4001.3 117.41,15.16 120.37,15.16 120.75,15.53 120.75,16.48 121.03,16.76 v1(121.03,17.03) ; Q2602.D 142.77,24.52 v1(143.57,24.52) 143.81,24.27 144.7,24.27 C2610.1 144.5,23.87 144.5,22.06 144.93,21.63 R2615.1
PWR_0D6V_S3EN: length 17.8
  TOP w0.127: PR5126.2 PR5125.2 31.56,11.71 37.7,11.71 39.74,9.68 42.14,9.68 42.59,10.13 42.59,11.28 v2(43.17,11.86) v1(43.66,12.35)
  BOTTOM w0.127: PU5102.7 43.48,12.53 v1(43.66,12.35) 44.06,12.35 PC5120.1
PWR_0D6V_S5EN: length 4
  BOTTOM w0.127: PU5102.9 43.61,11.53 43.81,11.73 PC5119.1 PR5114.2 44.19,10.46 v2(43.44,9.71)
PWR_0D6V_VCNTL: length 3.8
  TOP w0.127: PR5118.2 40.46,10.43 PC5111.1 41.65,10.43 v1(41.96,10.13) 42.21,10.38 v2(42.21,10.74)
  BOTTOM w0.127: v1(41.96,10.13) 41.96,10.78 42.21,11.03 PU5102.10
PWR_1D0V_BT: length 2.6
  TOP w0.254: PC5204.1 142.64,4.74 v1(142.59,4.69) 142.34,4.69 v2(142.09,4.44)
  BOTTOM w0.254: v1(142.59,4.69) 142.7,4.8 PU5201.20
PWR_1D0V_EN: length 5.7
  TOP w0.127: PC5215.1 144.4,7.79 144.45,7.84 v1(144.45,7.94) 144.02,7.94 v2(143.86,8.09)
  BOTTOM w0.127: PR5210.2 146.76,9.16 145.08,9.16 144.45,8.53 v1(144.45,7.94) 144.45,7.87 144.84,7.48 PU5201.2
PWR_1D0V_FB: length 5.4
  TOP w0.254: PR5202.2 145.13,9.9 PC5212.2 145.97,9.82 PR5204.1 146.53,9.87 147.01,9.39 v2(147.01,8.93) 147.01,8.55 v1(146.45,7.99)
  BOTTOM w0.254: v1(146.45,7.99) 146.45,7.69 146.34,7.57 PU5201.5
PWR_1D0V_FB_A: length 2.8
  TOP w0.254: v2(143.48,10.13) PG5223.1 143.56,9.03 PR5202.1 144.52,8.91 PC5212.1
PWR_1D0V_PFM: length 2.3
  TOP w0.254: PR5203.1 145.13,7.92 v1(145.08,7.97)
  BOTTOM w0.254: v2(145.08,8.55) v1(145.08,7.97) 145.34,7.71 PU5201.3
PWR_1D0V_PG: length 4
  BOTTOM w0.127: PR5208.2 PR5209.2 142.87,8.6 v2(142.87,8.26) 142.87,7.89 143.67,7.1 PU5201.1
PWR_1D0V_PH: length 1.7
  TOP w0.254: v1(142.67,3.33) 142.96,3.04 v2(143.33,3.04) 143.56,3.27 PC5204.2
PWR_1D0V_SS: length 2.6
  TOP w0.254: v2(142.09,5.99) v1(142.64,5.99) 142.8,5.99 143.18,6.37 PC5213.1
  BOTTOM w0.254: PU5201.22 143.08,6.3 142.77,5.99 v1(142.64,5.99)
PWR_1D0V_TON: length 2.1
  TOP w0.254: PR5201.2 v1(147.45,7) 147.19,7 v2(146.94,6.75)
  BOTTOM w0.254: PU5201.6 147.35,7.1 v1(147.45,7)
PWR_1D2V_BOOT: length 2.6
  TOP w0.508: PR5101.1 43.48,9.36 v1(43.2,9.09) 43.18,9.11 v2(42.59,9.11)
  BOTTOM w0.254: v1(43.2,9.09) 43.2,8.97 43.35,8.83 PU5101.1
PWR_1D2V_BOOT_R: length 1.9
  TOP w0.508: v2(44.5,8.22) 44.7,8.42 PC5117.1 45.41,8.45 PR5101.2
PWR_1D2V_BYP: length 2.6
  BOTTOM w0.254: PR5102.1 43.38,3.45 PC5110.1 43.35,3.48 PU5101.15
PWR_1D2V_EN: length 9.6
  BOTTOM w0.102: PR5105.2 v2(50.9,2.12) 49.58,2.12 49.33,2.38 49.33,3.14 49.02,3.45 PR5127.1 47.95,3.45 PC5138.1 47.5,3.9 47.17,3.9 46.66,4.41 45.39,4.41 45.14,4.65 PU5101.11
PWR_1D2V_IMAX: length 4
  BOTTOM w0.254: PU5101.13 44.25,4.65 44.46,4.43 44.93,4.43 45.27,4.09 46.52,4.09 PR5106.2
PWR_1D2V_PGOOD:
  vias: v2(47.17,5.27)
PWR_1D2V_PHASE: length 7
  TOP w0.508: v1(40.87,7.51) 40.92,7.46 v2(43.1,7.46) 45.34,7.46 PC5117.2 45.69,7.51 45.97,7.79 v1(46.66,7.79)
  BOTTOM w0.254: PU5101.6 46.47,7.6 v1(46.66,7.79)
PWR_1D2V_VFB: length 4
  BOTTOM w0.254: PC5112.2 46.38,3.45 PR5103.2 PR5104.1 44.88,3.58 44.48,3.98 44.17,3.98 43.79,4.35 PU5101.14
PWR_1D2V_VFB_R: length 6.2
  TOP w0.254: v1(46.4,1.87) 45.64,2.63 PG5113.2 43.15,3.47 v2(42.95,3.67)
  BOTTOM w0.254: PR5103.1 46.38,2.58 PC5112.1 v1(46.4,1.87)
PWR_1D5V_EN: length 4
  BOTTOM w0.127: PR5405.2 61.64,15.03 PC5407.1 61.95,16.02 v2(62.15,16.22) 63.13,16.22 63.3,16.05 PU5402.3
PWR_1D8V_EN: length 5.1
  TOP w0.127: v1(54.86,12.05) 54.93,11.98 PC5406.1 56.67,11.98 PR5401.1 PR5406.2 v2(57.71,12.77)
  BOTTOM w0.127: v1(54.86,12.05) 54.85,12.03 PU5401.8
PWR_1D8V_POK: length 7.4
  TOP w0.127: v2(58.98,12.67) 58.72,12.41 v1(58.72,12.05) 59.52,12.05 PR5408.2
  BOTTOM w0.127: v1(58.72,12.05) 55.74,12.05 54.48,13.3 53.66,13.3
PWR_2D5V:
  vias: v1(47.57,98.14) v2(49.22,99.74)
PWR_2D5V_EN: length 10.4
  BOTTOM w0.102: PU5403.8 39.11,101.97 38.26,101.12 38.26,98.67 38.07,98.48 38.07,97.71 v2(38.78,96.99) 39.29,96.49 PR5409.1 40.16,96.03 PC5427.1 40.21,96.03 PR5417.2
PWR_2D5V_FB: length 5.8
  TOP w0.254: PR5419.2 47.22,98.64 v2(47.47,98.9) 47.47,99.18 46.99,99.66 PC5411.2 46.48,100.52 PR5420.1 46.84,100.55 v1(47.17,100.22)
  BOTTOM w0.254: PU5403.2 46.76,100.7 47.17,100.3 v1(47.17,100.22)
PWR_2D5V_PG: length 134.3
  TOP w0.127: v2(57.15,2.89) v1(56.56,2.89)
  L3 w0.127: v1(45.54,92.55) 45.54,89.78 44.47,88.71 44.47,83.53 42.21,81.27 42.21,71.09 36.75,65.62 36.75,53.54 34.15,50.93 34.15,44.73 34.59,44.29 34.59,43.02 35.36,42.26 35.36,40.86 37.51,38.7 37.51,31.21 40.05,28.67 40.05,24.22 40.5,23.78 40.5,16.55 41.84,15.21 47.06,15.21 48.25,14.02 v1(48.25,10.95)
  L4 w0.127: v1(48.25,10.95) 48.5,10.69 48.5,4.47 49.2,3.78 55.68,3.78 v1(56.56,2.89)
  BOTTOM w0.127: v1(48.25,10.95) 45.07,10.95 PR5114.1 ; v1(56.56,2.89) 55.45,1.77 53.87,1.77 PR5105.1 ; v1(45.54,92.55) 44.58,93.51 43.14,93.51 42.59,94.06 42.59,95.5 42.06,96.03 PR5410.2 41.88,96.04 41.43,96.5 39.8,96.5 38.94,97.36 38.76,97.36 38.33,97.79 38.33,98.34 38.5,98.52 38.5,100.96 38.94,101.39 39.5,101.39 40.18,100.7 PU5403.7
PWR_3D3V:
  vias: v2(160.96,51.12) v3(158.82,51.43) v3(158.82,50.51) v3(158.8,49.67) v3(159.66,51.4) v3(159.66,50.51) v3(159.69,49.62) v3(162.44,51.43) v3(162.44,50.54) v3(162.44,49.65) v3(163.32,51.43) v3(163.32,50.56) v3(163.32,49.67)
PWR_3D3V_BOOT: length 2.9
  BOTTOM w0.254: PU4501.1 158.79,57.56 v2(158.27,57.04)
  BOTTOM w0.508: v2(158.27,57.04) 158.18,56.95 PR4501.1
PWR_3D3V_BOOT_A: length 2.2
  BOTTOM w0.508: PC4506.1 157.16,55.77 PR4501.2 157.01,55.62 v2(155.88,55.62)
PWR_3D3V_EN: length 4.7
  BOTTOM w0.127: PR4509.2 PR4508.1 163.22,62.2 163.24,62.22 PC4508.1 163.32,61.54 v2(163.22,61.43) 162.53,60.75 PU4501.11
PWR_3D3V_EN1: length 131
  TOP w0.127: PR4516.2 95.22,104.99 v1(94.97,104.74) ; v1(165.82,61.73) v2(165.82,61.15)
  L3 w0.127: v1(94.97,104.74) 95.27,105.05 96.52,105.05 97.04,105.57 97.54,105.57 98.91,104.2 98.91,104.16 100.02,103.05 102.45,103.05 103.49,102.01 112.32,102.01 114.67,104.36 118.59,104.36 122.77,108.54 129.16,108.54 130.06,109.44 158.31,109.44 161.9,105.85 v1(161.9,103.83)
  L6 w0.127: v1(161.9,103.83) 163.4,103.83 164.09,103.13 164.09,102.06 164.48,101.68 164.48,99.17 167.21,96.44 167.21,94.68 168.77,93.12 168.77,79.59 166.83,77.65 165.94,77.65 164.35,76.06 164.35,63.81 165.82,62.34 v1(165.82,61.73)
  BOTTOM w0.127: PU4501.12 163.11,58.91 163.69,59.49 163.69,61.24 PC4532.1 164.18,61.74 PR4514.1 165.01,61.73 v1(165.82,61.73)
PWR_3D3V_FB: length 2
  BOTTOM w0.254: PC4533.1 163.89,59.1 163.26,58.46 PU4501.13
PWR_3D3V_FB2: length 1.8
  BOTTOM w0.254: v2(164.97,60.8) 165.05,60.72 PR4506.2 164.36,59.88 PC4533.2
PWR_3D3V_LDO: length 1.7
  TOP w0.254: PG4532.1 162.81,56.96 v1(162.71,56.86) 162.71,56.46 v2(162.89,56.28)
PWR_3D3V_PH: length 8.2
  TOP w0.254: v2(160.83,54.3) v3(159.66,54.3)
  L6 w0.508: v3(159.66,55.21) 159.69,55.24 159.69,58.51 160.35,59.17 v1(160.35,60.88)
  BOTTOM w0.254: v1(160.35,60.88) 160.21,60.74 PU4501.6
PWR_3D3V_VOUT: length 10.7
  BOTTOM w0.254: PU4501.14 163.35,58.01 163.97,58.64 164.67,58.64 PR4506.1 165.48,59.02 165.73,58.77 165.73,54.86 v2(164.97,54.09) 164.21,53.33 PG4530.1
PWR_3V_PG: length 5
  TOP w0.127: PR4505.2 162.74,60.16 PG4531.2 162.84,60.6 162.56,60.88 v2(162.56,61.03) 162.08,61.03 v1(161.82,60.93)
  BOTTOM w0.127: PU4501.10 162.01,60.74 v1(161.82,60.93) 161.56,60.66 PU4501.9
PWR_5V:
  vias: v2(110.13,108.2) v2(114.35,108.04) v3(109.73,103.28) v3(110.62,103.28) v3(111.48,103.28) v3(112.37,103.37) v3(112.6,107.31) v3(112.57,106.42) v3(112.65,105.5) v3(112.65,104.61) v3(113.49,107.31) v3(113.46,106.42) v3(113.54,105.5) v3(113.54,104.61)
PWR_5V_BOOT: length 2.1
  TOP w0.254: 100.57,108.3 PU4502.1
  TOP w0.508: 100.57,108.3 100.57,108.45 100.29,108.73 PR4502.1
PWR_5V_BOOT_A: length 2.4
  TOP w0.508: PR4502.2 102,109.29 102.46,109.74 v2(102.83,109.74) 102.83,108.88 102.78,108.83 PC4521.1
PWR_5V_EN: length 7.9
  TOP w0.254: v2(91.62,103.22) 92.05,103.65 PR4511.2 92.53,103.66 93.39,103.66 PR4512.1 93.42,103.66 94.28,103.66 PC4530.1 94.5,103.47 v1(94.99,103.47) ; v1(98.02,104.46) 98.02,104.46 PU4502.11
  BOTTOM w0.254: v1(94.99,103.47) 95.27,103.47 95.65,103.85 97.56,103.85 98.02,104.31 v1(98.02,104.46)
PWR_5V_EN1: length 9
  TOP w0.254: PR4504.2 94.26,100.4 94.77,100.4 94.99,100.17 v2(95.58,100.17) PC4531.1 96.37,100.83 PR4513.1 96.26,101.24 96.54,101.52 97.13,101.52 97.36,101.74 97.36,103.14 97.66,103.45 98.88,103.45 99.22,103.78 PU4502.12
PWR_5V_EN1_R: length 4.8
  TOP w0.254: 95.7,103.28 96.56,103.28 PR4515.2 ; 95.7,103.28 PR4503.2 ; 95.7,103.28 95.7,102.97 95.79,102.88 v2(95.79,102.38) 95.6,102.19 95.6,101.29 95.29,100.97 94.98,100.97 PR4530.1 94.87,100.98 94.49,101.36 PR4504.1
PWR_5V_FB: length 2.5
  TOP w0.254: PU4502.13 99.67,102.84 PC4526.1 99.64,102.76 PR4551.1
PWR_5V_FB_A: length 0.8
  TOP w0.254: PC4526.2 99.59,101.9 PR4507.1
PWR_5V_LDO: length 7.1
  TOP w0.254: PG4528.1 101.45,103.58 v1(101.37,103.66) PU4502.15
  BOTTOM w0.254: PC4520.1 104.77,100.96 v2(103.45,100.96) 103.38,100.96 101.37,102.96 v1(101.37,103.66)
PWR_5V_PG: length 6.2
  TOP w0.127: PR4510.1 94.26,104.53 PG4529.2 v1(94.97,105.38) ; PU4502.9 97.57,105.43 v1(97.25,105.12) 97.39,104.98 PU4502.10
  BOTTOM w0.127: v1(94.97,105.38) 94.97,105.37 95.22,105.12 v1(97.25,105.12)
PWR_5V_PH: length 6.8
  TOP w0.254: v1(97.25,106.77) 97.27,106.78 PU4502.6
  BOTTOM w0.508: v3(102.97,107.03) 98.6,107.03 98.35,106.77 v1(97.25,106.77)
  vias: v2(104.49,106.14) v3(102.97,106.14) v3(102.97,105.25) v3(103.56,108.8) v3(103.68,107.92) v3(103.73,103.28) v3(104.49,108.77) v3(104.52,107.93) v3(104.62,103.28) v3(105.33,108.77) v3(105.36,107.93) v3(105.51,103.28) v3(106.17,108.78) v3(106.27,107.93) v3(106.35,103.22)
PWR_5V_VCC:
  vias: v2(102.77,103.95)
PWR_5V_VOUT: length 55.2
  TOP w0.254: PU4502.14 100.12,103.58 v1(100.2,103.49) ; v1(98.12,101.52) 98.12,102.02 PR4507.2
  BOTTOM w0.254: v1(98.12,101.52) 98.12,102.3 97.61,102.81 96.21,102.81 95.91,102.51 94.46,102.51 93.52,103.45 93.52,108.3 95.81,110.58 v2(106.6,110.58) 107.49,110.58 107.82,110.25 PG4527.1 107.36,109.82 107.11,110.07 96.06,110.07 94.03,108.04 94.03,103.6 94.66,102.96 95.58,102.96 95.88,103.27 99.97,103.27 v1(100.2,103.49)
PWR_ASGATE: length 5
  TOP w0.254: PC4436.2 148.44,34.94 148.05,35.33 v1(148.05,35.42) 148.03,35.4 148.03,35.35 147.75,35.07 v2(147.75,34.76)
  BOTTOM w0.203: PU4401.30 145.98,34.06 146.28,34.36 146.3,34.36
  BOTTOM w0.254: v1(148.05,35.42) 148.03,35.4 148.03,35.38 147.54,34.89 147.06,34.89 146.53,34.36 146.3,34.36
PWR_CHG_1: length 8.8
  TOP w0.254: v1(150.29,36.92) 150.29,37.06 149.35,38 v2(149.35,38.24) 148.43,39.17 PD4402.K 148.43,40.64 148.13,40.94 v1(148.08,40.94)
  BOTTOM w0.254: v1(150.29,36.92) 150.95,36.92 PD4405.K ; PD4401.K 148.08,40.56 v1(148.08,40.94) 146,40.94 PR4407.2
PWR_CHG_ACDET: length 4.1
  BOTTOM w0.203: 145.18,32.59 PU4401.1
  BOTTOM w0.254: 145.18,32.59 145.49,32.27 146.27,32.27 PR4408.2 146.73,32.58 PC4413.1 146.81,31.74 PR4409.1
PWR_CHG_ACN: length 7.1
  TOP w0.254: v1(146.78,33.87) 146.78,34.43 146.1,35.12 PC4404.1 145.68,35.12 145.68,35.67 145.9,35.88 v2(145.9,36.01)
  BOTTOM w0.203: PU4401.31 146.05,33.66 146.26,33.87 v1(146.78,33.87)
  BOTTOM w0.254: v1(146.78,33.87) 147.27,34.36 PC4402.2 147.73,34.36 148.62,35.25 PR4414.2
PWR_CHG_ACOK: length 16.7
  TOP w0.102: PR4463.2 137.06,31 v1(136.78,31.28) 136.78,31.69 v2(136.52,31.94) ; v1(145.57,31.46) 145.57,31.46 145.57,32.07 PG4408.1 145.11,33.05 144.62,33.54 PR4422.2 144.19,33.54 143.69,33.04 PR4443.2
  L4 w0.102: v1(136.78,31.28) 137.34,31.84 145.19,31.84 v1(145.57,31.46)
  BOTTOM w0.102: PU4401.2 144.18,32.19 144.4,31.97 145.16,31.97 145.57,31.56 145.57,31.46 v1(145.57,31.46)
PWR_CHG_ACP: length 5.7
  TOP w0.254: v1(146.46,33.33) 146.25,33.54 v2(146.25,34.03) 145.97,34.31 PC4403.1
  BOTTOM w0.203: PU4401.32 146.38,33.26 146.44,33.33 v1(146.46,33.33)
  BOTTOM w0.254: v1(146.46,33.33) 146.49,33.37 147,33.37 147.07,33.44 PC4402.1 147.43,33.44 147.96,33.98 148,33.98 148.49,34.46 PR4444.2
PWR_CHG_BATDRV: length 3
  BOTTOM w0.203: PU4401.25 145.62,36.06 145.74,36.19 145.74,36.57
  BOTTOM w0.254: PC4437.2 146.66,38.21 145.74,37.29 145.74,36.57
PWR_CHG_BATPRES#: length 3.2
  BOTTOM w0.203: PU4401.13 140.37,34.86 140.26,34.75 139.6,34.75
  BOTTOM w0.254: PR4449.1 138.17,34.79 v2(139.13,34.79) 139.56,34.79 139.6,34.75
PWR_CHG_BTST: length 3.4
  TOP w0.508: PR4447.1 146.48,39.16 v2(146.48,38.07) 146.48,37.61 146.02,37.15 146.01,37.15 145.64,36.78 145.64,36.77 145.44,36.57 v1(145.08,36.57)
PWR_CHG_BTST1: length 3
  TOP w0.254: PC4414.1 145.16,41.27 145.44,41.55 v2(145.77,41.55) 146.15,41.55 146.45,41.24 PR4447.2
PWR_CHG_COMP: length 5.2
  BOTTOM w0.203: PR4416.1 139.34,33.37 140.33,33.37 140.63,33.66 PU4401.10
  BOTTOM w0.254: PC4427.1 137.95,32.12 138.23,31.84 v2(138.68,31.84) 138.68,32.71 PR4416.1
PWR_CHG_FSET: length 3.4
  TOP w0.254: v1(140.08,34.23) 139.75,34.23 v2(139.14,33.62) 139.22,33.54 140.08,33.54 PR4430.1
  BOTTOM w0.203: v1(140.08,34.23) 140.31,34.46 PU4401.12
PWR_CHG_HIDRV: length 14.5
  TOP w0.508: v3(145.54,38.24) 145.54,37.81 v2(145.31,37.58)
  L6 w1.016: v3(147.83,50.36) 147.21,50.36 146.35,49.5 146.35,40.17
  BOTTOM w0.203: v3(145.54,38.24) 145.54,37.81 145.18,37.46 144.44,37.46 144.18,37.2 PU4401.23
PWR_CHG_IADP: length 3
  TOP w0.254: v2(141.83,32) 142.28,31.54 v1(142.28,31.41) 142.26,31.4 142.26,31.38 141.96,31.07 PG4401.1
  BOTTOM w0.203: PU4401.6 142.58,31.95 142.28,31.66 v1(142.28,31.41)
PWR_CHG_IDCHG: length 4.4
  TOP w0.254: PG4414.1 140.51,30.7 140.26,30.95 v2(140.26,31.56) 140.79,31.56 v1(140.95,31.41)
  BOTTOM w0.203: v1(140.95,31.41) 140.95,31.64 141.23,31.93 141.97,31.93 142.18,32.13 PU4401.7
PWR_CHG_ILIM: length 8
  TOP w0.254: PR4423.1 139.85,32.73 139.5,32.38 138.91,32.38 v2(138.89,32.35) 138.68,32.55 138.68,34.16 138.73,34.21 v1(138.73,34.28)
  BOTTOM w0.203: v1(138.73,34.28) 138.74,34.29 139.01,34.29 139.51,33.79 140.27,33.79 140.55,34.06 PU4401.11
  BOTTOM w0.254: v1(138.73,34.28) 138.68,34.28 138.56,34.15 137.67,34.15 137.26,34.56 PR4420.2
PWR_CHG_LODRV: length 4.3
  L6 w1.016: 143.56,39.16 143.56,39.87 142.09,41.34
  BOTTOM w0.203: PU4401.21 143.38,37.34 143.61,37.57 v3(143.61,38.14)
  vias: v2(141.91,42.49) v3(142.16,43.45)
PWR_CHG_NTC: length 2.7
  TOP w0.254: v1(141.4,37.43) 141.91,37.43 v2(142.04,37.31) 142.17,37.18 PR4437.1
  BOTTOM w0.203: v1(141.4,37.43) 141.4,36.92 141.58,36.74 PU4401.17
PWR_CHG_PHASE: length 7
  L6 w1.016: 147.6,37.02 149.05,38.47 149.05,41.65
  BOTTOM w0.203: v3(144.58,38.17) 144.58,38.07 143.78,37.27 PU4401.22
  vias: v2(148.26,42.87) v3(147.52,49.27) v3(147.57,44.75) v3(147.57,43.86) v3(148.39,49.29) v3(148.44,44.7) v3(148.41,43.83)
PWR_CHG_PHASE_1:
  vias: v2(155.62,43.27)
PWR_CHG_PMON: length 3.7
  BOTTOM w0.203: PU4401.8 141.01,32.59
  BOTTOM w0.254: PG4415.1 140.89,30.55 140.39,31.05 v2(140.39,31.28) 140.39,31.97 141.01,32.59
PWR_CHG_PROCHOT#: length 2
  TOP w0.089: v1(142.92,31.41) 142.87,31.36 PG4419.1
  BOTTOM w0.089: PU4401.5 142.98,31.47 v1(142.92,31.41)
PWR_CHG_PROG: length 1.6
  BOTTOM w0.203: PU4401.9 140.64,33.26 140.24,32.86 PR4433.1
PWR_CHG_REGN: length 13
  TOP w0.254: v1(142.9,37.86) 142.9,38.29 v2(143.41,38.8) 143.41,38.8 143.94,39.33 PR4412.2 143.41,40.4 PC4431.1
  L4 w0.254: v1(142.9,37.86) 141.5,36.47 139.14,36.47 138.76,36.08 v1(138.73,36.08)
  BOTTOM w0.203: PU4401.20 142.98,37.78 v1(142.9,37.86)
  BOTTOM w0.254: PR4420.1 137.06,35.75 137.06,36.64 v2(137.08,36.67) 137.84,36.67 PR4421.1 138.45,36.52 138.73,36.24 v1(138.73,36.08)
PWR_CHG_SCL: length 2.8
  TOP w0.089: PG4410.2 143.64,30.95 v1(143.64,31.41) 143.64,31.95 v2(143.54,32.05)
  BOTTOM w0.089: v1(143.64,31.41) 143.66,31.44 143.66,31.74 143.38,32.02 PU4401.4
PWR_CHG_SDA: length 2.5
  TOP w0.089: v1(144.27,31.41) 144.27,31.27 144.44,31.1 144.44,31.09 144.83,30.7 PG4409.2
  BOTTOM w0.089: PU4401.3 143.78,32.02 144.27,31.53 v1(144.27,31.41)
PWR_CHG_SRN: length 11
  TOP w0.254: v2(139.94,41.41) 139.94,41.35 140.63,40.66 PR4448.2 140.84,39.84 PC4420.2 140.77,39.41 140.21,38.85 140.21,37.26 139.6,36.65 139.6,35.63 140.03,35.2 v1(140.08,35.2) 140.16,35.27 140.92,35.27 141.24,35.58 141.6,35.58 141.78,35.4 PC4422.1
  BOTTOM w0.203: v1(140.08,35.2) 140.15,35.26 PU4401.14
PWR_CHG_SRN_1: length 12.8
  TOP w0.254: v1(140.89,42.18) 140.89,41.57 PR4448.1
  BOTTOM w0.254: PG4413.2 151.23,40.76 150.77,40.76 149.81,41.72 v2(148.89,41.72) 145.24,41.72 144.84,42.13 143.5,42.13 142.99,41.62 141.45,41.62 v1(140.89,42.18)
PWR_CHG_SRP: length 9.6
  TOP w0.254: PC4421.1 141.71,35.97 141.08,35.97 140.77,35.65 140.36,35.65 v1(140.16,35.86) 139.98,36.03 139.98,36.49 140.59,37.1 140.59,38.69 141.67,39.77 PC4420.1 141.65,39.79 PR4411.2
  BOTTOM w0.203: v1(140.16,35.86) 140.35,35.66 PU4401.15
  BOTTOM w0.254: v2(139.72,36.29) v1(140.16,35.86)
PWR_CHG_SRP_1: length 13.8
  TOP w0.254: PR4411.1 141.4,41.77 141.4,42.39 140.98,42.82 v1(140.86,42.82)
  BOTTOM w0.254: v1(140.86,42.82) 140.98,42.82 141.66,42.13 142.78,42.13 143.29,42.64 145.05,42.64 145.46,42.23 150.02,42.23 v2(150.54,41.71) 150.98,41.27 151.41,41.27 PG4412.2
PWR_CHG_VCC: length 6.5
  BOTTOM w0.203: v2(142.09,38.73) 141.8,38.44 141.8,37.71 142.18,37.33 PU4401.18
  BOTTOM w0.508: v2(142.09,38.73) 142.31,38.95 143.71,38.95 PC4412.1 145.77,39.39 PR4407.1
PWR_CMSRC: length 5.2
  TOP w0.254: v1(147.42,35.53) 147.42,35.7 v2(147.75,36.03) 148.33,36.62 PR4410.1 PC4436.1
  BOTTOM w0.203: 146.02,34.61 145.87,34.46 PU4401.29
  BOTTOM w0.254: v1(147.42,35.53) 147.24,35.35 146.96,35.35 146.35,34.74 146.14,34.74 146.02,34.61
PWR_DCBATOUT_1D0V: length 1.5
  TOP w0.508: v2(149.07,5.3) v1(148.48,5.3) 148.26,5.52 PR5201.1
PWR_DCBATOUT_1D2V:
  vias: v2(51.81,8.2) v3(46.4,8.6) v3(50.47,8.47) v3(51.09,7.84) v3(51.13,5.73) v3(51.99,5.73)
PWR_DCBATOUT_3D3V:
  vias: v2(160.35,61.46)
PWR_DCBATOUT_5V:
  vias: v2(96.8,108.14)
PWR_OPCN: length 3.6
  BOTTOM w0.203: 147.21,36.09 146.87,35.75 146.76,35.75 v2(146.43,35.42) 146.1,35.09 146,35.09 145.77,34.86 PU4401.28
  BOTTOM w0.254: 148.13,36.41 147.54,36.41 147.21,36.09
PWR_OPCP: length 5.5
  BOTTOM w0.127: PU4401.27 145.75,35.26 146.06,35.57 146.06,35.58 146.28,35.79 146.28,35.79 146.63,36.14
  BOTTOM w0.254: 146.63,36.14 146.65,36.14 v2(147.04,36.53) 147.04,36.75 147.5,37.2 148.66,37.2 PC4426.1
PWR_VBAT: length 4.6
  TOP w0.254: v1(146.28,36.52) 146.48,36.52 v2(146.81,36.84)
  BOTTOM w0.203: PU4401.26 145.71,35.66 146.28,36.23 v1(146.28,36.52)
  BOTTOM w0.254: v1(146.28,36.52) 146.28,36.94 146.65,37.3 PC4437.1 146.73,37.3 PR4403.1
PWR_VCCGT_BOOTA: length 4
  BOTTOM w0.203: PU4801.35 144.24,92.76 144.7,92.29 144.7,92.26
  BOTTOM w0.508: PR4802.1 144.74,90.34 v2(144.51,90.57) 144.51,91.13 144.77,91.38 144.77,92.2 144.7,92.26
PWR_VCCGT_BOOTA_RC: length 2.3
  BOTTOM w0.508: v2(147.89,90.34) PR4802.2 PC4809.1
PWR_VCCGT_COMP: length 4.3
  TOP w0.254: v1(157.49,91.25) 157.12,90.89 v2(157.12,90.16) 157.12,89.23 157.19,89.17 PC4617.2 157.15,89.2 PC4618.2
  BOTTOM w0.203: PU4601.4 v1(157.49,91.25)
PWR_VCCGT_COMP_R: length 2.5
  TOP w0.254: PR4631.2 157.2,87.52 v2(157.05,87.37) 156.67,87.37 156.26,87.78 PC4618.1
PWR_VCCGT_CSCOMP: length 30.9
  TOP w0.254: v2(158.29,87.34) 158.04,87.6 v1(157.73,87.6)
  L6 w0.254: v1(146.23,72.61) 146.1,72.74 146.1,73.24 146.99,74.13 150.8,74.13 153.59,76.93 155.12,76.93 157.28,79.09 157.28,87.14 v1(157.73,87.6)
  BOTTOM w0.203: PU4601.6 156.69,91.6 156.67,91.59 156.67,90.92 156.69,90.9 156.69,90.4 156.69,90.39
  BOTTOM w0.254: 156.69,90.39 PC4621.1 PC4620.1 157.04,88.75 PR4639.2 157.64,89.09 PR4640.1 157.88,88.31 157.88,87.75 v1(157.73,87.6) ; PR4634.2 146.4,72.43 v1(146.23,72.61)
PWR_VCCGT_CSN: length 39.1
  TOP w0.254: v2(154.52,104.27) v1(154.13,103.88)
  L3 w0.254: v1(154.13,103.88) 154.13,104.11 153.64,104.59 151.05,104.59 148.89,102.43 148.89,93.69 143.05,87.85 137.08,87.85 136.19,88.74 v1(136.19,88.87)
  BOTTOM w0.254: PR4680.2 154.71,103.6 154.43,103.88 v1(154.13,103.88) ; v1(136.19,88.87) 136.19,89.96 PR4633.1 136.14,90.69 133.75,93.08 PG4809.1
PWR_VCCGT_CSN_L: length 5.1
  BOTTOM w0.203: PU4601.28 155.49,98.88 155.27,99.1 v2(155.27,99.28) 155.27,99.36 154.46,100.17 PC4634.2
  BOTTOM w0.254: PC4634.2 PC4616.2 154.81,101.34 PC4647.2 154.81,102.38 PR4680.1
PWR_VCCGT_CSP: length 42.4
  TOP w0.254: v1(157.25,102.33) 156.26,102.33 v2(155.7,101.77)
  L3 w0.254: v1(135.02,93.72) 135.02,92.88 138.16,89.75 142.75,89.75 144.81,91.81 144.81,92.15 147.24,94.58 147.24,103.34 149.66,105.76 155.37,105.76 156.56,104.56 156.56,103.01 v1(157.25,102.33)
  BOTTOM w0.254: PR4627.2 156.56,101.64 v1(157.25,102.33) ; v1(135.02,93.72) 135.43,94.12 PG4808.1
PWR_VCCGT_CSP1: length 5
  TOP w0.254: v1(154.39,90.7) 154.53,90.56 PC4623.2 153.97,89.32 PR4651.2 154,89.02 154.61,89.02 v2(154.86,88.76)
  BOTTOM w0.203: v1(154.39,90.7) 154.51,90.7 154.81,91 154.84,91 155.14,91.3 155.14,91.33 155.16,91.35 155.16,91.71 155.09,91.77 PU4601.10
PWR_VCCGT_CSP2: length 5.7
  BOTTOM w0.203: PU4601.9 155.49,91.91 155.54,91.86 155.54,91.14
  BOTTOM w0.254: PR4676.2 154.15,90.14 153.85,90.44 v2(153.85,90.97) ; PR4676.2 154.15,89.04 PC4641.2 ; PR4676.2 PR4678.2 154.96,90.56 155.54,91.14
PWR_VCCGT_CSREF: length 15.6
  TOP w0.254: PR4677.1 151.61,87.55 v1(151.94,87.22) 152.33,86.83 v2(154,86.83) 154.35,86.83 154.94,86.25 155.5,86.25 155.8,86.55 155.8,87.52 155.45,87.88 PC4623.1 155.43,89.89 155.43,90.31 v1(155.7,90.58) 155.93,90.81 PC4646.1
  BOTTOM w0.203: 155.92,91.1 155.92,92.02 155.89,92.05 PU4601.8
  BOTTOM w0.254: PC4641.1 153.26,88.69 PR4646.1 151.94,87.37 v1(151.94,87.22) ; v1(155.7,90.58) 155.92,90.8 155.92,91.1
PWR_VCCGT_CSSUM: length 9.6
  TOP w0.254: PR4637.2 153.19,87.34 154.71,87.34 v1(155.29,86.76)
  BOTTOM w0.203: PU4601.7 156.29,90.78 156.3,90.76
  BOTTOM w0.254: 156.3,90.76 156.3,90.48 v2(156.23,90.41) 156.2,90.38 156.2,90.37 155.78,89.94 PC4621.2 PC4620.2 155.78,88.03 PR4638.2 155.14,87.98 PR4679.2 154.79,87.27 v1(155.29,86.76)
PWR_VCCGT_DIFFOUT: length 4.6
  TOP w0.254: v1(158.5,90.7) 158.5,90.44 PR4626.1 159.74,89.98 PR4625.1 160.5,90.06 v2(160.73,90.29)
  BOTTOM w0.203: PU4601.2 158.29,91.82
  BOTTOM w0.254: 158.29,91.82 158.38,91.73 158.38,90.84 158.5,90.72 v1(158.5,90.7)
PWR_VCCGT_DISB#_A: length 3.6
  BOTTOM w0.203: v2(142.97,90.39) 142.97,90.95 142.58,91.34 PU4801.2
  BOTTOM w0.254: v2(142.97,90.39) 143.69,90.39 144.32,89.75 PR4808.2
PWR_VCCGT_FB: length 6.2
  TOP w0.254: v2(159.89,88) 159.6,88.29 159.59,88.28 PC4614.2 158.9,88.31 PR4631.1 158.09,88.33 PC4617.1 PR4626.2 158.08,90 158.08,90.29 157.86,90.51 v1(157.86,90.69)
  BOTTOM w0.203: 157.89,91.66 PU4601.3
  BOTTOM w0.254: 157.89,91.66 158,91.55 158,91.04 157.86,90.91 v1(157.86,90.69)
PWR_VCCGT_FB_R: length 1.9
  TOP w0.254: PC4614.1 PR4625.2 160.5,89.2 v2(160.73,88.97)
PWR_VCCGT_ICCMAX: length 3.7
  TOP w0.254: PR4662.1 153.27,95.01 153.04,94.78 v1(151.68,94.78)
  BOTTOM w0.203: PU4601.18 153.14,95.02 153.08,94.96
  BOTTOM w0.254: 153.08,94.96 v2(152.45,94.96) 151.87,94.96 v1(151.68,94.78)
PWR_VCCGT_ILIM: length 3.4
  BOTTOM w0.203: PU4601.5 157.09,91.54 157.01,91.45 157.01,91.05 157.09,90.97 157.09,90.68 v2(157.53,90.24)
  BOTTOM w0.254: PR4640.2 158.15,89.62 v2(157.53,90.24)
PWR_VCCGT_ILIM_R: length 25.7
  TOP w0.254: v1(156.31,87.01) v2(156.31,86.38)
  L6 w0.254: v1(145.59,72.61) 145.72,72.74 145.72,73.4 146.83,74.51 150.64,74.51 153.43,77.31 154.96,77.31 156.89,79.24 156.89,86.43 v1(156.31,87.01)
  BOTTOM w0.254: v1(156.31,87.01) 156.31,87.7 PR4638.1 156.84,88.23 PR4639.1 ; v1(145.59,72.61) 145.54,72.56 PR4634.1
PWR_VCCGT_IOUT: length 4.4
  TOP w0.254: PR4632.2 156.83,92.23 156.69,92.1 v2(156.69,91.3) 156.82,91.3 157.41,91.89 PC4615.2 158.57,91.89 v1(158.88,91.58)
  BOTTOM w0.203: PU4601.1 158.69,92.03 158.85,91.86
  BOTTOM w0.254: 158.85,91.86 158.85,91.62 v1(158.88,91.58)
PWR_VCCGT_NTC: length 27.8
  TOP w0.254: v1(150.8,72.74) v2(150.8,73.37)
  L3 w0.254: v1(150.8,72.74) 150.8,73.29 155.75,78.24 155.75,78.26 156.18,78.69 156.18,82.61 156.82,83.25 156.82,87.52 154.66,89.68 151.51,89.68 v1(150.67,90.52)
  BOTTOM w0.254: v1(150.67,90.52) 150.59,90.44 PR4661.1 PR4655.1 ; PR4656.2 150.8,71.92 v1(150.8,72.74)
PWR_VCCGT_PHASEDA:
  vias: v2(144.91,93.13)
PWR_VCCGT_PWMA: length 16.2
  TOP w0.254: v1(141.76,90.9) 142.14,91.28 142.8,91.28 145.72,94.2 v2(149.22,94.2) 149.22,94.28 149.53,94.58 149.53,95.72 150.42,96.61 v1(151.43,96.61)
  BOTTOM w0.203: PU4801.4 141.78,90.93 v1(141.76,90.9) ; v1(151.43,96.61) 151.92,97.1 152.47,97.1 152.95,96.62 PU4601.22
PWR_VCCGT_SNUB_1: length 1
  BOTTOM w0.508: PC4810.1 135.57,99.12 PR4804.2
PWR_VCCGT_SWA:
  vias: v2(140,99.51)
PWR_VCCGT_TSENSE: length 5.8
  TOP w0.254: PC4630.1 155.24,92.08 v2(155.24,91.36) 154.79,91.36 v1(154.64,91.5)
  BOTTOM w0.203: v1(154.64,91.5) 154.69,91.55 PU4601.11
  BOTTOM w0.254: v1(154.64,91.5) 153.43,91.5 152.37,90.44 PR4655.2
PWR_VCCGT_VCCA: length 4.5
  BOTTOM w0.203: PU4801.6 140.98,91.4 140.77,91.18 140.77,89.68 PC4808.1
  BOTTOM w0.254: PC4808.1 PR4803.1 141.48,88.43 141.76,88.15 v2(141.88,88.15)
PWR_VCCGT_VSN: length 4.5
  BOTTOM w0.203: 159.49,92.29 159.34,92.44 PU4601.48
  BOTTOM w0.254: 159.49,92.29 159.51,92.27 v2(159.51,90.62) 160.02,90.11 160.02,89.7 PR4619.2 159.18,89.65 PC4612.2
PWR_VCCGT_VSN_R: length 3.6
  BOTTOM w0.254: PR4618.2 161.57,88.76 PC4611.2 160.75,88.79 PR4619.1 159.94,88.76 PC4612.1 159.15,88.18 v2(158.85,87.88)
PWR_VCCGT_VSP: length 5.4
  BOTTOM w0.203: 159.92,92.45 159.92,93.25 159.75,93.42 PU4601.47
  BOTTOM w0.254: 159.92,92.45 159.92,91.43 v2(160.73,90.62) 160.73,90.59 160.78,90.54 PC4611.1 161.65,89.68 PR4617.2
PWR_VCCSA_BST: length 2.8
  BOTTOM w0.305: PU5001.1 154.12,55.04
  BOTTOM w0.508: 154.12,55.04 154.12,56.03 v2(154.07,56.07) 153.95,56.2 PR5013.1
PWR_VCCSA_BST_RC: length 2.3
  BOTTOM w0.508: PR5013.2 151.31,56.56 v2(150.57,56.56) 150.42,56.4 PC5008.1
PWR_VCCSA_COMP: length 4.5
  TOP w0.254: v1(160.81,94.71) 161.12,94.4 v2(161.12,94.02) 160.75,94.02 160.32,94.45 PC4604.2
  BOTTOM w0.203: PU4601.43 160.52,95.02 160.81,94.73 v1(160.81,94.71)
  BOTTOM w0.254: v1(160.81,94.71) 161.06,94.96 PC4602.2
PWR_VCCSA_COMP_R: length 5
  TOP w0.254: PR4602.2 160.35,93.49 161.49,93.49 v2(162.33,94.33) 162.33,94.89 162.61,95.17 162.61,95.17 162.91,95.47 162.91,95.47 v1(163.07,95.62)
  BOTTOM w0.254: PC4602.1 162.51,95.07 163.06,95.62 v1(163.07,95.62)
PWR_VCCSA_CSN: length 58.6
  TOP w0.254: v1(163.12,94.96) 163.45,94.96 v2(163.65,95.17)
  L3 w0.254: v1(138.92,60.8) 138.92,60.97 141.67,63.72 150.16,63.72 151.31,62.58 153.95,62.58 156.28,64.91 156.28,76.48 157.28,77.47 157.28,82.02 158.57,83.32 158.57,90.05 159,90.49 159,90.69 162.66,94.34 162.66,94.54 162.96,94.83 162.99,94.83 v1(163.12,94.96)
  BOTTOM w0.254: v1(163.12,94.96) 163.17,94.91 PR4681.2 ; PG5022.1 138.92,57.13 v1(138.92,60.8) 138.92,61.42 PR4606.2
PWR_VCCSA_CSN_L: length 6.2
  BOTTOM w0.203: 160.47,95.82 PU4601.41
  BOTTOM w0.254: PR4681.1 163.75,96.16 PC4648.1 162.99,96.54 162.53,96.08 v2(162.36,96.08) 162.1,96.33 PC4607.1 161.54,96.87 PC4606.1 161.32,96.66 160.47,95.82
PWR_VCCSA_CSN_NTC: length 55
  TOP w0.254: v2(163.37,93.69) 163.17,93.9 v1(163.17,94.33)
  L3 w0.254: v1(163.17,94.33) 163.17,94.31 159.39,90.53 159.39,90.33 158.95,89.9 158.95,83.16 157.66,81.86 157.66,77.31 156.67,76.32 156.67,64.75 154.11,62.2 153.8,62.2 153.8,62.2 151.15,62.2 150.01,63.34 141.83,63.34 139.8,61.31 v1(139.8,60.8)
  BOTTOM w0.254: PR4606.1 v1(139.8,60.8) ; PR4609.2 164.51,94.77 164.29,94.54 164.06,94.33 v1(163.17,94.33)
PWR_VCCSA_CSP: length 59.8
  TOP w0.254: v2(140.28,58.64) 140.16,58.51 v1(140.16,57.98)
  L3 w0.254: v1(165.24,95.33) 165.24,94.92 160.73,90.42 160.73,90.09 160.04,89.4 160.04,82.62 158.67,81.25 158.67,76.8 157.68,75.81 157.68,64.02 155.09,61.43 150.29,61.43 149.51,62.22 142.41,62.22 140.16,59.96 v1(140.16,57.98)
  BOTTOM w0.254: v1(165.24,95.33) 165.61,95.7 PR4612.2 ; PG5021.1 140.59,57.24 140.16,57.67 v1(140.16,57.98)
PWR_VCCSA_CSP1B: length 7.9
  BOTTOM w0.203: 159.93,96.22 PU4601.40
  BOTTOM w0.254: 159.93,96.22 160.33,96.22 160.67,96.56 160.67,96.91 PC4606.2 161.54,97.78 PC4607.2 162.41,98.09 163.63,98.09 164.29,97.44 PR4612.1 164.29,96.41 164.51,96.18 PR4609.1
PWR_VCCSA_DRVH: length 10.8
  TOP w1.016: v3(145.49,61.16) 147.35,61.16 ; 147.35,61.16 v2(147.37,61.18) ; 147.35,61.16 149.56,61.16 152.07,58.66 152.07,56.35
  BOTTOM w0.305: v3(151.97,55.19) 152.3,54.85 PU5001.8
PWR_VCCSA_DRVL: length 3.1
  BOTTOM w0.305: 150.86,52.73 151.88,52.73 152.08,52.94 PU5001.5
  BOTTOM w1.016: 149.29,52.73 150.86,52.73
  vias: v2(148.41,52.37)
PWR_VCCSA_ICCMAX: length 4.4
  TOP w0.254: PR4660.1 153.13,96.66 152.32,95.85 151.87,95.85 151.85,95.86 v1(151.89,95.9)
  BOTTOM w0.203: PU4601.20 153.1,95.82 153.05,95.76 152.03,95.76 v1(151.89,95.9)
  BOTTOM w0.254: v1(151.89,95.9) 151.79,96 v2(151.18,96)
PWR_VCCSA_ILIM: length 3.8
  TOP w0.254: PR4611.1 160.09,95.29 PC4632.1 160.66,95.27 v1(160.82,95.43) 161.22,95.43 v2(161.42,95.24)
  BOTTOM w0.203: v1(160.82,95.43) 160.81,95.42 PU4601.42
PWR_VCCSA_IOUT: length 3.4
  TOP w0.254: v2(162.36,96.16) PC4609.1 161.69,96.82 PR4613.1 160.21,96.82 v1(160.16,96.77)
  BOTTOM w0.203: v1(160.16,96.77) 160.01,96.62 PU4601.39
PWR_VCCSA_PWM: length 58
  L6 w0.254: v1(159.43,98.72) 159.48,98.72 161.5,96.71 163.27,96.71 164.11,95.87 164.11,94.45 166.42,92.14 166.42,91.28 165.66,90.52 163.78,90.52 161.62,88.36 161.62,82.57 162.8,81.39 162.8,78.27 160.35,75.81 160.35,64.98 156.89,61.53 156.89,58.11 v1(154.86,56.07)
  BOTTOM w0.203: v1(159.43,98.72) 159.43,98.52 158.99,98.07 PU4601.36
  BOTTOM w0.254: v1(154.86,56.07) 154.86,55.34 155.32,54.88 v2(155.32,54.17) 155.12,53.97 154.15,53.97 PU5001.2
PWR_VCCSA_SNUB: length 2.4
  TOP w0.508: PC5031.1 147.3,55.97 147.19,56.09 v2(147.18,56.09) 147.18,56.1 147.06,56.21 147.06,57.5 PR5014.2
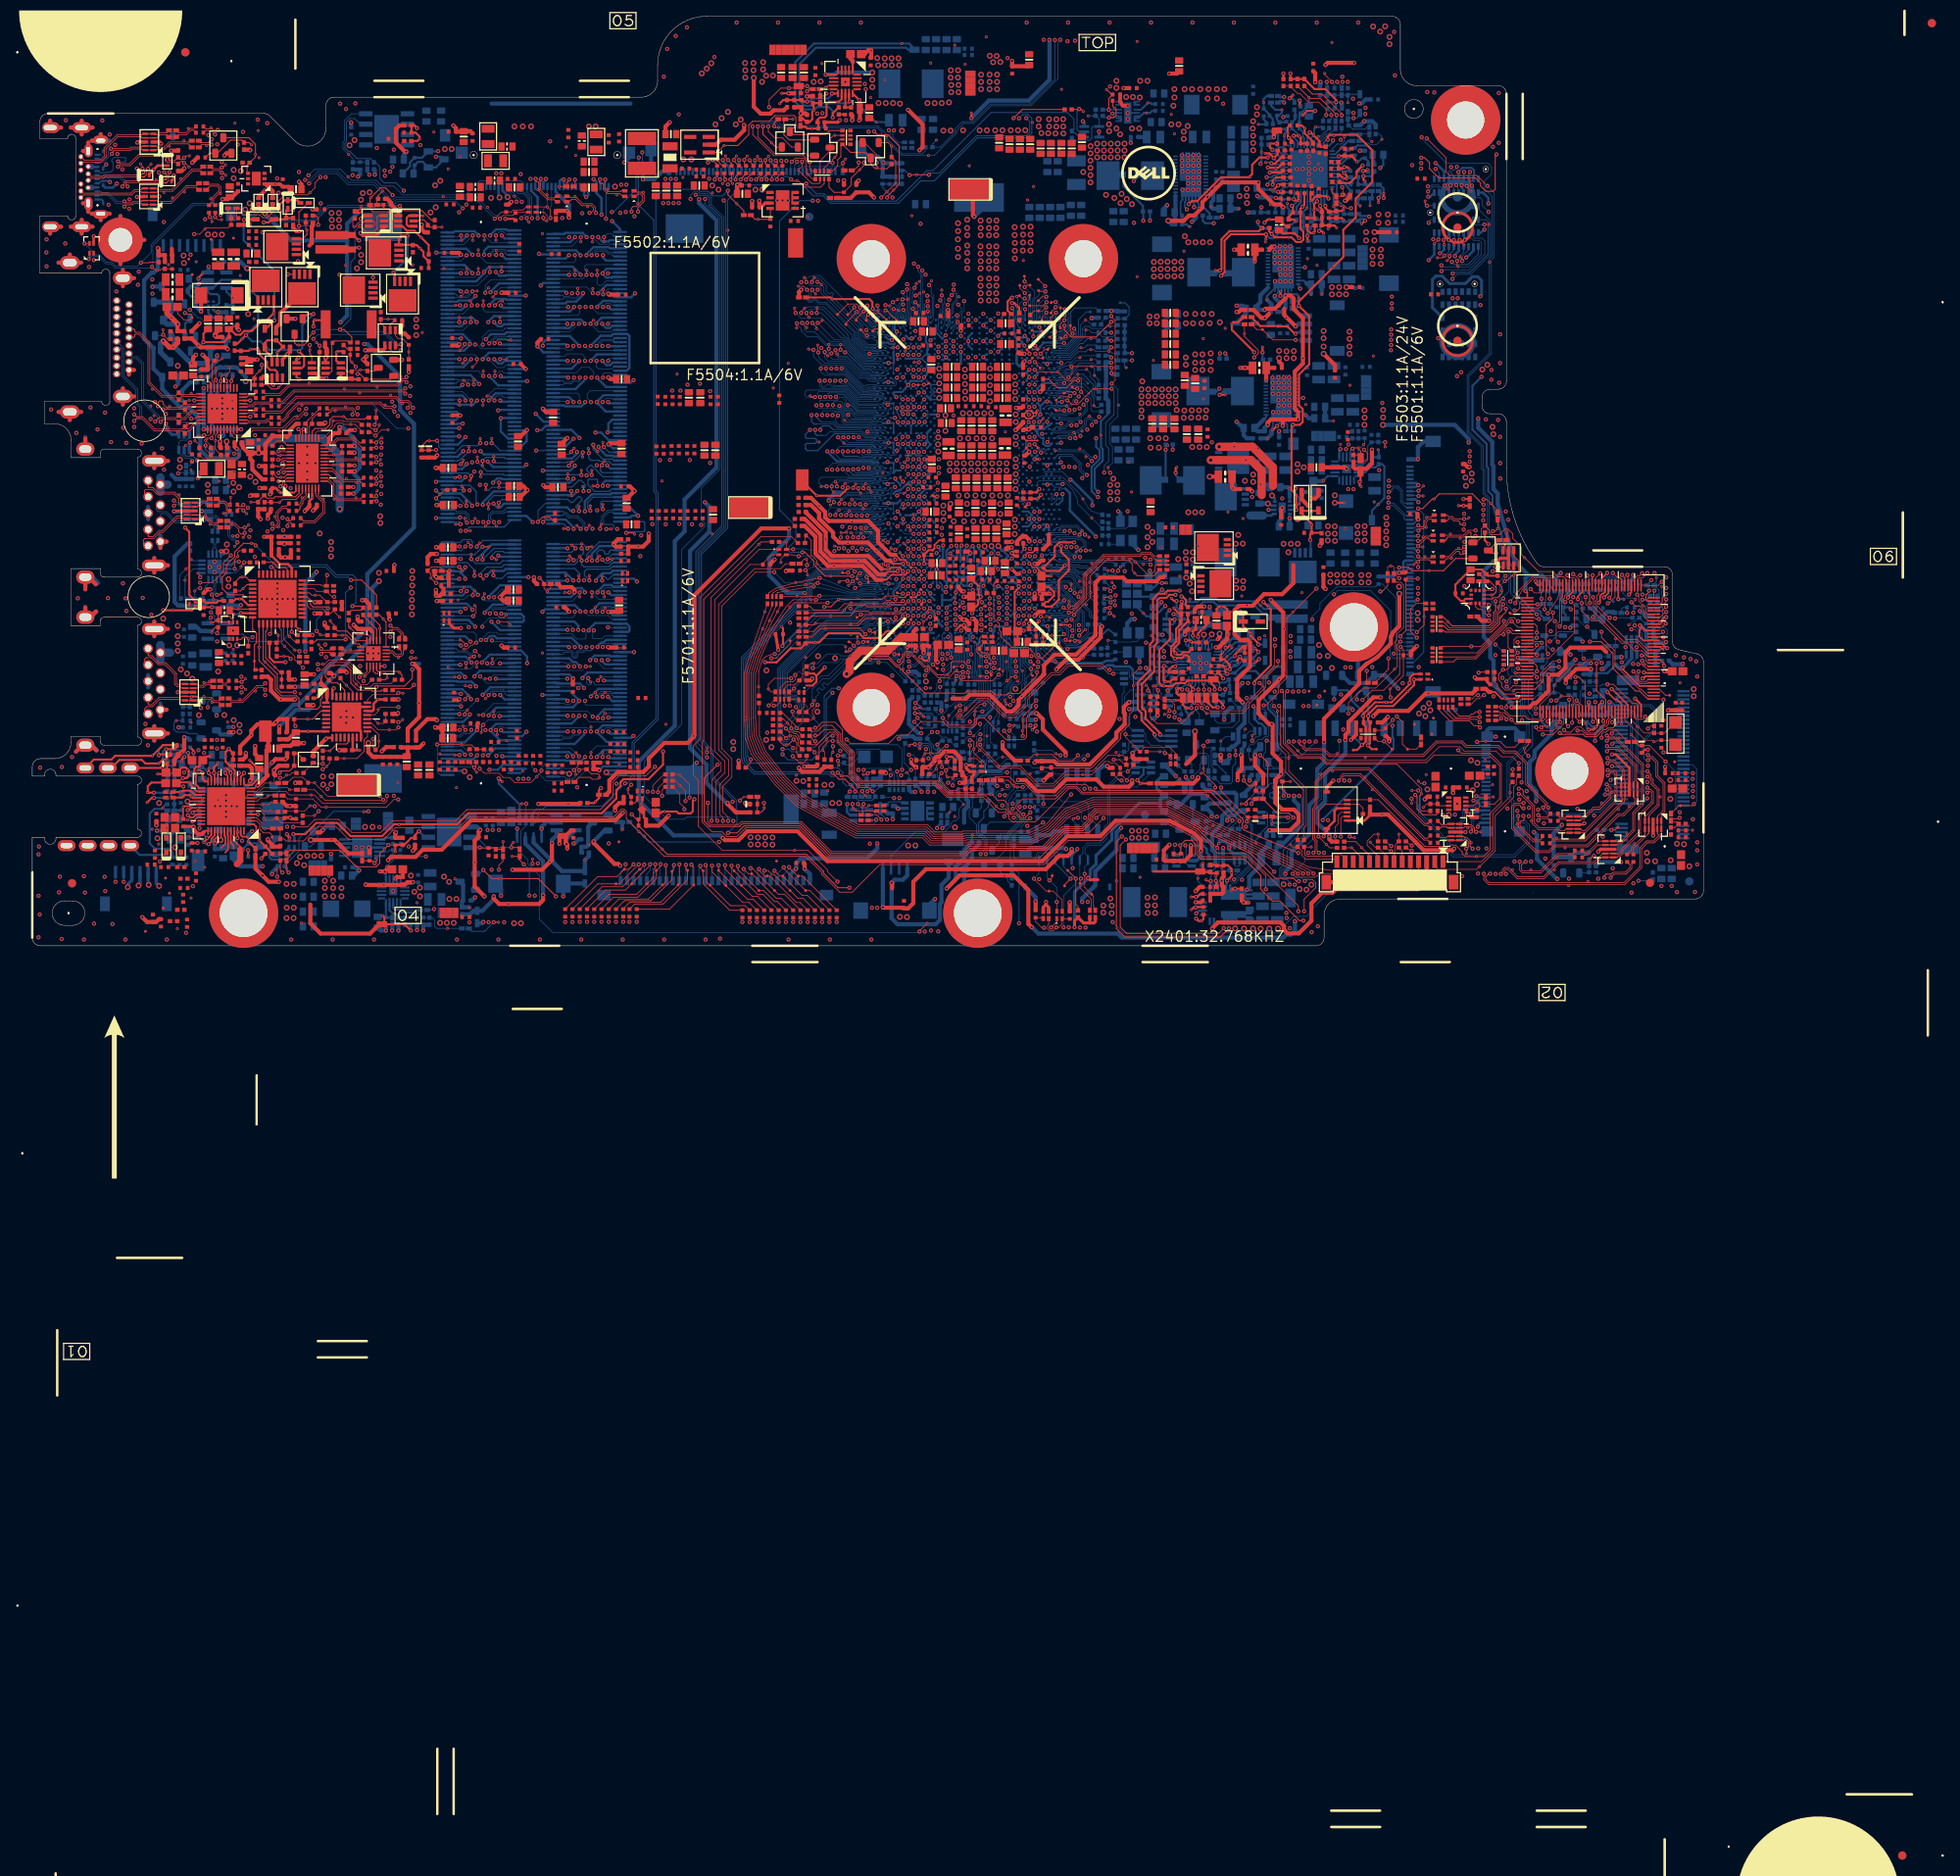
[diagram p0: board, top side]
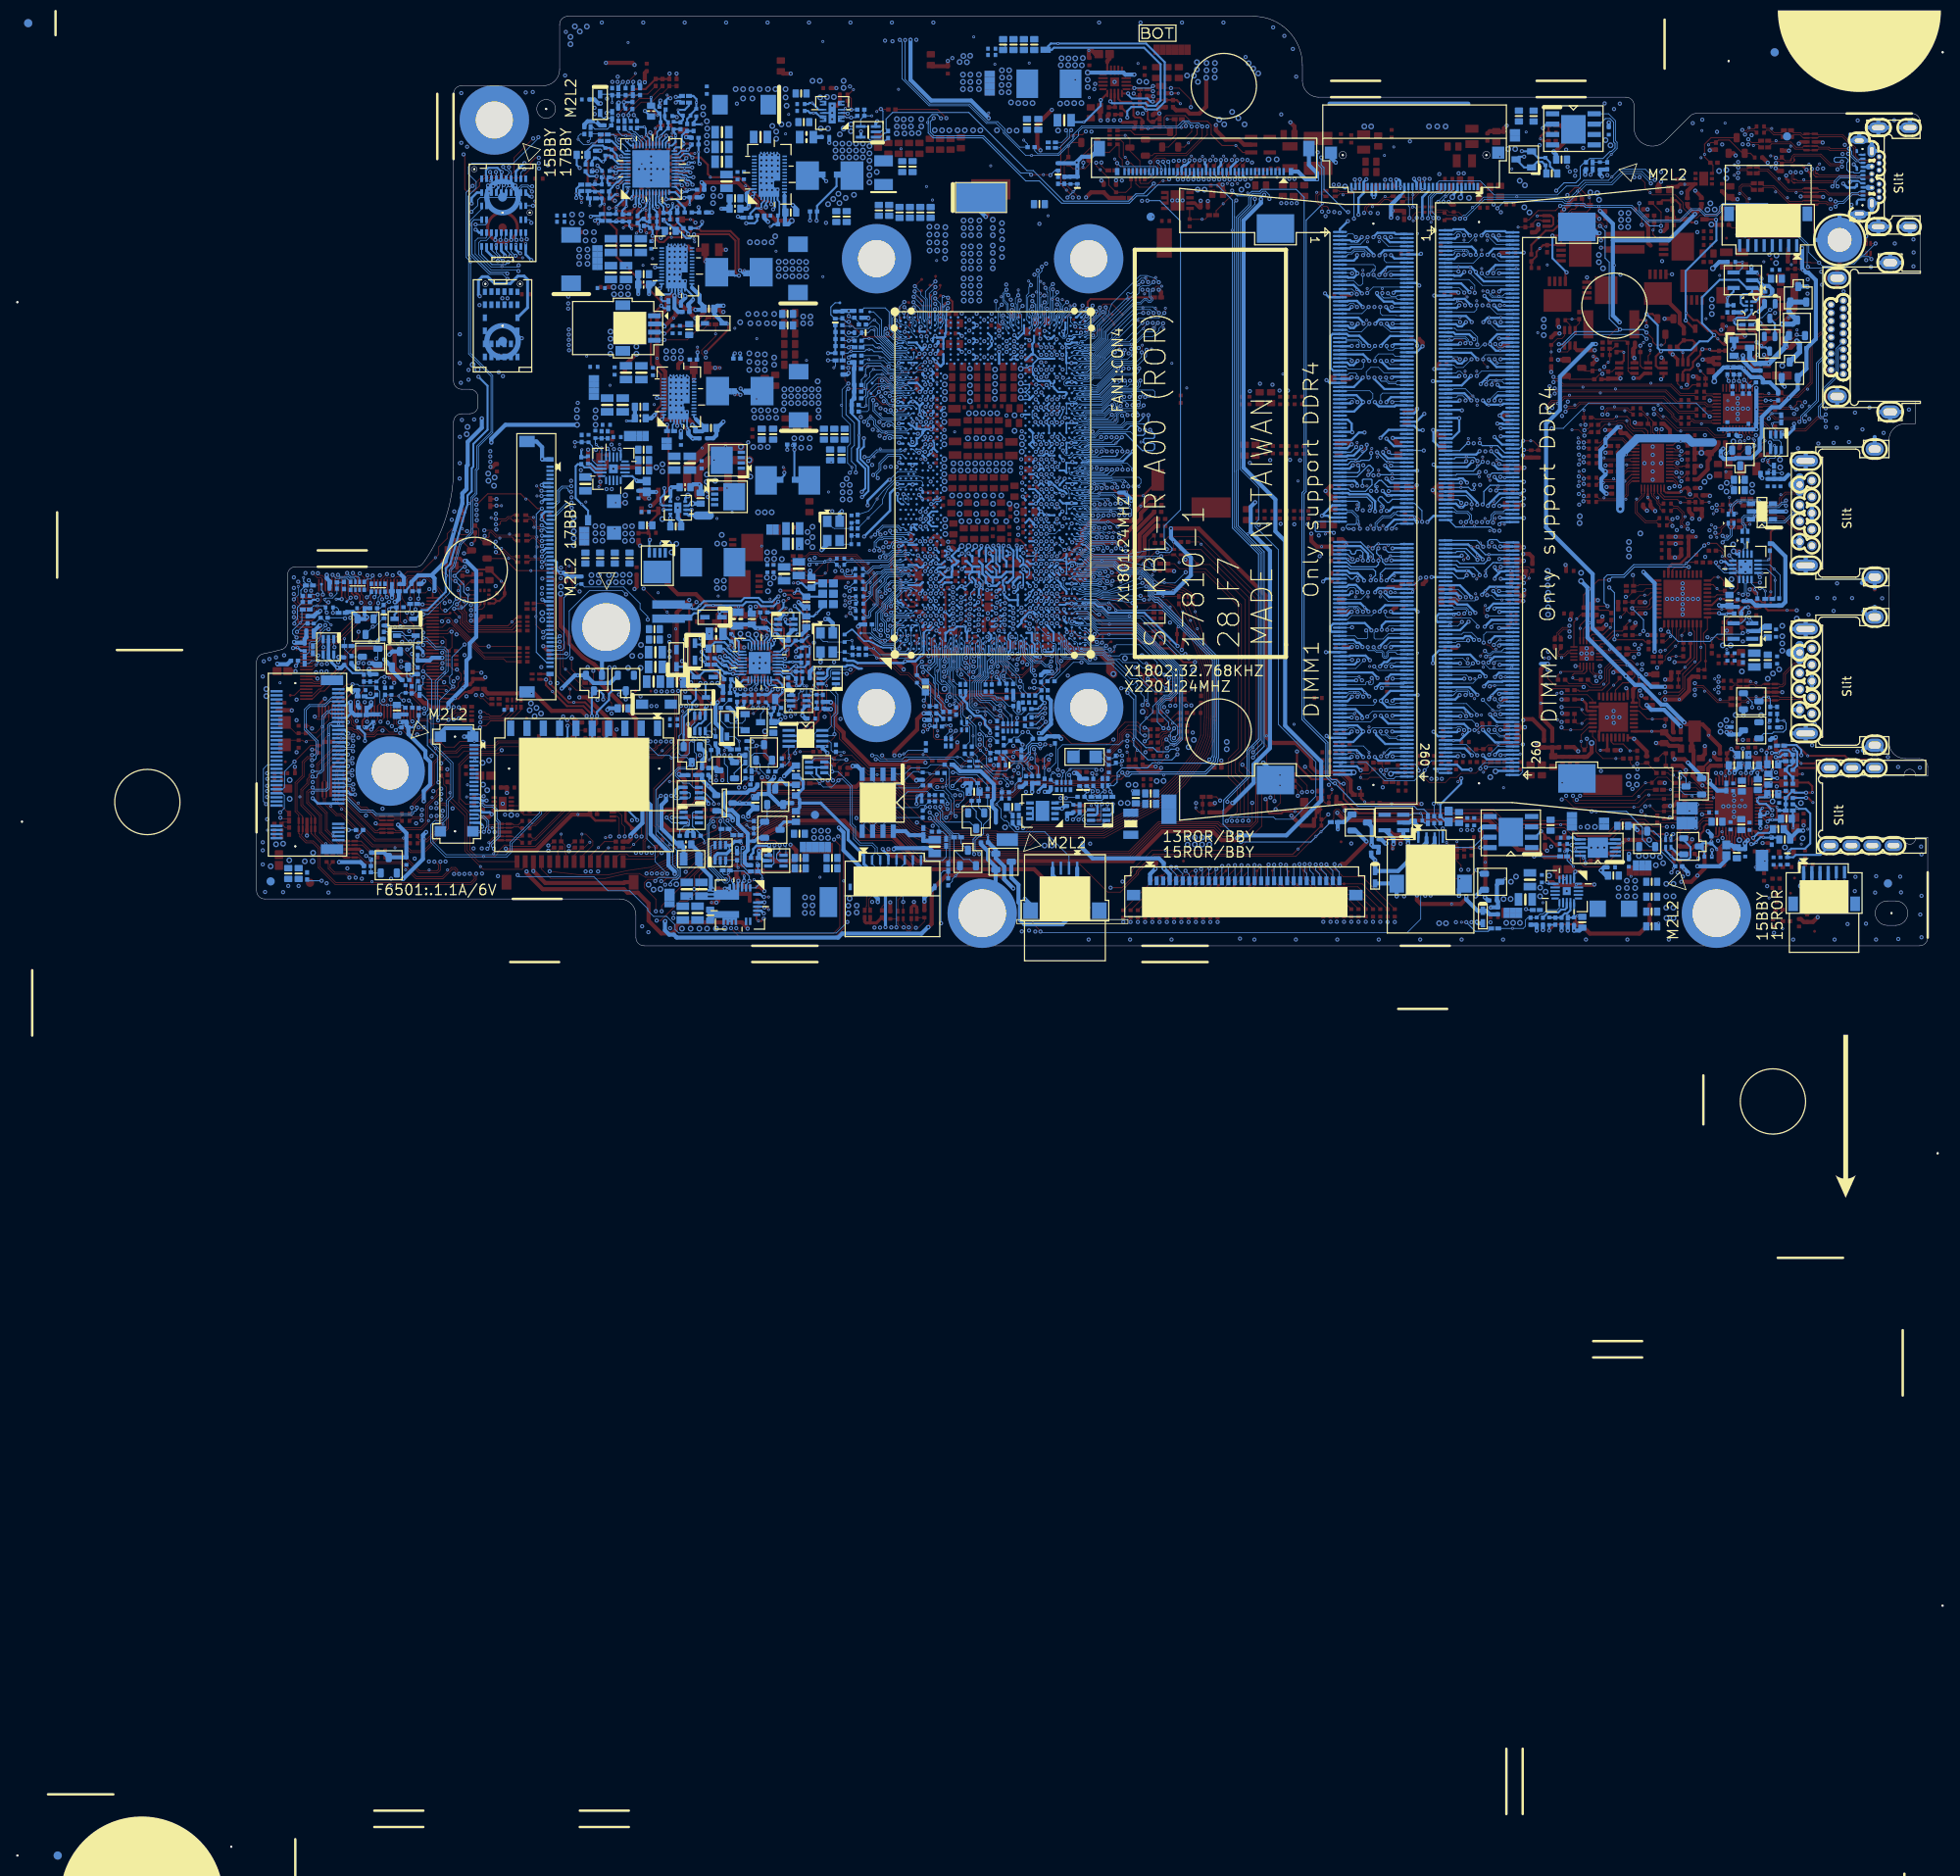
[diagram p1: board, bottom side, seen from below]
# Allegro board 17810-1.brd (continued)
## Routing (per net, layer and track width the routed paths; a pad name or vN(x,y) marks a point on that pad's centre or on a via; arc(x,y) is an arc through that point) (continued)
PWR_VCCSA_SW: length 12.8
  TOP w0.508: PR5014.1 v3(144.32,57.5)
  TOP w1.016: v3(144.45,59.53) v2(148.77,59.53) 149.4,59.53 150.7,58.23 150.7,55.24
  BOTTOM w0.305: PU5001.7 151.92,53.94 151.66,54.19 v3(151.46,54.19)
  BOTTOM w0.508: PC5008.2 v3(151.46,54.19)
PWR_VCCSA_VSN: length 3.6
  BOTTOM w0.203: PU4601.44 160.08,94.62 160.38,94.32
  BOTTOM w0.254: PC4603.2 161.63,93.31 161.84,93.52 161.84,94 PR4605.2 161.22,94.2 161.1,94.07 v2(160.72,94.07) 160.63,94.07 160.38,94.32
PWR_VCCSA_VSN_R: length 2.6
  BOTTOM w0.254: PR4604.2 163.42,93.29 PC4605.2 163.17,93.31 PC4603.1 162.51,93.34 PR4605.1
PWR_VCCSA_VSP: length 5.2
  BOTTOM w0.203: PU4601.45 159.93,94.22 160.19,93.95
  BOTTOM w0.254: v2(160.6,92.08) 160.93,92.08 161.4,91.61 PC4608.2 161.64,91.62 PR4608.2 161.64,92.56 161.21,92.98 161.21,93.06 160.66,93.61 160.53,93.61 160.19,93.95
PWR_VCCSA_VSP_R: length 3.7
  BOTTOM w0.254: v2(163.99,90.72) 163.99,91.5 PR4616.1 164.23,91.74 164.23,92.46 PR4607.2 163.46,92.51 PC4605.1 163.34,92.45 PR4608.1
PWR_VCCSA_VSP_RC: length 1.7
  BOTTOM w0.254: v2(162.77,90.68) 162.52,90.93 162.52,91.61 PC4608.1 162.54,91.61 PR4616.2
PWR_VCORE_ADDR_BOOT: length 4.1
  TOP w0.254: PR4663.1 152.65,97.02 v1(152.17,96.54) 152.17,96.59 151.64,97.12 v2(151.13,97.12)
  BOTTOM w0.203: v1(152.17,96.54) 152.49,96.22 PU4601.21
PWR_VCORE_ALERT#: length 3.4
  BOTTOM w0.114: PU4601.33 157.49,98.47 158.5,99.48 158.88,99.48 159.11,99.71 159.26,99.71 159.74,100.19 PR4666.2
PWR_VCORE_BOOT1: length 2.6
  BOTTOM w0.203: 156.01,65.12 155.65,65.48 PU4701.35
  BOTTOM w0.508: 156.01,65.12 v2(156.11,65.02) 156.46,64.66 PR4701.1
PWR_VCORE_BOOT2: length 2.9
  BOTTOM w0.203: PU4702.35 155.86,81.52 156.13,81.25
  BOTTOM w0.508: v2(156.74,79.87) PR4711.1 156.34,81.04 156.13,81.25
PWR_VCORE_BOOT_RC1: length 2.6
  BOTTOM w0.254: PR4701.2 158.8,64.33 v2(159.51,64.33)
  BOTTOM w0.508: PR4701.2 PC4706.1
PWR_VCORE_BOOT_RC2: length 2.4
  BOTTOM w0.508: PC4722.1 PR4711.2 v2(158.06,79.87)
PWR_VCORE_COMP: length 3.6
  TOP w0.254: PC4601.1 153.9,100.3 v2(153.9,99.58) 153.9,99.18 v1(154.05,99.03) 154.34,98.74 PC4619.1
  BOTTOM w0.203: v1(154.05,99.03) 154.1,99.03 154.69,98.44 PU4601.26
PWR_VCORE_COMP_R: length 3.4
  TOP w0.254: PC4601.2 155.61,100.55 v2(155.97,100.19) 155.97,99.59 157.02,98.54 PR4636.1
PWR_VCORE_CSNA: length 29.9
  L3 w0.254: v1(150.24,88.72) 150.24,88.68 150.79,88.13 152.51,88.13 154.76,85.88 154.76,81.24 154.43,80.91 154.43,79.37 145.64,70.58 145.64,68.42 v1(145.51,68.29)
  BOTTOM w0.254: v1(145.51,68.29) 145.13,67.91 PG4708.1 ; v1(150.24,88.72) 150.24,88.41 v2(150.67,87.98) 150.7,87.95 PR4646.2
PWR_VCORE_CSNB: length 10.9
  TOP w0.254: PR4677.2 150.37,87.6 146.76,87.6 145.77,86.61 145.77,82.95 v1(145.59,82.77) v2(145.03,82.77)
  BOTTOM w0.254: PG4711.1 145.25,82.43 v1(145.59,82.77)
PWR_VCORE_CSNNTC: length 33.9
  TOP w0.254: v1(155.34,103.6) v2(155.34,103.04)
  L3 w0.254: v1(137.01,88.89) 137.01,88.47 137.24,88.23 142.89,88.23 148.51,93.85 148.51,102.27 148.51,102.59 150.9,104.97 153.97,104.97 v1(155.34,103.6)
  BOTTOM w0.254: v1(137.01,88.89) PR4633.2 ; v1(155.34,103.6) 155.47,103.47 PR4629.2
PWR_VCORE_CSP_1A: length 6.7
  BOTTOM w0.203: PU4601.29 155.89,99.02 155.75,99.15 155.75,99.74 PC4634.1
  BOTTOM w0.254: PC4634.1 PC4616.1 155.32,101.85 PR4629.1 156.44,102.96 PR4627.1 v2(156.49,103.99)
PWR_VCORE_CSPA: length 32.7
  TOP w0.254: v1(145.54,67.53) v2(146.23,67.53) ; v1(151.05,88.64) 151.43,89.02 v2(151.66,89.02) PR4637.1 153.68,88.17 153.69,88.18 PR4651.1
  L3 w0.254: v1(151.05,88.64) 152.54,88.64 155.14,86.03 155.14,81.08 154.81,80.75 154.81,79.21 146.02,70.42 146.02,68.01 v1(145.54,67.53)
  BOTTOM w0.254: v1(145.54,67.53) 145.96,67.95 PG4707.1
PWR_VCORE_CSPB: length 16.3
  TOP w0.254: v1(145.72,82.13) 146.15,82.57 146.15,86.43 146.94,87.21 151.2,87.21 v1(151.23,87.19) v2(151.23,86.63)
  BOTTOM w0.254: PG4712.1 146.26,82.13 v1(145.72,82.13) ; PR4678.1 154.38,88.38 154.23,88.38 PR4679.1 153.06,87.62 152.15,86.71 151.7,86.71 v1(151.23,87.19)
PWR_VCORE_DISB#1: length 1.5
  BOTTOM w0.203: PU4701.2 153.68,64.01 153.85,63.85 153.85,63.26 PR4704.2
PWR_VCORE_DISB#2: length 3.2
  BOTTOM w0.203: 154.19,79.85 153.94,80.1 PU4702.2
  BOTTOM w0.254: PR4714.2 155.04,79.01 155.24,79.21 v2(155.24,79.42) 155.24,79.62 155.01,79.85 154.19,79.85
PWR_VCORE_DRVON: length 80.1
  TOP w0.254: v1(158.79,98.8) 158.79,98.82 158.8,98.84 158.8,99.15 159.05,99.41 162.36,99.41 164.26,97.5 164.26,93.62 162.23,91.58 v2(162.23,90.9) 162.23,89.27 160.7,87.75 160.7,84.42 v2(159.42,83.13) 155.24,78.96 v1(155.24,78.45) 156.51,77.18 156.51,71.26 155.27,70.02 155.27,66.23 155.73,65.78 155.73,64.2 155.37,63.85 154.58,63.85 154.56,63.87 v1(154.52,63.87) 154.35,63.7 154.35,55.86 154.94,55.28 v1(154.94,53.44)
  L4 w0.254: v1(158.79,98.8) 158.77,98.8 158.35,98.39 151.81,98.39 149.53,96.1 149.53,95.6 146.61,92.68 146.61,90.91 145.85,90.15 v1(145.85,89.37)
  BOTTOM w0.203: PU4601.35 158.29,98.46 158.63,98.8 v1(158.79,98.8)
  BOTTOM w0.254: PR4714.1 154.94,78.15 v1(155.24,78.45) ; v1(154.94,53.44) PU5001.3 ; PR4704.1 154.52,63.09 v1(154.52,63.87) ; PR4808.1 145.72,89.25 v1(145.85,89.37)
PWR_VCORE_EN: length 3.8
  BOTTOM w0.127: PR4630.1 161.09,99.43 v2(160.83,99.18) 160.83,98.98 160.83,98.62 160.48,98.26 159.94,98.26 159.34,97.67 PU4601.37
PWR_VCORE_ICCMAX: length 4.2
  TOP w0.254: PR4658.1 153.2,95.84 152.7,95.34 v2(152.37,95.34) 151.69,95.34 151.63,95.4 v1(151.45,95.4)
  BOTTOM w0.203: PU4601.19 151.48,95.42 v1(151.45,95.4)
PWR_VCORE_ILIM: length 3.8
  TOP w0.254: v1(154.63,99.29) 155.21,99.29 v2(155.37,99.13) 155.5,99 PC4633.1 156.23,98.34 PR4635.1
  BOTTOM w0.203: v1(154.63,99.29) 154.63,99.08 155.09,98.62 PU4601.27
PWR_VCORE_IOUT: length 4.7
  TOP w0.254: PR4628.1 157.94,97.93 PC4613.1 157.78,98.62 v2(157.05,99.36) 156.72,99.69 v1(156.59,99.69)
  BOTTOM w0.203: v1(156.59,99.69) 156.59,99.55 156.29,99.25 PU4601.30
PWR_VCORE_NTC: length 15.6
  L4 w0.254: v1(144.83,88.56) 145.82,88.56 147.12,89.86 147.12,92.42 v1(150.54,95.85)
  BOTTOM w0.254: v1(150.54,95.85) 150.67,95.98 v2(150.67,97.3) PR4650.2 PR4652.1 ; PR4653.2 143.48,88.87 143.79,88.56 v1(144.83,88.56)
PWR_VCORE_PHASED1:
  vias: v2(156.11,66.34)
PWR_VCORE_PHASED2:
  vias: v2(157.48,83.4)
PWR_VCORE_PWM1: length 41.4
  TOP w0.254: v2(152.07,63.21) v1(152.58,63.72)
  L6 w0.254: v1(151.41,93.28) 151.43,93.31 151.43,93.39 151.83,93.79 153.2,93.79 158.29,88.7 158.29,78.83 156.28,76.83 156.28,66.54 154.1,64.35 153.18,64.35 152.58,63.75 v1(152.58,63.72)
  BOTTOM w0.203: v1(151.41,93.28) 151.56,93.43 151.56,93.56 151.81,93.82 152.07,93.82 152.35,94.1 152.84,94.1 152.95,94.22 PU4601.16 ; v1(152.58,63.72) 152.88,64.03 PU4701.4
PWR_VCORE_PWM2: length 25.9
  TOP w0.254: v2(152.98,80.2) v1(152.98,79.65)
  L4 w0.254: v1(151.31,94.2) 153.21,94.2 157.02,90.39 157.02,80.99 154.99,78.96 153.47,78.96 152.98,79.44 v1(152.98,79.65)
  BOTTOM w0.203: PU4702.4 153.14,79.9 152.98,79.75 v1(152.98,79.65) ; PU4601.17 153.25,94.62 153.21,94.58 152.7,94.58 152.58,94.45 152.2,94.45 151.94,94.2 v1(151.31,94.2)
PWR_VCORE_ROSC_COREGT: length 2.4
  TOP w0.254: v2(152.2,92.7) 152.21,92.7 v1(152.71,93.2) 152.79,93.29 PR4664.1
  BOTTOM w0.203: PU4601.14 152.92,93.42 v1(152.71,93.2)
PWR_VCORE_ROSC_SAUS: length 3.8
  TOP w0.254: PR4659.1 152.45,94.17 v2(152.27,93.99) 152.04,93.77 v1(152.04,93.29)
  BOTTOM w0.203: PU4601.15 153.02,93.82 152.98,93.77 152.53,93.77 v1(152.04,93.29)
PWR_VCORE_SCLK: length 4
  BOTTOM w0.114: PR4665.2 160.5,99.76 160.05,99.31 v2(159.59,99.31) 159.56,99.31 159.5,99.24 158.6,99.24 158.35,98.99 158.35,98.96 157.89,98.5 PU4601.34
PWR_VCORE_SDIO: length 3.1
  BOTTOM w0.114: PR4667.2 158.98,100.15 158.57,99.74 158.42,99.74 157.86,99.18 v2(157.65,99.18) 157.09,98.62 PU4601.32
PWR_VCORE_SNUB1: length 2.5
  TOP w0.508: v2(151.26,69.36) PR4703.2 PC4709.1
PWR_VCORE_SNUB2: length 2.3
  TOP w0.508: v2(149.86,83.86) PR4713.2 PC4727.1
PWR_VCORE_SW1: length 1.5
  TOP w0.508: PR4703.1 v1(148.64,70.83) v2(148.05,70.83)
PWR_VCORE_SW2: length 0.9
  TOP w0.508: PR4713.1 v1(147.32,85.31)
  vias: v2(151.15,86.28)
PWR_VCORE_TSENSE: length 4.4
  TOP w0.254: v1(151.99,97.58) 151.71,97.86 v2(151.71,98.26) 151.76,98.31 PC4628.1
  BOTTOM w0.203: PU4601.23 153.2,97.02 152.79,97.43 152.14,97.43 v1(151.99,97.58)
  BOTTOM w0.254: v1(151.99,97.58) 151.53,98.04 PR4650.1
PWR_VCORE_VCC1: length 3.4
  BOTTOM w0.203: PU4701.6 152.08,63.61 151.92,63.44 PR4702.1
  BOTTOM w0.457: 151.92,62.7 PR4702.1
  BOTTOM w0.508: PC4708.1 151.36,62.2 v2(151.38,62.17) 151.92,62.7
PWR_VCORE_VCC2: length 3.6
  BOTTOM w0.203: 151.89,80.18 152.16,80.45 PU4702.6
  BOTTOM w0.254: v2(151.35,79.19) 151.35,79.64 151.89,80.18
  BOTTOM w0.508: PR4712.1 151.79,78.32 PC4728.1 151.92,78.62 v2(151.35,79.19)
PWR_VCORE_VCC_R: length 3.9
  TOP w0.254: v1(152.71,92.4) 152.86,92.25 153.21,92.25 153.35,92.38 PC4631.1
  BOTTOM w0.203: PU4601.13 153.46,93.02 152.84,92.4 v1(152.71,92.4)
  BOTTOM w0.254: v1(152.71,92.4) 152.07,92.4 v2(151.79,92.68) 151.78,92.67 PR4657.2
PWR_VCORE_VR_RDY: length 3.2
  BOTTOM w0.203: PU4601.38 159.71,97.02 159.98,97.29
  BOTTOM w0.254: 159.98,97.29 160.45,97.76 v2(160.45,97.81) 160.47,97.81 161.31,98.64 PR4670.1
PWR_VCORE_VRHOT#: length 3.5
  BOTTOM w0.203: PU4601.31 156.69,98.95 157.12,99.38 157.12,100.16 v2(157.32,100.35)
  BOTTOM w0.254: v2(157.32,100.35) 158.08,100.35 PR4668.1
PWR_VCORE_VRMP: length 4.4
  TOP w0.254: v1(152.44,91.66) 152.53,91.57 PC4629.1
  BOTTOM w0.254: v2(151.75,90.84) PR4601.2 152.36,91.73 v1(152.44,91.66) 152.83,91.66 153.53,92.36 PU4601.12
PWR_VCORE_VSN: length 3.5
  BOTTOM w0.203: PU4601.25 153.91,98.07 153.86,98.13
  BOTTOM w0.254: PR4644.1 152.91,100.09 PC4622.1 153.72,99.74 153.49,99.51 v2(153.49,99.28) 153.49,98.49 153.86,98.13
PWR_VCORE_VSN_R: length 4.8
  BOTTOM w0.254: PC4622.2 153.64,100.93 PR4644.2 152.58,101.24 PC4625.1 152.8,101.74 153.17,102.12 v2(153.17,102.45) 152.37,102.45 151.84,102.99 PR4645.1
PWR_VCORE_VSP: length 4.6
  BOTTOM w0.203: PU4601.24 153.63,97.69 153.47,97.86
  BOTTOM w0.254: 153.47,97.86 152.78,97.86 152.45,98.19 v2(152.45,98.29) 152.45,98.44 152.7,98.7 152.7,99.33 152.17,99.86 PR4647.1 PR4649.1
PWR_VCORE_VSP_R: length 4.6
  BOTTOM w0.254: PR4647.2 152.07,101.34 PC4625.2 151.66,101.87 PC4627.2 150.95,103.34 v2(150.93,103.37) 150.93,103.78 151.31,104.16 PR4648.1
PWR_VCORE_VSP_RC: length 2.1
  BOTTOM w0.254: PC4627.1 150.95,101.29 151.28,100.95 PR4649.2 151.23,100.68 v2(150.29,100.68)
Q6204_G: length 5.5
  TOP w0.254: R6510.1 137.02,19.89 v2(135.85,19.89) v1(135.46,20.29)
  BOTTOM w0.254: v1(135.46,20.29) 136.22,21.05 136.22,21.86 ; Q6504.5 136.22,21.86 ; 136.22,21.86 Q6504.2
Q6205_Q: length 3.7
  BOTTOM w0.381: Q6503.D 141.27,19.71 140.64,20.34 v2(140.64,20.44) 139.93,19.73 R6503.2
Q6502_D: length 2.6
  BOTTOM w0.381: Q6502.D 140.68,14.7 140.19,15.18 R6514.1
Q9102.G: length 6.6
  TOP w0.089: v1(30.37,20.59) 30.83,20.59 v2(31.16,20.92) 31.57,20.92 31.82,21.17 R9129.1
  BOTTOM w0.089: v1(30.37,20.59) 30.37,19.11 29.8,18.54 Q9102.G
RESET_OUT#: length 108.7
  TOP w0.102: KBC24.73 184.17,39.44 184.43,39.18 v1(184.43,38.39) ; v2(169.9,20.18) 170.18,19.9 v1(170.64,19.9)
  L4 w0.102: v1(170.64,19.9) 170.98,20.25 174.51,20.25 175.96,21.71 177.34,21.71 177.72,22.09 177.72,24.56 179.59,26.43 180.27,26.43 180.28,26.44 180.44,26.47 182.05,26.47 183.31,27.72 183.31,37.27 v1(184.43,38.38) ; v1(102.36,18.94) 103.17,19.75 111.2,19.75 111.73,19.22 117.04,19.22 117.83,20.01 119.72,20.01 121.16,18.57 124.16,18.57 125.02,17.71 126.83,17.71 127.23,18.11 128.46,18.11 128.79,18.44 130.67,18.44 133.15,20.92 139.53,20.92 139.83,21.23 140.36,21.23 140.46,21.12 141.58,21.12 141.91,20.79 142.08,20.79 v1(142.19,20.67)
  L6 w0.102: v1(170.64,19.9) 169.09,19.9 168.83,19.65 153.59,19.65 151.89,21.35 142.87,21.35 v1(142.19,20.67)
  BOTTOM w0.102: Q2602.G 143.13,22.24 143.13,21.61 v1(142.19,20.67) ; ED1704.1 103.06,19.59 102.84,19.37 102.83,19.37 102.6,19.14 102.56,19.14 v1(102.36,18.94) 102.36,18.91 102.51,18.76 R1706.1
REXT: length 4.6
  TOP w0.102: v2(23.24,71.97) 22.99,71.72 R5710.1 22.05,71.45 22.05,69.19 22.29,68.96 U5701.18
RING2: length 5.3
  TOP w0.203: HDA27.29 19.04,17.71 v3(19.02,17.7)
  L6 w0.508: v3(15.54,17.49) 18.83,17.49 19.02,17.69 v3(19.02,17.7)
  vias: v2(16,16.86)
RING2_R: length 12.6
  L3 w1.016: HPMIC1.4 5.55,10.94 13.1,10.94 v3(15.34,13.17)
  vias: v2(15.49,12.46)
RSMRST_PWRGD#: length 5.9
  BOTTOM w0.127: R4031.2 R4030.2 R4033.2 R4029.2 R4032.2 ; R4031.2 161.36,104.36 D4002.K ; R4031.2 v2(161.26,103.34)
RSVD_F65: length 1.7
  TOP w0.102: v1(122.28,73.52) 122.71,73.09 TP612.1
  BOTTOM w0.102: CPU1.F65 122.6,73.2 v1(122.28,73.52)
RSVD_G65: length 1.2
  TOP w0.102: TP613.1 122.25,72.74 v1(122.25,72.56)
  BOTTOM w0.102: v1(122.25,72.56) 121.95,72.86 CPU1.G65
RSVD_TP_AW70: length 5.2
  TOP w0.102: v1(101.93,77.77) 100.99,76.83 TP615.1
  BOTTOM w0.102: CPU1.AW70 104.37,76.39 104.06,76.09 103.55,76.09 103.4,76.24 103.02,76.24 101.93,77.34 v1(101.93,77.77)
RSVD_TP_AW71: length 3.1
  TOP w0.102: TP614.1 103.25,75.58 104.19,75.58 v1(104.49,75.89)
  BOTTOM w0.102: v1(104.49,75.89) 105.05,76.44 CPU1.AW71
RSVD_TP_BA68: length 5.9
  TOP w0.102: v1(101.09,77.69) 99.74,76.34 TP602.1
  BOTTOM w0.102: CPU1.BA68 103.72,75.74 103.58,75.61 103.12,75.61 101.14,77.58 101.14,77.64 v1(101.09,77.69)
RSVD_TP_BA70: length 1.9
  TOP w0.102: v1(103.1,77.16) 103.45,76.8 TP601.1
  BOTTOM w0.102: v1(103.1,77.16) 103.17,77.16 103.43,76.9 103.43,76.88 103.6,76.7 103.63,76.7 103.91,76.41 CPU1.BA70
RSVD_TP_BB68: length 5.5
  TOP w0.102: TP603.1 100.76,78.17 v1(100.76,78.25)
  BOTTOM w0.102: v1(100.76,78.25) 100.76,78.2 100.7,78.13 100.7,77.53 102.29,75.94 102.33,75.94 103.01,75.26 CPU1.BB68
RSVD_TP_BB69: length 6.7
  TOP w0.102: TP604.1 99.97,78.66 101.04,78.66 v1(101.47,78.22)
  BOTTOM w0.102: v1(101.47,78.22) 101.47,77.87 101.5,77.84 101.5,77.5 103.08,75.91 CPU1.BB69
RTC_AUX_S5: length 349.7
  TOP w0.508: v1(30.21,7.84) 28.99,7.84 v1(28.22,8.6) 27.35,9.47 R2725.1 ; R1730.1 96.01,21.96 94.65,21.96 v1(94.64,21.97)
  L3 w0.508: v1(191.44,15.97) 192.44,15.97 194.31,17.84 194.31,28.21 193.29,29.23 192.17,29.23 191.59,29.8 v1(191.59,29.86) ; v1(20.29,57.32) 19.96,56.99 19.96,50.82 18.74,49.6 18.74,46.09 17.7,45.05 17.7,40.83 19.91,38.62 19.91,34.81 20.65,34.07 20.65,29.18 v1(20.67,29.15) ; v1(75.44,18.89) 75.44,19.19 75.93,19.69 82.07,19.69 82.31,19.93 91.17,19.93 93.68,22.44 94.24,22.44 94.61,22.07 94.61,22 v1(94.64,21.97)
  L4 w0.508: v1(110.16,1.87) 110.16,1.88 109.53,2.51 108.48,2.51 107.75,1.77 63.35,1.77 ; v1(28.22,8.6) 29.51,9.89 29.51,19.02 25.53,23 25.53,24.3 24.33,25.49 v1(20.67,29.15) ; v1(144.58,15.84) 144.16,15.42 134.43,15.42 v1(133.47,14.46) ; v1(30.21,7.84) 30.21,3.06 31.52,1.74 42.09,1.74 42.98,2.63 48.69,2.63 49.55,1.77 63.35,1.77 ; 63.35,1.77 63.35,7.08 67.79,11.52 70.54,11.52 75.44,16.42 v1(75.44,18.89)
  L6 w0.508: v1(191.44,15.97) 191.44,15.34 194.74,12.04 v1(194.74,10.25) 194.74,7.85 193.86,6.98 158.67,6.98 156.56,4.87 153.66,4.87 153.08,4.29 153.08,2.89 153.44,2.53 153.44,1.79 153.01,1.36 132.07,1.36 128.7,4.73 v1(128.7,5.37) 125.21,8.86 120.17,8.86 118.88,7.57 114.54,7.57 110.16,3.19 v1(110.16,1.87)
  BOTTOM w0.254: R2451.2 190.55,30.37 191.39,30.37 R2472.2
  BOTTOM w0.508: R2464.1 191.69,9.85 192.1,10.25 v1(194.74,10.25) ; v1(144.58,15.84) 144.58,16.22 143.91,16.88 C2503.1 144.26,17.43 v2(144.85,17.43) 146.43,17.43 D2501.3 ; v1(133.47,14.46) 132.9,13.9 132.9,11.72 130.3,9.11 130.3,7.4 128.7,5.8 v1(128.7,5.37) ; R5721.1 20.5,57.52 v1(20.29,57.32)
RTC_DET#: length 50
  L3 w0.102: v1(116.46,28.72) 116.46,27.81 116.97,27.31 116.97,25.83 117.37,25.43 117.37,18.59 118.31,17.64 119.42,17.64 119.98,18.2 121.04,18.2 121.57,17.67 122.5,17.67 127.87,12.29 138.36,12.29 138.89,12.82 139.65,12.82 v1(140.08,12.39)
  BOTTOM w0.102: v1(140.08,12.39) 139.96,12.27 139.96,11.23 140.11,11.08 140.26,11.08 ; R2040.2 114.1,27.52 114.1,27.52 115.29,28.72 v2(115.57,28.72) v1(116.46,28.72) 116.64,28.9 117.02,28.9 117.4,29.28 117.4,32.74 117.41,32.75 117.41,32.9 118.62,34.11 118.62,35.74 118.43,35.93 CPU1.P1
RTC_RST#: length 143.2
  TOP w0.127: EC1807.1 74.09,15.49 v1(73.48,16.09) ; EC1807.1 C1806.1 v2(77.18,11.86) 77.83,11.21 94.89,11.21 96.99,9.11 96.99,8.89 98.76,7.12 v1(100.16,7.12) ; EC1807.1 74.47,15.64 G1801.2 74.47,17.29 74.8,17.61 RN1801.4
  L3 w0.127: v1(73.48,16.09) 73.77,16.39 78.19,16.39 78.85,15.73 80.24,15.73 83.19,18.67 95.93,18.67 96.4,19.14 98.14,19.14 100.09,21.09 100.09,24.55 100.49,24.96 100.49,26.15 99.78,26.85 99.78,30.2 102.55,32.97 104.07,32.97 105.1,34.01 105.1,35.35 104.27,36.18 104.27,44.29 105.39,45.41 108.86,45.41 v1(109.32,44.95)
  L4 w0.127: v1(100.16,7.12) 100.65,6.63 109.42,6.63 112.34,9.55 125.22,9.55 125.82,10.15 130.57,10.15 131.3,10.88 137.39,10.88 138.32,11.8 140.84,11.8 v1(141.35,12.31)
  BOTTOM w0.127: v1(109.32,44.95) 109.65,45.28 CPU1.AM16 ; Q2503.3 141.75,9.78 141.43,10.1 141.43,12.23 v1(141.35,12.31)
RTC_X1: length 39.5
  TOP w0.089: v1(98.75,23.31) v2(99.31,23.31)
  L4 w0.127: v1(98.75,23.31) 98.63,23.31 97.59,24.35 97.59,30.12 97.01,30.69 97.01,32 99.79,34.78 99.79,36.44 103.38,40.02 103.38,42.56 104.27,43.45 104.27,44.68 105.91,46.32 108.92,46.32 v1(109.33,45.91)
  BOTTOM w0.089: v1(109.33,45.91) 109.65,46.24 CPU1.AM18 ; v1(98.75,23.31) 98.78,23.28 R1815.1 99.54,23.28 99.87,22.95 C1804.1 100.43,22.95 101.03,23.56 101.03,24 101.13,24.1 103.88,24.1 104.72,23.26 X1802.1
RTC_X2: length 39.5
  TOP w0.089: v2(98.85,22.12) 98.85,22.58 v1(98.75,22.67)
  L4 w0.127: v1(108.68,47.72) 108.68,47.41 108.56,47.29 106.34,47.29 105.96,46.91 105.76,46.91 103.81,44.95 103.81,43.55 102.92,42.66 102.92,40.28 99.44,36.8 99.44,35.14 96.49,32.2 96.49,31.69 96.37,31.56 95.98,31.56 95.86,31.43 95.86,31.18 95.98,31.05 96.37,31.05 96.49,30.93 96.49,30.45 97.08,29.86 97.08,24.14 97.2,24.01 97.2,23.52 98.05,22.67 v1(98.75,22.67)
  BOTTOM w0.089: v1(98.75,22.67) 99.01,22.42 R1815.2 99.77,22.17 C1803.1 101.37,23.16 X1802.2 ; CPU1.AM20 109.65,47.42 109.35,47.72 v1(108.68,47.72)
RTCRST_ON: length 104.8
  TOP w0.127: v1(198.17,43.53) 198.17,43.37 197.8,43 197.8,42.41 197.97,42.24 KBC24.31 ; v1(155.8,3.09) 155.31,3.09 152.93,5.48 152.02,5.48 v2(151.7,5.8) 150.59,6.91 150.59,8.6 148.59,10.61 143.32,10.61 142.58,11.35 142.58,12.45 142.11,12.92 141.32,12.92 v1(140.71,12.31) 140.79,12.23 EC2504.1 140.77,11.27 139.9,11.27
  L3 w0.127: v1(155.8,3.09) 159.03,6.32 189.28,6.32 199.43,16.46 199.43,28.6 198.93,29.1 198.93,36.92 198.17,37.68 v1(198.17,43.53)
  BOTTOM w0.127: v1(140.71,12.31) 140.71,11.62 141.1,11.24 141.1,10.68 140.84,10.43 140.26,10.43
RUNPWROK: length 157.4
  TOP w0.127: v1(191.26,45.41) 191.26,45.17 191.21,45.11 KBC24.48 ; v1(107.54,94.45) 107.59,94.5 v2(108.41,94.5) v1(109.9,94.5)
  L3 w0.127: v1(161.97,101.44) 161.95,101.44 161.49,101.9 161.49,102.93 160.01,104.41 158.06,104.41 155.12,107.34 130.27,107.34 129.84,106.91 127.32,106.91 v1(121.84,101.44) ; v1(191.26,45.41) 191.26,45.17 191.03,44.94 187.44,44.94 186.61,45.76 185.04,45.76 184.94,45.81 184.66,45.95 184.65,45.95 184.55,46.05 184.5,46.08 183.65,46.08 181.65,48.09 181.65,49.47 181.51,49.6 181.51,49.61 181.23,50.34 181.17,50.48 181.02,50.54 180.68,50.89 180.68,51.5 180.16,52.02 180.16,55.1 179.47,57.29 179.47,61.48 176.78,64.18 176.78,67.86 178.31,69.38 v1(178.87,69.38)
  L4 w0.127: v1(166.65,78.1) 167.03,77.72 167.03,74.73 v1(166.57,74.27)
  L6 w0.127: v1(166.57,74.27) 166.1,73.8 166.1,72.81 171.8,67.11 176.06,67.11 178.33,69.38 v1(178.87,69.38) ; v1(161.97,101.44) 161.97,98.84 164.55,96.26 164.55,94.64 166.86,92.33 166.86,81.94 165.38,80.46 165.38,78.86 166.14,78.1 v1(166.65,78.1)
  BOTTOM w0.127: v1(121.84,101.44) 122.26,101.02 122.26,99.74 121.8,99.28 115.73,99.28 111.16,94.71 110.11,94.71 v1(109.9,94.5) ; R1716.1 ED1709.1 106.97,95.03 v1(107.54,94.45) ; R4002.1 163.63,100.35 163.37,100.09 161.85,100.09 161.39,100.55 R4005.2 161.26,100.65 R4011.2 161.36,101.44 v1(161.97,101.44) 162.36,101.44 162.74,101.82 D4002.A
SA0_CHA_DIM0: length 5.3
  TOP w0.102: v2(66.62,21) 66.62,21.3 v1(66.39,21.53) 66.42,21.53 66.88,21.99 66.88,22.22 R1205.2 R1204.1
  BOTTOM w0.102: v1(66.39,21.53) 66.39,21.53 66.19,21.73 DM1.256
SA0_CHB_DIM0: length 5.7
  TOP w0.102: v1(54.18,21.86) 54.18,21.56 v2(54.46,21.28) ; v1(54.18,21.86) 53.54,22.5 R1303.2 ; v1(54.18,21.86) 54.41,22.09 R1302.1
  BOTTOM w0.102: DM2.256 54.1,21.93 v1(54.18,21.86)
SA1_CHA_DIM0: length 10.5
  TOP w0.102: R1210.2 67.03,20.64 68.4,20.64 68.63,20.41 69.31,20.41 v2(69.53,20.63) 69.52,20.64 69.52,20.92 69.37,21.07 68.5,21.07 R1208.1 67.13,21.63 v1(67.03,21.53)
  BOTTOM w0.102: DM1.260 65.21,20.73 65.48,20.46 66.27,20.46 67.03,21.23 v1(67.03,21.53)
SA1_CHB_DIM0: length 10.8
  TOP w0.102: R1306.1 54.51,24.07 R1307.1 54.38,24.1 53.87,24.6 52.7,24.6 v2(52.63,24.68) v1(49.63,24.68)
  BOTTOM w0.102: v1(49.63,24.68) 49.66,24.65 49.66,21.3 50.02,20.93 DM2.260
SA2_CHA_DIM0: length 5.2
  TOP w0.102: v1(62.18,45.09) 62.74,44.53 R1211.1 62.74,43.81 v2(63.12,43.43) 63.55,43.86 R1212.2
  BOTTOM w0.102: v1(62.18,45.09) 62.18,45 62.95,44.23 DM1.166
SA2_CHB_DIM0: length 5.6
  TOP w0.102: v1(49.5,44.47) 49.3,44.67 49.25,44.67 v2(48.87,45.05) 48.87,45.56 R1310.1 48.92,46.42 49.96,46.42 50.19,46.19 R1311.2
  BOTTOM w0.102: v1(49.5,44.47) 49.66,44.47 49.69,44.44 DM2.166
SATA_LED#: length 82.7
  TOP w0.127: v1(167.54,46.35) 167.59,46.4 168.68,46.4 169.1,45.98 v2(171.22,45.98) 172.98,45.98 174.48,47.47 Q6403.S
  L4 w0.127: v1(167.54,46.35) 167.24,46.35 166.5,45.6 166.5,37.28 163.65,34.43 163.24,34.43 161.55,32.74 156.84,32.74 156.41,33.18 148.17,33.18 146.89,31.89 146.89,31.38 146.35,30.84 136.59,30.84 135.6,31.83 132.79,31.83 127.38,37.24 127.38,37.43 126.97,37.84 126.97,38.26 126.64,38.6 126.3,38.6 125.65,37.95 125.65,36.54 v1(123.29,34.18)
  BOTTOM w0.127: R1606.2 120.95,28.95 120.95,29.56 121.68,30.28 121.68,32.06 121.84,32.23 121.84,32.79 122.83,33.78 122.83,33.79 123.09,34.04 123.15,34.04 v1(123.29,34.18) 123.11,34.36 122.2,34.36 121.77,34.79 121.77,35.63 121.74,35.65 CPU1.H1
SATA_RX_CPU_N0: length 92.6
  TOP w0.102: v1(157.71,11.4) 157.48,11.62 157.48,12.88 157.17,13.19 157.17,16.68 157.48,16.98 157.48,20.04 158.98,21.54 159.38,21.54 ; C6006.1 171.03,14.75 170.64,14.75 163.85,21.54 159.38,21.54 ; 159.38,21.54 v2(159.38,21.42)
  L6 w0.127: v1(157.71,11.4) 157.48,11.17 157.48,10.86 157.19,10.57 153.35,10.57 152.8,11.13 150.22,11.13 149.07,12.27 147.75,12.27 146.95,13.07 143.71,13.07 142.81,13.97 140.24,13.97 138.66,15.55 137.16,17.05 134.55,17.05 130.1,21.5 130.1,23.57 125.83,27.83 125.83,30.9 128.85,33.93 128.85,42.79 126.91,44.73 125.26,44.73 124.29,45.7 124.29,46.11 123.26,47.15 123.26,47.37 123.24,47.48 v1(122.91,47.74)
  BOTTOM w0.102: v1(122.91,47.74) 122.54,47.38 CPU1.F20
SATA_RX_CPU_N12: length 112.5
  TOP w0.102: 183.23,18.07 184.12,17.18 184.12,15.07 184.73,14.47 186.91,14.47 187.3,14.08 187.77,14.08 188.02,14.33 U6301.9 U6301.2 189.79,14.33 190.04,14.08 190.26,14.08 194,17.82 194,21.11 193.83,21.28 193.53,21.28 v1(193.12,20.87) ; 183.23,18.07 182.75,18.56 182.75,19.05 182.55,19.24 v1(182.21,19.24) ; 183.23,18.07 v2(183.32,18.16)
  L6 w0.127: v1(123.48,53.2) 123.68,52.99 123.99,52.99 124.26,53.26 129.94,53.26 132.29,50.9 132.29,48.51 132.49,48.32 134.91,48.32 136.55,46.68 136.55,45.67 136.89,45.32 136.89,42.95 139.57,40.27 139.57,39.82 140.37,39.02 140.37,37.15 140.89,36.63 140.89,32.33 140.1,31.54 140.1,30.9 140.1,30.67 138.76,29.33 138.76,27.48 143.34,22.9 152.02,22.9 152.37,23.26 158.42,23.26 158.57,23.1 158.89,22.78 171.02,22.78 173.39,20.41 174.6,20.41 175.66,21.47 177.76,21.47 180.71,18.52 181.15,18.52 181.41,18.77 181.41,19.14 181.66,19.4 182.06,19.4 v1(182.21,19.24)
  BOTTOM w0.102: v1(123.48,53.2) 123.48,53.4 CPU1.E30 ; SSD1.43 193.9,20.94 193.72,21.12 193.38,21.12 v1(193.12,20.87)
SATA_RX_CPU_P0: length 92.3
  TOP w0.102: 158.04,20.92 v2(157.94,21.02) ; 158.04,20.92 158.89,21.77 163.94,21.77 170.74,14.98 171.06,14.98 C6005.1 ; 158.04,20.92 157.25,20.13 157.25,17.08 156.94,16.77 156.94,13.1 157.25,12.79 157.25,11.6 v1(157.05,11.4)
  L6 w0.127: v1(123.77,47.84) 123.51,47.51 123.52,47.42 123.52,47.38 123.52,47.26 124.56,46.22 124.56,45.81 125.37,45 127.02,45 129.12,42.9 129.12,33.82 126.1,30.79 126.1,27.94 130.36,23.68 130.36,21.61 134.66,17.31 137.27,17.31 138.84,15.74 140.35,14.24 142.92,14.24 143.82,13.34 147.06,13.34 147.86,12.54 149.18,12.54 150.33,11.4 152.91,11.4 153.47,10.84 157.08,10.84 157.21,10.97 157.21,11.23 v1(157.05,11.4)
  BOTTOM w0.102: CPU1.E20 123.21,47.29 v1(123.77,47.84)
SATA_RX_CPU_P12: length 112.6
  TOP w0.102: v1(182.21,18.61) 182.37,18.61 183.07,17.91 183.89,17.09 183.89,15.33 ; 183.89,15.33 183.89,14.98 184.63,14.24 186.82,14.24 187.21,13.85 U6301.10 U6301.1 190.36,13.85 194.23,17.73 194.23,21.2 193.92,21.51 v1(193.12,21.51) ; 183.89,15.33 v2(183.77,15.33)
  L6 w0.127: v1(122.83,53.2) 123.3,52.72 124.1,52.72 124.37,52.99 129.83,52.99 132.03,50.79 132.03,48.4 132.38,48.05 134.8,48.05 136.28,46.57 136.28,45.56 136.62,45.21 136.62,42.84 139.3,40.16 139.3,39.71 140.1,38.91 140.1,37.04 140.63,36.52 140.63,32.44 139.84,31.65 139.84,30.79 138.49,29.44 138.49,27.37 143.23,22.64 152.13,22.64 152.48,22.99 158.31,22.99 158.78,22.51 159,22.51 170.91,22.51 173.28,20.15 174.71,20.15 175.77,21.2 177.65,21.2 180.6,18.25 181.26,18.25 181.62,18.61 v1(182.21,18.61)
  BOTTOM w0.102: SSD1.41 193.9,21.44 193.81,21.35 193.81,21.35 193.28,21.35 v1(193.12,21.51) ; v1(122.83,53.2) 122.83,53.4 CPU1.F30
SATA_RXN0_R: length 8.6
  TOP w0.102: 175.97,14.58 175.58,14.58 175.46,14.46 U6001.4 U6001.7 173.47,14.46 173.35,14.57 172.72,14.57 172.55,14.4 C6006.2 ; 175.97,14.58 176.29,14.58 176.49,14.38 176.54,14.33 176.54,14.18 v1(176.35,13.99) ; 175.97,14.58 v2(175.97,14.44)
  BOTTOM w0.102: v1(176.35,13.99) 176.38,14.02 176.38,15.32 177.01,15.94 177.58,15.94 177.72,16.08 HDD1.18
SATA_RXP0_R: length 9.4
  TOP w0.102: C6005.2 172.78,14.8 173.33,14.8 173.46,14.94 U6001.6 U6001.5 175.46,14.94 175.58,14.81 176.38,14.81 176.65,14.54 176.77,14.42 176.77,14.18 v1(176.99,13.96) v2(177.57,13.96)
  BOTTOM w0.102: v1(176.99,13.96) 176.78,14.16 176.78,14.39 176.61,14.56 176.61,15.22 177.11,15.72 177.57,15.72 177.7,15.58 HDD1.19
SATA_TX_CPU_N0: length 74.9
  TOP w0.102: 163.31,20.58 v2(163.4,20.67) ; 163.31,20.58 162.83,21.06 160.64,21.06 160.37,20.79 160.37,20.48 v1(160.15,20.25) ; 163.31,20.58 170.7,13.18 171.04,13.18 C6003.1
  L3 w0.14: v1(160.15,20.25) 160.34,20.44 160.34,22.56 159.01,23.89 145.28,23.89 143.49,22.1 136.89,22.1 135.43,23.56 135.43,23.72 134.55,24.59 133.99,24.59 132.52,26.06 132.52,30.84 129.61,33.75 129.61,44.4 127.82,46.18 127.82,47.58 v1(127.76,47.64)
  BOTTOM w0.102: v1(127.76,47.64) 127.6,47.81 127.27,47.81 126.86,48.21 125.76,48.21 125.49,48.48 CPU1.B21
SATA_TX_CPU_N12: length 92.3
  TOP w0.102: v2(128.67,50.87) 128.37,50.56 v1(128.37,50.38) ; C6303.2 185.82,15.59 184.81,15.59 v1(184.61,15.38)
  L6 w0.127: v1(128.37,50.38) 128.57,50.18 128.59,50.18 128.61,50.17 128.61,49.79 129.64,48.76 129.64,47.48 131.92,45.2 133.22,45.2 134.05,44.38 134.05,40.59 133.15,39.69 133.15,34.51 135.66,32 135.66,25.12 136.77,24.01 136.77,22.92 137.93,21.76 141.04,18.65 141.12,18.57 146.65,18.57 147.37,17.85 149.87,17.85 152.71,15 155.42,15 156.42,16.01 166.16,16.01 167.3,14.86 170.69,14.86 172,13.55 174.56,13.55 174.92,13.2 179.15,13.2 179.54,12.82 181.6,12.82 184.28,15.5 184.45,15.5 184.57,15.38 v1(184.61,15.38)
  BOTTOM w0.102: v1(128.37,50.38) 128.6,50.61 128.6,50.72 128.02,51.3 126.26,51.3 CPU1.A25
SATA_TX_CPU_N12_C: length 11.7
  TOP w0.102: v1(193,19.78) 193.52,19.26 193.52,18.79 ; 193.52,18.79 193.52,18.13 192.15,16.76 191.46,16.76 190.21,15.51 189.89,15.51 189.75,15.37 U6301.4 U6301.7 188.1,15.37 187.97,15.5 187.21,15.5 C6303.1 ; 193.52,18.79 v2(193.65,18.79)
  BOTTOM w0.102: SSD1.47 194.15,19.94 193.99,19.78 v1(193,19.78)
SATA_TX_CPU_P0: length 74.7
  TOP w0.102: 164.34,19.22 170.61,12.95 171.04,12.95 C6001.1 ; 164.34,19.22 v2(164.25,19.13) ; 164.34,19.22 163.15,20.42 162.73,20.83 160.74,20.83 160.6,20.7 160.6,20.48 v1(160.83,20.25)
  L3 w0.14: v1(128.43,47.63) 128.09,47.3 128.09,46.29 129.87,44.51 129.87,33.86 132.79,30.95 132.79,26.18 134.1,24.86 134.67,24.86 135.7,23.83 135.7,23.67 137,22.37 143.38,22.37 145.17,24.16 159.12,24.16 160.6,22.67 160.6,20.48 v1(160.83,20.25)
  BOTTOM w0.102: CPU1.A21 125.95,48.44 126.95,48.44 127.36,48.03 128.03,48.03 v1(128.43,47.63)
SATA_TX_CPU_P12: length 93
  TOP w0.102: C6302.2 185.72,15.82 184.81,15.82 v1(184.61,16.02)
  L6 w0.127: v1(184.61,16.02) 184.35,15.76 184.17,15.76 181.49,13.09 179.65,13.09 179.27,13.47 175.03,13.47 174.67,13.82 172.11,13.82 170.8,15.13 167.41,15.13 166.27,16.27 156.31,16.27 155.31,15.27 152.82,15.27 149.98,18.11 147.48,18.11 146.76,18.84 141.23,18.84 138.12,21.95 137.03,23.03 137.03,24.12 135.93,25.23 135.93,32.11 133.41,34.62 133.41,39.58 134.31,40.48 134.31,44.49 133.33,45.47 132.03,45.47 129.91,47.59 129.91,48.87 128.88,49.9 128.88,50.23 v1(129.03,50.38)
  BOTTOM w0.102: CPU1.B25 125.55,51.25 125.88,51.25 126.16,51.53 128.12,51.53 128.83,50.82 128.83,50.58 v1(129.03,50.38) 129.21,50.38 v2(129.51,50.08)
SATA_TX_CPU_P12_C: length 11
  TOP w0.102: 192.47,17.4 192.05,16.98 191.36,16.98 190.12,15.74 189.89,15.74 189.78,15.85 U6301.5 U6301.6 188.09,15.85 187.97,15.73 187.23,15.73 187.02,15.94 C6302.1 ; 192.47,17.4 v2(192.38,17.49) ; 192.47,17.4 193.29,18.22 193.29,18.94 193.09,19.14 v1(193,19.14)
  BOTTOM w0.102: SSD1.49 194.09,19.44 193.98,19.55 193.41,19.55 v1(193,19.14)
SATA_TXN0_R: length 13.9
  TOP w0.102: v1(176.55,11.9) 176.25,12.2 176.25,12.64 ; 176.25,12.64 176.25,12.87 175.83,13.29 175.58,13.29 175.46,13.42 U6001.2 U6001.9 173.44,13.42 173.28,13.25 172.55,13.25 C6003.2 ; 176.25,12.64 v2(176.38,12.64)
  BOTTOM w0.102: HDD1.16 177.58,17.08 177.47,17.19 177.14,17.19 176.93,16.98 175.92,16.98 175.59,16.65 175.59,15.46 175.25,15.12 175.25,13.49 176.27,12.46 176.27,12.18 v1(176.55,11.9)
SATA_TXP0_R: length 14.5
  TOP w0.102: C6001.2 172.68,13.02 173.37,13.02 173.46,12.94 U6001.10 U6001.1 175.46,12.94 175.58,13.06 175.73,13.06 176.02,12.77 176.02,12.13 175.76,11.87 v1(175.76,11.9) 175.79,11.87 v2(175.79,11.29)
  BOTTOM w0.102: v1(175.76,11.9) 175.76,11.87 176.05,12.15 176.05,12.37 175.02,13.4 175.02,15.21 175.36,15.55 175.36,16.75 175.82,17.21 176.84,17.21 177.04,17.42 177.44,17.42 177.61,17.58 HDD1.15
SD_RCOMP: length 2.1
  TOP w0.508: R1901.1 114.84,39.55 114.42,39.97 v1(114.2,39.97) 114.04,39.97 v2(113.71,40.3)
  BOTTOM w0.254: CPU1.AB7 114.4,39.77 114.21,39.97 v1(114.2,39.97)
SD_READ_MODE: length 10.6
  BOTTOM w0.102: R2055.2 108.68,32.12 R2056.1 108.68,32.48 107.97,33.19 107.19,33.19 106.73,33.65 v2(106.73,33.9) 106.73,34.46 106.86,34.59 106.86,36.92 106.98,37.05 107.25,37.05 107.54,37.34 107.54,37.84 107.72,38.02 107.96,38.02 CPU1.AN5
SENSOR_I2C_SCL: length 168.2
  L3 w0.127: v1(112.27,19.98) 112.27,19.68 110.88,18.29 107.99,18.29 107.35,18.93 105.21,18.93 103.56,17.28 102.7,17.28 102.34,16.92 94.03,16.92 93.33,16.22 82.97,16.22 81.38,14.63 63.94,14.63 62.8,15.78 52.69,15.78 42.93,25.54 42.93,27.66 39.68,30.92 39.68,35.49 42.47,38.28 42.47,42.52 45.01,45.06 45.01,63.9 43.67,65.24 43.67,79.85 45.49,81.67 45.49,84.56 48.1,87.18 48.22,87.18 48.93,87.88 48.93,88 52.57,91.65 54.78,91.65 55.61,90.82 56.08,90.72 56.4,90.4 56.47,90.33 59.14,90.33 v1(59.99,91.18)
  BOTTOM w0.089: TCBD1.8 58.65,92.6 59.99,91.25 v1(59.99,91.18) ; v1(112.27,19.98) 112.35,19.98 v2(112.87,20.5) 113.39,21.02 114.6,21.02 116.2,22.62 RN7001.2 116.51,23.21 116.84,23.54 R2020.2
SENSOR_I2C_SCL_2G: length 96.5
  TOP w0.089: U7001.1 178.38,41.96 v1(178.56,41.77)
  L3 w0.127: v1(178.56,41.77) 179.56,40.77 179.56,38.64 179.51,38.59 179.51,37.39 179.8,37.1 179.8,35.44 179.39,35.03 179.39,31.57 179.56,31.39 179.56,30.39 178.52,29.35 178.52,22.24 177.28,21 177.02,21 175.38,19.36 175.38,19.32 174.29,18.23 173.55,18.23 170.47,15.14 168.31,15.14 165.7,12.53 165.7,11.75 163.88,9.93 v1(163.88,9.11)
  L6 w0.102: v1(163.88,9.11) 163.88,9.26 163.07,10.08 153.15,10.08 152.59,10.63 150.01,10.63 149.25,11.4 144.68,11.4 142.6,13.48 140.03,13.48 138.31,15.2 136.96,16.55 134.34,16.55 129.6,21.29 129.6,23.12 v1(129.39,23.33)
  BOTTOM w0.089: v1(129.39,23.33) 128.77,23.33 128.34,22.91 125.64,22.91 125.41,23.14 v2(118.95,23.14) 118.52,23.14 118,22.62 RN7001.3
SENSOR_I2C_SDA: length 169.7
  L3 w0.127: v1(59.36,91.2) 59.36,91.18 58.88,90.71 56.63,90.71 56.27,91.07 55.8,91.17 54.82,92.15 52.54,92.15 48.55,88.16 48.55,88.04 48.07,87.56 47.95,87.56 45.11,84.72 45.11,81.82 43.29,80.01 43.29,65.08 44.63,63.75 44.63,50.1 43.36,48.83 43.36,43.95 42.09,42.68 42.09,38.44 39.29,35.65 39.29,30.76 42.55,27.5 42.55,25.7 42.55,25.38 52.54,15.4 62.64,15.4 63.79,14.25 81.54,14.25 83.08,15.79 93.44,15.79 94.19,16.54 102.5,16.54 102.86,16.9 103.72,16.9 105.37,18.55 107.19,18.55 107.83,17.91 111.03,17.91 112.67,19.55 112.79,19.67 v1(112.82,19.67)
  BOTTOM w0.089: TCBD1.7 58.15,92.72 59.36,91.51 v1(59.36,91.2) ; R2021.2 117.56,23.07 117.17,23.07 116.97,22.86 116.97,22.23 116.7,21.97 RN7001.1 115.93,21.97 114.48,20.51 v2(114.17,20.51) 113.38,20.51 112.82,19.95 v1(112.82,19.67)
SENSOR_I2C_SDA_2G: length 99.4
  TOP w0.089: v1(178.97,43.73) 178.96,43.73 178.8,43.57 U7001.4
  L3 w0.127: v1(164.51,9.11) 164.51,10.02 166.08,11.59 166.08,12.37 168.47,14.76 170.62,14.76 173.71,17.85 174.44,17.85 175.76,19.17 175.76,19.2 177.18,20.62 177.44,20.62 178.9,22.08 178.9,29.19 179.94,30.23 179.94,31.55 179.77,31.73 179.77,34.65 180.18,35.06 180.18,37.26 179.89,37.54 179.89,38.43 179.94,38.48 179.94,41.02 178.93,42.03 178.93,43.69 v1(178.97,43.73)
  L6 w0.102: v1(164.51,9.11) 164.08,8.68 163.7,8.68 163.42,8.96 163.42,9.29 162.94,9.77 153.02,9.77 152.46,10.33 149.88,10.33 149.12,11.09 144.56,11.09 142.47,13.17 139.9,13.17 136.83,16.25 134.22,16.25 129.3,21.17 129.3,22.51 v1(128.95,22.86)
  BOTTOM w0.089: RN7001.4 v2(118.39,21.97) 118.49,21.97 119.4,22.87 124.89,22.87 125.12,22.64 128.45,22.64 128.67,22.86 v1(128.95,22.86)
SERIRQ_TPM: length 2.9
  TOP w0.102: U9104.27 39.28,31.15 v2(38.5,31.94) 37.77,32.66 R9148.1
SIO_EXT_SCI#: length 9.4
  BOTTOM w0.089: CPU1.J2 121.21,36.96 121.21,36.7 121.3,36.6 121.35,36.45 121.35,35.2 121.37,35.19 121.37,34.33 121.71,33.98 121.71,33.23 121.61,33.14 121.61,32.3 121.29,31.98 121.29,30.6 v2(121.26,30.57) 121.26,30.41 120.5,29.65 120.5,29.3 R1608.2
SIO_EXT_SMI#: length 12.3
  TOP w0.102: v1(119.87,29.51) 119.56,29.51 v2(119.33,29.73)
  L4 w0.102: v1(119.87,29.51) 119.82,29.55 119.82,29.93 119.42,30.33 119.42,39.42 v1(119.4,39.44)
  BOTTOM w0.102: v1(119.4,39.44) 119.46,39.44 119.77,39.12 CPU1.L6 ; v1(119.87,29.51) 119.38,29.51 R802.1
SIO_EXT_WAKE#: length 112.6
  TOP w0.102: KBC24.116 192.41,27.98 192.58,27.81 v1(192.58,27.55)
  L4 w0.102: v1(160.42,30.8) 160.42,30.42 158.89,28.88 152.89,28.88 152.52,28.52 149.31,28.52 149.01,28.21 148.45,28.21 146.44,26.2 143.86,26.2 142.69,25.04 132.31,25.04 129.29,22.01 129.03,22.01 127.65,22.01 127.34,21.71 125.16,21.71 124.85,22.01 122.55,22.01 121.89,22.67 121.53,22.67 121.2,23 117.26,23 117.09,22.83 115.45,22.83 114.96,23.31 114.38,23.31 112.5,25.19 111.8,25.19 111.38,24.76 111.38,24.48 111.01,24.11 v1(109.55,24.11) 109.29,24.36 109.29,24.86 108.53,25.62 108.53,26.55 109.64,27.66 109.64,30.23 110.55,31.14 110.55,32.76 v1(111.63,33.83)
  L6 w0.102: v1(192.58,27.55) 192.58,27.73 191.01,29.3 185.11,29.3 184.88,29.53 184.12,29.53 183.89,29.3 182.64,29.3 181.93,28.59 179.36,28.59 178.44,29.51 172.38,29.51 171.64,30.24 168.12,30.24 167.89,30.01 164.32,30.01 163.33,31 160.63,31 v1(160.42,30.8)
  BOTTOM w0.102: v1(111.63,33.83) 111.72,33.93 111.79,33.93 113.02,35.16 113.02,35.48 112.96,35.54 112.96,36.09 112.85,36.2 112.85,37.33 113.12,37.6 CPU1.AD3 ; v1(109.55,24.11) 109.42,23.98 v2(109.42,23.54) 109.42,22.38 109.02,21.97 R2041.2
SIO_PWRBTN#: length 159.9
  TOP w0.102: v2(98.89,44.58) 99.03,44.72 v1(99.92,44.72) ; v1(188.87,45.55) 188.96,45.55 189.61,44.9 KBC24.52
  L4 w0.102: v1(99.92,44.72) 98.78,43.58 98.78,39.39 94.56,35.17 94.56,25.92 93.5,24.86 93.29,24.86 92.78,24.35 92.78,23.05 93.04,22.8 95.1,22.8 97.33,20.57 98.7,20.57 99.82,19.45 100.93,19.45 101.29,19.08 101.29,18.76 101.55,18.51 103.61,18.51 104.65,19.55 111.11,19.55 111.64,19.02 117.27,19.02 117.4,19.14 120.3,19.14 121.07,18.37 124.08,18.37 124.94,17.5 126.91,17.5 127.32,17.91 128.55,17.91 128.87,18.23 130.75,18.23 133.24,20.72 139.37,20.72 139.88,20.21 143.1,20.21 144.12,21.23 147,21.23 147.36,21.58 148.03,21.58 149.4,22.95 149.4,23.49 149.72,23.8 151.44,23.8 153.61,25.98 158.7,25.98 159.98,24.69 162.21,24.69 165.99,28.46 166.48,28.46 172.9,34.88 172.9,37.8 175.77,40.67 175.77,42.9 176.81,43.94 176.81,44.63 177.34,45.16 177.34,49.11 177.85,49.62 v1(177.85,52.16)
  L6 w0.102: v1(188.87,45.55) 188.98,45.44 188.98,45.11 188.54,44.67 187.02,44.67 186.36,45.33 183.13,45.33 178.23,50.23 178.23,51.78 v1(177.85,52.16)
  BOTTOM w0.102: CPU1.BA15 103.75,44.94 103.43,44.62 101.9,44.62 101.71,44.81 101.31,44.81 100.77,44.28 100.37,44.28 v1(99.92,44.72)
SIO_RCIN#: length 28.2
  TOP w0.089: v1(98.14,24.45) v2(98.14,23.74) 97.94,23.54 R1820.2
  L4 w0.127: v1(98.14,24.45) 98.31,24.45 98.56,24.71 98.56,31.22 98.32,31.46 98.32,31.92 98.75,32.35 99.98,32.35 100.94,33.31 100.94,35.29 103.61,37.96 103.61,39.13 103.82,39.35 103.82,42.3 105.91,44.38 v1(105.91,44.95)
  BOTTOM w0.089: v1(105.91,44.95) 105.94,44.92 105.94,44.16 105.49,43.71 CPU1.AW13
SIO_SLP_A#: length 1.8
  TOP w0.102: TP1706.1 108.23,46.37 v1(108.68,45.91)
  BOTTOM w0.102: v1(108.68,45.91) 109,45.6 CPU1.AN16
SIO_SLP_S0#: length 394.7
  TOP w0.127: v1(46.79,31.97) 46.33,31.51 44.35,31.51 R9142.2 ; R6005.1 172.26,16.22 172.1,16.06 170.42,16.06 169.75,16.73 169.75,18.24 v1(169.51,18.47) ; 126.54,102.51 121.36,102.51 v1(120.29,101.44) ; v1(97.07,41.54) 97.08,41.55 97.89,41.55 98.8,42.46 v2(98.83,42.46) 104.16,42.46 104.57,42.87 105.61,42.87 105.64,42.89 106.07,42.89 106.27,42.69 106.9,42.69 v1(107.38,43.17) ; v1(155.24,7.92) 154.96,7.92 154.6,8.27 152.37,8.27 149.38,11.27 147.13,12.38 146.91,12.48 143.52,14.03 143.52,14.03 143.45,14.1 143.11,14.44 143.06,14.48 142.89,14.57 142.57,14.74 142.57,14.74 141.15,15.47 140.71,15.7 140.33,15.89 139.01,16.58 130.35,16.58 129.72,15.95 129.72,15.41 128.67,14.36 126.37,14.36 125.63,13.62 124.1,12.09 124,11.99 123.95,11.94 123.08,11.94 114.97,11.94 114.33,11.31 97.84,11.31 94.19,14.96 87.03,14.96 86.69,14.62 83.02,14.62 82.36,15.28 82.36,20.55 v1(84,22.19)
  L3 w0.127: v1(155.24,7.92) 155.71,8.39 157.8,8.39 158,8.59 169.09,8.59 171.57,11.07 172.77,11.07 174.33,12.63 177.36,12.63 178.55,13.81 178.55,14.56 v1(180.82,16.83) ; v1(74.34,96.61) 75.79,96.61 77.78,98.61 79.24,98.61 85.23,104.59 90.83,104.59 92.71,102.71 94.44,102.71 94.65,102.51 98.52,102.51 99.36,101.67 101.89,101.67 102.92,100.64 119.49,100.64 v1(120.29,101.44) ; v1(84,22.19) 82.62,22.19 81.5,21.07 73.04,21.07 72.27,20.3 69.3,20.3 68.73,20.87 67.58,20.87 67.49,20.77 67.4,20.73 67.32,20.68 66.8,20.68 66.24,20.12 61.85,20.12 61.01,20.96 56.61,20.96 56.38,20.73 55.63,20.73 55.52,20.84 54.56,20.84 53.84,20.12 52.74,20.12 47.36,25.5 47.36,31.4 v1(46.79,31.97) 45.59,33.17 45.59,37.1 48.23,39.74 48.23,85.09 49.47,86.33 49.96,86.33 50.49,86.33 54.05,89.88 55.12,89.88 55.14,89.87 55.25,89.85 55.34,89.83 55.66,89.7 56.17,89.19 56.17,88.75 56.42,88.5 65.66,88.5 66.44,89.28 66.44,89.8 67.17,90.53 70.45,90.53 v1(71.04,89.93)
  L4 w0.127: v1(97.07,41.54) 97.08,41.54 97.08,38.42 94.04,35.39 94.04,28.94 92.98,27.88 87.53,27.88 84,24.35 v1(84,22.19) ; v1(169.51,18.47) 171.84,18.47 173.22,19.85 175.01,19.85 176.48,21.31 177.44,21.31 184.3,28.18 v1(184.3,28.46)
  L6 w0.127: v1(180.82,16.83) 179.8,16.83 179.54,16.56 174.05,16.56 173.22,17.39 172.14,18.47 v1(169.51,18.47)
  BOTTOM w0.127: v1(184.3,28.46) 183.85,28.92 183.85,30.07 184.53,30.75 R2423.1 ; CPU1.AT11 107.05,42.85 v1(107.38,43.17) ; v1(71.04,89.93) 71.24,89.93 74,92.7 74,95.37 74.34,95.71 v1(74.34,96.61)
SIO_SLP_S3#: length 292.9
  TOP w0.127: PR5126.1 30.4,9.24 v1(30.66,8.98) ; v1(85.27,92.55) 85.27,92.04 v2(86.36,90.95) 87.22,90.08 R4017.1
  L3 w0.127: v1(30.66,8.98) 30.66,12.23 28.84,14.05 28.84,19.81 25.69,22.96 25.69,24.11 21.51,28.29 v1(21.51,29.23) ; v1(91.97,24.1) 90.23,22.36 90.23,21.66 89.73,21.16 81.95,21.16 81.6,20.82 73.85,20.82 72.94,19.9 v1(72.67,19.9) ; v1(94.87,93.41) 94.79,93.34 88.21,93.34 87.43,92.55 v1(85.27,92.55)
  L4 w0.127: v1(72.67,19.9) 68.82,16.06 68.82,14.03 61.59,6.8 v1(61.59,6.14) ; v1(98.86,31.56) 99.11,31.82 100.02,31.82 101.34,33.14 101.34,35.38 103.83,37.87 103.83,39.06 104.04,39.26 104.04,41.97 106.63,44.57 107.6,44.57 v1(108.03,45)
  L6 w0.127: v1(61.59,6.14) 61.59,4.87 61.14,4.41 55.17,4.41 54.66,3.9 54.66,2.51 53.39,1.24 34.72,1.24 32.82,3.14 32.82,7.84 32.43,8.22 31.29,8.22 30.66,8.86 v1(30.66,8.98)
  BOTTOM w0.127: CPU1.AP15 108.35,44.67 v1(108.03,45) ; v1(85.27,92.55) 84.63,91.91 83.4,91.91 82.86,92.46 81.89,92.46 81.63,92.71 77.41,92.71 76.44,91.74 76.44,55.78 76.7,55.51 76.7,27.73 73.79,24.81 73.79,20.74 72.95,19.9 v1(72.67,19.9) 69.87,17.11 62.95,17.11 62.57,16.73 61.77,16.73 61.26,16.22 PR5405.1 ; U4003.1 128.36,99.11 127.86,99.61 127.68,99.61 R4010.1 127.68,100.12 127.68,101.33 126.87,102.14 117.54,102.14 110.41,95.01 109.65,95.01 105.9,91.27 97.96,91.27 97.06,92.17 96.11,92.17 v1(94.87,93.41) ; v1(21.51,29.23) 21.51,29.87 Q2701.G ; v1(98.86,31.56) 98.02,31.56 97.08,30.62 97.08,25.52 95.83,24.28 94.95,24.28 94.45,23.78 93.08,23.78 92.76,24.1 v1(91.97,24.1)
SIO_SLP_S4#: length 162.5
  TOP w0.127: v1(100.48,45.3) v2(97.86,45.3) 97.19,45.3 95.8,46.7 95.8,47.14 94.71,48.23 v1(94.41,48.23)
  L3 w0.127: v1(41.32,94.5) 41.32,94.06 42.01,93.37 48.32,93.37 49.48,92.22 51.66,92.22 52.75,93.31 64.23,93.31 66.22,91.32 69.32,91.32 69.73,91.72 79.65,91.72 80.31,91.06 83.27,91.06 84.01,91.8 95.18,91.8 v1(95.65,91.33)
  L4 w0.127: v1(104.77,15.47) 104.71,15.47 104.28,15.9 100.73,15.9 99.45,17.18 99.45,19.03 98.16,20.32 97.19,20.32 94.96,22.56 92.94,22.56 92.54,22.95 92.54,24.86 92.87,25.19 92.87,25.47 93.62,26.22 93.86,26.22 94.31,26.67 94.31,35.27 98.35,39.31 98.35,43.72 99.93,45.3 v1(100.48,45.3)
  BOTTOM w0.127: v1(100.48,45.3) 100.53,45.25 101.61,45.25 101.97,45.61 102.44,45.61 102.56,45.49 104.18,45.49 CPU1.BA16 ; R4024.1 103.96,16.24 104.72,15.47 v1(104.77,15.47) ; PR5417.1 41.07,94.76 v1(41.32,94.5) ; v1(94.41,48.23) 93.47,48.23 93.44,48.2 92.91,48.2 92.63,48.48 92.63,48.73 93.6,49.7 93.6,51.43 91.59,53.43 91.59,88.81 94.11,91.33 v1(95.65,91.33)
SIO_SLP_S5#: length 4.6
  TOP w0.102: TP1703.1 101.09,45.38 101.37,45.66 v1(101.45,45.66)
  BOTTOM w0.102: v1(101.45,45.66) 101.6,45.81 102.54,45.81 102.66,45.69 103.81,45.69 103.98,45.86 104.62,45.86 CPU1.AY16
SKTOCC#: length 6.8
  BOTTOM w0.102: CPU1.A65 126.01,73.17 126.03,73.19 126.64,73.19 127.56,74.12 127.56,74.12 128.24,74.8 128.24,74.96 128.24,76.72 129.21,77.69 TP402.1
SLEEVE: length 3.8
  TOP w0.203: HDA27.30 19.49,17.31 19.29,17.11 18.62,17.11 v2(18.49,16.98) 18.49,15.56 EC2906.1
SLEEVE_R: length 11.7
  L6 w1.016: HPMIC1.3 8.15,10.94 13.1,10.94 14.22,12.06 v3(17.5,12.06)
  vias: v2(19.23,13.43)
SLP_LAN#: length 3.9
  TOP w0.127: v1(102.26,45.2) 102.49,44.97 TP1704.1
  BOTTOM w0.102: CPU1.AW15 105.07,44.99
  BOTTOM w0.127: v1(102.26,45.2) 102.36,45.2 102.42,45.27 104.05,45.27 104.06,45.26 104.39,45.26 104.41,45.28 104.77,45.28 105.07,44.99
SLP_S0_U: length 5.2
  TOP w0.127: v2(128.83,102.25) 128.52,102.56 v1(128.32,102.56) 128.27,102.51 R4012.2
  BOTTOM w0.127: U4003.2 128.34,99.76 128.07,100.04 128.07,102.3 v1(128.32,102.56)
SLP_SUS#: length 1.1
  TOP w0.102: TP1711.1 108.68,45.13 v1(108.68,44.95)
  BOTTOM w0.102: v1(108.68,44.95) 109,44.63 CPU1.AN15
SM_DRAMRST#: length 45.7
  TOP w0.127: R504.1 88.89,18.24 ED501.2 88.87,17.35 R505.2 89.33,16.35 89.71,16.73 v2(89.71,16.91) 89.71,17.47 v1(89.69,17.49)
  L3 w0.127: v1(89.69,17.49) 89.84,17.49 90.54,18.19 96.13,18.19 96.58,18.63 98.32,18.63 100.57,20.89 100.57,24.3 102.22,25.95 104.32,25.95 106.24,27.86 106.24,32.28 v1(105.41,33.11)
  L4 w0.127: v1(105.41,33.11) 105.41,34.23 104.33,35.31 104.33,38.94 104.45,39.06 104.45,39.58 104.44,39.59 104.44,40.89 105.34,41.78 105.34,42.59 106.43,43.68 106.97,43.68 v1(107.38,44.09)
  BOTTOM w0.127: CPU1.AT13 107.05,43.76 v1(107.38,44.09)
SM_INTRUDER#: length 30
  TOP w0.102: R1730.2 96.24,23.07 96.44,23.27 96.44,24.39 v2(97.35,25.3) 97.8,25.75 v1(98.09,25.75)
  L4 w0.102: v1(108.03,45.91) 107.62,45.51 105.91,45.51 105.51,45.1 105.51,44.29 103.6,42.38 103.6,39.46 103.4,39.26 103.4,38.04 100.73,35.38 100.73,35.02 97.51,31.79 97.51,30.9 98.12,30.29 98.12,25.9 98.09,25.87 v1(98.09,25.75)
  BOTTOM w0.102: v1(108.03,45.91) 108.35,45.59 CPU1.AP16
SM_PGCNTL: length 164.3
  TOP w0.127: v2(40.64,16.43) 41.15,16.43 v1(41.2,16.48)
  L3 w0.127: v1(41.2,16.48) 40.75,16.92 40.75,23.88 40.31,24.33 40.31,28.77 37.77,31.31 37.77,38.81 35.61,40.97 35.61,42.36 34.85,43.12 34.85,44.39 34.4,44.84 34.4,50.83 37.01,53.43 37.01,65.52 42.47,70.98 42.47,79.72 44.73,81.98 44.73,84.88 47.79,87.94 47.91,87.94 48.17,88.2 48.17,88.32 52.91,93.06 64.13,93.06 66.12,91.06 69.43,91.06 69.84,91.47 79.49,91.47 80.15,90.81 95.82,90.81 v1(96.32,91.3)
  L4 w0.127: v1(96.32,91.3) 96.95,90.67 96.95,81.26 101.81,76.39 102.53,76.39 v1(103.78,75.14)
  BOTTOM w0.127: v1(41.2,16.48) 36.93,16.48 34.97,14.52 34.97,13.04 34.08,12.15 Q501.S ; CPU1.AW67 104.92,74.73 104.75,74.9 104.03,74.9 v1(103.78,75.14)
SM_PGCNTL_R: length 8.7
  TOP w0.127: PR5125.1 v2(31.16,9.49) 31.16,9.23 v1(31.42,8.98)
  BOTTOM w0.127: v1(31.42,8.98) 31.42,9.11 30.96,9.57 R506.2 30.96,9.85 32.69,11.58 32.69,13.15 33.59,14.05 Q501.D
SM_RCOMP_0: length 17.7
  TOP w0.203: v1(107.38,46.83) 106.92,47.29 106.45,47.29 105.81,47.92
  TOP w0.508: R501.1 95.45,54.91 v2(96.47,53.89) 97.18,53.18 97.18,52.52 97.64,52.06 102.46,52.06 103.68,50.84 103.68,49.47 105.23,47.92 105.81,47.92
  BOTTOM w0.305: v1(107.38,46.83) 107.38,46.69 107.69,46.37 CPU1.AR18
SM_RCOMP_1: length 16.2
  TOP w0.203: 105.21,47.13 105.51,46.83 106.73,46.83 v1(106.73,46.83)
  TOP w0.508: R502.1 95.45,54.02 96.44,53.03 96.44,52.37 98.17,50.64 98.17,50.15 98.9,49.42 102.44,49.42 v2(103.45,48.4) 104.66,47.2 105.14,47.2 105.21,47.13
  BOTTOM w0.305: v1(106.73,46.83) 106.73,46.68 107.03,46.37 CPU1.AT18
SM_RCOMP_2: length 16.5
  TOP w0.203: v1(106.08,45.92) 106.01,45.85 104.84,45.85 104.49,45.51
  TOP w0.508: R503.1 94.69,52.32 96.62,50.38 96.62,48.33 97.79,47.16 v2(101.24,47.16) 102.05,47.16 103.71,45.51 104.49,45.51
  BOTTOM w0.305: CPU1.AU18 106.4,46.35 106.08,46.02 v1(106.08,45.92)
SMB_ALERT#: length 20.8
  L4 w0.102: v1(116.18,27.19) 116.13,27.25 116.06,27.25 115.09,28.22 115.09,31.8 115.07,31.81 115.07,33.03 115.44,33.4 115.44,35.22 115.68,35.46 115.68,39.56 115.88,39.76 115.88,41.43 116.11,41.66 116.62,41.66 116.91,41.94 v1(117.34,41.94)
  BOTTOM w0.102: CPU1.R10 117.71,41.94 v1(117.34,41.94) ; v1(116.18,27.19) 116.18,26.51 v2(115.39,25.72) 115.29,25.63 114.68,25.63 R1836.2
SML0_ALERT#: length 17.6
  TOP w0.102: v1(113.71,29.47) 113.44,29.47 v2(113.18,29.2)
  L4 w0.102: v1(110.95,26.18) 112.32,27.55 112.32,28.07 v1(113.71,29.47)
  BOTTOM w0.102: CPU1.W1 115.66,36.28 115.66,33.66 115.73,33.59 115.73,33.11 116.59,32.24 116.59,30.66 116.03,30.1 114.79,30.1 114.16,29.47 v1(113.71,29.47) ; v1(110.95,26.18) 110.95,26.11 111.49,25.57 112.01,25.57 R1823.1 113,24.58 R1822.2
SML0_SMBCLK: length 21
  TOP w0.089: v1(111.6,27.93) 112.48,27.05 115.23,27.05 115.47,27.29 115.47,27.79 115.49,27.81 v2(115.49,28.29) 115.49,28.92 116.17,29.6 v1(116.71,29.6)
  L3 w0.127: v1(116.71,29.6) 116.46,29.85 116.46,36.14 117.04,36.72 117.04,40.97 v1(117.35,41.28)
  BOTTOM w0.089: v1(111.6,27.93) 111.66,27.87 RN1807.5 ; v1(117.35,41.28) 117.72,41.28 CPU1.R9
SML0_SMBDATA: length 13.1
  BOTTOM w0.089: RN1807.6 112.24,28.11 v2(112.34,28.21) 113.08,28.95 113.08,29.43 113.54,29.89 114.12,29.89 114.6,30.37 115.92,30.37 116.32,30.77 116.32,32.24 115.54,33.01 115.54,33.51 115.47,33.58 115.47,36.75 CPU1.W2
SML1_SMBCLK: length 177.2
  TOP w0.089: v1(113.71,28.83) 113.28,28.4 113.28,28.02 113.53,27.77 113.88,27.77 116.14,30.03 117.06,30.03 119.11,27.98 120.45,27.98 121.98,29.51 121.98,30.17 125.03,33.22 125.95,33.22 127,34.27 131.01,34.27 131.94,33.34 v1(132.51,33.34)
  L4 w0.127: v1(132.51,33.34) 133.64,32.21 145.38,32.21 145.64,31.95 146.41,31.95 148.02,33.56 156.57,33.56 157,33.13 160.59,33.13 v1(161.59,34.13) 162.4,34.94 163.62,34.94 166.11,37.44 166.11,43.71 166.11,46.83 167.31,48.03 167.31,60.53 167.98,61.2 167.98,69.45 170.71,72.18 170.71,80.81 172.15,82.25 172.93,82.25 173.19,82.51 173.19,82.94 v1(172.72,83.4)
  L6 w0.102: v1(196.02,38.79) 195.86,38.62 193.19,38.62 192.62,38.05 189.58,38.05 188.86,37.33 188.42,37.33 187.84,36.75 185.67,36.75 185.06,36.14 183.77,36.14 183.62,36.28 183.4,36.5 182.27,37.63 182.24,37.66 181.89,37.66 180.41,36.19 177.22,36.19 176.93,35.91 167.41,35.91 167.07,36.25 166.15,36.25 164.59,34.69 162.15,34.69 v1(161.59,34.13)
  BOTTOM w0.089: v1(196.02,38.79) 196.44,38.79 197.06,38.16 197.06,37.51 197.53,37.04 197.69,37.04 R2459.2 ; v1(172.72,83.4) 172.92,83.21 176.1,83.21 177.6,84.71 177.6,86.19 177.34,86.45 176.66,86.45 176.06,87.05 176.06,87.4 GPU1.E8 ; RN1807.7 112.75,27.86 v1(113.71,28.83) 114.05,28.83 v2(114.4,29.18) 115.03,29.81 116.13,29.81 116.86,30.54 116.86,32.25 115.91,33.2 115.91,35.97 116.03,36.09 116.03,36.49 116,36.58 116,36.87 116.03,36.94 116.03,37.14 115.99,37.25 115.99,37.48 CPU1.W3 ; Q2601.3 132.58,33.41 v1(132.51,33.34)
SML1_SMBDATA: length 182.2
  TOP w0.089: v1(113.71,28.2) v2(114.46,28.95) 115.81,30.3 117.17,30.3 119.22,28.25 120.34,28.25 121.72,29.62 121.72,30.28 124.92,33.49 125.84,33.49 126.89,34.54 131.13,34.54 131.82,33.84 v1(132.05,33.84)
  L4 w0.127: v1(132.05,33.84) 132.64,33.84 133.89,32.59 145.53,32.59 145.79,32.33 146.25,32.33 147.86,33.94 156.73,33.94 157.16,33.51 160.34,33.51 v1(160.96,34.13) 162.15,35.32 163.46,35.32 165.73,37.59 165.73,43.55 165.73,43.55 165.73,44.38 165.73,44.38 165.73,46.99 166.93,48.19 166.93,60.68 167.6,61.36 167.6,69.63 170.33,72.36 170.33,80.96 172.06,82.69 v1(172.74,82.69)
  L6 w0.102: v1(196.42,39.29) 195.86,39.29 195.5,38.93 192.12,38.93 191.55,38.36 189.45,38.36 188.83,37.74 185.84,37.74 185.57,37.47 185.57,37.07 184.94,36.44 183.9,36.44 183.8,36.53 183.67,36.66 183.62,36.72 182.4,37.94 182.37,37.96 181.71,37.96 180.23,36.49 177.09,36.49 176.81,36.21 167.54,36.21 167.19,36.55 166.02,36.55 164.46,34.99 161.82,34.99 v1(160.96,34.13)
  BOTTOM w0.089: v1(132.05,33.84) 134.35,33.84 134.51,33.68 134.51,33.09 134.51,32.94 135.35,32.11 Q2601.6 ; GPU1.E9 176.65,86.83 176.76,86.73 177.72,86.73 178.05,86.4 178.05,84.78 176.12,82.85 172.9,82.85 v1(172.74,82.69) ; CPU1.V3 116.18,37.76 116.18,37.28 116.21,37.18 116.21,36.9 116.18,36.83 116.18,36.63 116.21,36.53 116.21,35.97 116.09,35.85 116.09,33.29 117.13,32.25 117.13,29.4 116.91,29.18 115.37,29.18 114.38,28.2 v1(113.71,28.2) 113.33,27.82 RN1807.8 ; R2447.2 198.37,36.03 198.37,37.11 198.17,37.31 197.64,37.31 197.33,37.62 197.33,38.27 196.42,39.18 v1(196.42,39.29)
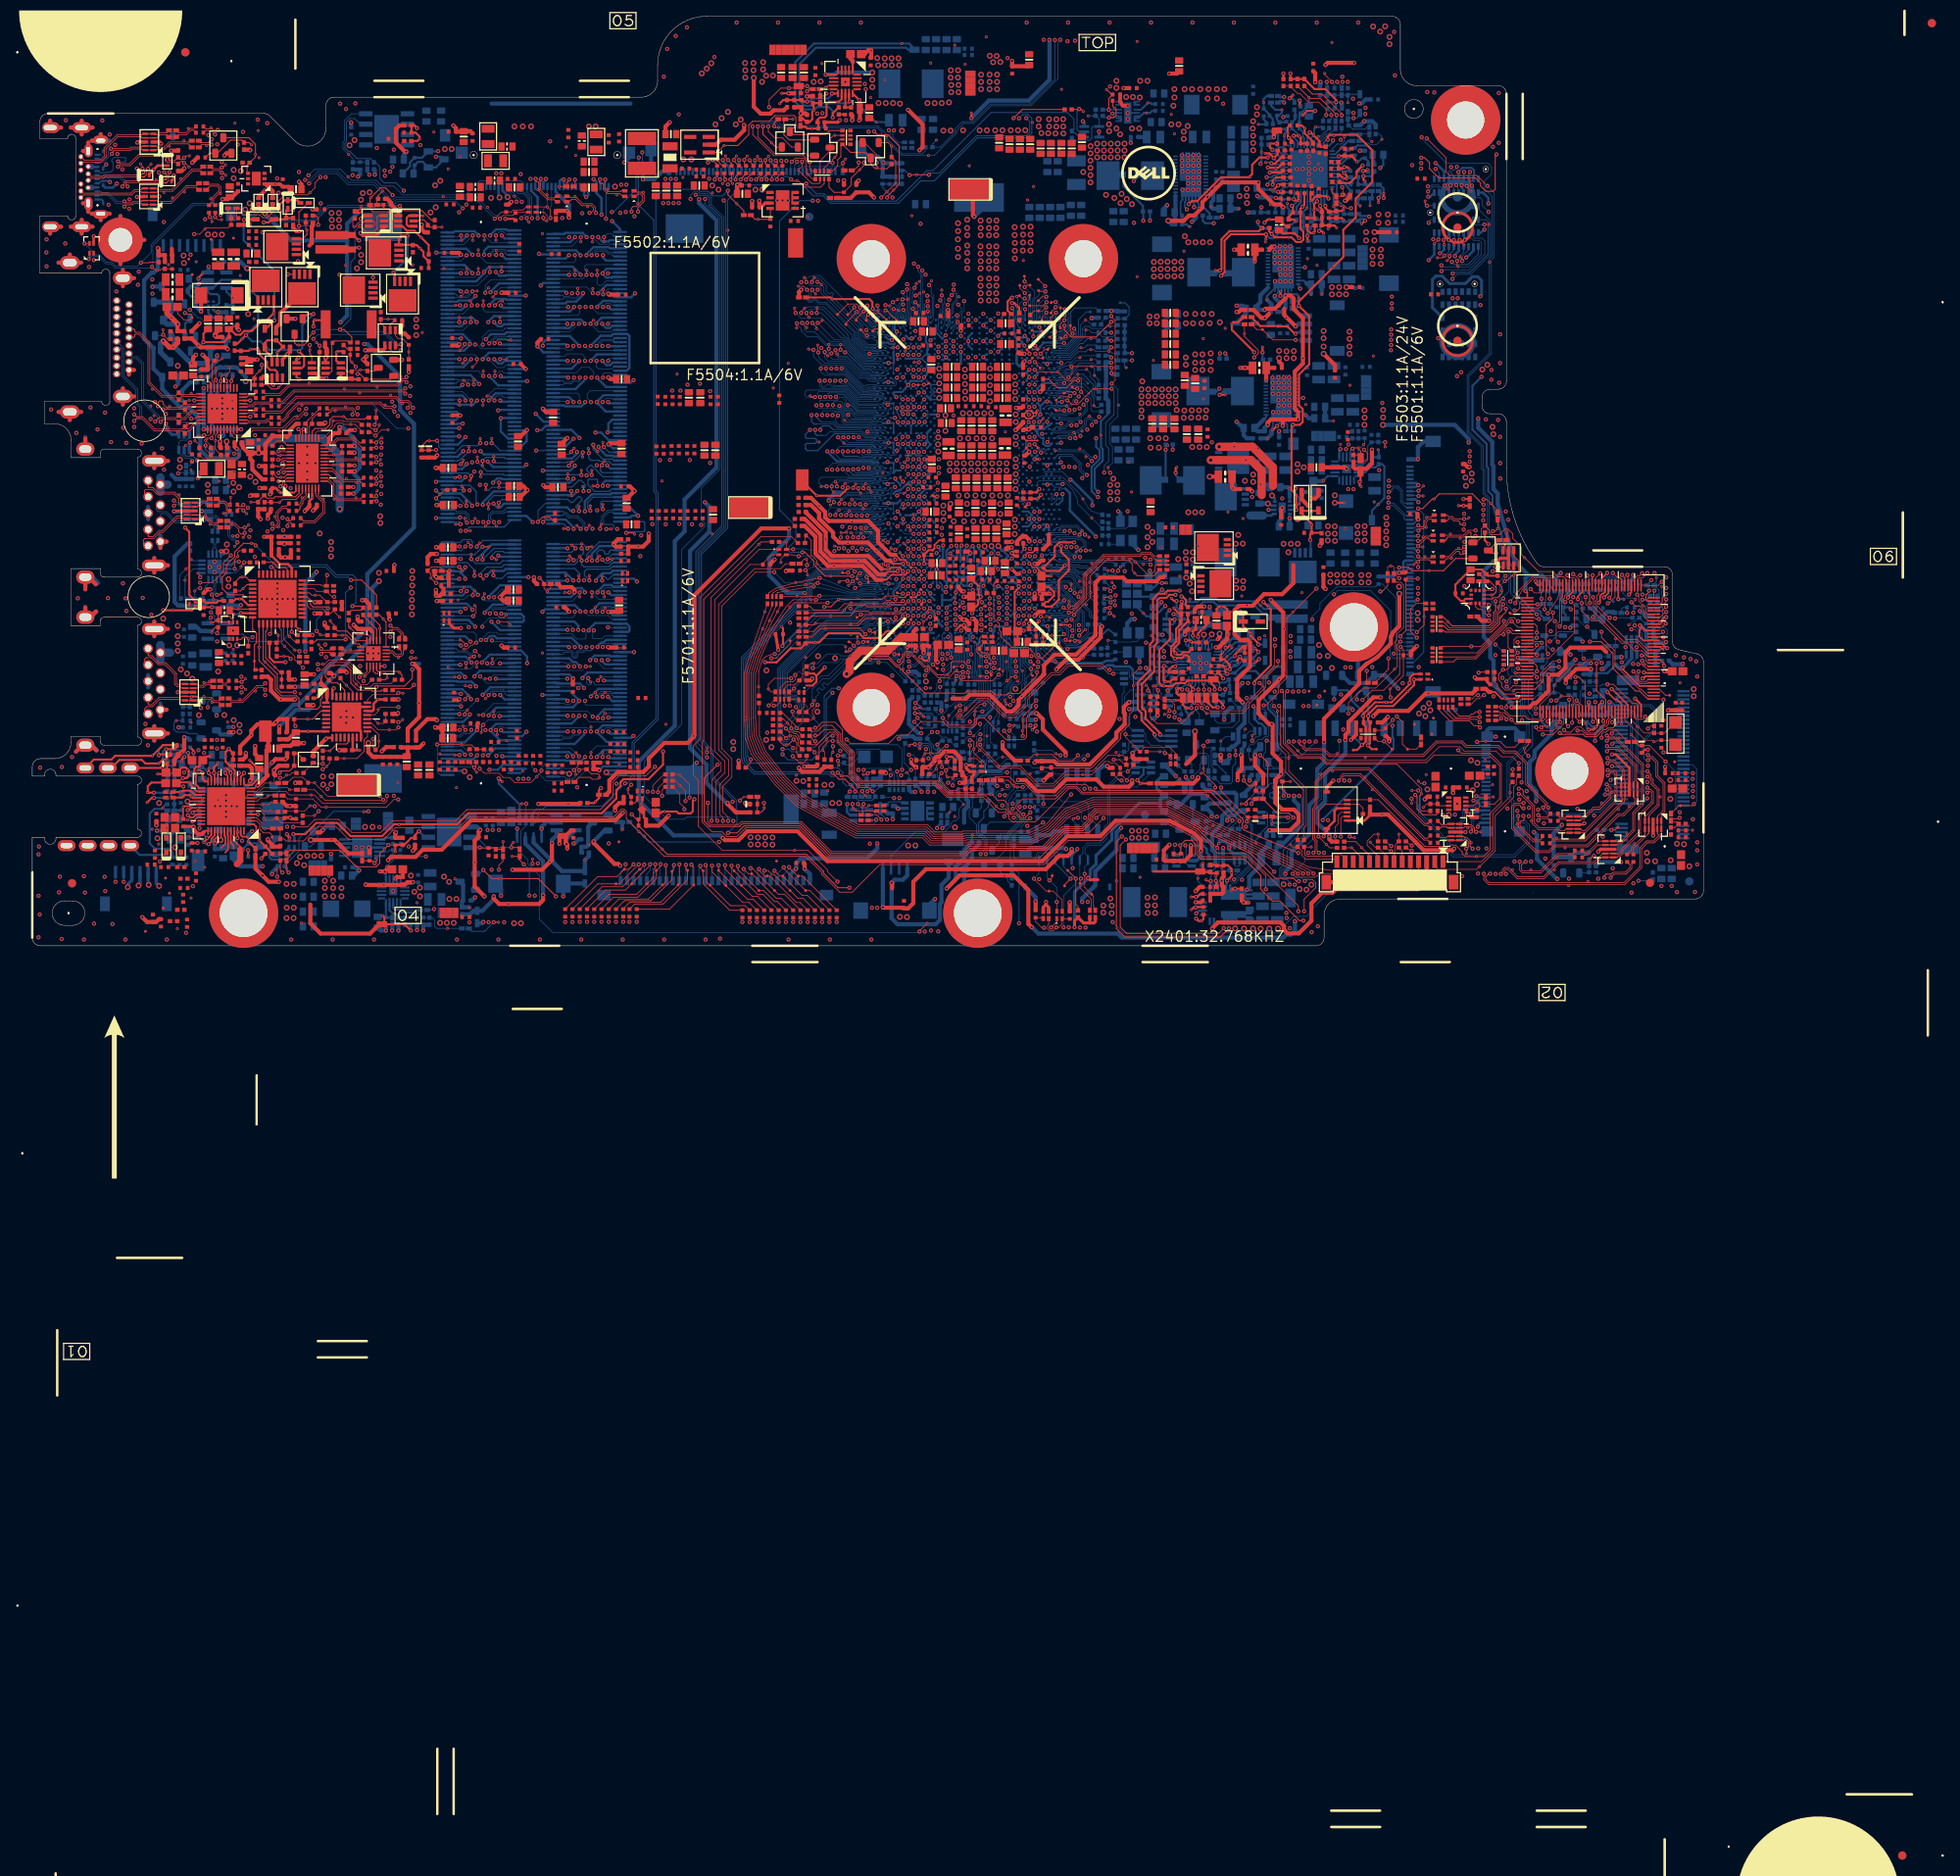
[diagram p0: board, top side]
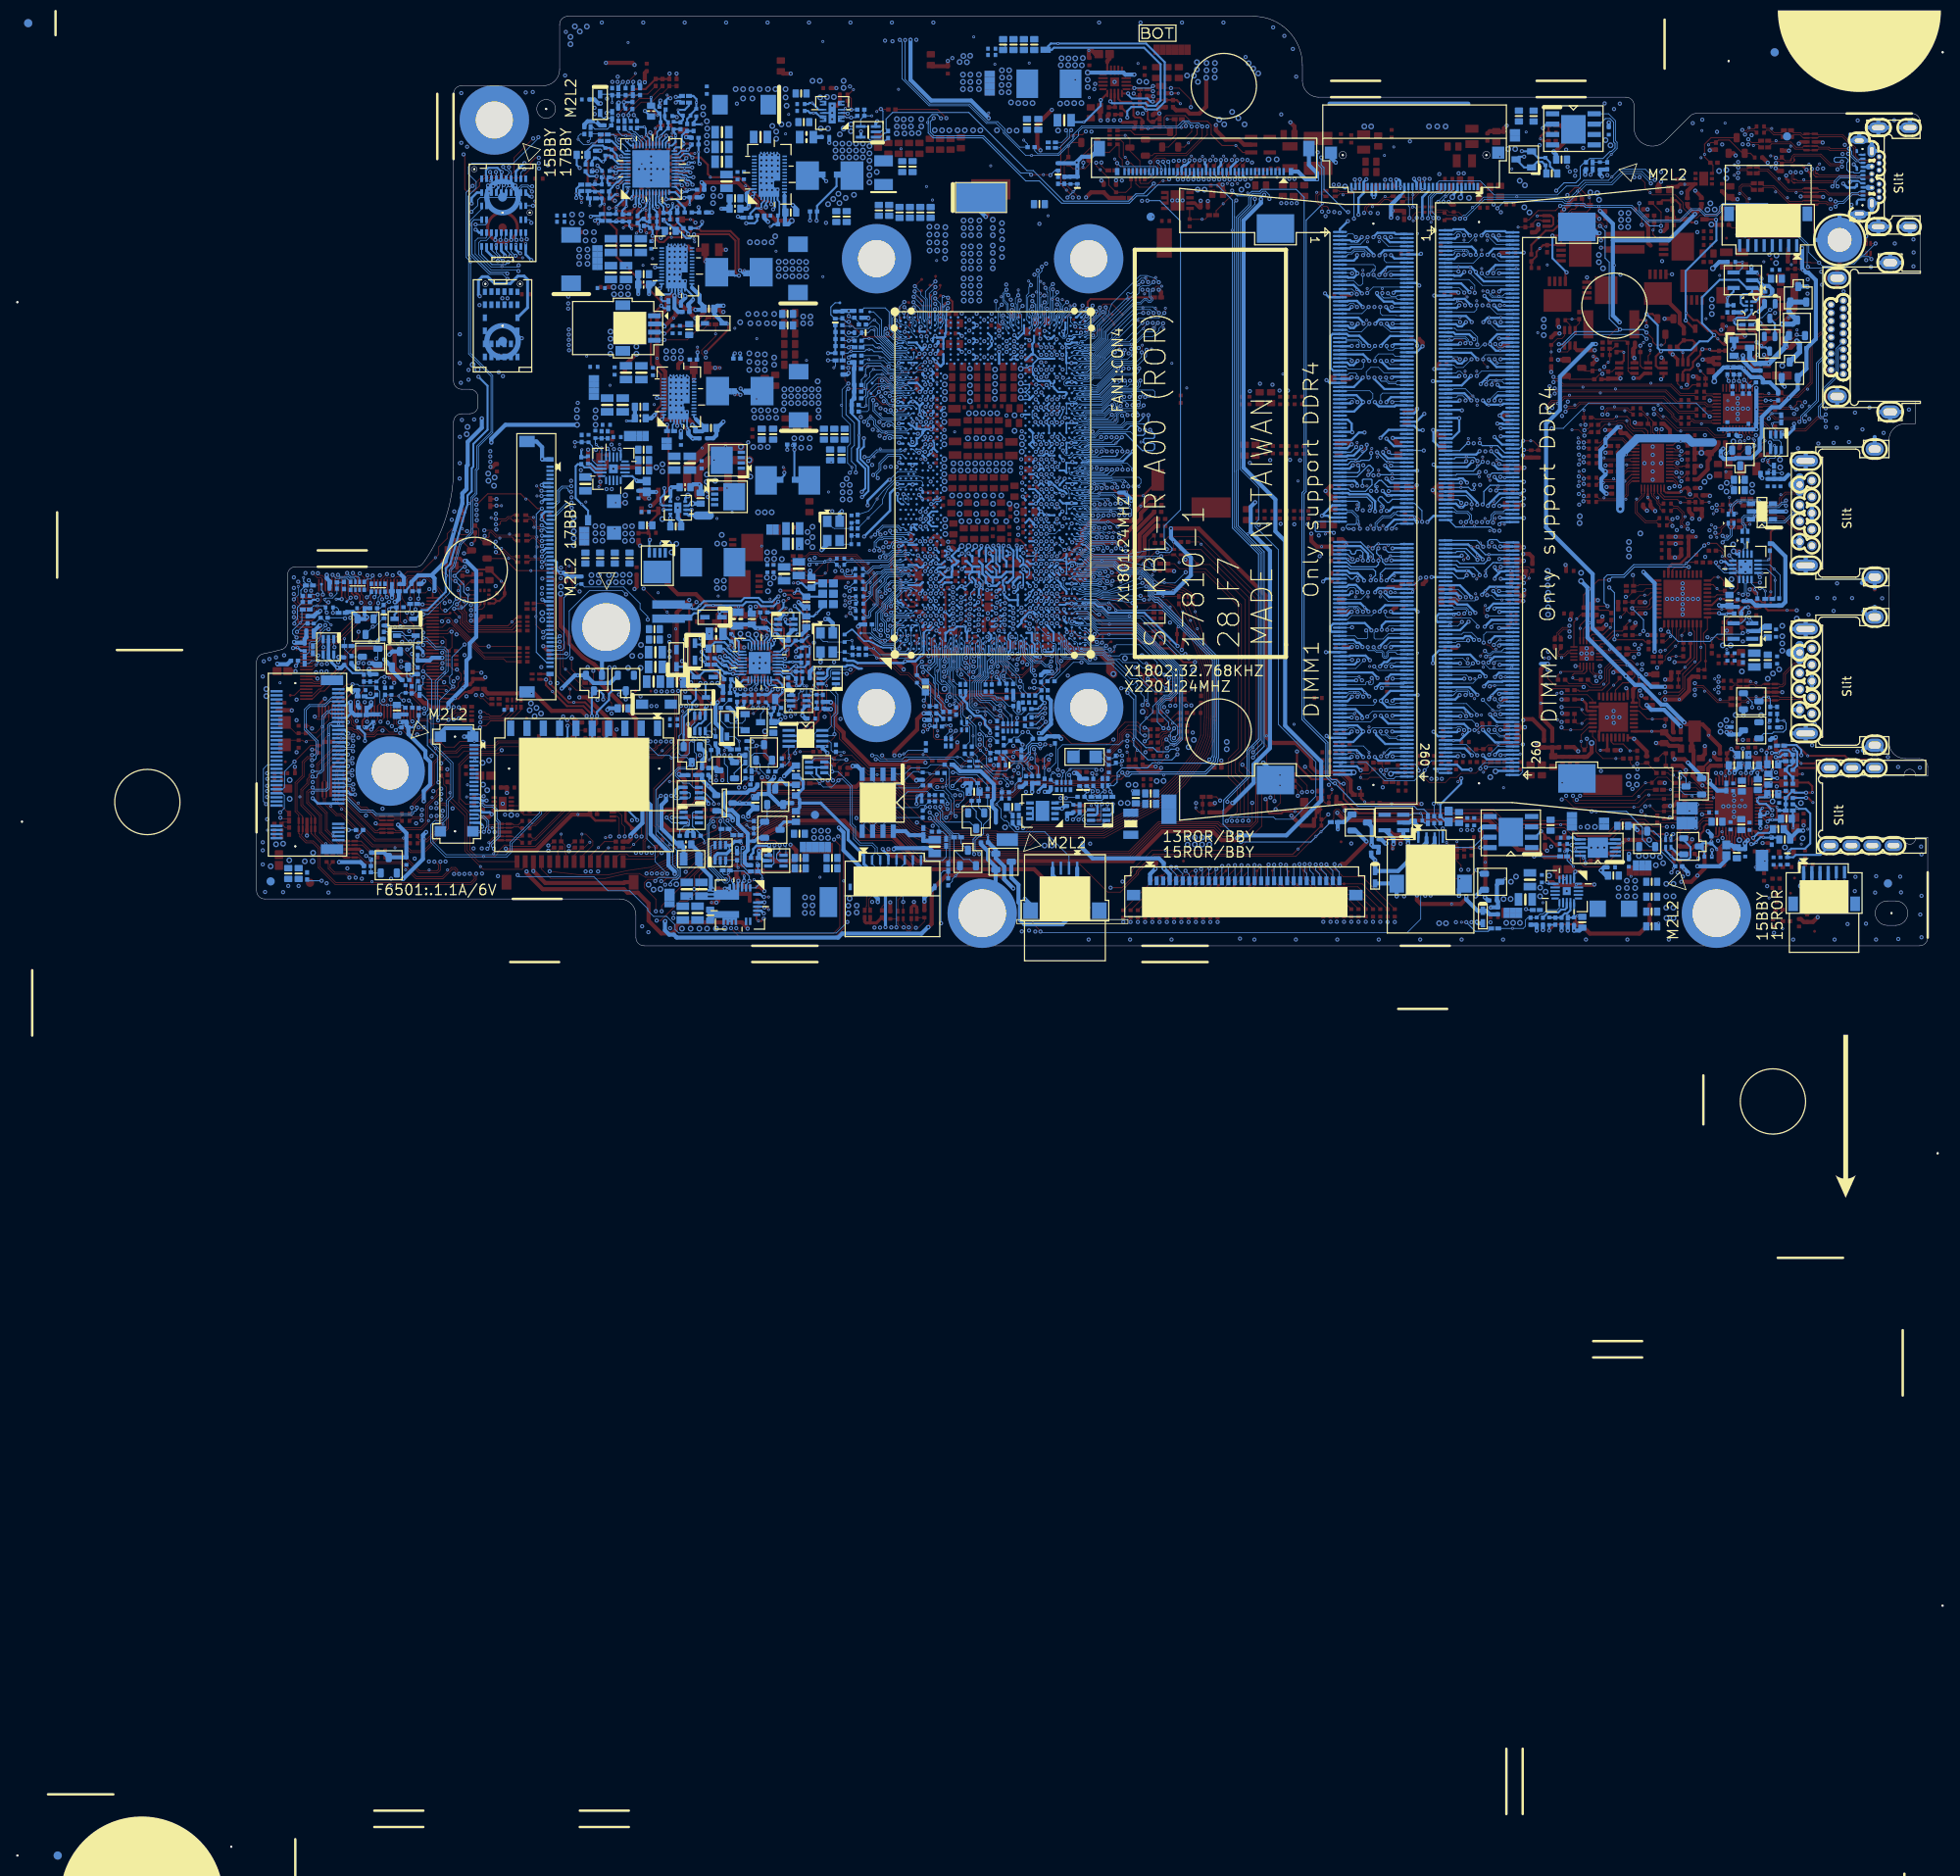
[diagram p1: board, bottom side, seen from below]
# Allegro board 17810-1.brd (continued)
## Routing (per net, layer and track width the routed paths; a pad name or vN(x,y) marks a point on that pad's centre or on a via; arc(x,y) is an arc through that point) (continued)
SML1ALERT#: length 2.5
  TOP w0.102: v1(110.06,40.33) 109.85,40.33 v2(109.24,39.73) 109.19,39.68 R1837.2
  BOTTOM w0.102: v1(110.06,40.33) 110.01,40.33 CPU1.AM7
SPI_CLK_CPU: length 22.2
  TOP w0.089: v1(93.01,32.78) 90.98,32.78 90.22,32.02 v2(90.22,31.46) 90.56,31.12 RN1803.8
  BOTTOM w0.089: CPU1.AV2 105.8,36.84 105.51,36.55 105.51,36.2 104.86,35.55 103.38,35.55 103.29,35.63 101.15,35.63 100.48,34.97 99.44,34.97 97.59,33.11 96.75,33.11 94.75,31.11 93.19,31.11 92.94,31.36 92.94,32.71 v1(93.01,32.78)
SPI_CLK_ROM: length 66.1
  TOP w0.089: RN1803.1 90.31,29.46 v1(90.27,29.46) ; R9132.1 78.81,20.24 v2(79.4,19.65) 80.07,18.98 v1(80.07,17.73)
  L4 w0.127: v1(120.17,16.78) 120.11,16.78 119.65,16.32 118.57,16.32 118.49,16.41 109.6,16.41 108.27,15.08 107.93,15.08 107.23,15.08 106.35,14.2 102.65,14.2 102.23,14.62 93.41,14.62 92.08,15.95 87.39,15.95 86.62,16.72 81.08,16.72 v1(80.07,17.73) 80.07,22.29 87.24,29.46 v1(90.27,29.46)
  BOTTOM w0.089: v1(120.17,16.78) 120.59,17.21 120.59,17.46 R2505.2
SPI_CLK_ROM_R: length 10.1
  BOTTOM w0.089: R2505.1 EC2503.1 122.88,17.22 123.48,17.22 123.76,16.94 128,16.94 128.62,16.32 128.62,15.33 129.34,14.62 SPI25.6
SPI_CLK_ROM_TPM2: length 43
  TOP w0.089: U9104.19 41.58,27.28 42.41,26.46 v2(43.76,26.46) 44.58,26.46 v1(44.88,26.76) ; R9132.2 76.71,19.32 v1(76.71,18.81)
  L3 w0.127: v1(44.88,26.76) 44.88,26.22 53.1,17.99 55.82,17.99 56.7,18.88 65.38,18.88 66.02,18.23 66.28,17.97 75.91,17.97 76.71,18.77 v1(76.71,18.81)
SPI_CS2#_R: length 109.6
  TOP w0.089: R9130.2 44.78,27.52 v1(44.88,27.42) 45.11,27.42 v2(45.39,27.7) ; R9133.2 v1(35.61,22.31) 34.55,22.31 Q9104.G 33.25,21.23 R9129.2
  L3 w0.127: v1(46.53,36.04) 45.99,35.5 45.99,33.81 48.82,30.99 48.82,24.62 51.38,22.05 53.36,22.05 54.16,21.24 55.69,21.24 55.79,21.14 56.21,21.14 56.44,21.37 61.18,21.37 62.02,20.53 66.08,20.53 66.63,21.09 67.2,21.09 67.21,21.09 67.26,21.11 67.41,21.27 69.08,21.27 69.65,20.71 72.1,20.71 72.88,21.48 81.33,21.48 82.48,22.64 82.88,22.64 84.19,22.64 85.25,21.57 89.56,21.57 89.83,21.83 89.83,22.58 92.08,24.83 93.49,24.83 95,26.35 95,30.27 98.43,33.7 99.16,33.7 99.87,34.41 103.4,34.41 v1(103.73,34.74)
  L4 w0.127: v1(46.53,36.04) 45.32,34.83 45.32,27.87 v1(44.88,27.42) 39.77,22.32 35.62,22.32 v1(35.61,22.31)
  BOTTOM w0.089: R1826.1 104.72,34.74 v1(103.73,34.74)
SPI_CS2#_R_TPM2: length 3.5
  TOP w0.089: U9104.20 41.86,27.78 v2(42.39,27.25) 43,27.25 43.28,27.52 R9130.1 R9140.2
SPI_CS_CPU_N0: length 20.3
  TOP w0.089: v1(96.26,29.51) 95.63,28.87 95.63,28.39 95.78,28.24 v2(95.78,27.93) 95.5,27.65 R1812.2
  BOTTOM w0.089: v1(96.26,29.51) 96.04,29.73 96.04,30.5 96.46,30.92 96.46,31.04 96.21,31.29 96.21,31.41 96.4,31.6 96.53,31.6 96.77,31.36 96.9,31.36 97.09,31.55 97.09,31.67 96.84,31.92 96.84,32.04 97.03,32.23 97.16,32.23 97.4,31.99 97.53,31.99 99.52,33.98 99.53,33.98 100.07,34.51 102.89,34.51 102.91,34.53 102.94,34.53 103.57,35.16 105.9,35.16 106.23,35.5 106.23,37.13 106.25,37.22 106.27,37.24 106.27,37.41 106.49,37.63 CPU1.AU3
SPI_CS_ROM_N0: length 68.6
  TOP w0.089: R1812.1 93.78,27.65 93.17,28.26 93.17,28.69 v1(93.19,28.72)
  L4 w0.127: v1(93.19,28.72) 92.76,28.29 87.36,28.29 83.56,24.48 83.56,21.74 86.51,18.79 89.1,18.79 91.13,16.76 92.42,16.76 93.75,15.43 102.57,15.43 102.99,15.01 106.02,15.01 108.24,17.24 118.87,17.24 v1(118.92,17.19)
  BOTTOM w0.089: SPI25.1 125.41,21.04 124.64,21.81 122.6,21.81 122.22,22.19 R2501.1 120.45,22.19 119.92,21.67 119.92,19.8 119.97,19.75 119.97,19.4 119.72,19.15 v2(118.92,19.15) 118.74,18.97 118.36,18.97 118.16,18.77 118.16,17.94 v1(118.92,17.19)
SPI_HOLD_CPU: length 18.8
  TOP w0.089: R1811.2 94.88,28.64 94.88,28.71 95.6,29.43 v1(95.6,29.53) 95.78,29.71 v2(95.78,30.06)
  BOTTOM w0.089: v1(95.6,29.53) 95.6,31.45 96.9,32.74 97.76,32.74 99.72,34.71 102.86,34.71 103.5,35.34 105.82,35.34 106.05,35.57 106.05,37.15 106.09,37.31 106.09,37.79 106.49,38.18 CPU1.AU4
SPI_HOLD_ROM: length 77
  TOP w0.089: v1(122.3,17.01) v2(122.86,17.01) ; v1(93.6,29.25) 93.99,28.86 93.99,28.64 R1811.1 94.61,29.25 RN1802.4
  L4 w0.127: v1(93.6,29.25) 93.32,29.53 93.32,29.6 92.21,30.71 86.77,30.71 78.81,22.75 78.81,16.65 80.73,14.73 91.58,14.73 92.9,13.4 99.3,13.4 99.75,12.96 102.85,12.96 103.11,12.7 103.11,12.38 103.4,12.09 105.99,12.09 107.75,13.86 108.44,13.86 108.77,13.86 110.11,15.19 117.98,15.19 118.15,15.03 120.26,15.03 120.76,15.53 120.76,16 121.33,16.56 121.85,16.56 122.29,17.01 v1(122.3,17.01)
  BOTTOM w0.089: v1(122.3,17.01) 122.57,17.01 123,16.58 R2503.2
SPI_HOLD_ROM_R: length 6
  BOTTOM w0.089: R2503.1 127.18,15.71 128.07,14.82 SPI25.7
SPI_IRQ#_TPM2: length 103.8
  TOP w0.102: v1(41.78,25.37) 41.78,24.32 R9119.2 42.49,24.43 v2(42.49,25.06) 42.49,25.84 41.55,26.78 U9104.18
  L3 w0.102: v1(41.78,25.37) 41.78,24.43 41.25,23.89 41.25,17.81 43.35,15.7 47.32,15.7 55.24,7.78 69.48,7.78 69.76,7.5 95.4,7.5 100.95,13.05 103.81,13.05 105.21,11.65 115.85,11.65 v1(116.25,11.24)
  BOTTOM w0.102: v1(116.25,11.24) 116.77,11.76 116.77,12.91 116.3,13.38 116.07,13.38 115.76,13.69 115.76,14.81 114.86,15.71 114.86,16.6 115.24,16.98 R1808.2
SPI_SI_CPU: length 19.1
  TOP w0.089: RN1803.6 92.17,31.51 92.63,31.97 93.44,31.97 94,32.53 94.03,32.53 94.44,32.94 94.44,33.72 94.46,33.75 94.46,33.84 94.85,34.23 R1824.2 94.99,34.33 95.15,34.33 95.45,34.64 v2(95.79,34.64) 95.79,34.14 v1(95.68,34.03)
  BOTTOM w0.089: CPU1.AV3 105.8,37.76 105.54,37.5 105.54,36.85 105.33,36.64 105.33,36.28 104.79,35.73 103.45,35.73 103.37,35.81 101.07,35.81 100.43,35.17 99.11,35.17 98.65,34.71 96.9,34.71 96.21,34.03 v1(95.68,34.03)
SPI_SI_ROM: length 68.3
  TOP w0.089: v1(92.23,29.43) 92.17,29.48 RN1803.3 ; R9139.1 79.32,21 v2(79.4,20.92) 80.57,19.75 v1(80.57,18.18)
  L4 w0.127: v1(120.17,17.42) 119.48,16.73 118.74,16.73 118.66,16.82 109.43,16.82 108.1,15.49 107.06,15.49 106.18,14.61 102.82,14.61 102.4,15.03 93.58,15.03 92.25,16.36 90.19,16.36 88.16,18.38 82.85,18.38 81.86,17.39 81.05,17.39 80.57,17.87 v1(80.57,18.18) 80.57,22.21 87.05,28.69 91.49,28.69 v1(92.23,29.43)
  BOTTOM w0.089: R2506.2 120.39,18.02 120.39,17.98 120.17,17.76 v1(120.17,17.42)
SPI_SI_ROM_R: length 12.7
  BOTTOM w0.089: SPI25.5 130.61,14.72 130.12,15.21 129.79,15.21 129.49,15.51 129.49,17.29 129.11,17.67 126.24,17.67 124.97,18.93 122.65,18.93 122.4,18.69 EC2501.1 R2506.1
SPI_SI_ROM_TPM2: length 45.4
  TOP w0.089: U9104.21 41.95,28.28 42.39,28.72 v2(42.39,28.95) 42.7,29.25 v1(44.88,29.25) ; v1(76.07,18.86) 76.07,19.65 77.42,21 R9139.2
  L3 w0.127: v1(44.88,29.25) 45.51,28.62 45.51,26.16 53.27,18.4 55.65,18.4 56.53,19.28 65.54,19.28 66.43,18.4 75.76,18.4 76.07,18.71 v1(76.07,18.86)
SPI_SO_CPU: length 19.8
  TOP w0.089: v1(93.52,33.19) 93.55,33.16 93.55,32.63 93.27,32.35 92.38,32.35 91.67,31.64 RN1803.7
  BOTTOM w0.089: CPU1.AW3 105.04,37.67 104.68,37.31 104.45,37.31 104.21,37.08 104.21,36.75 104.06,36.59 104.06,36.27 103.88,36.08 103.6,36.08 103.5,36.19 100.94,36.19 100.68,35.93 100.03,35.93 99.69,36.26 v2(99.69,36.64) 99.44,36.9 96.62,36.9 94.44,34.72 94.44,33.98 94.73,33.69 94.73,33.51 94.53,33.31 94.35,33.31 94.06,33.6 93.94,33.6 v1(93.52,33.19)
SPI_SO_ROM: length 72.4
  TOP w0.089: RN1803.2 91.67,29.87 91.24,29.43 v1(90.9,29.43) ; v1(79.93,16.73) 79.93,16.93 79.37,17.49 79.37,18.58 R9134.1
  L4 w0.127: v1(90.9,29.43) 90.9,29.45 90.45,29.9 87.11,29.9 79.62,22.42 79.62,17.04 v1(79.93,16.73) 80.35,16.31 86.45,16.31 87.22,15.54 91.91,15.54 93.24,14.22 102.06,14.22 102.48,13.79 106.52,13.79 107.4,14.67 107.76,14.67 108.44,14.67 109.77,16 118.32,16 118.44,15.88 v1(119.15,15.88)
  BOTTOM w0.089: R2507.1 120.29,20.95 120.29,19.95 120.34,19.9 v2(120.34,19.63) 120.34,19.25 119.65,18.56 119.65,18.28 119.37,18 119.37,16.1 v1(119.15,15.88)
SPI_SO_ROM_R: length 8.7
  BOTTOM w0.089: R2507.2 121.51,21.05 v2(122.3,21.05) 122.5,21.25 EC2502.1 123.59,21.25 123.7,21.35 124.33,21.35 125.95,19.73 127.89,19.73 128.07,19.9 SPI25.2
SPI_SO_ROM_TPM2: length 49.2
  TOP w0.089: R9134.2 77.21,19.07 v1(77.21,18.38) ; U9104.24 41.08,30.13 41.72,30.77 44.65,30.77 v1(44.88,31) 45.33,31 45.39,30.94 v2(45.44,30.94)
  L3 w0.127: v1(44.88,31) 44.38,30.51 44.38,28.33 44.42,28.29 44.42,26.1 53.27,17.25 56.09,17.25 57.31,18.47 65.21,18.47 66.11,17.57 73.94,17.57 74.05,17.45 76.28,17.45 v1(77.21,18.38)
SPI_WP_CPU: length 15.9
  TOP w0.089: v1(93.37,31.54) 92.95,31.12 RN1803.5
  BOTTOM w0.089: CPU1.AW2 105.13,37.02 104.7,36.59 104.7,36.27 104.33,35.91 103.53,35.91 103.43,36.01 101.01,36.01 100.53,35.53 v2(100.28,35.53) 99.08,35.53 98.84,35.77 97.4,35.77 96.21,34.59 95.64,34.59 95.25,34.2 95.25,33.42 v1(93.37,31.54)
SPI_WP_ROM: length 74.5
  TOP w0.089: RN1802.3 93.87,30.23 RN1803.4 92.76,29.53 v1(92.86,29.43)
  L4 w0.127: v1(120.32,15.71) 120.04,15.43 118.31,15.43 118.15,15.6 109.94,15.6 108.61,14.27 107.58,14.27 106.71,13.39 99.89,13.39 99.47,13.81 93.07,13.81 91.74,15.14 87.05,15.14 86.29,15.9 80.13,15.9 79.22,16.82 79.22,22.59 86.94,30.31 91.98,30.31 v1(92.86,29.43)
  BOTTOM w0.089: v1(120.32,15.71) 119.76,16.27 v2(119.74,16.27) 119.74,17.85 120.02,18.13 120.02,18.41 120.63,19.02 121.66,19.02 R2508.1
SPI_WP_ROM_R: length 7.4
  BOTTOM w0.089: R2508.2 123.38,19.65 123.69,19.35 128.4,19.35 129.34,20.29 SPI25.3
SPK_ID: length 128.8
  TOP w0.102: v1(114.86,34.15) 114.17,34.84 112.8,34.84 112.62,34.66 112.62,33.65 v2(112.19,33.21) 110.96,33.21 109.84,34.33 109.35,34.33 107.61,36.08 107.12,36.08 106.6,35.56 106.6,35.3 v1(106.22,34.92) ; v1(76.33,21.94) 75.23,20.84 71.93,20.84 71.17,20.08 71.17,18.23 69.62,16.68 53.26,16.68 51.91,15.33 44.17,15.33 42.72,13.89 39.17,13.89 37.57,15.49 34.64,15.49 33.73,14.57 v1(31.98,14.57)
  L6 w0.102: v1(106.22,34.92) 104.85,34.92 103.86,33.93 101.3,33.93 100.15,32.77 96.68,32.77 95.96,32.05 92.91,32.05 92.43,31.56 86.87,31.56 77.29,21.99 76.38,21.99 v1(76.33,21.94) ; v1(31.98,14.57) 31.52,14.11 31.04,14.11 30.66,13.73 30.66,10.25 29.64,9.24 23.95,9.24 23.04,8.32 11.68,8.32 v1(11.2,7.84)
  BOTTOM w0.089: CPU1.AB1 114.32,36.27 114.32,34.71 114.86,34.18 v1(114.86,34.15)
  BOTTOM w0.102: R2047.2 115.49,32.48 115.11,32.86 115.11,33.42 115.1,33.43 115.1,33.94 114.88,34.15 v1(114.86,34.15) ; SPK1.5 v1(11.2,7.84)
SPKR: length 88.8
  TOP w0.254: v1(89.82,34.76) 89.89,34.76 89.91,34.74 91.24,34.74 92.95,36.46 94.2,36.46 R2006.2 94.92,37.18 v2(95.98,37.18) 96.44,37.18 97.59,38.32 101.34,38.32 101.94,37.72 103.9,37.72 104.75,38.58 105.38,38.58 v1(105.51,38.45) ; v1(32,13.68) 33.45,13.68 34.82,15.05 37.39,15.05 38.99,13.45 42.9,13.45 44.34,14.9 52.09,14.9 53.44,16.25 69.8,16.25 71.6,18.05 71.6,19.09 72.11,19.6 72.11,20.06 72.46,20.41 75.52,20.41 77.32,22.21 v1(77.32,23.82)
  L6 w0.254: v1(89.82,34.76) 88.26,34.76 v1(77.32,23.82)
  BOTTOM w0.254: RN2701.2 32.12,13.56 v1(32,13.68) ; v1(105.51,38.45) 105.51,38.75 CPU1.AW5
SRTC_RST#: length 62.6
  TOP w0.127: RN1801.3 74.15,17.8 73.84,17.49 C1805.1 EC1806.1 73.4,18.3 73.04,18.67 v2(73.04,19.14) 73.04,19.36 v1(73.4,19.73)
  L3 w0.127: v1(98.09,31) 98.3,30.8 99.46,30.8 102.12,33.46 103.87,33.46 104.7,34.28 104.7,35.18 103.87,36.02 103.87,44.55 106.55,47.24 108.27,47.24 v1(108.68,46.83) ; v1(73.4,19.73) 74.24,20.57 81.71,20.57 82.05,20.91 89.84,20.91 91.97,23.04 v1(91.97,23.46)
  BOTTOM w0.127: v1(98.09,31) 98.09,30.95 97.33,30.19 97.33,24.53 95.58,22.79 92.64,22.79 v1(91.97,23.46) ; v1(108.68,46.83) 109,46.5 CPU1.AN18
SSD_DEVSLP: length 116.9
  TOP w0.102: v1(155.19,4.23) 155.19,4.89 148.81,11.28 148.73,11.32 145.34,11.32 144.83,11.83 144.83,11.98 142.69,14.12 142.69,14.12 142.23,14.36 141.99,14.48 140.04,15.49 138.89,16.08 130.84,16.08 v1(130.42,15.66) ; v1(201.93,15.69) 201.8,15.56 201.09,15.56 R6301.1 201.04,15.16 201.6,15.16 R6304.1 201.34,14.49 R6303.2
  L3 w0.102: v1(119.87,30.52) 120.36,30.52 120.97,29.91 120.97,22.43 126.06,17.34 128.69,17.34 130.36,15.66 v1(130.42,15.66)
  L4 w0.102: v1(201.93,15.69) 200.08,15.69 197.18,12.78 197.18,8.88 196.26,7.97 v1(196.26,7.66)
  L6 w0.102: v1(155.19,4.23) 155.62,3.8 156.18,3.8 158.93,6.54 194.86,6.54 195.98,7.66 v1(196.26,7.66)
  BOTTOM w0.102: CPU1.J3 120.78,37.39 120.78,35.25 120.99,35.03 120.99,32.62 v2(120.8,32.43) 120.48,32.43 119.78,31.73 119.78,30.61 v1(119.87,30.52)
SSD_PEDET: length 12.7
  TOP w0.127: AFTP6303.1 194,14.19 v1(193.56,14.19)
  L6 w0.127: v1(196.87,7.97) 195.38,9.47 195.38,12.37 v1(193.56,14.19)
  BOTTOM w0.127: SSD1.69 193.81,14.44 v1(193.56,14.19) R6310.2 ; v1(196.87,7.97) 198.5,7.97 R6306.1
SSEQ0_A0: length 3.8
  TOP w0.127: R3845.2 R3846.1 37.84,56.67 37.58,56.94 v2(37.13,56.94) 36.32,57.75 U3801.11
SSEQ1: length 5.7
  TOP w0.127: R3852.2 R3844.1 29.31,54.32 v2(30.3,54.32) 30.68,54.7 32.31,54.7 33.1,55.5 U3801.3
SUS_CLK: length 184.3
  TOP w0.089: R1807.1 93.09,50.13 89.3,50.13 81.83,42.66 81.83,25.31 81.03,24.51 81.03,20.9 81.64,20.29 81.64,14.64 84.58,11.7 v2(93.44,11.7) 95.09,11.7 97.48,9.31 97.48,9.09 v1(98.7,7.87) ; R2425.1 198.37,26.94 v1(198.05,26.63)
  L3 w0.127: v1(198.05,26.63) 197.39,25.97 197.39,16.71 193.11,12.42 190.54,12.42 185.7,7.59 158.5,7.59 156.61,5.69 154.66,5.69 152.89,3.92 144.03,3.92 142.26,2.15 132,2.15 130.16,3.99 123.07,3.99 121.7,5.37 121.7,6.17 121.47,6.4 118.01,9.86 100.69,9.86 v1(98.7,7.87)
SUSACK#_R: length 25.1
  TOP w0.127: v2(108.79,24.15) 108.81,24.17 v1(108.81,24.73)
  L4 w0.127: v1(108.68,42.28) 108.7,42.28 109.21,41.78 110.22,41.78 110.46,41.54 110.46,40.83 110.73,40.55 110.73,38.44 110.25,37.95 110.25,35.44 109.99,35.18 109.99,34.31 110.31,33.99 110.31,31.24 109.4,30.33 109.4,27.76 108.29,26.65 108.29,25.25 v1(108.81,24.73)
  BOTTOM w0.127: R1708.2 110.79,23.11 110.25,23.65 110.25,24.4 109.84,24.81 108.89,24.81 v1(108.81,24.73) ; CPU1.AP11 108.35,42.58 108.65,42.28 v1(108.68,42.28)
SUSCLK: length 13.4
  TOP w0.089: R1807.2 94.71,50.16 EC1803.2 94.89,50.28 95.48,49.7 95.48,47.9 96.16,47.21 v2(96.16,46.85) 96.87,46.14 100.53,46.14 v1(100.81,45.86)
  BOTTOM w0.089: v1(100.81,45.86) 100.91,45.86 101.12,46.07 101.7,46.07 101.75,46.02 102.61,46.02 102.72,45.91 103.09,45.91 103.13,45.88 103.68,45.88 CPU1.BA17
SYS_PRES1#: length 8.1
  TOP w0.102: R4301.2 169.64,24.1 AFTP4315.1 167.94,24.73 167.94,27.43 v1(167.26,28.11)
  BOTTOM w0.102: BATT1.7 167.7,27.67 v1(167.26,28.11)
SYS_PWROK: length 91.8
  TOP w0.127: v1(200.28,41.55) 199.77,41.04 KBC24.28 ; R1717.1 123.9,37.9 ED1702.1 124.01,38.02 v2(124.99,38.02) 126.29,38.02 v1(126.47,38.19)
  L4 w0.127: v1(164.26,34.15) 163.32,34.15 161.66,32.49 156.74,32.49 156.31,32.92 148.28,32.92 147.14,31.79 147.14,31.28 146.45,30.59 136.48,30.59 135.49,31.58 132.68,31.58 127.15,37.1 126.5,37.1 126.26,37.34 126.26,37.98 v1(126.47,38.19)
  L6 w0.127: v1(200.28,41.55) 197.38,38.64 196.51,38.64 196.25,38.39 196.25,38.39 196.17,38.31 193.32,38.31 192.75,37.74 189.71,37.74 188.99,37.01 188.56,37.01 187.49,35.95 186.75,35.95 186.08,35.27 185.57,35.27 184.88,34.59 183.9,34.59 182.45,33.14 181.73,33.14 181.44,33.43 181.43,33.43 181.39,33.47 181.39,33.47 181.29,33.56 180.27,34.59 178.92,34.59 178.63,34.88 169.2,34.88 168.44,34.12 164.3,34.12 v1(164.26,34.15)
  BOTTOM w0.127: CPU1.B6 125.14,39.24 125.41,38.96 125.76,38.96 125.77,38.97 126.04,38.97 126.29,38.72 126.29,38.37 v1(126.47,38.19)
SYSPWR_PRES: length 23.3
  TOP w0.102: KBC24.120 194.01,28.69 194.01,27.73 v1(193.67,27.4) ; v2(190.96,10.68) 191.29,11.01 v1(191.41,11.01)
  L4 w0.102: v1(193.67,27.4) 194.1,26.96 194.1,18.02 191.41,15.33 v1(191.41,11.01)
  BOTTOM w0.102: Q2417.G 190.74,8.92 R2454.1 R2464.2 190.8,9.8 R2463.2 190.83,10.56 191.29,11.01 v1(191.41,11.01)
T_CRIT#: length 4.1
  BOTTOM w0.102: R2601.1 141.2,21.35 R2604.2 140.03,22.09 139.57,22.55 v2(139.57,22.98) 139.57,23.46 139.62,23.51 THM261.4
THERM_SYS_SHDN#: length 7.5
  BOTTOM w0.102: v2(143.28,21.15) 143.53,21.4 R2602.1 144.19,21.42 144.19,23.26 143.86,23.59 142.49,23.59 141.77,22.86 Q2602.S 142.11,22.29 R2601.2
THM_SML1_CLK: length 18.7
  TOP w0.089: C2608.1 v2(138.23,23.79) 138.66,23.79 v1(138.84,23.61) 139.09,23.61 RN2602.4
  BOTTOM w0.089: v1(138.84,23.61) 138.84,23.96 138.26,24.54 137.17,24.54 136.47,25.24 136.47,25.96 136.03,26.41 135.53,26.41 THM261.8 134.91,26.39 134.4,26.91 134.4,28.05 133.86,28.58 133.86,30.35 133.87,30.36 133.87,30.56 134.67,31.36 135.92,31.36 136.39,31.83 136.39,33.27 136.25,33.41 Q2601.4
THM_SML1_DATA: length 16.2
  TOP w0.089: v1(134.01,25.92) 134.01,25.57 v2(135.13,24.45) C2609.1 136.35,24.35 139.39,24.35 140.19,23.56 RN2602.3
  BOTTOM w0.089: Q2601.1 133.83,31.03 133.6,30.8 133.6,28.47 134.03,28.03 134.03,25.95 v1(134.01,25.92) 134.03,25.92 134.22,25.74 THM261.7
TOP_MUX_N: length 93.3
  TOP w0.102: v1(11.68,93.07) 11.45,93.3 11.45,93.44 11.55,93.54 16.34,93.54 ED3804.1 16.46,93.51 16.69,93.75 16.69,94.69 v1(16.81,94.81) ; v2(35.1,36.9) 35.42,36.58 v1(35.42,36.4) 35.62,36.2 36.41,36.2 36.64,36.43 EL3801.3
  L6 w0.127: v1(35.42,36.4) 35.23,36.22 34.84,36.22 34.71,36.35 34.71,36.86 35.62,37.77 36.16,37.77 37.41,39.03 37.41,40.47 38.29,41.34 38.29,49.48 35.88,51.88 32.96,51.88 32.09,52.76 31.55,53.29 30.06,53.29 29.39,53.95 27.19,53.95 26.03,55.11 24.08,55.11 23.54,55.64 23.54,56.66 24.15,57.27 24.15,60.65 24.94,61.43 24.94,62.7 23.93,63.72 22.66,63.72 20.75,65.62 20.75,67.02 19.49,68.28 19.24,68.28 14.73,72.79 14.73,78.71 14.1,79.34 14.1,84.14 13.77,84.47 13.77,91.03 16.65,93.91 16.65,94.64 v1(16.81,94.81)
  BOTTOM w0.102: USB1.A7 8.15,94.46 8.28,94.32 10.85,94.32 11.48,93.69 11.48,93.27 v1(11.68,93.07)
TOP_MUX_N_L: length 2.6
  TOP w0.102: v2(39.01,36.29) 39.01,36.15 ; 39.01,36.15 39.55,36.15 39.63,36.23 U3802.17 ; 39.01,36.15 38.37,36.15 38.09,36.43 EL3801.4
TOP_MUX_P: length 92.8
  TOP w0.102: EL3801.2 36.64,35.74 36.41,35.97 35.62,35.97 v1(35.42,35.77) ; v1(16.18,94.81) 16.46,94.52 16.46,94.02 ED3804.2 16.1,93.92 15.95,93.77 15.19,93.77 ; 15.19,93.77 v2(15.19,93.9) ; 15.19,93.77 11.45,93.77 11.22,93.54 11.22,93.24 v1(11.05,93.07)
  L6 w0.127: v1(35.42,35.77) 35.23,35.95 34.73,35.95 34.44,36.24 34.44,36.97 35.51,38.04 36.04,38.04 37.15,39.14 37.15,40.58 38.02,41.45 38.02,49.37 35.77,51.62 32.85,51.62 31.44,53.03 29.94,53.03 29.28,53.69 27.08,53.69 25.92,54.84 23.97,54.84 23.28,55.53 23.28,56.77 23.89,57.38 23.89,60.76 24.67,61.54 24.67,62.59 23.81,63.45 22.54,63.45 20.48,65.51 20.48,66.91 19.38,68.01 19.13,68.01 14.46,72.68 14.46,78.6 13.83,79.23 13.83,84.03 13.5,84.36 13.5,91.14 16.38,94.02 16.38,94.61 v1(16.18,94.81)
  BOTTOM w0.102: v1(11.05,93.07) 11.25,93.27 11.25,93.6 10.75,94.1 8.28,94.1 8.14,93.96 USB1.A6
TOP_MUX_P_L: length 2.4
  TOP w0.102: U3802.18 39.63,35.83 39.55,35.92 38.23,35.92 38.06,35.74 EL3801.1
TOUCH_PAD_INTR#: length 60.7
  TOP w0.102: v1(95.96,25.77) 96.34,25.77 97.08,26.51 98.23,26.51 98.86,25.88 98.86,24.99 100.3,23.55 100.3,21.09 101.54,19.85 110.75,19.85 112.22,18.38 116.89,18.38 v2(118.16,17.11) 118.51,16.76 119.29,16.76 119.9,16.15 120.52,16.15 121.21,15.46 122.16,15.46 v1(122.33,15.63)
  BOTTOM w0.102: CPU1.BA5 103.58,38.6 103.22,38.6 102.26,37.63 96.83,37.63 92.57,33.38 92.57,31.21 93.05,30.73 93.6,30.73 94.99,29.33 94.99,28.59 96.57,27.02 96.57,26.1 96.24,25.77 v1(95.96,25.77) ; v1(122.33,15.63) 122.27,15.63 121.21,14.57 R404.2 120.75,13.99 120.32,13.55 R410.2
TOUCH_PANEL_INTR#: length 2.8
  TOP w0.127: TP409.1 127.05,39.34 v1(127.18,39.21)
  BOTTOM w0.127: v1(127.18,39.21) 126.84,39.21 126.41,39.64 126.19,39.64 125.91,39.91 CPU1.A7
TOUCH_PANEL_PD#: length 1.6
  TOP w0.102: TP404.1 104.57,37.73 v1(104.95,38.11)
  BOTTOM w0.102: v1(104.95,38.11) 104.91,38.15 CPU1.AY5
TOUCH_REPORT_SW: length 244.4
  TOP w0.127: v1(155.19,11.37) 148.58,14.15 148.32,14.41 148.32,14.96 148.42,15.07 148.42,15.47 144.94,18.95 144.82,18.95 144.72,19.05 130.53,19.05 v1(130.33,19.25) ; v1(123.15,33.53) 123.15,33.11 120.96,30.92 120.1,30.92 120.05,30.97 119.68,30.97 119.47,30.75 v2(118.49,30.75) 118.03,30.75 117.87,30.92 117.85,30.92 117.55,31.22 114.58,31.22 114.3,30.94 112.95,30.94 112.93,30.97 109.4,30.97 106.16,34.21 105.93,34.21 104.99,35.14 102.74,35.14 v1(102.69,35.09)
  L3 w0.127: v1(130.33,19.25) 129.47,20.11 128.8,20.11 128.28,20.64 126.83,20.64 122.6,24.86 122.6,25.91 121.87,26.65 121.87,30.29 121.69,30.47 121.69,32.07 v1(123.15,33.53) ; v1(102.69,35.09) 102.39,34.8 99.68,34.8 98.99,34.1 98.26,34.1 94.3,30.14 94.3,28.87 93.47,28.05 93.16,28.05 92.18,27.07 90.36,27.07 86.51,23.22 82.84,23.22 v1(82.7,23.08)
  L4 w0.127: v1(70.33,89.12) 70.47,89.26 71.79,89.26 72.07,88.98 74.2,88.98 77.27,92.04 v1(81.33,92.04) ; v1(155.19,11.37) 155.22,11.37 155.7,11.85 157.04,11.85 161.45,12.41 161.48,12.41 162.79,13.72 164.41,13.72 165.17,14.48 176.38,14.48 182.37,20.47 182.85,20.47 189.22,26.83 189.22,27.98 187.34,29.86 187.34,31.29 186.68,31.95 186.68,33.87 186.38,34.17 v1(186.38,36.31)
  BOTTOM w0.127: v1(81.33,92.04) 81.39,91.98 82.66,91.98 82.98,91.65 82.98,90.74 84.54,89.18 84.54,58.33 84.53,58.32 84.53,51.48 81.34,48.29 81.34,24.45 82.7,23.09 v1(82.7,23.08) ; v1(186.38,36.31) 186.15,36.31 185.57,36.9 185.57,37.46 185.34,37.68 D2402.A 186.57,38.02 187.04,38.49 189.24,38.49 R2429.1 ; TCBD1.32 70.65,92.58 70.33,92.26 v1(70.33,89.12)
TP1_AY4: length 3.8
  TOP w0.102: TP610.1 v1(101.85,37.23)
  BOTTOM w0.102: CPU1.AY4 104.56,38.41 104.16,38.02 103.83,38.02 103.66,37.84 103.07,37.84 102.64,37.41 102.11,37.41 101.93,37.23 v1(101.85,37.23)
TP2_BB3: length 3.3
  TOP w0.102: TP611.1 101.14,37.23 v1(101.22,37.15)
  BOTTOM w0.102: v1(101.22,37.15) 101.34,37.15 101.67,36.82 101.98,36.82 102,36.85 102.5,36.85 103.16,37.51 CPU1.BB3
TP4_BB5: length 1.5
  TOP w0.102: v1(102.64,38.65) 102.89,38.4 TP609.1
  BOTTOM w0.102: v1(102.64,38.65) 102.87,38.65 103.14,38.92 CPU1.BB5
TP5_AU5: length 1.2
  TOP w0.102: TP607.1 106.42,39.21 v1(106.73,39.51)
  BOTTOM w0.102: v1(106.73,39.51) 106.4,39.19 CPU1.AU5
TP6_AT5: length 1.2
  TOP w0.102: TP608.1 107.7,39.83 v1(107.38,39.51)
  BOTTOM w0.102: CPU1.AT5 107.05,39.19 v1(107.38,39.51)
TP_EN#: length 76.8
  TOP w0.127: v1(190.93,42.02) 190.93,42.03 190.88,42.08 190.88,43.02 190.81,43.09 KBC24.49 ; RN2405.4 172.95,40.3 v2(173.55,39.7) 174.04,39.21 178.55,39.21 179.12,39.77 179.12,40.84 179.37,41.09 v1(179.37,42.23)
  L4 w0.127: v1(179.37,42.23) 179.37,38.44 178.09,37.16 178.09,35.8 172.98,30.69 172.98,28.11 171.15,26.27 170.32,26.27 165.79,21.75 158.64,21.75 156.73,19.84 156.18,19.84 155.8,19.46 153.22,19.46 149.86,16.11 147.81,16.11 147.53,15.83 v1(145.21,15.83)
  L6 w0.127: v1(179.37,42.23) 179.37,41.49 180.41,40.45 183.18,40.45 184.13,41.4 184.69,41.4 185.24,41.95 187.46,41.95 187.72,41.69 188.78,41.69 188.9,41.56 190.35,41.56 190.8,42 190.92,42 v1(190.93,42.02)
  BOTTOM w0.127: R6504.1 144.66,15.28 v1(145.21,15.83)
TP_ON#_GATE: length 5.6
  BOTTOM w0.127: v2(144.78,14.8) 144.4,14.42 R6504.2 ; R6504.2 143.34,14.44 Q6502.G 142.26,15.52 Q6503.G ; R6504.2 C6502.2
TP_VDD: length 40.2
  TOP w0.356: v1(127.76,2.28) 127.76,3.04 R6511.1
  TOP w0.381: 129.63,2.8 130.14,2.8 130.31,2.97 RN6503.2 ; 129.63,2.8 128.87,2.8 R6511.1 ; 129.63,2.8 RN6503.1 ; 124.27,5.06 v1(124.27,5.37) ; 124.27,5.06 124.27,5.02 124.59,4.7 RN6501.1 ; 124.27,5.06 123.92,4.71 RN6501.2 ; AFTP6531.1 129.63,8.09 v1(129.42,8.31)
  L6 w0.381: v1(127.76,2.28) 127.76,2.76 126.9,3.62 126.02,3.62 v1(124.27,5.37)
  BOTTOM w0.381: R6514.2 138.28,16.96 C6503.1 ; R6502.2 138.45,20.77 137.84,20.16 137.84,19.3 R6503.1 138.28,17.95 C6503.1 ; v1(127.76,2.28) 127.76,6.63 129.12,7.98 129.12,8 v1(129.42,8.31) 129.42,8.33 129.69,8.6 129.69,9.31 130.4,10.02 TP1.1 130.4,11.06 132.33,13 132.33,14.14 135.69,17.49 C6503.1
TP_WAKE_KBC#: length 137.1
  TOP w0.102: KBC24.33 198.04,44.19 198.09,44.14 199.26,44.14 v1(199.74,44.62) ; R6511.2 128.19,4.79 127.91,5.07 v1(127.91,8.21) 127.91,8.25 AFTP6536.1
  L4 w0.102: v1(126.41,2.25) 127.63,1.03 154.36,1.03 157.05,3.73 157.05,4.06 159.29,6.3 192.86,6.3 196.51,9.95 196.51,12.4 198.96,14.85 198.96,37.82 199.24,38.11 199.24,42.11 199.74,42.61 v1(199.74,44.62)
  BOTTOM w0.102: R410.1 120.32,10.89 120.75,10.46 122.68,10.46 123.07,10.85 123.07,11.18 123.28,11.4 126.16,11.4 126.4,11.16 TP1.5 126.4,9.73 v1(127.91,8.21) 127.91,7.64 126.41,6.14 v1(126.41,2.25)
TPAN_VDD: length 2.8
  BOTTOM w0.305: TCBD1.26 67.65,92 v1(67.89,91.76) 68.15,92.02 TCBD1.27
  vias: v2(66.6,96.87)
TPCLK_C: length 8.5
  TOP w0.089: v1(122.78,8.22) 122.78,8.2 124.29,6.7 AFTP6532.1 125.14,6.7 126.23,5.61 RN6502.3
  BOTTOM w0.089: TP1.8 123.4,8.84 v1(122.78,8.22)
TPDATA_C: length 7.5
  TOP w0.089: v1(124.69,8.02) 125.02,8.35 AFTP6533.1 ; RN6502.4 v1(125.58,5.37)
  BOTTOM w0.089: TP1.7 124.4,8.31 v1(124.69,8.02) 125.58,7.13 v1(125.58,5.37)
TPM_GPIO0: length 14.5
  TOP w0.127: R9142.1 42.85,31.33 42.72,31.21 41.71,31.21 41.58,31.33 39.91,31.33 39.04,32.21 39.04,33.79 38.45,34.38 v2(36.88,34.38) 36.52,34.38 35.93,33.79 35.93,33 R9141.1 36.7,32.22 37.39,32.22 38.28,31.33 U9104.29
TPM_GPIO2: length 18.8
  TOP w0.127: v1(32.26,26.93) 32.1,27.08 R9120.1 v2(33.75,27.78) 34.39,27.78 35.39,28.78 U9104.3 ; Q9104.D 32.46,23.59 R9138.1 R9131.1 32.1,22 31.53,21.43 30.54,21.43 v1(30.34,21.23)
  L4 w0.127: v1(30.34,21.23) 30.34,21.23 30.34,23.19 32.26,25.11 v1(32.26,26.93)
  BOTTOM w0.127: v1(30.34,21.23) 29.63,20.52 Q9102.D
TPM_GPIO4: length 4.2
  TOP w0.127: R9133.1 v2(36.5,23.89) 37.34,24.73 38.53,24.73 38.78,24.98 U9104.13
TPM_ID: length 39.7
  TOP w0.102: R1913.2 123.85,21.86 R1912.1 124.96,21.79 129.83,21.79 133.4,25.37 133.4,26.03 134.52,27.15 134.52,28.39 134.96,28.83 v2(134.96,31.87) 134.96,33.28 135.71,34.03 v1(135.81,34.03)
  L4 w0.102: v1(135.81,34.03) 134.19,34.03 129.72,38.5 129.72,39.67 127.57,41.81 127.44,41.81 127.24,42.02 126.91,42.02 126.81,41.92 126.32,41.92 126.02,41.61 126.02,40.87 126.77,40.12 126.77,39.85 v1(126.78,39.85)
  BOTTOM w0.102: CPU1.D8 124.51,40.48 124.8,40.19 126.43,40.19 v1(126.78,39.85)
TPM_SPI_IRQ#: length 23.8
  L3 w0.102: v1(119.49,21.24) 119.05,21.68 119.05,23.79 120.19,24.93 120.19,26.18 120.21,26.2 120.21,27.89 118.88,29.21 118.88,31.41 119.68,32.21 119.68,33.24 120.04,33.6 v1(120.6,33.6)
  BOTTOM w0.089: CPU1.M2 119.75,36.99 119.98,36.71 119.98,36.61 120.01,36.48 120.01,35.29 119.94,35.21 119.94,35.2
  BOTTOM w0.102: R1808.1 115.24,19.65 116.56,20.97 118.79,20.97 119.07,21.24 v1(119.49,21.24) ; 119.94,35.2 119.94,34.26 v1(120.6,33.6)
TPM_VDD14: length 2.5
  TOP w0.305: v2(40.13,23.97) R9147.2 39.28,24.03 U9104.14
TPM_VDD22: length 3.3
  TOP w0.305: U9104.22 41.69,28.78 41.83,28.92 41.83,29.66 v2(42.37,30.19) R9149.2
TPM_VSB: length 3.6
  TOP w0.254: v2(35.41,32.99) R9144.2
  TOP w0.305: 36.12,30.45 36.12,29.92 U9104.1
  TOP w0.508: 36.12,30.45 36.12,31.43 35.45,32.1 R9144.2
TPS70933_EN: length 8.3
  TOP w0.127: Q3701.D 26.55,99.04 27.35,98.24 v2(27.35,96.99) 27.35,96.69 R3739.2 26.33,95.66 U3702.4
TPS70933_EN_G: length 6.8
  TOP w0.127: C3720.2 21.73,97.13 Q3701.G 22.69,97.13 24.31,98.75 25.65,98.75 R3738.2 26.59,98.44 v2(26.87,98.16)
TS#_DIMM0_1: length 6.1
  TOP w0.127: R1215.2 63.81,52.16 63.42,52.54 v2(62.89,52.54) 62.56,52.54 v1(61.97,51.96)
  BOTTOM w0.127: DM1.134 62.9,54.23 62,53.34 62,51.99 v1(61.97,51.96)
TS#_DIMM1_1: length 3.4
  TOP w0.127: v1(49.49,54.84) 49.99,55.33 v2(49.99,55.34) 49.99,55.34 50.53,55.87 R1312.2
  BOTTOM w0.127: DM2.134 49.89,54.44 v1(49.49,54.84)
TYPEC_5V: length 5.8
  TOP w0.254: PR4339.2 48.59,85.89 v2(47.7,86.78) 46.84,87.65 45.92,87.65 45.38,88.19 PQ4309.3
TYPEC_5V_L: length 3.9
  TOP w0.254: PQ4309.4 46.11,88.19 45.9,88.41 45.9,89.22 46.17,89.49 PQ4309.6 47.84,89.49 v2(47.88,89.45)
TYPEC_5V_SW:
  vias: v2(46.63,83.46)
TYPEC_5V_SW_R: length 14
  TOP w0.254: v1(46,87.04) 45.18,87.04 44.94,86.8 PU4305.4 46.62,85.9 PR4330.1 47.14,85.87 v2(47.55,85.46) 47.95,85.06 47.95,84.52 PR4339.1 PC4312.1 ; v1(44.27,82.54) 44.41,82.4 PU4306.4
  BOTTOM w0.254: v1(44.27,82.54) 46,84.27 v1(46,87.04)
TYPEC_CON_RXN1: length 16.7
  TOP w0.102: v2(18.21,94.02) 18.31,93.92 ; 18.31,93.92 17.1,92.7 15.39,92.7 15.25,92.84 ED3806.5 ED3806.6 13.5,92.84 13.33,92.68 12.53,92.68 12.1,92.24 6.22,92.24 USB1.B10 ; 18.31,93.92 19.56,95.17 20.62,95.17 R3835.2
TYPEC_CON_RXN2: length 13.1
  TOP w0.102: 16.7,98.1 16.23,97.64 15.28,97.64 15.15,97.52 ED3802.1 ED3802.10 13.55,97.52 13.41,97.65 12.19,97.65 12.01,97.48 10.03,97.48 9.75,97.2 v1(9.75,97.07) ; 16.7,98.1 16.88,98.29 19.12,98.29 R3837.2 ; 16.7,98.1 v2(16.79,98.01)
  BOTTOM w0.102: v1(9.75,97.07) 8.79,96.1 8.46,96.1 8.31,95.96 USB1.A10
TYPEC_CON_RXP1: length 16.7
  TOP w0.102: USB1.B11 6.26,92.02 12.19,92.02 12.62,92.45 13.33,92.45 13.44,92.34 ED3806.7 ED3806.4 15.23,92.34 15.37,92.47 16.13,92.47 ; 16.13,92.47 17.19,92.47 19.66,94.94 20.7,94.94 R3834.2 ; 16.13,92.47 v2(16.13,92.32)
TYPEC_CON_RXP2: length 13.2
  TOP w0.102: R3836.2 19.4,98.52 18.59,98.52 ; 18.59,98.52 v2(18.59,98.67) ; 18.59,98.52 16.79,98.52 16.14,97.87 15.35,97.87 15.2,98.02 ED3802.2 ED3802.9 13.49,98.02 13.36,97.88 12.1,97.88 11.92,97.71 v1(9.65,97.71)
  BOTTOM w0.102: v1(9.65,97.71) 9.32,97.37 9.32,96.96 8.69,96.33 8.4,96.33 8.28,96.46 USB1.A11
TYPEC_CON_TXN1: length 14.3
  TOP w0.102: v2(17.19,91.69) 17.3,91.58 ; 17.3,91.58 18.88,93.17 20.15,93.17 R3833.2 ; 17.3,91.58 16.94,91.23 15.36,91.23 15.25,91.34 ED3806.2 ED3806.9 13.44,91.34 13.31,91.2 12.35,91.2 12.2,91.05 11.48,91.05 v1(11.3,91.23)
  BOTTOM w0.102: USB1.A3 8.38,92.46 8.52,92.32 9.29,92.32 10.39,91.23 v1(11.3,91.23)
TYPEC_CON_TXN2: length 13.1
  TOP w0.102: USB1.B3 6.1,96.05 8.42,96.05 9.04,96.67 9.04,97.72 10.47,99.15 13.36,99.15 13.49,99.02 ED3802.7 ED3802.4 15.26,99.02 15.64,99.41 16.48,99.41 R3839.2
TYPEC_CON_TXP1: length 14.5
  TOP w0.102: R3832.2 20.15,92.94 18.98,92.94 18.54,92.5 ; 18.54,92.5 17.03,91 15.51,91 15.35,90.84 ED3806.1 ED3806.10 13.49,90.84 13.36,90.97 12.44,90.97 12.29,90.82 11.53,90.82 v1(11.3,90.59) ; 18.54,92.5 v2(18.64,92.4)
  BOTTOM w0.102: v1(11.3,90.59) 10.89,91 10.29,91 9.2,92.1 8.52,92.1 8.38,91.96 USB1.A2
TYPEC_CON_TXP2: length 13.2
  TOP w0.102: R3838.2 16.46,99.64 15.55,99.64 15.32,99.41 14.96,99.41 ED3802.5 ED3802.6 13.55,99.52 13.41,99.38 10.38,99.38 8.81,97.81 8.81,96.77 8.33,96.28 6.38,96.28 USB1.B2
TYPEC_SMBCLK: length 225.7
  TOP w0.089: v1(177.21,30.73) 176.99,30.73 176.53,30.27 RN2604.4 ; v1(187.15,34.89) 186.37,34.89 184.9,33.42 184.9,32.59 184.55,32.24 KBC24.91 ; R3854.1 41.07,32.02 40.26,32.02 39.59,32.69 39.59,34.02 38.61,35 36.32,35 35.83,34.51 v2(35.61,34.51) v1(35,34.51)
  L3 w0.127: v1(35,34.51) 35.23,34.51 35.61,34.13 35.61,32.48 34.66,31.52 34.66,30.46 39.58,25.53 39.58,15 40.62,13.97 42.89,13.97 43.74,14.82 45.64,14.82 47.67,12.79 47.67,10.89 48.73,9.83 52.14,9.83 54.82,7.15 69.22,7.15 69.5,6.87 95.66,6.87 99.53,10.75 118.38,10.75 123.83,5.3 123.83,5.19 124.13,4.88 129.65,4.88 130.56,5.8 130.56,6.59 133.37,9.4 141.15,9.4 141.99,8.56 147.47,8.56 149.04,10.13 162.22,10.13 164.38,12.3 164.38,13.58 167.27,16.46 169.92,16.46 173.74,20.29 174.27,20.29 175.17,21.18 175.17,23.47 176.08,24.39 176.08,29.6 v1(177.21,30.73)
  L4 w0.127: v1(180.21,32.83) 180.19,32.81 179.83,32.81 179.7,32.68 179.17,32.68 v1(177.21,30.73)
  L6 w0.102: v1(180.21,32.83) 180.31,32.94 180.92,32.94 181.43,32.43 181.43,32.12 181.68,31.87 182.55,31.87 183.16,32.48 184.61,32.48 184.87,32.73 184.87,33.4 185.98,34.51 186.76,34.51 v1(187.15,34.89) 188.19,34.89 188.69,34.38 190.04,34.38 190.73,35.07 192.12,35.07 193.65,36.59 v1(195.3,36.59)
  BOTTOM w0.089: v1(195.3,36.59) 195.32,36.59 195.39,36.66 Q2605.1
TYPEC_SMBDA: length 227.7
  TOP w0.089: RN2604.3 176.37,29.6 177.05,30.28 177.38,30.28 177.82,30.73 v1(177.95,30.73) ; v1(180.69,32.4) 181.33,33.04 KBC24.89 ; R3853.1 43.98,32.14 41.88,32.14 41.43,31.69 40.08,31.69 v2(39.71,32.06) 39.32,32.45 39.32,33.91 38.5,34.73 36.47,34.73 35.58,33.85 v1(35.05,33.85)
  L3 w0.127: v1(177.95,30.73) 176.46,29.24 176.46,24.23 175.55,23.32 175.55,21.03 174.43,19.9 173.9,19.9 170.08,16.08 167.43,16.08 164.76,13.42 164.76,12.14 162.37,9.74 149.19,9.74 147.8,8.36 147.8,7.97 147.32,7.5 143.58,7.5 142.9,8.18 141.83,8.18 141,9.01 133.53,9.01 130.95,6.43 130.95,5.64 129.8,4.5 123.28,4.5 122.54,5.24 122.54,6.04 118.22,10.37 99.69,10.37 95.82,6.49 69.35,6.49 69.07,6.77 54.67,6.77 51.99,9.45 48.57,9.45 47.29,10.73 47.29,12.63 45.48,14.44 43.9,14.44 43.04,13.59 40.46,13.59 39.2,14.85 39.2,25.37 34.07,30.5 34.07,31.58 35.05,32.55 v1(35.05,33.85)
  L4 w0.127: v1(177.95,30.73) 178.12,30.73 178.76,31.37 179.67,31.37 v1(180.69,32.4)
  L6 w0.102: v1(180.69,32.4) 180.72,32.4 181.13,32 181.13,31.99 181.56,31.56 182.67,31.56 183.28,32.17 184.74,32.17 185.17,32.6 185.17,33.12 185.7,33.65 190.17,33.65 190.32,33.49 195.14,33.49 v1(196.21,34.56)
  BOTTOM w0.089: Q2605.4 196.69,35.24 196.21,34.76 v1(196.21,34.56)
U22_POWER_K52: length 1.4
  TOP w0.508: R712.1 121.28,65.93 v1(120.6,65.93)
  BOTTOM w0.305: CPU1.K52 120.95,65.57 v1(120.6,65.93)
UART0_CTS#: length 1.7
  TOP w0.089: v1(116.31,38.65) 116.77,39.11 TP2014.1
  BOTTOM w0.089: v1(116.31,38.65) 116.62,38.35 CPU1.U4
UART0_RTS#: length 4.7
  TOP w0.089: v1(116.97,34.22) TP2013.1
  BOTTOM w0.089: CPU1.U3 117.1,37.52 117.49,37.13 117.49,36.69 117.54,36.5 117.54,35.79 117.45,35.7 117.45,34.7 v1(116.97,34.22)
UART1_CTS#: length 5.8
  TOP w0.089: TP2017.1 114.81,33.42 v1(114.7,33.52)
  BOTTOM w0.089: CPU1.AB4 114.19,38.09 114.19,37.6 114.22,37.51 114.22,37.23 114.19,37.15 114.19,36.95 114.22,36.86 114.22,36.58 114.15,36.41 114.15,34.64 114.47,34.32 114.47,33.99 114.7,33.76 v1(114.7,33.52)
UART1_RTS#: length 5
  TOP w0.089: TP2016.1 113.06,34.24 v1(114,34.24)
  BOTTOM w0.089: v1(114,34.24) 114,34.27 113.97,34.31 113.97,36.45 114.04,36.62 114.04,36.82 114.01,36.9 114.01,37.19 114.04,37.27 114.04,37.47 114,37.57 114,37.74 113.83,37.97 CPU1.AC3
UART_2_CRXD_DTXD: length 80.6
  TOP w0.089: R6810.2 155.12,14.2 155.8,14.88 155.8,19.09 153.65,21.24 153.65,23.43 152.62,24.46 v2(152.62,28.74) 152.62,28.95 v1(152.2,29.38)
  L4 w0.127: v1(111.22,32.45) 111.68,32 111.68,31.04 110.44,29.79 110.44,27.32 109.84,26.73 109.84,26.02 110.13,25.73 111.13,25.73 111.38,25.99 112.83,25.99 114.71,24.11 115.29,24.11 115.78,23.63 116.76,23.63 116.93,23.8 121.53,23.8 121.86,23.47 124.52,23.47 124.76,23.24 125.49,22.51 127.01,22.51 127.32,22.81 128.27,22.81 128.61,23.15 128.61,23.19 131.79,26.37 138.92,26.37 139.27,26.02 141.32,26.02 142.3,27 146.11,27 148.12,29.01 148.68,29.01 149.86,30.19 151.08,30.19 151.89,29.38 v1(152.2,29.38)
  BOTTOM w0.089: R2049.2 110.86,31.38 110.86,32.09 v1(111.22,32.45) 111.3,32.53 111.3,32.96 112.59,34.25 112.59,34.45 113.2,35.06 113.2,35.56 113.16,35.6 113.16,36.15 113.12,36.19 CPU1.AD1
UART_2_CRXD_DTXD_CON: length 6.9
  TOP w0.089: v2(154.23,12.39) 154.51,12.11 R6810.1 155.62,11.61 155.62,11.07 156.08,10.6 159.63,10.6 DB1.14
UART_2_CTXD_DRXD: length 80.5
  TOP w0.089: R6809.2 155.88,14.44 156.16,14.73 156.16,19.28 154.02,21.42 v2(154.02,23) 154.02,23.28 154.02,23.59 153.34,24.27 153.34,24.27 152.99,24.62 152.99,29.25 v1(152.83,29.4)
  L4 w0.127: v1(111.28,31.72) 111.28,31.21 110.03,29.96 110.03,27.49 109.43,26.9 109.43,25.85 109.96,25.33 111.39,25.33 111.64,25.58 112.66,25.58 114.54,23.7 115.13,23.7 115.61,23.22 116.92,23.22 117.1,23.4 121.36,23.4 121.69,23.07 124.36,23.07 125.32,22.1 127.18,22.1 127.48,22.41 129.12,22.41 132.15,25.43 142.53,25.43 143.7,26.59 146.28,26.59 148.29,28.6 148.85,28.6 149.15,28.91 152.35,28.91 152.64,29.2 152.64,29.21 v1(152.83,29.4)
  BOTTOM w0.089: CPU1.AD2 113.33,36.84 113.33,36.63 113.38,36.5 113.38,36.3 113.38,36.28 113.38,35.63 113.38,35.63 113.38,34.94 112.77,34.33 112.77,34 111.73,32.95 111.73,32.01 111.43,31.72 v1(111.28,31.72) 111.28,31.24 110.92,30.89 R2048.2
UART_2_CTXD_DRXD_CON: length 7.6
  TOP w0.089: DB1.13 160.92,10.67 160.33,11.26 159.48,11.26 159.19,10.97 156.24,10.97 155.99,11.22 155.99,12 R6809.1 v2(156.77,12.11)
USB2_ID: length 19.9
  TOP w0.102: RN1602.1 116.69,21.36 116.81,21.48 116.81,22.26 115.41,23.66 v2(115.41,24.09) 115.41,24.99 115.21,25.19 114.94,25.19 v1(114.93,25.19)
  L4 w0.102: v1(112.27,37.86) 113.02,37.11 113.02,34.68 112.55,34.21 112.55,32.12 114.35,30.32 114.35,27.87 114.3,27.82 114.3,25.83 v1(114.93,25.19)
  BOTTOM w0.102: v1(112.27,37.86) 112.1,37.7 CPU1.AG3
USB2_VBUSSENSE: length 19
  TOP w0.102: RN1602.2 116.33,22.37 115.75,22.95 v2(114.98,22.95) 114.93,23 v1(114.93,24.56)
  L4 w0.102: v1(112.21,35.8) 112.23,35.78 112.23,32.15 114.15,30.23 114.15,27.96 114.1,27.91 114.1,25.4 v1(114.93,24.56)
  BOTTOM w0.102: v1(112.21,35.8) 112.11,35.9 112.11,37.16 111.91,37.36 111.71,37.36 111.53,37.54 111.53,38.08 CPU1.AG4
USB20_DN0_C: length 11.7
  BOTTOM w0.102: USB2.2 15.4,54.03 15.21,53.84 15.21,53.43 15.44,53.21 16.45,53.21 17.62,52.04 18.73,52.04 ED3602.1 19.21,52.04 19.94,52.04 20.66,52.75 22.52,52.75 22.81,52.46 22.81,51.74 22.5,51.43 22.5,51.22 22.74,50.98 EL3605.2
USB20_DN1_C: length 34.6
  L6 w0.127: v1(17.37,54.58) 17.13,54.33 16.8,54.33 16.5,54.03 16.5,52.81 16.83,52.48 16.83,32.87 16.52,32.56 15.36,32.56 15.06,32.86 15.06,33.24 15.25,33.43 USB3.2
  BOTTOM w0.102: EL3606.2 24.44,53.04 24.2,53.28 24.2,53.86 24.11,53.95 ; v1(17.37,54.58) 17.58,54.37 17.91,54.37 18.34,53.94 18.73,53.94 ED3602.3 19.21,53.94 19.89,53.94 20.6,54.65 23.41,54.65 24.11,53.95 ; 24.11,53.95 v2(24.2,54.04)
USB20_DP0_C: length 10.5
  BOTTOM w0.102: USB2.3 15.7,52.78 15.9,52.98 16.35,52.98 17.53,51.81 20.04,51.81 20.75,52.52 21.42,52.52 ED3602.6 21.91,52.52 22.43,52.52 22.58,52.37 22.58,51.83 22.27,51.52 22.27,51.17 22.06,50.96 EL3605.3
USB20_DP1_C: length 33.1
  L6 w0.127: USB3.3 15.7,32.17 15.83,32.3 16.63,32.3 17.09,32.76 17.09,52.59 16.76,52.93 16.76,53.92 16.91,54.07 17.24,54.07 v1(17.37,53.94)
  BOTTOM w0.102: v2(22.93,54.3) 22.93,54.42 ; 22.93,54.42 21.91,54.42 ED3602.4 21.42,54.42 20.7,54.42 19.99,53.71 18.24,53.71 17.81,54.14 17.58,54.14 v1(17.37,53.94) ; 22.93,54.42 23.32,54.42 23.98,53.76 23.98,53.28 23.76,53.07 EL3606.3
USB30_RX_CPU_N1: length 156.2
  TOP w0.102: v2(25.86,50.05) 26.04,50.24 v1(26.04,50.62) 25.88,50.46 25.58,50.46 25.32,50.72 25.32,51.02 24.78,51.57 24.19,51.57 R3609.1
  L6 w0.127: v1(26.04,50.62) 26.03,50.62 25.66,50.98 24.65,50.98 20.99,47.32 20.99,46.08 21.36,45.71 21.36,36.69 22.75,35.3 27.59,35.3 30.19,32.7 30.19,28.27 32.08,26.38 36.56,26.38 41.17,21.77 44.01,21.77 45.19,21.77 54.07,12.89 62.41,12.89 63.91,11.4 70.41,11.4 71.36,12.35 79.14,12.35 83.05,16.26 96.64,16.26 97.17,16.79 102.25,16.79 102.97,17.52 107.36,17.52 107.47,17.4 112.94,17.4 114.92,19.38 114.92,21.72 116.69,23.48 116.69,28.31 117.57,29.2 117.57,31.31 119.01,32.74 119.01,37.27 119.89,38.14 119.89,40.39 120.6,41.1 120.75,41.1 v1(120.95,41.3)
  BOTTOM w0.102: CPU1.H8 121.24,41.11 121.05,41.3 v1(120.95,41.3)
USB30_RX_CPU_N2: length 131.7
  TOP w0.102: 27.26,31.3 27.63,31.67 28.27,31.67 v1(28.55,31.38) ; 27.26,31.3 v2(27.35,31.21) ; 27.26,31.3 25.78,29.82 24.39,29.82 R3612.1
  L6 w0.127: v1(28.55,31.38) 28.19,31.38 28.1,31.3 28.1,30.48 29.39,29.2 29.39,27.15 30.93,25.61 35.01,25.61 40.29,20.32 45.53,20.32 54.25,11.6 62.61,11.6 63.59,10.62 70.73,10.62 71.68,11.57 81.54,11.57 84.72,14.76 86.04,14.76 86.76,15.49 96.96,15.49 97.49,16.02 102.57,16.02 102.77,16.22 106.73,16.22 106.92,16.03 108.9,16.03 109.5,16.63 113.28,16.63 115.71,19.05 115.71,21.41 117.46,23.16 117.46,27.39 118.38,28.31 118.38,30.97 119.77,32.36 119.77,36.88 120.47,37.58 120.47,40.02 v1(120.88,40.43)
  BOTTOM w0.102: CPU1.J6 120.59,40.14 v1(120.88,40.43)
USB30_RX_CPU_N4: length 170.6
  TOP w0.102: 29.89,52.59 29.89,52.2 30.07,52.02 30.07,51.73 29.84,51.5 29.64,51.5 v1(29.41,51.73) ; 29.89,52.59 29.89,53.12 30.64,53.86 31.14,53.86 C3806.1 ; 29.89,52.59 v2(29.74,52.59)
  L6 w0.127: v1(122.87,41.34) 123.95,41.34 124.41,40.88 124.41,40.1 121.36,37.05 121.36,29.51 118.5,26.65 118.5,22.73 116.77,21 116.77,18.58 113.77,15.57 109.94,15.57 109.1,14.74 97.68,14.74 97.39,14.44 87.24,14.44 83.33,10.53 72.11,10.53 71.15,9.57 63.17,9.57 62.17,10.56 53.82,10.56 45.1,19.28 39.86,19.28 35.05,24.1 30.59,24.1 28.34,26.34 28.34,28.75 26.99,30.11 26.99,33.35 26.08,34.26 22.15,34.26 20.28,36.12 20.28,41.33 19.72,41.89 19.72,48.34 23.43,52.05 27.21,52.05 27.53,51.73 v1(29.41,51.73)
  BOTTOM w0.102: CPU1.E10 123.19,41.67 v1(122.87,41.34)
USB30_RX_CPU_N4_C: length 2.9
  TOP w0.102: v2(33.08,54.92) 33.18,54.82 ; 33.18,54.82 33.59,55.24 33.59,55.39 33.5,55.48 U3801.4 ; 33.18,54.82 32.94,54.59 32.94,54.3 32.7,54.06 32.52,54.06 C3806.2
USB30_RX_CPU_P1: length 157.1
  TOP w0.102: v2(26.52,51.58) 26.19,51.25 v1(26.04,51.25) 25.41,51.25 24.87,51.79 24.19,51.79 R3610.1
  L6 w0.127: v1(121.51,40.45) 121.13,40.83 120.71,40.83 120.15,40.28 120.15,38.03 119.28,37.16 119.28,32.63 117.84,31.2 117.84,29.09 116.95,28.2 116.95,23.37 115.19,21.61 115.19,19.27 113.05,17.14 107.36,17.14 107.25,17.25 103.08,17.25 102.36,16.53 97.28,16.53 96.75,15.99 83.16,15.99 79.25,12.08 71.47,12.08 70.52,11.13 63.8,11.13 62.3,12.62 53.96,12.62 45.08,21.5 41.06,21.5 36.45,26.12 31.97,26.12 29.92,28.16 29.92,32.59 27.48,35.03 22.64,35.03 21.09,36.58 21.09,45.6 20.72,45.97 20.72,47.43 24.54,51.25 v1(26.04,51.25)
  BOTTOM w0.102: CPU1.G8 121.89,40.83 v1(121.51,40.45)
USB30_RX_CPU_P2: length 132.3
  TOP w0.102: v1(28.55,32.17) 28.27,31.9 27.53,31.9 25.68,30.04 25.45,30.04 ; R3613.1 24.35,30.04 25.45,30.04 ; v2(25.45,30.19) 25.45,30.04
  L6 w0.127: v1(28.55,32.17) 27.84,31.46 27.84,30.37 29.12,29.09 29.12,27.04 30.82,25.34 34.9,25.34 40.18,20.06 45.42,20.06 54.14,11.34 62.5,11.34 63.48,10.35 70.84,10.35 71.79,11.31 81.65,11.31 84.83,14.49 86.15,14.49 86.88,15.22 97.07,15.22 97.6,15.75 102.68,15.75 102.88,15.96 106.62,15.96 106.81,15.76 109.01,15.76 109.61,16.36 113.39,16.36 115.97,18.94 115.97,21.3 117.73,23.05 117.73,27.28 118.65,28.2 118.65,30.86 120.04,32.25 120.04,36.77 120.74,37.47 120.74,39.32 v1(120.93,39.51)
  BOTTOM w0.102: v1(120.93,39.51) 120.93,39.52 121.24,39.83 CPU1.H6
USB30_RX_CPU_P4: length 169.9
  TOP w0.102: v2(30.2,51.35) 30.11,51.44 ; 30.11,51.44 30.3,51.64 30.3,52.11 30.12,52.29 30.12,53.03 30.73,53.64 31.14,53.64 C3805.1 ; 30.11,51.44 29.94,51.27 29.59,51.27 v1(29.41,51.1)
  L6 w0.127: v1(29.41,51.1) 29.04,51.46 27.42,51.46 27.1,51.78 23.54,51.78 19.99,48.23 19.99,42 20.55,41.44 20.55,36.23 22.26,34.52 26.19,34.52 27.25,33.46 27.25,30.22 28.61,28.86 28.61,26.45 30.7,24.36 35.16,24.36 39.97,19.55 45.21,19.55 53.93,10.83 62.28,10.83 63.28,9.83 71,9.83 71.02,9.85 71.05,9.85 72,10.8 83.22,10.8 87.13,14.71 97.28,14.71 97.57,15 108.99,15 109.83,15.84 113.66,15.84 116.51,18.69 116.51,21.11 118.24,22.84 118.24,26.76 121.09,29.62 121.09,37.16 124.14,40.21 124.14,40.77 123.84,41.08 123.3,41.08 123.11,40.89 122.67,40.89 v1(122.22,41.34)
  BOTTOM w0.102: v1(122.22,41.34) 122.54,41.67 CPU1.F10
USB30_RX_CPU_P4_C: length 3.5
  TOP w0.102: U3801.5 33.9,55.48 33.82,55.39 33.82,55.14 33.17,54.49 33.17,54.2 32.82,53.85 32.82,53.56 32.56,53.31 C3805.2
USB30_RXDN1_C: length 12.4
  TOP w0.102: 21.88,51.75 22.03,51.6 22.71,51.6 R3609.2 ; 21.88,51.75 21.24,52.39 20.64,52.39 20.56,52.31 ED3601.1 ED3601.10 18.6,52.31 18.46,52.44 17.8,52.44 16.02,50.66 15.64,50.66 14.89,49.92 13.8,49.92 13.61,49.72 13.61,49.24 13.82,49.03 USB2.5 ; 21.88,51.75 v2(21.79,51.65)
USB30_RXDN2_C: length 11.3
  TOP w0.102: 22.12,29.94 21.87,30.19 20.34,30.19 20.23,30.08 ED3603.1 ED3603.10 18.3,30.08 18.17,30.2 15.62,30.2 14.74,29.32 14.06,29.32 13.79,29.05 13.79,28.62 13.98,28.43 USB3.5 ; 22.12,29.94 22.25,29.81 22.91,29.81 R3612.2 ; 22.12,29.94 v2(22.02,29.84)
USB30_RXDP1_C: length 11.4
  TOP w0.102: 21.23,52.62 21.34,52.62 22.12,51.83 22.78,51.83 R3610.2 ; 21.23,52.62 v2(21.23,52.75) ; 21.23,52.62 20.68,52.62 20.49,52.81 ED3601.2 ED3601.9 18.57,52.81 18.44,52.67 17.7,52.67 15.92,50.89 15.54,50.89 14.79,50.14 14.3,50.14 14.29,50.15 14.2,50.25 USB2.6
USB30_RXDP2_C: length 10.7
  TOP w0.102: 21.03,30.42 20.34,30.42 20.18,30.58 ED3603.2 ED3603.9 18.27,30.58 18.12,30.43 15.53,30.43 14.64,29.54 14.3,29.54 14.2,29.65 USB3.6 ; 21.03,30.42 v2(21.03,30.55) ; 21.03,30.42 21.96,30.42 22.34,30.04 22.93,30.04 R3613.2
USB30_TX_CPU_N1: length 185.3
  TOP w0.102: C3601.1 25.14,53.51 25.27,53.63 25.6,53.63 v1(25.88,53.36) v2(26.28,52.96)
  L6 w0.127: v1(128.3,38.68) 128.09,38.68 127.87,38.45 127.87,37.9 128.2,37.56 128.2,34.54 125.06,31.39 125.06,27.39 125.23,27.21 125.23,23.07 126.22,22.08 126.22,14.1 123.87,11.74 119.6,11.74 117.64,9.78 101.51,9.78 98.81,7.08 59.96,7.08 59.26,7.78 52.48,7.78 48.29,11.97 47.71,11.97 45.06,14.62 44.91,14.77 43.85,15.83 34.91,15.83 32.29,18.44 30.64,18.44 27.94,21.15 27.94,23.08 26.29,24.73 26.29,27.78 18.97,35.09 18.97,40.6 18.41,41.16 18.41,49.06 23.11,53.77 25.3,53.77 25.42,53.64 25.42,53.48 25.55,53.36 v1(25.88,53.36)
  BOTTOM w0.089: 127.35,42.5 127.3,42.56 127.3,42.69 126.82,43.17 126.69,43.17 126.46,43.4 126.45,43.4 126.07,43.78 125.81,43.78 125.72,43.75 125.45,43.75 125.36,43.78 125.16,43.78 125.03,43.73 124.82,43.73 CPU1.C13
  BOTTOM w0.102: v1(128.3,38.68) 128.36,38.61 128.58,38.61 128.7,38.73 128.7,40.74 127.95,41.49 127.95,41.9 127.35,42.5
USB30_TX_CPU_N2: length 154.5
  TOP w0.102: C3603.1 25.14,31.72 v1(25.65,31.72) 25.85,31.72 v2(26.13,31.43)
  L6 w0.127: v1(127.48,38.63) 127.31,38.46 127.15,38.46 126.75,38.87 126.19,38.87 125.75,38.42 125.75,37.83 124.28,36.36 124.28,27.04 124.46,26.86 124.46,22.75 125.45,21.76 125.45,14.44 123.53,12.51 119.28,12.51 117.32,10.56 100.31,10.56 97.6,7.85 60.5,7.85 59.81,8.55 52.8,8.55 48.61,12.74 48.06,12.74 46.29,14.51 46.29,14.53 45.42,15.4 45.4,15.4 44.16,16.64 42.55,16.64 41.26,17.94 35.34,17.94 34.06,19.22 30.96,19.22 28.71,21.47 28.71,24.15 27.06,25.8 27.06,28.14 24.39,30.81 24.39,31.88 24.62,32.11 24.84,32.11 24.97,31.98 24.97,31.54 25.09,31.41 25.33,31.41 25.63,31.72 v1(25.65,31.72)
  BOTTOM w0.102: v1(127.48,38.63) 127.64,38.8 127.64,39.65 128.09,40.09 128.09,40.76 127.53,41.32 127.53,41.73 126.88,42.38 126.88,42.52 126.65,42.75 126.25,42.75 125.48,43.52 CPU1.B13
USB30_TX_CPU_N4: length 191.5
  TOP w0.102: v1(127.76,43.22) 128.23,43.22 v2(128.4,43.38) ; v1(31.29,52.29) 31.49,52.09 31.65,52.09 C3804.1
  L6 w0.127: v1(127.76,43.22) 127.45,43.22 127.12,42.89 126.21,42.89 125.63,42.31 125.63,39.26 123.65,37.29 122.83,37.29 121.91,36.37 121.91,32.31 123.77,30.44 123.77,26.82 123.95,26.65 123.95,22.54 124.94,21.55 124.94,14.65 123.32,13.02 117.12,13.02 115.16,11.07 99.79,11.07 97.09,8.36 60.82,8.36 59.43,9.76 53.46,9.76 48.89,14.33 48.01,14.33 45.16,17.18 42.73,17.18 41.47,18.44 35.55,18.44 32.58,21.42 31.18,21.42 29.47,23.12 29.47,24.12 27.57,26.02 27.57,28.4 26.21,29.76 26.21,33.03 25.81,33.43 24.37,33.43 23.67,32.73 22.17,32.73 19.49,35.41 19.49,40.85 18.92,41.42 18.92,48.63 23.11,52.82 27.42,52.82 27.66,53.06 29.18,53.06 30.22,52.02 31.02,52.02 v1(31.29,52.29)
  BOTTOM w0.089: 127.13,44.72 126.17,44.72 126.07,44.61 125.81,44.61 125.72,44.65 125.45,44.65 125.36,44.61 125.16,44.61 125.03,44.67 124.97,44.67 124.65,44.85 CPU1.C15
  BOTTOM w0.102: v1(127.76,43.22) 127.76,43.44 127.91,43.6 127.91,43.93 127.13,44.72
USB30_TX_CPU_N4_C: length 6.6
  TOP w0.102: C3804.2 33.22,52.09 34.55,52.09 35.61,53.15 35.61,54.32 34.79,55.14 34.79,55.39 34.7,55.48 U3801.7
USB30_TX_CPU_P1: length 187.1
  TOP w0.102: v1(25.87,54.03) 25.7,53.86 25.35,53.86 C3602.1 ; v2(129.11,38.75) 129.04,38.75 v1(128.33,38.04)
  L6 w0.127: v1(128.33,38.04) 128.33,37.81 128.47,37.67 128.47,34.43 125.32,31.28 125.32,27.5 125.5,27.32 125.5,23.18 126.49,22.19 126.49,13.99 123.98,11.47 119.71,11.47 117.75,9.52 101.62,9.52 98.92,6.81 59.85,6.81 59.15,7.51 52.37,7.51 48.18,11.7 47.6,11.7 44.87,14.43 44.72,14.58 43.74,15.56 34.8,15.56 32.18,18.18 30.53,18.18 27.67,21.04 27.67,22.97 26.02,24.62 26.02,27.66 18.71,34.98 18.71,40.49 18.15,41.05 18.15,49.17 23,54.03 v1(25.87,54.03)
  BOTTOM w0.089: 127.52,42.66 127.49,42.69 127.49,42.77 126.9,43.36 126.77,43.36 126.53,43.59 126.16,43.96 125.78,43.96 125.69,43.93 125.49,43.93 125.4,43.96 125.13,43.96 124.99,43.91 124.66,43.91 CPU1.D13
  BOTTOM w0.102: 127.52,42.66 128.18,42 128.18,41.59 128.93,40.84 128.93,38.64 v1(128.33,38.04)
USB30_TX_CPU_P2: length 155.3
  TOP w0.102: C3604.1 25.14,32.35 v1(25.65,32.35) 25.75,32.35 v2(26.12,32.71)
  L6 w0.127: v1(25.65,32.35) 25.63,32.38 24.51,32.38 24.13,32 24.13,30.7 26.8,28.03 26.8,25.69 28.45,24.04 28.45,21.36 30.85,18.95 33.95,18.95 35.23,17.67 41.15,17.67 42.44,16.37 44.05,16.37 45.29,15.13 45.31,15.13 46.02,14.42 46.02,14.4 47.94,12.48 48.5,12.48 52.69,8.28 59.69,8.28 60.39,7.59 97.71,7.59 100.42,10.29 117.43,10.29 119.39,12.25 123.64,12.25 125.72,14.33 125.72,21.87 124.72,22.86 124.72,26.98 124.55,27.15 124.55,36.25 126.02,37.72 126.02,38.31 126.3,38.6 126.64,38.6 127.04,38.19 127.23,38.19 v1(127.46,37.96)
  BOTTOM w0.102: CPU1.A13 125.91,43.41 126.34,42.98 126.75,42.98 127.11,42.62 127.11,42.47 127.76,41.82 127.76,41.41 128.32,40.86 128.32,39.99 127.87,39.55 127.87,38.37 v1(127.46,37.96)
USB30_TX_CPU_P4: length 191.2
  TOP w0.102: v1(127.25,43.6) 127.33,43.68 v2(127.33,44.34) ; v1(31.29,51.45) 31.29,51.73 31.42,51.86 31.66,51.86 31.98,51.54 C3803.1
  L6 w0.127: v1(31.29,51.45) 31.29,51.65 31.19,51.76 30.1,51.76 29.07,52.79 27.77,52.79 27.53,52.56 23.22,52.56 19.19,48.52 19.19,41.53 19.76,40.96 19.76,35.52 22.28,33 23.56,33 24.26,33.7 25.92,33.7 26.48,33.14 26.48,29.87 27.84,28.51 27.84,26.13 29.74,24.23 29.74,23.23 31.29,21.68 32.69,21.68 35.66,18.71 41.58,18.71 42.84,17.45 45.27,17.45 45.42,17.29 48.12,14.6 49,14.6 53.57,10.02 59.54,10.02 60.93,8.63 96.98,8.63 99.68,11.33 115.05,11.33 117.01,13.29 123.21,13.29 124.67,14.76 124.67,21.44 123.68,22.43 123.68,26.53 123.51,26.71 123.51,30.33 121.64,32.2 121.64,36.48 122.72,37.56 123.54,37.56 125.36,39.37 125.36,42.42 126.1,43.16 127.01,43.16 127.25,43.4 v1(127.25,43.6)
  BOTTOM w0.089: 127.07,44.46 126.99,44.53 126.25,44.53 126.16,44.44 125.78,44.44 125.69,44.47 125.49,44.47 125.4,44.44 125.13,44.44 124.99,44.49 124.18,44.49 123.96,44.71 CPU1.D15
  BOTTOM w0.102: 127.07,44.46 127.68,43.84 127.68,43.69 127.6,43.6 v1(127.25,43.6)
USB30_TX_CPU_P4_C: length 7.1
  TOP w0.102: 35.59,54.66 35.02,55.24 35.02,55.39 35.1,55.48 U3801.8 ; 35.59,54.66 35.84,54.42 35.84,53.05 34.64,51.86 33.21,51.86 32.89,51.54 C3803.2 ; 35.59,54.66 v2(35.69,54.75)
USB30_TXDN1_C: length 10.5
  TOP w0.102: USB2.8 13.77,55.46 13.77,55.79 13.89,55.92 14.71,55.92 15.26,55.36 17.38,55.36 17.96,54.79 17.96,54.2 18.2,53.95 18.44,53.95 18.59,53.81 ED3601.7 ED3601.4 20.23,53.81 20.39,53.97 20.62,53.97 20.93,54.27 21.44,54.27 R3605.2
USB30_TXDN1_R: length 3.4
  TOP w0.102: R3605.1 22.88,54.25 23.55,54.25 23.8,54 23.8,53.43 23.93,53.31 C3601.2 24.23,53.2 24.03,53 v2(23.44,53)
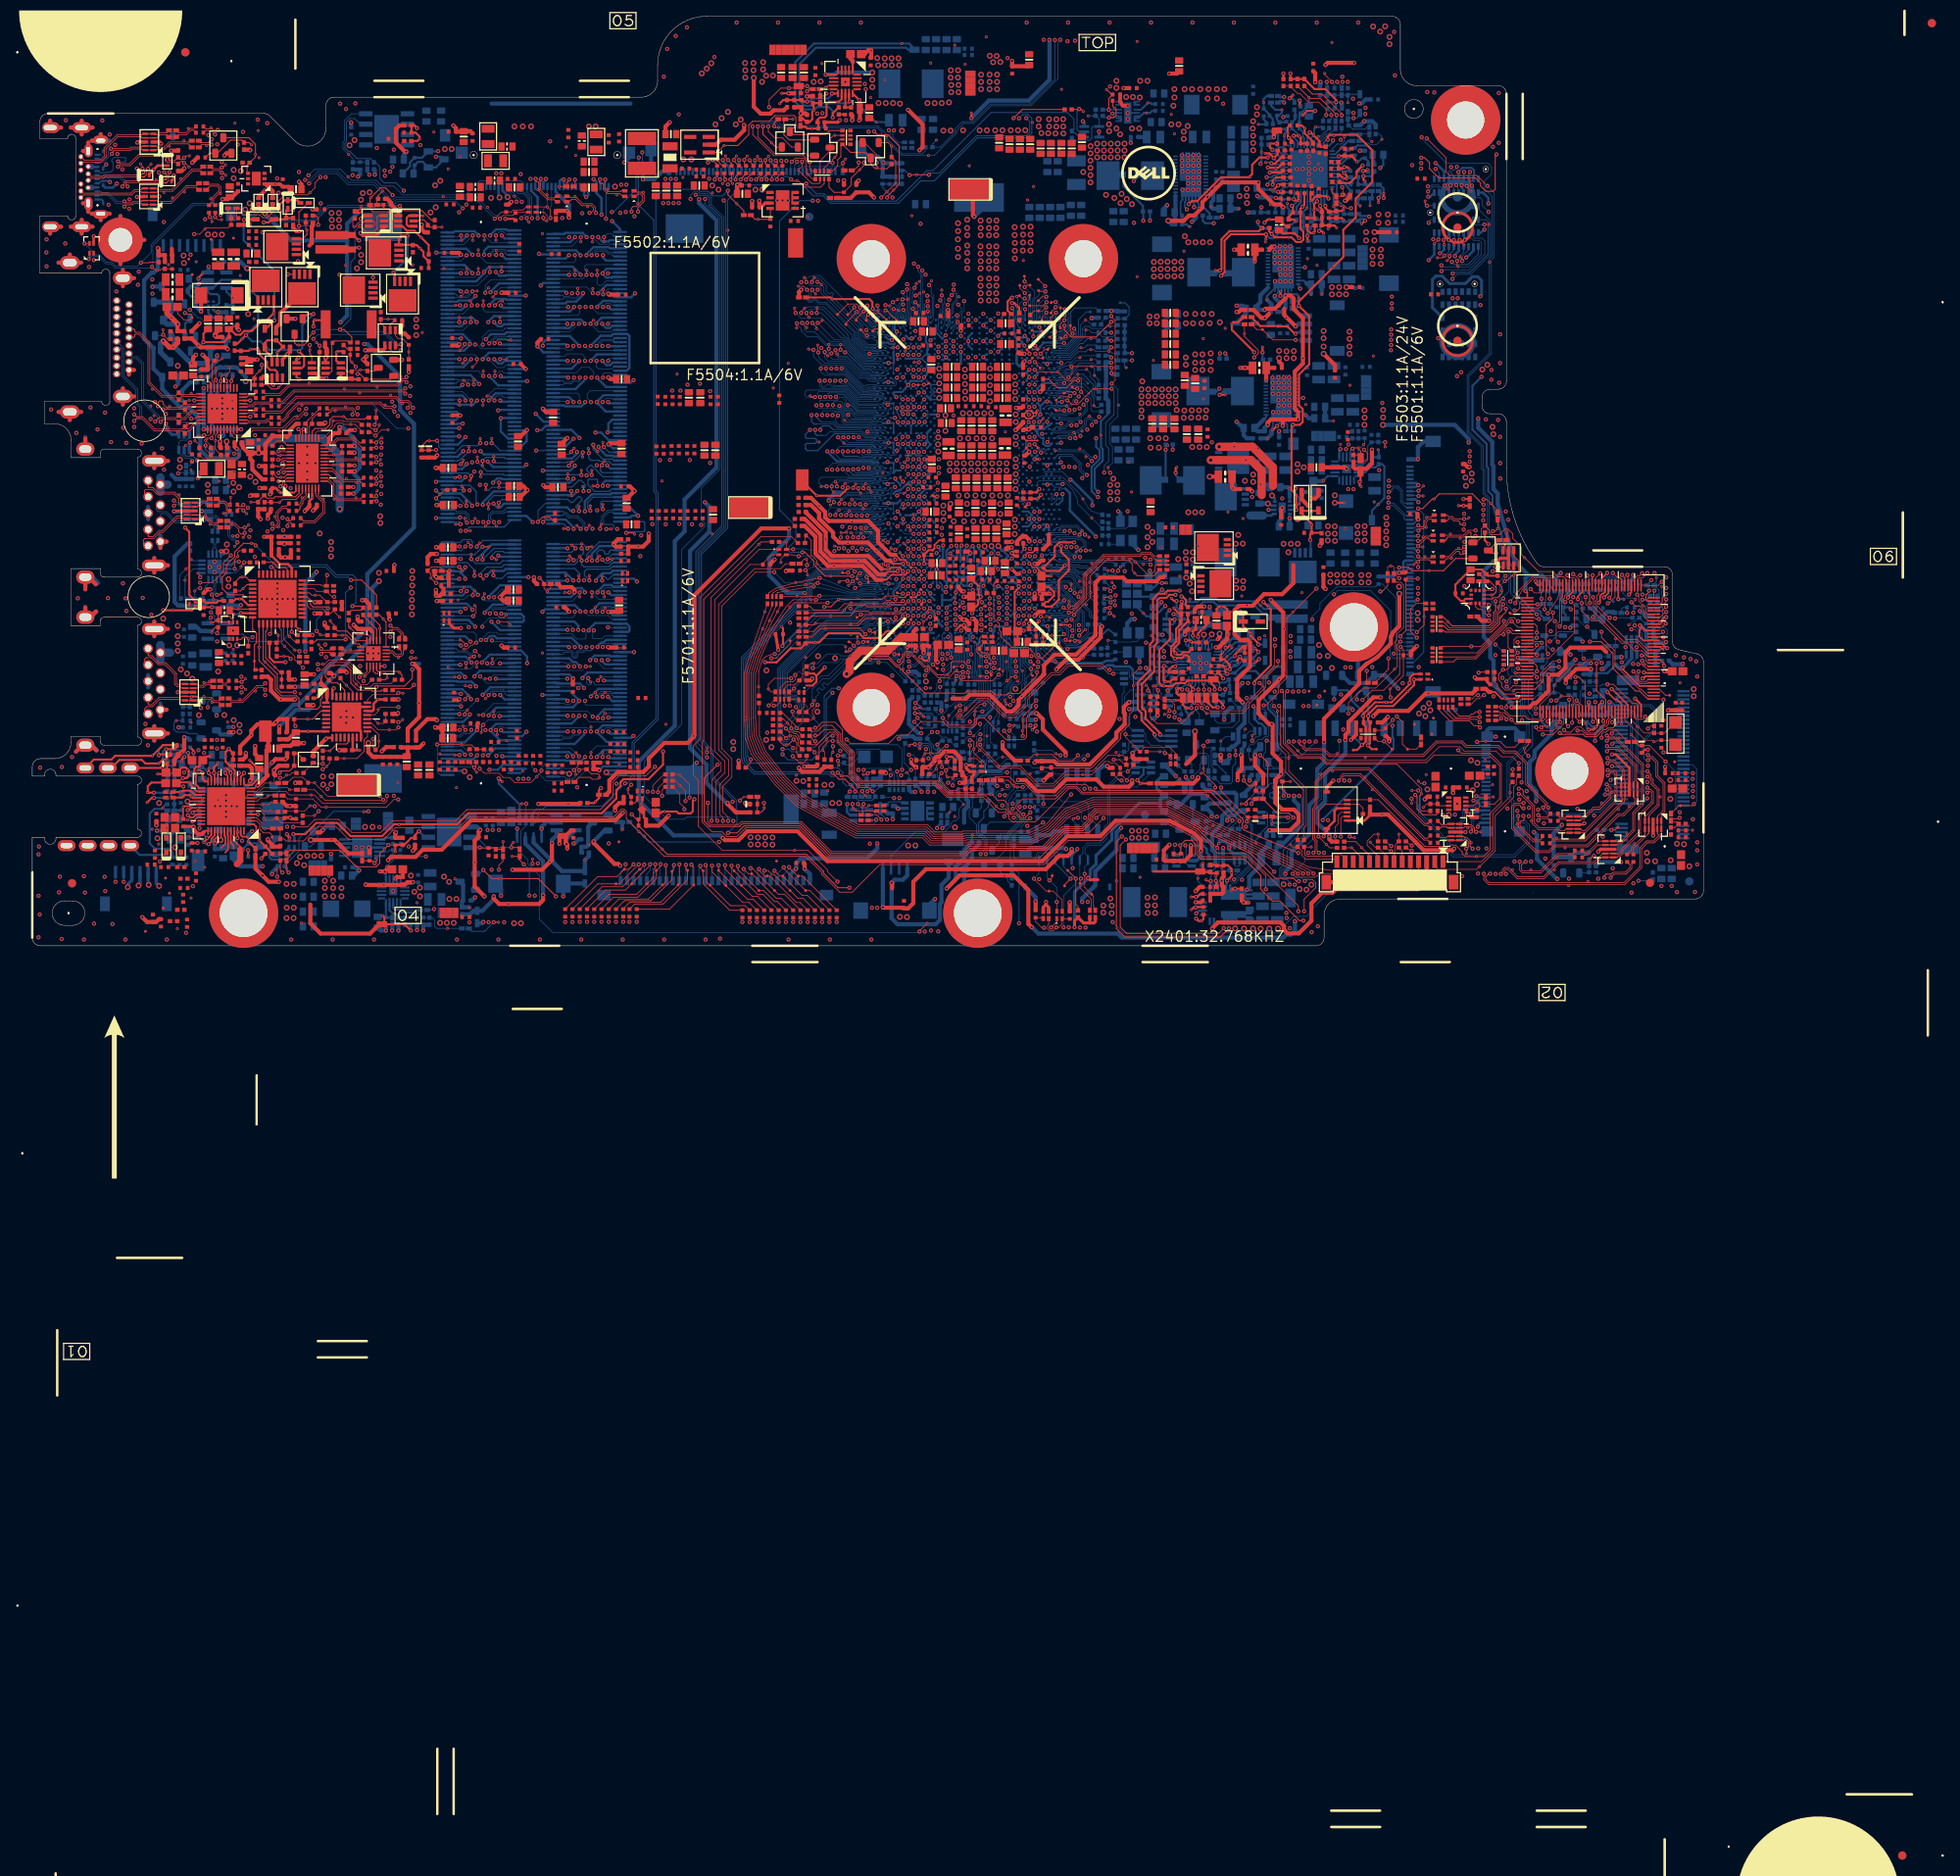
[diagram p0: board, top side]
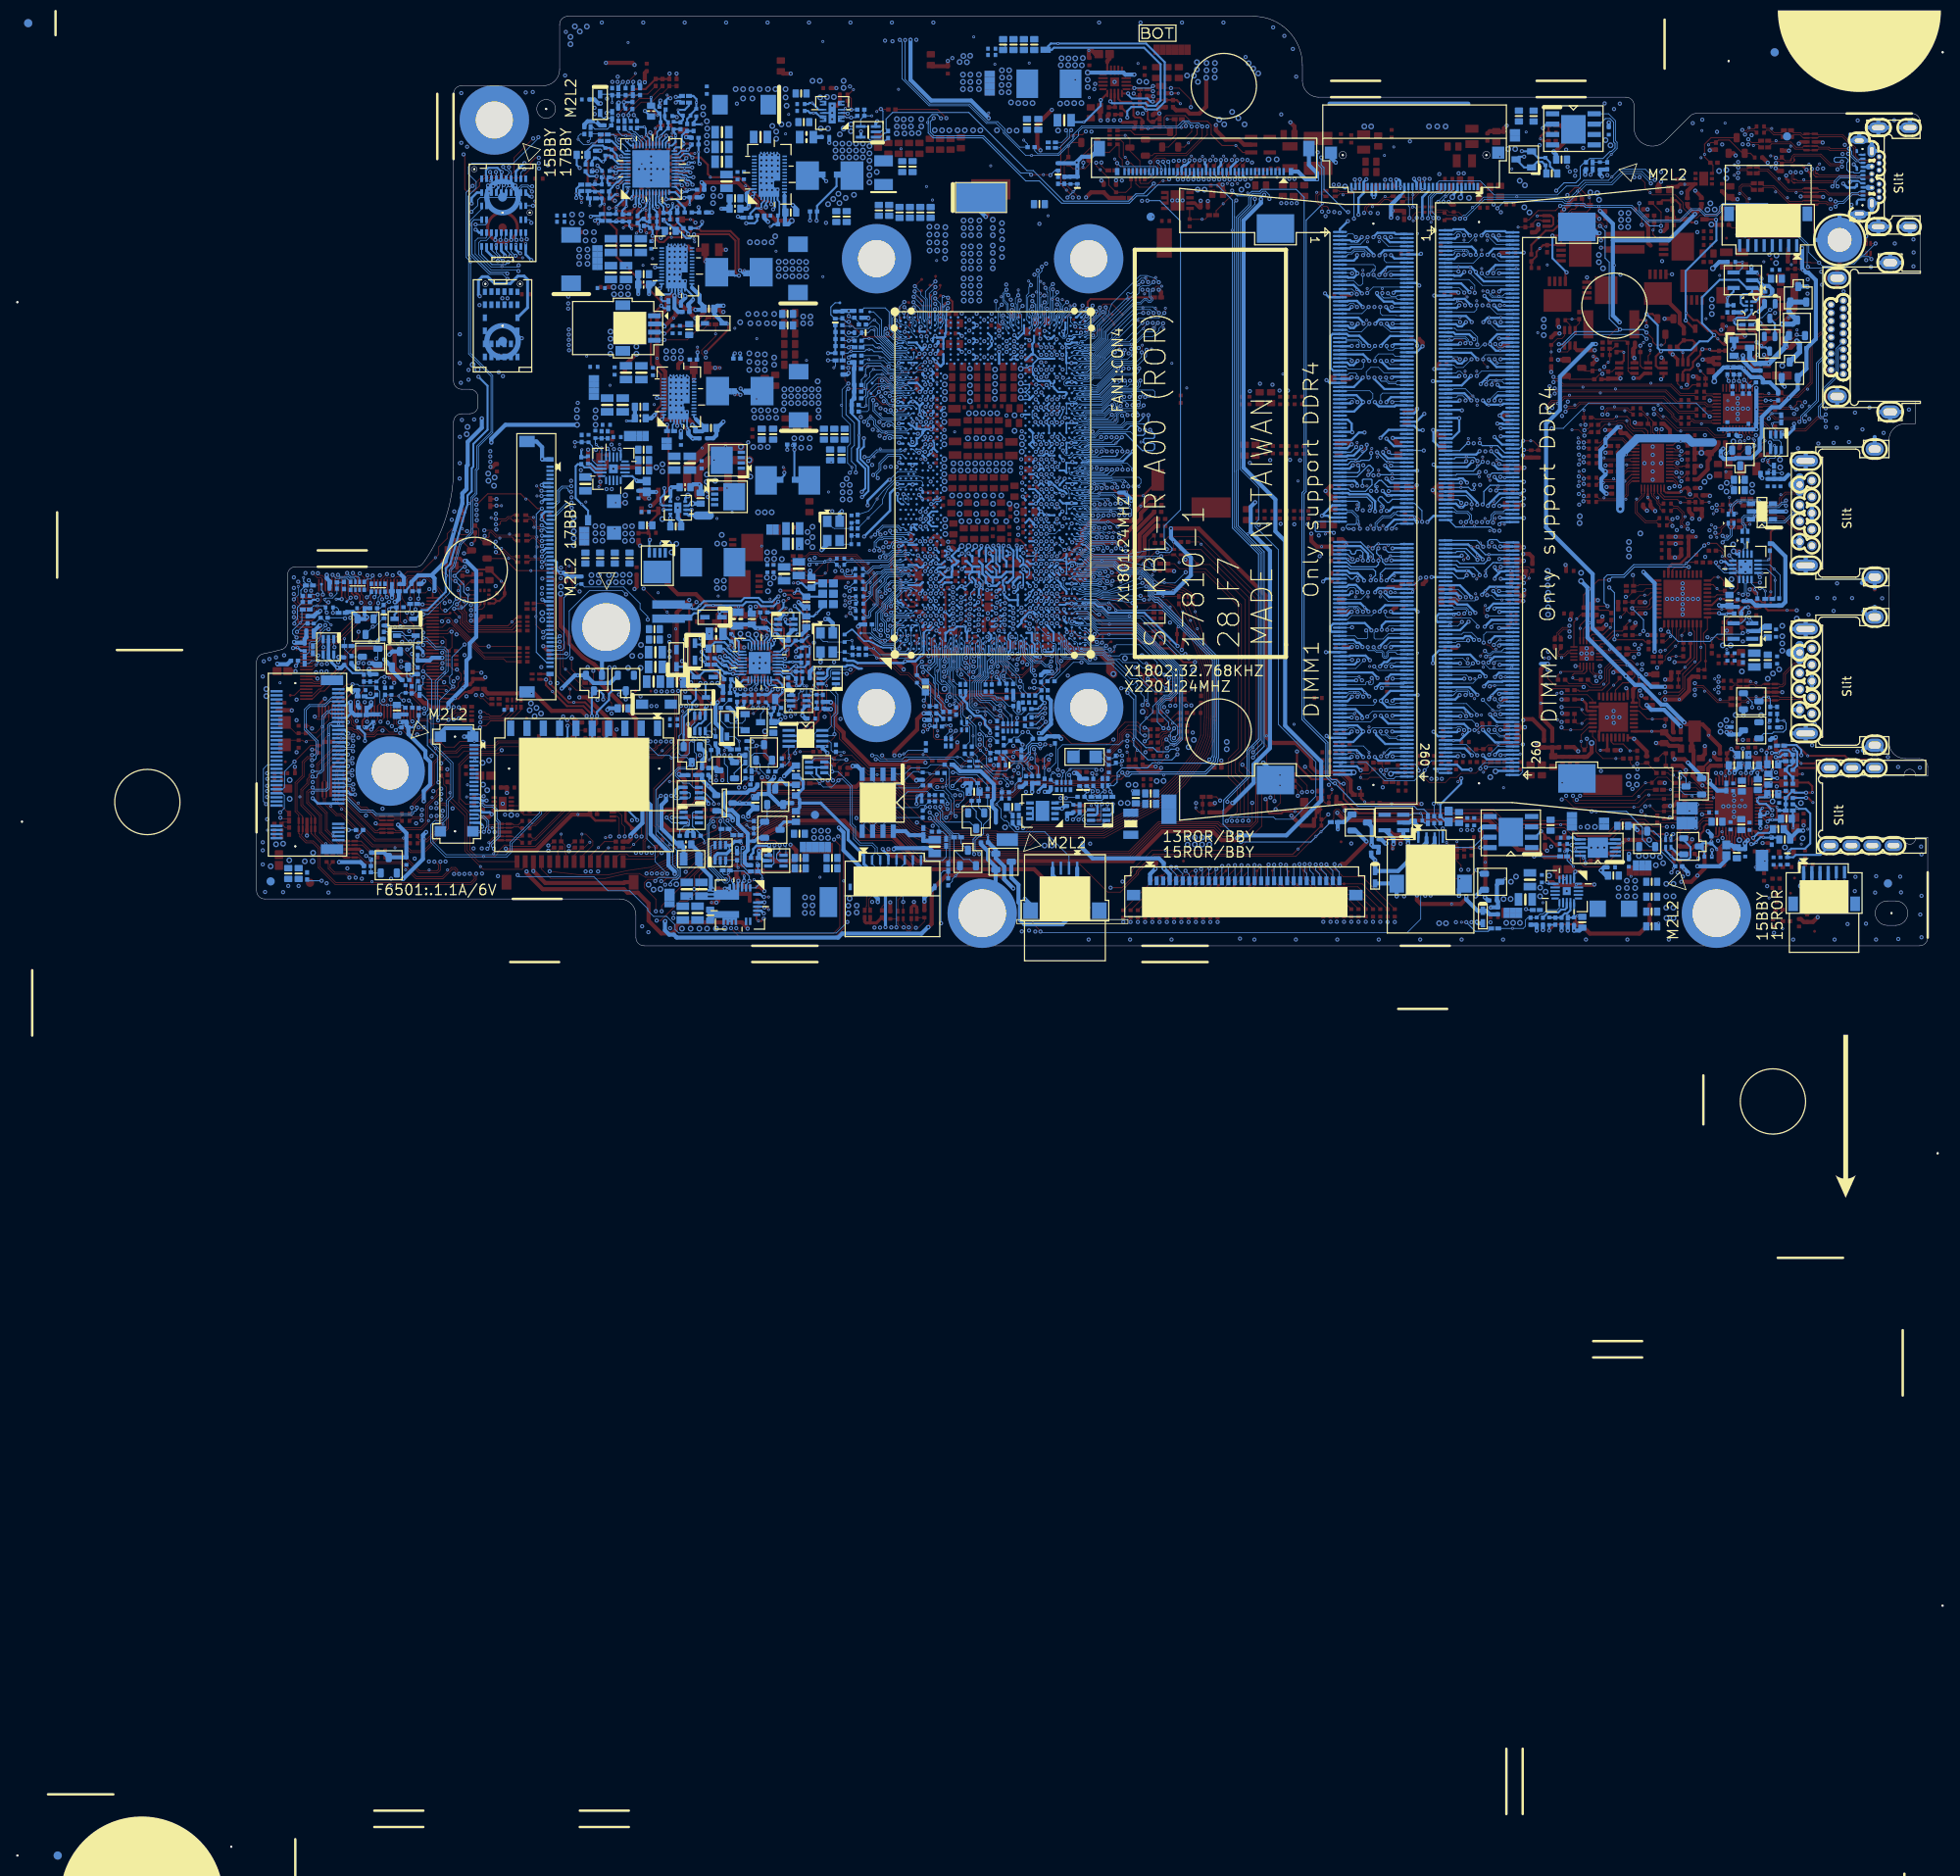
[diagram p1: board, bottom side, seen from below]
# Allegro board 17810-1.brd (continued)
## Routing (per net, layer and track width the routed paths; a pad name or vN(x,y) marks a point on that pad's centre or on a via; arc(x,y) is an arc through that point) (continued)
USB30_TXDN2_C: length 12.1
  TOP w0.102: USB3.8 13.92,34.43 13.74,34.61 13.74,35.09 13.96,35.32 14.59,35.32 15.45,34.46 16.26,34.46 17.45,33.27 17.45,32.07 17.78,31.74 18.21,31.74 18.37,31.58 ED3603.7 ED3603.4 20.21,31.58 20.32,31.69 21,31.69 21.3,32 21.89,32 R3611.2
USB30_TXDN2_R: length 1.3
  TOP w0.102: R3611.1 23.27,31.95 23.74,31.95 C3603.2
USB30_TXDP1_C: length 10
  TOP w0.102: v2(18.01,55.29) 17.89,55.17 ; 17.89,55.17 17.47,55.59 15.36,55.59 14.81,56.14 14.3,56.14 14.3,56.15 14.2,56.25 USB2.9 ; 17.89,55.17 18.18,54.88 18.18,54.3 18.3,54.18 18.5,54.18 18.63,54.31 ED3601.6 ED3601.5 20.24,54.31 20.35,54.19 20.53,54.19 20.83,54.5 21.46,54.5 R3606.2
USB30_TXDP1_R: length 2.8
  TOP w0.102: v2(24.31,54.96) 24.31,54.14 C3602.2 24.05,54.07 23.65,54.47 22.91,54.47 R3606.1
USB30_TXDP2_C: length 11.5
  TOP w0.102: v2(21.04,32.26) 21.14,32.16 ; 21.14,32.16 21.21,32.22 21.92,32.22 R3614.2 ; 21.14,32.16 20.9,31.92 20.34,31.92 20.18,32.08 ED3603.5 ED3603.6 18.23,32.08 18.12,31.97 17.87,31.97 17.68,32.17 17.68,33.37 16.36,34.69 15.54,34.69 14.69,35.54 14.3,35.54 14.3,35.55 14.25,35.6 14.2,35.65 USB3.9
USB30_TXDP2_R: length 1.3
  TOP w0.102: R3614.1 23.34,32.18 23.8,32.18 C3604.2
USB30_VCCA: length 5.1
  TOP w0.508: v3(23.8,48.35) v2(23.11,48.35)
  BOTTOM w0.305: v3(23.8,48.35) 23.44,48 U3401.12
  BOTTOM w0.508: ED3602.5 20.83,53.23 v1(20.78,53.28)
  BOTTOM w1.016: USB2.1 15.7,55.62 ; USB2.1 15.7,57.42 ; USB2.1 16.59,56.53
  vias: v3(21.51,56.51) v3(21.54,55.62) v3(23.85,49.19)
USB30_VCCB: length 3
  BOTTOM w1.016: USB3.1 15.7,36.84 15.7,36.85 ; USB3.1 15.7,35.02 ; USB3.1 16.89,35.93
  vias: v2(47.8,75.15) v3(17.83,37.94) v3(17.83,37.05) v3(17.83,36.16) v3(36.63,49.5) v3(36.63,48.61) v3(36.63,47.72) v3(47.06,76.75) v3(47.06,75.86) v3(47.06,74.85)
USB_ADT: length 237.4
  TOP w0.508: PD4409.A 157.66,55.21 157.28,54.83 v1(156.74,54.83) ; PU4304.5 32.82,79.95 30.41,77.54 30.41,76.32 29.89,75.81 PR4327.2
  L3 w0.508: v1(152.32,37.56) 152.32,38.5 154.1,40.28 154.1,43.85 156.7,46.45 156.7,48.88 157.35,49.53 157.35,54.42 156.94,54.83 v1(156.74,54.83) ; v1(37.67,82.26) 37.67,86.73 38.48,87.55 38.48,90.35 38.63,90.5 38.63,95.26 41.16,97.78 v1(42.24,97.78)
  L4 w0.508: v1(156.74,54.83) 156.74,61.51 164.26,69.03 164.26,69.79 167.6,73.13 167.6,78.04 166.91,78.73 v1(166.65,78.73) ; v1(163.42,102.71) 163.42,103.81 162.55,104.68 162.48,104.75 162.48,105.91 162.48,106.8 160.68,108.6 133.15,108.6 132.65,108.11 123.73,108.11 120.11,111.73 82.44,111.73 78.79,108.07 78.79,107.15 78.81,107.13 78.81,105.91 78.79,105.88 78.79,104.9 78.79,104.9 78.79,104.27 76.31,101.79 46.17,101.79 42.24,97.87 v1(42.24,97.78)
  L6 w0.508: v1(163.42,102.71) 163.02,102.71 162.63,102.33 162.63,99.13 165.87,95.89 165.87,94.13 167.44,92.56 167.44,81.61 165.95,80.12 165.95,79.1 166.32,78.73 v1(166.65,78.73)
USB_ADT_D: length 7.2
  BOTTOM w0.254: PD4407.K 152.22,34.2 PD4406.K 150.7,32.94 149.96,33.67 148.42,33.67 148.21,33.47 148.17,33.47 147.52,32.82 PR4408.1
USB_ADT_D1: length 9.1
  TOP w0.254: v1(156.64,49.75) 156.64,50.44 PC4434.2 ; PD4409.K 157.61,53.31 155.81,53.31 PD4411.K 155.6,52.95 156.82,51.73 v2(156.82,51.58) PC4434.2 ; PC4434.2 157.99,50.61 PR4442.1
  BOTTOM w0.254: PU4403.4 156.7,49.54 156.64,49.6 v1(156.64,49.75)
USB_ADT_R1: length 7.6
  TOP w0.254: PQ4308.6 29.37,72.14 28.5,73.02 PD4306.A 28.5,73.88 28.83,74.21 PR4327.1 29.94,74.21 PR4328.2 30.73,73.41 v2(30.02,72.7) PQ4308.5
USB_ADT_SW: length 16
  TOP w0.127: v1(28.14,71.19) 28.14,70.73 v2(27.86,70.45) 27.23,69.82 PR4320.2 PR4321.1 ; PU4304.4 v1(31.34,82.3)
  L4 w0.127: v1(31.34,82.3) 31.34,77.39 28.14,74.18 v1(28.14,71.19)
USB_ADT_SW_R: length 3.8
  TOP w0.127: PR4321.2 28.84,68.75 29.33,68.25 30.01,68.25 v2(30.2,68.44) 30.67,68.92 PQ4308.3
USB_CAMERA_N: length 5.1
  TOP w0.102: 62.99,91.94 63.27,91.66 63.98,91.66 64.19,91.87 EL5501.3 ; 62.99,91.94 v2(63.09,92.04) ; 62.99,91.94 62.33,92.6 v1(62.33,94)
  BOTTOM w0.102: TCBD1.15 62.15,93.82 v1(62.33,94)
USB_CAMERA_P: length 5.7
  TOP w0.102: 62.1,92.68 62.1,93.53 61.99,93.64 61.77,93.64 61.69,93.72 v1(61.69,94) ; 62.1,92.68 62.1,92.5 63.18,91.43 63.98,91.43 64.22,91.19 EL5501.2 ; 62.1,92.68 v2(61.97,92.68)
  BOTTOM w0.102: TCBD1.14 61.65,93.95 v1(61.69,94)
USB_CPU_PN0: length 139.2
  TOP w0.102: v1(22.66,43.02) 23.01,43.02 v2(23.19,43.2)
  L6 w0.089: 115.12,38.78 115.04,38.86 115.04,38.91 114.63,39.32 114.63,40.74 114.54,40.84 114.3,40.84 v1(114.2,40.73)
  L6 w0.127: v1(22.66,43.02) 22.64,43.02 22.37,42.74 22.37,42.16 23.38,41.15 23.38,36.59 23.9,36.07 27.93,36.07 30.96,33.04 30.96,29.25 33,27.21 36.83,27.21 41.49,22.55 45.51,22.55 54.39,13.66 78.9,13.66 82.27,17.03 96.22,17.03 97.5,18.32 103.59,18.32 104.18,18.9 107.07,18.9 107.72,18.25 112.68,18.25 114.11,19.69 114.11,20.64 113.71,21.04 113.71,22.42 115.4,24.1 115.4,31.65 116.18,32.43 116.18,37.72 115.12,38.78
  BOTTOM w0.102: U3401.2 22.6,44.55 22.46,44.42 22.46,43.21 22.66,43.02 v1(22.66,43.02) ; CPU1.AB9 114.54,41.08 114.22,40.76 114.22,40.76 v1(114.2,40.73)
USB_CPU_PN1: length 137.4
  TOP w0.102: v2(24.59,50.23) v1(25.15,50.23)
  L6 w0.127: v1(113.14,39.31) 113.14,38.38 115.49,36.02 115.49,33.06 112.9,30.47 112.9,24.68 112.27,24.05 111.89,24.05 110.56,22.72 110.56,21.83 108.41,19.68 99.6,19.68 99.03,19.1 97.19,19.1 95.95,17.86 90.63,17.86 89.95,18.55 82.62,18.55 78.53,14.46 65.92,14.46 65.29,15.08 54.07,15.08 45.83,23.32 41.81,23.32 37.15,27.98 33.4,27.98 31.74,29.65 31.74,33.36 28.14,36.95 28.14,40.81 27.53,41.42 27.53,46.57 26.36,47.74 26.36,49.65 26.04,49.97 25.41,49.97 v1(25.15,50.23)
  BOTTOM w0.102: CPU1.AD6 113.67,39.33 113.49,39.51 113.33,39.51 v1(113.14,39.31) ; EL3606.1 24.44,51.31 24.22,51.09 24.22,50.34 24.6,49.95 24.86,49.95 v1(25.15,50.23)
USB_CPU_PN2: length 130.5
  TOP w0.102: v2(173.84,50.46) 173.84,50.32 ; 173.84,50.32 EL6601.2 ; 173.84,50.32 175.43,50.32 176.03,50.92 v1(176.93,50.92)
  L3 w0.14: v1(176.93,50.92) 177.13,50.73 177.4,50.73 177.99,50.14 177.99,48.11 178.56,47.54 178.56,46.15 178.04,45.63 178.04,32.6 176.03,30.6 175.35,29.91 175.35,25.27 174.73,24.65 163.87,13.79 163.87,12.51 162,10.65 148.82,10.65 147.25,9.08 142.2,9.08 141.37,9.91 133.15,9.91 129.95,6.71 126.64,6.71 121.18,12.18 119.45,12.18 114.62,17.01 114.62,20.45 113.43,21.64 113.43,26.18 112.05,27.56 112.05,29.78 110.39,31.45 110.39,32.33 110.28,32.43 110.27,32.44 109.6,33.11 109.57,33.14 v1(109.42,33.14)
  BOTTOM w0.089: 110.83,35.7 110.83,35.92 110.91,36 110.91,36.53 110.87,36.63 110.87,36.83 110.91,36.9 110.91,37.18 110.87,37.28 110.87,37.76 CPU1.AH3
  BOTTOM w0.102: v1(109.42,33.14) 109.55,33.14 110.01,33.6 110.01,34.1 109.94,34.17 109.94,34.57 110.83,35.47 110.83,35.7
USB_CPU_PN2_C: length 3.3
  TOP w0.102: EL6601.1 171.41,50.32 171.3,50.21 170.77,50.21 170.58,50.01 ; 170.58,50.01 170.19,49.62 v1(169.87,49.62) ; 170.58,50.01 v2(170.48,50.11)
  BOTTOM w0.102: v1(169.87,49.62) 169.79,49.71 IOBD1.19
USB_CPU_PN3: length 108.9
  TOP w0.102: 40.75,33.14 40.32,33.14 v1(40.12,32.94) ; 40.75,33.14 40.89,33.14 41.41,33.66 U3802.2 ; 40.75,33.14 v2(40.75,33.01)
  L6 w0.089: 113.16,37.86 113.16,37.96 112.74,38.37 112.74,41.3 112.81,41.36 113.09,41.36 v1(113.14,41.3)
  L6 w0.127: 113.16,37.86 113.16,36.85 113.5,36.5 113.5,35.13 112.33,33.96 112.33,31.28 109.82,28.76 109.82,27.95 107.73,25.87 107.73,24.22 108.51,23.45 108.51,21.17 107.52,20.18 100.66,20.18 100.46,20.39 96.92,20.39 94.99,18.46 91.03,18.46 90.37,19.12 80.47,19.12 79.17,17.82 79.17,16.09 78.1,15.03 66.06,15.03 65.34,15.75 55.13,15.75 44.9,25.99 43.97,25.99 41.2,28.76 41.2,32.63 40.9,32.94 v1(40.12,32.94)
  BOTTOM w0.102: v1(113.14,41.3) 113.44,41.3 CPU1.AD9
USB_CPU_PN4: length 167.1
  TOP w0.102: v1(69.09,89.83) 69,89.92 69,90.53 68.58,90.95 67.45,90.95 66.69,91.71 66.52,91.71 ; 66.52,91.71 66.01,91.71 65.85,91.87 EL5501.4 ; 66.52,91.71 v2(66.52,91.84)
  L6 w0.127: v1(69.09,89.83) 68.41,90.5 66,90.5 65.45,89.95 55.96,89.95 55.67,90.24 54.41,90.24 51.37,87.2 51.37,65.13 48.7,62.46 48.7,54.31 41.37,46.98 41.37,44.26 48.18,37.46 48.18,24.94 54.47,18.65 64.65,18.65 65.45,17.85 70.53,17.85 71.65,18.97 73.68,18.97 75.93,21.21 77.6,21.21 87.15,30.76 96.47,30.76 97.71,32.01 100.46,32.01 101.38,32.92 104.07,32.92 105.14,33.99 106.69,33.99 106.91,34.21 v1(107.49,34.21)
  BOTTOM w0.102: CPU1.AJ1 110.46,36.4 110.36,36.29 110.36,35.6 109.45,34.69 108.68,34.69 108.21,34.21 v1(107.49,34.21)
USB_CPU_PN5: length 122.2
  TOP w0.102: v1(175.52,48.89) 175.22,48.58 174.83,48.58 ; EL6602.2 173.64,47.69 174.53,48.58 174.83,48.58 ; 174.83,48.58 v2(174.83,48.71)
  L3 w0.089: 112.69,38.75 112.69,38.83 112.43,39.08 112.28,39.08 112.11,38.92 v1(112.11,38.83)
  L3 w0.14: 112.69,38.75 112.69,36.42 113.05,36.06 113.05,33.84 112.63,33.43 112.63,32.6 114.36,30.87 114.36,28.86 115.45,27.77 115.45,23.07 116.19,22.33 116.19,17.66 120.1,13.75 121.88,13.75 126.84,8.79 128.35,8.79 131.08,11.52 141.98,11.52 142.85,10.65 146.6,10.65 148.59,12.64 161.77,12.64 162.29,13.16 162.29,14.44 173.77,25.92 173.77,30.56 174.46,31.25 174.46,32.95 175.79,34.28 175.79,39.39 176.41,40.01 176.41,48.37 176.01,48.78 175.63,48.78 v1(175.52,48.89)
  BOTTOM w0.102: CPU1.AF6 112.41,39.12 v1(112.11,38.83)
USB_CPU_PN5_C: length 3.3
  TOP w0.102: 170.71,47.54 170.05,47.54 v1(169.87,47.72) ; 170.71,47.54 v2(170.71,47.69) ; 170.71,47.54 171.4,47.54 171.55,47.69 EL6602.1
  BOTTOM w0.102: IOBD1.22 169.33,48.21 169.82,47.72 v1(169.87,47.72)
USB_CPU_PN6: length 125.4
  TOP w0.102: v2(176.1,52.47) 175.94,52.32 v1(175.51,52.32) 174.34,52.32 174.06,52.59 173.61,52.59 173.42,52.78 EL6603.2
  L3 w0.14: v1(175.51,52.32) 175.68,52.15 176,52.15 176.27,51.88 176.27,49.62 177.2,48.7 177.2,34.45 175.25,32.49 175.25,30.92 174.56,30.24 174.56,25.6 163.08,14.12 163.08,12.83 162.1,11.85 148.91,11.85 146.93,9.87 142.52,9.87 141.69,10.7 132.83,10.7 129.63,7.5 126.97,7.5 121.5,12.96 119.77,12.96 115.4,17.33 115.4,22.01 114.22,23.2 114.22,26.51 112.84,27.89 112.84,31.28 112.4,31.72 112.07,32.05 112.07,34.66 111.59,35.13 v1(111.54,35.13)
  BOTTOM w0.102: CPU1.AH1 111.17,36.68 111.17,35.96 111.16,35.94 111.16,35.51 v1(111.54,35.13)
USB_CPU_PN6_C: length 4.2
  TOP w0.102: 170.99,52.41 170.61,52.03 170.61,51.55 170.39,51.32 170.1,51.32 v1(169.9,51.53) ; 170.99,52.41 171.12,52.54 171.47,52.54 171.71,52.78 EL6603.1 ; 170.99,52.41 v2(170.9,52.51)
  BOTTOM w0.102: IOBD1.16 169.41,51.21 169.52,51.32 169.7,51.32 v1(169.9,51.53)
USB_CPU_PN7: length 180.1
  TOP w0.102: v2(74.9,92.35) 74.79,92.23 ; 74.79,92.23 75,92.02 75,91.23 74.24,90.47 v1(74.24,89.98) ; 74.79,92.23 74.65,92.37 74.1,92.37 73.94,92.53 EL5502.4
  L6 w0.127: v1(74.24,89.98) 73.52,90.71 69.6,90.71 69.02,91.29 65.54,91.29 64.98,90.73 56.32,90.73 56,91.05 54.1,91.05 50.6,87.55 50.6,68.16 47.79,65.35 47.79,54.77 40.55,47.53 40.55,43.92 47.23,37.24 47.23,24.77 55.32,16.68 70.51,16.68 72.02,18.19 74,18.19 76.25,20.44 77.95,20.44 87.5,29.99 99.54,29.99 101.7,32.15 106.32,32.15 106.84,32.67 107.75,32.67 109.05,33.97 109.05,34.4 111.56,36.9 111.56,39.62 v1(112.06,40.12)
  BOTTOM w0.102: v1(112.06,40.12) 112.08,40.12 112.38,40.43 CPU1.AF8
USB_CPU_PP0: length 140.4
  TOP w0.102: v1(22.01,43.04) 22.2,42.86 v2(22.2,42.49)
  L6 w0.089: 115.3,38.97 115.23,39.05 115.17,39.05 114.82,39.4 114.82,40.82 v1(114.22,41.43)
  L6 w0.127: v1(22.01,43.04) 22.1,42.96 22.1,42.05 23.11,41.04 23.11,36.48 23.79,35.81 27.81,35.81 30.69,32.93 30.69,29.14 32.89,26.94 36.72,26.94 41.38,22.28 45.4,22.28 54.28,13.4 79.01,13.4 82.38,16.77 96.33,16.77 97.61,18.05 103.7,18.05 104.29,18.63 106.96,18.63 107.61,17.99 112.79,17.99 114.37,19.57 114.37,20.75 113.98,21.15 113.98,22.31 115.67,23.99 115.67,31.54 116.44,32.32 116.44,37.83 115.3,38.97
  BOTTOM w0.102: CPU1.AB10 114.51,41.73 v1(114.22,41.43) ; v1(22.01,43.04) 22.24,43.27 22.24,44.41 22.1,44.54 U3401.3
USB_CPU_PP1: length 138.8
  TOP w0.102: v1(25.15,49.44) 25.15,49.29 v2(24.81,48.96)
  L6 w0.127: v1(113.13,39.96) 113.54,39.55 113.54,39.15 113.4,39.01 113.4,38.49 115.76,36.13 115.76,32.95 113.17,30.36 113.17,24.57 112.38,23.78 112,23.78 110.83,22.61 110.83,21.72 108.52,19.41 99.71,19.41 99.14,18.84 97.3,18.84 96.06,17.59 90.52,17.59 89.84,18.28 82.73,18.28 78.64,14.19 65.81,14.19 65.18,14.81 53.96,14.81 45.72,23.05 41.7,23.05 37.04,27.72 33.29,27.72 31.47,29.54 31.47,33.25 27.87,36.84 27.87,40.7 27.27,41.31 27.27,46.46 26.1,47.63 26.1,49.54 25.93,49.71 25.41,49.71 v1(25.15,49.44)
  BOTTOM w0.102: CPU1.AD7 113.32,39.77 v1(113.13,39.96) ; v1(25.15,49.44) 24.86,49.72 24.51,49.72 23.99,50.25 23.99,51.09 23.76,51.31 EL3606.4
USB_CPU_PP2: length 130.1
  TOP w0.102: 175.03,50.09 175.52,50.09 176.12,50.69 176.25,50.69 176.35,50.59 176.35,50.13 176.48,50 176.76,50 176.88,50.12 v1(176.88,50.23) ; 175.03,50.09 173.52,50.09 173.35,49.93 173.35,49.78 173.22,49.64 EL6601.3 ; 175.03,50.09 v2(175.03,49.95)
  L3 w0.14: v1(176.88,50.23) 177.11,50.46 177.29,50.46 177.72,50.03 177.72,48 178.29,47.43 178.29,46.26 177.77,45.74 177.77,32.71 175.77,30.71 175.08,30.02 175.08,25.38 174.62,24.92 163.6,13.9 163.6,12.62 161.89,10.91 148.71,10.91 147.88,10.08 147.88,10.08 147.8,10 147.14,9.34 142.31,9.34 141.48,10.18 133.04,10.18 129.84,6.98 126.75,6.98 121.29,12.44 119.56,12.44 114.88,17.12 114.88,20.56 113.69,21.75 113.69,26.29 112.32,27.67 112.32,29.89 110.65,31.56 110.65,32.44 110.47,32.62 110.16,32.93 110.16,33.81 110.03,33.93 109.78,33.93 v1(109.6,33.75)
  BOTTOM w0.089: CPU1.AJ3 110.56,37.7 110.69,37.57 110.69,37.25 110.73,37.14 110.73,36.94 110.69,36.87 110.69,36.58 110.73,36.49 110.73,36.09 110.6,35.97 110.6,35.75
  BOTTOM w0.102: v1(109.6,33.75) 109.71,33.86 109.71,34.67 110.6,35.56 110.6,35.75
USB_CPU_PP2_C: length 4.1
  TOP w0.102: EL6601.4 171.43,49.64 171.09,49.98 170.86,49.98 v1(169.87,48.99) 169.98,48.89 v2(170.46,48.89)
  BOTTOM w0.102: IOBD1.20 169.65,49.21 v1(169.87,48.99)
USB_CPU_PP3: length 109.4
  TOP w0.102: v2(113.11,42.64) v1(113.11,42) ; U3802.1 41.01,33.58 40.79,33.37 40.32,33.37 v1(40.12,33.57)
  L6 w0.089: v1(113.11,42) 113.11,41.93 112.55,41.38 112.55,38.3 112.89,37.96 112.89,37.86
  L6 w0.127: v1(40.12,33.57) 40.49,33.2 41.01,33.2 41.46,32.74 41.46,28.87 44.08,26.25 45.01,26.25 55.24,16.02 65.45,16.02 66.17,15.29 77.99,15.29 78.9,16.21 78.9,17.93 80.35,19.38 90.48,19.38 91.14,18.72 94.88,18.72 96.81,20.65 100.57,20.65 100.77,20.45 107.41,20.45 108.24,21.29 108.24,23.34 107.47,24.11 107.47,25.98 109.55,28.06 109.55,28.87 112.06,31.39 112.06,34.07 113.23,35.24 113.23,36.39 112.89,36.74 112.89,37.86
  BOTTOM w0.102: CPU1.AD10 113.67,41.95 113.54,42.08 113.19,42.08 v1(113.11,42)
USB_CPU_PP4: length 166.3
  TOP w0.102: 68.07,90.72 67.36,90.72 66.6,91.48 66.11,91.48 65.82,91.19 EL5501.1 ; 68.07,90.72 68.48,90.72 68.77,90.43 68.77,90.12 68.48,89.83 v1(68.3,89.83) ; 68.07,90.72 v2(68.07,90.59)
  L6 w0.127: v1(107.45,34.86) 107.32,34.99 107.06,34.99 106.91,34.84 106.91,34.59 106.58,34.26 105.03,34.26 103.96,33.19 101.27,33.19 100.35,32.27 97.6,32.27 96.36,31.03 87.04,31.03 77.49,21.48 75.82,21.48 73.57,19.23 71.54,19.23 70.42,18.11 65.56,18.11 64.76,18.91 54.58,18.91 48.45,25.05 48.45,37.57 41.64,44.37 41.64,46.87 48.97,54.2 48.97,62.35 51.64,65.02 51.64,87.09 54.52,89.97 55.56,89.97 55.85,89.68 65.56,89.68 66.11,90.24 68.1,90.24 68.3,90.04 v1(68.3,89.83)
  BOTTOM w0.102: CPU1.AJ2 110.43,37.05 110.13,36.75 110.13,35.7 109.35,34.92 108.59,34.92 108.11,34.44 107.85,34.44 107.45,34.84 v1(107.45,34.86)
USB_CPU_PP5: length 121.8
  TOP w0.102: v2(173.96,47.49) 173.86,47.59 ; 173.86,47.59 174.62,48.35 174.85,48.35 174.95,48.25 174.95,48.07 175.06,47.97 175.38,47.97 175.51,48.1 v1(175.51,48.25) ; 173.86,47.59 173.74,47.47 173.4,47.47 172.95,47.01 EL6602.3
  L3 w0.089: 112.95,38.75 112.93,38.78 112.93,38.85 112.51,39.27 112.25,39.27 v1(112.06,39.46)
  L3 w0.14: v1(175.51,48.25) 175.77,48.51 175.9,48.51 175.95,48.46 176.15,48.26 176.15,40.12 175.52,39.5 175.52,34.39 174.19,33.06 174.19,31.36 173.51,30.67 173.51,26.03 162.02,14.55 162.02,13.27 161.66,12.91 148.48,12.91 146.49,10.92 142.96,10.92 142.09,11.79 130.97,11.79 128.24,9.06 126.95,9.06 121.99,14.02 120.21,14.02 116.46,17.77 116.46,22.44 115.72,23.18 115.72,27.88 114.63,28.97 114.63,30.98 112.9,32.71 112.9,33.32 113.32,33.73 113.32,36.17 112.95,36.53 112.95,38.75
  BOTTOM w0.102: v1(112.06,39.46) 112.37,39.77 112.59,39.77 CPU1.AF7
USB_CPU_PP5_C: length 4.2
  TOP w0.102: EL6602.4 171.54,47.01 171.25,47.31 170.13,47.31 v1(169.87,47.06) 169.7,47.06 v2(169.37,46.73)
  BOTTOM w0.102: IOBD1.23 169.23,47.71 169.5,47.44 169.5,47.15 169.59,47.06 v1(169.87,47.06)
USB_CPU_PP6: length 125.7
  TOP w0.102: v1(175.51,51.65) 175.49,51.63 175.06,51.63 174.95,51.73 174.95,51.96 174.83,52.09 174.25,52.09 173.97,52.37 173.68,52.37 173.42,52.1 EL6603.3 ; v2(112.11,35.07) 112.11,35.22 111.56,35.78 v1(111.55,35.78)
  L3 w0.14: v1(111.55,35.78) 111.95,35.38 111.95,35.15 112.34,34.77 112.34,32.16 112.96,31.54 113.11,31.39 113.11,28 114.48,26.62 114.48,23.31 115.67,22.12 115.67,17.45 119.88,13.23 121.61,13.23 127.08,7.76 129.52,7.76 132.72,10.96 141.8,10.96 142.64,10.13 146.82,10.13 148.8,12.12 161.99,12.12 162.81,12.95 162.81,14.23 174.29,25.71 174.29,30.35 174.98,31.03 174.98,32.6 176.93,34.56 176.93,48.59 176.01,49.51 176.01,51.77 175.89,51.88 175.74,51.88 v1(175.51,51.65)
  BOTTOM w0.102: CPU1.AH2 111.17,37.41 111.3,37.41 111.4,37.3 111.4,35.96 111.55,35.81 v1(111.55,35.78)
USB_CPU_PP6_C: length 4.3
  TOP w0.102: 170.76,51.38 170.76,51.38 170.48,51.1 170.13,51.1 v1(169.92,50.89) ; 170.76,51.38 170.84,51.45 170.84,51.93 171.22,52.32 171.47,52.32 171.69,52.1 EL6603.4 ; 170.76,51.38 v2(170.85,51.29)
  BOTTOM w0.102: v1(169.92,50.89) 169.72,51.1 169.62,51.1 169.23,50.71 IOBD1.17
USB_CPU_PP7: length 179
  TOP w0.102: v2(74.22,90.97) 74.32,90.87 ; 74.32,90.87 74.06,90.62 73.66,90.62 73.46,90.42 v1(73.46,89.98) ; 74.32,90.87 74.77,91.32 74.77,91.93 74.55,92.14 74.23,92.14 73.94,91.85 EL5502.1
  L6 w0.127: v1(73.46,89.98) 73.53,90.06 73.53,90.32 73.41,90.44 69.49,90.44 68.91,91.02 65.65,91.02 65.09,90.47 56.21,90.47 55.89,90.78 54.21,90.78 50.86,87.43 50.86,68.05 48.06,65.24 48.06,54.66 40.82,47.42 40.82,44.03 47.5,37.35 47.5,24.88 55.43,16.95 70.4,16.95 71.91,18.46 73.89,18.46 76.14,20.71 77.84,20.71 87.39,30.26 99.43,30.26 101.59,32.41 106.21,32.41 106.73,32.94 107.64,32.94 108.79,34.08 108.79,34.51 111.29,37.01 111.29,39.73 111.56,39.99 111.56,40.28 v1(112.06,40.78)
  BOTTOM w0.102: CPU1.AF9 112.35,41.08 v1(112.06,40.78)
USB_EN#: length 342.7
  TOP w0.127: v1(200.02,34.31) 200.02,34.61 199.59,35.04 KBC24.13 ; v1(169.87,53.59) 170.43,53.59 171.6,54.75 v2(171.83,54.75) 172.46,55.39 176.53,55.39 177.85,54.07 v1(177.9,54.07)
  L3 w0.127: v1(21.89,40.86) 21.31,41.44 21.31,49.05 23.21,50.96 23.21,57.18 24.91,58.88 25.28,58.88 30.35,63.95 30.35,74.72 31.14,75.51 31.14,78.86 33.87,81.59 33.87,84.61 31.82,86.66 31.82,88.68 32.37,89.22 32.37,90.5 31.98,90.9 31.98,93.56 32.54,94.12 32.89,94.12 33.77,95 36.96,95 42.93,100.97 76.52,100.97 78.52,102.98 78.91,102.98 84.06,108.12 84.06,109.68 86.87,112.48 162.02,112.48 166.23,108.28 166.23,106.49 168.55,104.17 169.91,104.17 170.91,103.16 170.91,100.27 174.01,97.17 177.88,97.17 179.37,95.69 179.37,92.52 178.04,91.19 178.04,89.54 178.99,88.59 178.99,79.06 178.76,78.83 178.76,73.78 176.45,71.47 176.45,69.36 175.61,68.52 175.61,63.49 177.91,61.19 177.91,56.49 177.46,56.03 177.46,54.51 v1(177.9,54.07) 179.18,52.79 179.18,51.63 179.72,51.1 179.72,50.49 180.02,50.18 180.68,48.46 180.68,47.69 184.13,44.24 186.77,44.24 187.04,43.97 199.02,43.97 199.35,43.64 199.35,34.98 v1(200.02,34.31)
  BOTTOM w0.127: U3501.4 22.85,39.52 22.34,40.03 22.34,40.42 v1(21.89,40.86) ; R2434.2 199.77,34.56 v1(200.02,34.31) ; v1(169.87,53.59) 170.56,52.9 170.56,35.98 169.29,34.71 IOBD1.49
USB_OC0#: length 344.3
  TOP w0.102: RN1601.6 137.82,47.18 137.01,47.99 136.09,47.99 135.84,47.74 131.35,47.74 129,45.4 129,42.71 127.53,41.23 126.64,41.23 v1(126.42,41.45) ; v1(20.57,44.52) 22.1,44.52 v2(23.42,45.84) 23.42,46.93 v1(24.33,47.84)
  L3 w0.102: v1(44.32,97.58) 44.32,97.81 45.54,99.03 47.47,99.03 47.69,99.24 52.14,99.24 52.81,99.91 57.42,99.91 58.31,99.03 61.78,99.03 62.67,99.91 65.87,99.91 66.76,99.03 76.06,99.03 77.16,100.12 78.62,100.12 85.37,106.87 85.37,109.14 87.16,110.93 122.01,110.93 122.88,110.05 128.54,110.05 129.43,110.95 161.38,110.95 164.67,107.66 164.67,105.83 166.37,104.13 166.37,101.21 169.19,98.39 169.19,96.31 v1(170.23,95.27) ; v1(31.93,90.16) 31.44,89.68 31.44,86.7 33.63,84.51 33.63,81.7 30.88,78.96 30.88,75.63 30.1,74.85 30.1,64.04 25.18,59.12 24.81,59.12 22.97,57.28 22.97,51.06 21.07,49.15 21.07,45.01 v1(20.57,44.52) 21.07,44.02 21.07,41.05 v1(21.89,40.22)
  L4 w0.102: v1(126.42,41.45) 126.64,41.23 127.58,41.23 129.31,39.5 129.31,38.31 134.25,33.37 144.69,33.37 146.03,34.71 148.79,34.71 149.68,35.6 150.93,35.6 151.41,36.08 151.41,38.44 153.07,40.1 156.12,40.1 158.66,42.64 159.74,42.64 160.88,43.78 163.83,43.78 164.82,44.77 164.82,57.37 165.53,58.08 165.53,59.81 167.23,61.51 167.23,70.32 169.57,72.66 169.57,94.61 v1(170.23,95.27)
  L6 w0.102: v1(44.32,97.58) 43.28,96.54 39.65,96.54 36.83,93.72 35.48,93.72 v1(31.93,90.16)
  BOTTOM w0.102: v1(126.42,41.45) 126.24,41.45 125.91,41.12 CPU1.A9 ; v1(24.33,47.84) 23.9,47.41 U3401.13 ; U3501.3 21.51,39.84 v1(21.89,40.22)
USB_OC1#: length 76.8
  TOP w0.102: RN1601.5 137.52,47.77 137.1,48.19 136.01,48.19 135.76,47.95 131.27,47.95 128.8,45.48 128.8,42.79 127.63,41.62 v1(127.07,41.62) v2(127.07,42.18)
  L4 w0.102: v1(159.56,43.07) 158.81,43.07 156.04,40.3 152.98,40.3 151.2,38.52 151.2,36.72 150.95,36.47 149.94,36.47 148.39,34.92 145.95,34.92 144.6,33.57 134.34,33.57 129.51,38.4 129.51,39.59 127.48,41.62 v1(127.07,41.62)
  BOTTOM w0.102: v1(127.07,41.62) 126.73,41.96 126.39,41.96 126.21,41.79 126.08,41.79 125.74,41.45 125.13,41.45 125.07,41.39 125.04,41.39 124.69,41.05 CPU1.C9 ; v1(159.56,43.07) 160.02,43.53 164.03,43.53 166.52,41.04 166.52,36.87 166.46,36.81 166.46,35.64 166.88,35.21 IOBD1.48
USB_OC2#: length 20.5
  TOP w0.102: RN1601.8 138.19,46.07 137.46,45.34 135.46,45.34 v2(135.14,45.66) 134.82,45.98 134.82,46.8 134.36,47.26 131.62,47.26 129.69,45.33 129.69,42.64 128.01,40.96 128.01,40.88 v1(127.69,40.56)
  BOTTOM w0.102: v1(127.69,40.56) 127.57,40.44 126.91,40.44 126.76,40.59 125.24,40.59 125.23,40.6 125.23,40.6 125.06,40.77 124.8,40.77 124.78,40.75 124.46,40.75 124.17,41.05 CPU1.D9
USB_OC3#: length 19.1
  TOP w0.102: v1(127.07,40.83) 127.41,40.83 127.53,40.96 127.54,40.96 129.22,42.64 129.22,45.33 131.43,47.54 134.69,47.54 v2(135.2,47.04) 136.69,45.55 137.17,45.55 137.64,46.01 137.64,46.53 137.78,46.68 RN1601.7
  BOTTOM w0.102: v1(127.07,40.83) 126.92,40.99 126.41,40.99 126.21,40.78 125.52,40.78 125.26,41.03 CPU1.B9
USB_PN0_R: length 1.8
  BOTTOM w0.102: EL3605.1 22.74,49.51 22.46,49.23 22.46,48.74 22.6,48.6 U3401.11
USB_PN7_TPNL: length 4.8
  TOP w0.102: EL5502.3 72.2,92.53 72.08,92.42 70.6,92.42 70.4,92.62 ; 70.4,92.62 70.23,92.8 v1(70.23,93.92) ; 70.4,92.62 v2(70.51,92.73)
  BOTTOM w0.102: v1(70.23,93.92) 70.15,93.84 TCBD1.31
USB_POWERSHARE_VBUS_EN: length 236.1
  TOP w0.102: v1(20.57,45.16) 20.57,45.38 v2(20.29,45.66) ; v1(184.68,40.05) 184.29,40.05 184.1,40.24 KBC24.71
  L3 w0.102: v1(129.11,2.23) 127.86,0.98 121.82,0.98 119.55,3.25 119.55,5.28 119.32,5.51 117.35,7.48 109.41,7.48 104.21,2.28 61.81,2.28 60.69,3.39 47.91,3.39 44.93,6.37 44.93,9.28 44.47,9.74 42.48,9.74 42.22,9.49 41.42,9.49 40.91,10 38.91,10 36.8,12.11 32.86,12.11 32.43,12.53 32.43,14.72 32.08,15.08 31.36,15.08 30.8,15.63 30.8,21.96 27.24,25.53 27.24,28.02 23.39,31.87 23.39,34.1 21.87,35.62 21.87,39.11 19.66,41.32 19.66,44.25 v1(20.57,45.16)
  L4 w0.102: v1(184.68,40.05) 185.06,39.66 185.06,38.65 185.84,37.87 186.06,37.87 186.45,37.48 186.45,37.11 185.37,36.04 185.37,34.84 186.43,33.77 186.43,32.68 185.75,32 185.75,29.13 186.82,28.06 186.82,26.04 185.6,24.82 185.6,24.8 176,15.21 164.87,15.21 164.11,14.44 161.92,14.44 161.03,13.56 161.03,13.13 160.67,12.76 157.01,12.3 155.2,12.3 152.98,10.08 152.06,10.08 150.93,8.94 150.93,7.72 148.94,5.73 148.3,5.73 147.64,5.07 146.34,5.07 142.99,1.72 130.77,1.72 130.26,2.23 v1(129.11,2.23)
  BOTTOM w0.102: v1(20.57,45.16) 20.57,45.18 20.8,45.41 U3401.5
USB_PP0_R: length 1.8
  BOTTOM w0.102: U3401.10 22.1,48.6 22.24,48.74 22.24,49.33 22.06,49.51 EL3605.4
USB_PP7_TPNL: length 5.7
  TOP w0.102: 71.68,92.19 72.03,92.19 72.37,91.85 EL5502.2 ; 71.68,92.19 70.51,92.19 70,92.7 70,93.35 69.89,93.46 69.62,93.46 69.52,93.56 69.52,93.87 v1(69.59,93.95) ; 71.68,92.19 v2(71.68,92.04)
  BOTTOM w0.102: v1(69.59,93.95) 69.65,93.89 TCBD1.30
USB_PWR_SHR_EN_L#: length 226.6
  TOP w0.102: KBC24.118 193.21,27.87 193.01,27.67 193.01,27.37 192.75,27.12 192.58,27.12 191.52,26.06 190.58,26.06 189.83,26.81 189.23,26.81 188.59,26.18 188.04,26.18 v1(187.78,26.43)
  L3 w0.102: v1(128.42,2.23) 127.38,1.19 121.91,1.19 119.76,3.34 119.76,5.36 119.53,5.59 117.43,7.69 109.33,7.69 104.12,2.48 61.89,2.48 60.77,3.6 47.99,3.6 45.13,6.46 45.13,9.36 44.5,10 42.44,10 42.14,9.69 41.5,9.69 40.94,10.25 38.94,10.25 36.89,12.31 32.94,12.31 32.64,12.62 32.64,14.81 32.16,15.28 31.44,15.28 31.01,15.72 31.01,22.05 27.44,25.61 27.44,28.11 23.59,31.95 23.59,34.18 22.07,35.7 22.07,39.41 20.57,40.91 v1(20.57,43.83)
  L4 w0.102: v1(128.42,2.23) 129.13,1.52 143.08,1.52 146.43,4.87 148.97,4.87 150.75,6.65 150.75,7.26 151.13,7.64 151.13,8.84 152.16,9.87 153.06,9.87 155.28,12.09 157.02,12.09 161.34,12.64 162.66,13.96 164.31,13.96 165.07,14.72 176.28,14.72 182.27,20.71 182.49,20.71 187.78,26 v1(187.78,26.43)
  BOTTOM w0.102: R3401.1 v2(19.91,43.48) 20.27,43.83 v1(20.57,43.83) ; v1(187.78,26.43) 187.45,26.76 R2473.1
USB_TYPEC_DIS: length 10.5
  TOP w0.254: v1(34.47,75.91) 34.47,76.55 v2(34.59,76.67) 35.46,76.67 PR4338.2 ; PQ4310.6 32.38,69.74 v1(32.69,69.43)
  L6 w0.254: v1(34.47,75.91) 33.45,74.9 33.45,71.85 32.69,71.09 v1(32.69,69.43)
USB_TYPEC_R: length 16.6
  TOP w0.127: v1(39.65,70.96) 39.65,71.04 v2(39.17,71.52) 38.96,71.72 PC4310.1 38.99,72.43 PR4336.1 38.61,73.17 PR4322.1 ; v1(41.77,81.92) PU4303.4
  L3 w0.127: v1(41.77,81.92) 41.48,81.63 41.48,71.7 40.74,70.96 v1(39.65,70.96)
USB_TYPEC_SW: length 2.7
  TOP w0.254: PR4322.2 38.05,72.86 37.39,72.86 v2(37.26,72.74) 37.26,71.72 37.52,71.46 PQ4307.3
USBC1_CC1_CONN: length 67.9
  TOP w0.203: 20.5,41.44 20.27,41.67 ED3801.2 19.96,41.49 19.78,41.32
  TOP w0.254: v1(22.02,41.49) 20.98,41.49 20.93,41.44 ; 20.93,41.44 C3711.1 ; 20.93,41.44 20.5,41.44 ; v1(16.05,41.11) v2(17.24,41.11) 19.58,41.11 19.78,41.32
  L3 w0.254: v1(9.52,93.62) 9.52,93.35 10.51,92.37 13.14,92.37 13.82,91.69 13.82,69.21 16.91,66.11 16.91,57.55 17.88,56.58 17.88,46.45 16.84,45.41 16.84,41.95 16.05,41.16 v1(16.05,41.11)
  BOTTOM w0.178: 8.61,93.74 8.48,93.74 8.19,93.46 USB1.A5
  BOTTOM w0.254: 8.61,93.74 9.4,93.74 v1(9.52,93.62) ; R3728.2 22.86,41.04 22.4,41.49 v1(22.02,41.49)
USBC1_CC2_CONN: length 102.7
  TOP w0.203: 20.55,42.31 20.32,42.08 ED3801.1 19.96,42.29 19.86,42.38
  TOP w0.254: v1(18.74,51.25) 18.74,51.22 19.24,50.73 v2(19.24,43.37) 19.24,43 19.86,42.38 ; 20.55,42.31 C3712.1 21.28,42.03 22.55,42.03 22.78,42.26 R3727.2
  L3 w0.076: USB1.B5 7.36,95.06 7.39,95.09
  L3 w0.089: 6.62,96.17 6.62,95.94 arc(6.56,95.89) 6.5,95.84 6.48,95.82 arc(6.41,95.73) 6.38,95.64 USB1.B5
  L3 w0.229: 6.62,96.17 6.81,96.36 7.82,96.36 ; 7.39,95.09 7.82,95.52 7.82,96.36 ; 7.82,96.36 8.99,97.53 8.99,97.88 9.55,98.44 9.55,99.38 v1(9.49,99.44)
  L3 w0.254: v1(9.49,99.44) 9.95,99.89 13.41,99.89 18.08,95.22 18.08,92.32 14.76,88.99 14.76,84.19 15.37,83.58 15.37,68.42 17.45,66.34 17.45,61.59 18.74,60.29 v1(18.74,51.25)
  L4 w0.089: 6.65,96.2 6.27,95.46 USB1.B5
  L4 w0.229: 6.65,96.2 6.81,96.36 7.82,96.36 8.99,97.53 8.99,97.88 9.55,98.44 9.55,99.38 v1(9.49,99.44)
  L6 w0.076: USB1.B5 7.31,95.06
  L6 w0.089: 6.62,96.17 6.62,95.94 arc(6.56,95.89) 6.5,95.84 6.48,95.82 arc(6.41,95.73) 6.38,95.64 USB1.B5 5.96,94.26 6.38,93.68 arc(6.41,93.59) 6.48,93.5 6.48,93.41 arc(6.45,93.26) 6.38,93.12 arc(6.36,93.08) 6.33,93.05 6.33,92.84 6.38,92.78 arc(6.41,92.69) 6.48,92.6 6.5,92.58 arc(6.56,92.53) 6.62,92.48 arc(6.79,92.41) 6.98,92.38
  L6 w0.102: 6.98,92.38 7.22,92.38 7.36,92.52
  L6 w0.152: 7.31,95.06 7.57,95.06
  L6 w0.229: 7.82,96.36 7.82,96.1 7.57,95.85 7.57,92.73 7.36,92.52 ; 7.82,96.36 6.81,96.36 6.62,96.17 ; 7.82,96.36 8.99,97.53 8.99,97.88 9.55,98.44 9.55,99.38 v1(9.49,99.44)
USBC_DPAUX1: length 69.7
  TOP w0.102: v2(19.25,96.82) 18.85,96.82 v1(18.61,96.57) 18.42,96.38 18.13,96.38 R3830.1 17.47,96.23 16.86,96.23 ED3803.2 16.76,96.46 16.66,96.56 16.66,96.76 16.39,97.04 13.1,97.04 11.9,95.84 10.8,95.84 v1(10.51,96.13) ; U3801.27 32.7,62.62 32.88,62.79 32.88,63.05 v1(32.61,63.31)
  L6 w0.127: v1(32.61,63.31) 32.8,63.13 32.8,62.96 32.59,62.75 32.21,62.75 31.56,63.4 31.56,66.45 32.08,66.97 32.08,73.5 28.73,76.85 28.73,84.32 25.2,87.85 25.2,92.17 24.05,93.31 24.05,95.85 24.43,96.23 24.43,99.53 23.13,100.83 21.34,100.83 19.19,98.68 19.19,96.6 19.02,96.43 18.75,96.43 v1(18.61,96.57)
  BOTTOM w0.102: USB1.A8 8.18,94.96 8.43,94.71 8.99,94.71 9.09,94.81 9.6,94.81 9.9,95.11 9.9,95.98 9.75,96.13 9.75,96.33 10.03,96.61 11.33,96.61 11.45,96.49 11.45,96.18 11.33,96.05 10.59,96.05 v1(10.51,96.13)
USBC_DPAUX2: length 69.7
  TOP w0.102: v2(19.2,95.47) 18.73,95.94 v1(18.61,95.94) 18.39,96.16 18.21,96.16 R3831.1 17.71,96 16.56,96 16.36,96.21 ED3803.1 16.36,96.43 16.44,96.51 16.44,96.66 16.29,96.81 13.19,96.81 12,95.61 10.63,95.61 v1(10.51,95.5) ; U3801.26 33.1,63.17 v1(33.25,63.31)
  L3 w0.089: USB1.B8 6.38,92.78 arc(6.41,92.69) 6.48,92.6 6.5,92.58 arc(6.56,92.53) 6.62,92.48 arc(6.79,92.41) 6.98,92.38
  L3 w0.102: 6.98,92.38 7.17,92.38 7.26,92.47
  L3 w0.14: v1(10.51,95.5) 10.29,95.5 7.26,92.47
  L6 w0.127: v1(33.25,63.31) 33.06,63.13 33.06,62.85 32.7,62.49 32.09,62.49 31.29,63.29 31.29,66.56 31.81,67.09 31.81,73.38 28.46,76.74 28.46,84.21 24.93,87.74 24.93,92.06 23.79,93.2 23.79,95.96 24.17,96.34 24.17,99.42 23.02,100.56 21.45,100.56 19.45,98.57 19.45,96.49 19.14,96.17 18.83,96.17 v1(18.61,95.94)
USBCOMP: length 2.8
  TOP w0.254: v1(114.2,39.3) 113.81,39.3 v2(113.21,38.7)
  TOP w0.457: R1603.1 114.62,38.7 114.2,39.12 v1(114.2,39.3)
  BOTTOM w0.305: v1(114.2,39.3) 114.38,39.12 CPU1.AB6
V_SM_VREF_CNTA: length 53.6
  TOP w0.508: R1206.2 73.05,48.9 C1222.1 v2(74.29,48.92) 74.86,48.92 75.56,49.62 v1(75.56,50.51)
  L4 w0.508: v1(105.36,74.24) 104.62,73.5 100.3,73.5 99.61,74.18 93.65,74.18 89.03,69.56 89.03,55.95 83.59,50.51 v1(75.56,50.51)
  BOTTOM w0.254: v1(105.36,74.24) 105.26,74.34 104.9,74.34 104.63,74.61 CPU1.AY67
V_SM_VREF_CNTB: length 80
  TOP w0.457: C1323.1 50.14,44.01 50.42,43.73 R1305.2
  TOP w0.508: v1(49.48,43.6) 49.48,42.97 49.5,42.94 v2(49.5,42.89) 49.96,42.89 50.21,43.15 R1305.2
  L4 w0.508: v1(49.48,43.6) 50.49,43.6 51.1,44.21 63.57,44.21 65.4,46.04 71.25,46.04 73.51,48.3 73.51,50.41 75.74,52.65 84.28,52.65 88.01,56.38 88.01,69.98 93.48,75.45 v1(102.23,75.45)
  BOTTOM w0.089: CPU1.BA67 103.66,74.75 103.34,74.91 103.18,74.97 103.07,75.07 102.61,75.07 v1(102.23,75.45)
VCONN_MON_P1: length 13.8
  TOP w0.127: v2(22.02,38.4) 22.02,38.6 22.45,39.03 R3706.2 22.78,38.45 v1(22.66,38.32) ; R3735.1 32.2,38.09 v1(31.8,38.5) U3701.19
  BOTTOM w0.127: v1(22.66,38.32) 22.66,38.32 22.8,38.18 25.82,38.18 26.69,37.3 30.6,37.3 v1(31.8,38.5)
VCREF0: length 8.9
  TOP w0.102: KBC24.25 198.04,39.84 197.6,40.28 197.6,41.1 197.08,41.62 196.52,41.62 v1(196.04,42.1)
  BOTTOM w0.102: R2424.1 194.18,44.54 R2448.1 C2409.1 194.99,43.17 195.55,42.61 196.36,42.61 v2(196.51,42.46) 196.51,42.3 196.31,42.1 v1(196.04,42.1)
VD_IN1_C: length 131.5
  TOP w0.114: v1(146.05,2.15) 145.41,1.52 134.14,1.52 133.35,2.3 133.35,12.32 v1(134.06,13.02) ; v1(123.06,30.06) 122.5,29.51 122.5,29.19 121.44,28.12 121.44,26.41 v2(121.36,26.33) 121.41,26.28 v1(121.41,25.72)
  L3 w0.102: v1(121.41,25.72) 121.41,24.78 126.77,19.42 127.27,19.42 130.88,15.81 130.88,15.47 132.33,14.03 133.52,14.03 134.06,13.49 v1(134.06,13.02)
  L4 w0.114: v1(146.05,2.15) 146.05,2.17 147.96,4.09 149.03,4.09 153.12,8.18 153.83,8.18 154.07,8.42 154.07,9.38 154.86,10.18 158.15,10.18 158.6,10.3 161.98,11.64 163.16,12.82 164.78,12.82 165.48,13.52 173.44,13.52 174.42,12.54 183.7,12.54 183.7,12.54 184.45,12.54 192.02,20.1 192.02,23.39 191.06,24.35 191.06,25.39 193.23,27.57 193.23,27.58 193.49,27.84 193.5,27.84 194.49,28.82 194.49,31.96 192.99,33.45 192.99,38.32 v1(195.48,40.81)
  BOTTOM w0.114: v1(123.06,30.06) 122.86,30.27 R2610.2 123.9,32.1 C2612.2 ; v1(195.48,40.81) 195.48,40.81 C2613.2 195.02,41.47 194.79,41.24 R2611.1
VOL_DOWN#: length 36.4
  TOP w0.102: v1(193.14,41.98) 193.24,41.98 194.01,42.74 KBC24.41 ; RN2407.3 169.62,41.96 168.96,41.29 v2(168.96,40.63) 168.96,38.51 v1(169.71,37.76)
  L4 w0.102: v1(186.13,38.56) 186.21,38.63 186.21,39.95 187.07,40.81 191.97,40.81 v1(193.14,41.98)
  L6 w0.102: v1(186.13,38.56) 185.61,38.04 185.31,38.04 184.59,37.32 183.6,37.32 182.65,38.27 181.58,38.27 181.05,37.74 169.73,37.74 v1(169.71,37.76)
  BOTTOM w0.102: v1(169.71,37.76) 169.26,38.21 IOBD1.42
VOL_UP#: length 40.9
  TOP w0.102: RN2407.4 170.61,41.09 v2(170.61,40.35) 170.61,39.34 v1(169.72,38.45) ; KBC24.34 196.81,44.98 196.95,45.13 197.41,45.13 197.76,45.48 v1(197.97,45.69)
  L6 w0.102: v1(197.97,45.69) 197.97,44.72 197.74,44.49 197.74,43.35 197.79,43.29 197.79,41.17 196.58,39.96 196.1,39.96 195.38,39.23 192,39.23 191.43,38.66 189.33,38.66 188.91,38.24 187.07,38.24 186.33,38.99 180.24,38.99 179.7,38.45 v1(169.72,38.45)
  BOTTOM w0.102: v1(169.72,38.45) 169.46,38.71 IOBD1.41
VR_CAP: length 3.5
  TOP w0.203: v1(200.38,36.49) 200.35,36.52 200.28,36.52 199.75,37.04 KBC24.18
  BOTTOM w0.254: v1(200.38,36.49) 199.9,36.49 v2(199.83,36.57) 199.44,36.19 199.38,36.19 C2418.1
VR_EN: length 2.3
  BOTTOM w0.102: PR4630.2 162.76,99.53 163.85,99.53 R4002.2 163.9,98.87 v2(164.2,98.57)
VR_RDY: length 4.5
  BOTTOM w0.102: PR4670.2 163.12,98.64 163.37,98.39 163.83,98.39 164.03,98.19 164.77,98.19 v2(165.43,98.85) 165.43,99.2 165.15,99.48 PR4614.2
VR_SVID_ALERT#: length 72.9
  TOP w0.114: v1(159.88,101.82) 159.88,101.86 157.89,103.86 156.61,103.86 PR4622.2 ; v1(132.26,74.16) 132.06,74.16 v2(131.77,74.44)
  L4 w0.114: v1(159.88,101.82) 160.37,102.31 160.69,102.31 161.01,101.99 161.01,100.7 162.06,99.65 163.54,99.65 163.95,99.65 163.95,99.65 167.31,96.29 167.31,93.1 167.89,92.53 167.89,83.03 161.72,76.86 154.1,76.86 153.81,76.57 151.94,74.71 133.21,74.71 132.66,74.16 v1(132.26,74.16)
  BOTTOM w0.114: v1(159.88,101.82) 159.88,101.22 PR4666.1 ; R728.1 v1(132.26,74.16) 132.81,74.16 R727.2
VR_SVID_CLK: length 72.2
  TOP w0.114: v2(131.98,72.86) 131.98,73.07 v1(132.26,73.35) ; PR4621.2 156.91,104.39 158.11,104.39 160.51,101.98 v1(160.51,101.78)
  L4 w0.114: v1(132.26,73.35) 131.82,73.78 131.82,74.34 132.19,74.71 132.44,74.71 132.93,75.2 151.73,75.2 153.31,76.78 153.89,77.36 161.52,77.36 167.39,83.24 167.39,92.33 166.82,92.9 166.82,96.08 163.75,99.15 161.85,99.15 161.56,99.44 161.56,99.44 160.51,100.49 v1(160.51,101.78)
  BOTTOM w0.114: v1(160.51,101.78) 160.5,101.77 PR4665.1 ; R723.2 132.87,73.35 v1(132.26,73.35) 132.03,73.58 131.77,73.58 R732.2
VR_SVID_DATA: length 68.1
  L4 w0.114: v1(159.25,101.81) 159.25,101.89 160.16,102.8 160.57,102.8 160.89,102.8 161.5,102.19 161.5,100.9 162.27,100.14 163.16,100.14 163.75,100.14 164.16,100.14 164.74,99.56 167.81,96.49 167.81,96.08 167.81,93.31 168.38,92.74 168.38,82.82 161.93,76.37 161.52,76.37 161.52,76.37 154.3,76.37 152.14,74.21 137.26,74.21 v1(134.8,71.75)
  BOTTOM w0.114: PR4623.2 159.25,102.09 v1(159.25,101.81) 159.25,101.35 PR4667.1 ; v2(134.08,70.86) 133.88,71.06 R709.2 134.69,71.75 134.69,71.75 v1(134.8,71.75)
VRALERT#: length 1.3
  TOP w0.102: TP1708.1 109.33,43.25 v1(109.33,43.17)
  BOTTOM w0.102: CPU1.AM11 109.65,42.85 v1(109.33,43.17)
VRAM_ID1: length 14.7
  L4 w0.102: v1(108.66,41.34) 108.76,41.34 109.15,40.95 109.28,40.95 109.65,40.58 109.65,35.53 108.58,34.46 108.58,31.84 108.84,31.59 v1(109.52,31.59)
  BOTTOM w0.102: CPU1.AP8 108.35,41.02 108.66,41.32 v1(108.66,41.34) ; v2(110.11,31.59) v1(109.52,31.59) 108.91,31.59 R2030.1 109.27,30.67 R2029.2
VRAM_ID2: length 3
  TOP w0.102: v1(116.92,34.85) TP2012.1
  BOTTOM w0.089: v1(116.92,34.85) 117.27,35.21 117.27,35.81 117.32,35.86 117.32,36.18 117.36,36.31 117.36,36.48 117.31,36.67 117.31,36.83 CPU1.U2
VREF_CPU: length 6
  TOP w0.203: C2406.1 179.29,31.11 179.48,30.92 179.49,30.92 180.11,30.29 v2(180.52,30.29) 181.66,30.29 181.68,30.32 182.12,30.32 182.44,30.64 KBC24.95
  TOP w0.508: C2406.1 178.55,31.11 178.17,31.49 R2402.2
VREG3PD: length 5.5
  TOP w0.406: C3709.1 30.43,93.31 30.32,93.31 30.29,93.34 v2(29.79,93.34) 29.38,93.34 29.34,93.37 U3702.1
  TOP w0.457: C3710.1 31.37,93.03 C3709.1
  TOP w0.508: D3702.A 29.46,92.5 U3702.1
WHITE_LED_BAT: length 4.3
  BOTTOM w0.508: v2(53.59,4.66) 53.54,4.72 R6402.2 52.68,5.42 EC6402.1 52.8,7.47 Q6401.C
WIFI_RF_EN: length 63.4
  TOP w0.102: v2(128.42,37.23) 128.26,37.39 v1(127.8,37.39)
  L4 w0.102: v1(156.89,39.97) 156.39,39.46 155.14,39.46 153.62,37.94 153.62,37.19 150.73,34.31 146.2,34.31 144.85,32.96 134.04,32.96 132.79,34.21 129.61,37.39 v1(127.8,37.39)
  BOTTOM w0.102: v1(156.89,39.97) 156.89,40.35 157.83,41.29 157.83,41.95 159.86,43.98 164.67,43.98 EC6603.1 165.48,44.34 167.16,42.66 167.16,36.44 167.39,36.21 IOBD1.46 ; CPU1.B7 125.34,39.92 125.82,39.43 126.33,39.43 127.05,38.71 127.05,37.81 127.47,37.39 v1(127.8,37.39) 127.96,37.56 128.32,37.56 128.74,37.77 129.41,38.44 R1503.2
XCLK_BIASREF: length 1.9
  TOP w0.254: v1(122.86,59.63) v2(123.42,59.63)
  TOP w0.508: R1803.1 120.06,49.5 v1(120.09,49.52)
  BOTTOM w0.305: v1(122.86,59.63) 122.86,59.75 123.19,60.08 CPU1.E42
XDP_BPM0: length 4.1
  TOP w0.089: v1(128.08,68.3) 128.05,68.27 127.63,68.27 127.48,68.42 TP405.1
  BOTTOM w0.089: v1(128.08,68.3) 128.03,68.3 128.01,68.32 127.39,68.32 126.95,67.88 126.84,67.88 126.14,67.87 125.9,67.87 125.9,67.86 125.55,67.86 125.43,67.74 CPU1.C55
XDP_BPM1: length 5.3
  TOP w0.089: TP406.1 126.59,67.73 126.8,67.94 127.33,67.94 127.4,67.86 127.63,67.86 v1(127.76,67.73)
  BOTTOM w0.089: v1(127.76,67.73) 127.63,67.86 127.18,67.86 127.11,67.79 127.02,67.7 126.96,67.7 126.22,67.69 126.21,67.69 125.98,67.69 125.97,67.68 125.68,67.68 125.45,67.45 124.76,67.45 124.48,67.74 CPU1.D55
XDP_BPM2: length 4.1
  TOP w0.089: TP407.1 125.91,67.28 126.97,67.28 127.01,67.31 127.16,67.31 127.23,67.38 v1(127.23,67.38)
  BOTTOM w0.089: CPU1.B54 125.43,67.18 125.69,67.44 126.33,67.44 126.44,67.33 126.72,67.33 126.72,67.33 127.18,67.33 127.23,67.38 v1(127.23,67.38)
XDP_BPM3: length 5.7
  BOTTOM w0.089: TP408.1 128.68,69.66 127.93,69.66 127.33,69.05 127.11,69.05 126.65,68.59 126.31,68.59 126.16,68.74 125.78,68.74 125.69,68.71 125.04,68.71 124.99,68.69 124.81,68.52 CPU1.C56
XDP_DBRESET#: length 20.3
  TOP w0.114: EC1706.1 118.26,44.71 117.85,44.3 R1701.2 117.85,40.15 118.54,39.46 118.54,38.68 118.74,38.47 118.74,37.9 120.09,36.55 122.06,36.55 122.88,35.74 122.88,35.48 123.12,35.24 123.82,35.24 125.68,37.1 TP1709.1 125.93,37.05 125.93,36.57 v1(126.06,36.44)
  BOTTOM w0.114: v1(126.06,36.44) 126.06,36.76 125.61,37.2 125.15,37.2 124.97,37.38 124.97,37.64 125.26,37.94 CPU1.B5
XDP_PRDY#: length 6.4
  BOTTOM w0.089: CPU1.D56 124.35,68.07 124.4,68.02 124.82,68.02 124.84,68.04 126.07,68.04 126.08,68.06 126.87,68.06 127.34,68.52 127.75,68.52 127.92,68.69 128.24,68.69 128.27,68.65 128.28,68.65 128.41,68.52 128.7,68.52 TP1605.1
XDP_PREQ#: length 2.4
  TOP w0.089: TP1606.1 123.17,71.21 123.17,71.26 v1(122.89,71.53)
  BOTTOM w0.089: CPU1.D61 123.96,70.84 123.42,71.39 123.04,71.39 v1(122.89,71.53)
XDP_TCK_JTAGX: length 7.1
  BOTTOM w0.089: CPU1.A59 126.08,69.66 126.16,69.74 126.54,69.74 126.85,70.05 127.65,70.05 128.18,70.58 129.16,70.58 v2(129.23,70.65) 129.69,70.2 129.69,69.74 130.26,69.18 130.26,68.37 130.72,67.91 R417.1
XDP_TCLK: length 6.1
  BOTTOM w0.089: CPU1.B61 125.47,70.78 125.75,71.05 126.31,71.05 126.8,71.55 127.39,71.55 127.93,72.09 v2(128.41,72.09) 128.65,72.33 R406.1
XDP_TDI: length 14
  TOP w0.089: v1(128.56,67.89) 128.58,67.91 128.58,69.43 128.35,69.66 127.7,69.66 127.32,69.28 126.78,69.28 v2(125.73,70.32) 123.15,70.32 v1(122.87,70.6)
  BOTTOM w0.089: v1(122.87,70.6) 122.89,70.58 123.75,70.58 124.11,70.22 CPU1.D60 ; R422.1 130,65.47 129.77,65.7 129.77,67.05 129.49,67.33 129.02,67.33 128.81,67.54 128.81,67.55 128.7,67.66 128.7,67.71 128.56,67.84 v1(128.56,67.89)
XDP_TDO_CPU: length 5.4
  BOTTOM w0.089: CPU1.A61 125.99,70.86 126.39,70.86 126.59,71.06 126.91,71.06 127.22,71.37 127.61,71.37 127.96,71.72 129.67,71.72 v2(129.8,71.85) 130.38,71.85 R423.1
XDP_TMS: length 6.6
  BOTTOM w0.089: CPU1.C60 126.51,70.22 126.82,70.53 127.48,70.53 128.36,71.4 130.06,71.4 R421.1
XDP_TRST#: length 12.3
  TOP w0.089: v1(132.31,70.83) 132.26,70.83 132.08,71.01 v2(129.87,71.01) 127.4,71.01 v1(127.38,70.98) 127.46,70.91 127.46,70.1 v1(127.02,69.66)
  BOTTOM w0.089: CPU1.B59 125.3,69.66 125.53,69.43 125.71,69.43 125.79,69.39 126.05,69.39 126.11,69.43 126.24,69.55 126.26,69.56 126.92,69.56 v1(127.02,69.66) ; v1(127.38,70.98) 127.38,70.93 127.15,70.7 126.74,70.7 126.56,70.52 124.87,70.52 CPU1.C61 ; R402.1 132.36,70.88 v1(132.31,70.83)
XTAL24_IN: length 10.1
  BOTTOM w0.089: R1804.2 129.85,53.27 129.45,53.67 v2(128.78,54.77) 128.57,55.1 127.99,55.79 126.48,57.31 126.03,57.54 124.82,57.54 124.81,57.55 124.42,57.55 124.41,57.54 124.17,57.54 124.16,57.55 123.7,57.55 CPU1.E37
XTAL24_IN_R: length 4.8
  BOTTOM w0.089: R1804.1 C1801.2 R1802.1 131.93,51.14 134.01,51.14 134.27,51.28 X1801.1
XTAL24_IN_U42: length 8.3
  BOTTOM w0.089: CPU1.E3 123.64,37.45 123.95,37.14 123.95,36.24 124.52,35.67 128.47,35.67 v2(129.21,36.43) 129.22,36.44 R2202.2
XTAL24_IN_U42_R: length 6.6
  BOTTOM w0.089: R2202.1 131.72,36.44 R2201.1 131.8,37.35 v2(131.88,37.43) 132.56,37.43 C2201.2 134.82,37.23 134.9,37.3 135.41,37.3 135.73,37.63 X2201.1
XTAL24_OUT: length 11.4
  BOTTOM w0.089: CPU1.E35 123.19,56.79 123.38,56.98 126.45,56.98 127.51,55.91 128.11,54.74 128.11,54.2 v2(129.87,52.44) R1805.2
XTAL24_OUT_R: length 3.5
  BOTTOM w0.089: R1805.1 R1802.2 131.93,49.24 C1802.2 132.93,49.22 X1801.3
XTAL24_OUT_U42: length 11.7
  BOTTOM w0.089: CPU1.C7 124.14,39.7 124.1,39.66 123.98,39.62 123.82,39.57 123.65,39.4 123.59,39.08 123.35,37.84 123.35,36.22 124.31,35.27 v2(128.83,35.27) 129.21,35.65 R2203.2
XTAL24_OUT_U42_R: length 3.3
  BOTTOM w0.089: R2203.1 R2201.2 C2202.2 132.79,36.01 X2201.3
ZVM#: length 1.1
  TOP w0.102: TP616.1 108.56,68.72 v1(108.02,68.72)
  BOTTOM w0.102: CPU1.AR56 107.7,68.4 v1(108.02,68.72)

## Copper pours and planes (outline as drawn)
5V_HDD on TOP: 175.44,17.52 175.39,17.57 175.39,19.68 174.85,20.21 170.84,20.21 170.66,20.39 170.66,21.96 171.91,23.21 175.18,23.21 176.73,21.66 176.73,20.41 176.3,19.98 176.3,19.55 176.1,19.35 176.1,17.64 175.97,17.52 ; 1 cut-out
5V_HDD_SIP on TOP: 176.63,18.69 176.33,18.99 176.33,19.65 177.09,20.41 177.09,21.43 177.14,21.48 177.93,21.48 178.05,21.35 179.63,21.35 179.7,21.28 179.69,21.26 179.69,19.18 179.2,18.69 ; 3 cut-outs
5V_HDD_SIP on BOTTOM: 176.33,18.66 176.12,18.86 176.12,20.97 176.38,21.23 178.79,21.23 178.87,21.15 178.87,19.52 178.76,19.42 177.52,19.42 177.42,19.32 177.42,19.02 177.06,18.66
5V_HDMI_R_S5 on TOP: 22.45,56.66 22.3,56.81 22.3,59.17 22.66,59.53 26.21,59.53 26.47,59.27 26.47,58.77 26.13,58.44 23.98,58.44 23.62,58.08 23.62,56.89 23.39,56.66
5V_HDMI_S5 on TOP: 18.87,57.5 18.11,58.26 17.83,58.26 17.7,58.39 17.7,59.78 17.96,60.04 18.9,60.04 19.28,59.66 19.73,59.66 19.86,59.53 19.86,59.4 19.99,59.27 21.64,59.27 21.77,59.15 21.77,57.62 21.64,57.5 ; 1 cut-out
5V_HDMI_S5 on L4: 15.54,77.69 15.54,71.09 18.72,67.91 18.72,61.43 19.48,60.67 19.48,58.64 18.97,58.13 17.83,58.13 16.94,59.02 16.94,61.81 17.07,61.94 17.07,66.64 13.77,69.94 13.77,76.93 12.62,78.07 11.61,78.07 11.35,78.32 11.35,79.52 11.63,79.8 13.43,79.8
5V_S0 on TOP: 173.3,15.33 172.77,15.87 172.77,16.5 173.1,16.83 173.91,16.83 174.06,16.68 174.06,15.59 173.81,15.33
5V_S0 on TOP: 26.85,56.1 25.96,56.99 25.58,56.99 25.2,57.37 25.2,58.13 25.32,58.26 26.47,58.26 27.74,56.99 27.74,56.61 27.23,56.1 ; 1 cut-out
5V_S0 on TOP: 66.85,98.77 66.72,98.9 66.72,100.8 67.11,101.18 70.79,101.18 71.42,100.55 71.42,99.15 71.17,98.9 70.03,98.9 69.9,98.77 ; 3 cut-outs
5V_S0 on TOP: 134.67,99.66 134.42,99.91 134.42,100.55 134.8,100.93 135.08,100.93 136.07,101.92 136.07,104.23 135.81,104.49 135.43,104.49 135.05,104.87 135.05,105.86 135.69,106.49 137.77,106.49 138.33,105.93 138.33,100.02 137.97,99.66 ; 2 cut-outs
5V_S0 on TOP: 172.92,17.52 172.69,17.75 172.69,18.63 172.41,18.91 170.89,18.91 170.71,19.09 170.71,19.45 171.27,20.01 173.28,20.01 173.71,19.57 173.71,18.66 173.96,18.41 173.96,17.59 173.89,17.52 ; 2 cut-outs
5V_S0 on BOTTOM: 134.54,99.79 134.42,99.91 134.42,100.27 134.82,100.68 134.82,101.26 134.95,101.39 136.02,101.39 136.42,101.79 137.62,101.79 137.72,101.69 137.72,100.3 137.46,100.04 136.07,100.04 135.81,99.79 ; 4 cut-outs
5V_S0 on BOTTOM: 171.88,15.21 171.12,15.97 171.12,18.13 170.74,18.51 170.74,19.4 170.99,19.65 173.28,19.65 173.58,19.35 173.58,18.38 174.04,17.92 174.04,15.46 173.79,15.21
5V_S0 on BOTTOM: 49.33,92.7 49.02,93.01 49.02,93.97 50.9,95.85 54.53,95.85 55.68,96.99 63.68,96.99 67.74,101.06 69.26,101.06 69.58,100.74 69.58,99.53 65.16,95.11 56.56,95.11 55.56,94.11 54.7,94.11 53.29,92.7
5V_S0 on BOTTOM: 33.7,50.99 31.7,53 28.65,53 27.23,54.42 27.23,55.26 24.64,57.85 22.96,57.85 22.35,58.46 22.35,59.22 22.53,59.4 23.34,59.4 23.65,59.1 26.47,59.1 28.89,56.67 28.89,56.27 30.3,54.86 34.11,54.86 35.84,53.13 42.87,53.13 43.13,52.87 43.13,51.53 42.59,50.99
5V_S0 on BOTTOM: 135.51,105.66 135.18,105.99 135.18,108.04 139.75,112.61 163.5,112.61 164.51,111.6 166.55,111.6 166.67,111.47 166.67,109.06 165.91,108.3 165.02,108.3 162.99,110.33 141.78,110.33 137.11,105.66
5V_S0 on BOTTOM: 29.89,14.24 29.84,14.29 29.84,18.2 30.72,19.08 30.72,21.49 29.37,22.84 28.74,22.84 27.71,21.81 26.36,21.81 25.3,22.88 25.3,24.91 25.04,25.16 25.04,26.89 24.66,27.27 24.43,27.27 24.31,27.4 24.31,27.78 24.69,28.16 26.85,28.16 27.35,27.65 27.35,26.51 28.62,25.24 32.18,25.24 33.7,23.71 33.7,18.51 33.96,18.25 33.96,15.21 33.15,14.39 30.83,14.39 30.68,14.24
5V_S0 on L4: 25.04,27.03 24.81,27.26 24.43,27.26 24.18,27.51 24.18,28.49 26.21,30.52 26.21,33.37 27.11,34.27 27.11,35.79 31.29,39.97 39.93,39.97 43.23,43.27 43.23,49.34 42.14,50.44 42.14,52.54 43.74,54.14 43.74,62.2 43.36,62.58 43.34,62.58 42.57,63.35 42.57,64.38 41.96,64.99 41.96,69.87 43.05,70.96 43.05,78.2 44.88,80.03 44.88,92.17 48.11,95.39 50.26,95.39 51.51,94.15 51.51,92.47 50.34,91.3 49.45,91.3 48.06,89.91 48.06,64.48 46.53,62.96 46.53,48.1 46.15,47.72 46.15,40.86 42.47,37.18 36.65,37.18 30.92,31.45 30.92,29.57 29.13,27.78 29.13,25.49 28.5,24.86 25.53,24.86 25.04,25.34
5V_S0 on L4: 136.45,102.58 135.43,103.6 133.65,103.6 133.27,103.98 131.37,103.98 130.41,104.93 126.35,104.93 119.94,111.34 82.6,111.34 79.17,107.92 79.17,103.98 76.5,101.31 67.92,101.31 67.64,101.03 67.64,100.25 68.15,99.74 70.46,99.74 70.47,99.72 76.06,99.72 76.5,99.28 78.03,99.28 81.33,102.58 81.33,107.1 83.92,109.69 119.18,109.69 126.29,102.58 132.13,102.58 132.51,102.2 132.51,101.31 134.16,99.66 136.19,99.66 136.45,99.91
5V_S0 on L5VCC: 172.72,15.02 172.07,15.67 172.07,24.78 174.1,26.81 174.1,41.8 178.67,46.37 178.67,51.23 177.53,52.37 177.53,53.73 177.91,54.12 177.91,60.88 174.61,64.18 174.61,70.88 176.77,73.04 176.77,77.77 176.13,78.4 176.13,82.69 176.9,83.45 176.9,89.29 177.15,89.55 177.15,94.91 175.39,96.68 172.98,96.68 171.45,98.2 171.07,98.2 165.34,103.93 165.34,110.88 166.48,112.03 166.48,113.41 166.7,113.41 167.05,113.27 167.19,112.92 167.19,107.42 167.93,105.65 169.7,104.91 179.7,104.91 180.05,104.77 180.19,104.42 180.19,69.21 180.05,68.86 179.7,68.72 178.7,68.72 177.63,68.28 177.19,67.21 177.19,66.21 177.63,65.14 178.7,64.7 179.7,64.7 180.05,64.56 180.19,64.21 180.19,58.53 180.38,55.72 180.96,52.97 180.96,44.62 176.26,39.92 176.26,16.05 175.23,15.02
5V_S5 on TOP: 23.44,35.14 23.39,35.2 22.6,35.2 22.4,35.4 22.4,36.41 23.11,37.13 24.15,37.13 24.19,37.16 24.32,37.16 24.46,37.3 24.46,37.86 24.76,37.86 24.76,37.3 24.89,37.18 25.2,37.18 26.08,36.29 26.8,36.29 26.87,36.21 26.87,35.3 26.72,35.14 ; 8 cut-outs
5V_S5 on TOP: 129.56,98.82 129.31,99.08 129.31,99.89 129.18,100.02 129.18,102.33 128.55,102.96 115.75,102.96 115.11,103.6 115.11,107.15 115.24,107.28 128.95,107.28 131.9,104.33 131.88,104.31 131.88,102.89 131.67,102.68 131.67,101.41 131.93,101.16 133.17,101.16 133.65,100.68 133.65,99.03 133.53,98.9 133.5,98.9 133.42,98.82 ; 2 cut-outs
5V_S5 on TOP: 25.42,55.85 25.2,56.07 24.97,56.07 24.81,56.23 24.43,56.23 24.18,55.97 23.8,55.97 23.67,56.1 23.67,56.73 23.8,56.86 23.8,58 23.93,58.13 24.81,58.13 24.94,58 24.94,57.37 25.45,56.86 25.83,56.86 26.21,56.48 26.21,55.97 26.08,55.85
5V_S5 on BOTTOM: 22.6,42.03 22.57,42.07 22.57,42.45 22.63,42.51 22.93,42.51 23.04,42.61 23.04,45.3 24.43,45.3 24.97,44.77 24.97,42.36 24.84,42.23 23.77,42.23 23.57,42.03 ; 2 cut-outs
5V_S5 on BOTTOM: 115.24,103.95 115.01,104.18 115.01,107.26 115.8,108.04 117.02,108.04 117.4,107.66 118.92,107.66 119.3,107.28 119.3,104.61 118.67,103.98 115.54,103.98 115.52,103.95
5V_S5 on BOTTOM: 38.76,97.71 38.5,97.96 38.5,98.31 38.81,98.62 38.81,99.69 38.89,99.76 39.47,99.76 39.8,100.09 41.53,100.09 41.71,99.91 41.71,99.03 41.5,98.82 40.1,98.82 38.99,97.71 ; 1 cut-out
5V_S5 on BOTTOM: 167.36,42.79 167.18,42.97 167.18,44.19 168.31,45.32 169.33,45.32 169.33,43.16 169.21,43.04 168.4,43.04 168.15,42.79
5V_S5 on BOTTOM: 131.75,98.77 131.6,98.92 131.6,100.93 131.8,101.13 132.13,101.13 132.31,101.31 132.64,101.31 132.69,101.36 133.6,101.36 133.65,101.31 133.65,100.68 133.78,100.55 133.78,99.03 133.53,98.77
5V_S5 on BOTTOM: 23.54,35.53 23.29,35.78 23.29,36.16 23.04,36.41 23.04,37.76 25.5,37.76 25.83,37.43 25.83,35.65 25.7,35.53 ; 3 cut-outs
5V_S5 on L3: 81.2,106.01 76.38,101.18 42.57,101.18 37.62,96.23 37.62,96.18 36.63,95.19 30.12,95.19 27.74,92.8 27.74,90.64 26.85,89.75 25.7,89.75 25.07,90.39 25.07,93.95 26.66,95.53 26.66,96.93 27.61,97.88 30.53,97.88 31.67,96.74 35.36,96.74 37.26,98.64 37.26,100.17 40.31,103.22 75.87,103.22 77.85,105.2 77.85,106.14 78.99,107.28 79.02,107.28 81.05,109.31 82.57,109.31 83.59,108.3 83.59,108.02 81.58,106.01
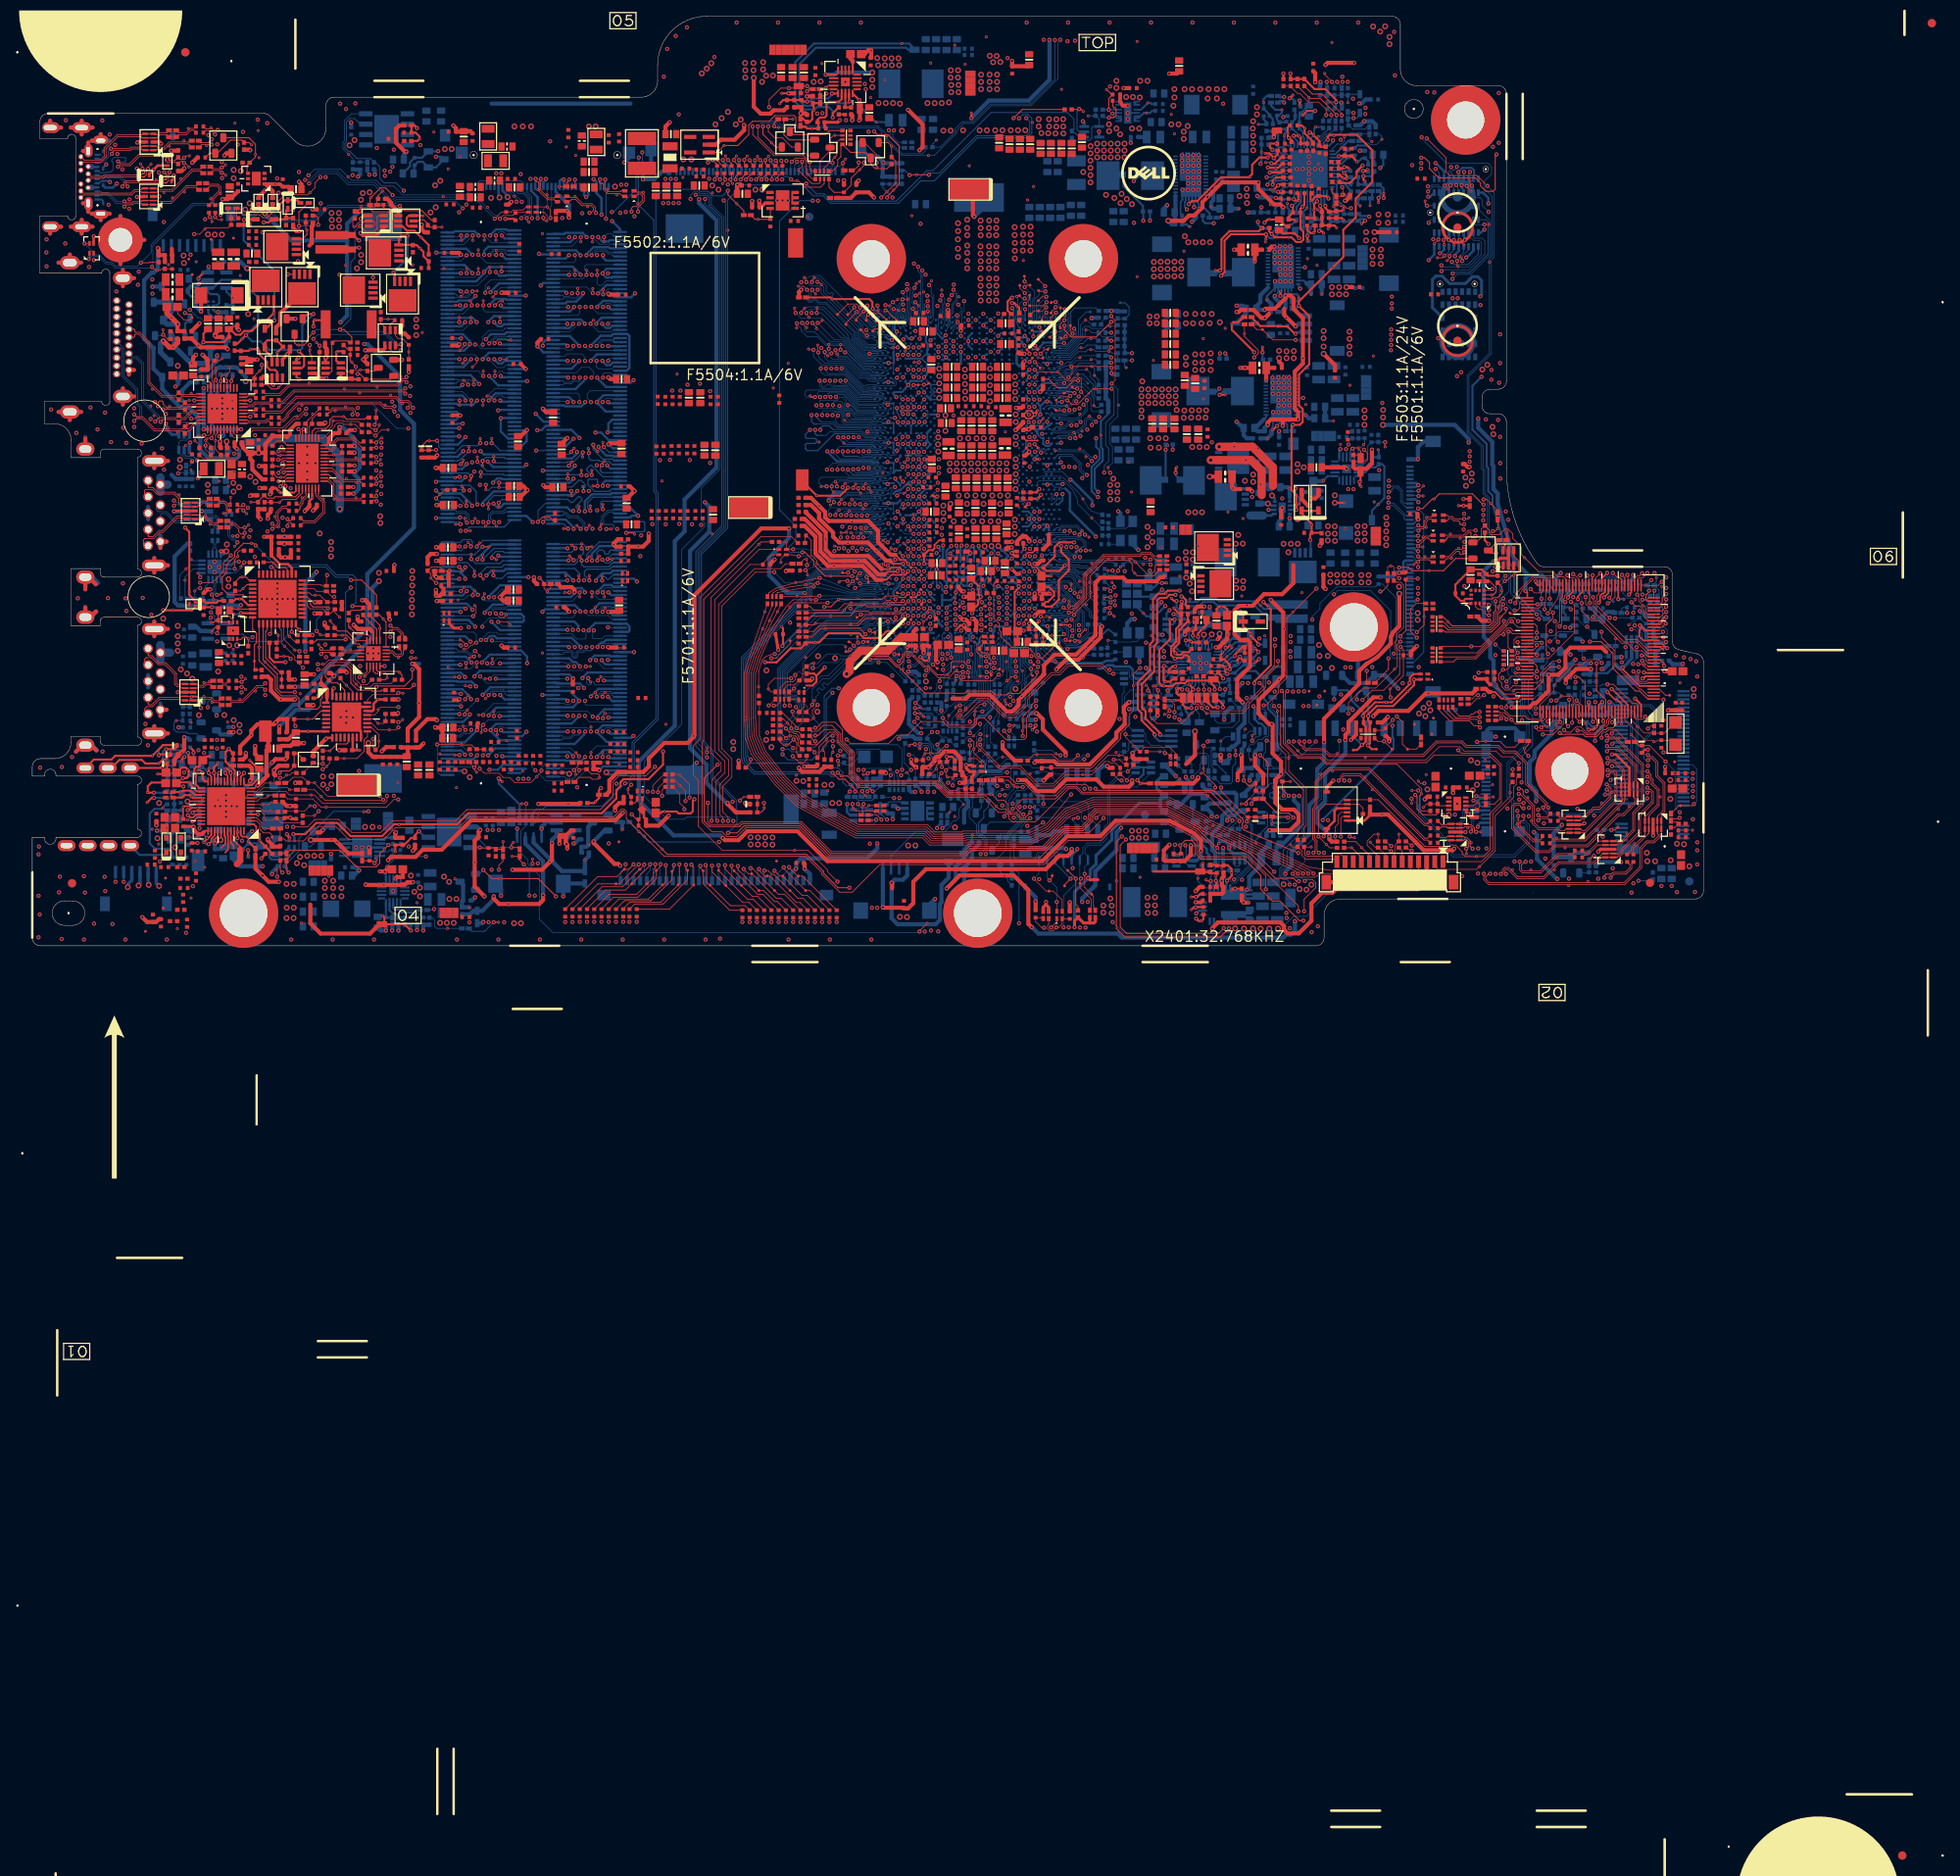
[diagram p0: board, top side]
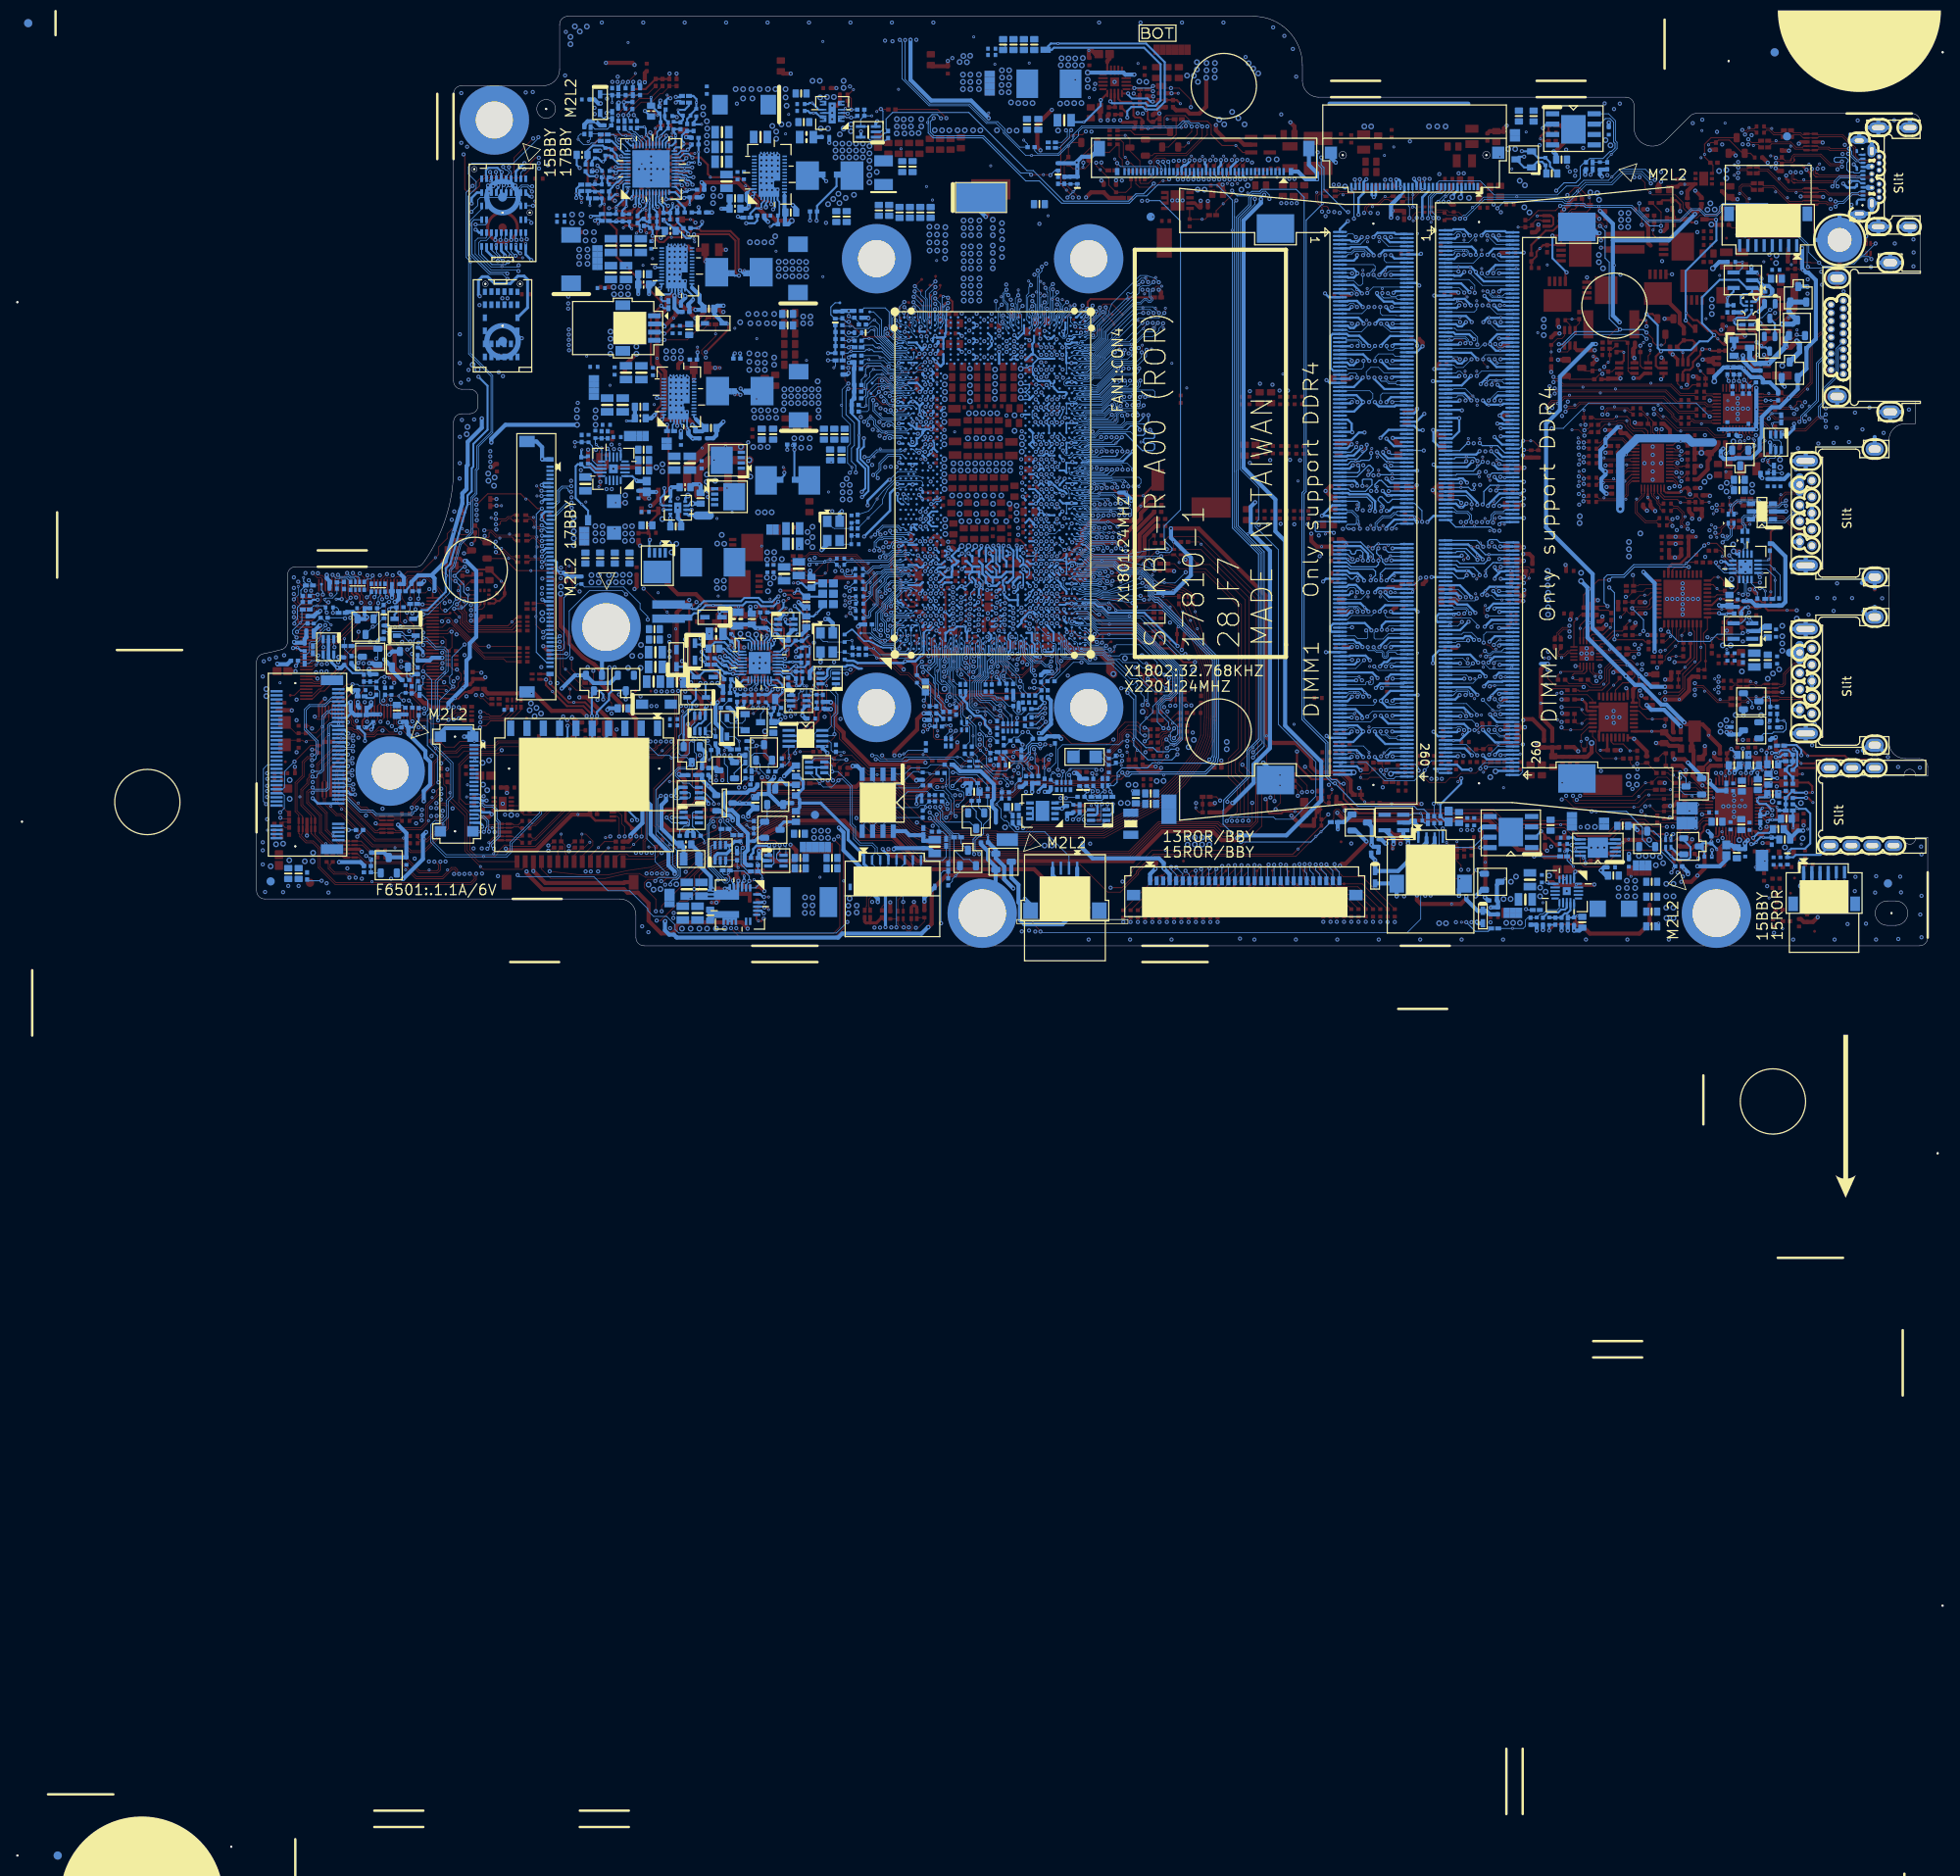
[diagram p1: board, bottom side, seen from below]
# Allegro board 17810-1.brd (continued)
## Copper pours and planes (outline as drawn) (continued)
5V_S5 on L3: 31.93,16.48 31.93,21.43 27.74,25.62 27.74,28.16 23.8,32.1 23.8,34.38 22.93,35.25 22.93,42.51 23.04,42.61 23.04,45.43 23.26,45.66 23.26,46.96 22.73,47.49 21.72,47.49 21.59,47.62 21.59,48.99 23.4,50.8 23.4,57.1 24.69,58.39 27.68,58.39 28.57,57.5 28.57,50.94 28.5,50.87 28.5,47.62 29.39,46.73 29.39,40.48 29.64,40.22 29.64,29.33 34.06,24.91 34.06,16.63 34.59,16.09 34.59,12.67 34.42,12.49 33.02,12.49 32.82,12.69 32.82,15.59
5V_S5 on L4: 26.21,56.2 26.21,60.16 27.2,61.15 27.2,63.19 28.37,64.35 28.37,66.01 28.83,66.46 28.83,69.99 24.69,74.13 24.69,76.98 26.03,78.32 26.03,84.62 27.86,86.45 27.86,90.39 26.85,91.41 26.26,91.41 26.06,91.2 26.06,90.92 23.93,88.79 23.93,85.39 22.02,83.48 22.02,78.91 21.39,78.27 21.39,77.89 20.8,77.31 20.8,72.91 23.8,69.92 24.51,69.92 24.79,69.64 24.79,65.78 23.54,64.53 23.54,57.37 24.99,55.92 25.93,55.92
5V_S5 on L4: 84.07,108.6 84.25,108.42 84.25,101.95 79.3,96.99 75.49,96.99 74.85,97.63 70.92,97.63 70.28,96.99 58.85,96.99 56.44,99.41 48.31,99.41 46.91,98.01 46.91,97.12 45.77,95.98 39.42,95.98 38.66,96.74 38.66,99.53 39.17,100.04 40.82,100.04 41.2,99.66 41.2,97.88 41.64,97.44 42.53,97.44 46.4,101.31 57.33,101.31 58.72,99.91 67.36,99.91 67.87,99.41 75.74,99.41 76.25,98.9 77.9,98.9 81.58,102.58 81.58,107.03 83.16,108.6
5V_S5 on L5VCC: 115.7,104.55 115.3,104.95 115.3,106.47 111.89,109.88 103.09,109.88 102.71,109.5 89.51,109.5 89.38,109.38 86.58,109.38 82.65,105.44 78.98,105.44 78.98,106.06 83.95,111.03 101.09,111.03 101.98,111.92 113.51,111.92 118.6,106.82 118.6,104.82 118.33,104.55
5V_S5 on L5VCC: 169.04,39.53 168.39,40.18 168.39,40.94 167.24,42.08 167.24,44.34 168.77,45.86 168.77,96.44 162.29,102.91 162.29,111.9 163.05,112.66 163.05,113.41 166.1,113.41 166.1,112.19 164.96,111.04 164.96,103.77 170.8,97.93 170.8,69.99 172.45,68.34 172.45,41.32 170.66,39.53
5V_S5 on L6: 26.59,43.58 26.59,37.43 25.73,36.57 24.08,36.57 23.93,36.73 23.93,41.37 23.42,41.88 23.42,43.15 23.16,43.4 23.16,44.92 23.54,45.3 24.86,45.3
5V_S5 on L6: 162.71,112.61 163.17,113.07 166.01,113.07 166.29,112.79 166.29,111.98 165.82,111.51 165.82,110.77 165.19,110.14 134.3,110.14 128.01,103.85 116.25,103.85 114.6,105.5 114.6,107.53 112.44,109.69 103.17,109.69 102.54,109.06 90.98,109.06 90.73,108.8 86.66,108.8 82.6,104.74 80.31,104.74 79.93,105.12 79.93,106.52 84.25,110.84 115.49,110.84 116,110.33 116,109.19 118.03,107.15 126.16,107.15 131.62,112.61
5V_S5 on L6: 132,102.33 132.64,102.33 132.76,102.2 132.76,101.31 133.45,100.63 133.45,100.3 132.97,99.81 132.69,99.81 132.28,99.41 131.75,99.41 131.24,99.91 131.24,101.82 131.49,102.07 131.75,102.07
+3V_AVDD on BOTTOM: 26.47,15.84 26.34,15.97 26.34,17.47 25.91,17.9 25.91,18.58 27.3,19.98 27.81,19.98 27.96,19.83 27.96,19.17 27.86,19.07 27.2,19.07 27.02,18.89 27.02,18.18 27.91,17.29 27.91,15.99 27.76,15.84 ; 2 cut-outs
+3VALW_EC on TOP: 177.98,27.4 177.72,27.65 177.72,28.79 177.47,29.05 176.81,29.05 176.05,28.29 175.06,28.29 174.55,28.79 174.55,29.43 174.42,29.56 174.27,29.56 174.14,29.68 172.13,29.68 172.01,29.81 172.01,30.32 172.26,30.57 175.44,30.57 175.56,30.45 175.56,29.3 176.4,29.3 177.16,30.06 177.6,30.06 177.98,30.45 178.52,30.45 178.9,30.83 179.25,30.83 179.5,30.57 179.5,30.06 178.87,29.43 178.87,27.52 178.74,27.4
+3VALW_EC on TOP: 170.86,32.35 170.74,32.48 170.74,33.49 170.51,33.72 170.51,36.44 170.74,36.67 171.93,36.67 171.93,34.56 172.36,34.13 173.79,34.13 174.65,34.99 178.33,34.99 179.75,36.41 180.62,36.41 180.74,36.29 180.74,34.33 180.64,34.23 175.33,34.23 173.45,32.35
+3VALW_EC on BOTTOM: 192.4,41.19 192.35,41.24 192.35,42.46 191.72,43.1 191.41,43.1 191.06,43.45 191.06,43.81 190.85,44.01 188.87,44.01 188.75,44.14 188.75,44.8 189.69,45.74 190.4,45.74 191.21,44.92 191.21,44.39 191.41,44.19 192.71,44.19 192.78,44.11 194.28,44.11 194.41,43.98 194.41,43.02 194.23,42.84 193.06,42.84 192.89,42.66 192.89,42 192.68,41.8 192.68,41.24 192.63,41.19 ; 1 cut-out
+3VALW_EC on L5VCC: 186.95,27.21 186.8,27.35 186.8,28.33 187.78,29.32 191.49,29.32 192.01,29.83 192.01,32.43 189.74,34.7 184.53,34.7 182.88,36.35 181.45,36.35 179.69,34.59 179.69,29.89 179.04,29.24 178.82,29.24 178.55,29.51 178.55,36.84 182.74,41.03 182.74,41.57 182.23,42.08 182.23,43.19 183.14,44.1 188.22,44.1 190.07,45.95 194.55,45.95 194.55,42.3 195.28,41.57 195.82,41.03 197.85,39 197.85,37.73 200.9,34.68 200.9,33.7 200.5,33.3 199.9,33.3 197.87,35.34 196.19,35.34 195.31,34.46 195.31,34.08 195.04,33.81 193.9,33.81 192.77,32.68 192.77,29.13 191.87,28.22 188.57,28.22 187.55,27.21
+5V_PVDD on BOTTOM: 23.04,12.79 21.87,13.96 21.69,13.96 21.59,14.06 21.59,14.47 21.69,14.57 24.41,14.57 24.48,14.49 25.58,14.49 25.8,14.72 25.8,15.43 26.08,15.71 27.86,15.71 28.12,15.97 28.12,17.62 28.24,17.75 29.51,17.75 29.64,17.62 29.64,14.57 29.39,14.32 26.59,14.32 25.93,13.66 25.93,12.92 25.8,12.79 25.47,12.79 25.35,12.92 25.07,12.92 24.99,13 23.62,13 23.42,12.79 ; 5 cut-outs
+V1.00A_SIP on TOP: 109.23,48.39 109.14,48.48 109.14,48.73 109.83,49.42 110.23,49.42 110.41,49.6 110.41,50.79 110.56,50.94 111.07,50.94 111.15,50.87 111.15,49.7 110.41,48.96 110.41,48.81 110.23,48.63 109.65,48.63 109.41,48.39
+V1.00A_SIP on TOP: 118.79,34.38 118.16,35.02 117.78,35.02 117.65,35.14 117.65,35.4 117.78,35.53 118.67,35.53 118.79,35.65 118.79,36.54 118.92,36.67 119.68,36.67 119.94,36.41 120.7,36.41 120.83,36.29 120.83,34.51 120.7,34.38 ; 1 cut-out
+V1.00A_SIP on BOTTOM: 133.65,40.61 133.27,40.99 133.27,44.67 133.4,44.8 134.42,44.8 134.54,44.67 134.54,41.49 134.8,41.24 134.8,40.73 134.67,40.61
+V1.00A_SIP on L3: 109.17,47.79 111.81,47.79 112.06,48.05 112.06,48.23 112.29,48.45 112.95,48.45 113.61,47.79 115.11,47.79 115.29,47.97 115.29,49.22 114.81,49.7 109.9,49.7 109.07,48.86 109.07,47.9
+V1.00A_SIP on L6: 113.66,42.46 114.4,42.46 115.31,41.55 116.36,41.55 116.71,41.19 116.71,38.27 116.97,38.02 116.97,36.21 117.35,35.83 117.35,35.25 117.57,35.02 118.06,35.02 118.49,35.45 118.49,37.43 119.31,38.26 119.31,42.35 120.42,43.45 125.19,43.45 125.5,43.76 126.74,43.76 126.95,43.96 126.95,44.11 126.8,44.26 124.59,44.26 123.47,45.38 123.47,46.27 123.14,46.6 121.03,46.6 120.55,47.08 120.55,47.41 120.24,47.72 119.91,47.72 119.78,47.84 119.78,48.35 119.99,48.56 120.24,48.56 120.32,48.63 120.32,49.01 120.22,49.11 119.02,49.11 118.92,49.01 118.92,48.68 118.72,48.48 116.38,48.48 116.13,48.23 114.98,48.23 114.86,48.1 114.86,46.96 113.26,45.36 113.26,42.87
+V1.00U_CPU on BOTTOM: 109.7,15.1 109.57,15.23 109.57,17.03 110.74,17.03 111.22,17.52 111.91,17.52 112.01,17.42 112.01,16.43 112.08,16.36 113.07,16.36 113.33,16.09 113.33,15.84 113.08,15.59 112.44,15.59 112.42,15.56 111.1,15.56 110.64,15.1 ; 1 cut-out
+V1.8A on TOP: 20.37,26.51 20.06,26.81 20.06,28.41 20.29,28.64 21.74,28.64 21.92,28.82 23.9,28.82 24.15,28.57 24.15,26.86 23.8,26.51
+V1.8A on BOTTOM: 42.49,14.06 42.29,14.27 42.29,15.51 41.01,16.79 35.93,16.79 33.83,18.89 33.83,23.97 32.31,25.49 28.75,25.49 27.74,26.51 27.74,27.78 27.1,28.41 24.56,28.41 24.05,27.91 23.29,27.91 23.16,28.03 23.16,28.52 23.32,28.67 23.32,29.33 23.67,29.68 24.18,29.68 24.69,30.19 27.74,30.19 29.26,28.67 29.26,27.14 29.89,26.51 33.68,26.51 35.23,24.96 35.23,19.4 35.86,18.76 39.27,18.76 39.47,18.56 41.88,18.56 42.16,18.28 42.16,18.25 43.48,16.93 43.48,14.06
+V1.8A on BOTTOM: 19.15,26.2 18.97,26.38 18.97,28.67 19.05,28.74 20.85,28.74 21.39,28.21 21.39,26.51 21.08,26.2 ; 4 cut-outs
+V1.8A on L6: 80.31,21.28 80.08,21.51 79.63,21.51 77.65,19.52 77.65,18.15 77.09,17.59 72.21,17.59 72.01,17.39 72.01,16.02 72.19,15.84 74.24,15.84 74.39,15.99 76.63,15.99 80.31,19.68
+V1.8A_SIP on TOP: 114.96,35.4 114.79,35.56 114.79,35.77 115.03,36.01 115.03,36.57 114.73,36.87 113.05,36.87 112.8,36.62 112.8,36.44 112.72,36.36 111.96,36.36 111.9,36.43 111.9,37.32 112.04,37.46 112.42,37.46 112.67,37.71 112.67,38.07 112.93,38.32 115.37,38.32 115.67,38.02 115.67,36.97 115.62,36.92 115.62,35.63 115.39,35.4 ; 5 cut-outs
+V1.8A_SIP on L3: 114.9,43.44 116,42.33 116,36.36 115.14,35.5 114.7,35.5 113.33,36.87 113.33,42.61 112.93,43.02 112.93,43.88 113.18,44.14 114.58,44.14 114.9,43.82
+V1.8A_SIP on L4: 110.29,45.3 115.67,45.3 116.2,44.77 116.2,43.22 115.77,42.79 115.77,39.92 115.49,39.64 115.49,35.65 115.24,35.4 114.73,35.4 114.4,35.73 114.4,42.87 114.2,43.07 113.21,43.07 111.96,44.31 110.77,44.31 110.26,43.81 109.9,43.81 109.7,44.01 109.7,44.72
+V3.3A_SIP on TOP: outline of 86 points within 94.33,37.25 115.3,49.19 ; 8 cut-outs
+V3.3A_SIP on TOP: 116.71,42.89 116.32,43.29 116.32,44.23 116.46,44.37 116.74,44.37 117.02,44.64 117.02,45.08 117.07,45.13 117.55,45.13 117.65,45.03 117.65,43.78 117.4,43.53 117.4,43.15 117.14,42.89 ; 1 cut-out
+V3.3A_SIP on L3: 111.91,43.78 112.67,43.78 113.21,44.31 114.6,44.31 115.14,43.78 117.12,43.78 117.27,43.93 117.27,45.74 116.94,46.07 112.6,46.07 112.29,46.37 110.64,46.37 110.42,46.16 110.42,44.75 110.68,44.49 111.2,44.49
+VCCGT on TOP: 118.67,65.24 118.29,65.62 117.91,65.62 117.78,65.75 117.78,66.26 117.91,66.39 118.67,66.39 118.92,66.64 118.92,71.47 118.79,71.59 116,71.59 115.75,71.34 115.75,65.88 115.62,65.75 114.1,65.75 113.97,65.88 113.97,66.51 113.84,66.64 112.95,66.64 112.83,66.77 112.83,71.34 112.57,71.59 111.17,71.59 110.92,71.34 109.78,71.34 109.65,71.47 109.65,75.78 109.52,75.91 108.89,75.91 108.76,76.04 108.76,83.66 107.75,84.67 107.75,92.8 109.02,94.07 110.11,94.07 111.81,95.77 111.81,98.14 112.06,98.39 119.05,98.39 119.35,98.09 122.68,98.09 123.21,97.55 127.99,97.55 128.14,97.71 128.14,98.19 128.22,98.26 129.08,98.26 129.47,98.66 134.05,98.66 134.24,98.47 134.24,96.49 133.15,95.39 133.15,93.31 135.18,91.28 135.18,90.39 133.91,89.12 120.06,89.12 119.56,88.61 119.56,79.34 119.43,79.21 119.43,73.37 120.95,71.85 120.95,67.66 121.08,67.53 121.59,67.53 121.72,67.4 121.72,66.77 121.59,66.64 121.21,66.64 121.08,66.51 120.32,66.51 120.19,66.39 120.19,65.37 120.06,65.24 ; 52 cut-outs
+VCCGT on BOTTOM: 119.81,66.39 119.6,66.6 119.6,70.44 119.47,70.57 119.43,70.57 119.43,71.09 118.92,71.59 118.03,71.59 117.65,71.21 117.14,71.21 116.76,71.59 116.25,71.59 115.87,71.21 115.45,71.21 114.45,72.22 114.31,72.22 114.3,72.22 114.11,72.41 114.11,75.14 114.22,75.25 114.22,75.56 114.11,75.67 114.11,78.99 114.1,79 114.1,79.19 112.77,80.53 112.77,81.1 109.27,84.6 109.27,91.66 116.38,98.77 122.1,98.77 122.99,97.88 122.99,95.88 123.62,95.24 129.13,95.24 129.34,95.44 129.34,98.54 129.44,98.64 134.06,98.64 134.26,98.44 134.26,96.51 133.17,95.42 133.17,93.16 135.18,91.15 135.18,90.26 134.42,89.5 129.97,89.5 129.34,90.14 121.33,90.14 119.84,88.64 119.84,79.73 119.41,79.29 119.41,77.66 120.03,77.03 120.03,72.3 120.41,71.92 120.41,71.31 120.51,71.2 120.51,71.19 120.9,70.8 121.55,70.8 121.62,70.74 121.62,70.31 121.5,70.19 121.5,69.93 121.64,69.8 121.64,66.87 121.15,66.39 ; 18 cut-outs
+VCCGT on L3: 119.33,89.25 119.33,82.69 121.12,80.9 121.12,80.89 121.15,80.86 121.15,78.23 124.76,74.62 126.48,74.62 126.8,74.31 126.8,68.77 126.64,68.62 125.88,68.62 125.75,68.75 125.75,69.43 125.09,70.1 121.79,70.1 121.36,69.67 121.36,67.18 120.96,66.78 119.77,66.78 119.1,66.11 114.69,66.11 113.26,67.54 113.26,71.09 114.04,71.87 114.04,74.62 114.03,74.63 114.04,74.64 114.04,78.56 114.35,78.87 114.35,81.5 113.33,82.52 113.33,82.77 113.35,82.78 113.35,83.55 110.18,86.71 110.18,88.64 111.43,89.88 118.69,89.88
+VCCGT on L3: 129.21,99.03 131.75,99.03 131.98,98.8 133.96,98.8 134.26,98.49 134.26,95.7 133.65,95.09 133.65,93.18 135.18,91.66 135.18,90.22 135.05,90.1 132.34,90.1 132.05,90.39 130.48,90.39 129.59,91.28 129.59,93.18 128.45,94.33 128.45,95.09 128.83,95.47 128.83,98.64
+VCCGT on L5VCC: 114.01,65.84 114.01,67.02 113.17,67.86 113.17,71.16 114.41,72.4 114.41,77.99 114.92,78.5 114.92,82.47 110.98,86.4 110.98,88.3 121.36,98.68 133.9,98.68 134.15,98.44 134.15,96.11 133.34,95.29 133.34,93.36 136.26,90.44 136.26,87.91 125.95,87.91 124.19,86.15 124.19,82.98 122.79,81.58 122.79,77.26 121.02,75.48 121.02,66.85 120.87,66.7 120.24,66.7 119.38,65.84
+VCCGT on L6: 114.73,66.13 120.32,66.13 121.15,66.96 121.15,72.29 121.14,72.29 121.14,82.71 119.81,84.04 119.81,89.15 119.33,89.63 113.21,89.63 112.34,88.76 112.34,84.55 114.35,82.55 114.35,82.52 114.86,82 114.86,78.71 114.22,78.07 114.22,72.1 113.33,71.21 113.33,67.53
+VCCGT on L6: 133.65,95.09 133.65,93.18 135.18,91.66 135.18,90.26 134.54,89.63 134.14,89.63 132.08,91.69 131.24,91.69 128.45,94.48 128.45,95.09 128.83,95.47 128.83,98.64 129.21,99.03 131.77,99.03 132.03,98.77 133.93,98.77 134.24,98.47 134.24,95.67
+VCCIO on TOP: 106.73,59.66 106.35,60.04 105.21,60.04 103.05,62.2 103.05,63.85 99.11,67.78 94.03,67.78 89.84,71.97 89.84,83.79 92.38,86.33 94.41,86.33 94.66,86.07 94.66,82.77 93.01,81.12 93.01,73.88 94.66,72.23 102.16,72.23 104.19,70.2 104.19,69.05 104.7,68.55 106.48,68.55 106.73,68.29 107.87,68.29 108.61,67.56 109.75,67.56 110.92,66.39 111.68,66.39 111.94,66.13 111.94,65.37 112.19,65.12 112.19,63.54 112.37,63.36 112.37,62.83 112.16,62.63 111.68,62.63 111.48,62.83 111.48,63.24 111.25,63.47 110.64,63.47 110.41,63.24 110.41,60.8 109.27,59.66 ; 3 cut-outs
+VCCIO on TOP: 110.59,51.2 110.54,51.25 110.54,52.67 110.41,52.8 110.41,53.81 110.67,54.07 110.67,54.58 110.74,54.65 111.12,54.65 111.45,54.32 111.81,54.32 112.06,54.07 112.06,53.36 112.16,53.26 112.75,53.26 112.85,53.15 112.85,52.67 112.77,52.59 112.37,52.59 112.14,52.37 112.14,52.11 111.81,51.78 111.43,51.78 111.12,51.48 111.12,51.25 111.07,51.2 ; 3 cut-outs
+VCCIO on BOTTOM: 111.3,51.78 111.17,51.91 111.17,52.16 110.79,52.54 109.6,52.54 109.44,52.7 109.44,53.74 109.62,53.92 110.25,53.92 110.91,54.58 111.2,54.58 111.45,54.83 111.45,59.07 111.12,59.41 110.06,59.41 109.42,60.04 109.42,60.17 109.55,60.29 109.93,60.29 110.42,59.81 110.72,59.81 111,60.09 111.76,60.09 111.96,59.88 111.96,54.45 112.06,54.35 112.06,52.04 111.81,51.78
+VCCIO on L4: 111.94,56.99 112.32,56.61 112.32,52.16 111.94,51.78 110.79,51.78 109.78,52.8 109.78,65.62 110.16,66.01 112.06,66.01 112.7,65.37 112.7,60.42 111.94,59.66
+VCCIO on L5VCC: 110.44,51.72 109.66,52.5 109.66,66.1 111.15,67.59 112.9,67.59 113.63,66.87 113.63,65.84 113.03,65.84 112.38,65.2 112.38,62.4 111.75,61.77 111.75,59.73 111.35,59.34 110.97,59.34 110.48,58.85 110.48,56.27 112,54.75 112,53.48 112.28,53.2 112.28,52.14 111.86,51.72
+VCCIO_SIP on TOP: 92.63,86.86 92.58,86.91 92.58,88.18 92.66,88.26 93.32,88.26 93.55,88.48 93.55,89.07 93.62,89.15 93.75,89.15 94.16,89.55 94.16,90.75 94.08,90.82 93.04,90.82 93.01,90.85 93.01,92.55 93.14,92.68 97.46,92.68 98.09,92.04 98.09,88.99 95.96,86.86 ; 1 cut-out
+VCCMPHYGTAON_1P0_LS_SIP on TOP: 119.18,37.96 118.84,38.29 118.84,43.73 119.35,44.24 120.32,44.24 120.42,44.14 120.42,43.68 120.09,43.35 120.09,38.17 119.89,37.96
+VCCMPHYGTAON_1P0_LS_SIP on TOP: 89.76,33.06 89.61,33.21 89.61,34.21 89.84,34.43 91.39,34.43 93.17,36.21 94.26,36.21 94.66,36.62 96.59,36.62 96.98,36.24 96.98,35.53 96.42,34.97 94.44,34.97 92.53,33.06
+VCCMPHYGTAON_1P0_LS_SIP on TOP: 112.95,46.3 112.88,46.37 112.88,47.72 112.72,47.87 112.39,47.87 112.27,48 112.27,48.23 112.39,48.35 112.7,48.35 113.28,47.77 113.51,47.77 113.61,47.67 113.61,46.5 113.41,46.3
+VCCMPHYGTAON_1P0_LS_SIP on TOP: 117.27,45.3 117.14,45.43 117.14,46.45 116.89,46.7 115.75,46.7 115.49,46.96 115.49,47.34 115.62,47.46 115.87,47.46 116.13,47.72 116.13,48.35 116.25,48.48 117.65,48.48 117.78,48.35 117.78,47.97 117.52,47.72 117.52,46.7 117.78,46.45 117.91,46.45 118.03,46.32 118.03,45.94 118.16,45.81 118.67,45.81 118.92,46.07 119.68,46.07 119.81,45.94 119.81,45.43 119.68,45.3 ; 4 cut-outs
+VCCMPHYGTAON_1P0_LS_SIP on BOTTOM: 89.08,23.92 89.05,23.94 88.42,23.94 87.86,24.5 87.86,33.8 88.47,34.41 90.27,34.41 90.6,34.08 90.6,28.59 90.85,28.34 90.85,25.16 90.96,25.06 90.96,24.1 90.78,23.92
+VCCMPHYGTAON_1P0_LS_SIP on BOTTOM: 119.37,43.76 118.86,44.27 118.03,44.27 117.8,44.5 117.8,45.28 117.93,45.41 118.21,45.41 118.77,45.97 118.77,46.3 118.59,46.47 118.59,46.57 118.67,46.65 118.89,46.65 119.24,46.3 119.24,44.5 119.48,44.26 119.58,44.26 119.78,44.07 119.78,43.91 119.62,43.76
+VCCMPHYGTAON_1P0_LS_SIP on BOTTOM: 96.82,15.21 96.54,15.49 96.54,17.8 96.81,18.06 98.99,18.06 99.26,17.8 99.26,15.43 99.03,15.21 ; 2 cut-outs
+VCCMPHYGTAON_1P0_LS_SIP on L3: 112.34,48.33 112.75,48.33 113.46,47.62 115.47,47.62 116.2,48.35 117.65,48.35 117.85,48.15 117.85,47.79 116.36,46.3 112.95,46.3 112.22,47.03 112.22,48.2
+VCCMPHYGTAON_1P0_LS_SIP on L4: 92.35,22.72 93.65,21.43 95.3,21.43 96.57,20.16 96.57,19.52 96.95,19.14 98.6,19.14 99.24,18.51 99.24,16.6 98.6,15.97 93.78,15.97 92.38,17.36 90.85,17.36 88.24,19.98 88.24,26.79 88.72,27.27 91.11,27.27 92.35,26.03
+VCCMPHYGTAON_1P0_LS_SIP on L4: 105.03,47.79 103.43,46.19 103.43,43.88 102.41,42.87 102.41,40.3 96.67,34.56 96.19,34.56 95.76,34.99 95.76,35.48 99.59,39.31 99.59,40 101.09,41.49 101.09,43.15 102.03,44.09 102.03,44.7 101.34,45.38 101.34,47.41 105.84,51.91 110.29,51.91 110.67,51.53 111.68,51.53 112.83,50.38 112.83,48.35 114.48,46.7 116.25,46.7 116.76,47.21 116.76,48.23 117.14,48.61 117.52,48.61 117.78,48.35 117.78,47.72 118.03,47.46 118.79,47.46 119.05,47.21 119.05,45.56 119.81,44.8 119.81,44.06 119.51,43.76 118.95,43.76 118.82,43.88 118.82,44.31 118.64,44.49 116.94,44.49 116,45.43 110.41,45.43 109.78,46.07 109.78,47.29 109.27,47.79
+VCCPAZIO on L6: 106.07,43.4 105.97,43.5 105.97,44.26 106.45,44.75 109.65,44.75 109.8,44.9 110.44,44.9 110.59,44.75 110.59,43.78 110.21,43.4
+VCCPDSW_3P3 on L6: 110.34,42.92 110.51,42.74 110.51,41.95 110.11,41.55 106.22,41.55 106.07,41.7 106.07,42.61 106.37,42.92
+VCCPRIM_CORE on TOP: 96.21,28.11 95.96,28.36 95.96,28.9 96.19,29.13 96.42,29.13 96.7,29.4 96.7,29.66 96.11,30.24 96.11,31.87 96.48,32.24 96.48,32.67 97.43,33.62 97.43,35.58 97.69,35.83 99.13,35.83 99.31,35.65 99.31,33.06 98.12,31.87 98.12,31.49 97.61,30.98 97.61,30.6 98.17,30.04 98.17,28.59 97.69,28.11
+VCCPRIM_CORE on TOP: 94.66,18.63 93.27,20.03 93.27,20.79 93.52,21.05 93.78,21.05 94.05,20.77 95.22,20.77 95.58,20.41 95.58,18.63 ; 2 cut-outs
+VCCPRIM_CORE on BOTTOM: 92.78,16.86 92.07,17.57 92.07,20.26 92.48,20.67 94.66,20.67 95.05,20.29 95.05,16.98 94.92,16.86 ; 2 cut-outs
+VCCPRIM_CORE on L3: 97.94,28.29 97.13,29.1 96.09,29.1 95.86,28.87 95.86,27.22 96.34,26.74 96.34,23.51 96,23.17 96,22.43 95.58,22.01 95.4,22.01 94.61,21.23 93.24,21.23 92.38,20.36 92.38,20.01 92.58,19.8 94.94,19.8 97.15,22.01 97.61,22.01 97.94,22.34
+VCCPRIM_CORE on L4: 113.22,48.49 112.98,48.73 112.98,49.11 112.95,49.14 112.95,49.88 113.08,50 116.25,50 116.38,49.88 116.38,48.73 116.14,48.49
+VCCPRIM_CORE on L5VCC: 92.97,19.21 92.7,19.48 92.7,21.6 93.97,22.87 93.97,28.97 95.62,30.62 95.62,33.67 98.93,36.99 103.63,36.99 105.67,39.02 110.24,39.02 110.6,39.38 110.6,41.83 110.35,42.08 110.35,46.75 113.16,49.56 115.92,49.56 116.19,49.29 116.19,48.18 112.89,44.88 112.89,39.16 110.08,36.35 105.89,36.35 104.11,34.57 99.79,34.57 97.78,32.56 97.78,29.38 95.49,27.1 95.49,23.51 95.62,23.38 95.62,20.24 94.59,19.21
+VCCPRIM_CORE on L6: 114.76,48.38 116.03,48.38 116.2,48.56 116.2,49.17 116.13,49.24 114.35,49.24 114.22,49.37 113.21,49.37 113.08,49.24 113.08,49.19 112.67,48.78 112.39,48.78 111.56,47.95 111.56,45.56 111.43,45.43 111.43,43.68 110.89,43.15 110.89,42.74 110.69,42.54 110.69,41.95 110.41,41.67 110.41,40.22 110.29,40.1 105.59,40.1 105.21,40.48 104.44,40.48 103.17,39.21 103.17,38.7 102.28,37.81 100.28,37.81 97.99,35.53 97.99,35.07 98.22,34.84 104.49,34.84 105.81,36.16 107.75,36.16 108.23,36.64 110.29,36.64 110.84,37.2 110.84,39.89 111.68,40.73 111.68,41.52 112.06,41.9 112.32,41.9 112.95,42.54 112.95,45.3 114.67,47.02 114.67,48.29
+VCCSA on TOP: 128.34,49.32 127.94,49.72 123.92,49.72 123.72,49.93 122.65,49.93 121.97,50.61 121.21,50.61 120.7,50.11 120.22,50.11 120.09,50.23 120.09,50.72 119.86,50.94 118.82,50.94 118.64,50.77 113.21,50.77 112.95,51.02 112.44,51.02 112.06,50.64 112.06,50.26 111.94,50.13 111.43,50.13 111.3,50.26 111.3,51.27 111.56,51.53 111.94,51.53 112.32,51.91 112.32,52.09 112.57,52.34 120.14,52.34 120.34,52.54 120.5,52.54 121.38,53.43 121.72,53.43 122.6,54.32 123.49,54.32 124,54.83 127.81,54.83 130.86,57.88 138.86,57.88 139.37,57.37 139.37,54.32 138.99,53.94 136.22,53.94 135.84,53.56 132.15,53.56 131.57,52.98 131.57,49.52 131.37,49.32 ; 12 cut-outs
+VCCSA on BOTTOM: 131.76,54.27 131.23,54.8 131.23,56.7 132.64,58.11 132.64,59.96 132.76,60.09 137.97,60.09 138.48,59.58 138.48,54.58 138.17,54.27 ; 3 cut-outs
+VCCSA on BOTTOM: 111.2,49.75 111.2,49.75 110.57,49.75 110.44,49.88 110.44,51.15 110.82,51.53 111.55,51.53 111.68,51.4 111.68,49.88 111.56,49.75
+VCCSA on BOTTOM: 120.8,49.47 120.41,49.86 120.32,49.86 119.88,50.3 119.88,53.19 120.53,53.84 121.03,53.84 121.13,53.74 121.13,53.13 121.28,52.99 121.98,52.99 122.08,52.89 122.08,52.89 122.08,52.68 121.89,52.48 121.89,52.15 122.09,51.95 122.09,51.75 121.89,51.56 121.89,51.22 122.08,51.03 122.08,50.85 121.88,50.64 121.88,50.32 122.07,50.14 122.07,49.91 121.8,49.64 121.8,49.57 121.69,49.47
+VCCSA on L6: 112.65,52.42 119.25,52.42 119.51,52.67 120.57,52.67 120.78,52.47 120.78,50.26 120.57,50.05 111.35,50.05 111.2,50.21 111.2,51.32 111.38,51.5 111.99,51.5 112.44,51.96 112.44,52.21
+VDDQ_CPU_CLK on L4: 107.41,60.11 109.32,60.11 109.6,59.83 109.6,59.22 109.4,59.02 106.55,59.02 106.4,59.17 106.4,59.68 106.86,60.14 107.39,60.14
GND on TOP: 64.62,18.69 64.46,18.84 64.46,20.18 64.79,20.51 66.04,20.51 66.09,20.46 66.09,20.08 66.34,19.83 67.05,19.83 67.26,19.63 67.26,19.3 66.65,18.69 ; 3 cut-outs
GND on TOP: 110.54,95.72 110.16,96.1 110.16,101.06 111.05,101.95 119.15,101.95 120.06,101.03 122.22,101.03 123.14,101.95 128.73,101.95 129.06,101.62 129.06,99.89 129.16,99.79 129.16,98.75 128.9,98.49 128.12,98.49 127.94,98.31 127.94,98.01 127.81,97.88 123.21,97.88 122.6,98.49 119.33,98.49 119.18,98.64 111.94,98.64 111.56,98.26 111.56,95.85 111.43,95.72 ; 11 cut-outs
GND on TOP: 43.74,4.03 43.36,4.41 43.36,6.82 43.48,6.95 46.53,6.95 47.29,7.71 48.69,7.71 48.94,7.46 48.94,4.41 48.56,4.03
GND on TOP: 18.24,5.99 18.18,6.04 18.18,6.6 18.29,6.7 18.49,6.7 18.67,6.87 18.67,7.31 18.79,7.43 19.45,7.43 19.76,7.74 19.76,8.2 19.84,8.27 20.32,8.27 20.42,8.17 20.42,7.76 19.1,6.44 19.1,6.32 18.77,5.99 ; 1 cut-out
GND on TOP: 142.54,68.93 142.04,69.43 140.77,69.43 140.64,69.56 140.64,69.94 139.75,70.83 139.75,77.82 140,78.07 144.7,78.07 145.08,77.69 145.08,69.82 144.19,68.93 ; 13 cut-outs
GND on TOP: 116.13,65.75 116,65.88 116,71.34 116.13,71.47 118.54,71.47 118.67,71.34 118.67,66.64 118.54,66.51 117.78,66.51 117.65,66.39 117.65,66.01 117.4,65.75 ; 9 cut-outs
GND on TOP: 26.34,61.31 26.21,61.43 26.21,62.07 26.49,62.35 26.64,62.35 27.13,62.83 28.75,62.83 28.88,62.7 28.88,62.32 28.84,62.28 28.59,62.28 27.9,61.6 27.47,61.6 27.18,61.31 ; 2 cut-outs
GND on TOP: outline of 159 points within 0.51,0.51 204.34,36.36 ; 76 cut-outs
GND on TOP: 120.57,83.53 120.06,84.04 120.06,88.36 120.32,88.61 122.86,88.61 123.49,87.98 123.49,83.91 123.11,83.53
GND on TOP: 109.14,73.24 109.02,73.37 109.02,73.5 108.89,73.63 106.73,73.63 105.71,74.64 105.71,75.78 106.35,76.42 106.35,77.94 106.73,78.32 108.25,78.32 108.63,77.94 108.63,75.91 108.76,75.78 109.27,75.78 109.52,75.53 109.52,73.37 109.4,73.24 ; 5 cut-outs
GND on TOP: 11.61,79.09 11.1,79.59 10.34,79.59 10.01,79.92 10.01,82.43 9.26,83.4 8.13,82.94 1.45,82.94 1.45,88.95 3.96,88.95 4.91,88.45 5.77,89.1 5.9,89.23 5.9,90.91 6.78,91.79 9.83,91.79 10.59,91.02 10.59,90.26 11.23,89.63 16.66,89.63 18.17,91.14 19.47,91.14 21.44,89.17 21.44,88.51 21.03,88.1 20.01,88.1 19.43,87.52 19.43,87.09 19.05,86.71 17.73,86.71 17.37,86.35 17.37,85.28 17.27,85.18 16.18,85.18 16.05,85.31 16.05,85.69 15.8,85.94 14.53,85.94 12.88,84.29 12.88,83.15 13.51,82.52 16.81,82.52 16.94,82.39 16.94,79.21 16.81,79.09 ; 1 cut-out
GND on TOP: 68.63,92.29 68.5,92.42 68.5,96.61 68.63,96.74 70.03,96.74 70.41,97.12 70.41,98.77 71.42,98.77 71.55,98.9 72.06,98.9 72.31,98.64 72.31,98.01 72.82,97.5 72.82,94.96 72.31,94.45 69.52,94.45 69.26,94.2 69.26,93.56 69.39,93.44 69.39,92.42 69.26,92.29 ; 3 cut-outs
GND on TOP: 90.6,25.11 89.84,25.87 89.84,28.67 89.97,28.79 90.98,28.79 91.11,28.67 91.11,25.24 90.98,25.11 ; 5 cut-outs
GND on TOP: 136.83,48.48 136.45,48.86 136.45,53.23 136.65,53.43 138.73,53.43 139.11,53.05 139.11,48.99 138.61,48.48 ; 3 cut-outs
GND on TOP: 112.32,53.81 112.19,53.94 112.19,54.19 111.91,54.47 111.5,54.47 111.35,54.63 111.35,55.36 111.47,55.48 112.2,55.48 112.7,55.97 112.7,56.4 112.77,56.48 119.99,56.48 120.06,56.4 120.06,55.64 120.37,55.34 120.88,55.34 121.13,55.59 121.13,55.82 121.23,55.92 121.77,55.92 121.84,55.85 121.84,55.36 121.69,55.21 121.23,55.21 120.95,54.93 120.95,54.58 120.32,54.58 120.19,54.45 120.19,53.94 120.06,53.81 ; 14 cut-outs
GND on TOP: 142.72,43.86 142.54,44.03 141.68,44.03 141.03,44.68 141.01,44.68 140.51,45.18 140.51,45.69 141.02,46.19 143.81,46.19 143.94,46.07 143.94,43.91 143.89,43.86 ; 2 cut-outs
GND on TOP: 148.74,16.25 148.64,16.35 148.64,16.81 148.8,16.97 149.03,16.97 149.2,17.14 149.2,17.52 149.29,17.61 149.97,17.61 150.44,17.14 150.44,16.55 150.14,16.25 ; 1 cut-out
GND on TOP: 170.1,25.24 169.21,26.13 169.21,28.79 170.48,30.06 171.37,30.06 172.52,28.92 172.52,26.51 171.25,25.24
GND on TOP: outline of 123 points within 1.45,51.15 181.57,113.41 ; 6 cut-outs
GND on TOP: 46.91,21.68 46.79,21.81 46.79,22.83 48.18,24.22 50.34,24.22 50.54,24.43 53.8,24.43 53.92,24.3 53.92,23.89 53.85,23.82 53.52,23.82 53.39,23.69 53.39,23.21 53.01,22.83 53.01,22.32 52.75,22.06 49.45,22.06 49.07,21.68 ; 8 cut-outs
GND on TOP: 118.21,43.81 118.11,43.91 118.11,44.19 118.21,44.29 118.64,44.29 118.87,44.52 118.87,44.95 118.97,45.05 121.11,45.05 121.23,44.92 121.23,44.49 121.13,44.39 119.33,44.39 118.74,43.81
GND on TOP: 113.41,60.93 113.33,61 113.33,63.34 113.46,63.47 118.03,63.47 118.16,63.34 118.16,61.05 118.03,60.93 ; 6 cut-outs
GND on TOP: outline of 168 points within 0.51,21.45 27.61,70.96 ; 17 cut-outs
GND on TOP: 136.62,58.23 136.45,58.41 136.45,63.59 136.57,63.72 140.38,63.72 140.51,63.59 140.51,62.83 140.77,62.58 144.47,62.58 144.85,62.2 144.85,61.59 143.94,60.67 141.37,60.67 138.94,58.23 ; 10 cut-outs
GND on TOP: 112.56,35.11 112.47,35.2 112.47,35.58 112.95,36.06 112.95,36.54 113.13,36.72 114.68,36.72 114.88,36.52 114.88,36.08 113.9,35.11 ; 1 cut-out
GND on TOP: 76.63,58.77 76,59.4 76,60.29 76.38,60.67 84.25,60.67 84.5,60.42 84.5,59.66 83.62,58.77 ; 15 cut-outs
GND on TOP: 199.95,23.33 199.44,23.84 199.44,24.6 200.07,24.6 200.33,24.35 200.33,23.46 200.2,23.33 ; 1 cut-out
GND on TOP: 59.51,92.32 59.23,92.6 59.23,93.41 58.88,93.77 58.88,94.28 59.76,95.17 59.76,99.15 60.13,99.52 64.57,99.52 64.58,99.53 65.96,99.53 66.09,99.41 66.09,94.86 65.43,94.2 65.43,93.74 65.25,93.56 63.42,93.56 63.41,93.58 62.95,93.58 62.81,93.72 62.81,94.23 62.58,94.45 61.47,94.45 61.24,94.23 61.24,92.85 60.7,92.32 ; 4 cut-outs
GND on TOP: 102.08,104.74 101.83,104.99 101.83,105.68 101.75,105.76 100.3,105.76 100.23,105.68 100.23,105.35 100.2,105.33 99.13,105.33 99.11,105.35 99.11,105.68 99.03,105.76 97.51,105.76 97.13,105.38 95.73,105.38 95.22,105.88 92.17,105.88 91.37,105.08 89.93,105.08 89.89,105.12 89.46,105.12 89.08,105.5 89.08,108.42 89.33,108.68 89.97,108.68 90.09,108.55 90.09,108.17 91.24,107.03 96.49,107.03 97,106.52 98.78,106.52 98.86,106.44 100.18,106.44 100.2,106.42 100.2,106.16 100.35,106.01 102.13,106.01 102.31,105.83 102.31,105.12 102.39,105.05 102.39,104.87 102.26,104.74 ; 9 cut-outs
GND on TOP: 100,98.01 100,100.4 100.1,100.5 102.69,100.5 102.82,100.37 102.82,99.89 102.46,99.53 101.4,99.53 101.09,99.23 101.09,98.14 100.96,98.01
GND on TOP: 26.16,82.64 25.96,82.85 25.96,83.76 25.7,84.01 25.7,88.26 26.21,88.76 26.72,88.76 26.97,88.51 26.97,83.46 26.72,83.2 26.72,82.8 26.57,82.64 ; 9 cut-outs
GND on TOP: 176.91,21.66 175.87,22.7 175.87,23 176.08,23.22 178.47,23.22 179.37,22.32 179.37,21.66 ; 2 cut-outs
GND on TOP: outline of 92 points within 50.85,66.89 94,95.75 ; 48 cut-outs
GND on TOP: 106.58,99.58 106.45,99.71 106.45,100.17 106.58,100.3 106.58,101.34 106.17,101.74 103.78,101.74 103.07,101.03 102.11,101.03 101.98,101.16 101.98,101.79 102.18,102 103.07,102 103.38,102.3 106.68,102.3 107.36,101.62 107.36,99.71 107.24,99.58
GND on TOP: 112.39,63.57 112.32,63.64 112.32,64.61 112.44,64.74 112.44,65.24 112.19,65.5 112.19,66.13 111.56,66.77 110.92,66.77 110.29,67.4 110.29,69.05 109.9,69.43 109.14,69.43 109.02,69.56 109.02,69.82 109.27,70.07 109.4,70.07 109.65,70.32 109.65,70.96 109.78,71.09 110.92,71.09 111.3,71.47 112.32,71.47 112.44,71.34 112.44,66.89 112.95,66.39 113.71,66.39 113.84,66.26 113.84,65.88 113.21,65.24 113.21,64.86 113.08,64.74 113.08,63.59 113.05,63.57 ; 5 cut-outs
GND on TOP: 116.05,44.54 115.85,44.75 115.85,45.43 115.7,45.58 114.6,45.58 114.43,45.41 112.09,45.41 112.01,45.48 112.01,46.73 112.14,46.85 112.62,46.85 112.7,46.78 112.7,46.17 112.8,46.07 113.56,46.07 113.76,46.27 113.76,47.82 113.59,48 113.16,48 112.27,48.89 112.27,49.95 112.3,49.99 112.3,50.63 112.44,50.77 112.83,50.77 113,50.59 118.67,50.59 118.9,50.82 119.81,50.82 119.94,50.69 119.94,50 119.78,49.85 119.07,49.85 118.98,49.76 118.98,48.34 119.61,47.72 119.61,47.36 119.91,47.06 120.37,47.06 120.5,47.18 121,47.18 121.08,47.11 121.08,46.75 121.84,45.99 121.84,45.61 121.77,45.53 121.44,45.53 121.33,45.64 121.33,45.79 121.04,46.08 120.69,46.08 120.19,46.57 117.91,46.57 117.65,46.83 117.65,47.59 117.78,47.72 118.69,47.72 118.81,47.83 118.81,48.19 118.36,48.63 116.58,48.63 116.33,48.89 116.33,49.24 116.1,49.47 115.82,49.47 115.67,49.32 115.67,48.76 115.92,48.51 115.92,47.84 115.72,47.64 115.49,47.64 115.31,47.46 115.31,46.85 115.75,46.42 116.81,46.42 116.89,46.35 116.89,44.72 116.71,44.54 ; 23 cut-outs
GND on TOP: 44.12,18.13 44.02,18.23 44.02,18.53 43.84,18.71 42.49,18.71 42.24,18.46 36.32,18.46 35.91,18.86 35.91,19.35 36.07,19.5 36.35,19.5 36.45,19.4 37.11,19.4 37.39,19.68 37.39,20.92 39.04,22.57 46.28,22.57 46.4,22.44 46.4,18.89 45.9,18.38 44.75,18.38 44.5,18.13 ; 8 cut-outs
GND on TOP: outline of 146 points within 56.69,20.79 94.28,56.35 ; 63 cut-outs
GND on TOP: 119.7,73.23 119.56,73.37 119.56,74.77 119.71,74.92 119.71,75.66 119.56,75.81 119.56,76.8 119.7,76.94 120.31,76.94 120.45,77.08 121.69,77.08 121.94,76.83 122.99,76.83 123.72,76.09 123.72,75.76 123.54,75.58 122.83,75.58 122.65,75.76 122.27,75.76 121.97,75.45 121.97,74.72 121.77,74.51 121.61,74.51 121.18,74.95 120.62,74.95 120.5,74.82 120.5,74.06 120.65,73.91 121.08,73.91 121.18,73.8 121.18,73.27 121.14,73.23 ; 8 cut-outs
GND on TOP: 161.26,55.74 161.14,55.87 161.14,57.34 160.5,57.98 160.5,60.04 160.81,60.34 160.81,61.15 160.72,61.24 160.72,62.13 160.96,62.37 161.49,62.37 161.57,62.3 161.57,58.26 162.25,57.57 162.25,55.85 162.15,55.74 ; 1 cut-out
GND on TOP: 27.35,46.57 27.1,46.83 27.1,47.34 26.47,47.97 26.47,48.48 26.59,48.61 28.12,48.61 28.62,48.1 28.62,47.59 28.5,47.46 28.12,47.46 27.86,47.21 27.86,46.7 27.74,46.57 ; 2 cut-outs
GND on TOP: 117.68,35.65 117.24,36.08 116.86,36.08 116.76,36.19 116.76,36.57 117.32,37.13 117.32,38.47 117.12,38.68 117.12,39.44 117.22,39.54 118.03,39.54 118.31,39.26 118.31,38.62 118.63,38.31 118.63,36.96 118.51,36.85 118.51,35.81 118.36,35.65 ; 2 cut-outs
GND on TOP: 123.09,35.37 123.01,35.45 123.01,36.39 122.6,36.8 121.44,36.8 121.33,36.9 121.33,37.68 121.44,37.79 122.3,37.79 122.78,38.27 123.24,38.27 123.32,38.19 123.32,36.97 123.8,36.49 123.8,35.5 123.67,35.37 ; 1 cut-out
GND on TOP: 109.9,45.05 109.65,45.3 109.65,48.1 109.78,48.23 110.54,48.23 110.67,48.35 110.92,48.35 111.05,48.23 111.05,47.84 110.67,47.46 110.67,45.18 110.54,45.05 ; 1 cut-out
GND on TOP: 139.88,84.93 139.75,85.06 139.75,87.6 139.88,87.72 141.53,87.72 142.29,86.96 144.52,86.96 145.08,86.4 145.08,85.23 144.78,84.93
GND on TOP: 140.71,32.5 140.66,32.55 140.66,34.41 140.88,34.62 141.9,34.62 142.16,34.89 142.54,34.89 142.67,35.02 142.67,36.67 142.8,36.8 143.31,36.8 143.43,36.92 143.43,37.3 143.56,37.43 144.58,37.43 144.73,37.28 144.73,36.19 145.08,35.83 145.08,34.71 144.96,34.59 144.96,34.08 144.83,33.95 144.24,33.95 143.79,33.49 143.18,33.49 143.05,33.37 143.05,32.86 142.95,32.76 141.81,32.76 141.55,32.5 ; 9 cut-outs
GND on TOP: 109.74,49.6 109.69,49.65 109.69,49.8 109.08,50.41 109.08,51.22 109,51.3 109,52.44 108.37,53.08 108.37,54.79 108.35,54.8 108.35,56.3 108.13,56.53 107.77,56.53 107.67,56.63 107.67,58.67 108,59 108.81,59 108.94,58.87 108.94,58.61 109.24,58.31 109.57,58.31 109.75,58.49 109.75,58.59 109.88,58.72 110.77,58.72 110.77,58 110.69,57.93 110.51,57.93 110.26,57.67 110.26,57.24 110.16,57.14 109.73,57.14 109.55,57.32 109.14,57.32 108.96,57.14 108.96,56.68 109.04,56.61 109.04,56.53 109.09,56.48 109.47,56.48 109.52,56.43 109.52,55.97 109.02,55.46 109.02,54.91 109,54.89 109.13,54.75 110.25,54.75 110.42,54.58 110.42,54.14 110.27,53.99 110.27,49.67 110.2,49.6 ; 8 cut-outs
GND on TOP: 175.13,42.87 174.95,43.04 174.95,43.58 175.8,44.43 175.8,45.19 175.84,45.23 176.71,45.23 177.01,44.92 177.62,44.92 177.65,44.9 177.65,44.44 177.57,44.37 177.57,43.32 176.73,43.32 176.6,43.2 176.6,42.87 ; 2 cut-outs
GND on TOP: 95.83,18.63 95.83,20.46 96.06,20.69 97.66,20.69 98.45,19.9 98.45,19.02 98.07,18.63 ; 2 cut-outs
GND on BOTTOM: 190.73,30.65 190.63,30.75 190.63,31.26 190.98,31.61 191.64,31.61 191.72,31.54 191.72,31.18 191.62,31.08 191.26,31.08 191.16,30.98 191.16,30.75 191.06,30.65
GND on BOTTOM: outline of 115 points within 0.51,21.45 25.2,69.05 ; 15 cut-outs
GND on BOTTOM: 169.47,25.62 169.21,25.87 169.21,31.08 169.9,31.77 172.49,31.77 172.64,31.61 172.64,30.24 173.85,30.24 174.1,29.99 174.1,25.94 173.79,25.62 ; 2 cut-outs
GND on BOTTOM: 156.18,86.07 156.11,86.15 156.11,86.53 156.23,86.66 156.56,86.66 156.72,86.81 156.72,87.11 156.82,87.21 158.29,87.21 159.05,87.98 163.24,87.98 164.64,89.37 164.64,89.88 164.9,90.14 167.05,90.14 167.44,89.75 167.44,88.36 167.56,88.23 167.56,86.2 167.44,86.07 ; 3 cut-outs
GND on BOTTOM: 158.75,44.16 158.21,44.7 158.21,47.01 158.67,47.46 165.28,47.46 165.4,47.34 165.4,46.19 165.15,45.94 162.48,45.94 162.1,45.56 162.1,44.42 161.85,44.16 ; 15 cut-outs
GND on BOTTOM: 44.75,11.4 44.63,11.52 44.63,13.43 44.75,13.55 45.26,13.55 45.39,13.68 45.39,14.32 45.52,14.44 46.91,14.44 47.04,14.32 47.04,13.05 47.67,12.41 49.33,12.41 49.33,11.65 47.29,11.65 47.04,11.4 ; 4 cut-outs
GND on BOTTOM: 100.51,79.09 97.08,82.52 93.14,82.52 92,83.66 92,88.74 94.16,90.9 97.46,90.9 97.71,90.64 106.35,90.64 107.24,91.53 108.63,91.53 108.76,91.41 108.76,89.12 109.14,88.74 109.14,88.23 108.38,87.47 108.38,83.53 108.19,83.34 108.19,82.58 104.7,79.09 ; 1 cut-out
GND on BOTTOM: 100.1,23.56 100,23.66 98.8,23.66 98.68,23.79 98.68,24.32 98.83,24.48 100.58,24.48 100.73,24.32 100.73,23.74 100.56,23.56 ; 1 cut-out
GND on BOTTOM: 176.07,21.81 175.94,21.94 175.94,22.65 177.01,23.71 178.76,23.71 178.87,23.61 178.87,21.94 177.57,21.94 177.44,21.81
GND on BOTTOM: 121.74,39.82 121.69,39.87 121.69,40.1 121.92,40.33 121.92,40.58 122.38,41.04 122.58,41.04 123.39,40.22 123.39,39.95 123.33,39.88 122.97,39.88 122.65,40.2 122.48,40.2 122.1,39.82
GND on BOTTOM: 123.01,53.86 121.99,54.88 121.36,54.88 121.28,54.96 121.28,55.19 121.36,55.26 122.15,55.26 122.43,55.54 122.43,56.38 122.12,56.68 121.38,56.68 121.26,56.81 121.26,56.99 121.33,57.07 121.99,57.07 122.43,57.5 122.43,58.11 122.02,58.51 121.36,58.51 121.28,58.59 121.28,58.82 121.33,58.87 122.02,58.87 122.48,59.33 122.58,59.33 122.91,59 123.47,59 123.7,59.22 125.02,59.22 125.55,58.69 125.55,58.03 125.45,57.93 123.44,57.93 122.86,57.34 122.86,54.63 123.06,54.42 123.98,54.42 124.13,54.58 125.04,54.58 125.22,54.4 125.22,54.09 124.99,53.86
GND on BOTTOM: 187.13,17.17 184.2,20.11 184.2,22.57 184.58,22.95 184.58,23.47 186.61,25.51 190.08,25.51 192.71,22.88 192.71,18.89 192.96,18.63 192.96,18.18 191.96,17.17
GND on BOTTOM: 153.69,24.1 153.41,24.38 153.41,25.62 152.96,26.08 152.96,28.92 153.21,29.18 153.21,30.19 152.45,30.95 152.07,30.95 151.43,31.59 151.43,32.35 151.81,32.73 151.81,33.11 151.94,33.24 152.96,33.24 153.08,33.11 153.08,31.46 153.47,31.08 153.47,30.57 153.85,30.19 154.86,30.19 154.86,29.05 154.61,28.79 154.1,28.79 153.57,28.26 153.57,28.01 153.59,27.98 153.59,26.28 154.33,25.54 154.79,25.54 154.96,25.37 154.96,24.45 154.61,24.1
GND on BOTTOM: 95.25,93.31 94.82,93.74 94.82,95.24 94.89,95.32 99.64,95.32 99.64,94.45 99.92,94.17 99.92,93.67 99.57,93.31
GND on BOTTOM: 123.85,41.57 123.7,41.72 123.7,41.95 122.35,43.3 122.35,43.63 123.01,44.29 123.01,44.59 123.09,44.67 123.29,44.67 123.59,44.37 123.59,44.14 123.49,44.03 123.26,44.03 122.96,43.73 122.96,43.5 123.19,43.27 123.19,43.02 123.52,42.69 123.95,42.69 124.51,42.13 124.97,42.13 125.07,42.03 125.07,41.65 124.99,41.57
GND on BOTTOM: 37.26,45.81 36.05,47.02 29.96,47.02 27.61,49.37 26.72,49.37 25.07,51.02 25.07,54.45 24.28,55.24 23.42,55.24 23.19,55.46 23.19,57.42 23.42,57.65 24.38,57.65 24.66,57.37 24.66,56.43 24.74,56.35 25.2,56.35 25.96,55.59 26.62,55.59 27,55.21 27,54.27 28.52,52.75 31.47,52.75 33.32,50.89 42.85,50.89 43.36,51.4 43.36,53.05 43.1,53.31 39.17,53.31 35.74,56.73 33.83,56.73 32.18,58.39 32.18,60.93 30.28,62.83 28.83,62.83 28.34,62.35 27.15,62.35 25.65,63.85 24.2,63.85 24.08,63.72 21.77,63.72 21.64,63.85 21.64,67.78 21.77,67.91 25.7,67.91 26.34,68.55 26.34,70.32 24.81,71.85 23.21,71.85 23.16,71.9 23.16,72.66 23.24,72.74 24.69,72.74 25.31,73.36 27.75,73.36 28.62,72.48 40.69,72.48 44.63,68.55 44.63,65.5 46.4,63.72 46.4,52.04 40.18,45.81 ; 7 cut-outs
GND on BOTTOM: 104.54,48.81 104.16,49.19 104.16,49.29 104.29,49.42 104.44,49.42 104.7,49.17 105.13,49.17 105.41,49.45 105.41,51.81 105.54,51.93 105.66,51.93 105.76,51.83 105.76,51.27 106.32,50.72 106.63,50.72 107.08,50.26 108.71,50.26 109.27,50.82 109.27,51.1 109.09,51.27 109.09,51.53 109.75,52.19 109.75,52.42 109.78,52.44 110.46,52.44 110.84,52.06 110.84,51.83 110.26,51.25 110.26,50.28 109.9,49.93 109.88,49.93 109.8,49.85 106.88,49.85 106.6,50.13 106.6,50.16 106.53,50.23 106.25,50.23 105.76,49.75 105.76,49.11 105.46,48.81
GND on BOTTOM: 172.39,78.07 172.01,78.45 172.01,80.1 172.52,80.61 177.04,80.61 177.14,80.51 177.14,78.17 177.04,78.07
GND on BOTTOM: 48.06,4.92 46.4,6.57 44.91,6.57 44.75,6.42 44.75,6.21 44.73,6.19 43.76,6.19 43.74,6.21 43.74,6.34 43.51,6.57 42.26,6.57 42.24,6.6 42.24,6.8 42.26,6.82 43.61,6.82 43.71,6.93 43.71,7.15 43.76,7.2 44.85,7.2 44.93,7.28 46.86,7.28 47.04,7.46 47.04,7.97 47.17,8.09 49.2,8.09 49.55,7.74 49.55,5.27 49.2,4.92 ; 1 cut-out
GND on BOTTOM: 132.64,34.51 132.38,34.76 132.38,35.27 132.51,35.4 133.15,35.4 133.53,35.02 136.24,35.02 136.45,35.22 136.45,39.16 135.91,39.69 132.74,39.69 132.38,39.34 132.38,38.68 132.28,38.57 131.75,38.57 131.62,38.7 131.62,39.46 132.51,40.35 136.07,40.35 136.78,39.64 136.78,34.71 136.57,34.51 ; 1 cut-out
GND on BOTTOM: 147.88,90.67 147.47,91.08 147.47,92.07 147.24,92.29 146.35,92.29 144.4,94.25 143.56,94.25 143.56,94.45 145.46,94.45 145.62,94.3 146.05,94.3 146.25,94.1 146.25,94.02 146.56,93.72 148.72,93.72 149.27,93.16 149.27,90.85 149.1,90.67 ; 2 cut-outs
GND on BOTTOM: 155.62,50.77 154.74,51.65 154.74,52.54 154.99,52.8 155.37,52.8 156.01,53.43 157.02,53.43 157.15,53.31 157.15,50.89 157.02,50.77 ; 5 cut-outs
GND on BOTTOM: outline of 270 points within 0.51,0.51 204.34,113.41 ; 10 cut-outs
GND on BOTTOM: 152.2,80.99 152.07,81.12 152.07,86.33 152.2,86.45 154.48,86.45 154.61,86.33 154.61,81.12 154.48,80.99
GND on BOTTOM: 139.47,44.03 138.61,44.9 137.62,44.9 137.59,44.92 137.59,45.94 137.84,46.19 138.94,46.19 139.42,45.71 140.92,45.71 141.31,46.11 143.47,46.11 143.56,46.02 143.56,44.54 143.05,44.03 ; 3 cut-outs
GND on BOTTOM: 177.09,11.65 176.96,11.78 176.96,12.54 177.6,13.17 177.6,14.7 179.04,14.7 179.04,13.38 179.25,13.17 181.28,13.17 181.56,13.45 181.56,14.65 181.61,14.7 183.03,14.7 183.06,14.67 183.06,13.35 181.35,11.65
GND on BOTTOM: 156.56,31.59 156.28,31.87 156.28,39.23 156.64,39.59 157.33,39.59 157.81,40.07 157.81,41.19 159.97,43.35 163.96,43.35 166.34,40.96 166.34,37.35 164.01,35.02 160.88,35.02 159.79,33.93 159.79,32.58 158.8,31.59 ; 3 cut-outs
GND on BOTTOM: 106.73,99.28 106.09,99.91 106.09,101.95 106.22,102.07 107.24,102.07 107.36,101.95 107.36,100.8 107.72,100.45 112.67,100.45 112.95,100.17 112.95,99.79 112.44,99.28 ; 4 cut-outs
GND on BOTTOM: 147.24,1.74 147.13,1.86 147.13,2.34 146.92,2.54 145.22,2.54 145.18,2.58 145.18,3.42 145.21,3.45 147.29,3.45 147.37,3.52 148.39,3.52 148.51,3.65 153.21,3.65 153.38,3.48 153.38,2.09 153.03,1.74 ; 2 cut-outs
GND on BOTTOM: 108.2,46.24 107.62,46.83 107.62,47.36 107.69,47.44 108.38,47.44 108.48,47.34 108.48,47.16 108.35,47.03 108.35,46.65 108.53,46.47 108.53,46.32 108.46,46.24
GND on BOTTOM: 149.88,14.55 149.77,14.66 149.77,15.14 149.45,15.46 149.45,16.76 149.2,17.01 149.2,17.7 149.81,18.3 151.23,18.3 151.66,17.87 151.66,17.49 152.07,17.09 152.83,17.09 153.13,16.78 153.13,16.22 153.08,16.17 151.97,16.17 151.86,16.27 151.86,16.58 151.33,17.11 150.21,17.11 149.99,16.88 149.99,15.38 150.11,15.26 151.15,15.26 151.15,14.67 151.03,14.55
GND on BOTTOM: 31.39,1.59 30.81,2.18 30.81,7.97 31.95,9.11 33.32,9.11 33.58,8.86 33.58,1.85 33.32,1.59 ; 8 cut-outs
GND on BOTTOM: 95.27,16.88 95.17,16.98 95.17,20.03 95.43,20.29 98.19,20.29 98.47,20.01 98.47,18.74 98.14,18.41 96.9,18.41 96.37,17.87 96.37,16.98 96.26,16.88 ; 4 cut-outs
GND on BOTTOM: 132.76,60.42 132.64,60.54 132.64,61.31 132.51,61.43 132.48,61.43 132.23,61.69 132.23,62.65 132.26,62.68 136.47,62.68 136.57,62.58 143.94,62.58 144.14,62.37 144.14,61.51 144.32,61.33 144.32,60.93 144.07,60.67 140.89,60.67 140.64,60.93 140.64,61.56 140.38,61.81 138.73,61.81 138.48,61.56 138.48,60.67 138.23,60.42 ; 13 cut-outs
GND on BOTTOM: 111.07,47.54 110.39,48.23 109.98,48.23 109.8,48.05 109.57,48.05 109.52,48.1 109.52,48.3 109.95,48.73 109.95,49.17 110.08,49.29 110.64,49.29 110.79,49.14 110.79,48.53 111.38,47.95 111.38,47.72 111.2,47.54
GND on BOTTOM: 148.08,95.24 147.88,95.44 147.88,100.93 146.99,101.82 146.99,104.49 147.24,104.74 149.78,104.74 149.91,104.61 149.91,103.34 150.1,103.15 150.25,103.15 150.47,102.94 150.47,101.74 150.16,101.44 150.16,101.01 149.99,100.83 149.99,100.47 150.16,100.3 150.16,95.57 149.83,95.24 ; 1 cut-out
GND on BOTTOM: 100.25,20.16 100.13,20.29 100.13,21.45 100.28,21.61 100.61,21.61 100.81,21.81 101.4,21.81 101.52,21.68 101.52,20.29 101.4,20.16
GND on BOTTOM: 24.84,14.7 24.69,14.85 23.98,14.85 23.7,15.13 22.55,15.13 22.21,14.79 21.68,14.79 21.59,14.88 21.59,18.53 22.35,19.3 24.08,19.3 24.1,19.27 24.1,18.79 24.38,18.51 25.04,18.51 26.21,17.34 26.21,16.12 25.58,15.49 25.58,14.8 25.47,14.7 ; 11 cut-outs
GND on BOTTOM: 148.21,54.5 148.21,57.29 148.54,57.62 149.15,57.62 149.78,58.26 149.78,58.64 150.04,58.89 154.35,58.89 154.48,58.77 154.48,57.93 154.81,57.6 155.34,57.6 155.73,57.98 155.93,57.98 156.39,58.44 156.39,61.26 156.44,61.31 157.22,61.31 157.4,61.13 157.4,57.75 157.28,57.62 156.51,57.62 156.34,57.45 156.34,57.04 155.83,56.53 154.56,56.53 154.1,56.99 150.44,56.99 149.78,56.33 149.78,54.83 149.45,54.5 ; 4 cut-outs
GND on BOTTOM: 40.56,85.69 40.44,85.82 40.44,86.58 39.93,87.09 39.93,87.72 40.05,87.85 40.44,87.85 40.56,87.98 40.56,88.48 40.44,88.61 40.05,88.61 39.93,88.74 39.93,89.12 41.11,90.3 44.21,90.3 44.42,90.52 47.22,90.52 48.08,89.65 48.08,88.23 47.95,88.1 46.15,88.1 45.52,87.47 45.52,85.94 45.26,85.69
GND on BOTTOM: 131.29,48.23 130.05,49.47 130.05,50.21 130.27,50.44 130.5,50.44 130.68,50.26 130.68,49.95 130.78,49.85 131.29,49.85 131.34,49.8 131.34,49.09 131.7,48.73 135.48,48.73 135.56,48.81 135.56,52.87 135.51,52.92 132.31,52.92 132.23,52.85 132.23,52.52 132.15,52.44 131.72,52.44 131.65,52.52 131.65,53.43 131.37,53.71 129.97,53.71 129.86,53.83 129.83,53.83 129.72,53.94 129.72,54.17 129.82,54.27 130.27,54.27 130.4,54.14 131.67,54.14 132.26,53.56 135.56,53.56 135.94,53.18 135.94,48.48 135.69,48.23 ; 1 cut-out
GND on BOTTOM: 140.79,92.17 140.77,92.19 140.77,94.12 140.64,94.25 140.64,99.66 140.13,100.17 138.23,100.17 137.97,100.42 137.97,101.57 138.1,101.69 138.1,103.6 138.23,103.72 138.23,106.01 138.48,106.26 140.13,106.26 140.51,105.88 140.51,101.44 140.89,101.06 141.78,101.06 142.8,100.04 142.8,98.01 143.31,97.5 143.31,92.29 143.18,92.17 ; 8 cut-outs
GND on BOTTOM: 39.55,18.76 39.24,19.07 39.24,21.89 39.67,22.32 45.49,22.32 45.74,22.06 45.74,19.22 45.29,18.76
GND on BOTTOM: 151.53,7.15 151.38,7.31 149.78,7.31 149.77,7.32 149.62,7.32 149.53,7.41 149.53,8.2 150.01,8.68 152.45,8.68 153.13,7.99 153.16,7.99 153.26,7.89 153.57,7.89 153.74,7.71 153.74,7.28 153.62,7.15
GND on BOTTOM: 141.91,33.37 141.78,33.49 141.78,35.91 141.91,36.03 144.32,36.03 144.58,35.78 144.58,33.49 144.45,33.37
GND on BOTTOM: 141.63,89.22 141.55,89.3 141.55,89.86 141.27,90.14 141.27,90.36 141.43,90.52 141.7,90.52 142.09,90.14 142.09,89.32 141.98,89.22
GND on BOTTOM: 151.94,64.86 151.81,64.99 151.81,65.9 151.92,66.01 152.35,66.01 152.5,66.16 152.5,66.77 152.4,66.87 151.79,66.87 151.69,66.97 151.69,72.23 151.18,72.74 151.18,73.75 151.19,73.77 151.19,75.14 151.43,75.38 154.15,75.38 154.3,75.23 154.3,74.18 154.74,73.75 157.15,73.75 157.53,74.13 157.53,75.53 158.67,76.67 158.67,82.03 158.82,82.19 162.23,82.19 162.48,81.93 162.48,78.71 163.37,77.82 163.37,70.7 163.24,70.58 154.53,70.58 154.35,70.4 154.35,64.99 154.23,64.86 ; 11 cut-outs
GND on BOTTOM: 152.8,52.95 152.7,53.05 152.7,55.36 152.88,55.54 153.49,55.54 153.67,55.36 153.67,53.05 153.57,52.95
GND on BOTTOM: 130.99,3.27 130.73,3.52 130.73,8.98 133.02,11.27 133.91,11.27 134.03,11.14 134.03,8.98 133.15,8.09 133.15,3.65 132.76,3.27 ; 2 cut-outs
GND on BOTTOM: 137.11,84.8 137.01,84.9 137.01,87.27 137.34,87.6 141.53,87.6 142.42,86.71 144.83,86.71 144.96,86.58 144.96,85.18 144.58,84.8
GND on BOTTOM: 163.93,56.89 163.78,57.04 163.78,57.8 164.11,58.13 164.59,58.13 164.79,58.34 164.79,58.67 164.95,58.82 165.33,58.82 165.53,58.61 165.53,57.04 165.38,56.89
GND on BOTTOM: 113.33,72.38 113.21,72.51 113.21,75.76 113.31,75.86 113.79,75.86 113.97,75.68 113.97,72.66 113.69,72.38
GND on BOTTOM: 114.89,38.15 114.89,38.16 114.89,38.9 114.93,38.94 114.93,39.56 115.03,39.67 115.03,39.89 114.58,40.35 114.58,40.45 115.42,41.29 115.77,41.29 115.97,41.09 115.97,40.93 115.57,40.53 115.57,39.66 116,39.23 116,38.92 115.3,38.22 115.3,38.15
GND on BOTTOM: 76.88,58.64 76.63,58.89 76.63,91.66 77.01,92.04 80.19,92.04 83.49,88.74 83.49,58.77 83.36,58.64
GND on BOTTOM: 185.6,27.22 185.47,27.35 185.47,28.29 185.9,28.72 186.76,28.72 186.87,28.62 186.87,28.16 186.74,28.03 186.15,28.03 186,27.88 186,27.4 185.82,27.22
GND on BOTTOM: 161.09,55.74 160.96,55.87 160.96,56.4 160.98,56.43 160.98,57.88 160.96,57.9 160.58,57.9 160.55,57.93 160.55,60.52 160.75,60.72 160.75,62.53 160.81,62.58 161.29,62.58 161.36,62.5 161.36,61.94 161.62,61.69 161.62,61.33 161.34,61.05 161.34,60.67 161.24,60.57 161.24,59.17 161.39,59.02 161.59,59.02 161.64,58.97 161.64,57.93 161.59,57.88 161.39,57.88 161.24,57.73 161.24,56.3 161.31,56.23 162.02,56.23 162.15,56.1 162.15,55.87 162.02,55.74
GND on BOTTOM: 163.93,62.2 163.83,62.3 163.83,62.5 163.68,62.65 162.18,62.65 162.1,62.73 162.1,64.48 161.97,64.61 159.43,64.61 159.18,64.86 159.18,66.01 159.31,66.13 164.39,66.13 164.69,65.83 164.69,63.42 165.28,62.83 165.28,62.32 165.15,62.2 ; 6 cut-outs
GND on BOTTOM: 123.87,95.47 123.37,95.98 123.37,98.26 122.86,98.77 122.86,101.44 123.37,101.95 126.8,101.95 127.3,101.44 127.3,100.5 127.02,100.22 127.02,98.7 127.24,98.48 128.48,98.48 129.21,97.76 129.21,95.6 129.08,95.47 ; 5 cut-outs
GND on BOTTOM: 55.93,12.54 55.29,13.17 55.29,14.95 55.42,15.08 56.69,15.08 57.07,15.46 57.83,15.46 57.96,15.33 57.96,14.7 58.22,14.44 59.1,14.44 59.36,14.7 59.49,14.7 59.61,14.57 59.61,12.67 59.49,12.54 ; 3 cut-outs
GND on BOTTOM: 167.82,31.97 167.69,32.1 167.69,33.62 168.45,34.38 169.3,34.38 169.3,32.9 168.37,31.97
GND on BOTTOM: 112.52,16.45 112.42,16.55 112.42,17.49 112.24,17.67 110.97,17.67 110.62,17.31 109.57,17.31 109.57,18.03 110.29,18.74 110.29,20.16 110.36,20.24 110.77,20.24 110.82,20.18 110.82,18.84 111.33,18.33 111.73,18.33 111.81,18.41 112.85,18.41 113.03,18.23 113.03,17.77 113.28,17.52 113.28,16.55 113.18,16.45
GND on BOTTOM: 113.71,21.63 113.61,21.73 113.61,22.37 113.94,22.7 113.94,23.18 113.97,23.21 115.06,23.21 115.19,23.08 115.19,22.24 114.58,21.63 ; 1 cut-out
GND on BOTTOM: 137.46,69.05 137.08,69.43 137.08,74.13 137.72,74.77 139.24,74.77 139.88,75.4 139.88,77.56 140.38,78.07 144.32,78.07 146.86,75.53 147.75,75.53 148.13,75.15 148.13,74.26 147.75,73.88 145.46,73.88 144.83,73.24 144.83,70.32 144.7,70.2 140.51,70.2 139.37,69.05 ; 3 cut-outs
GND on BOTTOM: 138.53,8.83 138.43,8.93 138.43,14.44 138.56,14.57 139.37,14.57 139.5,14.44 139.5,12.51 139.48,12.5 139.48,10.18 139.66,10 140.77,10 140.77,9.11 140.49,8.83 ; 2 cut-outs
GND on BOTTOM: 123.16,48.02 122.68,48.51 122.53,48.51 122.43,48.4 122.15,48.4 122.02,48.53 122.02,48.84 121.94,48.91 120.88,48.91 120.75,49.04 120.75,49.17 120.88,49.29 121.77,49.29 121.97,49.5 121.97,49.7 122.48,50.21 122.65,50.21 122.73,50.13 122.73,50 122.48,49.75 122.48,49.39 123.04,48.84 123.32,48.84 123.8,49.32 123.95,49.32 124.05,49.22 124.05,48.99 123.48,48.42 123.48,48.14 123.37,48.02
GND on BOTTOM: 136.83,48.48 136.45,48.86 136.45,52.16 136.7,52.42 138.48,52.42 138.86,52.04 138.86,48.68 138.66,48.48
GND on BOTTOM: outline of 118 points within 1.45,82.94 57.94,103.5 ; 5 cut-outs
GND on BOTTOM: 117.65,107.92 117.27,108.3 115.24,108.3 114.86,108.68 114.86,110.33 114.6,110.58 108.76,110.58 108.63,110.71 108.63,111.85 108.76,111.98 118.29,111.98 119.3,110.96 119.3,108.3 118.92,107.92 ; 8 cut-outs
GND on BOTTOM: 119.99,42.05 119.78,42.26 119.78,42.49 119.94,42.64 120.09,42.64 120.19,42.74 120.19,43.73 120.27,43.81 120.62,43.81 121.13,43.3 121.13,43.04 120.72,42.64 120.72,42.21 120.57,42.05
GND on BOTTOM: 126.8,79.59 124.51,81.88 122.1,81.88 120.06,83.91 120.06,88.23 121.72,89.88 129.08,89.88 129.84,89.12 134.16,89.12 134.29,88.99 134.29,82.13 131.75,79.59 ; 13 cut-outs
GND on L2GND: outline of 184 points within 0.51,0.51 204.34,113.41
GND on L3: outline of 230 points within 0.51,21.45 182.4,113.41
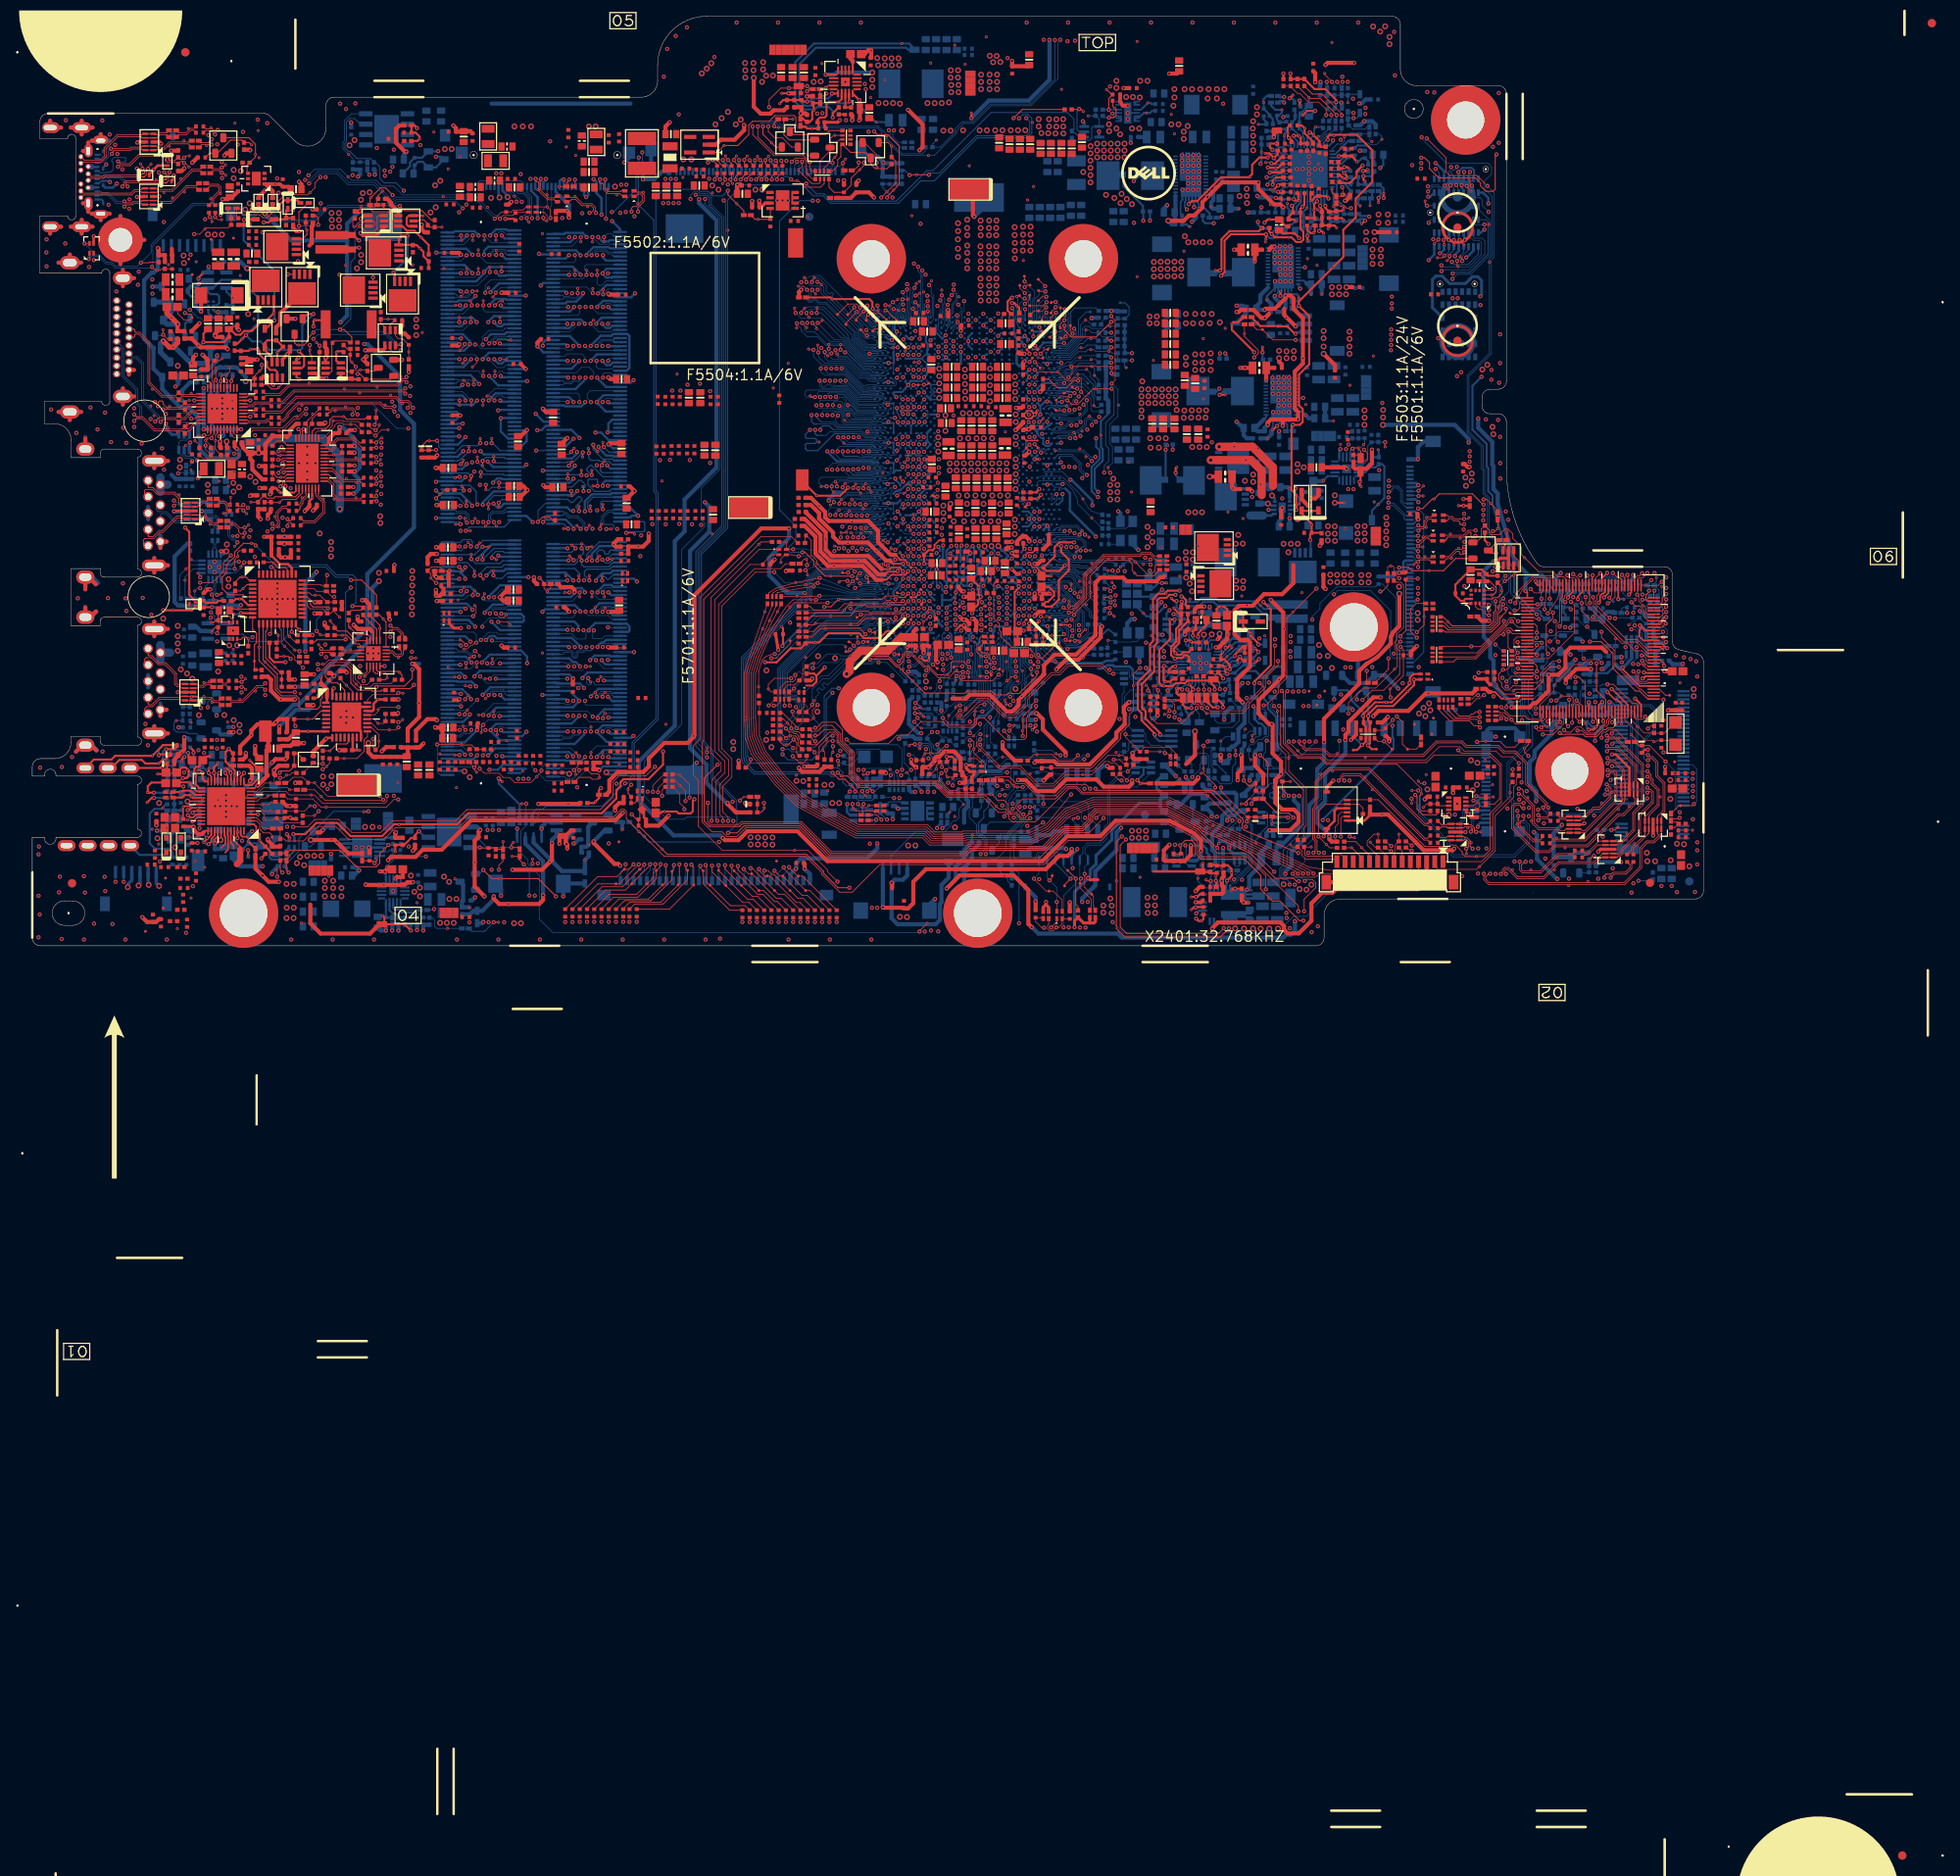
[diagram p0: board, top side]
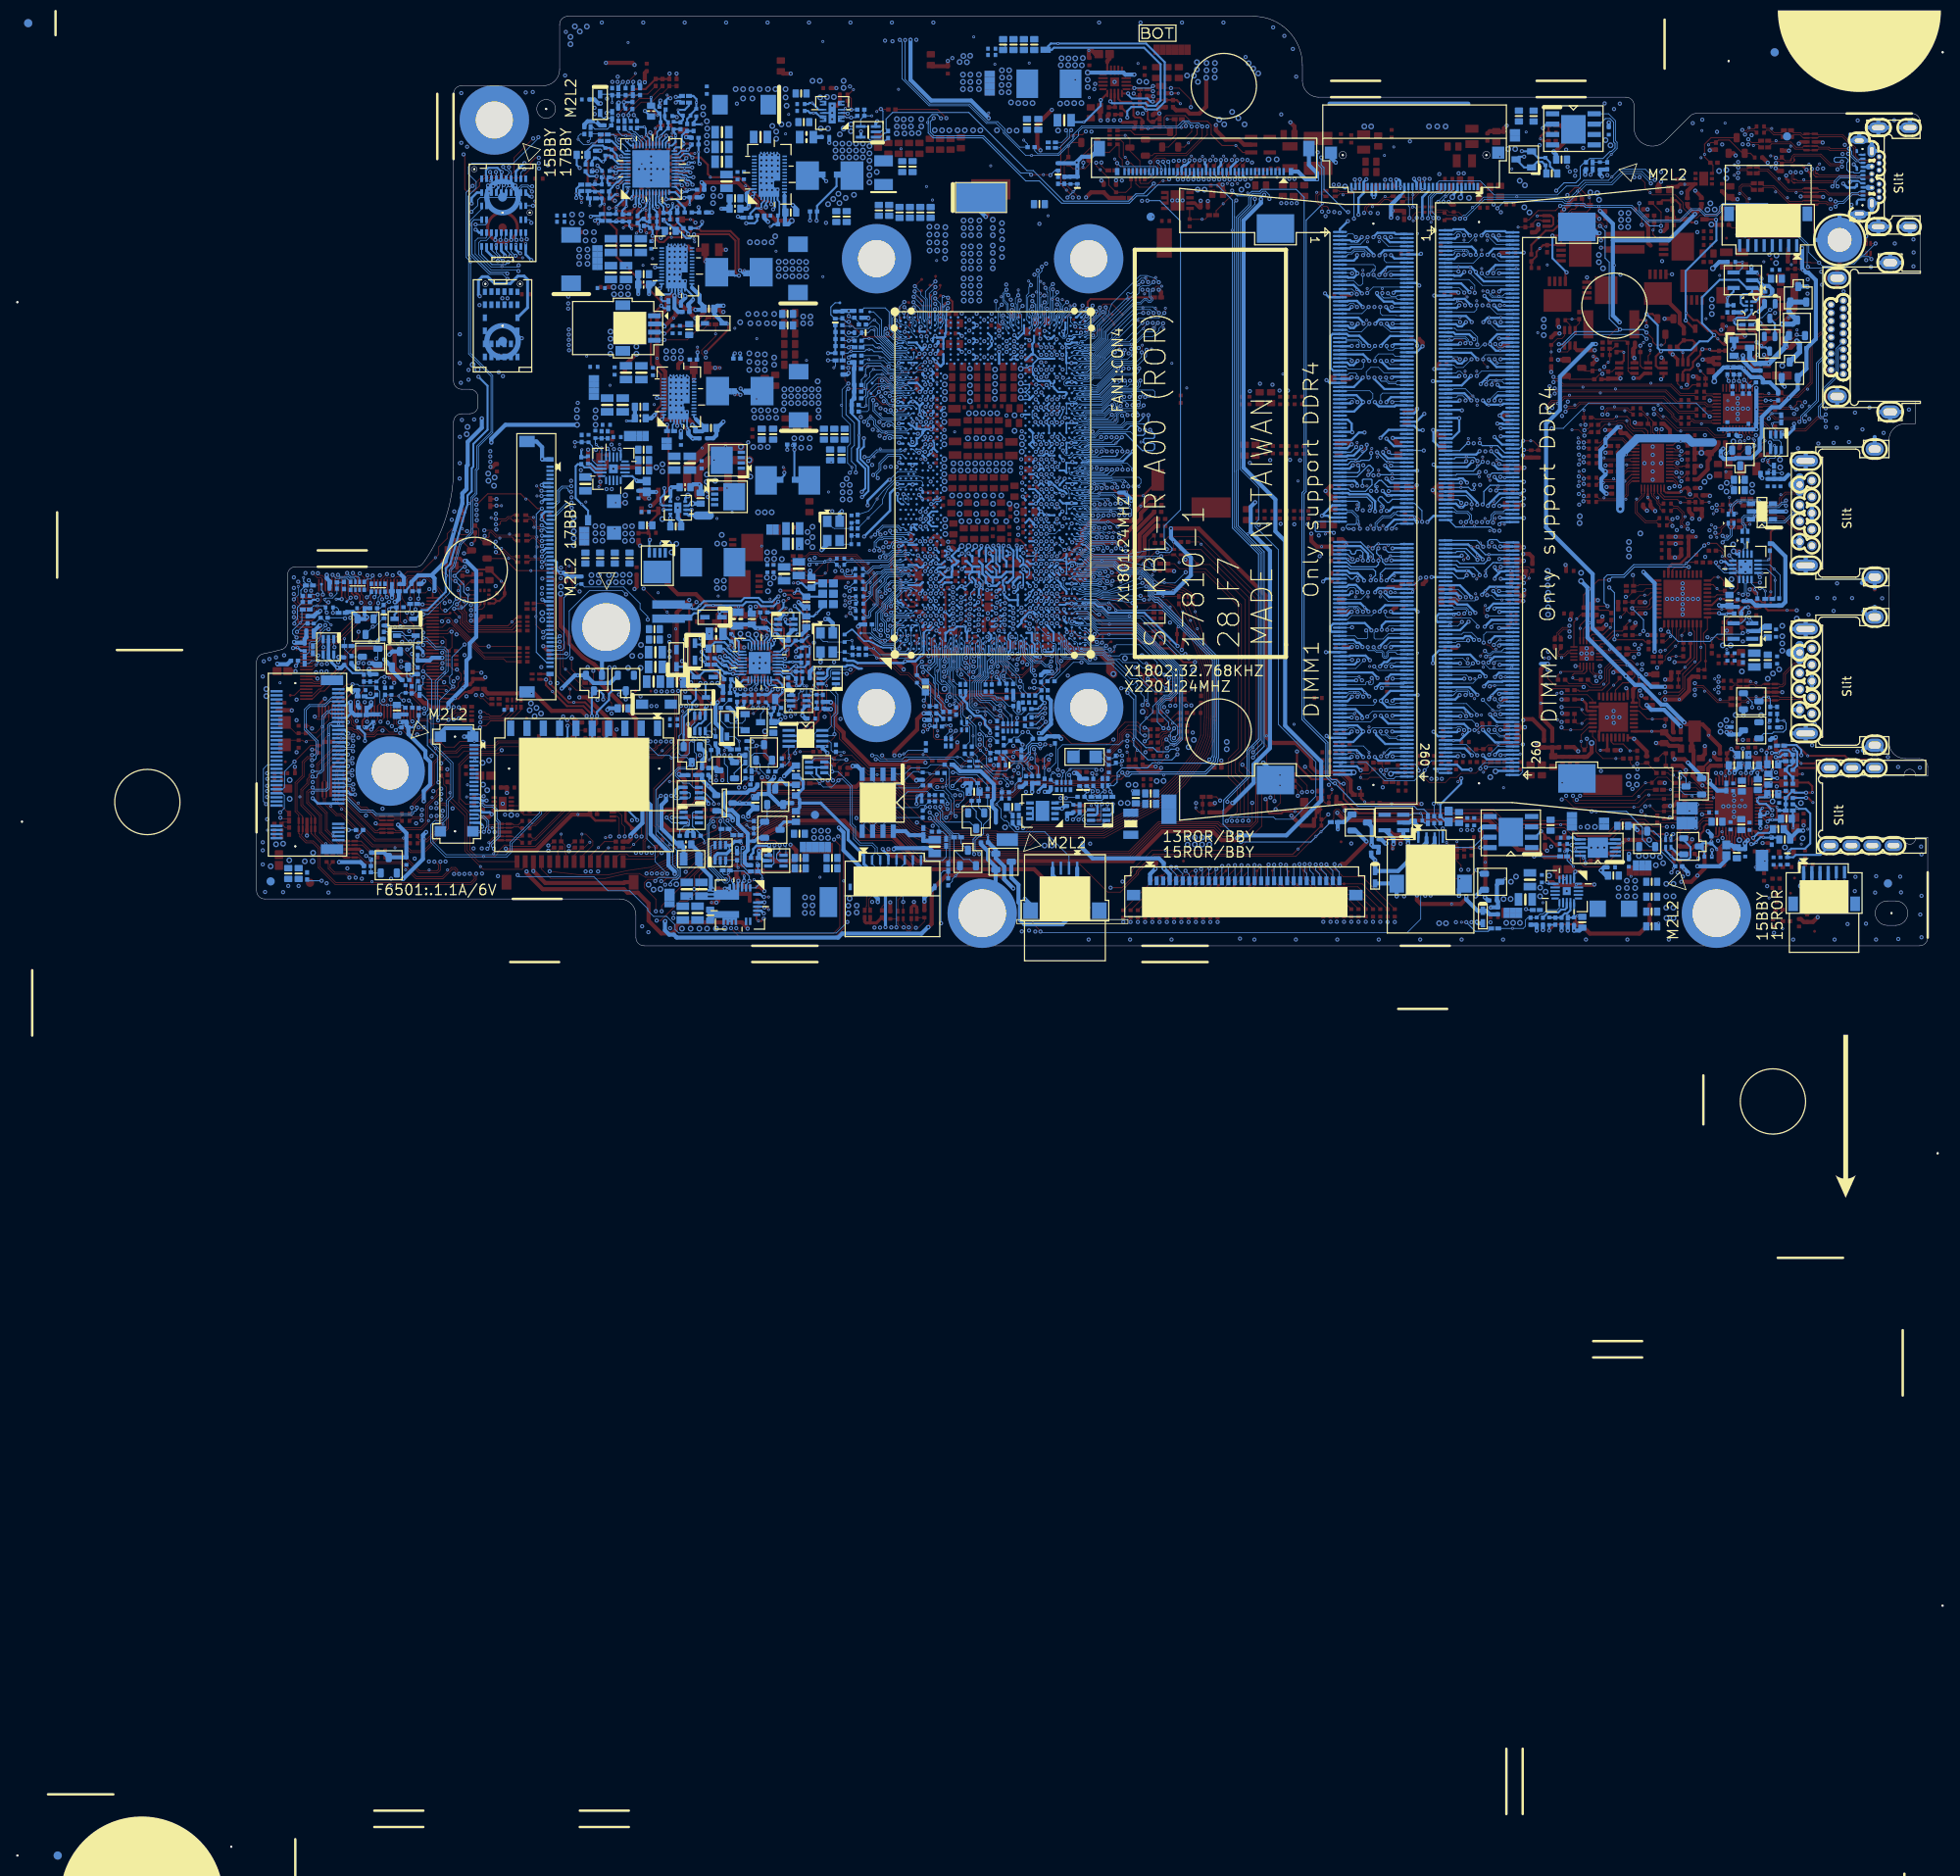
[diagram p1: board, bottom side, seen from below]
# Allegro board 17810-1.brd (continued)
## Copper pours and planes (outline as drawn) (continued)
GND on L3: 1,0.51 0.65,0.65 0.51,1 0.51,10.02 0.51,12.63 1.1,12.63 1.53,12.13 2.16,11.93 2.16,10.94 3.22,9.87 12.85,9.87 13.41,9.31 14.45,9.31 14.72,9.58 14.72,10.44 14.84,10.57 14.86,10.56 15.97,10.56 16.41,10.13 19.45,10.13 19.84,10.51 21.16,10.51 21.79,9.87 26.97,9.87 27.28,9.57 27.28,7.05 29.41,4.92 29.41,2.35 30.75,1.02 48.82,1.02 48.84,1.04 48.86,1.02 104.74,1.02 105.03,0.73 111.89,0.73 112.49,1.34 112.49,5.22 114.4,7.13 117.19,7.13 119,5.33 119,2.35 120.67,0.68 154.05,0.68 157.28,3.9 157.28,4.41 159.21,6.34 194,6.34 194.42,6.76 201.73,6.76 202.48,7.51 202.49,7.51 203.83,8.86 203.83,12.06 204.34,12.06 204.34,6.74 204.2,6.39 203.85,6.25 160.35,6.25 158.58,5.51 157.84,3.74 157.84,1 157.7,0.65 157.35,0.51
GND on L3: 200.4,37.51 200.12,37.79 199.87,37.79 199.69,37.96 199.69,38.19 199.88,38.38 200.3,38.38 200.54,38.14 200.54,37.27 200.86,36.35 201.67,35.81 202.8,35.53 203.95,35.28 204.23,35.11 204.34,34.8 204.34,12.54 204.21,12.41 203.76,12.41 202.87,13.3 202.87,20.92 204.14,22.19 204.14,31.72 203.24,32.62 202.25,32.62 200.4,34.47
GND on L3, L4: 26.21,19.14 22.53,19.14 21.61,18.23 21.61,15.23 21.77,15.08 22.91,15.08 24.31,13.68 27.1,13.68 27.35,13.94 27.35,18
GND on L4: outline of 133 points within 0.51,21.45 23.24,91.66
GND on L4: 197.33,12.72 199.86,15.24 202.04,15.24 202.31,15.51 202.31,16.78 201.22,17.87 201.22,30.19 201.6,30.57 201.6,31.46 201.54,31.52 201.54,35.32 200.96,35.57 200.49,35.99 200.42,35.99 199.72,36.69 199.72,38.31 199.79,38.38 200.33,38.38 200.54,38.17 200.54,37.27 200.86,36.35 201.67,35.81 202.8,35.53 203.95,35.28 204.23,35.11 204.34,34.8 204.34,13.89 204.34,13.89 204.34,6.74 204.2,6.39 203.85,6.25 197.6,6.25 197.33,6.52
GND on L4: 31.8,67.78 32.94,68.93 36.12,68.93 36.24,68.8 36.24,55.85 35.23,54.83 33.32,54.83 33.2,54.96 33.2,56.61 32.43,57.37 32.43,61.69 31.8,62.32
GND on L4: outline of 122 points within 1.45,43.53 200.54,113.41
GND on L4: 1,0.51 0.65,0.65 0.51,1 0.51,10.23 0.51,12.63 1.1,12.63 1.52,12.14 2.13,11.93 2.13,10.84 3.1,9.87 12.85,9.87 13.41,9.31 14.45,9.31 14.73,9.59 14.73,10.33 14.91,10.51 15.92,10.51 16.31,10.13 19.48,10.13 19.86,10.51 21.13,10.51 21.77,9.87 27.33,9.87 27.84,9.36 27.84,8.37 29.06,7.15 29.06,2.89 30.93,1.02 103.3,1.02 103.46,0.85 112.06,0.85 112.83,1.62 112.83,4.83 114.63,6.63 117.59,6.63 120.32,3.9 122.22,3.9 122.99,3.14 122.99,2.12 124.38,0.73 154.35,0.73 154.48,0.6 154.61,0.6 157.28,3.27 157.71,3.27 157.84,3.14 157.84,1 157.7,0.65 157.35,0.51
GND on L4: 10.34,99.53 16.69,99.53 17.07,99.15 17.07,94.71 16.94,94.58 14.53,94.58 14.27,94.83 9.83,94.83 8.81,95.85 8.81,96.36 9.32,96.87 9.32,97.88 9.96,98.52 9.96,99.15
GND on L5VCC: outline of 279 points within 0.51,0.51 204.34,113.41 ; 3 cut-outs
GND on L6: 176.45,93.56 176.71,93.31 176.58,93.18 176.58,83.15 174.93,81.5 173.58,81.5 172.49,82.59 172.49,84.37 170.6,86.26 170.6,93.43 170.74,93.56
GND on L6: 28.17,50.97 28.24,50.89 30.02,50.89 30.28,51.15 34.85,51.15 36.24,49.75 36.24,39.13 34.42,37.3 30.78,37.3 28.5,39.59 28.5,41.37 27.86,42 27.86,46.83 26.85,47.84 26.85,49.62 26.39,50.08 26.39,50.33 26.52,50.46 26.52,51.05 26.62,51.15 27.02,51.15 27.2,50.97
GND on L6: 34.09,70.83 35.61,72.36 36.12,72.36 36.37,72.1 36.37,70.96 37.79,69.54 37.79,65.8 40.44,63.16 40.44,55.72 43.1,53.05 43.1,51.02 41.07,48.99 40.31,48.99 39.67,49.62 39.67,50.89 32.31,58.26 32.31,59.58 32.76,60.04 32.76,60.77 34.59,62.6 34.59,66.77 34.09,67.28
GND on L6: outline of 327 points within 0.51,0.51 204.34,113.41 ; 1 cut-out
GND on L7GND: outline of 213 points within 0.51,0.51 204.34,113.41 ; 1 cut-out
VCC_CORE on TOP: 113.08,52.54 112.95,52.67 112.95,53.31 113.08,53.43 120.06,53.43 120.45,53.81 120.45,54.32 120.57,54.45 120.95,54.45 121.13,54.63 121.13,54.98 121.23,55.08 121.77,55.08 121.82,55.03 121.82,54.58 121.79,54.55 121.69,54.55 121.08,53.94 121.08,53.43 120.32,52.67 120.19,52.67 120.06,52.54
VCC_CORE on TOP: 113.46,63.97 113.33,64.1 113.33,65.37 113.59,65.62 118.03,65.62 118.16,65.5 118.16,64.1 118.03,63.97 ; 3 cut-outs
VCC_CORE on TOP: outline of 94 points within 109.13,54.83 144.45,84.42 ; 59 cut-outs
VCC_CORE on BOTTOM: 121.66,53.41 121.1,53.97 120.34,53.97 120.13,54.18 120.13,54.19 120.01,54.31 120.01,60.27 120.95,61.2 121.1,61.2 121.28,61.03 121.28,60.65 121.53,60.4 122.04,60.4 122.29,60.14 122.29,59.29 122.05,59.05 121.33,59.05 121.16,58.87 121.16,58.54 121.28,58.41 121.91,58.41 122.29,58.03 122.29,57.54 121.94,57.19 121.31,57.19 121.16,57.04 121.16,56.76 121.33,56.58 121.99,56.58 122.29,56.28 122.29,55.69 122.27,55.69 121.94,55.36 121.28,55.36 121.16,55.24 121.16,54.6 122.1,53.66 122.1,53.51 121.99,53.41
VCC_CORE on BOTTOM: 132.59,62.83 132.22,63.2 132.22,63.72 132.26,63.72 133.4,64.86 133.4,68.42 135.43,70.45 135.43,84.04 135.81,84.42 144.17,84.42 144.32,84.27 144.32,79.21 144.07,78.96 140.51,78.96 139.5,77.94 139.5,75.53 139.11,75.15 137.59,75.15 136.83,74.39 136.83,69.18 137.34,68.67 139.37,68.67 140.64,69.94 144.19,69.94 144.32,69.82 144.32,63.21 143.94,62.83 ; 11 cut-outs
VCC_CORE on BOTTOM: 110,54.38 110,54.38 109.6,54.38 109.17,54.81 109.17,55.24 109.67,55.74 109.67,56.18 109.13,56.71 109.13,57.02 109.69,57.57 109.69,57.99 109.13,58.54 109.13,58.77 109.31,58.95 110.1,58.95 110.48,59.33 110.97,59.33 111.33,58.97 111.33,55.01 111.17,54.85 110.52,54.85 110.05,54.38
VCC_CORE on L3: 141.15,69.18 143.33,69.18 144.86,67.66 144.86,64.69 144.4,64.23 141.02,64.23 139.93,63.14 139.93,63.08 136.45,63.08 135.58,63.95 135.58,84.32 136.45,85.18 141.4,85.18 141.78,84.8 141.78,80.99 140.13,79.34 140.13,70.2
VCC_CORE on L3: 111.32,59.27 112.04,59.99 120.72,59.99 120.9,59.81 120.9,55.85 120.67,55.62 110.87,55.62 110.74,55.74 110.74,56 110.75,56.01 110.75,59.03 111,59.27
VCC_CORE on L4: 128.45,69.94 143.18,69.94 144.65,68.47 144.65,64 143.36,62.7 136.96,62.7 136.32,62.07 136.32,61.05 133.78,58.51 130.99,58.51 128.95,56.48 127.94,56.48 125.91,54.45 121.21,54.45 119.18,52.42 113.21,52.42 112.7,52.92 112.7,55.46 112.83,55.59 112.83,56.48 112.06,57.24 112.06,59.15 112.95,60.04 112.95,65.24 113.97,66.26 119.94,66.26 120.95,67.28 120.95,69.69 121.84,70.58 127.81,70.58
VCC_CORE on L5VCC: 113.16,49.94 112.63,50.46 112.63,51.1 112.21,51.53 112.66,51.98 112.66,53.36 112.38,53.64 112.38,54.91 110.86,56.43 110.86,58.69 111.13,58.96 111.51,58.96 112.13,59.58 112.13,61.61 112.76,62.24 112.76,65.04 113.18,65.46 119.53,65.46 120.4,66.32 121.03,66.32 121.4,66.69 121.4,75.32 123.18,77.1 123.18,81.42 124.57,82.82 124.57,85.99 126.11,87.53 136.37,87.53 139.16,84.74 143.48,84.74 144.13,84.09 144.13,79.17 143.61,78.64 141.45,78.64 140.45,77.64 140.45,70.63 141.19,69.88 144.12,69.88 144.38,69.61 144.38,63.42 143.99,63.02 136.75,63.02 136,62.27 136,61 135.48,60.48 132.56,60.48 129.65,57.58 129.65,55.04 124.94,50.32 121.89,50.32 121.51,49.94
VCCPD_VBUS on TOP: 39.7,72.1 39.57,72.23 39.57,74.67 40.56,75.66 40.56,77.89 40.94,78.27 40.94,82.39 40.69,82.64 39.67,82.64 39.42,82.9 39.42,83.4 39.85,83.84 39.85,84.85 40.05,85.06 40.44,85.06 40.69,85.31 40.69,86.58 40.82,86.71 43.97,86.71 44.12,86.55 44.12,83.02 43.36,82.26 43.36,80.86 43.23,80.74 43.23,77.56 42.98,77.31 42.47,77.31 42.34,77.18 42.34,73.75 41.98,73.4 40.64,73.4 40.36,73.12 40.36,72.2 40.26,72.1 ; 5 cut-outs
VCCPD_VBUS on TOP: 23.72,92.68 23.56,92.84 23.56,93.83 23.67,93.95 23.93,93.95 24.18,94.2 24.18,96.36 24.31,96.49 25.96,96.49 26.06,96.38 26.06,93.79 26.16,93.69 26.57,93.69 26.72,93.54 26.72,93.06 26.59,92.93 24.94,92.93 24.69,92.68 ; 4 cut-outs
VCCPD_VBUS on BOTTOM: 32.36,90.29 32.1,90.54 28.85,90.54 25.7,93.69 24.38,93.69 24.26,93.82 24.26,96.61 24.74,97.1 28.62,97.1 32.59,93.13 34.29,93.13 34.97,93.82 36.14,93.82 36.4,94.07 37.44,94.07 38.45,93.06 41.45,93.06 41.83,92.68 41.83,91.28 41.58,91.02 35.63,91.02 34.9,90.29
VCCPD_VBUS on L3: 42.59,82.64 43.66,83.71 43.66,92.55 43.28,92.93 40.28,92.93 39.95,92.6 39.95,91 40.69,90.26 40.69,85.56 39.42,84.29 39.42,82.9 39.67,82.64
VCCPD_VBUS on L4: 9.92,88.65 9.7,88.87 9.7,91.15 9,91.85 6.69,91.85 6.48,92.07 6.48,92.6 6.4,92.68 6.4,95.44 6.96,96 8.3,96 9.66,94.64 13.96,94.64 14.27,94.33 16.94,94.33 17.35,94.73 17.35,97.93 17.37,97.96 17.37,100.09 18.21,100.93 28.12,100.93 32.18,96.87 37.9,96.87 38.91,95.85 40.94,95.85 41.65,95.14 41.65,91.86 40.82,91.02 32.05,91.02 30.28,92.8 29.26,92.8 28.24,93.82 25.45,93.82 24.31,92.68 22.02,92.68 18.72,89.37 15.99,89.37 15.26,88.65 ; 3 cut-outs
VDDD on TOP: 37.77,41.88 37.64,42 37.64,42.76 37.13,43.27 36.63,43.27 36.63,44.42 36.75,44.54 36.75,45.56 36.5,45.81 35.61,45.81 35.08,45.28 32.46,45.28 32.18,45.56 32.18,50.26 32.69,50.77 34.47,50.77 35.96,49.27 35.96,47.36 36.24,47.08 37.9,47.08 38.4,46.57 38.4,42 38.28,41.88 ; 7 cut-outs
VDDD on TOP: 33.45,34.59 33.45,35.58 33.2,35.83 33.2,36.11 33.17,36.14 33.17,36.26 33.68,36.77 34.57,36.77 34.75,36.59 34.75,35.22 34.11,34.59 ; 2 cut-outs
0D6V_PWR on BOTTOM: 36.5,11.9 36.26,12.15 36.26,13.69 36.5,13.94 37.01,13.94 37.39,14.32 37.39,15.59 37.51,15.71 39.55,15.71 39.55,14.06 38.95,13.47 38.95,12.93 38.91,12.89 37.59,12.89 37.51,12.82 37.51,12.21 37.56,12.16 38.95,12.16 38.95,11.94 38.91,11.9 ; 4 cut-outs
0D6V_S0 on TOP: 40.05,14.06 39.8,14.32 39.8,15.71 40.13,16.04 41.48,16.04 41.49,16.06 41.69,16.06 42.24,16.6 43.48,16.6 44.37,17.49 45.52,17.49 46.53,18.51 46.53,21.05 46.79,21.3 49.07,21.3 49.71,21.94 52.88,21.94 53.2,21.62 53.66,21.62 54.35,20.92 56.23,20.92 57.44,19.71 61.33,19.71 63.04,21.43 65.96,21.43 66.17,21.23 66.17,20.81 66.04,20.68 64.7,20.68 64.31,20.29 64.31,18.33 63.73,17.75 53.52,17.75 51.48,15.71 44.12,15.71 42.47,14.06 ; 19 cut-outs
0D6V_S0 on BOTTOM: 53.41,19.96 52.32,21.05 52.07,21.05 52.02,21.1 52.02,21.68 52.04,21.71 53.41,21.71 53.74,21.38 54.33,21.38 54.41,21.3 54.41,20.54 53.82,19.96
0D6V_S0 on BOTTOM: 39.8,14.06 39.8,15.71 41.71,15.71 42.09,15.33 42.09,14.29 41.86,14.06
1D0V_PWR on TOP: 134.29,2.38 133.53,3.14 133.53,7.95 134.17,8.6 134.17,11.89 134.21,11.93 137.97,11.93 138.1,11.8 138.1,2.68 137.79,2.38 ; 2 cut-outs
1D0V_PWR on BOTTOM: 134.29,2.38 133.53,3.14 133.53,7.92 134.16,8.55 134.16,11.88 134.21,11.93 137.97,11.93 138.1,11.8 138.1,2.68 137.79,2.38 ; 9 cut-outs
1D0V_S5 on TOP: 117.93,31.11 117.63,31.41 114.5,31.41 114.22,31.13 109.55,31.13 109.12,31.56 109.12,32.58 109.29,32.76 109.7,32.76 110.36,32.1 114.1,32.1 114.3,32.3 118.9,32.3 119.09,32.11 120.29,32.11 120.88,32.69 120.88,34.28 121.08,34.48 121.08,36.16 121.31,36.39 121.97,36.39 122.12,36.24 122.12,32.35 120.88,31.11
1D0V_S5 on TOP: 91.24,90.01 91.11,90.14 91.11,91.36 90.98,91.48 89.63,91.48 89.46,91.66 87.43,91.66 87.3,91.79 87.3,92.55 87.55,92.8 87.55,93.31 87.68,93.44 92.51,93.44 92.81,93.13 92.81,90.19 92.63,90.01 ; 1 cut-out
1D0V_S5 on TOP: 134.29,12.03 134.16,12.16 134.16,14.19 134.36,14.39 138.15,14.39 138.35,14.19 138.35,12.28 138.1,12.03
1D0V_S5 on BOTTOM: 87.81,11.9 86.54,13.17 86.54,17.87 84.26,20.15 84.26,20.16 84.25,20.16 83.74,20.67 83.74,24.1 82.22,25.62 82.22,47.57 85.79,51.13 85.79,91.67 87.17,93.06 92.33,93.06 92.81,92.57 92.81,90.82 90.22,88.23 90.22,49.11 86.41,45.3 86.41,22.85 91.24,18.03 91.24,18 93.14,16.09 95.43,16.09 96.7,14.82 99.49,14.82 99.74,14.57 103.22,14.57 103.74,15.09 104.15,15.09 104.16,15.1 105.94,15.1 106.12,15.28 106.12,16.27 106.25,16.4 107.57,16.4 107.67,16.5 107.67,17.77 109.35,17.77 109.35,14.44 109.09,14.19 108.15,14.19 107.64,13.68 105.46,13.68 105.28,13.5 104.04,13.5 103.2,12.67 103.2,12.11 103,11.9
1D0V_S5 on BOTTOM: 134.31,12.28 134.16,12.44 134.16,14.7 134.29,14.82 137.97,14.82 138.23,14.57 138.23,12.36 138.15,12.28 ; 2 cut-outs
1D0V_S5 on L5VCC: 100.84,9.43 99.19,11.08 87.5,11.08 86.98,11.6 86.98,13.48 87.38,13.87 109.48,13.87 110.49,14.89 136.62,14.89 137.27,14.24 137.27,11.09 136.88,10.7 126.34,10.7 125.07,9.43
1D0V_S5 on L6: 109.04,30.88 107.85,30.88 106.78,29.81 106.78,27.73 104.7,25.65 104.67,25.65 104.39,25.37 101.29,25.37 99.82,26.84 95.35,26.84 94.51,26 92.02,26 91.18,26.84 88.97,26.84 88.16,26.03 88.16,24.17 87.07,23.08 85.39,23.08 84.89,23.59 84.89,26 87.68,28.79 92.38,28.79 92.91,28.26 99.26,28.26 99.27,28.25 100.09,28.25 101.74,26.6 104.1,26.6 105.59,28.08 105.59,30.75 107.03,32.2 108.15,32.2 108.81,32.86 109.9,32.86 109.98,32.78 109.98,31.82
1D0V_S5 on L6: 139.58,27.96 140.19,27.35 141.3,27.35 141.45,27.19 141.45,26.92 141.37,26.84 139.95,26.84 139.11,27.68 139.11,28.26 139.27,28.41 139.47,28.41 139.58,28.3
1D2V_PWR on TOP: 33.96,3.9 33.83,4.03 33.83,9.11 37.51,9.11 38.4,8.22 38.4,4.28 38.02,3.9
1D2V_PWR on BOTTOM: 34.11,1.59 33.83,1.87 33.83,9.72 33.93,9.82 36.17,9.82 36.37,10.02 36.88,10.02 37.01,10.15 37.01,11.52 37.16,11.68 38.96,11.68 38.96,10.81 38.66,10.51 38.66,9.24 38.4,8.98 38.4,1.87 38.12,1.59 ; 20 cut-outs
1D2V_S3 on TOP: 32.43,9.24 32.18,9.49 32.18,11.27 32.43,11.52 35.61,11.52 36.88,10.25 36.88,9.24
1D2V_S3 on TOP: outline of 122 points within 45.83,25.49 106.48,85.44 ; 180 cut-outs
1D2V_S3 on BOTTOM: 35.61,19.27 35.36,19.52 35.36,23.59 37.64,25.87 39.55,25.87 42.09,28.41 42.09,39.21 43.23,40.35 43.23,45.94 43.61,46.32 46.79,46.32 46.91,46.19 46.91,34.38 45.9,33.37 45.9,24.73 43.86,22.7 39.55,22.7 39.01,22.17 39.01,19.75 38.53,19.27
1D2V_S3 on BOTTOM: 32.31,9.87 32.05,10.13 32.05,10.56 32.92,11.42 34.44,11.42 34.9,11.88 34.9,12.64 35,12.74 35.66,12.74 35.74,12.67 35.74,11.4 36.1,11.03 36.1,9.99 35.99,9.87
1D2V_S3 on L3: 102.18,48.3 102.84,48.3 104.47,49.93 105.33,49.93 105.89,49.37 109.35,49.37 109.52,49.55 109.52,50 108.74,50.79 104.19,50.79 102.08,48.68 102.08,48.4
1D2V_S3 on L4: 31.77,15.26 31.89,15.14 32.55,15.14 32.69,15 32.69,13.55 32.43,13.3 31.16,13.3 30.99,13.12 30.99,10.61 31.09,10.51 32.1,10.51 32.18,10.43 32.18,9.62 32.43,9.36 35.89,9.36 35.9,9.38 36.64,9.38 36.88,9.62 36.88,15.59 37.79,16.5 37.79,21.12 37.59,21.33 31.95,21.33 31.77,21.15
1D2V_S3 on L5VCC: 32.39,9.3 32.12,9.57 32.12,11.7 32.75,12.33 32.75,13.98 34.15,15.38 34.15,21.6 35.69,23.14 40.64,23.14 41.39,23.89 41.39,27.45 42.4,28.46 42.4,46.11 43.18,46.89 48.48,46.89 48.75,46.62 48.75,19.6 43.15,14 40.23,14 38.85,12.62 38.85,11.09 37.05,9.3
1D5V_S0 on TOP: 16.69,69.31 16.43,69.56 16.43,70.96 16.94,71.47 18.08,71.47 18.21,71.34 18.21,70.83 18.08,70.7 17.83,70.7 17.7,70.58 17.7,69.43 17.58,69.31
1D5V_VDD on TOP: 21.03,67.91 20.75,68.19 20.75,68.65 20.37,69.03 18.31,69.03 18.13,69.21 18.13,70.35 18.18,70.4 20.09,70.4 20.32,70.17 21.64,70.17 21.87,69.94 21.87,69.13 21.59,68.85 21.59,67.91 ; 3 cut-outs
1D8V_PWR on BOTTOM: 43.86,13.68 43.74,13.81 43.74,16.48 44.12,16.86 48.94,16.86 49.45,16.35 49.45,14.19 49.33,14.06 47.93,14.06 47.37,14.62 45.36,14.62 45.16,14.42 45.16,13.83 45.01,13.68 ; 4 cut-outs
2D5V_S3 on TOP: 70.15,20.84 70,21 70,21.38 70.41,21.78 70.86,21.78 71.07,21.99 71.07,23.31 70.58,23.79 70.58,24.02 70.69,24.12 73.33,24.12 73.51,23.94 73.51,21.05 73.3,20.84 ; 7 cut-outs
2D5V_S3 on TOP: 59.28,20.21 58.7,20.79 57.81,20.79 57.5,21.1 57.5,21.81 57.61,21.91 58.8,21.91 59.46,22.57 59.49,22.57 59.61,22.7 62.41,22.7 62.53,22.57 62.53,22.06 62.41,21.94 61.26,21.94 61.01,21.68 61.01,21.05 61.26,20.79 61.26,20.46 61.01,20.21 ; 9 cut-outs
2D5V_S3 on BOTTOM: 50.47,97.25 50.19,97.53 50.19,97.83 50.75,98.39 50.75,100.07 50.85,100.17 51.66,100.17 51.95,99.88 51.95,98.44 51.76,98.25 51.76,97.45 51.56,97.25
2D5V_S3 on BOTTOM: 59.74,17.82 58.23,19.33 58.23,21.19 58.34,21.3 60.22,21.3 60.3,21.38 60.3,21.78 60.35,21.84 60.73,21.84 61.09,21.48 61.09,20.75 61.68,20.16 64.95,20.16 65.07,20.03 66.72,20.03 68.38,21.68 69.06,21.68 69.15,21.59 70.58,21.59 70.74,21.44 70.74,21.23 70.86,21.1 72.87,21.1 72.9,21.07 72.9,20.64 72.82,20.57 72.24,20.57 71.88,20.21 71.47,20.21 71.19,19.93 71.19,19.07 69.95,17.82
2D5V_S3 on L4: 53.9,95.72 53.9,89.37 51.61,87.09 51.61,64.35 49.58,62.32 49.58,27.91 49.07,27.4 49.07,23.59 52.75,19.9 55.12,19.9 57.1,21.89 60.68,21.89 61.14,21.43 61.14,20.41 60.88,20.16 58.22,20.16 57.71,19.65 57.71,18.51 56.69,17.49 51.74,17.49 47.42,21.81 47.42,22.95 46.79,23.59 46.79,24.22 47.04,24.48 47.04,28.67 47.29,28.92 47.29,39.97 47.04,40.22 47.04,46.83 46.79,47.08 46.79,62.83 48.31,64.35 48.31,88.36 51.61,91.66 51.61,94.45 50.14,95.93 50.14,97.76 50.26,97.88 51.74,97.88
3D3V_CAMERA_S0 on TOP: 58.16,91.36 57.9,91.62 57.9,93.25 57.91,93.26 57.91,94.81 58.49,95.39 58.49,98.37 58.14,98.72 57.15,98.72 56.54,99.33 55.27,99.33 54.99,99.61 54.99,100.6 55.19,100.8 56.89,100.8 57.96,99.74 58.95,99.74 59.51,99.18 59.51,95.14 58.72,94.35 58.72,93.72 58.93,93.51 58.93,92.63 59.33,92.22 59.33,91.86 59.08,91.61 58.65,91.61 58.39,91.36 ; 2 cut-outs
3D3V_CAMERA_S0 on BOTTOM: 58.01,91.33 57.78,91.56 57.78,92.22 57.68,92.32 57.68,92.47 58.11,92.47 58.67,91.91 58.67,91.53 58.47,91.33
3D3V_GSEN2 on TOP: 174.7,39.92 172.87,41.75 172.87,44.34 174.95,46.42 175.74,46.42 175.84,46.52 176.78,46.52 176.88,46.42 176.88,45.76 176.76,45.64 175.94,45.64 175.77,45.81 175.26,45.81 173.73,44.29 173.73,42.1 174.98,40.86 176.48,40.86 176.63,40.71 176.63,40.05 176.5,39.92
3D3V_MUX on TOP: 31.32,61.76 31.04,62.04 31.04,62.53 31.14,62.63 32.36,62.63 32.38,62.6 32.38,61.76
3D3V_S0 on TOP: 138.99,20.41 138.73,20.67 138.73,22.44 138.86,22.57 141.58,22.57 141.7,22.44 141.7,22.11 141.55,21.96 141.02,21.96 140.89,21.84 140.89,20.92 140.38,20.41
3D3V_S0 on TOP: 201.7,8.98 201.5,9.19 201.5,10.13 201.62,10.25 203.3,10.25 203.53,10.02 203.53,9.24 203.27,8.98
3D3V_S0 on TOP: 55.61,21.34 55.19,21.76 55.19,22.06 54.96,22.29 54.96,22.75 55.09,22.88 55.93,22.88 56.16,23.11 56.16,23.56 55.93,23.79 55.93,24.53 55.52,24.93 51.28,24.93 51.1,25.11 51.1,27.04 50.62,27.52 49.33,27.52 48.82,28.03 48.82,34.89 46.38,37.33 46.38,38.04 44.25,40.17 44.25,41.9 42.11,44.03 42.11,46.04 42.57,46.5 43.51,46.5 43.71,46.3 43.71,45.61 45.52,43.81 45.52,40.43 50.09,35.86 50.09,29.38 52.07,27.4 52.07,26.36 52.4,26.03 56.16,26.03 56.69,25.49 56.69,23.56 56.56,23.44 56.56,21.84 56.07,21.34 ; 9 cut-outs
3D3V_S0 on TOP: 57.02,93.26 56.87,93.41 56.87,94.3 56.61,94.56 56.61,97.37 56.36,97.63 55.22,97.63 54.99,97.86 54.99,98.7 55.12,98.82 56.64,98.82 56.95,98.52 57.99,98.52 58.22,98.29 58.22,95.39 57.73,94.91 57.73,93.34 57.66,93.26 ; 2 cut-outs
3D3V_S0 on TOP: 101.14,15.21 99.36,16.98 99.36,18.13 99.74,18.51 101.65,18.51 102.16,18 102.16,17.24 102.03,17.11 101.78,17.11 101.65,17.24 101.65,17.62 101.52,17.75 100.25,17.75 100.13,17.62 100.13,17.11 101.01,16.22 101.9,16.22 101.9,15.21
3D3V_S0 on TOP: 118.41,23.84 116.51,25.75 116.51,25.98 116.3,26.18 116.1,26.18 115.39,25.47 114.7,25.47 114.27,25.04 109.09,25.04 108.25,25.87 108.25,26.51 108.51,26.76 108.89,26.76 109.43,27.31 111.53,27.31 112.25,26.59 115.42,26.59 115.95,27.12 117.24,27.12 119.4,24.96 119.4,24.12 119.12,23.84
3D3V_S0 on TOP: 24.99,67.91 24.99,70.37 25.45,70.83 26.97,70.83 27.1,70.7 27.1,70.07 26.54,69.51 26.54,68.29 26.35,68.1 25.64,68.1 25.45,67.91 ; 2 cut-outs
3D3V_S0 on TOP: 201.85,17.64 201.67,17.82 201.67,19.57 201.92,19.82 203.74,19.82 203.83,19.73 203.83,17.77 203.71,17.64
3D3V_S0 on TOP: 79.68,96 79.45,96.23 79.45,98.77 79.27,98.95 78.56,98.95 78.51,99 78.51,100.12 78.56,100.17 81.1,100.17 81.43,99.84 81.43,96.16 81.28,96
3D3V_S0 on TOP: 93.7,36.75 92.89,37.56 92.89,38.32 92.64,38.56 92.64,40.87 93.65,41.88 94.28,41.88 94.28,36.9 94.13,36.75 ; 4 cut-outs
3D3V_S0 on BOTTOM: 118.95,23.54 118.29,24.2 118.29,24.76 117.6,25.44 117.6,26.76 118.57,26.76 118.82,27.02 118.82,28.59 118.87,28.64 119.35,28.64 119.43,28.57 119.43,28.29 119.63,28.08 120.9,28.08 120.93,28.06 120.93,27.55 120.9,27.52 119.76,27.52 118.74,26.51 118.74,25.47 119.35,24.86 120.67,24.86 121.74,25.92 123.75,25.92 123.75,27.65 123.62,27.78 123.62,32.1 125.65,34.13 130.81,34.13 131.98,32.96 134.31,32.96 134.34,32.94 134.34,32.53 134.29,32.48 131.82,32.48 130.59,33.71 127.52,33.71 127.3,33.49 126.67,33.49 124.55,31.37 124.55,30.26 124.42,30.13 124.42,28.25 124.51,28.16 124.51,26.94 126.97,24.48 130.94,24.48 133.02,26.56 133.02,27.93 133.2,28.11 133.65,28.11 133.86,27.91 133.86,26.23 133.63,26 133.63,25.39 134.16,24.86 134.16,24.35 134.06,24.25 133.17,24.25 132.64,23.71 125.53,23.71 124.84,24.4 122.15,24.4 121.28,23.54 ; 3 cut-outs
3D3V_S0 on BOTTOM: 178.94,37.38 178.31,38.02 178.31,40 178.59,40.28 179.07,40.28 179.96,39.39 182.57,39.39 182.85,39.67 184.68,39.67 184.71,39.64 186.26,39.64 186.28,39.67 186.28,40.25 186.61,40.58 186.61,41.75 186.66,41.8 187.22,41.8 187.3,41.72 187.3,39.77 187.27,39.74 187.27,39.72 186.64,39.08 184.96,39.08 184.71,38.83 184.05,38.83 183.75,38.54 183.72,38.54 182.81,37.63 181.84,37.63 181.58,37.38
3D3V_S0 on BOTTOM: 140.26,22.83 140.13,22.95 140.13,23.59 140.64,24.1 140.64,25.98 140.38,26.23 138,26.23 137.83,26.39 136.92,26.39 136.43,26.88 134.99,26.88 134.85,27.02 134.85,28.08 135.02,28.26 136.45,28.26 136.65,28.06 136.65,27.7 137.21,27.14 140.38,27.14 140.77,26.76 142.42,26.76 142.92,26.25 142.92,25.87 142.67,25.62 142.16,25.62 141.53,24.98 141.53,24.1 140.89,23.46 140.89,23.08 140.64,22.83 ; 4 cut-outs
3D3V_S0 on BOTTOM: 92.05,100.63 91.29,101.39 90.65,101.39 90.22,100.96 87.88,100.96 87.09,101.74 86.64,101.74 85.57,100.68 84.76,100.68 84.12,101.31 84.12,102.07 85.39,103.34 87.48,103.34 87.86,102.96 93.47,102.96 94.13,102.3 97.08,102.3 97.46,101.92 97.46,100.78 97.31,100.63
3D3V_S0 on BOTTOM: 176.73,74.59 176.58,74.74 176.58,77.36 177.26,78.05 177.26,78.73 177.39,78.86 177.98,78.86 178.1,78.73 178.1,75.43 177.26,74.59
3D3V_S0 on BOTTOM: 107.87,97.25 107.62,97.5 107.62,98.64 108.89,98.64 109.02,98.52 109.02,97.37 108.89,97.25
3D3V_S0 on BOTTOM: 25.7,61.18 25.45,61.43 23.67,61.43 23.54,61.56 23.54,61.94 23.67,62.07 23.8,62.07 24.05,62.32 24.05,62.7 24.18,62.83 26.47,62.83 26.72,62.58 26.72,61.31 26.59,61.18 ; 1 cut-out
3D3V_S0 on BOTTOM: 168.43,39.56 168.35,39.64 168.35,41.24 168.45,41.34 170.18,41.34 170.36,41.16 170.36,39.77 170.15,39.56
3D3V_S0 on BOTTOM: 134.97,102.76 134.92,102.81 134.92,103.5 134.87,103.55 134.01,103.55 133.83,103.72 133.83,104.54 134.8,105.5 137.72,105.5 137.97,105.25 137.97,103.88 137.69,103.6 136.45,103.6 135.81,102.96 135.81,102.79 135.79,102.76 ; 2 cut-outs
3D3V_S0 on BOTTOM: 109.14,29.51 109.09,29.56 109.09,30.06 109.14,30.12 111,30.12 111.71,30.83 113.16,30.83 113.79,31.46 115.75,31.46 115.87,31.33 115.87,30.95 115.75,30.83 113.82,30.83 113.13,30.14 112.67,30.14 112.49,29.96 111.91,29.96 111.45,29.51 ; 2 cut-outs
3D3V_S0 on L3: 109.27,26.64 109.92,25.99 110.63,25.99 111.12,25.49 111.12,19.73 110.64,19.24 109.6,19.24 109.37,19.02 109.37,18.74 109.22,18.58 108.94,18.58 108.76,18.76 108.76,18.91 108.43,19.24 108.05,19.24 107.95,19.14 105.08,19.14 103.44,17.5 102.42,17.5 102.03,17.11 99.57,17.11 99.41,17.26 99.41,18.1 99.79,18.48 103.05,18.48 103.33,18.76 103.33,20.06 103.82,20.55 106.84,20.55 107.34,21.05 108.2,21.05 108.61,21.45 110.08,21.45 110.23,21.61 110.23,24.02 108.76,25.49 108.38,25.49 108,25.87 108,26.51 108.13,26.64
3D3V_S0 on L3: 49.43,28.21 50.44,28.21 51.69,26.97 51.69,23.41 52.09,23 55.7,23 56.39,22.32 56.39,21.58 56.13,21.32 55.88,21.32 55.8,21.4 54.96,22.24 51.46,22.24 50.34,23.36 50.34,26.53 49.58,27.3 49.38,27.3 49.17,27.5 49.17,27.96
3D3V_S0 on L3: 25.07,61.56 24.81,61.31 23.67,61.31 23.54,61.43 23.54,63.47 23.8,63.72 24.94,63.72 25.07,63.59
3D3V_S0 on L4: 203,19.9 203.76,19.9 203.88,19.78 203.88,17.11 203.25,16.48 203.25,15.21 203.76,14.7 203.76,9.24 203.63,9.11 202.49,9.11 202.36,9.24 202.36,11.52 203,12.16 203,14.44 202.36,15.08 202.36,19.27
3D3V_S0 on L4: 175.23,62.58 176.07,63.42 176.07,68.37 177.34,69.64 177.34,69.99 177.6,70.25 177.85,70.25 178.97,71.37 178.97,72.61 178.43,73.14 177.54,73.14 173.28,68.88 173.28,62.96 172.9,62.58 172.9,60.04 172.45,59.59 172.45,44.35 171.75,43.65 171.75,43.02 170.61,41.88 169.98,41.88 169.47,41.37 169.47,39.77 169.49,39.74 169.49,39.31 169.59,39.21 172.26,39.21 174.55,41.49 174.55,43.4 174.93,43.78 174.93,44.67 175.23,44.97
3D3V_S0 on L4: 40.77,82.77 40.77,90.31 41.58,91.13 41.58,91.15 42.21,91.79 42.21,93.06 45.07,95.91 45.83,95.91 47.17,97.25 47.17,97.76 48.69,99.28 56.31,99.28 58.85,96.74 79.17,96.74 85.01,102.58 85.52,102.58 86.03,102.07 86.03,101.18 85.74,100.89 85.74,100.13 84,98.39 83.36,98.39 80.06,95.09 77.65,95.09 77.01,94.45 70.46,94.45 69.82,95.09 59.49,95.09 58.6,94.2 56.95,94.2 53.14,98.01 49.83,98.01 49.07,97.25 49.07,96.23 48.56,95.72 48.06,95.72 44.88,92.55 44.37,92.55 43.86,92.04 43.86,90.77 43.48,90.39 43.48,79.59 42.47,78.58 42.47,70.73 40.82,69.08 40.82,53.15 40.84,53.13 40.84,53.1 41.37,52.57 41.37,50 42.72,48.66 42.72,44.54 42.47,44.29 40.56,44.29 37.64,47.21 37.64,50.26 36.5,51.4 36.5,71.21 38.28,72.99 38.28,80.28
3D3V_S0 on L4: 55.47,21.23 56.03,21.23 56.97,22.17 64.44,22.17 64.67,21.94 67.38,21.94 68.04,21.28 69.57,21.28 69.7,21.4 69.7,22.29 69.19,22.8 65.28,22.8 65.02,23.05 56.41,23.05 55.42,22.06 55.42,21.28
3D3V_S0 on L6: 179.12,70.2 179.5,70.58 179.5,75.15 179.88,75.53 179.88,96.61 177.98,98.52 174.42,98.52 171.8,101.13 171.8,103.22 170.43,104.59 167.99,104.59 166.55,106.04 166.55,107.28 166.17,107.66 166.17,108.68 164.9,109.95 134.59,109.95 128.19,103.55 113.61,103.55 112.75,102.68 103.48,102.68 101.98,104.18 98.55,104.18 98.45,104.08 96.16,104.08 95.3,103.22 95.3,101.31 95.68,100.93 97.53,100.93 97.71,101.11 97.71,101.62 97.89,101.79 101.73,101.79 102.08,101.44 102.72,101.44 103.1,101.06 113.64,101.06 114.4,101.82 130.73,101.82 131.11,102.2 131.11,102.45 131.49,102.84 132.38,102.84 132.89,102.33 132.89,101.44 133.63,100.7 135.58,100.7 138.23,103.34 138.23,106.52 139.62,107.92 158.16,107.92 158.67,108.42 161.85,108.42 166.24,104.03 166.24,102.94 166.57,102.61 166.57,100.35 168.26,98.66 170.86,98.66 173.29,96.23 173.3,96.23 173.76,95.77 174.9,95.77 175.44,95.24 176.12,95.24 177.6,93.77 177.6,79.37 176.96,78.73 176.96,75.12 175.94,74.11 173.23,74.11 172.72,74.62 172.29,74.62 172.11,74.44 172.11,68.85 172.92,68.04 174.83,68.04 176.33,69.54 176.33,69.87 176.66,70.2
3D3V_S0 on L6: 178.2,40.15 178.81,40.15 178.99,39.97 178.99,39.29 178.76,39.06 171.17,39.06 170.72,39.5 169.66,39.5 169.31,39.84 169.31,41.01 169.61,41.3 172.91,41.3 173.79,40.43 177.93,40.43
3D3V_S0 on L7GND: 201.04,17.94 194.95,24.03 193.04,24.03 190.63,26.45 186.18,26.45 186.06,26.57 183.52,26.57 182.48,27.6 182.48,28.75 181.87,29.37 176.15,29.37 173.21,32.3 173.21,37.51 171.2,39.53 169.04,39.53 168.39,40.18 168.39,41.54 168.78,41.94 171.93,41.94 175.63,38.24 175.63,33.03 177.14,31.53 182.72,31.53 185.01,29.24 193.52,29.24 194.01,28.75 202.92,19.84 204.34,19.84 204.34,17.94
3D3V_S5 on TOP: 165.78,48.73 165.56,48.96 164.92,48.96 164.82,49.06 164.82,52.02 164.51,52.33 163.59,52.33 163.37,52.54 163.37,55.82 164.51,56.96 164.51,62.58 165.06,63.12 165.06,67.06 165.28,67.28 167.18,67.28 168.2,66.26 168.2,61.31 167.56,60.67 167.56,48.99 167.31,48.73
3D3V_S5 on TOP: 197.92,28.82 197.46,29.28 197.46,29.71 196.62,30.55 195.55,30.55 192.61,33.49 192.28,33.49 192.1,33.67 192.1,34.13 192.15,34.18 192.78,34.18 192.89,34.28 192.89,35.6 192.45,36.03 192.45,36.29 192.61,36.44 192.86,36.44 193.57,35.73 193.57,33.9 196.44,31.03 196.8,31.03 196.81,31.02 196.99,31.02 197.81,30.19 197.81,30.04 197.97,29.89 199.72,29.89 200.15,30.32 200.71,30.32 201.22,30.83 201.22,32.53 201.85,33.16 201.85,33.87 201.5,34.23 201.5,34.61 201.65,34.76 202.49,34.76 203.5,33.75 203.5,32.35 202.61,31.46 202.61,29.25 202.18,28.82 ; 2 cut-outs
3D3V_S5 on TOP: 48.69,89.5 47.78,90.42 46.94,90.42 44.27,93.08 42.19,93.08 41.93,93.34 41.93,95.14 42.39,95.6 46.3,95.6 49.12,92.78 50.62,92.78 51.1,92.29 51.1,90.39 50.21,89.5 ; 2 cut-outs
3D3V_S5 on TOP: 171.37,38.32 171.25,38.45 171.25,43.88 174.42,47.06 177.06,47.06 177.54,47.54 179.35,47.54 179.55,47.34 179.55,47.01 179.4,46.85 177.62,46.85 177.32,46.55 175.66,46.55 175.63,46.51 174.74,46.51 172.26,44.03 172.26,38.45 172.13,38.32
3D3V_S5 on BOTTOM: 58.62,2.1 58.22,2.51 58.22,8.75 57.21,9.76 51.85,9.76 50.85,10.76 49.83,10.76 49.58,11.01 49.58,16.6 47.29,18.89 47.29,86.58 47.33,86.62 47.33,87.1 48.4,88.17 48.4,90.48 48.82,90.9 50.86,90.9 51.1,90.66 51.1,88.82 49.73,87.44 49.73,86 49.33,85.59 49.33,20.79 49.81,20.31 52.73,20.31 53.9,19.14 57.58,19.14 59.23,17.49 59.23,15.84 58.98,15.59 56.95,15.59 56.69,15.33 52.75,15.33 52.63,15.21 52.63,11.78 53.01,11.4 58.09,11.4 60.37,9.11 60.37,2.51 59.97,2.1 ; 6 cut-outs
3D3V_S5 on BOTTOM: 106.14,17.82 105.97,18 105.97,18.25 105.81,18.41 104.93,18.41 104.65,18.69 104.65,19.45 104.75,19.55 107.14,19.55 107.21,19.47 107.21,18.1 106.93,17.82
3D3V_S5 on BOTTOM: 145.46,18.51 145.34,18.63 145.34,18.89 145.46,19.02 146.86,19.02 146.99,19.14 146.99,19.65 147.24,19.9 147.24,20.21 147.6,20.57 148,20.57 148.08,20.49 148.08,18.97 147.62,18.51
3D3V_S5 on BOTTOM: 71.17,92.29 71.04,92.42 71.04,93.95 70.53,94.45 69.39,94.45 68.88,94.96 68.88,98.14 71.93,101.18 77.14,101.18 81.84,105.88 89.71,105.88 90.16,106.33 91.04,106.33 91.29,106.57 91.29,110.51 93.52,112.74 101.78,112.74 102.16,113.12 121.33,113.12 121.72,112.74 131.24,112.74 133.65,110.33 133.65,102.79 131.7,102.79 131.37,103.12 131.37,108.42 128.32,111.47 119.05,111.47 118.41,112.11 103.81,112.11 102.79,111.09 95.17,111.09 93.14,109.06 93.14,105.76 92.12,104.74 92.12,103.98 91.36,103.22 87.91,103.22 87.65,103.47 85.39,103.47 83.87,101.95 83.87,101.18 84.12,100.93 84.12,100.55 83.74,100.17 74.09,100.17 71.17,97.25 71.17,96.36 71.93,95.6 72.82,95.6 73.46,94.96 73.46,92.42 73.33,92.29
3D3V_S5 on BOTTOM: 42.98,93.95 42.85,94.07 42.85,94.58 42.98,94.71 43.48,94.71 43.61,94.83 43.61,95.09 41.96,96.74 40.31,96.74 40.03,97.02 40.03,98.39 40.1,98.47 41.73,98.47 41.93,98.67 41.93,101.77 42.01,101.85 44.91,101.85 44.93,101.82 44.93,94.99 44.89,94.95 44.89,94.21 44.63,93.95 ; 4 cut-outs
3D3V_S5 on BOTTOM: 161.16,104.82 161.09,104.89 161.09,105.48 161.01,105.55 160.65,105.55 160.45,105.76 160.45,106.39 160.58,106.52 162.1,106.52 162.33,106.29 162.33,105.78 162.13,105.58 161.85,105.58 161.67,105.4 161.67,104.87 161.62,104.82
3D3V_S5 on BOTTOM: 106.22,3.01 105.84,3.39 105.84,6.57 107.75,8.47 107.75,10.63 106.98,11.4 106.98,12.28 108.48,13.78 112.55,13.78 112.57,13.76 112.57,11.65 112.32,11.4 112.29,11.4 111.43,10.53 111.43,8.09 108.76,5.43 108.76,3.39 108.38,3.01
3D3V_S5 on BOTTOM: 165.66,48.61 165.28,48.99 165.02,48.99 164.9,49.11 164.9,52.42 165.28,52.8 166.93,52.8 167.24,52.48 167.24,49.11 166.74,48.61
3D3V_S5 on L3: 44.75,95.98 45.64,96.87 48.44,96.87 48.94,96.36 52.63,96.36 53.77,97.5 56.44,97.5 57.2,96.74 69.14,96.74 71.3,94.58 76.12,94.58 78.66,97.12 79.68,97.12 83.62,101.06 83.87,101.06 84.5,100.42 84.5,100.04 81.84,97.37 81.84,94.2 79.93,92.29 68.5,92.29 66.22,94.58 61.14,94.58 60.16,93.6 51.27,93.6 50.67,94.2 49.43,94.2 48.79,93.56 42.09,93.56 41.71,93.95 41.71,95.47 42.21,95.98
3D3V_S5 on L4: 131.88,104.49 138.73,104.49 139.62,105.38 155.47,105.38 155.98,104.87 161.34,104.87 161.52,105.05 161.52,106.9 160.88,107.53 157.55,107.53 156.89,108.2 133.3,108.2 131.75,106.65 131.75,104.61
3D3V_S5 on L6: 41.76,94.3 42.16,94.3 42.31,94.45 42.31,95.19 41.37,96.13 40.89,96.13 40.69,95.93 40.69,95.32 40.79,95.22 41.27,95.22 41.6,94.89 41.6,94.45
3D3V_S5 on L6: 122.72,17.43 122.72,15.02 122.4,14.7 122.05,14.7 121.66,15.08 121.59,15.08 121.33,15.33 116.76,15.33 113.99,12.56 110.31,12.56 109.9,12.97 107.62,12.97 107.36,12.72 107.36,11.78 107.39,11.78 107.57,11.6 114.65,11.6 116.81,13.76 123.01,13.76 124.13,14.88 124.13,19.27 123.24,20.16 123.24,22.57 122.99,22.83 122.1,22.83 121.84,22.57 121.84,18.3
3D3V_S5 on L6: 58.75,1.46 58.6,1.62 58.6,3.39 58.72,3.52 105.97,3.52 107.62,5.17 108.76,5.17 109.02,4.92 109.02,3.78 106.73,1.49 103.43,1.49 103.4,1.46
3D3V_S5 on L7GND: 165.36,63.15 165.21,63.29 165.21,65.67 165.48,65.94 165.99,65.94 167.5,67.45 167.5,82.56 168.26,83.33 168.26,98.47 161.16,105.57 160.66,105.57 160.51,105.71 160.51,106.95 160.91,107.34 163.8,107.34 170.93,100.22 170.93,84.37 170.42,83.86 170.42,65.45 168.12,63.15
3D3V_S5_PCH on TOP: 112.83,27.22 111.94,28.11 111.94,28.95 111.28,29.61 108.84,29.61 108.3,30.14 108.02,30.14 107.08,31.08 107.08,31.54 104.93,33.7 100.99,33.7 100.05,32.76 99.74,32.76 99.41,33.09 99.41,34 100.2,34.79 105.08,34.79 105.87,34 106.09,34 109.32,30.78 112.85,30.78 112.95,30.67 112.95,29.68 112.7,29.43 112.7,28.31 113.41,27.6 114.43,27.6 114.55,27.73 115.19,27.73 115.26,27.65 115.26,27.32 115.16,27.22
3D3V_S5_PCH on TOP: 93.78,30.83 93.7,30.9 93.7,31.84 93.9,32.05 95.1,32.05 95.22,31.92 95.22,31.21 94.84,30.83
3D3V_S5_PCH on TOP: 138.81,45 138.56,45.25 138.56,45.66 138.63,45.74 138.63,48.15 138.76,48.28 139.39,48.28 139.62,48.05 139.62,45.3 139.32,45
3D3V_S5_PCH on TOP: 112.06,14.19 110.16,16.09 104.19,16.09 104.06,16.22 104.06,17.49 104.19,17.62 108.38,17.62 109.42,18.66 109.42,19.02 109.52,19.12 110.01,19.12 110.13,18.99 110.13,18.71 111.1,17.75 116.13,17.75 118.92,14.95 122.1,14.95 122.22,14.82 122.22,14.52 122.02,14.32 113.59,14.32 113.46,14.19
3D3V_S5_PCH on BOTTOM: 113.03,25.11 112.98,25.16 112.98,25.47 112.75,25.7 111.68,25.7 111.4,25.98 111.4,27.4 113.89,27.4 114.07,27.58 114.48,27.58 114.62,27.72 115.2,27.72 115.26,27.65 115.26,27.32 115.16,27.22 114.98,27.22 114.35,26.59 114.35,25.65 114.3,25.59 113.76,25.59 113.61,25.44 113.61,25.14 113.59,25.11 ; 2 cut-outs
3D3V_S5_PCH on BOTTOM: 113.23,12.16 113.18,12.21 113.18,13.78 112.85,14.11 112.85,14.77 113.16,15.08 114.6,15.08 114.83,14.85 114.83,12.89 114.1,12.16
3D3V_S5_PCH on BOTTOM: 121.79,13.66 121.69,13.76 121.69,14.8 122.1,15.21 122.27,15.21 122.35,15.13 123.04,15.13 123.59,14.57 123.59,14.14 123.47,14.01 122.68,14.01 122.32,13.66 ; 1 cut-out
3D3V_S5_PCH on L3: 100.25,13.43 100.38,13.3 104.06,13.3 104.32,13.05 113.33,13.05 113.56,13.28 113.56,14.62 112.09,16.09 105.97,16.09 104.32,14.44 100.38,14.44 100.25,14.32
3D3V_S5_PCH on L6: 97.2,34.54 100.18,34.54 100.61,34.1 100.61,33.65 99.97,33.01 97.1,33.01 96.7,33.42 96.7,34.03
3D3V_SEN_S0 on TOP: 56.82,91.25 56.64,91.43 56.64,92.35 55.32,93.67 54.2,93.67 52.09,95.77 52.09,98.67 52.37,98.95 54.41,98.95 54.58,98.77 54.58,98.04 55.29,97.32 56.18,97.32 56.41,97.1 56.41,94.56 56.72,94.25 56.72,93.36 56.93,93.15 57.08,93.15 57.63,92.6 57.63,91.46 57.43,91.25 ; 6 cut-outs
3D3V_SEN_S0 on BOTTOM: 56.95,91.15 56.72,91.38 56.72,92.24 56.87,92.4 57.38,92.4 57.63,92.14 57.63,91.33 57.45,91.15
3D3V_SSD on TOP: 200.7,17.49 200.57,17.62 200.57,22.58 200.52,22.64 201.09,23.21 202.61,23.21 202.74,23.33 202.74,31.21 203.38,31.84 203.88,31.84 204.09,31.64 204.09,22.57 203.27,21.76 202.51,21.76 202.31,21.56 202.31,20.13 202.13,19.96 201.85,19.96 201.57,19.68 201.57,17.64 201.42,17.49 ; 5 cut-outs
3D3V_SSD on TOP: 198.8,9.11 198.55,9.36 198.55,10.89 198.8,11.14 200.58,11.14 201.08,11.64 201.08,12.78 200.96,12.89 200.94,12.89 200.58,13.25 200.58,14.19 201.34,14.19 201.6,14.44 201.85,14.44 202.11,14.19 202.11,13.05 202.36,12.79 202.61,12.79 203.12,12.28 203.12,10.76 202.79,10.43 201.65,10.43 201.34,10.13 201.34,9.49 200.96,9.11 ; 4 cut-outs
3D3V_SSD on BOTTOM: 198.3,8.86 198.17,8.98 198.17,9.49 198.42,9.74 198.42,12.67 199.41,13.66 199.41,20.74 199.87,21.2 200.86,21.2 201.22,20.84 201.22,14.62 201.52,14.32 203.5,14.32 203.63,14.19 203.63,10.74 201.75,8.86 ; 7 cut-outs
3D3V_SSD on BOTTOM: 201.65,27.04 201.62,27.07 201.62,28.82 201.65,28.85 203.3,28.85 203.5,29.05 203.5,30.29 203.25,30.55 201.62,30.55 201.6,30.57 201.6,31.72 201.85,31.97 203.76,31.97 204.01,31.72 204.01,27.47 203.58,27.04
3D3V_SSD on L3: 202.49,13.05 203,12.54 203,10.51 201.73,9.24 199.44,9.24 198.42,10.25 198.42,11.78 198.04,12.16 198.04,14.44 199.69,16.09 199.69,21.05 201.85,23.21 202.74,23.21 202.87,23.33 202.87,31.59 203.12,31.84 203.76,31.84 204.01,31.59 204.01,22.57 202.49,21.05
3D3V_SSD on L6: 199.82,21.05 201.22,21.05 201.73,20.54 201.73,15.33 202.87,14.19 202.87,10.89 201.6,9.62 199.06,9.62 198.42,10.25 198.42,12.41 198.17,12.67 198.17,16.09 198.93,16.86 198.93,20.16
3D3V_TPM_1 on TOP: 33.12,30.19 32.66,30.65 32.66,31.33 32.82,31.49 32.82,32.4 32.99,32.58 34.62,32.58 34.87,32.33 34.87,31.16 34.62,30.9 34.29,30.9 34.09,30.7 34.09,30.32 33.96,30.19 ; 6 cut-outs
81208_AGND on TOP: 153.74,91.3 153.69,91.36 153.69,91.76 153.92,91.98 153.92,95.62 153.91,95.62 153.91,96.85 153.68,97.08 153.38,97.08 153.11,97.35 153.11,98.59 152.69,99.01 152.69,101.81 152.83,101.95 153.59,101.95 153.72,101.82 153.72,100.68 153.47,100.42 153.47,99.05 153.9,98.62 153.9,98.16 154.02,98.04 155.01,98.04 155.2,97.84 157.19,97.84 157.53,97.5 158.93,97.5 158.95,97.48 159.61,98.14 162.86,98.14 163.02,97.98 163.02,97.32 162.89,97.2 162.43,97.2 162.3,97.32 160.07,97.32 159.54,96.79 159.54,94.86 159.69,94.71 159.69,93.41 159.56,93.29 159.15,93.29 159.03,93.41 159.03,93.87 158.77,94.12 158.11,94.12 158.03,94.04 158.03,92.89 157.85,92.71 154.78,92.71 154.62,92.55 154.62,92.15 154.53,92.07 154.53,92.07 154.25,91.79 154.25,91.38 154.18,91.3 ; 33 cut-outs
81208_AGND on BOTTOM: 154.38,92.93 154.2,93.11 154.2,97.3 154.4,97.5 158.62,97.5 158.77,97.35 158.77,93.08 158.62,92.93
+DC_IN on TOP: 21.28,76.17 20.98,76.47 20.98,77.31 21.36,77.69 21.39,77.69 21.97,78.27 21.97,83.96 22.05,84.04 25.32,84.04 25.7,83.66 25.7,82.64 26.62,81.73 26.62,80.13 26.9,79.85 29.01,79.85 29.13,79.72 29.13,77.44 28.88,77.18 28.24,77.18 27.23,76.17 ; 6 cut-outs
+DC_IN on BOTTOM: 19.73,74.06 19.53,74.26 19.53,75.05 19.76,75.28 20.37,75.28 20.78,75.68 23.7,75.68 24.31,76.29 24.31,77.89 24.33,77.92 24.92,77.92 25.04,78.05 25.04,79.26 25.37,79.59 26.59,79.59 26.85,79.34 26.85,76.8 25.96,75.91 25.09,75.91 24.33,75.15 21.28,75.15 20.19,74.06 ; 1 cut-out
+DC_IN_C on TOP: 21.21,84.29 20.92,84.59 20.92,87.1 21.54,87.72 24.94,87.72 25.58,87.09 25.58,84.67 25.2,84.29
+DC_IN_C on BOTTOM: 18.9,81.2 18.67,81.42 18.67,82.97 19.16,83.47 19.16,83.85 20.09,84.78 20.42,84.78 20.62,84.98 20.62,87.04 21.23,87.65 23.32,87.65 23.8,87.16 23.8,84.98 23.16,84.34 22.63,84.34 22.05,83.76 21.44,83.76 20.52,82.85 20.52,82.54 20.04,82.06 20.04,81.42 19.81,81.2 ; 3 cut-outs
+SDC_IN on TOP: 32.56,81.7 32.54,81.73 32.54,82.92 31.8,83.66 31.8,86.2 34.21,86.2 34.47,85.94 38.28,85.94 38.78,85.44 38.78,83.28 38.28,82.77 37.18,82.77 36.12,81.7
AD+ on TOP: 148.78,31.96 148.66,32.07 148.66,33.01 150.67,35.02 150.67,37.05 150.16,37.56 150.16,38.07 149.66,38.57 149.66,39.84 149.88,40.07 151.05,40.07 151.31,39.82 151.31,38.7 151.56,38.45 151.56,34.76 149.43,32.63 149.43,32.06 149.32,31.96
AD+ on TOP: 26.97,80.1 26.85,80.23 26.85,82.97 27.1,83.23 27.1,87.82 27.18,87.9 29.69,87.9 30.53,88.74 31.29,88.74 31.55,88.48 31.55,83.66 30.78,82.9 30.78,80.48 30.4,80.1 ; 9 cut-outs
AD+ on BOTTOM: 147.52,29.81 147.34,29.99 147.34,30.8 147.47,30.93 147.85,30.93 148.66,31.74 148.66,32.45 148.54,32.58 148.36,32.58 148.33,32.6 148.33,33.11 148.39,33.16 149.53,33.16 149.53,32.58 149.43,32.48 149.43,31.33 147.9,29.81
AUD_AGND on TOP: 13.82,9.62 13.69,9.74 13.69,11.5 14.12,11.93 14.12,14.11 14.48,14.47 14.78,14.47 14.88,14.37 15.47,14.37 15.54,14.29 15.54,13.99 15.42,13.86 14.83,13.86 14.65,13.68 14.65,12.41 15.11,11.95 15.34,11.95 15.44,11.85 15.44,11.35 15.42,11.32 14.68,11.32 14.4,11.04 14.4,9.72 14.3,9.62 ; 2 cut-outs
AUD_AGND on TOP: 20.5,23.33 20.12,23.71 20.12,24.35 20.37,24.6 23.54,24.6 23.67,24.48 23.67,24.22 23.16,23.71 21.51,23.71 21.13,23.33 ; 5 cut-outs
AUD_AGND on BOTTOM: 22.02,10.38 21.39,11.01 19.48,11.01 19.1,10.63 17.96,10.63 17.83,10.76 17.83,11.27 18.85,12.28 18.85,12.67 18.97,12.79 20.37,12.79 21.26,11.9 21.51,11.9 22.15,11.27 22.66,11.27 22.78,11.14 23.67,11.14 23.8,11.01 23.8,10.51 23.67,10.38 ; 5 cut-outs
AUD_AGND on BOTTOM: 18.01,17.21 17.93,17.29 17.93,18.41 17.65,18.69 17.22,18.69 17.09,18.81 17.09,20.9 17.32,21.12 17.58,21.12 17.93,21.48 18.79,21.48 18.9,21.38 18.9,21.07 18.74,20.92 18.13,20.92 18.03,20.82 18.03,20.21 18.18,20.06 19.99,20.06 20.39,19.65 21.26,19.65 21.33,19.57 21.33,18.77 21.21,18.65 20.41,18.65 20.24,18.81 20.24,19.14 20.17,19.22 19.38,19.22 19.07,18.91 19.07,18.38 18.46,17.77 18.46,17.26 18.41,17.21 ; 6 cut-outs
AUD_AGND on BOTTOM: 21.13,22.83 19.86,24.1 18.59,24.1 18.21,24.48 18.21,24.6 18.34,24.73 18.59,24.73 18.85,24.48 22.78,24.48 22.91,24.35 22.91,23.97 22.53,23.59 22.53,22.95 22.4,22.83 ; 2 cut-outs
AUD_AGND on L2GND: 16.75,21.98 16.99,21.75 17.91,21.75 18.27,22.11 18.27,22.87 19.16,23.76 19.16,24.52 19.18,24.54 24.1,24.54 24.88,23.76 24.88,21.86 25.24,21.49 26.13,21.49 26.27,21.35 26.27,21.13 25.64,20.49 25.64,19.86 25.5,19.71 21.81,19.71 21.19,19.09 21.19,15 21.69,14.51 22.7,14.51 22.85,14.36 22.85,13.38 22.59,13.13 22.59,12.49 22.45,12.35 18.77,12.35 17.88,11.46 14.7,11.46 14.34,11.09 14.34,9.7 14.32,9.68 13.59,9.68 12.96,10.32 3.3,10.32 2.53,11.09 2.53,11.98 2.98,12.22 3.3,12.63 12.9,12.63 13.87,13.38 13.41,14.51 13.41,19.57 13.87,20.7 12.9,21.45 4.15,21.45 5.84,23.14 9.65,23.14 10.03,23.52 14.73,23.52 16,24.79 18,24.79 18.02,24.78 18.02,24.3 17.88,24.16 17.5,24.16 17.13,23.79 17.13,23.16 16.75,22.78
AUD_AGND on L5VCC, L7GND: 2.53,11.09 2.53,11.98 2.98,12.22 3.3,12.63 12.9,12.63 13.87,13.38 13.41,14.51 13.41,19.57 13.87,20.7 12.9,21.45 4.15,21.45 5.84,23.14 9.65,23.14 10.03,23.52 14.73,23.52 16,24.79 18.64,24.79 18.89,24.54 24.1,24.54 24.88,23.76 24.88,21.86 25.24,21.49 26.13,21.49 26.27,21.35 26.27,21.13 25.64,20.49 25.64,19.86 25.5,19.71 21.81,19.71 21.19,19.09 21.19,13.86 21.56,13.49 21.81,13.49 22.83,12.48 23.75,12.48 23.88,12.6 26.16,12.6 26.42,12.86 28.04,12.86 28.56,12.33 28.56,10.71 28.29,10.44 25.91,10.44 25.51,10.84 25.51,11.35 25.15,11.71 24.1,11.71 23.73,11.35 23.73,10.33 23.72,10.32 22.1,10.32 21.46,10.95 19.66,10.95 19.27,10.57 16.51,10.57 16.13,10.95 14.7,10.95 14.07,10.32 3.3,10.32
AUD_SPK_L+ on TOP: 18.51,9.24 18.36,9.39 18.36,9.95 19.15,10.74 19.86,10.74 20.22,11.09 20.52,11.09 20.85,11.42 20.85,11.9 20.93,11.98 22.6,11.98 22.96,12.34 23.21,12.34 23.26,12.28 23.26,11.8 22.59,11.13 21.7,11.13 20.45,9.87 19.43,9.87 19.35,9.8 19.35,9.34 19.25,9.24 ; 2 cut-outs
AUD_SPK_L+_C on TOP: 15.34,7 14.98,7.36 14.98,7.99 16.38,9.39 16.38,9.9 16.41,9.92 18.03,9.92 18.06,9.9 18.06,9.19 18.01,9.14 17.4,9.14 16.66,8.4 16.66,7.18 16.48,7 ; 2 cut-outs
AUD_SPK_L- on TOP: 18.74,7.66 18.67,7.74 18.67,8.93 18.79,9.06 19.3,9.06 19.51,9.26 19.51,9.44 19.73,9.67 20.5,9.67 21.79,10.96 22.78,10.96 23.59,11.78 23.93,11.78 24.05,11.65 24.05,11.12 22.87,9.94 22.21,9.94 20.7,8.42 19.76,8.42 19.58,8.25 19.58,7.74 19.51,7.66 ; 4 cut-outs
AUD_SPK_L-_C on TOP: 14.46,5.59 13.92,6.14 13.92,7.69 14.07,7.84 14.58,7.84 14.91,7.51 14.91,7.28 15.47,6.72 16.58,6.72 16.89,7.03 16.89,8.25 17.35,8.7 18.29,8.7 18.36,8.63 18.36,8.14 18.46,8.04 18.46,6.93 18.36,6.82 18.01,6.82 17.85,6.67 17.85,6.19 17.26,5.59 ; 3 cut-outs
AUD_SPK_R+ on TOP: 17.65,1.92 17.5,2.07 17.5,3.34 17.78,3.62 19.33,3.62 19.92,4.22 19.92,5.21 21.36,6.65 21.36,6.85 24.92,10.41 25.27,10.41 25.6,10.08 25.6,9.85 22.43,6.67 22.43,6.34 21.46,5.38 21.46,4.89 20.98,4.41 20.98,3.62 20.14,2.79 18.62,2.79 18.46,2.63 18.46,2.4 17.98,1.92 ; 4 cut-outs
AUD_SPK_R+_C on TOP: 13.16,1.19 11.3,3.04 11.3,7.38 11.45,7.54 12.19,7.54 12.46,7.27 12.46,4.7 12.47,4.69 12.47,3.83 14.04,2.25 15.29,2.25 15.47,2.43 15.47,2.58 15.59,2.71 16.1,2.71 16.28,2.89 16.28,3.47 16.36,3.55 17.12,3.55 17.22,3.45 17.22,2.28 16.13,1.19 ; 3 cut-outs
AUD_SPK_R- on TOP: 18.49,3.83 18.34,3.98 18.34,4.94 18.08,5.2 18.08,5.63 18.21,5.76 18.82,5.76 19.3,6.24 19.3,6.34 20.72,7.76 20.72,8.09 22.22,9.59 22.78,9.59 24.18,10.99 24.18,11.93 24.31,12.06 24.79,12.06 24.94,11.9 24.94,10.66 23.29,9.01 23.16,9.01 21.13,6.98 21.13,6.62 19.77,5.26 19.77,4.35 19.25,3.83 ; 3 cut-outs
AUD_SPK_R-_C on TOP: 14.07,3.5 12.62,4.94 12.62,7.54 12.85,7.76 13.46,7.76 13.79,7.43 13.79,5.99 14.55,5.22 17.65,5.22 18.01,4.87 18.01,3.95 17.88,3.83 15.37,3.83 15.04,3.5 ; 4 cut-outs
BT+ on TOP: 155.24,28.92 154.28,29.89 154.28,31.92 153.97,32.22 153.97,38.57 154.23,38.83 156.64,38.83 157.15,38.32 157.15,34 158.67,32.48 158.67,29.94 157.66,28.92
BT+ on BOTTOM: 154.48,25.75 153.85,26.38 153.85,28.29 154.1,28.54 154.61,28.54 155.12,29.05 155.12,30.19 154.23,31.08 154.23,31.46 154.1,31.59 153.72,31.59 153.59,31.72 153.59,33.11 153.97,33.49 153.97,36.92 152.84,38.05 150.05,38.05 149.88,37.89 149.88,37.58 149.76,37.46 148.87,37.46 148.77,37.56 148.77,40.2 149.17,40.61 150.42,40.61 150.52,40.5 150.87,40.5 151.08,40.3 151.08,39.69 151.18,39.59 152.2,39.59 152.32,39.72 152.32,40.35 152.58,40.61 156.26,40.61 156.39,40.48 156.39,39.59 156.16,39.36 156.16,31.69 156.51,31.33 157.78,31.33 159.69,29.43 159.69,28.03 160.12,27.6 160.12,25.82 160.04,25.75 ; 11 cut-outs
CAP_LED on TOP: 93.5,9.11 93.22,9.39 93.22,9.82 92.99,10.05 91.18,10.05 90.98,10.25 90.98,10.51 91.18,10.71 93.75,10.71 94.03,10.43 94.03,9.24 93.9,9.11 ; 2 cut-outs
CFG_RCOMP on TOP: 121.16,68.9 121.08,68.98 121.08,70.07 121.21,70.2 123.01,70.2 123.19,70.02 123.19,69.26 122.83,68.9
CHARGER_SRC on TOP: 140.26,46.7 139.77,47.18 139.77,48.1 139.62,48.25 139.62,50.77 139.75,50.89 145.21,50.89 145.46,50.64 145.46,47.08 145.08,46.7 ; 2 cut-outs
CHARGER_SRC on BOTTOM: 139.42,45.91 138.89,46.45 137.72,46.45 137.59,46.57 137.59,47.72 137.97,48.1 138.61,48.1 139.11,48.61 139.11,52.29 139.24,52.42 140.26,52.42 140.64,52.04 140.64,51.15 140.87,50.92 143.03,50.92 143.56,50.38 143.56,46.68 143.23,46.35 141.35,46.35 140.92,45.91 ; 3 cut-outs
CPVDD on BOTTOM: 22.5,19.57 22.25,19.83 22.25,20.57 22.66,20.97 22.66,21.3 22.78,21.43 23.01,21.43 23.16,21.28 23.16,21.02 23.42,20.77 24.51,20.77 24.71,20.97 24.89,20.97 25.07,20.79 25.07,19.68 24.97,19.57 ; 3 cut-outs
DCBATOUT on TOP: 49.83,2.25 49.58,2.51 49.58,3.52 49.96,3.9 52.88,3.9 53.01,3.78 53.01,2.63 52.63,2.25 ; 1 cut-out
DCBATOUT on TOP: outline of 193 points within 34.69,44.16 179.37,112.74 ; 47 cut-outs
DCBATOUT on BOTTOM: 163.88,66.89 163.63,67.15 163.63,78.07 162.74,78.96 162.74,82.13 163.12,82.52 163.12,85.69 163.24,85.82 168.2,85.82 168.32,85.94 168.32,87.85 167.64,88.54 167.64,92.12 167.31,92.45 167.31,98.77 164.39,101.69 164.39,104.74 162.1,107.03 157.91,107.03 155.88,104.99 146.86,104.99 146.61,104.74 146.61,101.82 147.62,100.8 147.62,95.39 148.08,94.94 148.08,94.12 147.98,94.02 146.51,94.02 146.43,94.1 146.43,94.33 146.23,94.53 145.64,94.53 145.59,94.58 144.24,94.58 144.17,94.66 143.56,94.66 143.56,97.76 143.18,98.14 143.18,100.42 142.04,101.57 141.02,101.57 140.77,101.82 140.77,106.52 144.19,109.95 162.74,109.95 167.87,104.82 167.87,101.92 169.85,99.94 169.85,93.54 170.48,92.9 170.48,83.28 169.98,82.77 169.98,75.45 171.3,74.13 177.09,74.13 177.21,74.01 177.21,71.95 175.46,70.2 174.17,70.2 170.86,66.89 ; 15 cut-outs
DCBATOUT on BOTTOM: 49.73,2.4 49.63,2.51 49.63,3.83 49.73,3.93 52.12,3.93 52.25,3.8 52.25,2.63 52.02,2.4
DCBATOUT on BOTTOM: 153.72,47.59 153.47,47.84 153.47,48.89 153.29,49.06 152.96,49.06 152.68,49.34 152.68,50.51 152.87,50.7 153.76,50.7 153.77,50.72 154.94,50.72 155.45,50.21 156.06,50.21 156.39,49.88 156.39,47.72 156.26,47.59
DCBATOUT on BOTTOM: 59.1,99.91 58.6,100.42 58.6,102.33 59.1,102.84 75.87,102.84 78.54,105.5 78.54,109.06 81.71,112.23 88.19,112.23 88.89,111.54 88.89,106.33 88.7,106.14 81.84,106.14 77.01,101.31 63.55,101.31 62.15,99.91
DCBATOUT on BOTTOM: 141.02,51.15 140.77,51.4 140.77,53.18 141.02,53.43 143.56,53.43 143.81,53.18 143.81,52.67 143.43,52.29 143.43,51.4 143.18,51.15
DCBATOUT on BOTTOM: 154.47,4.64 154.39,4.72 154.39,6.87 154.94,7.42 155.97,7.42 157.53,8.98 157.53,10.38 158.04,10.89 158.55,10.89 158.93,11.27 158.93,12.54 159.31,12.92 161.02,12.92 161.34,13.24 161.34,17.17 168.11,23.94 168.93,23.94 170.36,25.37 173.91,25.37 174.17,25.62 174.17,57.73 174.75,58.31 177.29,58.31 177.48,58.12 177.48,54.58 177.47,54.58 177.47,43.81 177.46,43.79 177.46,40.24 177.4,40.19 177.4,37.46 178.23,36.63 178.23,35.14 178.61,34.76 178.61,31.97 178.6,31.96 178.6,30.38 178.59,30.37 178.59,29.68 178.18,29.28 177.06,29.28 176.71,28.92 176.71,23.77 175.77,22.83 175.77,21.12 174.67,20.03 171.19,20.03 170.76,20.46 170.41,20.46 168.58,18.63 168.58,16.73 166.11,14.27 166.11,11.09 164.64,9.62 162.23,9.62 161.97,9.36 161.97,7.33 161.59,6.95 159.05,6.95 156.74,4.64 ; 3 cut-outs
DCBATOUT on BOTTOM: 154.89,57.78 154.74,57.93 154.74,63.08 155.75,64.1 159.71,64.1 159.97,64.35 161.9,64.35 161.97,64.28 161.97,62.81 161.9,62.73 160.02,62.73 159.87,62.58 156.51,62.58 156.26,62.32 156.26,58.51 155.95,58.21 155.7,58.21 155.27,57.78 ; 2 cut-outs
DCBATOUT on L4: 140.77,51.78 148.64,51.78 151.18,49.24 153.21,49.24 153.59,48.86 153.59,47.97 153.72,47.84 155.75,47.84 155.88,47.97 155.88,50.89 154.86,51.91 152.07,51.91 149.91,54.07 140.77,54.07 140.38,53.69 140.38,52.16
DCBATOUT on L5VCC: 35.56,87.15 35.04,87.67 35.04,96.66 41.02,102.65 76.46,102.65 78.87,105.06 82.81,105.06 86.74,109 88.62,109 88.89,108.73 88.89,104.82 84.55,100.49 77.95,100.49 77.57,100.11 67.44,100.11 67.06,100.49 62.2,100.49 61.31,99.6 44.42,99.6 38.47,93.64 38.47,87.8 37.82,87.15
DCBATOUT on L5VCC: 49.13,0.51 49.13,3.7 49.4,3.97 105.67,3.97 107.3,5.6 107.3,9.05 125.07,9.05 127.1,7.01 128.49,7.01 132.05,3.46 137.26,3.46 138.27,2.44 144.4,2.44 145.42,3.46 152.27,3.46 153.4,4.59 153.4,6.74 153.93,7.27 155.07,7.27 155.7,7.9 158.34,7.9 160.02,6.23 158.46,5.39 157.84,3.74 157.84,1 157.7,0.65 157.35,0.51
DCBATOUT on L6: 161.85,46.07 155.12,46.07 153.59,47.59 153.59,48.53 153.02,49.1 153.02,49.58 153.36,49.93 155.75,49.93 157.2,48.48 163.75,48.48 164.51,49.24 164.51,57.5 171.25,64.23 171.27,64.23 171.93,64.89 176.45,64.89 177.09,64.25 177.24,64.25 177.25,64.27 177.43,64.27 177.72,63.97 179.25,63.97 179.5,63.72 179.5,56.66 178.85,56.01 175.5,56.01 175.26,56.25 175.26,57.88 175.64,58.26 176.83,58.26 177.34,58.77 177.34,61.43 176.58,62.2 174.93,62.2 170.52,57.79 169.35,57.79 168.58,57.01 168.58,55.44 169.21,54.8 169.21,47.97 168.2,46.96 167.31,46.96 166.8,46.45 166.8,46.07 164.77,44.03 162.86,44.03 162.61,44.29 162.61,45.3
DCBATOUT_+VCCSA on BOTTOM: 146.61,57.88 146.35,58.13 146.35,61.56 146.48,61.69 149.91,61.69 149.93,61.66 153.03,61.66 153.82,62.45 154.35,62.45 154.48,62.32 154.48,59.15 154.35,59.02 149.91,59.02 149.53,58.64 149.53,58.26 149.15,57.88 ; 4 cut-outs
DCBATOUT_CAMERA on TOP: 54.79,90.14 54.53,90.39 54.53,93.44 54.63,93.54 55.27,93.54 56.51,92.29 56.51,90.85 55.8,90.14 ; 3 cut-outs
DCBATOUT_CAMERA on BOTTOM: 55.42,91.18 54.96,91.63 54.96,93.49 55.01,93.54 55.75,93.54 55.8,93.49 55.8,92.52 56.26,92.07 56.26,91.36 56.08,91.18
DCBATOUT_LCD on TOP: 76.1,92.68 75.61,93.16 75.61,93.56 75.23,93.95 73.53,93.95 73.05,94.43 73.05,96.05 73.2,96.21 79.17,96.21 79.96,95.42 79.96,93.08 79.55,92.68 ; 6 cut-outs
